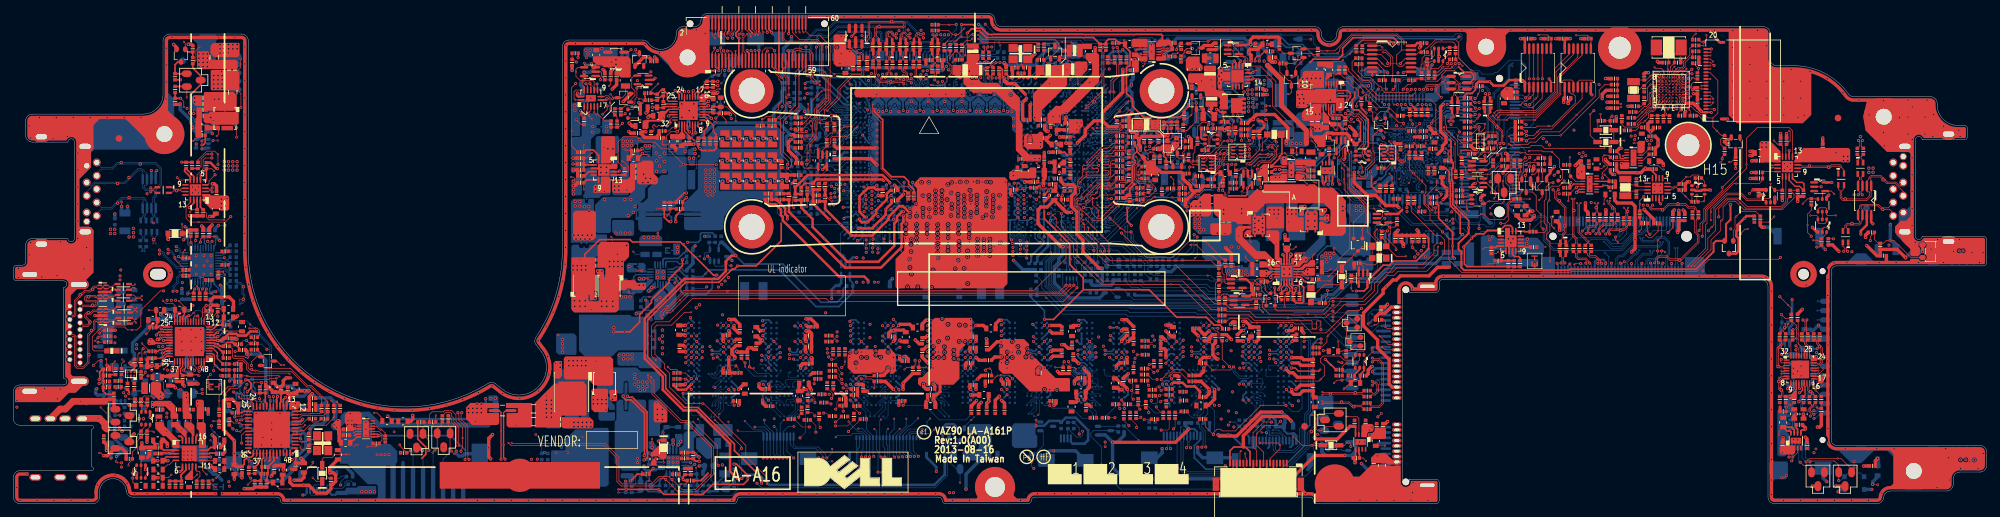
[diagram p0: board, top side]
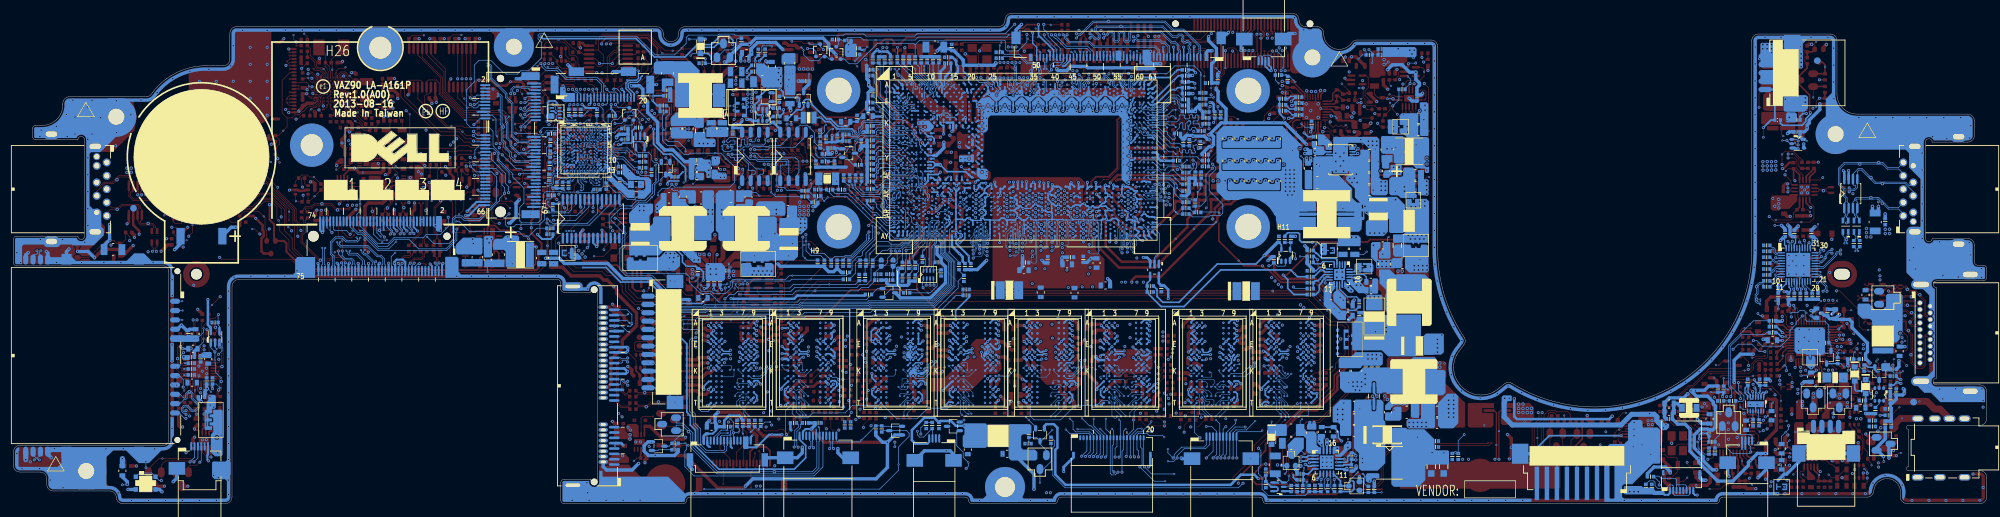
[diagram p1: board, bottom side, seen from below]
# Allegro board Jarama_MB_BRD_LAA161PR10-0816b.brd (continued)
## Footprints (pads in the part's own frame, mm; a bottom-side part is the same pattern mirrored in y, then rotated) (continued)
TPS51285BRUKR_QFN20_3X3
  oval 0.203x1.016 smd: 1(0,0) 2(0.4,0) 3(0.8,0) 4(1.2,0) 5(1.6,0) 11(1.6,2.975) 12(1.2,2.975) 13(0.8,2.975) 14(0.4,2.975) 15(0,2.975)
  oval 1.016x0.203 smd: 6(2.288,0.688) 7(2.288,1.088) 8(2.288,1.488) 9(2.288,1.888) 10(2.288,2.288) 16(-0.688,2.288) 17(-0.688,1.888) 18(-0.688,1.488) 19(-0.688,1.088) 20(-0.688,0.688)
  rect 1.702x1.702 smd: 21(0.8,1.488)
TPS51362RVER_QFN28_4P5X3P5
  oval 0.203x1.041 smd: 1(0,0) 2(0.4,0) 3(0.8,0) 4(1.2,0) 5(1.6,0) 6(2,0) 7(2.4,0) 8(2.8,0) 9(3.2,0) 15(3.2,3.45) 16(2.8,3.45) 17(2.4,3.45) 18(2,3.45) 19(1.6,3.45) 20(1.2,3.45) 21(0.8,3.45) 22(0.4,3.45) 23(0,3.45)
  oval 1.041x0.203 smd: 10(3.825,0.925) 11(3.825,1.325) 12(3.825,1.725) 13(3.825,2.125) 14(3.825,2.525) 24(-0.625,2.525) 25(-0.625,2.125) 26(-0.625,1.725) 27(-0.625,1.325) 28(-0.625,0.925)
  rect 3.099x2.108 smd: 29(1.6,1.725)
TPS51622RSM_QFN32_4X4
  oval 0.203x0.914 smd: 1(0,0) 2(0.4,0) 3(0.8,0) 4(1.2,0) 5(1.6,0) 6(2,0) 7(2.4,0) 8(2.8,0) 17(2.8,4.077) 18(2.4,4.077) 19(2,4.077) 20(1.6,4.077) 21(1.2,4.077) 22(0.8,4.077) 23(0.4,4.077) 24(0,4.077)
  oval 0.914x0.203 smd: 9(3.438,0.639) 10(3.438,1.039) 11(3.438,1.438) 12(3.438,1.838) 13(3.438,2.239) 14(3.438,2.639) 15(3.438,3.039) 16(3.438,3.438) 25(-0.639,3.438) 26(-0.639,3.039) 27(-0.639,2.639) 28(-0.639,2.239) 29(-0.639,1.838) 30(-0.639,1.438) 31(-0.639,1.039) 32(-0.639,0.639)
  rect 2.794x2.794 smd: 33(1.4,2.039)
TXB0102YZPR_DSBGA_8P
  round 0.254 smd: A1(0,0) A2(0.5,0) B1(0,-0.5) B2(0.5,-0.5) C1(0,-1) C2(0.5,-1) D1(0,-1.5) D2(0.5,-1.5)
TXB0104PWR_TSSOP14
  oval 0.381x1.651 smd: 1(0,0) 2(0.65,0) 3(1.3,0) 4(1.95,0) 5(2.6,0) 6(3.25,0) 7(3.9,0) 8(3.9,5.775) 9(3.25,5.775) 10(2.6,5.775) 11(1.95,5.775) 12(1.3,5.775) 13(0.65,5.775) 14(0,5.775)
W25Q32FVSSIQ_SO8
  oval 0.635x1.676 smd: 1(0,0) 2(1.27,0) 3(2.54,0) 4(3.81,0) 5(3.81,7.25) 6(2.54,7.25) 7(1.27,7.25) 8(0,7.25)
W25Q64FVSSIQ_SO8
  oval 0.635x1.676 smd: 1(0,0) 2(1.27,0) 3(2.54,0) 4(3.81,0) 5(3.81,7.25) 6(2.54,7.25) 7(1.27,7.25) 8(0,7.25)
Y_7A08000006_2P
  rect 1.702x2.388 smd: 1(0,0) 2(3.7,0)
Y_CM31532768DZFT_2P
  rect 1.092x1.905 smd: 1(0,0) 2(2.5,0)
Y_Q13FC1350000200_2P
  rect 0.991x1.803 smd: 1(0,0) 2(2.5,0)
Y_X3G024000DC1H_4P
  rect 1.397x1.194 smd: 1(0,0) 2(2.2,0) 3(2.2,1.7) 4(0,1.7)

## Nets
1.2V_DDR_PWROK: PU601.10 R1133.2
1.05V_VREF: PC501.2 PU501.26
1.05VS_PG: R1353.2 RH438.2 U672.2 U697.1
1.05VS_PG_EC: R1353.1 U34.A1
1.5VS_PWROK: PR428.1 R982.2
1.05VS_VCCST_PG: R1132.2 R1180.1 RC150.1 U672.4
1.5VSP_FB: PC429.2 PR425.1 PR427.2 PU405.5
1.8V_DDR_PWROK: PR434.2 R934.2
3VA_EN: D301.1 D302.1 D303.2 D305.1 D306.1 PR344.1
3VALW_PG: PR348.2 PU301.7 RH309.1
5VA_EN: D307.2 U34.B2
+0.6VSP: PC606.1 PC607.1 PJP603.1 PU601.2 PU601.20
+0.675VS: CD93.1 CD94.1 CD95.1 CD96.1 CD97.1 CD98.1 CD101.1 CD102.1 CD103.1 CD104.1 CD105.1 CD106.1 CD107.1 CD110.1 MC1267.1 MC1268.1 PJP603.2 RD25.2 RD26.2 RD27.2 RD28.2 RD29.2 RD30.2 RD31.2 RD32.2 RD33.2 RD34.2 RD35.2 RD36.2 RD37.2 RD38.2 RD39.2 RD40.2 RD41.2 RD42.2 RD43.2 RD44.2 RD45.2 RD46.2 RD47.2 RD48.2 RD49.2 RD50.2 RD51.2 RD52.2 RD53.2 RD54.2 RD55.2 RD56.2 RD57.2 RD58.2 RD59.2 RD60.2 RD61.2 RD62.2 RD63.2 RD64.2 RD65.2 RD66.2 RD67.2 RD68.2 RD69.2 RD70.2 RD71.2 RD72.2 RD75.2 RD76.2 RD77.2 RD78.2 RD87.2 RD88.2 RD89.2 RD90.2
+1.2V_B+: PC602.1 PC603.1 PC604.1 PJP601.2 PL601.2 PQ601.5 PR611.1
+1.2V_FB: PC614.1 PR608.1 PR610.1 PU601.6
+1.2V_TON: PR611.2 PU601.9
+1.2VS_DVDD: CA1.1 CA2.1 CA3.1 CA4.1 CA5.1 CA6.1 CA18.1 CA19.1 CA20.1 LA1.1 UA1.1 UA1.15 UA1.25 UA1.37
+1.05VA: C1228.1 C1243.1 CH1214.1 CH1222.1 CH1223.1 CH1239.1 PJP501.2 Q360.5 R1355.1 RH38.1 RH39.1 RH40.1 RH375.1 RH405.1 RH406.2 RH445.1 U673.4 U673.5 U673.9 U673.10 U673.11 U673.12 U673.13 U673.14 U673.18 U673.19 UCPU1.AE9 UCPU1.AF9 UCPU1.AG8 UCPU1.AG13 UCPU1.AG14
+1.05VDX_MODPHY: C1209.1 LH10.1 LH11.1 Q360.1 Q360.2 Q360.3 R300.1 R1240.1
+1.05VDX_MODPHY_D: Q39.1 R300.2
+1.05VS: C1240.1 C1244.2 CH1.1 CH39.1 CH1215.1 CH1216.1 CH1217.1 CH1233.1 CH1234.1 CH1235.1 LH12.1 R297.1 R1190.2 R1355.2 RH51.1 RH340.1 RH355.1 RH356.1 U673.6 U673.7 U673.8 UCPU1.AE8 UCPU1.AF22 UCPU1.AG16 UCPU1.AG17 UCPU1.H11 UCPU1.H15 UCPU1.J11 UCPU1.J17 UCPU1.N8 UCPU1.P9 UCPU1.R21 UCPU1.T21
+1.5VS: CV31.1 CV32.1 CV42.1 CV43.1 PJP410.2 R296.1 R1305.1 U722.12 U722.19 U722.20 U722.31 U722.40 UCPU1.J15
+1.5VS_3.3VS_AUDIO: CA22.1 CA33.1 CA43.2 CH85.1 RA75.1 U717.8 U717.9 UA1.9 UA2.7 UCPU1.AH14
+1.05VS_B+: PC510.1 PC511.1 PC512.1 PC513.1 PL501.2 PU501.15 PU501.16 PU501.17
+1.5VS_D: Q34.1 R296.2
+1.5VS_FSW: PR422.2 PU405.7
+1.05VS_VCCST: CH1204.1 CH1205.1 PC721.1 PR735.1 PR736.1 PR737.1 R1132.1 R1179.1 R1211.1 RC43.2 RC45.2 RC46.2 RC48.2 RC93.2 RC95.1 RC149.2 RH340.2 UCPU1.AC22 UCPU1.AE22 UCPU1.AE23
+1.05VS_XDP: JXDP.43 JXDP.44 RH51.2
+1.5VSP: PC426.1 PC429.1 PC430.1 PJP410.1 PL405.2 PR422.1 PR427.1 PU405.14
+1.05VSP: PC505.1 PC506.1 PC507.1 PC508.1 PJP501.1 PL502.2 PU501.22
+1.5VSP_LX: PL405.1 PR429.1 PU405.1 PU405.2 PU405.3
+1.5VSP_VIN: PC428.1 PC432.1 PJP409.2 PU405.10 PU405.11 PU405.12
+1.8VP: PC434.1 PC440.1 PC441.1 PJP412.1 PL406.2 PR433.1 PR437.1 PU406.14
+1.8VS: C1284.1 C1286.1 C1288.1 JTP1.1 PJP412.2 R1131.2 R1188.2 R1204.2 R1327.1 R1328.1 R1360.1 R1361.1 R1362.1 R1363.1 R1364.1 R1365.1 R1368.1 R1369.1 R1370.1 R1371.1 RH350.2 U671.1 U677.1 U679.C1
+1.8VSP_LX: PL406.1 PR432.1 PU406.1 PU406.2 PU406.3
+1.35V_DDR: CC160.1 CC161.1 CC162.1 CC163.1 CC164.1 CC165.1 CC233.1 CC234.1 CC238.1 CC239.1 CC240.1 CD14.1 CD15.1 CD16.1 CD17.1 CD18.1 CD19.1 CD20.1 CD21.1 CD22.1 CD37.1 CD38.1 CD39.1 CD40.1 CD41.1 CD42.1 CD43.1 CD44.1 CD58.1 CD59.1 CD60.1 CD61.1 CD62.1 CD63.1 CD64.1 CD65.1 CD66.1 CD81.1 CD82.1 CD83.1 CD84.1 CD85.1 CD86.1 CD87.1 CD88.1 CD111.1 CD112.1 CD113.1 CD114.1 CD115.1 CD116.1 CD117.1 CD118.1 CD119.1 CD120.1 CD121.1 CD122.1 CD123.1 CD124.1 CD125.1 CD126.1 PJP602.2 RC75.1 RD13.1 RD17.1 RD18.1 RD73.2 RD74.2 UC1.5 UCPU1.AH26 UCPU1.AJ31 UCPU1.AJ33 UCPU1.AJ37 UCPU1.AN33 UCPU1.AP43 UCPU1.AR48 UCPU1.AY35 UCPU1.AY40 UCPU1.AY44 UCPU1.AY50 UD1.A1 UD1.A8 UD1.B2 UD1.C1 UD1.C9 UD1.D2 UD1.D9 UD1.E9 UD1.F1 UD1.G7 UD1.H2 UD1.H9 UD1.K2 UD1.K8 UD1.N1 UD1.N9 UD1.R1 UD1.R9 UD2.A1 UD2.A8 UD2.B2 UD2.C1 UD2.C9 UD2.D2 UD2.D9 UD2.E9 UD2.F1 UD2.G7 UD2.H2 UD2.H9 UD2.K2 UD2.K8 UD2.N1 UD2.N9 UD2.R1 UD2.R9 UD4.A1 UD4.A8 UD4.B2 UD4.C1 UD4.C9 UD4.D2 UD4.D9 UD4.E9 UD4.F1 UD4.G7 UD4.H2 UD4.H9 UD4.K2 UD4.K8 UD4.N1 UD4.N9 UD4.R1 UD4.R9 UD5.A1 UD5.A8 UD5.B2 UD5.C1 UD5.C9 UD5.D2 UD5.D9 UD5.E9 UD5.F1 UD5.G7 UD5.H2 UD5.H9 UD5.K2 UD5.K8 UD5.N1 UD5.N9 UD5.R1 UD5.R9 UD6.A1 UD6.A8 UD6.B2 UD6.C1 UD6.C9 UD6.D2 UD6.D9 UD6.E9 UD6.F1 UD6.G7 UD6.H2 UD6.H9 UD6.K2 UD6.K8 UD6.N1 UD6.N9 UD6.R1 UD6.R9 UD7.A1 UD7.A8 UD7.B2 UD7.C1 UD7.C9 UD7.D2 UD7.D9 UD7.E9 UD7.F1 UD7.G7 UD7.H2 UD7.H9 UD7.K2 UD7.K8 UD7.N1 UD7.N9 UD7.R1 UD7.R9 UD9.A1 UD9.A8 UD9.B2 UD9.C1 UD9.C9 UD9.D2 UD9.D9 UD9.E9 UD9.F1 UD9.G7 UD9.H2 UD9.H9 UD9.K2 UD9.K8 UD9.N1 UD9.N9 UD9.R1 UD9.R9 UD10.A1 UD10.A8 UD10.B2 UD10.C1 UD10.C9 UD10.D2 UD10.D9 UD10.E9 UD10.F1 UD10.G7 UD10.H2 UD10.H9 UD10.K2 UD10.K8 UD10.N1 UD10.N9 UD10.R1 UD10.R9
+1.35VP: PC610.1 PC611.1 PC614.2 PC615.1 PJP602.1 PJP604.1 PL602.1 PR608.2 PU601.5
+3.3V_M: C1216.1 CH6.1 CH7.1 CH47.1 R746.2 R1129.2 R1379.2 RH54.1 RH56.1 U2.8 U48.8 UCPU1.Y8
+3.3VDX_SSD: C719.1 C720.1 C721.1 C722.1 C1302.1 JSATA1.2 JSATA1.24 JSATA1.39 JSATA1.41 JSATA1.52 R1366.1 R1389.2
+3V_BATMAN: C1294.1 R1346.2 R1347.2 R1348.1 R1349.1 U714.11
+3V_D: Q5.1 R298.2
+3V_NFC: C1134.1 JNFC1.1 JNFC1.13 JNFC1.14 R973.1 R1242.2
+3V_PCH: C352.1 C1261.1 C1262.1 CH1220.1 CH1236.1 JAPS.12 JAPS.18 Q351.1 R298.1 R1239.1 R1242.1 R1312.2 R1324.1 R1326.2 RH42.1 RH70.2 RH72.2 RH80.2 RH81.2 RH154.2 RH160.2 RH270.2 RH271.2 RH274.1 RH294.2 RH295.2 RH298.2 RH299.2 RH303.2 RH341.1 RH351.1 RH383.2 RH468.2 RH469.2 RH470.2 RH471.2 RH472.2 U663.14 U672.5 U690.5 U691.5 U697.5 UCPU1.AA9 UCPU1.AC9 UCPU1.AE20 UCPU1.AE21
+3V_PCH_DSW: CH1224.1 RH12.2 RH146.2 RH296.2 RH348.2 RH351.2 RH402.2 RH464.2 RH466.2 UCPU1.AH10
+3VALW: C8.1 C96.1 C1199.1 C1219.1 C1289.1 C1290.1 C1297.1 C1299.1 CR11.1 CR12.1 JAPS.16 JLVDS2.45 JP1.1 PJP304.2 PR102.1 PR113.2 PR126.1 Q330.3 R11.1 R162.2 R163.2 R216.1 R923.2 R1260.1 RH348.1 RR9.1 RR10.2 U1.27 U5.5 U23.14 U636.C6 U664.1 U664.2 U699.5 U700.5 U710.5 U713.5 U715.1 U715.2 U716.1 U716.2 U716.6 U716.7 U718.1 U718.2 U718.6 U718.7 U719.1 U719.2 U719.4 U719.6 U719.7 U720.1 U720.2 U721.1 U721.2 U724.1 U724.2 U725.2
+3VALW_EC: C276.1 C277.1 C278.1 C279.1 C280.2 C281.2 L43.1 R216.2 R219.2 R221.2 R229.2 R230.2 R232.1 R233.1 R604.1 R922.2 R933.1 R935.2 R937.1 R940.1 R947.1 R949.2 R1156.1 R1386.2 RP21.7 RP21.8 RP22.5 U34.J4 U34.J7 U34.K7 U34.K12 U34.M12
+3VALWP: PC326.1 PJP304.1 PL303.1 PR348.1 PR353.1
+3VLP: PC347.1 PR335.1 R921.2 R939.1 R1349.2 RP22.6 RTCD1.3 U712.5
+3VNS_PWR: C976.1 C977.1 C978.1 C979.1 JLVDS2.40 JSATA1.22 JSNRDG.1 Q352.2 Q352.5 R854.2 R855.2 R1003.2 R1092.2 R1143.2 R1220.2 R1229.2 R1234.1 R1235.1 R1236.1 R1237.1 R1251.2 R1319.2 RH461.2 RH462.2 U636.A1 U636.A8 U636.F7 U636.G6 U636.G8 U636.H1
+3VS: C655.1 C1135.1 C1136.1 C1137.1 C1138.1 C1139.1 C1140.1 C1256.1 C1283.1 C1285.1 C1287.1 CH1225.1 CH1226.1 CV39.1 CV44.1 JDEBUG.9 JLVDS1.7 JLVDS1.17 MC1276.1 MC1277.1 MD50.5 PR723.2 PR725.2 PU701.20 PU701.21 Q326.2 Q344.2 Q359.2 Q359.5 QH3.2 QH3.5 QH4.2 QH4.5 R884.2 R930.1 R975.2 R976.1 R977.1 R978.1 R979.1 R1033.2 R1103.2 R1129.1 R1182.2 R1185.1 R1289.1 R1306.1 R1311.2 R1330.2 R1339.1 R1340.1 R1343.1 RC159.1 RH29.2 RH35.1 RH37.1 RH82.2 RH91.1 RH95.1 RH98.1 RH99.1 RH100.1 RH103.1 RH107.1 RH180.2 RH196.2 RH248.1 RH281.1 RH282.1 RH301.2 RH302.2 RH354.2 RH367.2 RH380.1 RH381.1 RH384.2 RH388.1 RH389.1 RH390.2 RH391.2 RH392.2 RH396.1 RH397.1 RH424.2 RH425.2 RH440.2 RH441.2 RH452.1 RH455.1 RH456.1 RH457.2 RH458.2 RH459.2 RH460.2 RH463.1 RH465.2 RH467.2 RV16.2 RV17.2 RV18.2 RV19.2 RV20.2 RV21.2 RV32.2 U635.5 U652.5 U652.10 U652.19 U652.24 U671.14 U675.5 U677.14 U678.5 U679.B2 U682.5 U698.5 U709.5 U722.11 U722.37 UCPU1.K14 UCPU1.K16 UCPU1.V8 UCPU1.W9 UH5.5
+3VS_AUDIO: CA7.1 CA8.1 CA9.1 CA10.1 CA11.1 CA12.1 CA31.1 CA32.1 CA46.1 LH2.1 R25.2 R1261.1 R1265.1 R1266.1 R1318.2 RA14.1 RA18.1 RA30.1 RA32.2 RA37.1 RA38.1 UA1.14 UA1.16 UA1.42 UA2.23 UA3.B2
+3VS_CAM: C1158.1 C1159.1 JLVDS1.1 JLVDS1.2 R1321.2
+3VS_CR: C1298.1 CR2.1 CR7.1 JP1.2 R1380.2 U1.11
+3VS_DVDD: CA35.1 CA42.2 RA32.1 UA2.11
+3VS_NGFF: C712.1 C713.1 C714.1 C715.1 C716.1 C717.1 C718.1 C725.1 C1215.1 JNGFF1.2 JNGFF1.4 JNGFF1.64 JNGFF1.66 JNGFF2.2 JNGFF2.4 JNGFF2.72 JNGFF2.74 Q346.2 Q348.2 Q350.2 R942.1 R1036.2 R1137.1 R1197.1 R1200.1 R1205.1 R1226.2
+3VS_TP: C1225.1 JTP1.2 Q364.2 Q365.2 R1128.2 R1300.1 R1301.1 RH364.2 RH365.2
+3VS_TS: C1200.1 JLVDS2.50 MD90.5 Q363.2 R1320.2 R1385.1 RH436.2 RH437.2
+5V_USB_P0: C1109.1 C1110.1 JUSB2.1 MD82.8 US2.12
+5V_USB_P1: C265.1 C303.1 JUSB1.1 MD74.8 US1.12
+5VALW: C962.1 C963.1 C1161.1 C1172.1 C1173.1 C1203.1 C1213.1 C1241.1 C1254.1 C1301.1 C1303.1 JPWR1.1 PC608.2 PJP306.2 PR104.2 PR505.1 PR606.1 PR731.1 PU601.12 R1165.2 R1168.2 R1170.2 R1213.2 R1214.2 R1341.2 U664.4 U664.6 U664.7 U673.2 U676.5 U715.4 U716.4 U717.1 U717.2 U717.4 U718.4 U720.4 U721.4 U724.4 US1.1 US2.1
+5VALWP: PC334.1 PJP306.1 PL302.2 PR316.2 PU301.14
+5VS: C1102.2 C1153.1 C1162.1 CV40.1 D110.2 D111.2 F1.2 JFAN1.1 JFAN1.8 PC713.1 PR720.1 PU702.2 Q329.3 QC5.2 R886.2 R989.2 R1331.2
+5VS_AUDIO: L1.1 R1125.2 RA2.2
+5VS_KBL: C1059.1 F1.1 JBL1.4 R950.2
+5VS_LDO-IN: CA36.1 CA37.1 RA2.1 UA2.39
+V1.05A_AOSCSUS: CH1232.1 CH1240.1 L63.1 UCPU1.AB8
+V1.05A_AOSCSUS_L: L63.2 RH406.1
+V1.05A_DCPSUS: RH405.2 UCPU1.AD8 UCPU1.AD10 UCPU1.AH13 UCPU1.J13
+V1.05S_APLLOPI: CH1212.1 CH1213.1 LH12.2 UCPU1.AA21 UCPU1.W21
+V1.05S_ASATA3PLL: CH1210.1 CH1211.1 LH11.2 RH43.2 UCPU1.A12 UCPU1.B11
+V1.05S_AUSB3PLL: CH1208.1 CH1209.1 LH10.2 RH338.1 UCPU1.B18 UCPU1.B27
+V1.05S_AXCK_DCB: CH1228.1 CH1229.1 L61.2 UCPU1.J18 UCPU1.K19
+V1.05S_AXCK_DCB_L: L61.1 RH355.2
+V1.05S_AXCK_LCPLL: CH1230.1 CH1231.1 L62.2 RH113.2 UCPU1.A20
+V1.05S_AXCK_LCPLL_L: L62.1 RH356.2
+V1.05VS_VCCHSIO: CH40.1 CH41.1 R1240.2 UCPU1.K9 UCPU1.L10 UCPU1.M9
+V18R: C293.1 U34.L1
+VCC_CORE: MC1269.1 MC1270.1 MC1271.1 MC1272.1 PC801.1 PC802.1 PC803.1 PC804.1 PC805.1 PC806.1 PC807.1 PC808.1 PC809.1 PC810.1 PC811.1 PC812.1 PC813.1 PC814.1 PC815.1 PC816.1 PC817.1 PC818.1 PC819.1 PC820.1 PC821.1 PC822.1 PC823.1 PC824.1 PC825.1 PC826.1 PC827.1 PC828.1 PC829.1 PC830.1 PL701.4 RC97.1 UCPU1.AB57 UCPU1.AD57 UCPU1.AG57 UCPU1.C24 UCPU1.C28 UCPU1.C32 UCPU1.C36 UCPU1.C40 UCPU1.C44 UCPU1.C48 UCPU1.C52 UCPU1.C56 UCPU1.E23 UCPU1.E25 UCPU1.E27 UCPU1.E29 UCPU1.E31 UCPU1.E33 UCPU1.E35 UCPU1.E37 UCPU1.E39 UCPU1.E41 UCPU1.E43 UCPU1.E45 UCPU1.E47 UCPU1.E49 UCPU1.E51 UCPU1.E53 UCPU1.E55 UCPU1.E57 UCPU1.F24 UCPU1.F28 UCPU1.F32 UCPU1.F36 UCPU1.F40 UCPU1.F44 UCPU1.F48 UCPU1.F52 UCPU1.F56 UCPU1.F59 UCPU1.G23 UCPU1.G25 UCPU1.G27 UCPU1.G29 UCPU1.G31 UCPU1.G33 UCPU1.G35 UCPU1.G37 UCPU1.G39 UCPU1.G41 UCPU1.G43 UCPU1.G45 UCPU1.G47 UCPU1.G49 UCPU1.G51 UCPU1.G53 UCPU1.G55 UCPU1.G57 UCPU1.H23 UCPU1.J23 UCPU1.K23 UCPU1.K57 UCPU1.L22 UCPU1.M23 UCPU1.M57 UCPU1.P57 UCPU1.U57 UCPU1.W57
+VCCIO_OUT: CH1241.1 UCPU1.A59
+VCCIOA_OUT: RC36.2 UCPU1.E20
+VCCP_D: Q4.1 R297.2
AGND: C21.2 C27.2 C42.2 C43.2 C44.2 C45.2 C46.2 C47.1 C48.2 CA25.2 CA28.2 CA29.2 CA30.2 CA31.2 CA32.2 CA34.2 CA36.2 CA37.2 CA38.2 CA39.1 CA40.1 CA45.1 CA46.2 CA51.2 CA52.2 CA53.1 CA54.1 CA55.1 CA56.1 CA57.2 CA67.2 CA68.2 CA69.2 CA74.2 DA1.1 DA2.1 DA3.1 DA4.1 DA5.1 JHP1.7 JPA1.1 JPA2.1 JPA3.1 QA1.1 QA1.4 QA3.1 QA3.4 QA6.1 QA6.4 R26.1 R27.1 RA20.2 RA25.2 RA43.1 RA45.1 RA68.2 RA69.2 U4.12 U4.16 U4.20 U4.21 UA2.22 UA2.28 UA2.42 UA3.A2
AV12: CR8.2 RR11.1 U1.10
DV12S: CR9.1 CR10.1 RR11.2 U1.14
DV33_18: CR1.2 U1.18
DVDD-12-SWR: LA1.2 UA1.13
DVDD_25: CA13.1 CA14.1 CA21.1 R1186.1 UA1.43
DVDD_IO: CA25.1 CA34.1 LH2.2 UA2.25
GND: C8.2 C9.1 C96.2 C265.2 C276.2 C277.2 C278.2 C279.2 C280.1 C281.1 C283.2 C285.2 C293.2 C303.2 C352.2 C355.2 C407.2 C612.2 C617.1 C655.2 C656.2 C712.2 C713.2 C714.2 C715.2 C716.2 C717.2 C718.2 C719.2 C720.2 C721.2 C722.2 C725.2 C962.2 C963.2 C976.2 C977.2 C978.2 C979.2 C1059.2 C1102.1 C1109.2 C1110.2 C1116.1 C1117.2 C1118.2 C1123.2 C1124.2 C1125.2 C1134.2 C1135.2 C1136.2 C1137.2 C1138.2 C1139.2 C1140.2 C1143.2 C1145.2 C1152.2 C1153.2 C1158.2 C1159.2 C1160.2 C1161.2 C1162.2 C1163.2 C1164.2 C1172.2 C1173.2 C1199.2 C1200.2 C1202.2 C1203.2 C1204.2 C1205.2 C1209.2 C1212.2 C1213.2 C1214.2 C1215.2 C1216.2 C1219.2 C1225.2 C1227.2 C1228.2 C1230.2 C1231.2 C1237.2 C1240.2 C1241.2 C1242.2 C1243.2 C1245.2 C1246.2 C1247.2 C1248.2 C1251.2 C1252.2 C1253.2 C1254.2 C1256.2 C1257.2 C1261.2 C1262.2 C1278.2 C1280.1 C1281.2 C1282.2 C1283.2 C1284.2 C1285.2 C1286.2 C1287.2 C1288.2 C1289.2 C1290.2 C1292.2 C1294.2 C1295.2 C1296.2 C1297.2 C1298.2 C1299.2 C1300.2 C1301.2 C1302.2 C1303.2 C1304.2 CA1.2 CA2.2 CA3.2 CA4.2 CA5.2 CA6.2 CA7.2 CA9.2 CA11.2 CA12.2 CA14.2 CA15.2 CA16.2 CA17.2 CA21.2 CA22.2 CA23.2 CA24.1 CA26.2 CA27.1 CA33.2 CA35.2 CA41.2 CA42.1 CA43.1 CA48.2 CA49.1 CA50.1 CC160.2 CC161.2 CC162.2 CC163.2 CC164.2 CC165.2 CC233.2 CC234.2 CC238.2 CC239.2 CC240.2 CD1.1 CD2.1 CD3.1 CD4.1 CD5.2 CD14.2 CD15.2 CD16.2 CD17.2 CD18.2 CD19.2 CD20.2 CD21.2 CD22.2 CD24.1 CD25.1 CD26.1 CD27.1 CD28.2 CD37.2 CD38.2 CD39.2 CD40.2 CD41.2 CD42.2 CD43.2 CD44.2 CD45.1 CD46.1 CD47.1 CD48.1 CD49.2 CD58.2 CD59.2 CD60.2 CD61.2 CD62.2 CD63.2 CD64.2 CD65.2 CD66.2 CD68.1 CD69.1 CD70.1 CD71.1 CD72.2 CD81.2 CD82.2 CD83.2 CD84.2 CD85.2 CD86.2 CD87.2 CD88.2 CD90.2 CD93.2 CD94.2 CD95.2 CD96.2 CD97.2 CD98.2 CD101.2 CD102.2 CD103.2 CD104.2 CD105.2 CD106.2 CD107.2 CD110.2 CD111.2 CD112.2 CD113.2 CD114.2 CD115.2 CD116.2 CD117.2 CD118.2 CD119.2 CD120.2 CD121.2 CD122.2 CD123.2 CD124.2 CD125.2 CD126.2 CH1.2 CH2.2 CH3.2 CH4.1 CH5.2 CH6.2 CH7.2 CH23.2 CH24.2 CH39.2 CH40.2 CH41.2 CH47.2 CH82.2 CH83.2 CH84.2 CH85.2 CH95.2 CH1202.2 CH1203.2 CH1204.2 CH1205.2 CH1206.2 CH1207.2 CH1208.2 CH1209.2 CH1210.2 CH1211.2 CH1212.2 CH1213.2 CH1214.2 CH1215.2 CH1216.2 CH1217.2 CH1218.2 CH1220.2 CH1222.2 CH1223.2 CH1224.2 CH1225.2 CH1226.2 CH1227.2 CH1228.2 CH1229.2 CH1230.2 CH1231.2 CH1232.2 CH1233.2 CH1234.2 CH1235.2 CH1236.2 CH1239.2 CH1240.2 CH1241.2 CLRP1.1 CLRP2.2 CR1.1 CR2.2 CR3.2 CR4.2 CR5.2 CR6.1 CR7.2 CR8.1 CR9.2 CR10.2 CR11.2 CR12.2 CR19.2 CR20.2 CV31.2 CV32.2 CV39.2 CV40.2 CV41.2 CV42.2 CV43.2 CV44.2 CV768.1 CV795.1 CV796.1 DA6.1 DA8.1 DA9.1 DE1.1 DE2.1 DH5.2 DV4.3 DV5.3 H1.1(TP-1) H2.1(TP-1) H4.1(TP-1) H6.1(TP-1) H7.1(TP-1) H9.1(TP-1) H10.1(TP-1) H11.1(TP-1) H12.1(TP-1) H15.1(TP-1) H18.1(TP-1) H26.1(TP-1) JAPS.5 JAPS.7 JAPS.9 JAPS.11 JAPS.19 JAPS.20 JBATT1.1 JBATT1.2 JBATT1.3 JBATT1.10 JBATT1.11 JBL1.5 JBL1.6 JCARD.4 JCARD.7 JCARD.12 JCARD.15 JCARD.19 JCARD.20 JCARD.21 JCARD.22 JCARD.23 JDCIN1.6 JDCIN1.7 JDEBUG.8 JDEBUG.10 JDEBUG.13 JDEBUG.14 JFAN1.4 JFAN1.5 JFAN1.9 JFAN1.10 JHDMI.2 JHDMI.5 JHDMI.8 JHDMI.11 JHDMI.17 JHDMI.20 JHDMI.21 JHDMI.22 JHDMI.23 JKB1.11 JKB1.12 JKB2.2 JKB2.21 JKB2.22 JLVDS1.5 JLVDS1.6 JLVDS1.13 JLVDS1.14 JLVDS1.21 JLVDS1.22 JLVDS1.23 JLVDS1.24 JLVDS2.3 JLVDS2.6 JLVDS2.9 JLVDS2.12 JLVDS2.15 JLVDS2.19 JLVDS2.21 JLVDS2.24 JLVDS2.27 JLVDS2.30 JLVDS2.31 JLVDS2.32 JLVDS2.46 JLVDS2.51 JLVDS2.52 JLVDS2.53 JLVDS2.54 JNFC1.2 JNFC1.9 JNFC1.15 JNFC1.16 JNFC1.17 JNGFF1.1 JNGFF1.7 JNGFF1.18 JNGFF1.25 JNGFF1.31 JNGFF1.37 JNGFF1.43 JNGFF1.49 JNGFF1.55 JNGFF1.61 JNGFF1.67 JNGFF1.68 JNGFF1.69 JNGFF2.1 JNGFF2.7 JNGFF2.18 JNGFF2.23 JNGFF2.24 JNGFF2.29 JNGFF2.30 JNGFF2.33 JNGFF2.36 JNGFF2.39 JNGFF2.45 JNGFF2.51 JNGFF2.57 JNGFF2.63 JNGFF2.69 JNGFF2.75 JNGFF2.76 JNGFF2.77 JPA1.2 JPA2.2 JPA3.2 JPWR1.6 JPWR1.7 JPWR1.8 JROT1.3 JROT1.4 JROT1.5 JROT1.6 JSATA1.4 JSATA1.9 JSATA1.15 JSATA1.18 JSATA1.21 JSATA1.26 JSATA1.27 JSATA1.29 JSATA1.34 JSATA1.35 JSATA1.37 JSATA1.40 JSATA1.43 JSATA1.50 JSATA1.53 JSATA1.54 JSNRDG.20 JSNRDG.21 JSNRDG.22 JSPK1.5 JSPK1.6 JTP1.3 JTP1.13 JTP1.14 JUSB1.4 JUSB1.7 JUSB1.11 JUSB1.12 JUSB1.13 JUSB1.14 JUSB2.4 JUSB2.7 JUSB2.11 JUSB2.12 JUSB2.13 JUSB2.14 JVOL.3 JVOL.4 JVOL.5 JVOL.6 JXDP.1 JXDP.2 JXDP.7 JXDP.8 JXDP.13 JXDP.14 JXDP.19 JXDP.20 JXDP.25 JXDP.26 JXDP.31 JXDP.32 JXDP.37 JXDP.38 JXDP.49 JXDP.50 JXDP.59 L44.1 LED2.1 MC94.2 MC95.2 MC96.2 MC102.1 MC103.2 MC104.2 MC105.2 MC118.1 MC284.2 MC654.2 MC1133.2 MC1141.2 MC1151.2 MC1210.2 MC1211.2 MC1212.2 MC1267.2 MC1268.2 MC1269.2 MC1270.2 MC1271.2 MC1272.2 MC1273.2 MC1274.2 MC1275.2 MC1276.2 MC1277.2 MD50.2 MD74.7 MD82.7 MD90.2 PBJ1.2 PC101.2 PC102.2 PC103.2 PC104.2 PC105.2 PC106.2 PC107.2 PC108.2 PC112.2 PC113.2 PC116.2 PC202.2 PC203.2 PC204.2 PC205.2 PC210.1 PC212.2 PC213.2 PC214.2 PC216.2 PC217.2 PC219.2 PC220.1 PC221.2 PC223.2 PC224.2 PC225.2 PC228.2 PC324.2 PC326.2 PC328.2 PC329.2 PC333.2 PC334.2 PC342.2 PC343.2 PC345.2 PC347.2 PC426.2 PC427.2 PC428.2 PC430.2 PC432.2 PC433.2 PC434.2 PC436.2 PC437.2 PC439.2 PC441.2 PC501.1 PC502.1 PC504.1 PC505.2 PC506.2 PC507.2 PC508.2 PC509.2 PC510.2 PC511.2 PC512.2 PC513.2 PC602.2 PC603.2 PC604.2 PC606.2 PC607.2 PC608.1 PC609.2 PC610.2 PC611.2 PC612.2 PC613.2 PC615.2 PC616.2 PC701.2 PC702.2 PC703.2 PC704.2 PC705.2 PC707.2 PC709.2 PC710.1 PC712.1 PC713.2 PC715.2 PC717.2 PC720.2 PC721.2 PC725.1 PC726.1 PC801.2 PC802.2 PC803.2 PC804.2 PC805.2 PC806.2 PC807.2 PC808.2 PC809.2 PC810.2 PC811.2 PC812.2 PC813.2 PC814.2 PC815.2 PC816.2 PC817.2 PC818.2 PC819.2 PC820.2 PC821.2 PC822.2 PC823.2 PC824.2 PC825.2 PC826.2 PC827.2 PC828.2 PC829.2 PC830.2 PD103.1 PD104.1 PL104.2 PQ102.3 PQ103.1 PQ103.4 PQ104.3 PQ105.1 PQ105.4 PQ106.3 PQ202.3 PQ204.3 PQ205.1 PQ205.2 PQ205.3 PQ304.8 PQ305.8 PQ602.1 PQ602.2 PQ602.3 PR106.2 PR108.2 PR115.2 PR118.2 PR121.2 PR124.2 PR125.2 PR213.2 PR225.2 PR226.2 PR311.1 PR318.2 PR351.2 PR352.1 PR354.2 PR425.2 PR438.2 PR508.1 PR610.2 PR709.2 PR710.2 PR711.2 PR712.2 PR713.2 PR714.2 PR721.2 PU201.14 PU201.21 PU301.21 PU405.6 PU405.15 PU405.16 PU405.17 PU406.6 PU406.15 PU406.16 PU406.17 PU501.10 PU501.11 PU501.12 PU501.13 PU501.14 PU501.19 PU501.23 PU501.24 PU501.25 PU501.29 PU601.1 PU601.3 PU601.14 PU601.21 PU701.19 PU701.22 PU701.29 PU701.33 PU702.3 PU702.9 Q4.3 Q5.3 Q34.3 Q39.3 Q71.3 Q107.3 Q134.3 Q305.3 Q311.3 Q361.1 Q362.3 Q366.4 Q367.4 R7.2 R36.2 R225.1 R290.2 R537.2 R540.2 R545.2 R607.1 R608.1 R819.1 R924.2 R936.2 R938.2 R945.1 R946.2 R951.2 R974.2 R1026.2 R1034.1 R1035.2 R1099.1 R1100.1 R1117.2 R1118.2 R1119.2 R1120.2 R1140.2 R1141.2 R1142.2 R1161.2 R1162.2 R1164.2 R1169.2 R1174.2 R1187.2 R1197.2 R1200.2 R1203.2 R1205.2 R1208.2 R1216.1 R1217.1 R1228.2 R1250.2 R1253.2 R1310.2 R1325.1 R1338.2 R1376.2 R1390.2 RA11.2 RA12.2 RA13.2 RA42.2 RC44.1 RC52.2 RC54.2 RC55.2 RC58.2 RC60.2 RC81.2 RC100.2 RC138.2 RC153.2 RC154.2 RC155.2 RC156.2 RC158.1 RC160.2 RC161.2 RD1.2 RD2.2 RD5.2 RD6.2 RD7.2 RD8.2 RD11.2 RD12.2 RD15.2 RD16.2 RD21.2 RD22.2 RD23.2 RD24.2 RD79.2 RD80.2 RD81.2 RD82.2 RD83.2 RD84.2 RD85.2 RD86.2 RH34.1 RH53.1 RH76.2 RH77.2 RH78.2 RH79.2 RH83.2 RH123.1 RH151.1 RH158.1 RH159.2 RH163.2 RH171.2 RH183.1 RH186.1 RH272.2 RH300.1 RH314.1 RH315.1 RH316.1 RH337.2 RH387.1 RH394.2 RH400.2 RH401.2 RH403.1 RH423.2 RH442.2 RH443.2 RP21.6 RP22.7 RP22.8 RR6.1 RV22.2 RV24.2 RV26.2 RV27.2 RV30.1 RV31.1 RV33.2 SW2.3 SW2.4 U1.33 U2.4 U5.3 U23.7 U34.G2 U34.J8 U34.J9 U34.J10 U34.N13 U48.4 U635.3 U636.A7 U636.B1 U636.E7 U636.F5 U636.H2 U636.H3 U652.1 U652.2 U652.3 U652.4 U652.8 U652.9 U652.11 U652.18 U652.25 U663.7 U663.15 U664.11 U664.15 U671.7 U672.3 U673.3 U675.3 U676.3 U677.7 U678.3 U679.B1 U682.3 U690.3 U691.3 U697.3 U698.3 U699.3 U700.3 U708.3 U709.3 U710.3 U712.3 U713.3 U714.3 U714.17 U715.11 U715.15 U716.11 U716.15 U717.11 U717.15 U718.11 U718.15 U719.11 U719.15 U720.5 U720.9 U721.5 U721.9 U722.15 U722.35 U722.41 U724.5 U724.9 U725.1 UA1.44 UA1.49 UA2.49 UC1.3 UCPU1.A11 UCPU1.A14 UCPU1.A18 UCPU1.A24 UCPU1.A28 UCPU1.A32 UCPU1.A36 UCPU1.A40 UCPU1.A44 UCPU1.A48 UCPU1.A52 UCPU1.A56 UCPU1.AA1 UCPU1.AA58 UCPU1.AB7 UCPU1.AB10 UCPU1.AB20 UCPU1.AB22 UCPU1.AC61 UCPU1.AD3 UCPU1.AD21 UCPU1.AD63 UCPU1.AE5 UCPU1.AE10 UCPU1.AE58 UCPU1.AF11 UCPU1.AF12 UCPU1.AF14 UCPU1.AF15 UCPU1.AF17 UCPU1.AF18 UCPU1.AG1 UCPU1.AG11 UCPU1.AG21 UCPU1.AG23 UCPU1.AG60 UCPU1.AG61 UCPU1.AG62 UCPU1.AG63 UCPU1.AH16 UCPU1.AH17 UCPU1.AH19 UCPU1.AH20 UCPU1.AH22 UCPU1.AH24 UCPU1.AH28 UCPU1.AH30 UCPU1.AH32 UCPU1.AH34 UCPU1.AH36 UCPU1.AH38 UCPU1.AH40 UCPU1.AH42 UCPU1.AH44 UCPU1.AH46 UCPU1.AH49 UCPU1.AH51 UCPU1.AH53 UCPU1.AH55 UCPU1.AH57 UCPU1.AJ13 UCPU1.AJ14 UCPU1.AJ23 UCPU1.AJ25 UCPU1.AJ27 UCPU1.AJ29 UCPU1.AJ35 UCPU1.AJ39 UCPU1.AJ41 UCPU1.AJ43 UCPU1.AJ45 UCPU1.AJ47 UCPU1.AJ50 UCPU1.AJ52 UCPU1.AJ54 UCPU1.AJ56 UCPU1.AJ58 UCPU1.AJ60 UCPU1.AJ63 UCPU1.AK3 UCPU1.AK23 UCPU1.AK52 UCPU1.AL10 UCPU1.AL13 UCPU1.AL17 UCPU1.AL20 UCPU1.AL22 UCPU1.AL23 UCPU1.AL26 UCPU1.AL29 UCPU1.AL31 UCPU1.AL33 UCPU1.AL36 UCPU1.AL39 UCPU1.AL40 UCPU1.AL45 UCPU1.AL46 UCPU1.AL51 UCPU1.AL52 UCPU1.AL54 UCPU1.AL57 UCPU1.AL60 UCPU1.AL61 UCPU1.AM1 UCPU1.AM17 UCPU1.AM23 UCPU1.AM31 UCPU1.AM52 UCPU1.AN7 UCPU1.AN17 UCPU1.AN23 UCPU1.AN31 UCPU1.AN32 UCPU1.AN35 UCPU1.AN36 UCPU1.AN39 UCPU1.AN40 UCPU1.AN42 UCPU1.AN43 UCPU1.AN45 UCPU1.AN46 UCPU1.AN48 UCPU1.AN49 UCPU1.AN51 UCPU1.AN52 UCPU1.AN60 UCPU1.AN63 UCPU1.AP3 UCPU1.AP10 UCPU1.AP17 UCPU1.AP20 UCPU1.AP22 UCPU1.AP23 UCPU1.AP26 UCPU1.AP29 UCPU1.AP31 UCPU1.AP38 UCPU1.AP39 UCPU1.AP48 UCPU1.AP52 UCPU1.AP54 UCPU1.AP57 UCPU1.AR5 UCPU1.AR11 UCPU1.AR15 UCPU1.AR17 UCPU1.AR23 UCPU1.AR31 UCPU1.AR33 UCPU1.AR39 UCPU1.AR43 UCPU1.AR49 UCPU1.AR52 UCPU1.AT13 UCPU1.AT35 UCPU1.AT37 UCPU1.AT40 UCPU1.AT42 UCPU1.AT43 UCPU1.AT46 UCPU1.AT49 UCPU1.AT61 UCPU1.AT62 UCPU1.AT63 UCPU1.AU1 UCPU1.AU16 UCPU1.AU18 UCPU1.AU20 UCPU1.AU22 UCPU1.AU24 UCPU1.AU26 UCPU1.AU28 UCPU1.AU30 UCPU1.AU33 UCPU1.AU51 UCPU1.AU53 UCPU1.AU55 UCPU1.AU57 UCPU1.AU59 UCPU1.AV8 UCPU1.AV14 UCPU1.AV16 UCPU1.AV20 UCPU1.AV24 UCPU1.AV28 UCPU1.AV33 UCPU1.AV34 UCPU1.AV36 UCPU1.AV39 UCPU1.AV41 UCPU1.AV43 UCPU1.AV46 UCPU1.AV49 UCPU1.AV51 UCPU1.AV55 UCPU1.AV59 UCPU1.AW4 UCPU1.AW16 UCPU1.AW24 UCPU1.AW33 UCPU1.AW35 UCPU1.AW37 UCPU1.AW40 UCPU1.AW42 UCPU1.AW44 UCPU1.AW47 UCPU1.AW50 UCPU1.AW51 UCPU1.AW59 UCPU1.AW60 UCPU1.AY4 UCPU1.AY6 UCPU1.AY11 UCPU1.AY16 UCPU1.AY18 UCPU1.AY22 UCPU1.AY24 UCPU1.AY26 UCPU1.AY30 UCPU1.AY33 UCPU1.AY51 UCPU1.AY53 UCPU1.AY57 UCPU1.AY59 UCPU1.B4 UCPU1.B20 UCPU1.B24 UCPU1.B26 UCPU1.B28 UCPU1.B32 UCPU1.B36 UCPU1.B40 UCPU1.B44 UCPU1.B48 UCPU1.B52 UCPU1.B56 UCPU1.B60 UCPU1.C11 UCPU1.C14 UCPU1.C18 UCPU1.C20 UCPU1.C25 UCPU1.C27 UCPU1.C38 UCPU1.C39 UCPU1.C57 UCPU1.D2 UCPU1.D5 UCPU1.D8 UCPU1.D12 UCPU1.D14 UCPU1.D18 UCPU1.D21 UCPU1.D23 UCPU1.D25 UCPU1.D26 UCPU1.D27 UCPU1.D29 UCPU1.D30 UCPU1.D31 UCPU1.D33 UCPU1.D34 UCPU1.D35 UCPU1.D37 UCPU1.D38 UCPU1.D39 UCPU1.D41 UCPU1.D42 UCPU1.D43 UCPU1.D45 UCPU1.D46 UCPU1.D47 UCPU1.D49 UCPU1.D50 UCPU1.D51 UCPU1.D53 UCPU1.D54 UCPU1.D55 UCPU1.D57 UCPU1.D59 UCPU1.D62 UCPU1.D63 UCPU1.E11 UCPU1.E17 UCPU1.F20 UCPU1.F26 UCPU1.F30 UCPU1.F34 UCPU1.F38 UCPU1.F42 UCPU1.F46 UCPU1.F50 UCPU1.F54 UCPU1.F58 UCPU1.F61 UCPU1.G3 UCPU1.G5 UCPU1.G6 UCPU1.G8 UCPU1.G18 UCPU1.G22 UCPU1.H13 UCPU1.H17 UCPU1.H57 UCPU1.J10 UCPU1.J22 UCPU1.J59 UCPU1.J63 UCPU1.K1 UCPU1.K12 UCPU1.L7 UCPU1.L13 UCPU1.L15 UCPU1.L17 UCPU1.L18 UCPU1.L20 UCPU1.L58 UCPU1.L61 UCPU1.M22 UCPU1.N3 UCPU1.N10 UCPU1.N21 UCPU1.P22 UCPU1.P59 UCPU1.P62 UCPU1.P63 UCPU1.R8 UCPU1.R10 UCPU1.R22 UCPU1.T1 UCPU1.T58 UCPU1.U9 UCPU1.U20 UCPU1.U22 UCPU1.U61 UCPU1.V3 UCPU1.V7 UCPU1.V10 UCPU1.V23 UCPU1.V58 UCPU1.W20 UCPU1.W22 UCPU1.Y10 UCPU1.Y59 UCPU1.Y63 UD1.A9 UD1.B1 UD1.B3 UD1.B9 UD1.D1 UD1.D3 UD1.D8 UD1.E1 UD1.E2 UD1.E7 UD1.E8 UD1.F9 UD1.G1 UD1.G8 UD1.G9 UD1.J2 UD1.J8 UD1.M1 UD1.M9 UD1.P1 UD1.P9 UD1.T1 UD1.T9 UD2.A9 UD2.B1 UD2.B3 UD2.B9 UD2.D1 UD2.D3 UD2.D8 UD2.E1 UD2.E2 UD2.E7 UD2.E8 UD2.F9 UD2.G1 UD2.G8 UD2.G9 UD2.J2 UD2.J8 UD2.M1 UD2.M9 UD2.P1 UD2.P9 UD2.T1 UD2.T9 UD4.A9 UD4.B1 UD4.B3 UD4.B9 UD4.D1 UD4.D3 UD4.D8 UD4.E1 UD4.E2 UD4.E7 UD4.E8 UD4.F9 UD4.G1 UD4.G8 UD4.G9 UD4.J2 UD4.J8 UD4.M1 UD4.M9 UD4.P1 UD4.P9 UD4.T1 UD4.T9 UD5.A9 UD5.B1 UD5.B3 UD5.B9 UD5.D1 UD5.D3 UD5.D8 UD5.E1 UD5.E2 UD5.E7 UD5.E8 UD5.F9 UD5.G1 UD5.G8 UD5.G9 UD5.J2 UD5.J8 UD5.M1 UD5.M9 UD5.P1 UD5.P9 UD5.T1 UD5.T9 UD6.A9 UD6.B1 UD6.B3 UD6.B9 UD6.D1 UD6.D3 UD6.D8 UD6.E1 UD6.E2 UD6.E7 UD6.E8 UD6.F9 UD6.G1 UD6.G8 UD6.G9 UD6.J2 UD6.J8 UD6.M1 UD6.M9 UD6.P1 UD6.P9 UD6.T1 UD6.T9 UD7.A9 UD7.B1 UD7.B3 UD7.B9 UD7.D1 UD7.D3 UD7.D8 UD7.E1 UD7.E2 UD7.E7 UD7.E8 UD7.F9 UD7.G1 UD7.G8 UD7.G9 UD7.J2 UD7.J8 UD7.M1 UD7.M9 UD7.P1 UD7.P9 UD7.T1 UD7.T9 UD9.A9 UD9.B1 UD9.B3 UD9.B9 UD9.D1 UD9.D3 UD9.D8 UD9.E1 UD9.E2 UD9.E7 UD9.E8 UD9.F9 UD9.G1 UD9.G8 UD9.G9 UD9.J2 UD9.J8 UD9.M1 UD9.M9 UD9.P1 UD9.P9 UD9.T1 UD9.T9 UD10.A9 UD10.B1 UD10.B3 UD10.B9 UD10.D1 UD10.D3 UD10.D8 UD10.E1 UD10.E2 UD10.E7 UD10.E8 UD10.F9 UD10.G1 UD10.G8 UD10.G9 UD10.J2 UD10.J8 UD10.M1 UD10.M9 UD10.P1 UD10.P9 UD10.T1 UD10.T9 UH5.3 US1.14 US1.17 US2.14 US2.17 YA1.2 YA1.4 YH2.2 YH2.4
VCC: PC214.1 PR210.2 PU201.20
VCCSENSE: PU701.24 RC98.1
VCCSENSE_R: RC97.2 RC98.2 UCPU1.E63
VCCSTPG_MCP: RC150.2 UCPU1.B59
VDD_+1.2V: PC612.1 PR604.1 PR606.2 PU601.11
VIN: PC103.1 PC104.1 PC208.1 PD201.2 PL101.2 PQ201.1 PR120.1 PR122.1 PR123.1 PR208.1 PR209.1
VSSSENSE: PU701.23 RC99.2
VSSSENSE_R: RC99.1 RC100.1 UCPU1.E62
1.2_PGND: CA8.2 CA10.2 CA18.2 CA19.2 CA20.2 RA11.1 RA12.1 RA13.1 UA1.12
3&5V_B+: PC324.1 PC328.1 PC343.1 PC345.1 PL304.2 PQ304.1 PQ305.1 PU301.12
+1.5VS_SS/TR: PC433.1 PU405.9
+1.8VS_SS/TR: PC437.1 PU406.9
+5PVDD: C21.1 C27.1 C43.1 C44.1 C46.1 L1.2 R23.2 R24.2 R34.2 U4.2 U4.4 U4.6 U4.14
+EC_VCCA: C282.1 L43.2 U34.B11
+EDP_COM: RC36.1 UCPU1.D20
+HDMI_5V: D110.1 FV2.1
+HDMI_5V_OUT: CV41.1 FV2.2 JHDMI.18
+INV_PWR_SRC: C612.1 JLVDS2.25 JLVDS2.26 Q70.1 Q70.2 Q70.5 Q70.6 R531.2 R541.1
+LCDVDD: C1143.1 C1145.1 C1231.1 JLVDS2.16 JLVDS2.17 JLVDS2.18 R1322.2 U708.5
+LCDVDD_R: D105.1 Q71.2 R1161.1 U708.2
+ODR_PWR: CR3.1 CR4.1 JCARD.5 U1.12
+PCH_VCCDSW: RH346.1 UCPU1.AG19 UCPU1.AG20
+RTC_VCCSUS: CH1207.1 RH341.2 UCPU1.AH11
+RTCBATT: PBJ1.1 RTCR1.2
+RTCVCC: CH82.1 CH83.1 CH84.1 CH95.1 R1348.2 RA16.1 RH11.1 RH23.1 RH25.1 RH31.1 RH147.1 RTCD1.1 UCPU1.AG10
+SD_VDD2: CR5.1 CR19.1 JCARD.16 U1.13
+VCHGR: PC223.1 PC224.1 PC225.1 PD204.1 PQ206.1 PQ206.2 PQ206.3 PR216.4
+VREFCA: CD1.2 CD2.2 CD24.2 CD25.2 CD45.2 CD46.2 CD68.2 CD69.2 CD90.1 RD13.2 RD14.2 RD15.1 UD1.M8 UD2.M8 UD4.M8 UD5.M8 UD6.M8 UD7.M8 UD9.M8 UD10.M8
+VREFDQ_A: CD3.2 CD4.2 CD26.2 CD27.2 RD17.2 RD19.2 RD21.1 UD1.H1 UD2.H1 UD4.H1 UD5.H1
+VREFDQ_B: CD47.2 CD48.2 CD70.2 CD71.2 RD18.2 RD20.2 RD22.1 UD6.H1 UD7.H1 UD9.H1 UD10.H1
+VS_LPSS_SDIO: CH1227.1 RH350.1 RH354.1 RH434.1 UCPU1.T9 UCPU1.U8
AC_PRESENT: RH12.1 RH137.2 U34.M10
AC_PRESENT_R: RH137.1 UCPU1.AJ8
ACCEL_INT1: D87.2 JLVDS2.38 R1230.1
ACCEL_INT2: JLVDS2.39 U636.E4
ACDET: PC216.1 PR208.2 PR213.1 PU201.6
ACDRV: PR206.2 PU201.4
ACIN: C1116.2 PR119.1 PR238.1 U34.F5
ACOFF: PQ202.2 RP22.1 U34.A9
ACOK: PR223.2 PR226.1 PR238.2 PU201.5
AD_BID0: C283.1 R219.1 R225.2 U34.A12
ADP_I: PC220.2 PR116.1 PU201.7 U34.B12
ADPIN: JDCIN1.2 JDCIN1.3 PC101.1 PC102.1 PL101.1
AGC: C45.1 R24.1 R27.2 U4.10
ALL_SYS_PCH_PWROK_EC: R1292.1 U691.4
ALS_INT#: JLVDS1.12 R1116.1
ALS_INT#_HUB: R1116.2 R1143.1 U636.E6
ALS_SMBCLK: JLVDS1.10 R983.1 R985.1
ALS_SMBDATA: JLVDS1.11 R984.1 R986.1
AMP_SPK_L: C29.2 RA47.1
AMP_SPK_L1: C51.1 RA47.2 RA69.1
AMP_SPK_LC: C29.1 UA2.43
AMP_SPK_LR: C51.2 U4.5
AMP_SPK_R: C32.2 RA46.1
AMP_SPK_R1: C50.1 RA46.2 RA68.1
AMP_SPK_RC: C32.1 UA2.44
AMP_SPK_RR: C50.2 CA58.1 U4.11
APOWER_OK: PU501.1 R746.1 R931.2 RH131.2
APWROK_R: RH131.1 RH134.1 RH438.1 UCPU1.AB5
ARRAY_MIC_CLK: JLVDS1.16 MC1212.1 U23.5
ARRAY_MIC_DAT: JLVDS1.15 MC1211.1 U23.2
AUD_MUTE#: RA55.1 U4.3
AUD_MUTE#_R: C42.1 D3.2 D4.2 R25.1 RA55.2
AUD_MUTE_EC#: D3.1 RA44.1 U34.N12
AUDIO_IRQ#: RH396.2 UCPU1.L4
AUDIO_PWREN: D305.2 R1140.1 R1182.1 T279.1(TP-1) U664.3 U664.5 U717.5 UCPU1.P1
AUDIO_XTAL24_IN: CA17.1 UA1.2 YA1.3
AUDIO_XTAL24_OUT: CA16.1 UA1.3 YA1.1
B+: C613.1 MC1273.1 MC1274.1 MC1275.1 PC217.1 PC219.1 PJP409.1 PJP411.1 PJP601.1 PL203.2 PL304.1 PL501.1 PL601.1 PL703.1 PR216.1 Q70.4 Q361.4 R531.1 R535.1 R1381.1
B-RAMP: PR704.2 PR711.1 PU701.11
BATDRV: PR230.1 PU201.11
BATMAN_CLK: Q359.6 R1347.1 R1350.1 U714.7
BATMAN_DATA: Q359.3 R1346.1 R1351.1 U714.6
BATMAN_X1: C1295.1 U714.14 Y3.1
BATMAN_X2: C1296.1 U714.15 Y3.2
BATT+: PC105.1 PC106.1 PD204.2 PL105.1 PL106.1 PQ206.5 PQ206.6 PQ206.7 PQ206.8
BATT++: JBATT1.8 JBATT1.9 PC107.1 PC108.1 PL105.2 PL106.2
BATT_LED_COLOR_W: Q366.5 U5.2 U34.A4
BATT_LED_COLOR_W#: Q367.5 U5.4
BATT_LED_CTRL#: Q366.2 Q367.2 R36.1 U34.A3
BATT_LOW_LED#_C: DA9.3 JPWR1.4 R4.1
BATT_PRS: JBATT1.5 PD104.2 PR112.1
BEEP#: RA33.1 U34.M8
BKOFF#: D72.3 D106.2 U34.E1
BOOT0: R819.2 R1092.1 U636.A6
BOOT_+1.2V: PR601.2 PU601.18
BST1_3V: PC318.2 PR355.1
BST1_5V: PC335.1 PR356.2
BST_3V: PR355.2 PU301.9
BST_5V: PR356.1 PU301.17
BST_+1.05VS: PR506.1 PU501.5
BT_CS_NOTICE: R1210.2 R1212.2 UCPU1.AP1
BT_PCMCLK: JNGFF1.8 U677.2
BT_PCMFR1: JNGFF1.10 U677.3
BT_PCMIN: JNGFF1.12 U677.5
BT_PCMOUT: JNGFF1.14 U677.4
BT_RADIO_DIS#: JNGFF1.46 JNGFF2.54 UCPU1.R7
BTST: PR211.1 PU201.17
BYPASS: C47.2 U4.9
CAPS_LED: LED2.2 R943.2
CAPS_LED#: Q326.3 U34.B3
CDCLK_REQ#: RH95.2 U1.2 UCPU1.Y5
CFG0: JXDP.9 UCPU1.AC60
CFG1: JXDP.11 UCPU1.AC62
CFG2: JXDP.15 UCPU1.AC63
CFG3: JXDP.17 R1198.2 UCPU1.AA63
CFG4: JXDP.27 RC81.1 UCPU1.AA60
CFG5: JXDP.29 UCPU1.Y62
CFG6: JXDP.33 UCPU1.Y61
CFG7: JXDP.35 UCPU1.Y60
CFG8: JXDP.10 UCPU1.V62
CFG9: JXDP.12 UCPU1.V61
CFG10: JXDP.16 UCPU1.V60
CFG11: JXDP.18 UCPU1.U60
CFG12: JXDP.28 UCPU1.T63
CFG13: JXDP.30 UCPU1.T62
CFG14: JXDP.34 UCPU1.T61
CFG15: JXDP.36 UCPU1.T60
CFG16: JXDP.6 UCPU1.AA62
CFG17: JXDP.4 UCPU1.AA61
CFG18: JXDP.24 UCPU1.U63
CFG19: JXDP.22 UCPU1.U62
CFG_RCOMP: RC153.1 UCPU1.V63
CHG_LGATE: PQ205.4 PU201.15
CHG_LX: PC218.2 PL203.1 PQ203.1 PQ203.2 PQ203.3 PQ205.5 PR220.1 PU201.19
CHG_UGATE: PQ203.4 PU201.18
CL_CLK: JNGFF1.34 JNGFF2.42 UCPU1.AF2
CL_DATA: JNGFF1.32 JNGFF2.40 UCPU1.AD2
CL_RST#: R1209.2 UCPU1.AF4
CL_RST#_L: JNGFF1.30 JNGFF2.38 R1209.1 R1210.1
CLK_LPC_DEBUG: JDEBUG.7 RH360.2
CLK_PCI_LPC: MR226.1 RH386.2 U34.N5
CLK_PCI_TPM: MR976.1 RH428.2 U652.21
CLK_PCIE0: JNGFF2.71 UCPU1.C42
CLK_PCIE0#: JNGFF2.73 UCPU1.C43
CLK_PCIE2: JNGFF1.39 UCPU1.B42
CLK_PCIE2#: JNGFF1.41 UCPU1.C41
CLK_PCIE3: JNGFF2.47 UCPU1.C37
CLK_PCIE3#: JNGFF2.49 UCPU1.B38
CLK_PCIE_CD: U1.5 UCPU1.A41
CLK_PCIE_CD#: U1.6 UCPU1.B41
CLK_REQ0#: JNGFF2.68 Q348.3 R1343.2 RH417.1
CLK_REQ2#: JNGFF1.45 Q346.3 R1339.2 RH410.1
CLK_REQ3#: JNGFF2.53 Q350.3 R1340.2 RH418.1
CLK_SMB: JBATT1.7 PD103.2 PR109.1
CLKOUT_LPC0: RH360.1 RH428.1 UCPU1.AN15
CLKOUT_LPC1: RH386.1 UCPU1.AP15
CMSRC: PR203.2 PU201.3
COMP: PC714.2 PC724.2 PR726.1 PR727.2 PU701.26
CONSOLE_RX: JSNRDG.14 T261.1(TP-1) U636.D3
CONSOLE_TX: JSNRDG.15 T260.1(TP-1) U636.D2
CPU_B+: PC701.1 PC702.1 PC703.1 PC704.1 PC705.1 PC710.2 PC725.2 PC726.2 PL703.2 PR717.1 PU702.5
CPU_EDP_HPD#: QC5.3 RC148.1 RC160.1 UCPU1.D6
CPU_PATH_EN: R1324.2 R1325.2 U697.2
CPU_PATH_EN_G: U663.1 U663.4 U663.10 U663.13 U697.4
CPU_XDP_TCK: RC52.1 RH446.1 T265.1(TP-1) UCPU1.E60
CPU_XDP_TDI: RC46.1 T268.1(TP-1) U663.9 UCPU1.F63
CPU_XDP_TDO: RC48.1 T269.1(TP-1) U663.5 UCPU1.F62
CPU_XDP_TMS: RC45.1 T266.1(TP-1) U663.12 UCPU1.E61
CPU_XDP_TRST#: RC54.1 RH370.2 T267.1(TP-1) U663.2 UCPU1.E59
CR_PWREN: RH83.1 U720.3 UCPU1.AL2
CR_RST#: R1208.1 U1.1 U678.4
CR_WAKE#: RH295.1 RR18.2 UCPU1.AD5
CS_+1.2V: PR604.2 PU601.13
CSN1: PC708.2 PC718.2 PL701.3 PR707.2 PR708.2 PU701.18
CSON_B: PC227.2 PC228.1 PR216.3 PU201.12
CSOP_B: PC227.1 PR216.2 PU201.13
CSP1: PC708.1 PC718.1 PH702.1 PR702.2 PR707.1 PU701.17
CSSN_1: PC211.2 PC212.1 PR201.3 PU201.1
CSSP_1: PC210.2 PC211.1 PR201.2 PU201.2
DAT_SMB: JBATT1.6 PD103.3 PR111.1
DC_TEST_A3_B3: UCPU1.A3 UCPU1.B3
DC_TEST_A61_B61: UCPU1.A61 UCPU1.B61
DC_TEST_AY2_AW2: UCPU1.AW2 UCPU1.AY2
DC_TEST_AY3_AW3: UCPU1.AW3 UCPU1.AY3
DC_TEST_AY61_AW61: UCPU1.AW61 UCPU1.AY61
DC_TEST_AY62_AW62: UCPU1.AW62 UCPU1.AY62
DC_TEST_B62_B63: UCPU1.B62 UCPU1.B63
DC_TEST_C1_C2: UCPU1.C1 UCPU1.C2
DCIN_GND: JDCIN1.4 JDCIN1.5 PL104.1
DDR3_DRAMRST#: CD5.1 CD28.1 CD49.1 CD72.1 RC75.2 RC162.2 UD1.T2 UD2.T2 UD4.T2 UD5.T2 UD6.T2 UD7.T2 UD9.T2 UD10.T2
DDR_A_BS0: RD67.1 UCPU1.AU35 UD1.M2 UD2.M2 UD4.M2 UD5.M2
DDR_A_BS1: RD71.1 UCPU1.AV35 UD1.N8 UD2.N8 UD4.N8 UD5.N8
DDR_A_BS2: RD69.1 UCPU1.AY41 UD1.M3 UD2.M3 UD4.M3 UD5.M3
DDR_A_CAS#: RD63.1 UCPU1.AU34 UD1.K3 UD2.K3 UD4.K3 UD5.K3
DDR_A_CKE0: RD57.1 UCPU1.AU43 UD1.K9 UD2.K9 UD4.K9 UD5.K9
DDR_A_CKE1: RD87.1 UCPU1.AW43 UD1.J9 UD2.J9 UD4.J9 UD5.J9
DDR_A_CS0#: RD61.1 UCPU1.AP33 UD1.L2 UD2.L2 UD4.L2 UD5.L2
DDR_A_CS1#: RD88.1 UCPU1.AR32 UD1.L1 UD2.L1 UD4.L1 UD5.L1
DDR_A_D0: UCPU1.AH63 UD1.F7
DDR_A_D1: UCPU1.AH62 UD1.H7
DDR_A_D2: UCPU1.AK63 UD1.F2
DDR_A_D3: UCPU1.AK62 UD1.H3
DDR_A_D4: UCPU1.AH61 UD1.H8
DDR_A_D5: UCPU1.AH60 UD1.F8
DDR_A_D6: UCPU1.AK61 UD1.E3
DDR_A_D7: UCPU1.AK60 UD1.G2
DDR_A_D8: UCPU1.AM63 UD1.A7
DDR_A_D9: UCPU1.AM62 UD1.B8
DDR_A_D10: UCPU1.AP63 UD1.A3
DDR_A_D11: UCPU1.AP62 UD1.A2
DDR_A_D12: UCPU1.AM61 UD1.C8
DDR_A_D13: UCPU1.AM60 UD1.D7
DDR_A_D14: UCPU1.AP61 UD1.C2
DDR_A_D15: UCPU1.AP60 UD1.C3
DDR_A_D16: UCPU1.AP58 UD2.F7
DDR_A_D17: UCPU1.AR58 UD2.H7
DDR_A_D18: UCPU1.AM57 UD2.E3
DDR_A_D19: UCPU1.AK57 UD2.H3
DDR_A_D20: UCPU1.AL58 UD2.H8
DDR_A_D21: UCPU1.AK58 UD2.F8
DDR_A_D22: UCPU1.AR57 UD2.F2
DDR_A_D23: UCPU1.AN57 UD2.G2
DDR_A_D24: UCPU1.AP55 UD2.A7
DDR_A_D25: UCPU1.AR55 UD2.B8
DDR_A_D26: UCPU1.AM54 UD2.C2
DDR_A_D27: UCPU1.AK54 UD2.C3
DDR_A_D28: UCPU1.AL55 UD2.C8
DDR_A_D29: UCPU1.AK55 UD2.D7
DDR_A_D30: UCPU1.AR54 UD2.A3
DDR_A_D31: UCPU1.AN54 UD2.A2
DDR_A_D32: UCPU1.AY58 UD4.F8
DDR_A_D33: UCPU1.AW58 UD4.H8
DDR_A_D34: UCPU1.AY56 UD4.F2
DDR_A_D35: UCPU1.AW56 UD4.H3
DDR_A_D36: UCPU1.AV58 UD4.H7
DDR_A_D37: UCPU1.AU58 UD4.F7
DDR_A_D38: UCPU1.AV56 UD4.G2
DDR_A_D39: UCPU1.AU56 UD4.E3
DDR_A_D40: UCPU1.AY54 UD4.B8
DDR_A_D41: UCPU1.AW54 UD4.A7
DDR_A_D42: UCPU1.AY52 UD4.A2
DDR_A_D43: UCPU1.AW52 UD4.A3
DDR_A_D44: UCPU1.AV54 UD4.D7
DDR_A_D45: UCPU1.AU54 UD4.C8
DDR_A_D46: UCPU1.AV52 UD4.C2
DDR_A_D47: UCPU1.AU52 UD4.C3
DDR_A_D48: UCPU1.AK40 UD5.G2
DDR_A_D49: UCPU1.AK42 UD5.H3
DDR_A_D50: UCPU1.AM43 UD5.H7
DDR_A_D51: UCPU1.AM45 UD5.F8
DDR_A_D52: UCPU1.AK45 UD5.H8
DDR_A_D53: UCPU1.AK43 UD5.F7
DDR_A_D54: UCPU1.AM40 UD5.F2
DDR_A_D55: UCPU1.AM42 UD5.E3
DDR_A_D56: UCPU1.AM46 UD5.C2
DDR_A_D57: UCPU1.AK46 UD5.C3
DDR_A_D58: UCPU1.AM49 UD5.B8
DDR_A_D59: UCPU1.AK49 UD5.A7
DDR_A_D60: UCPU1.AM48 UD5.A3
DDR_A_D61: UCPU1.AK48 UD5.A2
DDR_A_D62: UCPU1.AM51 UD5.D7
DDR_A_D63: UCPU1.AK51 UD5.C8
DDR_A_DQS0: UCPU1.AJ62 UD1.F3
DDR_A_DQS1: UCPU1.AN61 UD1.C7
DDR_A_DQS2: UCPU1.AN58 UD2.F3
DDR_A_DQS3: UCPU1.AN55 UD2.C7
DDR_A_DQS4: UCPU1.AW57 UD4.F3
DDR_A_DQS5: UCPU1.AW53 UD4.C7
DDR_A_DQS6: UCPU1.AL42 UD5.F3
DDR_A_DQS7: UCPU1.AL49 UD5.C7
DDR_A_DQS#0: UCPU1.AJ61 UD1.G3
DDR_A_DQS#1: UCPU1.AN62 UD1.B7
DDR_A_DQS#2: UCPU1.AM58 UD2.G3
DDR_A_DQS#3: UCPU1.AM55 UD2.B7
DDR_A_DQS#4: UCPU1.AV57 UD4.G3
DDR_A_DQS#5: UCPU1.AV53 UD4.B7
DDR_A_DQS#6: UCPU1.AL43 UD5.G3
DDR_A_DQS#7: UCPU1.AL48 UD5.B7
DDR_A_MA0: RD29.1 UCPU1.AU36 UD1.N3 UD2.N3 UD4.N3 UD5.N3
DDR_A_MA1: RD37.1 UCPU1.AY37 UD1.P7 UD2.P7 UD4.P7 UD5.P7
DDR_A_MA2: RD35.1 UCPU1.AR38 UD1.P3 UD2.P3 UD4.P3 UD5.P3
DDR_A_MA3: RD41.1 UCPU1.AP36 UD1.N2 UD2.N2 UD4.N2 UD5.N2
DDR_A_MA4: RD33.1 UCPU1.AU39 UD1.P8 UD2.P8 UD4.P8 UD5.P8
DDR_A_MA5: RD47.1 UCPU1.AR36 UD1.P2 UD2.P2 UD4.P2 UD5.P2
DDR_A_MA6: RD39.1 UCPU1.AV40 UD1.R8 UD2.R8 UD4.R8 UD5.R8
DDR_A_MA7: RD51.1 UCPU1.AW39 UD1.R2 UD2.R2 UD4.R2 UD5.R2
DDR_A_MA8: RD53.1 UCPU1.AY39 UD1.T8 UD2.T8 UD4.T8 UD5.T8
DDR_A_MA9: RD43.1 UCPU1.AU40 UD1.R3 UD2.R3 UD4.R3 UD5.R3
DDR_A_MA10: RD31.1 UCPU1.AP35 UD1.L7 UD2.L7 UD4.L7 UD5.L7
DDR_A_MA11: RD45.1 UCPU1.AW41 UD1.R7 UD2.R7 UD4.R7 UD5.R7
DDR_A_MA12: RD25.1 UCPU1.AU41 UD1.N7 UD2.N7 UD4.N7 UD5.N7
DDR_A_MA13: RD55.1 UCPU1.AR35 UD1.T3 UD2.T3 UD4.T3 UD5.T3
DDR_A_MA14: RD49.1 UCPU1.AV42 UD1.T7 UD2.T7 UD4.T7 UD5.T7
DDR_A_MA15: RD27.1 UCPU1.AU42 UD1.M7 UD2.M7 UD4.M7 UD5.M7
DDR_A_RAS#: RD59.1 UCPU1.AY34 UD1.J3 UD2.J3 UD4.J3 UD5.J3
DDR_A_WE#: RD65.1 UCPU1.AW34 UD1.L3 UD2.L3 UD4.L3 UD5.L3
DDR_B_BS0: RD70.1 UCPU1.AL35 UD6.M2 UD7.M2 UD9.M2 UD10.M2
DDR_B_BS1: RD66.1 UCPU1.AM36 UD6.N8 UD7.N8 UD9.N8 UD10.N8
DDR_B_BS2: RD68.1 UCPU1.AU49 UD6.M3 UD7.M3 UD9.M3 UD10.M3
DDR_B_CAS#: RD62.1 UCPU1.AM33 UD6.K3 UD7.K3 UD9.K3 UD10.K3
DDR_B_CKE0: RD58.1 UCPU1.AY49 UD6.K9 UD7.K9 UD9.K9 UD10.K9
DDR_B_CKE1: RD89.1 UCPU1.AU50 UD6.J9 UD7.J9 UD9.J9 UD10.J9
DDR_B_CS0#: RD60.1 UCPU1.AM32 UD6.L2 UD7.L2 UD9.L2 UD10.L2
DDR_B_CS1#: RD90.1 UCPU1.AK32 UD6.L1 UD7.L1 UD9.L1 UD10.L1
DDR_B_D0: UCPU1.AY31 UD7.H7
DDR_B_D1: UCPU1.AW31 UD7.F7
DDR_B_D2: UCPU1.AY29 UD7.G2
DDR_B_D3: UCPU1.AW29 UD7.F2
DDR_B_D4: UCPU1.AV31 UD7.H8
DDR_B_D5: UCPU1.AU31 UD7.F8
DDR_B_D6: UCPU1.AV29 UD7.H3
DDR_B_D7: UCPU1.AU29 UD7.E3
DDR_B_D8: UCPU1.AY27 UD7.D7
DDR_B_D9: UCPU1.AW27 UD7.B8
DDR_B_D10: UCPU1.AY25 UD7.A2
DDR_B_D11: UCPU1.AW25 UD7.A3
DDR_B_D12: UCPU1.AV27 UD7.C3
DDR_B_D13: UCPU1.AU27 UD7.A7
DDR_B_D14: UCPU1.AV25 UD7.C2
DDR_B_D15: UCPU1.AU25 UD7.C8
DDR_B_D16: UCPU1.AM29 UD6.H8
DDR_B_D17: UCPU1.AK29 UD6.F8
DDR_B_D18: UCPU1.AL28 UD6.F2
DDR_B_D19: UCPU1.AK28 UD6.G2
DDR_B_D20: UCPU1.AR29 UD6.H7
DDR_B_D21: UCPU1.AN29 UD6.F7
DDR_B_D22: UCPU1.AR28 UD6.E3
DDR_B_D23: UCPU1.AP28 UD6.H3
DDR_B_D24: UCPU1.AN26 UD6.B8
DDR_B_D25: UCPU1.AR26 UD6.A7
DDR_B_D26: UCPU1.AR25 UD6.C3
DDR_B_D27: UCPU1.AP25 UD6.C2
DDR_B_D28: UCPU1.AK26 UD6.A2
DDR_B_D29: UCPU1.AM26 UD6.C8
DDR_B_D30: UCPU1.AK25 UD6.D7
DDR_B_D31: UCPU1.AL25 UD6.A3
DDR_B_D32: UCPU1.AY23 UD9.H8
DDR_B_D33: UCPU1.AW23 UD9.F7
DDR_B_D34: UCPU1.AY21 UD9.H3
DDR_B_D35: UCPU1.AW21 UD9.G2
DDR_B_D36: UCPU1.AV23 UD9.H7
DDR_B_D37: UCPU1.AU23 UD9.F8
DDR_B_D38: UCPU1.AV21 UD9.F2
DDR_B_D39: UCPU1.AU21 UD9.E3
DDR_B_D40: UCPU1.AY19 UD9.A7
DDR_B_D41: UCPU1.AW19 UD9.B8
DDR_B_D42: UCPU1.AY17 UD9.C2
DDR_B_D43: UCPU1.AW17 UD9.A3
DDR_B_D44: UCPU1.AV19 UD9.C8
DDR_B_D45: UCPU1.AU19 UD9.D7
DDR_B_D46: UCPU1.AV17 UD9.A2
DDR_B_D47: UCPU1.AU17 UD9.C3
DDR_B_D48: UCPU1.AR21 UD10.E3
DDR_B_D49: UCPU1.AR22 UD10.H7
DDR_B_D50: UCPU1.AL21 UD10.F2
DDR_B_D51: UCPU1.AM22 UD10.H8
DDR_B_D52: UCPU1.AN22 UD10.F7
DDR_B_D53: UCPU1.AP21 UD10.H3
DDR_B_D54: UCPU1.AK21 UD10.G2
DDR_B_D55: UCPU1.AK22 UD10.F8
DDR_B_D56: UCPU1.AN20 UD10.B8
DDR_B_D57: UCPU1.AR20 UD10.A7
DDR_B_D58: UCPU1.AK18 UD10.A2
DDR_B_D59: UCPU1.AL18 UD10.A3
DDR_B_D60: UCPU1.AK20 UD10.D7
DDR_B_D61: UCPU1.AM20 UD10.C8
DDR_B_D62: UCPU1.AR18 UD10.C3
DDR_B_D63: UCPU1.AP18 UD10.C2
DDR_B_DQS0: UCPU1.AV30 UD7.F3
DDR_B_DQS1: UCPU1.AW26 UD7.C7
DDR_B_DQS2: UCPU1.AM28 UD6.F3
DDR_B_DQS3: UCPU1.AM25 UD6.C7
DDR_B_DQS4: UCPU1.AV22 UD9.F3
DDR_B_DQS5: UCPU1.AW18 UD9.C7
DDR_B_DQS6: UCPU1.AM21 UD10.F3
DDR_B_DQS7: UCPU1.AM18 UD10.C7
DDR_B_DQS#0: UCPU1.AW30 UD7.G3
DDR_B_DQS#1: UCPU1.AV26 UD7.B7
DDR_B_DQS#2: UCPU1.AN28 UD6.G3
DDR_B_DQS#3: UCPU1.AN25 UD6.B7
DDR_B_DQS#4: UCPU1.AW22 UD9.G3
DDR_B_DQS#5: UCPU1.AV18 UD9.B7
DDR_B_DQS#6: UCPU1.AN21 UD10.G3
DDR_B_DQS#7: UCPU1.AN18 UD10.B7
DDR_B_MA0: RD30.1 UCPU1.AP40 UD6.N3 UD7.N3 UD9.N3 UD10.N3
DDR_B_MA1: RD44.1 UCPU1.AR40 UD6.P7 UD7.P7 UD9.P7 UD10.P7
DDR_B_MA2: RD40.1 UCPU1.AP42 UD6.P3 UD7.P3 UD9.P3 UD10.P3
DDR_B_MA3: RD50.1 UCPU1.AR42 UD6.N2 UD7.N2 UD9.N2 UD10.N2
DDR_B_MA4: RD38.1 UCPU1.AR45 UD6.P8 UD7.P8 UD9.P8 UD10.P8
DDR_B_MA5: RD56.1 UCPU1.AP45 UD6.P2 UD7.P2 UD9.P2 UD10.P2
DDR_B_MA6: RD36.1 UCPU1.AW46 UD6.R8 UD7.R8 UD9.R8 UD10.R8
DDR_B_MA7: RD48.1 UCPU1.AY46 UD6.R2 UD7.R2 UD9.R2 UD10.R2
DDR_B_MA8: RD42.1 UCPU1.AY47 UD6.T8 UD7.T8 UD9.T8 UD10.T8
DDR_B_MA9: RD52.1 UCPU1.AU46 UD6.R3 UD7.R3 UD9.R3 UD10.R3
DDR_B_MA10: RD32.1 UCPU1.AK36 UD6.L7 UD7.L7 UD9.L7 UD10.L7
DDR_B_MA11: RD54.1 UCPU1.AV47 UD6.R7 UD7.R7 UD9.R7 UD10.R7
DDR_B_MA12: RD26.1 UCPU1.AU47 UD6.N7 UD7.N7 UD9.N7 UD10.N7
DDR_B_MA13: RD46.1 UCPU1.AK33 UD6.T3 UD7.T3 UD9.T3 UD10.T3
DDR_B_MA14: RD34.1 UCPU1.AR46 UD6.T7 UD7.T7 UD9.T7 UD10.T7
DDR_B_MA15: RD28.1 UCPU1.AP46 UD6.M7 UD7.M7 UD9.M7 UD10.M7
DDR_B_RAS#: RD64.1 UCPU1.AM35 UD6.J3 UD7.J3 UD9.J3 UD10.J3
DDR_B_WE#: RD72.1 UCPU1.AK35 UD6.L3 UD7.L3 UD9.L3 UD10.L3
DDR_CHA_EN: RH440.1 RH442.1 UCPU1.J1
DDR_CHB_EN: RH441.1 RH443.1 UCPU1.K3
DDR_PG_CNTL: UC1.2 UCPU1.AV61
DDR_VREF: CA13.2 CA15.1 R1186.2 R1187.1 UA1.40
DELAY_VR_AND_ALL_SYS: R1290.1 R1295.1 U690.4 U691.1
DEVSLP0: JSATA1.44 R1366.2 UCPU1.P2
DH_+1.2V: PQ601.4 PU601.17
DISPOFF#: D72.1 JLVDS2.22 R540.1
DL_+1.2V: PQ602.4 PU601.15
DMIC_CLK: MD50.6 R1342.1 U23.9
DMIC_CLK_CODEC: CA49.2 RA9.2 UA2.12
DMIC_CLK_DSP: RA5.2 UA1.47
DMIC_CLK_R: JLVDS1.9 MC1133.1 R1342.2
DMIC_CLK_SW: RA5.1 RA9.1 U23.6 U23.8
DMIC_DAT: JLVDS1.8 MC1210.1 MD50.4 U23.12
DMIC_DAT_CODEC: CA24.2 RA10.2 UA2.13
DMIC_DAT_DSP: RA6.2 UA1.48
DMIC_DAT_SW: RA6.1 RA10.1 U23.3 U23.11
DMIC_SW_CODEC: RH419.1 UA2.17
DMIC_SW_DIS: Q135.2 Q136.2 RH466.1 UCPU1.AN4
DMIC_SW_HUB: R31.1 U636.H5
DMIC_SW_PCH: RH420.1 UCPU1.T2
DROOP: PC714.1 PR727.1 PR744.1 PU701.25
DSP_PD#: R1262.1 U34.H5
DSP_PD#_R: R1261.2 R1262.2 UA1.17
DSWODVREN: RH147.2 RH151.2 UCPU1.AW7
EAPD#: RA23.1 U34.D6 UA2.14
EC_BATT_PRS#: C286.2 PC114.1 PC229.1 PR112.2 PR113.1 U34.B1
EC_CRY2: MC654.1 R253.2 R607.2 U34.K1
EC_ENVDD: D93.1 D105.3 D306.3 R1026.1 U34.A10 U715.3
EC_ON: C1117.1 R341.1 U34.G1
EC_ON_CTRL#: C1118.1 R987.1 RP22.3 U34.G5
EC_PECI: R240.1 U34.H2
EC_RST#: C285.1 R221.1 U34.K13
EC_RUNTIME_SCI#: RH299.1 U34.N6 UCPU1.AM2
EC_RX: JDEBUG.12 U34.K9
EC_SLP_S5#: D114.2 R1386.1 U34.N9
EC_SMB_CK1: PR109.2 PR240.1 R229.1 R1016.1 U34.A8
EC_SMB_CK1_R: JLVDS2.43 R1016.2
EC_SMB_CK4: JLVDS2.28 U34.E5
EC_SMB_DA1: PR111.2 PR239.1 R230.1 R1017.1 U34.A7
EC_SMB_DA1_R: JLVDS2.44 R1017.2
EC_SMB_DA4: JLVDS2.29 U34.D5
EC_SMI#: RH82.1 T270.1(TP-1) U34.L13 UCPU1.V1
EC_TX: JDEBUG.11 U34.K10
EC_WAKE_SCI#: RH427.2 U34.N7
ECAGND: C282.2 C286.1 L44.2 R948.2 U34.A11
EDP_AUXN: C1065.1 UCPU1.A45
EDP_AUXN_C: C1065.2 ML58.1 R1011.1 R1033.1
EDP_AUXN_CONN: JLVDS2.14 ML58.2 R1011.2
EDP_AUXP: C1064.1 UCPU1.B45
EDP_AUXP_C: C1064.2 ML58.4 R1010.1 R1034.2
EDP_AUXP_CONN: JLVDS2.13 ML58.3 R1010.2
EDP_BKLCTL: RC147.2 UCPU1.B8
EDP_DISP: RC146.1 RC158.2 UCPU1.A43
EDP_HPD: JLVDS2.20 QC5.1 RC138.1 RC148.2
EDP_TXN_P0: C1060.1 UCPU1.C45
EDP_TXN_P0_C: C1060.2 ML57.4 R1008.1
EDP_TXN_P0_CONN: JLVDS2.1 ML57.3 R1008.2
EDP_TXN_P1: C1061.1 UCPU1.A47
EDP_TXN_P1_C: C1061.2 ML56.4 R1006.1
EDP_TXN_P1_CONN: JLVDS2.4 ML56.3 R1006.2
EDP_TXN_P2: C1066.1 UCPU1.C47
EDP_TXN_P2_C: C1066.2 ML59.4 R1013.1
EDP_TXN_P2_CONN: JLVDS2.7 ML59.3 R1013.2
EDP_TXN_P3: C1068.1 UCPU1.A49
EDP_TXN_P3_C: C1068.2 ML60.1 R1015.1
EDP_TXN_P3_CONN: JLVDS2.10 ML60.2 R1015.2
EDP_TXP_P0: C1062.1 UCPU1.B46
EDP_TXP_P0_C: C1062.2 ML57.1 R1009.1
EDP_TXP_P0_CONN: JLVDS2.2 ML57.2 R1009.2
EDP_TXP_P1: C1063.1 UCPU1.B47
EDP_TXP_P1_C: C1063.2 ML56.1 R1007.1
EDP_TXP_P1_CONN: JLVDS2.5 ML56.2 R1007.2
EDP_TXP_P2: C1067.1 UCPU1.C46
EDP_TXP_P2_C: C1067.2 ML59.1 R1012.1
EDP_TXP_P2_CONN: JLVDS2.8 ML59.2 R1012.2
EDP_TXP_P3: C1069.1 UCPU1.B49
EDP_TXP_P3_C: C1069.2 ML60.4 R1014.1
EDP_TXP_P3_CONN: JLVDS2.11 ML60.3 R1014.2
EN_+1.05VS: PU501.28 R501.2 R503.2
EN_+1.5VSP: PR404.2 PU405.13
EN_+1.8VSP: PR405.2 PU406.13
EN_+V5A: D307.1 PR345.2
EN_CAM: R1162.1 U715.5 UCPU1.AM4
EN_WLANPWR#: D115.3 U34.F4
ENBKL: D72.2 RH123.2 UCPU1.A9
F-IMAX: PR712.1 PR745.2 PU701.10
FAN_TEMP0: C1253.1 R949.1 R951.1 U34.A13
FB_3V: PR352.2 PR353.2 PU301.4
FB_5V: PR316.1 PR354.1 PU301.2
FB_+1.8VSP: PC440.2 PR433.2 PR438.1 PU406.5
FIVE_EN: JXDP.45 R1179.2 UCPU1.H59
FSW_+1.8VS: PR437.2 PU406.7
GPIO12: RH296.1 UCPU1.AM7
GYRO_DRDY: JLVDS2.35 U636.G5
GYRO_INT#: JLVDS2.36 U636.H8
H_CATERR#: T2.1(TP-1) UCPU1.K61
H_CPU_SVIDALRT#: RC93.1 RC94.2 UCPU1.L62
H_CPU_SVIDCLK: RC92.2 UCPU1.N63
H_CPU_SVIDDAT: RC95.2 RC96.2 UCPU1.L63
H_CPUPWRGD_R: RC44.2 UCPU1.C61
H_DRAMRST#: RC162.1 UCPU1.AV15
H_PECI: R240.2 UCPU1.N62
H_PROCHOT#: C656.1 PQ104.1 PQ105.3 PQ106.1 R265.1 RC41.1 RC43.1 U635.4
H_PROCHOT#_R: RC41.2 UCPU1.K63
H_PROCHOT_EC: PR110.1 R608.2 U34.E2 U635.2
H_THERMTRIP#: RC49.2 RC149.1
H_THERMTRIP#_R: RC49.1 UCPU1.D60
HDA_BIT_CLK: MC96.1 RP3.8 UCPU1.AW8
HDA_BITCLK_AUDIO: RA58.1 RP3.1 UA1.6
HDA_BITCLK_AUDIO_R: CA41.1 RA29.2 UA2.5
HDA_BITCLK_DSP: RA29.1 RA58.2 UA1.23
HDA_RST#: RP3.7 UCPU1.AU8
HDA_RST_AUDIO#: RA62.1 RP3.2 UA1.11
HDA_RST_AUDIO#_R: CA26.1 Q6.3 RA30.2 RA54.2 RA57.1 UA2.6
HDA_RST_DSP#: RA54.1 RA62.2 UA1.18
HDA_SDIN0: RA1.1 UCPU1.AY10
HDA_SDIN0_AUDIO: RA1.2 RA60.1 UA1.8
HDA_SDIN0_DSP: RA36.1 RA60.2 UA1.21
HDA_SDIN0_R: RA36.2 UA2.8
HDA_SDO: Q351.2 R1341.1 U34.C1
HDA_SDOUT: MC103.1 RH24.2 RH42.2 RP3.5 UCPU1.AU11
HDA_SDOUT_AUDIO: RA59.1 RP3.4 UA1.5
HDA_SDOUT_AUDIO_R: RA52.2 UA2.4
HDA_SDOUT_DSP: CA27.2 RA52.1 RA59.2 UA1.24
HDA_SPKR: RA31.1 RH37.2 UCPU1.V2
HDA_SYNC: RP3.6 UCPU1.AV11
HDA_SYNC_AUDIO: RA61.1 RP3.3 UA1.10
HDA_SYNC_AUDIO_R: RA53.2 UA2.9
HDA_SYNC_DSP: CA50.2 RA53.1 RA61.2 UA1.19
HDMI_CEC: CV796.2 JHDMI.13
HDMI_CFG: RV20.1 RV26.1 U722.23
HDMI_CK_N: L67.2 U722.21
HDMI_CK_N_R: DV4.1 DV4.9 JHDMI.12 L67.1
HDMI_CK_P: L67.3 U722.22
HDMI_CK_P_R: DV4.2 DV4.8 JHDMI.10 L67.4
HDMI_CLK: JHDMI.15 RV28.2 U722.32
HDMI_D0_N: L66.2 U722.29
HDMI_D0_N_R: DV4.4 DV4.7 JHDMI.9 L66.1
HDMI_D0_P: L66.3 U722.30
HDMI_D0_P_R: DV4.5 DV4.6 JHDMI.7 L66.4
HDMI_D1_N: L65.2 U722.26
HDMI_D1_N_R: DV5.2 DV5.8 JHDMI.6 L65.1
HDMI_D1_P: L65.3 U722.27
HDMI_D1_P_R: DV5.1 DV5.9 JHDMI.4 L65.4
HDMI_D2_N: L64.2 U722.24
HDMI_D2_N_R: DV5.5 DV5.6 JHDMI.3 L64.1
HDMI_D2_P: L64.3 U722.25
HDMI_D2_P_R: DV5.4 DV5.7 JHDMI.1 L64.4
HDMI_DAT: JHDMI.16 RV29.2 U722.33
HDMI_DCIN_EN: RV17.1 U722.13
HDMI_DDCBUF: RV16.1 RV22.1 U722.14
HDMI_EQ: RV18.1 RV24.1 U722.17
HDMI_HPD: CV768.2 JHDMI.19 RV30.2 U722.28
HDMI_I2C_CTL_EN: RV19.1 U722.8
HDMI_PRE: RV21.1 RV27.1 U722.16
HDMI_RESERVED: CV795.2 JHDMI.14
HDMI_REXT: RV31.2 U722.18
HP2_D_L: RA15.1 UA2.26
HP2_D_L_C: DA2.3 JHP1.1 RA3.2
HP2_D_L_R1: CA29.1 RA3.1 RA15.2 RA21.1 RA43.2 RA49.2 RA51.2
HP2_D_R: RA17.1 UA2.27
HP2_D_R_C: DA1.2 JHP1.2 RA4.2
HP2_D_R_R2: CA28.1 RA4.1 RA17.2 RA22.1 RA45.2 RA48.2 RA50.2
HP_PLUG#: D4.1 QA6.6
HUB_OSC_IN: C1204.1 U636.D8 Y2.1
HUB_OSC_OUT: C1205.1 U636.D7 Y2.2
HWPG: R930.2 R931.1 R934.1 R982.1 R1133.1 R1296.1 U34.F1 U690.2
I2C0_SCK: Q352.1 R1224.1 RA8.2 RH425.1 RH462.1 UCPU1.F3
I2C0_SCK_DSP: RA8.1 UA1.26
I2C0_SCK_SNR: JSNRDG.18 R1224.2 U636.G3
I2C0_SDA: Q352.4 R1225.1 RA7.2 RH424.1 RH461.1 UCPU1.F2
I2C0_SDA_DSP: RA7.1 UA1.27
I2C0_SDA_SNR: JSNRDG.19 R1225.2 U636.F3
I2C1_SCK: R1152.1 R1257.1 RH364.1 RH436.1 UCPU1.F1
I2C1_SCK_TP: DE2.3 JTP1.6 R1257.2
I2C1_SCK_TS: JLVDS2.47 MD90.1 R1152.2 R1218.2
I2C1_SDA: R1153.1 R1258.1 RH365.1 RH437.1 UCPU1.G4
I2C1_SDA_TP: DE2.2 JTP1.7 R1258.2
I2C1_SDA_TS: JLVDS2.48 MD90.3 R1153.2 R1219.2
I2S_BCLK_OUT: R1372.2 UA1.29
I2S_CLK: R1372.1 R1373.1 R1374.1 U677.13
I2S_CLK_IN: R1373.2 UA1.38
I2S_SDI_IN: U677.10 UA1.41
I2S_SDO_OUT: U677.11 UA1.31
I2S_SFRM_IN: R1374.2 UA1.39
I2S_SFRM_OUT: U677.12 UA1.30
IMON: PC707.1 PR703.1 PU701.13
IMVP_VR_PG: PR723.1 PU701.3 R1211.2 R1291.1 RC152.1
INV_PWM_R: D106.1 JLVDS2.23 MC1151.1 R545.1
ISET: RV32.1 RV33.1 U722.34
JACK_PLUG: QA3.5 RA26.1 RA35.1
JACK_PLUG_C: DA5.3 JHP1.6 RA20.1 RA35.2
JACK_PLUG_DL: CA57.1 QA3.6 QA6.2 QA6.5 RA26.2 RA38.2
JACK_PLUG_DL#: QA6.3 RA24.2
JDREF: RA25.1 UA2.35
JNTRST: JSATA1.16 JSNRDG.4 R1236.2 U636.B4
JTCK: JSATA1.14 JSNRDG.5 R1099.2 U636.B2
JTDI: JSATA1.12 JSNRDG.6 R1237.2 U636.C3
JTDO: JSATA1.10 JSNRDG.7 R1235.2 U636.A4
JTMS: JSATA1.8 JSNRDG.3 R1234.2 U636.D4
KB_BL_DET: R944.1 R945.2 T284.1(TP-1) UCPU1.AU2
KB_DET#: JKB1.10 RH302.1 T282.1(TP-1) UCPU1.Y1
KB_INT#: Q365.1 R1388.1 U34.M7
KB_INT#_R: JTP1.12 Q365.3 R1301.2 R1388.2
KB_LED_PWM: Q311.2 U34.M9
KB_LED_PWM#: JBL1.1 JTP1.9 Q311.1 R950.1
KB_RST#: RH196.1 U34.L2 UCPU1.V4
KSI0: JKB1.1 U34.D9
KSI1: JKB1.3 U34.E12
KSI2: JKB1.5 U34.E13
KSI3: JKB1.2 U34.D12
KSI4: JKB1.6 U34.D13
KSI5: JKB1.4 U34.C12
KSI6: JKB1.7 U34.C13
KSI7: JKB1.8 U34.D10
KSO0: JKB2.12 U34.J13
KSO1: JKB2.14 U34.J12
KSO2: JKB2.13 U34.H12
KSO3: JKB2.15 U34.H13
KSO4: JKB2.19 U34.H10
KSO5: JKB2.20 U34.H9
KSO6: JKB2.17 U34.G9
KSO7: JKB2.18 U34.G10
KSO8: JKB2.16 U34.G13
KSO9: JKB2.6 U34.G12
KSO10: JKB2.4 U34.F13
KSO11: JKB2.5 U34.F12
KSO12: JKB2.11 U34.F10
KSO13: JKB2.8 U34.F9
KSO14: JKB2.7 U34.E10
KSO15: JKB2.9 U34.E9
KSO16: JKB2.10 U34.E8
L_MIC1: CA69.1 DA2.2 JHP1.3 RA28.2 UA2.31
LCD_TEST: JLVDS2.42 U34.B10
LDO_OUT: CA40.2 CA45.2 UA2.40
LG_3V: PQ304.4 PU301.11
LG_5V: PQ305.4 PU301.15
LID_SW_IN#: C9.2 R11.2 RP21.2 U34.N2 U725.3
LINE2-VREFO: RA27.1 RA28.1 UA2.29
LPC_AD0: JDEBUG.5 U34.N4 U652.26 UCPU1.AU14
LPC_AD1: JDEBUG.4 U34.K5 U652.23 UCPU1.AW12
LPC_AD2: JDEBUG.3 U34.M4 U652.20 UCPU1.AY12
LPC_AD3: JDEBUG.2 U34.N3 U652.17 UCPU1.AW11
LPC_FRAME#: JDEBUG.1 U34.K4 U652.22 UCPU1.AV12
LPCPD#: R1238.2 R1239.2 U652.28
LX_3V: PC318.1 PQ304.3 PU301.8
LX_5V: PC335.2 PQ305.3 PU301.18
LX_DGPU: PL701.1 PR719.2 PU702.4
M_CLK_A_DDR0: RD75.1 UCPU1.AV37 UD1.J7 UD2.J7 UD4.J7 UD5.J7
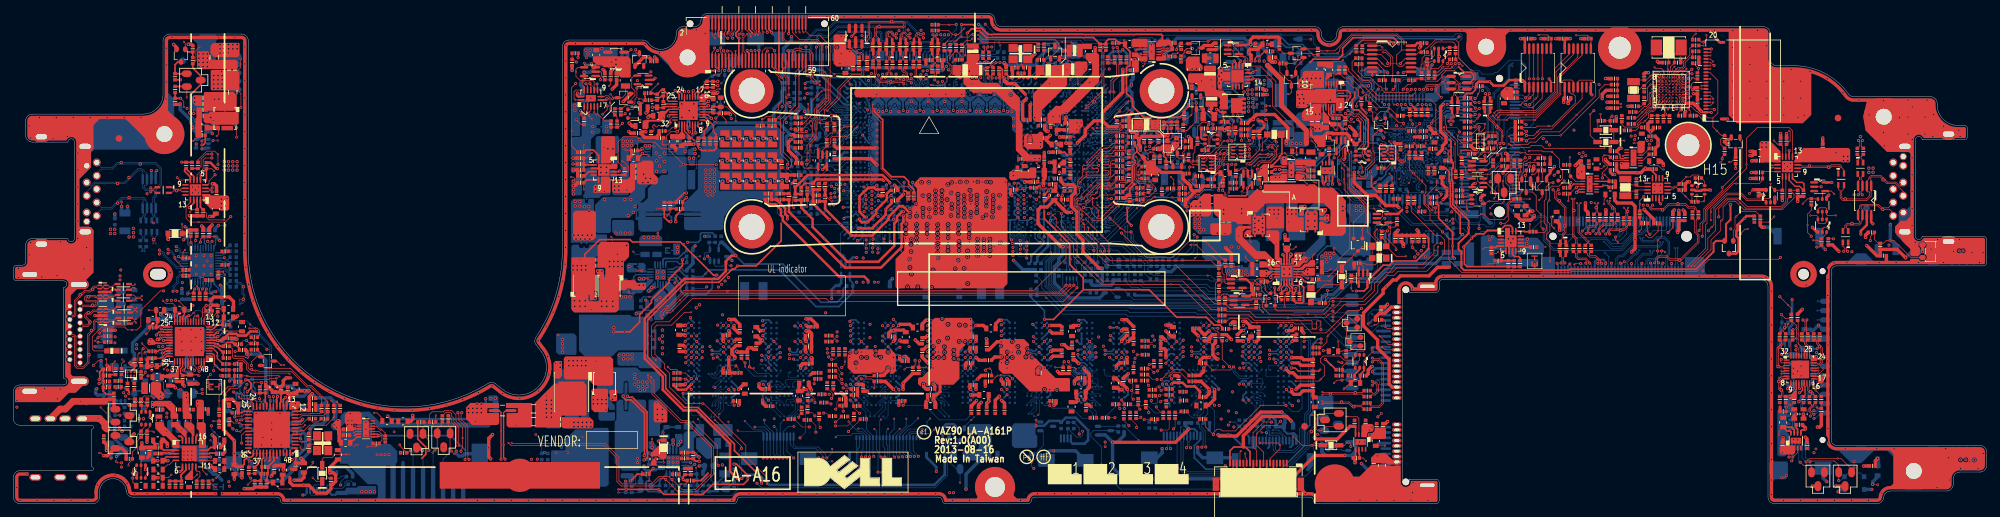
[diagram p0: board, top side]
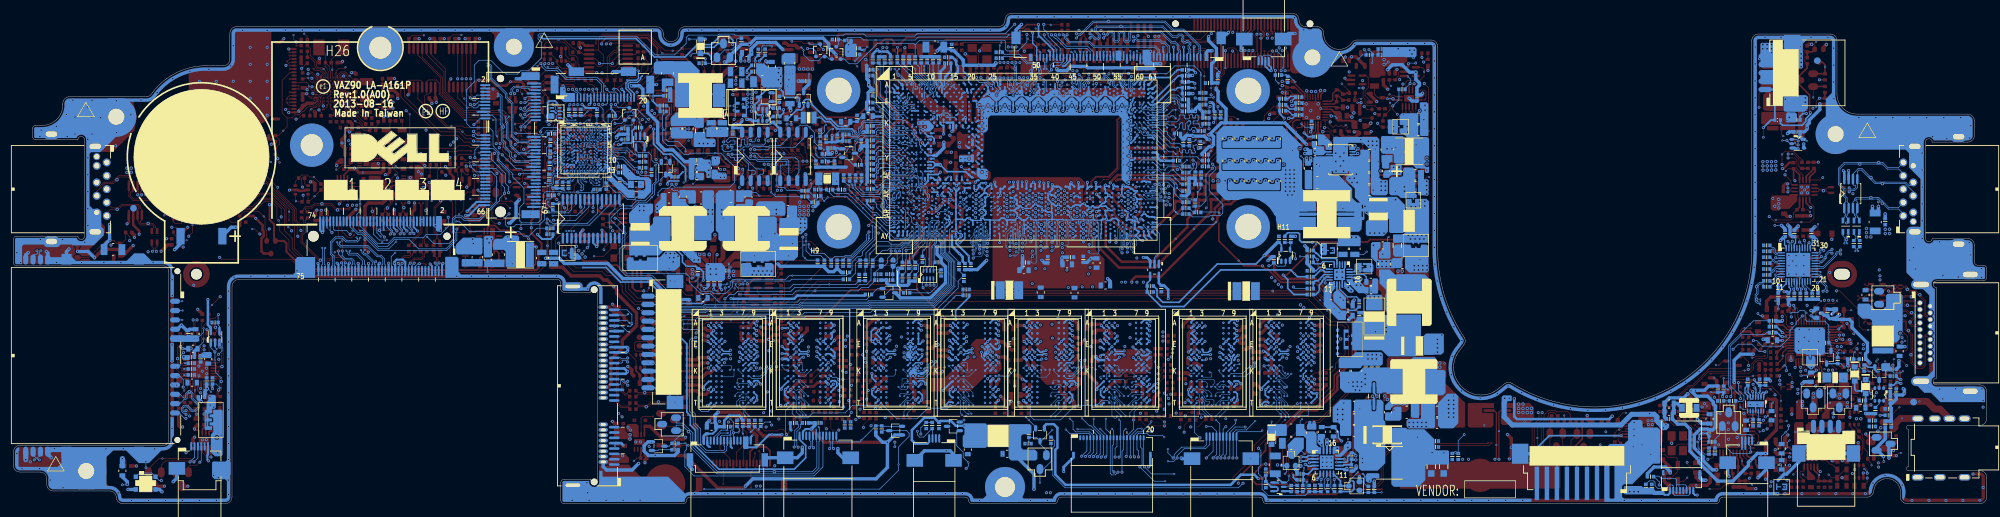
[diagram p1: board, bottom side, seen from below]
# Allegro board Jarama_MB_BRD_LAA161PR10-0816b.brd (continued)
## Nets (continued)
M_CLK_A_DDR#0: RD77.1 UCPU1.AU37 UD1.K7 UD2.K7 UD4.K7 UD5.K7
M_CLK_B_DDR0: RD76.1 UCPU1.AN38 UD6.J7 UD7.J7 UD9.J7 UD10.J7
M_CLK_B_DDR#0: RD78.1 UCPU1.AM38 UD6.K7 UD7.K7 UD9.K7 UD10.K7
M_ODT0: RD73.1 UD1.J1 UD1.K1 UD2.J1 UD2.K1 UD4.J1 UD4.K1 UD5.J1 UD5.K1
M_ODT2: RD74.1 UD6.J1 UD6.K1 UD7.J1 UD7.K1 UD9.J1 UD9.K1 UD10.J1 UD10.K1
MAG_DRDY: JLVDS2.37 U636.E5
MEM_CONFIG0: RH303.1 RH316.2 T286.1(TP-1) UCPU1.AT5
MEM_CONFIG1: RH180.1 RH315.2 T287.1(TP-1) UCPU1.U4
MEM_CONFIG2: RH271.1 RH314.2 UCPU1.AB6
MEM_TEMP0: C1245.1 R940.2 R946.1 U34.B13
MIC2-VREFO-L: RA49.1 UA2.1
MIC2-VREFO-R: RA48.1 UA2.30
MIC2_L: CA71.1 UA2.47
MIC2_L_C: CA71.2 RA51.1
MIC2_R: CA70.1 UA2.48
MIC2_R_C: CA70.2 RA50.1
MIC_CAP: CA67.1 UA2.36
MONO_IN: CA47.2 UA2.2
MOTOR_EN#: C1164.1 Q330.2 R923.1 U34.B6
MOTOR_N1: JLVDS1.20 R924.1
MOTOR_P1: DH5.1 JLVDS1.19 Q330.1
MPCIE_RST#: R1314.1 RH381.2 U675.1 U678.2 UCPU1.U6
MPHY_PWREN: Q362.2 R1169.1 R1185.2 UCPU1.Y2
MPHY_PWREN#: Q39.2 Q361.2 Q361.5 Q362.1 R1381.2
MSATA_DET#: JSATA1.51 RH392.1 T274.1(TP-1) UCPU1.AC1
NFC_DET#: JNFC1.4 R1228.1 RH465.1 UCPU1.N5
NFC_IRQ: JNFC1.5 R1100.2 RH294.1 UCPU1.AN3
NFC_RST#: JNFC1.10 R1142.1 UCPU1.AD7
NFC_VDD_SIM: JNFC1.6 R973.2 R974.1
NGFF_PWREN: D115.2 R1233.1 UCPU1.R6
NGFF_RST#: JNGFF1.44 R1203.1 R1232.1 R1241.2 R1243.2 U675.4 U709.2
NGFF_WAKE#: R1215.1 R1231.1 RH397.2 UCPU1.L3
NGFF_WAKE#_R: Q347.1 R1231.2
O-USR: PR706.2 PR713.1 PU701.9
OCP-I: PR703.2 PR710.1 PU701.12
P1: PL201.1 PL202.1 PR201.4
PA0_WAKUP: D86.1 D87.1 R537.1 R1230.2 U636.F6
PA11: R1221.2 U636.C1
PA12: R1222.2 R1223.1 R1251.1 U636.C2
PB5: R1223.2 U636.A5
PB13: R1367.1 U636.G1
PBTN_OUT#: RH293.2 U34.H4
PBTN_OUT#_R: R1312.1 RH293.1 RH439.1 RH444.1 UCPU1.AL7
PBTN_SW#: DA8.3 JAPS.8 JPWR1.2 R987.2 RH21.1 RH439.2 SW2.1 SW2.2
PC0: R1135.1 U636.E8
PC2_1: R1136.1 U636.D6
PCH_DDI2_N0: CV30.1 UCPU1.C51
PCH_DDI2_N0_C: CV30.2 U722.7
PCH_DDI2_N1: CV33.1 UCPU1.C53
PCH_DDI2_N1_C: CV33.2 U722.5
PCH_DDI2_N2: CV34.1 UCPU1.C49
PCH_DDI2_N2_C: CV34.2 U722.2
PCH_DDI2_N3: CV35.1 UCPU1.A53
PCH_DDI2_N3_C: CV35.2 U722.10
PCH_DDI2_P0: CV27.1 UCPU1.C50
PCH_DDI2_P0_C: CV27.2 U722.6
PCH_DDI2_P1: CV28.1 UCPU1.B54
PCH_DDI2_P1_C: CV28.2 U722.4
PCH_DDI2_P2: CV29.1 UCPU1.B50
PCH_DDI2_P2_C: CV29.2 U722.1
PCH_DDI2_P3: CV36.1 UCPU1.B53
PCH_DDI2_P3_C: CV36.2 U722.9
PCH_DP_AUXN: CV10.2 UCPU1.C5
PCH_DP_AUXN_C: CV10.1 JNGFF2.20 R1036.1
PCH_DP_AUXP: CV8.2 UCPU1.B5
PCH_DP_AUXP_C: CV8.1 JNGFF2.22 R1035.1
PCH_DP_CLK: RH281.2 UCPU1.B9
PCH_DP_DAT: RH282.2 UCPU1.C9
PCH_DP_HPD: JNGFF2.31 RH300.2 UCPU1.C8
PCH_DP_N0: CV49.1 UCPU1.C54
PCH_DP_N0_C: CV49.2 JNGFF2.32
PCH_DP_N1: CV48.1 UCPU1.B58
PCH_DP_N1_C: CV48.2 JNGFF2.26
PCH_DP_N2: CV50.1 UCPU1.B55
PCH_DP_N2_C: CV50.2 JNGFF2.25
PCH_DP_N3: CV38.1 UCPU1.A57
PCH_DP_N3_C: CV38.2 JNGFF2.19
PCH_DP_P0: CV37.1 UCPU1.C55
PCH_DP_P0_C: CV37.2 JNGFF2.34
PCH_DP_P1: CV45.1 UCPU1.C58
PCH_DP_P1_C: CV45.2 JNGFF2.28
PCH_DP_P2: CV46.1 UCPU1.A55
PCH_DP_P2_C: CV46.2 JNGFF2.27
PCH_DP_P3: CV47.1 UCPU1.B57
PCH_DP_P3_C: CV47.2 JNGFF2.21
PCH_DPWROK: RH126.1 RH309.2 RH401.1 UCPU1.AV5
PCH_ENVDD: D93.2 D105.2 D306.2 RH158.2 UCPU1.C6
PCH_GPIO15: RH270.1 UCPU1.AD6
PCH_GPIO17: RH301.1 T281.1(TP-1) UCPU1.T3
PCH_GPIO18: Q348.1 RH91.2 RH417.2 UCPU1.U2
PCH_GPIO20: Q346.1 RH100.2 RH410.2 UCPU1.AD1
PCH_GPIO21: Q350.1 RH103.2 RH418.2 UCPU1.N1
PCH_GPIO22: RH107.2 UCPU1.U5
PCH_GPIO27: RH186.2 RH310.2 RH427.1 RH464.1 UCPU1.AN5
PCH_GPIO35: RH390.1 T271.1(TP-1) UCPU1.U1
PCH_GPIO36: RH391.1 T272.1(TP-1) UCPU1.V6
PCH_HDMI_CLK: RH388.2 U722.38 UCPU1.D9
PCH_HDMI_DAT: RH389.2 U722.39 UCPU1.D11
PCH_HDMI_HPD: RH387.2 U722.3 UCPU1.A8
PCH_INTVRMEN: RH31.2 RH34.2 UCPU1.AV7
PCH_INV_PWM: D106.3 RC146.2 RC147.1
PCH_JTAG_JTAGX: RH374.1 RH375.2 RH412.1 T273.1(TP-1) UCPU1.AE63
PCH_JTAG_TCK: RH53.2 RH373.1 RH411.1 T277.1(TP-1) UCPU1.AE62
PCH_JTAG_TDI: RH40.2 RH371.1 T278.1(TP-1) UCPU1.AD61
PCH_JTAG_TDO: RH369.1 RH413.1 RH445.2 T275.1(TP-1) UCPU1.AE61
PCH_JTAG_TMS: RH39.2 RH372.1 T276.1(TP-1) UCPU1.AD62
PCH_JTAG_TRST#: RH370.1 UCPU1.AU62
PCH_OPIRCOMP: RC156.1 UCPU1.AW15
PCH_PLTRST#: RH168.2 RH183.2 UCPU1.AG7 UH5.1 UH5.2
PCH_PWR_EN: R1249.2 U34.F2
PCH_PWRBTN#_XDP: JXDP.41 RH21.2 RH444.2
PCH_PWROK: R1295.2 R1296.2 R1297.2 RH134.2 RH394.1 UCPU1.AY7
PCH_PWROK_EC: R1294.1 U34.E6 U691.2
PCH_RSMRST#: RH133.2 RH159.1 U34.D4
PCH_RSMRST#_R: RH126.2 RH133.1 UCPU1.AW6
PCH_RTCRST#: CH4.2 CLRP1.2 JAPS.10 RH25.2 UCPU1.AU7
PCH_RTCX1: CH2.1 RH2.1 UCPU1.AW5 YH1.1
PCH_RTCX2: CH3.1 RH2.2 UCPU1.AY5 YH1.2
PCH_SATALED#: RH35.2 UCPU1.U3
PCH_SMBCLK: JXDP.53 QH3.1 RH98.2 RH105.2
PCH_SMBDATA: JXDP.51 QH3.4 RH99.2 RH111.2
PCH_SMLCLK: JTP1.10 Q352.6 Q359.1 QH4.1 R976.2 R983.2 R1350.2 RH453.2 U34.B8
PCH_SMLDATA: JTP1.11 Q352.3 Q359.4 QH4.4 R977.2 R984.2 R1351.2 RH454.2 U34.A6
PCH_SPI_CLK: MC118.2 RH256.2 RH258.2 UCPU1.AA3
PCH_SPI_CS1#: U2.1 UCPU1.Y4
PCH_SPI_CS#: U48.1 UCPU1.Y7
PCH_SPI_IO2: RH54.2 RP4.7 RP5.7 UCPU1.Y6
PCH_SPI_IO3: RH56.2 RP4.5 RP5.5 UCPU1.AF1
PCH_SPI_SI: RP4.6 RP5.6 UCPU1.AA2
PCH_SPI_SO: RP4.8 RP5.8 UCPU1.AA4
PCH_SRTCRST#: CH5.1 CLRP2.1 RH23.2 UCPU1.AV6
PCH_SUSWARN#: RH297.2 U34.D8
PCH_SUSWARN#R: RH154.1 RH297.1 RH429.2 UCPU1.AV4
PCI_PIRQC#: RH455.2 UCPU1.N4
PCI_PIRQD#: RH456.2 UCPU1.N2
PCIE_PRX_C_CARDTX_N2: CR13.2 U1.8
PCIE_PRX_C_CARDTX_P2: CR14.2 U1.7
PCIE_PRX_CARDTX_N2: CR13.1 UCPU1.F15
PCIE_PRX_CARDTX_P2: CR14.1 UCPU1.G15
PCIE_PRX_DTX_N1: JNGFF2.67 UCPU1.G17
PCIE_PRX_DTX_N4: JNGFF2.43 UCPU1.F13
PCIE_PRX_DTX_P1: JNGFF2.65 UCPU1.F17
PCIE_PRX_DTX_P4: JNGFF2.41 UCPU1.G13
PCIE_PRX_WLANTX_N3: JNGFF1.35 UCPU1.G11
PCIE_PRX_WLANTX_P3: JNGFF1.33 UCPU1.F11
PCIE_PTX_C_CARDRX_N2: CH25.2 UCPU1.B31
PCIE_PTX_C_CARDRX_P2: CH26.2 UCPU1.A31
PCIE_PTX_CARDRX_N2: CH25.1 U1.4
PCIE_PTX_CARDRX_P2: CH26.1 U1.3
PCIE_PTX_DRX_N1: CH1242.1 JNGFF2.61
PCIE_PTX_DRX_N1_C: CH1242.2 UCPU1.C30
PCIE_PTX_DRX_N4: CH1237.1 JNGFF2.37
PCIE_PTX_DRX_N4_C: CH1237.2 UCPU1.B29
PCIE_PTX_DRX_P1: CH1243.1 JNGFF2.59
PCIE_PTX_DRX_P1_C: CH1243.2 UCPU1.C31
PCIE_PTX_DRX_P4: CH1238.1 JNGFF2.35
PCIE_PTX_DRX_P4_C: CH1238.2 UCPU1.A29
PCIE_PTX_WLANRX_N3: CH11.1 JNGFF1.29
PCIE_PTX_WLANRX_N3_C: CH11.2 UCPU1.C29
PCIE_PTX_WLANRX_P3: CH16.1 JNGFF1.27
PCIE_PTX_WLANRX_P3_C: CH16.2 UCPU1.B30
PCIE_RCOMP: RH338.2 UCPU1.A27
PCIE_WAKE#: JNGFF1.47 JNGFF2.55 Q347.3 R942.2 U676.4
PLT_RST#: JDEBUG.6 MC104.1 R1313.1 RH168.1 RH171.1 RH363.2 U34.M5 U675.2 U678.1 U698.1 UH5.4
PLTRST1#_XDP: JXDP.46 RH363.1
PM_CLKRUN#: RH248.2 U34.M6 U652.15 UCPU1.V5
PM_SLP_A#: JAPS.13 R503.1 U34.K2 U721.3 UCPU1.AL5
PM_SLP_S0#: JAPS.4 PU501.2 RH447.2 RH448.1 U34.M2
PM_SLP_S3#: JAPS.17 PR404.1 PR405.1 R501.1 U34.J5 U673.16 U710.2 U716.3 U717.3 UCPU1.AT4
PM_SLP_S4#: JAPS.14 PR613.1 U34.N1 UCPU1.AJ6
PM_SLP_S5#: D114.1 JAPS.15 UCPU1.AP5
PM_SLP_SUS: Q5.2 U713.4
PM_SLP_SUS#: D307.3 R290.1 R1249.1 RH313.1 U713.2 U719.3
PM_SYS_RESET#: JAPS.6 RH450.2 RH451.2
PP: R975.1 U652.7
PROC_OPI_COMP: RC154.1 UCPU1.AY15
PS_ID: PR102.2 PR103.2 U34.K6
PSID: JDCIN1.1 PL102.1
PSID-1: PQ102.2 PR105.2 PR106.1
PSID-2: PQ101.2 PQ102.1 PR104.1
PSID-3: PQ101.3 PR103.1
PWM1: PU701.6 PU702.8
PWR_LED#: DA8.2 JPWR1.3 R1.1
PWR_SRC_ON: C613.2 Q70.3 R535.2 R536.1
REGN: PC213.1 PD202.2 PR223.1 PR224.2 PU201.16
RESET#: C1152.1 JSATA1.20 JSNRDG.2 R1003.1 R1090.1 R1141.1 U636.C7
ROTATION_SW#: C1125.1 R233.2 R957.2 U34.B9
ROTATION_SW#_C: JROT1.1 JROT1.2 R957.1
RREF: RR6.2 U1.9
RUN_ON#: Q4.2 Q34.2 U710.4
S3_+1.2V: PR615.2 PU601.7
S5_+1.2V: PC616.1 PR613.2 PU601.8
SATA_PRX_DTX_N0: CS53.1 UCPU1.J5
SATA_PRX_DTX_N0_C: CS53.2 JSATA1.25
SATA_PRX_DTX_P0: CS54.1 UCPU1.H5
SATA_PRX_DTX_P0_C: CS54.2 JSATA1.23
SATA_PTX_DRX_N0: CS43.1 UCPU1.B15
SATA_PTX_DRX_N0_C: CS43.2 JSATA1.31
SATA_PTX_DRX_P0: CS42.1 UCPU1.A15
SATA_PTX_DRX_P0_C: CS42.2 JSATA1.33
SATA_RCOMP: RH43.1 UCPU1.C12
SBD_WAKE#: T252.1(TP-1) U636.F8
SD_CD#: JCARD.8 U1.30
SD_CLK: CR20.1 JCARD.6 RR4.2
SD_CLK_R: RR4.1 U1.17
SD_CMD: JCARD.3 RR5.2
SD_CMD_R: RR5.1 U1.19
SD_D2: JCARD.1 RR8.2
SD_D2_R: RR8.1 U1.21
SD_D3: JCARD.2 RR7.2
SD_D3_R: RR7.1 U1.20
SD_LN0_M: JCARD.14 RR15.2
SD_LN0_M_R: RR15.1 U1.25
SD_LN0_P: JCARD.13 RR16.2
SD_LN0_P_R: RR16.1 U1.26
SD_LN1_M: JCARD.17 RR13.2
SD_LN1_M_R: RR13.1 U1.23
SD_LN1_P: JCARD.18 RR12.2
SD_LN1_P_R: RR12.1 U1.22
SD_RCLK_M: JCARD.10 RR2.2
SD_RCLK_M_R: RR2.1 U1.15
SD_RCLK_P: JCARD.9 RR3.2
SD_RCLK_P_R: RR3.1 U1.16
SD_REG2: CR6.2 RR14.2
SD_REG2_R: RR14.1 U1.24
SD_WAKE#_R: RR10.1 RR18.1 U1.32
SDIO_CLK: JNGFF1.9 R1360.2 UCPU1.E3
SDIO_CMD: JNGFF1.11 R1361.2 UCPU1.F4
SDIO_D0: JNGFF1.13 R1362.2 RH434.2 UCPU1.D3
SDIO_D1: JNGFF1.15 R1363.2 UCPU1.E4
SDIO_D2: JNGFF1.17 R1364.2 UCPU1.C3
SDIO_D3: JNGFF1.19 R1365.2 UCPU1.E2
SDIO_RST#: JNGFF1.23 R1328.2 U679.D1
SDIO_RST#_R: R1313.2 R1314.2 U679.A1
SDIO_WAKE#: R1215.2 U679.A2
SDIO_WAKE#_Q: JNGFF1.21 R1327.2 U679.D2
SENSE_A: RA41.1 UA2.34
SENSE_B: RA24.1 UA2.33
SENSOR_ALERT#: R1158.1 U636.H6
SENSOR_DFU_EN#: JSNRDG.17 R1220.1 U636.F2 UCPU1.AK4
SENSOR_EN: JSNRDG.16 R1250.1 U716.5 UCPU1.AG3
SENSOR_HUB_I2C_WAKE: R1252.1 UCPU1.Y3
SENSOR_HUB_I2C_WAKE_R: JSNRDG.13 R1252.2 R1253.1 U636.G2
SENSOR_HUB_WAKE#: R232.2 U636.F1
SENSOR_I2C_SCL: JLVDS2.33 JSNRDG.8 R854.1 R985.2 U636.B5
SENSOR_I2C_SDA: JLVDS2.34 JSNRDG.9 R855.1 R986.2 U636.C5
SENSOR_INT#: R1135.2 R1367.2 RH298.1 T285.1(TP-1) UCPU1.AH4
SENSOR_RST#: R1090.2 RH452.2 UCPU1.R5
SENSOR_STANDBY#: D86.2 UCPU1.C4
SERIRQ: RH29.1 U34.M3 U652.27 UCPU1.T4
SKIN_TEMP0: C1251.1 R933.2 R936.1 U34.E7
SKIN_TEMP1: C1252.1 R937.2 R938.1 U34.D7
SKIP#: PR718.1 PU701.7
SKIP#1: PR718.2 PR720.2 PU702.1
SLATE_MODE: U636.D5 UCPU1.AL4
SLEEVE: CA68.1 DA1.3 JHP1.4 QA1.3 RA27.2 UA2.32
SLEW: PC502.2 PU501.21
SLEWA: PR701.2 PR714.1 PU701.15
SLP_WLAN#: RH402.1 U34.N8 UCPU1.AM5
SM_INTRUDER#: RH11.2 UCPU1.AU6
SM_PG_CTRL: PR615.1 RC159.2 RC161.1 UC1.4
SM_RCOMP0: RC55.1 UCPU1.AU60
SM_RCOMP1: RC58.1 UCPU1.AV60
SM_RCOMP2: RC60.1 UCPU1.AU61
SMBALERT#: R1136.2 RH81.1 UCPU1.AN2
SMBCLK: QH3.6 RH105.1 RH470.1 UCPU1.AP2
SMBDATA: QH3.3 RH111.1 RH471.1 UCPU1.AH1
SML0CLK: JNFC1.8 RH70.1 UCPU1.AN1
SML0DATA: JNFC1.7 RH72.1 UCPU1.AK1
SML1ALERT#: R1158.2 R1229.1 UCPU1.AU4
SML1CLK: QH4.6 RH453.1 RH469.1 UCPU1.AU3
SML1DATA: QH4.3 RH454.1 RH472.1 UCPU1.AH3
SNUB_1.5VSP: PC427.1 PR429.2
SNUB_1.8VSP: PC439.1 PR432.2
SNUB_3V: PC333.1 PR312.2
SNUB_5V: PC329.1 PR313.2
SNUB_+1.2V: PC613.1 PR605.2
SNUB_+1.05V: PC509.1 PR507.2
SNUB_CHG: PC221.1 PR220.2
SOSCI: CH1202.1 U636.B8 Y1.2
SOSCO: CH1203.1 U636.B7 Y1.1
SP7_SDWP: JCARD.11 U1.29
SPARE1: JSNRDG.10 U636.C4
SPARE2: JSNRDG.11 U636.A3
SPI_CLK32: MR257.2 RH256.1 U2.6
SPI_CLK_ROM: MR256.2 RH258.1 U48.6
SPI_DIN32: RP5.1 U2.2
SPI_DO32: RP5.3 U2.5
SPI_IO2_ROM: RP4.2 U48.3
SPI_IO3_ROM: RP4.4 U48.7
SPI_PCH_DO2_32: RP5.2 U2.3
SPI_PCH_DO3_32: RP5.4 U2.7
SPI_SI_ROM: RP4.3 U48.5
SPI_SO_ROM: RP4.1 U48.2
SPK_L+_C: CA55.2 DA3.2 JSPK1.4 L2.2
SPK_L-_C: CA53.2 DA3.3 JSPK1.3 L3.2
SPK_OUT_L+: L2.1 U4.19
SPK_OUT_L-: L3.1 U4.1
SPK_OUT_R+: L4.1 U4.17
SPK_OUT_R-: L5.1 U4.15
SPK_R+_C: CA54.2 DA4.2 JSPK1.2 L4.2
SPK_R-_C: CA56.2 DA4.3 JSPK1.1 L5.2
SSD_PWREN: RH431.1 U682.4 U724.3
SSD_PWREN#: RH423.1 RH431.2 U682.2 UCPU1.K2
SUS_STAT#: R1238.1 UCPU1.AG4
SUSACK#: RH430.2 U34.M13
SUSACK#_R: RH429.1 RH430.1 UCPU1.AK2
SUSCLK: MC102.2 RH132.2 UCPU1.AE6
SUSCLK_R: R253.1 R1255.2 R1256.2 RH132.1
SW_+1.2V: PC605.1 PL602.2 PQ601.1 PQ601.2 PQ601.3 PQ602.5 PR605.1 PU601.16
SW_+1.05VS: PC503.2 PL502.1 PR507.1 PU501.6 PU501.7 PU501.8 PU501.9
SW_USB20_N0: ML52.4 US2.11
SW_USB20_N1: ML40.4 US1.11
SW_USB20_P0: ML52.1 US2.10
SW_USB20_P1: ML40.1 US1.10
SYS_PRS: JBATT1.4 PR115.1
SYS_PWROK: R1290.2 R1292.2 R1294.2 R1297.1 R1309.1 RH272.1 UCPU1.AG2
SYS_PWROK_XDP: C1282.1 JXDP.47 R1309.2 R1311.1
SYS_RESET#: RH450.1 RH467.1 UCPU1.AC3
SYSTEM_FAN_FB: D81.2 R884.1 U34.M11
SYSTEM_FAN_PWM: JFAN1.3 JFAN1.6 R1103.1 U34.N10
TABLET_MODE: Q107.2 RA42.1 U34.B7
TABLET_MODE_R: T283.1(TP-1) UA1.7
TD_IREF: RC155.1 UCPU1.B12
TESTLOW1: RH76.1 UCPU1.C35
TESTLOW2: RH77.1 UCPU1.C34
TESTLOW3: RH78.1 UCPU1.AK8
TESTLOW4: RH79.1 UCPU1.AL8
TP_CLK: DE1.2 JTP1.5 R979.2 U34.A5
TP_DATA: DE1.3 JTP1.4 R978.2 U34.B5
TP_EN: R1174.1 U718.5 UCPU1.N6
TP_INT#: Q364.1 R1387.1 RH380.2 UCPU1.U7
TP_INT#_R: JTP1.8 Q364.3 R1300.2 R1387.2
TPM_DET: RH274.2 RH337.1 UCPU1.AG5
TPM_IRQ#: RH463.2 UCPU1.P4
TPM_RESET#: R1310.1 U652.16 U698.4
TPM_RST#: U698.2 UCPU1.AG6
TRIP: PR508.2 PU501.20
TS_EN: U719.5 UCPU1.N7
TS_INT#: Q363.1 R1384.1 RH384.1 UCPU1.P3
TS_INT#_R: Q363.3 R1157.1 R1384.2 R1385.2
TS_RST#: R1227.1 R1376.1 UCPU1.L1
TS_RST#_R: JLVDS2.49 R1157.2 R1227.2
UART1_CTS#: RH460.1 U671.10 UCPU1.J4
UART1_CTS#_NGFF: JNGFF1.26 R1371.2 U671.5
UART1_RTS#: RH459.1 U671.11 UCPU1.J3
UART1_RTS#_NGFF: JNGFF1.28 R1370.2 U671.4
UART1_RXD: RH457.1 U671.12 UCPU1.K4
UART1_RXD_NGFF: JNGFF1.22 R1369.2 U671.3
UART1_TXD: RH458.1 U671.13 UCPU1.G2
UART1_TXD_NGFF: JNGFF1.24 R1368.2 U671.2
UART_WAKE#: JNGFF1.20 RH383.1 T288.1(TP-1) UCPU1.AM3
UG_3V: PQ304.2 PU301.10
UG_5V: PQ305.2 PU301.16
USB0_CTL1: R1166.2 U34.B4
USB0_DET#: D83.1 JUSB2.10
USB0_DET_EC#: D83.3 R935.1 U34.D1
USB0_EN: R1217.2 U700.4 US2.5
USB0_PWR_EN: RH400.1 U700.1 UCPU1.AT3
USB0_PWR_EN_EC: RP22.2 U34.M1 U700.2
USB1_CTL1: R1167.2 U34.H1
USB1_DET#: D104.1 JUSB1.10
USB1_DET_EC#: D104.3 R1156.2 U34.A2
USB1_EN: R1216.2 U699.4 US1.5
USB1_PWR_EN: RH403.2 U699.1 UCPU1.AV3
USB1_PWR_EN_EC: RP21.3 U34.J2 U699.2
USB3RN0: ML54.4 UCPU1.G20
USB3RN0_RC_CON: JUSB2.5 MD82.1 ML54.3
USB3RN1: ML46.1 UCPU1.E18
USB3RN1_RC_CON: JUSB1.5 MD74.6 ML46.2
USB3RP0: ML54.1 UCPU1.H20
USB3RP0_RC_CON: JUSB2.6 MD82.2 ML54.2
USB3RP1: ML46.4 UCPU1.F18
USB3RP1_RC_CON: JUSB1.6 MD74.5 ML46.3
USB3TN0: C1107.1 UCPU1.C33
USB3TN0_C: C1107.2 ML53.4
USB3TN0_RC_CON: JUSB2.8 MD82.3 ML53.3
USB3TN1: C621.1 UCPU1.B33
USB3TN1_C: C621.2 ML45.4
USB3TN1_RC_CON: JUSB1.8 MD74.3 ML45.3
USB3TP0: C1108.1 UCPU1.B34
USB3TP0_C: C1108.2 ML53.1
USB3TP0_RC_CON: JUSB2.9 MD82.4 ML53.2
USB3TP1: C623.1 UCPU1.A33
USB3TP1_C: C623.2 ML45.1
USB3TP1_RC_CON: JUSB1.9 MD74.4 ML45.2
USB20_N0: UCPU1.AN8 US2.2
USB20_N0_CONN: JUSB2.2 MD82.5 ML52.3
USB20_N1: UCPU1.AR7 US1.2
USB20_N1_CONN: JUSB1.2 MD74.2 ML40.3
USB20_N2: ML49.1 R742.1 UCPU1.AR8
USB20_N2_R: JNGFF1.5 ML49.2 R742.2
USB20_N3: R1218.1 UCPU1.AR10
USB20_N4: ML55.1 R1005.1 UCPU1.AM15
USB20_N4_CONN: JLVDS1.4 MD50.1 ML55.2 R1005.2
USB20_N5: R1221.1 UCPU1.AM13
USB20_N6: ML50.1 R743.1 UCPU1.AP11
USB20_N6_R: JNGFF2.5 ML50.2 R743.2
USB20_P0: UCPU1.AM8 US2.3
USB20_P0_CONN: JUSB2.3 MD82.6 ML52.2
USB20_P1: UCPU1.AT7 US1.3
USB20_P1_CONN: JUSB1.3 MD74.1 ML40.2
USB20_P2: ML49.4 R741.1 UCPU1.AP8
USB20_P2_R: JNGFF1.3 ML49.3 R741.2
USB20_P3: R1219.1 UCPU1.AT10
USB20_P4: ML55.4 R1004.1 UCPU1.AL15
USB20_P4_CONN: JLVDS1.3 MD50.3 ML55.3 R1004.2
USB20_P5: R1222.1 UCPU1.AN13
USB20_P6: ML50.4 R744.1 UCPU1.AN11
USB20_P6_R: JNGFF2.3 ML50.3 R744.2
USB_CTL0: R1166.1 R1213.1 US2.6
USB_CTL1: R1167.1 R1214.1 US1.6
USB_ILIM_SET: R1164.1 R1170.1 U34.K8 US1.4 US2.4
USB_OC0#: RH468.1 UCPU1.AL3 US2.13
USB_OC1#: RH160.1 UCPU1.AT1 US1.13
USB_OC2#: RH80.1 UCPU1.AH2
USBCHG_DET_D: R342.1 U712.4
USBCHG_DET_PWR_EN#: D83.2 D104.2 R939.2 U712.2
USBRBIAS: RH163.1 UCPU1.AJ10 UCPU1.AJ11
V_DDR_REF_CA: CD89.1 RD14.1 UCPU1.AP49
V_DDR_REFA_R: CD91.1 RD19.1 UCPU1.AR51
V_DDR_REFB_R: CD92.1 RD20.1 UCPU1.AP51
VCIN0_PH: R947.2 R948.1 U34.C2
VCIN1_PH: PC112.1 PR116.2 PR118.1 U34.D2
VCOUT0_PH#: D303.1 R922.1 U34.E4
VLDOIN_+1.2V: PJP604.2 PU601.19
VOLUME: C48.1 R23.1 R26.2 U4.7
VOLUME_DOWN_SW#: C1124.1 R955.2 RP21.1 U34.J1
VOLUME_DOWN_SW#_C: DA6.2 JVOL.2 R955.1 R1263.1
VOLUME_DOWN_SW#_DSP: R1263.2 R1265.2 UA1.4
VOLUME_UP_SW#: C1123.1 R953.2 RP22.4 U34.N11
VOLUME_UP_SW#_C: DA6.3 JVOL.1 R953.1 R1264.1
VOLUME_UP_SW#_DSP: R1264.2 R1266.2 UA1.20
VR_HOT#: PU701.30 R265.2
VR_ON: PU701.8 RC151.1
VR_ON_MCP: RC151.2 UCPU1.F60
VR_SVID_ALRT#: PR736.2 PU701.32 RC94.1
VR_SVID_CLK: PR735.2 PU701.31 RC92.1
VR_SVID_DAT: PR737.2 PU701.1 RC96.1
VREF: PC717.1 PH701.1 PR701.1 PR704.1 PR706.1 PR726.2 PR745.1 PU701.27
VREF_CODEC: CA39.2 UA2.41
VRP: CA52.1 UA2.38
VRPG_MCP: RC152.2 UCPU1.C59
VTTREF_+1.2V: PC609.1 PU601.4
WAKE#: RH128.2 RH146.1 RH310.1 UCPU1.AJ5
WAKE_PCH#: R604.2 RH128.1 U34.L12 U676.2
WIN8_INT#: JLVDS2.41 MC105.1 U34.G4
WL_OFF#: Q344.3 UCPU1.L2
WL_OFF#_R: JNGFF1.48 JNGFF2.56 Q344.1 R1137.2
WLAN_EN: D115.1 R1390.1 U718.3
XCLK_BIASREF: RH113.1 UCPU1.C26
XDP_BPM0#: JXDP.21 UCPU1.J60
XDP_BPM1#: JXDP.23 UCPU1.H60
XDP_DBRESET#: C1237.1 JXDP.48 RH367.1 RH451.1
XDP_PIN60: JXDP.60 R1198.1
XDP_PRDY#: JXDP.5 T263.1(TP-1) UCPU1.J62
XDP_PREQ#: JXDP.3 T264.1(TP-1) UCPU1.K62
XDP_PWRGD: JXDP.39 R1180.2
XDP_TCK0: JXDP.57 RH374.2 RH411.2 RH446.2
XDP_TCK1: JXDP.55 RH373.2
XDP_TDI: JXDP.56 RH371.2 RH414.1
XDP_TDI_SWITCH: RH413.2 RH414.2 U663.8
XDP_TDO: JXDP.52 RH38.2 RH369.2 RH412.2 U663.6
XDP_TMS: JXDP.58 RH372.2 U663.11
XDP_TRST#: JXDP.54 U663.3
XTAL24_IN: CH23.1 RH117.2 UCPU1.A25 YH2.3
XTAL24_OUT: CH24.1 RH117.1 UCPU1.B25 YH2.1
N13303482: PC115.2 PQ105.5 PR124.1
N13303498: PC115.1 PQ105.6 PR126.2
N13303530: PC114.2 PQ104.2 PR108.1
N13303550: PQ105.2 PR123.2 PR125.1
N13303636: PC116.1 PQ106.2 PR110.2
N13305100: PL102.2 PQ101.1 PR105.1
N13305156: PQ103.5 PQ103.6 PR120.2 PR121.1
N13305200: PC113.1 PQ103.2 PR119.2
N13305312: PQ103.3 PR122.2
N13374678: PC504.2 PR505.2 PU501.18
N13374846: PC503.1 PR506.2
N17638789: Q329.1 R943.1
N17654244: C1160.1 Q326.1 Q329.2 R989.1
N18675747: MC284.1 MR226.2
N22841841: R1331.1 U717.13 U717.14
N34287396: MC94.1 MR256.1
N34514472: RH313.2 UCPU1.AP4
N34536136: T123.1(TP-1) UCPU1.AD4
N35032609: CH1206.1 UCPU1.AE7
N36180324: CH1218.1 RH346.2
N39815594: T226.1(TP-1) UCPU1.H61
N39815596: T227.1(TP-1) UCPU1.H62
N39815598: T228.1(TP-1) UCPU1.K59
N39815600: T229.1(TP-1) UCPU1.H63
N39815609: T231.1(TP-1) UCPU1.J61
N39815611: T230.1(TP-1) UCPU1.K60
N39955939: R1125.1 U664.8 U664.9
N39956017: C1212.1 U664.12
N39956029: R1318.1 U664.13 U664.14
N39956087: C1214.1 U664.10
N40621945: Q71.1 R536.2
N41001654: C1230.1 U715.12
N41482702: R1188.1 U671.8
N41500627: C1242.1 U673.1
N41500629: R1190.1 U673.15
N41574995: R1204.1 U677.8
N41624107: R1202.1 R1232.2 R1233.2 R1338.1 U676.1 U709.4
N41625248: C1246.1 Q347.2 R1202.2
N41869823: C1244.1 U673.17
N42153733: R1330.1 U716.13 U716.14
N42557576: R1289.2 R1291.2 U690.1
N42775202: Q351.3 RH24.1
N42993790: R1131.1 U679.C2
N43167321: R1322.1 U715.13 U715.14
N43454026: R1326.1 U719.13 U719.14
N44367556: R1321.1 U715.8 U715.9
N44368114: C1247.1 U715.10
N44369635: C617.2 R1260.2 U715.6 U715.7
N44370994: C1257.1 U716.12
N44372336: R1319.1 U716.8 U716.9
N44373242: C1248.1 U716.10
N44377351: C1163.1 U717.12
N44380707: C1202.1 U718.12
N44531503: C355.1 U719.12
N44535135: C1278.1 U719.10
N44536141: R1320.1 U719.8 U719.9
N44948988: RD7.1 UD6.L8
N44951196: RD8.1 UD7.L8
N44953884: RD11.1 UD9.L8
N44956010: RD12.1 UD10.L8
N44984260: RD1.1 UD1.L8
N44985933: RD2.1 UD2.L8
N44994261: RD5.1 UD4.L8
N44996448: RD6.1 UD5.L8
N45067794: CD91.2 RD23.1
N45067802: CD92.2 RD24.1
N45067875: CD89.2 RD16.1
N45134129: RD79.1 UD1.L9
N45134345: RD80.1 UD2.L9
N45134724: RD81.1 UD4.L9
N45134937: RD82.1 UD5.L9
N45136338: RD83.1 UD6.L9
N45136742: RD84.1 UD7.L9
N45137119: RD85.1 UD9.L9
N45137332: RD86.1 UD10.L9
N45346908: C1280.2 R1305.2 R1306.2 U717.6 U717.7
N45346942: C1281.1 U717.10
N45347302: R1128.1 U718.8 U718.9
N45347364: C1292.1 U718.10
N45348400: R1226.1 U718.13 U718.14
N45705313: R34.1 U4.13
N46229337: RR9.2 U1.28
N46231209: D111.1 RV28.1 RV29.1
N46238153: MC95.1 MR257.1
N46249068: R1118.1 US1.15
N46249084: R1165.1 US1.7 US1.8
N46249102: R1117.1 US1.16
N46483813: JNGFF2.50 R1256.1
N46487566: JNGFF1.42 R1255.1
N46493858: JNGFF2.52 R1243.1
N46563920: QA1.5 QA1.6 RA16.2
N46563950: CA74.1 Q6.1 QA1.2 RA18.2 RA57.2
N46564129: RA23.2 RA44.2 UA3.B1
N46564153: CA30.1 UA3.B3
N46564161: RA21.2 UA3.A1
N46564163: RA22.2 UA3.A3
N46564471: CA47.1 CA48.1 R7.1 RA31.2 RA33.2 RA56.2
N46564600: T254.1(TP-1) UA2.37
N46564857: CA23.1 UA2.10
N46564859: CA51.1 UA2.20
N46565041: CA44.1 UA2.21
N46565056: CA44.2 UA2.24
N46565215: QA3.3 RA37.2 RA39.1
N46565224: CA38.1 QA3.2 RA39.2
N46974230: Q136.1 R163.1 R990.1 U23.10 U23.13
N46974405: Q135.1 R162.1 R988.1 U23.1 U23.4
N47176858: Q134.2 Q136.3 R31.2 R990.2 RH419.2 RH420.2
N47395773: PR428.2 PU405.4
N47396645: PR434.1 PU406.4
N47396970: PC436.1 PJP411.2 PU406.10 PU406.11 PU406.12
N47421956: PR717.2 PU701.16
N47421965: PC720.1 PR731.2 PU701.28
N47421967: PC709.1 PH701.2 PR709.1 PU701.14
N47422029: PR721.1 PU701.4
N47422048: PH702.2 PR708.1
N47422075: PL701.2 PR702.1
N47422085: PC715.1 PR725.1 PU701.2
N47422365: PC712.2 PR719.1
N47422375: PR715.2 PU702.6
N47422428: PC711.2 PR715.1
N47422430: PC711.1 PU702.7
N47423101: PC724.1 PR744.2
N47902580: JSATA1.45 T244.1(TP-1)
N47902593: JSATA1.47 T245.1(TP-1)
N47902613: JSATA1.49 T246.1(TP-1)
N47972075: C407.1 U721.6
N47972306: R1379.1 U721.7 U721.8
N47973312: R1380.1 U720.7 U720.8
N47973343: C1300.1 U720.6
N48312843: Q107.1 RA41.2
N48433973: MC1141.1 MR976.2
N48463842: DA5.2 JHP1.5 RA14.2
N48664246: PC208.2 PC209.2 PR202.2 PR206.1
N48664254: PC209.1 PQ201.4 PR203.1
N48664258: PQ201.3 PR201.1
N48664262: PQ201.2 PR202.1
N48664277: PQ202.1 PR209.2
N48664377: PC202.1 PC203.1 PC204.1 PC205.1 PL201.2 PL202.2 PQ203.5
N48664598: PC218.1 PD202.1 PR211.2
N48665076: PQ206.4 PR230.2
N48665187: PQ204.1 PR224.1 PU201.10
N48665195: PC229.2 PQ204.2 PR225.1
N48665393: PD201.1 PR210.1
N48680306: T280.1(TP-1) UCPU1.AC20
N48727395: C1227.1 Q360.4 R1382.2 R1383.2
N48727429: Q361.3 R1382.1
N48727431: Q361.6 R1383.1
N48850801: PL303.2 PQ304.5 PQ304.6 PQ304.7 PR312.1
N48850817: PR344.2 PU301.6
N48850937: PL302.1 PQ305.5 PQ305.6 PQ305.7 PR313.1
N48851279: PR318.1 PU301.1
N48851283: PR345.1 PU301.20
N48851285: PR311.2 PU301.5
N48851436: PR351.1 PU301.19
N49081818: R1389.1 U724.7 U724.8
N49081850: C1304.1 U724.6
N49122205: JNGFF1.58 R1212.1
N49301602: PR335.2 PU301.3
N49301672: PC342.1 PU301.13
N49308388: PR239.2 PU201.8
N49308391: PR240.2 PU201.9
N49379203: CA58.2 RA56.1
N49466651: JKB1.9 JKB2.3
N49718258: Q366.1 Q366.3
N49718282: Q367.1 Q367.3
N49718310: Q366.6 R1.2
N49718360: Q367.6 R4.2
N49853731: RH447.1 UCPU1.AF3
N49853749: RH448.2 UCPU1.L5
N51252706: D81.1 JFAN1.2 JFAN1.7 R886.1
N51254722: Q6.2 RA75.2
N51410754: D301.2 R342.2
N51410761: D302.2 R341.2
N51850640: Q134.1 Q135.3 R988.2
N52198701: R1168.1 US2.7 US2.8
N52198820: R1119.1 US2.15
N52198836: R1120.1 US2.16
N52248533: JNGFF2.17 T289.1(TP-1)
N52739814: JSATA1.38 T243.1(TP-1)
N52739816: JSATA1.36 T242.1(TP-1)
N53088164: PC605.2 PR601.1
N53261894: RTCD1.2 RTCR1.1
N53506599: JNGFF2.66 R1241.1
N85222631: R921.1 U34.J6
N93297419: Q305.2 U708.4
N93297423: Q305.1 R541.2
N96981838: JBL1.3 R944.2

Pads without a net: BRK1 1; D110 3; DA9 2; FD1 1; FD2 1; FD3 1; FD4 1; FD5 1; FD6 1; JAPS 1 2 3; JBL1 2; JKB2 1; JLVDS1 18; JNFC1 3 11 12; JNGFF1 6 16 36 38 40 50 51 52 53 54 56 57 59 60 62 63 65; JNGFF2 6 8 9 10 11 12 13 14 15 16 44 46 48 58 60 62 64 70; JPWR1 5; JSATA1 1 3 5 6 7 11 13 17 19 28 30 32 42 46 48; JSNRDG 12; JXDP 40 42; MD90 4 6; PD104 3; PU405 8; PU406 8; PU501 3 4 27; PU701 5; RP21 4 5; U1 31; U4 8 18; U5 1; U635 1; U636 A2 B3 B6 C8 D1 E1 E2 E3 F4 G4 G7 H4 H7; U652 6 12 13 14; U671 6 9; U672 1; U677 6 9; U682 1; U708 1; U709 1; U710 1; U712 1; U713 1; U714 1 2 4 5 8 9 10 12 13 16; U722 36; UA1 22 28 32 33 34 35 36 45 46; UA2 3 15 16 18 19 45 46; UC1 1; UCPU1 A4 A5 A6 A17 A21 A23 A35 A37 A39 A51 A60 A62 AA23 AA59 AB21 AB23 AC2 AC4 AC58 AC59 AD23 AD59 AD60 AE59 AE60 AF20 AG58 AJ7 AK38 AL1 AL11 AL32 AL38 AM10 AM11 AN10 AP7 AP13 AP32 AR13 AT2 AU10 AU12 AU15 AU44 AU63 AV1 AV2 AV10 AV44 AV50 AV62 AV63 AW1 AW10 AW14 AW36 AW49 AW63 AY8 AY14 AY36 AY42 AY43 AY60 B2 B6 B14 B17 B21 B22 B23 B35 B37 B39 B43 B51 C15 C17 C21 C22 C23 C62 C63 D1 D15 D17 D58 D61 E1 E5 E6 E8 E10 E13 E15 F5 F6 F8 F10 F22 G1 G10 H6 H8 H10 H18 H22 J2 J6 J8 J20 J21 J58 K10 K18 K21 L6 L8 L11 L59 L60 M20 M21 N23 N58 N59 N60 N61 P20 P60 P61 R20 R23 T23 T59 U10 U59 V21 V59 W23 Y20 Y22; US1 9; US2 9

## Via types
v1: diameter 0.457, hole 0.203, TOP to BOTTOM, 2394 vias
v2: diameter 0.305, hole 0.152, TOP to BOTTOM, 695 vias
v3: diameter 0.457, hole 0.203, IN1 to IN4, 673 vias
v4: diameter 0.305, hole 0.102, IN4 to BOTTOM, 907 vias
v5: diameter 0.406, hole 0.203, TOP to BOTTOM, 117 vias
v6: diameter 0.508, hole 0.254, TOP to BOTTOM, 662 vias
v7: diameter 0.305, hole 0.102, TOP to IN1, 408 vias
v8: diameter 0.305, hole 0.102, TOP to GND1, 232 vias
v9: diameter 0.305, hole 0.102, GND3 to BOTTOM, 195 vias
v10: diameter 0.254, hole 0.102, GND3 to BOTTOM, 122 vias
v11: diameter 0.254, hole 0.102, TOP to GND1, 16 vias
v12: diameter 0.305, hole 0.102, GND1 to IN1, 1 via

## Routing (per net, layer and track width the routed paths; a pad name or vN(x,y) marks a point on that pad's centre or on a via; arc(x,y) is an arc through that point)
1.2V_DDR_PWROK: length 182.4
  TOP w0.109: v2(99.17,33.87) 99.17,33.26 v1(98.99,33.08) ; v1(210.84,59.81) 210.84,59.2 R1133.2
  IN1 w0.076: v1(98.99,33.08) 98.99,33.16 98.16,32.33 98.16,28.52 97.55,27.91 97.55,15.87 99.59,13.84 99.59,13.14 100.4,12.33 100.92,12.33 101.3,11.95 102.75,11.95 105.55,9.15 v3(106.08,9.15)
  IN3 w0.102: v1(210.84,59.81) 211.02,59.63 211.02,56.62 210.72,56.33 210.01,56.33 209.11,55.43 209.11,53.96 209.82,53.25 209.82,52.81 208.55,51.55 208.55,49.9 206.23,47.58 206.23,42.67 205.23,41.66 205.23,39.63 199.21,33.61 199.21,26.78 198.04,25.61 198.04,14.53 193.62,10.12 193.16,10.12 190.89,7.84 180.36,7.84 179.23,6.72 159.79,6.72 157.1,9.4 150.93,9.4 149.86,10.47 139.95,10.47 138.96,9.48 128.05,9.48 126.46,7.88 108.4,7.88 107.13,9.15 v3(106.08,9.15)
  BOTTOM w0.109: PU601.10 98.93,33.54 98.99,33.47 v1(98.99,33.08)
1.05V_VREF: length 2.6
  TOP w0.203: v1(199.57,61.1) 199.54,61.13 PU501.26
  BOTTOM w0.254: v1(199.57,61.1) 199.51,61.16 PC501.2
1.05VS_PG: length 104.8
  TOP w0.109: v1(87.85,63.56) 87.85,63.93 87.68,64.1 U697.1 ; U672.2 121.09,52.99 R1353.2 121.95,53.63 122.28,53.96 122.28,54.75 122.6,55.07 v2(124.39,55.07) 124.85,55.07 v7(126.31,56.52)
  IN1 w0.076: v1(87.85,63.56) 89.43,63.56 91.43,61.55 94.3,61.55 95.47,62.72 103.63,62.72 105.12,64.22 106.93,64.22 108.84,66.13 122.66,66.13 127.02,61.77 127.02,60.71 128.52,59.22 128.52,58.23 126.84,56.55 v3(126.69,56.55) 126.66,56.52 v7(126.31,56.52) ; v3(165.59,54.99) 165.7,55.1 v7(166.02,55.1)
  IN3 w0.102: v3(165.59,54.99) 161.88,54.99 161.51,54.62 160.37,54.62 159.38,53.63 155.11,53.63 154.6,53.12 151.63,53.12 150.44,54.31 150.44,57.89 150.11,58.23 129.13,58.23 127.45,56.55 v3(126.69,56.55)
1.05VS_PG_EC: length 96.1
  TOP w0.109: v7(125.43,56.55) v2(124.36,56.55) 123.37,55.56 122.28,55.56 121.72,55 R1353.1
  IN1 w0.076: v3(125.82,56.55) v7(125.43,56.55)
  IN3 w0.102: v1(200.22,57.63) 200.21,57.63 196.77,54.19 195.2,54.19 193.83,52.81 189.56,52.81 187.42,54.95 184.67,54.95 183.73,55.89 182.11,55.89 181.45,56.55 181.1,56.55 180.31,55.76 175.48,55.76 175.12,56.12 168.99,56.12 167.64,57.46 165.18,57.46 164.94,57.22 163.72,57.22 163.33,57.62 162.86,57.62 161.87,58.61 160.72,58.61 160.42,58.3 158.41,58.3 157.68,59.04 156.94,59.04 156.25,58.35 154.83,58.35 154.37,58.81 150.31,58.81 149.68,59.44 129.63,59.44 127.22,57.03 126.31,57.03 v3(125.82,56.55)
  BOTTOM w0.109: 206.57,55.94 205.81,56.7 205.81,57.23 205.45,57.59 204.87,57.59 203.75,58.71 202.94,58.71 202.51,59.14 201.95,59.14 200.44,57.63 v1(200.22,57.63)
  BOTTOM w0.254: U34.A1 206.57,55.94
1.5VS_PWROK: length 154.7
  TOP w0.109: PR428.1 83.55,53.59 v2(83.55,55.88) 83.55,62.37 v1(84.16,62.97) ; v1(208.3,59.85) 208.97,59.18 R982.2
  IN3 w0.102: v1(84.16,62.97) 84.78,62.97 86.02,64.22 89.83,64.22 91.71,66.1 98.11,66.1 99.93,64.28 101.95,64.28 105.01,67.34 106.93,67.34 108.71,69.12 111.55,69.12 111.91,69.48 117.47,69.48 117.7,69.71 121.48,69.71 123.13,71.36 129.53,71.36 131.9,68.99 137.55,68.99 138.41,68.13 142.58,68.13 143.49,67.22 146.06,67.22 148.39,69.55 153.89,69.55 154.04,69.4 162.91,69.4 164.43,67.88 165.45,67.88 165.6,68.03 165.6,68.34 166.46,69.2 174.62,69.2 176.22,67.6 180.12,67.6 180.89,68.37 189.54,68.37 189.83,68.66 193.15,68.66 195.26,66.56 198.4,66.56 200.71,68.87 204.22,68.87 206.79,66.3 206.79,64.17 206.9,64.05 206.9,61.51 208.3,60.11 v1(208.3,59.85)
1.05VS_VCCST_PG: length 20.4
  TOP w0.109: v7(117.09,52.76) 117.28,52.76 117.99,52.05 R1132.2 117.99,50.76 118.45,50.3 v2(119.11,50.3) 120.22,50.3 U672.4
  IN1 w0.076: v7(117.09,52.76) 116.78,53.07 116.78,53.58 113.34,57.02 113.07,57.02 112.71,57.39 v3(112.6,57.39) 111.84,56.62 v7(111.31,56.62)
  IN4 w0.076: v3(112.6,57.39) 112.6,58.03 115.18,60.61 115.18,61.15 115.84,61.81 116.6,61.81 v4(116.83,61.58)
1.5VSP_FB: length 4.9
  TOP w0.109: PR425.1 85.77,51.8 v2(86.57,52.6)
  TOP w0.254: PC429.2 PR425.1 ; PC429.2 85.5,50.77 PU405.5 ; PC429.2 PR427.2
1.8V_DDR_PWROK: length 51.1
  TOP w0.109: v7(222.18,37.75) 221.93,37.5 PR434.2 ; R934.2 211.64,59.61 v1(211.42,59.83) ; v1(232.08,48.38) 231.3,47.6 230.26,47.6 229.86,47.2 v2(229.86,45.47) 229.59,45.19 229.59,42.27 229.93,41.93 229.93,40.83 229.47,40.37 229.47,39.7 229.95,39.21 v7(229.95,36.3)
  IN1 w0.076: v7(229.95,36.3) 229.72,36.53 228.48,36.53 227.82,37.19 222.74,37.19 v7(222.18,37.75)
  IN2 w0.102: v1(211.42,59.83) 212.22,59.03 216.81,59.03 218.65,57.18 222.22,57.18 226.19,53.22 227.27,53.22 229.22,51.27 231.2,51.27 232.08,50.38 v1(232.08,48.38)
3VA_EN: length 14
  TOP w0.109: 203.35,36.81 D302.1 201.92,38.59 D306.1 198.81,35.48 D305.1 v2(196.99,33.4) 195.57,33.4 PR344.1 194.19,32.49 D301.1
3VALW_PG: length 28.4
  TOP w0.109: v1(193.73,33.82) 193.38,33.82 192.81,34.38 PU301.7
  BOTTOM w0.109: v1(193.73,33.82) 193.64,33.82 193.13,34.32 PR348.2 192.86,32.39 192.31,31.85 190.83,31.85 190.49,31.5 188.69,31.5 187.7,32.49 187.7,33.2 187.53,33.38 179.09,33.38 178.83,33.64 v2(175.96,33.64) RH309.1
5VA_EN: length 54.3
  TOP w0.109: D307.2 187.5,29.71 187.5,31.22 186.81,31.91 186.81,32.49 186.51,32.8 186.26,32.8 v1(186.11,32.95)
  IN1 w0.076: v3(205.57,55.05) 205.57,54.79 205.25,54.47 204.82,54.47 203.7,53.35 201.72,53.35 200.11,51.74 v3(199.69,51.74)
  IN3 w0.102: v1(186.11,32.95) 186.16,33.01 186.16,35.78 185.43,36.52 182.31,36.52 179.16,39.66 179.16,43.56 180.7,45.1 188.96,45.1 191.52,47.66 194.68,47.66 196.21,49.18 198.98,49.18 199.69,49.89 v3(199.69,51.74)
  IN4 w0.076: v4(205.89,55.3) 205.83,55.3 v3(205.57,55.05)
  BOTTOM w0.076: 207.11,55.2 206.32,55.2 206.24,55.28 205.91,55.28 v4(205.89,55.3)
  BOTTOM w0.109: v1(186.11,32.95) 186.52,32.95 v2(186.63,32.84)
  BOTTOM w0.254: U34.B2 207.11,55.2
+0.6VSP: length 1.9
  BOTTOM w0.102: v2(92.78,37.78) 93.2,37.36 PC607.1
+0.675VS: length 3.2
  TOP w0.508: 123.87,16.65 123.88,16.65 124.56,15.97 RD37.2 124.56,15.14 124.6,15.1 RD29.2 ; RD88.2 RD61.2
  vias: v5(113.86,12.73) v6(99.38,38.41) v6(99.38,37.75) v6(102.2,29.37) v6(102.69,29.8)
+1.2V_B+: length 29.1
  TOP w0.254: 85.5,36.66 85.5,37.35 87.74,39.58 92.28,39.58 92.64,39.23 99.8,39.23 104.76,34.27 v1(105.28,34.27)
  BOTTOM w0.254: v1(105.28,34.27) 104.59,33.59 104.59,32.29 103.65,31.35 PR611.1
  vias: v2(84.79,36.58) v6(83.75,35.67) v6(83.74,35.03) v6(84.38,35.67) v6(84.38,35.03) v6(85.02,35.67) v6(85.02,35.03) v6(85.65,35.67) v6(85.65,35.03)
+1.2V_FB: length 6.4
  BOTTOM w0.102: PR608.1 v2(102.76,37.07)
  BOTTOM w0.203: PR610.1 100.34,34.91 99.79,35.45 99.09,35.45 98.77,35.14 PU601.6
  BOTTOM w0.508: PR610.1 100.77,35.07 101.68,35.99 PC614.1 PR608.1
+1.2V_TON: length 4.2
  BOTTOM w0.203: PU601.9 98.81,33.94
  BOTTOM w0.254: PR611.2 100.37,31.35 v2(99.87,31.86) 99.87,32.77 99.42,33.22 99.42,33.41 98.89,33.94 98.81,33.94
+1.2VS_DVDD: length 59.2
  TOP w0.203: UA1.25 34.43,13.84 34.22,13.63 CA5.1
  TOP w0.254: CA6.1 34.55,5.91 34.55,6.52 34.99,6.97 35.61,6.97 35.91,7.27 UA1.37 ; UA1.1 42.14,8.34 42.53,7.96 42.53,7.22 42.22,6.91 CA4.1 ; UA1.15 40.41,15.61 v1(40.75,15.95)
  TOP w0.508: CA5.1 33.66,14.76 CA2.1 32.76,15.65 31.65,15.65 31.45,15.45 31.45,11.06 v2(33.07,9.43) v1(33.07,7.54) CA3.1 33.32,5.58 CA6.1 ; CA4.1 43.48,6.09 CA1.1 43.49,6.36 43.08,6.77 43.07,6.77 v1(43.07,6.77)
  IN3 w0.508: v1(40.75,15.95) 41.43,15.26 41.43,14.37 42.26,13.55 43.48,13.55 44.06,12.96 44.06,11.51 v1(44.39,11.18)
  BOTTOM w0.508: v1(33.07,7.54) 34.3,7.54 35.65,6.18 35.65,5.72 37.99,3.39 40.25,3.39 43.07,6.2 v1(43.07,6.77) 43.31,6.77 44.39,7.86 v1(44.39,11.18) 45.13,11.92 46.25,11.92 CA18.1 47.03,13.56 CA20.1 CA19.1 46.28,15.02 LA1.1
+1.05VA: length 88.3
  IN1 w0.508: v3(135.15,46.49) 134.41,46.49 133.55,45.63 131.13,45.63 129.69,47.07 129.08,47.07 128.49,47.66 128.49,47.68 127.15,49.03 v3(126.59,49.03)
  IN2 w0.508: v3(135.15,46.49) 135.15,46.67 135.58,47.1 137.2,47.1 137.92,47.81 138.98,47.81 139.57,47.23 141.42,47.23 141.83,47.63 146.86,47.63 147.16,47.33 149.95,47.33 150.46,47.84 150.46,48.45 151.81,49.79 153.08,49.79 153.54,49.34 154.6,49.34 154.97,49.7 v1(156.57,49.7)
  IN2 w0.889: 181.41,59.88 181.24,60.05 v6(177.02,60.05) 177.02,59.66 174.58,57.22 167.68,57.22 166.17,55.71
  IN4 w0.254: v4(155.37,48.02) 155.37,48.35 156.57,49.55 v1(156.57,49.7)
  IN4 w0.508: v4(120.49,46.14) 121.37,47.01 121.37,47.34 122.65,48.62 124.71,48.62 125.37,47.96 126.13,47.96 126.64,48.47 126.64,48.98 v3(126.59,49.03)
  BOTTOM w0.254: UCPU1.AG13 v4(155.37,48.02) ; v1(156.57,49.7) 156.94,49.33 UCPU1.AE9 UCPU1.AF9 158.43,48.35 UCPU1.AG8 ; RH406.2 179.32,57.77 178.05,59.04 177.36,59.04 177.02,59.38 v6(177.02,60.05) 177.02,60.32 176.75,60.59 176.22,60.59 175.86,60.23 175.86,59.9 173.63,57.67 172.99,57.67 171.87,56.55 170.54,56.55 170.06,57.03 CH1239.1 169.09,57.26 CH1214.1 168.27,58.09 RH405.1
  BOTTOM w0.508: RH375.1 118.43,47.94 RH38.1 119.32,48.8 RH40.1 RH39.1 RH445.1 119.37,46.54 119.78,46.14 v4(120.49,46.14)
  vias: v1(164.15,54.47) v5(186.12,59.86) v6(184.17,61.69) v6(184.75,62.02) v6(184.75,61.39) v6(184.84,60.75) v6(184.84,60.12) v6(184.84,59.48) v6(184.84,58.85) v6(185.39,62.02) v6(185.39,61.39) v6(185.48,60.75) v6(185.48,60.12) v6(185.48,59.48)
+1.05VDX_MODPHY: length 0.7
  BOTTOM w0.508: v1(177.82,63.36) 177.79,63.33 R300.1
  vias: v2(179.44,62.59)
+1.05VDX_MODPHY_D: length 3.1
  BOTTOM w0.109: R300.2 v2(176.24,64.45)
  BOTTOM w0.508: Q39.1 177.03,62.11 176.24,62.9 R300.2
+1.5VS: length 373.4
  TOP w0.254: v1(207.26,68.92) 207.26,69.13 206.55,69.85 200.49,69.85 198.93,68.28 198.93,67.27 198.29,66.63 194.54,66.63 194.07,66.16 v7(194.07,66.15) ; R296.1 v1(257.74,50.25)
  TOP w0.508: 48.75,10.79 48.75,9.39 R1305.1
  IN1 w0.254: v7(194.07,66.15) v3(193.39,66.84) ; v3(233.62,67.8) 233.24,67.42 233.24,59.32 232.96,59.04 232.96,55.76 233.77,54.95 235.65,54.95 241.06,49.54 257.03,49.54 v1(257.74,50.25)
  IN2 w0.254: v3(193.39,66.84) 193.29,66.73 192.7,66.73 191.8,67.64 190.56,67.64 190.39,67.47 181.68,67.47 180.44,68.71 176.02,68.71 175.71,68.4 175.71,68.04 175.14,67.47 174.71,67.47 174.45,67.22 172.99,67.22 172.21,68 171.33,68 170.55,67.23 170.12,67.23 169.32,68.03 168.78,68.03 168.24,67.5 167.07,67.5 166.54,66.96 164.26,66.96 163.9,66.61 159.05,66.61 158.59,67.06 158.16,67.06 157.73,66.63 157.73,65.31 157.04,64.63 v3(157.04,57.64) ; v1(207.26,68.92) 207.83,69.49 210.18,69.49 210.7,68.97 215.13,68.97 217.96,66.14 221.75,66.14 223.41,67.8 v3(233.62,67.8)
  IN2 w0.508: v3(126.16,70.82) 126.1,70.77 126.1,67.6 127.09,66.61 127.09,63.2 128.29,62.01 149.83,62.01 153.38,58.45 153.38,57.26 v3(153.21,57.08)
  IN2 w0.762: v6(88.78,55.86) v6(88.78,56.52)
  IN3 w0.508: v6(88.78,56.52) 88.78,58.19 90.44,59.85 90.44,60.79 91.23,61.58 91.23,64.6 92.3,65.67 97.73,65.67 99.6,63.8 102.33,63.8 104.77,66.24 106.48,66.24 108.86,68.61 117.62,68.61 118.13,69.12 121.51,69.12 123.21,70.82 v3(126.16,70.82) ; v3(153.21,57.08) 155.62,57.08 156.08,57.54 156.94,57.54 v3(157.04,57.64)
  IN3 w0.635: v1(25.22,32.27) 25.24,32.24 25.62,32.24 26.63,31.24 27.7,31.24 28.19,30.76 28.19,29.42 28.56,29.05 31.24,29.05 33.71,26.58 33.71,25.37 34.23,24.85 34.23,24.01 34.09,23.87 34.09,22.09 34.51,21.67 35.78,21.67 40.76,16.7 41.5,16.7 45.59,12.61 47.14,12.61 47.39,12.35
  IN3 w0.762: 72.46,15.48 v6(72.14,15.79)
  IN4 w0.254: v3(157.04,57.64) 157.04,57.72 156.89,57.56 155.17,57.56 v4(155.14,57.59)
  IN4 w0.508: v1(25.47,39.56) 26.1,40.19 30.12,40.19 v1(30.85,39.45)
  IN4 w1.016: 87.98,55.38 85.54,52.94 85.54,50.96 84.91,50.33 84.91,47.34 88.01,44.23 88.01,38.86 89.33,37.55 92.4,37.55 93.11,36.84 93.11,34.81 92.47,34.17 92.47,32.65 93.62,31.5 93.62,30.49 91.79,28.66 91.79,25.18 89.58,22.97 89.58,19.16 88.28,17.86 86.3,17.86 83.71,15.27 83.71,13.39 82.37,12.05 77.14,12.05 74.62,14.57 74.62,14.61 73.55,14.61 72.92,15.25
  BOTTOM w0.203: CV43.1 26.1,39.91 26.1,38.91 26.39,38.62 U722.31 ; CV42.1 30.24,39.96 30.24,38.82 30,38.57 U722.40 ; CV32.1 29.36,31.86 29.36,32.22 29.56,32.42 29.56,32.85 29.6,32.89 U722.12
  BOTTOM w0.381: CV32.1 29.89,31.78 v1(30.31,31.78)
  BOTTOM w0.508: v1(25.47,39.56) 25.95,40.04 CV43.1 ; v1(25.22,32.27) CV31.1 ; CV42.1 30.27,40.04 v1(30.85,39.45)
  BOTTOM w0.762: 48.94,12.15 49.07,12.15 49.35,12.43 49.35,13.01 49.73,13.39 53.13,13.39 54.73,11.79 70.98,11.79 72.21,13.02 72.21,15.22 72.08,15.35
  vias: v1(48.01,11.82) v1(48.38,11.36) v1(71.44,15.79) v5(48.55,12.45)
+1.05VS: length 96.8
  TOP w0.508: CH39.1 157.53,54.03 157.52,54.04 v1(157.52,54.06) ; v1(154.15,47.69) 154.15,48.51 154.36,48.73 154.36,49.51 RH340.1 154.27,49.6 CH1215.1 ; CH1233.1 151.38,48.24 v1(151.33,48.19) ; v1(161.89,68.36) 161.89,67.34 ; CH1235.1 v1(153.7,53.5) ; LH12.1 143.62,68.6 144.01,68.21 v1(144.01,67.83)
  IN1 w0.508: v1(161.89,68.36) 161.87,68.39 158.87,68.39 157.35,69.91 145.71,69.91 144.01,68.21 v1(144.01,67.83)
  IN3 w0.508: v1(116.44,70.01) 116.91,70.48 121.39,70.48 122.7,71.79 135.98,71.79 136.95,70.82 136.95,70.01 137.43,69.53 138.02,69.53 138.83,68.72 143.22,68.72 144.01,67.93 v1(144.01,67.83)
  IN4 w0.254: v3(178.33,49.34) 185.01,49.34 185.22,49.13 187.79,49.13 188.14,49.49 190.02,49.49 190.75,48.76 191.79,48.76 192.33,49.31 193.43,49.31 193.69,49.04 194.46,49.04 v4(195.13,49.72) ; v3(158.92,48.8) v4(158.92,48.42)
  BOTTOM w0.152: v1(156.56,58.1) 156.56,58.23 156.23,58.56 155.47,58.56 155.16,58.24 UCPU1.H15 ; UCPU1.J17 154.19,57.66 154.45,57.92 155.5,57.92 v1(155.58,58)
  BOTTOM w0.254: v1(156.56,58.1) 156.71,58.24 UCPU1.H11 UCPU1.J11 ; v4(195.13,49.72) 195.13,49.7 R297.1 ; v4(158.92,48.42) 158.9,48.45 158.9,48.47 158.87,48.49 UCPU1.AE8 ; UCPU1.AG17 153.81,48.02 154.14,47.69 v1(154.15,47.69) 154.48,48.02 UCPU1.AG16 ; v1(151.33,48.19) 151.04,48.48 UCPU1.AF22 ; UCPU1.N8 158.43,55.08 UCPU1.P9 157.83,55.05 157.5,54.72 157.5,54.14 157.51,54.13 157.52,54.13 v1(157.52,54.06)
  BOTTOM w0.356: v4(151.77,54.58) UCPU1.T21
  BOTTOM w0.508: RH51.1 115.96,63.08 CH1.1 115.98,65.93 115.26,66.66 115.26,68.23 116.44,69.41 v1(116.44,70.01)
  vias: v1(153.71,54.13) v1(157.54,58.6) v3(152.52,54.58) v5(161.08,63.15) v6(180.44,64.07) v6(180.46,63) v6(180.71,65.24) v6(180.79,64.6) v6(180.8,63.54)
+1.5VS_3.3VS_AUDIO: length 215.8
  TOP w0.102: v5(11.97,20.71) 12.71,21.45 v1(13.13,21.45)
  TOP w0.203: U717.9 54.49,10.42 v1(54.72,10.19) 54.54,10.02 U717.8 ; UA2.7 29.95,24.5
  TOP w0.254: v1(43.3,12.64) 43,12.34 UA1.9 ; v1(30.57,24.44) 30.52,24.5 29.95,24.5 ; v1(154.88,46.9) 154.39,46.41 CH85.1
  TOP w0.381: v7(36.46,25.79) 36.44,25.81 35.44,25.81 34.82,25.19 33.64,25.19 33.37,25.46 32.22,25.46 31.68,24.93 CA33.1
  TOP w0.508: v1(30.57,24.44) 31.1,24.44 31.45,24.8 CA33.1
  IN1 w0.508: v1(43.3,12.64) 43.3,15.32 42.39,16.23 42.39,16.52 40.57,18.34 40.57,19.45 39.52,20.51 39.11,20.51 37.23,22.39 37.23,25.02 v7(36.46,25.79)
  IN3 w0.254: v1(154.88,46.9) 153.76,46.9 153.54,47.13 152.37,47.13 152.09,47.4 150.29,47.4 149.78,46.9 148.74,46.9 148.13,47.51 141.7,47.51 141.34,47.15 139.39,47.15 139.16,47.38 133.29,47.38 132.89,46.97 129.05,46.97 128.57,47.46 127.98,47.46 127.43,46.9 127.04,46.9 125.44,45.3 122.07,45.3 121,44.23 121,43.91 109.34,32.25 109.34,21.88 108.63,21.17 108.63,19.57 107.74,18.68 105.17,18.68 100.68,14.18 v3(100.68,13.27)
  IN3 w0.508: v1(30.57,24.44) 29.69,24.44 29.13,25 29.13,25.92 28.29,26.75 28.29,28.33 27.49,29.13 27.49,30.2 27.15,30.54 26.34,30.54 25.68,31.2 20.59,31.2 18.64,29.24 18.64,25.94 16.2,23.5 15.18,23.5 v1(13.13,21.45) ; v1(43.3,12.64) 43.4,12.54 43.4,10.27 44.37,9.31 44.37,7.04 44.75,6.66 48.28,6.66 50.62,9 53.56,9 54.72,10.16 v1(54.72,10.19)
  IN4 w0.254: v4(67.61,8.03) 73.63,8.03 78.06,3.6 89.82,3.6 91.15,4.94 93.57,4.94 93.73,4.77 95.94,4.77 96.26,5.09 99.94,5.09 100.68,5.82 v3(100.68,13.27)
  BOTTOM w0.254: v1(30.57,24.44) 30.6,24.44 30.63,24.47 31.34,24.47 CA43.2 ; UCPU1.AH14 155.31,47.34 v1(154.88,46.9) ; v4(67.61,8.03) 65.45,10.19 v1(54.72,10.19)
  BOTTOM w0.508: RA75.1 13.13,20.54 v1(13.13,21.45) ; v1(43.3,12.64) 42.67,12.01 CA22.1
+1.05VS_B+:
  vias: v2(193.01,57.72) v6(193.58,58.38) v6(194.21,58.38) v6(194.85,58.38) v6(195.48,58.38)
+1.5VS_D: length 2.4
  TOP w0.102: v2(256.77,51.21) 257.08,51.21 R296.2
  TOP w0.508: Q34.1 R296.2
+1.5VS_FSW: length 4
  TOP w0.109: PR422.2 85.36,49.02 84.99,48.65 84.12,48.65 83.81,48.95 v2(83.46,48.95)
  TOP w0.254: PR422.2 85.48,49.13 86.12,49.77 PU405.7
+1.05VS_VCCST: length 53.5
  TOP w0.508: PR736.1 96.64,55.39 96.37,55.13 PR737.1 96.32,54.9 PR735.1 94.49,54.9 PC721.1 94.06,55.74 v1(94.65,55.74) ; v1(116.35,54.59) 115.98,54.22 v2(115.98,53.65) 115.98,52.97 117.2,51.75 117.2,51.16 R1132.1
  IN2 w0.508: v1(116.35,54.59) 116.12,54.59 114.66,56.05 102.75,56.05 102.43,56.37 100.83,56.37 100.5,56.04 100.5,55.53 100.07,55.1 98.93,55.1 98.29,55.74 v1(94.65,55.74) ; v1(116.23,60.15) 117.06,60.15 v1(118.42,58.78) 118.41,58.78 117.93,58.3 117.93,55.66 118.48,55.1 v1(118.76,55.1)
  BOTTOM w0.381: R1211.1 115.67,58.89 115.67,59.87 115.95,60.15 v1(116.23,60.15)
  BOTTOM w0.508: RC95.1 120.64,55 RC93.2 119.98,54.8 119.98,54.98 119.76,55.2 118.87,55.2 v1(118.76,55.1) 117.09,55.1 116.58,54.59 v1(116.35,54.59) ; RC46.2 RC48.2 RC45.2 118.45,58.81 v1(118.42,58.78) 118.42,59.13 RC149.2 117.75,59.16 R1179.1 RC43.2
  vias: v1(149.62,49.77) v1(149.65,49.16)
+1.05VS_XDP: length 9.2
  TOP w0.254: v1(114.88,64.63) 114.57,64.93 JXDP.43 JXDP.44
  BOTTOM w0.102: v1(114.88,64.63) 114.88,64.83 v2(115.33,65.29)
  BOTTOM w0.508: v1(114.88,64.63) 115.07,64.44 RH51.2
+1.5VSP: length 18.4
  TOP w0.203: PC429.1 v6(83.74,50.91)
  TOP w0.254: v1(90.68,49.87) 90.58,49.77 PU405.14
  TOP w0.508: PR422.1 PR427.1 v1(83.78,50.02)
  IN2 w0.508: v1(90.68,49.87) 90.48,50.07 90.48,54.22 89.62,55.08 88.15,55.08 86.71,56.52 v1(86.71,56.52)
  IN4 w0.203: v6(83.74,50.91) 83.91,50.91 84.63,51.62 84.63,53.48 86.61,55.46 86.61,55.63 v1(86.66,55.69)
  vias: v2(87.24,58.35)
+1.05VSP: length 22.9
  TOP w0.102: v1(187.43,59.63) v2(188.04,59.63)
  TOP w0.203: PU501.22 v7(197.62,58.66)
  IN1 w0.203: v7(197.62,58.66) 197.55,58.73 197.02,58.73 v3(197,58.76) 196.64,59.11 193.66,59.11 193.22,59.55 189.57,59.55 189.07,60.04 187.84,60.04 v1(187.43,59.63)
  IN3 w0.203: v3(197,58.76) 197,58.35 196.54,57.89 189.35,57.89 188.26,58.99 v1(187.43,58.99)
+1.5VSP_LX:
  vias: v2(88.4,53.4) v6(88.97,53.2) v6(89.73,53.2)
+1.5VSP_VIN:
  vias: v2(88.47,46.8) v6(87.13,47.48) v6(87.13,46.85)
+1.8VP: length 22.5
  TOP w0.254: PU406.14 224.35,41.37 224.03,41.69 223.21,41.69 222.5,40.98 220.61,40.98 220.06,40.43 218.92,40.43 v5(218.2,39.71) 217.01,38.53 v1(217.01,38.46) 217.15,38.32 217.15,35.91 217.53,35.53 PC440.1 PR433.1 PR437.1
  BOTTOM w0.254: v1(217.01,38.46) 217.06,38.51 217.72,38.51 218,38.24 218,37.32
+1.8VS: length 224.4
  TOP w0.254: v7(220.83,55.1) C1284.1 220.31,54.59 U679.C1 ; R1361.1 217.15,61.12 217.53,61.5 218.27,61.5 218.8,62.04 218.8,62.47 R1360.1
  TOP w0.305: U671.1 232.16,60.84 C1286.1
  TOP w0.381: U677.1 226.2,63.19 225.89,63.49 v1(225.62,63.49) C1288.1 223.85,63.49 223.03,62.67 221.51,62.67 v5(220.92,63.25) 219.28,63.25 218.93,62.9 R1360.1 ; RH350.2 187.71,68.87 v1(187.66,68.82)
  TOP w0.508: v7(224.77,54.59) R1371.1 R1368.1 R1369.1 ; v1(232.01,60.16) 232.01,60.68 232.14,60.8 C1286.1 ; R1188.2 v1(234.58,69.71) ; R1204.2 v1(228.61,69.71)
  IN1 w0.254: v7(217.15,55.48) 217.72,54.91 220.64,54.91 v7(220.83,55.1) 220.83,55.48 221.9,56.55 223.13,56.55 224.77,54.91 v7(224.77,54.59)
  IN1 w0.508: v1(232.01,60.16) 232.01,67.23 234.49,69.71 v1(234.58,69.71)
  IN2 w0.254: v3(241.34,38.87) 240.46,37.98 229.65,37.98 227.89,36.23 225.39,36.23 224.94,35.77 215.26,35.77 214.34,36.69 212.05,36.69 211.72,37.02 v1(211.31,37.02) 210.2,35.91 204.3,35.91 200.48,32.09 200.48,27.99 197.17,24.68 v1(195.71,24.68)
  IN2 w0.508: v1(225.62,63.49) 226.04,63.08 226.64,63.08 229.56,60.16 v1(232.01,60.16) 232.01,55.6 233.5,54.11 v3(234.46,54.11)
  IN3 w0.254: v1(228.61,69.71) 228.39,69.71 225.94,67.25 222.84,67.25 221.38,65.79 218.71,65.79 216.35,68.16 v1(216.35,69.99)
  IN3 w0.508: v1(228.61,69.71) 228.85,69.71 229.63,68.92 233.14,68.92 233.93,69.71 v1(234.58,69.71)
  IN4 w0.508: v3(241.34,38.87) 241.06,39.15 241.06,41 238.96,43.11 238.96,45.41 238.42,45.94 238.42,49.2 236.52,51.1 236.52,52.15 234.74,53.93 234.64,53.93 v3(234.46,54.11)
  BOTTOM w0.254: v1(195.71,24.68) 195.23,24.68 194.51,23.96 194.51,13.72 194,13.21 194,11.77 193.23,11 193.23,8.66 189.73,5.16 178.44,5.16 176.73,6.88 176.73,8.69 177.65,9.61 JTP1.1 ; v1(216.35,69.99) 216.07,69.71 202.1,69.71 199.36,66.96 194.79,66.96 192.93,68.82 190.82,68.82 189.58,70.06 188.23,70.06 187.62,69.45 187.62,68.86 v1(187.66,68.82)
+1.8VSP_LX:
  vias: v1(220.9,39.56) v1(221.3,40.01) v2(220.74,40.17)
+1.35V_DDR: length 230.7
  TOP w0.254: RD13.1 118.42,48.01 117.91,47.51 RD18.1
  TOP w0.381: v7(130.24,48.38) 130.03,48.6 120.17,48.6 119.69,48.12 RD13.1 ; v1(143.26,20.31) 143.26,20.31 143.29,20.34 143.29,20.83 CD37.1 ; v1(127.92,33.2) 127.92,33.46 127.34,34.04 123.55,34.04 115.14,42.45 115.14,42.96 114.86,43.24 114.86,44.08 114.04,44.9 113.1,44.9 112.5,45.5 RD17.1
  TOP w0.457: 138.67,18.07 138.67,16.8 138.17,16.3 CD39.1
  TOP w0.508: v1(184.06,24.32) 183.97,24.42 CD83.1 ; v1(179.75,17.12) 179.76,17.11 179.76,15.68 178.8,14.71 CD87.1 ; v1(166.69,17.11) 166.64,17.16 166.64,17.29 166.11,17.82 CD63.1 165.88,17.87 164.98,18.77 CD64.1 ; v1(154.29,20.33) 154.24,20.28 CD111.1 ; CD61.1 166.61,27.57 v1(165.88,27.57) ; CD82.1 177.43,26.14 CD81.1 178.36,25.33 v1(178.95,25.92) ; v1(191.32,25.1) 191.4,25.18 191.8,25.18 CD85.1 ; v1(119.43,22.72) 119.45,22.74 CD18.1 CD17.1 119.45,25.53 119.11,25.87 118.68,25.87 v1(118.62,25.92) ; CD38.1 136.23,23.1 v1(136.72,23.59) ; CD19.1 120.28,26.78 119.35,27.7 v1(118.61,27.7) ; v1(100.54,25.18) 100.4,25.32 CD114.1 ; CD21.1 119.03,17.67 119.24,17.45 119.24,17.26 v1(119.45,17.06) ; v1(107.05,27.62) 107.06,27.62 107.96,27.62 108.71,26.87 CD14.1 ; CD118.1 147,26.96 147.54,27.5 v1(147.84,27.5) ; CD15.1 107.13,25.86 v1(107.06,25.92) ; v1(147.84,24.26) 147.19,24.26 146.01,23.08 CD116.1 ; v1(136.79,25.19) 136.49,24.88 CD120.1 ; v1(165.84,25.92) 166.07,26.15 CD62.1 ; CD84.1 191.75,26.27 191.42,25.94 190.52,25.94 v1(190.5,25.92) ; CD123.1 185.24,26.48 CD125.1 185.22,26.53 184.41,27.34 v1(183.99,27.34) ; CD126.1 173.29,25.07 v1(172.47,25.89) ; CD115.1 100.28,23.74 v1(100.54,23.48) ; v1(143.26,16.32) 143.28,16.3 CD44.1 ; RD73.2 CD16.1 107.13,20.27 v1(107.07,20.33) 107.07,21.94 v1(107.07,21.94) ; CD43.1 137.98,15.2 v1(137.65,15.53) 137.73,15.61 CD39.1 ; CD122.1 136.01,26.95 136.56,27.5 v1(136.79,27.5) ; CD112.1 111.67,24.06 v1(112.11,24.5) 111.89,24.5 111.32,25.07 CD113.1 ; CD119.1 130.98,25.57 131.33,25.92 v1(131.7,25.92) 131.79,26.01 133.24,26.01 CD121.1 ; v1(191.3,17.12) 191.3,16.72 191.63,16.39 192.49,16.39 193.02,16.92 CD86.1 194.49,16.18 CD88.1 ; v1(144.06,22.72) 144.08,22.75 CD40.1 ; v1(160.26,15.53) 160.45,15.73 CD65.1 160.45,16.87 161.03,17.44 161.03,19.34 160.26,20.11 v1(160.26,20.32) ; v1(172.44,24.47) 171.93,24.99 CD124.1 ; v1(190.49,20.32) 190.49,20.12 190.99,19.62 191.5,19.62 192.16,18.96 RD74.2 ; v1(155.11,25.92) 155.46,25.56 CD60.1 ; CD42.1 144.06,17.79 v1(144.06,17.12)
  IN1 w0.381: v7(130.24,48.38) 130.61,48.75 131.79,48.75 132.91,47.63 134.77,47.63 v7(135.27,48.14)
  IN4 w0.508: v1(121.55,28.61) 122.47,29.54 v1(122.47,30.74)
  BOTTOM w0.102: 125.29,24.32 v1(125.29,24.35)
  BOTTOM w0.178: UCPU1.AN33 143.36,44.97 143.3,44.97 v1(143.27,44.95)
  BOTTOM w0.203: UCPU1.AY35 142.61,40.05 142.58,40.02 142.58,39.7 143.02,39.26 143.02,39.26 v1(143.04,39.24) ; UD1.K8 101.86,19.82 102.26,19.42 102.26,18.73 v1(102.24,18.72) ; UCPU1.AY40 139.46,40.06 139.42,40.02 139.42,39.65 139.86,39.21 v1(139.86,39.18)
  BOTTOM w0.254: v1(117.81,26.71) 118.19,26.33 118.21,26.33 UD2.B2 ; UD7.C9 UD7.D9 UD7.E9 159.62,23.92 v1(159.16,24.39) ; UCPU1.AP43 137.25,43.63 137.1,43.63 v1(137.07,43.61) ; UD1.C9 100.88,25.52 v1(100.54,25.18) ; v1(148.71,17.13) 148.71,17.16 148.3,17.57 UD6.N9 ; v1(173.35,20.35) 173.35,20.31 173.35,20.31 173.35,20.28 173.71,19.92 UD9.K8 ; UD1.K2 106.66,19.97 107.02,20.33 v1(107.07,20.33) ; UD7.N9 159.86,17.54 v1(159.43,17.96) ; UD4.G7 127.3,22.33 126.9,22.72 v1(126.9,22.73) ; UD10.K8 185.29,19.92 v1(184.9,20.31) ; v1(125.18,21.94) 125.18,21.93 125.28,21.93 UD4.H9 ; v1(136.79,25.19) 137.13,25.52 UD5.C9 ; v1(102.24,22.72) 102.64,22.32 UD1.G7 ; UD6.D9 148.3,24.72 v1(147.84,24.26) 148.18,23.92 UD6.E9 ; v1(133.49,39.79) 133.46,39.79 133.16,40.1 UCPU1.AY50 ; UD10.R1 190.94,15.92 ; v1(143.25,21.91) 142.86,21.52 UD5.H2 ; UD10.H2 190.08,21.54 190.08,21.54 v1(189.69,21.15) ; UD2.A8 113.41,27.15 113.01,27.55 112.21,27.55 112.12,27.46 v1(112.12,27.42) ; v1(149.48,22.72) 149.88,22.32 UD6.G7 ; v1(154.29,20.33) 154.31,20.33 UD6.K2 ; v1(118.61,20.34) 118.21,19.95 UD2.K2 ; v1(131.69,27.62) 132.09,27.22 UD4.A1 ; v1(136.72,23.59) 136.94,23.59 137.25,23.91 UD5.E9 ; v1(148.69,20.32) 149.09,19.92 UD6.K8 ; UD5.D9 137.22,24.72 v1(136.82,24.32) ; v1(147.84,25.2) 147.98,25.2 UD6.C9 ; UD6.A1 154.7,27.12 v1(154.3,26.71) 153.91,26.32 UD6.B2 ; v1(148.43,48.2) 148.43,47.71 UCPU1.AH26 ; v1(137.65,15.53) 137.26,15.92 UD5.R9 ; v1(118.62,25.92) 118.62,25.92 UD2.C1 UD2.D2 ; UD4.H2 v1(131.7,21.93) ; UD2.H9 112.52,21.61 112.52,21.81 112.09,22.24 v1(111.99,22.24) ; v1(184.09,17.94) 184.5,17.53 UD10.N9 ; v1(165.85,21.91) 165.46,21.52 UD7.H2 ; v1(165.85,20.32) 165.83,20.32 165.46,19.95 UD7.K2 ; v1(166.65,22.73) 166.26,23.12 UD7.F1 ; v1(159.44,27.48) 159.48,27.48 159.48,27.47 159.58,27.57 160.24,27.57 160.66,27.15 UD7.A8 ; UD1.N1 107.48,17.52 107.86,17.13 v1(107.86,17.12) 107.95,17.03 107.95,16.3 107.58,15.92 UD1.R1 ; UD9.E9 172.94,23.98 v1(172.44,24.47) ; v1(191.32,22.74) 190.94,23.12 UD10.F1 ; v1(118.61,21.91) 118.22,21.52 UD2.H2 ; v1(135.17,43.68) 134.99,43.68 UCPU1.AR48 ; UD9.R9 172.97,15.92 173.35,15.54 v1(173.35,15.52) ; UD6.A8 149.1,27.15 148.68,27.57 147.92,27.57 v1(147.84,27.5) ; v1(138.43,22.72) 138.83,22.32 UD5.G7 ; UCPU1.AJ33 v1(143.69,48.25) ; UD7.R1 166.37,15.92 166.8,16.36 166.8,17 v1(166.69,17.11) ; UD9.A1 179.34,27.12 v1(178.93,26.71) 178.54,26.32 UD9.B2 ; v1(166.69,17.11) 166.69,17.12 ; v1(166.69,17.11) 166.28,17.52 UD7.N1 ; v1(155.16,23.57) 155.16,23.53 155.15,23.51 155.01,23.51 154.7,23.2 UD6.F1 ; UD10.N1 190.92,17.52 191.3,17.13 v1(191.3,17.12) ; v1(144.06,22.72) 143.66,23.12 UD5.F1 ; v1(161.04,22.72) 161.44,22.32 UD7.G7 ; UD5.B2 142.86,26.32 v1(143.25,26.71) ; v1(184,23.52) 184.4,23.92 UD10.E9 ; UD7.D2 UD7.C1 166.24,25.52 v1(165.84,25.92) 165.46,26.3 UD7.B2 ; UD4.B2 131.3,26.32 v1(131.69,26.71) ; 143.23,20.31 143.26,20.31 143.26,20.31 v1(143.26,20.31) 143.2,20.31 142.85,19.96 UD5.K2 ; UD2.R1 119.45,16.35 v1(119.45,17.06) 119.44,17.06 119.01,17.48 UD2.N1 ; v1(143.26,16.32) 143.65,15.93 UD5.R1 ; v1(136.76,39.76) 136.33,40.19 UCPU1.AY44 ; v1(132.67,23.45) 132.67,23.45 132.62,23.4 132.38,23.4 132.1,23.12 UD4.F1 ; v1(143.25,27.62) 143.65,27.22 UD5.A1 ; v1(183.89,22.13) 184.48,21.55 184.48,21.51 184.49,21.52 UD10.H9 ; UD9.D9 172.94,24.74 172.77,24.91 172.77,25.36 UD9.C9 172.9,25.56 172.8,25.56 v1(172.47,25.89) ; UD2.C9 112.49,25.52 v1(112.16,25.19) 112.61,24.73 UD2.D9 ; UD9.H9 172.93,21.52 172.87,21.52 172.47,21.12 v1(172.47,21.05) ; v1(160.26,15.53) 160.24,15.56 160.23,15.56 159.86,15.92 UD7.R9 ; UD1.N9 101.06,17.54 101.45,17.15 v1(101.45,17.12) ; v1(113.02,20.33) 113.41,19.94 UD2.K8 ; v1(107.05,26.71) 106.66,26.32 UD1.B2 ; v1(144.06,17.12) 144.06,17.13 143.67,17.52 UD5.N1 ; UD10.D9 184.46,24.72 v1(184.06,24.32) ; v1(178.95,25.92) 178.95,25.92 UD9.C1 UD9.D2 ; UD10.D2 UD10.C1 190.5,25.92 v1(190.5,25.92) ; v1(125.29,25.14) 125.68,25.52 UD4.C9 ; v1(100.61,21.12) 101.01,21.52 UD1.H9 ; v1(131.7,25.92) 131.7,25.92 UD4.C1 UD4.D2 ; v1(126.11,20.32) 126.11,20.32 126.11,20.31 126.5,19.93 UD4.K8 ; UD6.H9 148.26,21.52 v1(147.86,21.12) ; UD1.H2 106.67,21.53 106.67,21.54 v1(107.07,21.94) ; UD9.N1 179.36,17.52 179.75,17.13 v1(179.75,17.12) 179.88,16.99 179.88,16.34 179.46,15.92 UD9.R1 ; UD9.F1 179.81,23.12 v1(180.27,23.58) ; v1(118.61,27.7) 119.01,27.29 UD2.A1 ; v1(131.69,20.32) 131.68,20.32 131.3,19.93 UD4.K2 ; UD2.R9 112.61,15.9 113,15.52 v1(113.01,15.52) ; v1(184.9,15.52) 184.9,15.55 184.6,15.85 184.57,15.85 UD10.R9 ; UD6.H2 153.91,21.52 v1(154.31,21.92) ; UD2.G7 114.26,22.32 114.53,22.59 114.71,22.59 v1(114.76,22.65) ; v1(107.06,23.51) 107.46,23.12 UD1.F1 ; UD10.B2 190.1,26.34 v1(190.46,26.71) ; UD10.G7 186.24,22.32 v1(186.64,22.72) ; UD4.A8 126.07,27.55 125.4,27.55 v1(125.17,27.32) ; v1(137.65,20.33) 138.05,19.93 UD5.K8 ; UD10.C9 184.37,25.52 v1(184.04,25.19) ; UD6.N1 154.71,17.52 155.1,17.13 v1(155.1,17.12) 155.2,17.02 155.2,16.3 154.82,15.92 UD6.R1 ; UD1.R9 101.07,15.92 v1(101.47,16.32) ; UD9.G7 174.56,22.32 v1(175.06,22.82) ; v1(159.31,22.37) 159.31,22.07 159.86,21.52 UD7.H9 ; v1(112.11,24.5) 112.11,24.49 112.61,23.98 UD2.E9 ; UCPU1.AJ37 v1(141.09,48.05) ; v1(100.54,23.48) 100.54,23.48 100.98,23.92 UD1.E9 ; v1(155.11,25.92) 155.09,25.92 UD6.C1 UD6.D2 ; v1(125.28,17.9) 125.65,17.52 UD4.N9 ; UD9.N9 172.94,17.59 172.61,17.92 172.58,17.92 172.55,17.94 v1(172.55,17.92) ; v1(136.86,17.92) 137.25,17.53 UD5.N9 ; UD1.D9 100.94,24.72 v1(100.54,24.32) ; UD2.N9 112.6,17.52 v1(112.21,17.91) ; v1(136.79,27.5) 136.87,27.57 137.63,27.57 138.05,27.15 UD5.A8 ; v1(101.34,27.9) 101.34,27.72 101.3,27.68 UD1.A8 ; v1(136.73,22.14) 136.73,22.06 137.25,21.54 UD5.H9 ; v1(143.26,25.92) 143.26,25.92 UD5.C1 UD5.D2 ; UD4.R1 132.22,15.92 132.59,16.3 132.59,17.03 v1(132.5,17.12) 132.5,17.13 132.11,17.52 UD4.N1 ; UD1.D2 UD1.C1 107.06,25.92 v1(107.06,25.92) ; v1(190.49,20.32) 190.5,20.32 190.11,19.92 UD10.K2 ; UD4.R9 125.7,15.92 v1(126.09,15.53) ; UCPU1.AJ31 v1(144.99,48.22) ; UD1.A1 107.46,27.22 v1(107.05,27.62) ; UD6.R9 148.31,15.92 v1(148.71,16.32) ; UD2.F1 119.02,23.12 119.43,22.71 v1(119.43,22.72) ; UD4.E9 125.7,23.94 v1(125.29,24.35) 125.66,24.72 UD4.D9
  BOTTOM w0.381: v1(122.47,30.74) 122.47,32.09 123.08,32.7 CC240.1 123.88,33.06 UC1.5
  vias: v5(105,17.39) v6(96.67,24.69) v6(97.14,26.02) v6(97.14,25.13) v6(97.14,24.24) v6(97.14,23.35) v6(97.14,22.46)
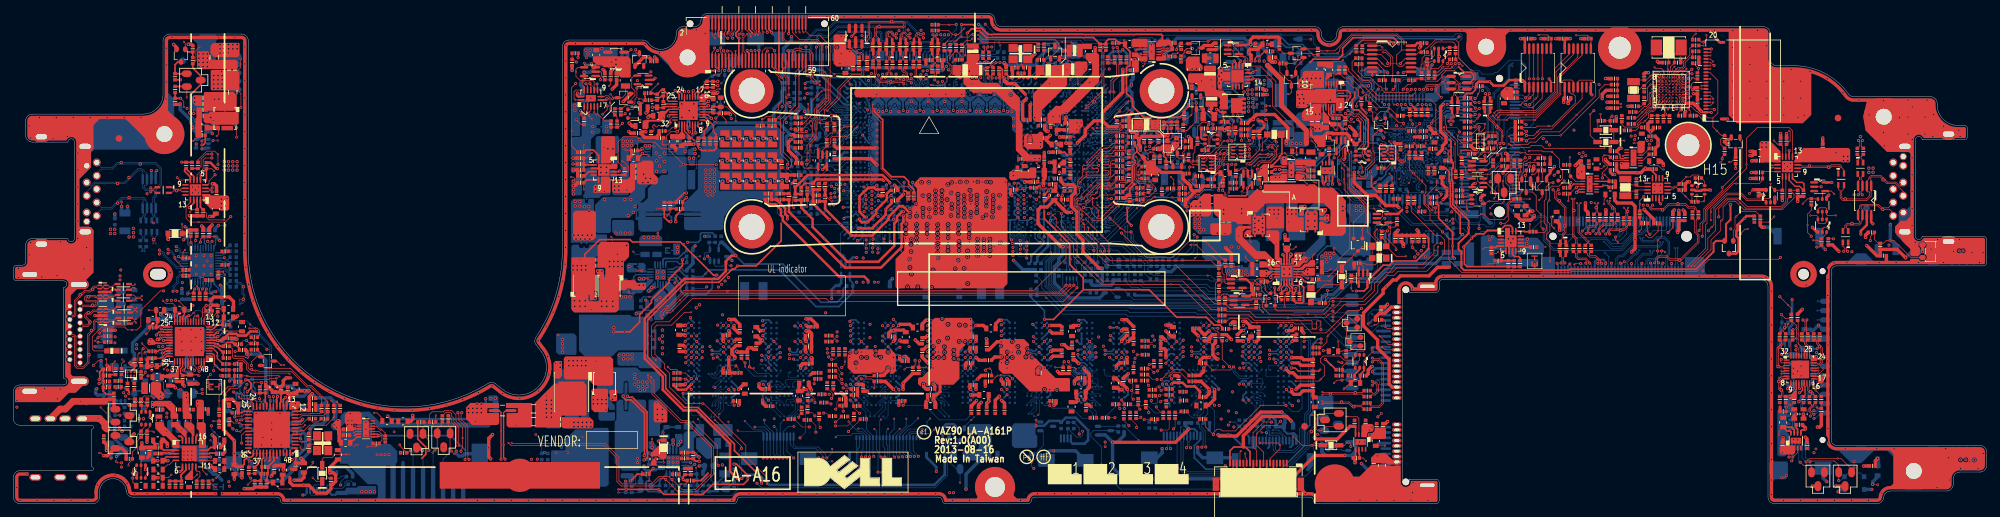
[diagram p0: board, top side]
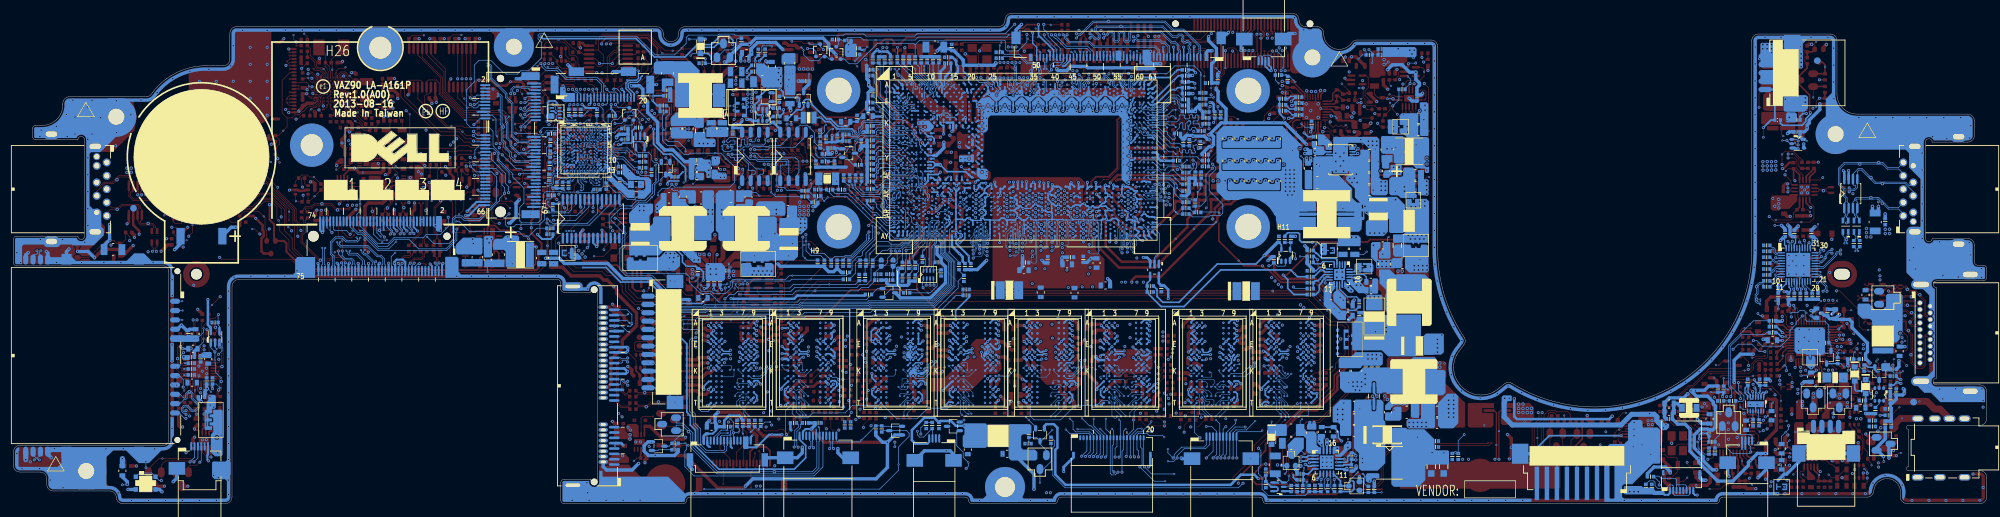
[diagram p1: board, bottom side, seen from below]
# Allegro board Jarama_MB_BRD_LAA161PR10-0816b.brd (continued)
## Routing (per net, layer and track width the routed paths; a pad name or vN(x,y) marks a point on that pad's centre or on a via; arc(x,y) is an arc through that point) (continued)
+1.35VP: length 38.5
  TOP w0.254: v1(100.12,36.56) 100.12,35.66 98.13,33.66 98.13,33.16 95.48,30.51 95.48,30.13 93.72,28.37 93.72,27.22 92.26,25.76 v5(91.46,25.76) v6(89.86,25.76)
  IN1 w0.508: v6(92.14,35.54) 94.81,35.54 95.7,34.65 95.7,33.23 96.21,32.72 96.21,31.96 95.6,31.35 95.6,29.6 92.4,26.4 v6(89.86,26.4)
  BOTTOM w0.203: PU601.5 97.63,36.15 97.77,36.3 99.32,36.3 99.66,35.95 100.54,35.95 PC614.2 PR608.2 100.63,37.07 v1(100.12,36.56)
+3.3V_M: length 70.1
  TOP w0.254: CH47.1 157.31,52.69 157.77,52.23 v7(157.77,52.21) ; R746.2 201.73,59.28 v1(202.44,58.57) ; v1(201.17,57.58) 201.61,57.15 201.61,54.45 201.05,53.89 R1129.2
  TOP w0.381: RH56.1 RH54.1 187.17,56.49 v5(187.17,57) 186.81,57.36 186.44,57.36 v1(186.25,57.55) ; 194.75,54.72 194.21,55.26 v1(194.21,56.19)
  TOP w0.508: R1129.2 199.93,54.81 199.93,55.08 199.55,55.46 197.43,55.46 197.33,55.56 196.6,55.56 196.07,55.02 C1216.1
  IN1 w0.254: v3(158.01,51.9) 157.91,52 157.91,52.07 v7(157.77,52.21)
  IN2 w0.254: v1(201.17,57.58) 202.17,58.57 v1(202.44,58.57)
  IN2 w0.381: v1(194.21,56.19) 193.43,56.97 188.55,56.97 188.16,56.57 186.4,56.57 186.2,56.78 186.2,56.85 ; v3(170.38,55.69) 170.47,55.77 173.03,55.77 173.68,55.13 174.16,55.13 174.68,55.65 175.63,55.65 175.8,55.81 179.85,55.81 180.92,56.88 v3(182.49,56.88) 182.75,56.62 185.97,56.62 186.2,56.85 ; v1(186.25,57.55) 186.25,56.9 186.2,56.85
  IN4 w0.254: v3(158.01,51.9) 158.69,51.9 v4(158.87,51.71)
  IN4 w0.381: v3(182.49,56.88) 182.47,56.9 v4(182.09,56.9) ; v3(170.38,55.69) 170.38,55.43 170.07,55.13 169.06,55.13 168.75,55.43 168.75,55.84 168.34,56.26 167.52,56.26 167.24,55.98 165.72,55.98 164.84,55.1 164.84,54.44 163.85,53.45 161.61,53.45 161.21,53.04 160.11,53.04 159.71,52.64 159.71,52.56 158.87,51.73 v4(158.87,51.71)
  BOTTOM w0.381: v1(186.25,57.55) 186.25,57.29 186.66,56.88 187.45,56.88 187.65,56.68 CH6.1 186.35,56.32 186.24,56.2 U48.8 ; v4(182.09,56.9) 181.83,57.16 CH7.1 181.49,57.07 180.54,56.12 U2.8
+3.3VDX_SSD: length 23.9
  TOP w0.102: v5(202.74,26.97) 203.33,27.57 R1366.1
  TOP w0.508: JSATA1.52 206.18,29.46 205.29,28.57 C720.1 204.48,28.57 203.84,27.94 R1366.1
  IN2 w0.508: v6(203.01,10.33) 202.6,10.33 202.11,10.82 202.11,15.26 205.12,18.26 JSATA1.24
  BOTTOM w0.508: JSATA1.2 207.03,5.55 206.52,5.04 202.72,5.04 v1(201.73,6.03)
  vias: v1(204.12,7.16) v6(203.03,9.7)
+3V_BATMAN: length 17.3
  TOP w0.254: U714.11 245.8,49.28 C1294.1
  TOP w0.508: R1348.1 R1349.1 239.91,49.97 240.27,49.61 v2(243.01,49.61) 243.57,49.61 v1(244.24,50.29) 244.38,50.15 C1294.1 ; v1(250.84,48.24) 250.52,48.24 R1347.2 R1346.2
  IN2 w0.508: v1(250.84,48.24) 250.82,48.22 249.93,48.22 248.14,50.01 244.52,50.01 v1(244.24,50.29)
+3V_D: length 2.4
  TOP w0.508: R298.2 179.66,69.02 179.33,68.69 178.2,68.69 Q5.1
+3V_NFC: length 27.7
  TOP w0.508: v1(189.82,13.72) 186.66,13.72 183.07,10.14 180.49,10.14 v1(180.28,10.35)
  BOTTOM w0.305: 191.55,10.49 190.63,10.49 190.13,10.99 R1242.2 ; 185.82,8.44 184.11,8.44 182.2,10.35 v5(181.76,10.35) v1(180.28,10.35)
  BOTTOM w0.381: C1134.1 188.92,11.59 188.92,12.45 188.18,13.19 186.68,13.19 186.37,12.87 186.37,12.75 R973.1
  BOTTOM w0.508: v1(189.82,13.72) 190.29,13.25 190.29,12.11 190.13,11.95 R1242.2 C1134.1
+3V_PCH: length 332.2
  TOP w0.203: 168.13,52.79 167.57,52.23 167.57,51.75 167.87,51.44 167.87,51.06 167.46,50.64 167.46,48.16 166.02,46.72 RH468.2
  TOP w0.254: RH270.2 167.77,53.73 168.13,53.37 168.13,52.79 168.74,52.18 168.94,52.18 ; JAPS.12 185.06,7.8 184.42,8.44 184.11,8.44 184.05,8.49 182.63,8.49 182.06,7.92 JAPS.18 ; v1(215.65,36.79) 215.38,37.06 v5(215.38,38.65) 215.38,40.71 213.29,42.79 213.29,44.74 R1239.1 ; v1(84.41,61.53) 84.28,61.4 84.28,61.2 84.46,61.02 U663.14 ; v1(166.69,44.31) 166.69,42.34 167.3,41.73 v1(167.3,41.72)
  TOP w0.305: U690.5 184.51,33.65 185.21,32.95 v1(185.47,32.95)
  TOP w0.381: v6(85.41,64.68) 85.42,64.67 U697.5 ; U672.5 121.54,50.52 121.11,50.09 v1(121.11,50.08) ; U691.5 185.05,31.11 185.27,31.34 C1261.1
  TOP w0.508: v1(89.66,65.06) 89.39,64.79 R1324.1 ; C1261.1 185.62,31.66 185.32,31.95 C1262.1 185.32,32.81 v1(185.47,32.95) ; v1(156.56,50.76) 156.97,51.16 CH1220.1 ; 176.71,46.66 176.97,46.91 177.46,46.91 177.93,47.39 RH299.2 RH298.2 ; 176.71,46.66 176.18,47.19 176.18,47.65 175.8,48.03 175.72,48.03 175.04,48.71 RH383.2 174.78,49.67 171.76,49.67 171.47,49.96 RH351.1 ; 176.71,46.66 175.63,45.58 R1312.2 175.39,44.7 175.57,44.52 v1(175.63,44.52) ; v1(158.35,43.67) 157.6,43.67 RH341.1 154.72,44.47 153.76,44.47 153.35,44.05 153.35,41.97 156.78,38.54 v6(157.07,38.54) ; v7(178.75,68.05) 179.9,68.05 R298.1 ; v1(191.17,12.41) 191.19,12.43 190.56,13.06 186.95,13.06 184.05,10.17 184.05,8.49
  IN1 w0.254: v3(170.63,49.13) 170.8,49.13 v7(171.08,49.41)
  IN1 w0.381: v3(178.12,68.11) 178.7,68.11 v7(178.75,68.05)
  IN1 w0.508: v1(121.11,50.08) 122.31,51.28 122.85,51.82 122.85,53.7 123.82,54.67 126.91,54.67 126.91,54.68 128.04,54.68 128.36,55 128.36,56.88 129.36,57.87 136.14,57.87 136.82,58.56 136.82,59.09 137.41,59.67 149.45,59.67 150.34,58.78 150.34,55.05 151.66,53.73 v3(152.16,53.73)
  IN1 w0.635: v3(160.19,61.58) 160.19,60.89 159.86,60.56 159.1,60.56 158.18,59.65 158.18,57.67 157.45,56.93 157.45,54.95 156.69,54.19 156.69,51.75 156.56,51.62 v1(156.56,50.76)
  IN2 w0.254: 157.7,45.78 157.83,45.65 157.83,44.89 158.36,44.36 158.36,44.26 158.57,44.05
  IN2 w0.381: v1(158.35,43.67) 158.08,43.94 157.31,43.94 156.86,44.38 156.86,45.04 157.6,45.78 157.7,45.78
  IN2 w0.508: v3(178.12,68.11) 176.68,66.66 175.14,66.66 174.96,66.47 167.86,66.47 v6(167.73,66.59) ; v1(121.11,50.08) 121,49.97 117.8,49.97 116.43,51.34 116.43,53.37 114.38,55.42 103.59,55.42 102.96,54.8 101.06,54.8 100.58,54.31 98.35,54.31 97.81,54.86 94.14,54.86 92.6,56.4 90.72,56.4 87.8,59.32 86.62,59.32 v1(84.41,61.53) ; v1(156.56,50.76) 156.28,50.76 155.82,50.3 154.88,50.3 154.4,50.78 154.4,52.23 153.97,52.66 153.66,52.66 152.6,53.73 v3(152.16,53.73)
  IN2 w0.635: v1(167.3,41.72) 167.77,42.19 167.77,42.62 170.24,45.08 173.44,45.08 174.1,44.42 174.53,44.42 ; 157.7,45.78 157.7,47.73 157.96,47.99 157.96,49.39 156.84,50.5 156.81,50.5 v1(156.56,50.76) ; v3(160.19,61.58) 162.58,63.97 164.1,63.97 165.27,65.13 165.27,65.44 165.93,66.1 167.24,66.1 v6(167.73,66.59)
  IN4 w0.508: v1(191.17,12.41) 191.17,12.9 193.97,15.7 193.97,25.81 193.59,26.2 193.59,30.03 v4(194.13,30.56) 194.13,31 192.25,32.88 191.36,32.88 191.18,33.05 188.08,33.05 187.36,32.33 185.79,32.33 185.41,32.71 185.41,32.91 185.46,32.95 v1(185.47,32.95)
  BOTTOM w0.254: v4(158.43,51.24) 157.68,51.24 157.25,50.81 157.78,50.29 UCPU1.AC9 ; v1(166.69,44.31) 166.91,44.31 167.53,44.93 RH160.2 ; v1(156.56,50.76) 155.57,49.77 152.8,49.77 152.33,49.29 UCPU1.AE20 151.87,48.89 UCPU1.AE21
  BOTTOM w0.457: RH154.2 174.91,44.93 175.32,44.52 v1(175.63,44.52)
  BOTTOM w0.508: 157.25,50.81 156.61,50.81 v1(156.56,50.76) ; v1(215.65,36.79) 213.61,36.79 212.82,36 206.35,36 204.08,33.73 199.92,33.73 197.52,31.33 196.36,31.33 195.62,30.59 194.2,30.59 194.18,30.56 v4(194.13,30.56) ; R1242.1 191.52,12.06 v1(191.17,12.41) ; Q351.1 162.57,30.84 158.05,30.84 155.8,33.1 155.8,35.52 RH42.1 156.46,36.76 157.07,37.38 157.07,38.53 v6(157.07,38.54) ; RH294.2 171.39,34.65 172.03,35.29 ; RH303.2 172.03,35.29 ; 172.03,35.29 172.54,34.78 173.3,34.78 173.93,35.42 RH72.2 RH70.2 180.56,35.59 v4(180.92,35.95) ; 170.68,50.45 RH274.1 RH295.2 ; v1(84.41,61.53) 84.66,61.27 CH1236.1 85.24,62.37 84.88,62.72 84.88,63.05 85.41,63.58 v6(85.41,64.68) 86.35,64.68 87.47,65.79 88.92,65.79 v1(89.66,65.06)
  vias: v1(175.65,43.91) v4(171.04,49.28)
+3V_PCH_DSW: length 37.1
  TOP w0.254: v1(180.37,46.97) 180.37,47.38 180.5,47.5 180.5,48 RH296.2 181.03,49.16 180.65,49.54 180.15,49.54 179.71,49.11 RH12.2
  TOP w0.305: v7(167.93,47.94) 167.78,47.94 167.06,47.22 RH464.2
  TOP w0.508: RH466.2 166.33,45.83 166.73,46.24 RH464.2
  IN1 w0.203: v7(170.87,48.56) 170.81,48.62 170.5,48.62 170.43,48.7 169.82,48.7 169.49,48.37 169.49,47.96 169.21,47.68 168.18,47.68 v7(167.93,47.94) ; v3(167.76,48.47) 167.32,48.92 166.01,48.92 v7(166,48.93)
  IN1 w0.254: v3(171.21,48.2) 170.87,48.55 v7(170.87,48.56) ; v3(167.76,48.47) 167.93,48.31 v7(167.93,47.94)
  IN2 w0.254: v3(171.21,48.2) 171.3,48.12 171.3,47.59 171.64,47.25 175.08,47.25 175.93,48.1 179.24,48.1 v1(180.37,46.97)
  IN3 w0.254: v3(158.38,47.5) 158.39,47.5 158.39,47.48 158.74,47.13 161.61,47.13 161.8,47.32 163.2,47.32 163.39,47.51 164.76,47.51 165.8,48.55 167.68,48.55 v3(167.76,48.47)
  IN4 w0.254: v4(157.55,47.05) 157.57,47.05 157.83,47.3 158.21,47.3 158.39,47.48 158.39,47.5 v3(158.38,47.5)
  BOTTOM w0.254: UCPU1.AH10 157.81,47.36 157.6,47.15 157.6,47.1 v4(157.55,47.05)
  vias: v2(172.12,48.33)
+3VALW: length 250.7
  TOP w0.102: v5(259.81,46.5) v1(260.36,47.05)
  TOP w0.109: v6(197.63,37.5) v5(197.63,38.31)
  TOP w0.203: 173.45,68.05 173.26,68.05 173.03,67.83 172.65,67.83 172.5,67.97 171.93,67.97 171.69,67.73 U719.4 ; U718.6 234.34,47.12 233.93,46.71 v6(233.93,46.67) 233.98,46.72 U718.7 ; U1.27 v7(268,23.2)
  TOP w0.254: RH348.1 181.76,49.84 v1(181.76,50.87) ; PR113.2 60.52,9.69 61.72,8.49 61.72,7.39 v7(61.13,6.8) ; v1(141.89,71.81) 143.64,71.81 144.2,71.26 144.93,71.26 145.84,70.34 171.77,70.34 171.96,70.15 171.96,69.27 ; U721.2 196.42,48.29 196.11,47.98 v1(196.11,47.89) 195.92,48.08 U721.1 ; 183.06,5.06 JAPS.16
  TOP w0.305: v1(199.12,51.57) 199.32,51.77 U710.5 ; U713.5 184.32,68.7 184.42,68.8 v6(185.17,68.8)
  TOP w0.356: U5.5 v1(272.16,48.16)
  TOP w0.381: U23.14 209.72,68.65 210.11,69.05 C96.1 ; RR10.2 266.25,25.99 v1(266.33,26.07)
  TOP w0.457: R216.1 213.8,47.94 v5(214.53,47.2) 214.53,46.16 v1(213.96,45.59)
  TOP w0.508: C96.1 210.61,68.51 v1(210.43,68.33) ; v1(188.89,66.2) 188.3,66.2 187.97,66.53 R162.2 ; v1(260.36,47.05) C1289.1 262.26,47.05 U699.5 ; v1(283.17,36.86) 281.91,38.12 R11.1 C8.1 278.89,37.17 v1(277.36,38.69) ; v6(185.17,68.8) 185.11,68.87 185.11,69.5 185.54,69.93 189.27,69.93 189.46,69.74 R163.2 ; PR102.1 24.89,59.85 v1(24.96,59.93) ; RR9.1 267.01,28.43 v1(267.71,29.13) ; v1(203.35,20.56) 203.26,20.56 202.75,20.05 202.75,19.46 PR126.1 ; U725.2 v1(285.7,37.8)
  GND1 w0.254: v11(247.34,62.84) v12(246.98,62.84)
  IN1 w0.254: v7(61.13,6.8) 61.02,6.8 59.18,4.96 v3(59.18,4.59) ; v3(173.56,67.78) 173.56,68.26 v7(173.4,68.42) ; v3(247.74,62.84) v12(246.98,62.84)
  IN1 w0.762: v7(268,23.2) v3(267.55,23.2)
  IN2 w0.508: v1(29.15,27.01) 29.86,27.73 29.86,28.89 30.09,29.12 30.09,30.87 29.52,31.44 29.52,33.01 28.97,33.56 25.72,33.56 v1(25.29,33.13)
  IN3 w0.254: v1(190.21,51.75) 190.19,51.77 187.47,51.77 187.27,51.57 184.73,51.57 183.47,50.31 182.17,50.31 181.76,50.73 v1(181.76,50.87)
  IN3 w0.508: v1(16.07,35.03) 17.01,35.03 18.46,36.48 23.87,36.48 25.53,34.82 25.53,33.37 v1(25.29,33.13)
  IN3 w0.762: v3(36.37,3.62) 36.37,5.34 32.94,8.77 32.94,9.51 32.07,10.37 32.07,13.17 32.96,14.05 32.96,16.72 v1(32.94,16.75) 33.34,17.15 33.34,18.78 31.15,20.98 31.15,23.81 31.34,24 31.34,25.92 30.88,26.37 29.79,26.37 v1(29.15,27.01)
  IN4 w0.508: v1(260.36,47.05) 261.46,48.16 v1(272.16,48.16) 275.39,44.92 275.39,39.9 276.6,38.69 v1(277.36,38.69)
  IN4 w0.762: v3(36.37,3.62) 36.67,3.31 40.38,3.31 41.34,2.35 42.74,2.35 43.38,2.98 46.98,2.98 ; v1(16.07,35.03) 16.45,35.42 16.45,42.27 18.36,44.18 18.36,49.13 20.52,51.29 23.31,51.29 26.49,54.47 26.49,55.99 v1(26.87,56.37)
  BOTTOM w0.203: U664.2 33.77,16.42 33.5,16.7 32.99,16.7 ; 32.99,16.7 v1(32.94,16.75) ; 32.99,16.7 33.34,16.34 33.35,16.34 33.37,16.32 U664.1
  BOTTOM w0.254: v1(141.89,71.81) 141.88,71.8 141.88,70.24 139.65,68.01 JLVDS2.45
  BOTTOM w0.457: C1290.1 27.25,55.74 26.87,56.12 v1(26.87,56.37)
  BOTTOM w0.508: v1(283.17,36.86) 284.11,37.8 v1(285.7,37.8) ; C1290.1 27.92,54.96 27.57,54.61 U700.5 ; v1(26.87,56.37) 26.87,56.75 26.56,57.06 26.56,57.48 24.96,59.08 v1(24.96,59.93) ; v1(172.19,67.32) 173.3,68.43 173.3,68.95 174.14,69.78 184.19,69.78 v6(185.17,68.8) 185.22,68.86 R923.2 188.07,67.14 Q330.3 188.07,66.76 188.63,66.2 v1(188.89,66.2)
  vias: v1(140.11,1.64) v1(140.7,1.64) v1(183.52,2.64) v1(184.11,2.64) v1(202.93,11.03) v1(203.32,11.46) v1(234.23,49.41) v1(234.7,49.77) v1(240.7,50.99) v1(242.11,55.1) v1(242.61,54.58) v1(242.72,55.16) v1(264.72,7.6) v4(266.79,22.49) v4(267.28,22.16) v6(195.83,37.09) v6(196.36,37.5) v6(196.46,36.87) v6(196.56,36.24) v6(197,37.5) v6(197.1,36.87)
+3VALW_EC: length 407
  TOP w0.254: R947.1 133.6,46.86 133.31,46.86 v7(133.22,46.95) ; v1(111.97,3.06) 111.97,3.89 107.91,7.96 107.91,8.95 102.43,14.42 100.45,14.42 97.62,17.25 97.62,19.23 94.92,21.93 94.92,27.53 100.58,33.18 105.59,33.18 107.6,35.19 107.92,35.19 v1(108.38,35.64) 111.15,35.64 v2(111.94,36.43) 114.9,39.39 v7(114.9,42.01) ; R219.2 204.1,46.76 203.26,47.61 203.26,49.13 ; 160.1,32.06 169.97,32.06 174.08,27.95 178.52,27.95 179.69,26.78 180.59,26.78 180.94,26.42 R937.1 ; 160.1,32.06 160.1,33.84 158.1,35.85 158.1,38.92 154.29,42.73 v7(154.29,43.8) ; 160.1,32.06 155.66,27.62 v1(154.3,27.62) ; R216.2 214.29,50.34 214.86,49.77 214.86,48.31 215.04,48.14 215.04,44.66 216.52,43.19 216.52,40.56 216.71,40.37 v1(216.88,40.37) ; 204.29,53.31 204.41,53.18 RP22.5 ; R949.2 84.52,66.9 v1(84.51,66.89)
  TOP w0.508: 213.16,52.38 213.87,53.09 213.87,53.61 214.39,54.14 214.39,54.98 213.59,55.78 213.59,59.5 v1(213.96,59.86) ; 209.63,54.97 C281.2
  IN1 w0.254: v7(211.37,54.11) 211.27,54.21 210.97,54.21 v3(210.94,54.24) ; v3(211.27,52.51) v7(211.73,52.51) ; v7(154.29,43.8) 154.29,44.6 154.27,44.61 154.27,45.14 153.38,46.03 152.9,46.03 151.5,47.43 148.13,47.43 146.86,48.7 138.98,48.7 137.23,46.95 v7(133.22,46.95) 130.69,46.95 127.11,50.53 122.78,50.53 122.03,49.78 121.6,49.78 121.35,49.54 121.1,49.54 116.95,45.39 116.95,44.5 115.25,42.8 115.25,42.52 114.9,42.17 v7(114.9,42.01)
  IN1 w0.381: v7(212.26,50.94) 212.01,50.94 v3(211.85,50.78)
  IN2 w0.254: v1(84.51,66.89) 84.85,66.54 84.85,62.85 83.86,61.86 83.86,60.99 86.96,57.89 88.46,57.89 91.28,55.08 93.11,55.08 93.83,54.35 97.59,54.35 102.71,49.23 102.71,44.1 108.63,38.18 108.63,35.9 v1(108.38,35.64) ; v1(111.97,3.06) 143.36,3.06 145.7,5.41 148.09,5.41 151.37,2.12 193.03,2.12 196.44,5.53 196.44,13.97 197.12,14.65 197.12,22.6 196.3,23.43 195.38,23.43 195.18,23.63 195.18,24.85 195.51,25.18 196.59,25.18 199.87,28.46 199.87,32.32 203.84,36.29 209.84,36.29 211.05,37.51 211.87,37.51 212.27,37.11 213.65,37.11 216.88,40.34 v1(216.88,40.37)
  IN2 w0.305: v3(211.85,50.78) 212.18,50.78 213.04,49.93 214.89,49.93 v3(215.36,50.4)
  IN3 w0.305: v1(213.96,59.86) 213.96,60.1 213.35,60.71 210.89,60.71 210.2,60.03 v1(210.2,59.83)
  IN4 w0.254: v3(211.85,50.78) 211.85,50.76 211.8,50.81 211.52,50.81 211.5,50.78 v4(211.47,50.78) ; v4(215.16,48.47) 214.97,48.28 214.97,47.89 214.71,47.63 v4(214.71,47.39) 214.91,47.19 215.36,47.19 215.59,46.96 215.59,46.45 215.36,46.22 v4(215.27,46.22) ; v3(210.94,54.24) 210.94,54.59 v4(211.09,54.75) ; v3(211.27,52.51) 211.27,52.54 211.37,52.64 211.63,52.64 211.63,52.69 211.68,52.69 v4(211.68,52.66)
  IN4 w0.305: v3(215.36,50.4) 215.02,50.06 215.02,49.11 215.21,48.92 215.21,48.52 v4(215.16,48.47)
  BOTTOM w0.254: 211.5,50.78 211.52,50.81 211.98,50.81 212.35,50.44 U34.M12 ; 211.5,50.78 v4(211.47,50.78) ; 211.5,50.78 211.5,50.83 211.36,50.69 U34.K12 ; U34.J4 210.86,54.51 v4(211.09,54.75) ; 215.35,58.14 215.35,60.13 215.12,60.36 214.22,60.36 213.96,60.1 v1(213.96,59.86) ; U34.J7 U34.K7 211.37,52.94 211.63,52.69 211.68,52.69 v4(211.68,52.66) ; v1(154.3,27.62) 154.3,28.92 152.27,30.95 R940.1 ; R229.2 R230.2
  BOTTOM w0.305: v4(214.71,47.39) 214.1,47.39 R604.1 R221.2 ; R933.1 214.55,40.04 214.9,39.68 216.2,39.68 v1(216.88,40.37) ; v1(210.2,59.83) 210.15,59.83 209.63,59.3 208.16,59.3 R935.2
  BOTTOM w0.508: 203.32,55.38 204.64,55.38 205.05,54.97 v1(205.05,54.85) ; 203.32,55.38 R922.2 ; 203.32,55.38 R1156.1
  vias: v1(203.1,49.77)
+3VALWP: length 15.7
  TOP w0.254: v1(192.04,33.5) 193.1,32.44 193.1,30.31 192.87,30.08 191.91,30.08 191.57,30.42 PR353.1
  BOTTOM w0.254: 198.77,38.62 196.59,38.62 195.17,37.19 195.17,36.2 v2(194.56,35.59) 193.19,35.59 192.86,35.26 PR348.1 192.55,35.24 192.04,34.73 v1(192.04,33.5)
+3VLP: length 144.4
  TOP w0.254: RP22.6 205.36,52.68 205.67,52.99 205.67,53.37 205.23,53.82 v1(204.74,53.82) ; v1(217.79,41.36) v2(217.79,42.1) 217.79,42.46 215.42,44.83 215.42,48.29 215.25,48.47 215.25,50.14 215.45,50.34 215.45,51.11 R921.2 215.14,54.33 v7(214.93,54.54)
  TOP w0.305: v1(217.79,41.36) 217.79,40.55 216.26,39.02 216.26,38.16 216.69,37.73 216.69,35.39 217.09,35 232.84,35 232.97,35.14 251.8,35.14 254.44,37.78 254.44,39.02 254.8,39.39 RTCD1.3 256.29,39.59 256.29,41.9 256.97,42.57 v6(256.97,44.81)
  TOP w0.432: R1349.2 238.99,49.67 239.34,49.32 v1(239.64,49.32)
  IN1 w0.254: v3(190.74,30.86) 190.74,30.64 v7(190.61,30.5) ; v1(204.74,53.82) 205.01,54.08 206.09,54.08 206.42,54.42 207.33,54.42 207.91,55 211.55,55 212.16,54.39 212.84,54.39 213,54.54 v7(214.93,54.54)
  IN3 w0.305: v1(239.64,49.32) 240.09,49.77 242.98,49.77 243.9,48.85 253.76,48.85 256.97,45.65 v6(256.97,44.81)
  IN4 w0.254: v4(191.4,30.84) 190.76,30.84 v3(190.74,30.86) ; v4(210.08,35.4) 211.27,35.4 213.1,37.23 213.1,39.22 213.47,39.59 215.25,39.59 217.02,41.36 v1(217.79,41.36)
  BOTTOM w0.152: U712.5 200.84,54.02 201.09,54.26 202.69,54.26
  BOTTOM w0.254: v1(204.74,53.82) 204.73,53.81 204.34,53.81 204.08,54.06 202.81,54.06 202.69,54.19 202.69,55.89 R939.1 ; v4(191.4,30.84) 191.46,30.84 192.3,30.01 195.9,30.01 196.72,30.82 197.73,30.82 200.14,33.22 204.43,33.22 206.61,35.4 v4(210.08,35.4)
+3VNS_PWR: length 236.1
  TOP w0.127: v11(248.84,63.34) 248.84,63.43 249.24,63.84 U636.G8
  TOP w0.203: U636.H1 249.86,60.34 250.13,60.07 250.44,60.07 250.48,60.03
  TOP w0.229: U636.A8 246.08,64.09 v1(245.87,64.09)
  TOP w0.254: v7(249.18,64.19) 249.34,64.04 U636.G8 ; v1(254.09,58.63) 254.06,58.66 JSNRDG.1 ; U636.A1 246.2,60.2 246.2,59.69 246.2,59.69 246.2,59.65 v6(246.24,59.65) ; v7(200.72,61.68) 200.72,60.89 200.34,60.51 200.34,59.29 200.59,59.04 201.29,59.04 202.75,57.58 202.75,53.58 202.24,53.07 202.24,52.6 v7(202.34,52.5) 202.36,52.5 202.67,52.18 Q352.2 ; v7(201.59,52.18) Q352.5
  TOP w0.305: JSNRDG.1 252.76,58.66 v1(252.57,58.85)
  TOP w0.508: R1092.2 v1(241.64,59.57) ; v7(250.26,58.78) 250.12,58.64 R1220.2 ; R855.2 v1(238.49,60.18) ; 250.48,60.03 251.36,60.03 251.67,59.72 251.9,59.72 C977.1 252.02,59.4 v1(252.57,58.85) ; C978.1 245.45,56.17 v1(245.01,55.73) 244.6,56.14 C976.1 244.6,56.95 244.91,57.25 R1251.2 ; v7(214.92,35.44) 213.14,35.44 211.84,34.15 207.57,34.15 206.96,33.53 206.45,33.53 v5(205.42,32.5) 204.98,32.06 204.98,31.53 202.05,28.6 202.05,26.64 204.17,24.52 204.17,23.33 205.87,21.62 205.87,17.93 206.34,17.46 JSATA1.22 ; R1319.2 246.59,51.34 246.92,50.94 v1(246.92,50.67) ; R1003.2 238.36,61.96 237.78,61.37 v1(237.78,60.71) ; v7(252.23,66.02) R1143.2 ; C979.1 251.61,62.34 v1(251.34,62.06) ; R854.2 v1(238.49,59.29)
  GND1 w0.254: v11(249.34,62.84) 249.05,63.12 249.05,63.13 248.84,63.34 v11(248.84,63.34)
  IN1 w0.254: v7(249.18,64.19) 249.18,64.59 v3(249.22,64.63) ; v7(202.34,52.5) 201.91,52.5 v7(201.59,52.18) ; v7(200.72,61.68) 200.27,62.12 200.27,64.68 201.06,65.46 201.47,65.46 201.9,65.03 v3(202.58,65.03)
  IN1 w0.508: v3(225.65,35.58) 225.05,34.98 215.37,34.98 v7(214.92,35.44) ; v1(252.57,58.85) 250.32,58.85 v7(250.26,58.78) ; v7(252.23,66.02) v3(251.66,66.02)
  IN2 w0.381: 220.94,63.42 216.83,63.42 216.81,63.43 205.15,63.43 203.55,65.03 v3(202.58,65.03) 202.05,65.03 201.29,65.79 200.07,65.79 199.22,66.65 194.65,66.65 192.7,68.59 190.32,68.59 189.66,67.93 181.93,67.93 180.71,69.15 175.56,69.15 174.89,68.47 v3(174.89,67.97) ; v1(237.78,60.71) 235.5,60.71 231.35,64.87 224.03,64.87 223.49,64.32 ; v1(166.02,68.05) 166.02,67.97 165.8,67.75 160.75,67.75 160.37,68.13 158.13,68.13 157.32,67.32 156.53,67.32 154.2,64.98 144.06,64.98 142.64,66.4 142.64,67.52 142.23,67.93 139.9,67.93 138.65,66.68 v3(138.65,65.57)
  IN2 w0.508: v3(225.65,35.58) 228.45,35.58 230.35,37.47 241.01,37.47 242.03,38.49 246.93,38.49 248.35,37.07 253.21,37.07 254.91,38.77 254.91,40.62 254.04,41.49 v3(253.84,41.49)
  IN4 w0.508: v3(253.84,41.49) 253.75,41.58 253.75,42.97 253.28,43.44 253.28,47.58 251.86,49 249.68,49 248.01,50.67 v1(246.92,50.67) ; v3(138.65,65.57) v4(138.25,65.57)
  BOTTOM w0.254: JLVDS2.40 137.15,66.41 137.99,65.57 v4(138.25,65.57)
  BOTTOM w0.381: RH461.2 166.69,67.39 166.03,68.05 v1(166.02,68.05) 165.74,67.78 164.48,67.78 164.03,67.32 RH462.2
+3VS: length 704.7
  TOP w0.254: C1283.1 218.51,54.08 219.13,54.08 219.14,54.09 U679.B2 ; C1135.1 211.36,40.19 211.8,39.75 211.8,38.23 209.95,36.38 206.58,36.38 205.96,35.76 205,35.76 202.64,33.4 U682.5 202.64,32.38 202.14,31.89 v1(200.96,31.89) ; v1(209.12,59.83) 209.2,59.83 209.86,59.16 R930.1 ; v1(220.21,52.14) 220.21,51.54 U675.5 ; v7(216.3,65.46) 217.09,64.68 218.14,64.68 218.54,64.27 218.54,63.66 217.99,63.1 MD50.5 ; RH98.1 177.73,56.19 177.73,54.85 177.96,54.62 v7(178.32,54.62) ; RH384.2 RH440.2 RH301.2 172.75,56.57 172.75,55.23 v1(172.78,55.2) ; UH5.5 185.11,47.74 v1(184.66,47.29) 184.66,46.39 184.41,46.13 v7(181.86,46.13) ; QH3.5 180.17,54.57 v7(179.53,54.57)
  TOP w0.305: v1(218.79,48.01) 218.53,48.01 218.3,47.78 U709.5
  TOP w0.381: C1285.1 232.16,69.53 U671.14 ; U698.5 207.21,43.43 207.83,44.05 ; Q359.2 251.59,47.03 251.72,46.9 252.6,46.9 252.74,47.03 Q359.5 253.73,47.03 253.74,47.02 253.97,47.02 v1(253.99,47) ; C1287.1 226.2,69.68 U677.14 ; QH4.2 213.29,67.18 v1(213.43,67.04) 213.29,66.9 QH4.5 ; v1(108.11,37.17) 107.45,37.17 106.61,36.33 106.61,34.83 105.47,33.69 100.39,33.69 94.48,27.78 94.48,21.75 97.18,19.05 97.18,17.06 100.26,13.98 102.25,13.98 107.25,8.97 107.25,4.84 108.32,3.77 v1(109.01,3.77)
  TOP w0.508: v1(139.16,65.18) 139.02,65.32 139.02,66.23 R1033.2 ; 168.45,54.61 168.45,53.82 168.66,53.6 v1(168.66,53.01) ; 168.45,54.61 168.89,55.05 RH248.1 RH196.2 RH180.2 171.43,55.1 172.27,55.1 172.37,55.2 v1(172.78,55.2) ; 168.45,54.61 168.08,54.97 RH452.1 168.14,55.34 v1(168.14,55.67) 167.3,55.67 166.96,56.02 RH396.1 RH397.1 166.96,58.12 v1(167.39,58.56) ; C1285.1 v1(232.99,69.71) ; C1283.1 218.59,53.12 v1(218.94,53.12) ; v1(210.06,41.02) 210.08,41.02 210.24,40.85 C1136.1 ; v7(181.4,38.36) 182.26,37.5 R1289.1 ; RH95.1 RH441.2 176.28,54.59 v1(175.84,55.04) ; R1340.1 245.5,42.62 244.05,44.06 v1(244.05,44.13) ; RH367.2 116.8,55.3 v1(116.38,55.3) ; C1136.1 R975.2 C1140.1 C1139.1 206.81,40.59 v1(207.22,40.99) ; C1136.1 C1135.1 ; Q344.2 227.05,47.86 v1(227.46,47.44) ; v1(200.65,49.69) 200.65,48.18 202.62,46.21 203.89,46.21 205.42,44.69 207.03,44.69 v1(207.35,44.37) ; v1(199.98,56.56) 200.84,55.69 R1129.1 ; CH1226.1 154.34,56.12 154.64,55.81 v1(154.84,55.81) ; C1287.1 v1(225.53,69.71) ; RV32.2 29.28,41.3 v1(29.75,41.77) ; RH465.2 156.58,54.97 v1(156.56,54.95) ; R1185.1 181.68,56.35 181.27,55.94 v1(181.24,55.94) 180.93,56.24 RH99.1 ; R1343.1 248.34,43.8 248.56,44.01 v1(248.56,44) ; v1(101.81,53.88) PR723.2 100.25,53.88 PR725.2 ; R1339.1 223.65,52.27 223.41,52.51 v1(223.31,52.51) ; R1306.1 47.34,5.41 v1(47.34,4.62) 47.91,4.62 48.23,4.3 48.23,3.35 47.77,2.89 R884.2 47.53,2.23 46.88,1.58 45.38,1.58 44.21,2.75 v5(43.48,2.75) 41.83,2.75 41.38,3.2 v7(41.38,3.9) ; CH1225.1 156.39,53.83 v1(156.05,54.17)
  IN1 w0.254: v3(166.67,47.54) 166.49,47.72 166.11,47.72 v7(166.02,47.63) ; v1(213.43,67.04) 213.58,67.04 214.09,66.53 214.09,65.79 214.39,65.49 216.27,65.49 v7(216.3,65.46) ; v7(181.86,46.13) 181.86,45.53 179.53,43.21 179.53,38.97 180.14,38.36 v7(181.4,38.36)
  IN1 w0.305: v1(210.38,44.45) 210.59,44.45 211.44,45.3 213.43,45.3 v1(213.62,45.11)
  IN1 w0.381: v7(179.53,54.57) 179.48,54.62 v7(178.32,54.62) 177.69,54.62 177.27,55.04 v1(175.84,55.04)
  IN1 w0.508: v7(41.38,3.9) 41.21,4.08 39.68,4.08 39.05,4.71 37.21,4.71 35.93,5.99 35.93,10.1 35.38,10.66 35.38,12.12 32.86,14.64 32.86,15.9 32.33,16.43 32.33,18.37 v1(32.35,18.4) ; v1(225.53,69.71) 225.65,69.71 226.46,68.89 232.17,68.89 ; v3(230.96,63.56) 230.96,67.67 232.17,68.89 ; 232.17,68.89 v1(232.99,69.71)
  IN2 w0.508: v1(154.84,55.81) 154.04,56.61 154.04,60.36 151.76,62.64 141.03,62.64 139.16,64.51 v1(139.16,65.18) ; v1(109.01,3.77) 108.52,3.77 106.92,2.17 57.07,2.17 55.92,3.31 51.96,3.31 50.65,4.62 v1(47.34,4.62) ; v1(213.43,67.04) 209.54,67.04 207.21,64.7 v1(207.21,64.58) ; v1(253.99,47) 251.48,49.51 249.8,49.51 248.53,50.78 247.88,50.78 247.33,51.34 246.86,51.34 244.82,53.37 v1(244.82,53.88) ; v1(244.05,44.13) 242.86,42.93 232.85,42.93 228.34,47.44 v1(227.46,47.44) ; v1(199.98,56.56) 200.12,56.42 200.12,55.91 199.64,55.43 193.9,55.43 193.79,55.53 190.2,55.53 189.74,55.99 181.29,55.99 v1(181.24,55.94) 180.54,55.24 176.04,55.24 v1(175.84,55.04) 175.8,55.08 174.95,55.08 174.39,54.52 173.46,54.52 v1(172.78,55.2)
  IN3 w0.381: v1(253.99,47) 253.99,46.43 256.24,44.18 262.48,44.18 264.99,41.66 264.99,36.42 264.75,36.18 264.75,32.42 266.19,30.98 v1(266.19,30.6)
  IN3 w0.508: v1(116.38,55.3) 116.05,55.3 115.56,54.82 115.56,52.6 116.45,51.71 116.45,49.46 116.63,49.29 116.63,48.05 114.29,45.71 109.68,45.71 107,43.04 107,38.27 v1(108.11,37.17) ; v1(248.56,44) 248.56,45.04 251.58,48.07 252.93,48.07 v1(253.99,47) ; v3(230.96,63.56) 230.96,64.17 230.52,64.6 225.52,64.6 224.94,64.02 224.94,62.26 223.31,60.64 219.96,60.64 218.47,62.12 216.57,62.12 213.66,65.03 213.66,65.06 213.33,65.39 213.33,66.94 v1(213.43,67.04)
  IN4 w0.254: v1(200.65,49.69) 199.99,49.03 198.86,49.03 197.96,48.13 197.96,47.63 197.21,46.88 185.07,46.88 v1(184.66,47.29) ; v3(166.67,47.54) 166.84,47.72 167.64,47.72 v4(167.66,47.73) ; v4(200.33,21.12) 200.63,21.41 200.63,31.56 v1(200.96,31.89)
  IN4 w0.508: v6(101.05,61.78) 101.05,61.45 100.64,61.04 99,61.04 96.92,58.96 96.92,55.51 98.04,54.39 100.42,54.39 100.93,53.88 v1(101.81,53.88) ; v4(167.66,65.72) 166.76,66.62 165.27,66.62 v4(164.92,66.98) 164.83,67.06 159.52,67.06 v4(159.44,66.99) ; v4(115.3,62.33) 116.55,63.58 119.42,63.58 120.73,64.89 124.15,64.89 124.47,65.2 v4(124.59,65.2) ; v1(26.87,29.73) 27.07,29.73 28.26,28.53 28.26,26.74 28.84,26.17 28.84,23.93 31.77,20.99 31.77,18.98 v1(32.35,18.4)
  BOTTOM w0.203: CV44.1 28.59,39.86 28.59,39.07 28.79,38.87 U722.37 ; CV39.1 30.7,32.04 30.7,32.27 30,32.97 U722.11
  BOTTOM w0.254: RH392.2 167.51,48.17 167.66,48.01 v4(167.66,47.73) ; RC159.1 124.66,32.62 124.15,32.11 124.15,31.06 123.27,30.18 120.87,30.18 115.13,35.92 109.35,35.92 v1(108.11,37.17) ; C655.1 105.55,38.8 U635.5 ; v1(204.26,62.14) 203.9,61.78 JLVDS1.17 ; U652.19 207.22,44.5 v1(207.35,44.37) ; UCPU1.V8 158.87,52.63 UCPU1.W9 157.58,52.19 ; U652.10 v1(207.22,40.99) ; v1(209.12,59.83) 209.09,59.83 208.9,60.01 JLVDS1.7
  BOTTOM w0.305: U652.5 210.47,40.61 v1(210.06,41.02) ; v1(213.62,45.11) 213.77,44.95 RH29.2 ; U652.24 210.47,44.53 v1(210.38,44.45)
  BOTTOM w0.356: v1(154.84,55.81) 154.67,55.99 UCPU1.K16 UCPU1.K14
  BOTTOM w0.381: RH391.2 172.79,54.19 ; 172.79,54.19 172.79,55.19 v1(172.78,55.2) ; 172.79,54.19 172.18,54.19 RH455.1 RH463.1 RH456.1 ; Q326.2 141.01,11.63 140.73,11.91 139.59,11.91 139.06,11.37 139.06,8.39 139.37,8.08 139.37,4.36 137.83,2.82 113.14,2.82 111.61,4.34 109.58,4.34 v1(109.01,3.77) ; v1(266.19,30.6) 266.19,26.79 265.96,26.56 265.94,26.56 265.76,26.38 U678.5
  BOTTOM w0.508: 113.82,57.08 105.01,57.08 v1(101.81,53.88) ; 113.82,57.08 113.82,59.2 115.02,60.4 115.02,61.79 115.3,62.07 v4(115.3,62.33) ; 113.82,57.08 114.55,57.08 116.33,55.3 ; v4(167.66,65.72) 167.58,65.64 RH458.2 RH460.2 167.58,64.12 167.56,64.1 167.56,63.67 167.3,63.41 v6(167.3,62.78) 167.3,62.68 166.69,62.07 RH459.2 166.95,62.04 167.38,61.6 167.38,60.33 RH457.2 RH380.1 167.39,59.03 v1(167.39,58.56) ; 116.33,55.3 v1(116.38,55.3) ; 116.33,55.3 116,55.3 115.69,55 115.69,53.81 115.97,53.53 116.35,53.53 117.38,52.5 R1311.2 ; v1(168.14,55.67) 168.08,55.74 RH381.1 RH103.1 ; CV39.1 31.18,32.52 v1(30.96,32.75) ; R1103.2 50.77,4.5 49.78,5.49 48.08,5.49 47.34,4.76 v1(47.34,4.62) ; RH354.2 186.28,67.25 186.45,67.09 v1(186.45,66.35) ; v1(139.16,65.18) 139.16,65.11 138.98,64.93 137.66,64.93 137.04,65.55 134.73,65.55 134.51,65.34 127.27,65.34 127.13,65.2 v4(124.59,65.2) ; v1(32.35,18.4) 32.61,18.66 R1182.2 ; v1(108.11,37.17) 106.11,39.16 C655.1 ; v1(156.05,54.17) 156.05,53.34 157.2,52.19 157.58,52.19 ; CV44.1 29.08,40.04 29.43,40.39 29.43,41.45 v1(29.75,41.77) ; RH390.2 RH35.1 RH82.2 RH37.1 167.51,50.88 RH302.2 RH100.1 RH392.2 ; RH390.2 167.58,53.63 RH107.1 168.4,53.27 v1(168.66,53.01) ; RH390.2 RH91.1 ; v4(159.44,66.99) RH388.1 RH281.1 RH389.1 ; v4(164.92,66.98) RH424.2
  vias: v1(244.51,54.42) v1(245.12,54.43) v6(100.41,61.78)
+3VS_AUDIO: length 125.4
  TOP w0.203: UA2.23 24.54,28.22 v1(24.89,28.56)
  TOP w0.254: UA3.B2 17.59,19.83 18.15,20.39 CA32.1 ; v7(38.26,6.36) 38.41,6.51 UA1.42 ; UA1.16 39.91,15.12 40.01,15.22 40.01,15.81 40.06,15.86 CA10.1 ; UA1.14 40.91,15.25 41.34,15.68
  TOP w0.381: v1(22.02,28.34) 22.56,28.89 LH2.1
  TOP w0.508: v7(32.94,29.12) 32.94,30.32 32.29,30.97 30.02,30.97 v7(29.43,30.39) ; RA14.1 13.94,8.86 v1(13.94,7.97) ; CA11.1 41.34,16.28 41.34,15.68 ; CA11.1 41.09,16.56 CA7.1 42.57,16.91 v5(43.57,16.91) v1(44.25,16.91) ; CA11.1 40.94,16.68 40.14,16.68 CA10.1 39.93,16.73 CA8.1 38.15,17.52 R1266.1 37.77,17.79 37.76,17.8 v1(37.76,18.17) ; v7(39.04,5.58) 39.21,5.74 CA9.1 40.4,5.65 v1(40.4,5.07) ; v1(17.32,14.82) 17.37,14.77 RA37.1 ; RA38.1 v1(20,9.2) ; CA32.1 18,20.89 17.66,20.89 v1(17.46,21.09) ; RA30.1 34.94,22.84 v1(34.94,22.41)
  IN1 w0.508: v1(34.94,22.41) 34.94,23.27 34.09,24.12 34.09,24.93 32.94,26.08 v7(32.94,29.12) ; v7(39.04,5.58) 39,5.62 39,5.62 v7(38.26,6.36) ; v7(29.43,30.39) 29.41,30.36 26.08,30.36 24.89,29.17 v1(24.89,28.56) ; v1(17.46,21.09) 17.46,20.25 16.74,19.54 v3(16.74,18.46) ; v1(20,9.2) 20,9.27 19.5,9.76 17.66,9.76 17.19,10.23 17.19,14.69 v1(17.32,14.82)
  IN4 w0.508: v1(20,9.2) 20,8.57 19.4,7.97 v1(13.94,7.97) ; v4(19.04,15.45) 19.04,16.19 16.78,18.45 16.76,18.45 v3(16.74,18.46) 16.74,18.33 15.82,17.41 15.82,15.96 16.96,14.82 v1(17.32,14.82) ; v4(32.19,12.49) 32.2,12.48 32.2,11.01 33.03,10.18 34.09,10.18 37.3,6.97 37.95,6.97 39.85,5.07 v1(40.4,5.07)
  BOTTOM w0.508: CA46.1 23.5,27.73 23.81,28.04 CA31.1 24.3,28.23 24.63,28.56 v1(24.89,28.56) ; CA46.1 22.05,28.34 v1(22.02,28.34) ; CA46.1 22.55,27.62 20.57,27.62 20.14,27.19 20.14,26.39 17.84,24.09 17.84,22.77 18.12,22.49 RA18.1 18.04,21.67 v1(17.46,21.09) ; v1(34.94,22.41) 36.85,22.41 37.79,21.47 37.79,18.19 v1(37.76,18.17) ; v1(40.4,5.07) 41.04,5.07 42.44,6.47 42.44,7.04 43.76,8.36 43.76,10.28 42.87,11.17 41.66,11.17 R1265.1 40.99,11.06 40.58,11.46 40.58,14.61 40.91,14.94 40.91,15.25 41.78,16.11 43.45,16.11 v1(44.25,16.91) 44.15,17 42.21,17 41.58,17.63 R1261.1
+3VS_CAM: length 29.2
  TOP w0.102: v5(213.71,60.9) 212.88,61.73 v1(212.88,62.11)
  IN2 w0.381: v1(212.88,62.11) 212.87,62.1 212.87,61.96 212.48,61.57 203.81,61.57 202.79,62.58 v6(202.79,62.63)
  BOTTOM w0.508: v6(202.79,62.63) 201.61,62.63 201.09,62.11 201.09,60.92 200.37,60.21 200.37,58.66 198.88,57.16 198.88,54.08 197.81,53.02 196.59,53.02 194.84,51.27 194.1,51.27
+3VS_CR:
  vias: v1(265.31,14.46) v1(265.87,16.07) v1(265.86,14.77) v2(266.81,16.96)
+3VS_DVDD: length 6
  TOP w0.102: v2(31.63,30.41) 31.49,30.27 RA32.1
  TOP w0.203: UA2.11 29.8,26.1 30.08,26.37
  TOP w0.254: 30.08,26.37 30.49,26.78 31.3,26.78 CA35.1 31.36,26.84 31.36,27.8 CA42.2 RA32.1
+3VS_NGFF: length 88.4
  TOP w0.254: v1(172.13,52.64) 172.19,52.57 172.19,52.08 172.52,51.75 R1200.1 173.21,51.24 173.52,50.92 Q348.2
  TOP w0.381: v1(230.64,50.53) 230.64,50.5 230.08,49.94 R1197.1 229.99,49.55 229.44,49 Q346.2 ; R942.1 223.65,50.4 222.93,49.68 v1(222.93,49.51)
  TOP w0.508: R1137.1 227.53,50.15 v1(227.53,50.61) ; v1(227.39,43.84) 226.92,43.84 C725.1 ; C717.1 231.37,41.91 v1(231.37,41) ; C716.1 225.05,43.06 225.61,42.5 227.04,42.5 227.6,43.06 v1(227.6,43.2) ; C713.1 C714.1 249.23,41.03 249.07,40.86 v1(249.07,40.65) ; R1036.2 235.64,43.67 235.26,44.05 235.26,45.07 v1(235.27,45.07)
  IN1 w0.254: v3(185.53,49.61) 185.41,49.73 183.71,49.73 183.47,49.98 179.82,49.98 178.43,51.37 178.43,51.88 177.67,52.64 173.5,52.64 172.98,53.16 172.43,53.16 172.13,52.85 v1(172.13,52.64) ; v3(223.91,48.08) 223.59,47.76 222.53,47.76 221.35,48.94 220.29,48.94 220.05,48.7 218.01,48.7 217.88,48.57 215.16,48.57 214.57,49.16 213.1,49.16 212.77,48.83 212.45,48.83 211.98,48.36 210.11,48.36 209.35,47.6 203.55,47.6 202.75,48.4 200.57,48.4 199.98,48.99 194.72,48.99 v3(194.18,49.54)
  IN4 w0.254: v3(185.53,49.61) 187.6,49.61 188.63,50.64 190.4,50.64 190.52,50.53 193.5,50.53 194.18,49.86 v3(194.18,49.54)
  BOTTOM w0.254: v1(172.13,52.64) 172.13,52.97 R1205.1 171.91,53.32 171.77,53.19 Q350.2
  BOTTOM w0.305: v1(227.39,43.84) 227.37,43.84 225.97,45.24 JNGFF1.64 ; v1(227.6,43.2) 227.13,43.2 225.59,44.74 JNGFF1.66 ; JNGFF2.74 249.4,40.98 v1(249.07,40.65) 248.9,40.81 JNGFF2.72
  vias: v1(223.51,62.14) v1(228.95,54.72) v1(229.46,54.21) v1(229.89,53.78) v1(234.33,52.48) v1(234.74,52) v1(235.3,52.18) v5(234.92,52.64)
+3VS_TP: length 154.4
  TOP w0.508: v1(185.73,2.63) 186.02,2.35 189.9,2.35 194.77,7.22 v1(199.26,7.22) ; v1(175.9,11.18) 173.92,9.2 v1(164.5,9.2) ; v1(242.16,37.71) 242.68,38.24 v5(242.68,39.59) 242.68,44.59 242.2,45.07 240.04,45.07 239.64,45.46 R1128.2
  IN2 w0.508: v1(199.26,7.22) 199.26,9.71 199.69,10.14 199.69,20.73 204.97,26.02 204.97,32.89 205.81,33.73 212.11,33.73 213.24,34.86 228.67,34.86 230.52,36.71 241.15,36.71 v1(242.16,37.71)
  IN4 w0.381: v1(175.9,11.18) 178.7,11.18 v4(178.89,11)
  BOTTOM w0.305: v1(175.9,11.18) 176.75,11.18 177.15,10.79 JTP1.2
  BOTTOM w0.381: v4(178.89,11) 179.01,11.13 RH365.2
  BOTTOM w0.508: RH364.2 C1225.1 175.33,11.76 v1(175.9,11.18) ; v1(185.73,2.63) 184.64,3.72 166.21,3.72 164.5,5.43 v1(164.5,9.2) ; R1301.1 166.24,10.23 165.21,9.2 v1(164.5,9.2) ; v1(164.5,9.2) 163.41,10.29 Q365.2 ; R1300.1 195.83,7.76 196.36,7.22 v1(199.26,7.22) 200.25,7.22 200.91,7.88 200.91,8.68 200.32,9.27 Q364.2
+3VS_TS: length 72.9
  TOP w0.254: v7(175.8,59.9) 175.8,59.47 175.2,58.87 R1385.1 174.52,57.92 169.14,57.92 167.48,59.58 167.48,60.64 166.58,61.54 166.58,65.38 166.77,65.57 167,65.57 167.11,65.68 167.11,67.74 166.36,68.49 R1320.2 166.18,69.06 C1200.1 164.88,69.62 163.87,69.62 163.51,69.25 RH436.2 RH437.2 161.64,69.87 145.61,69.87 v2(144.66,70.82) 144.63,70.85 144.07,70.85 143.74,71.18 143.39,71.18 v1(142.75,70.54) ; v1(125.44,70.06) 126.04,70.66 MD90.5
  IN1 w0.254: v7(177.68,61.06) 177.25,61.06 176.09,59.9 v7(175.8,59.9)
  IN4 w0.254: v1(125.44,70.06) 125.44,71 126.08,71.64 135.83,71.64 136.29,71.18 142.12,71.18 v1(142.75,70.54)
  BOTTOM w0.203: v1(142.75,70.54) 142.75,69.01 142.15,68.4 JLVDS2.50
+5V_USB_P0: length 1.3
  BOTTOM w0.381: v1(21.46,49.92) 21.3,49.76 MD82.8
  vias: v5(20.97,42.08) v6(14.53,41.13) v6(14.53,40.5) v6(15.17,41.13) v6(15.17,40.5) v6(17.33,39.99) v6(17.98,41.26) v6(17.98,40.62) v6(17.98,39.99)
+5V_USB_P1: length 1.4
  TOP w0.381: MD74.8 278.02,42.21 v1(278.29,41.94)
  vias: v5(272.78,52.61) v6(273.88,52.05) v6(273.88,51.42) v6(274.52,52.05) v6(274.52,51.42) v6(277.67,50.29) v6(277.67,49.66) v6(278.3,50.29) v6(278.3,49.66)
+5VALW: length 282.7
  TOP w0.109: 30.51,44.98 v6(31.13,44.98)
  TOP w0.203: U715.4 189.5,50.07 189.48,50.09 v1(189.48,50.1) ; C1254.1 240.44,52.28 240.44,51.81 240.55,51.7 240.97,51.7 241.11,51.84 U716.4 ; C1203.1 233.49,47.92 U718.4
  TOP w0.254: U724.4 200.86,11.45 C1303.1 ; v1(197.4,47.89) 197.42,47.9 U721.4 ; v1(25.19,51.19) 25.22,51.19 25.23,51.17 R1168.2 R1214.2 ; PR104.2 v1(25.03,63.53) ; v1(199.51,56.17) 198.87,56.17 198.38,56.65 PR505.1 ; 30.41,44.88 C1173.1 ; v1(183.69,66.35) 183.44,66.11 U673.2
  TOP w0.381: v1(233.06,48.14) 232.92,48 C1203.1
  TOP w0.508: v1(240.59,53.27) 240.37,53.27 C1254.1 ; R1170.2 v1(259.92,48.75) ; R1165.2 R1213.2 267.02,45.33 v1(267.02,45.32) ; PR731.1 95.19,58.15 v6(94.99,57.95) ; U676.5 219.59,45.86 v1(219.59,45.55) ; C1303.1 200.03,11.59 198.13,9.69 194.98,9.69 v1(194.71,9.95)
  IN1 w0.254: v1(25.03,63.53) 23.95,62.45 23.95,59.16 25.46,57.65 25.46,51.46 v1(25.19,51.19) 25.19,42.93 v3(25.85,42.27)
  IN1 w0.508: v1(267.02,45.32) 263.59,48.75 v1(259.92,48.75)
  IN2 w0.254: v1(199.51,56.17) 199.4,56.06 196.44,56.06 195.09,57.41 188.18,57.41 187.89,57.12 187.05,57.12 186.84,57.34 v3(186.84,57.58)
  IN2 w0.508: v3(221.18,40.93) 220.88,40.64 217.57,40.64 217.21,40.99 216.64,40.99 215.31,39.66 213.05,39.66 212.57,39.18 ; v1(259.92,48.75) 259.02,49.65 259.02,53.27 259.84,54.08 v6(261.68,54.08) 260.51,55.25 255.14,55.25 253.38,57.01 249.6,57.01 249.09,57.51 243.27,57.51 240.82,55.06 240.82,53.5 v1(240.59,53.27)
  IN3 w0.254: v3(194.49,32.98) 194.49,33.16 200.78,39.44 200.78,42.23 202.1,43.55 202.1,44.92 200.48,46.54 198.7,46.54 197.4,47.84 v1(197.4,47.89) ; v1(183.69,66.35) 183.26,65.93 183.26,59.46 184.5,58.23 186.29,58.23 186.84,57.68 v3(186.84,57.58)
  IN3 w0.508: v1(267.02,45.32) 265.75,44.05 265.75,36.14 265.51,35.9 265.51,33.5 267,32.01 267,25.42 266.08,24.51 266.08,21.24 264.66,19.82 264.66,12.78 265.52,11.92 265.52,9.05 266.24,8.34 268.76,8.34 v1(269.46,7.64) ; v1(233.06,48.14) 233.06,49.13 234.41,50.48 235.17,50.48 237,52.31 239.64,52.31 240.59,53.26 v1(240.59,53.27) ; 97.2,31.35 97.99,32.14 97.99,36.05 97.02,37.02 95.22,37.02 92.55,39.68 89.68,39.68 89.05,40.32 89.05,44.74 90.54,46.24 92.35,46.24 93.29,47.18 93.29,53.86 93.67,54.24 93.67,56.17 94.99,57.49 v6(94.99,57.95)
  IN4 w0.508: v4(221.18,42.07) v3(221.18,40.93)
  BOTTOM w0.203: U664.6 35.37,16.36 35.71,16.7 35.71,17.71 C1213.1 36.16,17.32 36.16,16.59 35.77,16.2 U664.7 ; U664.4 34.57,16.57 34.51,16.63 34.51,17.17 v1(34.7,17.36)
  BOTTOM w0.254: v1(199.51,56.17) 199.51,53.9 197.99,52.38 196.75,52.38 194.71,50.34 194.71,48.4 ; v1(197.4,47.89) 197.4,48.14 197.17,48.37 195.7,48.37 ; v1(183.69,66.35) 183.38,66.66 183.37,66.66 C1241.1
  BOTTOM w0.381: v1(187.91,30.75) 187.88,30.72 178.45,30.72 177.97,31.2 167.94,31.2 R1341.2
  BOTTOM w0.508: v4(221.18,42.07) 220.95,42.07 220.07,42.94 220.07,45.07 v1(219.59,45.55)
  vias: v1(34.94,17.89) v1(50.03,11.84) v1(50.08,12.43) v1(50.64,11.84) v1(50.67,12.43) v1(96.28,30.5) v1(96.74,30.89) v5(32,45.75) v5(50.43,13.51) v5(269.75,8.2) v6(31.13,45.63) v6(31.11,44.33) v6(31.71,44.59) v6(181.86,34.87) v6(182.16,34.29) v6(182.51,34.89) v6(182.8,34.31) v6(183.15,34.87) v6(183.44,34.3) v6(183.79,34.86) v6(184.07,34.29) v6(184.46,34.89) v6(184.71,34.31) v6(209.73,36.97) v6(210.19,37.45) v6(210.7,37.93) v6(211.07,38.58) v6(261.68,53.45) v6(262.31,54.08) v6(262.31,53.45)
+5VALWP: length 20.4
  TOP w0.254: v1(188.77,32.34) 188.77,31.59 PR316.2
  IN1 w0.508: v1(189.99,37.32) 188.89,38.41 v1(183.36,38.41)
  IN3 w0.254: v6(182.33,38.5) 183.23,37.6 187.12,37.6 188.78,35.94 188.78,32.36 v1(188.77,32.34)
  vias: v2(179.32,37.14)
+5VS: length 288
  TOP w0.127: v7(144.37,70.26) 145.08,69.55 155.87,69.55 156.47,68.96 156.47,68.13 155.24,66.9 QC5.2
  TOP w0.508: v1(23.18,39.61) 23.15,39.64 D111.2
  IN1 w0.127: v6(100.53,52.81) 100.02,53.32 96.25,53.32 94.76,51.82 92.25,51.82 89.1,54.97 85.13,54.97 83.53,56.57 83.53,63.15 84.35,63.97 85.39,63.97 86.02,64.6 94.05,64.6 94.91,65.46 97.92,65.46 99.4,63.99 102.05,63.99 104.25,66.19 104.25,70.8 105.35,71.9 119.06,71.9 120.44,70.52 122.09,70.52 123.74,72.17 140.14,72.17 141.05,71.26 143.38,71.26 v7(144.37,70.26)
  IN1 w0.381: v6(100.53,52.81) 100.53,51.16 96.77,47.4 94.99,47.4 93.92,46.34 90.37,46.34 89.1,45.07 89.1,38.34 86.56,35.8 86.56,34.53 82.62,30.59 82.62,27.67 80.92,25.97 80.92,18.35 77.67,15.1 71.32,15.1 v6(70.68,15.73)
  IN2 w0.508: v6(142.56,2.17) 142.48,2.25 107.9,2.25 107.16,1.51 56.08,1.51 55.7,1.89
  BOTTOM w0.305: JFAN1.1 47.4,1.57 47.64,1.33 48.2,1.33 48.48,1.61 ; v1(43.31,1.29) 43.62,1.29 43.9,1.58 JFAN1.8
  BOTTOM w0.381: v6(56.04,13.11) 56.47,12.68 70.3,12.68 70.68,13.06 v6(70.68,15.73)
  BOTTOM w0.508: R886.2 51.02,1.96 ; C1153.1 145.61,7.48 142.56,4.43 v6(142.56,2.17)
  BOTTOM w0.635: R886.2 C1102.2 49.73,1.61 48.48,1.61
  vias: v1(15.97,34.15) v1(15.96,33.55) v5(56.99,10.77) v6(52.13,1.79) v6(52.77,1.79) v6(53.41,1.79) v6(54.04,1.79)
+5VS_AUDIO: length 1
  TOP w0.102: v1(28.26,16.53) 27.57,16.53 v5(27.37,16.72)
  vias: v1(20.15,19.15) v1(20.69,20.01) v1(28.25,17.14)
+5VS_KBL: length 15.8
  TOP w0.102: v1(153.04,11.67) v5(153.04,12.54)
  BOTTOM w0.305: 158.5,9 158.25,9.25 JBL1.4
  BOTTOM w0.381: 152.55,11.24 152.98,11.67 v1(153.04,11.67) 154.25,11.67 154.98,12.4 156.56,12.4 R950.2 157.5,12.89 158.97,12.89 160.84,11.02 160.84,9.52 160.32,9 158.5,9
+5VS_LDO-IN: length 5.7
  TOP w0.102: v2(23.64,16.53) 23.04,16.53 22.5,17.08 22.5,18.16 22.22,18.44 RA2.1
  TOP w0.508: CA37.1 23.44,19.24 CA36.1 22.35,19.1 RA2.1
+V1.05A_AOSCSUS: length 15.8
  TOP w0.508: v1(169.31,55.69) 169.31,56.63 169.12,56.82 CH1240.1
  IN1 w0.508: v7(158.17,50.71) 157.76,50.71 v3(157.7,50.76)
  IN2 w0.508: v3(165,53.75) 166.03,53.75 167.34,55.06 168.69,55.06 v1(169.31,55.69)
  IN4 w0.508: v3(157.7,50.76) 157.71,50.76 158.87,50.76 v4(158.87,50.76)
  BOTTOM w0.254: v1(169.31,55.69) 169.79,56.17 172.02,56.17 173.15,57.29 173.85,57.29 v2(174.44,57.88) 175.48,57.88 L63.1
+V1.05A_AOSCSUS_L: length 1.1
  BOTTOM w0.254: L63.2 177.2,57.77 RH406.1
+V1.05A_DCPSUS: length 27.8
  TOP w0.109: v1(165.28,58.03) 166.05,58.03 v2(167.06,59.04)
  IN1 w0.254: v3(158.87,57.84) 159.53,58.5 160.34,58.5 160.65,58.81 163.94,58.81 164.31,58.44 164.5,58.44 164.91,58.03 v1(165.28,58.03)
  IN4 w0.254: v4(155.85,47.67) 155.85,48.09 v4(157.57,49.81) 157.16,50.22 156.48,50.22 155.47,51.24 155.47,54.57 155.64,54.75 155.64,55.94 156.1,56.39 v4(156.1,57.16) 157.48,57.16 158.16,57.84 v3(158.87,57.84)
  BOTTOM w0.254: UCPU1.J13 v4(156.1,57.16) ; v4(157.57,49.81) UCPU1.AD10 UCPU1.AD8 ; UCPU1.AH13 v4(155.85,47.67)
  BOTTOM w0.381: v1(165.28,58.03) 166.64,58.03 RH405.2
+V1.05S_APLLOPI:
  vias: v1(152.88,51.74) v1(153.51,51.74) v2(143.47,62.92)
+V1.05S_ASATA3PLL: length 29.4
  IN4 w0.381: v4(155.92,66.02) 155.92,65.54 156.42,65.05 161.07,65.05 161.51,64.6 165.28,64.6 165.73,64.16 168.17,64.16 169.46,65.45 169.8,65.45 170.26,65.91 177.84,65.91 178.19,65.57 v3(179.04,65.57)
  BOTTOM w0.254: 156.53,63.58 156.53,63.17 156.34,62.98 UCPU1.A12 156.34,62.78 156.76,62.36 UCPU1.B11
  BOTTOM w0.381: 156.53,63.58 156.53,64.8 v2(156.33,65.01) 155.92,65.41 v4(155.92,66.02)
  vias: v3(179.58,65.57) v3(180.07,65.54) v4(179.28,66) v4(179.7,66) v4(180.14,66) v7(178.94,65.16) v7(179.32,65.16) v7(179.7,65.16)
+V1.05S_AUSB3PLL: length 45.6
  TOP w0.254: v1(148.25,63.84) 148.01,64.08 148.01,65.06 147.73,65.34 RH338.1
  TOP w0.508: CH1209.1 179.75,58.15 v6(178.99,58.91) 179.32,59.24 LH10.2 ; v7(151.44,61.37) v2(149.84,62.97) 148.8,62.97 148.65,63.13
  IN1 w0.381: v3(151.83,61.37) v7(151.44,61.37)
  IN3 w0.508: v1(148.25,63.84) 148.25,63.41 148.53,63.13 165.91,63.13 170.12,58.91 v6(178.99,58.91)
  IN4 w0.381: v4(152.42,61.6) 152.01,61.6 151.83,61.43 v3(151.83,61.37)
  BOTTOM w0.203: UCPU1.B27 147.62,62.29 148,62.67 148,63.1 148.14,63.24 148.14,63.74 148.24,63.84 v1(148.25,63.84)
  BOTTOM w0.305: UCPU1.B18 152.59,61.77 v4(152.42,61.6)
  BOTTOM w0.508: CH1208.1 179.09,59.34 178.99,59.24 v6(178.99,58.91)
+V1.05S_AXCK_DCB: length 2.1
  TOP w0.508: v1(152.81,57.88) 153.12,57.56 CH1229.1
  BOTTOM w0.254: 152.83,57.88 152.86,57.91 152.86,57.92 153.19,57.59 UCPU1.J18 ; 152.83,57.88 152.79,57.84 152.79,57.14 UCPU1.K19 ; 152.83,57.88 v1(152.81,57.88)
  vias: v2(155.05,62.97)
+V1.05S_AXCK_DCB_L: length 2.2
  TOP w0.109: L61.1 v2(159.31,62.94)
+V1.05S_AXCK_LCPLL: length 16.1
  TOP w0.508: L62.2 157.09,67.93 v1(157.04,67.88) ; v1(148.28,66.12) 148.28,66.01 148.57,65.72 RH113.2
  BOTTOM w0.203: UCPU1.A20 152.34,63.22 152.34,64.04 153.13,64.83 153.13,65.72
  BOTTOM w0.508: v1(148.28,66.12) 148.28,65.97 148.53,65.72 v2(150.82,65.72) 153.13,65.72 153.13,66.48 154.58,67.93 CH1231.1 155.12,68.18 155.82,68.18 CH1230.1 156.48,68.44 v1(157.04,67.88)
+V1.05S_AXCK_LCPLL_L: length 3.3
  TOP w0.109: L62.1 158.34,69.2 v2(156.88,69.2)
+V1.05VS_VCCHSIO:
  vias: v1(159.18,57.06) v1(159.18,56.07) v1(159.78,57.08) v2(159.52,56.57) v6(175.71,65.15) v6(176.4,65.15) v6(177.03,65.16) v6(177.67,65.16)
+V18R: length 3.4
  TOP w0.102: v2(213.86,54.72) 213.04,55.55 C293.1
  TOP w0.508: v1(211.85,56.52) 211.87,56.52 212.13,56.26 212.13,56.07 C293.1
  BOTTOM w0.203: v1(211.85,56.52) 211.85,55.94 U34.L1
+VCC_CORE: length 107.8
  TOP w0.508: v6(112.17,51.44) 112.17,51.91 PC804.1 ; v6(115.75,48.4) 115.75,48.84 PC809.1 115.41,49.26 MC1269.1 ; v6(108.67,48.4) 108.67,48.81 PC821.1 ; PC817.1 114.03,55.14 v6(114.03,54.75) ; MC1271.1 128.29,51.72 v1(129.23,50.78) ; MC1272.1 114.86,51.42 v6(113.99,51.42) 113.99,51.88 PC803.1 ; PC822.1 106.86,51.89 v6(106.86,51.42) ; PC810.1 113.95,48.87 v6(113.95,48.4) ; MC1270.1 123.2,53.31 v5(124.4,53.31) 129.22,53.31 v1(129.23,53.32) ; v6(112.2,54.72) 112.2,55.19 PC815.1 ; v6(110.39,51.42) 110.39,51.91 PC807.1 ; v6(106.93,54.78) 106.93,55.13 PC824.1 ; v6(112.22,48.4) 112.22,48.81 PC811.1 ; PC823.1 108.62,51.91 v6(108.62,51.37) ; PC825.1 108.67,55.16 v6(108.67,54.67) ; PC816.1 110.45,55.16 v6(110.45,54.75) ; v6(106.91,48.37) 106.91,48.79 PC801.1 ; v6(110.45,48.42) 110.45,48.81 PC814.1
  BOTTOM w0.102: 138.51,59.71 138.51,59.57 UCPU1.G41 ; UCPU1.G29 146.45,59.57 146.45,59.64 ; UCPU1.G29 146.48,59.12 ; UCPU1.G29 146.04,59.56 146.04,59.72 ; UCPU1.G29 146.08,59.2 146.08,59.01 ; UCPU1.G37 141.43,59.16 141.43,59.03 ; UCPU1.G37 141.41,59.54 141.41,59.7 ; UCPU1.G37 141.13,59.27 141.13,59.01 ; UCPU1.G37 141,59.58 141,59.75 ; UCPU1.F28 147.13,59.49 147.13,59.38 ; UCPU1.F28 146.7,59.92 146.6,59.92 ; UCPU1.F28 146.67,59.43 ; UCPU1.F28 147.19,59.95 ; 150.46,58.31 150.46,58.53 UCPU1.H23 ; 128.55,53.79 128.55,53.58 UCPU1.U57 ; UCPU1.G47 135.28,59.56 135.28,59.73 ; UCPU1.G47 135.23,59.22 135.23,59.02 ; UCPU1.G47 134.84,59.6 ; UCPU1.G47 134.82,59.1 ; 137.77,59.71 137.77,59.55 UCPU1.G43 ; 130.17,59.01 130.17,59.26 UCPU1.G55 ; UCPU1.G53 131.07,59.24 131.07,59.01 ; UCPU1.G53 131.4,59.57 131.4,59.71 ; UCPU1.G53 130.98,59.57 130.98,59.76 ; UCPU1.G53 131.43,59.13 ; UCPU1.F44 136.63,59.42 ; UCPU1.F44 137.15,59.94 ; UCPU1.F44 137.09,59.5 137.09,59.33 ; UCPU1.F44 136.62,59.97 ; 144.91,59.69 144.91,59.57 UCPU1.G31 ; UCPU1.AG57 128.56,48.39 128.56,48.62 ; UCPU1.AG57 128.4,48.23 128.19,48.44 128.19,48.57 ; UCPU1.AG57 128.27,48.1 128.27,47.88 ; UCPU1.AG57 128.64,48 ; 128.23,55.07 128.23,54.91 UCPU1.P57 ; UCPU1.G31 145.19,59.28 145.19,59.01 ; UCPU1.G31 144.92,59.17 144.76,59.17 ; UCPU1.G31 145.28,59.53 145.28,59.71 ; UCPU1.G33 143.89,59.53 143.89,59.69 ; UCPU1.G33 143.68,59.31 143.68,59.02 ; UCPU1.G33 143.55,59.55 143.55,59.72 ; UCPU1.G33 143.99,59.11 ; UCPU1.F36 141.65,59.42 ; UCPU1.F36 142.21,59.98 ; UCPU1.F36 142.16,59.44 ; UCPU1.F36 141.66,59.94 ; 128.62,57.64 128.62,57.56 UCPU1.K57 ; UCPU1.G43 137.38,59.58 137.38,59.7 ; UCPU1.G43 137.29,59.06 ; UCPU1.G43 137.74,59.22 137.74,59.01 ; 149.91,59.68 149.91,59.58 UCPU1.G23 ; 144.6,59.36 144.6,59.51 UCPU1.F32 ; 128.98,59.15 128.9,59.15 UCPU1.G57 ; 140.24,59.02 140.24,59.22 UCPU1.G39 ; UCPU1.G27 147.35,59.1 ; UCPU1.G27 147.78,59.53 147.78,59.7 ; UCPU1.G27 147.75,59.24 147.75,59.01 ; UCPU1.G27 147.38,59.61 ; 128.56,57.04 128.56,57.18 UCPU1.K57 ; 144.11,59.89 144.22,59.89 UCPU1.F32 ; 132.36,59.68 132.36,59.58 UCPU1.G51 ; UCPU1.G55 129.79,59.09 ; UCPU1.G55 129.88,59.55 129.88,59.72 ; UCPU1.G55 130.29,59.58 130.29,59.71 ; UCPU1.U57 128.29,53.55 128.29,53.78 ; UCPU1.U57 128.67,53.16 ; UCPU1.U57 128.24,53.27 128.24,53.1 ; UCPU1.F24 149.15,59.4 ; UCPU1.F24 149.68,59.44 ; UCPU1.F24 149.7,59.95 ; UCPU1.F24 149.17,59.96 ; UCPU1.AB57 128.58,50.65 128.58,50.52 ; UCPU1.AB57 128.62,51.05 128.62,51.16 ; UCPU1.AB57 128.18,50.61 ; UCPU1.AB57 128.22,51.02 128.22,51.18 ; UCPU1.P57 128.58,54.92 128.58,55.06 ; UCPU1.P57 128.17,54.5 ; UCPU1.P57 128.64,54.5 ; 132.06,59.34 132.06,59.51 UCPU1.F52 ; 128.19,56.32 128.19,56.25 UCPU1.M57 ; UCPU1.G23 150.31,59.18 150.31,59.03 ; UCPU1.G23 149.84,59.08 ; UCPU1.G23 150.31,59.55 150.31,59.71 ; UCPU1.G51 132.78,59.56 132.78,59.72 ; UCPU1.G51 132.27,59.06 ; UCPU1.G51 132.69,59.25 132.69,59.03 ; UCPU1.F52 131.61,59.41 ; UCPU1.F52 131.65,59.92 131.59,59.92 ; UCPU1.F52 132.14,59.95 ; UCPU1.G45 136.41,59.56 136.41,59.69 ; UCPU1.G45 136.05,59.52 136.05,59.71 ; UCPU1.G45 136.46,59.11 ; UCPU1.G45 136.18,59.33 136.18,59.01 ; UCPU1.H23 150.04,58.34 ; UCPU1.H23 150.12,58.87 ; UCPU1.H23 150.46,58.75 150.46,58.98 ; UCPU1.M23 150.48,56.07 150.48,55.84 ; UCPU1.M23 150.55,56.41 150.55,56.51 ; UCPU1.M23 150.07,55.92 ; UCPU1.M23 150.12,56.43 150.12,56.53 ; UCPU1.G49 133.64,59.3 133.64,59.02 ; UCPU1.G49 133.88,59.54 133.88,59.69 ; UCPU1.G49 133.51,59.55 133.51,59.71 ; UCPU1.G49 133.98,59.08 ; UCPU1.G57 128.8,59.48 128.8,59.74 ; UCPU1.G57 128.47,59.58 128.47,59.73 ; UCPU1.G57 128.69,59.36 128.69,58.96 ; UCPU1.F48 134.15,59.44 ; UCPU1.F48 134.16,59.92 134.16,59.97 ; UCPU1.F48 134.6,59.48 134.6,59.36 ; UCPU1.F48 134.65,59.95 ; 148.65,58.99 148.65,59.26 UCPU1.G25 ; UCPU1.K57 128.22,57.52 128.22,57.65 ; UCPU1.K57 128.15,57.09 ; 129.11,59.42 UCPU1.F56 ; UCPU1.F56 129.11,59.96 ; UCPU1.F56 129.6,59.91 129.68,59.91 ; UCPU1.F56 129.65,59.41 ; 139.61,59.37 139.61,59.48 UCPU1.F40 ; UCPU1.M57 128.62,56.26 128.62,56.3 ; UCPU1.M57 128.2,55.84 128.2,55.72 ; UCPU1.M57 128.62,55.82 128.62,55.73 ; UCPU1.F32 144.16,59.43 ; UCPU1.F32 144.63,59.9 144.72,59.9 ; UCPU1.G39 139.9,59.56 139.9,59.68 ; UCPU1.G39 139.84,59.1 ; UCPU1.G39 140.28,59.54 140.28,59.71 ; UCPU1.K23 150.53,56.83 150.53,56.66 ; UCPU1.K23 150.11,56.78 ; UCPU1.K23 150.47,57.14 150.47,57.46 ; UCPU1.K23 150.07,57.29 ; UCPU1.G35 142.78,59.54 142.78,59.72 ; UCPU1.G35 142.73,59.24 142.73,59.02 ; UCPU1.G35 142.43,59.53 142.43,59.7 ; UCPU1.G35 142.3,59.06 ; UCPU1.AD57 128.14,49.27 ; UCPU1.AD57 128.6,49.34 128.6,49.22 ; UCPU1.AD57 128.66,49.79 ; UCPU1.AD57 128.2,49.73 128.2,49.84 ; UCPU1.F40 139.13,59.42 ; UCPU1.F40 139.15,59.95 ; UCPU1.F40 139.66,59.94 ; UCPU1.J23 150.09,58.08 ; UCPU1.J23 150.06,57.55 ; UCPU1.J23 150.46,57.94 150.46,58.17 ; UCPU1.J23 150.47,57.7 150.47,57.46 ; UCPU1.W57 128.2,52.33 128.2,52.47 ; UCPU1.W57 128.62,52.35 128.62,52.43 ; UCPU1.W57 128.15,51.88 ; UCPU1.W57 128.62,51.92 128.62,51.83 ; UCPU1.G41 138.71,59.36 138.71,59.02 ; UCPU1.G41 138.88,59.53 138.88,59.7 ; UCPU1.G41 139.01,59.07 ; UCPU1.G25 149.03,59.08 ; UCPU1.G25 149.04,59.66 ; UCPU1.G25 148.54,59.57 148.54,59.71
  BOTTOM w0.254: UCPU1.F59 127.55,59.34 127.84,59.05 v1(127.84,59.02)
  BOTTOM w0.508: v6(108.67,54.67) 108.67,55.16 PC825.1 ; PC804.1 112.17,51.91 v6(112.17,51.44) ; v6(108.67,48.4) 108.67,48.81 PC821.1 ; PC814.1 110.45,48.81 v6(110.45,48.42) ; PC813.1 112.2,55.2 v6(112.2,54.72) ; v6(106.86,51.42) 106.86,51.89 PC822.1 ; v6(110.45,54.75) 110.45,55.18 PC820.1 ; v6(112.22,48.4) 112.22,48.81 PC811.1 ; v1(118.84,64.19) 119.4,64.19 RC97.1 ; PC812.1 114.03,55.15 v6(114.03,54.75) ; v6(106.93,54.78) 106.93,55.13 PC824.1 ; v6(110.39,51.42) 110.39,51.91 PC807.1 ; v6(106.91,48.37) 106.91,48.79 PC801.1 ; PC823.1 108.62,51.91 v6(108.62,51.37)
  vias: v1(129.23,56.88) v1(129.23,55.99) v1(129.23,55.1) v1(129.23,54.21) v1(129.23,52.56) v1(129.23,51.67) v1(129.48,58.78) v1(130.12,58.78) v1(131.26,58.78) v1(132.53,58.78) v1(133.8,58.78) v1(134.4,60.26) v1(135.07,58.78) v1(136.21,58.78) v1(136.9,60.26) v1(137.61,58.78) v1(138.88,58.78) v1(139.38,60.26) v1(139.9,58.78) v1(141.29,58.78) v1(141.92,60.26) v1(141.88,58.78) v1(142.46,58.78) v1(144.09,58.78) v1(144.72,58.78) v1(146.25,58.78) v1(146.88,58.78) v1(147.52,58.78) v1(148.79,58.78) v1(149.42,58.78) v1(149.68,57.77) v1(149.68,56.62) v6(103.64,50.02) v6(103.64,49.39) v6(103.63,48.75) v6(103.63,48.12) v6(103.63,47.48) v6(103.63,46.85) v6(103.96,46.27) v6(104.27,50.02) v6(104.27,49.39) v6(104.26,48.75) v6(104.26,48.12) v6(104.26,47.48) v6(104.27,46.85) v6(104.59,46.27) v6(104.91,50.02) v6(104.91,49.39) v6(104.9,48.75) v6(104.91,48.12) v6(104.91,47.48) v6(104.91,46.85)
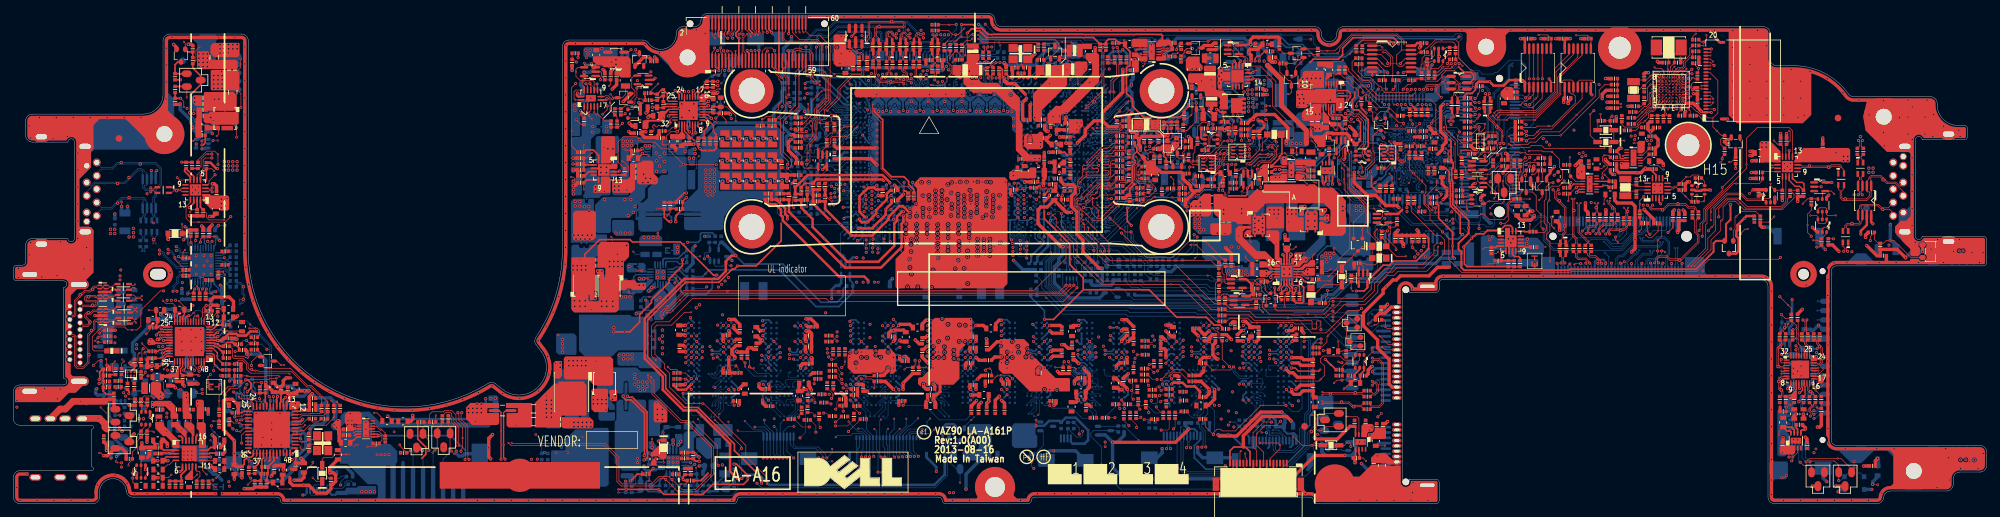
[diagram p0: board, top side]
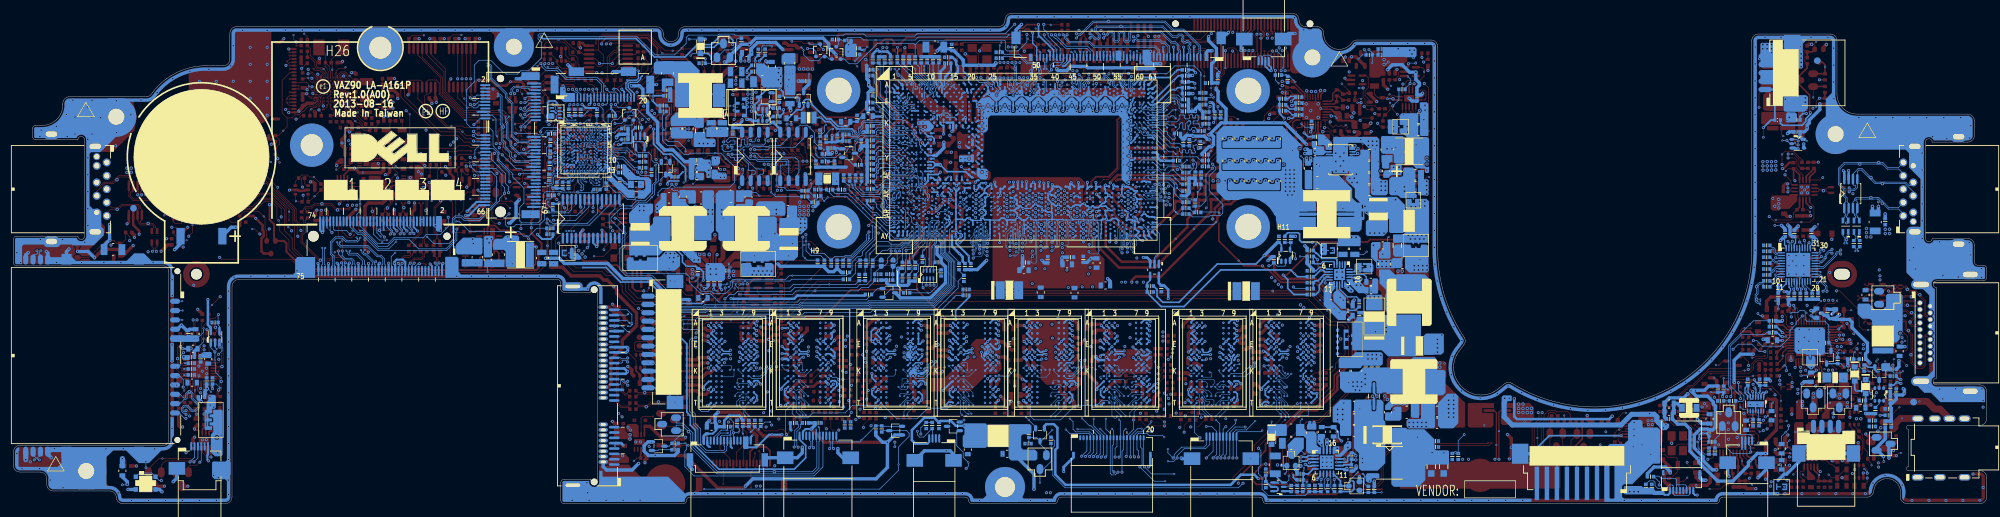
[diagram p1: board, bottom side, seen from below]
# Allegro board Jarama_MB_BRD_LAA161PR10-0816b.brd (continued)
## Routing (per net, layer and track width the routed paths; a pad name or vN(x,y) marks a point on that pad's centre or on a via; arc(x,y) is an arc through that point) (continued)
+VCCIO_OUT: length 8.1
  BOTTOM w0.254: CH1241.1 121.08,65.03 v2(121.39,64.71) 122.23,63.88 126.5,63.88 UCPU1.A59
+VCCIOA_OUT: length 3.4
  TOP w0.508: v7(152.25,59.88) 152.15,59.77 v2(152.15,58.89) RC36.2
  IN1 w0.508: v3(152.7,60.14) 152.52,60.14 v7(152.25,59.88)
  IN4 w0.508: v4(152.29,60.2) 152.64,60.2 v3(152.7,60.14)
+VCCP_D: length 2.3
  BOTTOM w0.102: v2(198.42,48.45) 198.42,48.6 Q4.1
  BOTTOM w0.508: Q4.1 197.06,49.33 R297.2
AGND: length 58.7
  TOP w0.109: CA34.2 20.43,26.01 v5(19.88,25.46) ; v5(25.03,17.1) 24.64,17.1 24.36,17.38 v1(24.24,17.38) ; v1(29.11,18.14) 29.11,18.99 v5(29.48,19.36)
  TOP w0.203: UA2.22 24.94,28.01 v7(24.96,28.02) ; UA2.28 22.01,25.3 v1(21.99,25.27) ; v1(26.21,20.38) 26.14,20.44 UA2.42
  TOP w0.254: U4.20 25.31,9.89 25.1,10.09 v8(24.75,10.09) ; U4.12 v1(29.51,7) ; U4.16 27.31,10.01 27.45,10.16 v8(27.45,10.36) ; UA3.A2 v8(17.59,18.88)
  TOP w0.381: v1(20.91,27.01) 20.43,26.53 CA34.2 ; QA6.4 v1(19.76,5.09) ; QA6.1 v1(18.46,4.6) ; QA3.1 v1(20.46,12.93)
  TOP w0.508: C27.2 20.92,9.23 21.2,8.95 21.2,8.41 ; RA25.2 20.06,21.59 CA67.2 20.69,20.62 v1(20.76,20.68) ; RA69.2 v1(21.65,3.89) ; C21.2 21.2,8.41 ; 21.2,8.41 RA20.2 19.34,8.41 CA57.2 v1(19.23,9.15) ; v1(29.5,5.75) 30.06,5.18 RA68.2 ; CA36.2 23.92,17.7 v1(24.24,17.38) ; CA37.2 CA40.1 25.33,17.89 v1(25.58,17.64) ; v1(18.09,10.44) 18.04,10.44 17.35,9.75 DA5.1 ; C46.2 v1(21.61,6.43) ; v8(30.99,8.44) 31.57,9.01 C43.2 ; CA56.1 v1(29.15,13.41) ; CA45.1 v1(27.63,17.95)
  GND1 w0.203: 7,3.28 JHP1.7 ; JHP1.7 8.08,3.95 ; JHP1.7 8.08,3.28 ; JHP1.7 5.92,3.28 ; JHP1.7 5.92,3.95
  IN1 w0.254: v3(25.37,28.18) 25.22,28.02 v7(24.96,28.02)
  VCC w0.203: JHP1.7 8.08,3.28 ; JHP1.7 5.92,3.28 ; JHP1.7 5.92,3.95 ; JHP1.7 8.08,3.95 ; JHP1.7 7,3.28
  GND2 w0.203: JHP1.7 8.08,3.95 ; JHP1.7 5.92,3.28 ; JHP1.7 7,3.28 ; JHP1.7 5.92,3.95 ; JHP1.7 8.08,3.28
  GND3 w0.203: JHP1.7 8.08,3.28 ; JHP1.7 7,3.28 ; JHP1.7 5.92,3.95 ; JHP1.7 8.08,3.95 ; JHP1.7 5.92,3.28
  BOTTOM w0.381: CA46.2 22.66,28.9 v1(23.16,28.41)
  BOTTOM w0.508: v1(20.76,20.68) 20.76,21.62 CA74.2 ; v1(14.61,6.83) 14.61,8.75 DA2.1 ; v1(26.28,28.94) 25.79,28.94 CA51.2 ; v10(23.81,29.14) 23.79,29.13 CA46.2 ; CA39.1 27.31,18.27 v1(27.63,17.95)
  vias: v1(0.53,14.46) v1(0.53,2.42) v1(1.01,0.49) v1(2.03,4.43) v1(3.55,0.49) v1(6.09,0.49) v1(8.63,0.49) v1(11.17,0.49) v1(12.62,2.79) v1(15.21,4.25) v1(17.02,3.07) v1(18.15,1.49) v1(18.45,23.83) v1(18.45,23.22) v1(20.02,1.49) v1(22.56,1.49) v1(25.1,1.49) v1(25.52,7.87) v1(25.52,7.29) v1(25.51,6.68) v1(26.1,7.86) v1(26.1,7.27) v1(26.09,6.66) v1(26.7,7.87) v1(26.7,7.29) v1(26.69,6.68) v1(27.64,1.49) v1(29.11,17.53) v1(29.86,3.53) v1(30.18,1.49) v3(25.67,28.8) v8(14.37,17.45) v8(15.22,17.51) v8(16.19,19.34) v8(17.35,13.19) v8(19.16,11.86) v8(20.06,15.68) v8(20.19,27.54) v8(21.44,14.08) v8(24.26,2.47) v8(24.86,14.12) v8(25.15,2.47) v8(26.3,2.48) v8(26.9,14.09) v8(27.44,2.47) v8(28.33,2.47) v9(13.53,17.2) v9(14.29,11.46) v9(14.45,19.11) v9(15.42,17.32) v9(16.64,11.57) v9(16.72,15.42) v9(19.53,14.37) v9(21.45,18.65) v9(22.04,14.18) v9(25.98,14.18)
AV12: length 3.8
  TOP w0.203: U1.10 266.4,17.33 v6(266.3,17.23)
  BOTTOM w0.102: v6(266.3,17.23) 266.19,17.23 v2(265.73,16.77)
  BOTTOM w0.508: RR11.1 266.69,16.34 266.62,16.42 266.62,16.91 v6(266.3,17.23) 266.38,17.31 CR8.2
DV12S: length 2.7
  TOP w0.203: 268.13,16.29 v2(268.13,16.98) 268.13,17.53 268,17.66 U1.14
  BOTTOM w0.508: v6(267.2,15.3) 267.61,15.71 RR11.2
DV33_18: length 1.4
  IN1 w0.508: v3(269.97,18.55) v7(270.52,18.55)
  IN4 w0.508: v3(269.97,18.55) 269.8,18.55 269.4,18.14 v4(269.25,18.14)
  vias: v2(270.66,19.03)
DVDD-12-SWR:
  vias: v1(42.21,14.99) v1(42.59,14.49) v2(41.85,14.59)
DVDD_25: length 8.8
  TOP w0.109: CA21.1 39.81,2.21 v2(41.46,2.21)
  TOP w0.254: UA1.43 38.91,6.98 39.02,6.87 39.02,6.46 38.1,5.54 CA13.1 38.1,4.61 R1186.1 37.98,3.5 CA14.1 38.16,3.16 CA21.1
DVDD_IO: length 6.1
  TOP w0.102: v2(20.26,29) LH2.2
  TOP w0.203: UA2.25 22.76,26.5
  TOP w0.254: LH2.2 21.36,27.76 CA25.1 21.58,27.02 21.34,26.78 CA34.1 21.63,26.4 21.91,26.68 22.33,26.68 22.51,26.5 22.76,26.5
GND: length 2273.3
  TOP w0.102: v1(264.64,3.89) 265,3.89 v5(265.33,4.23) ; CA1.2 44.82,6.01 v5(44.82,6.21) ; v1(128.88,33.2) v5(129.44,33.2) ; v6(16.2,44.56) v5(16.2,45.23) ; v1(164.11,26.44) v5(165.14,26.44) ; v5(241.06,36.28) 240.84,36.05 v1(240.47,36.05) ; v6(96.45,39.92) v5(96.45,40.52)
  TOP w0.203: PU701.19 101.63,61.78 v6(101.75,61.9) ; U636.B1 246.83,60.33 246.83,60.24 v11(246.62,60.02) ; U636.A7 246.32,63.35 245.86,63.35 v11(245.83,63.38) ; U715.11 192.99,50.07 v1(193.02,50.05) ; v8(98.3,58.71) PU701.29 ; U717.11 U717.15 ; PU701.22 100.43,60.33 v6(100.03,59.93) ; U636.H3 250.23,61.34 250.49,61.59 v1(250.49,61.5) ; PU501.19 196.42,60.18 ; U719.11 v1(170.36,67.73) ; U718.11 v1(235.89,47.92) ; U716.11 v8(242.46,51.84)
  TOP w0.254: U682.3 v8(201.34,35.43) ; v1(107.06,64.91) 107.07,64.92 JXDP.13 ; v8(204.62,52.38) 204.82,52.18 205.09,52.18 RP22.7 ; JAPS.11 v8(185.57,5.29) ; JAPS.5 v8(188.57,5.29) ; v1(182.69,66.35) 182.94,66.1 U673.3 ; v8(110.57,70.49) 110.57,70.59 110.07,71.09 JXDP.26 ; UA1.44 39.41,6.93 v8(39.5,6.84) ; v1(26.32,44.38) 26.99,45.06 US2.14 ; v1(118.38,64.6) 118.57,64.79 JXDP.59 ; U714.3 246.3,45.16 v1(246.53,44.94) ; v1(220.2,53.86) 219.97,54.09 U679.B1 ; JXDP.1 104.07,65.24 104.4,64.91 v1(104.98,64.91) ; JXDP.14 107.07,70.85 106.87,70.65 v8(106.87,70.38) ; U724.5 200.86,7.18 C1304.2 ; JXDP.8 105.57,71 105.52,70.95 105.52,70.57 105.51,70.57 105.51,70.14 105.88,69.78 v8(106.01,69.78) ; U720.5 267.51,10.89 267.65,11.03 268.01,11.03 v1(268.18,11.2) ; JXDP.50 116.07,70.52 v1(116.02,70.47) ; JAPS.9 v8(186.57,5.29) ; RP22.8 v8(205.64,51.68) ; JXDP.20 108.57,71.01 108.12,70.57 108.12,70.15 108.49,69.78 v1(108.6,69.78) 108.57,69.75 JXDP.19 ; v8(111.66,70.65) 111.57,70.74 JXDP.32 ; JXDP.38 113.07,71.09 113.48,70.68 v1(113.48,70.65) ; JXDP.31 111.57,67.95 111.58,67.95 v1(111.58,67.93) ; U663.7 88.67,60.52 v6(88.84,60.69) ; US1.14 v1(265.75,52.91) ; JXDP.49 116.07,67.75 v1(115.92,67.9) ; JXDP.25 110.07,67.51 109.81,67.78 v1(109.81,67.93) ; v1(229.83,63.69) 229.83,63.57 230.1,63.3 U677.7 ; v8(203.36,64.17) U23.7 ; U636.H2 250.18,60.84 v11(250.27,60.74) ; U710.3 197.36,54.47 v8(196.98,54.85) ; JXDP.7 v1(105.57,64.91) ; JAPS.7 v8(187.57,5.29)
  TOP w0.305: JSNRDG.20 254.06,68.16 254.07,68.16 v1(254.09,68.16) ; v8(204.78,41.77) 204.41,42.13 U698.3
  TOP w0.381: v1(251.39,61.46) 251.42,61.43 C979.2 ; v1(276.47,40.39) 276.47,40.89 277.37,41.79 MD74.7 ; DV5.3 14.53,31.73 v1(14.69,31.89) ; DV4.3 v1(12.19,28.18) ; CA12.2 38.58,4.2 v1(38.58,4.08) ; v1(86.54,65.95) 86.54,65.67 86.81,65.4 U697.3 ; R1217.1 29.5,51.11 30.38,50.22 v1(30.55,50.22) ; RD22.2 116.92,48.42 v8(116.49,47.99) ; CH85.2 154.46,45.5 155.03,46.07 v1(155.03,46.24) ; R1253.2 256.43,54.61 256.79,54.61 Q34.3 ; U672.3 v8(120.44,53.2) ; v1(236.24,61.27) 236.05,61.46 236.05,62.42 U671.7
  TOP w0.406: v1(254.82,69.71) 255.36,69.16 JSNRDG.22
  TOP w0.432: JSNRDG.21 v1(256.55,57.66) ; Q367.4 271.36,45.93 v1(271.68,46.26) ; Q366.4 269.93,40.71 v1(269.21,41.44)
  TOP w0.457: U699.3 v1(263.6,45.95)
  TOP w0.508: v1(256.7,53.88) 256.55,53.88 256.53,53.91 256.44,53.91 R1253.2 ; v1(136.83,21.1) 136.83,21.13 136.01,21.96 CD38.2 ; C1301.2 268.41,9.72 v1(268.17,9.97) ; v1(261.88,46.31) 261.35,46.31 C1289.2 ; v6(109.7,48.34) 109.68,48.33 109.68,47.87 PC814.2 ; CD5.2 108.65,14.89 v1(108.51,14.75) ; CD26.1 132.96,21.38 132.65,21.69 v1(132.65,22.1) ; v1(232.67,59.99) 232.68,60 232.68,60.28 233.05,60.65 C1286.2 ; v1(249.89,44) 250.12,43.77 C713.2 ; v1(264.84,9.91) 264.84,9.32 C1297.2 ; v1(33.45,24.64) 33.36,24.64 33.2,24.8 CA33.2 ; CA1.2 43.49,3.92 43.08,3.51 v1(42.02,3.51) ; v1(118.61,22.73) 118.53,22.81 CD18.2 ; v1(143.26,17.12) 143.17,17.21 CD42.2 ; R1120.2 R1119.2 26.38,43.15 v1(26.33,43.19) ; C1162.2 59.47,12.34 59.77,12.64 v1(59.77,13.23) ; C1204.2 249.51,66.74 v1(249.5,66.75) ; v1(259.9,52.81) 260.34,52.81 C962.2 260.22,52.18 v1(259.9,52.18) ; C1228.2 v1(187.64,61.32) ; Q305.3 92.32,61.33 v1(91.27,60.28) ; C1287.2 v1(227.69,69.71) ; CD41.2 144.08,24.36 v1(144.04,24.32) ; PC809.2 115.04,47.85 v6(115.04,48.4) ; CD126.2 173.25,26.75 v1(172.46,26.75) ; R537.2 v1(239.87,58.02) ; MC1267.2 144.44,14.79 v1(144.83,15.18) ; CD125.2 184.86,24.71 v1(184.86,24.31) ; v1(107.3,58.33) 107.09,58.53 PR710.2 ; PC823.2 107.83,51 v6(107.83,51.37) ; CD37.2 142.46,20.92 142.46,20.32 v1(142.45,20.31) ; CR10.2 267.9,13.38 v1(267.86,13.42) ; RD81.2 130.19,19.22 130.89,19.92 v1(130.89,20.31) ; CD4.1 118.6,21 118.11,21 117.81,20.7 v1(117.81,20.32) ; v1(118.61,26.76) 118.84,26.53 CD19.2 ; v1(277.18,39.91) 277.18,40.25 C9.1 ; CR7.2 266.5,13.19 v1(266.76,13.44) ; RD7.2 v1(145.46,17.62) ; CD71.1 192.67,20.73 192.31,21.09 191.36,21.09 v1(191.36,21.09) ; PC803.2 113.24,50.92 v6(113.24,51.42) ; C612.2 90.28,62.8 v1(89.62,62.14) ; RD11.2 177.74,18.33 v1(178.94,17.13) 178.94,16.48 CD69.1 ; v1(144.28,18.66) 144.84,19.22 RD83.2 ; v1(118.62,17.12) 118.29,17.12 118.03,16.87 CD101.2 117.57,17.93 CD21.2 ; PC213.2 95.81,6.38 v1(96.12,6.69) ; CD82.2 176.51,25.95 v1(177.3,25.16) ; CH1211.2 v8(179.05,66.78) ; v1(155.73,14.72) 156.02,15.01 CD49.2 ; v1(155.02,51.16) CH1220.2 CH1223.2 ; R938.2 182.48,27.22 v1(182.13,26.87) ; CD118.2 145.15,26.72 v1(144.04,26.72) ; C720.2 205.24,29.49 v1(205.64,29.89) ; v8(40.25,3.16) 40.25,4.29 CA9.2 ; CD25.1 136.58,17.18 136.22,17.54 v1(136.22,17.88) ; v1(100.54,26.73) 100.52,26.72 CD114.2 ; v6(111.46,54.72) 111.46,54.22 PC815.2 ; PC811.2 111.41,47.93 v6(111.41,48.34) ; R1034.1 v8(136.57,65.86) ; RC60.2 132.34,47.26 v1(131.85,47.74) ; v6(107.91,48.4) 107.91,47.87 PC821.2 ; RD12.2 181.56,25.33 v1(182.29,24.6) ; v1(165.87,17.12) 165.88,17.12 165.88,17.12 165.88,17.1 165.86,17.08 165.51,17.08 165.22,17.38 CD64.2 ; v6(94.7,58.58) 94.93,58.81 PC717.2 ; v6(106.08,51.44) 106.08,50.97 PC822.2 ; CD20.2 109.27,17.88 v1(108.51,17.12) ; CD115.2 100.51,22.82 v1(100.61,22.72) ; v1(88.23,65.08) 88.5,64.82 R1325.1 ; CH1215.2 v11(154.27,52.67) ; v1(166.72,24.32) 166.86,24.32 167.34,24.79 CD98.2 CD61.2 ; v1(132.66,24.51) 132.86,24.3 CD121.2 ; v1(246.03,66.3) 246.22,66.12 C1205.2 ; R1118.2 v1(265.36,55.48) ; R36.2 272.22,38.79 v1(273.18,37.83) ; C1248.2 C1257.2 246.13,53.68 v1(246.13,54.07) 246.13,54.61 C1256.2 ; v1(152.93,63.86) 152.95,63.86 153.64,64.56 CH1228.2 ; C1140.2 208.01,38.97 v1(208.01,38.55) ; CD112.2 110.72,23.15 110.49,23.38 v1(110.07,23.38) 109.85,23.16 RD2.2 RD80.2 108.35,22.72 v1(108.22,22.85) ; R1216.1 v1(264.72,45.45) ; v1(147.87,21.99) 146.85,21.99 CD27.1 ; CD122.2 134.13,26.88 132.65,26.88 v1(132.48,26.72) ; YH2.4 152.04,66.61 v6(152.85,67.42) ; v1(134.97,24.54) 134.99,24.54 135.55,23.97 CD120.2 ; v1(143.25,22.72) 143.17,22.8 CD40.2 ; CH1202.2 244.24,64.61 v1(244.69,64.61) ; CH1235.2 v11(152.13,55.03) ; v8(99.12,53.02) 99.12,53.27 PC715.2 ; PC816.2 109.68,54.22 v6(109.68,54.72) ; v1(61.21,7.97) 60.79,8.39 PD104.1 ; CD83.2 183.81,25.95 v1(184.09,25.95) ; C1243.2 187.18,61.98 v1(187.56,61.98) ; CA4.2 v8(41.62,5.17) ; CD1.1 100.45,17.82 v1(100.57,17.95) ; v1(150.7,67.88) 150.27,68.31 YH2.2 ; R1164.2 v1(260.08,49.64) ; CD106.2 146.93,15.48 147.54,16.09 v1(147.55,16.09) ; CA49.1 30.51,29.75 v1(29.48,29.75) 29.48,29.18 CA24.1 ; CD44.2 145.95,15.38 v1(145.98,15.36) 145.66,15.04 CD103.2 ; v1(111.58,17.96) 111.58,17.5 111.89,17.18 CD2.1 ; v1(155.16,55.23) 154.78,54.85 CH1234.2 154.57,54.52 155.25,53.83 CH1225.2 ; v1(165.86,24.32) 165.86,24.49 CD62.2 ; v6(106.13,48.34) 106.13,47.87 PC801.2 ; CD60.2 156.66,26.72 v1(155.09,26.72) ; v1(269.97,11.49) 270.32,11.49 270.55,11.73 CR20.2 ; v1(191.95,17.12) 192.59,17.76 194.29,17.76 CD86.2 ; v1(144.14,15.43) 143.37,14.67 CD107.2 ; RA13.2 v8(45.22,14.93) ; v1(29.39,43.06) 29.88,43.06 C1172.2 ; C1251.2 210.69,51.79 v8(210.75,51.72) ; v1(133.15,17.12) v5(133.15,18.06) RD6.2 RD82.2 ; CD68.1 174.21,19.19 v11(173.75,19.19) ; CD123.2 186.37,24.62 186.04,24.3 v1(185.72,24.3) ; v1(118.62,24.32) 118.53,24.41 CD17.2 ; v1(191.36,24.32) 191.53,24.48 CD85.2 ; v1(260.17,51.37) 260.22,51.42 C963.2 ; v6(23.99,68.83) 24.43,68.39 PQ102.3 ; C1300.2 268.18,11.36 v1(268.18,11.2) ; v1(159.4,21.03) 159.41,21.03 159.41,21.01 158.87,21.55 CD59.2 ; CD43.2 136.58,15.29 v1(136.82,15.53) CD39.2 ; CH24.2 152.08,65.36 152.08,64.1 151.85,63.86 v1(151.8,63.86) ; CH39.2 158.17,52.56 v11(158.24,52.49) ; CD124.2 171.69,24.07 CD97.2 172.25,23.23 172.48,23 v1(172.48,21.86) ; v6(113.26,48.37) 113.26,47.85 PC810.2 ; CD102.2 119.6,19.6 v11(119.32,19.32) ; v1(159.43,26.71) 158.62,26.71 CD117.2 ; CD46.1 148.12,18.13 147.84,18.41 v1(147.84,18.68) ; PC720.2 92.6,56.61 v6(92.17,57.04) ; CH1209.2 178.05,59.15 v8(177.83,59.37) ; CD104.2 112.56,14.62 112.13,15.05 v1(112.13,15.53) ; R1197.2 v1(229.99,51.9) ; PC807.2 109.68,50.92 v6(109.68,51.42) ; v6(83.76,51.8) PR425.2 ; RD5.2 129.75,18.31 130.52,18.31 v1(131.69,17.13) ; v1(131.7,24.32) 131.9,24.52 CD119.2 ; v6(106.1,54.66) 106.1,54.25 PC824.2 ; CD110.2 159.07,15.22 v1(159.39,15.53) 159.06,15.86 CD65.2 ; v1(156.88,23.83) 157.29,23.83 157.82,23.3 CD58.2 ; CH23.2 149.43,64.99 149.51,64.91 149.51,63.85 v1(149.47,63.81) ; CD28.2 v1(132.51,14.75) ; v1(149.38,46.24) 149.24,46.38 CH1218.2 ; v1(238.26,63.74) 238.72,63.74 238.74,63.71 R1141.2 ; CH47.2 v1(154.92,52.69) ; CD113.2 111.7,25.95 v1(112.21,25.95) ; C1173.2 30.41,47.61 30.08,47.94 v1(29.77,47.94) ; JAPS.19 192.67,2.21 v1(193.36,1.51) ; C1285.2 v1(230.82,69.71) ; v1(107.88,24.34) 108.17,24.63 CD3.1 ; CH1212.2 141.2,64.33 v1(141.66,63.86) ; CD81.2 178.85,24.42 v1(178.95,24.32) 178.95,24.82 179.46,25.33 CD70.1 ; v6(26.19,68.86) 26.64,68.86 PR106.2 ; v1(106.27,20.32) 106.21,20.26 CD16.2 ; PC433.2 84.45,48.08 84.05,47.68 v6(83.8,47.68) ; C721.2 205.33,12 v1(205.66,12.33) ; v1(28.19,41.61) 28.39,41.41 RV33.2 ; PC721.2 92.36,55.53 v1(92.11,55.79) ; C1292.2 v8(239.72,48.32) ; CD93.2 160.95,14.85 v11(161.28,14.52) ; CV796.1 v1(15.23,25.99) ; CA3.2 v1(33.07,3.67) ; C714.2 v1(249.23,43.98) ; v1(129.42,46.23) 129.47,46.19 RC55.2 ; PC804.2 111.49,50.9 v6(111.49,51.42) ; v6(113.26,54.72) 113.26,54.2 PC817.2 ; v1(166.83,19.5) 166.12,18.79 CD63.2 ; v6(107.88,54.69) 107.88,54.25 PC825.2 ; CD111.2 153.33,20.12 153.49,20.28 153.49,20.3 v1(153.5,20.31) ; C1219.2 234.41,51.37 v1(233.72,50.68) ; v1(158.78,17.94) 158.78,18.39 159.23,18.84 CD45.1 ; PC342.2 190.3,39.8 v6(190.3,40.32) ; v1(178.96,21.94) 178.95,21.93 178.06,21.93 177.53,21.4 RD86.2 ; v1(133.2,46.4) 132.34,45.54 RC58.2 ; v1(157.56,57.97) 157.46,57.87 157.46,57.13 CH41.2 ; v1(156.1,55.41) 156.1,55.89 CH1217.2 157.27,56.05 CH40.2 ; MD90.2 v8(126.04,69.86) ; v1(147.87,15.51) 148.33,15.05 CD96.2 ; CD48.1 165.5,21.12 165.06,20.68 v1(165.06,20.31) ; CD15.2 106.21,24.38 v1(106.27,24.32) ; CR5.2 v1(276.88,5.65) ; DA8.1 v1(272.7,2.62) ; C1254.2 v1(238.99,53.49) ; CA14.2 CA15.2 R1187.2 35.87,2.26 v1(34.54,2.26) ; v1(200.78,6.13) 200.78,6.57 C1304.2 ; CD116.2 145.67,24.65 v1(145.6,24.73) ; v1(95.97,66.95) 96.3,66.62 R1161.2 ; v1(33.56,28.15) 33.33,27.92 CA42.1 ; C8.2 280.3,36.18 ; v1(155.23,22.86) 155.37,22.86 155.53,23.02 CD47.1 ; CA27.1 34.04,20.93 v8(34.04,20.05) ; v8(206.66,54.16) 206.86,53.96 C1252.2 ; C979.2 C977.2 ; R1117.2 v1(264.47,55.48) ; DA9.1 v1(269.2,2.62) ; v1(193.12,25.59) 192.79,25.92 CD84.2 ; v1(156.25,19.82) 156.25,19.83 156.56,19.52 RD8.2 RD84.2 ; YA1.4 v1(47.13,9.04) ; CD24.1 v11(127.83,16.85) ; R951.2 v1(83.61,64.93) ; PR213.2 PC216.2 ; RH423.2 v8(200.64,35.34) ; v1(238.32,44.05) 238.3,44.05 238.3,43.84 238.31,43.82 R1035.2 ; C265.2 v1(270.77,54.81) ; v1(178.14,20.32) 178.14,19.82 177.54,19.22 RD85.2 ; v1(107.84,26.72) 107.84,26.26 108.48,25.62 CD14.2 ; CA6.2 v1(34.22,3.89) ; C1298.2 v7(264.39,14.46) ; C1152.2 v7(238.56,61.07)
  GND1 w0.203: 8.12,17.47 JHDMI.20 ; JHDMI.20 8.12,19.23 ; JHDMI.20 9.8,19.23 ; JHDMI.20 9.8,17.47 ; JHDMI.20 11.48,19.23 ; 206.15,24.66 JSATA1.40 ; JSATA1.40 206.15,24.42 ; JSATA1.40 206.15,24.91 ; 284.4,3.27 H18.1 ; H18.1 283.2,6.1 ; H18.1 284.4,6.53 ; H18.1 283.2,3.7 ; H18.1 285.6,3.7 ; H18.1 282.77,4.9 ; H18.1 286.03,4.9 ; H18.1 285.6,6.1 ; H26.1 241.91,66.82 ; H26.1 238.87,69.86 ; H26.1 240.39,70.42 ; H26.1 241.91,69.86 ; H26.1 238.87,66.82 ; H26.1 242.47,68.34 ; H26.1 238.31,68.34 ; H26.1 240.39,66.26 ; 206.15,18.82 JSATA1.26 ; JSATA1.26 206.15,19.06 ; JSATA1.26 206.15,19.31 ; JUSB2.13 12.16,52.6 ; JUSB2.13 10.75,52.6 ; JUSB2.13 12.16,53.55 ; JUSB2.13 12.16,54.5 ; JUSB2.13 10.75,54.5 ; JUSB2.4 10.98,51.43 ; JUSB2.4 11.58,50.05 ; JUSB2.4 10.98,49.87 ; JUSB2.4 10.38,50.05 ; JUSB2.4 11.58,51.25 ; JUSB2.4 10.2,50.65 ; JUSB2.4 10.38,51.25 ; JUSB2.4 11.75,50.65 ; 219.2,67.3 H7.1 ; H7.1 220.4,66.87 ; H7.1 218.77,68.5 ; H7.1 222.03,68.5 ; H7.1 221.6,67.3 ; H7.1 221.6,69.7 ; H7.1 220.4,70.13 ; H7.1 219.2,69.7 ; 282.22,43.05 JUSB1.4 ; JUSB1.4 283.6,43.65 ; JUSB1.4 282.05,43.65 ; JUSB1.4 283.42,43.05 ; JUSB1.4 283.42,44.25 ; JUSB1.4 282.82,44.43 ; JUSB1.4 282.82,42.87 ; JUSB1.4 282.22,44.25 ; 11.7,47.15 JUSB2.7 ; JUSB2.7 13.25,47.15 ; JUSB2.7 11.88,46.55 ; JUSB2.7 12.48,47.93 ; JUSB2.7 13.08,46.55 ; JUSB2.7 12.48,46.38 ; JUSB2.7 11.88,47.75 ; JUSB2.7 13.08,47.75 ; 283.05,39.8 JUSB1.13 ; JUSB1.13 281.64,41.7 ; JUSB1.13 283.05,41.7 ; JUSB1.13 281.64,39.8 ; JUSB1.13 281.64,40.75 ; 288.19,38.35 JUSB1.14 ; JUSB1.14 291.01,39.3 ; JUSB1.14 288.19,39.3 ; JUSB1.14 291.01,38.35 ; JUSB1.14 289.6,38.35 ; 108.11,61.9 H10.1 ; H10.1 112.24,60.16 ; H10.1 110.5,59.51 ; H10.1 108.76,60.16 ; H10.1 112.89,61.9 ; H10.1 108.76,63.64 ; H10.1 110.5,64.29 ; H10.1 112.24,63.64 ; 206.15,22.26 JSATA1.34 ; JSATA1.34 206.15,22.02 ; JSATA1.34 206.15,22.51 ; 2.79,37.95 JUSB2.11 ; JUSB2.11 5.61,37.95 ; JUSB2.11 2.79,38.9 ; JUSB2.11 4.2,37.95 ; JUSB2.11 5.61,38.9 ; 279.9,56.37 H2.1 ; H2.1 281.1,56.8 ; H2.1 281.53,58 ; H2.1 278.27,58 ; H2.1 278.7,56.8 ; H2.1 279.9,59.63 ; H2.1 278.7,59.2 ; H2.1 281.1,59.2 ; H12.1 173.54,63.64 ; H12.1 170.06,60.16 ; H12.1 169.41,61.9 ; H12.1 171.8,64.29 ; H12.1 174.19,61.9 ; H12.1 170.06,63.64 ; H12.1 173.54,60.16 ; H12.1 171.8,59.51 ; H9.1 173.54,43.24 ; H9.1 171.8,39.11 ; H9.1 171.8,43.89 ; H9.1 170.06,39.76 ; H9.1 174.19,41.5 ; H9.1 169.41,41.5 ; H9.1 173.54,39.76 ; H9.1 170.06,43.24 ; 110.5,39.11 H11.1 ; H11.1 112.89,41.5 ; H11.1 112.24,43.24 ; H11.1 108.11,41.5 ; H11.1 112.24,39.76 ; H11.1 110.5,43.89 ; H11.1 108.76,39.76 ; H11.1 108.76,43.24 ; 0.87,34.35 JHDMI.23 ; JHDMI.23 4.03,35.23 ; JHDMI.23 0.87,35.23 ; JHDMI.23 4.03,34.35 ; JHDMI.23 2.45,35.23 ; 206.15,7.06 JSATA1.4 ; JSATA1.4 206.15,7.31 ; JSATA1.4 206.15,6.82 ; 0.87,16.85 JHDMI.22 ; JHDMI.22 4.03,16.85 ; JHDMI.22 4.03,15.97 ; JHDMI.22 2.45,15.97 ; JHDMI.22 0.87,15.97 ; 9.4,28.1 JHDMI.5 ; JHDMI.5 9.52,28.56 ; JHDMI.5 9.52,27.64 ; JHDMI.5 10.56,28.1 ; JHDMI.5 10.44,27.64 ; JHDMI.5 10.44,28.56 ; 249.13,55.26 H15.1 ; H15.1 249.13,52.22 ; H15.1 250.65,55.82 ; H15.1 250.65,51.66 ; H15.1 252.17,55.26 ; H15.1 252.17,52.22 ; H15.1 248.57,53.74 ; H15.1 252.73,53.74 ; H4.1 146.9,4.43 ; H4.1 144.97,2.5 ; H4.1 145.48,3.92 ; H4.1 148.83,2.5 ; H4.1 145.48,1.08 ; H4.1 148.32,1.08 ; H4.1 148.32,3.92 ; H4.1 146.9,0.57 ; JUSB2.14 4.2,55.95 ; JUSB2.14 5.61,55.95 ; JUSB2.14 5.61,55 ; JUSB2.14 2.79,55 ; JUSB2.14 2.79,55.95 ; 281.64,54.5 JUSB1.12 ; JUSB1.12 281.64,53.55 ; JUSB1.12 283.05,54.5 ; JUSB1.12 281.64,52.6 ; 281.32,46.37 JUSB1.7 ; JUSB1.7 281.32,47.92 ; JUSB1.7 280.72,47.75 ; JUSB1.7 281.92,47.75 ; JUSB1.7 282.1,47.15 ; JUSB1.7 280.55,47.15 ; JUSB1.7 281.92,46.55 ; JUSB1.7 280.72,46.55 ; 207.03,15.38 JSATA1.18 ; JSATA1.18 206.15,15.38 ; JSATA1.18 206.15,15.86 ; JUSB2.12 12.16,41.7 ; JUSB2.12 12.16,40.75 ; JUSB2.12 10.75,39.8 ; JUSB2.12 12.16,39.8 ; JHDMI.2 8.89,30.06 ; JHDMI.2 7.97,30.06 ; JHDMI.2 8.43,30.18 ; JHDMI.2 8.89,29.14 ; JHDMI.2 9.01,29.6 ; JHDMI.2 7.97,29.14 ; 288.19,55.4 JUSB1.11 ; JUSB1.11 288.19,56.35 ; JUSB1.11 291.01,55.4 ; JUSB1.11 289.6,56.35 ; JHDMI.11 10.44,24.64 ; JHDMI.11 10.56,25.1 ; JHDMI.11 9.4,25.1 ; JHDMI.11 10.44,25.56 ; JHDMI.11 9.52,24.64 ; JHDMI.11 9.52,25.56 ; H1.1 102.1,68.1 ; H1.1 99.27,66.9 ; H1.1 99.7,65.7 ; H1.1 100.9,65.27 ; H1.1 102.1,65.7 ; H1.1 100.9,68.53 ; H1.1 99.7,68.1 ; H1.1 102.53,66.9 ; 209.92,32.56 JSATA1.54 ; JSATA1.54 209.92,33.38 ; JSATA1.54 211.58,33.38 ; 9.52,21.64 JHDMI.17 ; JHDMI.17 9.4,22.1 ; JHDMI.17 10.44,21.64 ; JHDMI.17 10.56,22.1 ; JHDMI.17 10.44,22.56 ; JHDMI.17 9.52,22.56 ; 22.6,53.77 H6.1 ; H6.1 21.4,56.6 ; H6.1 23.8,56.6 ; H6.1 24.23,55.4 ; H6.1 23.8,54.2 ; H6.1 20.97,55.4 ; H6.1 21.4,54.2 ; H6.1 22.6,57.03 ; JHDMI.21 11.48,32.85 ; JHDMI.21 11.48,31.97 ; JHDMI.21 8.12,31.97 ; JHDMI.21 9.8,31.97 ; JHDMI.21 9.8,33.73 ; JHDMI.21 8.12,33.73 ; JHDMI.21 11.48,33.73 ; 206.15,28.66 JSATA1.50 ; JSATA1.50 206.15,28.91 ; JSATA1.50 206.15,28.42 ; JHDMI.8 8.89,26.14 ; JHDMI.8 8.89,27.06 ; JHDMI.8 9.01,26.6 ; JHDMI.8 7.97,27.06 ; JHDMI.8 7.97,26.14 ; 209.92,1.95 JSATA1.53 ; JSATA1.53 209.92,2.76 ; JSATA1.53 211.58,1.95
  VCC w0.203: JHDMI.2 9.01,29.6 ; JHDMI.2 7.97,29.14 ; JHDMI.2 7.97,30.06 ; JHDMI.2 8.89,29.14 ; JHDMI.2 8.43,30.18 ; JHDMI.2 8.89,30.06 ; JUSB1.4 283.42,43.05 ; JUSB1.4 282.82,42.87 ; JUSB1.4 282.22,44.25 ; JUSB1.4 283.6,43.65 ; JUSB1.4 282.05,43.65 ; JUSB1.4 282.22,43.05 ; JUSB1.4 283.42,44.25 ; JUSB1.4 282.82,44.43 ; 283.2,3.7 H18.1 ; H18.1 285.6,6.1 ; H18.1 284.4,3.27 ; H18.1 286.03,4.9 ; H18.1 282.77,4.9 ; H18.1 284.4,6.53 ; H18.1 283.2,6.1 ; H18.1 285.6,3.7 ; H1.1 102.1,68.1 ; H1.1 99.7,65.7 ; H1.1 99.7,68.1 ; H1.1 100.9,68.53 ; H1.1 99.27,66.9 ; H9.1 174.19,41.5 ; H9.1 170.06,43.24 ; H9.1 171.8,39.11 ; H9.1 170.06,39.76 ; H9.1 173.54,43.24 ; H9.1 173.54,39.76 ; H9.1 169.41,41.5 ; H9.1 171.8,43.89 ; H7.1 221.6,69.7 ; H7.1 221.6,67.3 ; H7.1 219.2,67.3 ; H7.1 220.4,70.13 ; H7.1 219.2,69.7 ; H7.1 218.77,68.5 ; H7.1 220.4,66.87 ; H7.1 222.03,68.5 ; JHDMI.22 4.03,15.97 ; JHDMI.22 2.45,15.97 ; JHDMI.22 0.87,16.85 ; JHDMI.22 0.87,15.97 ; JHDMI.22 4.03,16.85 ; JUSB2.7 13.08,47.75 ; JUSB2.7 13.08,46.55 ; JUSB2.7 11.88,46.55 ; JUSB2.7 13.25,47.15 ; JUSB2.7 11.7,47.15 ; JUSB2.7 12.48,47.93 ; JUSB2.7 12.48,46.38 ; JUSB2.7 11.88,47.75 ; 7.97,26.14 JHDMI.8 ; JHDMI.8 8.89,26.14 ; JHDMI.8 9.01,26.6 ; JHDMI.8 7.97,27.06 ; JHDMI.8 8.89,27.06 ; H6.1 23.8,54.2 ; H6.1 21.4,56.6 ; H6.1 23.8,56.6 ; H6.1 21.4,54.2 ; H6.1 24.23,55.4 ; H6.1 22.6,53.77 ; H6.1 22.6,57.03 ; H6.1 20.97,55.4 ; 288.19,56.35 JUSB1.11 ; JUSB1.11 291.01,55.4 ; JUSB1.11 288.19,55.4 ; JUSB1.11 289.6,56.35 ; 206.15,7.06 JSATA1.4 ; JSATA1.4 206.15,6.82 ; JSATA1.4 206.15,7.31 ; H11.1 110.5,43.89 ; H11.1 110.5,39.11 ; H11.1 108.76,43.24 ; H11.1 112.89,41.5 ; H11.1 112.24,43.24 ; H11.1 108.76,39.76 ; H11.1 108.11,41.5 ; H11.1 112.24,39.76 ; 2.79,37.95 JUSB2.11 ; JUSB2.11 2.79,38.9 ; JUSB2.11 5.61,38.9 ; JUSB2.11 4.2,37.95 ; JUSB2.11 5.61,37.95 ; 281.64,53.55 JUSB1.12 ; JUSB1.12 281.64,54.5 ; JUSB1.12 281.64,52.6 ; JUSB1.12 283.05,54.5 ; JUSB2.13 12.16,53.55 ; JUSB2.13 10.75,54.5 ; JUSB2.13 10.75,52.6 ; JUSB2.13 12.16,52.6 ; JUSB2.13 12.16,54.5 ; 10.2,50.65 JUSB2.4 ; JUSB2.4 11.75,50.65 ; JUSB2.4 10.98,49.87 ; JUSB2.4 11.58,51.25 ; JUSB2.4 10.38,51.25 ; JUSB2.4 11.58,50.05 ; JUSB2.4 10.38,50.05 ; JUSB2.4 10.98,51.43 ; JHDMI.5 10.44,27.64 ; JHDMI.5 9.52,28.56 ; JHDMI.5 9.4,28.1 ; JHDMI.5 10.56,28.1 ; JHDMI.5 9.52,27.64 ; JHDMI.5 10.44,28.56 ; H26.1 241.91,66.82 ; H26.1 241.91,69.86 ; H26.1 240.39,66.26 ; H26.1 240.39,70.42 ; H26.1 242.47,68.34 ; H26.1 238.87,66.82 ; H26.1 238.31,68.34 ; H26.1 238.87,69.86 ; 2.79,55.95 JUSB2.14 ; JUSB2.14 5.61,55 ; JUSB2.14 4.2,55.95 ; JUSB2.14 2.79,55 ; JUSB2.14 5.61,55.95 ; 8.12,17.47 JHDMI.20 ; JHDMI.20 11.48,19.23 ; JHDMI.20 9.8,17.47 ; JHDMI.20 8.12,19.23 ; JHDMI.20 9.8,19.23 ; 0.87,34.35 JHDMI.23 ; JHDMI.23 4.03,35.23 ; JHDMI.23 4.03,34.35 ; JHDMI.23 0.87,35.23 ; JHDMI.23 2.45,35.23 ; JHDMI.11 10.56,25.1 ; JHDMI.11 9.52,24.64 ; JHDMI.11 10.44,24.64 ; JHDMI.11 9.4,25.1 ; JHDMI.11 9.52,25.56 ; JHDMI.11 10.44,25.56 ; 288.19,39.3 JUSB1.14 ; JUSB1.14 291.01,38.35 ; JUSB1.14 289.6,38.35 ; JUSB1.14 288.19,38.35 ; JUSB1.14 291.01,39.3 ; 10.75,39.8 JUSB2.12 ; JUSB2.12 12.16,40.75 ; JUSB2.12 12.16,39.8 ; JUSB2.12 12.16,41.7 ; 281.64,41.7 JUSB1.13 ; JUSB1.13 283.05,39.8 ; JUSB1.13 281.64,39.8 ; JUSB1.13 281.64,40.75 ; JUSB1.13 283.05,41.7 ; H2.1 281.1,56.8 ; H2.1 278.7,59.2 ; H2.1 281.1,59.2 ; H2.1 278.7,56.8 ; H2.1 279.9,59.63 ; H2.1 281.53,58 ; H2.1 279.9,56.37 ; H2.1 278.27,58 ; 281.32,46.37 JUSB1.7 ; JUSB1.7 281.92,47.75 ; JUSB1.7 280.72,47.75 ; JUSB1.7 280.72,46.55 ; JUSB1.7 280.55,47.15 ; JUSB1.7 281.32,47.92 ; JUSB1.7 282.1,47.15 ; JUSB1.7 281.92,46.55 ; JHDMI.21 11.48,32.85 ; JHDMI.21 9.8,31.97 ; JHDMI.21 8.12,31.97 ; JHDMI.21 11.48,31.97 ; JHDMI.21 8.12,33.73 ; JHDMI.21 11.48,33.73 ; JHDMI.21 9.8,33.73 ; JHDMI.17 10.56,22.1 ; JHDMI.17 9.52,22.56 ; JHDMI.17 10.44,21.64 ; JHDMI.17 9.4,22.1 ; JHDMI.17 10.44,22.56 ; JHDMI.17 9.52,21.64 ; 209.92,2.76 JSATA1.53 ; JSATA1.53 211.58,1.95 ; JSATA1.53 209.92,1.95
  GND2 w0.203: H2.1 281.53,58 ; H2.1 278.27,58 ; H2.1 279.9,59.63 ; H2.1 279.9,56.37 ; H2.1 281.1,59.2 ; H2.1 278.7,56.8 ; H2.1 281.1,56.8 ; H2.1 278.7,59.2 ; 281.64,39.8 JUSB1.13 ; JUSB1.13 281.64,41.7 ; JUSB1.13 283.05,39.8 ; JUSB1.13 281.64,40.75 ; JUSB1.13 283.05,41.7 ; H11.1 112.24,39.76 ; H11.1 110.5,39.11 ; H11.1 108.76,43.24 ; H11.1 108.76,39.76 ; H11.1 112.24,43.24 ; H11.1 110.5,43.89 ; H11.1 112.89,41.5 ; H11.1 108.11,41.5 ; 280.55,47.15 JUSB1.7 ; JUSB1.7 281.32,47.92 ; JUSB1.7 281.32,46.37 ; JUSB1.7 282.1,47.15 ; JUSB1.7 281.92,46.55 ; JUSB1.7 280.72,46.55 ; JUSB1.7 281.92,47.75 ; JUSB1.7 280.72,47.75 ; JUSB2.4 11.58,51.25 ; JUSB2.4 10.2,50.65 ; JUSB2.4 10.98,49.87 ; JUSB2.4 11.58,50.05 ; JUSB2.4 10.38,51.25 ; JUSB2.4 10.98,51.43 ; JUSB2.4 11.75,50.65 ; JUSB2.4 10.38,50.05 ; H12.1 173.54,63.64 ; H12.1 169.41,61.9 ; H12.1 174.19,61.9 ; H12.1 171.8,59.51 ; H12.1 170.06,60.16 ; H12.1 171.8,64.29 ; H12.1 173.54,60.16 ; H12.1 170.06,63.64 ; 206.15,22.26 JSATA1.34 ; JSATA1.34 206.15,22.02 ; JSATA1.34 206.15,22.51 ; 206.15,19.31 JSATA1.26 ; JSATA1.26 206.15,19.06 ; JSATA1.26 206.15,18.82 ; 206.15,24.42 JSATA1.40 ; JSATA1.40 206.15,24.66 ; JSATA1.40 206.15,24.91 ; H15.1 250.65,55.82 ; H15.1 252.73,53.74 ; H15.1 249.13,55.26 ; H15.1 252.17,55.26 ; H15.1 252.17,52.22 ; H15.1 250.65,51.66 ; H15.1 248.57,53.74 ; H15.1 249.13,52.22 ; 238.87,66.82 H26.1 ; H26.1 242.47,68.34 ; H26.1 238.31,68.34 ; H26.1 238.87,69.86 ; H26.1 240.39,66.26 ; H26.1 241.91,66.82 ; H26.1 240.39,70.42 ; H26.1 241.91,69.86 ; JUSB2.14 4.2,55.95 ; JUSB2.14 5.61,55 ; JUSB2.14 5.61,55.95 ; JUSB2.14 2.79,55.95 ; JUSB2.14 2.79,55 ; 7.97,29.14 JHDMI.2 ; JHDMI.2 8.89,30.06 ; JHDMI.2 8.89,29.14 ; JHDMI.2 8.43,30.18 ; JHDMI.2 9.01,29.6 ; JHDMI.2 7.97,30.06 ; 21.4,54.2 H6.1 ; H6.1 24.23,55.4 ; H6.1 23.8,54.2 ; H6.1 23.8,56.6 ; H6.1 22.6,53.77 ; H6.1 21.4,56.6 ; H6.1 20.97,55.4 ; H6.1 22.6,57.03 ; 2.45,15.97 JHDMI.22 ; JHDMI.22 0.87,16.85 ; JHDMI.22 4.03,16.85 ; JHDMI.22 0.87,15.97 ; JHDMI.22 4.03,15.97 ; 281.64,52.6 JUSB1.12 ; JUSB1.12 283.05,54.5 ; JUSB1.12 281.64,53.55 ; JUSB1.12 281.64,54.5 ; JUSB2.13 12.16,53.55 ; JUSB2.13 12.16,52.6 ; JUSB2.13 10.75,52.6 ; JUSB2.13 10.75,54.5 ; JUSB2.13 12.16,54.5 ; H18.1 284.4,6.53 ; H18.1 285.6,6.1 ; H18.1 284.4,3.27 ; H18.1 282.77,4.9 ; H18.1 283.2,3.7 ; H18.1 286.03,4.9 ; H18.1 283.2,6.1 ; H18.1 285.6,3.7 ; 169.41,41.5 H9.1 ; H9.1 170.06,43.24 ; H9.1 170.06,39.76 ; H9.1 173.54,39.76 ; H9.1 174.19,41.5 ; H9.1 171.8,39.11 ; H9.1 173.54,43.24 ; H9.1 171.8,43.89 ; JHDMI.5 10.44,28.56 ; JHDMI.5 9.4,28.1 ; JHDMI.5 9.52,27.64 ; JHDMI.5 9.52,28.56 ; JHDMI.5 10.56,28.1 ; JHDMI.5 10.44,27.64 ; 288.19,38.35 JUSB1.14 ; JUSB1.14 291.01,38.35 ; JUSB1.14 288.19,39.3 ; JUSB1.14 291.01,39.3 ; JUSB1.14 289.6,38.35 ; 288.19,56.35 JUSB1.11 ; JUSB1.11 289.6,56.35 ; JUSB1.11 288.19,55.4 ; JUSB1.11 291.01,55.4 ; 209.92,32.56 JSATA1.54 ; JSATA1.54 211.58,33.38 ; JSATA1.54 209.92,33.38 ; 110.5,59.51 H10.1 ; H10.1 112.24,63.64 ; H10.1 110.5,64.29 ; H10.1 108.11,61.9 ; H10.1 108.76,63.64 ; H10.1 112.89,61.9 ; H10.1 108.76,60.16 ; H10.1 112.24,60.16 ; 146.9,0.57 H4.1 ; H4.1 145.48,1.08 ; H4.1 148.32,1.08 ; H4.1 146.9,4.43 ; H4.1 148.83,2.5 ; H4.1 144.97,2.5 ; H4.1 145.48,3.92 ; H4.1 148.32,3.92 ; JHDMI.23 4.03,35.23 ; JHDMI.23 2.45,35.23 ; JHDMI.23 0.87,35.23 ; JHDMI.23 0.87,34.35 ; JHDMI.23 4.03,34.35 ; JHDMI.21 11.48,32.85 ; JHDMI.21 11.48,31.97 ; JHDMI.21 9.8,33.73 ; JHDMI.21 9.8,31.97 ; JHDMI.21 8.12,33.73 ; JHDMI.21 11.48,33.73 ; JHDMI.21 8.12,31.97 ; 7.97,26.14 JHDMI.8 ; JHDMI.8 9.01,26.6 ; JHDMI.8 7.97,27.06 ; JHDMI.8 8.89,26.14 ; JHDMI.8 8.89,27.06 ; 8.12,17.47 JHDMI.20 ; JHDMI.20 9.8,17.47 ; JHDMI.20 11.48,19.23 ; JHDMI.20 8.12,19.23 ; JHDMI.20 9.8,19.23 ; 206.15,15.38 JSATA1.18 ; JSATA1.18 206.15,15.86 ; JSATA1.18 207.03,15.38 ; JUSB2.12 12.16,40.75 ; JUSB2.12 10.75,39.8 ; JUSB2.12 12.16,41.7 ; JUSB2.12 12.16,39.8 ; 282.22,44.25 JUSB1.4 ; JUSB1.4 283.42,43.05 ; JUSB1.4 282.05,43.65 ; JUSB1.4 283.6,43.65 ; JUSB1.4 282.22,43.05 ; JUSB1.4 283.42,44.25 ; JUSB1.4 282.82,44.43 ; JUSB1.4 282.82,42.87 ; 9.52,21.64 JHDMI.17 ; JHDMI.17 10.44,21.64 ; JHDMI.17 10.44,22.56 ; JHDMI.17 10.56,22.1 ; JHDMI.17 9.4,22.1 ; JHDMI.17 9.52,22.56 ; 220.4,66.87 H7.1 ; H7.1 222.03,68.5 ; H7.1 219.2,69.7 ; H7.1 219.2,67.3 ; H7.1 221.6,69.7 ; H7.1 220.4,70.13 ; H7.1 218.77,68.5 ; H7.1 221.6,67.3 ; JUSB2.11 5.61,37.95 ; JUSB2.11 2.79,37.95 ; JUSB2.11 2.79,38.9 ; JUSB2.11 5.61,38.9 ; JUSB2.11 4.2,37.95 ; 9.52,25.56 JHDMI.11 ; JHDMI.11 10.56,25.1 ; JHDMI.11 10.44,25.56 ; JHDMI.11 9.52,24.64 ; JHDMI.11 9.4,25.1 ; JHDMI.11 10.44,24.64 ; 11.88,47.75 JUSB2.7 ; JUSB2.7 12.48,47.93 ; JUSB2.7 12.48,46.38 ; JUSB2.7 13.08,46.55 ; JUSB2.7 13.25,47.15 ; JUSB2.7 11.88,46.55 ; JUSB2.7 11.7,47.15 ; JUSB2.7 13.08,47.75 ; H1.1 102.1,65.7 ; H1.1 100.9,68.53 ; H1.1 102.1,68.1 ; H1.1 100.9,65.27 ; H1.1 99.7,65.7 ; H1.1 99.7,68.1 ; H1.1 102.53,66.9 ; H1.1 99.27,66.9 ; 209.92,1.95 JSATA1.53 ; JSATA1.53 211.58,1.95 ; JSATA1.53 209.92,2.76 ; 206.15,28.42 JSATA1.50 ; JSATA1.50 206.15,28.66 ; JSATA1.50 206.15,28.91 ; 206.15,6.82 JSATA1.4 ; JSATA1.4 206.15,7.31 ; JSATA1.4 206.15,7.06
  GND3 w0.203: 0.87,16.85 JHDMI.22 ; JHDMI.22 4.03,16.85 ; JHDMI.22 2.45,15.97 ; JHDMI.22 0.87,15.97 ; JHDMI.22 4.03,15.97 ; 8.12,19.23 JHDMI.20 ; JHDMI.20 11.48,19.23 ; JHDMI.20 8.12,17.47 ; JHDMI.20 9.8,17.47 ; JHDMI.20 9.8,19.23 ; JUSB1.11 291.01,55.4 ; JUSB1.11 288.19,55.4 ; JUSB1.11 289.6,56.35 ; JUSB1.11 288.19,56.35 ; JHDMI.8 8.89,27.06 ; JHDMI.8 9.01,26.6 ; JHDMI.8 8.89,26.14 ; JHDMI.8 7.97,27.06 ; JHDMI.8 7.97,26.14 ; H6.1 24.23,55.4 ; H6.1 21.4,54.2 ; H6.1 21.4,56.6 ; H6.1 23.8,56.6 ; H6.1 22.6,57.03 ; H6.1 22.6,53.77 ; H6.1 20.97,55.4 ; H6.1 23.8,54.2 ; JUSB1.13 283.05,41.7 ; JUSB1.13 281.64,41.7 ; JUSB1.13 281.64,40.75 ; JUSB1.13 283.05,39.8 ; JUSB1.13 281.64,39.8 ; JUSB2.12 12.16,40.75 ; JUSB2.12 10.75,39.8 ; JUSB2.12 12.16,39.8 ; JUSB2.12 12.16,41.7 ; 289.6,38.35 JUSB1.14 ; JUSB1.14 291.01,38.35 ; JUSB1.14 291.01,39.3 ; JUSB1.14 288.19,39.3 ; JUSB1.14 288.19,38.35 ; 283.2,3.7 H18.1 ; H18.1 286.03,4.9 ; H18.1 285.6,6.1 ; H18.1 283.2,6.1 ; H18.1 284.4,6.53 ; H18.1 282.77,4.9 ; H18.1 284.4,3.27 ; H18.1 285.6,3.7 ; 209.92,2.76 JSATA1.53 ; JSATA1.53 209.92,1.95 ; JSATA1.53 211.58,1.95 ; 99.7,68.1 H1.1 ; H1.1 102.53,66.9 ; H1.1 99.7,65.7 ; H1.1 102.1,68.1 ; H1.1 100.9,68.53 ; H1.1 102.1,65.7 ; H1.1 99.27,66.9 ; H1.1 100.9,65.27 ; 209.92,32.56 JSATA1.54 ; JSATA1.54 211.58,33.38 ; JSATA1.54 209.92,33.38 ; 10.98,49.87 JUSB2.4 ; JUSB2.4 10.38,50.05 ; JUSB2.4 10.2,50.65 ; JUSB2.4 11.75,50.65 ; JUSB2.4 10.38,51.25 ; JUSB2.4 10.98,51.43 ; JUSB2.4 11.58,51.25 ; JUSB2.4 11.58,50.05 ; 206.15,22.02 JSATA1.34 ; JSATA1.34 206.15,22.51 ; JSATA1.34 206.15,22.26 ; 206.15,18.82 JSATA1.26 ; JSATA1.26 206.15,19.06 ; JSATA1.26 206.15,19.31 ; JUSB2.14 4.2,55.95 ; JUSB2.14 2.79,55.95 ; JUSB2.14 5.61,55 ; JUSB2.14 5.61,55.95 ; JUSB2.14 2.79,55 ; 9.4,28.1 JHDMI.5 ; JHDMI.5 9.52,28.56 ; JHDMI.5 10.56,28.1 ; JHDMI.5 10.44,27.64 ; JHDMI.5 9.52,27.64 ; JHDMI.5 10.44,28.56 ; 145.48,1.08 H4.1 ; H4.1 148.32,1.08 ; H4.1 146.9,4.43 ; H4.1 148.32,3.92 ; H4.1 145.48,3.92 ; H4.1 146.9,0.57 ; H4.1 148.83,2.5 ; H4.1 144.97,2.5 ; JUSB1.4 283.42,44.25 ; JUSB1.4 283.42,43.05 ; JUSB1.4 282.22,44.25 ; JUSB1.4 282.22,43.05 ; JUSB1.4 283.6,43.65 ; JUSB1.4 282.05,43.65 ; JUSB1.4 282.82,44.43 ; JUSB1.4 282.82,42.87 ; 11.7,47.15 JUSB2.7 ; JUSB2.7 13.08,46.55 ; JUSB2.7 12.48,47.93 ; JUSB2.7 13.25,47.15 ; JUSB2.7 11.88,47.75 ; JUSB2.7 13.08,47.75 ; JUSB2.7 12.48,46.38 ; JUSB2.7 11.88,46.55 ; 240.39,66.26 H26.1 ; H26.1 241.91,66.82 ; H26.1 238.87,69.86 ; H26.1 238.87,66.82 ; H26.1 238.31,68.34 ; H26.1 242.47,68.34 ; H26.1 241.91,69.86 ; H26.1 240.39,70.42 ; 279.9,56.37 H2.1 ; H2.1 278.7,59.2 ; H2.1 279.9,59.63 ; H2.1 281.53,58 ; H2.1 281.1,59.2 ; H2.1 278.27,58 ; H2.1 278.7,56.8 ; H2.1 281.1,56.8 ; H11.1 110.5,43.89 ; H11.1 112.24,39.76 ; H11.1 110.5,39.11 ; H11.1 112.24,43.24 ; H11.1 108.76,39.76 ; H11.1 108.76,43.24 ; H11.1 112.89,41.5 ; H11.1 108.11,41.5 ; JUSB1.12 283.05,54.5 ; JUSB1.12 281.64,53.55 ; JUSB1.12 281.64,54.5 ; JUSB1.12 281.64,52.6 ; 0.87,35.23 JHDMI.23 ; JHDMI.23 4.03,35.23 ; JHDMI.23 2.45,35.23 ; JHDMI.23 4.03,34.35 ; JHDMI.23 0.87,34.35 ; H9.1 174.19,41.5 ; H9.1 170.06,43.24 ; H9.1 171.8,39.11 ; H9.1 169.41,41.5 ; H9.1 171.8,43.89 ; H9.1 173.54,43.24 ; H9.1 170.06,39.76 ; H9.1 173.54,39.76 ; H15.1 252.73,53.74 ; H15.1 248.57,53.74 ; H15.1 250.65,55.82 ; H15.1 250.65,51.66 ; H15.1 252.17,52.22 ; H15.1 249.13,52.22 ; H15.1 252.17,55.26 ; H15.1 249.13,55.26 ; 281.32,46.37 JUSB1.7 ; JUSB1.7 280.55,47.15 ; JUSB1.7 280.72,46.55 ; JUSB1.7 281.32,47.92 ; JUSB1.7 282.1,47.15 ; JUSB1.7 281.92,46.55 ; JUSB1.7 281.92,47.75 ; JUSB1.7 280.72,47.75 ; H7.1 222.03,68.5 ; H7.1 221.6,67.3 ; H7.1 219.2,67.3 ; H7.1 220.4,66.87 ; H7.1 221.6,69.7 ; H7.1 218.77,68.5 ; H7.1 220.4,70.13 ; H7.1 219.2,69.7 ; 108.76,63.64 H10.1 ; H10.1 112.24,63.64 ; H10.1 110.5,59.51 ; H10.1 112.24,60.16 ; H10.1 108.76,60.16 ; H10.1 112.89,61.9 ; H10.1 110.5,64.29 ; H10.1 108.11,61.9 ; JHDMI.17 10.44,22.56 ; JHDMI.17 9.52,21.64 ; JHDMI.17 9.52,22.56 ; JHDMI.17 10.56,22.1 ; JHDMI.17 10.44,21.64 ; JHDMI.17 9.4,22.1 ; 9.52,24.64 JHDMI.11 ; JHDMI.11 10.56,25.1 ; JHDMI.11 9.4,25.1 ; JHDMI.11 10.44,25.56 ; JHDMI.11 9.52,25.56 ; JHDMI.11 10.44,24.64 ; 206.15,6.82 JSATA1.4 ; JSATA1.4 206.15,7.06 ; JSATA1.4 206.15,7.31 ; 207.03,15.38 JSATA1.18 ; JSATA1.18 206.15,15.38 ; JSATA1.18 206.15,15.86 ; 170.06,63.64 H12.1 ; H12.1 173.54,60.16 ; H12.1 171.8,59.51 ; H12.1 174.19,61.9 ; H12.1 170.06,60.16 ; H12.1 173.54,63.64 ; H12.1 169.41,61.9 ; H12.1 171.8,64.29 ; 7.97,29.14 JHDMI.2 ; JHDMI.2 8.89,30.06 ; JHDMI.2 8.43,30.18 ; JHDMI.2 9.01,29.6 ; JHDMI.2 8.89,29.14 ; JHDMI.2 7.97,30.06 ; 10.75,52.6 JUSB2.13 ; JUSB2.13 12.16,53.55 ; JUSB2.13 12.16,52.6 ; JUSB2.13 10.75,54.5 ; JUSB2.13 12.16,54.5 ; 206.15,24.91 JSATA1.40 ; JSATA1.40 206.15,24.42 ; JSATA1.40 206.15,24.66 ; 206.15,28.42 JSATA1.50 ; JSATA1.50 206.15,28.66 ; JSATA1.50 206.15,28.91 ; JHDMI.21 11.48,33.73 ; JHDMI.21 11.48,32.85 ; JHDMI.21 8.12,33.73 ; JHDMI.21 9.8,31.97 ; JHDMI.21 9.8,33.73 ; JHDMI.21 11.48,31.97 ; JHDMI.21 8.12,31.97 ; 2.79,37.95 JUSB2.11 ; JUSB2.11 2.79,38.9 ; JUSB2.11 4.2,37.95 ; JUSB2.11 5.61,38.9 ; JUSB2.11 5.61,37.95
  BOTTOM w0.076: v10(209.62,56.27) 209.61,56.26 209.61,55.67 209.83,55.44 U34.G2 210.11,55.69 210.11,56.24 v10(210.1,56.24)
  BOTTOM w0.102: v10(163.01,66.99) v5(163.01,68.41) ; v1(86.54,65.95) 86.44,66.05 v5(85.44,66.05) ; v1(30.7,41.72) v5(31.69,41.72) ; v1(33.56,28.15) 33.88,28.15 v5(34.23,28.51) ; v5(278.99,2.83) 278.33,2.83 v6(278.25,2.9) ; DH5.2 v5(194.18,69.63) ; v1(30.96,18.47) v5(30.96,19.19) ; v9(31.18,29.95) v5(31.18,29.19) ; v6(88.84,60.69) v5(89.67,60.69) ; v1(275.47,6.31) v5(275.47,5.38)
  BOTTOM w0.109: v9(79.08,7.53) 79.08,9.46 v5(78.17,10.36)
  BOTTOM w0.127: UCPU1.AV41 138.71,41.64 139.08,42 139.08,42.48 139.12,42.53 ; 140.65,42.56 140.65,42.04 140.29,41.67 UCPU1.AV39 ; 134.51,42.53 134.35,42.37 134.35,42 133.99,41.64 UCPU1.AV49 ; UCPU1.AY22 150.5,40.51 150.5,39.61 v1(150.67,39.44) ; UCPU1.AV36 141.86,41.64 142.23,42 142.23,42.41 142.35,42.53 ; UCPU1.AV46 135.61,41.53 135.61,41.68 135.93,42 135.93,42.27 135.91,42.28 135.91,42.59 ; UCPU1.AV43 137.14,41.64 137.5,42 137.5,42.28 137.75,42.53
  BOTTOM w0.152: v1(145.23,39.59) 145.23,39.6 145.36,39.74 UCPU1.AY30
  BOTTOM w0.178: v1(134.17,43.04) 134.11,43.04 133.85,43.3 UCPU1.AR49 133.68,43.28 133.68,42.7 UCPU1.AT49 ; UCPU1.AV33 144.06,42.46 UCPU1.AU33 ; UCPU1.AV33 144.01,41.76 UCPU1.AW33 ; UCPU1.AV33 143.76,41.81 UCPU1.AV34 ; UCPU1.AW37 141.12,40.84 v1(141.46,41.18) 141.77,41.49 UCPU1.AV36 ; UCPU1.AV34 143.34,41.49 v1(143.02,41.17) 142.69,40.84 UCPU1.AW35 ; UCPU1.AV34 143.76,41.16 UCPU1.AW33 ; v1(143.28,45.56) 143.36,45.56 143.7,45.9 UCPU1.AL33 ; v1(141.39,44.42) 141.56,44.6 UCPU1.AN36 ; UCPU1.AW40 139.54,40.84 v1(139.88,41.18) 140.19,41.49 UCPU1.AV39 ; UCPU1.AN35 143.07,44.26 143.6,44.26 143.6,44.26 143.87,44.26 143.87,44.26 144.17,44.26 v1(144.2,44.24) ; UCPU1.AW33 UCPU1.AY33 ; UCPU1.AV43 137.03,41.49 v1(136.72,41.17) 136.38,40.84 UCPU1.AW44 ; UCPU1.AW47 134.84,40.84 v1(135.17,41.16) 135.29,41.16 135.56,41.44 UCPU1.AV46 ; UCPU1.AV41 138.63,41.49 v1(138.31,41.17) 137.98,40.84 UCPU1.AW42 ; UCPU1.AT49 133.99,42.57 134.03,42.53 135.08,42.53 UCPU1.AT46 UCPU1.AT43 136.79,42.53 138.16,42.53 138.22,42.59 UCPU1.AT42 138.86,42.59 138.93,42.53 139.12,42.53 139.19,42.59 UCPU1.AT40 140.36,42.59 140.43,42.53 140.62,42.53 140.69,42.59 UCPU1.AT37 141.82,42.59 141.88,42.53 142.62,42.53 142.69,42.59 UCPU1.AT35 143.02,42.77 v1(143.29,43.03) 143.55,43.3 UCPU1.AR33 ; UCPU1.AT49 133.47,42.49 132.51,42.49 UCPU1.AU51 UCPU1.AV51 UCPU1.AW51 UCPU1.AY51 132.57,40.43 v9(132.57,39.82) ; UCPU1.AL36 141.56,45.9 v1(141.39,45.72) ; UCPU1.AU20 UCPU1.AU22
  BOTTOM w0.203: v1(28.3,32.16) 28.39,32.26 U722.15 ; v1(121.68,68.44) 121.65,68.4 JLVDS2.9 ; UCPU1.AT40 139.83,42.64 139.83,43.53 UCPU1.AR39 UCPU1.AP39 UCPU1.AN39 ; v1(147.7,39.12) 147.7,40.42 UCPU1.AY26 ; v1(141.38,43.78) 141.21,43.95 UCPU1.AP38 ; UCPU1.AU26 147.84,42.51 149.09,42.51 UCPU1.AU24 ; UCPU1.D59 127.76,60.66 127.76,60.4 127.96,60.2 v9(127.96,60.12) ; U664.11 U664.15 ; UD7.J8 160.26,21.12 159.49,21.12 v1(159.4,21.03) ; JLVDS2.6 120.15,68.41 v1(120.18,68.44) ; v1(149.35,39.55) 149.14,39.76 UCPU1.AY24 ; U722.35 28,36.01 U722.41 ; v1(123.23,68.44) 123.23,67.73 123.15,67.65 JLVDS2.12 ; v1(136.83,21.1) 136.86,21.12 137.65,21.12 138.05,20.72 UD5.J8 ; JLVDS2.3 118.65,68.43 v1(118.6,68.49) ; JLVDS2.24 v4(129.15,67.72) ; UCPU1.AR43 137.4,43.3 v1(137.07,42.97) 136.72,42.62 UCPU1.AT43 ; v1(153.67,39.17) 153.52,39.17 152.9,39.79 152.9,40.48 UCPU1.AY18
  BOTTOM w0.254: v9(127.9,58.47) 128.16,58.47 UCPU1.H57 128.4,58.71 128.3,58.81 128.3,59.25 128.08,59.46 UCPU1.F58 128.08,60 v9(127.96,60.12) ; UD5.F9 137.15,23.12 v1(136.81,22.78) 136.87,22.78 137.25,22.4 UD5.G9 ; UD10.D3 189.3,24.7 v1(189.66,24.33) ; UCPU1.AH32 v1(144.34,48.23) ; UD2.E7 114.21,23.93 113.83,24.32 113.83,24.33 v1(113.82,24.33) 113.43,24.72 UD2.D8 ; UD4.G1 132.11,22.33 132.41,22.33 v1(132.65,22.1) ; v10(151.23,53.69) 150.9,53.36 UCPU1.U22 150.45,52.95 UCPU1.V23 ; UD4.M1 132.14,18.32 133.12,17.34 133.12,17.12 133.14,17.11 v1(133.15,17.12) ; v1(108.22,22.85) 108.17,22.8 107.97,22.8 107.48,22.31 107.42,22.31 107.41,22.32 UD1.G1 ; UD2.G9 112.67,22.32 112.82,22.18 112.82,22.13 v1(113.03,21.92) ; v10(151.39,54.91) 151.77,55.29 UCPU1.N21 ; v9(141.91,62.93) UCPU1.A36 141.75,62.33 141.75,62 UCPU1.B36 ; UCPU1.AB22 150.85,50.94 v10(151.23,51.32) ; v9(125.29,18.65) 125.62,18.32 UD4.M9 ; UCPU1.AN42 138.59,44.6 v1(138.92,44.92) 139.24,44.6 UCPU1.AN40 139.65,44.92 UCPU1.AN39 139.92,45.09 140.45,45.62 140.45,46.45 v1(140.32,46.58) ; UCPU1.D14 155.93,61.03 155.93,61.41 v10(155.88,61.46) 155.72,61.62 UCPU1.C14 ; UCPU1.AH22 150.85,47.34 151.17,47.02 151.22,47.02 v1(151.3,46.95) 151.5,47.15 UCPU1.AG21 ; UCPU1.AH22 150.75,47.67 UCPU1.AJ23 ; UCPU1.AH22 150.45,48.07 UCPU1.AG23 149.89,48.07 149.78,47.96 v1(149.78,48.04) ; UD1.D1 107.5,24.72 107.88,24.34 v1(107.88,24.34) 107.88,24.28 107.53,23.92 UD1.E1 ; v9(156.89,42.96) 157.09,42.96 UCPU1.AR11 ; UCPU1.U9 v10(157.87,53.14) 157.98,53.03 UCPU1.V10 ; v1(178.94,17.13) 178.95,17.13 178.95,17.1 179.31,16.73 179.33,16.73 UD9.P1 ; UD5.P9 137.25,16.66 136.82,16.23 v1(136.82,15.53) 136.81,15.52 137.21,15.12 UD5.T9 ; UD4.T9 125.65,15.12 v1(125.24,15.53) ; v1(113.03,21.92) 113.41,22.3 UD2.G8 ; v1(113.03,21.92) 113.01,21.9 113.01,21.12 113.41,20.72 UD2.J8 ; UCPU1.AJ54 130.68,47.77 v1(130.66,47.77) 130.66,47.82 130.36,47.53 UCPU1.AH55 ; UCPU1.AY53 131.13,39.37 v1(131.24,39.26) ; UCPU1.J22 151.01,57.42 v10(151.21,57.22) ; UCPU1.E11 157.05,60.21 v10(157.36,60.52) ; v1(166.72,24.32) 166.7,24.3 166.7,24.28 166.34,23.92 UD7.E1 ; v1(166.72,24.32) 166.32,24.72 166.26,24.72 ; v1(166.72,24.32) 166.92,24.51 166.92,25.81 166.41,26.32 UD7.B1 ; v1(96.12,6.69) 96.14,6.71 PU201.14 ; v9(153.74,47.34) 153.74,47.22 154.17,46.8 ; v1(142.42,24.31) 142.05,24.68 UD5.D3 ; UCPU1.J59 127.59,58 v10(127.59,58.21) ; v1(159.43,26.71) 159.84,27.12 UD7.A9 ; v10(158.96,41.24) 158.96,41.27 158.8,41.42 158.69,41.42 UCPU1.AV8 ; UD6.A9 148.24,27.12 147.93,26.81 v1(147.84,26.81) ; v1(125.27,26.68) 125.7,27.11 UD4.A9 ; v1(132.51,14.75) 132.14,15.12 UD4.T1 ; v1(133.3,48.15) 133.3,48.09 133.32,48.07 133.32,48.07 133.28,48.03 UCPU1.AJ50 132.96,47.53 UCPU1.AH51 ; v10(153.9,58.49) 154.14,58.24 UCPU1.H17 ; UCPU1.D18 153.36,60.96 v10(153.65,60.67) ; UCPU1.AK23 149.68,46.55 v1(149.38,46.24) 149.39,46.24 149.39,46.25 149.73,45.9 UCPU1.AL23 149.84,45.8 149.84,45.34 UCPU1.AM23 149.84,45.15 149.84,44.69 UCPU1.AN23 150.01,44.6 v1(150.33,44.28) ; UCPU1.AK23 150.06,46.55 150.31,46.3 150.36,46.3 150.51,46.16 150.51,46.14 UCPU1.AL22 ; UCPU1.AK23 149.95,46.57 149.95,47.12 UCPU1.AH24 149.48,47.58 149.35,47.58 v1(149.02,47.91) 148.92,47.82 148.92,47.23 UCPU1.AJ25 ; v1(180.26,26.3) 180.23,26.32 UD9.B1 ; JLVDS2.27 v10(130.65,67.66) ; v9(154.24,42.46) UCPU1.AV16 UCPU1.AW16 ; v9(154.24,42.46) 154.07,42.63 153.26,42.63 153.09,42.46 v9(152.92,42.46) 152.6,42.79 v1(152.25,42.79) 151.92,42.46 UCPU1.AU20 UCPU1.AV20 ; v9(154.24,42.46) v9(154.24,43.63) UCPU1.AP17 UCPU1.AN17 UCPU1.AM17 v9(154.24,46.23) 154.24,46.73 154.17,46.8 ; UD10.E2 190.1,23.92 190.5,24.32 v1(190.52,24.32) 190.9,24.7 UD10.D1 ; v1(128.65,39.61) 128.65,39.66 128.71,39.73 128.71,39.73 128.68,39.76 128.68,40.5 UCPU1.AY57 ; UCPU1.R22 150.98,54.17 v10(151.23,54.42) ; UD6.P9 148.3,16.73 147.92,17.11 v1(147.87,17.11) ; UCPU1.AP48 134.27,44.28 v1(134.16,44.28) ; UD2.P1 119.01,16.73 v1(118.62,17.12) ; v1(111.58,17.96) 112.02,18.41 112.53,18.41 UD2.M9 ; UD1.F9 101.01,23.12 v1(100.61,22.72) ; v9(156.99,48.57) 156.99,48.56 ; 156.99,48.56 UCPU1.AG11 ; 156.99,48.56 157.02,48.53 UCPU1.AF11 157.73,48.86 UCPU1.AE10 ; UD5.M9 137.17,18.41 136.63,18.41 136.22,18 v1(136.22,17.88) ; UCPU1.L17 v10(154.19,56.29) ; 154.17,46.8 154.17,46.86 154.56,47.25 v9(154.56,47.34) ; v1(140.66,58.94) UCPU1.F38 UCPU1.D38 ; UD9.D3 177.74,24.72 v1(177.3,25.16) ; UD4.D1 132.09,24.72 v1(131.7,24.32) 131.69,24.32 131.3,23.93 UD4.E2 ; UD2.E8 113.41,23.92 v1(113.01,23.52) 112.62,23.12 UD2.F9 ; v1(150.33,44.28) 150,43.95 UCPU1.AP23 149.77,43.79 149.77,43.46 UCPU1.AR23 149.99,43.3 v1(150.34,42.95) ; v1(150.33,44.28) 150.32,44.28 150.32,44.31 150.69,43.95 UCPU1.AP22 ; UCPU1.AD63 124.63,49.64 v10(124.5,49.77) ; v1(155.21,42.43) 155.21,43 UCPU1.AR15 ; v1(155.21,42.43) 155.21,41.9 UCPU1.AV14 ; v1(155.21,42.43) 155.35,42.57 155.67,42.57 UCPU1.AT13 ; 127.49,44.95 127.11,44.57 UCPU1.AN60 ; 127.49,44.95 v1(127.55,44.95) ; 127.49,44.95 127.45,44.95 127.11,45.3 UCPU1.AL60 ; UCPU1.AL29 146.02,45.82 v1(145.62,45.82) ; v9(239.9,41.03) JNGFF2.36 ; UD6.B3 153.1,26.34 v1(152.56,26.89) ; v1(100.57,17.95) 100.83,18.21 100.94,18.21 UD1.M9 ; UD4.E1 132.09,23.94 132.64,24.48 132.64,24.49 v1(132.66,24.51) ; JLVDS2.30 v4(132.15,67.78) ; v1(190.53,22.71) 190.53,22.69 190.89,22.32 UD10.G1 ; UCPU1.G8 158.75,58.69 v10(158.52,58.69) ; v10(153.11,63.14) 153.11,63.07 152.86,62.81 UCPU1.A18 ; UCPU1.J63 124.44,57.88 124.43,57.9 v9(124.42,57.9) ; v1(164.17,25.19) 164.26,25.19 164.66,24.79 UD7.D3 ; UD10.B1 190.9,26.33 v1(191.28,26.72) ; UCPU1.AU51 132.3,42.64 v1(131.74,42.64) ; UD4.D3 130.1,25.11 v1(130.1,25.13) ; UCPU1.B40 UCPU1.A40 v9(139.41,62.87) ; v1(131.74,42.64) 131.72,42.66 131.72,43.14 UCPU1.AR52 UCPU1.AP52 131.51,43.95 v1(131.34,44.12) ; v1(131.74,42.64) 131.56,42.46 UCPU1.AU53 130.84,42.75 130.24,42.75 129.95,42.46 UCPU1.AU55 UCPU1.AV55 ; UD1.D3 105.87,24.72 v1(106.27,24.32) 106.66,23.93 UD1.E2 ; v9(214.12,58.56) 214.39,58.83 RP21.6 ; UD4.B3 130.5,26.33 130.89,26.72 v1(130.89,26.73) ; v10(152.53,56.25) 152.28,56.5 UCPU1.L20 ; v1(152.2,44.26) 152.28,44.26 152.59,43.95 UCPU1.AP20 ; UD1.B1 107.46,26.33 v1(107.84,26.72) ; UCPU1.A32 UCPU1.B32 ; v1(149.25,61.34) 149.27,61.37 149.74,61.37 UCPU1.D23 ; UCPU1.AH49 134.26,47.53 UCPU1.AJ47 v1(134.58,48.17) ; UCPU1.AJ63 125.09,46.92 124.26,46.92 v1(124.24,46.9) ; UD2.E2 118.21,23.93 v1(117.82,24.32) 117.42,24.72 UD2.D3 ; UD1.T9 101.06,15.15 100.22,15.98 v1(100.22,16.54) ; v10(153.09,56.28) 153.24,56.43 UCPU1.L18 ; v1(178.14,20.32) 178.1,20.32 178.51,20.72 UD9.J2 ; UCPU1.AH36 141.74,48.2 141.71,48.22 v1(141.71,48.22) ; UD6.E1 154.7,23.96 155.21,24.47 155.21,24.48 v1(155.23,24.5) ; JLVDS2.19 v10(126.65,66.01) ; v1(130.68,58.91) 130.63,58.96 UCPU1.F54 UCPU1.D54 ; UD10.E8 185.28,23.92 184.89,23.53 184.88,23.53 v1(184.88,23.53) ; v10(126.51,62.42) 126.77,62.15 UCPU1.B60 ; UCPU1.AP54 131.17,43.95 v1(131.34,44.12) ; UCPU1.AL40 139.33,45.97 139.58,46.22 UCPU1.AL39 139.96,46.22 v1(140.32,46.58) ; v1(131.34,44.12) 131.82,44.6 UCPU1.AN52 UCPU1.AN51 ; v1(131.69,17.13) 131.7,17.13 131.7,17.1 132.07,16.73 132.09,16.73 UD4.P1 ; v10(158.39,54.57) UCPU1.R10 ; v1(100.64,21.93) 101.02,22.32 UD1.G9 ; JNGFF2.45 v1(242.15,35.99) ; UD6.G1 154.77,22.32 155.19,22.74 155.19,22.87 155.23,22.92 v1(155.23,22.86) ; UCPU1.AL54 131.02,45.9 v1(131.34,46.22) ; UCPU1.W22 150.85,52.4 v10(151.05,52.21) ; v1(147.86,25.86) 148.3,26.3 UD6.B9 ; UCPU1.G22 v10(150.85,58.66) ; UCPU1.AN35 142.42,44.91 142.34,44.99 v1(142.29,44.95) 141.94,44.6 UCPU1.AN36 ; UCPU1.B24 UCPU1.A24 149.48,62.49 v9(149.73,62.74) ; UCPU1.C20 v10(151.95,62.02) 151.8,62.17 UCPU1.B20 ; v1(143.26,17.12) 143.65,16.73 143.65,16.73 UD5.P1 ; v1(143.17,58.96) UCPU1.F34 UCPU1.D34 ; UD2.B9 112.58,26.32 v1(112.21,25.95) ; v1(150.34,42.95) 149.96,42.56 149.33,42.56 149.23,42.46 UCPU1.AU24 UCPU1.AV24 UCPU1.AW24 UCPU1.AY24 ; v1(150.34,42.95) 150.49,42.79 UCPU1.AU22 ; 145.52,43.95 UCPU1.AR31 145.06,43.48 v1(145.06,42.89) ; 145.52,43.95 UCPU1.AP31 144.96,44.27 UCPU1.AN32 ; 145.52,43.95 UCPU1.AP29 ; v1(145.68,58.93) UCPU1.F30 UCPU1.D30 ; UD6.M1 154.82,18.32 v1(156.15,17) ; UD1.M1 107.5,18.32 108.49,17.34 108.49,17.12 108.5,17.11 v1(108.51,17.12) ; UD10.D8 185.3,24.72 v1(185.72,24.3) 185.72,24.3 185.72,24.29 186.09,23.92 UD10.E7 ; UD10.E1 190.98,23.92 191.34,24.28 191.34,24.3 v1(191.36,24.32) ; v1(180.4,17.15) 180.4,17.13 180.38,17.11 180.37,17.12 180.37,17.34 179.38,18.32 UD9.M1 ; UD9.D1 179.34,24.72 v1(178.95,24.32) ; 166.26,24.72 v1(165.86,24.32) 165.85,24.32 165.46,23.93 UD7.E2 ; 166.26,24.72 UD7.D1 ; UCPU1.AJ13 156.37,46.5 v1(156.37,46.24) 156.26,46.24 156.06,46.04 UCPU1.AL13 ; v1(143.29,43.03) 143.84,42.48 UCPU1.AU33 144.35,42.48 144.76,42.89 v1(145.06,42.89) ; v1(112.18,26.71) 112.59,27.12 UD2.A9 ; v9(126.46,48.21) 126.32,48.35 125.94,48.35 UCPU1.AG62 125.75,48.27 125.38,48.27 125.32,48.21 UCPU1.AG63 ; v1(141.38,43.78) 141.38,44.41 v1(141.39,44.42) ; UCPU1.AJ14 155.36,46.69 155.01,46.34 155.01,46.24 v1(155.03,46.24) ; UD7.J2 165.45,20.72 165.06,20.34 v1(165.06,20.31) ; v1(144.04,26.72) 144.03,26.71 143.65,26.33 UD5.B1 ; v1(100.54,25.93) 100.93,26.32 UD1.B9 ; UCPU1.AN51 132.7,44.64 132.31,45.02 132.1,45.02 UCPU1.AM52 131.83,45.29 131.83,45.85 UCPU1.AL52 131.69,45.9 131.37,46.22 v1(131.34,46.22) ; UCPU1.AN51 132.91,44.39 133.5,44.39 UCPU1.AN49 133.85,44.6 v1(134.16,44.28) ; UCPU1.AL60 UCPU1.AL61 ; UCPU1.AL60 127.13,45.66 127.13,45.69 127.56,46.13 v1(127.56,46.19) 127.55,46.21 127.55,46.42 UCPU1.AJ60 127.13,46.89 127.61,46.89 127.93,47.2 UCPU1.AJ58 128.41,47.53 UCPU1.AH57 129,47.53 v1(129.22,47.74) 129.36,47.6 129.36,47.22 UCPU1.AJ56 129.42,47.16 v1(129.42,46.23) 129.09,45.9 UCPU1.AL57 ; v1(131.34,46.22) 131.67,46.55 UCPU1.AK52 131.88,47.09 UCPU1.AJ52 131.98,47.61 v1(131.85,47.74) 131.7,47.59 131.38,47.59 131.33,47.54 UCPU1.AH53 ; v1(108.51,14.75) 108.51,14.85 108.07,15.29 107.63,15.29 UD1.T1 ; UCPU1.AU28 146.5,42.54 145.7,42.54 145.63,42.46 UCPU1.AU30 145.36,42.59 v1(145.06,42.89) ; UCPU1.AU28 UCPU1.AV28 ; UCPU1.AU28 146.66,42.46 147.01,42.8 147.45,42.8 UCPU1.AU26 ; v9(124.58,67.75) 124.65,67.68 JLVDS2.15 ; UD10.G8 185.3,22.31 v1(184.91,21.92) ; UD9.J8 173.73,20.73 173.73,20.76 v1(173.35,21.15) ; UD4.B1 132.09,26.33 v1(132.48,26.72) ; UD1.J8 101.85,20.72 101.85,20.75 101.48,21.12 v1(101.44,21.12) ; v1(137.65,21.91) 138.05,22.32 UD5.G8 ; UD5.B3 142.05,26.33 142.45,26.72 v1(142.45,26.73) ; v1(165.86,15.56) 165.86,15.46 166.2,15.12 UD7.T1 ; v9(125.81,59.63) 125.82,59.63 126.12,59.33 UCPU1.F61 ; JLVDS2.32 v4(133.15,67.71) ; UCPU1.AR5 160.81,43.44 v10(161,43.63) ; JROT1.3 107.93,65.55 107.28,64.91 v1(107.06,64.91) 107.06,65.37 107.43,65.74 JROT1.4 ; UD10.M9 184.37,18.44 183.92,18.44 183.45,17.97 v1(183.45,17.91) ; UD9.G1 179.51,22.49 v1(180.27,22.49) ; v1(124.59,17.81) 124.59,17.76 125.63,16.72 UD4.P9 ; UCPU1.AP10 157.8,44.13 v10(158.06,44.38) ; v1(142.45,20.31) 142.45,20.33 142.84,20.72 UD5.J2 ; UCPU1.D12 156.95,61.03 v10(157.13,61.2) 157.13,61.6 UCPU1.C11 ; UCPU1.AL46 135.85,45.9 v1(136.11,46.15) 136.33,46.15 UCPU1.AL45 ; UD9.T1 179.38,15.12 v1(179.76,14.75) ; UD9.T9 172.96,15.14 173.03,15.07 v10(173.03,14.56) ; v9(140.4,67.93) 140.15,67.67 JLVDS2.46 ; UCPU1.AP57 128.93,43.92 128.84,43.92 v1(128.5,43.59) 128.53,43.56 128.53,43.03 128.73,42.83 128.73,42.5 UCPU1.AU57 128.59,42.57 127.91,42.57 127.8,42.46 UCPU1.AU59 UCPU1.AV59 UCPU1.AW59 127.37,41.16 127.05,40.84 UCPU1.AW60 126.89,40.66 UCPU1.AY59 127.3,40.19 126.58,39.46 v1(126.32,39.46) ; v1(140.32,46.58) 139.79,47.11 UCPU1.AJ39 139.83,47.24 v1(139.83,47.83) 139.52,47.53 UCPU1.AH40 138.81,47.53 138.49,47.2 UCPU1.AJ41 ; UD6.J8 149.09,20.72 149.09,20.77 148.75,21.11 148.74,21.11 v1(148.69,21.16) ; UCPU1.AJ35 142.39,47.94 v1(142.66,48.22) 143.04,47.84 UCPU1.AH34 ; UD4.E7 127.29,23.92 126.91,24.3 126.91,24.31 v1(126.9,24.31) ; UD9.D8 173.74,24.7 v1(174.12,24.32) 173.74,23.94 UD9.E8 ; UD9.A9 172.57,26.75 172.51,26.75 ; UCPU1.AD21 151.62,49.7 v10(151.39,49.47) ; UCPU1.AW4 161.53,40.8 v10(161.53,40.19) ; v1(144.2,44.24) 144.56,44.6 UCPU1.AN32 ; v1(232.94,35.92) 232.65,35.64 JNGFF2.7 ; UD2.B3 117.41,26.32 117.09,26.63 v1(116.94,26.63) ; v9(157.18,63.2) 157.18,62.91 UCPU1.A11 ; UD6.D3 152.97,24.72 152.66,25.03 v1(152.64,25.03) ; v1(133.57,41.13) 133.44,41.13 133.16,40.86 UCPU1.AW50 ; UCPU1.AH38 v1(140.44,48.15) ; UD4.D8 126.53,24.72 126.9,24.34 v1(126.9,24.31) ; v1(184.09,25.95) 184.46,26.32 UD10.B9 ; UD2.D1 119.01,24.72 v1(118.62,24.32) 119.01,23.93 UD2.E1 ; UD10.J2 190.04,20.72 189.67,20.35 189.67,20.35 189.7,20.32 v1(189.7,20.31) ; UD9.M9 172.83,18.43 172.37,18.43 172.36,18.43 172.34,18.43 172.04,18.13 172.04,18.04 171.96,17.95 v1(171.96,17.92) 171.96,17.85 172.06,17.75 172.06,17.66 172.94,16.78 UD9.P9 ; UCPU1.AL51 132.71,45.9 133.2,46.38 v1(133.2,46.4) ; UD7.M1 166.83,18.89 v1(166.83,19.5) ; U34.J8 U34.J9 U34.J10 211.08,51.22 v9(211.08,51.08) ; UD5.E7 138.47,24.3 138.47,24.31 v1(138.46,24.31) UD5.D8 ; v1(184.06,26.71) 184.48,27.12 UD10.A9 ; UCPU1.D26 UCPU1.F26 148.18,58.92 v1(148.19,58.92) ; UD9.E2 178.54,23.93 178.93,24.32 v1(178.95,24.32) ; UCPU1.P62 UCPU1.P63 124.8,54.88 124.58,54.67 124.58,54.67 v10(124.58,54.67) ; v1(159.31,23) 159.43,23.12 UD7.F9 ; v1(135.92,48.16) 135.89,48.13 UCPU1.AJ45 135.56,47.53 UCPU1.AH46 ; v1(147.87,15.51) 148.26,15.12 UD6.T9 ; v9(131.88,61.84) 131.87,61.85 131.87,62.47 v9(131.88,62.49) ; v1(147.72,23.64) 147.72,23.35 147.95,23.12 UD6.F9 UD6.E8 ; v9(129.74,63.18) 129.59,63.03 129.59,62.7 UCPU1.A56 129.23,62.34 129.23,61.98 UCPU1.B56 ; v1(107.05,17.13) 107.06,17.13 107.06,17.1 107.43,16.73 107.45,16.73 UD1.P1 ; UD5.A9 137.23,27.12 v1(136.82,26.71) ; UD7.P9 159.73,16.72 159.29,16.28 159.29,15.64 v1(159.39,15.53) 159.8,15.12 UD7.T9 ; UD7.P1 166.25,16.73 166.25,16.74 v1(165.87,17.12) ; UCPU1.A44 136.66,62.24 136.66,62.22 v10(136.63,62.2) 136.9,61.93 UCPU1.B44 136.93,61.84 ; UD7.M9 159.74,18.44 159.18,18.44 158.78,18.04 v1(158.78,17.94) ; UCPU1.J10 157.82,57.59 157.52,57.89 157.52,57.93 v1(157.56,57.97) ; UD5.D1 143.65,24.7 v1(143.27,24.32) 143.26,24.32 142.86,23.92 UD5.E2 ; JVOL.3 v9(36.1,8.21) ; JVOL.4 v9(36.6,8.21) ; UCPU1.D62 125.45,60.78 v10(125.17,61.05) 125.05,61.05 UCPU1.D63 ; UD1.B3 105.86,26.33 106.25,26.72 v1(106.25,26.73) ; JLVDS2.21 v10(127.65,67.69) ; v1(130.89,20.31) 130.89,20.34 131.27,20.72 UD4.J2 ; UCPU1.AN43 137.44,44.6 v1(137.06,44.22) 137.06,44.24 136.71,44.6 UCPU1.AN45 136.41,44.77 135.87,44.77 135.69,44.6 UCPU1.AN46 135.66,44.65 135.34,44.96 v1(135.05,44.96) 135.05,44.95 134.69,44.6 UCPU1.AN48 134.48,44.6 v1(134.16,44.28) ; UD6.E7 149.88,23.92 v1(149.5,24.3) 149.1,24.7 UD6.D8 ; v1(133.17,58.91) 133.17,58.89 133.14,58.91 UCPU1.F50 UCPU1.D50 ; v10(125.8,56.12) 126.03,56.34 UCPU1.L61 ; UD5.E8 138.05,23.9 137.67,23.52 v1(137.66,23.52) ; U34.N13 v10(212.86,49.4) ; v1(147.87,21.99) 148.21,22.32 UD6.G9 ; UCPU1.N10 v10(157.55,55.52) ; UD1.D8 v1(102.27,24.31) 102.28,24.31 102.28,24.3 102.66,23.92 UD1.E7 ; UD4.F9 125.6,23.12 v1(125.17,22.7) 125.55,22.32 UD4.G9 125.81,22.21 126.38,22.21 UD4.G8 ; UCPU1.G5 160.36,58.89 v10(160.32,58.94) 160.28,58.89 UCPU1.G6 ; UD1.E8 101.86,23.9 101.49,23.52 101.47,23.52 v1(101.47,23.52) ; UCPU1.T58 128.08,54.09 128.03,54.09 127.43,54.69 UCPU1.P59 127.43,54.85 127.11,55.17 v1(127.11,55.26) ; UCPU1.AL26 147.95,45.9 147.58,46.27 v1(147.58,46.24) 147.59,46.26 UCPU1.AJ27 147.26,47.2 UCPU1.AH28 ; v1(161.07,24.31) 160.68,23.92 UD7.E8 ; v1(161.07,24.31) UD7.D8 ; v1(161.07,24.31) 161.08,24.31 161.08,24.3 UD7.E7 ; UD1.G8 101.86,22.32 v1(101.45,21.91) ; v1(154.3,17.13) 154.31,17.13 154.31,17.1 154.68,16.73 154.7,16.73 UD6.P1 ; v10(151.21,56.12) 150.88,55.79 UCPU1.M22 ; v1(126.1,21.11) 126.49,20.72 UD4.J8 ; 172.51,26.75 v1(172.46,26.75) ; 172.51,26.75 UD9.B9 ; UD6.T1 154.81,15.23 155.32,15.23 155.73,14.82 v1(155.73,14.72) ; U652.8 208.52,39.06 v1(208.01,38.55) 207.87,38.69 U652.9 ; UCPU1.AJ29 146.03,47.46 145.7,47.46 UCPU1.AH30 v1(145.64,48.22) ; v1(155.09,26.72) 155.08,26.71 154.7,26.33 UD6.B1 ; v1(178.95,24.32) 179.34,23.93 UD9.E1 ; UD7.G9 159.86,22.33 v1(160.26,22.73) 160.66,22.34 UD7.G8 ; v1(135.68,58.97) 135.68,58.94 135.65,58.97 UCPU1.F46 UCPU1.D46 ; UD10.P1 190.89,16.73 190.87,16.73 190.49,17.11 190.5,17.11 v1(190.5,17.12) ; UCPU1.AH42 137.51,47.53 UCPU1.AJ43 137.19,47.96 137,48.14 v1(137,48.14) 137,47.98 136.86,47.85 136.86,47.85 UCPU1.AH44 ; UCPU1.G18 153.5,58.89 v10(153.67,59.07) ; UD2.J2 118.21,20.72 v1(117.81,20.32) ; UD2.G1 118.97,22.32 118.61,22.68 v1(118.61,22.73) ; UCPU1.D21 v10(151.69,60.39) ; UCPU1.K12 156.57,56.97 156.28,56.67 UCPU1.L13 156.1,56.38 156.1,56.38 v1(156.1,55.41) ; UCPU1.AL31 145.21,46.22 v1(145.62,45.82) ; v1(136.85,25.95) 137.22,26.32 UD5.B9 ; UCPU1.L58 127.76,56.69 v10(127.64,56.81) ; UD5.T1 143.81,15.12 144.05,15.36 144.05,15.51 144.12,15.43 v1(144.14,15.43) ; v1(178.13,26.73) 177.74,26.34 UD9.B3 ; v1(148.72,21.91) 149.1,22.29 UD6.G8 ; UCPU1.AR39 140.01,43.72 140.6,43.72 UCPU1.AP38 ; v10(156.85,48.94) 156.59,48.68 UCPU1.AF12 ; v1(153.1,45.58) 152.97,45.58 UCPU1.AL20 ; UD6.E2 153.9,23.93 v1(154.3,24.32) 154.31,24.32 154.7,24.72 UD6.D1 ; UD9.E7 174.54,23.98 v1(175.07,24.51) ; UD2.B1 119.01,26.33 119.04,26.35 118.97,26.35 118.61,26.71 v1(118.61,26.76) ; JNGFF2.24 236.9,41.39 236.4,40.89 v1(236.4,40.88) ; UCPU1.C18 153.13,61.62 v10(153.32,61.43) ; UD1.A9 101.02,27.12 100.63,26.73 v1(100.54,26.73) ; UCPU1.AF15 154.96,48.96 155.01,49.01 v10(155.02,49.01) ; UCPU1.AP26 147.71,44.24 147.69,44.24 v1(147.58,44.35) ; v1(124.18,44.43) UCPU1.AN63 ; UD10.P9 184.5,16.66 184.04,16.2 v1(184.04,15.54) 184.02,15.52 184.06,15.52 184.46,15.12 UD10.T9 ; UCPU1.AT61 126.24,43.39 125.9,43.39 125.65,43.14 UCPU1.AT62 125.54,43.12 125.41,42.99 124.86,42.99 UCPU1.AT63 124.51,42.97 v1(124.3,42.76) ; v1(143.25,22.72) 143.25,22.68 143.6,22.32 UD5.G1 ; UD10.J8 184.92,21.1 184.05,21.1 v1(184.02,21.06) ; UCPU1.L15 155.14,56.38 155.11,56.35 v10(155.11,56.23) ; UD5.M1 143.8,18.32 144.14,18.66 v1(144.28,18.66) ; v10(151.23,55.34) 150.88,54.98 UCPU1.P22 ; UD6.M9 148.25,18.32 147.89,18.68 v1(147.84,18.68) ; v1(145.62,45.82) 145.54,45.82 145.29,45.57 UCPU1.AM31 145.11,45.48 145.11,45.02 UCPU1.AN31 144.87,44.6 UCPU1.AN32 ; v1(234.8,40.86) 235.4,41.46 JNGFF2.18 ; UD10.G9 184.44,22.32 v1(184,22.77) 184.35,23.12 UD10.F9 ; v1(126.9,24.31) 126.51,23.92 UD4.E8 ; UCPU1.Y10 v10(157.51,51.71) ; UD2.T1 119.07,15.12 119.48,15.53 v1(119.51,15.53) ; UCPU1.AP3 162.16,43.67 162.47,43.98 v10(162.47,44.03) ; JLVDS2.31 v4(132.65,67.74) ; UD5.E1 143.66,23.92 144.02,24.28 144.02,24.3 v1(144.04,24.32) ; UCPU1.AF17 v10(154.15,49.11) ; v1(159.41,25.99) 159.53,25.99 159.86,26.32 UD7.B9 ; v10(155.35,49.04) 155.78,48.61 UCPU1.AF14 ; v1(153.13,46.69) 152.93,46.89 UCPU1.AH19 v9(152.12,47.34) ; v10(152.76,53.69) 152.43,53.36 UCPU1.U20 ; UD2.P9 112.39,16.72 112.13,16.46 v1(112.13,15.53) 112.54,15.12 UD2.T9 ; UCPU1.AF18 v10(153.34,49.06) ; UCPU1.AA58 128.04,51.53 v10(127.66,51.53) 127.43,51.76 UCPU1.Y59 ; UCPU1.A48 UCPU1.B48 134.39,61.46 v9(134.23,61.3) ; UD6.J2 153.87,20.72 153.5,20.35 v1(153.5,20.31) ; v1(191.95,17.12) 191.94,17.11 191.93,17.12 191.93,17.64 191.25,18.32 UD10.M1 ; JNGFF2.30 238.4,41.38 v1(237.9,40.88) ; UCPU1.D42 UCPU1.F42 138.15,59.03 v1(138.25,58.94) ; UD7.G1 166.26,22.36 v1(165.89,22.72) ; UCPU1.B28 UCPU1.A28 ; UD9.F9 172.84,23.12 172.39,22.67 172.39,22.04 172.48,21.94 v1(172.48,21.86) 172.74,22.12 172.74,22.12 172.94,22.32 UD9.G9 173.08,22.46 173.6,22.46 UD9.G8 ; UCPU1.AB10 v10(158.42,50.76) ; UD4.B9 125.67,26.32 v1(125.27,25.92) ; UCPU1.D8 159.3,61.43 159.28,61.45 v10(159.28,61.45) ; v1(189.69,26.73) 189.69,26.72 189.3,26.33 UD10.B3 ; v1(164.11,26.44) 164.24,26.32 UD7.B3 ; v1(106.27,20.32) 106.27,20.38 106.61,20.72 UD1.J2 ; UCPU1.Y63 v9(124.42,51.89) ; UCPU1.E17 v10(154.62,60.2)
  BOTTOM w0.305: v9(191.03,8.52) 191.18,8.52 191.45,8.79 191.45,9.03 JNFC1.2 ; v1(246.86,36.05) 246.65,35.84 JNGFF2.63 ; JNGFF1.18 v9(225.82,58.74) ; JNGFF2.1 231.15,35.88 v1(231.01,36.03) ; JNGFF1.1 v9(218.3,62.99) ; JNGFF1.49 218.27,48.99 v9(218.33,48.93) ; JNGFF1.7 v9(218.32,61.49) ; JNGFF1.25 v9(218.33,54.99) ; v9(104.08,1.81) 104.14,1.87 PQ103.1 ; v1(118.38,64.6) 118.81,65.03 CH1241.2 ; JNGFF2.75 249.65,35.95 v1(249.73,36.03) ; JPWR1.6 266.18,7.37 266.26,7.29 266.26,6.56 v1(266.12,6.42) ; v1(100.22,16.54) 100.25,16.52 100.86,16.52 101.06,16.72 UD1.P9 ; v1(243.71,36.03) 243.65,35.97 JNGFF2.51 ; JNGFF2.33 v1(239.15,36.05) ; v1(240.47,36.05) 240.65,35.87 JNGFF2.39 ; JNGFF2.57 245.15,35.92 v1(244.99,36.08) ; v9(218.28,47.49) JNGFF1.55 ; v4(106.01,3.16) 106.03,3.17 PQ103.4 ; v9(184.73,10.22) 184.95,10 JNFC1.15 ; JNFC1.9 187.95,9.05 187.95,8.54 v9(187.75,8.34) ; JNGFF2.69 v1(248.15,36) ; v9(218.23,51.99) JNGFF1.37 ; JNGFF1.67 v9(218.31,44.49) ; JNGFF2.29 238.15,35.79 238.3,35.93 v1(238.3,36.03) 238.3,36.24 237.95,36.58 237,36.58 236.65,36.23 JNGFF2.23 ; UCPU1.D2 162.81,60.89 v10(163.01,61.1) ; v1(154.26,39.99) 154.26,40.04 154.28,40.05 UCPU1.AY16 ; v9(218.2,53.5) 218.19,53.49 JNGFF1.31 ; CR6.1 v1(269.94,23.22) ; v9(218.38,50.49) JNGFF1.43 ; UD10.T1 191.3,14.71 v1(191.42,14.71) ; v9(218.28,45.99) JNGFF1.61
  BOTTOM w0.381: U635.3 104.25,36.76 v1(103.89,37.12) ; v1(199.03,62.81) JLVDS1.22 ; MD82.7 v1(20.65,49.94) ; v1(126.22,36.9) 125.63,36.9 125.18,36.45 UC1.3 ; Q361.1 v1(182.54,58.15)
  BOTTOM w0.406: JSATA1.9 204.34,9.06 v9(204.03,8.76) ; v1(138.12,4.81) 138.12,5.48 136.66,6.94 136.66,7.37 JKB2.21 ; JSATA1.35 203.6,22.66 203.35,22.92 v1(203.35,23.33) 203.48,23.46 JSATA1.37 ; v1(125.43,5.51) 125.15,5.79 JKB2.22 ; JSATA1.43 v9(204.07,25.86) ; JSATA1.27 203.69,19.46 v1(203.37,19.78) 203.85,20.26 JSATA1.29 ; JSATA1.21 v9(204.07,17.06)
  BOTTOM w0.457: v1(28.22,53.2) 28.62,53.2 28.73,53.31 U700.3 ; JROT1.5 111.58,69.15 v1(111.58,67.93)
  BOTTOM w0.508: PC813.2 111.46,54.24 v6(111.46,54.72) ; CA50.1 31.54,27.34 30.7,27.34 v1(30.57,27.47) ; RV22.2 CV32.2 29.66,29.93 v1(29.48,29.75) ; v6(106.08,51.44) 106.08,50.97 PC822.2 ; v1(271.16,38.08) 270.27,38.97 PBJ1.2 ; C1110.2 v6(15.18,43.42) ; v1(107.55,36.44) 106.97,37.03 R608.1 ; v1(86.42,60.77) 86.01,60.36 CH1236.2 ; v6(109.68,51.42) 109.68,50.92 PC807.2 ; v1(103.52,70.48) 104.44,70.48 JROT1.6 ; PQ204.3 v9(93.86,4.06) ; CR19.2 278.99,4.02 278.25,3.28 v6(278.25,2.9) ; PC825.2 107.88,54.25 v6(107.88,54.69) ; v1(212.31,65.78) 211.29,64.76 JLVDS1.23 ; v1(293.08,37.63) 293.45,37.26 JCARD.15 ; v1(273.07,1.79) 273.41,2.13 SW2.4 ; MC1151.2 169.94,69.17 v1(170.33,68.79) ; v6(109.7,48.34) 109.7,47.86 PC814.2 ; C303.2 281.72,38.73 280.89,39.56 v1(280.89,41.87) ; v1(182.69,66.35) 182.55,66.21 181.8,66.21 C1240.2 ; v1(113.48,70.65) 113.68,70.44 JLVDS2.52 ; CV43.2 26.23,40.98 v1(25.7,41.51) ; JPWR1.7 270.83,3.85 v1(271.38,3.3) ; v1(33.45,24.64) 32.91,24.64 CA43.1 ; PR225.2 91.64,3.25 91.62,3.26 v1(91.62,3.37) ; v6(113.24,51.42) 113.24,50.92 PC803.2 ; JLVDS2.51 116.75,67.67 116.52,67.9 v1(115.92,67.9) ; JTP1.14 171.17,6.88 171.91,7.63 v1(171.91,8.26) ; 271.1,26.14 270.76,26.14 v1(270.15,26.75) 269.36,25.97 CR3.2 268.94,26.14 268.04,26.14 ; PC804.2 111.49,50.9 v6(111.49,51.42) ; v1(144.3,37.16) 144.28,37.14 CC239.2 144.28,35.47 CC164.2 ; JVOL.6 38.75,4.25 v1(38.58,4.08) ; CC234.2 134.62,36.17 v1(134.12,36.67) 134.01,36.77 CC161.2 ; v1(66.27,7.88) 66.27,7.55 66.68,7.15 67.23,7.15 67.57,7.49 JBATT1.10 ; JBL1.6 158.97,7.92 v1(155.7,7.92) 155.11,7.92 154.6,7.41 JBL1.5 ; PC612.2 94.89,28.18 95.45,27.62 v9(95.45,27.57) ; SW2.3 v1(278.13,2.13) ; PC811.2 111.41,47.93 v6(111.41,48.34) ; JDEBUG.8 v9(199.1,22.36) ; JNFC1.16 194.05,5.5 v9(193.68,5.13) ; v9(191.76,69.63) DH5.2 ; JSPK1.6 23.46,7.53 24.48,8.54 27.09,8.54 JSPK1.5 28.1,6.26 29.94,4.43 30.3,4.43 31.21,3.51 ; v1(102.03,38.64) 101.68,38.3 PC609.2 ; JBATT1.3 v9(58.31,6.16) ; v6(109.68,54.72) 109.68,54.24 PC820.2 ; v1(42.02,3.51) 42.56,3.51 42.9,3.85 JFAN1.9 ; CV42.2 30.17,41.18 v1(30.7,41.72) ; v6(17.09,44.56) 17.09,43.96 C1109.2 16.2,44.04 v6(16.2,44.56) ; PR226.2 103.19,4.87 103.43,5.11 PQ202.3 102.67,5.69 v1(102.63,5.65) ; JVOL.5 32.95,5.16 v1(34.22,3.89) ; PC821.2 107.91,47.87 v6(107.91,48.4) ; PC801.2 106.13,47.87 v6(106.13,48.34) ; v1(289.63,6.89) 290.15,7.41 JCARD.19 ; CC238.2 138.26,36.94 v1(138.38,36.82) 138.38,35.98 CC163.2 ; RC154.2 RC156.2 151.05,35.09 v1(149.65,36.48) ; RV24.2 RV31.1 CV31.2 ; CC233.2 140.99,36.1 v1(141.38,36.49) ; PC608.1 94.88,30.27 v1(94.63,30.51) ; v9(100.65,12.17) 100.65,11.84 PC214.2 101.29,11.79 v9(101.29,12.17) ; C656.2 v1(103.45,40.08) ; v6(101.16,51.8) 101.16,51.35 PC712.1 101.8,51.23 v6(101.8,51.8) ; JKB1.11 120.42,6.75 v1(120.52,6.85) ; CV39.2 v9(31.18,29.95) ; v1(205.66,64.58) 205.47,64.76 JLVDS1.24 ; R1205.2 173.4,52.48 RH78.2 172.94,52.43 v1(172.74,52.64) ; v10(176.8,49.45) 176.73,49.37 U2.4 ; v1(177.23,8.47) 177.23,7.63 177.98,6.88 JTP1.13 182.54,6.88 JNFC1.17 ; v1(12.22,23.54) CV41.2 ; C1290.2 29.54,55.74 29.77,55.5 v1(29.77,55.48) ; JCARD.12 290.15,37.59 v1(290.37,37.8) ; v1(131.55,33.72) 131.17,33.34 CC160.2 ; JCARD.23 287.35,37.78 v1(286.98,38.16) ; v9(220.06,63.69) 219.36,63.69 218.96,64.09 JNGFF1.68 ; v6(93.22,28.48) 93.38,28.63 PC615.2 ; JDEBUG.10 v9(199.05,19.87) ; v6(113.26,54.72) 113.26,54.21 PC812.2 ; RC100.2 v1(118.79,61.48) ; PC823.2 107.83,51 v6(107.83,51.37) ; v6(101.99,53.13) 101.67,53.13 PC713.2 101.43,52.49 v6(102.02,52.49) ; CV44.2 28.77,41.03 v1(28.19,41.61) ; v6(106.1,54.66) 106.1,54.25 PC824.2 ; JLVDS2.54 145.25,71.03 v1(144.44,71.84) ; v1(94.35,5.65) 94.35,5.32 94.76,4.91 PC228.2
  vias: v1(0.53,15.45) v1(0.74,33.89) v1(0.7,17.22) v1(0.78,35.25) v1(2.36,56.65) v1(2.36,37.3) v1(2.56,54.8) v1(2.58,39.14) v1(3.88,57.87) v1(4.24,33.97) v1(4.64,17.23) v1(5.96,54.69) v1(6.42,57.87) v1(6.55,34.2) v1(7.03,39.25) v1(7.03,17.18) v1(8.1,55.02) v1(8.96,57.87) v1(9.65,52.56) v1(9.65,50.02) v1(9.65,47.48) v1(9.65,44.94) v1(9.65,42.4) v1(9.63,39.76) v1(11.5,57.87) v1(14.04,57.87) v1(15.23,25) v1(15.2,24.11) v1(16.58,57.87) v1(19.12,57.87) v1(20.01,46.46) v1(22.9,68.28) v1(22.9,65.74) v1(22.9,63.2) v1(22.85,60.69) v1(23.01,30.49) v1(23.49,34.65) v1(23.64,30.49) v1(23.74,69.91) v1(24.28,30.49) v1(24.99,26.09) v1(25.19,24.28) v1(25.24,22.98) v1(26.28,69.91) v1(26.57,26.08) v1(26.6,24.34) v1(26.61,23.01) v1(26.82,47.46) v1(26.82,46.59) v1(27.24,47.03) v1(27.36,37.19) v1(27.36,35.67) v1(27.36,34.4) v1(27.68,47.46) v1(27.68,46.59) v1(28.03,26.11) v1(28.14,24.29) v1(28.14,22.97) v1(28.5,37.19) v1(28.5,35.67) v1(28.5,34.4) v1(29.6,37.19) v1(29.6,35.67) v1(29.6,34.4) v1(30.75,69.91) v1(30.96,17.89) v1(31.3,1.49) v1(32.24,3.28) v1(32.34,2.62) v1(33.17,69.91) v1(33.84,1.49) v1(34.35,14.84) v1(34.64,68.46) v1(34.64,65.92) v1(34.64,63.38) v1(34.64,60.84) v1(34.64,58.3) v1(34.64,55.76) v1(34.64,53.22) v1(34.64,50.68) v1(34.64,48.14) v1(34.64,45.6) v1(34.64,43.06) v1(34.64,40.52) v1(34.64,37.98) v1(34.77,35.44) v1(35.2,32.88) v1(35.36,14.84) v1(35.88,30.39) v1(36.34,13.5) v1(36.38,1.49) v1(36.82,27.97) v1(37.13,8.8) v1(37.33,9.91) v1(38.04,25.69) v1(38.64,9.65) v1(38.64,8.76) v1(38.66,12.1) v1(38.66,11.09) v1(38.92,1.49) v1(39.49,23.53) v1(39.9,13.5) v1(40.09,8.81) v1(41.14,21.55) v1(41.5,0.49) v1(43.02,19.79) v1(45.08,18.19) v1(47.26,16.85) v1(49.12,0.49) v1(49.6,15.76) v1(51.66,0.49) v1(52.01,14.92) v1(52.75,12.19) v1(52.77,11.15) v1(52.77,10.19) v1(54.2,0.49) v1(54.44,7.34) v1(54.5,14.33) v1(55.04,7.34) v1(55.62,7.35) v1(56.22,7.36) v1(57.04,14.03) v1(59.68,14) v1(62.3,14.26) v1(64.79,14.79) v1(67.25,15.6) v1(69.44,0.49) v1(69.59,16.65) v1(71.63,17.66) v1(71.98,0.49) v1(73.23,16.49) v1(74.52,0.49) v1(75.79,15.81) v1(77.06,0.49) v1(78.53,24.46) v1(78.59,16.89) v1(79.6,0.49) v1(79.72,26.53) v1(79.97,22.07) v1(80.12,19.33) v1(80.79,28.71) v1(81.63,31.07) v1(82.14,0.49) v1(82.21,33.36) v1(82.64,66.35) v1(82.64,63.81) v1(82.64,61.27) v1(82.64,58.73) v1(82.64,56.19) v1(82.64,53.65) v1(82.64,51.11) v1(82.64,48.57) v1(82.64,46.03) v1(82.64,43.49) v1(82.64,40.95) v1(82.64,38.41) v1(82.57,35.9) v1(82.68,68.65) v1(84.12,68.99) v1(84.68,0.49) v1(86.66,68.99) v1(87.22,0.49) v1(89.2,68.99) v1(89.76,0.49) v1(91.74,68.99) v1(92.3,0.49) v1(94.56,68.84) v1(94.84,0.49) v1(95.4,64.73) v1(96.69,67.6) v1(97.38,0.49) v1(98.08,6.87) v1(98.08,6.21) v1(98.08,5.57) v1(98.74,6.87) v1(98.74,6.21) v1(98.74,5.57) v1(99.37,6.87) v1(99.37,6.21) v1(99.4,5.57) v1(99.92,0.49) v1(101.47,26.72) v1(101.47,25.12) v1(102.2,71.03) v1(102.24,23.5) v1(102.26,25.16) v1(102.46,0.49) v1(103.12,22.82) v1(103.57,72.86) v1(104.24,23.56) v1(104.75,21.81) v1(105,0.49) v1(105.4,26.76) v1(105.52,32.47) v1(105.99,32.88) v1(106.13,28.3) v1(106.5,33.38) v1(107,33.89) v1(107.06,24.36) v1(107.54,0.49) v1(110.08,1.47) v1(111.99,21.49) v1(112.62,1.47) v1(115.16,1.47) v1(116.13,21.73) v1(117.7,1.47) v1(119.22,72.98) v1(120.24,1.47) v1(121.76,72.98) v1(121.81,23.2) v1(122.01,22) v1(122.44,47.59) v1(122.35,46.47) v1(122.77,44.78) v1(122.78,1.47) v1(123.27,25.74) v1(123.46,47.16) v1(124.3,72.98) v1(125.32,1.47) v1(126.19,33.2) v1(126.84,72.98) v1(127.01,70.16) v1(127.18,36.82) v1(127.17,33.2) v1(127.86,1.47) v1(128.2,26.89) v1(128.19,24.89) v1(128.4,64.47) v1(128.59,37.72) v1(128.98,23.56) v1(129.21,61.36) v1(129.38,72.98) v1(130.08,64.37) v1(130.07,26.69) v1(130.4,1.47) v1(130.46,63.89) v1(131.92,72.98) v1(132.54,70.9) v1(132.68,63.74) v1(132.94,1.47) v1(133.18,64.14) v1(133.81,32.5) v1(133.9,71.01) v1(134.05,23.55) v1(134.18,35.4) v1(134.35,64.37) v1(134.4,34.43) v1(134.46,72.98) v1(135.35,32.5) v1(135.48,1.47) v1(135.83,70.95) v1(136.13,64.87) v1(136.76,64.93) v1(137,72.98) v1(137.1,61.32) v1(137.43,32.4) v1(137.64,35.02) v1(137.88,63.52) v1(138.02,1.47) v1(138.31,37.61) v1(138.78,70.29) v1(138.99,27.76) v1(139.35,22.7) v1(139.54,72.98) v1(139.54,61.35) v1(139.8,24.82) v1(139.87,26.88) v1(140.56,0.49) v1(140.77,21.73) v1(140.95,35.22) v1(141.51,39.34) v1(141.58,26.77) v1(141.93,61.35) v1(142.08,72.98) v1(142.29,35.27) v1(142.81,32.99) v1(143.1,0.49) v1(143.5,63.86) v1(144.67,66.12) v1(144.66,61.32) v1(144.93,72.98) v1(145.24,37.76) v1(146.25,48.19) v1(146.16,38.51) v1(146.42,68.46) v1(146.78,71.51) v1(146.76,61.34) v1(147.07,63.81) v1(147.64,66.12) v1(149.09,70.98) v1(150.68,37.53) v1(150.72,0.49) v1(151.53,22) v1(151.63,70.98) v1(151.67,38) v1(153.27,1.51) v1(154.17,70.98) v1(155.81,1.51) v1(156.71,70.98) v1(158.35,1.51) v1(158.59,42.73) v1(159.25,70.98) v1(160.89,1.51) v1(161.79,70.98) v1(162,22.62) v1(162.41,24.98) v1(163.13,23.6) v1(163.43,1.51) v1(164,65.16) v1(164.33,70.98) v1(165.97,1.51) v1(166.87,70.98) v1(167.63,22.84) v1(167.86,21.78) v1(168.51,1.51) v1(169.41,70.98) v1(170.5,25.12) v1(171.05,1.51) v1(171.95,70.98) v1(173.59,1.51) v1(174.49,70.98) v1(176.13,1.51) v1(176.32,23.49) v1(177.03,70.98) v1(178.67,1.51) v1(179.57,70.98) v1(180.46,14.74) v1(180.75,12.69) v1(181.08,20.51) v1(181.21,1.51) v1(181.57,24.45) v1(181.83,11.79) v1(181.85,13.88) v1(182.11,70.98) v1(182.24,22.93) v1(182.45,16.75) v1(182.65,11.5) v1(183.02,13.63) v1(183.75,1.51) v1(184.65,70.98) v1(185.72,23.51) v1(185.69,22.71) v1(186.29,1.51) v1(186.68,21.31) v1(186.76,50.22) v1(187.19,70.98) v1(187.19,63.44) v1(187.18,62.86) v1(187.98,21.72) v1(188.83,1.51) v1(188.9,21.14) v1(189.73,70.98) v1(189.66,23.51) v1(190.52,23.55) v1(190.49,21.93) v1(191.37,1.51) v1(192.27,70.98) v1(192.31,15.41) v1(194.27,71) v1(196.28,49.96) v1(196.91,68.73) v1(197.05,49.96) v1(199.66,70.99) v1(201.52,70.98) v1(201.47,9.25) v1(201.52,0.49) v1(202.15,9.25) v1(204.06,70.98) v1(204.06,0.49) v1(206.6,70.98) v1(206.6,0.49) v1(208.55,43.77) v1(209.14,70.98) v1(209.14,0.49) v1(209.38,32.18) v1(209.37,1.63) v1(209.47,3.15) v1(210.45,62.11) v1(211.68,70.98) v1(211.68,0.49) v1(212.24,62.11) v1(214.04,34.1) v1(214.22,70.98) v1(215.14,56.82) v1(216.58,34.1) v1(216.76,70.98) v1(219.12,34.1) v1(219.35,60.13) v1(219.87,61.93) v1(221.66,34.1) v1(222.57,53.36) v1(224.1,70.98) v1(224.2,34.1) v1(226.64,70.98) v1(226.74,34.1) v1(228.95,34.1) v1(229.18,70.98) v1(231.34,46.46) v1(231.72,70.98) v1(233.55,55.99) v1(234.26,70.98) v1(235.91,48.88) v1(235.91,46.97) v1(236.11,45.14) v1(236.8,70.98) v1(240.59,47.35) v1(241.24,47.35) v1(241.88,47.35) v1(243.92,44.74) v1(244.42,70.98) v1(245.61,47.71) v1(245.61,46.85) v1(246.47,47.71) v1(246.47,46.85) v1(246.96,70.98) v1(249.5,70.98) v1(252.04,70.98) v1(252.29,34.1) v1(252.85,34.9) v1(254.58,70.98) v1(254.68,34.1) v1(257.22,34.1) v1(257.32,70.94) v1(257.32,68.4) v1(257.32,65.86) v1(257.32,63.32) v1(257.32,60.78) v1(257.32,58.24) v1(259.76,34.1) v1(259.86,68.4) v1(259.86,65.86) v1(259.86,63.32) v1(259.86,60.78) v1(259.86,58.24) v1(261,70.95) v1(262.27,33.92) v1(262.39,68.64) v1(262.4,63.32) v1(262.4,60.78) v1(262.4,58.24) v1(262.78,65.63) v1(263.09,31.86) v1(263.09,29.32) v1(263.09,26.78) v1(263.09,24.24) v1(263.09,21.7) v1(263.09,19.16) v1(263.09,16.62) v1(263.09,14.08) v1(263.09,11.54) v1(263.09,9) v1(263.09,6.64) v1(263.09,3.54) v1(263.09,1.38) v1(264.94,63.32) v1(264.94,60.78) v1(264.94,58.24) v1(264.92,0.49) v1(265.06,50.96) v1(265.06,50.09) v1(265.5,50.53) v1(265.94,50.96) v1(265.93,50.1) v1(266.05,65.1) v1(266.39,20.3) v1(266.36,19.46) v1(266.41,9.6) v1(267.02,19.86) v1(267,9.56) v1(267.48,63.32) v1(267.48,60.78) v1(267.53,20.62) v1(267.53,19.16) v1(267.46,0.49) v1(268,58.21) v1(268.31,32.75) v1(268.88,64.78) v1(268.93,13.14) v1(270,0.49) v1(271.44,63.7) v1(271.54,33.59) v1(271.52,31.2) v1(271.54,23.78) v1(271.54,21.37) v1(271.54,11.26) v1(271.62,9.08) v1(272.46,36.1) v1(272.54,0.49) v1(273.78,61.62) v1(274.16,8.21) v1(274.39,36.15) v1(275.14,37.77) v1(275.08,0.49) v1(275.47,46.31) v1(276.21,60.5) v1(277.62,0.49) v1(277.73,58.29) v1(278.86,8.24) v1(279.22,36.15) v1(279.6,1.61) v1(279.89,60.4) v1(279.86,55.62) v1(279.99,53.64) v1(280.69,38.76) v1(281.45,8.21) v1(281.76,36.15) v1(282.25,57.86) v1(283.53,60.49) v1(283.53,57.95) v1(283.53,55.41) v1(284.17,59.47) v1(284.17,54.61) v1(284.16,51.85) v1(284.16,49.31) v1(284.16,46.77) v1(284.16,44.23) v1(284.16,41.69) v1(284.63,39.19) v1(285.1,36.15) v1(286.07,57.95) v1(286.07,55.41) v1(286.4,60.49) v1(287.24,55.04) v1(287.37,58.35) v1(287.88,2.4) v1(287.95,39.61) v1(288.84,36.15) v1(288.87,56.57) v1(289.17,8.24) v1(289.81,3.54) v1(291.13,55.99) v1(291.33,55.04) v1(291.26,39.61) v1(291.38,5.25) v1(292.78,6.26) v1(294,5.24) v1(294.23,36.15) v1(294.77,37.64) v1(294.79,7.53) v3(107,21.12) v3(107.66,12.65) v3(108.45,12.27) v3(109.21,16.04) v3(109.63,19.88) v3(109.78,13.95) v3(109.97,11.76) v3(110.18,18.67) v3(110.29,16.64) v3(110.8,11.37) v3(113.77,17.47) v3(115.42,19.89) v3(118.13,12.78) v3(119.36,13.14) v3(119.43,11) v3(119.94,17.39) v3(120.18,11.55) v3(121.45,12.98) v3(121.85,15.87) v3(122.49,14.38) v3(122.51,11.94) v3(123.06,15.66) v3(123.66,14.14) v3(124.34,19.96) v3(124.4,19.04) v3(124.77,10.25) v3(126.98,13.07) v3(131.44,21.11) v3(133.29,20.32) v3(133.44,12.16) v3(134.41,13.91) v3(134.39,11.78) v3(135.23,16.67) v3(135.64,13.68) v3(135.77,11.74) v3(135.85,18.89) v3(136.72,11.26) v3(139,21.35) v3(153.97,61.96) v3(154.94,12.82) v3(155.06,16.23) v3(155.59,60.13) v3(155.96,11.95) v3(156.78,13.88) v3(157.09,11.65) v3(157.29,19.09) v3(157.89,16.32) v3(157.91,11.4) v3(158.14,14.9) v3(158.8,11.2) v3(161.77,58.07) v3(163.81,20.11) v3(164.25,13.07) v3(165.88,13.35) v3(167.17,16.06) v3(167.57,11.69) v3(168,14.2) v3(168.67,12.36) v3(169.48,14.06) v3(169.84,20.28) v3(170.16,17.21) v3(170.61,14.95) v3(170.81,19.1) v3(171.33,18.06) v3(171.76,19.65) v3(172.13,16.23) v3(172.3,15.24) v3(181.5,17.86) v3(186.03,18.01) v4(126.13,50.35) v4(128.08,52.78) v5(6.58,15.71) v5(10.6,35.19) v5(10.95,38.39) v5(11.52,36.51) v5(27.3,24.93) v5(29.01,36.38) v5(81.53,25.28) v5(88.7,14.05) v5(90.38,37.4) v5(90.66,22.23) v5(91.8,47) v5(93.67,54.57) v5(96.2,15.1) v5(99.65,59.24) v5(106.83,31.86) v5(179.24,63.53) v5(181.34,40.47) v5(191.32,35.82) v5(192.22,59.52) v5(267.07,57.87) v6(27.12,60.82) v6(27.12,60.18) v6(27.76,67.42) v6(27.76,66.78) v6(27.76,66.15) v6(27.76,65.51) v6(28.39,67.42) v6(28.39,66.78) v6(28.39,66.15) v6(28.39,65.51) v6(29.03,67.42) v6(29.03,66.78) v6(29.03,66.15) v6(29.03,65.51) v6(82.19,24.62) v6(82.19,23.99) v6(82.19,23.35) v6(82.19,22.72) v6(83.8,48.34) v6(83.8,47.05) v6(83.8,46.41) v6(83.89,12.17) v6(83.89,11.54) v6(84.04,59.71) v6(84.04,58.97) v6(84.52,12.17) v6(84.52,11.54) v6(85.16,12.17) v6(85.16,11.54) v6(85.79,12.17) v6(85.79,11.54) v6(86.43,12.17) v6(86.43,11.54) v6(86.8,16.87) v6(86.8,16.24) v6(86.8,15.6) v6(86.8,14.97) v6(87.43,15.6) v6(87.43,14.97) v6(87.92,50.43) v6(87.92,49.61) v6(88.07,15.6) v6(88.07,14.97) v6(88.7,15.6) v6(88.7,14.97) v6(88.75,50.43) v6(88.75,49.61) v6(89.21,36.3) v6(89.21,35.54) v6(89.85,36.3) v6(89.85,35.54) v6(89.97,48.24) v6(89.97,47.61) v6(89.97,46.97) v6(90.18,40.56) v6(90.48,36.3) v6(90.48,35.54) v6(90.62,48.24) v6(90.61,47.61) v6(90.61,46.97) v6(90.87,40.56) v6(90.99,30.97) v6(91.12,36.3) v6(91.12,35.54) v6(91.26,54.34) v6(91.26,53.7) v6(91.32,22.33) v6(91.32,21.7) v6(91.57,40.56) v6(91.62,31) v6(91.76,38.72) v6(91.89,54.34) v6(91.89,53.7) v6(91.95,22.33) v6(91.95,21.7) v6(92.27,40.56) v6(92.27,30.97) v6(92.53,54.34) v6(92.53,53.7) v6(92.59,22.33) v6(92.59,21.7) v6(94.35,39.92) v6(95.05,39.92) v6(95.75,39.92) v6(96.18,52.56) v6(96.25,51.39) v6(96.23,49.82) v6(96.42,34.73) v6(96.42,33.92) v6(96.37,14.13) v6(96.37,13.37) v6(96.37,12.61) v6(96.7,50.62) v6(96.77,52) v6(97.14,14.13) v6(97.14,13.37) v6(97.14,12.61) v6(97.24,34.73) v6(97.24,33.92) v6(97.42,52.55) v6(97.4,51.3) v6(97.36,49.84) v6(100.03,57.89) v6(101.15,58.91) v6(101.83,59.93) v6(101.78,57.89) v6(176.85,42.65) v6(176.85,42.02) v6(176.85,41.38) v6(177.49,42.65) v6(177.49,42.02) v6(177.49,41.38) v6(177.56,40.74) v6(178.14,41.05) v6(180.16,40.54) v6(180.51,41.07) v6(185.79,42.78) v6(185.79,42.02) v6(185.79,41.38) v6(185.79,40.75) v6(186.38,42.4) v6(186.35,41.05) v6(186.94,42.78) v6(186.94,42.02) v6(186.94,41.38) v6(186.94,40.75) v6(190.14,35.19) v6(190.14,34.37) v6(190.98,35.19) v6(190.98,34.37) v6(191.18,51.08) v6(191.25,49.97) v6(191.25,49.28) v6(192.2,61.27) v6(192.46,60.69) v6(192.46,60.05) v6(192.88,61.32) v6(193.11,60.69) v6(193.1,60.05) v6(193.73,59.8) v6(193.74,43.42) v6(193.74,42.4) v6(193.74,41.51) v6(194.82,56.19) v6(194.76,43.42) v6(194.76,42.4) v6(194.76,41.51) v6(195.46,56.19) v6(197.1,60.5) v6(200.96,44.59) v6(200.96,43.95) v6(201.59,44.59) v6(201.59,43.95) v6(223.74,39.71) v6(224.1,39.1) v6(224.43,39.71) v6(276.42,55.02) v7(142.02,67.9) v7(208.78,55.86) v8(32.25,14.77) v8(32.26,26.83) v8(32.33,22.72) v8(32.74,13.63) v8(34.04,27.22) v8(34.12,23.91) v8(34.45,27.24) v8(37.07,20.72) v8(41.08,17.46) v8(42.22,17.95) v8(44.2,10.53) v8(44.2,7.84) v8(45.22,15.81) v8(45.43,7.96) v8(49.38,11.16) v8(49.38,10.27) v8(53.83,9.03) v8(55.64,9.24) v8(57.96,7.63) v8(64.4,8.45) v8(98.85,19.6) v8(98.85,18.71) v8(103.37,53.88) v8(104.26,53.88) v8(105.85,60.88) v8(112.5,46.46) v8(114.28,46.46) v8(114.99,50.38) v8(117,57.04) v8(117,53.32) v8(117.86,49.26) v8(118.8,47.33) v8(120.58,48.01) v8(120.61,46.24) v8(121.47,48.01) v8(121.76,56.03) v8(122.87,56.04) v8(122.88,54.54) v8(122.87,52.64) v8(124.52,64.56) v8(125.66,65.06) v8(140.19,68.82) v8(150.25,50.44) v8(150.48,51.67) v8(151.33,50.61) v8(153.27,66.53) v8(153.3,48.24) v8(153.36,67.98) v8(153.42,56.68) v8(154.34,57.56) v8(155.05,47.86) v8(155.23,56.42) v8(155.81,48.75) v8(157.28,46.9) v8(157.74,45.58) v8(158.17,51.62) v8(158.2,49.72) v8(158.17,46.9) v8(162.07,12.89) v8(164.52,69.06) v8(166,52.54) v8(166,51.51) v8(166,50.6) v8(166,49.73) v8(167.16,64.98) v8(169.04,47.35) v8(169.81,48.75) v8(170.82,56.82) v8(170.87,57.26) v8(170.87,56.37) v8(171.58,53.2) v8(171.58,51.19) v8(171.89,46.34) v8(172.52,50.33) v8(172.66,53.48) v8(173.82,69.05) v8(173.83,67.04) v8(174.06,53.86) v8(174.73,66.2) v8(174.76,68.11) v8(175.5,16.78) v8(175.58,15.46) v8(175.66,13.83) v8(175.92,67.66) v8(176.33,62.42) v8(177.03,14.71) v8(177.53,12.68) v8(179.97,2.92) v8(181.72,67.4) v8(181.76,57.26) v8(182.1,48.12) v8(182.1,47.23) v8(182.22,32.35) v8(182.61,29.81) v8(182.81,56.4) v8(184.08,49.48) v8(185.86,69.02) v8(186.24,32.24) v8(186.53,31.34) v8(188.45,67.8) v8(191.38,52.81) v8(192.46,30.59) v8(194.49,22.53) v8(194.63,49.95) v8(194.63,49.06) v8(194.75,14.52) v8(196.28,12.56) v8(196.91,53.27) v8(197.95,19.19) v8(198.39,57.77) v8(199.33,56.93) v8(199.46,22) v8(199.75,19.19) v8(200.72,12.51) v8(200.82,20.39) v8(201.11,27.74) v8(201.59,24.94) v8(202.12,22.29) v8(202.37,12.51) v8(204.02,12) v8(204.4,63.48) v8(205.42,46.79) v8(206.31,46.79) v8(206.48,45.7) v8(206.81,39.28) v8(207.07,42.73) v8(207.35,63.48) v8(208.44,53.58) v8(208.82,63.48) v8(209.61,44.99) v8(210.17,53.58) v8(210.24,39.28) v8(211.13,39.28) v8(211.23,43.8) v8(211.52,69.05) v8(211.47,55.86) v8(211.46,54.97) v8(211.59,67.67) v8(211.77,49.44) v8(212.65,54.15) v8(212.65,49.44) v8(212.86,53.2) v8(215.16,63.1) v8(215.95,46.97) v8(216.87,45.19) v8(217.15,53.7) v8(218.25,44.96) v8(218.27,50.04) v8(219.98,48.74) v8(221.44,51.53) v8(221.75,55.1) v8(221.72,36.43) v8(223.08,60.03) v8(224.84,62.58) v8(225.04,61.7) v8(225.05,60.82) v8(225.05,44.62) v8(226.31,44.62) v8(227.96,38.46) v8(230.94,43.73) v8(232.01,50.78) v8(232.01,47.35) v8(232.01,46.46) v8(235.77,50.45) v8(239.91,51.93) v8(241.08,55.99) v8(242.45,52.76) v8(242.45,50.92) v8(242.89,48.7) v8(242.88,45.94) v8(243.69,56.41) v8(244.05,60.9) v8(244.05,61.73) v8(245.85,50.15) v8(246.36,56.37) v8(260.53,42.2) v8(266.5,15.15) v8(267.9,15.15) v8(269.49,46.86) v9(17.96,30.59) v9(18.37,30.59) v9(27.88,30.64) v9(34.06,11.66) v9(34.95,11.66) v9(38.6,13.7) v9(40.25,15.4) v9(41.47,13.41) v9(41.55,8.34) v9(45.4,1.87) v9(45.9,1.87) v9(48.4,4.57) v9(50.11,2.9) v9(79.97,7.53) v9(82.04,9.38) v9(82.04,8.49) v9(100.53,2.73) v9(101.42,2.73) v9(104.59,63.15) v9(105.91,40.08) v9(107.87,2.4) v9(110.11,6.75) v9(116.9,63.05) v9(117.38,50.55) v9(119.01,18.32) v9(119.36,50.53) v9(119.37,45.19) v9(120.77,51.42) v9(123.51,31.78) v9(127.11,48.21) v9(128.08,48.88) v9(135.15,9.88) v9(136.5,30.93) v9(141.55,30.99) v9(143.91,9) v9(144.86,31.99) v9(147.26,7.73) v9(147.26,7.22) v9(148.23,67.67) v9(148.23,66.78) v9(152.28,52.54) v9(152.27,32.11) v9(152.47,7.41) v9(153.68,12.24) v9(154.87,68.84) v9(156.1,58.24) v9(157.8,46.04) v9(158.74,68.44) v9(158.69,11.26) v9(159.52,56.48) v9(167.51,47.18) v9(171.46,57.26) v9(172.74,69.58) v9(174.26,51.29) v9(174.42,12.1) v9(174.57,56) v9(176.38,59.79) v9(176.65,10.18) v9(178.68,65) v9(178.71,64.42) v9(178.81,62.8) v9(178.83,62.34) v9(179.14,65) v9(179.14,64.42) v9(179.27,62.8) v9(179.27,62.34) v9(179.6,65) v9(179.6,64.42) v9(179.72,62.8) v9(179.72,62.34) v9(180.57,57.16) v9(180.66,61.07) v9(181.82,61.59) v9(182.43,48.43) v9(182.81,68.13) v9(183.46,12.51) v9(183.83,68.13) v9(184.35,12.51) v9(185.24,12.51) v9(187.01,12.51) v9(187.65,55.41) v9(187.95,11.54) v9(189.43,56.09) v9(189.83,56.09) v9(190.24,56.09) v9(190.62,56.09) v9(192.68,66.02) v9(192.79,30.84) v9(194.94,45.32) v9(195.37,45.32) v9(196.28,33.31) v9(196.28,15.17) v9(198.21,11.92) v9(198.34,51.22) v9(201.38,47.86) v9(202.14,54.92) v9(206.57,47.15) v9(206.57,45.61) v9(206.57,39.81) v9(208.43,47.1) v9(210.38,59.11) v9(211.12,45.61) v9(211.27,59.11) v9(211.4,40.88) v9(211.78,40.88) v9(212.21,47.28) v9(212.16,40.88) v9(212.54,40.88) v9(214.3,62.81) v9(214.45,35.96) v9(214.55,41.28) v9(214.94,54.59) v9(215.04,50.22) v9(216.22,35.96) v9(217.9,43.39) v9(225.62,36.05) v9(226.13,36.05) v9(227.64,36.08) v9(228.03,36.05) v9(264.46,24.13) v9(265.58,27.16) v9(270.87,17.79) v9(271.43,17.79) v10(33.96,18.67) v10(35.74,18.66) v10(101.68,34.91) v10(101.68,33.13) v10(124.71,31.73) v10(126.13,53.35) v10(143.05,66.9) v10(152.29,59.54) v10(152.28,50.92) v10(155.43,62.81) v10(155.92,66.91) v10(156.47,34.13) v10(157.09,40.19) v10(158.87,54.57) v10(159.25,36.17) v10(159.52,52.67) v10(159.52,50.76) v10(159.72,44.74) v10(160.08,40.19) v10(160.34,35.28) v10(160.78,60.97) v10(160.82,48.86) v10(161.23,66.99) v10(161.3,35.28) v10(161.54,62.16) v10(162.12,66.99) v10(162.16,58.63) v10(162.16,55.63) v10(162.16,52.63) v10(162.16,49.64) v10(162.16,46.64) v10(162.25,33.37) v10(163.46,57.09) v10(163.46,54.09) v10(163.46,51.1) v10(163.46,48.1) v10(163.46,45.1) v10(163.46,42.16) v10(163.65,36.53) v10(164.61,34.4) v10(165.42,36.53) v10(165.47,34.4) v10(168.6,35.59) v10(168.73,34.35) v10(169.04,58.23) v10(170.25,35.59) v10(170.9,47.07) v10(171.14,35.59) v10(172.92,35.59) v10(175.37,47.07) v10(205.4,60.86) v10(205.9,60.86) v10(209.4,60.86) v10(209.9,60.86) v11(113.07,66.41) v11(248.34,63.34) v11(248.84,62.34)
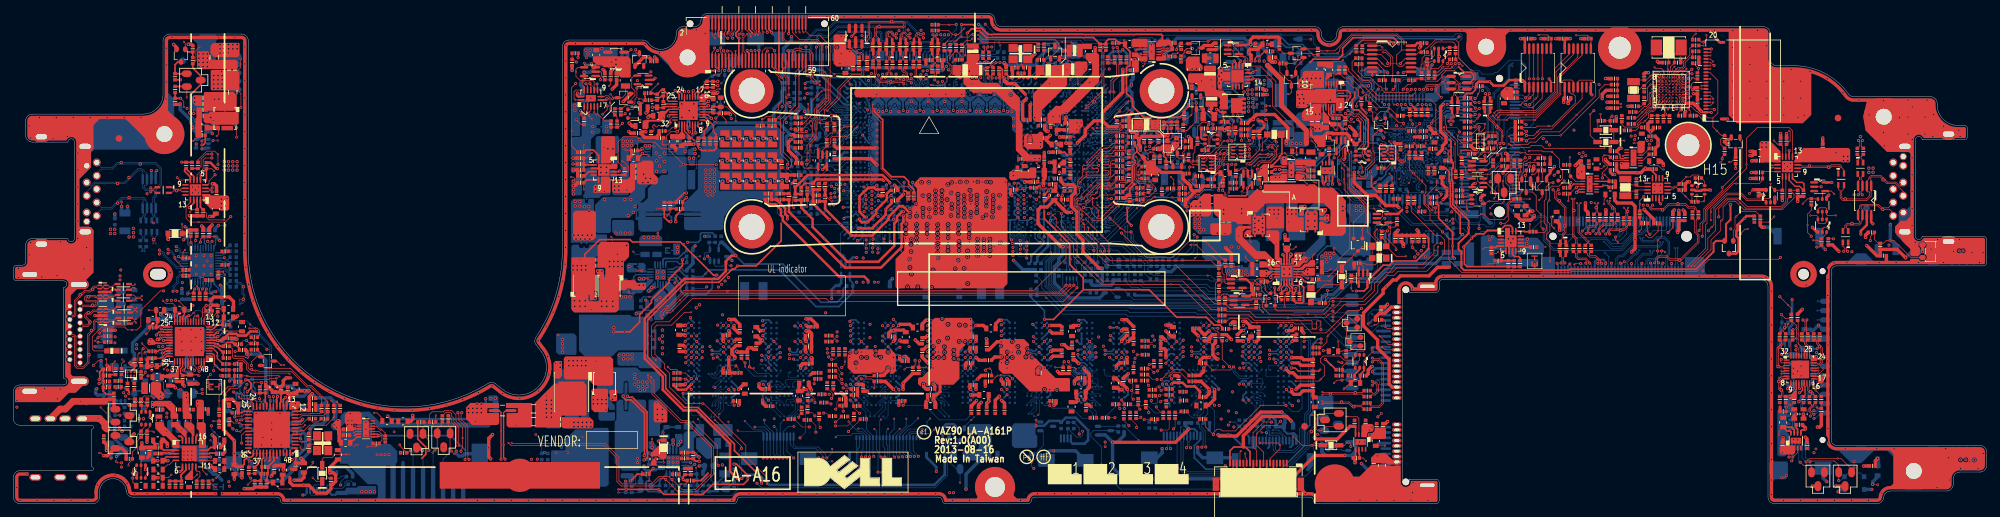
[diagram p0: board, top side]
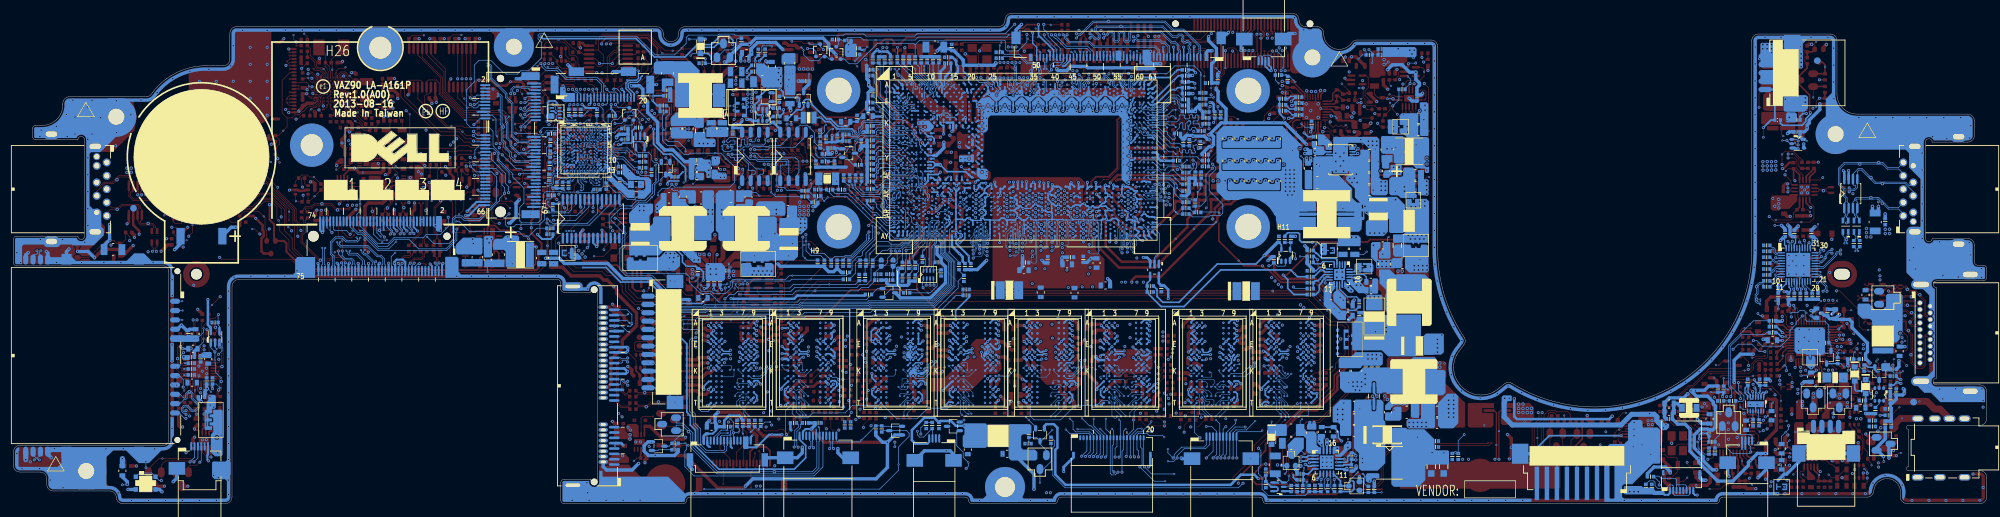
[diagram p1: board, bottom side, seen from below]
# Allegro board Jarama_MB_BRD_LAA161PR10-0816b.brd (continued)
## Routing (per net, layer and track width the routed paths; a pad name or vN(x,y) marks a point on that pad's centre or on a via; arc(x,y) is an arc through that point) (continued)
VCC: length 1.8
  BOTTOM w0.102: PR210.2 102.74,12.39 v2(102.46,12.67)
VCCSENSE: length 27.2
  TOP w0.203: PU701.24 99.63,61.34 v1(99.04,61.93)
  IN2 w0.254: v1(99.04,61.93) 99.05,61.95 99.05,62.75 99.92,63.61 102.67,63.61 105.23,61.05 106.52,61.05 109.06,58.52 112.24,58.52 114.32,60.6 114.32,61.13 116.11,62.92 118.43,62.92 v1(118.48,62.97)
  BOTTOM w0.254: v1(118.48,62.97) 118.74,63.23 RC98.1
VCCSENSE_R: length 7.1
  BOTTOM w0.254: RC98.2 RC97.2 120.96,64.14 v2(121.68,63.43) 124.83,60.27 UCPU1.E63
VCCSTPG_MCP: length 16.1
  BOTTOM w0.109: RC150.2 117.6,61.73 v2(117.6,64.27) 117.6,64.65 118.56,65.62 121.5,65.62 122.65,64.48 126.71,64.48 127.51,63.67 127.51,63.32 127.88,62.95 127.88,62.49 UCPU1.B59
VDD_+1.2V: length 2.9
  BOTTOM w0.254: PR604.1 93.95,29.5 94.47,28.98 95.47,28.98 PC612.1
  vias: v2(97.63,29.24)
VIN: length 260
  TOP w0.254: PR208.1 102.86,3.46 103.92,4.53 v7(103.93,4.53) ; PR123.1 197.21,20.81 197.15,20.81 v1(196.34,21.62) ; v6(107.87,5.93) 108.22,5.93 109.91,4.24 v1(109.91,3.79) 109.91,3.54 109.26,2.89 104.67,2.89 103.17,1.4 97.35,1.4 v5(96.6,2.14) v5(91.74,2.14) v7(90.52,2.14)
  IN1 w0.254: v3(31.26,31.12) 31.26,24.53 32.04,23.75 32.04,22.65 31.69,22.31 31.69,19.9 31.79,19.79 31.79,19.16 31.44,18.8 31.44,16.92 31.18,16.67 31.18,15.88 31.95,15.12 31.95,13.19 34.28,10.85 34.28,9.63 34.64,9.28 34.64,6.03 37.65,3.02 42.39,3.02 42.6,3.23 46.01,3.23 46.46,2.78 48.18,2.78 48.75,3.35 55.78,3.35 56.99,2.14 v7(90.52,2.14) ; v6(106.11,5.8) 106.11,5.49 105.43,4.81 104.74,4.81 104.46,4.53 v7(103.93,4.53)
  IN2 w0.254: v1(109.91,3.79) 109.94,3.82 143.04,3.82 145.38,6.17 148.41,6.17 151.45,3.12 192.94,3.12 195.65,5.82 195.65,20.94 v1(196.34,21.62)
  IN3 w0.254: v1(25.99,59.27) 25.83,59.1 25.83,51.04 24.89,50.1 24.89,41.21 26.08,40.01 26.08,38.79 26.89,37.98 28.64,37.98 29.05,37.57 29.05,33.97 31.26,31.76 v3(31.26,31.12)
  IN4 w0.254: v1(25.99,59.27) 27.25,59.27 28.62,60.64 v6(30.75,60.64)
  vias: v5(30.11,60.63)
VSSSENSE: length 25.9
  TOP w0.203: v6(99.69,61.93) 99.69,61.79 100.03,61.45 PU701.23
  IN2 w0.254: v6(99.69,61.93) 99.69,62.48 100.18,62.97 102.41,62.97 104.97,60.42 106.26,60.42 108.79,57.88 112.5,57.88 115,60.38 115,60.92 116.37,62.29 v1(118.51,62.29)
  BOTTOM w0.254: RC99.2 119.42,62.34 118.56,62.34 v1(118.51,62.29)
VSSSENSE_R: length 7.2
  BOTTOM w0.254: RC100.1 RC99.1 121.06,62.37 v2(121.38,62.05) 122.12,62.05 124.25,59.93 124.48,59.93 124.65,59.76 125.11,59.76 UCPU1.E62
1.2_PGND: length 19.6
  TOP w0.254: UA1.12 42.91,13.84 43.1,14.03
  TOP w0.508: 43.1,14.03 44.29,14.03 RA13.1 RA12.1 RA11.1 44.3,16.06 44.67,16.42 44.7,16.42 v1(44.72,16.44) ; CA8.2 39.55,17.52 CA10.2 40.39,17.85 40.39,18.42 v2(40.82,18.86) v7(41.48,18.86)
  IN1 w0.508: v1(44.72,16.44) 44.57,16.29 43.81,16.29 43.33,16.77 43.32,16.77 41.48,18.61 v7(41.48,18.86)
  BOTTOM w0.508: CA18.2 48.22,12.98 CA20.2 CA19.2 48.22,15.11 47.47,15.86 45.35,15.86 44.76,16.44 v1(44.72,16.44)
3&5V_B+: length 13.8
  IN1 w0.508: v6(191.15,37.37) 190.94,37.58 190.77,37.58 189.2,39.15 184.37,39.15 181.12,42.4 v6(181.12,43.44) v6(181.12,44.08)
  vias: v2(190.53,46.11) v6(183.81,44.19) v6(183.81,43.55) v6(198.95,44.56) v6(198.95,43.92)
+1.5VS_SS/TR: length 3.4
  TOP w0.109: PC433.1 v2(85.36,47.09)
  TOP w0.254: PC433.1 85.78,48.53 PU405.9
+1.8VS_SS/TR: length 1.5
  TOP w0.254: PC437.1 226.15,38.45 226,38.6 PU406.9
+5PVDD: length 17.7
  TOP w0.254: U4.6 25.31,5.07 25.05,4.81 v1(24.9,4.81) ; C46.1 22.89,7 U4.4 ; C21.1 22.49,8.04 23.72,8.04 23.76,8 U4.2 ; U4.14 29.09,8 29.53,8.44 C44.1
  TOP w0.508: C46.1 v1(23.12,6.43) ; R34.2 31.35,7.45 31.63,7.73 v1(31.63,8.09) ; v1(23.04,8.57) 23.04,9.03 22.59,9.48 C27.1 22.13,9.29 C21.1 ; v1(29.75,10.3) 30.17,9.88 C43.1 30.17,8.53 C44.1
  IN1 w0.254: v7(29.22,2.47) v3(28.7,2.47) ; v7(23.37,2.47) v3(22.93,2.47)
  IN4 w0.508: v1(29.75,10.3) 29.75,9.97 v1(31.63,8.09)
  vias: v1(22,16.4) v1(22,15.81) v2(22.43,16.11)
+EC_VCCA:
  vias: v2(205.58,48.17) v4(206.24,48.6) v4(206.27,48.98) v4(207.66,50.78) v4(207.98,50.81)
+EDP_COM: length 4.5
  TOP w0.508: RC36.1 151.03,57.72 v2(151.03,60.16) v7(151.62,60.74)
  IN1 w0.508: v3(152.04,60.77) 151.64,60.77 v7(151.62,60.74)
  IN4 w0.508: v4(152.45,61.03) 152.38,61.03 152.11,60.77 v3(152.04,60.77)
+HDMI_5V:
  vias: v2(13.19,27.47)
+HDMI_5V_OUT:
  vias: v2(16.31,21.61)
+INV_PWR_SRC: length 2.4
  BOTTOM w0.102: v5(89.54,66.2) 89.9,65.85 v6(90.18,65.85)
  BOTTOM w0.254: JLVDS2.25 v4(129.65,67.71) ; JLVDS2.26 v4(130.15,67.67)
  vias: v6(90.18,66.56)
+LCDVDD: length 49.1
  TOP w0.762: v7(187.67,65.72) 187.67,65.71 189.77,63.61 189.77,59.66 193.5,55.93 193.5,54.23 193.5,54.22 193.5,53.96
  IN1 w0.508: v7(187.67,65.72) 187.94,65.98 v3(187.94,66.32)
  IN3 w0.762: 124.14,66.85 118.24,66.85 116.93,65.54 108.76,65.54 107.38,64.17 105.2,64.17 102.03,60.99 95.8,60.99 v1(93.39,63.41)
  vias: v1(123.69,65.96) v1(123.88,70.06) v1(124.48,70.06) v1(125.15,67.79) v5(123.89,67.43) v6(187.18,66.33)
+LCDVDD_R: length 15.1
  TOP w0.356: v1(96.03,63.78) 95.78,63.52 U708.2
  TOP w0.508: Q71.2 94.4,66.99 v1(95.04,66.99) 95.38,66.65 R1161.1 ; D105.1 93.82,59.9 v1(93.61,60.11)
  IN2 w0.508: v1(93.61,60.11) 96.03,62.54 v1(96.03,63.78) 96.03,66 v1(95.04,66.99)
  BOTTOM w0.102: v1(93.61,60.11) v2(94.16,60.11)
+ODR_PWR: length 2.8
  TOP w0.203: v1(267.28,17.25) 267.2,17.33 U1.12
  BOTTOM w0.102: v4(267.79,24.75) 266.83,25.7 v2(266.83,26.27)
  vias: v3(267.79,24.34) v3(268.29,24.34) v4(268.24,24.75)
+PCH_VCCDSW: length 4.2
  TOP w0.102: v7(153.64,47.66) 153.64,46.12 v2(153.45,45.93)
  TOP w0.254: v7(153.64,47.66) 153.47,47.66 RH346.1
  IN1 w0.254: v7(153.64,47.66) 153.64,47.89 v3(153.5,48.02)
  IN4 w0.254: v4(152.93,48.02) v3(153.5,48.02)
  BOTTOM w0.254: v4(152.93,48.02) UCPU1.AG20
+RTC_VCCSUS: length 5.5
  TOP w0.102: RH341.2 155.38,47.29 154.55,47.29 154.46,47.2 v2(154.15,47.2)
  TOP w0.508: RH341.2 155.96,47.11 v7(155.96,47.86)
  IN1 w0.508: v3(155.77,46.97) 155.96,47.16 v7(155.96,47.86)
  IN4 w0.381: v4(156.46,47.66) v3(155.77,46.97)
  BOTTOM w0.254: UCPU1.AH11 156.78,47.34 v4(156.46,47.66)
+RTCBATT: length 6.2
  TOP w0.102: v2(263.52,43.04) 262.68,42.2 RTCR1.2
  TOP w0.508: RTCR1.2 261.42,41.7 261.69,41.44 v1(262,41.44)
  BOTTOM w0.508: v1(262,41.44) 262.69,41.44 PBJ1.1
+RTCVCC: length 358.6
  TOP w0.381: CH95.1 259.37,43.11 v1(259.02,42.77) 258.01,41.76 258.01,40.96 257.84,40.8 257.84,40.09 258.17,39.76 258.17,37.84 257.82,37.49 RTCD1.1
  TOP w0.508: CH82.1 156.72,48.37 v7(157.28,47.81) CH84.1 158.53,47.81 158.88,47.46 158.88,46.59 158.32,46.03 158.32,44.56 159.16,43.72 159.16,40.37 160.08,39.45 160.08,37.72 162.52,35.28 v1(162.92,35.28) ; v1(71.7,10.37) 71.7,10.35 71.14,9.79 v5(71.14,8.38) 71.14,7.01 v1(71.43,6.71) ; R1348.2 238.89,50.9 238.26,51.53 v1(238.26,51.62)
  IN1 w0.508: v3(157.28,48.24) v7(157.28,47.81)
  IN2 w0.381: v3(182.53,47.35) 183.15,46.73 191.31,46.73 192.39,47.81 193.45,47.81 194.1,48.46 199,48.46 200.07,47.39 202.43,47.39 203.78,46.05 207.64,46.05 209.85,43.84 211.7,43.84 212.22,43.32 214.01,43.32 214.28,43.05 215.04,43.05 215.19,43.2 219.6,43.2 221.56,45.16 222.84,45.16 225.47,42.53 225.99,42.53 227.01,41.51 v3(227.56,41.51) ; v1(238.26,51.62) 239.45,50.43 242.45,50.43 243.57,49.31 247.97,49.31 251.81,45.47 254.91,45.47 257.61,42.77 v1(259.02,42.77)
  IN2 w0.508: v3(157.28,48.24) 156.85,48.67 153.13,48.67 v3(152.77,49.03)
  IN3 w0.381: v3(182.53,47.35) 182.57,47.35 181.39,48.54 176.43,48.54 175.22,47.32 167.9,47.32 167.13,48.09 166.15,48.09 165.03,46.97 163.62,46.97 163.37,46.72 157.85,46.72 157.28,47.29 v3(157.28,48.24) ; v3(227.56,41.51) 227.56,40.52 230.93,37.16 250.78,37.16 256.39,42.77 v1(259.02,42.77)
  IN3 w0.508: v1(71.7,10.37) 71.72,10.35 73.53,10.35 74.77,9.1 92.25,9.1 94.79,11.64 97.78,11.64 98.87,12.74 98.87,16.74 99.87,17.74 99.87,28.18 102.18,30.49 106.14,30.49 115.19,39.54 115.19,42.94 115.52,43.28 116.79,43.28 122.4,48.88 124.68,48.88 125.16,48.4 125.16,47.33 v3(124.94,47.1)
  IN4 w0.508: v4(157.81,48.02) 157.63,48.2 157.31,48.2 157.28,48.23 v3(157.28,48.24) ; v3(124.94,47.1) 126.09,47.1 127.72,48.73 138.55,48.73 139.13,49.31 148.63,49.31 149.35,48.6 150.62,48.6 151.05,49.03 v3(152.77,49.03) ; v4(18.12,13.53) 18.12,12.4 21.23,9.29 23.32,9.29 24.06,8.56 29.64,8.56 33.03,5.16 38.86,5.16 39.67,4.35 42.36,4.35 42.7,4.01 47.91,4.01 48.44,4.54 49.71,4.54 50.64,5.47 70.19,5.47 v1(71.43,6.71)
  BOTTOM w0.508: RA16.1 18.09,13.51 v4(18.12,13.53) ; RH11.1 v1(162.92,35.28) 162.92,34.58 162.96,34.54 162.96,32.72 ; 162.96,32.72 164.26,32.72 164.61,33.08 RH23.1 RH25.1 ; 162.96,32.72 161.51,32.72 161.3,32.94 RH147.1 RH31.1
+SD_VDD2: length 36.1
  TOP w0.203: v1(267.28,16.62) 267.37,16.62 267.75,17 267.75,17.43 267.6,17.58 U1.13
  TOP w0.508: CR5.1 278.64,6.42 v1(278.99,6.76)
  IN2 w0.762: v6(293.45,6.57) 293.45,6.88 293.01,7.32 290.95,7.32 290.52,6.89 290.52,6.59 289.91,5.98 287.55,5.98 286.2,7.32 279.8,7.32 279.24,6.76 v1(278.99,6.76)
  IN3 w0.762: v1(278.99,6.76) 278.73,6.76 278.43,7.07 271.67,7.07 269.13,9.61 269.13,11.51 268.23,12.41
  BOTTOM w0.762: v1(278.99,6.76) CR19.1 ; JCARD.16 v6(293.45,6.57)
+VCHGR: length 0.6
  TOP w0.102: v1(93.4,6.14) v5(93.4,6.78)
+VREFCA: length 156.7
  TOP w0.381: v1(101.46,17.92) 101.46,17.91 v2(100.64,17.09) 99.46,17.09 98.85,17.7 CD1.2 ; v1(113,17.93) 113.1,17.83 CD2.2 ; RD15.1 RD13.2 CD90.1 RD14.2 119.69,44.99 122.05,42.63 122.08,42.63 v1(122.1,42.6) ; v1(173.35,17.92) 173.56,18.12 CD68.2 174.99,18.12 175.55,17.57 176.82,17.57 177.53,16.86 CD69.2
  TOP w0.508: CD24.2 127.04,17.9 v1(126.12,17.9) ; v1(148.71,18.72) 148.71,18.62 149.04,18.29 CD46.2 ; v1(137.65,17.92) 137.86,17.71 CD25.2 ; v1(160.25,17.93) 160.34,18.02 CD45.2
  IN1 w0.508: v1(148.71,18.72) 148.71,18.65 148.06,18 146.43,18 146.07,18.36 145.03,18.36 144.58,17.91 140.47,17.91 139.54,18.84 137.95,18.84 137.65,18.53 v1(137.65,17.92)
  IN2 w0.381: v1(122.1,42.6) 118.07,38.57 114.88,38.57 103.68,27.36 103.68,19.19 102.41,17.92 v1(101.46,17.92)
  IN2 w0.508: v1(137.65,17.92) 137.65,17.2 138.47,16.37 138.47,14.85 136.41,12.79 134.67,12.79 134.01,13.44 133.42,13.44 132.91,13.95 129.48,13.95 126.12,17.32 ; 126.12,17.32 125.02,16.22 124.29,16.22 121.62,18.88 113.34,18.88 ; 126.12,17.32 v1(126.12,17.9)
  IN3 w0.508: v1(184.86,17.92) 184.86,17.46 184.39,16.98 183.26,16.98 181.28,18.96 179.77,18.96 178.73,17.92 v1(173.35,17.92) 174.11,17.17 174.11,15.14 172.74,13.78 170.71,13.78 169.59,14.89 161.96,14.89 ; 161.96,14.89 160.25,16.59 v1(160.25,17.93) ; 161.96,14.89 160.23,13.17 159.43,13.17 159.02,12.76 157.35,12.76 156.86,13.24 156.15,13.24 155.75,13.65 154.98,13.65 151.4,17.23 149.97,17.23 148.71,18.49 v1(148.71,18.72)
  BOTTOM w0.381: v1(126.12,17.9) 126.5,18.27 UD4.M8 ; v1(137.65,17.92) 138.05,18.32 UD5.M8 ; v1(184.86,17.92) 184.86,17.97 185.21,18.32 UD10.M8 ; UD6.M8 149.1,18.33 v1(148.71,18.72) ; v1(101.46,17.92) 101.86,18.32 UD1.M8 ; v1(160.25,17.93) 160.25,17.98 160.6,18.32 UD7.M8 ; UD2.M8 113.4,18.32 v1(113,17.93) ; v1(173.35,17.92) 173.74,18.31 UD9.M8
+VREFDQ_A: length 88.8
  TOP w0.381: v1(115.82,42.67) 115.82,43.12 115.5,43.44 115.5,44.26 114.28,45.47 RD19.2 RD17.2 RD21.1
  TOP w0.508: CD4.2 119.52,21.8 v1(119.41,21.91) ; CD27.2 144.49,21.5 v1(144.06,21.93) ; v1(133.28,22.07) 133.54,22.07 133.92,21.68 CD26.2 ; CD3.2 108.17,23.71 107.53,23.08 v2(107.53,22.47) 107.98,22.02 v1(107.98,21.8)
  IN2 w0.508: v1(107.98,21.8) 108.49,21.8 108.92,22.23 108.92,23.68 109.3,24.06 110.61,24.06 111.08,23.59 111.08,21.25 111.5,20.83 112.53,20.83 112.73,21.03 118.71,21.03 119.41,21.74 v1(119.41,21.91) 119.84,21.91 120.28,22.36 120.28,22.77 121.5,23.98 122.24,23.98 122.63,23.59 125.54,23.59 126,24.04 126,24.84 127.02,25.86 130.77,25.86 131.4,25.24 132.9,25.24 133.28,24.85 v1(133.28,22.07) 134.54,20.82 136,20.82 137.52,19.29 139.11,19.29 140.8,20.98 143.54,20.98 144.06,21.5 v1(144.06,21.93)
  IN3 w0.381: v1(107.98,21.8) 108.12,21.8 108.83,22.51 108.83,32.37 115.82,39.36 115.82,42.66 v1(115.82,42.67)
  BOTTOM w0.381: UD1.H1 107.7,21.52 v1(107.98,21.8) ; UD2.H1 119.02,21.52 v1(119.41,21.91) ; v1(144.06,21.93) 143.65,21.53 UD5.H1 ; v1(133.28,22.07) 133.28,21.89 132.91,21.52 UD4.H1
+VREFDQ_B: length 119.1
  TOP w0.381: v1(131.16,48.08) 131.16,48.15 130.05,49.26 v2(123.37,49.26) 118.85,49.26 117.1,47.51 RD22.1 117.02,47.48 RD20.2 RD18.2
  TOP w0.508: v1(180.25,21.69) 180.1,21.69 179.51,22.28 179.51,23.73 179.89,24.11 CD70.2 ; CD47.2 155.56,22.11 v1(155.27,21.82) ; v1(191.32,21.96) 191.41,21.88 192.79,21.88 193.1,21.57 194.43,21.57 CD71.2 ; CD48.2 166.66,21.15 166.66,21.92 v1(166.65,21.93)
  IN3 w0.381: v3(150.29,46.62) 150.29,46.36 148.53,44.61 148.53,31.96 153.56,26.93 153.56,24.27 154.27,23.55 154.27,22.92 155.27,21.92 v1(155.27,21.82)
  IN3 w0.508: 166.09,21.07 162.23,21.07 160.71,19.55 159.24,19.55 158.35,20.44 157.09,20.44 155.71,21.82 v1(155.27,21.82) ; 166.09,21.07 166.65,21.63 v1(166.65,21.93) ; 166.09,21.07 166.47,21.07 167.24,20.31 167.96,20.31 169.17,21.52 171.02,21.52 172.9,19.64 178.95,19.64 180.04,20.73 180.04,21.48 v1(180.25,21.69) ; v1(191.32,21.96) 191.64,21.96 192.04,21.56 192.04,20.02 191.38,19.36 185.41,19.36
  IN4 w0.381: v3(150.29,46.62) 149.7,47.2 148.89,47.2 148.46,47.63 147.77,47.63 146.61,48.79 139.82,48.79 138.64,47.61 135.86,47.61 135.4,47.15 131.54,47.15 131.16,47.53 v1(131.16,48.08)
  BOTTOM w0.381: UD9.H1 179.51,21.69 v1(180.25,21.69) ; v1(166.65,21.93) 166.26,21.54 UD7.H1 ; v1(191.32,21.96) 190.9,21.53 UD10.H1 ; v1(155.27,21.82) 154.98,21.52 UD6.H1
+VS_LPSS_SDIO: length 45.4
  TOP w0.508: RH434.1 163.89,56.5 163,57.39 ; RH350.1 186.52,68.45 186.52,68.4 186.23,68.11 CH1227.1 185.08,68.11 184.85,67.88 v2(184.85,67.61) 185.22,67.24 v1(185.22,66.35) ; 163,57.39 161.73,57.39 160.41,56.07 160.41,55.25 159.24,54.08 v1(159.24,54.07) ; 163,57.39 163,58.66 166.03,61.69 v1(166.03,65.11)
  IN2 w0.508: v1(166.03,65.11) 166.13,65.21 168.05,65.21 168.68,65.84 175.22,65.84 175.41,66.02 177.44,66.02 v3(179.47,68.05)
  IN4 w0.508: v3(179.47,68.05) v4(180.13,68.05)
  BOTTOM w0.254: UCPU1.U8 158.43,54.06 UCPU1.T9
  BOTTOM w0.305: v1(159.24,54.07) 159.24,53.98 UCPU1.U8
  BOTTOM w0.508: v4(180.13,68.05) 181.21,69.13 183.93,69.13 184.88,68.18 RH354.1 184.88,67.38 185.22,67.04 v1(185.22,66.35)
AC_PRESENT: length 43.1
  TOP w0.109: RH12.1 178.31,48.62 RH137.2 177.83,49.84 177.54,50.13 177.54,51.87 177.73,52.06 178.21,52.06 178.68,52.53 179.18,52.53 179.98,53.32 180.23,53.32 180.85,53.95 180.85,54.14 181.09,54.38 v2(181.16,54.38) v1(181.76,54.38)
  IN2 w0.102: v3(212.34,52) 212.24,52.1 209.11,52.1 206.9,54.31 206.83,54.31 205.74,55.4 205.43,55.4 205.23,55.2 200.34,55.2 199.91,54.77 193.62,54.77 193.52,54.87 189.93,54.87 189.47,55.33 182.7,55.33 181.76,54.39 v1(181.76,54.38)
  IN4 w0.076: v4(212.06,51.7) 212.06,51.72 v3(212.34,52)
  BOTTOM w0.109: v4(212.06,51.7) 212.31,51.44 U34.M10
AC_PRESENT_R: length 23
  TOP w0.109: RH137.1 176.92,49.06 v7(176.43,48.57) ; v1(164.32,45.73) 164.31,45.74 v2(163.75,45.74)
  IN1 w0.076: v3(175.89,48.83) 176.13,48.83 176.38,48.57 v7(176.43,48.57)
  IN4 w0.076: v3(175.89,48.83) 175.46,48.4 175.46,47.81 175.22,47.57 171.19,47.57 170.46,46.85 168.57,46.85 167.45,45.73 v1(164.32,45.73) 163.85,45.73 163.82,45.75 163.48,45.75 163.15,46.08 161.28,46.08 160.99,45.79 160.99,45.79 160.85,45.65 160.45,45.65 160.35,45.55 159.94,45.55 159.86,45.63 159.86,45.63 159.83,45.65 159.28,45.65 159.15,45.53 158.97,45.53 v4(158.87,45.42)
  BOTTOM w0.109: v4(158.87,45.42) 158.87,45.58 158.46,45.98 158.46,46.24 158.87,46.65 UCPU1.AJ8
ACCEL_INT1: length 116.4
  TOP w0.109: v2(237.52,58.4) 237.52,57.73 v7(237.18,57.39) 237.11,57.32 D87.2
  IN1 w0.076: v7(237.18,57.39) 237.34,57.55 237.34,62.78 v1(237.31,62.82)
  IN2 w0.102: v1(237.31,62.82) 237.27,62.82 234.6,65.49 222.5,65.49 222.16,65.15 217.68,65.15 216.59,64.06 206.78,64.06 204.43,66.41 200.49,66.41 199.66,67.24 194.99,67.24 192.88,69.35 181.48,69.35 181.08,69.75 170,69.75 169.53,69.27 153.45,69.27 153.4,69.22 137.36,69.22 136.47,68.33 v3(136.47,67.17)
  IN4 w0.076: v3(136.47,67.17) 136.45,67.18 136.45,67.76 v4(136.48,67.79)
  BOTTOM w0.109: v4(136.48,67.79) 136.15,67.46 JLVDS2.38
ACCEL_INT2: length 129.1
  TOP w0.076: v1(250.6,62.49) 250.58,62.47 250.37,62.47 250.26,62.58 249.74,62.58 249.6,62.44 249.6,62.21 249.46,62.08 248.6,62.08 248.36,61.84 U636.E4
  IN2 w0.102: v1(250.6,62.49) 250.35,62.75 248.46,62.75 247.62,63.58 244.09,63.58 243.45,64.22 240.23,64.22 238.42,62.42 236.85,62.42 234,65.26 222.6,65.26 222.25,64.92 217.78,64.92 216.66,63.8 205.59,63.8 203.96,65.44 202.16,65.44 201.42,66.18 200.39,66.18 199.56,67.01 194.81,67.01 192.83,68.99 189.45,68.99 188.82,68.36 182.09,68.36 180.93,69.52 170.13,69.52 169.65,69.05 157.15,69.05 153.7,65.59 144.36,65.59 143.3,66.65 143.3,68.08 142.39,68.99 138.12,68.99 137.05,67.93 v3(137.05,67.17)
  IN4 w0.076: v4(136.98,67.75) 136.98,67.24 v3(137.05,67.17)
  BOTTOM w0.109: JLVDS2.39 136.65,67.43 v4(136.98,67.75)
ACDET: length 4.8
  TOP w0.109: PR208.2 100.84,3.16 100.63,2.94 v2(99.93,2.94)
  TOP w0.254: PR213.1 PC216.1 100.23,4.07 v1(100.23,3.62) 100.39,3.46 PR208.2
  BOTTOM w0.254: PU201.6 99.74,4.16 100.03,3.87 100.03,3.82 v1(100.23,3.62)
ACDRV: length 127.2
  TOP w0.254: v1(28.21,53.78) 28.43,53.78 v2(28.71,54.06) PR206.2
  IN1 w0.254: v1(101.97,5.9) 101.97,4.58 100.31,2.92 93.57,2.92 92.6,3.89 91.46,3.89 90.47,2.9 57.3,2.9 56.1,4.11 48.43,4.11 47.86,3.54 46.78,3.54 46.32,4 42.58,4 41.99,4.59 39.97,4.59 39.55,5 39.55,6.15 38.02,7.68 37.48,7.68 36.65,8.52 36.65,10.4 36.09,10.96 36.09,12.42 33.81,14.69 33.81,15.13 34.18,15.5 34.41,15.5 35.49,16.59 35.49,17.3 35.45,17.35 35.45,18.76 34.66,19.55 34.66,21.2 33.69,22.17 33.69,23.18 32.02,24.84 32.02,31.51 31.93,31.6 31.93,35.71 31.03,36.61 31.03,38.31 31.46,38.74 31.46,39.91 30.63,40.75 29.38,40.75 28.75,41.38 28.75,42.22 28.19,42.78 28.19,47.63 27.35,48.47 27.35,53.02 28.11,53.78 v1(28.21,53.78)
  BOTTOM w0.254: v1(101.97,5.9) 101.86,5.9 101.58,5.62 101.09,5.62 101,5.71 PU201.4
ACIN: length 166.9
  TOP w0.109: v1(204.2,13.01) v5(204.72,13.53)
  IN4 w0.076: v4(101.69,3.28) 102,2.98 105.02,2.98 105.91,3.87 108.27,3.87 109.27,4.87 117.35,4.87 117.75,4.48 127.55,4.48 128.97,3.06 142.11,3.06 144.82,5.77 147.91,5.77 151.57,2.11 185.85,2.11 186.57,2.83 192.39,2.83 194.85,5.29 196.06,5.29 203.78,13.01 v1(204.2,13.01) 204.59,13.41 204.59,32.16 207.29,34.86 208.22,34.86 211.49,38.13 211.49,39.01 210.9,39.6 210.9,40.07 211.38,40.55 211.69,40.55 212.11,40.97 212.11,41.53 213.04,42.45 213.04,43.96 214.36,45.28 214.36,46.01 214.27,46.1 214.27,46.75 213.86,47.16 213.86,47.81 213.77,47.9 213.77,49.41 213.43,49.75 213.43,50.71 213.67,50.95 213.67,51.76 v4(213.45,51.98) 213.4,52.03 213.4,52.33 213.07,52.66 212.87,52.66 212.59,52.94 211.35,52.94 211.04,53.25 210.08,53.25 v4(209.98,53.15)
  BOTTOM w0.076: U34.F5 209.54,53.76 209.54,53.42 209.82,53.15 v4(209.98,53.15)
  BOTTOM w0.109: v4(213.45,51.98) 213.62,51.98 213.87,51.72 214.26,51.72 214.85,51.14 C1116.2 ; PR119.1 PR238.1 101.85,2.29 101.85,3.13 v4(101.69,3.28)
ACOFF: length 144.8
  TOP w0.109: v2(206.75,50.35) v7(206.75,51.42) 206.48,51.68 RP22.1
  IN1 w0.076: v7(206.75,51.42) 206.8,51.47 v3(206.8,51.8)
  IN4 w0.076: v3(206.8,51.8) 206.6,52 v4(206.47,52) 206.15,52 205.73,51.58 205.73,50.59 205.96,50.36 205.96,48.34 203.83,46.21 203.83,42.65 202.51,41.33 202.51,38.18 197.88,33.55 197.88,26.7 196.92,25.74 196.92,21.62 196.18,20.88 196.18,14.32 194.58,12.72 194.23,12.72 190.03,8.52 179.76,8.52 179.05,7.8 156.65,7.8 155.94,8.51 154.07,8.51 151.12,11.46 142.43,11.46 140.49,9.53 125.46,9.53 125.06,9.13 119.67,9.13 119.3,8.76 112.29,8.76 108.01,4.48 v4(105.02,4.48)
  BOTTOM w0.076: U34.A9 206.53,51.94 v4(206.47,52)
  BOTTOM w0.109: v4(105.02,4.48) 104.73,4.77 PQ202.2
ACOK: length 4.9
  BOTTOM w0.109: v2(102.16,5.39) 102.16,4.99 102.28,4.87 PR226.1
  BOTTOM w0.254: PU201.5 100.78,5.21 101.53,4.45 PR226.1 PR223.2 102.33,3.51 PR238.2
AD_BID0: length 5.5
  TOP w0.109: v7(205.92,49.49) 206.31,49.1 v2(206.31,48.78) R225.2 C283.1 204.56,47.7 R219.1
  IN1 w0.076: v7(205.92,49.49) 205.95,49.51 v3(206.32,49.51)
  IN4 w0.076: v3(206.32,49.51) 206.32,49.89 v4(206.29,49.92)
  BOTTOM w0.254: U34.A12 206.59,50.44 206.29,50.14 v4(206.29,49.92)
ADP_I: length 149
  TOP w0.109: v1(99.59,3.62) 99.57,3.63 PC220.2
  IN4 w0.076: v1(99.59,3.62) 99.59,3.59 99.99,3.18 100.63,3.18 101.34,3.89 105.06,3.89 105.44,4.28 108.1,4.28 112.38,8.55 119.38,8.55 119.73,8.9 125.12,8.9 125.55,9.33 140.58,9.33 142.51,11.26 151.03,11.26 153.98,8.31 155.86,8.31 156.57,7.6 179.18,7.6 179.9,8.31 190.11,8.31 194.32,12.52 194.67,12.52 196.39,14.24 196.39,20.8 197.12,21.53 197.12,25.65 198.09,26.62 198.09,33.47 202.71,38.09 202.71,41.24 204.03,42.57 204.03,45.58 207.51,49.07 v4(207.73,49.07)
  BOTTOM w0.076: v4(207.73,49.07) 207.6,49.2 207.6,50.2
  BOTTOM w0.109: PU201.7 99.24,3.97 v1(99.59,3.62) 99.62,3.58 PR116.1 ; v4(207.73,49.07) 207.73,49.01 v2(207.42,48.7)
  BOTTOM w0.254: U34.B12 207.6,50.2
ADPIN: length 6.3
  TOP w0.109: v5(34.05,59.39) 34.05,61.49 PL101.1 ; PC101.1 34.02,65.36 v5(34.02,66.7)
  vias: v5(31.15,64.75) v6(29.99,64.17) v6(29.99,63.53) v6(29.99,62.9) v6(29.99,62.26) v6(30.63,64.17) v6(30.63,63.53) v6(30.63,62.9) v6(30.63,62.26) v6(31.26,64.17) v6(31.26,63.53) v6(31.26,62.9) v6(31.26,62.26)
AGC: length 6
  TOP w0.109: v2(30.28,2.52) 30.08,2.52 R24.1 R27.2 C45.1 27.44,3.59 27.92,4.07 27.92,4.71 27.77,4.86 27.44,4.86 27.31,4.99 U4.10
ALL_SYS_PCH_PWROK_EC: length 3.8
  TOP w0.109: U691.4 185.51,29.81 R1292.1 186.46,29.81 186.46,29.22 v2(186.99,28.69)
ALS_INT#: length 61.9
  TOP w0.109: v1(207.1,59.83) v2(206.6,59.83)
  IN1 w0.076: v3(252.67,67.8) v7(252.23,67.8)
  IN2 w0.102: v3(252.67,67.8) 252.67,66.96 253.13,66.51 253.13,64.04 252.19,63.1 252.19,61.55 251.15,60.51 248.79,60.51 247.45,59.16 243.46,59.16 237.59,53.3 229.63,53.3 226.64,56.29 224.61,56.29 219.7,61.2 218.33,61.2 218.15,61.02 208.02,61.02 207.1,60.1 v1(207.1,59.83)
  BOTTOM w0.109: JLVDS1.12 206.4,60 206.57,59.83 v1(207.1,59.83)
ALS_INT#_HUB: length 6.7
  TOP w0.076: U636.E6 248.58,63.08 248.58,63.94 248.61,63.97
  TOP w0.109: R1116.2 R1143.1 250.96,66.91 250.19,66.14 250.19,65.5 249.85,65.17 249.37,65.17 248.61,64.41 248.61,63.97
ALS_SMBCLK: length 14.9
  TOP w0.109: v2(216.86,65.63) 216.52,65.97 v1(216.36,65.97) 215.86,66.47 R985.1 215.83,66.63 R983.1
  BOTTOM w0.109: v1(216.36,65.97) 216.21,65.82 216.21,65.52 215.64,64.95 213.97,64.95 212.62,63.6 208.06,63.6 207.31,62.85 207.31,61.77 207.4,61.68 JLVDS1.10
ALS_SMBDATA: length 17.5
  TOP w0.102: v1(215.77,65.97) 215.77,65.94 v2(215.3,65.46) 215.07,65.24 214.28,65.24 213.29,64.24
  TOP w0.109: 213.29,64.24 213.12,64.24 R986.1 212.59,63.86 211.85,63.86 R984.1
  BOTTOM w0.109: v1(215.77,65.97) 215.89,65.85 215.89,65.65 215.51,65.26 213.84,65.26 212.49,63.91 207.93,63.91 206.99,62.98 206.99,61.77 206.9,61.68 JLVDS1.11
AMP_SPK_L1: length 4.6
  TOP w0.109: RA69.1 22.36,3.95 21.19,5.11 C51.1 ; RA69.1 23.2,3.89 v2(23.64,4.34) ; RA69.1 RA47.2
AMP_SPK_LC: length 31.6
  TOP w0.109: UA2.43 26.54,20.64 27.1,20.09 v1(27.1,20) ; v1(17.87,3.84) 17.87,3.2 C29.1
  IN1 w0.076: v1(27.1,20) 27.08,20 26.82,19.73 26.82,17.13 28.4,15.54 28.4,12.29 30.17,10.52 30.17,8.36 29.03,7.22 29.03,5.57 27.41,3.96 22.38,3.96 21.84,3.41 18.31,3.41 v1(17.87,3.84)
AMP_SPK_LR: length 2.5
  TOP w0.109: C51.2 23.07,5.82 23.32,5.82 24,6.5 U4.5
AMP_SPK_R: length 3.5
  BOTTOM w0.109: v2(29.5,9.5) 29.84,9.15 29.84,8.42 30.68,7.58 C32.2 RA46.1
AMP_SPK_R1: length 4.8
  TOP w0.109: v1(30.85,5.82) 31.44,6.41 C50.1 31.57,5.19 RA68.1 31.56,5.09 v2(30.35,3.87)
  BOTTOM w0.109: v1(30.85,5.82) 30.68,5.65 RA46.2
AMP_SPK_RC: length 13.9
  TOP w0.109: v1(27.82,19.85) 27.82,19.86 27.41,20.26 27.41,20.35 26.94,20.82 UA2.44
  IN1 w0.076: v1(27.82,19.85) 28.72,18.94 28.72,17.29 29.64,16.38 v1(29.64,11.68)
  BOTTOM w0.109: v1(29.64,11.68) 29.64,11.16 v2(30.09,10.7) 30.68,10.12 C32.1
AMP_SPK_RR: length 9.6
  TOP w0.109: v2(28.92,4.38) 28.28,5.02 U4.11 30.08,6.5 v7(30.17,6.41)
  IN1 w0.076: v7(30.17,6.41) 30.52,6.76 30.52,11.2 v7(30.79,11.46)
APOWER_OK: length 56.4
  TOP w0.109: R746.1 201.69,60.77 201.3,61.15 201.3,61.91 200.87,62.34 200.54,62.34 199.6,63.27 199.02,63.27 198.8,63.48 198.18,63.48 198.02,63.33 PU501.1 ; R746.1 202.25,61.29 202.67,61.29 v2(202.93,61.03) 204.59,59.37 205.9,59.37 R931.2 ; R746.1 200.98,60.02 v1(200.98,59.58)
  IN1 w0.076: v3(167.42,54.26) 167.18,54.5 166.58,54.5 166.34,54.26 v7(165.97,54.26)
  IN3 w0.102: v3(167.42,54.26) 167.65,54.03 169.01,54.03 169.72,54.75 174.74,54.75 174.91,54.91 175.33,54.91 175.74,54.5 176.03,54.5 176.55,55.02 180.87,55.02 181.25,55.41 183.53,55.41 184.47,54.47 184.47,54.26 184.97,53.77 185.81,53.77 186.68,52.89 188.56,52.89 189.12,52.33 194.03,52.33 195.4,53.7 197.74,53.7 200.76,56.72 200.76,58 200.92,58.16 200.92,59.52 v1(200.98,59.58)
APWROK_R: length 9.1
  TOP w0.109: RH131.1 RH438.1 ; RH131.1 164.78,53.96 164.43,53.96 163.74,53.27 v2(162.69,53.27) 160.66,51.24 160.66,51.14 v7(160.66,51.14) ; RH131.1 165.94,53.4 RH134.1
  IN1 w0.076: v3(160.67,50.76) 160.66,50.77 v7(160.66,51.14)
  IN4 w0.076: v4(160.67,50.38) v3(160.67,50.76)
  BOTTOM w0.109: UCPU1.AB5 160.82,50.53 v4(160.67,50.38)
ARRAY_MIC_CLK: length 7.3
  TOP w0.109: U23.5 204.09,66.05 205.12,65.02 205.12,63.67 MC1212.1 205.31,62.28 v1(205.45,62.14)
  BOTTOM w0.109: v1(205.45,62.14) 205.37,62.23 205.01,62.23 204.4,61.62 JLVDS1.16
ARRAY_MIC_DAT: length 11
  TOP w0.109: U23.2 205.34,68 206.43,66.91 MC1211.1 206.79,63.13 v2(206.79,62.57) 206.79,62.4 v1(206.5,62.11)
  BOTTOM w0.109: JLVDS1.15 204.9,61.43 205.17,61.7 206.09,61.7 v1(206.5,62.11)
AUD_MUTE#: length 2.3
  TOP w0.254: RA55.1 22.25,7.63 v2(23.09,7.63) 23.27,7.63 23.4,7.5 U4.3
AUD_MUTE#_R: length 14.8
  IN1 w0.076: v7(21.22,7.51) 21.22,9.23 18.01,12.43 18.01,14.18 18.35,14.52 18.35,14.62 v3(18.56,14.83)
  IN4 w0.076: v3(18.56,14.83) 18.13,14.4 v4(18.13,14.37)
  BOTTOM w0.254: v4(18.13,14.37) R25.1 18.1,15.48 D4.2 18.51,16.9 v2(19.49,16.9) 19.74,17.15 D3.2
AUD_MUTE_EC#: length 258.8
  TOP w0.109: v1(19.75,19.71) 19.75,19.55 19.11,18.91 RA44.1
  IN4 w0.076: v1(19.75,19.71) 19.75,15.31 18.48,14.04 17.9,14.04 17.65,13.8 17.65,12.27 22.21,7.72 23.78,7.72 27.2,4.3 36.35,4.3 36.8,4.75 38.68,4.75 39.57,3.86 40.61,3.86 41.51,2.95 42.46,2.95 43.1,3.59 48.08,3.59 48.62,4.12 49.88,4.12 50.81,5.05 72.14,5.05 74.69,2.5 104.83,2.5 106,3.67 108.35,3.67 108.96,4.28 127.47,4.28 128.89,2.85 142.19,2.85 144.91,5.57 147.82,5.57 151.49,1.91 185.93,1.91 186.65,2.62 192.47,2.62 194.94,5.09 196.14,5.09 198.96,7.91 202.24,7.91 205,10.66 205,31.99 207.46,34.45 208.39,34.45 210.55,36.61 211.5,36.61 211.89,37 211.89,39.75 213.67,41.53 213.67,43.73 214.98,45.04 214.98,45.42 215.88,46.33 215.88,47.18 215.46,47.6 v4(215.3,47.6)
  BOTTOM w0.109: D3.1 19.75,20.23 v1(19.75,19.71) ; U34.N12 213.28,50.02 213.28,49.82 213.99,49.11 v2(214.24,49.11) 214.46,48.89 214.46,48.01 214.72,47.75 215.14,47.75 v4(215.3,47.6)
AUDIO_IRQ#: length 6.5
  TOP w0.109: RH396.2 166.05,56.29 165.58,55.83 v2(163.38,55.83) 161.98,55.83 v7(161.5,56.31)
  IN1 w0.076: v7(161.5,56.31) 161.41,56.22 161.41,55.74 v3(161.44,55.71)
  IN4 w0.076: v3(161.44,55.71) 161.41,55.74 161.41,56.21 v4(161.51,56.3)
AUDIO_PWREN: length 276.6
  TOP w0.109: v7(193.72,31.25) 194.62,31.25 196.19,32.82 D305.2 ; U717.5 51.2,10.82 v7(51.01,10.63) ; v7(39.41,18.77) 38.36,18.77 38.22,18.63 35.11,18.63 35.06,18.58
  TOP w0.254: v1(34.77,18.58) 35.06,18.58 35.57,18.07 35.57,17.34 v1(35.01,16.79)
  IN1 w0.076: v7(39.41,18.77) 39.41,17.97 40.35,17.03 40.35,13.99 40.56,13.78 40.56,10.28 44.4,6.43 48.03,6.43 49.7,8.1 49.7,9.56 50.77,10.63 v7(51.01,10.63) 51.04,10.63 51.65,10.01 51.65,9.74 52.27,9.13 56.52,9.13 57.49,8.15 58.51,8.15 59.68,9.32 73.77,9.32 73.91,9.46 74.75,9.46 75.27,8.94 92,8.94 94.53,11.46 100.56,11.46 102.06,9.97 103.51,9.97 105.49,7.98 108.71,7.98 110.46,6.23 119.21,6.23 119.42,6.03 141.31,6.03 143.8,8.52 152.88,8.52 155.63,5.77 180.15,5.77 180.91,6.54 190.41,6.54 195.86,11.99 195.86,12.5 196.97,13.6 196.97,26.11 195.73,27.36 195.73,28.45 193.72,30.45 v7(193.72,31.25) 193.71,31.26 193.71,31.78 193.33,32.16 192.81,32.68 192.44,33.05 192.44,33.69 191.61,34.51 191.61,35.45 191.22,35.84 189.22,35.84 188.15,36.91 179.82,36.91 177.59,39.14 177.59,40.11 176.96,40.75 176.74,40.75 176.39,41.1 176.39,42.6 175.24,43.75 175.24,45.31 174.49,46.06 167.04,46.06 166.57,46.53 166.06,46.53 165.3,47.29 164.68,47.29 164.48,47.48 163.41,47.48 163.07,47.82 161.66,47.82 161.37,48.11 161.37,48.43 160.48,49.32 159.93,49.32 159.55,49.32 159.09,49.79 159.09,50.16 158.82,50.43 158.82,50.69 158.43,51.09 158.43,51.99 158.67,52.23 158.67,53.35 158.9,53.58 159.76,53.58 160.04,53.3 161.26,53.3 162.15,54.19 162.15,54.62 162.43,54.9 162.81,54.9 163.18,54.52 v3(163.18,54.52)
  IN4 w0.076: v3(163.18,54.52) 163.18,54.56 v4(163.46,54.84)
  BOTTOM w0.109: T279.1 165.11,55.55 164.41,54.85 163.46,54.85 v4(163.46,54.84)
  BOTTOM w0.203: U664.3 34.17,16.5 33.9,16.77 33.9,17.68 R1140.1 ; U664.5 34.97,16.75 v1(35.01,16.79)
  BOTTOM w0.254: R1182.1 R1140.1 34.04,17.75 34.77,18.47 v1(34.77,18.58)
AUDIO_XTAL24_IN: length 6.3
  TOP w0.109: UA1.2 42.7,8.84 42.92,8.62 42.92,8.38 v2(43.29,8.01) 43.45,8.01 CA17.1 44.37,8.92 46.17,8.92 YA1.3
AUDIO_XTAL24_OUT: length 3.7
  TOP w0.109: YA1.1 44.89,9.62 CA16.1 43.87,9.29 v2(43.31,9.29) 42.62,9.29 42.57,9.34 UA1.3
B+: length 49.2
  TOP w0.254: PJP411.1 v7(227.65,35.49)
  TOP w0.508: v6(190.49,53.98) 190.49,54.45 190.76,54.72 190.76,56.31 188.73,58.34 186.05,58.34 185.54,57.83 v1(185.54,57.59) 185.24,57.59 R1381.1
  IN1 w0.254: v3(211.74,34.62) 213.51,36.38 215.23,36.38 215.74,35.87 224.68,35.87 225.33,36.52 226.62,36.52 v7(227.65,35.49)
  IN2 w0.254: v3(211.74,34.62) 204.88,34.62 203.07,32.8 203.07,28.63 199.33,24.9 v3(198.8,24.9)
  BOTTOM w0.381: v1(185.54,57.59) 184.94,57.59 184.73,57.38 Q361.4
  vias: v5(85.76,66.84) v6(83.89,40.24) v6(84.08,45.32) v6(84.08,44.62) v6(84.21,39.67) v6(84.52,40.24) v6(84.78,45.32) v6(84.78,44.62) v6(84.84,39.67) v6(85.16,40.24) v6(85.46,44.51) v6(85.54,39.67) v6(85.67,67.98) v6(85.92,40.24) v6(86,67.42) v6(86.12,44.51) v6(86.15,43.82) v6(86.24,39.67) v6(86.32,67.98) v6(86.56,40.24) v6(88.06,68.21) v6(93.01,19.39) v6(93.01,18.75) v6(93,17.9) v6(93.53,17.55) v6(93.55,18.24) v6(93.83,16.98) v6(94.19,18.25) v6(94.17,17.59) v6(94.47,17.03) v6(94.82,18.22) v6(94.81,17.59) v6(176.31,44.57) v6(176.33,43.92) v6(176.33,43.29) v6(176.98,44.56) v6(176.97,43.92) v6(176.97,43.29) v6(177.62,45.19) v6(177.62,44.56) v6(177.6,43.92) v6(177.6,43.29) v6(191.39,53.98) v6(192.03,53.98) v6(192.66,53.98)
B-RAMP: length 5.6
  TOP w0.109: v6(104.45,57.77) 104.95,57.27 v2(105.21,57.27)
  TOP w0.203: PU701.11 103.91,58.31 v6(104.45,57.77)
  BOTTOM w0.203: v6(104.45,57.77) 103.89,57.77 PR711.1 103.9,58.28 104.54,58.91 PR704.2
BATDRV: length 2.1
  TOP w0.109: PR230.1 v2(95.14,3.42)
  TOP w0.254: PR230.1 95.14,4.66 v1(95.75,5.27)
BATMAN_CLK: length 7.4
  TOP w0.102: Q359.6 253.1,48.32 R1350.1 252.15,49.27 251.26,49.27 250.96,48.97 v2(250.33,48.97) R1347.1 248.95,47.59 248.53,47.59 248.34,47.4 248.17,47.4 248.03,47.54 U714.7
BATMAN_DATA: length 5.8
  TOP w0.102: Q359.3 251.2,45.27 R1351.1 251.06,45.25 v2(250.24,46.07) R1346.1 248.95,47.36 248.62,47.36 248.43,47.17 248.14,47.17 248,47.04 U714.6
BATMAN_X1: length 3.8
  TOP w0.109: Y3.1 242.1,47.79 C1295.1 243.14,47.54 U714.14
BATMAN_X2: length 3.7
  TOP w0.109: U714.15 243.06,47.04 C1296.1 241.92,46.85 Y3.2
BATT+:
  vias: v2(85.16,9.97)
BATT++:
  vias: v1(77.54,6.65) v1(78.42,6.65) v5(79.47,7.68) v5(81.24,7.62) v5(82.98,7.67)
BATT_LED_COLOR_W: length 86
  TOP w0.109: v2(259.54,41.16) 259.15,41.16 v1(258.41,40.42) ; U5.2 v1(270.53,47.51) ; Q366.5 270.71,41.19 270.95,41.44 v1(271.6,41.44)
  IN1 w0.076: v1(270.53,47.51) 270.39,47.37 270.39,41.74 270.69,41.44 v1(271.6,41.44)
  IN2 w0.102: v1(258.41,40.42) 258.13,40.7 256.63,40.7 254.09,43.24 251.58,43.24 250.36,42.02 232.5,42.02 227.97,46.55 226.98,46.55 226.1,47.43 223.21,47.43 220.31,50.33 216.48,50.33 215.23,51.57 212.08,51.57 211.22,50.71 210.25,50.71 207.03,53.93 206.42,53.93 205.86,54.49 v3(205.86,54.57)
  IN4 w0.076: v1(258.41,40.42) 259,41 271.16,41 v1(271.6,41.44) ; v4(206.24,54.42) 206.09,54.57 v3(205.86,54.57)
  BOTTOM w0.076: v4(206.24,54.42) 206.27,54.39 206.8,54.39 U34.A4
BATT_LED_COLOR_W#: length 3.1
  TOP w0.109: Q367.5 270.71,46.72 270.85,46.86 U5.4 272.06,46.86 v2(272.47,46.44)
BATT_LED_CTRL#: length 82.9
  TOP w0.109: R36.1 v1(272.37,39.71) ; Q367.2 v7(270.71,42.61)
  IN1 w0.076: v1(272.37,39.71) 272.37,41.8 271.56,42.61 v7(270.71,42.61)
  IN2 w0.102: v1(257.02,41.18) 257.02,41.82 254.88,43.95 251.57,43.95 250.1,42.48 232.69,42.48 228.16,47.01 227.23,47.01 226.23,48.01 225.58,48.01 225,48.59 222.69,48.59 220.5,50.78 217.7,50.78 215.19,53.28 212.63,53.28 210.97,54.95 208.76,54.95 208.4,55.3 206.39,55.3 v3(206.37,55.28)
  IN4 w0.076: v1(272.37,39.71) 272.37,41.55 272.05,41.87 257.7,41.87 v1(257.02,41.18) ; v3(206.37,55.28) 206.37,55.2 v4(206.14,54.97)
  BOTTOM w0.102: U34.A3 206.8,55 206.17,55 v4(206.14,54.97)
BATT_LOW_LED#_C: length 47.4
  TOP w0.109: v1(267.4,6.22) 267.87,5.75 268.87,5.75 269.09,5.52 DA9.3 ; v1(269.06,40.09) 268.5,40.65 v2(268.5,41.75) 268.5,43.39 269.07,43.96 R4.1
  IN4 w0.076: v1(269.06,40.09) 269.06,39.36 265.58,35.88 265.58,22.03 264.47,20.93 264.47,14.04 265.35,13.17 265.35,9.36 267.4,7.31 v1(267.4,6.22)
  BOTTOM w0.109: v1(267.4,6.22) 267.18,6.43 JPWR1.4
BATT_PRS: length 12.4
  TOP w0.109: v1(62.2,8) 62.2,9.5 61.3,10.4 PD104.2 61.3,11.49 61.55,11.74 62.72,11.74 PR112.1 v2(63.21,13.22)
  BOTTOM w0.109: v1(62.2,8) 61.31,7.11 JBATT1.5
BEEP#: length 238.6
  TOP w0.109: RA33.1 34.04,17.79 33.52,17.27 32.46,17.27 v2(32.33,17.14) 31.67,16.48 v1(31.67,16.32)
  IN4 w0.076: v4(212.08,52.66) 212.52,52.66 212.85,52.33 212.85,51.68 212.39,51.23 212.39,50.83 213.12,50.1 213.12,49.53 213.42,49.23 213.42,47.68 213.26,47.53 213.26,45.63 212.21,44.58 212.21,43.7 211.91,43.4 211.91,41.07 211.59,40.75 211.3,40.75 210.47,39.92 210.47,38.57 209.55,37.66 209.55,37.41 204.39,32.24 204.39,13.91 195.97,5.49 194.77,5.49 192.3,3.03 183.36,3.03 182.64,2.31 151.66,2.31 147.99,5.98 144.7,5.98 141.99,3.26 129.08,3.26 127.65,4.68 118.1,4.68 117.47,5.32 109.43,5.32 108.18,4.07 105.83,4.07 104.94,3.18 102.28,3.18 101.85,3.62 101.44,3.62 100.53,2.7 75.13,2.7 71.94,5.89 71.94,6.98 71.79,7.13 67.99,7.13 67.87,7.02 64.99,7.02 64.42,6.45 50.23,6.45 49.3,5.52 43.81,5.52 43.52,5.81 41.13,5.81 38.83,8.11 38.56,8.11 35.6,11.07 35.6,11.91 31.67,15.85 v1(31.67,16.32)
  BOTTOM w0.109: v4(212.08,52.66) 212.3,52.44 U34.M8
BKOFF#: length 55
  IN3 w0.102: v3(208.96,56.5) 208.96,56.52 208.71,56.78 208.71,60.03 207.13,61.6 207.13,63.05 208.48,64.4 208.48,66.63 207.84,67.27 206.29,67.27 204.4,69.16 200.68,69.16 198.3,66.78 195.35,66.78 192.89,69.25 178.25,69.25 v3(177.01,68)
  IN4 w0.076: v4(208.74,56.98) 208.96,56.76 v3(208.96,56.5) ; v4(177.36,68.41) 177.01,68.05 v3(177.01,68)
  BOTTOM w0.076: v4(208.74,56.98) 208.74,56.66 208.91,56.5 208.91,56 U34.E1
  BOTTOM w0.109: D106.2 173.2,66.65 173.58,67.03 D72.3 174.17,67.03 174.8,66.4 176.14,66.4 177.06,67.32 v2(177.06,67.95) 177.06,68.11 v4(177.36,68.41)
BOOT0: length 5.6
  TOP w0.109: R1092.1 243.63,59.57 R819.2 244.56,60.5 244.56,62.38 v2(245.02,62.84) U636.A6
BOOT_+1.2V: length 3.4
  BOTTOM w0.203: PR601.2 92.83,33.98 93.19,34.34 PU601.18
BST1_3V: length 2.8
  TOP w0.109: PC318.2 196.7,34.78 v2(197.15,35.23)
  TOP w0.508: PC318.2 PR355.1
BST1_5V: length 3
  TOP w0.109: PR356.2 184.41,36.86 v2(184.41,37.17)
  TOP w0.508: PR356.2 PC335.1
BST_3V: length 2.3
  TOP w0.109: PR355.2 194.43,37.16 v2(194.75,37.47)
  TOP w0.203: 192.81,35.18 PU301.9
BST_5V:
  vias: v2(187.92,35.42)
BST_+1.05VS: length 1.7
  TOP w0.203: PU501.5 196.42,63.68 196.59,63.85
  TOP w0.508: 196.59,63.85 196.91,64.17 PR506.1
BT_CS_NOTICE: length 75.5
  TOP w0.109: R1210.2 224.9,50.27 224.9,46.01 R1212.2 223.78,44.89 223.78,42.53 223.25,42 222.62,42 v1(222.59,42.03)
  IN2 w0.102: v3(165.7,45.04) 165.87,45.21 167.65,45.21 169.11,46.67 175.3,46.67 176.2,47.57 178.85,47.57 180.29,46.13 191.56,46.13 192.64,47.21 198.59,47.21 199.01,46.8 202.16,46.8 204.01,44.95 204.75,44.95 206.69,43.01 211.11,43.01 211.92,42.2 212.92,42.2 213.75,41.37 215.35,41.37 216.43,42.45 221.3,42.45 221.72,42.03 v1(222.59,42.03)
  IN4 w0.076: v4(165.32,45.02) 165.35,45.04 v3(165.7,45.04)
  BOTTOM w0.109: v4(165.32,45.02) 165.45,44.89 v2(165.45,44.57) 165.45,44.41 164.65,43.6 UCPU1.AP1
BT_PCMCLK: length 3.6
  TOP w0.109: U677.2 226.85,61.35 v1(226.33,60.84)
  BOTTOM w0.109: JNGFF1.8 225.93,61.24 v1(226.33,60.84)
BT_PCMFR1: length 6.2
  TOP w0.109: U677.3 227.5,61.41 v1(226.93,60.84) 226.42,60.33 226.1,60.33 v2(225.53,59.76)
  BOTTOM w0.109: v1(226.93,60.84) 226.5,60.41 226.18,60.41 225.85,60.74 JNGFF1.10
BT_PCMIN: length 6.7
  TOP w0.109: U677.5 228.8,60.8 v2(227.36,59.37) 226.78,59.37 226.33,59.81 v1(226.33,59.84)
  BOTTOM w0.109: JNGFF1.12 225.69,60.24 226.09,59.84 v1(226.33,59.84)
BT_PCMOUT: length 5.7
  TOP w0.109: v1(226.92,59.83) v2(227.81,60.72) 228.15,61.05 U677.4
  BOTTOM w0.109: v1(226.92,59.83) 226.43,59.34 225.95,59.34 225.55,59.74 JNGFF1.14
BT_RADIO_DIS#: length 117.2
  IN2 w0.102: v1(226.92,50.61) 226.69,50.38 226.12,50.38 225.29,51.2 225.29,52.37 223.28,54.38 218.8,54.38 217,56.18 216.22,56.18 215.98,55.94 215.98,55.53 216.73,54.78 216.73,54.42 216.43,54.11 215.33,54.11 214.85,54.59 214.06,54.59 212.73,55.93 211.33,55.93 211.06,56.19 209.68,56.19 209.38,55.89 206.76,55.89 206.66,55.99 201.48,55.99 200.6,56.87 200.25,57.22 196.22,57.22 195.5,57.95 193.4,57.95 192.77,58.58 185.4,58.58 184.44,57.62 182.16,57.62 182,57.77 176.06,57.77 174.89,56.6 167.94,56.6 165.92,54.58 164.87,54.58 164.38,54.08 163.9,54.08 163.62,54.36 163.62,54.67 163.32,54.97 161.24,54.97 160.96,54.7 160.45,54.7 160.27,54.52 159.61,54.52 v3(159.25,54.87)
  IN4 w0.076: v4(233.38,39.99) 234.08,39.29 v4(238.02,39.29) ; v4(159.52,54.57) 159.25,54.84 v3(159.25,54.87)
  BOTTOM w0.109: JNGFF2.54 244.4,41.32 243.66,40.58 243.01,40.58 240.62,38.2 239.11,38.2 v4(238.02,39.29) ; v4(233.38,39.99) 232.41,39.01 230.06,39.01 229.41,39.66 229.41,40.52 229.61,40.72 229.61,42.71 229.18,43.14 228.16,43.14 227.74,42.72 225.56,42.72 223.02,45.26 223.02,49.02 223.74,49.74 JNGFF1.46 226.05,49.74 v1(226.92,50.61)
BTST: length 2.4
  BOTTOM w0.254: PU201.17 98.24,8.79 v2(97.96,9.06) 97.72,9.3 PR211.1
BYPASS: length 1.4
  TOP w0.102: v2(27.5,4.36) 27.02,3.88 C47.2
CAPS_LED: length 170.9
  TOP w0.109: v1(22.47,31.9) 21.99,31.9 19.08,28.99 19.08,26.63 18.5,26.04 v2(17.74,26.04) 17.1,26.04 16.67,26.48 13.24,26.48 11.81,25.05 11.81,23.19 12.1,22.9 LED2.2
  IN1 w0.076: v1(111.28,3.06) 110.32,2.1 105.72,2.1 104.75,1.14 49.29,1.14 48.33,2.1 46.18,2.1 45.73,2.56 42.88,2.56 42.66,2.34 35.21,2.34 33.65,3.9 33.65,4.56 32.61,5.6 32.61,9.36 31.57,10.4 31.57,11.57 30.79,12.34 v3(30.79,14.21)
  IN4 w0.076: v1(22.47,31.9) 23.31,31.06 26.25,31.06 26.77,30.54 26.9,30.54 28.68,28.76 28.68,26.91 29.25,26.34 29.25,24.1 32.19,21.17 32.19,19.39 32.94,18.64 32.94,18.17 30.79,16.02 v3(30.79,14.21)
  BOTTOM w0.109: R943.2 139.5,9.44 139.5,8.65 139.74,8.41 139.74,4.21 137.92,2.38 111.96,2.38 v1(111.28,3.06)
CAPS_LED#: length 104.2
  IN4 w0.076: v4(143.76,13) 144.47,12.29 151.47,12.29 154.43,9.33 156.28,9.33 156.99,8.62 170.68,8.62 171.42,9.36 174.21,9.36 174.35,9.5 178.91,9.5 179.08,9.33 189.69,9.33 193.36,13 193.36,13.49 195.17,15.3 195.17,22.97 195.55,23.35 195.93,23.35 196.11,23.53 196.11,26.39 196.46,26.74 196.46,30.88 197.07,31.49 197.07,33.89 201.69,38.51 201.69,41.67 203.02,42.99 203.02,46.57 205.06,48.61 205.06,50.02 205.12,50.08 205.12,51.95 206.85,53.68 206.85,53.68 206.95,53.78 207.36,53.78 v4(207.82,54.24)
  BOTTOM w0.076: v4(207.82,54.24) 207.61,54.44 207.61,54.59 207.36,54.85 U34.B3
  BOTTOM w0.109: Q326.3 142.47,11.66 v2(143.35,12.54) 143.76,12.95 v4(143.76,13)
CDCLK_REQ#: length 137
  TOP w0.109: U1.2 264.6,21.11 264.42,21.29 264.42,21.5 v1(264.56,21.64) ; v7(174.97,52.03) 174.97,52.65 175.37,53.04 RH95.2
  IN1 w0.076: v3(164.56,51.95) 164.7,52.09 167.03,52.09 167.4,51.71 168.13,51.71 168.4,51.98 174.92,51.98 v7(174.97,52.03) 175.09,52.14 177.47,52.14 177.93,51.67 177.93,51.16 179.61,49.48 183.26,49.48 183.51,49.23 184.91,49.23 185.68,48.47 191.59,48.47 192.33,49.21 193.38,49.21 194.09,48.5 199.67,48.5 200.27,47.9 202.54,47.9 203.34,47.1 209.55,47.1 210.23,47.77 212.77,47.77 213.86,48.87 214.45,48.87 215.04,48.28 218,48.28 218.13,48.41 220.17,48.41 220.41,48.65 221.23,48.65 222.41,47.47 224.39,47.47 225.55,46.31 225.55,45.75 226.98,44.32 226.98,43.25 227.43,42.8 228.26,42.8 229.67,41.38 230.42,41.38 231.22,40.59 232.05,40.59 234.46,38.18 240.08,38.18 241.17,39.28 245.67,39.28 247.48,41.08 247.85,41.08 249.93,39 253.87,39 v3(256.43,41.56)
  IN4 w0.076: v1(264.56,21.64) 264.19,22 264.19,23.47 264.79,24.06 264.79,32.72 256.43,41.08 v3(256.43,41.56) ; v3(164.56,51.95) 164.1,52.41 161.61,52.41 161.54,52.33 161.54,51.88 161.28,51.62 160.67,51.62 v4(160.47,51.42)
  BOTTOM w0.109: v4(160.47,51.42) 160.77,51.71 UCPU1.Y5
CFG0: length 40
  TOP w0.109: v2(104.87,64.24) 105.62,64.24 106,64.63 106,65.11 106.07,65.18 JXDP.9 106.07,67.5 105.85,67.72 v1(105.85,68.32)
  IN2 w0.102: v3(126.49,50.02) 125.9,50.61 124.63,50.61 124.4,50.83 123.24,50.83 120.87,53.2 120.87,56.28 120.13,57.01 120.13,64.33 118.79,65.67 114.98,65.67 114.53,66.12 109.75,66.12 109.35,66.52 107.41,68.46 107.09,68.46 107.07,68.49 106.03,68.49 105.86,68.32 v1(105.85,68.32)
  IN4 w0.076: v4(126.78,50.35) 126.49,50.05 v3(126.49,50.02)
CFG1: length 37.9
  TOP w0.109: JXDP.11 106.57,67.51 106.27,67.81 v1(106.27,67.9)
  IN2 w0.102: v1(106.27,67.9) 106.62,68.26 106.97,68.26 107,68.23 107.31,68.23 109.12,66.42 109.65,65.9 114.43,65.9 114.89,65.44 118.7,65.44 119.91,64.23 119.91,56.92 120.64,56.18 120.64,53.1 123.27,50.48 123.56,50.48 123.69,50.61 124.3,50.61 124.53,50.38 124.81,50.38 v3(125.16,50.02)
  IN4 w0.076: v3(125.16,50.02) 125.16,50.07 v4(125.48,50.39)
  BOTTOM w0.109: v2(105.28,65.34) 105.28,66.91 v1(106.27,67.9)
CFG2: length 33.8
  TOP w0.109: v1(106.85,67.85) 107.37,67.85 107.57,67.65 JXDP.15
  IN2 w0.102: v3(124.54,50.02) 124.19,50.38 123.82,50.38 123.69,50.25 123.17,50.25 120.41,53.01 120.41,56.09 119.68,56.83 119.68,64.14 118.6,65.21 114.79,65.21 114.34,65.67 109.56,65.67 108.89,66.33 107.37,67.85 v1(106.85,67.85)
  IN4 w0.076: v4(124.83,50.39) 124.83,50.31 v3(124.54,50.02)
CFG3: length 37.4
  TOP w0.109: JXDP.17 v7(108.07,67.86)
  IN1 w0.076: v3(107.87,66.76) 108.07,66.96 v7(108.07,67.86)
  IN2 w0.102: v3(107.87,66.76) 109.2,65.43 111.96,65.43 113.65,63.74 118.89,63.74 119.45,63.18 119.45,56.73 120.18,55.99 120.18,52.91 123.08,50.02 v3(123.97,50.02)
  IN4 w0.076: v3(123.97,50.02) v4(123.97,50.43)
  BOTTOM w0.109: R1198.2 120.29,49.75 120.71,50.17 120.71,50.34 120.87,50.5 122.54,50.5 v2(123,50.04) 123.58,50.04 v4(123.97,50.43) 124.68,51.14 UCPU1.AA63
CFG4: length 40.6
  TOP w0.109: v1(110.39,67.93) 110.57,67.75 JXDP.27
  IN2 w0.102: v3(127.11,51.43) 126.42,51.43 126.1,51.75 124.55,51.75 124.5,51.8 123.87,51.8 123.64,52.03 123.06,52.03 121.56,53.53 121.56,56.56 120.82,57.3 120.82,59.26 121.56,60 121.56,64 119.21,66.35 115.27,66.35 114.81,66.81 111.51,66.81 v1(110.39,67.93)
  IN4 w0.076: v3(127.11,51.43) 126.85,51.18 v4(126.78,51.18)
  BOTTOM w0.109: v4(126.78,51.18) 126.43,51.53 124.45,51.53 123.68,50.76 120.5,50.76 RC81.1 120.28,50.91 v2(119.68,51.51)
CFG5: length 29.4
  TOP w0.109: v1(110.99,67.93) 111.07,67.85 JXDP.29
  IN2 w0.102: v1(110.99,67.93) 111.88,67.04 114.91,67.04 115.36,66.58 119.3,66.58 121.78,64.1 121.78,59.91 121.05,59.17 121.05,57.39 121.78,56.66 121.78,53.64 123.17,52.26 123.92,52.26 v3(124.02,52.15)
  IN4 w0.076: v3(124.02,52.15) 124.03,52.15 124.56,52.15 124.82,51.89 v4(125.48,51.89)
CFG6: length 31.3
  TOP w0.109: JXDP.33 112.07,67.83 112.55,68.31 113.52,68.31 v1(113.93,67.9)
  IN2 w0.102: v1(113.93,67.9) 115.01,67.9 115.65,67.27 119.61,67.27 122.54,64.34 122.54,53.94 123.56,52.92 125.21,52.92 v3(125.83,52.3)
  IN4 w0.076: v3(125.83,52.3) 126.13,52 v4(126.13,51.85)
  BOTTOM w0.109: v1(113.93,67.9) v2(113.93,65.31)
CFG7: length 30.9
  TOP w0.109: JXDP.35 112.57,67.59 v1(112.83,67.85)
  IN2 w0.102: v1(112.83,67.85) 113.42,67.27 115,67.27 115.46,66.81 119.39,66.81 122.01,64.19 122.01,59.81 121.28,59.08 121.28,57.49 122.01,56.75 122.01,53.82 123.32,52.51 124.33,52.51 124.91,51.93 127.29,51.93 v3(127.65,52.29)
  IN4 w0.076: v4(126.78,51.85) 127.21,51.85 v3(127.65,52.29)
CFG8: length 35.5
  TOP w0.109: JXDP.10 106.07,70.44 v7(106,70.37)
  IN1 w0.076: v3(106.38,70.35) 106.36,70.37 v7(106,70.37)
  IN2 w0.102: v3(125.22,52.31) 125.22,52.29 124.83,52.69 123.47,52.69 122.24,53.91 122.24,64.31 119.51,67.04 115.55,67.04 115.09,67.5 113.73,67.5 113.4,67.83 113.4,67.98 113.1,68.28 111.78,68.28 111.68,68.39 108.46,68.39 107.69,69.15 107.37,69.15 107.15,69.38 106.66,69.38 106.38,69.66 v3(106.38,70.35)
  IN4 w0.076: v3(125.22,52.31) 125.22,52.38 v4(125.48,52.64)
CFG9: length 36.1
  TOP w0.109: JXDP.12 106.57,70.8 106.41,70.63 106.41,70.19 106.81,69.78 v1(106.9,69.78)
  IN2 w0.102: v1(106.9,69.78) 107.06,69.78 107.47,69.38 107.79,69.38 108.55,68.61 111.77,68.61 111.88,68.51 114,68.51 114.3,68.21 115.03,68.21 115.74,67.5 119.7,67.5 122.77,64.43 122.77,54.04 123.66,53.15 125.23,53.15 125.56,52.81 125.95,52.81 v3(126.47,52.29)
  IN4 w0.076: v4(126.13,52.67) 126.13,52.63 v3(126.47,52.29)
CFG10: length 36
  TOP w0.109: v1(107.64,69.78) 107.23,70.19 107.23,70.54 107.57,70.88 JXDP.16
  IN2 w0.102: v3(127.09,52.29) 126.29,53.09 125.54,53.09 125.26,53.37 123.75,53.37 123,54.13 123,64.55 119.82,67.72 117.93,67.72 117.21,68.44 114.39,68.44 114.09,68.74 111.97,68.74 111.87,68.84 108.64,68.84 107.71,69.78 v1(107.64,69.78)
  IN4 w0.076: v3(127.09,52.29) 126.78,52.61 v4(126.78,52.67)
CFG11: length 35.5
  TOP w0.109: v1(107.64,70.37) 107.64,70.52 108.07,70.95 JXDP.18
  IN2 w0.102: v3(126.42,53.79) 125.87,54.34 125.57,54.34 123.95,55.96 123.95,64.89 121.27,67.57 121.27,68.58 120.5,69.35 114.77,69.35 114.47,69.66 113.24,69.66 112.88,70.02 112.26,70.02 111.96,70.32 110.51,70.32 109.57,69.38 108.43,69.38 108.2,69.61 108.2,69.81 v1(107.64,70.37)
  IN4 w0.076: v3(126.42,53.79) 126.66,53.55 v4(127.08,53.55)
  BOTTOM w0.109: v4(127.08,53.55) 126.88,53.35 UCPU1.U60
CFG12: length 29.5
  TOP w0.109: v7(110.98,70.24) 110.99,70.25 110.99,70.73 110.57,71.15 JXDP.28
  IN1 w0.076: v7(110.98,70.24) 110.98,69.87 v3(110.99,69.86)
  IN2 w0.102: v3(124.53,53.79) 124.53,54.62 123.46,55.69 123.46,64.73 120.81,67.38 120.81,68.39 120.31,68.89 114.58,68.89 114.28,69.2 112.16,69.2 112.06,69.3 111.55,69.3 v3(110.99,69.86)
  IN4 w0.076: v3(124.53,53.79) 124.53,53.83 v4(124.83,54.13)
CFG13: length 29.4
  TOP w0.109: JXDP.30 111.07,71.06 111.23,70.9 111.23,70.52 111.49,70.26 v7(111.46,70.26)
  IN1 w0.076: v3(111.58,69.88) 111.46,70 v7(111.46,70.26)
  IN2 w0.102: v3(111.58,69.88) 111.76,69.7 112.6,69.7 112.87,69.43 114.37,69.43 114.68,69.12 120.41,69.12 121.04,68.49 121.04,67.48 123.71,64.81 123.71,55.83 125.19,54.35 v3(125.19,53.79)
  IN4 w0.076: v4(125.48,54.13) 125.48,54.08 v3(125.19,53.79)
CFG14: length 33.4
  TOP w0.109: v7(112.25,70.67) 112.07,70.85 JXDP.34
  IN1 w0.076: v7(112.25,70.67) 112.25,70.73 v3(112,70.97)
  IN2 w0.102: v3(112,70.97) 112.14,71.1 119.72,71.1 121.52,69.3 122.04,69.3 122.55,68.79 122.55,68.35 124.66,66.25 124.66,57.41 125.34,56.73 125.34,55.61 125.7,55.25 126.47,55.25 127.58,54.14 v3(127.58,53.68)
  IN4 w0.076: v4(126.13,54.17) 126.43,54.47 127.3,54.47 127.65,54.11 127.65,53.75 v3(127.58,53.68)
CFG15: length 30
  TOP w0.109: JXDP.36 112.57,71.11 112.83,70.85 v1(112.83,70.65)
  IN2 w0.102: v3(127.15,54.03) 126.28,54.9 125.7,54.9 124.43,56.17 124.43,66.15 122.32,68.26 122.32,68.7 121.95,69.07 121.43,69.07 119.62,70.87 114.45,70.87 113.68,70.11 113.44,70.11 112.9,70.65 v1(112.83,70.65)
  IN4 w0.076: v4(126.78,54.17) 127.01,54.17 v3(127.15,54.03)
CFG16: length 37.6
  TOP w0.109: JXDP.6 105.07,70.41 v7(105.03,70.37)
  IN1 w0.076: v7(105.03,70.37) 104.85,70.37 v3(104.68,70.2)
  IN2 w0.102: v3(124.53,51.21) 124.38,51.06 123.33,51.06 121.1,53.29 121.1,56.37 120.36,57.11 120.36,64.42 118.89,65.9 115.08,65.9 114.62,66.35 109.84,66.35 109.58,66.61 107.5,68.69 107.19,68.69 106.96,68.92 106.47,68.92 106.27,69.12 105.11,69.12 104.68,69.55 v3(104.68,70.2)
  IN4 w0.076: v4(125.48,51.14) 125.36,51.01 124.73,51.01 v3(124.53,51.21)
CFG17: length 37.4
  TOP w0.109: v7(105.02,69.78) 104.57,70.23 JXDP.4
  IN1 w0.076: v3(105.41,69.77) 105.4,69.78 v7(105.02,69.78)
  IN2 w0.102: v3(105.41,69.77) 105.83,69.35 106.36,69.35 106.56,69.15 107.05,69.15 107.28,68.92 107.6,68.92 109.94,66.58 114.72,66.58 115.17,66.12 118.98,66.12 120.59,64.52 120.59,57.2 121.33,56.47 121.33,53.44 122.97,51.8 123.62,51.8 123.8,51.62 124.43,51.62 124.48,51.57 124.89,51.57 v3(125.06,51.39)
  IN4 w0.076: v4(126.13,51.18) 126.13,51.18 125.89,51.42 125.09,51.42 v3(125.06,51.39)
CFG18: length 30
  TOP w0.109: v7(110.41,70.01) 110.24,70.18 110.24,70.44 109.57,71.11 JXDP.24
  IN1 w0.076: v7(110.41,70.01) v3(110.41,69.63)
  IN2 w0.102: v3(123.92,53.79) 123.92,54.76 123.23,55.44 123.23,64.64 119.92,67.95 118.02,67.95 117.31,68.66 114.49,68.66 114.18,68.97 112.07,68.97 111.96,69.07 110.97,69.07 v3(110.41,69.63)
  IN4 w0.076: v4(124.83,53.39) 124.33,53.39 v3(123.92,53.79)
CFG19: length 35.7
  TOP w0.109: JXDP.22 109.07,70.83 v1(108.61,70.37)
  IN2 w0.102: v1(108.61,70.37) 109.01,69.96 109.77,69.96 110.36,70.54 112.06,70.54 112.36,70.24 112.98,70.24 113.34,69.88 114.56,69.88 114.87,69.58 120.6,69.58 121.33,68.84 121.85,68.84 122.09,68.6 122.09,68.14 124.2,66.04 124.2,56.04 125.62,54.62 126.13,54.62 126.79,53.96 126.79,53.55 126.61,53.37 126.24,53.37 v3(125.82,53.79)
  IN4 w0.076: v3(125.82,53.79) 125.48,53.45 v4(125.48,53.39)
CFG_RCOMP: length 4
  BOTTOM w0.381: RC153.1 121.71,51.39 v2(123.08,51.39) 123.62,51.39 124,51.77 124,52.31 124.33,52.64 UCPU1.V63
CHG_LGATE: length 11.2
  TOP w0.109: v6(95.59,9.08) v2(95.59,9.71)
  IN2 w0.102: v6(95.59,9.08) 95.22,9.08 95.19,9.1
  IN2 w1.016: 90.05,14.78 90.05,11.48 91.64,9.89 93.92,9.89 94.18,9.63
  BOTTOM w0.254: v6(95.59,8.4) 96.78,7.21 PU201.15
  vias: v6(89.67,15.63) v6(90.07,16.14)
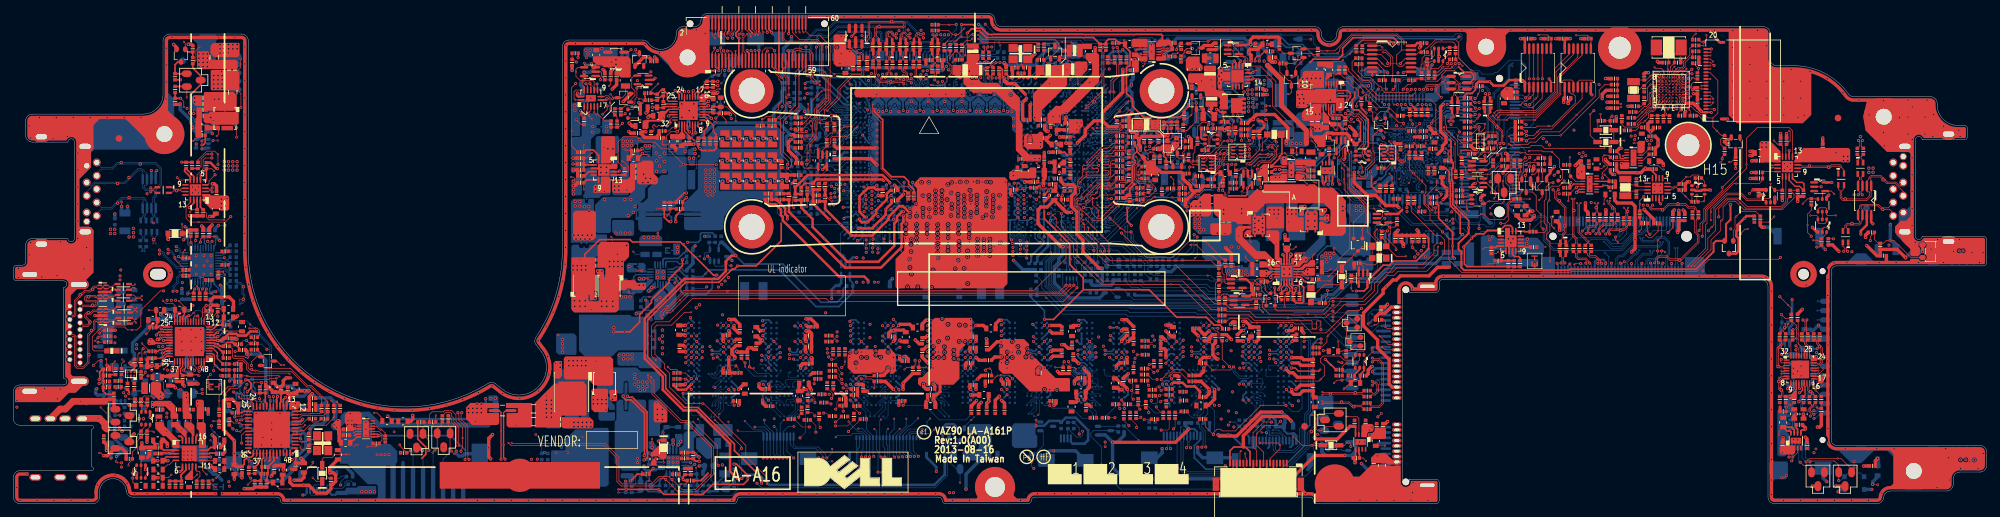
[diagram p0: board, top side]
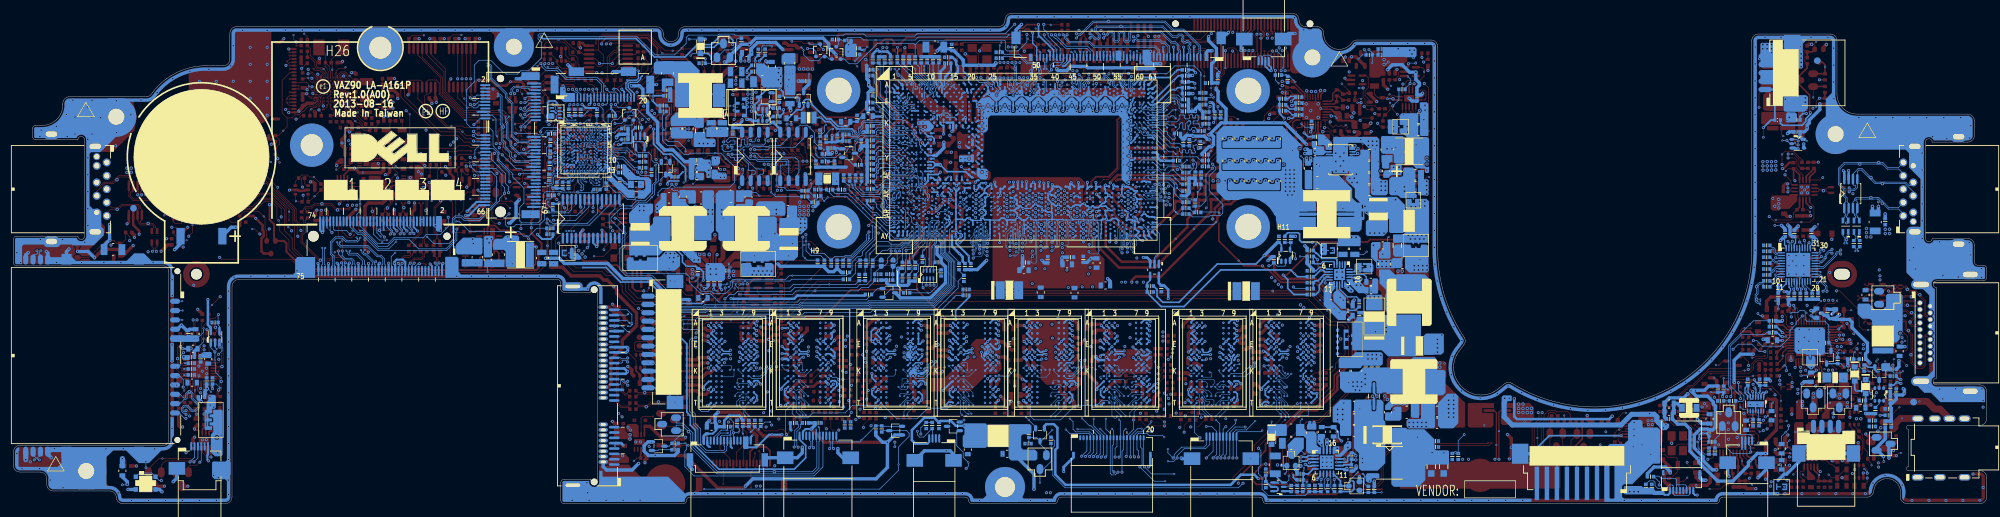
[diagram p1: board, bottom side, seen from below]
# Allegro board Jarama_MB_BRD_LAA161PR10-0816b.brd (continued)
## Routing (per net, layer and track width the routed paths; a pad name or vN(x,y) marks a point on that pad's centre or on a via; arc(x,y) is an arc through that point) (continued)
CHG_LX: length 20.2
  IN2 w1.016: 86.81,20.76 95.83,20.76 97.1,19.49 97.1,16.62 98.82,14.89 98.82,13.19 100.04,11.97 100.04,11.36
  vias: v2(87.18,21.34) v6(83.13,21.43) v6(83.13,20.68) v6(83.76,21.43) v6(83.76,20.68) v6(84.4,21.43) v6(84.4,20.68) v6(85.03,21.43) v6(85.03,20.68) v6(85.67,21.43) v6(85.67,20.68) v6(99.5,8.82) v6(99.87,9.36)
CHG_UGATE: length 22
  IN2 w1.016: 81.73,19.54 82.85,18.42 90.93,18.42 95.07,14.28 95.07,12.23 96.23,11.06 98.09,11.06
  BOTTOM w0.254: v6(98.74,8.9) PU201.18
  vias: v2(81.13,21.01) v6(81.83,21.09) v6(81.83,20.46) v6(98.72,9.53)
CL_CLK: length 96.3
  IN1 w0.076: v3(163.06,49.17) 163.46,49.56 164.59,49.56 164.71,49.44 166.52,49.44 167.2,50.12 175.1,50.12 175.75,49.47 176.68,49.47 177.06,49.09 177.31,49.09 178.45,47.96 182.63,47.96 182.88,47.71 184.05,47.71 184.26,47.51 184.26,47.07 184.45,46.88 194.89,46.88 195.4,46.38 201.91,46.38 202.44,45.84 202.71,45.58 205.81,45.58 206.17,45.22 210.55,45.22 211.34,46.01 218.95,46.01 219.88,46.94 220.88,46.94 v1(221.2,46.62)
  IN4 w0.076: v3(163.06,49.17) 162.81,48.91 v4(162.81,48.85) ; v1(221.2,46.62) 221.43,46.39 221.43,46.29 224.29,43.43 224.71,43.43 225.47,42.67 225.84,42.67 229.69,38.82 238.69,38.82 v4(239.39,39.51)
  BOTTOM w0.109: JNGFF1.34 223.93,52.74 223.72,52.52 223.72,51.58 221.62,49.48 221.62,47.95 221.2,47.53 v1(221.2,46.62) ; JNGFF2.42 241.4,40.39 240.53,39.51 v4(239.39,39.51)
CL_DATA: length 101.8
  IN1 w0.076: v3(165,50.53) 166.26,50.53 167.24,51.51 168.22,51.51 168.48,51.77 173.7,51.77 173.78,51.7 175.87,51.7 176.11,51.94 177.38,51.94 177.73,51.59 177.73,51.08 179.53,49.28 183.18,49.28 183.42,49.03 184.83,49.03 185.59,48.27 193.21,48.27 193.24,48.29 199.59,48.29 200.18,47.7 202.46,47.7 203.26,46.9 209.64,46.9 210.31,47.57 212.85,47.57 213.94,48.66 214.33,48.66 215.56,47.43 218.79,47.43 219.55,48.19 220.96,48.19 v1(221.02,48.25)
  IN4 w0.076: v4(162.99,49.97) 163.14,49.97 163.16,50 163.67,50 164.03,50.35 164.03,50.71 164.22,50.9 164.63,50.9 v3(165,50.53) ; v4(240.33,40.04) 240.33,39.71 238.98,38.36 229.13,38.36 224.54,42.95 224.13,42.95 223.81,42.63 221.6,42.63 221.3,42.93 220.91,42.93 220.69,43.15 220.69,44.97 220.99,45.26 220.99,46.17 220.8,46.36 220.8,47.05 221.02,47.27 v1(221.02,48.25)
  BOTTOM w0.109: v4(162.99,49.97) 162.81,49.79 UCPU1.AD2 ; JNGFF1.32 223.46,53.24 222.89,52.68 222.89,51.44 221.13,49.68 221.13,48.36 v1(221.02,48.25) ; v4(240.33,40.04) 240.9,40.61 JNGFF2.40
CL_RST#: length 74.8
  TOP w0.109: v7(225.27,47.23) 225.27,47.89 225.26,47.89 225.26,49.33 225.53,49.6 v2(225.53,49.7) 225.53,50.53 R1209.2
  IN1 w0.076: v7(225.27,47.23) 225.27,47.44 224.19,48.52 223.77,48.52 223.3,48.05 222.65,48.05 221.47,49.23 220.17,49.23 219.93,48.99 217.89,48.99 217.76,48.87 215.28,48.87 214.7,49.45 212.72,49.45 212.48,49.21 210.42,49.21 209.73,48.52 203.03,48.52 202.75,48.8 201.73,48.8 201.25,49.28 195.18,49.28 194.01,50.45 190.49,50.45 189.58,49.54 186.2,49.54 185.72,50.02 183.84,50.02 183.59,50.27 179.94,50.27 178.72,51.49 178.72,52 177.79,52.93 173.64,52.93 173.12,53.45 171.86,53.45 170.8,52.38 167.87,52.38 167.81,52.32 164.36,52.32 163.15,51.11 163.15,50.48 v3(161.83,49.16)
  IN4 w0.076: v3(161.83,49.16) 161.83,49.13 v4(161.51,48.81)
CL_RST#_L: length 30.3
  TOP w0.109: v1(239.77,39.96) 239.77,39.52 v2(240.11,39.18) ; R1210.1 R1209.1 225.86,51.49 226.23,51.86 v1(226.24,51.86)
  IN1 w0.076: v1(239.77,39.96) 239.49,39.68 235.13,39.68 233.95,40.86 233.95,41.25 229.08,46.12 229.08,49.45 228.14,50.39 228.14,51.44 227.76,51.82 227.42,51.82 227.03,51.43 226.51,51.43 226.23,51.71 226.23,51.85 v1(226.24,51.86)
  BOTTOM w0.109: JNGFF2.38 240.4,40.59 v1(239.77,39.96) ; JNGFF1.30 225.51,53.74 226.24,53.01 v1(226.24,51.86)
CLK_LPC_DEBUG: length 23.8
  TOP w0.109: v1(195.67,26.09) 195.67,27.3 195.57,27.4 195.1,27.4 195,27.3 195,26.32 194.9,26.22 194.46,26.22 194.35,26.32 194.35,27.32 194.25,27.42 192.07,27.42 192.01,27.49 v2(187.94,27.49) 185.68,27.49 184.88,28.29 181.38,28.29 RH360.2
  BOTTOM w0.109: JDEBUG.7 199.25,23.61 196.82,26.04 195.73,26.04 v1(195.67,26.09)
CLK_PCI_LPC: length 54.8
  TOP w0.109: v1(201.75,29.27) 201.42,28.94 v2(201.16,28.94) 199.78,28.94 196.44,25.6 194.3,25.6 192.97,26.93 191.8,26.93 191.59,27.15 185.36,27.15 184.71,27.8 182.05,27.8 181.58,27.33 RH386.2
  IN3 w0.102: v1(214.22,52.61) 214.22,51.68 213.56,51.02 213.56,50.16 213.18,49.78 213.18,48.15 211.42,46.4 211.42,44.01 208.93,41.52 208.93,40.34 207.56,38.96 207.55,38.96 201.88,33.3 201.88,29.41 v1(201.75,29.27)
  BOTTOM w0.076: v1(214.22,52.61) 214.22,53.4 213.96,53.65 213.15,53.65 U34.N5
  BOTTOM w0.109: MR226.1 214.67,52.57 214.26,52.57 v1(214.22,52.61)
CLK_PCI_TPM: length 50.1
  TOP w0.109: v1(208.54,44.37) 208.54,44.82 MR976.1 209.2,44.51 209.2,43.8 212.78,40.22 213.49,40.22 214.19,39.52 214.19,37.53 211.49,34.84 207.22,34.84 206.6,34.22 205.64,34.22 204.19,32.77 204.19,31.73 202.27,29.81 199.13,29.81 197.75,28.43 196.9,28.43 196.38,27.91 192.29,27.91 192.26,27.88 v2(190.71,27.88) 185.98,27.88 185.08,28.78 181.66,28.78 RH428.2
  BOTTOM w0.109: U652.21 208.52,44.39 v1(208.54,44.37)
CLK_PCIE0: length 139.7
  IN4 w0.076: v4(248.64,38.34) 248.77,38.47 248.77,38.77 248.02,39.52 248.02,40.84 247.29,41.58 247.29,48.23 245.41,50.11 245.41,50.84 243.63,52.61 242.91,52.61 236.92,58.6 236.92,59.55 233.82,62.66 222.05,62.66 220.83,63.88 219.03,63.88 215.26,67.65 204.69,67.65 204.24,68.11 200.96,68.11 198.78,65.93 195.01,65.93 192.78,68.16 190.82,68.16 189.98,67.32 181.35,67.32 181.24,67.2 179.28,67.2 179.23,67.15 172.93,67.15 172.36,67.72 171.52,67.72 170.95,67.15 169.74,67.15 169.28,66.7 168.28,66.7 167.56,67.42 165.45,67.42 165.13,67.74 157.92,67.74 157.46,67.28 155.35,67.28 153,64.93 145.26,64.93 144.62,64.3 143.37,64.3 143.15,64.07 142.03,64.07 141.8,64.3 141.04,64.3 139.36,62.62 138.3,62.62 137.88,62.2 137.88,61.46 v4(138.15,61.19)
  BOTTOM w0.109: JNGFF2.71 248.65,35.79 248.77,35.91 248.77,38.18 248.64,38.31 v4(248.64,38.34)
CLK_PCIE0#: length 139.9
  IN4 w0.076: v4(249.07,38.34) 248.95,38.46 248.95,38.84 248.2,39.59 248.2,40.91 247.47,41.65 247.47,48.3 245.59,50.18 245.59,50.91 243.71,52.79 242.99,52.79 237.1,58.67 237.1,59.62 233.89,62.84 222.12,62.84 220.9,64.05 219.11,64.05 215.33,67.83 204.77,67.83 204.31,68.28 200.88,68.28 198.7,66.11 195.08,66.11 192.86,68.33 190.75,68.33 189.91,67.5 181.28,67.5 181.16,67.38 179.21,67.38 179.16,67.33 173.01,67.33 172.43,67.9 171.45,67.9 170.87,67.33 169.67,67.33 169.21,66.87 168.35,66.87 167.63,67.6 165.52,67.6 165.21,67.92 157.84,67.92 157.39,67.46 155.28,67.46 152.93,65.11 145.18,65.11 144.55,64.47 143.3,64.47 143.07,64.24 142.11,64.24 141.88,64.47 140.97,64.47 139.29,62.8 138.22,62.8 137.7,62.27 137.7,61.62 v4(137.59,61.51)
  BOTTOM w0.109: v4(249.07,38.34) 249.03,38.3 249.03,35.91 249.15,35.79 JNGFF2.73
CLK_PCIE2: length 106.5
  IN4 w0.076: v4(222.82,61.47) 222.69,61.34 221.82,61.34 220.44,62.72 218.51,62.72 216.5,64.73 210.56,64.73 208.73,66.56 201.14,66.56 199.41,64.83 186.18,64.83 185.77,65.24 183.64,65.24 180.98,62.57 180.29,62.57 178.14,64.72 175.41,64.72 174.83,65.3 170.52,65.3 170.06,64.84 169.72,64.84 168.34,63.47 160.41,63.47 159.58,64.3 153.94,64.3 153.1,63.46 148.4,63.46 147.77,62.84 140.09,62.84 139.48,62.23 138.72,62.23 138.33,61.84 v4(138.15,61.84)
  BOTTOM w0.109: JNGFF1.39 218.05,51.49 218.16,51.38 220.06,51.38 220.78,52.1 220.78,52.68 221.65,53.54 221.65,54.14 222.03,54.52 222.03,56.84 222.17,56.98 222.17,61.09 222.46,61.39 222.74,61.39 v4(222.82,61.47)
CLK_PCIE2#: length 106.4
  IN4 w0.076: v4(138.72,61.51) 138.55,61.68 138.55,61.81 138.79,62.05 139.55,62.05 140.16,62.66 147.85,62.66 148.47,63.28 153.18,63.28 154.02,64.12 159.51,64.12 160.33,63.29 168.42,63.29 169.79,64.66 170.13,64.66 170.59,65.12 174.76,65.12 175.34,64.54 178.06,64.54 180.22,62.39 181.05,62.39 183.72,65.06 185.7,65.06 186.1,64.65 199.48,64.65 201.21,66.38 208.66,66.38 210.49,64.55 216.43,64.55 218.44,62.54 220.36,62.54 221.75,61.16 222.7,61.16 v4(222.82,61.04)
  BOTTOM w0.109: v4(222.82,61.04) 222.74,61.12 222.57,61.12 222.43,60.98 222.43,56.87 222.29,56.73 222.29,54.41 221.91,54.03 221.91,53.43 221.05,52.56 221.05,51.99 220.17,51.11 218.2,51.11 218.08,50.99 JNGFF1.41
CLK_PCIE3: length 135.4
  IN4 w0.076: v4(141.14,63.23) 141.2,63.29 145.09,63.29 145.43,63.64 145.43,64.02 145.71,64.3 153.28,64.3 155.63,66.65 157.88,66.65 158.02,66.78 158.44,66.78 159.12,66.1 161.25,66.1 161.36,66.21 164.41,66.21 165.03,65.6 166.34,65.6 167.1,64.83 167.97,64.83 169.21,66.06 169.55,66.06 170.01,66.52 181.64,66.52 182.44,65.72 185.95,65.72 186.38,65.29 199.15,65.29 200.88,67.01 212.36,67.01 214.04,65.34 216.55,65.34 218.67,63.22 220.59,63.22 221.87,61.93 222.91,61.93 223.34,61.5 224.25,61.5 224.4,61.65 232.97,61.65 242.76,51.86 243.3,51.86 244.77,50.39 244.77,49.85 244.87,49.74 244.87,46.62 245.78,45.72 245.78,43 245.31,42.53 245.31,38.21 245.03,37.93 v4(244.9,37.93)
  BOTTOM w0.109: v4(244.9,37.93) 245.07,37.77 245.07,37.64 244.96,37.54 243.82,37.54 242.77,36.48 242.77,35.91 242.65,35.79 JNGFF2.47 ; UCPU1.C37 141.08,61.51 140.99,61.6 140.99,61.68 141.09,61.78 141.09,61.88 140.93,62.05 140.93,63.12 141.04,63.23 v4(141.14,63.23)
CLK_PCIE3#: length 135.4
  IN4 w0.076: v4(245.48,37.93) 245.48,42.45 245.95,42.92 245.95,45.79 245.05,46.69 245.05,49.82 244.95,49.92 244.95,50.47 243.38,52.04 242.83,52.04 233.04,61.83 224.33,61.83 224.17,61.68 223.41,61.68 222.98,62.11 221.94,62.11 220.66,63.39 218.75,63.39 216.63,65.51 214.11,65.51 212.44,67.19 200.81,67.19 199.08,65.46 186.45,65.46 186.02,65.9 182.52,65.9 181.72,66.7 169.93,66.7 169.47,66.24 169.13,66.24 167.9,65.01 167.18,65.01 166.41,65.77 165.1,65.77 164.48,66.39 161.29,66.39 161.17,66.28 159.2,66.28 158.51,66.96 157.94,66.96 157.8,66.82 155.56,66.82 153.21,64.47 145.64,64.47 145.26,64.09 145.26,63.71 145.02,63.47 141.36,63.47 v4(141.17,63.66)
  BOTTOM w0.109: v4(141.17,63.66) 141.09,63.66 140.66,63.23 UCPU1.B38 ; v4(245.48,37.93) 245.33,37.78 245.33,37.53 245.07,37.27 243.93,37.27 243.03,36.37 243.03,35.91 243.15,35.79 JNGFF2.49
CLK_PCIE_CD: length 174.2
  TOP w0.109: U1.5 264.97,19.91 264.9,19.85 264.66,19.85 v7(264.59,19.92)
  IN1 w0.076: v7(264.59,19.92) 264.74,19.77 264.97,19.77 265.58,20.38 265.58,23.76 264.51,24.82 264.51,29.24 265.42,30.16 265.42,32.29 264.85,32.87 264.85,39.23 259.95,44.13 251.07,44.13 250.08,43.14 246.61,43.14 245.47,41.99 235.18,41.99 231.84,45.33 231.84,47.49 231.21,48.13 231.21,51.24 230.04,52.41 229.41,52.41 226.92,54.9 226.92,55.96 226.64,56.24 226.13,56.24 221.84,60.54 220.39,60.54 218.92,62.01 218.26,62.01 217.24,63.03 208.68,63.03 208.22,62.57 204.03,62.57 203.65,62.19 203.65,61.12 202.58,60.05 200.58,60.05 200.46,59.94 199.09,59.94 198.34,59.19 198.34,58.23 197.72,57.6 193.51,57.6 192.94,58.18 192.92,58.18 192.25,58.85 189.67,58.85 189,58.18 184.6,58.18 183.5,59.28 182.46,59.28 177.19,64.55 175,64.55 174.65,64.91 173.12,64.91 172.75,65.27 170.5,65.27 168.9,63.67 167.57,63.67 166.64,62.75 159.81,62.75 159.3,63.25 154.17,63.25 153.43,62.52 139.24,62.52 138.57,63.19 v1(138.36,63.19)
  BOTTOM w0.109: UCPU1.A41 138.72,62.56 138.61,62.45 138.46,62.45 138.36,62.56 v1(138.36,63.19)
CLK_PCIE_CD#: length 174.3
  TOP w0.109: v7(264.59,19.49) 264.67,19.58 264.86,19.58 264.93,19.51 U1.6
  IN1 w0.076: v7(264.59,19.49) 264.69,19.59 265.04,19.59 265.75,20.31 265.75,23.83 264.69,24.9 264.69,29.17 265.6,30.08 265.6,32.37 265.03,32.94 265.03,39.3 260.03,44.31 251,44.31 250.01,43.32 246.54,43.32 245.4,42.17 235.25,42.17 232.02,45.4 232.02,47.57 231.39,48.2 231.39,51.31 230.11,52.59 229.48,52.59 227.09,54.97 227.09,56.04 226.71,56.42 226.21,56.42 221.91,60.71 220.47,60.71 218.99,62.19 218.33,62.19 217.32,63.2 208.61,63.2 208.15,62.75 203.96,62.75 203.47,62.26 203.47,61.2 202.51,60.23 200.5,60.23 200.39,60.12 199.02,60.12 198.16,59.26 198.16,58.3 197.65,57.78 193.58,57.78 193.01,58.36 193,58.36 192.33,59.03 189.59,59.03 188.92,58.36 184.67,58.36 183.57,59.46 182.53,59.46 177.26,64.73 175.08,64.73 174.72,65.08 173.2,65.08 172.83,65.45 170.43,65.45 168.83,63.85 167.5,63.85 166.57,62.92 159.89,62.92 159.38,63.43 154.1,63.43 153.36,62.7 139.31,62.7 139.03,62.97 v1(139.03,63.29)
  BOTTOM w0.109: v1(139.03,63.29) 139.03,62.38 138.82,62.16 UCPU1.B41
CLK_REQ0#: length 87.9
  TOP w0.109: Q348.3 174.82,51.13 175.14,51.44 RH417.1 176.48,50.83 v7(177.21,50.83) ; R1343.2 v2(248.34,41.41) 248.34,41.37 v1(247.62,40.65)
  IN1 w0.076: v7(177.21,50.83) 177.41,50.83 179.36,48.87 183.01,48.87 183.26,48.62 184.66,48.62 185.49,47.8 195.33,47.8 195.84,47.29 202.29,47.29 203.09,46.49 206.19,46.49 206.54,46.13 209.71,46.13 210.73,47.15 213.12,47.15 213.75,47.79 214.91,47.79 215.5,47.2 218.85,47.2 219.5,47.86 221.73,47.86 222.32,47.27 224.29,47.27 225.34,46.21 225.34,45.67 226.78,44.23 226.78,43.16 227.35,42.6 228.17,42.6 229.43,41.34 229.43,39.66 229.94,39.15 232.65,39.15 233.81,37.98 241.07,37.98 241.41,38.32 245.09,38.32 245.46,38.69 245.66,38.69 v1(247.62,40.65)
  BOTTOM w0.109: v1(247.62,40.65) 247.9,40.93 JNGFF2.68
CLK_REQ2#: length 16.8
  TOP w0.109: v1(222.14,52.29) 222.34,52.5 v2(222.64,52.5) 222.74,52.4 R1339.2 ; Q346.3 228.23,48.67 228.23,49.93 RH410.1 227.6,49.36 v7(227.3,49.36)
  IN1 w0.076: v7(227.3,49.36) 227.3,49.83 226.94,50.19 226.23,50.19 224.92,51.49 222.84,51.49 222.5,51.84 222.5,51.94 v1(222.14,52.29)
  BOTTOM w0.109: v1(222.14,52.29) 220.06,50.21 219.28,50.21 219.06,49.99 JNGFF1.45
CLK_REQ3#: length 102.5
  TOP w0.109: v1(246.07,37.88) v2(246.07,39.44) 246.68,40.05 246.68,41.77 R1340.2 246.14,41.77 246.14,40.85 245.15,39.86 244.71,39.86 v7(244.33,40.24)
  IN1 w0.076: v1(170.05,53.53) 170.9,53.53 171.23,53.86 173.29,53.86 173.81,53.34 182.25,53.34 184.11,51.48 186.44,51.48 187.06,50.86 190.22,50.86 190.91,51.54 191.33,51.54 191.9,50.97 196.83,50.97 198.11,49.69 199.73,49.69 200.42,50.38 203.34,50.38 203.85,50.88 205.38,50.88 205.81,50.45 207.16,50.45 207.66,50.96 207.66,51.67 207.95,51.96 210.63,51.96 211.03,51.56 218.31,51.56 218.8,51.08 221.65,51.08 222.31,50.41 224.22,50.41 226.98,47.66 226.98,46.42 229.33,44.07 229.33,43.16 230.05,42.44 231.69,42.44 234.93,39.2 239.66,39.2 240.65,40.19 244.28,40.19 v7(244.33,40.24)
  BOTTOM w0.109: v1(246.07,37.88) 246.07,37.19 245.65,36.78 244.65,36.78 244.31,36.44 244.31,35.97 244.15,35.82 JNGFF2.53 ; RH418.1 169.59,50.78 170.69,51.89 Q350.3 171.24,52.16 170.53,52.87 170.53,53.04 v1(170.05,53.53)
CLK_SMB: length 10.6
  TOP w0.109: PR109.1 65.08,11.72 65.36,11.44 PD103.2 65.36,8.07 v1(65.54,7.9) v2(66.01,7.43)
  BOTTOM w0.109: JBATT1.7 64.31,6.67 v1(65.54,7.9)
CLKOUT_LPC0: length 34.7
  TOP w0.109: RH360.1 RH428.1 179.23,29.13 174.99,33.37 163,33.37 159.19,37.18 159.19,39.21 156.84,41.56 v2(156.84,42.31) v1(156.84,43.47)
  BOTTOM w0.102: v1(156.84,43.47) 156.5,43.81 155.77,43.81 155.6,43.97 155.6,44.13 UCPU1.AN15
CLKOUT_LPC1: length 34.6
  TOP w0.109: RH386.1 179.99,27.33 174.44,32.88 162.79,32.88 158.68,36.99 158.68,39.02 156.06,41.64 156.06,42.76 v2(155.59,43.23) 155.35,43.47 v1(154.88,43.47)
  BOTTOM w0.109: v1(154.88,43.47) 155.18,43.76 UCPU1.AP15
CMSRC: length 128.5
  TOP w0.109: v1(26.97,58.48) v2(26.97,59.03)
  IN1 w0.254: v1(101.35,6.13) 101.42,6.06 101.42,4.76 100.79,4.12 97.45,4.12 96.89,3.56 93.47,3.56 92.75,4.28 91.31,4.28 90.31,3.28 57.46,3.28 56.26,4.49 48.27,4.49 47.7,3.92 46.94,3.92 46.48,4.38 42.74,4.38 41.97,5.14 41.1,5.14 37.81,8.43 37.81,12.87 36.09,14.6 36.09,14.93 35.72,15.3 35.72,16.22 35.93,16.44 35.93,17.4 35.83,17.5 35.83,18.92 35.07,19.68 35.07,21.33 34.07,22.33 34.07,23.34 32.4,25 32.4,31.67 32.31,31.76 32.31,40.15 31.26,41.21 29.46,41.21 29.2,41.47 29.2,42.43 28.62,43.01 28.62,47.74 27.93,48.42 27.93,52.1 28.84,53 28.84,55.15 26.99,56.99 26.99,58.45 v1(26.97,58.48)
  BOTTOM w0.254: v1(101.35,6.13) 101.28,6.21 PU201.3 ; PR203.2 27.92,58.06 27.5,58.48 v1(26.97,58.48)
COMP: length 4.8
  TOP w0.203: PU701.26 97.62,59.91 PR726.1 PR727.2 96.98,61.12 PC714.2 96.32,60.49 PC724.2
CONSOLE_RX: length 19.2
  TOP w0.076: U636.D3 248.09,61.09 248.09,60.14
  TOP w0.109: JSNRDG.14 253.94,65.16 v7(253.94,65.16) ; T261.1 248.74,59.09 248.37,59.46 v7(248.37,59.72) 248.36,59.73 248.36,59.78 248.09,60.05 248.09,60.14
  IN1 w0.076: v7(253.94,65.16) 255.47,63.64 255.47,58.3 255.41,58.24 249.01,58.24 248.36,58.88 248.36,59.72 v7(248.37,59.72)
CONSOLE_TX: length 19.9
  TOP w0.076: 247.84,59.82 247.84,59.97 247.58,60.23 247.58,60.58 U636.D2
  TOP w0.109: v7(253.94,65.67) 253.92,65.67 253.91,65.66 JSNRDG.15 ; T260.1 247.86,59.33 v7(247.86,59.77) 247.84,59.8 247.84,59.82
  IN1 w0.076: v7(247.86,59.77) 248.02,59.62 248.02,58.94 248.93,58.03 255.49,58.03 255.67,58.21 255.67,63.94 v7(253.94,65.67)
CPU_B+: length 20.2
  TOP w0.508: PR717.1 105.28,61.53 v1(105.4,61.65)
  IN3 w0.508: v6(94.32,49.39) 94.32,50.92 94.99,51.6 94.99,52.42 96.44,53.87 96.44,54.54 96.95,55.05 100.04,55.05 100.5,55.51 100.5,56.07 101.03,56.6 102.05,56.6 103.45,58 103.7,58 104.92,59.22 104.92,61.17 v1(105.4,61.65)
  vias: v2(96.02,48.27) v6(88.46,45.58) v6(91.51,45.58) v6(92.02,43.16) v6(92.4,45.58) v6(92.78,43.67) v6(93.03,44.56) v6(94.21,48.13) v6(94.63,48.79) v6(94.98,48.14) v6(95.32,48.75)
CPU_EDP_HPD#: length 15.9
  TOP w0.109: RC148.1 154.23,67.39 154.18,67.34 RC160.1 154.69,66.02 155.83,66.02 QC5.3 157.51,66.72 v7(157.83,66.4) 158.07,66.4 158.5,65.97 158.5,63.91 v2(158.16,63.57)
  IN1 w0.076: v7(157.83,66.4) 157.85,66.43 158.16,66.43 v3(158.21,66.38)
  IN2 w0.102: v3(159.56,61.22) 158.21,62.57 v3(158.21,66.38)
  IN4 w0.076: v3(159.56,61.22) 159.75,61.03 v4(160.09,61.03)
CPU_PATH_EN: length 4.1
  TOP w0.109: U697.2 87.86,64.75 88.02,64.6 88.02,64.12 88.5,63.64 R1325.2 R1324.2 89.39,62.87 v2(89.13,62.62)
CPU_PATH_EN_G: length 15.8
  TOP w0.109: U663.10 86.92,63.24 86.75,63.41 85.22,63.41 ; 85.22,63.41 85.22,62.72 85.42,62.53 U663.13 84.16,61.99 83.9,61.73 83.9,60.74 v7(84.08,60.56) 84.13,60.52 U663.1 ; 85.22,63.41 84.84,63.41 84.18,64.07 v2(84.18,64.75) 84.18,65.08 84.5,65.4 U697.4 ; U663.4 86.42,58.92 v7(86.18,58.68)
  IN1 w0.076: v7(84.08,60.56) 85.96,58.68 v7(86.18,58.68)
CPU_XDP_TCK: length 31.3
  TOP w0.109: v7(123.41,57.62) 123.03,58 122.52,58 T265.1 122.4,57.43 RC52.1
  IN1 w0.076: v3(127.15,59.88) 127.53,59.88 128.21,59.19 128.21,58.43 126.89,57.11 123.92,57.11 v7(123.41,57.62) 121.33,55.53 121.33,51.95 119.91,50.53 119.91,49.76 115.72,45.57 115.72,44.84 114.83,43.95 v3(114.83,43.94)
  IN4 w0.076: v4(126.74,59.8) 127.07,59.8 v3(127.15,59.88) ; v3(114.83,43.94) v4(114.83,43.54)
  BOTTOM w0.109: v4(126.74,59.8) 126.74,60.12 UCPU1.E60 ; v4(114.83,43.54) 115,43.72 117.54,43.72 RH446.1
CPU_XDP_TDI: length 54.2
  TOP w0.109: v1(87.34,62.9) 87.42,62.83 U663.9
  IN1 w0.076: v1(87.34,62.9) 87.62,62.62 89.79,62.62 91.37,61.04 102.54,61.04 105.31,63.81 107.11,63.81 108.96,65.66 112.71,65.66 114.41,63.96 117.04,63.96 118.13,65.05 122.96,65.05 v7(125.16,62.85) 126.66,61.35 126.66,60.66 126.21,60.21 125.62,60.21 v3(125.14,59.72)
  IN4 w0.076: v3(125.14,59.72) 124.83,59.42 v4(124.83,59.38)
  BOTTOM w0.109: RC46.1 121.04,61.26 122.05,61.26 123.71,59.6 124.44,59.6 124.66,59.38 v4(124.83,59.38)
CPU_XDP_TDO: length 56.7
  TOP w0.109: U663.5 86.92,58.66 v7(86.92,58.66)
  IN1 w0.076: v3(125.76,59.11) 125.58,59.29 125.04,59.29 124.71,59.62 124.71,59.88 125.22,60.38 126.03,60.38 126.42,60.78 126.42,61.21 123.26,64.37 v7(122.88,64.37) 120.49,64.37 119.83,63.71 114.37,63.71 112.63,65.46 109.05,65.46 105.84,62.25 104.05,62.25 102.64,60.84 89.99,60.84 89.35,60.21 88.47,60.21 v7(86.92,58.66)
  IN4 w0.076: v3(125.76,59.11) 125.5,59.38 v4(125.48,59.38)
  BOTTOM w0.109: RC48.1 120.85,60.18 120.85,60.56 121.23,60.94 121.99,60.94 123.56,59.37 124.41,59.37 124.68,59.1 124.95,59.1 125.23,59.38 v4(125.48,59.38)
CPU_XDP_TMS: length 59.5
  TOP w0.109: U663.12 85.92,62.71 v1(85.68,62.95)
  IN1 w0.076: v3(125.93,59.77) 126.35,59.77 v7(126.56,59.99) 126.82,60.24 126.82,61.67 122.56,65.93 108.92,65.93 107.01,64.02 105.23,64.02 102.46,61.25 91.45,61.25 89.8,62.9 87.9,62.9 87.5,63.31 87.17,63.31 86.4,62.54 86.09,62.54 v1(85.68,62.95)
  IN4 w0.076: v3(125.93,59.77) 125.99,59.84 v4(126.3,59.84)
  BOTTOM w0.102: v4(126.3,59.84) 126.3,59.76 126.43,59.62 126.43,59.24 126.23,59.04 125.29,59.04 125.16,58.91 124.28,58.91
  BOTTOM w0.109: v4(126.3,59.84) 126.13,60.01 UCPU1.E61 ; RC45.1 120.85,59.29 120.85,59.74 121.1,59.99 121.1,60.48 121.31,60.69 121.91,60.69 123.5,59.09 124.1,59.09 124.28,58.91
CPU_XDP_TRST#: length 56.6
  TOP w0.109: v1(84.89,58.91) 84.89,58.26 RH370.2 85.42,58.1 U663.2 ; v7(123.41,58.07) 123.18,58.3 122.23,58.3 121.49,57.56 120.96,57.56 120.67,57.27 T267.1 120.83,56.95 RC54.1
  IN1 w0.076: v3(127.42,59.39) 127.3,59.27 127.3,58.53 126.66,57.89 123.59,57.89 v7(123.41,58.07) 122.24,59.24 117.67,59.24 117.47,59.04 112.11,59.04 111.6,58.53 108.55,58.53 106.34,60.74 103.12,60.74 102.81,60.43 95.13,60.43 92.69,58 90.75,58 89.93,58.81 88.19,58.81 87,57.62 86.19,57.62 v1(84.89,58.91)
  IN4 w0.076: v3(127.42,59.39) 127.64,59.6 v4(127.64,59.75)
  BOTTOM w0.109: UCPU1.E59 127.64,59.96 v4(127.64,59.75)
CR_PWREN: length 152.7
  TOP w0.109: v1(265.73,6.99) v2(266.35,6.99) 267.01,7.65 U720.3 ; RH83.1 168.42,48.75 168.4,48.78 v7(168.4,48.83)
  IN1 w0.076: v7(168.4,48.83) 168.45,48.78 168.45,48.4 v3(168.42,48.37)
  IN2 w0.102: v1(265.73,6.99) 265.73,7.65 263.66,9.72 263.66,38.53 262.83,39.35 256.88,39.35 254.29,41.94 253.33,41.94 253.02,41.63 253.02,41.02 250.78,38.78 249.07,38.78 247.88,39.98 240.82,39.98 240.32,39.47 233.87,39.47 231.18,42.15 227.69,42.15 226.32,43.52 225.33,43.52 223.1,45.75 221.31,45.75 220.37,44.81 217.67,44.81 217.29,45.19 214.69,45.19 213.96,44.47 213.26,44.47 211.97,45.75 209.96,45.75 208.79,46.92 204.07,46.92 202.77,48.22 200.54,48.22 199.47,49.28 195.29,49.28 194.63,49.94 194.01,49.94 193.46,49.4 192.76,49.4 190.92,47.56 185.62,47.56 184.96,48.22 181.95,48.22 181.3,48.87 178.17,48.87 177.92,49.11 177.92,49.82 177.68,50.05 175.82,50.05 175.44,50.43 170.36,50.43 169.98,50.05 168.73,50.05 168.42,49.74 v3(168.42,48.37)
  IN4 w0.076: v3(168.42,48.37) 168.19,48.14 168.19,47.76 167.07,46.64 164.15,46.64 164,46.8 v4(164,46.82)
  BOTTOM w0.102: UCPU1.AL2 162.53,46.13 162.53,46.72 162.7,46.89 163.94,46.89 v4(164,46.82)
CR_RST#: length 7.6
  TOP w0.109: U1.1 265.37,21.62 v1(264.6,22.39)
  BOTTOM w0.109: v1(264.6,22.39) 264.06,22.92 264.06,24.86 264.46,25.25 U678.4 264.46,26.57 264.66,26.78 R1208.1 v2(264.66,28.35)
CR_WAKE#: length 127.6
  TOP w0.109: v1(264.34,31.02) v2(265.57,29.8) 266.06,29.31 RR18.2
  IN2 w0.102: v3(176.77,53.93) 179.34,53.93 179.6,53.68 183.41,53.68 183.79,54.06 185.48,54.06 186.29,54.87 189.28,54.87 189.74,54.42 193.33,54.42 193.43,54.31 204.62,54.31 204.7,54.24 204.95,54.24 205.2,53.98 205.2,53.45 205.48,53.17 206.18,53.17 209.43,49.92 212.05,49.92 212.9,49.07 215.1,49.07 215.43,48.74 221.55,48.74 223.09,47.2 224.78,47.2 225.86,46.12 228.08,46.12 232.64,41.56 250.55,41.56 251.21,42.22 254.33,42.22 256.97,39.58 263.11,39.58 263.98,38.72 263.98,31.39 v1(264.34,31.02)
  IN4 w0.076: v4(164.18,49.64) 164.23,49.69 165.6,49.69 167.32,51.42 168.98,51.42 169.5,51.94 174.35,51.94 v4(176.16,53.74) 176.58,53.74 v3(176.77,53.93)
  BOTTOM w0.102: 163.79,49.22 163.7,49.13 161.49,49.13 160.82,49.79 UCPU1.AD5
  BOTTOM w0.109: v4(164.18,49.64) 164.18,49.61 163.79,49.22 ; RH295.1 175.2,51.57 175.94,52.31 175.94,53.53 v4(176.16,53.74)
CS_+1.2V: length 4.4
  BOTTOM w0.203: PR604.2 93.91,30.6 94.3,31 v2(95.19,31) 95.64,31 96.83,32.19 96.83,32.85
CSN1: length 33.9
  TOP w0.203: PU701.18 102.03,61.48 103.82,63.27 PC718.2 PC708.2 104.76,63.25 105.37,63.25 v6(105.42,63.31)
  TOP w0.254: v6(100.69,45.86) 100.15,45.32 PR707.2 PR708.2 99.13,43.16 v2(99.13,42.93) v6(99.13,42.27)
  IN3 w0.254: v6(105.42,63.31) 105.49,63.23 106.2,63.23 106.81,62.61 106.81,56.99 103.96,54.13 103.96,51.97 102.78,50.8 102.78,47 101.8,46.02 100.85,46.02 v6(100.69,45.86)
  BOTTOM w0.254: v6(99.13,42.27) 99,42.4 99,42.91 99.49,43.39 PL701.3
CSON_B: length 16.4
  TOP w0.254: v6(94.39,6.56) 94.49,6.56 94.82,6.89 94.82,6.9 94.91,6.99 94.91,7.81 94.82,7.9 94.82,13.76 v2(92.64,15.94) 92.06,15.94 v6(91.89,16.11)
  BOTTOM w0.254: PU201.12 96.31,5.71 96.19,5.82 PC228.1 PC227.2 94.94,6.69 94.81,6.56 v6(94.39,6.56) ; PR216.3 91.69,15.81 91.89,16.01 v6(91.89,16.11)
CSOP_B: length 16
  TOP w0.254: v6(91.24,16.11) 91.24,15.96 91.65,15.56 92.45,15.56 v2(93.81,14.19) 94.44,13.56 94.44,7.23 v6(94.41,7.2)
  BOTTOM w0.254: PR216.2 91.69,16.61 91.24,16.16 v6(91.24,16.11) ; v6(94.41,7.2) 94.41,7.25 94.76,7.6 PC227.1 95.62,7.04 95.62,6.41 95.83,6.21 PU201.13
CSP1: length 27.8
  TOP w0.203: v6(105.4,62.67) 104.98,62.67 PC708.1 PC718.1 103.48,62.39 102.43,61.35 PU701.17
  TOP w0.254: PR702.2 PH702.1 99.18,45.14 PR707.1 99.23,45.4 v2(100.09,46.25) 100.4,46.57 v6(100.7,46.57)
  IN3 w0.254: v6(105.4,62.67) 105.45,62.72 105.99,62.72 106.31,62.4 106.31,57.2 103.45,54.34 103.45,52.18 102.32,51.05 102.32,47.24 101.58,46.49 100.78,46.49 v6(100.7,46.57)
CSSN_1: length 45.7
  TOP w0.203: v1(73.59,6.66) 73.59,6.68 73.36,6.9 v2(73.36,8.81) 73.36,13.65 73.67,13.95 PR201.3
  TOP w0.254: v6(102.61,6.99) 101.94,7.67 PC211.2 100.93,7.67 PC212.1
  IN1 w0.203: v1(73.59,6.66) 73.42,6.5 73.42,5.45 74.9,3.98 90.04,3.98 91.3,5.24 93.29,5.24 93.72,4.81 96.41,4.81 96.72,5.11 99.84,5.11 100.27,5.55 100.27,6.29 100.95,6.97 102.58,6.97 v6(102.61,6.99)
  BOTTOM w0.254: PU201.1 101.5,7.21 101.71,6.99 v6(102.61,6.99)
CSSP_1: length 46.2
  TOP w0.203: v1(72.98,6.65) v2(72.98,10.88) 72.98,13.67 72.7,13.95 PR201.2
  TOP w0.254: v6(102.63,6.36) 102.14,6.36 PC211.1 100.93,6.75 PC210.2
  IN1 w0.203: v1(72.98,6.65) 73.09,6.54 73.09,5.32 74.76,3.65 90.18,3.65 91.44,4.91 93.15,4.91 93.58,4.48 96.55,4.48 96.85,4.78 99.98,4.78 100.6,5.41 100.6,6.15 101.09,6.64 102.2,6.64 102.48,6.36 v6(102.63,6.36)
  BOTTOM w0.254: v6(102.63,6.36) 102.61,6.38 101.78,6.38 101.46,6.71 PU201.2
DAT_SMB: length 10.3
  TOP w0.109: PR111.1 64.19,11.97 63.43,11.21 PD103.3 63.43,8.38 v1(63.09,8.03) 62.74,7.69 v2(62.74,7.65)
  BOTTOM w0.109: v1(63.09,8.03) 62.81,7.76 JBATT1.6
DC_TEST_A3_B3: length 1.5
  BOTTOM w0.254: 162.86,63.36 UCPU1.A3 162.2,62.69 UCPU1.B3
DC_TEST_A61_B61: length 1.5
  BOTTOM w0.254: 125.8,63.48 126.07,63.21 UCPU1.A61 126.07,62.22 UCPU1.B61
DC_TEST_AY2_AW2: length 0.7
  BOTTOM w0.254: UCPU1.AW2 162.8,40.3 UCPU1.AY2
DC_TEST_AY3_AW3: length 0.7
  BOTTOM w0.254: UCPU1.AY3 162.14,40.24 UCPU1.AW3
DC_TEST_AY61_AW61: length 1.4
  BOTTOM w0.254: UCPU1.AW61 126.13,40.27 UCPU1.AY61 126.05,39.99 125.67,39.61
DC_TEST_AY62_AW62: length 1.4
  BOTTOM w0.254: 124.91,39.7 UCPU1.AY62 125.4,40.75 UCPU1.AW62
DC_TEST_B62_B63: length 1.4
  BOTTOM w0.254: 124.33,62.72 UCPU1.B63 125.35,62.22 UCPU1.B62
DC_TEST_C1_C2: length 1.5
  BOTTOM w0.254: 163.77,62.34 163.46,62.03 UCPU1.C1 163.34,61.56 UCPU1.C2
DCIN_GND:
  vias: v5(32.16,67.6) v6(30.93,68.82) v6(30.93,68.18) v6(30.93,67.55) v6(31.57,68.82) v6(31.57,68.18) v6(31.57,67.55) v6(32.2,68.82) v6(32.2,68.18) v6(32.85,68.82) v6(32.85,68.18) v6(33.5,68.82) v6(33.5,68.18)
DDR3_DRAMRST#: length 184.4
  TOP w0.102: CD28.1 133.43,15.03 v1(133.15,14.75) ; v1(107.86,14.75) 107.74,14.87 CD5.1 ; v1(155.1,14.7) 155.11,14.71 CD49.1
  TOP w0.109: CD72.1 178.44,11.49 v1(179.58,10.35) 179.58,10.62 180.12,11.16 180.65,11.16 180.9,10.9 182.86,10.9 186.7,14.74 v1(190.43,14.74)
  IN1 w0.076: v1(155.1,14.7) 144.1,14.7 v1(143.26,15.53)
  IN3 w0.102: v1(133.15,14.75) 133.15,14.67 130.29,11.81 127.77,11.81 125.77,9.82 117.77,9.82 v1(117.72,9.86) 117.68,9.82 115.15,9.82 111.98,12.99 109.26,12.99 107.86,14.39 v1(107.86,14.75)
  BOTTOM w0.102: v1(117.72,9.86) 118.54,10.68 118.54,14.79 UD2.T2 ; UD6.T2 153.95,15.12 154.37,14.7 v1(155.1,14.7) 155.48,14.31 158.46,14.31 160.04,12.73 163.14,12.73 165.01,14.61 ; UD5.T2 143.13,14.84 143.13,13.15 142.55,12.56 138.57,12.56 136.39,14.75 v1(133.15,14.75) 132.41,15.48 131.55,15.48 131.3,15.23 UD4.T2 ; UD7.T2 165.46,15.12 165.84,14.75 169.7,14.75 170.84,13.6 175.68,13.6 176.42,12.86 178.13,12.86 178.74,13.48 178.74,14.12 178.54,14.32 UD9.T2 179.75,13.91 179.75,10.51 v1(179.58,10.35) ; v1(107.86,14.75) 107.03,14.75 UD1.T2
  BOTTOM w0.109: UD5.T2 142.85,15.13 v1(143.26,15.53) ; UD10.T2 190.43,14.79 v1(190.43,14.74) 191.34,13.83 192.35,13.83 192.86,14.33 192.86,16.11 192.63,16.34 192.63,21.7 192.71,21.78 192.71,25.87 192.93,26.09 194.96,26.09 195.57,26.7 195.57,27.19 195.19,27.57 193.24,27.57 192.65,28.15 191.48,28.15 191.23,28.41 177.14,28.41 176.88,28.66 167.01,28.66 166.71,28.97 157.27,28.97 153.91,32.34 153.91,33.37 RC75.2 153.79,34.96 RC162.2 ; UD7.T2 165.46,15.05 165.01,14.61
DDR_A_BS0: length 137.4
  TOP w0.076: RD67.1 121.9,17.24 122.63,16.5 v2(122.63,16.24) 122.63,15.97 v1(122.43,15.76)
  IN1 w0.076: v3(110.82,16.37) 111.07,16.62 112.76,16.62 113.04,16.34 114.33,16.34 114.4,16.27 114.4,15.66 114.48,15.59 114.63,15.59 114.71,15.66 114.71,16.27 114.78,16.34 114.94,16.34 115.01,16.27 115.01,15.66 115.09,15.59 115.24,15.59 115.32,15.66 115.32,16.27 115.39,16.34 115.54,16.34 115.62,16.27 115.62,15.66 115.7,15.59 115.85,15.59 115.93,15.66 115.93,16.27 116,16.34 116.15,16.34 116.23,16.27 116.23,15.66 116.31,15.59 116.46,15.59 116.54,15.66 116.54,16.27 116.61,16.34 116.78,16.34 116.83,16.3 116.83,16.2 116.93,16.09 120.31,16.09 120.44,15.97 120.44,15.59 120.56,15.46 122,15.46 122.3,15.76 v1(122.43,15.76) 122.6,15.6 122.6,15.56 122.89,15.27 123.62,15.27 123.78,15.42 123.78,15.59 123.85,15.67 124.01,15.67 124.08,15.59 124.08,15.42 124.16,15.34 124.31,15.34 124.39,15.42 124.39,15.59 124.46,15.67 124.62,15.67 124.69,15.59 124.69,15.42 124.77,15.34 124.83,15.34 125.1,15.07 126.53,15.07 126.65,15.2 130.18,15.2 130.33,15.36 130.44,15.36 130.54,15.26 130.65,15.26 130.75,15.37 130.75,15.48 130.66,15.58 130.66,15.68 130.77,15.79 130.87,15.79 130.97,15.7 131.08,15.7 131.19,15.8 131.19,15.91 131.09,16.01 131.09,16.12 131.2,16.22 131.31,16.22 131.4,16.13 131.51,16.13 131.62,16.23 131.62,16.34 131.52,16.44 131.52,16.55 131.67,16.69 133.43,16.69 133.56,16.82 133.56,17.19 133.61,17.24 133.75,17.24 133.81,17.17 133.81,16.43 133.94,16.3 134.52,16.3 134.65,16.43 v3(134.65,16.5)
  IN3 w0.191: v1(142.8,37.04) 142.7,37.14 142.54,37.14 142.43,37.03 142.43,36.11 142.35,36.03 142.35,35.83 142.71,35.47 142.71,35.03 142.58,34.9 142.56,34.9 142.43,34.78 142.43,34.34 142.54,34.23 142.54,33.98 142.23,33.68 141.66,33.68 141.49,33.85 141.05,33.85 140.34,33.14 139.14,33.14 137.93,31.92 136.76,31.92 135.92,31.08 127.01,31.08 126.91,31.19 126.47,31.19 126.35,31.31 126.35,31.69 126.22,31.82 125.78,31.82 125.66,31.69 125.66,30.71 125.53,30.59 125.06,30.59 124.93,30.71 124.93,32.22 124.81,32.34 124.41,32.34 124.29,32.22 124.29,30.75 124.16,30.62 123.79,30.62 123.66,30.75 123.66,32.13 123.54,32.26 123.05,32.26 122.93,32.13 122.93,28.97 123.05,28.85 123.74,28.85 123.87,28.72 123.87,24.23 123.54,23.91 123.27,23.91 123.08,23.72 123.08,21.6 122.43,20.96 122.43,16.84 122.57,16.7 122.57,16.34 122.79,16.11 123.54,16.11 123.66,15.98 123.66,15.27 123.38,14.99 123.08,14.99 122.43,15.64 v1(122.43,15.76)
  IN4 w0.076: v4(142.85,18.32) 142.9,18.37 143.2,18.37 143.27,18.44 143.27,18.63 143.23,18.67 141.89,18.67 140.06,16.85 138.91,16.85 138.5,16.43 137.68,16.43 137.57,16.54 135.67,16.54 135.4,16.27 134.87,16.27 v3(134.65,16.5) 134.63,16.52 133.89,16.52 133.58,16.82 133.58,17.33 133.34,17.57 130.58,17.57 130.2,17.95 129.6,17.95 v4(129.16,17.52) ; v4(116.08,17.52) 116.08,17.32 115.59,16.83 114.6,16.83 114.23,16.46 112.27,16.46 112.17,16.56 111.26,16.56 111.06,16.37 v3(110.82,16.37) 110.7,16.25 109.86,16.25 108.94,17.16 108.94,17.25 108.63,17.57 105.86,17.57 105.49,17.94 104.95,17.94 104.69,17.68 v4(104.69,17.48)
  BOTTOM w0.076: v4(129.16,17.52) 128.95,17.73 128.95,18.43 129.12,18.61 131.01,18.61 UD4.M2 ; UD2.M2 117.93,18.61 115.75,18.61 115.56,18.42 115.56,18.04 115.77,17.83 115.77,17.63 115.88,17.52 v4(116.08,17.52) ; v1(142.8,37.04) 142.87,37.04 142.99,36.91 142.99,36.2 142.87,36.07 142.32,36.07 142.19,36.2 142.19,41.44 142.56,41.81 UCPU1.AU35 ; v4(104.69,17.48) 104.69,17.68 105.64,18.63 106.02,18.63 106.34,18.32 UD1.M2
DDR_A_BS1: length 128.1
  TOP w0.076: v1(123.05,16.56) 122.96,16.56 122.7,16.83 RD71.1
  IN1 w0.076: v3(133.85,17.96) 133.65,17.76 133.46,17.76 133.38,17.83 133.38,18.05 133.31,18.13 133.15,18.13 133.08,18.05 133.08,17.83 133,17.76 132.85,17.76 132.77,17.83 132.77,18.05 132.7,18.13 132.54,18.13 132.47,18.05 132.47,17.83 132.39,17.76 132.24,17.76 132.16,17.83 132.16,18.05 132.09,18.13 131.94,18.13 131.86,18.05 131.86,17.83 131.78,17.76 131.45,17.76 129.91,16.22 129.79,16.22 129.72,16.3 129.72,16.37 129.64,16.45 129.49,16.45 129.41,16.37 129.41,16.3 129.34,16.22 129.18,16.22 129.11,16.3 129.11,16.37 129.03,16.45 128.88,16.45 128.8,16.37 128.8,16.3 128.73,16.22 128.57,16.22 128.5,16.3 128.5,16.37 128.42,16.45 128.27,16.45 128.19,16.37 128.19,16.3 128.12,16.22 127.97,16.22 127.89,16.3 127.89,16.37 127.81,16.45 127.66,16.45 127.58,16.37 127.58,16.3 127.51,16.22 125.02,16.22 124.96,16.16 123.71,16.16 123.31,16.56 v1(123.05,16.56) 122.66,16.95 120.06,16.95 119.76,16.65 118.08,16.65 117.93,16.8 113.25,16.8 112.96,17.1 110.77,17.1 110.55,17.32 109.07,17.32 108.74,17.64 108.74,17.9 108.82,17.97 v3(109.11,17.97)
  IN3 w0.076: v1(142.78,37.88) 143.09,37.88 143.17,37.8 143.17,36.6 143.12,36.55
  IN3 w0.191: v1(123.05,16.56) 123.05,16.8 122.8,17.05 122.8,20.87 123.43,21.51 123.43,23.26 124.28,24.1 124.28,29.28 124.15,29.4 123.45,29.4 123.32,29.53 123.32,30.04 123.45,30.17 126.03,30.17 126.15,30.29 126.15,30.66 126.19,30.7 136.52,30.7 136.74,30.93 136.74,31.35 136.87,31.47 137.39,31.47 137.52,31.35 137.52,30.31 137.65,30.19 138.15,30.19 138.28,30.31 138.28,31.66 138.4,31.79 138.75,31.79 138.88,31.66 138.88,30.32 139,30.19 139.38,30.19 139.49,30.31 139.49,32.6 139.62,32.73 140.06,32.73 140.18,32.6 140.18,30.33 140.32,30.19 140.76,30.19 140.89,30.32 140.89,32.16 141.01,32.29 141.45,32.29 141.58,32.16 141.58,30.2 141.7,30.08 143.01,30.08 143.13,30.2 143.13,30.66 143.01,30.79 142.4,30.79 142.27,30.92 142.27,31.33 142.4,31.46 143.01,31.46 143.13,31.59 143.13,32.11 143.01,32.24 142.36,32.24 142.23,32.36 142.23,33.14 142.54,33.44 142.89,33.44 143.12,33.67 143.12,36.55
  IN4 w0.076: v4(101.86,17.52) 102.32,17.99 102.95,17.99 103.32,18.36 105.66,18.36 106.04,17.99 109.1,17.99 v3(109.11,17.97) 109.21,17.87 109.21,17.66 109.55,17.32 110.46,17.32 110.8,16.98 112.51,16.98 112.63,16.87 114.05,16.87 114.7,17.52 v4(114.8,17.52) ; v4(127.89,17.52) 128.8,18.43 130.47,18.43 130.84,18.06 133.75,18.06 v3(133.85,17.96) 133.85,17.79 134.21,17.42 134.66,17.42 134.81,17.26 135.55,17.26 135.76,17.05 138.36,17.05 138.8,17.49 139.42,17.49 v4(139.44,17.52)
  BOTTOM w0.076: v4(139.44,17.52) 139.09,17.87 138.66,17.87 138.31,17.52 UD5.N8 ; v4(127.89,17.52) 127.53,17.87 126.96,17.87 126.61,17.52 UD4.N8 ; v1(142.78,37.88) 142.87,37.88 142.99,37.75 142.99,37.51 142.87,37.38 142.47,37.38 142.34,37.51 142.34,41.38 142.45,41.49 UCPU1.AV35 ; v4(114.8,17.52) 114.45,17.87 114.02,17.87 113.67,17.52 UD2.N8
DDR_A_BS2: length 128.8
  TOP w0.076: RD69.1 119.29,16.37 119.95,15.71 v1(119.95,15.15)
  IN1 w0.076: v3(111.47,16.17) 111.4,16.1 111.4,15.83 111.5,15.73 111.73,15.73 112.01,16.01 112.15,16.01 112.19,16.05 112.19,16.3 112.3,16.41 112.45,16.41 112.55,16.3 112.55,15.94 112.65,15.84 112.78,15.84 112.98,16.03 113.3,16.03 113.43,15.9 113.43,15.42 113.54,15.31 113.71,15.31 113.82,15.42 113.82,16.08 113.87,16.14 114.08,16.14 114.18,16.04 114.18,15.51 114.3,15.38 116.65,15.38 116.79,15.52 116.79,15.76 116.86,15.83 116.97,15.83 117.05,15.76 117.05,15.39 117.06,15.38 117.23,15.38 117.3,15.45 117.3,15.76 117.36,15.82 117.36,15.83 117.52,15.83 117.63,15.72 117.63,15.11 117.74,15 117.9,15 118.01,15.11 118.01,15.74 118.12,15.84 118.26,15.84 118.37,15.74 118.37,15.03 118.44,14.95 118.65,14.95 118.72,15.03 118.72,15.72 118.83,15.83 118.99,15.83 119.1,15.72 119.1,14.98 119.15,14.93 119.73,14.93 v1(119.95,15.15) 119.99,15.19 122.02,15.19 122.19,15.36 122.51,15.36 122.8,15.06 124.73,15.06 124.93,14.86 130.53,14.86 132.15,16.48 133.48,16.48 133.8,16.15 133.8,16.15 133.85,16.1 135.8,16.1 v3(135.84,16.14)
  IN3 w0.191: v1(138.32,38.37) 136.53,38.37 136.08,37.93 135.09,37.93 134.53,37.37 133.4,37.37 133.28,37.5 133.28,37.84 133.15,37.96 132.87,37.96 132.74,37.84 132.74,37.5 132.62,37.37 132.16,37.37 132.03,37.5 132.03,38.79 131.91,38.92 131.47,38.92 131.35,38.79 131.35,37.49 131.22,37.37 130.8,37.37 130.67,37.49 130.67,38.5 130.55,38.62 130.11,38.62 129.99,38.5 129.99,37.32 129.86,37.19 129.86,36.67 129.73,36.54 129.28,36.54 129.07,36.74 129.07,37.11 128.87,37.31 127.9,37.31 127.85,37.27 127.22,37.27 127.1,37.39 127.1,37.95 125.78,39.27 121.4,39.27 113.41,31.28 113.41,29.52 113.87,29.06 113.87,28.03 114.11,27.79 115,27.79 115.22,27.58 115.22,24.84 117.34,22.72 117.34,21.56 117.63,21.28 119.52,21.28 120.45,20.35 120.45,19.15 120.32,19.02 119.38,19.02 119.25,18.89 119.25,18.63 119.38,18.51 120.18,18.51 120.45,18.23 120.45,17.26 120.08,16.89 120.08,15.28 v1(119.95,15.15)
  IN4 w0.076: v4(105.16,17.52) 105.49,17.52 105.65,17.36 106.23,17.36 106.89,16.7 109.11,16.7 109.77,16.04 110.38,16.04 110.44,15.98 111.28,15.98 v3(111.47,16.17) 111.52,16.22 114.27,16.22 114.66,16.6 116.41,16.6 116.72,16.91 v4(116.72,17.52) ; v4(142.05,18.32) 141.7,17.97 141.7,17.86 141.71,17.85 141.71,17.74 141.61,17.63 141.5,17.63 141.48,17.65 141.38,17.65 141.27,17.54 141.27,17.43 141.28,17.41 141.28,17.31 141.18,17.2 141.07,17.2 141.05,17.21 140.94,17.21 140.84,17.11 140.84,17 140.85,16.98 140.85,16.87 140.74,16.77 140.64,16.77 140.62,16.78 140.51,16.78 140.32,16.59 139.03,16.59 138.66,16.22 135.92,16.22 v3(135.84,16.14) 135.74,16.04 134.46,16.04 134.25,16.25 133.7,16.25 133.4,16.55 131.99,16.55 131.84,16.7 131.06,16.7 130.25,17.52 v4(129.8,17.52)
  BOTTOM w0.076: UD1.M3 105.86,18.21 v4(105.16,17.52) ; UD2.M3 116.92,18.32 116.63,18.03 116.63,17.6 v4(116.72,17.52) ; UD4.M3 130.5,18.21 v4(129.8,17.52) ; v1(138.32,38.37) 138.71,38.76 UCPU1.AY41
DDR_A_CAS#: length 127.1
  TOP w0.076: v1(124.02,18.03) 124,18.03 123.03,19 RD63.1
  IN1 w0.076: v3(110.9,18.65) 114.18,18.65 114.52,18.31 119.02,18.31 119.68,18.97 121.03,18.97 121.48,18.51 123.51,18.51 123.99,18.03 v1(124.02,18.03) 124.32,18.33 125.46,18.33 125.68,18.1 125.68,17.64 125.82,17.5 129.48,17.5 130.97,18.99 134.6,18.99 134.98,18.61 135.28,18.61 v3(135.31,18.58)
  IN3 w0.076: v1(143.04,41.84) 144.19,40.68 145.27,40.68 145.66,40.29 145.66,37.34
  IN3 w0.191: 145.66,37.34 145.53,37.21 145.53,26.35 144.63,25.46 140.4,25.46 140.27,25.33 140.27,24.92 140.4,24.79 144.38,24.79 144.5,24.66 144.5,23.98 144.38,23.85 141.22,23.85 141.09,23.72 141.09,23.32 141.22,23.19 144.4,23.19 144.53,23.06 144.53,21.34 144.4,21.21 139.63,21.21 139.5,21.09 139.5,20.7 139.63,20.57 141.34,20.57 141.47,20.44 141.47,19.71 141.34,19.59 136.84,19.59 136.53,19.9 136.01,19.9 135.12,20.79 132.95,20.79 131.7,19.55 127.64,19.55 127.27,19.18 125.91,19.18 125,18.27 124.26,18.27 v1(124.02,18.03)
  IN4 w0.076: v4(117.41,19.92) 117.41,19.61 116.79,18.99 113.98,18.99 113.91,18.91 113.91,18.82 113.83,18.75 113.68,18.75 113.6,18.82 113.6,18.91 113.53,18.99 113.37,18.99 113.3,18.91 113.3,18.82 113.22,18.75 113.07,18.75 112.99,18.82 112.99,18.91 112.92,18.99 112.76,18.99 112.69,18.91 112.69,18.82 112.61,18.75 112.46,18.75 112.38,18.82 112.38,18.91 112.31,18.99 112.15,18.99 112.08,18.91 112.08,18.82 112,18.75 111.85,18.75 111.77,18.82 111.77,18.91 111.7,18.99 111.28,18.99 110.94,18.65 v3(110.9,18.65) 110.77,18.65 110.35,19.07 108.88,19.07 108.68,19.27 106.04,19.27 105.92,19.15 104.85,19.15 v4(104.54,19.47) ; v4(141.48,20.06) 140.57,19.14 139.17,19.14 138.63,18.6 136.35,18.6 136.23,18.48 135.41,18.48 v3(135.31,18.58) 135.02,18.58 134.31,19.29 130.05,19.29 v4(129.31,20.03)
  BOTTOM w0.076: v1(143.04,41.84) 143.19,41.84 UCPU1.AU34 ; UD4.K3 130.5,19.89 130.18,19.57 129.77,19.57 v4(129.31,20.03) ; UD1.K3 105.86,19.89 105.08,19.12 104.89,19.12 v4(104.54,19.47) ; UD5.K3 142.05,19.84 141.73,19.52 141.58,19.52 141.43,19.67 141.43,20 v4(141.48,20.06)
DDR_A_CKE0: length 122.7
  TOP w0.076: RD57.1 122.88,21.63 v1(122.47,21.63)
  IN1 w0.076: v3(132.26,21.21) 132.01,21.21 131.88,21.33 131.88,21.55 132.01,21.68 132.54,21.68 132.7,21.52 132.84,21.52 133,21.68 133.15,21.68 133.31,21.52 133.45,21.52 133.61,21.68 133.67,21.68 133.79,21.8 133.79,21.89 133.91,22.01 134.07,22.01 134.19,21.89 134.19,21.8 134.32,21.68 134.44,21.68 134.55,21.57 134.55,21.38 134.42,21.25 133.28,21.25 133.15,21.12 133.15,21.03 132.84,20.72 132.72,20.72 132.59,20.59 132.59,20.47 132.48,20.35 132.31,20.35 132.2,20.47 132.2,20.59 132.07,20.72 130.71,20.72 129.84,19.84 125.68,19.84 123.89,21.63 123.77,21.63 123.69,21.56 123.69,21.2 123.62,21.12 123.47,21.12 123.39,21.2 123.39,21.56 123.31,21.63 v1(122.47,21.63) 122.47,20.87 122.2,20.6 121.92,20.6 121.84,20.68 121.84,20.83 121.72,20.96 121.54,20.96 121.41,20.83 121.41,20.73 121.28,20.6 119.74,20.6 118.64,19.5 116.7,19.5 115.33,20.87 114.93,20.87 113.72,19.66 111.8,19.66 110.53,20.94 109.95,20.94 109.69,20.67 109.33,20.67 109.25,20.76 108.98,20.76 108.68,21.06 107.68,21.06 v3(107.6,20.98)
  IN3 w0.076: 140.92,35.98 141.04,36.1 141.04,36.71 141.07,36.74 141.07,42.36 140.92,42.51 138.06,42.51 137.39,41.84 v1(136.74,41.84)
  IN3 w0.191: v1(122.47,21.63) 122.61,21.77 122.61,23.6 121.78,24.43 121.78,24.99 121.07,25.7 121.07,29.78 120.61,30.24 120.61,30.88 119.59,31.91 119.59,33.16 122.05,35.63 123.68,35.63 123.98,35.33 123.98,35.06 123.75,34.83 123.75,34.65 124.11,34.29 124.29,34.29 124.52,34.52 124.79,34.52 125.65,33.66 130.4,33.66 131.23,32.83 133.29,32.83 133.43,32.97 135.25,32.97 135.96,33.68 136.3,33.68 136.55,33.93 137.75,33.93 138.51,34.69 139.63,34.69 140.25,35.32 140.92,35.98
  IN4 w0.076: v4(101.06,19.92) 100.59,19.92 100.49,19.82 100.49,19.67 100.59,19.56 102.36,19.56 103.63,20.83 105.53,20.83 105.63,20.73 107.35,20.73 v3(107.6,20.98) 107.79,21.17 108.25,21.17 108.53,21.45 108.66,21.45 108.69,21.42 108.69,21.02 108.8,20.91 108.97,20.91 109.08,21.02 109.08,21.45 109.21,21.58 109.76,21.58 110.17,21.17 110.76,21.17 110.92,21.01 110.92,20.89 110.82,20.78 110.82,20.69 110.91,20.6 111.03,20.6 111.19,20.76 111.31,20.76 111.43,20.64 111.43,20.52 111.27,20.36 111.27,20.24 111.46,20.04 112.03,20.04 112.09,20.11 v4(112.09,20.33) ; v4(125.23,19.64) 127.15,19.64 127.54,20.03 127.54,20.15 128.27,20.89 130.25,20.89 130.41,20.72 131.77,20.72 v3(132.26,21.21) 132.47,21.42 133.48,21.42 133.6,21.29 133.6,21.06 133.68,20.98 133.83,20.98 133.91,21.06 133.91,21.36 133.96,21.42 134.12,21.42 134.24,21.29 134.24,21.05 134.28,21.01 134.59,21.01 134.81,20.79 135.76,20.79 v4(136.2,20.36)
  BOTTOM w0.076: UCPU1.AU43 137.04,42.14 v1(136.74,41.84) ; UD4.K9 125.7,19.89 125.44,19.64 v4(125.23,19.64) ; v4(136.2,20.36) 136.2,20.07 136.81,19.46 137.61,19.46 137.74,19.59 137.74,19.79 137.61,19.92 UD5.K9 ; v4(112.09,20.33) 112.09,20.28 112.45,19.92 UD2.K9
DDR_A_CKE1: length 117.3
  TOP w0.076: v1(121.82,22.6) 122.39,22.6 RD87.1
  IN1 w0.076: v3(106.53,21.53) 107.15,21.53 107.31,21.38 108.61,21.38 108.8,21.56 109.86,21.56 110.05,21.38 110.52,21.38 111.95,19.94 113.6,19.94 114.77,21.11 115.42,21.11 116.6,19.93 118.77,19.93 119.65,20.81 120.49,20.81 121.62,21.93 121.62,22.39 v1(121.82,22.6) 122.27,22.6 122.34,22.67 122.34,23.7 122.47,23.83 122.66,23.83 122.79,23.7 122.79,22.18 122.94,22.03 123.78,22.03 125.1,20.71 125.25,20.71 125.33,20.79 125.33,21.01 125.4,21.09 125.56,21.09 125.63,21.01 125.63,20.79 125.71,20.71 126.36,20.71 126.41,20.65 126.88,20.65 126.95,20.58 126.95,20.17 127.03,20.09 127.18,20.09 127.26,20.17 127.26,20.58 127.33,20.65 127.48,20.65 127.56,20.58 127.56,20.17 127.64,20.09 127.79,20.09 127.87,20.17 127.87,20.58 127.94,20.65 128.07,20.65 128.15,20.58 128.15,20.21 128.23,20.13 128.38,20.13 128.46,20.21 128.46,20.58 128.53,20.65 128.68,20.65 128.76,20.58 128.76,20.21 128.84,20.13 128.99,20.13 129.07,20.21 129.07,20.58 129.14,20.65 129.29,20.65 129.37,20.58 129.37,20.21 129.45,20.13 129.6,20.13 129.68,20.21 129.68,20.58 129.75,20.65 129.98,20.65 130.35,21.02 130.46,21.02 130.51,20.97 130.62,20.97 130.73,21.08 130.73,21.19 130.68,21.24 130.68,21.35 v3(130.9,21.57)
  IN3 w0.076: 140.82,36.53 140.82,36.73 140.92,36.83 140.92,42.14 140.71,42.36 138.18,42.36 137.95,42.13 137.95,41.89 136.73,40.67 v1(136.73,40.5)
  IN3 w0.191: 140.82,36.53 140.77,36.48 140.77,36.39 139.46,35.08 138.35,35.08 137.58,34.32 136.39,34.32 136.14,34.07 135.8,34.07 135.09,33.36 133.26,33.36 133.15,33.24 132.73,33.24 132.61,33.37 132.61,33.65 132.48,33.77 132.12,33.77 131.99,33.65 131.99,33.37 131.87,33.24 131.37,33.24 130.56,34.05 125.81,34.05 123.85,36.02 121.8,36.02 119.19,33.42 119.19,31.74 120.18,30.75 120.18,30.11 120.65,29.64 120.65,25.52 121.39,24.78 121.39,24.35 122.28,23.46 122.28,22.58 122.15,22.45 121.95,22.45 121.82,22.58 v1(121.82,22.6)
  IN4 w0.076: v4(101.06,20.72) 100.79,20.72 100.66,20.59 100.66,20.41 100.79,20.28 101.14,20.28 101.66,19.76 102.26,19.76 103.53,21.03 105.54,21.03 106.03,21.53 v3(106.53,21.53) 107.39,21.53 107.55,21.38 108.16,21.38 108.6,21.82 109.82,21.82 110.24,21.4 110.98,21.4 111.28,21.71 111.43,21.71 111.56,21.58 111.56,21.4 111.42,21.26 111.42,21.08 111.61,20.89 111.79,20.89 v4(111.81,20.92) ; v4(125.25,20.3) 125.36,20.3 125.78,19.88 127.09,19.88 127.32,20.11 127.32,20.24 128.19,21.1 130.15,21.1 130.35,21.3 130.63,21.3 v3(130.9,21.57) 130.95,21.52 131.96,21.52 132.09,21.64 134.24,21.64 134.88,21 136.33,21 136.85,20.49 v4(136.85,20.35)
  BOTTOM w0.076: v1(136.73,40.5) 136.73,40.63 136.93,40.84 UCPU1.AW43 ; UD5.J9 137.25,20.67 136.93,20.35 v4(136.85,20.35) ; v4(125.25,20.3) 125.26,20.3 125.69,20.72 UD4.J9 ; v4(111.81,20.92) 111.89,20.84 112.49,20.84 UD2.J9
DDR_A_CS0#: length 118.5
  TOP w0.076: v1(124.18,17.36) 124.22,17.31 125.26,17.31 RD61.1
  IN1 w0.076: v3(110.95,18) 110.98,18 111.42,18.44 114.05,18.44 114.39,18.1 119.11,18.1 119.65,18.63 120.68,18.63 121.28,18.02 123.31,18.02 123.97,17.36 v1(124.18,17.36) 124.95,17.36 125.22,17.09 127.09,17.09 127.16,17.17 127.16,17.21 127.24,17.29 127.39,17.29 127.47,17.21 127.47,17.17 127.55,17.09 127.7,17.09 127.77,17.17 127.77,17.21 127.85,17.29 128,17.29 128.08,17.21 128.08,17.17 128.15,17.09 128.31,17.09 128.38,17.17 128.38,17.21 128.46,17.29 128.61,17.29 128.69,17.21 128.69,17.17 128.76,17.09 128.92,17.09 128.99,17.17 128.99,17.21 129.07,17.29 129.22,17.29 129.3,17.21 129.3,17.17 129.37,17.09 129.76,17.09 131.44,18.77 134.51,18.77 135.19,18.09 v3(135.63,18.09)
  IN3 w0.076: 146.51,36.64 146.51,39.84 143.84,42.5 143.84,43.18 143.33,43.69 v1(143.29,43.69)
  IN3 w0.191: 146.51,36.64 146.14,36.27 146.14,26.03 145.13,25.02 145.13,24.01 145.33,23.81 145.48,23.81 145.65,23.64 145.65,23.31 145.48,23.15 145.32,23.15 145.15,22.98 145.15,22.65 145.32,22.49 145.48,22.49 145.65,22.32 145.65,21.14 145.47,20.96 145.21,20.96 145.02,20.77 145.02,20.17 143.92,19.06 142.55,19.06 142.47,18.98 136.66,18.98 136.1,19.54 135.66,19.54 135.05,20.15 134.53,20.15 134.15,19.76 133.25,19.76 132.98,19.49 132.98,18.4 132.85,18.27 131.35,18.27 131.22,18.4 131.22,19.01 131.09,19.14 129.26,19.14 129.14,19.01 129.14,18.67 129.26,18.55 130.14,18.55 130.27,18.42 130.27,17.17 130.14,17.05 127.55,17.05 127.42,17.17 127.42,18.12 127.3,18.25 126.74,18.25 126.61,18.12 126.61,17.17 126.48,17.05 125.52,17.05 125.25,17.31 124.22,17.31 v1(124.18,17.36)
  IN4 w0.076: v4(131.69,18.73) 130.83,18.73 130.73,18.84 130.73,18.98 130.83,19.08 134.14,19.08 135.13,18.09 v3(135.63,18.09) 135.65,18.09 135.84,18.28 136.31,18.28 136.43,18.39 138.75,18.39 139.27,18.91 140.82,18.91 141.42,19.51 v4(142.46,19.51) ; v4(117.82,19.53) 117.82,19.47 116.89,18.54 111.54,18.54 111,18 v3(110.95,18) 110.67,18.28 110.01,18.28 109.5,18.79 108.77,18.79 108.65,18.9 108.65,19 108.59,19.07 108.31,19.07 108.24,18.99 108.24,18.88 108.16,18.8 108.01,18.8 107.93,18.88 107.93,18.99 107.86,19.07 106.92,19.07 106.78,18.93 106.78,18.65 106.66,18.52 106.45,18.52 106.32,18.65 v4(106.32,18.79)
  BOTTOM w0.076: v4(131.69,18.73) 131.68,18.75 131.68,19.46 131.55,19.59 131.38,19.59 131.26,19.46 131.26,19.16 UD4.L2 ; UD1.L2 106.66,19.48 106.53,19.61 106.32,19.61 106.19,19.48 106.19,18.92 106.32,18.79 v4(106.32,18.79) ; v1(143.29,43.69) 143.55,43.95 UCPU1.AP33 ; UD2.L2 118.21,19.14 v4(117.82,19.53) ; v4(142.46,19.51) 142.85,19.12 UD5.L2
DDR_A_CS1#: length 119.1
  TOP w0.076: v1(124.69,16.85) 125.25,16.3 RD88.1
  IN1 w0.076: v3(138.28,17.97) 138.28,17.78 137.94,17.44 135.46,17.44 134.33,18.57 131.59,18.57 129.9,16.88 124.72,16.88 v1(124.69,16.85) 124.59,16.75 124.13,16.75 123.13,17.76 121.17,17.76 120.57,18.37 119.67,18.37 119.19,17.88 118.08,17.88 118,17.81 118,17.38 117.93,17.3 117.78,17.3 117.7,17.38 117.7,17.81 117.62,17.88 117.47,17.88 117.4,17.81 117.4,17.38 117.32,17.3 117.17,17.3 117.09,17.38 117.09,17.81 117.01,17.88 116.86,17.88 116.79,17.81 116.79,17.38 116.71,17.3 116.56,17.3 116.48,17.38 116.48,17.81 116.4,17.88 113.73,17.88 113.6,18.01 v3(113.6,18.04)
  IN3 w0.076: v1(144.17,43.63) 144.17,42.51 146.74,39.94 146.74,36.38
  IN3 w0.191: 146.74,36.38 146.53,36.17 146.53,19.95 144.77,18.19 143.27,18.19 142.91,18.55 141.63,18.55 141.44,18.36 141.44,17.5 141.25,17.31 140.86,17.31 140.67,17.5 140.67,18.36 140.48,18.55 139.53,18.55 138.03,17.05 135.59,17.05 134.89,17.75 134.89,18.03 134.84,18.07 134.84,19.05 134.72,19.18 133.5,19.18 133.37,19.05 133.37,17.73 133.24,17.6 131.22,17.6 131.09,17.47 131.09,16.74 130.97,16.61 126.79,16.61 126.6,16.42 126.6,16.15 126.48,16.02 126.21,16.02 126.08,16.15 126.08,16.44 125.91,16.61 125.44,16.61 125.31,16.49 125.31,16.12 125.19,15.99 124.82,15.99 124.69,16.12 v1(124.69,16.85)
  IN4 w0.076: v4(107.1,18.75) 107.27,18.58 109.42,18.58 109.94,18.06 110.29,18.06 110.88,17.48 113.22,17.48 113.46,17.72 113.46,17.9 v3(113.6,18.04) 113.76,18.19 118.48,18.19 119,18.71 119,19.14 v4(118.62,19.52) ; v4(132.51,18.76) 132.54,18.73 134.14,18.73 135.19,17.68 135.7,17.68 135.89,17.49 137.82,17.49 138.28,17.95 v3(138.28,17.97) 138.31,18 138.66,18 139.35,18.68 140.29,18.68 140.44,18.53 140.44,18.23 140.54,18.12 140.69,18.12 140.82,18.25 140.82,18.56 141.37,19.1 143.58,19.1 143.69,19.22 143.69,19.39 143.56,19.52 v4(143.26,19.52)
  BOTTOM w0.076: UD5.L1 143.65,19.13 v4(143.26,19.52) ; UD4.L1 132.61,19.12 132.73,19 132.73,18.89 132.6,18.76 v4(132.51,18.76) ; UCPU1.AR32 144.5,43.3 v1(144.17,43.63) ; UD1.L1 107.46,19.1 v4(107.1,18.75) ; UD2.L1 119.14,19.12 119.27,19.25 119.27,19.39 119.14,19.52 v4(118.62,19.52)
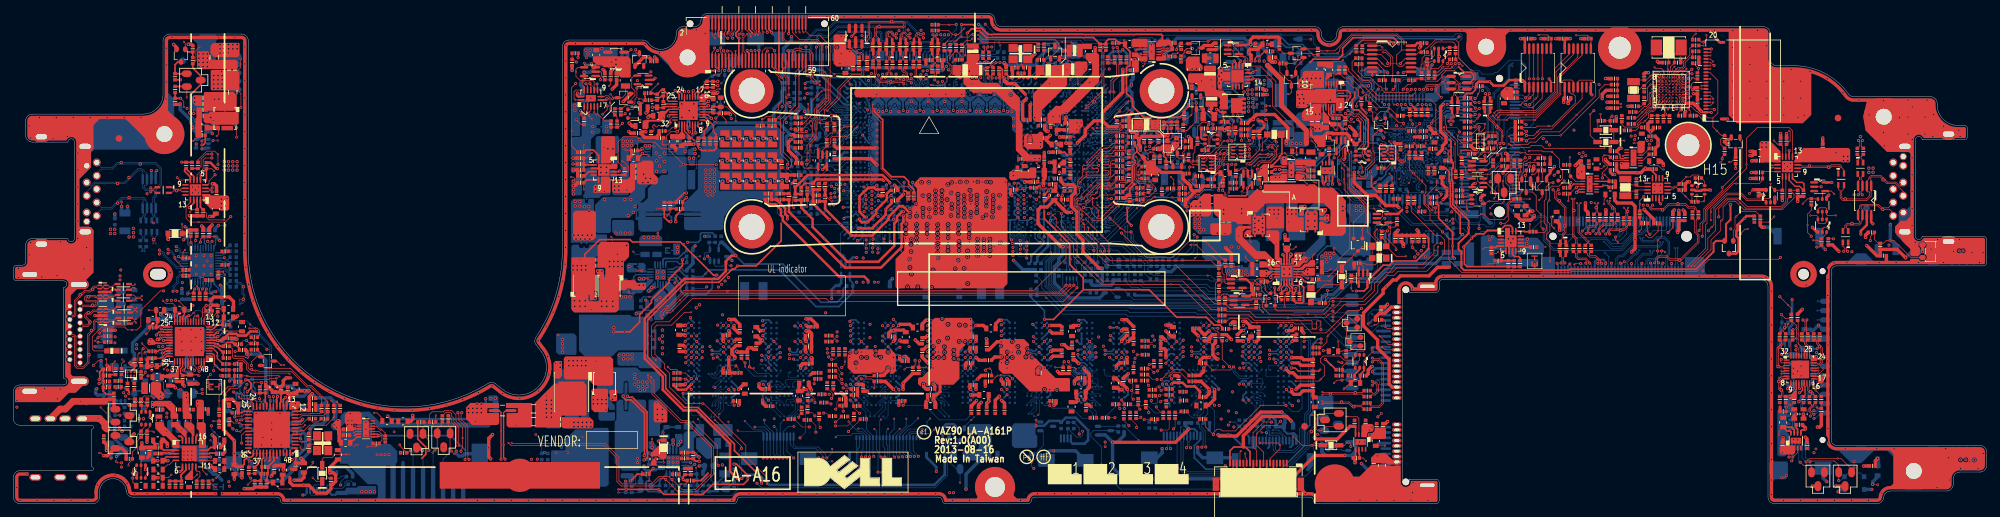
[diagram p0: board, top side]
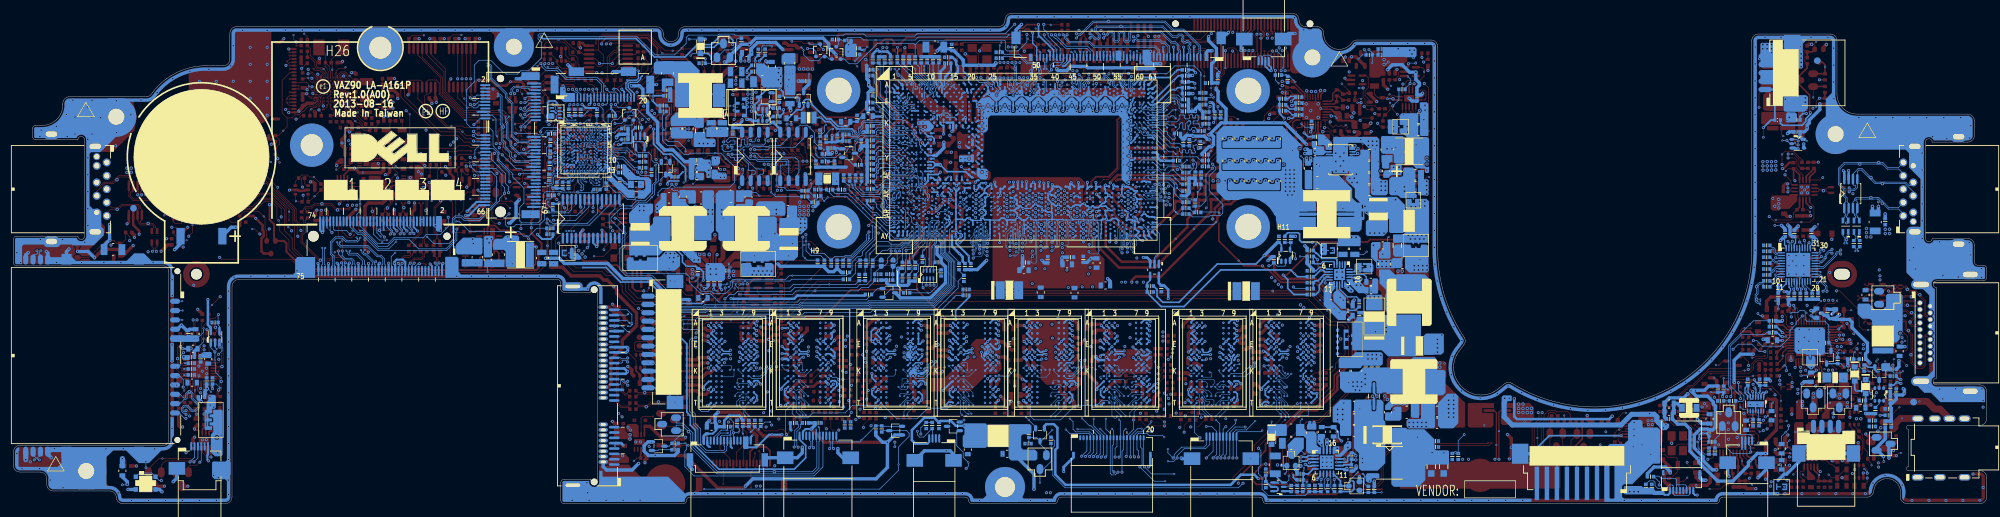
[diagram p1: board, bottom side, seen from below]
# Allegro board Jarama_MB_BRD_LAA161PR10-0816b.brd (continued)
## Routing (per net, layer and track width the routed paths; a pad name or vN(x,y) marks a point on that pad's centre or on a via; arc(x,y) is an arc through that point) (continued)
DDR_A_D0: length 36.6
  IN1 w0.127: v1(103.13,23.51) 103.11,23.53 103.11,28.33 119.45,44.67 119.45,45.92 121.83,48.3 123.41,48.3 123.82,47.88 v1(123.82,47.83)
  BOTTOM w0.076: v1(123.82,47.83) 124.19,47.46 124.76,47.46 UCPU1.AH63
  BOTTOM w0.178: UD1.F7 102.74,23.12 v1(103.13,23.51)
DDR_A_D1: length 38.4
  IN1 w0.127: v1(123.16,47.82) 122.96,48.02 122.06,48.02 119.81,45.77 119.81,44.52 103.55,28.26 103.55,22.34 103.11,21.9 v1(103.06,21.9)
  BOTTOM w0.076: UCPU1.AH62 125.45,47.54 125.16,47.25 124.61,47.25 124.56,47.3 123.82,47.3 123.29,47.82 v1(123.16,47.82)
  BOTTOM w0.178: UD1.H7 102.69,21.52 v1(103.06,21.9)
DDR_A_D2: length 35.3
  IN1 w0.127: v1(123.58,46) 122.76,45.18 121.95,45.18 121.75,44.97 121.75,43.48 110.09,31.83 110.09,24.44 109.57,23.92 109.3,23.92 109.17,23.79 109.17,23.61 109.05,23.48 108.79,23.48 108.66,23.61 108.66,24.02 108.54,24.15 108.28,24.15 108.16,24.02 108.16,23.69 108.03,23.56 107.78,23.56 107.65,23.69 107.65,23.79 107.52,23.92 107.26,23.92 107.24,23.93 106.46,23.93 106.26,23.74 v1(106.26,23.53)
  BOTTOM w0.076: v1(123.58,46) 123.77,46.18 UCPU1.AK63
  BOTTOM w0.178: UD1.F2 106.66,23.13 106.29,23.5 106.29,23.5 v1(106.26,23.53)
DDR_A_D3: length 36
  IN1 w0.127: v1(122.94,45.97) 122.94,45.71 122.68,45.44 121.75,45.44 121.4,45.1 121.4,43.66 109.73,31.99 109.73,27.48 107.05,24.81 106.03,24.81 105.83,24.6 105.83,22.5 v1(105.33,21.99)
  BOTTOM w0.076: v1(122.94,45.97) 122.94,45.96 123.27,45.63 123.73,45.63 123.99,45.89 124.99,45.89 125.28,46.18 UCPU1.AK62
  BOTTOM w0.178: v1(105.33,21.99) 105.8,21.52 UD1.H3
DDR_A_D4: length 40.3
  IN1 w0.127: v1(102.24,21.92) 102.66,22.33 102.66,23.97 102.73,24.04 102.73,28.47 119.09,44.82 119.09,46.07 121.7,48.68 123.62,48.68 v1(124.44,47.86)
  BOTTOM w0.076: UCPU1.AH61 125.75,47.92 124.5,47.92 v1(124.44,47.86)
  BOTTOM w0.178: v1(102.24,21.92) 101.86,21.53 UD1.H8
DDR_A_D5: length 42.5
  IN1 w0.127: v1(101.48,22.72) 101.01,23.19 101.01,26.94 101.85,27.79 101.85,28.1 118.72,44.97 118.72,46.22 121.56,49.06 123.84,49.06 125.43,47.47 v1(127.29,47.47)
  BOTTOM w0.076: UCPU1.AH60 127.23,47.54 v1(127.29,47.47)
  BOTTOM w0.178: v1(101.48,22.72) 101.86,23.1 UD1.F8
DDR_A_D6: length 36.6
  IN1 w0.127: v1(105.32,24.41) 105.32,25.91 105.45,26.04 105.88,26.04 106.01,25.91 106.01,25.21 106.14,25.09 106.45,25.09 106.58,25.21 106.58,25.35 106.71,25.48 107.24,25.48 109.34,27.58 109.34,32.11 121.07,43.85 121.07,45.25 121.71,45.9 122.35,45.9 v1(122.35,45.89)
  BOTTOM w0.076: UCPU1.AK61 126.06,46.29 125.46,45.7 124.02,45.7 123.8,45.48 122.77,45.48 v1(122.35,45.89)
  BOTTOM w0.178: v1(105.32,24.41) 105.34,24.39 105.34,24.38 105.37,24.36 105.37,24.35 105.8,23.92 UD1.E3
DDR_A_D7: length 37.1
  IN1 w0.127: v1(122.19,44.79) 122.14,44.74 122.14,43.38 110.51,31.74 110.51,24.41 109.25,23.15 109.25,22.79 109.12,22.66 108.89,22.66 108.77,22.79 108.77,23.14 108.64,23.27 107.88,23.27 107.75,23.14 107.75,22.78 107.73,22.76 106.3,22.76 v1(106.27,22.72)
  BOTTOM w0.076: UCPU1.AK60 126.59,46.29 125.84,45.54 124.07,45.54 123.86,45.32 122.64,45.32 122.19,44.87 v1(122.19,44.79)
  BOTTOM w0.178: UD1.G2 106.66,22.34 v1(106.27,22.72)
DDR_A_D8: length 39.2
  IN4 w0.127: v4(102.66,27.12) 102.66,27.38 105.81,30.54 108.99,30.54 113.91,35.46 113.91,35.64 113.1,36.45 113.1,36.63 113.28,36.81 113.46,36.81 114.27,36 114.45,36 114.63,36.18 114.63,36.36 113.15,37.84 113.15,38.01 113.33,38.19 113.51,38.19 114.98,36.72 115.16,36.72 115.44,37 115.44,37.18 114.28,38.34 114.28,38.53 116.72,40.96 118.67,40.96 121.77,44.06 123.24,44.06 124.29,45.11 v4(124.83,45.11)
DDR_A_D9: length 39.1
  IN4 w0.127: v4(125.48,45.11) 125.16,45.43 124.29,45.43 123.27,44.4 121.37,44.4 118.41,41.44 116.12,41.44 112.03,37.34 112.03,37.07 113.24,35.85 113.24,35.49 113.06,35.31 112.88,35.31 111.52,36.66 111.34,36.66 111.16,36.48 111.16,36.3 112.52,34.95 112.52,34.77 108.72,30.97 105.5,30.97 102.28,27.75 102.28,26.74 v4(101.86,26.32)
DDR_A_D10: length 37.4
  IN4 w0.127: v4(124.83,43.75) 124.64,43.56 124.04,43.56 123.7,43.22 123.03,43.22 122.61,42.81 122.61,41.61 122.01,41 121.76,41 121.63,41.13 121.42,41.34 121.24,41.34 120.93,41.03 120.93,40.85 121.27,40.51 121.27,40.26 121.03,40.02 120.78,40.02 120.44,40.36 120.26,40.36 119.95,40.05 119.95,39.87 120.29,39.53 120.29,39.29 119.93,38.92 119.12,38.92 110.68,30.48 110.68,30.18 111.51,29.35 111.51,29.11 111.33,28.93 111.15,28.93 110.21,29.87 110.03,29.87 109.85,29.69 109.85,29.51 110.79,28.57 110.79,28.39 110.59,28.2 110.42,28.2 109.29,29.33 109.11,29.33 108.93,29.15 108.93,28.97 109.79,28.11 109.79,27.78 109.67,27.65 107.62,27.65 107.22,28.04 106.88,28.04 106.38,27.55 105.93,27.55 105.73,27.35 105.73,27.25 v4(105.86,27.12)
DDR_A_D11: length 36.5
  IN4 w0.127: v4(106.66,27.12) 106.68,27.14 107.53,27.14 107.72,27.33 110.18,27.33 112.06,29.21 112.06,29.39 111.14,30.31 111.14,30.49 111.32,30.67 111.5,30.67 112.42,29.75 112.6,29.75 112.78,29.93 112.78,30.11 111.86,31.03 111.86,31.21 112.04,31.39 112.22,31.39 113.14,30.47 113.31,30.47 113.49,30.65 113.49,30.83 112.58,31.75 112.58,31.93 112.76,32.11 112.94,32.11 113.85,31.19 114.03,31.19 114.21,31.37 114.21,31.54 113.61,32.14 113.61,32.61 114.31,33.31 114.31,33.58 119.17,38.44 119.96,38.44 123.22,41.7 123.22,42.76 123.4,42.93 123.87,42.93 124.23,43.3 125.03,43.3 v4(125.48,43.75)
DDR_A_D12: length 38.9
  IN4 w0.127: v4(126.13,45) 125.5,45.63 124.08,45.63 123.61,45.16 121.63,45.16 118.31,41.84 116.08,41.84 110.88,36.64 110.61,36.37 110.61,36.19 111.96,34.84 111.96,34.66 111.78,34.48 111.6,34.48 110.25,35.83 110.07,35.83 105.62,31.38 105.46,31.38 105.05,30.98 100.99,26.92 100.99,26.39 v4(101.86,25.52)
DDR_A_D13: length 41.1
  IN4 w0.127: v4(102.66,24.72) 102.64,24.74 101.78,24.74 101.68,24.64 101.68,24.12 101.55,23.99 101.25,23.99 101.12,24.12 101.12,24.63 100.99,24.76 100.29,24.76 100.07,24.98 100.07,27.55 100.92,28.41 101.98,28.41 105.28,31.7 105.49,31.7 116.01,42.22 118.15,42.22 121.43,45.49 123.62,45.49 123.97,45.84 125.94,45.84 v4(126.78,45)
DDR_A_D14: length 38.3
  IN4 w0.127: v4(126.13,43.75) 125.42,43.04 125.15,43.04 124.39,42.29 123.88,42.29 123.67,42.07 123.67,41.63 120.11,38.08 119.43,38.08 116.88,35.53 116.88,35.32 117.61,34.6 117.61,34.31 117.42,34.13 117.25,34.13 116.5,34.87 116.32,34.87 116.14,34.69 116.14,34.51 116.89,33.77 116.89,33.59 116.71,33.41 116.53,33.41 115.78,34.15 115.6,34.15 115.43,33.98 115.43,33.8 116.17,33.05 116.17,32.87 115.99,32.69 115.81,32.69 115.07,33.44 114.89,33.44 114.71,33.26 114.71,33.08 115.45,32.33 115.45,32.16 115.27,31.98 115.09,31.98 114.35,32.72 114.17,32.72 113.99,32.54 113.99,32.36 114.73,31.62 114.73,31.44 108.71,25.41 106.76,25.41 v4(106.66,25.52)
DDR_A_D15: length 39.3
  IN4 w0.127: v4(105.86,25.52) 106.32,25.06 108.8,25.06 118.13,34.39 118.13,34.57 117.35,35.36 117.35,35.54 117.53,35.72 117.7,35.72 118.49,34.93 118.67,34.93 118.85,35.11 118.85,35.29 118.06,36.08 118.06,36.26 118.24,36.44 118.42,36.44 119.21,35.65 119.39,35.65 119.57,35.83 119.57,36.01 118.78,36.8 118.78,36.98 118.96,37.16 119.14,37.16 119.93,36.37 120.11,36.37 120.29,36.55 120.29,36.73 119.62,37.4 119.62,37.58 119.8,37.76 119.98,37.76 120.65,37.09 120.83,37.09 121.01,37.27 121.01,37.47 120.61,37.86 120.61,38.07 125.26,42.71 125.73,42.71 v4(126.78,43.75)
DDR_A_D16: length 28.8
  IN1 w0.127: v1(127.61,44.32) 127.69,44.25 127.69,43.51 127.13,42.95 127.13,42.63 126.8,42.29 125.89,42.29 124.36,40.77 122.97,40.77 114.68,32.48 v1(114.68,23.51)
  BOTTOM w0.076: UCPU1.AP58 127.99,43.95 v1(127.61,44.32)
  BOTTOM w0.178: v1(114.68,23.51) 114.3,23.12 UD2.F7
DDR_A_D17: length 30.6
  IN1 w0.127: v1(127.31,43.8) 126.88,43.8 124.22,41.14 122.83,41.14 113.86,32.17 113.86,27.44 114.32,26.98 114.32,23.93 114.18,23.79 114.18,22.54 v1(114.76,21.96)
  BOTTOM w0.076: v1(127.31,43.8) 127.44,43.8 127.94,43.3 UCPU1.AR58
  BOTTOM w0.178: UD2.H7 114.32,21.52 v1(114.76,21.96)
DDR_A_D18: length 32
  IN1 w0.127: v1(116.97,24.32) 116.97,24.21 116.84,24.08 116.07,24.08 115.94,24.21 115.94,24.91 116.07,25.04 118.68,25.04 119.14,25.49 119.14,35.12 123.38,39.36 124.29,39.36 125.66,40.73 126.69,40.73 128.5,42.55 128.5,43.02 128.87,43.39 128.87,45.15 v1(128.47,45.55)
  BOTTOM w0.076: v1(128.47,45.55) 128.77,45.25 UCPU1.AM57
  BOTTOM w0.178: v1(116.97,24.32) 117.37,23.92 UD2.E3
DDR_A_D19: length 33
  IN1 w0.127: v1(116.77,21.68) 116.91,21.82 116.91,23.17 117.26,23.52 118.62,23.52 119.46,24.36 119.46,34.93 123.5,38.97 124.48,38.97 125.86,40.35 126.65,40.35 128.73,42.43 128.73,42.94 129.07,43.28 129.07,45.62 v1(128.48,46.22)
  BOTTOM w0.076: UCPU1.AK57 128.81,46.55 v1(128.48,46.22)
  BOTTOM w0.178: v1(116.77,21.68) 116.93,21.52 UD2.H3
DDR_A_D20: length 32
  IN1 w0.127: v1(113.81,21.93) 113.85,21.96 113.85,23.34 113.08,24.11 113.08,31.91 122.68,41.51 124.08,41.51 125.23,42.65 125.23,43.21 127.57,45.56 v1(127.62,45.56)
  BOTTOM w0.076: UCPU1.AL58 127.96,45.9 v1(127.62,45.56)
  BOTTOM w0.178: v1(113.81,21.93) 113.41,21.53 UD2.H8
DDR_A_D21: length 32.8
  IN1 w0.127: v1(113.03,22.72) 113.03,22.89 112.54,23.38 112.54,23.87 112.68,24.01 112.68,32.02 125.31,44.65 125.31,45 127.14,46.83 v1(128.5,46.83)
  BOTTOM w0.076: UCPU1.AK58 128.22,46.55 v1(128.5,46.83)
  BOTTOM w0.183: UD2.F8 113.41,23.1 v1(113.03,22.72)
DDR_A_D22: length 30.3
  IN1 w0.127: v1(117.81,22.72) 117.81,22.43 117.71,22.32 117.31,22.32 117.18,22.45 117.18,23.08 117.31,23.21 119.65,23.21 119.83,23.38 119.83,34.78 123.64,38.6 124.67,38.6 126.11,40.05 127.05,40.05 128.81,41.8 128.81,42.18 129.4,42.77 v1(129.4,43.06)
  BOTTOM w0.076: v1(129.4,43.06) 129.19,43.06 UCPU1.AR57
  BOTTOM w0.178: v1(117.81,22.72) 118.21,23.12 UD2.F2
DDR_A_D23: length 33.1
  IN1 w0.127: v1(129.44,45.43) 129.44,44.89 129.8,44.53 129.8,42.75 129.07,42.03 129.07,41.58 126.55,39.06 125.73,39.06 124.91,38.24 123.79,38.24 120.2,34.64 120.2,22.01 119.66,21.48 118.24,21.48 v1(117.81,21.91)
  BOTTOM w0.076: v1(129.44,45.43) 129.44,45.09 UCPU1.AN57
  BOTTOM w0.178: UD2.G2 118.21,22.32 v1(117.81,21.91)
DDR_A_D24: length 25.1
  IN4 w0.127: v4(129.37,43.96) 129.1,43.96 128.87,43.73 128.87,43.39 128.48,43 128.48,42.71 127.75,41.98 127.24,41.98 126.96,41.7 126.09,41.7 122.48,38.09 122.48,37.05 113.6,28.17 113.6,27.73 v4(114.21,27.12)
  BOTTOM w0.076: v4(129.37,43.96) 129.4,43.92 129.87,43.92 UCPU1.AP55
DDR_A_D25: length 25.6
  IN4 w0.127: v4(113.41,26.32) 113.41,26.33 113.82,26.73 114.57,26.73 114.81,26.98 114.81,28.87 122.9,36.96 122.9,37.94 125.81,40.85 126.5,40.85 127.36,41.71 127.85,41.71 128.69,42.55 128.69,42.9 129.34,43.55 v4(129.38,43.55)
  BOTTOM w0.076: UCPU1.AR55 129.67,43.53 129.4,43.53 v4(129.38,43.55)
DDR_A_D26: length 27.4
  IN4 w0.076: v4(130.85,45.25) 130.59,45.25 130.34,45 130.34,42.76 129.59,42.01 129.59,41.9
  IN4 w0.127: 129.59,41.9 128.06,40.36 127.89,40.36 127.1,39.58 127.1,37.44 126.71,37.05 126.71,36.71 126.29,36.29 125.66,36.29 116.5,27.13 116.5,26.48 117.12,25.86 117.87,25.86 v4(118.21,25.52)
DDR_A_D27: length 28.9
  IN4 w0.076: 129.42,42.1 129.52,42.21 129.57,42.21 130.19,42.83 130.19,46.26 130.48,46.55 v4(130.85,46.55)
  IN4 w0.127: v4(117.41,25.52) 117.21,25.31 116.49,25.31 116.14,25.66 116.14,27.28 125.71,36.85 125.71,37.15 126.79,38.23 126.79,39.77 127.69,40.67 127.98,40.67 129.42,42.1
DDR_A_D28: length 31.4
  IN4 w0.076: 128.12,42.82 128.12,46.93 128.36,47.17 128.64,47.17 129.01,46.8 129.01,46.16 129.28,45.89 129.89,45.89 v4(129.9,45.9)
  IN4 w0.127: 128.12,42.82 127.54,42.24 127.21,42.24 126.86,41.9 125.71,41.9 122.12,38.31 122.12,37.31 113.07,28.26 113.07,25.86 v4(113.41,25.52)
DDR_A_D29: length 32.6
  IN4 w0.076: v4(129.9,46.55) 129.55,46.55 128.77,47.32 128.29,47.32 127.96,46.99 127.96,43.89 127.77,43.7
  IN4 w0.127: v4(114.21,24.72) 113.76,25.18 113.27,25.18 112.72,25.74 112.72,28.36 121.62,37.27 121.62,38.34 125.47,42.2 126.67,42.2 127.09,42.63 127.09,43.02 127.77,43.7
DDR_A_D30: length 26.7
  IN4 w0.076: v4(130.85,43.3) 130.85,43.27 130.65,43.07 130.65,42.62 130.09,42.07 130.09,41.57 129.8,41.28
  IN4 w0.127: v4(117.41,27.12) 117.36,27.07 117.36,26.32 117.57,26.12 118.07,26.12 118.29,26.34 119.05,26.34 119.14,26.43 119.14,27.44 119.27,27.56 119.76,27.56 119.89,27.69 119.89,27.94 119.76,28.07 119.27,28.07 119.14,28.2 119.14,28.45 119.27,28.58 119.74,28.58 119.91,28.75 119.91,29.22 123.62,32.93 124.44,32.93 128.23,36.73 128.23,36.9 128.51,37.18 128.82,37.18 129,37.35 129,39.36 129.17,39.54 129.17,40.66 129.8,41.28
DDR_A_D31: length 27.3
  IN4 w0.076: v4(130.85,44.6) 130.7,44.6 130.5,44.39 130.5,42.69 129.92,42.12 129.92,41.81 129.26,41.15
  IN4 w0.127: v4(118.21,27.12) 117.92,27.12 117.71,27.33 117.71,27.62 123.87,33.78 124.05,33.78 124.35,33.48 124.53,33.48 124.71,33.66 124.71,33.84 124.41,34.14 124.41,34.32 124.59,34.5 124.77,34.5 125.07,34.2 125.25,34.2 125.43,34.38 125.43,34.56 125.13,34.86 125.13,35.04 125.31,35.22 125.49,35.22 125.79,34.92 125.97,34.92 126.15,35.1 126.15,35.28 125.83,35.6 125.83,35.78 126.02,35.97 126.2,35.97 126.43,35.74 126.65,35.74 126.99,36.08 127,36.08 127.63,36.71 127.63,37.02 128.12,37.52 128.12,40.01 129.26,41.15
DDR_A_D32: length 22.9
  IN1 w0.127: v1(127.64,39.52) 126.69,38.57 126.16,38.57 125.09,37.49 124.73,37.49 124.6,37.37 124.6,37.11 124.73,36.99 125.09,36.99 125.21,36.86 125.21,36.6 125.09,36.48 124.73,36.48 124.6,36.35 124.6,36.1 124.73,35.97 125.09,35.97 125.21,35.84 125.21,35.45 123.75,33.99 123.75,29.33 125.82,27.26 125.82,23.01 v1(126.11,22.72)
  BOTTOM w0.076: UCPU1.AY58 128.02,40.07 127.64,39.68 v1(127.64,39.52)
  BOTTOM w0.178: UD4.F8 126.5,23.1 v1(126.11,22.72)
DDR_A_D33: length 23.3
  IN1 w0.127: v1(126.9,21.94) 126.91,21.93 126.91,21.93 127.41,22.42 127.41,22.93 126.24,24.1 126.24,27.29 124.15,29.39 124.15,33.93 125.53,35.32 125.53,37.42 126.23,38.12 126.77,38.12 127.56,38.9 v1(127.64,38.9)
  BOTTOM w0.076: v1(127.64,38.9) 128.11,39.37 128.11,39.86 128.29,40.03 128.29,40.3 128.13,40.45 128.02,40.56 UCPU1.AW58
  BOTTOM w0.178: UD4.H8 126.5,21.54 v1(126.9,21.94)
DDR_A_D34: length 23
  IN1 w0.127: v1(129.37,38.21) 130.28,37.31 130.28,33.39 130.46,33.21 130.46,33.03 130.3,32.87 130.3,32.69 130.48,32.51 130.66,32.51 130.82,32.67 131,32.67 131.18,32.49 131.18,32.31 131.02,32.15 131.02,31.97 131.2,31.79 131.38,31.79 131.54,31.95 131.72,31.95 131.9,31.77 131.9,31.59 131.74,31.43 131.74,31.25 131.92,31.07 132.1,31.07 132.26,31.23 132.44,31.23 132.62,31.05 132.62,30.87 132.46,30.71 132.46,30.53 132.64,30.35 132.82,30.35 132.98,30.51 133.16,30.51 133.34,30.33 133.34,26.34 132.1,25.1 131.35,25.1 131.06,24.82 131.06,23.69 v1(130.9,23.52)
  BOTTOM w0.076: v1(129.37,38.21) UCPU1.AY56
  BOTTOM w0.178: v1(130.9,23.52) 131.3,23.13 UD4.F2
DDR_A_D35: length 23.7
  IN1 w0.127: v1(129.79,21.96) 129.82,21.96 130.47,22.61 130.47,23.84 130.63,24.01 130.63,25.21 130.88,25.46 131.99,25.46 133,26.46 133,29.54 129.92,32.62 129.92,37.06 v1(129.39,37.6)
  BOTTOM w0.076: UCPU1.AW56 129.4,40.84 129.64,40.59 129.64,39.92 129.54,39.81 129.54,38.6 129.76,38.38 129.76,37.98 129.39,37.6 v1(129.39,37.6)
  BOTTOM w0.178: UD4.H3 130.22,21.52 129.79,21.95 v1(129.79,21.96)
DDR_A_D36: length 23.5
  IN1 w0.127: v1(127.63,37.68) 127.41,37.68 126.7,36.96 126.7,35.59 124.97,33.86 124.97,30.69 126.94,28.72 126.94,25.47 128.23,24.18 128.23,22.42 v1(127.7,21.9)
  BOTTOM w0.076: UCPU1.AV58 128.02,41.35 128.3,41.07 128.3,40.51 128.44,40.37 128.44,39.96 128.27,39.79 128.27,39.18 128.11,39.03 128.11,38.15 v1(127.63,37.68)
  BOTTOM w0.178: v1(127.7,21.9) 127.33,21.52 UD4.H7
DDR_A_D37: length 24.2
  IN1 w0.127: v1(127.63,38.29) 127.56,38.29 126.96,37.7 126.3,37.7 125.85,37.24 125.85,35.19 124.62,33.95 124.62,30.6 124.91,30.3 124.91,30.12 124.48,29.68 124.48,29.51 124.66,29.33 124.84,29.33 125.27,29.76 125.45,29.76 126.55,28.67 126.55,25.37 127.69,24.22 127.69,23.54 v1(127.75,23.48)
  BOTTOM w0.076: v1(127.63,38.29) 127.22,38.7 127.22,39.65 127.47,39.89 127.58,39.89 127.73,40.04 127.73,41.84 UCPU1.AU58
  BOTTOM w0.178: UD4.F7 127.39,23.12 v1(127.75,23.48)
DDR_A_D38: length 24.6
  IN1 w0.127: v1(130.91,22.72) 130.94,22.69 131.3,22.69 131.77,23.15 131.77,23.33 131.63,23.47 131.63,23.64 131.81,23.82 131.99,23.82 132.13,23.69 132.31,23.69 132.49,23.87 133.46,23.87 133.66,24.07 133.66,24.8 133.53,24.93 133.19,24.93 133.06,25.06 133.06,25.31 133.19,25.44 133.53,25.44 133.66,25.57 133.66,30.46 130.65,33.47 130.65,38.78 v1(130.29,39.13)
  BOTTOM w0.076: UCPU1.AV56 129.81,40.94 129.81,39.61 v1(130.29,39.13)
  BOTTOM w0.178: UD4.G2 131.3,22.33 v1(130.91,22.72)
DDR_A_D39: length 26.2
  IN1 w0.127: v1(130.05,24.4) 129.57,24.87 129.57,31.92 129.58,31.93 129.58,32.66 129.45,32.78 128.53,32.78 128.4,32.91 128.4,33.49 128.53,33.62 129.48,33.62 129.61,33.75 129.61,34.08 129.48,34.21 128.81,34.21 128.68,34.33 128.68,34.59 128.81,34.72 129.48,34.72 129.61,34.84 129.61,35.1 129.48,35.22 128.77,35.22 128.64,35.35 128.64,35.6 128.77,35.73 129.48,35.73 129.61,35.86 129.61,36.11 129.48,36.24 129.16,36.24 129.04,36.37 129.04,36.62 129.16,36.75 129.48,36.75 129.61,36.87 129.61,37.09 129.48,37.22 129.12,37.22 129,37.35 129,38.51 130.18,39.69 v1(130.29,39.69)
  BOTTOM w0.076: UCPU1.AU56 129.27,42 130.05,41.21 130.05,39.93 v1(130.29,39.69)
  BOTTOM w0.178: UD4.E3 130.5,23.95 130.08,24.37 130.08,24.37 130.05,24.4 130.05,24.4 v1(130.05,24.4)
DDR_A_D40: length 16.5
  IN4 w0.076: v4(130.45,40.19) 130.11,40.19 129.92,40 129.92,38.93 130.42,38.43 130.42,36.76
  IN4 w0.127: v4(126.5,26.32) 126.5,26.33 126.9,26.73 127.51,26.73 127.75,26.98 127.75,27.65 130.14,30.04 130.14,36.48 130.42,36.76
DDR_A_D41: length 17.4
  IN4 w0.076: 130.19,36.92 130.19,38.36 129.72,38.83 129.72,40.33 130.23,40.84 v4(130.45,40.84)
  IN4 w0.127: v4(127.3,27.12) 126.9,27.52 126.9,28.08 127.58,28.76 127.82,28.76 127.99,28.59 128.23,28.59 128.48,28.83 128.48,29.08 128.31,29.25 128.31,29.49 128.55,29.74 128.8,29.74 128.97,29.57 129.21,29.57 129.46,29.81 129.46,30.06 129.29,30.22 129.29,30.47 129.77,30.95 129.77,36.5 130.19,36.92
DDR_A_D42: length 14.8
  IN4 w0.076: 132.44,39.25 131.8,39.88 v4(131.8,40.19)
  IN4 w0.127: v4(131.3,27.12) 131.24,27.17 131.24,27.89 132.52,29.17 132.52,31.92 133.63,33.03 133.63,34.3 133.03,34.91 133.03,37.44 132.44,38.03 132.44,39.25
DDR_A_D43: length 15.9
  IN4 w0.076: 132.16,38.95 132.16,39.3 131.45,40 131.45,40.63 131.66,40.84 v4(131.8,40.84)
  IN4 w0.127: 132.16,38.95 132.16,37.93 132.7,37.39 132.7,34.79 133.31,34.17 133.31,33.16 132.2,32.05 132.2,29.3 130.5,27.59 v4(130.5,27.12)
DDR_A_D44: length 19.6
  IN4 w0.076: v4(130.56,41.49) 130.56,41.38 129.56,40.38 129.56,38.78 129.97,38.36 129.97,37.07
  IN4 w0.127: v4(127.3,24.72) 126.9,25.12 126.9,25.73 126.74,25.9 126.42,25.9 126.09,26.23 126.09,27.78 129.39,31.09 129.39,36.49 129.97,37.07
DDR_A_D45: length 19.3
  IN4 w0.076: v4(130.56,42.14) 130.55,42.14 130.24,41.82 130.24,41.34 129.38,40.48 129.38,38.73 129.75,38.36 129.75,37.23 129.68,37.16
  IN4 w0.127: v4(126.5,25.52) 126.31,25.52 125.75,26.09 125.75,27.95 128.4,30.61 128.4,33.51 129.01,34.12 129.01,36.49 129.68,37.16
DDR_A_D46: length 19.5
  IN4 w0.076: v4(131.8,41.49) 131.69,41.49 131.58,41.37 131.58,41.01 131.3,40.74 131.3,39.94 131.88,39.36 131.88,38.85
  IN4 w0.127: 131.88,38.85 131.88,37.8 132.38,37.3 132.38,34.66 133,34.04 133,33.29 131.89,32.18 131.89,29.45 129.64,27.21 129.64,26.32 129.94,26.03 130.79,26.03 v4(131.3,25.52)
DDR_A_D47: length 19.8
  IN4 w0.076: 131.63,38.81 131.63,39.4 131.14,39.88 131.14,40.8 131.42,41.08 131.42,41.65 131.8,42.03 v4(131.8,42.14)
  IN4 w0.127: 131.63,38.81 131.63,37.56 131.99,37.19 131.99,34.53 132.64,33.88 132.64,33.45 131.52,32.33 131.52,29.62 129.31,27.41 129.31,26.05 129.76,25.61 130.41,25.61 v4(130.5,25.52)
DDR_A_D48: length 32.8
  IN1 w0.127: v1(138.96,46.9) 139.2,46.9 140.13,45.96 140.13,45.28 139.93,45.08 139.93,42.83 139.14,42.04 139.14,36.22 138.96,36.04 138.96,31.73 142.03,28.67 142.03,26.01 143.07,24.97 144.24,24.97 144.49,24.72 144.49,21.68 144.25,21.44 142.91,21.44 v1(142.45,21.91)
  BOTTOM w0.076: v1(138.96,46.9) 139.32,46.55 UCPU1.AK40
  BOTTOM w0.183: v1(142.45,21.91) 142.85,22.32 UD5.G2
DDR_A_D49: length 31.1
  IN1 w0.127: v1(138.93,46.23) 139.31,45.85 139.31,45.42 139.53,45.21 139.53,43.26 138.76,42.5 138.49,42.5 137.85,41.86 137.85,35.58 138.1,35.32 138.1,34.6 137.98,34.47 137.56,34.47 137.43,34.35 137.43,34.09 137.56,33.96 137.98,33.96 138.1,33.84 138.1,31.39 140.62,28.88 140.62,26.28 141.98,24.92 141.98,23.93 141.95,23.9 141.95,21.29 141.82,21.16 141.53,21.16 141.4,21.29 v1(141.4,21.68)
  BOTTOM w0.076: UCPU1.AK42 138.62,46.55 138.93,46.24 v1(138.93,46.23)
  BOTTOM w0.178: v1(141.4,21.68) 141.56,21.52 UD5.H3
DDR_A_D50: length 29
  IN1 w0.127: v1(137.99,44.95) 137.65,44.61 136.87,44.61 136.68,44.42 136.68,43.01 136.11,42.43 135.08,42.43 134.77,42.12 134.77,35.01 134.92,34.86 134.92,32.26 138.55,28.63 138.55,25.53 139.31,24.77 139.31,24.39 139.93,23.76 139.93,22.57 v1(139.26,21.9)
  BOTTOM w0.076: UCPU1.AM43 137.7,45.25 v1(137.99,44.95)
  BOTTOM w0.178: v1(139.26,21.9) 138.88,21.52 UD5.H7
DDR_A_D51: length 30.2
  IN1 w0.127: v1(137.04,45.51) 134.39,45.51 133.28,44.39 132.92,44.39 132.54,44.01 132.54,40.64 132.06,40.16 132.06,39.16 132.64,38.57 132.64,34.45 133.37,33.72 133.37,31.68 137.33,27.71 137.33,24.06 137.19,23.92 137.19,23.2 v1(137.67,22.72)
  BOTTOM w0.076: v1(137.04,45.51) 136.78,45.25 UCPU1.AM45
  BOTTOM w0.183: UD5.F8 138.05,23.1 v1(137.67,22.72)
DDR_A_D52: length 31.2
  IN1 w0.127: v1(137.01,46.21) 137.4,45.81 137.4,45.32 137.19,45.1 135.75,45.1 134.61,43.96 134.61,42.9 134.34,42.64 133.63,42.64 133.09,42.09 133.09,34.59 134.27,33.4 134.27,31.36 137.7,27.93 137.7,24.2 138.92,22.98 138.92,22.39 v1(138.44,21.92)
  BOTTOM w0.076: UCPU1.AK45 136.69,46.55 137.01,46.23 v1(137.01,46.21)
  BOTTOM w0.178: UD5.H8 138.05,21.53 v1(138.44,21.92)
DDR_A_D53: length 29.8
  IN1 w0.127: v1(139.32,23.51) 138.94,23.89 138.94,24.51 138.17,25.29 138.17,28.53 134.6,32.1 134.6,33.6 133.71,34.49 133.71,39.46 134.43,40.19 134.43,42.32 134.78,42.66 135.44,42.66 135.63,42.85 135.63,44.47 136.02,44.86 137.3,44.86 137.61,45.16 137.61,46.51 v1(137.99,46.9)
  BOTTOM w0.076: UCPU1.AK43 137.64,46.55 v1(137.99,46.9)
  BOTTOM w0.178: v1(139.32,23.51) 138.93,23.12 UD5.F7
DDR_A_D54: length 31.3
  IN1 w0.127: v1(142.45,22.72) 142.45,23.16 142.57,23.28 144.02,23.28 144.15,23.41 144.15,23.67 144.03,23.79 143.03,23.79 142.84,23.98 142.84,24.65 140.95,26.54 140.95,27.08 141.08,27.21 141.61,27.21 141.74,27.33 141.74,27.59 141.61,27.71 141.08,27.71 140.95,27.84 140.95,28.09 141.08,28.22 141.51,28.22 141.63,28.35 141.63,28.6 141.51,28.73 141.08,28.73 140.95,28.86 140.95,29.06 138.5,31.51 138.5,36.33 138.76,36.59 138.76,42.03 139.73,42.99 139.73,45.57 v1(139.73,45.58)
  BOTTOM w0.076: v1(139.73,45.58) 139.4,45.25 UCPU1.AM40
  BOTTOM w0.178: v1(142.45,22.72) 142.85,23.12 UD5.F2
DDR_A_D55: length 29.4
  IN1 w0.127: v1(138.93,45.58) 138.93,45.43 139.32,45.04 139.32,43.44 138.6,42.71 138.28,42.71 137.49,41.93 137.49,39.42 137.37,39.3 137.11,39.3 136.99,39.17 136.99,38.98 137.11,38.85 137.4,38.85 137.53,38.73 137.53,38.47 137.4,38.34 137.11,38.34 136.99,38.22 136.99,37.96 137.11,37.84 137.4,37.84 137.53,37.71 137.53,37.46 137.4,37.33 137.11,37.33 136.99,37.2 136.99,36.95 137.11,36.82 137.4,36.82 137.53,36.69 137.53,36.44 137.4,36.31 137.11,36.31 136.99,36.19 136.99,33.65 137.11,33.52 137.61,33.52 137.73,33.39 137.73,33.14 137.61,33.01 137.11,33.01 136.99,32.88 136.99,32 140.3,28.68 140.3,26.03 141.15,25.17 141.15,24.73 v1(141.56,24.32)
  BOTTOM w0.076: v1(138.93,45.58) 138.9,45.55 138.9,45.53 138.61,45.25 UCPU1.AM42
  BOTTOM w0.178: v1(141.56,24.32) 141.96,23.92 UD5.E3
DDR_A_D56: length 25.3
  IN4 w0.127: v4(142.85,25.52) 142.89,25.48 143.41,25.48 144.21,26.28 144.46,26.53 144.46,27.04 139.58,31.92 139.58,33.7 138.98,34.3 138.98,36.5 138.8,36.68 138.8,42.04 137.49,43.35 137.49,44.5 136.46,45.53 135.86,45.53 135.66,45.33 v4(135.66,45.25)
DDR_A_D57: length 29.6
  IN4 w0.127: v4(135.68,46.55) 136.4,47.27 138.15,47.27 138.43,46.98 138.43,42.78 139.05,42.16 139.05,36.97 139.33,36.68 139.33,34.59 139.96,33.97 139.96,31.99 144.71,27.23 144.71,26.42 143.47,25.18 142.39,25.18 v4(142.05,25.52)
DDR_A_D58: length 24.4
  IN4 w0.127: v4(133.7,45.25) 133.7,42.95 134.39,42.26 135.33,42.26 135.59,42 135.59,38.78 136.13,38.23 136.13,34.43 136.83,33.73 136.83,31.17 137.36,30.64 137.36,30.39 136.9,29.94 136.9,29.76 137.21,29.45 137.39,29.45 137.84,29.91 138.09,29.91 138.94,29.05 138.94,28.73 139.49,28.18 139.49,27.15 139.06,26.72 138.45,26.72 v4(138.05,26.32)
DDR_A_D59: length 24.5
  IN4 w0.127: v4(138.85,27.12) 138.36,27.61 138.36,27.62 138.04,27.94 138.04,28.19 138.58,28.72 138.58,28.9 138.27,29.21 138.09,29.21 137.55,28.68 137.31,28.68 136.46,29.52 136.46,33.58 135.77,34.28 135.77,37.8 134.78,38.79 134.78,41.57 133.75,42.6 133.16,42.6 132.72,43.04 132.72,44.73 133.24,45.25 133.24,45.9 133.73,46.39 v4(133.73,46.55)
DDR_A_D60: length 24.7
  IN4 w0.076: v4(134.6,45.25) 134.6,44.88 135.61,43.87 135.61,43.75
  IN4 w0.127: 135.61,43.75 135.61,43.01 136.22,42.4 136.77,42.4 137.14,42.03 137.14,39.31 137.52,38.93 137.52,36.41 138.26,35.67 138.26,33.76 138.69,33.32 138.69,31.18 138.87,31 139.05,31 139.23,31.18 139.41,31.18 139.59,31 139.59,30.82 139.41,30.64 139.41,30.47 139.59,30.29 139.77,30.29 139.95,30.47 140.13,30.47 140.31,30.28 140.31,30.11 140.13,29.93 140.13,29.75 141.09,28.79 141.09,28.42 141.21,28.3 141.77,28.3 141.9,28.17 141.9,27.92 141.77,27.79 141.21,27.79 141.09,27.66 141.09,27.38 141.21,27.26 141.93,27.26 142.05,27.13 v4(142.05,27.12)
DDR_A_D61: length 24.7
  IN4 w0.076: v4(134.63,46.55) 134.63,45.88 135.73,44.78 136.3,44.78 136.58,44.5
  IN4 w0.127: v4(142.85,27.12) 142.66,27.31 142.66,28.38 142.12,28.93 141.94,28.93 141.74,28.73 141.56,28.73 141.38,28.91 141.38,29.09 141.58,29.29 141.58,29.47 141.4,29.65 141.22,29.65 141.04,29.47 140.86,29.47 140.68,29.65 140.68,29.83 140.86,30.01 140.86,30.19 139.17,31.88 139.17,33.59 138.62,34.14 138.62,36 137.76,36.86 137.76,41.72 136.58,42.9 136.58,44.5
DDR_A_D62: length 24.3
  IN4 w0.127: v4(138.85,24.72) 138.47,25.1 138.47,25.77 138.32,25.92 137.94,25.92 137.65,26.22 137.65,27.82 136.1,29.37 136.1,33.43 135.4,34.13 135.4,37.57 134.64,38.33 134.17,38.33 133.87,38.62 133.87,39.28 133.95,39.36 133.95,42.09 133.72,42.32 133.04,42.32 132.34,43.02 132.34,44.88 v4(132.7,45.25)
DDR_A_D63: length 24.6
  IN4 w0.127: v4(132.72,46.55) 132.34,46.55 131.92,46.13 131.92,42.99 133.04,41.88 133.04,39.37 133.62,38.78 133.62,37.83 134.2,37.25 134.58,37.25 135.03,36.81 135.03,33.99 135.78,33.24 135.78,29.17 137.32,27.64 137.32,25.87 137.67,25.52 v4(138.05,25.52)
DDR_A_DQS0: length 38.7
  IN1 w0.165: v1(122.91,47.26) 122.85,47.2 121.9,47.2 120.28,45.57 120.28,44.23 104.49,28.45 104.49,24.09 105.13,23.45 105.13,22.85 104.97,22.69 104.84,22.69 104.79,22.75 104.77,22.75 104.55,22.96 v1(104.55,23)
  BOTTOM w0.076: UCPU1.AJ62 125.81,46.74 125.71,46.65 125.32,46.65 125.27,46.59 125.05,46.59 124.99,46.65 124.54,46.65 124.44,46.55 123.8,46.55 123.55,46.8 123.25,46.8 122.91,47.14 v1(122.91,47.26)
  BOTTOM w0.216: UD1.F3 105.86,23.03 105.65,22.82 104.73,22.82 v1(104.55,23)
DDR_A_DQS1: length 37.8
  IN4 w0.076: v4(126.46,44.43) 126.05,44.02 124.62,44.02 124.44,43.84 123.89,43.84 123.58,43.53 122.25,43.53 121.86,43.14 121.86,43.07 121.85,43.07
  IN4 w0.165: v4(102.66,25.52) 102.76,25.63 104.12,25.63 104.43,25.94 104.43,28.06 106.15,29.78 109.3,29.78 116.41,36.89 116.41,37.38 116.09,37.69 116.09,37.87 116.38,38.16 116.56,38.16 116.87,37.84 117.37,37.84 117.78,38.26 117.78,38.75 116.8,39.73 116.8,39.97 117.03,40.2 117.26,40.2 118.25,39.22 118.74,39.22 119.2,39.68 119.2,40.41 121.85,43.07
DDR_A_DQS2: length 31.8
  IN1 w0.102: v1(128.46,44.27) 128.4,44.27 128.13,44 128.13,43.36 128.29,43.21 128.29,42.66 127.34,41.71 126.26,41.71 126.22,41.68 126.21,41.68
  IN1 w0.165: 126.21,41.68 126.08,41.68 124.29,39.89 123.19,39.89 115.6,32.29 115.6,22.93 115.71,22.82 115.99,22.82 116.13,22.96 v1(116.13,23.18)
  BOTTOM w0.076: v1(128.46,44.27) 128.06,44.27 127.99,44.34 127.99,44.54 UCPU1.AN58
  BOTTOM w0.216: UD2.F3 117.37,23.12 117.27,23.03 117.27,22.77 117.17,22.66 116.53,22.66 116.35,22.85 116.23,22.85 116.13,22.95 v1(116.13,23.18)
DDR_A_DQS3: length 28.2
  IN4 w0.076: v4(129.9,44.6) 129.9,44.71 129.79,44.81 129.61,44.81 129.53,44.74 129.53,44.52 129.98,44.07 129.98,42.84 129.55,42.4 129.28,42.4 129.03,42.15 129.03,42.09
  IN4 w0.165: v4(114.21,25.52) 115.01,25.52 115.67,26.18 115.67,27.5 123.09,34.92 123.09,35.41 123.04,35.47 123.04,35.7 123.39,36.06 123.62,36.06 123.68,36 124.17,36 125.03,36.86 125.03,39.02 126.13,40.12 126.69,40.12 127.6,41.03 127.97,41.03 129.03,42.09
DDR_A_DQS4: length 25.2
  IN1 w0.102: 127.88,36.68 127.88,36.69 127.92,36.72 127.92,36.79 127.99,36.87 127.99,38.23 128.18,38.43 128.18,38.57 v1(128.6,38.99)
  IN1 w0.165: v1(129.07,22.91) 129.26,22.73 129.45,22.73 129.7,22.98 129.7,23.61 128.75,24.56 128.75,27.55 125.42,30.88 125.42,33.62 127.88,36.08 127.88,36.68
  BOTTOM w0.076: UCPU1.AW57 128.78,41.24 128.86,41.24 128.94,41.16 128.94,40.67 128.97,40.63 128.97,40.4 128.93,40.36 128.93,39.89 129.04,39.77 129.04,38.77 128.88,38.61 128.82,38.61 128.73,38.7 128.68,38.7 128.6,38.78 v1(128.6,38.99)
  BOTTOM w0.216: v1(129.07,22.91) 129.17,22.81 130.12,22.81 130.14,22.8 130.33,22.8 130.47,22.94 130.47,23.1 UD4.F3
DDR_A_DQS5: length 17.8
  IN4 w0.076: 131.01,38.43 130.98,38.46 130.98,39.02 130.86,39.13 130.86,39.86 130.97,39.96 130.97,41 v4(131.13,41.16)
  IN4 w0.165: 131.01,38.43 131.01,29.8 128.99,27.78 128.99,26.46 128.3,25.77 127.54,25.77 v4(127.3,25.52)
DDR_A_DQS6: length 30.6
  IN1 w0.076: 135.96,41.72 135.96,41.73 136,41.78 136,41.83 136.01,41.84 136.01,42.01 136.57,42.56 137.55,42.56 138.35,43.37 138.35,45.78 138.29,45.85 138.12,45.85 138,45.72 v1(138,45.56)
  IN1 w0.165: v1(140.74,23) 140.94,22.81 141.09,22.81 141.23,22.95 141.23,23.39 140.37,24.25 140.37,24.95 139,26.32 139,27.14 139.51,27.65 139.51,28.38 136.15,31.74 136.15,39.04 135.96,39.22 135.96,41.72
  BOTTOM w0.076: v1(138,45.56) 138,45.71 138.19,45.9 UCPU1.AL42
  BOTTOM w0.216: UD5.F3 141.62,22.69 141.4,22.69 141.27,22.82 140.92,22.82 v1(140.74,23)
DDR_A_DQS7: length 25
  IN4 w0.076: v4(134.18,45.66) 134.26,45.57 134.26,45 134.75,44.51 134.75,42.95 134.98,42.73 135.54,42.73 136.2,42.06 136.2,41.55 136.24,41.51
  IN4 w0.165: v4(138.85,25.52) 139.84,25.52 140.64,26.32 140.64,28.61 138.24,31 138.24,32.86 137.69,33.42 137.69,34 137.08,34.61 137.08,38.54 136.24,39.37 136.24,41.51
  BOTTOM w0.076: UCPU1.AL49 133.94,45.9 v4(134.18,45.66)
DDR_A_DQS#0: length 38.9
  IN1 w0.165: v1(122.91,46.6) 122.62,46.89 122.03,46.89 120.59,45.44 120.59,44.1 104.8,28.32 104.8,24.22 105.44,23.58 105.44,22.72 105.1,22.38 104.56,22.38 v1(104.55,22.37)
  BOTTOM w0.076: v1(122.91,46.6) 122.95,46.65 123.48,46.65 123.74,46.39 124.5,46.39 124.6,46.49 124.93,46.49 124.98,46.43 125.33,46.43 125.39,46.49 125.89,46.49 126.26,46.86 UCPU1.AJ61
  BOTTOM w0.216: v1(104.55,22.37) 104.66,22.48 105.7,22.48 UD1.G3
DDR_A_DQS#1: length 38
  IN4 w0.076: 121.63,43.28 121.65,43.3 121.71,43.3 122.16,43.75 123.49,43.75 123.8,44.06 124.35,44.06 124.53,44.24 125.79,44.24 125.85,44.3 125.85,44.39 v4(125.81,44.43)
  IN4 w0.165: 121.63,43.28 118.89,40.54 118.89,39.81 118.61,39.53 118.38,39.53 117.39,40.51 116.9,40.51 116.49,40.1 116.49,39.61 117.47,38.62 117.47,38.39 117.24,38.15 117,38.15 116.69,38.47 116.25,38.47 115.78,38 115.78,37.56 116.1,37.25 116.1,37.01 109.17,30.09 106.02,30.09 104.12,28.18 104.12,26.06 103.99,25.94 102.45,25.94 102.34,26.05 102.34,26.21 102.45,26.32 v4(102.66,26.32)
DDR_A_DQS#2: length 32
  IN1 w0.102: v1(128.46,44.94) 128.08,44.56 128.08,44.29 127.89,44.1 127.89,43.26 128.04,43.11 128.04,42.76 127.23,41.96 126.26,41.96 126.22,41.99 126.21,41.99
  IN1 w0.165: 126.21,41.99 125.95,41.99 124.16,40.2 123.07,40.2 115.29,32.42 115.29,22.8 115.58,22.51 115.99,22.51 116.13,22.37 v1(116.13,22.37)
  BOTTOM w0.076: UCPU1.AM58 128.05,45.25 128.35,44.94 v1(128.46,44.94)
  BOTTOM w0.216: UD2.G3 116.18,22.32 v1(116.13,22.37)
DDR_A_DQS#3: length 28.4
  IN4 w0.076: 128.81,42.31 128.82,42.32 128.88,42.32 129.19,42.62 129.45,42.62 129.76,42.93 129.76,43.98 129.31,44.43 129.31,44.83 129.52,45.03 129.8,45.03 129.9,45.13 v4(129.9,45.25)
  IN4 w0.165: 128.81,42.31 127.84,41.34 127.47,41.34 126.56,40.43 126,40.43 124.72,39.14 124.72,36.99 124.04,36.31 123.81,36.31 123.75,36.37 123.26,36.37 122.73,35.83 122.73,35.34 122.78,35.29 122.78,35.05 115.36,27.63 115.36,26.31 114.88,25.83 114.62,25.83 114.21,26.24 v4(114.21,26.32)
DDR_A_DQS#4: length 25.4
  IN1 w0.102: v1(128.57,38.34) 128.44,38.34 128.23,38.13 128.23,36.72 128.19,36.68
  IN1 w0.165: v1(129.07,22.28) 129.21,22.42 129.58,22.42 130.01,22.85 130.01,23.74 129.06,24.69 129.06,27.68 125.73,31 125.73,33.49 128.19,35.95 128.19,36.68
  BOTTOM w0.076: UCPU1.AV57 128.7,41.62 129.09,41.22 129.09,40.73 129.13,40.7 129.13,40.34 129.08,40.29 129.08,39.95 129.2,39.84 129.2,38.71 128.95,38.46 128.69,38.46 v1(128.57,38.34)
  BOTTOM w0.216: v1(129.07,22.28) 129.27,22.47 129.98,22.47 130,22.46 130.36,22.46 UD4.G3
DDR_A_DQS#5: length 18
  IN4 w0.076: 130.7,38.43 130.7,38.44 130.74,38.49 130.74,38.54 130.76,38.56 130.76,38.93 130.64,39.04 130.64,39.95 130.74,40.05 130.74,41.17 131.13,41.56 v4(131.13,41.81)
  IN4 w0.165: v4(127.3,26.32) 127.54,26.08 128.17,26.08 128.68,26.58 128.68,27.91 130.7,29.92 130.7,38.43
DDR_A_DQS#6: length 30.9
  IN1 w0.076: 136.27,41.72 136.27,41.75 136.23,41.78 136.23,41.91 136.66,42.34 137.64,42.34 138.57,43.28 138.57,45.88 138.38,46.07 138.15,46.07 v1(138,46.22)
  IN1 w0.165: 136.27,41.72 136.27,39.35 136.46,39.17 136.46,31.87 139.82,28.51 139.82,27.52 139.31,27.02 139.31,26.44 140.68,25.07 140.68,24.38 141.54,23.51 141.54,22.82 141.22,22.5 140.87,22.5 v1(140.74,22.37)
  BOTTOM w0.076: UCPU1.AL43 137.67,45.9 v1(138,46.22)
  BOTTOM w0.216: UD5.G3 141.28,22.32 141.13,22.48 140.86,22.48 v1(140.74,22.37)
DDR_A_DQS#7: length 25.4
  IN4 w0.076: v4(134.17,46.07) 133.86,45.76 133.86,45.52 134.04,45.34 134.04,44.91 134.53,44.42 134.53,42.86 134.89,42.51 135.45,42.51 135.98,41.97 135.98,41.62 135.98,41.62 135.98,41.56 135.93,41.52 135.93,41.51
  IN4 w0.165: v4(138.85,26.32) 138.85,26.04 139.06,25.83 139.71,25.83 140.33,26.44 140.33,28.48 137.93,30.87 137.93,32.74 137.38,33.29 137.38,33.87 136.77,34.48 136.77,38.41 135.93,39.25 135.93,41.51
  BOTTOM w0.076: v4(134.17,46.07) 134.33,45.9 UCPU1.AL48
DDR_A_MA0: length 125.1
  TOP w0.076: v1(124.2,13.86) 124.2,14.19 RD29.1
  IN1 w0.076: v3(135.03,15.14) 135.03,14.94 135.4,14.56 135.4,14.49 135.33,14.42 134.94,14.42 134.8,14.56 134.75,14.56 134.68,14.63 134.68,14.81 134.55,14.94 134.47,14.94 134.06,15.35 134.06,15.65 134.01,15.7 133.75,15.7 133.45,15.4 132.03,15.4 130.65,14.01 124.35,14.01 v1(124.2,13.86) 124.04,13.71 122.09,13.71 121.5,14.3 117.46,14.3 117.06,14.7 111.67,14.7 111.12,15.25 110.5,15.25 v3(110.39,15.14)
  IN3 w0.076: 143.93,36.27 143.53,36.68 143.53,37.87 142.98,38.42 142.78,38.42 142.14,39.06 142.14,41.96 142.01,42.09 141.59,42.09 141.46,41.96 v1(141.46,41.84)
  IN3 w0.191: v1(124.2,13.86) 124.2,13.46 124.58,13.08 124.58,11.64 124.7,11.51 126.46,11.51 126.58,11.64 126.58,12.4 126.46,12.53 125.45,12.53 125.33,12.65 125.33,13.88 125.45,14.01 126.8,14.01 126.93,14.14 126.93,14.61 126.8,14.74 124.53,14.74 124.34,14.93 124.34,16.54 123.52,17.36 123.52,20.69 124.27,21.45 124.27,23.02 125.14,23.88 125.58,23.88 125.78,24.08 125.78,28.41 126.27,28.9 133.81,28.9 134.2,29.29 143.64,29.29 143.93,29.57 143.93,36.27
  IN4 w0.076: v4(129.11,16.12) 129.11,16.17 129.53,16.59 129.94,16.59 130.31,16.22 130.42,16.22 130.72,15.91 131.49,15.91 132,15.41 133.96,15.41 134.33,15.04 134.93,15.04 v3(135.03,15.14) 135.21,15.32 135.97,15.32 136.43,14.86 137.99,14.86 138.57,15.44 139.83,15.44 141.91,17.52 v4(142.05,17.52) ; v4(104.66,16.11) 104.66,16.31 104.93,16.58 106.12,16.58 106.78,15.91 106.86,15.91 107.39,15.38 108.73,15.38 108.87,15.24 109.38,15.24 109.61,15.01 110.26,15.01 v3(110.39,15.14) 110.52,15.27 111.2,15.27 111.63,14.84 113.39,14.84 113.95,15.4 115.66,15.4 116.03,15.76 v4(116.03,16.12)
  BOTTOM w0.076: UD1.N3 105.76,17.52 104.66,16.43 v4(104.66,16.11) ; v1(141.46,41.84) 141.61,41.84 UCPU1.AU36 ; v4(129.11,16.12) 129.11,16.21 130.42,17.52 UD4.N3 ; v4(116.03,16.12) 116.03,16.55 116.41,16.93 116.79,16.93 117.38,17.52 UD2.N3
DDR_A_MA1: length 128.5
  TOP w0.076: v1(123.07,14.16) 123.24,14.34 123.24,15.23 RD37.1
  IN1 w0.076: v3(109.86,15.44) 109.79,15.37 109.58,15.37 109.41,15.54 109.41,15.68 109.65,15.92 110.1,15.92 110.47,15.55 111.12,15.55 111.76,14.9 117.22,14.9 117.61,14.51 120.33,14.51 120.39,14.57 121.87,14.57 121.92,14.52 121.92,14.25 122.2,13.97 122.91,13.97 123.07,14.13 v1(123.07,14.16) 123.49,14.59 124.23,14.59 124.59,14.23 130.57,14.23 131.94,15.6 133.37,15.6 133.67,15.9 135.05,15.9 135.2,15.75 136.2,15.75 136.29,15.66 136.29,15.54 136.2,15.46 135.38,15.46 135.31,15.54 134.62,15.54 v3(134.53,15.44)
  IN3 w0.076: 143.53,36.31 143.34,36.5 143.34,37.85 142.92,38.27 142.71,38.27 142.33,38.66 142.11,38.66 141.96,38.8 141.96,39.59 141.84,39.72 141.77,39.72 141.65,39.84 141.65,40.02 141.77,40.15 141.84,40.15 141.96,40.28 141.96,40.71 141.86,40.81 141.59,40.81 141.46,40.68 v1(141.46,40.51)
  IN3 w0.191: 143.53,36.31 143.53,29.9 143.31,29.68 137.13,29.68 137,29.81 137,30.18 136.87,30.31 136.44,30.31 136.31,30.18 136.31,29.84 136.18,29.71 135.74,29.71 135.62,29.84 135.62,30.19 135.49,30.32 135.05,30.32 134.93,30.19 134.93,29.84 134.8,29.71 134.36,29.71 134.24,29.84 134.24,30.19 134.11,30.32 133.67,30.32 133.55,30.19 133.55,29.47 133.42,29.34 132.98,29.34 132.85,29.47 132.85,30.19 132.73,30.32 132.29,30.32 132.16,30.19 132.16,29.42 132.04,29.29 131.6,29.29 131.47,29.42 131.47,30.19 131.35,30.32 130.91,30.32 130.78,30.19 130.78,29.48 130.65,29.35 130.22,29.35 130.09,29.48 130.09,30.19 129.96,30.32 129.53,30.32 129.4,30.19 129.4,29.42 129.27,29.29 128.84,29.29 128.71,29.42 128.71,30.19 128.58,30.32 128.15,30.32 128.02,30.19 128.02,29.42 127.89,29.29 127.46,29.29 127.33,29.42 127.33,30.18 127.21,30.31 126.77,30.31 126.65,30.18 126.65,29.7 126.52,29.57 124.91,29.57 124.79,29.44 124.79,28.97 124.89,28.87 125.2,28.87 125.33,28.74 125.33,28.19 125.2,28.06 124.89,28.06 124.69,27.86 124.69,23.97 123.87,23.16 123.87,21.49 123.18,20.81 123.18,17.15 123.98,16.35 123.98,15.1 123.07,14.19 v1(123.07,14.16)
  IN4 w0.076: v4(140.03,16.12) 140.03,16.07 139.65,15.69 138.41,15.69 137.82,15.1 136.57,15.1 136.13,15.54 135.19,15.54 135.17,15.56 134.65,15.56 v3(134.53,15.44) 134.31,15.44 134.09,15.66 132.13,15.66 131.6,16.18 130.83,16.18 130.53,16.49 130.36,16.49 130.03,16.82 129.17,16.82 v4(128.48,16.12) ; v4(102.66,16.72) 102.81,16.87 106.12,16.87 106.81,16.18 106.97,16.18 107.56,15.59 108.81,15.59 108.96,15.45 109.85,15.45 v3(109.86,15.44) 109.95,15.54 111.31,15.54 111.76,15.09 113.35,15.09 113.88,15.62 115.49,15.62 115.55,15.69 115.55,15.97 v4(115.39,16.12)
  BOTTOM w0.076: v4(140.03,16.12) 140.03,16.52 139.84,16.72 UD5.P7 ; UD4.P7 127.87,16.72 v4(128.48,16.12) ; v4(115.39,16.12) 115.39,16.42 115.1,16.72 UD2.P7 ; UCPU1.AY37 140.9,40.05 140.9,39.72 140.95,39.67 141.39,39.67 141.46,39.73 v1(141.46,40.51)
DDR_A_MA2: length 136.5
  TOP w0.076: RD35.1 117.53,13.11 v1(117.53,12.96)
  IN1 w0.076: v3(135.03,13.74) 134.73,13.44 133.89,13.44 133.63,13.69 132.64,13.69 131.68,12.73 128.03,12.73 127.42,12.12 126.55,12.12 126.03,12.64 122.12,12.64 121.77,12.28 121.21,12.28 120.76,12.74 118.96,12.74 118.49,13.21 117.78,13.21 v1(117.53,12.96) 117.47,13.02 117.47,13.21 117.39,13.29 117.22,13.29 117.1,13.16 117.1,12.78 116.97,12.65 116.77,12.65 116.64,12.78 116.64,13.16 116.54,13.26 116.05,13.26 115.57,13.74 111.42,13.74 111.33,13.83 110.98,13.83 110.45,13.31 108.89,13.31 108.48,13.73 108.46,13.73 108.33,13.86 106.31,13.86 106.19,13.98 106.19,14.19 106.31,14.32 108.65,14.32 108.78,14.19 108.78,13.9 109.13,13.54 110.13,13.54 v3(110.37,13.78)
  IN3 w0.076: 131.49,42.27 132.63,42.27 132.96,42.6 137.24,42.6 137.68,43.05 140.15,43.05 v1(140.3,43.2)
  IN3 w0.191: 131.49,42.27 131.49,42.28 124.76,42.28 124.59,42.1 120.33,42.1 110.35,32.12 110.35,23.98 110.91,23.42 110.91,20.28 112.7,18.49 113.79,18.49 114.22,18.06 114.22,13.55 114.62,13.15 117.34,13.15 v1(117.53,12.96)
  IN4 w0.076: v4(104.61,14.7) 104.61,14.94 104.88,15.21 105.89,15.21 107.33,13.77 108.78,13.77 108.99,13.55 110.14,13.55 v3(110.37,13.78) 110.42,13.84 115.45,13.84 115.98,14.37 v4(115.98,14.75) ; v4(142.05,16.72) 142.22,16.89 142.29,16.89 142.37,16.82 142.37,16.53 142.1,16.26 141.81,16.26 141.12,15.57 141.01,15.57 140.9,15.68 140.79,15.68 140.68,15.57 140.68,15.47 140.79,15.36 140.79,15.25 140.64,15.1 140.64,14.88 139.56,13.8 136.13,13.8 135.85,14.07 135.36,14.07 v3(135.03,13.74) 134.86,13.74 134.61,13.49 134.15,13.49 133.94,13.7 132.2,13.7 131.05,14.85 130.2,14.85 129.88,15.17 129.48,15.17 v4(129.06,14.75)
  BOTTOM w0.076: v4(104.61,14.7) 104.61,15.03 105.52,15.94 105.52,16.39 UD1.P3 ; UD2.P3 117.41,16.44 117.08,16.1 117.08,15.95 116.72,15.59 115.76,15.59 115.64,15.46 115.64,14.87 115.76,14.75 v4(115.98,14.75) ; UD4.P3 130.5,16.4 130.16,16.06 130.16,15.91 129.06,14.81 v4(129.06,14.75) ; UCPU1.AR38 140.4,43.3 v1(140.3,43.2)
DDR_A_MA3: length 132.1
  TOP w0.076: v1(126.63,13.55) 126.6,13.55 125.77,14.38 RD41.1
  IN1 w0.076: v3(135.6,14.92) 137.91,14.92 138.04,14.8 138.04,14.34 137.91,14.21 134.79,14.21 133.83,15.18 132.12,15.18 130.5,13.55 v1(126.63,13.55) 124.51,13.55 124.4,13.44 121.97,13.44 121.33,14.09 117.38,14.09 116.99,14.48 111.59,14.48 111.22,14.85 v3(110.95,14.85)
  IN3 w0.076: 146.95,35.98 146.95,40.16 144.68,42.43 144.68,44.28 144.35,44.61 143.93,44.61 143.56,44.24 v1(142.31,44.24)
  IN3 w0.191: v1(126.63,13.55) 127.2,13.55 127.33,13.68 127.33,15.43 127.45,15.55 130.03,15.55 130.15,15.43 130.15,14.01 130.28,13.88 130.62,13.88 130.75,14.01 130.75,16.15 130.88,16.27 131.27,16.27 131.4,16.15 131.4,14.34 131.52,14.21 131.9,14.21 132.03,14.34 132.03,16.18 132.15,16.31 132.64,16.31 132.76,16.18 132.76,15.68 132.89,15.55 133.56,15.55 133.95,15.94 134.85,15.94 135.13,15.66 136.2,15.66 137.15,16.61 142.09,16.61 143.05,17.58 144.59,17.58 145.64,16.53 146.45,16.53 147.14,17.21 147.14,35.8 146.95,35.98
  IN4 w0.076: v4(129.75,16.16) 129.95,15.95 130.27,15.95 130.57,15.65 131.38,15.65 131.85,15.18 133.89,15.18 134.25,14.82 134.6,14.82 134.7,14.72 135.4,14.72 v3(135.6,14.92) 136.05,14.92 136.4,14.57 138.08,14.57 138.69,15.18 139.98,15.18 141.98,17.17 142.5,17.17 v4(142.85,17.52) ; v4(105.11,16.12) 106.28,16.12 106.75,15.65 106.75,15.65 107.22,15.17 108.65,15.17 108.78,15.04 109.29,15.04 109.53,14.8 110.19,14.8 110.29,14.7 110.8,14.7 v3(110.95,14.85) 111.05,14.75 111.35,14.75 111.52,14.57 113.42,14.57 114.03,15.18 115.85,15.18 116.66,15.99 v4(116.66,16.12)
  BOTTOM w0.076: v4(105.11,16.12) 105.11,16.47 105.74,17.11 106.24,17.11 UD1.N2 ; UD4.N2 130.88,17.11 130.4,17.11 129.74,16.45 129.74,16.16 129.75,16.16 v4(129.75,16.16) ; v4(129.75,16.16) 129.74,16.16 v4(129.75,16.16) ; UD2.N2 117.8,17.11 117.3,17.11 116.66,16.47 v4(116.66,16.12) ; UCPU1.AP36 142.02,43.95 v1(142.31,44.24)
DDR_A_MA4: length 129.2
  TOP w0.076: RD33.1 122.06,15.15 122.27,14.95 v1(122.35,14.95)
  IN1 w0.076: v3(108.56,16.11) 108.93,16.48 109.87,16.48 110.6,15.75 111.2,15.75 111.84,15.1 117.35,15.1 117.73,14.72 120.17,14.72 120.31,14.86 122.26,14.86 v1(122.35,14.95) 122.44,14.86 122.79,14.86 122.87,14.78 122.87,14.63 122.95,14.56 123.1,14.56 123.18,14.63 123.18,14.78 123.25,14.86 124.58,14.86 124.63,14.81 124.63,14.7 124.75,14.58 124.75,14.49 124.74,14.48 124.79,14.43 124.98,14.43 125.05,14.51 125.05,14.58 125.13,14.66 125.28,14.66 125.36,14.58 125.36,14.51 125.43,14.43 125.59,14.43 125.66,14.51 125.66,14.58 125.74,14.66 125.89,14.66 125.97,14.58 125.97,14.51 126.04,14.43 126.2,14.43 126.27,14.51 126.27,14.58 126.35,14.66 126.5,14.66 126.58,14.58 126.58,14.51 126.65,14.43 126.81,14.43 126.88,14.51 126.88,14.58 126.96,14.66 127.11,14.66 127.19,14.58 127.19,14.51 127.26,14.43 127.42,14.43 127.49,14.51 127.49,14.58 127.57,14.66 127.72,14.66 127.8,14.58 127.8,14.51 127.87,14.43 128.01,14.43 128.08,14.51 128.08,14.57 128.16,14.65 128.31,14.65 128.39,14.57 128.39,14.51 128.47,14.43 128.62,14.43 128.69,14.51 128.69,14.57 128.77,14.65 128.92,14.65 129,14.57 129,14.51 129.08,14.43 129.23,14.43 129.3,14.51 129.3,14.57 129.38,14.65 129.53,14.65 129.61,14.57 129.61,14.51 129.68,14.43 129.84,14.43 129.91,14.51 129.91,14.57 129.99,14.65 130.14,14.65 130.22,14.57 130.22,14.51 130.29,14.43 130.42,14.43 131.85,15.86 132.04,15.86 132.13,15.95 132.13,16.14 132.22,16.23 132.37,16.23 132.45,16.16 132.45,15.88 132.53,15.8 132.68,15.8 132.76,15.88 132.76,16.16 132.83,16.23 133.06,16.23 v3(133.23,16.07)
  IN3 w0.191: v1(139.88,41.84) 139.88,41.86 140.01,41.99 140.41,41.99 140.54,41.86 140.54,41.47 140.34,41.27 140.34,40.86 140.54,40.66 140.54,37.57 140.24,37.27 140.19,37.27 139.95,37.03 139.47,37.03 139.17,36.73 139.17,36.25 139.03,36.11 137.68,36.11 137.56,36.24 137.56,36.82 137.43,36.95 137.11,36.95 136.99,36.82 136.99,35.6 136.86,35.47 136.54,35.47 136.41,35.6 136.41,36.64 136.29,36.77 136,36.77 135.87,36.64 135.87,36.43 135.75,36.3 135.44,36.3 135.31,36.17 135.31,35.83 135.44,35.7 135.75,35.7 135.87,35.58 135.87,35.22 135.75,35.09 134.86,35.09 134.64,34.88 133.9,34.88 133.57,35.21 133.04,35.21 132.74,34.9 131.53,34.9 131.37,35.06 126.23,35.06 125.07,36.21 125.07,36.97 124.42,37.62 121.98,37.62 116.83,32.47 116.83,31.91 116.64,31.72 116.2,31.72 116,31.53 116,31.15 116.2,30.96 116.64,30.96 116.83,30.77 116.83,30.72 117.08,30.47 117.08,29.07 117.55,28.6 118.42,28.6 118.43,28.62 119.48,28.62 119.61,28.49 119.61,25.09 120.96,23.74 120.96,21.86 121.76,21.06 121.76,16.77 121.39,16.4 121.39,15.16 121.53,15.03 121.53,14.97 121.7,14.8 122.2,14.8 v1(122.35,14.95)
  IN4 w0.076: v4(127.82,16.12) 127.82,16.14 128.77,17.08 130.14,17.08 130.47,16.75 130.64,16.75 130.94,16.45 131.71,16.45 132.18,15.98 132.69,15.98 132.82,16.12 133.17,16.12 v3(133.23,16.07) 133.23,16.09 133.33,15.98 134.14,15.98 134.29,15.84 135.26,15.84 135.36,15.74 136.14,15.74 136.38,15.98 139.23,15.98 v4(139.37,16.12) ; v4(101.86,16.72) 101.86,16.88 102.06,17.08 103.45,17.08 103.58,17.21 103.58,17.55 103.7,17.68 103.81,17.68 103.92,17.57 103.92,17.21 104.05,17.08 106.21,17.08 106.8,16.49 108.19,16.49 v3(108.56,16.11) 108.58,16.11 109.05,15.65 109.49,15.65 109.68,15.84 110.29,15.84 110.37,15.76 111.78,15.76 111.98,15.97 113.31,15.97 113.44,15.83 113.61,15.83 113.75,15.97 114.58,15.97 v4(114.74,16.12)
  BOTTOM w0.076: UD4.P8 126.49,16.72 126.28,16.72 126.19,16.63 126.19,16.4 126.27,16.32 127.62,16.32 v4(127.82,16.12) ; v4(139.37,16.12) 139.17,16.32 137.86,16.32 137.76,16.42 137.76,16.59 137.84,16.67 138,16.67 UD5.P8 ; UD2.P8 113.34,16.72 113.21,16.59 113.21,16.45 113.34,16.32 114.54,16.32 v4(114.74,16.12) ; v1(139.88,41.84) 139.76,41.96 139.76,42.2 139.89,42.33 140.21,42.33 140.34,42.2 UCPU1.AU39
DDR_A_MA5: length 139.5
  TOP w0.076: v1(119.12,11.5) 118.03,11.5 RD47.1
  IN1 w0.076: v3(134.12,12.3) 133.95,12.13 133.95,12.11 132.88,11.04 126.01,11.04 125.54,11.51 124.61,11.51 124.06,10.96 120.49,10.96 120.35,11.1 120.02,11.1 119.71,11.41 119.21,11.41 v1(119.12,11.5) 118.95,11.33 118.95,11.24 118.82,11.12 118.55,11.12 118.43,11.24 118.43,11.48 118.34,11.57 118.21,11.57 118.12,11.48 118.12,11.41 118.04,11.33 117.89,11.33 117.82,11.41 117.82,11.48 117.73,11.57 117.6,11.57 117.51,11.48 117.51,11.43 117.41,11.32 117.25,11.32 117.15,11.43 117.15,11.52 117.1,11.57 114.75,11.57 114.68,11.64 114.68,12.21 114.4,12.49 113.78,12.49 113.71,12.41 113.71,11.65 113.63,11.57 113.48,11.57 113.4,11.65 113.4,12.41 113.32,12.49 113.17,12.49 113.1,12.41 113.1,11.65 113.02,11.57 112.87,11.57 112.79,11.65 112.79,12.41 112.71,12.49 112.56,12.49 112.49,12.41 112.49,12.07 112.45,12.03 112.23,12.03 112.18,12.08 112.18,12.41 112.11,12.49 109.91,12.49 v3(109.72,12.3)
  IN3 w0.076: 133,42.33 133.12,42.45 137.35,42.45 137.72,42.82 141.1,42.82 v1(141.38,43.1)
  IN3 w0.191: 133,42.33 132.66,42 125,42 124.71,41.71 120.5,41.71 110.75,31.96 110.75,25.05 110.97,24.83 110.97,23.81 111.22,23.56 111.22,21.17 112.43,19.96 112.76,19.96 116.87,15.86 116.87,14.98 118.09,13.76 118.58,13.27 118.58,12.81 118.95,12.44 118.95,11.66 v1(119.12,11.5)
  IN4 w0.076: v4(142.85,16.72) 142.41,16.28 142.41,15.83 142.02,15.44 141.92,15.44 141.27,14.78 141.27,13.77 139.97,12.47 138.74,12.47 138.74,12.47 134.29,12.47 v3(134.12,12.3) 134.12,12.09 133.75,11.73 133.24,11.73 132.56,12.41 131.83,12.41 130.54,13.7 129.44,13.7 128.86,13.11 v4(128.86,13.1) ; v4(104.44,12.99) 104.44,13 105.03,13.58 105.79,13.58 107.51,11.87 109.29,11.87 v3(109.72,12.3) 109.77,12.35 115.28,12.35 v4(116.03,13.1)
  BOTTOM w0.076: v1(141.38,43.1) 141.58,43.3 UCPU1.AR36 ; v4(116.03,13.1) 117.05,14.11 117.05,15.2 117.4,15.55 117.45,15.55 117.79,15.89 117.79,16.3 UD2.P2 ; UD1.P2 106.32,16.39 106.32,15.91 105.93,15.52 105.78,15.52 105.49,15.23 105.49,14.38 104.44,13.33 v4(104.44,12.99) ; UD4.P2 130.87,16.3 130.87,15.82 130.63,15.58 130.48,15.58 130.13,15.23 130.13,14.47 128.86,13.2 v4(128.86,13.1)
DDR_A_MA6: length 129.3
  TOP w0.076: RD39.1 121.67,13.58 v1(121.28,13.58)
  IN1 w0.076: v3(109.12,14.65) 109.15,14.62 109.5,14.62 109.58,14.7 109.58,14.95 109.67,15.04 109.84,15.04 109.93,14.95 109.93,14.82 110.06,14.7 110.48,14.7 110.57,14.61 110.57,14.49 110.67,14.39 111.39,14.39 111.5,14.28 116.9,14.28 117.3,13.88 120.98,13.88 v1(121.28,13.58) 121.44,13.58 121.85,13.17 126.25,13.17 126.77,12.65 127.17,12.65 127.78,13.26 131.38,13.26 132.34,14.23 133.3,14.23 v3(133.76,14.68)
  IN3 w0.076: v1(139.87,38.51) 139.61,38.51 139.49,38.64 139.49,39.03 139.36,39.16 138.98,39.16 138.85,39.03 138.85,38.15 138.73,38.03 136.63,38.03 136.2,37.6
  IN3 w0.191: v1(121.28,13.58) 121.35,13.58 120.98,13.95 120.76,13.95 120.41,14.3 120.41,16.77 120.77,17.13 120.77,20.5 119.89,21.37 119.89,23.17 119.77,23.3 119.05,23.3 118.93,23.42 118.93,23.65 118.74,23.83 118.21,23.83 118.09,23.71 118.09,23.35 117.96,23.22 117.39,23.22 117.26,23.35 117.26,23.64 117.14,23.77 116.84,23.77 115.71,24.9 115.71,27.99 115.59,28.12 114.39,28.12 114.26,28.25 114.26,28.63 114.39,28.76 115.37,28.76 115.5,28.88 115.5,29.25 115.37,29.38 114.12,29.38 113.93,29.57 113.93,30.74 114.06,30.86 114.46,30.86 114.58,30.99 114.58,31.28 114.36,31.5 114.36,31.68 121.52,38.84 125.53,38.84 126.76,37.61 126.76,36.26 126.89,36.13 127.54,36.13 127.66,36.26 127.66,36.86 127.79,36.99 128.11,36.99 128.23,36.86 128.23,36.26 128.36,36.13 129.21,36.13 129.24,36.16 130.04,36.16 130.17,36.29 130.17,36.96 130.29,37.09 134.65,37.09 134.78,37.21 134.98,37.21 135.36,37.6 136.2,37.6
  IN4 w0.076: v4(127.79,14.77) 128.65,15.64 130.2,15.64 130.46,15.38 131.27,15.38 132.35,14.3 133.38,14.3 v3(133.76,14.68) 133.92,14.52 136.16,14.52 136.38,14.3 138.5,14.3 138.59,14.39 138.59,14.72 138.71,14.85 138.81,14.85 138.92,14.75 138.92,14.42 139.03,14.3 139.19,14.3 139.35,14.45 v4(139.35,14.73) ; v4(101.86,15.92) 101.86,16.15 101.98,16.27 103.37,16.27 103.5,16.15 103.5,15.81 103.62,15.69 106.32,15.69 107.69,14.32 108.8,14.32 v3(109.12,14.65) 109.21,14.56 110.1,14.56 110.21,14.45 111.24,14.45 111.36,14.33 113.48,14.33 113.7,14.54 113.88,14.54 113.97,14.46 113.97,14.39 114.06,14.3 114.19,14.3 114.28,14.39 114.28,14.84 114.4,14.97 114.58,14.97 114.71,14.84 v4(114.71,14.75)
  BOTTOM w0.076: v4(114.71,14.75) 114.71,15.23 114.47,15.48 113.54,15.48 113.42,15.6 113.42,15.92 UD2.R8 ; v1(139.87,38.51) 139.49,38.51 139.19,38.8 139.19,41.22 UCPU1.AV40 ; v4(127.79,14.77) 127.79,15.12 127.42,15.48 127.03,15.48 126.59,15.92 UD4.R8 ; UD5.R8 138.08,15.92 138.52,15.48 138.98,15.48 139.35,15.11 v4(139.35,14.73)
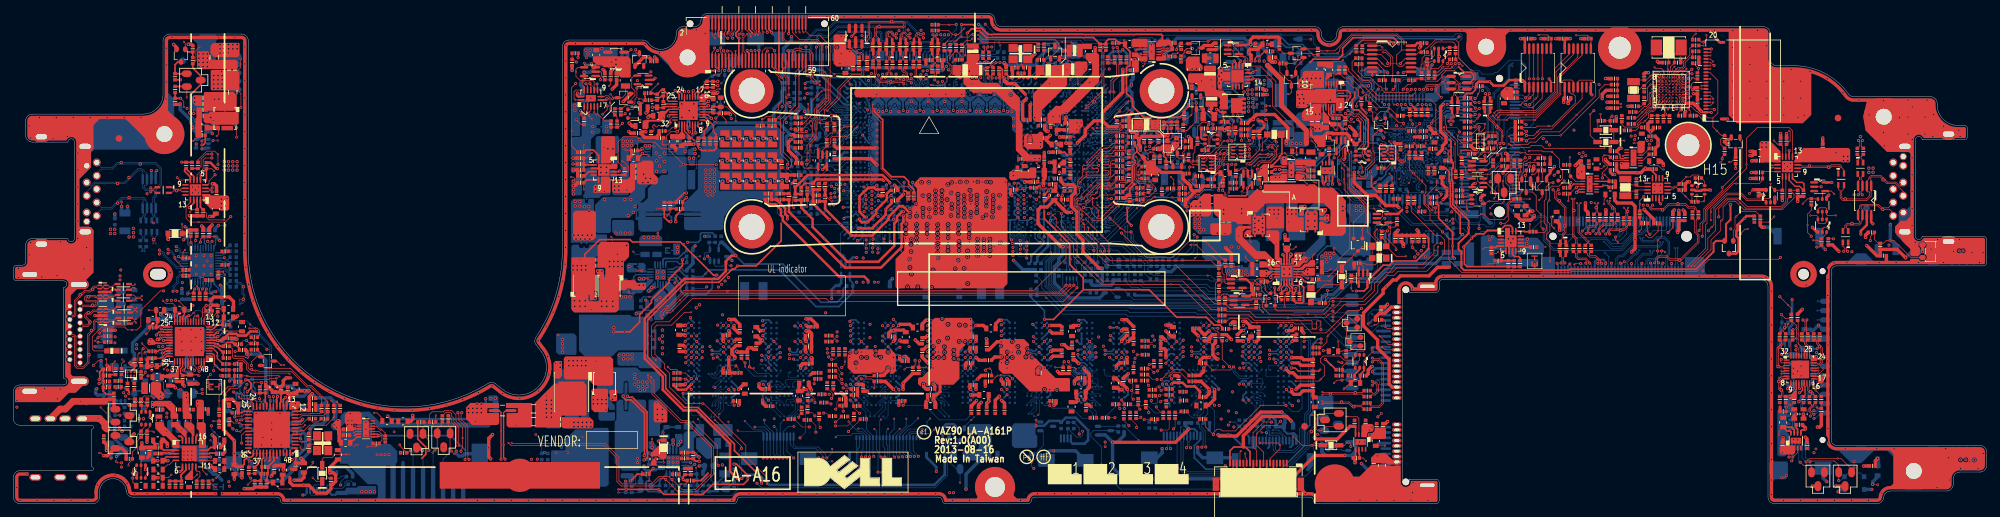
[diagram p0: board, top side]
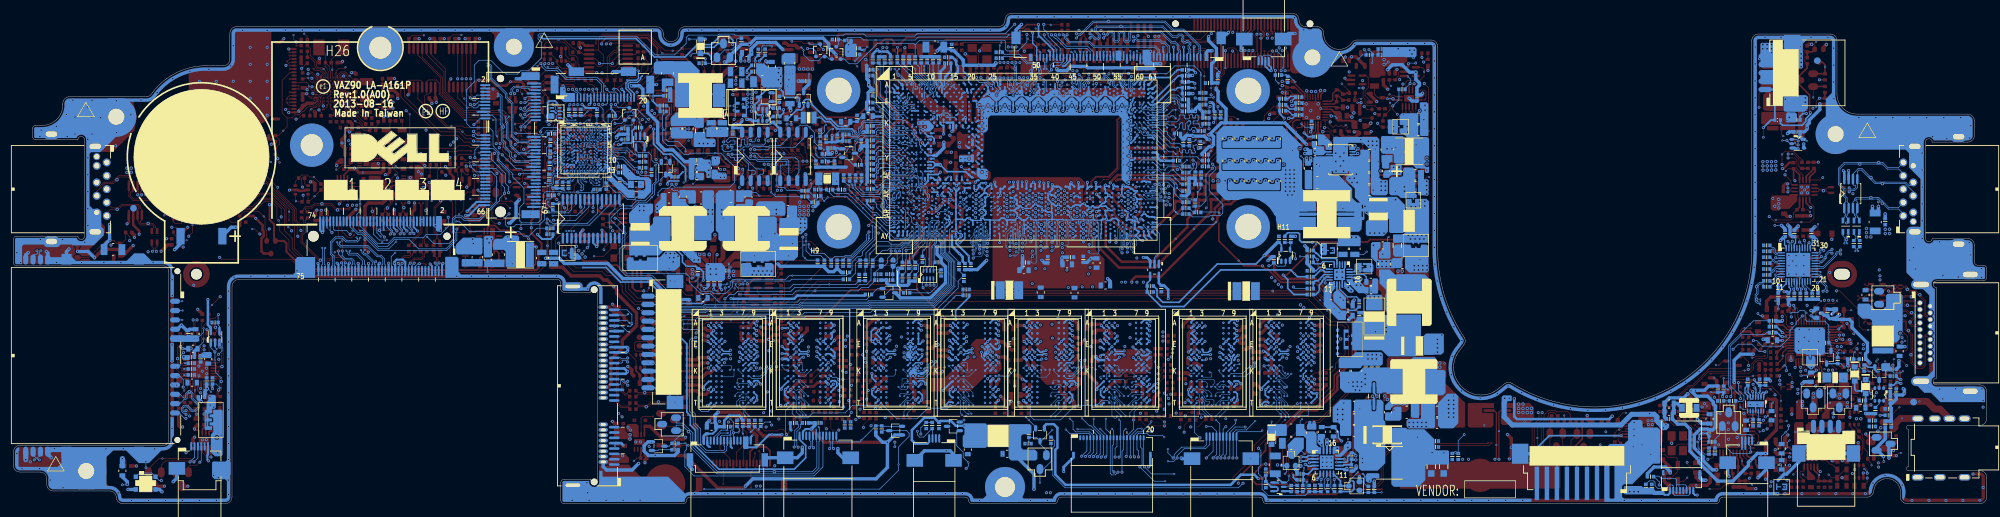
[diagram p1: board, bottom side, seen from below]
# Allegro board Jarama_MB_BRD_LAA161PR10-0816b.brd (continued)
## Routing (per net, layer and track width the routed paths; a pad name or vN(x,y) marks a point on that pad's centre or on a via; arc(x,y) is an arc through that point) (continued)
DDR_A_MA7: length 135.7
  TOP w0.076: RD51.1 126.73,12.57 v1(124.97,10.81)
  IN1 w0.076: v3(136.12,11.26) 136.12,10.6 135.98,10.46 135.68,10.46 135.6,10.53 135.6,11.23 135.5,11.33 135.36,11.33 135.26,11.23 135.26,10.59 135.13,10.46 125.37,10.46 125.02,10.81 v1(124.97,10.81) 124.75,10.81 124.23,10.29 115.78,10.29 115.03,11.04 112.4,11.04 111.71,11.73 111.57,11.73 v3(111.41,11.56)
  IN3 w0.076: 138.16,36.46 138.51,36.46 139.6,37.56 140.03,37.56 140.26,37.79 140.26,40.14 v1(139.88,40.52)
  IN3 w0.191: v1(124.97,10.81) 124.86,10.7 123.73,10.7 123.6,10.83 123.6,11.57 123.73,11.7 124.02,11.7 124.15,11.83 124.15,12.83 123.68,13.3 122.75,13.3 121.07,14.98 121.07,16.53 121.43,16.89 121.43,20.84 120.61,21.66 120.61,23.57 119.18,25.01 119.18,28.03 119.05,28.16 117.01,28.16 116.63,28.54 116.63,29.94 116.37,30.19 115.85,30.19 115.5,30.55 115.5,31.7 121.84,38.04 124.42,38.04 125.44,37.03 125.44,36.41 126.39,35.45 131.54,35.45 132.02,35.93 133.11,35.93 134.48,35.93 135.09,36.54 135.22,36.54 135.72,37.04 136.5,37.04 136.69,37.23 137.66,37.23 137.98,36.91 137.98,36.64 138.16,36.46
  IN4 w0.076: v4(130.18,13.07) 132.17,11.08 135.94,11.08 v3(136.12,11.26) 136.59,11.73 140.23,11.73 142.52,14.01 142.52,14.18 142.6,14.25 142.91,14.25 143,14.34 143,14.47 142.91,14.56 142.4,14.56 142.31,14.65 142.31,14.77 142.4,14.86 142.73,14.86 142.85,14.99 v4(142.85,15.92) ; v4(116.94,13.06) 116.94,12.67 115.85,11.57 111.42,11.57 v3(111.41,11.56) 111.41,11.34 111.04,10.98 107.5,10.98 105.55,12.92 v4(105.55,12.99)
  BOTTOM w0.076: UD4.R2 131.34,15.88 131.34,15.69 130.9,15.26 130.9,13.21 130.5,12.81 130.32,12.81 130.18,12.95 v4(130.18,13.07) ; v4(116.94,13.06) 116.94,13.12 117.25,13.43 117.69,13.43 117.82,13.55 117.82,15.32 117.95,15.45 118.23,15.45 118.35,15.57 118.35,15.79 118.23,15.92 UD2.R2 ; v4(105.55,12.99) 105.55,13.31 v2(105.66,13.42) 106.26,14.02 106.26,15.42 106.66,15.82 UD1.R2 ; UCPU1.AW39 140.2,40.84 v1(139.88,40.52)
DDR_A_MA8: length 133.4
  TOP w0.076: RD53.1 124.84,11.66 v1(123.03,11.66)
  IN1 w0.076: v3(132.95,13.02) 132.48,12.55 132.48,11.98 132.09,11.59 130.23,11.59 130.15,11.66 130.15,12.11 130.07,12.18 129.92,12.18 129.85,12.11 129.85,11.66 129.77,11.59 129.62,11.59 129.54,11.66 129.54,12.11 129.46,12.18 129.31,12.18 129.24,12.11 129.24,11.66 129.16,11.59 129.01,11.59 128.93,11.66 128.93,12.11 128.85,12.18 128.7,12.18 128.63,12.11 128.63,11.66 128.55,11.59 128.4,11.59 128.32,11.66 128.32,11.95 128.27,12 128.08,12 128.02,11.94 128.02,11.66 127.94,11.59 126.33,11.59 125.82,12.09 124.38,12.09 123.98,11.7 123.07,11.7 v1(123.03,11.66) 122.92,11.55 121.2,11.55 120.53,12.21 118.55,12.21 118.45,12.11 115.62,12.11 114.69,13.04 108.12,13.04 v3(108.07,13.1)
  IN3 w0.076: v1(139.89,39.84) 139.46,39.41 139.21,39.41 139.13,39.49 139.13,39.89 139.05,39.97 138.93,39.97 138.85,39.89 138.85,39.54 138.73,39.41 138.22,39.41 137.7,38.89 136.3,38.89 135.77,38.36 134.1,38.36 133.76,38.7 133.76,39.11 133.57,39.3 133.16,39.3 132.97,39.49 132.97,40.05 132.81,40.2
  IN3 w0.191: v1(123.03,11.66) 123.03,11.33 122.77,11.08 121.96,11.08 121.72,11.32 121.72,12.09 121.62,12.2 121.6,12.2 120.84,12.95 120.84,13.4 120.03,14.21 120,14.21 119.59,14.62 119.09,14.62 118.16,15.55 118.16,19.21 117.31,20.07 117.31,20.42 117.18,20.54 115.73,20.54 115.26,21.02 115.26,23.6 114.32,24.54 114.32,24.73 113,26.04 113,27.9 112.56,28.34 112.56,31.55 121.09,40.07 125.78,40.07 126.03,40.31 129.59,40.31 129.84,40.55 132.43,40.55 132.78,40.2 132.81,40.2
  IN4 w0.076: v4(114.76,13.07) 114.71,13.02 108.14,13.02 v3(108.07,13.1) 107.93,13.24 106.89,13.24 105.9,14.23 104.2,14.23 v4(102.96,12.99) ; v4(139.4,13.07) 139.34,13.01 134.89,13.01 134.84,12.96 133.9,12.96 133.71,13.15 133.07,13.15 v3(132.95,13.02) 132.92,12.99 132.02,12.99 130.76,14.25 127.61,14.25 127.49,14.13 127.49,13.17 v4(127.59,13.07)
  BOTTOM w0.076: v4(127.59,13.07) 127.59,13.76 126.5,14.85 UD4.T8 ; v4(114.76,13.07) 114.73,13.07 113.41,14.39 UD2.T8 ; UD5.T8 138.05,14.39 139.37,13.07 v4(139.4,13.07) ; UCPU1.AY39 140.24,40.19 v1(139.89,39.84) ; v4(102.96,12.99) 102.79,13.17 101.65,13.17 101.53,13.29 101.53,14.79 UD1.T8
DDR_A_MA9: length 127.2
  TOP w0.076: v1(123.03,12.24) 123.11,12.24 RD43.1
  IN1 w0.076: v3(136.16,13.4) 135.7,12.94 133.98,12.94 133.5,13.42 132.78,13.42 131.83,12.46 128.14,12.46 127.53,11.85 126.44,11.85 125.92,12.37 123.64,12.37 123.51,12.24 v1(123.03,12.24) 122.92,12.35 122.27,12.35 121.94,12.02 121.1,12.02 120.65,12.47 118.44,12.47 118.34,12.37 116.56,12.37 116.34,12.6 116.23,12.6 116.11,12.48 116,12.48 115.89,12.58 115.89,12.69 116.02,12.81 116.02,12.92 115.91,13.03 115.8,13.03 115.68,12.91 115.57,12.91 115.46,13.02 115.46,13.12 115.58,13.24 115.58,13.35 115.5,13.44 v3(111.14,13.44)
  IN3 w0.076: 138.03,37.25 138.56,37.25 139.17,37.86 139.84,37.86 v1(139.88,37.9)
  IN3 w0.191: v1(123.03,12.24) 123.12,12.16 123.5,12.16 123.62,12.28 123.62,12.84 123.5,12.97 122.61,12.97 120.74,14.84 120.74,16.65 121.1,17.01 121.1,20.71 120.28,21.52 120.28,23.31 118.72,24.87 116.28,24.87 116.16,25 116.16,25.38 116.28,25.5 116.64,25.5 116.77,25.63 116.77,26.04 116.64,26.17 116.31,26.17 116.18,26.29 116.18,29.66 116.06,29.78 114.66,29.78 114.48,29.96 114.48,30.33 114.61,30.46 114.96,30.46 115.09,30.58 115.09,31.85 121.69,38.45 125.38,38.45 125.8,38.02 125.8,36.68 126.63,35.84 130.15,35.84 131.04,36.73 133.44,36.73 133.57,36.6 133.57,36.38 133.7,36.26 134.29,36.26 134.92,36.88 135.12,36.88 135.55,37.32 136.39,37.32 136.78,37.71 137.57,37.71 138.03,37.25
  IN4 w0.076: v4(105.06,14.73) 105.98,14.73 107.21,13.5 108.63,13.5 108.84,13.29 110.99,13.29 v3(111.14,13.44) 111.23,13.53 115.62,13.53 116.61,14.52 v4(116.61,14.73) ; v4(142.05,15.92) 141.75,15.92 140.99,15.16 140.99,14.93 140.71,14.65 140.71,13.58 140.63,13.51 140.41,13.51 140.33,13.58 140.33,13.88 140.26,13.96 140.11,13.96 140.03,13.88 140.03,13.58 139.95,13.51 139.7,13.51 136.27,13.51 v3(136.16,13.4) 136.03,13.27 134.78,13.27 134.73,13.22 134.04,13.22 133.84,13.43 131.97,13.43 130.94,14.46 129.97,14.46 v4(129.7,14.73)
  BOTTOM w0.076: v4(116.61,14.73) 116.32,15.03 116.32,15.29 116.37,15.34 116.82,15.34 116.88,15.4 116.89,15.4 UD2.R3 ; v4(105.06,14.73) 105.06,15.1 105.86,15.9 UD1.R3 ; v4(129.7,14.73) 129.7,15.12 130.5,15.92 UD4.R3 ; UCPU1.AU40 139.41,41.93 139.04,41.56 139.04,38.74 v1(139.88,37.9)
DDR_A_MA10: length 129.2
  TOP w0.076: RD31.1 v2(124.45,21.29) 124.45,20.9 v1(123.97,20.42)
  IN1 w0.076: v3(109.18,20.28) 109.2,20.3 109.78,20.3 109.97,20.11 110.79,20.11 111.6,19.29 114.58,19.29 114.85,19.03 118.74,19.03 119.56,19.85 123.41,19.85 v1(123.97,20.42) 124.5,20.42 125.59,19.32 130.16,19.32 130.5,19.66 134.15,19.66 134.59,20.1 135.02,20.1 135.4,19.73 135.58,19.73 135.85,20 135.85,20.18 135.28,20.75 134.96,20.75 134.87,20.84 134.01,20.84 133.89,20.72 v3(133.89,20.25)
  IN3 w0.076: v1(142.32,43.6) 142.32,43.62 142.44,43.74 142.78,43.74 142.9,43.62 142.9,42.2 142.78,42.07 142.42,42.07 142.29,41.95 142.29,39.12 142.84,38.57 143.04,38.57 143.68,37.94 143.68,36.85 144.33,36.2
  IN3 w0.191: v1(123.97,20.42) 123.97,20.64 124.71,21.38 124.71,22.97 125.26,23.52 126.14,23.52 126.23,23.61 126.23,25.22 126.36,25.35 128.97,25.35 129.1,25.47 129.1,26.1 128.97,26.23 126.36,26.23 126.23,26.36 126.23,26.79 126.36,26.91 127.24,26.91 127.37,27.04 127.37,27.38 127.24,27.51 126.5,27.51 126.37,27.63 126.37,27.64 126.23,27.78 126.23,28.21 126.52,28.5 127.78,28.5 127.9,28.38 127.9,27.47 128.03,27.34 129.04,27.34 129.17,27.47 129.17,28.31 129.37,28.5 134.37,28.5 134.52,28.35 134.52,26.75 134.65,26.62 135.41,26.62 135.54,26.75 135.54,28.76 135.66,28.89 139.6,28.89 139.73,28.76 139.73,28.34 139.6,28.22 138.27,28.22 138.14,28.09 138.14,26.61 138.27,26.48 139.21,26.48 139.33,26.61 139.33,27.24 139.46,27.37 140.17,27.37 140.3,27.5 140.3,28.6 140.59,28.89 143.98,28.89 144.33,29.24 144.33,36.2
  IN4 w0.076: v4(114.84,19.97) 114.47,19.97 114.12,19.62 111.29,19.62 110.8,20.11 109.96,20.11 109.77,20.3 109.2,20.3 v3(109.18,20.28) 108.82,19.92 105.97,19.92 105.26,20.63 104.16,20.63 v4(102.66,19.12) ; v4(128.04,20.06) 128.66,20.67 129.92,20.67 130.67,19.92 133.56,19.92 v3(133.89,20.25) 134.14,20.5 134.52,20.5 134.93,20.09 135.53,20.09 135.93,19.69 138.74,19.69 139.15,20.11 v4(139.58,20.11)
  BOTTOM w0.076: UD5.L7 138.85,19.15 139.58,19.88 v4(139.58,20.11) ; UD4.L7 127.31,19.12 128.04,19.85 v4(128.04,20.06) ; UCPU1.AP35 142.66,43.95 v1(142.32,43.6) ; v4(114.84,19.97) 114.84,19.79 114.21,19.17 UD2.L7
DDR_A_MA11: length 126.6
  TOP w0.076: RD45.1 119.47,13.68 119.94,13.21 v1(119.94,13.16)
  IN1 w0.076: v3(133.84,14.1) 133.7,13.96 132.49,13.96 131.52,13 127.92,13 127.31,12.39 126.66,12.39 126.14,12.91 121.95,12.91 121.61,12.56 121.31,12.56 120.71,13.16 v1(119.94,13.16) 120.23,13.45 120.23,13.51 120.13,13.61 119.17,13.61 119.04,13.48 119.04,13.43 118.91,13.3 118.78,13.3 118.65,13.43 118.65,13.48 118.52,13.61 118.28,13.61 118.15,13.48 117.95,13.48 117.82,13.61 117.2,13.61 117.11,13.7 117,13.7 116.8,13.49 116.69,13.49 116.58,13.6 116.58,13.71 116.78,13.91 116.78,14.02 116.73,14.07 116.34,14.07 116.27,14 116.27,13.76 116.19,13.68 116.04,13.68 115.96,13.76 115.96,14 115.88,14.07 111.33,14.07 111.28,14.13 110.79,14.13 110.73,14.07 110.63,14.07 110.52,14.18 110.19,14.18 110.09,14.28 110.09,14.4 109.97,14.52 109.73,14.52 109.56,14.34 109.45,14.34 v3(109.17,14.06)
  IN3 w0.076: 133.23,41.38 133.39,41.55 133.9,41.55 133.98,41.62 134.66,41.62 134.79,41.49 134.79,38.93 134.92,38.8 135.41,38.8 135.53,38.93 135.53,39.27 135.66,39.39 137,39.39 137.12,39.52 137.12,40.71 137.25,40.83 138.18,40.83 138.31,40.71 v1(138.31,40.5)
  IN3 w0.191: 133.23,41.38 127.23,41.38 127.1,41.25 127.1,41.03 126.98,40.9 120.8,40.9 111.64,31.74 111.64,24.06 111.77,23.93 112.42,23.93 112.56,23.79 112.56,23.5 112.49,23.43 111.99,23.43 111.86,23.3 111.86,22.88 111.99,22.75 112.44,22.75 112.56,22.62 112.56,21.74 112.85,21.45 113.59,21.45 113.98,21.06 113.98,20.25 115.13,19.09 115.57,19.09 115.7,18.96 115.7,18.33 115.83,18.2 116.23,18.2 116.36,18.33 116.36,19.26 116.49,19.38 116.89,19.38 117.02,19.26 117.02,18.49 117.15,18.37 117.38,18.37 117.5,18.24 117.5,15.24 119.13,13.62 119.59,13.62 119.94,13.26 v1(119.94,13.16)
  IN4 w0.076: v4(128.43,14.75) 129.1,15.42 130.01,15.42 130.31,15.11 131.16,15.11 132.23,14.05 133.78,14.05 v3(133.84,14.1) 134.05,14.32 135.98,14.32 136.24,14.06 139.3,14.06 v4(139.98,14.75) ; v4(102.66,15.92) 102.56,15.92 102.43,15.79 102.43,15.52 102.5,15.45 106.27,15.45 107.66,14.05 109.16,14.05 v3(109.17,14.06) 109.47,14.35 109.99,14.35 110.14,14.2 111.11,14.2 111.22,14.09 114.71,14.09 115.34,14.72 v4(115.34,14.75)
  BOTTOM w0.076: v4(128.43,14.75) 128.43,14.81 127.31,15.92 UD4.R7 ; UD5.R7 138.94,15.92 139.98,14.88 v4(139.98,14.75) ; v1(138.31,40.5) 138.64,40.84 UCPU1.AW41 ; v4(115.34,14.75) 115.34,14.89 114.47,15.76 114.38,15.76 UD2.R7
DDR_A_MA12: length 127
  TOP w0.076: v1(122.1,16.4) 122.05,16.45 121.5,16.45 RD25.1
  IN1 w0.076: v3(109.76,16.92) 109.88,17.05 110.47,17.05 110.69,16.83 112.91,16.83 113.19,16.55 116.88,16.55 116.99,16.44 117.29,16.44 117.44,16.3 117.6,16.3 117.74,16.44 117.9,16.44 118.05,16.3 118.21,16.3 118.35,16.44 118.51,16.44 118.66,16.3 118.82,16.3 118.96,16.44 119.12,16.44 119.27,16.3 119.43,16.3 119.57,16.44 119.73,16.44 119.88,16.3 120.04,16.3 120.18,16.44 120.26,16.44 120.39,16.56 120.65,16.56 120.78,16.44 120.78,15.98 120.89,15.87 121.05,15.87 121.16,15.98 121.16,16.46 121.28,16.58 121.58,16.58 121.8,16.36 122.06,16.36 v1(122.1,16.4) 122.65,16.4 122.89,16.16 123.26,16.16 123.54,15.87 124.94,15.87 125.02,15.96 129.94,15.96 131.54,17.55 133.84,17.55 133.94,17.45 134.74,17.45 134.85,17.35 134.85,17.19 134.74,17.08 134.34,17.08 134.22,16.96 v3(134.22,16.96)
  IN3 w0.076: v1(138.32,41.81) 138.32,41.61 138.45,41.48 138.84,41.48 138.97,41.61 138.97,42.08 139.09,42.21 140.64,42.21 140.77,42.08 140.77,37.25 140.69,37.17
  IN3 w0.191: v1(122.1,16.4) 122.1,21.2 121.34,21.96 121.34,23.88 120.97,24.25 120.97,24.73 120.7,25 120.21,25 120.04,25.17 120.04,28.83 119.79,29.09 119.79,29.38 119.78,29.39 119.78,29.62 119.65,29.75 119.14,29.75 119.01,29.62 119.01,29.16 118.89,29.04 118.42,29.04 118.29,29.16 118.29,29.62 118.16,29.75 117.77,29.75 117.64,29.87 117.64,30.22 117.77,30.34 119.14,30.34 119.27,30.47 119.27,30.8 119.14,30.93 117.35,30.93 117.22,31.06 117.22,31.5 117.35,31.63 118.43,31.63 118.56,31.75 118.56,32.05 118.43,32.17 117.69,32.17 117.57,32.3 117.57,32.62 117.69,32.74 118.39,32.74 118.52,32.87 118.52,33.61 121.56,36.64 122.11,36.64 122.25,36.79 122.25,37.02 122.37,37.14 122.78,37.14 122.91,37.01 122.91,36.75 123.02,36.63 124.5,36.63 124.68,36.45 124.68,36.05 126.07,34.66 131.01,34.66 131.13,34.53 131.13,34.39 131.28,34.24 131.73,34.24 131.99,34.5 132.86,34.5 132.99,34.37 132.99,34.11 133.13,33.97 134.74,33.97 134.86,34.1 134.86,34.55 134.99,34.68 135.89,34.68 136.14,34.93 136.89,34.93 137.68,35.72 139.23,35.72 140.69,37.17
  IN4 w0.076: v4(115.44,17.52) 115.44,17.25 115.27,17.08 114.56,17.08 114.14,16.67 112.46,16.67 112.36,16.77 110.72,16.77 110.46,17.03 109.87,17.03 v3(109.76,16.92) 109.59,16.92 108.73,17.78 105.95,17.78 105.58,18.15 103.45,18.15 102.83,17.52 v4(102.66,17.52) ; v4(140.08,17.52) 140.08,17.31 139.83,17.06 138.67,17.06 138.39,16.78 135.74,16.78 135.46,17.06 134.32,17.06 v3(134.22,16.96) 134.11,16.96 133.85,17.22 133.85,17.38 133.39,17.83 130.69,17.83 130.31,18.22 129.22,18.22 v4(128.52,17.52)
  BOTTOM w0.076: UCPU1.AU41 138.76,42.22 138.65,42.33 138.3,42.33 138.14,42.17 138.14,41.91 138.24,41.81 v1(138.32,41.81) ; UD2.N7 114.21,17.25 114.38,17.08 115.01,17.08 v4(115.44,17.52) ; v4(140.08,17.52) 139.65,17.08 139.22,17.08 138.85,17.45 UD5.N7 ; UD4.N7 127.3,17.43 127.63,17.09 128.1,17.09 v4(128.52,17.52)
DDR_A_MA13: length 133
  TOP w0.076: v1(120.09,10.71) 120.09,11.72 RD55.1
  IN1 w0.076: v3(135.18,11.93) 135.18,11.9 134.05,10.77 125.58,10.77 125.11,11.24 124.73,11.24 124.12,10.63 120.24,10.63 120.17,10.71 v1(120.09,10.71) 120.02,10.71 119.92,10.61 119.1,10.61 119.03,10.68 119.03,10.76 118.95,10.84 118.8,10.84 118.72,10.76 118.72,10.68 118.65,10.61 118.3,10.61 118.22,10.68 118.22,10.98 118.15,11.05 118,11.05 117.92,10.98 117.92,10.68 117.84,10.61 117.69,10.61 117.61,10.68 117.61,10.98 117.54,11.05 117.39,11.05 117.31,10.98 117.31,10.68 117.23,10.61 117.06,10.61 116.93,10.73 116.93,11.18 116.8,11.31 116.6,11.31 116.52,11.23 116.52,10.6 116.47,10.56 116.27,10.56 116.22,10.61 116.22,11.23 116.14,11.31 115.99,11.31 115.91,11.23 115.91,10.93 115.83,10.85 115.68,10.85 115.61,10.93 115.61,11.23 115.53,11.31 114.49,11.31 114.37,11.43 114.37,12.11 114.25,12.22 114.09,12.22 113.97,12.11 113.97,11.38 113.9,11.31 112.56,11.31 111.88,11.99 110.65,11.99 v3(110.59,11.94)
  IN3 w0.076: 133.3,42.22 133.38,42.3 137.46,42.3 137.83,42.66 141.99,42.66 v1(142.31,42.98)
  IN3 w0.191: 133.3,42.22 132.8,41.72 125.27,41.72 124.86,41.3 120.65,41.3 111.18,31.84 111.18,25.48 111.29,25.37 111.29,23.96 111.54,23.71 111.54,21.3 111.84,21.01 112.98,21.01 113.66,20.33 113.66,19.85 117.19,16.33 117.19,15.11 118.21,14.08 118.21,14.08 118.9,13.4 118.9,12.94 119.73,12.11 119.73,11.35 120.09,10.99 v1(120.09,10.71)
  IN4 w0.076: v4(129.52,13.07) 129.94,13.49 130.35,13.49 132.46,11.38 134.8,11.38 135.18,11.76 v3(135.18,11.93) 135.18,12.03 135.35,12.2 138.46,12.2 138.59,12.07 140.11,12.07 141.55,13.51 141.55,14.62 v4(142.05,15.12) ; v4(104.89,12.99) 105.21,13.31 105.68,13.31 107.64,11.36 110.16,11.36 110.59,11.79 v3(110.59,11.94) 110.63,11.98 112.44,11.98 112.58,11.85 115.74,11.85 116.5,12.61 v4(116.5,13.08)
  BOTTOM w0.076: v1(142.31,42.98) 142.62,43.3 UCPU1.AR35 ; v4(129.52,13.07) 129.52,13.17 130.5,14.15 UD4.T3 ; UD1.T3 105.86,14.19 104.89,13.23 v4(104.89,12.99) ; UD2.T3 117.41,14.01 116.5,13.1 v4(116.5,13.08)
DDR_A_MA14: length 128.4
  TOP w0.076: v1(120.75,11.42) 120.58,11.59 RD49.1
  IN1 w0.076: v3(133.56,12.74) 133.47,12.74 132.82,12.09 132.82,11.94 132.18,11.31 126.23,11.31 125.72,11.82 124.49,11.82 123.93,11.26 120.92,11.26 v1(120.75,11.42) 120.75,11.61 120.42,11.94 119.82,11.94 119.75,11.87 119.75,11.76 119.67,11.69 119.52,11.69 119.44,11.76 119.44,11.87 119.36,11.94 118.66,11.94 118.56,11.84 115.43,11.84 114.51,12.77 109.22,12.77 v3(109.03,12.58)
  IN3 w0.076: v1(138.32,39.82) 138.32,39.92 138.19,40.05 137.48,40.05 137.35,39.92 137.35,39.26 137.23,39.13 135.89,39.13 135.77,39.01 135.77,38.64 135.64,38.51 134.2,38.51 133.91,38.8 133.91,39.17 133.63,39.45 133.26,39.45 133.12,39.59 133.12,40.33 132.96,40.49
  IN3 w0.191: 132.96,40.49 132.96,40.87 132.74,41.09 129.54,41.09 129.41,40.96 129.41,40.72 129.28,40.59 128.91,40.59 128.78,40.72 128.78,40.94 128.65,41.06 128.09,41.06 127.97,40.94 127.97,40.83 127.76,40.63 125.82,40.63 125.66,40.47 120.92,40.47 112.16,31.7 112.16,28.07 112.67,27.55 112.67,25.45 112.8,25.33 113.2,25.33 113.33,25.2 113.33,23.99 113.45,23.86 113.95,23.86 114.07,23.73 114.07,23.16 113.95,23.03 113.92,23.03 113.8,22.9 113.8,22.52 113.92,22.4 114.17,22.4 114.3,22.27 114.3,20.38 115.27,19.41 115.73,19.41 116.22,19.9 116.83,19.9 117.83,18.9 117.83,15.41 119.26,13.99 119.78,13.99 120.45,13.31 120.45,12.14 120.58,12.02 121,12.02 121.12,11.89 121.12,11.55 121,11.42 v1(120.75,11.42)
  IN4 w0.076: v4(140.03,13.07) 139.7,12.74 135,12.74 134.95,12.69 133.61,12.69 v3(133.56,12.74) 133.43,12.61 132.01,12.61 130.58,14.04 129.17,14.04 v4(128.22,13.1) ; v4(103.6,13.02) 104.54,13.97 105.78,13.97 107.49,12.26 107.84,12.26 108.25,12.67 108.94,12.67 v3(109.03,12.58) 109.17,12.72 114.06,12.72 114.13,12.65 114.97,12.65 v4(115.39,13.07)
  BOTTOM w0.076: UD2.T7 114.14,15.05 114.14,14.35 115.39,13.1 v4(115.39,13.07) ; UD1.T7 102.66,13.96 v4(103.6,13.02) ; v4(140.03,13.07) 140.03,13.1 138.85,14.28 UD5.T7 ; UD4.T7 127.3,14.56 128.22,13.63 v4(128.22,13.1) ; v1(138.32,39.82) 137.88,39.82 137.62,40.07 137.62,41.22 UCPU1.AV42
DDR_A_MA15: length 127.5
  TOP w0.076: RD27.1 119.93,18.06 v1(119.84,17.97)
  IN1 w0.076: v3(109.74,17.72) 109.74,17.77 109.95,17.97 110.25,17.97 110.86,17.36 111.22,17.36 111.3,17.44 111.3,17.47 111.38,17.54 111.53,17.54 111.61,17.47 111.61,17.44 111.68,17.36 112.44,17.36 112.52,17.44 112.52,17.47 112.6,17.54 112.75,17.54 112.82,17.47 112.82,17.44 112.9,17.36 113.07,17.36 113.36,17.07 114.09,17.07 114.21,17.2 114.21,17.55 114.27,17.61 114.4,17.61 114.48,17.53 114.48,17.12 114.53,17.07 114.67,17.07 114.75,17.15 114.75,17.58 114.82,17.66 114.98,17.66 115.05,17.58 115.05,17.15 115.13,17.07 115.28,17.07 115.36,17.15 115.36,17.58 115.43,17.66 115.59,17.66 115.66,17.58 115.66,17.15 115.74,17.07 115.89,17.07 115.97,17.15 115.97,17.58 116.04,17.66 116.2,17.66 116.27,17.58 116.27,17.15 116.35,17.07 118,17.07 118.48,17.55 119.29,17.55 119.71,17.97 v1(119.84,17.97) 120.04,17.97 120.74,17.28 122.91,17.28 123.82,16.37 124.87,16.37 125.18,16.68 130.04,16.68 131.72,18.35 134.04,18.35 134.43,17.96 v3(134.43,17.86)
  IN3 w0.076: 133.84,38.21 135.83,38.21 136.36,38.74 138.06,38.74 v1(138.33,39.01)
  IN3 w0.191: 133.84,38.21 133.59,38.21 133.47,38.33 133.47,38.95 133.34,39.08 133.06,39.08 132.93,38.95 132.93,38.37 132.81,38.24 132.46,38.24 132.31,38.4 132.31,39.26 132.18,39.39 132.04,39.39 131.92,39.51 131.92,40 131.79,40.12 131.46,40.12 131.33,40 131.33,39.79 131.21,39.66 130.93,39.66 130.8,39.79 130.8,40 130.67,40.12 130.03,40.12 129.89,39.98 129.89,38.84 129.77,38.73 129.19,38.73 129.06,38.85 129.06,39.84 128.87,40.03 126.15,40.03 125.78,39.67 121.24,39.67 112.98,31.4 112.98,29.4 113.48,28.9 113.48,27.55 113.57,27.46 114.7,27.46 114.82,27.33 114.82,27.08 114.7,26.95 113.46,26.95 113.34,26.83 113.34,26.55 113.46,26.42 114.67,26.42 114.8,26.29 114.8,25.96 114.67,25.84 114.33,25.84 114.2,25.71 114.2,25.37 114.33,25.24 114.67,25.24 114.8,25.11 114.8,24.54 115.61,23.73 115.61,21.42 115.88,21.15 115.88,21 116.01,20.87 116.47,20.87 116.6,21 116.6,21.07 116.73,21.2 117.12,21.2 117.24,21.09 117.24,21.01 117.36,20.88 118.92,20.88 119.09,20.71 119.09,19.19 118.97,19.06 118.66,19.06 118.53,18.93 118.53,17.72 118.66,17.59 119.23,17.59 119.61,17.97 v1(119.84,17.97)
  IN4 w0.076: v4(127.92,18.15) 128.46,18.7 130.58,18.7 130.98,18.3 133.05,18.3 133.13,18.38 134.02,18.38 134.43,17.97 v3(134.43,17.86) 134.56,17.86 134.95,17.47 135.63,17.47 135.83,17.26 138.23,17.26 139.42,18.45 139.58,18.45 139.71,18.32 v4(139.71,18.09) ; v4(102.66,18.32) 102.94,18.61 105.9,18.61 106.2,18.31 108.7,18.31 108.77,18.38 109.29,18.38 109.74,17.92 v3(109.74,17.72) 109.93,17.72 110.06,17.59 110.48,17.59 110.88,17.19 112.7,17.19 112.82,17.07 112.99,17.07 113.07,17.15 113.07,17.19 113.14,17.26 113.3,17.26 113.37,17.19 113.37,17.15 113.45,17.07 113.96,17.07 114.21,17.32 114.21,17.86 114.32,17.96 115,17.96 v4(115.12,17.85)
  BOTTOM w0.076: v4(115.12,17.85) 114.64,18.32 UD2.M7 ; UCPU1.AU42 137.84,41.95 137.47,41.58 137.47,38.84 137.59,38.71 138.2,38.71 138.33,38.84 v1(138.33,39.01) ; v4(139.71,18.09) 139.71,18.39 139.58,18.52 139.05,18.52 UD5.M7 ; v4(127.92,18.15) 127.75,18.32 UD4.M7
DDR_A_RAS#: length 125.5
  TOP w0.076: RD59.1 123.58,19.37 123.58,19.02 v1(123.97,18.63)
  IN1 w0.076: v3(110.71,19.28) 110.8,19.19 111.09,19.19 111.42,18.86 114.38,18.86 114.72,18.53 118.95,18.53 119.67,19.24 121.12,19.24 121.59,18.77 123.83,18.77 v1(123.97,18.63) 125.44,18.63 125.75,18.32 128.7,18.32 128.78,18.39 128.78,18.82 128.85,18.9 129,18.9 129.08,18.82 129.08,18.39 129.16,18.32 129.31,18.32 129.39,18.39 129.39,18.82 129.46,18.9 129.61,18.9 129.69,18.82 129.69,18.39 129.77,18.32 129.91,18.32 130.01,18.42 130.01,18.72 130.1,18.8 130.4,18.8 130.8,19.21 134.68,19.21 134.76,19.12 135.21,19.12 v3(135.28,19.19)
  IN3 w0.076: 144.73,37.27 144.73,39.91 144.61,40.03 143.21,40.03 v1(143.04,39.87)
  IN3 w0.191: 144.73,37.27 144.74,37.25 144.74,36.68 145.13,36.29 145.13,28.78 144.43,28.08 141.23,28.08 141.1,27.95 141.1,25.91 140.97,25.79 139.42,25.79 139.28,25.65 139.28,24.7 139.16,24.58 138.84,24.58 138.72,24.7 138.72,25.66 138.59,25.79 138.03,25.79 137.9,25.66 137.9,24.12 137.77,23.99 137.44,23.99 137.31,24.12 137.31,27.9 137.18,28.02 136.45,28.02 136.34,27.91 136.34,23.85 136.15,23.66 136.15,22.33 136.02,22.21 135.56,22.21 135.44,22.33 135.44,23.89 135.31,24.01 132.33,24.01 132.21,23.89 132.21,22.52 132.08,22.39 131.5,22.39 131.37,22.52 131.37,23.99 131.25,24.12 130.56,24.12 130.43,23.99 130.43,22.55 130.31,22.42 129.67,22.42 129.54,22.55 129.54,23.9 129.42,24.03 128.34,24.03 128.22,23.9 128.22,21.47 128.34,21.34 130.04,21.34 130.17,21.21 130.17,20.71 130.04,20.58 127.48,20.58 126.47,19.57 125.82,19.57 124.83,18.58 124.02,18.58 v1(123.97,18.63)
  IN4 w0.076: v4(140.85,20.06) 140.16,19.37 139.07,19.37 138.86,19.17 136.37,19.17 136.26,19.28 135.37,19.28 v3(135.28,19.19) 135.26,19.22 134.73,19.22 134.44,19.5 130.34,19.5 v4(129.81,20.03) ; v4(117.41,20.72) 117.41,20.37 116.24,19.2 110.79,19.2 v3(110.71,19.28) 108.96,19.28 108.77,19.47 105.02,19.47 v4(104.97,19.52)
  BOTTOM w0.076: UD5.J3 141.51,20.72 v4(140.85,20.06) ; v1(143.04,39.87) 143.36,40.19 UCPU1.AY34 ; UD4.J3 130.06,20.72 129.95,20.62 129.95,20.17 v4(129.81,20.03) ; v4(104.97,19.52) 105.31,19.87 105.31,20.46 105.57,20.72 UD1.J3
DDR_A_WE#: length 130.1
  TOP w0.076: v1(123.99,19.47) 123.99,19.56 123.55,20.01 123.55,20.28 RD65.1
  IN1 w0.076: v3(134.85,19.67) 134.61,19.43 130.7,19.43 130.38,19.12 128.45,19.12 128.37,19.04 128.37,18.61 128.29,18.53 128.14,18.53 128.07,18.61 128.07,19.04 127.99,19.12 127.84,19.12 127.76,19.04 127.76,18.61 127.68,18.53 127.53,18.53 127.46,18.61 127.46,19.04 127.38,19.12 125.36,19.12 125.33,19.08 125.33,18.99 125.2,18.86 124.96,18.86 124.83,18.99 124.83,19.36 124.72,19.47 v1(123.99,19.47) 123.56,19.04 121.82,19.04 121.33,19.54 119.59,19.54 118.86,18.81 114.73,18.81 114.47,19.07 111.5,19.07 110.86,19.71 v3(110.21,19.71)
  IN3 w0.076: v1(143.03,40.52) 143.03,40.68 142.9,40.81 142.57,40.81 142.45,40.68 142.45,39.18 142.9,38.73 143.11,38.73 143.83,38 143.83,37.14 144.29,36.68
  IN3 w0.191: 144.29,36.68 144.72,36.25 144.72,28.91 144.31,28.5 140.92,28.5 140.69,28.27 140.69,26.27 140.57,26.14 137.85,26.14 137.72,26.27 137.72,28.35 137.59,28.48 136.06,28.48 135.93,28.35 135.93,24.91 135.81,24.78 135.46,24.78 135.33,24.91 135.33,26.1 135.21,26.23 134.86,26.23 134.74,26.1 134.74,25.07 134.61,24.95 134.25,24.95 134.13,25.07 134.13,27.63 134,27.75 133.59,27.75 133.51,27.66 133.51,25.04 133.38,24.91 133.07,24.91 132.95,25.04 132.95,27.87 132.73,28.09 129.71,28.09 129.58,27.96 129.58,26.36 129.71,26.23 130.93,26.23 131.06,26.1 131.06,25.8 130.93,25.67 129.71,25.67 129.58,25.54 129.58,24.49 129.45,24.36 127.83,24.36 126.65,23.19 125.78,23.19 125.64,23.05 125.64,22.39 125.64,22.38 125.64,22.32 125.77,22.19 126.3,22.19 126.43,22.06 126.43,21.7 126.3,21.57 125.46,21.57 125.13,21.24 125.13,20.82 124.79,20.49 124.79,19.75 124.54,19.5 124.02,19.5 v1(123.99,19.47)
  IN4 w0.076: v4(116.26,19.69) 115.98,19.41 111.17,19.41 110.86,19.71 v3(110.21,19.71) 109.99,19.49 109.04,19.49 108.84,19.69 105.58,19.69 105.39,19.88 104.46,19.88 v4(104.05,19.47) ; v4(128.68,20.06) 129.08,20.46 129.84,20.46 130.58,19.71 134.81,19.71 v3(134.85,19.67) 135.65,19.67 135.85,19.48 138.85,19.48 139.02,19.65 140.01,19.65 140.21,19.85 v4(140.21,20.08)
  BOTTOM w0.076: v4(128.68,20.06) 129.61,19.12 UD4.L3 ; UCPU1.AW34 143.35,40.84 v1(143.03,40.52) ; v4(104.05,19.47) 104.7,18.82 105.56,18.82 UD1.L3 ; v4(116.26,19.69) 116.08,19.69 115.95,19.56 115.95,19.09 116.08,18.96 117.26,18.96 UD2.L3 ; v4(140.21,20.08) 140.21,19.5 140.74,18.96 141.89,18.96 UD5.L3
DDR_B_BS0: length 152.7
  TOP w0.076: RD70.1 171.85,15.43 v1(171.69,15.28)
  IN1 w0.076: v3(156.47,16.42) 156.84,16.42 157.3,16.89 163.15,16.89 163.37,16.67 166.99,16.67 167.12,16.54 167.48,16.54 167.8,16.22 170.61,16.22 171.44,15.4 171.58,15.4 v1(171.69,15.28) 172.14,14.84 172.57,14.84 172.7,14.96 172.7,15.29 172.79,15.39 172.93,15.39 173.03,15.29 173.03,15 173.14,14.89 173.3,14.89 173.41,15 173.41,15.05 173.54,15.17 173.56,15.17 173.65,15.26 173.72,15.26 173.97,15.51 173.97,15.7 173.89,15.78 173.66,15.78 173.55,15.88 173.55,16.03 173.66,16.13 174.32,16.13 174.4,16.05 174.4,15.52 174.48,15.44 174.93,15.44 175.01,15.52 175.01,15.95 175.09,16.03 175.25,16.03 175.31,15.97 175.31,15.52 175.39,15.44 175.75,15.44 176.99,16.68 179.96,16.68 180,16.72 180.76,16.72 181.18,16.3 181.8,16.3 181.89,16.39 v3(181.89,16.5)
  IN2 w0.191: v1(143.28,46.17) 143.96,46.84 144.47,46.84 145.16,46.14 145.16,44.26 146.07,43.36 146.07,42.48 146.6,41.95 154.75,41.95 155.54,41.16 157.97,41.16 159.34,39.8 164.58,39.8 166.27,38.12 177.66,38.12 180.41,35.37 180.41,27.68 180.53,27.55 181.52,27.55 181.65,27.42 181.65,26.81 181.52,26.69 180.85,26.69 180.72,26.56 180.72,25.94 180.85,25.81 181.83,25.81 181.96,25.68 181.96,25.03 181.83,24.91 180.25,24.91 180.13,24.78 180.13,24.16 180.25,24.04 180.6,24.04 180.72,23.91 180.72,21.52 181.54,20.7 181.54,20.28 180.88,19.62 180.5,19.62 179.94,20.18 179.73,20.18 178.07,18.52 178.07,16.27 178.03,16.23 178.03,15.31 177.9,15.18 177.21,15.18 177.19,15.2 175.53,15.2 175.4,15.33 175.4,15.53 175.28,15.66 174.7,15.66 174.58,15.53 174.58,14.44 174.45,14.32 173.93,14.32 173.8,14.44 173.8,14.65 173.68,14.77 172.1,14.77 171.69,15.18 v1(171.69,15.28)
  IN4 w0.076: v4(176.41,17.52) 176.41,17.73 176.62,17.95 177.44,17.95 177.71,17.68 180.43,17.68 180.83,17.29 180.83,16.64 180.86,16.6 181.02,16.6 181.23,16.39 181.78,16.39 v3(181.89,16.5) 182.05,16.34 182.65,16.34 182.89,16.57 186.25,16.57 186.5,16.81 187.26,16.81 188.29,17.84 188.29,17.95 188.21,18.02 188.21,18.12 188.32,18.23 188.43,18.23 188.5,18.16 188.61,18.16 189.16,18.72 189.63,18.72 190.03,18.32 v4(190.1,18.32) ; v4(151.77,17.52) 151.52,17.26 151.35,17.26 151.29,17.33 151.29,17.5 151.73,17.95 152.62,17.95 153,17.57 155.4,17.57 155.58,17.39 155.58,16.99 156.15,16.42 v3(156.47,16.42) 156.84,16.42 157.18,16.77 157.71,16.77 157.76,16.72 161.39,16.72 161.5,16.83 162.67,16.83 164.53,18.69 164.86,18.69 165.22,18.32 v4(165.46,18.32)
  BOTTOM w0.076: v4(151.77,17.52) 152.94,18.68 153.54,18.68 UD6.M2 ; v1(143.28,46.17) 143.01,45.9 UCPU1.AL35 ; UD9.M2 178.23,18.63 177.52,18.63 v4(176.41,17.52)
DDR_B_BS1: length 152.1
  TOP w0.076: v1(171.51,16.19) 171.51,16.2 171.6,16.3 RD66.1
  IN1 w0.076: v3(156.43,17.94) 156.43,17.91 156.89,17.45 157.78,17.45 157.94,17.3 164.28,17.3 164.76,17.78 167.82,17.78 168.13,17.47 169.33,17.47 170.04,16.75 170.86,16.75 171.42,16.19 v1(171.51,16.19) 171.61,16.19 171.96,15.84 172.39,15.84 172.52,15.97 172.52,16.74 172.61,16.83 172.74,16.83 172.84,16.74 172.84,16.33 172.94,16.23 173.08,16.23 173.18,16.33 173.18,16.74 173.28,16.84 173.42,16.84 173.52,16.74 173.52,16.67 173.64,16.55 173.8,16.55 173.92,16.67 173.92,16.74 174.04,16.85 174.62,16.85 174.69,16.93 174.69,17.42 174.77,17.49 174.92,17.49 175,17.42 175,16.93 175.07,16.85 175.23,16.85 175.3,16.93 175.3,17.68 175.39,17.77 175.52,17.77 175.61,17.68 175.61,17.02 175.7,16.93 175.82,16.93 175.91,17.02 175.91,17.73 175.98,17.8 180.65,17.8 181.13,17.31 v3(181.78,17.31)
  IN2 w0.191: v1(141.39,45.07) 141.84,44.63 141.84,42.86 142.38,42.31 142.38,39.32 143.89,37.82 143.89,37 144.16,36.72 148.84,36.72 149.49,36.07 150.78,36.07 151.62,35.23 160.27,35.23 160.87,35.84 164.44,35.84 165.04,35.23 169.14,35.23 169.5,34.88 169.5,33.33 169.62,33.21 170.3,33.21 170.42,33.33 170.42,34.79 170.55,34.92 171.15,34.92 171.28,34.79 171.28,32.58 171.4,32.45 172.04,32.45 172.16,32.58 172.16,34.79 172.29,34.92 172.9,34.92 173.03,34.79 173.03,34.24 173.15,34.12 174.08,34.12 174.21,33.99 174.21,33.46 174.08,33.33 173.4,33.33 173.27,33.2 173.27,32.59 173.4,32.46 174.08,32.46 174.21,32.34 174.21,31.72 174.08,31.59 172.11,31.59 171.99,31.46 171.99,30.9 172.11,30.78 174.08,30.78 174.21,30.65 174.21,30.17 174.08,30.04 173.4,30.04 173.27,29.91 173.27,29.42 173.4,29.29 174.08,29.29 174.21,29.16 174.21,28.64 174.08,28.51 173.4,28.51 173.27,28.39 173.27,27.94 173.4,27.82 174.08,27.82 174.21,27.69 174.21,27.18 174.08,27.05 173.09,27.05 172.96,26.93 172.96,26.42 173.09,26.29 174.08,26.29 174.21,26.17 174.21,25.64 174.08,25.52 172.84,25.52 172.71,25.39 172.71,24.88 172.84,24.76 173.51,24.76 173.64,24.63 173.64,24.11 173.51,23.98 172.54,23.98 171.15,22.59 171.15,21.02 170.35,20.22 170.35,20.01 170.22,19.88 170.22,18.93 170.86,18.29 170.86,17.82 171.02,17.66 171.02,16.81 171.51,16.32 v1(171.51,16.19)
  IN4 w0.076: v4(161.92,17.5) 161.92,17.31 161.86,17.26 161.18,17.26 161.04,17.12 157.93,17.12 157.88,17.17 157.41,17.17 157.16,17.43 156.92,17.43 156.84,17.35 156.64,17.35 156.43,17.56 v3(156.43,17.94) 156.16,17.94 156.02,18.08 153.14,18.08 152.79,18.43 150.48,18.43 150.04,17.99 148.86,17.99 148.73,17.86 148.73,17.65 148.86,17.52 v4(149.1,17.52) ; v4(186.69,17.52) 186.54,17.52 186.41,17.38 186.15,17.38 186.12,17.34 186.12,17.09 186.04,17.02 185.82,17.02 185.75,17.09 185.75,17.31 185.67,17.39 185.52,17.39 185.44,17.31 185.44,17.09 185.37,17.02 183.13,17.02 182.7,17.45 182.2,17.45 182.07,17.57 181.91,17.57 181.78,17.44 v3(181.78,17.31) 181.4,17.31 180.61,18.1 177.96,18.1 177.7,18.37 176.08,18.37 175.66,17.96 174.17,17.96 v4(173.74,17.52)
  BOTTOM w0.076: UD10.N8 185.22,17.6 185.22,17.83 185.42,18.04 186.63,18.04 186.88,17.78 186.88,17.71 v4(186.69,17.52) ; v1(141.39,45.07) 141.56,45.25 UCPU1.AM36 ; v4(161.92,17.5) 161.93,17.5 162.12,17.69 162.12,17.87 161.9,18.09 161.72,18.09 161.61,17.97 160.77,17.97 160.66,17.86 UD7.N8
DDR_B_BS2: length 144.5
  TOP w0.076: RD68.1 168.14,16.61 167.52,16.61 167.39,16.48 167.39,15.79 167.52,15.66 v1(167.6,15.66)
  IN1 w0.076: v3(183.06,16.13) 182.23,16.13 182.18,16.08 181.07,16.08 180.64,16.51 180.25,16.51 180.2,16.46 177.06,16.46 175.81,15.21 174.02,15.21 173.5,14.68 172.86,14.68 172.76,14.58 171.84,14.58 171.18,15.24 171.18,15.29 170.84,15.62 170.75,15.62 170.5,15.88 168.07,15.88 167.81,15.61 167.66,15.61 v1(167.6,15.66) 167.39,15.45 166.87,15.45 166.78,15.54 166.78,16.32 166.7,16.4 166.55,16.4 166.47,16.32 166.47,16.17 166.4,16.09 166.25,16.09 166.17,16.17 166.17,16.32 166.09,16.4 165.84,16.4 165.79,16.35 165.79,16.27 165.68,16.16 165.52,16.16 165.41,16.27 165.41,16.38 165.32,16.47 165.19,16.47 165.1,16.38 165.1,16.17 165,16.07 164.85,16.07 164.75,16.17 164.75,16.36 164.64,16.47 163.1,16.47 163.05,16.53 161.93,16.53 161.85,16.45 161.85,15.92 161.77,15.84 161.62,15.84 161.55,15.92 161.55,16.45 161.47,16.53 161.3,16.53 161.19,16.42 161.19,15.89 161.09,15.79 160.95,15.79 160.85,15.89 160.85,16.42 160.73,16.54 160.56,16.54 160.44,16.42 160.44,16.26 160.36,16.18 160.21,16.18 160.14,16.26 160.14,16.6 160.05,16.69 159.92,16.69 159.83,16.6 159.83,16.26 159.75,16.18 159.6,16.18 159.53,16.26 159.53,16.6 159.44,16.69 159.31,16.69 159.22,16.6 159.22,16.26 159.14,16.18 158.99,16.18 158.92,16.26 158.92,16.4 158.79,16.53 158.62,16.53 158.5,16.4 v3(158.5,16.17)
  IN2 w0.076: v1(133.57,41.91) 133.47,41.91 132.94,41.38 132.85,41.38 132.71,41.51 132.57,41.51 132.43,41.37 132.43,41.22 132.68,40.97 132.68,40.82 132.62,40.76 132.24,40.76 132.15,40.67 132.15,40.49 132.22,40.41 132.6,40.41 132.68,40.34 132.68,40.16 132.6,40.08 132.27,40.08 132.15,39.96 132.15,39.58 132.37,39.35
  IN2 w0.191: 132.37,39.35 132.37,35.1 133.14,34.33 133.14,33.27 133.41,33 133.41,32.72 133.15,32.46 133.15,32.28 133.57,31.85 133.75,31.85 133.88,31.98 134.06,31.98 134.32,31.73 134.32,31.55 134.19,31.42 134.19,31.24 134.44,30.99 134.62,30.99 134.75,31.12 134.93,31.12 135.18,30.87 135.18,30.69 135.05,30.56 135.05,30.38 135.34,30.09 135.52,30.09 135.65,30.23 135.82,30.23 136.15,29.9 138.61,29.9 139.83,28.68 140.38,28.68 140.5,28.55 140.5,27.92 140.63,27.79 141.09,27.79 141.21,27.92 141.21,28.55 141.34,28.68 141.87,28.68 142,28.55 142,27.92 142.13,27.79 142.61,27.79 142.74,27.92 142.74,28.52 142.87,28.64 143.43,28.64 143.56,28.52 143.56,27.96 143.68,27.83 144.68,27.83 144.87,27.64 144.87,27.05 145,26.92 145.61,26.92 145.74,26.79 145.74,26.36 145.61,26.24 144.95,26.24 144.83,26.11 144.83,25.73 144.95,25.61 145.95,25.61 146.64,24.92 146.64,23.6 146.77,23.48 147.13,23.48 147.26,23.6 147.26,24.61 147.39,24.74 148.17,24.74 148.3,24.61 148.3,23.75 148.43,23.63 148.92,23.63 149.04,23.75 149.04,24.5 149.39,24.84 149.7,24.84 149.96,24.58 149.96,24.27 150.14,24.08 150.46,24.08 150.78,23.76 150.78,23.21 150.91,23.08 151.12,23.08 151.25,22.95 151.25,22.37 151.12,22.24 150.41,22.24 150.28,22.11 150.28,21.68 150.41,21.56 150.74,21.56 150.87,21.43 150.87,20.64 150.99,20.51 151.39,20.51 151.51,20.64 151.51,21.44 151.64,21.56 152.12,21.56 152.25,21.44 152.25,20.62 152.38,20.49 152.83,20.49 152.96,20.62 152.96,21.99 153.09,22.12 153.86,22.12 154.13,22.39 154.5,22.39 154.77,22.12 154.77,21.74 154.25,21.22 154.25,21.04 154.55,20.74 154.73,20.74 155.36,21.37 155.81,21.37 156.48,20.7 156.48,20.34 156.61,20.22 156.95,20.22 157.08,20.34 157.08,20.72 157.2,20.84 157.6,20.84 157.73,20.72 157.73,20.21 158.07,19.87 158.07,19.62 158.7,18.99 160.98,18.99 161.39,18.58 162.47,18.58 163.08,17.97 164.16,17.97 164.52,17.62 164.52,16.63 165.13,16.02 166.3,16.02 166.78,15.53 166.78,15.38 166.91,15.25 167.27,15.25 167.4,15.38 167.4,15.46 v1(167.6,15.66)
  IN4 w0.076: v4(189.3,18.32) 189.11,18.32 188.56,17.77 188.56,17.66 188.74,17.47 188.74,17.37 188.63,17.26 188.52,17.26 188.34,17.44 188.23,17.44 187.35,16.56 186.6,16.56 186.26,16.22 183.15,16.22 v3(183.06,16.13) 183.03,16.1 181.71,16.1 181.64,16.17 181,16.17 180.62,16.55 179.23,16.55 179.07,16.71 178.3,16.71 177.5,17.52 v4(177.04,17.52) ; v4(164.66,18.32) 162.92,16.58 161.63,16.58 161.27,16.22 160.33,16.22 160.25,16.29 160.25,16.35 160.18,16.42 160.02,16.42 159.95,16.35 159.95,16.29 159.87,16.22 159.72,16.22 159.64,16.29 159.64,16.35 159.57,16.42 159.41,16.42 159.34,16.35 159.34,16.29 159.26,16.22 158.55,16.22 v3(158.5,16.17) 158.26,15.93 157.45,15.93 157.35,16.03 156.25,16.03 155.6,16.68 154.12,16.68 153.55,17.24 153.04,17.24 152.77,17.52 v4(152.4,17.52)
  BOTTOM w0.076: UD9.M3 177.74,18.21 v4(177.04,17.52) ; UCPU1.AU49 133.93,42.24 133.68,42.24 133.57,42.13 v1(133.57,41.91) ; v4(152.4,17.52) 153.1,18.21 UD6.M3
DDR_B_CAS#: length 146.6
  TOP w0.076: RD62.1 170.45,18.63 v1(171.16,18.63)
  IN1 w0.076: v3(158.03,18.53) 158.08,18.53 158.17,18.62 167.62,18.62 168.19,19.19 170.16,19.19 170.72,18.63 v1(171.16,18.63) 171.28,18.75 171.28,18.91 171.35,18.99 171.98,18.99 172.18,18.79 172.18,18.42 172.29,18.3 172.46,18.3 172.57,18.42 172.57,18.64 172.67,18.74 172.81,18.74 172.91,18.64 172.91,18.44 173.04,18.32 173.61,18.32 173.73,18.44 173.73,18.78 173.86,18.91 178.71,18.91 178.87,19.06 181.75,19.06 181.98,18.84 182.3,18.84 v3(182.55,18.58)
  IN2 w0.191: v1(171.16,18.63) 171.61,19.08 172.3,19.08 172.6,19.37 173.17,19.37 173.36,19.56 173.36,19.69 173.55,19.88 173.93,19.88 174.12,19.69 174.12,19.56 174.31,19.37 174.68,19.37 174.81,19.5 174.81,19.68 175,19.87 175.36,19.87 175.56,20.06 175.56,20.44 175.36,20.63 175,20.63 174.81,20.82 174.81,21.45 174.94,21.57 175.68,21.57 175.81,21.7 175.81,23.62 175.99,23.8 175.99,25.21 176.11,25.34 176.63,25.34 176.76,25.21 176.76,24.26 176.9,24.11 176.9,23.54 177.09,23.35 177.5,23.35 177.69,23.54 177.69,23.88 177.79,23.98 178.36,23.98 178.49,24.11 178.49,24.62 178.36,24.74 177.89,24.74 177.76,24.87 177.76,25.33 177.89,25.45 178.36,25.45 178.49,25.58 178.49,26.15 178.36,26.28 177.17,26.28 177.05,26.4 177.05,27.06 177.17,27.19 178.67,27.19 178.79,27.32 178.79,28.01 178.67,28.13 177.17,28.13 177.05,28.26 177.05,28.87 177.17,29 178.67,29 178.79,29.12 178.79,29.75 178.67,29.87 177.17,29.87 177.05,30 177.05,30.61 177.17,30.74 178.16,30.74 178.35,30.93 178.35,31.44 178.16,31.63 177.17,31.63 177.05,31.75 177.05,32.48 177.17,32.6 178.67,32.6 178.79,32.73 178.79,33.44 178.67,33.57 177.17,33.57 177.05,33.7 177.05,34.34 177.17,34.47 178.14,34.47 178.27,34.6 178.27,35.22 178.14,35.35 177.17,35.35 177.05,35.47 177.05,36.41 176.92,36.54 165.4,36.54 164.97,36.98 161.05,36.98 160.55,37.48 154.79,37.48 151.42,40.85 145.51,40.85 143.77,42.59 143.77,45.18 v1(144.2,45.61)
  IN4 w0.076: v4(164.66,19.92) 164.86,19.92 164.99,19.79 164.99,19.51 164.86,19.38 163.49,19.38 162.71,18.61 158.45,18.61 158.35,18.51 158.05,18.51 v3(158.03,18.53) 157.9,18.66 157.16,18.66 156.85,18.97 155.85,18.97 155.53,19.3 152.68,19.3 151.95,20.03 v4(151.92,20.03) ; v4(189.3,19.92) 189.52,19.92 189.64,19.81 189.64,19.64 189.52,19.53 187.85,19.53 187.42,19.1 186.51,19.1 186.3,18.9 182.87,18.9 v3(182.55,18.58) 182.24,18.58 181.52,19.29 180.35,19.29 180.15,19.49 177.09,19.49 v4(176.56,20.03)
  BOTTOM w0.076: v4(151.92,20.03) 152.23,19.72 152.9,19.72 UD6.K3 ; v4(176.56,20.03) 176.99,19.6 177.42,19.6 UD9.K3 ; v1(144.2,45.61) 143.84,45.25 UCPU1.AM33
DDR_B_CKE0: length 135
  TOP w0.076: RD58.1 167.63,21.07 v1(167.74,21.19)
  IN1 w0.076: v3(178.22,21.36) 177.41,20.55 177.26,20.55 177.18,20.63 177.18,20.86 177.11,20.93 176.88,20.93 176.8,20.86 176.8,20.63 176.72,20.55 176.5,20.55 176.42,20.63 176.42,20.86 176.34,20.93 176.11,20.93 176.04,20.86 176.04,20.63 175.96,20.55 175.73,20.55 175.66,20.63 175.66,20.86 175.58,20.93 175.35,20.93 175.28,20.86 175.28,20.63 175.2,20.55 175.11,20.55 175.05,20.49 175.05,20.03 174.96,19.94 174.83,19.94 174.74,20.03 174.74,20.8 174.65,20.89 174.52,20.89 174.42,20.8 174.42,20.02 174.35,19.94 174.2,19.94 174.12,20.02 174.12,20.55 174.03,20.64 173.9,20.64 173.82,20.55 173.82,20.02 173.74,19.94 173.02,19.94 172.74,20.22 172.74,20.32 172.89,20.47 172.89,20.59 172.8,20.68 172.67,20.68 172.53,20.54 172.35,20.54 171.68,21.21 171.68,21.31 171.86,21.49 171.86,21.6 171.76,21.71 171.65,21.71 171.47,21.53 171.36,21.53 171.2,21.69 171.08,21.69 171,21.76 171,21.97 170.92,22.05 170.77,22.05 170.7,21.97 170.7,21.76 170.62,21.69 170.1,21.69 170.02,21.76 170.02,22.46 169.95,22.53 169.79,22.53 169.72,22.46 169.72,21.76 169.64,21.69 169.49,21.69 169.41,21.76 169.41,22.46 169.34,22.53 169.18,22.53 169.11,22.46 169.11,21.76 169.03,21.69 168.5,21.69 168.18,21.36 168.09,21.36 167.95,21.23 167.78,21.23 v1(167.74,21.19) 167.62,21.19 166.73,20.3 166.49,20.3 165.91,19.71 163.58,19.71 162.82,20.48 162.21,20.48 161.96,20.23 161.96,20.12 162.38,19.71 162.38,19.6 162.27,19.5 162.16,19.5 161.75,19.91 161.64,19.91 161.38,19.64 161.38,19.6 161.3,19.52 161.15,19.52 161.07,19.6 161.07,19.64 160.99,19.72 160.84,19.72 160.77,19.64 160.77,19.6 160.69,19.52 160.54,19.52 160.46,19.6 160.46,19.64 160.38,19.72 160.23,19.72 160.16,19.64 160.16,19.6 160.08,19.52 159.93,19.52 159.85,19.6 159.85,19.64 159.78,19.72 159.19,19.72 158.91,20 158.91,20.11 159.13,20.33 159.13,20.43 159.02,20.54 158.91,20.54 158.69,20.32 158.59,20.32 158.48,20.43 158.48,20.54 158.69,20.76 158.69,20.86 158.59,20.97 158.48,20.97 158.26,20.76 158.16,20.76 158.04,20.87 155.5,20.87 155.43,20.79 155.43,19.52 155.34,19.43 155.21,19.43 155.12,19.52 155.12,20.79 155.05,20.87 153.94,20.87 v3(153.86,20.79)
  IN2 w0.076: v1(134.32,38.88) 134.12,38.88 133.99,38.75 133.99,37.53 134.14,37.38
  IN2 w0.191: v1(167.74,21.19) 167.73,21.17 167.52,21.17 167.14,21.56 167.14,22.89 166.49,23.53 165.17,23.53 165.04,23.4 165.04,23.29 164.91,23.16 164.3,23.16 164.17,23.29 164.17,23.97 164.3,24.1 164.65,24.1 164.77,24.23 164.77,25.23 164.54,25.46 164.54,25.87 164.42,25.99 163.84,25.99 163.71,25.87 163.71,24.92 163.59,24.79 163.06,24.79 162.93,24.92 162.93,25.31 163.05,25.43 163.05,26.42 162.92,26.55 162.51,26.55 162.39,26.42 162.39,25.54 162.26,25.41 161.83,25.41 161.7,25.54 161.7,26.43 162.06,26.79 162.06,26.97 161.7,27.32 161.52,27.32 160.94,26.74 160.94,25.9 160.81,25.77 160.35,25.77 160.23,25.9 160.23,27.66 160.35,27.79 160.61,27.79 160.74,27.92 160.74,28.49 160.61,28.62 155.37,28.62 154.9,29.08 150.86,29.08 150.73,29.21 150.73,30.02 150.61,30.15 150.18,30.15 150.05,30.02 150.05,29.69 149.93,29.56 149.49,29.56 149.37,29.69 149.37,30.01 149.24,30.14 146.99,30.14 146.28,30.85 145.47,30.85 144.67,31.65 142.09,31.65 141.96,31.78 141.96,32.38 141.84,32.51 138.83,32.51 138.32,33.02 138.32,33.22 138.65,33.56 138.65,33.74 138.34,34.05 138.16,34.05 137.84,33.73 137.39,33.73 136.79,34.34 136.79,35.6 135,37.38 134.14,37.38
  IN4 w0.076: v1(183.52,20.32) 183.33,20.51 183.33,20.73 182.76,21.3 180.52,21.3 180.44,21.21 180.03,21.21 179.68,20.87 178.71,20.87 v3(178.22,21.36) 177.99,21.13 177.89,21.13 177.67,20.91 175.55,20.91 174.81,20.17 174.81,19.99 174.25,19.43 172.48,19.43 v4(172.47,19.42) ; v4(148.3,19.92) 148.07,19.92 147.95,19.79 147.95,19.57 148.07,19.45 149.77,19.45 150.31,19.98 150.31,20.11 151.08,20.88 153.77,20.88 v3(153.86,20.79) 154.08,21.01 154.49,21.01 154.56,20.93 154.56,20.73 154.65,20.64 154.78,20.64 154.87,20.73 154.87,20.88 154.99,21.01 155.07,21.01 155.19,21.12 156.75,21.12 157.01,20.87 158.64,20.87 158.83,20.68 v4(158.83,20.36)
  BOTTOM w0.076: UD9.K9 172.94,19.9 172.47,19.43 v4(172.47,19.42) ; UD7.K9 159.83,19.9 159.29,19.9 v4(158.83,20.36) ; v1(183.52,20.32) 183.92,19.92 UD10.K9 ; UCPU1.AY49 133.96,40.19 133.83,40.06 133.83,38.49 133.96,38.36 134.19,38.36 134.32,38.49 v1(134.32,38.88)
DDR_B_CKE1: length 132.9
  TOP w0.076: RD89.1 v1(168.19,22.32)
  IN1 w0.076: v3(153.8,21.39) 153.81,21.4 155.42,21.4 155.71,21.69 158.18,21.69 159.95,19.92 161.37,19.92 162.12,20.68 164.65,20.68 164.71,20.74 166.58,20.74 167.44,21.61 167.44,21.92 167.84,22.32 v1(168.19,22.32) 168.72,22.32 168.8,22.39 168.8,23.4 168.89,23.49 169.01,23.49 169.1,23.4 169.1,22.95 169.19,22.86 169.32,22.86 169.41,22.95 169.41,23.4 169.5,23.49 169.62,23.49 169.71,23.4 169.71,22.91 169.8,22.83 169.93,22.83 170.02,22.91 170.02,23.33 170.11,23.42 170.23,23.42 170.32,23.33 170.32,22.39 170.4,22.32 171.47,22.32 172.32,21.47 172.71,21.47 172.9,21.28 172.9,20.96 173.1,20.76 173.5,20.76 173.9,21.15 177.34,21.15 177.45,21.25 177.51,21.25 178.03,21.77 178.37,21.77 178.81,21.32 v3(178.95,21.32)
  IN2 w0.191: v1(134.34,37.79) 134.34,38.38 134.47,38.51 134.91,38.51 135.04,38.38 135.04,37.9 137.18,35.76 137.18,34.83 137.66,34.35 137.9,34.35 138.15,34.6 138.35,34.6 138.59,34.36 139.07,33.88 139.07,33.03 139.2,32.9 139.77,32.9 139.89,33.03 139.89,33.32 140.02,33.44 140.55,33.44 140.68,33.32 140.68,33.03 140.81,32.9 141.35,32.9 141.48,33.03 141.48,33.32 141.61,33.44 142.23,33.44 142.36,33.32 142.36,32.17 142.48,32.05 143.14,32.05 143.27,32.17 143.27,33.32 143.4,33.44 143.92,33.44 144.05,33.32 144.05,32.17 144.17,32.05 144.54,32.05 145,32.5 145.18,32.5 145.5,32.18 145.5,32 145.3,31.8 145.3,31.62 145.68,31.23 145.86,31.23 146.06,31.43 146.26,31.43 147.15,30.53 151,30.53 151.13,30.41 151.13,29.61 151.25,29.48 151.71,29.48 151.84,29.61 151.84,29.88 151.97,30 152.45,30 152.58,29.88 152.58,29.61 152.7,29.48 153.13,29.48 153.26,29.61 153.26,29.88 153.39,30 153.89,30 154.02,29.88 154.02,29.61 154.14,29.48 154.63,29.48 154.75,29.61 154.75,29.88 154.88,30 155.2,30 155.62,29.58 155.62,29.14 155.74,29.01 161,29.01 161.13,28.88 161.13,27.77 161.26,27.64 161.67,27.64 161.8,27.77 161.8,27.94 161.93,28.07 162.45,28.07 162.58,27.94 162.58,27 162.7,26.88 163.13,26.88 163.26,27 163.26,27.94 163.39,28.07 163.86,28.07 163.99,27.94 163.99,27.02 164.11,26.9 164.56,26.9 164.68,27.02 164.68,27.94 164.81,28.07 165.29,28.07 165.42,27.94 165.42,27.24 165.55,27.12 165.88,27.12 166,26.99 166,26.51 165.88,26.38 165.01,26.38 164.88,26.25 164.88,25.59 165.01,25.47 165.82,25.47 165.95,25.34 165.95,24.91 165.82,24.78 165.27,24.78 165.15,24.65 165.15,23.99 165.27,23.86 166.63,23.86 167.18,23.31 167.9,23.31 168.19,23.02 v1(168.19,22.32)
  IN4 w0.076: v4(172.94,20.72) 172.94,20.16 173.22,19.88 174.28,19.88 174.59,20.19 174.59,20.24 175.48,21.13 177.43,21.13 178.05,21.75 178.52,21.75 v3(178.95,21.32) 178.97,21.32 179.74,22.09 181.96,22.09 182.11,21.94 182.11,21.7 182.23,21.58 182.4,21.58 182.51,21.7 182.51,21.95 182.64,22.08 182.86,22.08 182.98,21.95 182.98,21.48 184.1,20.36 v1(184.12,20.36) ; v4(148.3,20.72) 148.32,20.74 148.85,20.74 148.97,20.86 149.13,20.86 149.25,20.75 149.25,20.58 149.09,20.42 149.09,19.93 149.18,19.84 149.8,19.84 149.93,19.97 149.93,20.23 150.79,21.1 153.51,21.1 v3(153.8,21.39) 154.17,21.39 154.3,21.26 155.04,21.26 155.15,21.38 156.51,21.38 156.82,21.69 157.06,21.69 157.14,21.77 157.14,21.94 157.21,22.01 157.37,22.01 157.44,21.94 157.44,21.77 157.52,21.69 158.1,21.69 v4(159.47,20.33)
  BOTTOM w0.076: UCPU1.AU50 133.06,42.14 132.87,41.95 v2(132.87,37.94) 132.87,37.56 133,37.43 134.21,37.43 134.34,37.56 v1(134.34,37.79) ; UD7.J9 159.86,20.7 159.48,20.33 v4(159.47,20.33) ; v1(184.12,20.36) 184.48,20.72 UD10.J9
DDR_B_CS0#: length 135.9
  TOP w0.076: v1(171.48,17.5) 171.11,17.5 170.89,17.28 RD60.1
  IN1 w0.076: v3(158.18,17.96) 158.64,18.41 167.78,18.41 167.88,18.51 170.17,18.51 170.32,18.35 170.45,18.35 171.31,17.5 v1(171.48,17.5) 173.87,17.5 173.97,17.59 173.97,18.64 174.03,18.7 174.22,18.7 174.3,18.63 174.3,18.44 174.37,18.37 174.53,18.37 174.6,18.44 174.6,18.63 174.68,18.7 178.8,18.7 178.95,18.85 181.68,18.85 182.43,18.1 182.96,18.1 183.16,18.3 v3(183.16,18.47)
  IN2 w0.191: v1(171.48,17.5) 171.7,17.5 171.76,17.44 173.52,17.44 173.85,17.78 173.85,18.02 175.33,19.5 177.56,19.5 177.69,19.62 177.69,20.38 177.56,20.51 175.96,20.51 175.83,20.64 175.83,21.28 175.96,21.4 177.62,21.4 178.61,22.39 179.25,22.39 179.38,22.52 179.38,22.98 179.25,23.1 178.78,23.1 178.66,23.23 178.66,23.74 178.78,23.87 179.28,23.87 179.4,23.99 179.4,34.95 177.22,37.14 165.65,37.14 164.1,38.69 160.95,38.69 160.8,38.54 160.8,38.14 160.67,38.01 159.97,38.01 159.85,38.14 159.85,38.56 159.72,38.69 159.1,38.69 158.97,38.56 158.97,38.14 158.84,38.01 158.38,38.01 158.26,38.14 158.26,38.6 158.13,38.73 157.62,38.73 157.5,38.6 157.5,38.22 157.37,38.09 156.66,38.09 156.53,38.22 156.53,39.69 156.4,39.82 155.72,39.82 155.59,39.69 155.59,38.22 155.46,38.09 154.75,38.09 154.63,38.22 154.63,38.92 152.32,41.23 145.58,41.23 144.35,42.46 144.35,43.21 144.61,43.46 144.61,44.56 v1(144.18,44.99)
  IN4 w0.076: v4(154.3,18.73) 153.13,18.73 153.03,18.84 153.03,18.98 153.13,19.08 155.45,19.08 155.77,18.76 156.77,18.76 157.08,18.46 157.42,18.46 157.92,17.96 v3(158.18,17.96) 158.63,18.4 163.13,18.4 163.85,19.12 v4(165.46,19.12) ; v4(190.1,19.12) 190.12,19.15 190.12,19.33 189.97,19.48 189.79,19.48 189.63,19.33 187.94,19.33 187.51,18.9 186.59,18.9 186.31,18.62 183.31,18.62 v3(183.16,18.47) 182.87,18.18 182.35,18.18 181.45,19.08 180.28,19.08 180.06,19.29 178.04,19.29 177.92,19.16 177.92,18.96 178.04,18.84 178.83,18.84 v4(178.93,18.73)
  BOTTOM w0.076: v4(154.3,18.73) 154.28,18.75 154.28,18.77 153.93,19.12 UD6.L2 ; v1(144.18,44.99) 144.44,45.25 UCPU1.AM32 ; v4(178.93,18.73) 178.92,18.75 178.91,18.75 UD9.L2
DDR_B_CS1#: length 135.5
  TOP w0.076: RD90.1 171.95,17.18 171.76,17 v1(171.76,16.97)
  IN1 w0.076: v3(185.45,18.09) 185.45,17.91 185.03,17.49 183.25,17.49 182.9,17.85 182.39,17.85 181.59,18.65 179.03,18.65 178.88,18.5 175.16,18.5 173.92,17.26 172.05,17.26 v1(171.76,16.97) 171.43,16.97 170.31,18.09 170.21,18.09 170.08,18.22 167.89,18.22 167.87,18.2 164.2,18.2 164.12,18.12 164.12,17.83 164.05,17.76 163.9,17.76 163.82,17.83 163.82,18.12 163.74,18.2 163.59,18.2 163.51,18.12 163.51,17.83 163.44,17.76 163.29,17.76 163.21,17.83 163.21,18.12 163.13,18.2 162.98,18.2 162.9,18.12 162.9,17.83 162.83,17.76 162.68,17.76 162.6,17.83 162.6,18.12 162.52,18.2 162.37,18.2 162.3,18.12 162.3,17.83 162.22,17.76 162.07,17.76 161.99,17.83 161.99,18.12 161.91,18.2 161.76,18.2 161.69,18.12 161.69,17.83 161.61,17.76 161.46,17.76 161.38,17.83 161.38,18.12 161.3,18.2 161.11,18.2 v3(160.89,17.97)
  IN2 w0.191: v1(171.76,16.97) 171.77,16.98 173.38,16.98 173.51,16.86 173.51,16 173.64,15.87 174.25,15.87 174.37,16 174.37,16.34 174.5,16.46 174.76,16.46 174.89,16.59 174.89,17 174.76,17.12 174.5,17.12 174.37,17.25 174.37,18.01 175.05,18.69 175.49,18.69 175.62,18.56 175.62,18.1 175.75,17.97 176.2,17.97 176.33,18.1 176.33,18.88 176.46,19 176.89,19 177.01,18.88 177.01,18.09 177.14,17.96 177.59,17.96 177.71,18.09 177.71,18.79 178.8,19.87 178.8,20.34 179.1,20.64 179.57,20.64 179.8,20.87 179.8,35.11 177.39,37.52 165.81,37.52 164.22,39.11 162.45,39.11 162.29,39.27 162.29,39.34 162.1,39.54 161.72,39.54 161.53,39.34 161.53,39.27 161.34,39.08 158.3,39.08 158.17,39.21 158.17,40.28 158.04,40.41 157.59,40.41 157.4,40.6 157.4,40.71 157.21,40.9 156.83,40.9 156.64,40.71 156.64,40.6 156.45,40.41 155.12,40.41 154.99,40.54 154.99,40.94 154.87,41.06 154.37,41.06 154.24,40.94 154.24,40.57 154.12,40.44 153.66,40.44 153.54,40.57 153.54,41.43 153.41,41.56 145.74,41.56 144.64,42.65 144.64,43.06 144.88,43.3 144.88,46.04 144.69,46.24 v1(144.2,46.24)
  IN4 w0.076: v4(179.86,18.76) 179.89,18.73 181.5,18.73 182.27,17.97 182.76,17.97 183.26,17.47 185.02,17.47 185.45,17.9 v3(185.45,18.09) 185.77,18.41 186.38,18.41 186.68,18.7 187.59,18.7 187.82,18.92 189.72,18.92 190,18.64 191,18.64 191.13,18.77 191.13,18.99 191,19.12 v4(190.9,19.12) ; v4(166.26,19.12) 166.37,19.12 166.5,18.99 166.5,18.77 166.37,18.64 165.34,18.64 165.06,18.92 164.04,18.92 163.2,18.08 160.99,18.08 v3(160.89,17.97) 160.89,17.9 160.51,17.53 158.1,17.53 158.05,17.58 157.88,17.58 157.22,18.24 157.01,18.24 156.7,18.55 155.38,18.55 v4(155.17,18.76)
  BOTTOM w0.076: v4(179.86,18.76) 179.86,18.76 179.5,19.12 UD9.L1 ; v4(155.17,18.76) 155.17,18.88 154.94,19.12 UD6.L1 ; v1(144.2,46.24) 144.51,46.55 UCPU1.AK32
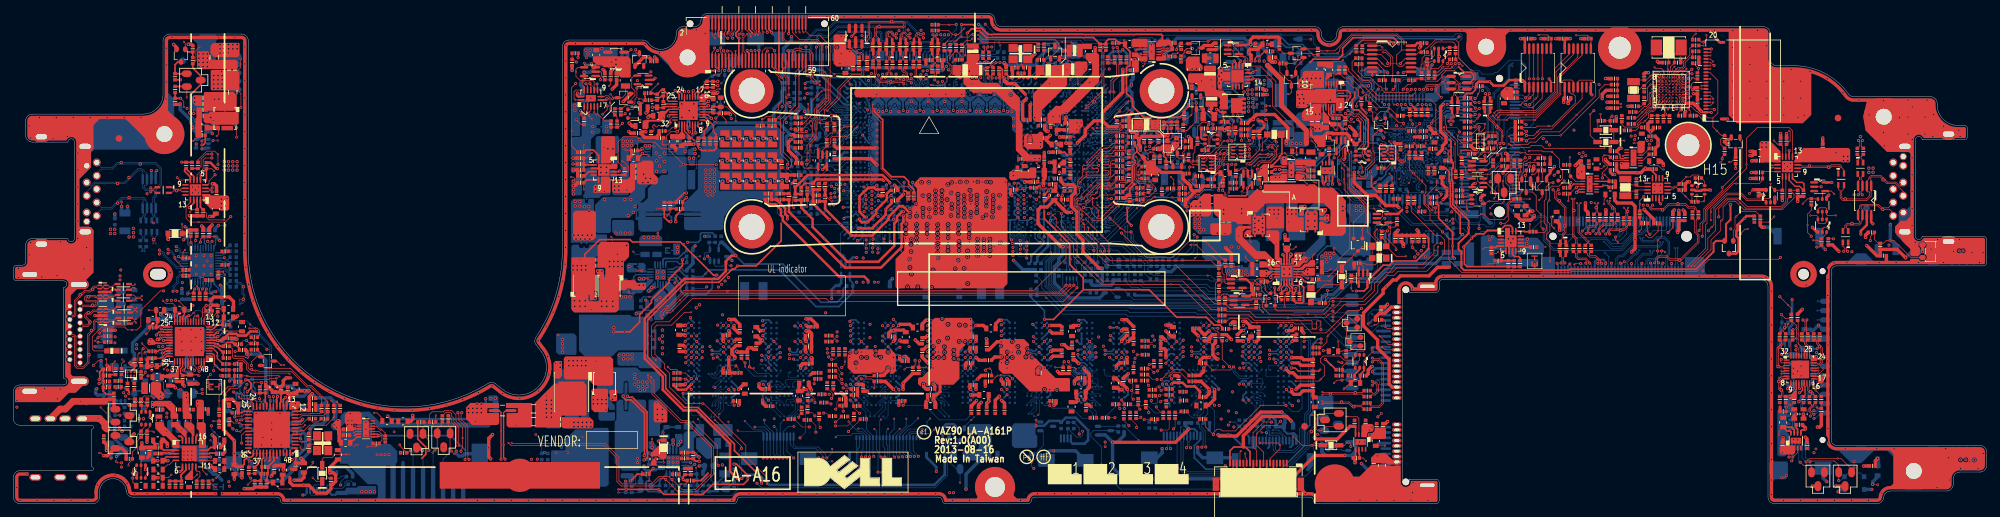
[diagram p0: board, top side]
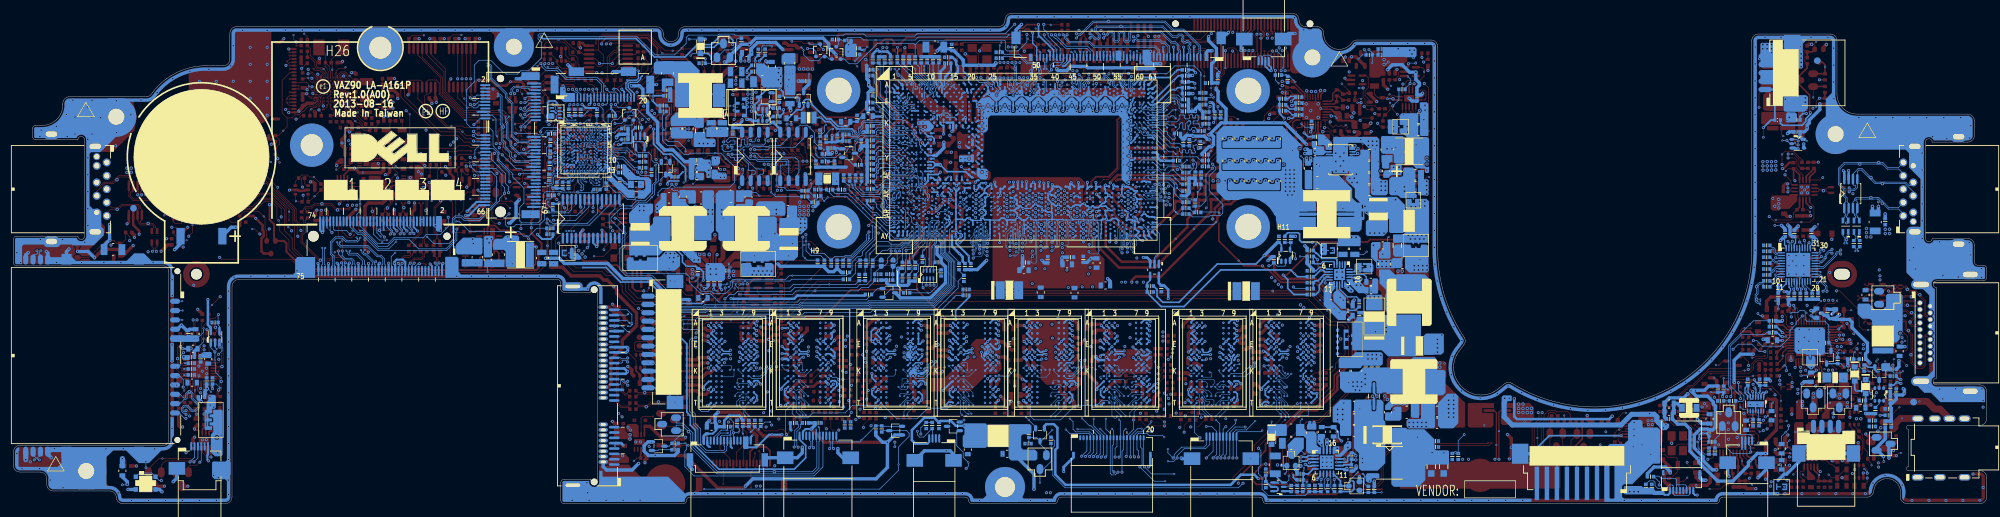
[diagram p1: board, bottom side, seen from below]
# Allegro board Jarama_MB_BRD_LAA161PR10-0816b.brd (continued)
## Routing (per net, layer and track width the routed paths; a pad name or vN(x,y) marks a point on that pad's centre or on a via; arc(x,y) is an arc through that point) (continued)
DDR_B_D0: length 38.9
  IN1 w0.102: 145.27,37.21 144.86,37.62 144.86,39.11 v1(144.3,39.67)
  IN1 w0.127: v1(162.01,21.98) 161.53,21.98 161.41,21.85 161.41,21.46 161.53,21.34 163.54,21.34 163.67,21.46 163.67,21.78 163.54,21.91 162.61,21.91 162.49,22.04 162.49,22.27 162.61,22.39 162.74,22.39 162.87,22.52 162.87,22.88 162.74,23 162.61,23 162.49,23.13 162.49,23.92 162.36,24.04 162.07,24.04 161.94,24.17 161.94,25.86 162.11,26.03 162.39,26.03 162.55,26.19 162.55,26.52 162.39,26.69 162.11,26.69 161.94,26.85 161.94,28.4 161.75,28.59 161.21,28.59 160.8,29 156.16,29 155.01,30.15 153.1,30.15 151.22,32.03 148.37,32.03 145.4,35 145.4,36.37 145.27,36.5 145.27,37.21
  BOTTOM w0.076: UCPU1.AY31 144.3,39.8 v1(144.3,39.67)
  BOTTOM w0.178: v1(162.01,21.98) 161.56,21.52 UD7.H7
DDR_B_D1: length 39.9
  IN1 w0.102: v1(144.3,39.06) 144.68,38.67 144.68,37.54 145,37.23 145,36.77
  IN1 w0.127: 145,36.77 145,36.41 145.02,36.39 145.02,34.86 148.31,31.58 151.07,31.58 152.87,29.77 154.87,29.77 155.98,28.66 159.82,28.66 159.95,28.53 159.95,25.91 160.07,25.78 160.38,25.78 160.51,25.91 160.51,28.38 160.63,28.5 160.85,28.5 160.98,28.38 160.98,28.27 161.1,28.15 161.55,28.15 161.67,28.02 161.67,27.56 161.55,27.44 161.08,27.44 160.95,27.31 160.95,27.04 161.08,26.91 161.57,26.91 161.7,26.79 161.7,26.48 161.57,26.36 161.13,26.36 161,26.23 161,25.95 161.13,25.82 161.5,25.82 161.62,25.7 161.62,24.15 161.5,24.03 161.37,24.03 161.25,23.9 161.25,23.59 161.37,23.46 161.79,23.46 v1(161.88,23.55)
  BOTTOM w0.076: v1(144.3,39.06) 143.84,39.51 143.84,39.88 144.01,40.05 144.17,40.05 144.57,40.45 144.58,40.45 144.68,40.56 UCPU1.AW31
  BOTTOM w0.178: v1(161.88,23.55) 161.46,23.13 UD7.F7
DDR_B_D2: length 38.9
  IN1 w0.127: v1(146.13,39.64) 147.96,39.64 148.22,39.37 148.22,39.08 147.52,38.37 147.52,36.65 149.78,34.39 152.39,34.39 154.34,32.44 155.78,32.44 157.04,31.18 162.22,31.18 162.51,30.9 162.71,30.9 163,31.18 164.18,31.18 166.94,28.41 166.94,27.63 167.07,27.5 167.86,27.5 168.19,27.16 168.19,26.96 167.82,26.59 167.82,24.44 166.59,23.21 165.67,23.21 165.47,23.02 165.47,22.13 165.28,21.93 v1(165.06,21.93)
  BOTTOM w0.076: UCPU1.AY29 146.04,39.73 v1(146.13,39.64)
  BOTTOM w0.178: UD7.G2 165.44,22.32 v1(165.06,21.93)
DDR_B_D3: length 39.6
  IN1 w0.127: v1(165.05,22.73) 165.05,23.05 165.53,23.54 166.55,23.54 167.5,24.49 167.5,26.03 167.38,26.15 166.73,26.15 166.6,26.28 166.6,26.55 166.73,26.67 167.38,26.67 167.5,26.8 167.5,27.12 167.38,27.24 166.75,27.24 166.63,27.37 166.63,28.28 164.05,30.86 163.13,30.86 162.76,30.49 162.46,30.49 162.09,30.86 156.91,30.86 155.65,32.12 154.21,32.12 152.26,34.08 149.53,34.08 148.16,35.44 147.8,35.44 146.96,36.28 146.96,36.74 147.16,36.94 147.16,39.21 147.08,39.29 146.26,39.29 146.13,39.17 v1(146.13,39.08)
  BOTTOM w0.076: UCPU1.AW29 146.51,40.36 146.51,39.46 v1(146.13,39.08)
  BOTTOM w0.178: UD7.F2 165.44,23.12 v1(165.05,22.73)
DDR_B_D4: length 40
  IN1 w0.102: v1(144.3,37.84) 144.3,37.66 144.67,37.29 144.67,36.72
  IN1 w0.127: v1(160.26,21.93) 160.96,21.93 161.52,22.5 161.52,22.95 160.42,24.06 160.42,24.76 160.54,24.88 161.09,24.88 161.22,25.01 161.22,25.34 161.09,25.47 159.06,25.47 158.93,25.59 158.93,27.92 158.8,28.04 158.37,28.04 158.25,27.92 158.25,25.71 158.12,25.58 157.76,25.58 157.64,25.71 157.64,28.17 157.51,28.3 155.82,28.3 154.71,29.41 152.7,29.41 150.88,31.22 148.16,31.22 144.67,34.72 144.67,36.72
  BOTTOM w0.076: UCPU1.AV31 144.68,41.24 144.96,40.96 144.96,40.73 144.88,40.66 144.88,40.38 144.96,40.3 144.96,40.08 144.68,39.8 144.68,38.14 144.38,37.84 v1(144.3,37.84)
  BOTTOM w0.183: UD7.H8 160.66,21.53 v1(160.26,21.93)
DDR_B_D5: length 41.1
  IN1 w0.127: v1(160.27,23.52) 160.22,23.47 159.02,23.47 158.89,23.59 158.89,23.8 159.02,23.92 159.79,23.92 159.92,24.05 159.92,24.95 159.79,25.07 157.25,25.07 157.13,25.2 157.13,27.85 157,27.98 156.71,27.98 156.58,27.85 156.58,24.41 156.45,24.29 156.23,24.29 156.1,24.41 156.1,27.69 155.92,27.87 155.26,27.87 154.08,29.05 152.56,29.05 150.74,30.87 148.01,30.87 144.3,34.59 144.3,36.62 143.91,37.01 143.91,38.05 v1(144.3,38.45)
  BOTTOM w0.076: v1(144.3,38.45) 143.67,39.08 143.67,39.92 143.96,40.21 144.11,40.21 144.3,40.4 144.3,41.6 144.68,41.98 UCPU1.AU31
  BOTTOM w0.178: UD7.F8 160.66,23.13 v1(160.27,23.52)
DDR_B_D6: length 40.2
  IN1 w0.127: v1(164.06,21.93) 164.06,21.71 164.19,21.58 164.49,21.58 164.62,21.71 164.62,22.99 165.48,23.84 166.09,23.84 166.3,24.04 166.3,24.57 166.47,24.74 166.65,24.74 167,25.09 167,25.5 166.3,26.2 166.3,28.16 163.91,30.55 163.26,30.55 162.89,30.18 162.33,30.18 161.96,30.55 156.78,30.55 155.52,31.81 154.08,31.81 152.12,33.76 149.27,33.76 147.94,35.08 147.62,35.08 146.63,36.08 146.63,36.97 146.83,37.17 146.83,38.09 146.75,38.17 146.29,38.17 146.16,38.04 v1(146.16,37.95)
  BOTTOM w0.076: v1(146.16,37.95) v2(146.76,38.55) 146.76,40.65 UCPU1.AV29
  BOTTOM w0.178: UD7.H3 164.47,21.52 v1(164.06,21.93)
DDR_B_D7: length 41.4
  IN1 w0.127: v1(164.12,24.53) 164.12,24.34 164.48,23.98 165.26,23.98 165.38,24.11 165.38,24.35 165.26,24.48 164.71,24.48 164.58,24.6 164.58,24.87 164.71,25 166.53,25 166.65,25.12 166.65,25.37 166.53,25.49 165.51,25.49 165.38,25.62 165.38,28.63 163.78,30.23 163.39,30.23 163.02,29.86 162.2,29.86 161.83,30.23 156.65,30.23 155.43,31.45 153.94,31.45 152.1,33.29 149.23,33.29 147.88,34.64 147.56,34.64 146.26,35.94 146.26,36.78 146.12,36.91 v1(146.12,37.17)
  BOTTOM w0.076: v1(146.12,37.17) 146.09,37.2 v2(145.4,37.2) 145.22,37.2 144.83,37.59 144.83,39.74 145.11,40.02 145.11,40.36 145.04,40.44 145.04,40.59 145.11,40.67 145.11,41.02 145.01,41.13 145.01,41.88 145.27,42.14 UCPU1.AU29
  BOTTOM w0.178: v1(164.12,24.53) 164.66,23.99 UD7.E3
DDR_B_D8: length 38.7
  IN4 w0.127: v4(161.46,24.72) 161.46,24.6 161.59,24.48 161.81,24.48 161.94,24.6 161.94,25.05 161.81,25.17 161.2,25.17 161.08,25.3 161.08,28.91 160.95,29.04 160.01,29.04 159.88,28.91 159.88,25.66 159.76,25.53 159.11,25.53 158.98,25.66 158.98,27.78 159.11,27.91 159.36,27.91 159.49,28.03 159.49,29.02 159.36,29.15 159.07,29.15 158.94,29.02 158.94,28.55 158.82,28.43 158.52,28.43 158.4,28.55 158.4,29.02 158.27,29.15 155.34,29.15 155.21,29.28 155.21,30.01 155.08,30.14 154.8,30.14 154.68,30.01 154.68,29.28 154.55,29.15 154.32,29.15 154.19,29.28 154.19,30.03 154.07,30.16 152.12,30.16 146.59,35.69 146.59,36.43 147.06,36.9 147.06,40.13 v4(147.12,40.19)
DDR_B_D9: length 39.8
  IN4 w0.076: v4(147.12,40.84) 147.08,40.87 147.08,41.35 146.97,41.47 146.56,41.47 146.41,41.32 146.41,41.2
  IN4 w0.127: 146.41,41.2 146.41,40.1 146.8,39.7 146.8,36.97 146.27,36.44 146.27,35.51 151.93,29.84 152.7,29.84 152.82,29.72 152.82,28.92 152.95,28.79 153.18,28.79 153.3,28.92 153.3,29.71 153.43,29.84 153.69,29.84 153.81,29.71 153.81,28.92 153.94,28.79 157.95,28.79 158.08,28.67 158.08,28.24 158.21,28.11 158.6,28.11 158.73,27.98 158.73,27.73 158.6,27.6 158.14,27.6 158.02,27.47 158.02,27.23 158.14,27.11 158.6,27.11 158.73,26.98 158.73,26.74 158.6,26.61 158.13,26.61 158,26.48 158,26.24 158.13,26.11 158.58,26.11 158.7,25.99 158.7,25.76 158.58,25.63 158.17,25.63 158.04,25.5 158.04,25.19 158.17,25.06 160.09,25.06 160.21,25.19 160.21,28.59 160.34,28.72 160.63,28.72 160.76,28.59 160.76,26.42 v4(160.66,26.32)
DDR_B_D10: length 39.6
  IN4 w0.127: v4(148.47,40.19) 148.89,40.19 148.96,40.11 148.96,38.73 149.21,38.48 149.21,38.22 148.96,37.97 148.96,37.71 149.21,37.46 149.21,37.2 148.96,36.95 148.96,36.55 150.05,35.47 150.68,35.47 153.29,32.86 156.33,32.86 157.86,31.33 167.49,31.33 168.12,30.7 169.1,30.7 169.75,30.05 169.75,29.79 169.62,29.67 169.31,29.67 169.18,29.54 169.18,29.29 169.31,29.16 169.62,29.16 169.75,29.03 169.75,28.78 169.62,28.65 169.31,28.65 169.18,28.52 169.18,28.2 169.31,28.07 169.7,28.07 169.83,27.94 169.83,27.7 169.73,27.6 169.29,27.6 168.72,27.02 168.67,27.02 168.53,26.89 166.98,26.89 166.86,26.76 166.86,26.29 166.73,26.17 166.46,26.17 166.33,26.29 166.33,26.94 166.21,27.06 166,27.06 165.88,26.94 165.88,26.46 165.75,26.33 165.48,26.33 165.36,26.46 165.36,27.02 v4(165.46,27.12)
DDR_B_D11: length 39.9
  IN4 w0.076: 148.39,38.37 148.48,38.46 148.48,39.5 148,39.98 148,40.88 148.12,41 148.34,41 148.47,40.88 v4(148.47,40.84)
  IN4 w0.127: v4(164.66,27.12) 164.72,27.12 164.85,27.25 164.85,27.52 164.96,27.63 164.96,28.43 165.05,28.52 166.4,28.52 166.77,28.14 166.77,27.77 166.9,27.64 167.15,27.64 167.28,27.77 167.28,28.13 167.41,28.25 167.66,28.25 167.79,28.13 167.79,27.84 167.96,27.67 168.19,27.67 168.54,28.02 168.54,28.84 168.42,28.96 168.29,28.96 168.17,29.09 168.17,29.34 168.29,29.47 168.42,29.47 168.54,29.6 168.54,29.92 168.4,30.07 167.86,30.07 167.23,30.7 157.59,30.7 156.07,32.22 155.08,32.22 154.67,31.8 154.47,31.8 154.09,32.18 153.2,32.18 152.89,31.87 152.68,31.87 152.35,32.2 152.35,32.38 152.5,32.53 152.5,32.71 152.32,32.89 152.14,32.89 151.99,32.74 151.81,32.74 151.63,32.92 151.63,33.1 151.79,33.25 151.79,33.43 151.61,33.61 151.43,33.61 151.27,33.46 151.09,33.46 150.91,33.64 150.91,33.82 151.07,33.97 151.07,34.15 150.89,34.33 150.71,34.33 150.55,34.18 150.37,34.18 148.39,36.16 148.39,38.37
DDR_B_D12: length 40.5
  IN4 w0.076: v4(148.05,41.49) 148.38,41.15 148.54,41.15 148.76,40.94 148.76,40.58 148.68,40.5 148.3,40.5 148.2,40.4 148.2,40 148.64,39.55 148.64,38.26
  IN4 w0.127: v4(164.66,25.52) 164.66,25.28 164.79,25.15 164.98,25.15 165.1,25.28 165.1,27.28 165.26,27.44 165.26,27.87 165.38,27.99 166.22,27.99 166.35,27.87 166.35,27.28 166.47,27.16 168.15,27.16 168.86,27.87 168.86,29.67 169.12,29.93 169.12,30.23 168.96,30.38 167.99,30.38 167.36,31.02 157.73,31.02 156.2,32.54 153.16,32.54 150.53,35.16 149.86,35.16 148.64,36.38 148.64,38.26
  BOTTOM w0.076: UCPU1.AV27 v4(148.05,41.49)
DDR_B_D13: length 41
  IN4 w0.127: v4(146.78,41.16) 146.61,41 146.61,40.39 146.69,40.31 146.83,40.31 147.01,40.49 147.28,40.49 147.41,40.36 147.41,39.92 147.33,39.84 147.33,38.97 147.55,38.75 147.55,38.2 147.33,37.99 147.33,36.78 146.89,36.34 146.89,35.9 152.31,30.48 155.43,30.48 155.55,30.35 155.55,29.59 155.68,29.47 155.91,29.47 156.04,29.59 156.04,30.18 156.16,30.31 156.27,30.31 156.52,30.06 156.52,29.59 156.64,29.47 160.2,29.47 160.32,29.35 160.58,29.35 160.7,29.47 160.93,29.47 161.04,29.35 161.24,29.35 161.35,29.47 162.81,29.47 162.94,29.34 162.94,29.15 162.81,29.02 161.54,29.02 161.41,28.9 161.41,28.65 161.54,28.53 162.78,28.53 162.91,28.4 162.91,28.21 162.78,28.08 161.54,28.08 161.41,27.96 161.41,27.77 161.54,27.64 162.86,27.64 162.98,27.51 162.98,26.52 162.86,26.39 161.86,26.39 161.74,26.52 161.74,26.71 161.86,26.84 162.49,26.84 162.61,26.96 162.61,27.13 162.49,27.24 161.58,27.24 v4(161.46,27.12)
  BOTTOM w0.076: UCPU1.AU27 147.22,42.08 146.64,41.5 146.64,41.23 146.7,41.16 v4(146.78,41.16)
DDR_B_D14: length 41.7
  IN4 w0.127: v4(148.47,41.49) 150.04,39.91 150.04,36.07 150.29,35.82 150.77,35.82 153.42,33.17 156.46,33.17 157.99,31.65 167.62,31.65 168.25,31.02 169.23,31.02 170.14,30.1 170.14,26.36 170.02,26.23 169.7,26.23 169.58,26.36 169.58,26.94 169.46,27.05 169.2,27.05 169.07,26.93 169.07,26.71 168.94,26.58 168.69,26.58 168.68,26.57 167.49,26.57 166.84,25.92 166.84,24.87 166.72,24.74 166.41,24.74 166.33,24.82 166.33,25.41 166.21,25.54 166,25.54 165.88,25.41 165.88,24.87 165.75,24.74 165.48,24.74 165.36,24.87 165.36,25.42 v4(165.46,25.52)
DDR_B_D15: length 41.1
  IN4 w0.076: 146.17,36.7 146.55,37.07 146.55,39.71 146.17,40.09 146.17,41.43 146.38,41.65 147.15,41.65 147.88,42.38 148.22,42.38 v4(148.47,42.14)
  IN4 w0.127: v4(160.66,25.52) 160.66,24.93 160.53,24.81 158.41,24.81 158.28,24.68 158.28,23.84 158.16,23.71 157.86,23.71 157.74,23.84 157.74,28.32 157.61,28.45 157.33,28.45 157.2,28.32 157.2,24.4 157.08,24.27 156.81,24.27 156.68,24.4 156.68,28.35 156.56,28.48 152.8,28.48 145.93,35.35 145.93,36.45 146.17,36.7
DDR_B_D16: length 43.9
  IN1 w0.127: v1(149.49,21.92) 149.49,21.66 149.64,21.51 149.82,21.51 150.14,21.83 150.14,22.39 149.93,22.6 149.93,22.89 149.65,23.17 148.58,23.17 147.86,22.44 146.65,22.44 146.37,22.16 146.37,20.69 146.24,20.56 145.28,20.56 145.15,20.69 145.15,25.17 144.85,25.48 144.85,27.11 139.8,32.15 139.8,36.58 139.93,36.71 140.36,36.71 140.49,36.83 140.49,42.05 141.05,42.61 141.41,42.61 141.81,43.01 141.81,46.28 142.14,46.61 144.38,46.61 145.11,45.88 145.11,45.72 v1(145.59,45.25)
  BOTTOM w0.076: UCPU1.AM29 v1(145.59,45.25)
  BOTTOM w0.178: v1(149.49,21.92) 149.1,21.53 UD6.H8
DDR_B_D17: length 44.7
  IN1 w0.127: v1(145.67,46.78) 145.08,47.37 142.89,47.37 142.44,46.92 141.93,46.92 141.75,46.74 141.21,46.74 140.9,46.43 140.9,42.96 140.34,42.4 139.82,42.4 139.49,42.07 139.49,32.02 144.56,26.95 144.56,25.22 144.83,24.95 144.83,19.59 144.96,19.46 145.75,19.46 145.88,19.59 145.88,20.11 146,20.23 146.17,20.23 146.29,20.11 146.29,19.42 146.42,19.29 146.74,19.29 146.87,19.42 146.87,21.35 147.06,21.54 148.09,21.54 148.3,21.76 148.3,22.28 v1(148.73,22.71)
  BOTTOM w0.076: v1(145.67,46.78) 145.9,46.55 UCPU1.AK29
  BOTTOM w0.178: v1(148.73,22.71) 149.1,23.08 UD6.F8
DDR_B_D18: length 44.9
  IN1 w0.102: v1(146.64,45.56) 146.87,45.56 147.2,45.23 147.2,43.89 147.32,43.77 147.67,43.77 147.79,43.64 147.79,43.49 147.67,43.36 147.32,43.36 147.2,43.23 147.2,40.95 146.45,40.2 144.08,40.2 143.75,39.87 143.75,38.73 143.53,38.5 143.53,36.02
  IN1 w0.127: 143.53,36.02 143.53,35.51 143.45,35.44 143.45,34.26 147.67,30.04 150.38,30.04 150.8,29.63 150.8,29.27 150.89,29.18 151.25,29.18 151.58,28.84 151.58,28.35 151.68,28.25 153.81,28.25 153.94,28.12 153.94,27.92 153.81,27.79 151.67,27.79 151.54,27.66 151.54,27.45 151.67,27.32 153.79,27.32 153.92,27.19 153.92,26.89 153.79,26.76 153.02,26.76 152.89,26.64 152.89,26.41 153.02,26.28 154.56,26.28 154.69,26.15 154.69,25.86 154.56,25.73 153.62,25.73 153.49,25.61 153.49,24.87 153.62,24.74 154.6,24.74 154.73,24.62 154.73,24.12 154.5,23.89 153.6,23.89 153.49,23.79 v1(153.49,23.54)
  BOTTOM w0.076: v1(146.64,45.56) 146.98,45.9 UCPU1.AL28
  BOTTOM w0.178: v1(153.49,23.54) 153.49,23.51 153.88,23.12 UD6.F2
DDR_B_D19: length 44.7
  IN1 w0.102: 143.83,35.4 143.83,36.19 143.72,36.3 143.72,38.44 143.93,38.65 143.93,39.8 144.15,40.02 146.52,40.02 147.97,41.47 147.97,44.86 v1(146.62,46.21)
  IN1 w0.127: v1(153.49,22.68) 154.63,22.68 154.79,22.85 154.79,23.03 154.66,23.16 154.04,23.16 153.91,23.28 153.91,23.5 154.04,23.63 154.61,23.63 155.02,24.03 155.3,24.03 156.02,23.31 156.2,23.31 156.39,23.5 156.39,23.68 155.67,24.4 155.67,24.9 155.54,25.02 153.88,25.02 153.75,25.15 153.75,25.35 153.88,25.48 155.54,25.48 155.67,25.61 155.67,26.85 153.94,28.57 152.36,28.57 150.53,30.4 147.82,30.4 143.82,34.4 143.82,35.39 143.83,35.4
  BOTTOM w0.076: v1(146.62,46.21) 146.97,46.55 UCPU1.AK28
  BOTTOM w0.178: UD6.G2 153.86,22.32 v1(153.49,22.68)
DDR_B_D20: length 42
  IN1 w0.127: v1(145.57,43.27) 145.57,43.62 145.44,43.74 144.82,43.74 144.69,43.62 144.69,42.79 144.57,42.66 142.8,42.66 142.54,42.41 141.81,42.41 141.6,42.21 141.3,42.21 141.04,41.94 141.04,36.73 140.53,36.22 140.53,32.32 143.5,29.35 143.83,29.35 144.64,30.16 144.82,30.16 145.59,29.4 145.59,29.22 144.81,28.44 144.81,28.15 145.65,27.31 145.65,25.74 146.21,25.19 147.28,25.19 147.41,25.06 147.41,24.81 147.28,24.68 146.48,24.68 146.36,24.55 146.36,24.27 146.48,24.15 147.09,24.15 147.22,24.02 147.22,23.77 147.09,23.64 146.55,23.64 146.42,23.51 146.42,23.19 146.55,23.07 147.74,23.07 148.55,23.88 149.75,23.88 149.89,24.02 150.64,24.02 151.03,23.63 151.03,22.88 150.85,22.7 v1(150.43,22.7)
  BOTTOM w0.076: v1(145.57,43.27) 145.59,43.3 UCPU1.AR29
  BOTTOM w0.178: UD6.H7 149.91,21.52 150.43,22.04 v1(150.43,22.7)
DDR_B_D21: length 43
  IN1 w0.127: v1(145.59,44.6) 145.58,44.61 143.41,44.61 143.38,44.58 142.86,44.58 142.69,44.4 142.69,42.84 142.46,42.61 141.72,42.61 141.52,42.41 141.13,42.41 140.79,42.07 140.79,41.07 140.76,41.03 140.76,36.8 140.17,36.21 140.17,32.24 143.69,28.72 143.83,28.72 144.73,29.62 144.91,29.62 145.11,29.42 145.11,29.24 144.28,28.4 144.28,28.13 145.33,27.08 145.33,25.61 146.04,24.9 146.04,24.39 145.91,24.26 145.61,24.26 145.48,24.13 145.48,23.9 145.61,23.78 145.91,23.78 146.04,23.65 146.04,23.41 145.91,23.28 145.62,23.28 145.49,23.16 145.49,21.01 145.62,20.88 145.85,20.88 145.98,21.01 145.98,22.69 146.1,22.81 147.86,22.81 148.47,23.42 149.81,23.42 150.08,23.16 150.25,23.16 150.37,23.27 150.37,23.51 v1(150.33,23.56)
  BOTTOM w0.076: UCPU1.AN29 v1(145.59,44.6)
  BOTTOM w0.178: v1(150.33,23.56) 149.9,23.13 UD6.F7
DDR_B_D22: length 41.2
  IN1 w0.102: 142.73,36.42 143.16,36.85 143.16,38.64 143.4,38.87 143.4,40.02 143.93,40.55 146.1,40.55 146.51,40.96 v1(146.51,42.99)
  IN1 w0.127: v1(152.66,24.32) 152.66,24.43 151.94,25.15 150.42,25.15 150.09,25.48 149.11,25.48 148.99,25.61 148.99,25.82 149.11,25.95 149.96,25.95 150.09,26.08 150.09,26.28 149.96,26.41 149.13,26.41 149,26.53 149,26.79 149.13,26.91 149.96,26.91 150.09,27.04 150.09,27.3 149.96,27.42 149.1,27.42 148.97,27.55 148.97,27.79 149.1,27.92 149.96,27.92 150.09,28.04 150.09,28.24 149.96,28.36 149.2,28.36 149.08,28.49 149.08,28.74 149.2,28.87 149.9,28.87 150.03,29 150.03,29.2 149.9,29.33 147.38,29.33 143.25,33.46 142.46,33.46 142.33,33.33 142.33,32.78 142.2,32.66 141.93,32.66 141.8,32.78 141.8,33.8 141.93,33.93 142.64,33.93 142.76,34.05 142.76,34.23 142.64,34.36 142.19,34.36 142.07,34.48 142.07,34.69 142.19,34.81 142.6,34.81 142.73,34.94 142.73,36.42
  BOTTOM w0.076: UCPU1.AR28 146.81,43.3 v1(146.51,42.99)
  BOTTOM w0.178: UD6.E3 153.06,23.92 v1(152.66,24.32)
DDR_B_D23: length 42.9
  IN1 w0.102: 143.1,35.78 143.34,36.02 143.34,38.56 143.57,38.8 143.57,39.94 144.01,40.38 146.38,40.38 146.9,40.9 146.9,43.49 v1(146.57,43.82)
  IN1 w0.127: 143.1,35.78 143.1,34.11 147.53,29.69 150.22,29.69 150.35,29.56 150.35,28.98 150.47,28.86 151.09,28.86 151.22,28.73 151.22,28.44 151.09,28.31 150.51,28.31 150.38,28.18 150.38,27.93 150.51,27.8 151.13,27.8 151.26,27.68 151.26,27.38 151.13,27.26 150.51,27.26 150.38,27.13 150.38,26.84 150.51,26.71 151.13,26.71 151.26,26.58 151.26,26.31 151.13,26.18 150.5,26.18 150.37,26.05 150.37,25.58 150.5,25.45 151.53,25.45 151.65,25.58 151.65,26.91 151.78,27.04 152,27.04 152.12,26.91 152.12,25.58 152.25,25.45 152.54,25.45 152.67,25.58 152.67,25.89 152.8,26.01 153.04,26.01 153.16,25.89 153.16,24.3 153.06,24.2 153.06,22.53 152.94,22.41 152.2,22.41 152.07,22.28 152.07,22.11 152.2,21.99 v1(152.45,21.99)
  BOTTOM w0.076: UCPU1.AP28 146.7,43.95 v1(146.57,43.82)
  BOTTOM w0.178: UD6.H3 152.92,21.52 v1(152.45,21.99)
DDR_B_D24: length 42.5
  IN4 w0.127: v4(148,44.6) 147.88,44.72 147.13,44.72 147.01,44.85 147.01,45.75 146.99,45.76 146.99,46.44 146.82,46.61 146.4,46.61 146.17,46.38 145.54,46.38 145.21,46.71 144,46.71 143.86,46.57 142.6,46.57 142.47,46.7 142.47,47.03 142.34,47.16 141.95,47.16 141.82,47.03 141.82,42.74 141.7,42.61 140.73,42.61 140.6,42.48 140.6,36.24 141.32,35.53 141.32,34.98 141.02,34.69 141.02,32.46 146.41,27.08 146.41,26 146.54,25.87 147.33,25.87 147.45,25.75 147.45,25.42 147.33,25.29 146.48,25.29 146.36,25.16 146.36,24.8 146.48,24.68 148.4,24.68 148.53,24.8 148.53,26.66 148.66,26.79 149.45,26.79 149.58,26.66 149.58,26.45 149.45,26.32 v4(149.1,26.32)
DDR_B_D25: length 41.8
  IN4 w0.127: v4(149.9,27.12) 148.39,27.12 148.26,26.99 148.26,26.47 148.14,26.35 146.94,26.35 146.8,26.48 146.8,27.13 141.34,32.59 141.34,34.56 141.63,34.85 141.63,35.56 140.88,36.31 140.88,36.86 141.01,36.99 141.49,36.99 141.62,37.11 141.62,37.35 141.49,37.48 141.01,37.48 140.88,37.61 140.88,42.18 141.01,42.31 142.16,42.31 142.76,42.91 142.76,44.45 142.89,44.58 143.63,44.58 143.75,44.45 143.75,43.08 143.88,42.95 144.44,42.95 144.57,43.08 144.57,46.32 144.7,46.45 145.01,46.45 145.14,46.32 145.14,43.77 145.27,43.64 145.56,43.64 145.68,43.77 145.68,44.18 145.81,44.3 146.08,44.3 146.21,44.18 146.21,43.58 146.33,43.45 146.98,43.45 147.11,43.58 147.11,43.86 147.23,43.99 147.5,43.99 147.63,43.86 v4(147.63,43.77)
  BOTTOM w0.076: v4(147.63,43.77) 147.63,43.67 UCPU1.AR26
DDR_B_D26: length 41.2
  IN4 w0.076: v4(148.96,43.3) 148.68,43.3 148.34,42.95 147.74,42.95 146.9,42.12 145.84,42.12 145.74,42.01 144.97,42.01 144.69,41.74
  IN4 w0.127: v4(153.1,25.52) 153.1,25.74 153.23,25.86 154.12,25.86 154.24,25.74 154.24,25.04 154.37,24.92 155.52,24.92 155.65,24.79 155.65,23.54 155.77,23.41 156.11,23.41 156.24,23.54 156.24,26.08 156.11,26.2 155.77,26.2 155.64,26.08 155.64,25.58 155.51,25.45 154.82,25.45 154.69,25.58 154.69,26.16 154.56,26.29 153.71,26.29 153.58,26.42 153.58,26.65 153.46,26.77 153.29,26.77 153.17,26.65 153.17,26.42 153.04,26.29 152.76,26.29 152.63,26.16 152.63,25.56 152.5,25.43 152.26,25.43 152.14,25.56 152.14,26.97 150.47,28.64 149.53,28.64 144.24,33.92 144.24,35.44 143.46,36.22 143.46,36.55 143.81,36.9 143.81,41.61 143.93,41.74 144.69,41.74
DDR_B_D27: length 41.7
  IN4 w0.076: 144.44,42.01 144.59,42.17 145.65,42.17 145.75,42.27 146.84,42.27 147.68,43.11 148.28,43.11 148.96,43.79 148.96,43.94 v4(148.96,43.95)
  IN4 w0.127: v4(153.9,25.52) 153.9,25.31 153.77,25.19 153.2,25.19 153.08,25.06 153.08,24.91 153.2,24.78 153.78,24.78 153.9,24.65 153.9,24.48 153.78,24.35 153.19,24.35 153.08,24.23 153.08,24.07 153.19,23.96 153.83,23.96 153.9,23.88 154.61,23.88 154.74,23.75 154.74,23.24 154.61,23.12 152.85,23.12 152.72,22.99 152.72,22.58 152.59,22.46 152.39,22.46 152.26,22.58 152.26,23.49 152.14,23.62 151.96,23.62 151.83,23.74 151.83,24.04 151.96,24.17 152.11,24.17 152.24,24.3 152.24,24.63 152.11,24.76 151.96,24.76 151.83,24.88 151.83,26.82 150.34,28.32 149.4,28.32 143.93,33.79 143.93,35.35 143.17,36.11 143.17,36.77 143.3,36.9 143.46,36.9 143.59,37.02 143.59,37.21 143.46,37.34 143.3,37.34 143.17,37.47 143.17,37.7 143.3,37.82 143.44,37.82 143.56,37.95 143.56,38.13 143.44,38.26 142.8,38.26 142.67,38.38 142.67,38.65 142.8,38.78 143.36,38.78 143.49,38.9 143.49,41.89 143.61,42.01 144.44,42.01
DDR_B_D28: length 43.9
  IN4 w0.076: v4(148,46.55) 148,46.54 148.13,46.41 148.69,46.41 148.82,46.28 148.82,45.77 148.95,45.65 149.34,45.65 149.47,45.52 149.47,42.78 149.34,42.65 147.87,42.65 147.02,41.8 146.09,41.8 146.03,41.74
  IN4 w0.127: 146.03,41.74 145.93,41.63 145.93,40.01 145.66,39.74 145.66,35 147.77,32.89 147.77,32.71 147.15,32.09 147.15,31.91 147.33,31.73 147.51,31.73 148.13,32.35 148.31,32.35 148.49,32.17 148.49,31.99 147.87,31.37 147.87,31.19 148.05,31.01 148.23,31.01 148.85,31.63 149.03,31.63 149.21,31.45 149.21,31.27 148.59,30.65 148.59,30.47 148.77,30.29 148.95,30.29 149.57,30.91 149.75,30.91 149.93,30.73 149.93,30.55 149.31,29.93 149.31,29.75 149.49,29.57 149.67,29.57 150.29,30.19 150.47,30.19 150.65,30.01 150.65,29.83 150.45,29.63 150.45,29.45 150.63,29.27 150.81,29.27 151.01,29.47 151.19,29.47 151.37,29.29 151.37,29.11 151.25,29 151.25,28.82 151.43,28.64 151.61,28.64 151.73,28.75 151.91,28.75 152.09,28.57 152.09,28.39 151.94,28.25 151.94,28.07 152.12,27.89 152.3,27.89 152.46,28.04 153.05,28.04 153.18,27.92 153.18,27.54 153.3,27.41 153.51,27.41 153.63,27.54 153.63,27.92 153.76,28.04 155.9,28.04 156.02,27.92 156.02,26.6 155.9,26.47 155.67,26.47 155.54,26.6 155.54,27.08 155.41,27.21 153.98,27.21 v4(153.9,27.12)
DDR_B_D29: length 44.8
  IN4 w0.127: v4(148,45.25) 147.21,46.04 147.21,46.51 146.9,46.82 146.27,46.82 145.82,47.26 143.7,47.26 143.53,47.44 141.38,47.44 140.95,47.01 140.95,43.21 140.35,42.61 140.35,35.22 140.71,34.86 140.71,32.33 145.56,27.48 145.56,27.16 145.68,27.03 145.96,27.03 146.09,26.9 146.09,26.64 145.96,26.51 145.62,26.51 145.49,26.38 145.49,26.2 145.62,26.08 145.97,26.08 146.1,25.95 146.1,25.71 145.97,25.58 145.62,25.58 145.49,25.45 145.49,25.27 145.62,25.15 145.93,25.15 146.05,25.02 146.05,24.39 146.18,24.26 147.16,24.26 147.28,24.13 147.28,23.83 147.16,23.7 145.62,23.7 145.49,23.57 145.49,23.3 145.62,23.17 148.1,23.17 149.05,24.12 149.05,25.47 v4(149.1,25.52)
DDR_B_D30: length 44.1
  IN4 w0.127: v4(148.96,46.55) 148.43,47.07 146.37,47.07 145.93,47.51 144.21,47.51 144.04,47.68 140.2,47.68 139.83,47.31 139.83,46.24 140.16,45.91 140.16,45.36 139.35,44.54 139.35,43.47 139.31,43.44 139.31,37.17 139.96,36.52 139.96,35.17 140.39,34.73 140.39,32.2 145.18,27.41 145.18,25.96 145.05,25.84 144.72,25.84 144.59,25.71 144.59,25.5 144.72,25.38 145.05,25.38 145.18,25.25 145.18,22.91 145.28,22.81 148.15,22.81 149.06,23.72 149.85,23.72 149.99,23.86 149.99,24.63 v4(149.9,24.72)
DDR_B_D31: length 44.3
  IN4 w0.076: v4(148.54,46.05) 148.22,46.05 148.1,45.93 148.1,45.53 148.22,45.41 149.19,45.41 149.32,45.28 149.32,42.93 149.19,42.8 147.81,42.8 146.97,41.96 145.94,41.96 145.84,41.86 145.3,41.86 145.13,41.68
  IN4 w0.127: v4(153.1,27.12) 152.84,27.38 152.17,27.38 150.6,28.95 149.66,28.95 146.62,32 146.62,32.18 147.23,32.8 147.23,32.98 147.06,33.16 146.88,33.16 146.26,32.54 146.08,32.54 145.9,32.72 145.9,32.9 146.52,33.52 146.52,33.7 146.34,33.87 146.16,33.87 145.54,33.26 145.36,33.26 145.1,33.51 145.1,33.66 145.74,34.29 145.74,34.47 145.55,34.66 145.37,34.66 144.88,34.17 144.7,34.17 144.56,34.31 144.56,34.49 144.95,34.88 144.95,35 144.82,35.13 144.61,35.13 144.48,35.26 144.48,35.45 144.61,35.58 145.21,35.58 145.34,35.7 145.34,35.96 145.21,36.08 144,36.08 143.87,36.21 143.87,36.47 144,36.59 145.29,36.59 145.42,36.72 145.42,37 145.29,37.13 144.91,37.13 144.78,37.25 144.78,39.82 144.57,40.03 144.17,40.03 144.05,40.16 144.05,40.4 144.17,40.53 145.06,40.53 145.19,40.4 145.19,40.09 145.32,39.96 145.53,39.96 145.66,40.09 145.66,40.9 145.53,41.02 144.14,41.02 144.01,41.15 144.01,41.35 144.14,41.48 144.92,41.48 145.13,41.68
  BOTTOM w0.076: UCPU1.AL25 148.7,45.9 v4(148.54,46.05)
DDR_B_D32: length 39.4
  IN1 w0.127: v1(174.14,21.91) 173.33,22.71 173.33,22.88 168.95,27.26 168.71,27.26 168.07,27.9 167.86,27.9 167.38,28.38 167.38,28.59 164.36,31.61 157.22,31.61 155.96,32.87 154.52,32.87 152.57,34.83 149.95,34.83 147.87,36.91 147.87,38.17 148.14,38.43 149.03,38.43 149.58,37.88 v1(149.58,37.79)
  BOTTOM w0.076: v1(149.58,37.79) 149.79,37.79 150.02,38.01 150.02,39.99 UCPU1.AY23
  BOTTOM w0.183: v1(174.14,21.91) 174.11,21.91 173.74,21.54 UD9.H8
DDR_B_D33: length 40.2
  IN1 w0.127: v1(149.58,38.4) 149.93,38.4 150.02,38.32 150.02,36.96 150.22,36.76 150.22,36.5 149.78,36.07 149.78,35.89 149.97,35.71 150.15,35.71 150.28,35.85 150.46,35.85 150.94,35.37 153.06,35.37 154.93,33.51 156.23,33.51 156.56,33.17 159.19,33.17 160.11,32.25 164.62,32.25 167.5,29.37 168.58,29.37 169.95,27.99 169.95,27.93 169.66,27.64 169.66,27.45 169.84,27.27 170.02,27.27 170.23,27.47 170.41,27.47 170.59,27.3 170.59,27.12 170.38,26.91 170.38,26.73 170.56,26.55 170.74,26.55 171.04,26.85 171.22,26.85 171.4,26.67 171.4,26.49 171.1,26.19 171.1,26.01 171.97,25.15 173.21,25.15 173.64,24.72 173.64,24.02 174.2,23.46 v1(175.07,23.46)
  BOTTOM w0.076: UCPU1.AW23 149.82,40.59 149.55,40.32 149.55,40.08 149.86,39.76 149.86,38.6 149.67,38.4 v1(149.58,38.4)
  BOTTOM w0.178: v1(175.07,23.46) 174.85,23.46 174.54,23.14 UD9.F7
DDR_B_D34: length 39.4
  IN1 w0.127: v1(177.06,21.95) 177.66,22.55 177.66,23.75 177.74,23.83 177.74,25.59 173.82,29.52 171.9,29.52 171.73,29.68 171.73,30.71 171.61,30.84 169.82,30.84 169.4,31.26 168.22,31.26 165.39,34.1 162.1,34.1 161.56,34.64 160.38,34.64 160,35.02 158.72,35.02 158.07,35.67 155.34,35.67 153.57,37.44 v1(151.64,37.44)
  BOTTOM w0.076: v1(151.64,37.44) 151.25,37.84 v2(151.25,38.26) 151.25,38.9 151.33,38.98 151.33,39.85 151.23,39.95 151.23,40.12 UCPU1.AY21
  BOTTOM w0.178: UD9.H3 177.31,21.95 177.07,21.95 v1(177.06,21.95)
DDR_B_D35: length 40.5
  IN1 w0.127: v1(151.68,39.2) 151.68,39.18 152.17,38.69 153.15,38.69 155.53,36.3 158.33,36.3 158.98,35.66 160.27,35.66 160.65,35.28 161.84,35.28 162.39,34.73 165.65,34.73 168.49,31.9 169.75,31.9 170.14,31.51 172.76,31.51 178.48,25.8 178.48,25.43 178.6,25.3 179.01,25.3 179.14,25.17 179.14,24.91 179.01,24.78 178.53,24.78 178.41,24.65 178.41,23.94 178.53,23.82 179.07,23.82 179.2,23.69 179.2,23.25 179.07,23.12 178.28,23.12 178.15,22.99 v1(178.15,22.73)
  BOTTOM w0.076: UCPU1.AW21 151.17,40.77 151.44,40.5 151.44,39.96 151.68,39.72 v1(151.68,39.2)
  BOTTOM w0.178: UD9.G2 178.15,22.71 v1(178.15,22.73)
DDR_B_D36: length 41.8
  IN1 w0.127: v1(175.07,22.06) 175.77,22.06 175.9,22.19 175.9,23.77 175.77,23.89 174.73,23.89 174.6,24.02 174.6,24.96 172.98,26.58 172.98,27.55 172.6,27.93 170.53,27.93 168.77,29.69 167.63,29.69 164.75,32.57 161.41,32.57 160.87,33.11 159.7,33.11 159.32,33.49 156.7,33.49 156.36,33.82 155.09,33.82 153.25,35.66 151.22,35.66 150.6,36.29 150.6,36.93 150.24,37.29 150.24,39.17 150.12,39.3 149.62,39.3 149.49,39.17 v1(149.49,39.01)
  BOTTOM w0.076: v1(149.49,39.01) 149.51,39.01 149.56,39.01 149.71,39.16 149.71,39.7 149.38,40.03 149.38,40.36 149.48,40.47 149.48,40.94 149.82,41.27 UCPU1.AV23
  BOTTOM w0.183: v1(175.07,22.06) 175.06,22.06 175.06,22.04 UD9.H7
DDR_B_D37: length 42
  IN1 w0.127: v1(149.58,37.18) 148.81,37.95 148.41,37.95 148.23,37.77 148.23,37.47 148.46,37.24 148.81,37.24 148.94,37.12 148.94,36.89 148.81,36.76 148.81,36.43 150.11,35.13 152.8,35.13 154.74,33.19 156.09,33.19 157.35,31.93 164.49,31.93 167.76,28.66 167.92,28.66 168.27,29.01 168.45,29.01 168.63,28.82 168.63,28.65 168.4,28.41 168.4,28.2 168.54,28.05 168.75,28.05 168.99,28.29 169.17,28.29 169.35,28.11 169.35,27.93 169.13,27.71 169.13,27.53 171.77,24.89 172.95,24.89 173.35,24.5 v1(173.35,23.52)
  BOTTOM w0.076: v1(149.58,37.18) 149.77,37.18 150.17,37.58 150.17,40.12 150.08,40.21 150.08,40.3 150.05,40.33 150.05,40.69 150.09,40.73 150.09,40.94 150.06,40.97 150.06,41.35 150.1,41.39 150.1,41.61 149.82,41.89 UCPU1.AU23
  BOTTOM w0.178: v1(173.35,23.52) 173.74,23.13 UD9.F8
DDR_B_D38: length 40.3
  IN1 w0.127: v1(178.15,23.52) 178.15,25.65 173.95,29.85 173.23,29.85 173.1,29.98 173.1,30.71 172.98,30.84 172.72,30.84 172.6,30.71 172.6,29.98 172.47,29.85 172.2,29.85 172.08,29.98 172.08,31.05 171.95,31.18 169.99,31.18 169.59,31.58 168.35,31.58 165.52,34.41 162.24,34.41 161.69,34.96 160.52,34.96 160.14,35.34 158.85,35.34 158.2,35.99 155.4,35.99 153.33,38.06 152.22,38.06 v1(151.65,38.62)
  BOTTOM w0.076: UCPU1.AV21 151.52,41.03 151.52,40.64 151.59,40.57 151.59,40.25 152.03,39.81 152.03,39.01 v1(151.65,38.62)
  BOTTOM w0.178: v1(178.15,23.52) 178.54,23.14 UD9.F2
DDR_B_D39: length 41.2
  IN1 w0.127: v1(177.22,24.52) 176.86,24.87 176.86,26.01 173.69,29.19 171.5,29.19 171.38,29.31 171.38,30.38 171.25,30.51 170.97,30.51 170.84,30.38 170.84,29.9 170.72,29.77 170.44,29.77 170.31,29.9 170.31,30.38 170.18,30.51 169.7,30.51 169.26,30.94 168.09,30.94 165.26,33.78 161.97,33.78 161.43,34.33 160.25,34.33 159.87,34.71 158.59,34.71 157.94,35.35 155.28,35.35 153.82,36.81 v1(151.65,36.81)
  BOTTOM w0.076: UCPU1.AU21 150.4,42.14 150.21,41.95 150.21,41.73 150.25,41.69 150.25,41.33 150.21,41.29 150.21,41.04 150.25,41 150.25,40.67 150.2,40.62 150.2,40.4 150.24,40.36 150.24,40.27 150.32,40.19 150.32,37.2 150.47,37.05 151.41,37.05 v1(151.65,36.81)
  BOTTOM w0.178: UD9.E3 177.74,23.99 v1(177.22,24.52)
DDR_B_D40: length 40.5
  IN4 w0.127: v4(152.25,40.19) 152.25,40.18 152.25,39.69 152.38,39.56 152.38,36.47 154.25,34.6 157.34,34.6 157.58,34.35 159.6,34.35 160.91,33.03 168.19,33.03 168.79,32.43 170.1,32.43 171.53,31 171.53,30.6 171.76,30.37 172.95,30.37 173.18,30.14 174.56,30.14 174.68,30.01 174.68,29.71 174.56,29.58 173.22,29.58 173.09,29.45 173.09,29.17 173.22,29.04 174.95,29.04 175.07,28.91 175.07,28.66 174.95,28.53 173.22,28.53 173.09,28.4 173.09,28.13 173.22,28.01 175.12,28.01 175.25,27.88 175.25,27.7 175.12,27.57 174.16,27.57 174.02,27.42 174.02,27.2 174.1,27.12 v4(174.54,27.12)
DDR_B_D41: length 41.9
  IN4 w0.127: v4(173.74,26.32) 173.54,26.32 173.41,26.19 173.41,25.62 173.28,25.49 173.1,25.49 172.89,25.71 172.89,26.21 172.88,26.21 172.88,26.66 173.01,26.79 173.56,26.79 173.69,26.92 173.69,27.17 173.56,27.3 173.01,27.3 172.88,27.42 172.88,27.85 172.75,27.98 171.34,27.98 171.21,28.11 171.21,28.36 171.34,28.49 172.65,28.49 172.77,28.62 172.77,28.87 172.65,29 171.34,29 171.21,29.12 171.21,29.38 171.34,29.51 172.65,29.51 172.77,29.63 172.77,29.89 172.65,30.01 171.34,30.01 171.21,30.14 171.21,30.87 169.96,32.12 168.66,32.12 168.06,32.72 160.78,32.72 159.46,34.03 157.45,34.03 157.24,34.24 154.1,34.24 152.07,36.27 152.07,39.37 151.54,39.91 151.54,40.48 151.9,40.84 v4(152.25,40.84)
DDR_B_D42: length 38.8
  IN4 w0.127: v4(153.6,40.19) 153.6,39.77 154.13,39.24 154.13,37.43 155.24,36.33 157.77,36.33 158.2,35.9 160.25,35.9 161.58,34.56 168.83,34.56 169.43,33.96 174.66,33.96 175.46,33.17 175.46,32.96 175.58,32.83 176.52,32.83 176.65,32.71 176.65,32.53 176.52,32.41 175.64,32.41 175.52,32.28 175.52,32.1 175.64,31.97 176.46,31.97 176.63,31.79 177.03,31.79 177.16,31.66 177.16,31.45 177.03,31.32 176.73,31.32 176.6,31.19 176.6,30.9 176.73,30.78 177.05,30.78 177.18,30.65 177.18,26.57 177.31,26.44 177.75,26.44 178.54,25.66 v4(178.54,25.52)
DDR_B_D43: length 39.2
  IN4 w0.127: v4(177.74,27.12) 177.5,27.36 177.5,27.62 177.63,27.74 178.04,27.74 178.17,27.87 178.17,28.12 178.04,28.25 177.63,28.25 177.5,28.38 177.5,28.63 177.63,28.76 178.04,28.76 178.17,28.89 178.17,29.14 178.04,29.27 177.63,29.27 177.5,29.39 177.5,29.77 177.63,29.9 178.09,29.9 178.22,30.02 178.22,30.28 178.09,30.4 177.63,30.4 177.5,30.53 177.5,30.79 177.63,30.91 178.03,30.91 178.17,31.06 178.17,31.27 178.03,31.42 177.63,31.42 177.5,31.55 177.5,32.31 176.24,33.56 176.06,33.56 175.88,33.38 175.7,33.38 175.52,33.56 175.52,33.74 175.7,33.92 175.7,34.1 175.52,34.28 169.56,34.28 168.96,34.88 163.93,34.88 163.09,35.72 160.87,35.72 160.38,36.22 158.33,36.22 157.9,36.64 155.31,36.64 154.33,37.62 154.33,39.37 153.89,39.81 153.89,40.54 v4(153.6,40.84)
DDR_B_D44: length 40.3
  IN4 w0.127: v4(152.36,41.49) 151.44,41.49 151.2,41.24 151.2,36.47 153.74,33.92 157.11,33.92 157.32,33.72 159.33,33.72 160.65,32.4 167.93,32.4 168.56,31.77 169.86,31.77 170.89,30.74 170.89,27.84 171.02,27.71 171.86,27.71 171.99,27.59 171.99,27.33 171.86,27.21 171.02,27.21 170.89,27.08 170.89,26.83 171.02,26.7 171.86,26.7 171.99,26.57 171.99,26.32 171.86,26.19 171.02,26.19 170.89,26.06 170.89,25.81 171.01,25.7 172.06,25.7 172.19,25.57 172.19,25.32 172.32,25.19 173.61,25.19 173.74,25.32 v4(173.74,25.52)
DDR_B_D45: length 40.9
  IN4 w0.127: v4(174.54,24.72) 174.54,24.86 174.41,24.98 173.76,24.98 173.63,24.86 173.63,24.51 173.5,24.38 173.25,24.38 173.12,24.51 173.12,24.81 172.99,24.94 172.06,24.94 171.93,24.81 171.93,24.67 171.8,24.54 171.55,24.54 171.42,24.67 171.42,24.81 171.29,24.94 171.19,24.94 170.91,25.21 170.91,25.34 170.58,25.67 170.58,30.61 169.73,31.45 168.43,31.45 167.8,32.08 160.52,32.08 159.2,33.4 157.19,33.4 156.98,33.61 153.6,33.61 150.26,36.95 150.26,41.88 150.51,42.14 v4(152.36,42.14)
DDR_B_D46: length 40.9
  IN4 w0.127: v4(153.6,41.49) 153.6,41.3 154.96,39.94 154.96,37.82 155.74,37.04 157.96,37.04 158.46,36.53 160.51,36.53 161.01,36.04 163.23,36.04 164.07,35.2 169.09,35.2 169.66,34.64 175.82,34.64 178.49,31.97 178.49,30.46 178.54,30.41 178.54,30.26 178.67,30.13 180.01,30.13 180.16,29.98 180.16,29.77 180.01,29.62 178.67,29.62 178.54,29.5 178.54,29.24 178.67,29.12 179.29,29.12 179.42,28.99 179.42,28.73 179.29,28.61 178.67,28.61 178.54,28.48 178.54,28.23 178.67,28.1 179.29,28.1 179.42,27.97 179.42,27.72 179.29,27.59 178.67,27.59 178.54,27.46 v4(178.54,27.12)
DDR_B_D47: length 40.6
  IN4 w0.076: v4(153.6,42.14) 153.41,42.14 153.22,41.94 153.22,39.12 153.46,38.88 153.46,38.52
  IN4 w0.127: v4(177.74,25.52) 177.75,25.52 177.88,25.65 177.88,25.94 177.75,26.06 177.41,26.06 177.28,25.94 177.28,25.68 177.16,25.55 176.97,25.55 176.74,25.78 176.23,25.78 176.11,25.91 176.11,26.16 176.23,26.29 176.74,26.29 176.86,26.41 176.86,30.33 176.74,30.46 176.41,30.46 176.28,30.58 176.28,31.5 176.16,31.63 175.26,31.63 175.14,31.75 175.14,33.03 174.53,33.65 169.3,33.65 168.7,34.25 161.45,34.25 160.12,35.58 158.07,35.58 157.7,35.94 154.83,35.94 153.46,37.32 153.46,38.52
DDR_B_D48: length 49.6
  IN1 w0.127: v1(151.3,42.89) 151.3,42.84 152.3,41.84 154.83,41.84 155.85,40.82 157.69,40.82 160.34,38.16 161.11,38.16 161.51,38.57 164.08,38.57 165.31,37.35 166.73,37.35 169.47,34.6 170.78,34.6 171.21,34.17 173.78,34.17 178.19,29.77 185.68,29.77 188.24,27.21 188.24,25.47 188.37,25.34 188.85,25.34 188.98,25.21 188.98,24.98 188.85,24.86 188.37,24.86 188.24,24.73 188.24,24.46 188.37,24.33 v1(188.8,24.33)
  BOTTOM w0.076: v1(151.3,42.89) 151.3,42.89 UCPU1.AR21
  BOTTOM w0.178: UD10.E3 189.21,23.92 v1(188.8,24.33)
DDR_B_D49: length 50.9
  IN1 w0.127: v1(186.5,21.9) 187.11,22.51 187.11,23.68 186.92,23.87 186.92,24.88 186.13,25.67 186.13,27.53 185.13,28.53 177.71,28.53 173.3,32.95 170.7,32.95 170.32,33.33 169.01,33.33 166.22,36.12 164.17,36.12 163.62,36.66 161.22,36.66 160.84,37.04 159.55,37.04 157.67,38.93 156.31,38.93 154.37,40.87 151.88,40.87 149.96,42.79 149.96,43.22 150.36,43.61 v1(150.36,43.61)
  BOTTOM w0.076: v1(150.36,43.61) 150.44,43.61 UCPU1.AR22
  BOTTOM w0.183: UD10.H7 186.13,21.52 v1(186.5,21.9)
DDR_B_D50: length 52.4
  IN1 w0.127: v1(189.66,22.72) 189.66,22.91 190.08,23.33 190.08,25.09 188.85,26.32 188.85,27.51 185.96,30.4 178.45,30.4 174.05,34.81 171.47,34.81 171.04,35.24 169.74,35.24 166.99,37.98 165.76,37.98 164.29,39.46 159.86,39.46 157.98,41.34 156.87,41.34 155.41,42.8 152.99,42.8 151.69,44.1 151.69,45.08 151.23,45.53 v1(151.23,45.56)
  BOTTOM w0.076: UCPU1.AL21 151.37,45.56 v1(151.23,45.56)
  BOTTOM w0.183: v1(189.66,22.72) 190.06,23.12 UD10.F2
DDR_B_D51: length 52.7
  IN1 w0.127: v1(150.35,45.56) 149.3,44.51 149.3,42.7 151.77,40.23 153.2,40.23 156.36,37.07 158.63,37.07 159.29,36.41 160.58,36.41 160.96,36.03 163.28,36.03 163.83,35.48 165.96,35.48 168.78,32.66 170.06,32.66 170.41,32.31 173.03,32.31 177.52,27.82 184.85,27.82 185.45,27.22 185.45,25.25 186.13,24.57 186.13,22.37 v1(185.68,21.92)
  BOTTOM w0.076: v1(150.35,45.56) 150.66,45.25 UCPU1.AM22
  BOTTOM w0.183: UD10.H8 185.3,21.53 v1(185.68,21.92)
DDR_B_D52: length 52.3
  IN1 w0.127: v1(186.57,23.51) 186.55,23.53 186.55,24.74 185.79,25.49 185.79,27.36 184.98,28.18 177.62,28.18 173.16,32.63 170.55,32.63 170.2,32.98 168.91,32.98 166.09,35.8 164.04,35.8 163.49,36.34 161.09,36.34 160.71,36.73 159.42,36.73 158.48,37.67 157.01,37.67 156.75,37.41 156.57,37.41 156.39,37.59 156.39,37.77 156.65,38.03 156.65,38.21 156.47,38.39 156.29,38.39 156.03,38.13 155.85,38.13 155.67,38.31 155.67,38.49 155.93,38.75 155.93,38.93 154.31,40.55 151.83,40.55 149.6,42.79 149.6,44.17 v1(150.35,44.92)
  BOTTOM w0.076: UCPU1.AN22 150.43,44.92 v1(150.35,44.92)
  BOTTOM w0.178: UD10.F7 186.48,23.51 v1(186.57,23.51)
DDR_B_D53: length 51.7
  IN1 w0.127: v1(151.3,43.63) 151.3,43.44 151.79,42.94 151.79,42.73 152.44,42.08 154.98,42.08 156,41.06 157.83,41.06 159.97,38.92 164.18,38.92 165.44,37.66 166.86,37.66 169.6,34.92 170.91,34.92 171.34,34.49 173.92,34.49 178.32,30.08 185.82,30.08 188.57,27.33 188.57,26.15 189.23,25.49 189.23,22.27 v1(188.65,21.68)
  BOTTOM w0.076: v1(151.3,43.63) 151.39,43.63 UCPU1.AP21
  BOTTOM w0.183: v1(188.65,21.68) 189.14,21.68 UD10.H3
DDR_B_D54: length 54
  IN1 w0.127: v1(152.17,46.12) 152.63,45.66 152.63,44.16 153.78,43.01 155.53,43.01 156.98,41.57 158.11,41.57 159.89,39.79 164.41,39.79 165.89,38.3 167.12,38.3 169.87,35.55 171.18,35.55 171.61,35.13 174.18,35.13 178.59,30.72 186.12,30.72 189.19,27.64 189.19,26.52 190.93,24.78 190.93,23.35 190.72,23.13 190.27,23.13 190.1,22.95 190.1,22.32 v1(189.71,21.92)
  BOTTOM w0.076: UCPU1.AK21 152.14,46.12 v1(152.17,46.12)
  BOTTOM w0.183: v1(189.71,21.92) 190.1,22.32 UD10.G2
DDR_B_D55: length 53.2
  IN1 w0.127: v1(151.21,46.19) 150.36,46.19 149.05,44.89 149.05,42.55 151.64,39.96 152.34,39.96 155.56,36.74 158.51,36.74 159.16,36.09 160.45,36.09 160.83,35.71 163.15,35.71 163.7,35.16 165.83,35.16 168.65,32.34 169.92,32.34 170.27,31.99 172.9,31.99 177.56,27.34 180.87,27.34 181.83,26.37 182.26,26.37 183.38,25.26 183.38,21.83 183.53,21.67 184.09,21.67 184.32,21.9 184.32,22.13 v1(184.91,22.72)
  BOTTOM w0.076: v1(151.21,46.19) 150.85,46.55 UCPU1.AK22
  BOTTOM w0.183: UD10.F8 185.3,23.1 v1(184.91,22.72)
DDR_B_D56: length 45.5
  IN4 w0.076: v4(152.66,44.6) 152.66,43.69 152.99,43.36 152.99,43.16 153.24,42.9 154.14,42.9 154.92,42.13
  IN4 w0.127: v4(185.3,26.32) 185.3,26.47 185.5,26.67 186.32,26.67 186.81,27.16 186.81,27.54 185.04,29.31 183.1,29.31 176.11,36.3 175.35,36.3 175.13,36.08 174.82,36.08 174.58,36.32 174.05,36.32 173.79,36.06 173.55,36.06 173.25,36.36 171.61,36.36 171.31,36.06 170.19,36.06 169.67,36.58 164.7,36.58 163.86,37.42 161.59,37.42 161.08,37.93 159.23,37.93 158.14,39.02 156.89,39.02 156.41,39.51 156.41,40.45 154.92,41.94 154.92,42.13
DDR_B_D57: length 44.3
  IN4 w0.076: v4(152.66,43.3) 152.66,43.1 153.01,42.75 153.91,42.75 154.63,42.03
  IN4 w0.127: 154.63,42.03 154.63,41.72 156.1,40.25 156.1,38.67 156.69,38.08 158.42,38.08 158.9,37.6 160.95,37.6 161.45,37.11 163.73,37.11 164.57,36.27 169.53,36.27 170.06,35.74 171.53,35.74 171.65,35.87 171.65,35.9 171.78,36.03 172.04,36.03 172.16,35.9 172.16,35.87 172.29,35.74 172.54,35.74 172.67,35.87 172.67,35.9 172.8,36.03 173.05,36.03 173.18,35.9 173.18,35.87 173.31,35.74 173.96,35.74 174.08,35.87 174.08,35.87 174.21,36 174.44,36 174.7,35.74 175.24,35.74 175.49,35.99 175.98,35.99 182.97,28.99 184.7,28.99 185.14,28.55 185.14,28.2 185.29,28.05 185.67,28.05 185.85,27.87 185.85,27.64 185.69,27.49 185.35,27.49 185.18,27.33 185.18,27.09 185.35,26.93 185.9,26.93 v4(186.1,27.12)
DDR_B_D58: length 46.6
  IN4 w0.076: 156.36,43.39 156.13,43.39 155.34,44.18 154.6,44.18 153.9,44.88 153.9,46.26 v4(153.61,46.55)
  IN4 w0.127: 156.36,43.39 159.56,40.19 165.63,40.19 167.06,38.76 170.67,38.76 170.9,38.53 176.96,38.53 184.01,31.48 185.94,31.48 189.18,28.24 190.06,28.24 190.21,28.08 190.21,27.85 190.06,27.69 189.87,27.69 189.71,27.53 189.71,27.29 189.87,27.12 v4(190.1,27.12)
DDR_B_D59: length 46.1
  IN4 w0.076: 156.24,43.15 156.2,43.19 156.08,43.19 155.24,44.03 154.5,44.03 153.61,44.92 v4(153.61,45.9)
  IN4 w0.127: v4(189.3,27.12) 189.3,26.89 189.19,26.78 189.03,26.78 188.92,26.89 188.92,27.29 189.2,27.57 189.2,27.77 185.8,31.16 183.88,31.16 176.83,38.21 170.77,38.21 170.54,38.44 166.19,38.44 165.57,39.06 165.57,39.24 165.75,39.41 165.75,39.59 165.57,39.77 165.39,39.77 165.21,39.6 165.03,39.6 164.77,39.86 159.54,39.86 156.24,43.15
DDR_B_D60: length 49.4
  IN4 w0.076: v4(152.66,46.55) 151.92,46.55 151.65,46.28 151.65,42.78 152.01,42.42 153.71,42.42 153.94,42.19 153.94,42
  IN4 w0.127: 153.94,42 153.94,41.48 155.37,40.05 155.37,37.96 155.94,37.4 158.21,37.4 158.64,36.97 160.69,36.97 161.19,36.47 163.44,36.47 164.28,35.63 169.27,35.63 169.83,35.07 176,35.07 183.15,27.92 184.21,27.92 184.53,27.6 184.53,25.51 185.26,24.78 186.04,24.78 v4(186.1,24.72)
DDR_B_D61: length 45.8
  IN4 w0.076: v4(152.66,45.25) 152.21,45.25 151.81,44.85 151.81,43.74 152.95,42.6 153.76,42.6 154.26,42.09
  IN4 w0.127: 154.26,42.09 154.26,41.6 155.72,40.15 155.72,38.23 156.2,37.75 158.3,37.75 158.77,37.28 160.82,37.28 161.32,36.79 163.6,36.79 164.44,35.95 169.4,35.95 169.97,35.39 176.13,35.39 182.84,28.68 184.3,28.68 184.83,28.14 184.83,25.98 v4(185.3,25.52)
DDR_B_D62: length 44.1
  IN4 w0.076: 155.59,43.09 154.7,43.09 154.2,43.59 v4(153.83,43.59)
  IN4 w0.127: v4(189.3,25.52) 188.26,26.56 188.26,27.81 185.54,30.53 183.62,30.53 176.57,37.57 170.5,37.57 170.27,37.8 165.78,37.8 164.4,39.18 159.5,39.18 155.59,43.09
  BOTTOM w0.076: v4(153.83,43.59) 153.61,43.38 UCPU1.AR18
DDR_B_D63: length 45.2
  IN4 w0.076: 155.37,43.62 155.16,43.82 154.35,43.82 153.92,44.26 153.79,44.26 153.61,44.08 v4(153.61,43.95)
  IN4 w0.127: 155.37,43.62 159.45,39.53 164.54,39.53 165.95,38.12 170.4,38.12 170.64,37.89 176.7,37.89 183.75,30.85 185.67,30.85 188.6,27.92 188.6,26.69 189.32,25.97 189.65,25.97 v4(190.1,25.52)
DDR_B_DQS0: length 41.6
  IN1 w0.076: 145.7,36.33 145.7,36.35 145.72,36.37 145.72,36.64 145.5,36.86 145.5,37.47 145.59,37.56 145.59,38.39 145.48,38.5 145.37,38.5 v1(145.24,38.38)
  IN1 w0.165: v1(163.38,23) 163.58,22.79 163.78,22.79 163.91,22.92 163.91,23.45 163.4,23.97 163.37,23.97 162.85,24.49 162.85,25.67 163.16,25.98 164.43,25.98 164.56,26.11 164.56,26.8 164.43,26.93 162.82,26.93 162.45,27.3 162.45,27.99 162.82,28.37 163.84,28.37 164.03,28.56 164.03,28.91 163.84,29.1 161.42,29.1 161.05,29.47 156.33,29.47 155.15,30.65 153.38,30.65 151.5,32.53 148.56,32.53 145.7,35.39 145.7,36.33
  BOTTOM w0.076: v1(145.24,38.38) 145.24,38.43 145.75,38.94 145.75,40.28 145.8,40.33 145.8,40.71 145.75,40.76 145.75,40.94 145.8,40.99 145.8,41.21 145.66,41.35 145.36,41.65 UCPU1.AV30
  BOTTOM w0.216: UD7.F3 164.36,22.82 163.55,22.82 v1(163.38,23)
DDR_B_DQS1: length 41.8
  IN4 w0.076: 148.05,37.86 148.05,37.87 148.01,37.92 148.01,37.97 148,37.98 148,38.47 148.29,38.76 148.29,39.42 147.82,39.89 147.82,40.66 147.63,40.84 147.63,41 v4(147.79,41.16)
  IN4 w0.165: v4(161.46,25.52) 161.7,25.77 162.46,25.77 162.59,25.64 162.59,25.42 162.97,25.04 163.41,25.04 163.93,25.57 163.93,26.01 163.67,26.26 163.67,27.08 163.8,27.21 164.23,27.21 164.54,27.52 164.54,28.08 164.23,28.39 163.79,28.39 163.67,28.51 163.67,28.85 163.79,28.97 166.58,28.97 166.85,28.71 167.28,28.71 167.7,29.13 167.7,29.57 167.03,30.25 157.41,30.25 155.9,31.76 155.26,31.76 154.74,31.24 154.4,31.24 153.91,31.73 153.38,31.73 152.89,31.24 152.63,31.24 147.8,36.07 147.8,36.49 148.05,36.75 148.05,37.86
DDR_B_DQS2: length 45.2
  IN1 w0.076: 142.17,41.15 142.17,41.16 142.21,41.2 142.21,41.81 142.8,42.4 145.2,42.4 145.95,43.14 145.95,44.51 146.2,44.76 146.43,44.76 146.61,44.95 v1(146.61,44.99)
  IN1 w0.165: v1(151.79,23.23) 151.79,23.22 151.95,23.06 152.25,23.06 152.39,23.2 152.39,23.51 151.88,24.01 151.18,24.01 150.71,24.48 149.98,24.48 149.71,24.75 148.8,24.75 148.3,25.26 148.3,28.43 148.17,28.55 147.53,28.55 147.4,28.43 147.4,26.09 147.09,25.78 146.41,25.78 146.1,26.09 146.1,29.52 144.85,30.78 144.62,30.78 143.89,30.04 143.45,30.04 142.98,30.51 142.98,30.95 143.74,31.71 143.74,31.89 143.39,32.23 143.21,32.23 142.52,31.53 141.96,31.53 141.04,32.46 141.04,34.76 141.43,35.15 141.43,35.51 141.95,36.02 141.95,38.1 142.17,38.33 142.17,41.15
  BOTTOM w0.076: v1(146.61,44.99) 146.87,45.25 UCPU1.AM28
  BOTTOM w0.216: v1(151.79,23.23) 151.97,23.05 152.38,23.05 152.57,22.86 152.87,22.86 153.1,23.09 UD6.F3
DDR_B_DQS3: length 44.9
  IN4 w0.076: 143.7,42.31 143.71,42.31 143.73,42.33 145.5,42.33 145.6,42.43 146.77,42.43 147.61,43.27 148.09,43.27 148.68,43.86 148.68,44.78 v4(148.41,45.06)
  IN4 w0.165: 143.7,42.31 142.92,42.31 142.33,41.73 142.33,41.47 142.6,41.2 142.6,40.29 142.33,40.02 142.33,36.22 143.47,35.08 143.47,34.55 142.1,33.18 142.1,32.91 142.63,32.38 142.83,32.38 143.54,33.1 143.98,33.1 144.47,32.61 144.47,32.17 143.74,31.45 143.74,31.27 144.15,30.86 144.33,30.86 145.05,31.59 145.49,31.59 146.08,31 146.08,30.56 145.35,29.84 145.35,29.66 145.69,29.33 145.87,29.33 146.59,30.05 147.03,30.05 147.5,29.57 147.5,29.13 146.83,28.46 146.83,28.24 147.08,27.98 147.27,27.98 147.89,28.6 148.45,28.6 149.19,27.87 150.4,27.87 150.73,27.54 150.73,26.98 150.82,26.89 151.25,26.89 151.56,26.59 151.56,24.21 151.25,23.9 150.6,23.9 150.29,24.21 150.29,25.45 150.17,25.58 149.96,25.58 v4(149.9,25.52)
  BOTTOM w0.076: UCPU1.AM25 148.6,45.25 v4(148.41,45.06)
DDR_B_DQS4: length 42.4
  IN1 w0.102: v1(150.7,38.14) 150.78,38.22 150.92,38.22 151.04,38.1 151.04,36.47 151.37,36.13 152.64,36.13 152.66,36.12
  IN1 w0.165: v1(176.34,22.85) 176.54,22.85 176.89,23.2 176.89,23.64 175.73,24.8 175.73,25.29 176.02,25.58 176.02,25.76 175.73,26.05 175.43,26.05 175.17,25.8 174.74,25.8 174.06,26.47 174.06,26.91 174.37,27.22 174.37,27.36 173.31,28.41 170.7,28.41 168.93,30.18 167.78,30.18 164.94,33.02 161.59,33.02 161.05,33.56 159.88,33.56 159.5,33.94 158.26,33.94 157.62,34.57 155.05,34.57 153.51,36.12 152.66,36.12
  BOTTOM w0.076: UCPU1.AV22 150.51,41.81 150.8,41.53 150.8,41.38 150.93,41.24 150.93,40.96 150.88,40.91 150.88,40.75 150.94,40.68 150.94,40.35 150.87,40.28 150.87,40.04 151.17,39.74 151.17,39.1 151.08,39.02 151.08,38.55 150.7,38.17 v1(150.7,38.14)
  BOTTOM w0.216: v1(176.34,22.85) 176.4,22.79 177.49,22.79 177.74,23.04 UD9.F3
DDR_B_DQS5: length 41.9
  IN4 w0.076: v4(152.92,41.16) 152.9,41.16 152.75,41.01 152.75,39.92 152.99,39.68 152.99,38.93 153.03,38.89
  IN4 w0.165: 153.03,38.89 153.03,37.08 154.65,35.46 157.55,35.46 157.9,35.11 159.91,35.11 161.23,33.8 168.51,33.8 169.11,33.19 172.06,33.19 172.37,32.89 172.37,31.26 172.5,31.13 173.05,31.13 173.18,31.26 173.18,32.85 173.48,33.16 174.38,33.16 174.69,32.85 174.69,31.33 174.85,31.17 175.35,31.17 175.83,30.68 175.83,30.13 176,29.97 176.1,29.97 176.41,29.66 176.41,28.99 176.1,28.69 175.97,28.69 175.84,28.56 175.84,28.15 175.97,28.03 176.28,28.03 176.59,27.72 176.59,27.05 176.28,26.75 176,26.75 175.83,26.58 175.83,26.14 175.46,25.77 174.78,25.77 v4(174.54,25.52)
DDR_B_DQS6: length 53.4
  IN1 w0.076: 152.55,41.18 152.53,41.18 152.52,41.19 152.52,41.2 152.45,41.27 151.97,41.27 150.71,42.53 150.71,44.42 150.9,44.61 151.22,44.61 151.33,44.71 151.33,44.86 v1(151.23,44.95)
  IN1 w0.165: v1(187.99,23) 188.21,22.78 188.41,22.78 188.57,22.94 188.57,23.26 187.52,24.3 187.52,26.83 185.36,28.99 177.89,28.99 173.47,33.41 170.89,33.41 170.49,33.82 169.18,33.82 166.41,36.58 164.53,36.58 164,37.11 161.41,37.11 161.03,37.49 159.74,37.49 157.32,39.92 155.82,39.92 154.56,41.18 152.55,41.18
  BOTTOM w0.076: UCPU1.AM21 151.53,45.25 v1(151.23,44.95)
  BOTTOM w0.216: v1(187.99,23) 188.17,22.82 189,22.82 UD10.F3
DDR_B_DQS7: length 46.8
  IN4 w0.076: 156,42.26 155.99,42.26 155.97,42.25 155.96,42.25 155.77,42.44 155.77,42.6 155.44,42.93 154.63,42.93 154.27,43.3 153.66,43.3 153.35,43.61 153.35,44.57 v4(152.98,44.93)
  IN4 w0.165: v4(186.1,25.52) 186.34,25.77 187.34,25.77 187.83,26.25 187.83,27.6 185.35,30.08 183.43,30.08 176.38,37.12 170.2,37.12 169.97,37.35 165.57,37.35 164.2,38.72 159.54,38.72 156,42.26
  BOTTOM w0.076: v4(152.98,44.93) 153.31,45.25 UCPU1.AM18
DDR_B_DQS#0: length 41.6
  IN1 w0.076: v1(145.24,38.98) 145.24,38.87 145.38,38.73 145.57,38.73 145.81,38.48 145.81,37.47 145.72,37.38 145.72,36.95 145.94,36.73 145.94,36.46 145.97,36.44 145.97,36.38 146.01,36.34 146.01,36.33
  IN1 w0.165: v1(163.38,22.37) 163.49,22.48 163.91,22.48 164.22,22.79 164.22,23.58 163.52,24.28 163.5,24.28 163.16,24.62 163.16,25.54 163.29,25.67 164.56,25.67 164.87,25.98 164.87,26.93 164.56,27.24 162.95,27.24 162.76,27.43 162.76,27.87 162.95,28.06 163.96,28.06 164.34,28.43 164.34,29.04 163.96,29.41 161.54,29.41 161.18,29.78 156.46,29.78 155.28,30.96 153.51,30.96 151.63,32.84 148.69,32.84 146.01,35.52 146.01,36.33
  BOTTOM w0.076: v1(145.24,38.98) 145.3,38.93 145.52,38.93 145.59,39 145.59,40.34 145.64,40.39 145.64,40.64 145.64,40.65 145.59,40.69 145.59,41 145.64,41.05 145.64,41.15 145.53,41.27 145.47,41.27 UCPU1.AW30
  BOTTOM w0.216: v1(163.38,22.37) 163.49,22.48 164.5,22.48 UD7.G3
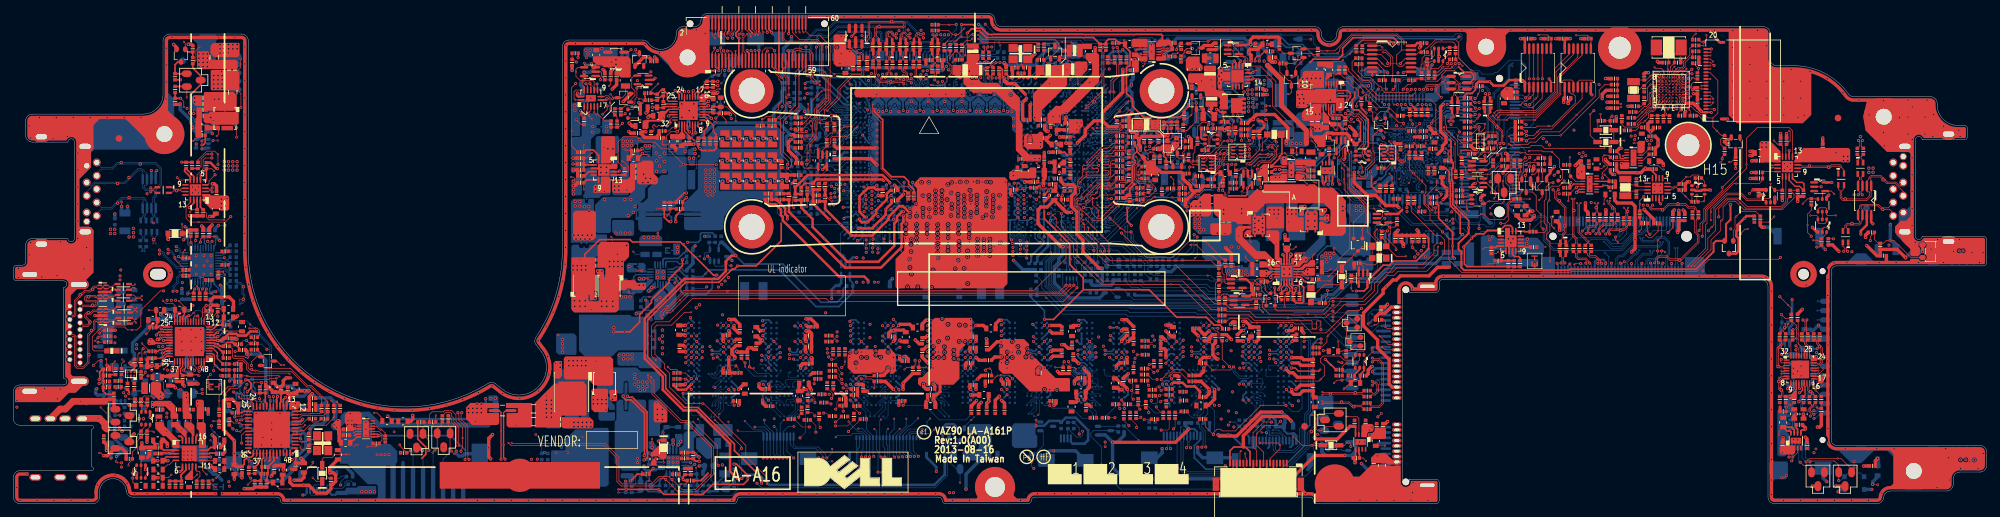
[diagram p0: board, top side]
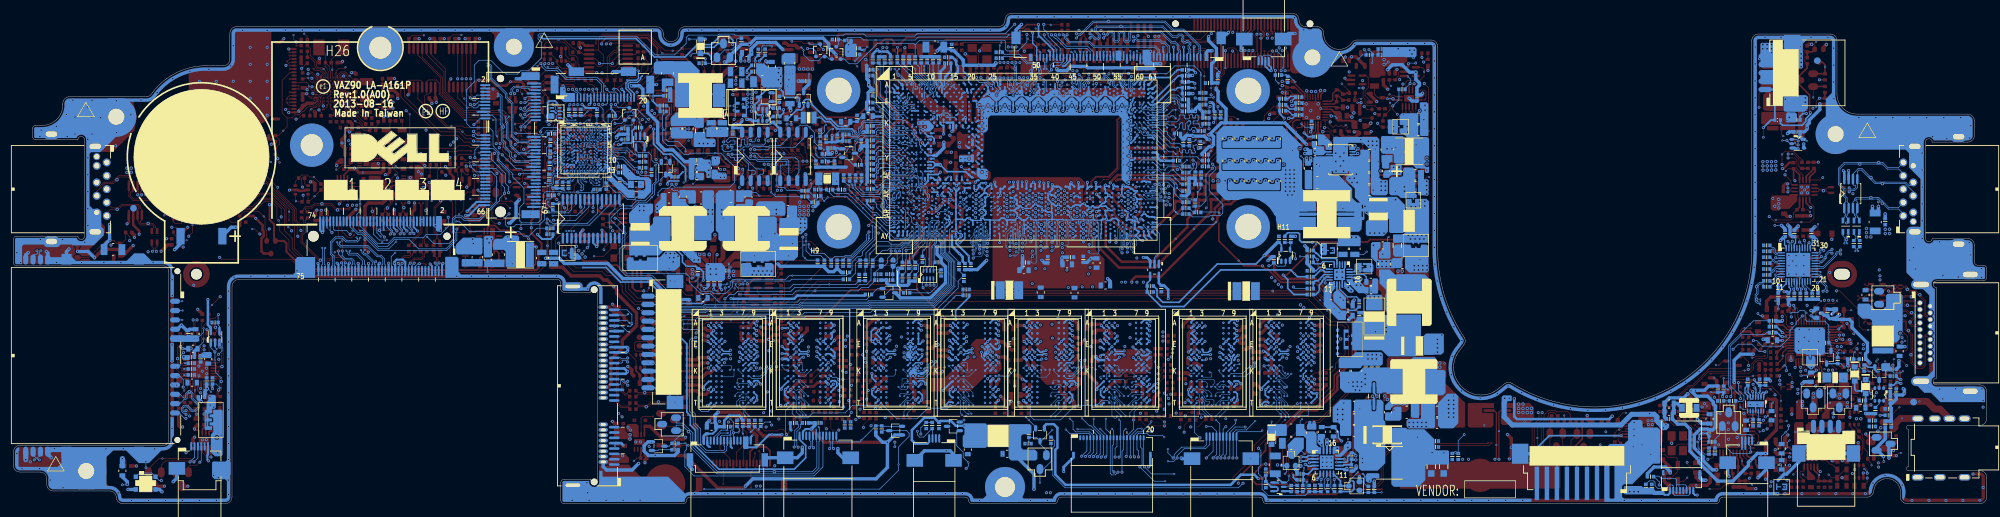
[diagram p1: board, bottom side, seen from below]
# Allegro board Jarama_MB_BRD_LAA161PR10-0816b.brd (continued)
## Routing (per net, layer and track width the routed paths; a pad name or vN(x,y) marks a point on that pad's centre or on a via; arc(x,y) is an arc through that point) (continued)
DDR_B_DQS#1: length 42
  IN4 w0.076: v4(147.79,41.81) 147.49,41.51 147.49,41.17 147.41,41.09 147.41,40.75 147.6,40.56 147.6,39.8 148.07,39.33 148.07,38.85 147.78,38.56 147.78,37.89 147.78,37.88 147.75,37.88 147.74,37.87 147.74,37.86
  IN4 w0.165: 147.74,37.86 147.74,36.87 147.49,36.62 147.49,35.94 152.5,30.93 153.02,30.93 153.51,31.42 153.78,31.42 154.27,30.93 154.87,30.93 155.39,31.45 155.77,31.45 157.28,29.94 166.9,29.94 167.39,29.44 167.39,29.26 167.16,29.02 166.98,29.02 166.71,29.28 163.67,29.28 163.36,28.97 163.36,28.39 163.67,28.08 164.1,28.08 164.23,27.95 164.23,27.64 164.1,27.52 163.67,27.52 163.36,27.21 163.36,26.13 163.62,25.88 163.62,25.7 163.28,25.35 163.1,25.35 162.9,25.55 162.9,25.77 162.59,26.08 161.7,26.08 v4(161.46,26.32)
DDR_B_DQS#2: length 45.2
  IN1 w0.076: v1(146.61,44.38) 146.45,44.54 146.29,44.54 146.17,44.42 146.17,43.05 145.29,42.18 142.89,42.18 142.43,41.72 142.43,41.21 142.48,41.16 142.48,41.15
  IN1 w0.165: v1(151.79,22.6) 151.79,22.6 151.95,22.75 152.38,22.75 152.7,23.07 152.7,23.64 152.01,24.32 151.3,24.32 150.83,24.79 150.1,24.79 149.84,25.06 148.93,25.06 148.61,25.38 148.61,28.55 148.3,28.86 147.4,28.86 147.09,28.55 147.09,26.22 146.96,26.09 146.54,26.09 146.41,26.22 146.41,29.65 144.98,31.09 144.49,31.09 143.76,30.35 143.58,30.35 143.29,30.64 143.29,30.82 144.05,31.58 144.05,32.01 143.52,32.54 143.09,32.54 142.39,31.84 142.09,31.84 141.35,32.59 141.35,34.63 141.74,35.02 141.74,35.38 142.26,35.89 142.26,37.98 142.48,38.2 142.48,41.15
  BOTTOM w0.076: UCPU1.AN28 146.83,44.6 v1(146.61,44.38)
  BOTTOM w0.216: UD6.G3 153.07,22.32 152.87,22.52 152.43,22.52 152.24,22.71 151.91,22.71 v1(151.79,22.6)
DDR_B_DQS#3: length 45
  IN4 w0.076: v4(148.41,44.41) 148.46,44.35 148.46,43.95 148,43.49 147.51,43.49 146.68,42.65 145.51,42.65 145.41,42.55 143.78,42.55 143.7,42.62
  IN4 w0.165: v4(149.9,26.32) 149.84,26.32 149.71,26.19 149.71,26 149.82,25.89 150.29,25.89 150.6,25.58 150.6,24.33 150.73,24.21 151.12,24.21 151.25,24.33 151.25,26.46 151.12,26.58 150.69,26.58 150.42,26.85 150.42,27.41 150.27,27.56 149.06,27.56 148.32,28.29 148.02,28.29 147.4,27.67 146.95,27.67 146.52,28.11 146.52,28.59 147.2,29.26 147.2,29.44 146.9,29.74 146.72,29.74 145.99,29.02 145.56,29.02 145.04,29.53 145.04,29.97 145.77,30.69 145.77,30.87 145.36,31.28 145.18,31.28 144.46,30.55 144.02,30.55 143.43,31.14 143.43,31.58 144.16,32.3 144.16,32.48 143.85,32.79 143.67,32.79 142.96,32.07 142.5,32.07 141.79,32.78 141.79,33.3 143.17,34.68 143.17,34.95 142.02,36.09 142.02,40.15 142.29,40.41 142.29,41.08 142.02,41.34 142.02,41.86 142.79,42.62 143.7,42.62
  BOTTOM w0.076: UCPU1.AN25 148.99,44.6 149.11,44.47 149.11,44.38 148.99,44.25 148.54,44.25 148.41,44.38 v4(148.41,44.41)
DDR_B_DQS#4: length 42.4
  IN1 w0.102: v1(150.7,38.75) 150.7,38.6 150.82,38.48 151.01,38.48 151.29,38.2 151.29,36.57 151.48,36.38 152.61,36.38 152.66,36.43
  IN1 w0.165: 152.66,36.43 153.63,36.43 155.18,34.88 157.75,34.88 158.39,34.25 159.63,34.25 160.01,33.87 161.18,33.87 161.72,33.33 165.07,33.33 167.9,30.49 169.06,30.49 170.83,28.72 173.44,28.72 174.68,27.49 174.68,27.09 174.37,26.78 174.37,26.6 174.87,26.11 175.05,26.11 175.3,26.36 175.86,26.36 176.33,25.89 176.33,25.45 176.04,25.16 176.04,24.93 177.2,23.77 177.2,23.07 v1(176.34,22.21)
  BOTTOM w0.076: v1(150.7,38.75) 150.88,38.75 150.93,38.8 150.93,39.08 151.02,39.17 151.02,39.68 150.72,39.97 150.72,40.35 150.79,40.42 150.79,40.62 150.72,40.68 150.72,41.06 150.62,41.17 150.5,41.17 UCPU1.AW22
  BOTTOM w0.216: UD9.G3 177.74,22.38 177.67,22.45 177.66,22.45 177.65,22.44 176.57,22.44 v1(176.34,22.21)
DDR_B_DQS#5: length 42.1
  IN4 w0.076: v4(152.92,41.81) 152.66,41.54 152.66,41.24 152.52,41.1 152.52,39.83 152.77,39.59 152.77,38.94 152.72,38.89
  IN4 w0.165: 152.72,38.89 152.72,36.95 154.52,35.15 157.42,35.15 157.77,34.8 159.78,34.8 161.1,33.49 168.38,33.49 168.98,32.88 171.94,32.88 172.06,32.76 172.06,31.13 172.37,30.82 173.18,30.82 173.49,31.13 173.49,32.72 173.61,32.85 174.25,32.85 174.38,32.72 174.38,31.2 174.76,30.82 175.26,30.82 175.52,30.55 175.52,30 175.87,29.66 175.98,29.66 176.1,29.53 176.1,29.12 175.98,29 175.84,29 175.53,28.69 175.53,28.02 175.84,27.72 176.15,27.72 176.28,27.59 176.28,27.18 176.15,27.06 175.87,27.06 175.52,26.71 175.52,26.27 175.33,26.08 174.78,26.08 v4(174.54,26.32)
DDR_B_DQS#6: length 53.5
  IN1 w0.076: 152.55,41.49 152.49,41.43 152.03,41.43 150.86,42.6 150.86,44.35 150.97,44.46 151.16,44.46 151.28,44.34 v1(151.28,44.26)
  IN1 w0.165: v1(188,22.36) 188.11,22.47 188.53,22.47 188.88,22.81 188.88,23.38 187.83,24.43 187.83,26.96 185.49,29.3 178.02,29.3 173.6,33.72 171.02,33.72 170.62,34.13 169.31,34.13 166.54,36.89 164.66,36.89 164.13,37.42 161.54,37.42 161.16,37.8 159.87,37.8 157.45,40.23 155.95,40.23 154.69,41.49 152.55,41.49
  BOTTOM w0.076: UCPU1.AN21 151.36,44.26 v1(151.28,44.26)
  BOTTOM w0.216: v1(188,22.36) 188.12,22.48 189.14,22.48 UD10.G3
DDR_B_DQS#7: length 46.9
  IN4 w0.076: 155.78,42.04 155.78,42.05 155.78,42.06 155.8,42.09 155.8,42.19 155.62,42.37 155.62,42.54 155.38,42.78 154.56,42.78 154.27,43.08 153.57,43.08 153.12,43.52 153.12,44.14 v4(152.98,44.27)
  IN4 w0.165: 155.78,42.04 159.41,38.41 164.08,38.41 165.44,37.04 169.84,37.04 170.07,36.81 176.25,36.81 183.3,29.77 185.22,29.77 187.52,27.47 187.52,26.38 187.21,26.08 186.17,26.08 186.1,26.15 v4(186.1,26.32)
  BOTTOM w0.076: UCPU1.AN18 153.74,44.6 153.9,44.76 153.9,44.86 153.78,44.98 153.42,44.98 152.87,44.43 152.87,44.39 v4(152.98,44.27)
DDR_B_MA0: length 134.6
  TOP w0.076: RD30.1 165.42,14.42 v1(165.58,14.26)
  IN1 w0.076: v3(182.27,15.14) 182.18,15.05 181.61,15.05 181.26,15.4 177.71,15.4 176.21,13.9 171.06,13.9 170.64,14.32 170.4,14.32 169.7,15.01 168.13,15.01 167.94,14.82 166.25,14.82 165.68,14.26 v1(165.58,14.26) 165.58,14.77 165.19,15.15 164.79,15.15 164.68,15.05 164.68,14.43 164.6,14.35 164.45,14.35 164.38,14.43 164.38,15.08 164.28,15.18 164.13,15.18 164.07,15.12 164.07,14.43 163.99,14.35 163.84,14.35 163.77,14.43 163.77,15.12 163.71,15.18 163.53,15.18 163.44,15.09 163.44,14.43 163.36,14.35 163.21,14.35 163.14,14.43 163.14,15.1 163.06,15.18 162.9,15.18 162.83,15.1 162.83,14.43 162.75,14.35 162.6,14.35 162.53,14.43 162.53,15.1 162.45,15.18 162.29,15.18 162.22,15.1 162.22,14.43 162.14,14.35 161.99,14.35 161.92,14.43 161.92,14.96 161.86,15.02 161.67,15.02 161.61,14.97 161.61,14.7 161.51,14.6 161.37,14.6 161.32,14.65 161.31,14.65 161.31,14.9 161.09,15.12 160.7,15.12 160.48,14.9 159.15,14.9 158.7,15.34 157.75,15.34 157.55,15.14 v3(157.55,14.93)
  IN2 w0.076: v1(138.93,44.26) 138.43,43.77 138.43,43.55 138.14,43.26 137.86,43.26 137.44,43.67 137.44,44.33 137.14,44.63 135.5,44.63
  IN2 w0.191: 135.5,44.63 135.43,44.56 134.71,44.56 134.58,44.69 133.55,44.69 132.69,43.83 132.69,42.93 130.84,41.07 130.84,39.13 130.65,38.94 130.65,33.11 135.05,28.71 137.34,28.71 141.09,24.96 144.04,24.96 144.83,24.18 144.83,23.71 146.89,21.65 146.89,20.71 148.13,19.47 149.41,19.47 151.28,17.6 155.75,17.6 155.88,17.47 156.7,17.47 156.77,17.39 157.3,17.39 157.72,16.97 158.41,16.97 159.39,15.99 160.46,15.99 162.19,14.26 v1(165.58,14.26)
  IN4 w0.076: v4(176.35,16.12) 176.77,16.54 177.18,16.54 177.5,16.22 177.66,16.22 177.97,15.91 178.74,15.91 179.27,15.38 181.15,15.38 181.56,14.96 182.1,14.96 v3(182.27,15.14) 182.39,15.26 183.47,15.26 183.89,14.84 185.8,14.84 186.37,15.41 187.18,15.41 v4(189.3,17.52) ; v4(151.71,16.12) 152.12,16.54 152.54,16.54 152.86,16.22 153.52,16.22 153.83,15.91 154.1,15.91 154.69,15.32 156.58,15.32 156.91,14.99 157.48,14.99 v3(157.55,14.93) 157.91,15.29 158.73,15.29 159.2,14.82 161.13,14.82 161.76,15.44 162.42,15.44 164.5,17.52 v4(164.66,17.52)
  BOTTOM w0.076: UCPU1.AP40 139.24,43.95 v1(138.93,44.26) ; v4(151.71,16.12) 151.71,16.63 152.17,17.1 152.68,17.1 UD6.N3 ; UD9.N3 177.74,17.5 v4(176.35,16.12)
DDR_B_MA1: length 132.3
  TOP w0.076: v1(171.05,14.51) 171.05,14.34 171.68,13.71 RD44.1
  IN1 w0.076: v3(157.08,15.43) 157.08,15.48 157.14,15.55 158.82,15.55 159.25,15.11 160.41,15.11 160.62,15.32 161.78,15.32 161.84,15.38 164.24,15.38 164.51,15.65 164.99,15.65 165.6,15.04 167.86,15.04 168.11,15.28 169.73,15.28 170.45,14.56 171,14.56 v1(171.05,14.51) 171.44,14.11 176.14,14.11 177.73,15.71 181.1,15.71 181.26,15.87 182.76,15.87 183.03,15.6 183.51,15.6 183.62,15.49 183.62,15.33 183.51,15.22 182.96,15.22 182.65,15.53 181.86,15.53 v3(181.77,15.44)
  IN2 w0.191: v1(171.05,14.51) 172.35,13.2 172.35,12.9 172.93,12.33 173.11,12.33 173.42,12.65 173.42,12.91 171.06,15.27 171.06,16.2 170.64,16.61 170.64,17.49 170.45,17.68 170.45,18.09 169.82,18.72 169.82,19.67 169.38,20.1 169.38,20.91 170.25,21.77 170.25,23.16 169.24,24.16 169.24,24.32 168.8,24.77 168.8,25.19 168.93,25.31 169.05,25.31 169.18,25.44 169.18,25.85 169.05,25.97 168.16,25.97 168.03,26.1 168.03,27.74 168.17,27.88 168.35,27.88 168.48,28.01 168.48,28.44 168.35,28.57 168.2,28.57 168.09,28.67 168.09,30.24 167.97,30.37 167.31,30.37 167.19,30.24 167.19,29.71 167.06,29.58 166.53,29.58 166.4,29.71 166.4,29.92 166.27,30.05 165.81,30.05 165.69,29.92 165.69,29.7 165.56,29.57 165.1,29.57 164.98,29.7 164.98,29.92 164.85,30.05 164.34,30.05 164.21,29.92 164.21,29.7 164.09,29.57 163.29,29.57 163.16,29.7 163.16,30.71 163.03,30.84 159.03,30.84 158.91,30.97 158.91,31.89 158.68,32.11 158.29,32.11 158.13,32.27 157.68,32.27 157.52,32.11 157.19,32.11 157.07,32.24 157.07,32.79 156.94,32.92 154.71,32.92 154.53,33.1 154.04,33.1 153.86,32.92 151.45,32.92 150.66,33.71 150.21,33.71 150.06,33.87 150.06,34.32 149.81,34.56 146.05,34.56 145.28,35.34 143.42,35.34 142.74,36.02 141.19,36.02 139.14,38.08 139.14,42.91 138.93,43.12 v1(138.93,43.61)
  IN4 w0.076: v4(162.64,16.12) 162.18,15.66 161.67,15.66 161.04,15.03 159.28,15.03 158.8,15.51 157.15,15.51 v3(157.08,15.43) 156.92,15.59 154.81,15.59 154.21,16.18 153.88,16.18 153.57,16.49 152.97,16.49 152.65,16.81 151.34,16.81 151.25,16.72 v4(149.9,16.72) ; v4(174.54,16.72) 174.56,16.74 177.35,16.74 177.61,16.49 177.77,16.49 178.08,16.18 178.85,16.18 179.44,15.59 181.4,15.59 181.55,15.44 v3(181.77,15.44) 181.9,15.57 182.58,15.57 182.67,15.48 183.53,15.48 183.94,15.08 185.19,15.08 185.32,15.21 185.32,15.41 185.42,15.51 185.57,15.51 185.68,15.41 185.68,15.34 185.78,15.24 185.92,15.24 186.02,15.34 186.02,15.55 186.15,15.68 186.83,15.68 v4(187.28,16.12)
  BOTTOM w0.076: v4(162.64,16.12) 162.64,16.4 162.51,16.52 161.59,16.52 161.46,16.65 UD7.P7 ; UCPU1.AR40 139.24,43.3 v1(138.93,43.61) ; UD10.P7 186.85,16.72 187.28,16.3 v4(187.28,16.12)
DDR_B_MA2: length 143.8
  TOP w0.076: v1(164.84,12.89) 164.82,12.87 RD40.1
  IN1 w0.076: v3(182.44,13.73) 182.08,13.37 181.39,13.37 181.08,13.68 178.93,13.68 178.06,12.8 170.22,12.8 169.71,13.31 169.33,13.31 169.27,13.37 168.58,13.37 168.2,13 166.87,13 166.3,12.42 165.31,12.42 v1(164.84,12.89) 164.84,12.53 164.71,12.4 164.53,12.4 164.52,12.41 164.52,12.56 164.42,12.67 164.28,12.67 164.23,12.61 164.23,12.47 164.15,12.4 163.99,12.4 163.86,12.53 163.86,13.22 163.73,13.34 162.89,13.34 162.82,13.27 162.82,12.47 162.74,12.4 162.59,12.4 162.51,12.47 162.51,13.27 162.44,13.34 162.22,13.34 162.15,13.27 162.15,12.49 162.07,12.41 161.92,12.41 161.84,12.49 161.84,13.27 161.77,13.34 161.61,13.34 161.54,13.27 161.54,12.49 161.46,12.41 161.31,12.41 161.23,12.49 161.23,13.27 161.16,13.34 161,13.34 160.93,13.27 160.93,13.07 160.85,13 160.7,13 160.62,13.07 160.62,13.27 160.55,13.34 160.4,13.34 160.32,13.27 160.32,13.17 160.27,13.12 160.07,13.12 160.01,13.18 160.01,13.27 159.94,13.34 159.81,13.34 159.32,13.83 159.21,13.83 159.06,13.68 158.91,13.68 158.75,13.83 157.89,13.83 157.76,13.71 157.76,13.4 157.64,13.27 156.25,13.27 156.23,13.3 156.23,13.44 156.27,13.48 157.11,13.48 v3(157.36,13.73)
  IN2 w0.191: v1(164.84,12.89) 164.56,12.62 161.81,12.62 160.25,14.18 157.51,14.18 156.51,15.18 154.47,15.18 153.83,15.82 148.51,15.82 145.91,18.42 145.91,21.52 144.06,23.37 141.24,23.37 140.25,24.36 139.6,24.36 137.68,26.28 137.68,27.25 136.99,27.95 134.69,27.95 129.42,33.23 129.42,36.86 129.86,37.3 129.86,38.34 129.48,38.73 129.48,41.29 130.21,42.02 130.21,42.12 133.8,45.71 136.22,45.71 136.85,45.09 137.24,45.09 138,44.33 v1(138,44.24)
  IN4 w0.076: v4(189.3,16.72) 189.52,16.72 189.61,16.63 189.61,16.52 189.46,16.37 189.17,16.37 188.92,16.12 188.92,15.83 188.83,15.74 188.72,15.74 188.49,15.97 188.38,15.97 188.27,15.86 188.27,15.75 188.5,15.52 188.5,15.42 187.02,13.94 183.4,13.94 183.3,14.04 182.74,14.04 v3(182.44,13.73) 182.19,13.48 181.28,13.48 181.13,13.63 180.81,13.63 180.62,13.82 179.49,13.82 178.46,14.85 177.45,14.85 177.24,15.05 176.46,15.05 176.3,14.9 v4(176.3,14.75) ; v4(151.67,14.75) 151.67,15.09 151.81,15.24 153.08,15.24 153.28,15.04 153.42,15.04 154.63,13.82 155.25,13.82 155.53,13.55 156.49,13.55 156.58,13.45 157.08,13.45 v3(157.36,13.73) 157.46,13.83 158.42,13.83 158.68,13.58 161.08,13.58 161.46,13.96 162.27,13.96 163.03,14.72 163.17,14.72 163.86,15.41 163.86,15.52 163.62,15.76 163.62,15.87 163.73,15.98 163.84,15.98 164.08,15.74 164.19,15.74 164.26,15.82 164.26,16.01 164.14,16.13 164.14,16.18 164.66,16.7 v4(164.66,16.72)
  BOTTOM w0.076: v4(176.3,14.75) 176.3,14.93 177.41,16.03 177.41,16.39 UD9.P3 ; UD6.P3 153.1,16.4 152.76,16.06 152.76,15.94 152.41,15.59 152.41,15.58 151.67,14.84 v4(151.67,14.75) ; v1(138,44.24) 138.29,43.95 UCPU1.AP42
DDR_B_MA3: length 140.3
  TOP w0.076: RD50.1 166.26,14.28 v1(166.27,14.27)
  IN1 w0.076: v3(158.71,14.75) 158.71,14.6 158.78,14.53 159.05,14.53 159.15,14.63 159.15,14.65 159.2,14.7 159.81,14.7 159.88,14.62 159.88,14.32 159.9,14.3 159.98,14.22 160.05,14.22 160.14,14.32 160.14,14.63 160.19,14.69 160.32,14.69 160.37,14.65 160.37,14.21 160.43,14.14 160.59,14.14 160.66,14.21 160.66,14.73 160.82,14.9 160.93,14.9 160.98,14.84 160.98,14.14 161.05,14.08 161.2,14.08 161.28,14.16 161.28,14.32 161.36,14.39 161.45,14.39 161.51,14.33 161.51,14.13 161.56,14.08 164.6,14.08 164.73,13.95 164.8,13.95 164.88,14.04 164.88,14.84 164.96,14.91 165.13,14.91 165.18,14.86 165.18,13.86 165.35,13.69 165.51,13.69 165.65,13.83 166.16,13.83 166.19,13.8 167.5,13.8 167.54,13.83 167.54,14.35 167.49,14.41 167.29,14.41 167.21,14.33 167.21,14.07 167.14,14 166.98,14 166.91,14.07 166.91,14.33 166.83,14.41 166.74,14.41 166.67,14.33 166.67,14.09 166.6,14.02 166.41,14.02 166.33,14.1 166.33,14.2 v1(166.27,14.27) 166.61,14.61 168.01,14.61 168.12,14.72 169.7,14.72 170.31,14.11 170.45,14.11 170.96,13.61 176.3,13.61 177.83,15.14 181.16,15.14 181.55,14.75 182.73,14.75 v3(182.83,14.85)
  IN2 w0.076: v1(138,43.6) 137.63,43.97 137.63,44.39 137.21,44.81 136.64,44.81 136.54,44.91
  IN2 w0.191: v1(166.27,14.27) 166.17,14.16 166.16,14.16 165.8,13.81 161.86,13.81 160.86,14.81 159.41,14.81 158.61,15.61 157.53,15.61 157.26,15.89 156.86,15.89 156.58,15.61 154.71,15.61 153.36,16.96 150.06,16.96 149.41,17.61 148.16,17.61 146.29,19.48 146.29,21.7 144.28,23.7 141.45,23.7 140.72,24.44 140.72,24.78 137.17,28.33 134.87,28.33 130.18,33.02 130.18,38.42 129.76,38.84 129.76,40.41 130.75,41.41 130.75,42.28 133.9,45.43 136.02,45.43 136.54,44.91
  IN4 w0.076: v4(152.34,16.11) 152.51,15.95 153.39,15.95 153.69,15.65 153.99,15.65 154.52,15.12 156.49,15.12 156.86,14.74 157.13,14.74 157.34,14.53 157.88,14.53 157.95,14.46 158.42,14.46 v3(158.71,14.75) 158.78,14.75 158.9,14.62 161.23,14.62 161.79,15.18 162.54,15.18 162.93,15.57 163.04,15.57 163.32,15.29 163.42,15.29 163.53,15.4 163.53,15.51 163.25,15.79 163.25,15.89 164.47,17.11 164.93,17.11 165.03,17.21 165.03,17.67 165.13,17.77 165.41,17.77 165.48,17.69 165.48,17.55 v4(165.46,17.52) ; v4(190.1,17.52) 189.69,17.11 189.19,17.11 187.86,15.79 187.86,15.68 188.12,15.43 188.12,15.32 188.01,15.21 187.9,15.21 187.65,15.47 187.54,15.47 187.26,15.19 186.46,15.19 185.83,14.57 183.87,14.57 183.59,14.85 v3(182.83,14.85) 182.69,14.71 181.53,14.71 181.07,15.17 179.11,15.17 178.63,15.65 177.82,15.65 177.59,15.88 177.3,15.88 177.14,15.73 176.75,15.73 176.65,15.83 176.65,15.93 176.69,15.97 176.84,15.97 v4(176.99,16.12)
  BOTTOM w0.076: UD6.N2 153.49,17.11 152.99,17.11 152.34,16.46 v4(152.34,16.11) ; UCPU1.AR42 138.3,43.3 138.01,43.59 138.01,43.59 v1(138,43.6) ; v4(176.99,16.12) 176.99,16.47 177.62,17.11 177.97,17.11 177.97,17.08 178.06,17 178.26,17 178.54,17.27 UD9.N2
DDR_B_MA4: length 143.4
  TOP w0.076: v1(170.28,15.46) 170.28,15.19 170.42,15.05 171.1,15.05 171.19,15.15 171.19,15.96 170.98,16.17 RD38.1
  IN1 w0.076: v3(155.64,16.07) 155.88,15.83 157.34,15.83 157.39,15.78 158.99,15.78 159.18,15.97 160.48,15.97 160.86,15.58 161.8,15.58 162.09,15.87 162.09,16.22 162.19,16.32 162.41,16.32 162.48,16.25 162.48,15.69 162.56,15.61 162.71,15.61 162.79,15.69 162.79,16.25 162.86,16.32 162.96,16.32 163.02,16.26 163.37,16.26 163.44,16.19 163.44,15.85 163.52,15.78 163.67,15.78 163.75,15.85 163.75,16.19 163.82,16.26 164.23,16.26 164.63,15.87 165.52,15.87 165.61,15.95 166.04,15.95 166.37,15.62 166.37,15.43 166.56,15.25 167.79,15.25 168.13,15.59 170.16,15.59 v1(170.28,15.46) 170.4,15.34 170.79,15.34 171.79,14.34 173.95,14.34 174.03,14.41 174.03,14.93 174.1,15 174.26,15 174.33,14.93 174.33,14.41 174.41,14.34 174.56,14.34 174.64,14.41 174.64,14.93 174.71,15 174.87,15 174.94,14.93 174.94,14.41 175.02,14.34 175.17,14.34 175.25,14.41 175.25,14.93 175.32,15 175.48,15 175.55,14.93 175.55,14.41 175.63,14.34 175.97,14.34 176.4,14.77 176.4,14.87 176.21,15.06 176.21,15.17 176.32,15.27 176.43,15.27 176.61,15.09 176.72,15.09 176.83,15.2 176.83,15.31 176.65,15.49 176.65,15.6 176.75,15.71 176.86,15.71 177.05,15.52 177.15,15.52 177.26,15.63 177.26,15.74 177.08,15.92 177.08,16.03 177.19,16.14 177.29,16.14 177.48,15.95 177.58,15.95 177.89,16.26 179.16,16.26 179.24,16.18 179.24,16.01 179.31,15.93 179.46,15.93 179.54,16.01 179.54,16.18 179.62,16.26 180.3,16.26 v3(180.44,16.11)
  IN2 w0.191: v1(170.28,15.46) 170.52,15.46 170.67,15.61 170.67,15.97 169.4,17.25 169.4,17.94 168.57,18.76 168.57,21.24 169.24,21.91 169.24,23.03 167.54,24.73 167.54,25.39 167.34,25.59 166.87,25.59 166.66,25.79 166.66,28.65 166.53,28.79 162.51,28.79 162.38,28.92 162.38,29.89 162.26,30.01 158.26,30.01 158.13,30.14 158.13,30.46 157.99,30.6 157.42,30.6 157.28,30.46 157.28,30.14 157.13,29.99 156.63,29.99 156.48,30.14 156.48,30.88 156.35,31.01 155.21,31.01 155.09,31.13 155.09,31.33 154.96,31.46 154.38,31.46 154.26,31.33 154.26,31.13 154.1,30.98 153.62,30.98 153.47,31.13 153.47,31.41 153.34,31.54 152.8,31.54 152.67,31.41 152.67,31.13 152.53,30.99 151.96,30.99 151.82,31.13 151.82,31.41 151.69,31.54 147.53,31.54 147.19,31.88 147.19,32.14 147.39,32.34 147.39,32.63 147.18,32.83 146.89,32.83 146.77,32.71 146.4,32.71 144.67,34.43 142.18,34.43 142.05,34.56 142.05,34.94 141.87,35.12 141.42,35.12 141.24,34.94 141.24,34.56 141.12,34.43 140.41,34.43 140.1,34.74 140.1,34.92 140.58,35.4 140.58,35.58 140.28,35.89 140.1,35.89 139.38,35.16 139.2,35.16 138.92,35.44 138.92,35.62 139.77,36.47 139.77,36.62 139.12,37.26 138.91,37.26 138.76,37.11 138.76,36.94 138.93,36.77 138.93,36.7 138.37,36.13 138.19,36.13 137.54,36.78 137.54,36.96 137.91,37.33 137.91,37.51 137.6,37.82 137.42,37.82 136.99,37.39 136.81,37.39 136.47,37.73 136.47,37.91 136.9,38.33 136.9,38.57 136.73,38.74 135.7,38.74 135.57,38.87 135.57,39.34 135.7,39.46 136.22,39.46 136.35,39.59 136.35,40.03 136.22,40.16 135.7,40.16 135.57,40.29 135.57,40.71 135.7,40.83 136.19,40.83 136.31,40.96 136.31,41.42 136.19,41.55 135.7,41.55 135.57,41.67 135.57,42.08 135.7,42.21 136.26,42.21 136.38,42.33 136.38,42.87 136.21,43.05 v1(136.12,43.05)
  IN4 w0.076: v4(161.98,16.12) 161.97,16.12 161.97,16.14 161.85,16.02 161.45,16.02 161.39,15.97 159.19,15.97 158.94,15.72 157.36,15.72 157.25,15.83 155.88,15.83 v3(155.64,16.07) 155.38,15.81 154.88,15.81 154.27,16.42 153.94,16.42 153.61,16.75 153.08,16.75 152.77,17.06 150.78,17.06 150.71,17.14 150.71,17.36 150.63,17.44 150.48,17.44 150.4,17.36 150.4,17.14 150.33,17.06 149.44,17.06 v4(149.1,16.72) ; v4(173.74,16.72) 173.43,16.72 173.29,16.86 173.29,16.98 173.45,17.14 175.9,17.14 176.08,16.96 177.67,16.96 178.24,16.39 179.01,16.39 179.26,16.15 180.41,16.15 v3(180.44,16.11) 180.59,15.97 181.55,15.97 181.66,15.87 181.98,15.87 182.07,15.78 182.83,15.78 182.92,15.69 183.28,15.69 183.56,15.97 186.46,15.97 v4(186.62,16.13)
  BOTTOM w0.076: UCPU1.AR45 136.71,43.18 136.71,43.07 136.46,42.83 136.16,42.83 136.12,42.87 v1(136.12,43.05) ; UD7.P8 160.79,16.72 161.19,16.32 161.77,16.32 v4(161.98,16.12) ; UD10.P8 185.58,16.44 186.31,16.44 v4(186.62,16.13)
DDR_B_MA5: length 146.6
  TOP w0.076: v1(168.09,11.42) 168.09,11.81 RD56.1
  IN1 w0.076: v3(157.03,12.23) 156.81,12.23 156.68,12.11 156.68,11.31 156.81,11.18 157.36,11.18 157.48,11.31 157.48,12.32 157.64,12.47 159.03,12.47 160.23,11.28 167.95,11.28 v1(168.09,11.42) 168.15,11.36 169.28,11.36 169.66,11.74 181.21,11.74 181.7,12.23 v3(182.24,12.23)
  IN2 w0.191: v1(136.12,43.68) 135.64,43.19 135.64,42.75 135.22,42.33 133.09,42.33 131.93,41.18 131.93,39.46 131.97,39.42 131.97,34.8 132.72,34.05 132.72,32.15 135.38,29.49 138.46,29.49 140.49,27.46 142.37,27.46 142.66,27.17 143.43,27.17 143.44,27.17 144.23,27.17 144.5,26.91 144.5,26.39 144.37,26.26 143.84,26.26 143.72,26.13 143.72,25.75 143.84,25.62 144.45,25.62 144.87,25.2 145.8,25.2 146.07,24.93 146.07,23.7 146.74,23.04 147.35,23.04 147.48,22.91 147.48,22.58 147.6,22.46 148.14,22.46 148.26,22.58 148.26,23.18 148.39,23.31 149.84,23.31 149.96,23.18 149.96,21.35 150.09,21.23 150.41,21.23 150.54,21.1 150.54,20.65 150.41,20.53 150.09,20.53 149.96,20.4 149.96,20.06 150.09,19.93 152.41,19.93 152.77,19.57 154.68,19.57 154.8,19.7 154.8,20.09 154.93,20.22 155.57,20.22 155.69,20.09 155.69,19.09 156.06,18.72 156.88,18.72 156.99,18.62 157.47,18.62 157.91,19.07 158.17,19.07 158.78,18.46 161.05,18.46 161.34,18.16 161.34,16.7 161.47,16.57 161.94,16.57 162.07,16.7 162.07,17.66 162.19,17.78 162.54,17.78 162.66,17.66 162.66,16.7 162.79,16.58 163.24,16.58 163.36,16.7 163.36,16.93 163.49,17.06 163.96,17.06 164.09,16.93 164.09,16.6 165.58,15.1 166.57,15.1 167.16,14.51 167.16,12.96 168.09,12.03 v1(168.09,11.42)
  IN4 w0.076: v4(151.93,13.48) 152.35,13.9 152.82,13.9 155.17,11.55 156.34,11.55 v3(157.03,12.23) 157.67,12.23 157.88,12.44 159.02,12.44 159.08,12.37 161.8,12.37 164.3,14.88 164.3,15.24 164.62,15.56 164.87,15.56 165.03,15.71 165.03,16.29 v4(165.46,16.72) ; v4(176.71,13.25) 176.71,13.35 177.2,13.84 177.92,13.84 179.73,12.03 181.46,12.03 181.66,12.23 v3(182.24,12.23) 182.41,12.41 186.97,12.41 187.04,12.48 187.04,13.33 189.22,15.51 189.39,15.51 189.66,15.79 189.66,16.11 189.68,16.11 189.84,16.27 189.96,16.27 190.1,16.41 v4(190.1,16.72)
  BOTTOM w0.076: UCPU1.AP45 136.39,43.95 v1(136.12,43.68) ; v4(176.71,13.25) 176.71,13.35 177.37,14.01 177.37,15.25 177.7,15.58 177.85,15.58 178.11,15.84 178.11,16.3 UD9.P2 ; UD6.P2 153.48,16.3 153.48,15.82 153.11,15.46 152.96,15.46 152.76,15.26 152.76,15.26 152.73,15.23 152.73,14.28 v4(151.93,13.48)
DDR_B_MA6: length 143.2
  TOP w0.076: RD36.1 168.33,14.41 v1(168.58,14.16)
  IN1 w0.076: v3(181.04,14.61) 181.04,14.49 180.83,14.28 177.35,14.28 176.41,13.34 170.79,13.34 169.68,14.46 168.88,14.46 v1(168.58,14.16) 168.54,14.16 167.91,13.53 166.64,13.53 166.07,12.96 165.71,12.96 165.1,13.57 164.73,13.57 164.42,13.88 160.03,13.88 159.59,14.33 157.38,14.33 157.17,14.54 156.47,14.54 v3(156.34,14.67)
  IN2 w0.076: v1(135.16,40.52) 134.97,40.52 134.84,40.65 134.84,41.03 134.74,41.14 134.59,41.14 134.48,41.03 134.48,40.44 134.36,40.31 133.99,40.31 133.86,40.19 133.86,39.62 133.49,39.25 133.49,36.31 133.67,36.13
  IN2 w0.191: 133.67,36.13 133.94,35.87 134.41,35.87 135.36,34.92 135.36,33.71 135.46,33.6 135.46,33.13 135.59,33 136.15,33 136.33,32.82 136.33,32.22 137.44,31.11 140.66,31.11 140.9,30.87 140.9,29.99 141.02,29.86 141.52,29.86 141.65,29.99 141.65,30.13 141.77,30.25 142.4,30.25 142.52,30.13 142.52,29.99 142.65,29.86 143.16,29.86 143.28,29.99 143.28,30.13 143.41,30.25 143.93,30.25 144.06,30.13 144.06,29.69 144.29,29.45 144.63,29.11 145.05,29.11 145.39,29.45 145.57,29.45 145.86,29.16 145.86,28.98 145.69,28.81 145.69,28.63 145.97,28.35 146.15,28.35 146.55,28.74 146.75,28.74 146.88,28.61 146.88,28.48 147.01,28.35 147.44,28.35 147.56,28.48 147.56,28.61 147.69,28.74 148.29,28.74 148.42,28.61 148.42,28.48 148.54,28.35 148.75,28.35 149.35,27.76 149.63,27.76 149.72,27.66 149.72,26.2 149.85,26.07 150.35,26.07 150.47,26.2 150.47,27.69 150.6,27.81 151.16,27.81 151.29,27.69 151.29,25.89 151.41,25.76 151.97,25.76 152.1,25.89 152.1,27.69 152.23,27.81 152.89,27.81 153.01,27.69 153.01,25.76 153.14,25.63 153.24,25.63 153.37,25.51 153.37,25.4 153.49,25.27 154.53,25.27 154.66,25.4 154.66,26.13 154.53,26.26 153.84,26.26 153.71,26.39 153.71,27.05 153.84,27.17 154.48,27.17 155.28,27.17 155.57,26.89 155.57,26.03 155.86,25.74 155.86,25.52 155.67,25.33 155.67,25.16 156.15,24.67 156.33,24.67 156.78,25.12 157.27,25.12 157.4,25 157.4,24.81 157.53,24.68 157.83,24.68 157.95,24.81 157.95,25.01 158.08,25.13 158.41,25.13 158.76,24.79 158.76,24.61 157.91,23.76 157.91,23.58 158.37,23.13 158.55,23.13 159.16,23.74 159.69,23.74 159.81,23.87 159.81,24.01 159.94,24.13 160.6,24.13 160.73,24.01 160.73,23.4 160.94,23.18 161.55,23.18 161.64,23.09 162.18,23.09 162.47,22.8 162.47,22.16 163,21.63 163,21.52 162.51,21.02 162.51,20.84 162.84,20.51 163.02,20.51 163.47,20.95 163.68,20.95 164.12,20.52 164.3,20.52 164.62,20.19 164.62,19.73 164.43,19.54 164.43,19.36 165.09,18.7 165.27,18.7 165.64,19.07 165.82,19.07 166.16,18.73 166.16,18.55 165.96,18.35 165.96,18.17 166.23,17.9 166.41,17.9 166.67,18.16 167.03,18.16 167.82,17.38 167.82,16.59 168.65,15.76 168.65,15.22 168.53,15.09 168.49,15.09 168.37,14.96 168.37,14.58 168.58,14.37 v1(168.58,14.16)
  IN4 w0.076: v4(173.74,15.92) 173.69,15.92 173.56,16.05 173.56,16.17 173.69,16.3 175.44,16.3 176.27,15.47 177.61,15.47 177.7,15.38 178.53,15.38 179.59,14.31 180.75,14.31 v3(181.04,14.61) 181.27,14.61 181.37,14.51 182.48,14.51 182.53,14.45 183.07,14.45 183.26,14.64 183.47,14.64 183.76,14.36 186.59,14.36 186.72,14.48 186.72,14.6 v4(186.59,14.73) ; v4(161.95,14.75) 161.62,14.41 161.04,14.41 160.97,14.33 160.97,14.19 160.89,14.11 160.74,14.11 160.66,14.19 160.66,14.33 160.59,14.41 160.44,14.41 160.36,14.33 160.36,14.19 160.28,14.11 160.13,14.11 160.05,14.19 160.05,14.33 159.98,14.41 159.77,14.41 159.7,14.33 159.7,14.14 159.61,14.06 159.48,14.06 159.39,14.14 159.39,14.33 159.32,14.41 158.96,14.41 158.8,14.25 157.84,14.25 157.76,14.33 157.23,14.33 157.03,14.53 156.71,14.53 156.57,14.67 v3(156.34,14.67) 156.24,14.67 155.83,14.26 154.93,14.26 153.75,15.44 153.53,15.44 153.32,15.66 151.25,15.66 151.07,15.84 150.89,15.84 150.71,15.66 150.45,15.66 150.22,15.89 150.22,16.13 150.16,16.19 150.16,16.2 150.07,16.3 149.29,16.3 149.1,16.11 v4(149.1,15.92)
  BOTTOM w0.076: v4(161.95,14.75) 161.95,15.1 161.6,15.46 161.12,15.46 UD7.R8 ; v1(135.16,40.52) 135.16,40.71 135.29,40.84 UCPU1.AW46 ; UD10.R8 185.3,16.02 185.4,16.13 185.56,16.13 185.66,16.02 185.66,15.59 185.79,15.46 186.48,15.46 186.59,15.35 v4(186.59,14.73)
DDR_B_MA7: length 150.4
  TOP w0.076: RD48.1 172.96,11.26 172.74,11.03 v1(171.77,11.03)
  IN1 w0.076: v3(158.7,11.8) 158.86,11.8 159.91,10.75 171.03,10.75 171.31,11.03 v1(171.77,11.03) 172.75,11.03 173.31,10.47 176.76,10.47 177.05,10.76 182.78,10.76 183.35,11.33 v3(183.35,11.57)
  IN2 w0.191: v1(135.16,39.21) 135.26,39.12 135.26,38.55 139.77,34.04 144.49,34.04 147.39,31.14 151.25,31.14 151.8,30.6 155.44,30.6 156.44,29.61 161.88,29.61 161.99,29.49 161.99,28.53 162.12,28.4 166.06,28.4 166.33,28.12 166.33,25.38 168.72,22.99 168.72,21.96 168.2,21.44 168.2,20.79 168.1,20.69 168.1,18.68 169,17.77 169,17.08 169.83,16.26 169.83,15.08 171.32,13.59 171.32,10.21 171.44,10.08 174.54,10.08 175.21,10.75 175.21,11.55 175.34,11.67 178.75,11.67 178.94,11.87 178.94,12.46 178.75,12.65 174.34,12.65 174.21,12.52 174.21,10.88 174.08,10.75 172.65,10.75 172.52,10.88 172.52,11.79 172.4,11.92 171.9,11.92 171.77,11.79 v1(171.77,11.03)
  IN4 w0.076: v4(152.73,13.12) 152.83,13.12 154.96,10.99 158.07,10.99 158.36,11.28 158.36,11.46 v3(158.7,11.8) 162.73,11.8 162.8,11.88 162.8,12.14 162.88,12.22 163.03,12.22 163.11,12.14 163.11,11.88 163.18,11.8 163.43,11.8 163.63,12 163.63,13.01 164.09,13.47 164.72,13.47 164.99,13.73 164.99,15.31 165.46,15.78 v4(165.46,15.92) ; v4(177.59,13.2) 179.29,11.5 179.58,11.5 179.69,11.4 179.69,11.21 179.79,11.11 179.97,11.11 180.07,11.21 180.07,11.3 180.17,11.4 180.38,11.4 180.49,11.3 180.49,11.21 180.59,11.11 180.79,11.11 180.89,11.21 180.89,11.32 180.99,11.43 181.22,11.43 181.32,11.32 181.32,11.18 181.43,11.08 182.86,11.08 v3(183.35,11.57) 183.59,11.81 187.13,11.81 187.95,12.63 187.95,12.74 187.75,12.93 187.75,13.04 187.86,13.15 187.97,13.15 188.16,12.95 188.27,12.95 188.38,13.06 188.38,13.17 188.18,13.36 188.18,13.47 188.29,13.58 188.4,13.58 188.59,13.38 188.7,13.38 189.79,14.48 189.79,15.35 190.1,15.65 v4(190.1,15.92)
  BOTTOM w0.076: UCPU1.AY46 135.56,39.61 v1(135.16,39.21) ; UD9.R2 178.15,15.53 178.15,13.76 v4(177.59,13.2) ; v4(152.73,13.12) 153.17,13.12 v2(153.37,13.33) 153.55,13.5 153.55,15.43 153.9,15.79 UD6.R2
DDR_B_MA8: length 141.7
  TOP w0.076: v1(169.23,12.6) 169.28,12.66 RD42.1
  IN1 w0.076: v3(180.24,13.02) 180.32,12.94 180.32,12.35 180.24,12.27 179.88,12.27 179.8,12.35 179.8,13.06 179.73,13.14 179.57,13.14 179.5,13.06 179.5,12.35 179.42,12.27 179.27,12.27 179.19,12.35 179.19,12.88 179.14,12.93 178.97,12.93 178.89,12.85 178.89,12.35 178.81,12.27 169.98,12.27 169.65,12.6 v1(169.23,12.6) 169.23,12.13 169.01,11.92 168.56,11.92 168.1,12.37 167.03,12.37 166.51,11.85 160.44,11.85 159.29,13.01 155.68,13.01 v3(155.54,12.87)
  IN2 w0.076: 134.03,36.24 133.66,36.6 133.66,39.19 134.02,39.56 134.02,40.03 134.15,40.16 134.83,40.16 v1(135.16,39.84)
  IN2 w0.191: v1(169.23,12.6) 169.31,12.52 169.31,11.03 169.12,10.84 166.15,10.84 165.28,11.71 163.56,11.71 163.37,11.51 163.37,11.11 163.56,10.92 165.02,10.92 165.79,10.14 166.83,10.14 167.02,9.95 167.02,9.03 167.21,8.83 167.49,8.83 167.68,9.03 167.68,9.95 167.87,10.14 169.63,10.14 169.87,10.38 169.87,13.03 169.03,13.87 169.03,15.94 168.21,16.76 168.21,17.45 166.36,19.3 166.36,20.99 166.23,21.12 165.83,21.12 165.7,20.99 165.7,20.89 165.57,20.77 165.14,20.77 165.01,20.89 165.01,20.99 164.89,21.12 163.98,21.12 162.91,22.2 162.91,22.83 162.34,23.4 162.34,23.74 160.99,25.09 160.66,25.09 160.04,24.46 159.81,24.46 159.55,24.72 159.55,24.92 159.67,25.04 159.67,25.23 159.38,25.52 159.21,25.52 158.98,25.29 158.72,25.29 158.49,25.52 156.55,25.52 155.9,26.17 155.9,27.11 155.51,27.5 155.06,27.5 154.42,28.14 149.51,28.14 148.52,29.14 146.57,29.14 145.86,29.85 145.05,29.85 144.25,30.65 141.67,30.65 140.82,31.5 137.6,31.5 136.73,32.38 136.73,32.98 135.78,33.92 135.78,35.05 134.6,36.24 134.03,36.24
  IN4 w0.076: v4(173.74,15.12) 173.74,15.32 174.02,15.6 174.55,15.6 175.35,14.81 175.73,14.81 175.81,14.72 175.81,14.34 175.89,14.26 178.27,14.26 179.51,13.02 v3(180.24,13.02) 180.31,13.08 180.91,13.08 181.05,12.95 184.35,12.95 184.42,13.02 184.42,13.11 184.5,13.19 184.65,13.19 184.73,13.11 184.73,13.02 184.8,12.95 185.1,12.95 v4(185.26,13.11) ; v4(161.53,13.21) 161.24,12.92 156.32,12.92 156.23,13.01 155.68,13.01 v3(155.54,12.87) 155.45,12.87 155.03,13.29 154.45,13.29 153.34,14.39 151.12,14.39 151.03,14.48 151.03,14.86 150.86,15.03 150.48,15.03 150.02,15.5 149.15,15.5 149.06,15.41 149.06,15.16 v4(149.1,15.12)
  BOTTOM w0.076: v4(161.53,13.21) 161.53,13.54 160.66,14.42 UD7.T8 ; v4(185.26,13.11) 185.26,13.16 185.82,13.72 185.82,14.6 UD10.T8 ; v1(135.16,39.84) 134.81,40.19 UCPU1.AY47
DDR_B_MA9: length 146.4
  TOP w0.076: v1(168.72,12.95) 168.55,12.78 RD52.1
  IN1 w0.076: v3(158.17,13.41) 158.17,13.5 158.23,13.57 158.6,13.57 158.87,13.3 159.06,13.3 159.17,13.41 159.36,13.41 159.97,12.81 160.08,12.81 160.11,12.84 160.22,12.84 160.33,12.73 160.33,12.62 160.3,12.59 160.3,12.38 160.47,12.2 160.6,12.2 160.65,12.25 160.65,12.64 160.7,12.69 160.85,12.69 160.91,12.63 160.91,12.17 160.95,12.13 163.19,12.13 163.27,12.21 163.27,13 163.34,13.07 163.49,13.07 163.57,13 163.57,12.21 163.65,12.13 166.41,12.13 167.01,12.73 168.5,12.73 v1(168.72,12.95) 169.01,12.95 169.07,13.01 169.64,13.01 170.11,12.54 178.17,12.54 179.04,13.41 180.88,13.41 181.18,13.11 183.2,13.11 183.58,13.49 v3(183.59,13.49)
  IN2 w0.076: v1(135.16,41.84) 135.19,41.87 135.19,42.04 135.11,42.12 134.45,42.12 134.32,42 134.32,41.9 134.39,41.83 134.7,41.83 134.78,41.75 134.78,41.6 134.7,41.52 134.39,41.52 134.32,41.45 134.32,40.58 134.2,40.47 134.03,40.47 133.92,40.58 133.92,41.39 133.79,41.52 133.39,41.52
  IN2 w0.191: 133.39,41.52 132.9,41.03 132.9,39.37 132.82,39.3 132.82,35.4 133.78,34.43 133.78,34.22 133.54,33.98 133.54,33.42 134.27,32.69 134.27,32.33 136.27,30.34 138.75,30.34 139.06,30.03 139.28,30.03 139.58,30.32 139.83,30.32 140.11,30.04 140.11,29.78 139.88,29.56 139.88,29.28 140.08,29.07 143.56,29.07 144.4,28.23 144.85,28.23 146.62,26.45 146.62,25.45 146.75,25.33 147.26,25.33 147.39,25.45 147.39,26.19 147.51,26.32 148.05,26.32 148.26,26.1 148.4,26.1 148.62,26.31 148.79,26.31 149.07,26.04 149.07,25.86 148.56,25.36 148.56,25.18 148.82,24.92 149,24.92 149.42,25.34 149.67,25.34 150.1,24.91 150.43,24.91 150.55,25.03 150.73,25.03 151.04,24.72 151.04,24.54 150.87,24.36 150.87,24.14 151.14,23.87 152.12,23.87 152.25,23.74 152.25,22.57 152.38,22.44 152.91,22.44 153.04,22.57 153.04,23.82 153.25,24.03 153.83,24.03 153.99,23.87 154.57,23.87 154.7,23.74 154.7,23.42 154.57,23.3 154.14,23.3 154.02,23.17 154.02,22.85 154.14,22.72 154.64,22.72 154.77,22.59 154.77,22.59 155.08,22.28 156.07,22.28 156.2,22.15 156.2,21.45 156.33,21.32 156.7,21.32 156.82,21.45 156.82,21.85 156.95,21.97 157.86,21.97 158.35,21.49 158.35,20.84 158.27,20.77 158.27,20.28 158.71,19.84 158.71,19.45 158.84,19.32 159.31,19.32 159.44,19.45 159.44,19.75 159.56,19.88 160,19.88 160.12,19.75 160.12,19.45 160.25,19.32 160.63,19.32 160.76,19.45 160.76,19.73 160.89,19.86 161.29,19.86 161.42,19.73 161.42,19.04 161.55,18.91 162.18,18.91 162.31,19.04 162.31,19.14 162.44,19.27 163.02,19.27 163.21,19.08 163.21,18.88 163.02,18.69 163.02,18.54 163.26,18.3 163.51,18.3 163.82,18.61 164.1,18.61 165.22,17.48 165.22,17.27 164.85,16.89 164.85,16.77 165.27,16.35 165.6,16.35 165.81,16.56 166.2,16.56 166.47,16.29 166.76,16.29 166.98,16.51 167.43,16.51 168.15,15.8 168.15,15.32 168.02,15.19 167.67,15.19 167.54,15.07 167.54,13.88 167.67,13.75 168.4,13.75 168.52,13.62 168.52,13.44 168.4,13.31 167.86,13.31 167.73,13.19 167.73,12.95 167.86,12.82 168.6,12.82 v1(168.72,12.95)
  IN4 w0.076: v4(189.3,15.92) 186.74,13.36 186.63,13.36 186.57,13.42 186.57,13.66 186.49,13.73 186.34,13.73 186.26,13.66 186.26,13.6 186.26,13.6 186.26,13.44 186.22,13.4 186.04,13.4 185.96,13.48 185.96,13.66 185.88,13.73 185.73,13.73 185.65,13.66 185.65,13.6 185.58,13.53 185.43,13.53 185.35,13.6 185.35,13.66 185.27,13.73 185.12,13.73 185.05,13.66 185.05,13.6 184.97,13.53 184.81,13.53 184.74,13.6 184.74,13.66 184.66,13.73 184.51,13.73 184.43,13.66 184.43,13.6 184.43,13.6 184.43,13.49 184.36,13.41 184.19,13.41 184.13,13.48 184.13,13.66 184.05,13.73 183.9,13.73 183.82,13.66 183.82,13.6 183.75,13.53 183.63,13.53 v3(183.59,13.49) 183.32,13.22 181.16,13.22 181.03,13.35 180.7,13.35 180.54,13.5 179.42,13.5 178.34,14.58 177.09,14.58 v4(176.94,14.73) ; v4(164.66,15.92) 163.95,15.22 163.95,15.11 164.03,15.03 164.03,14.92 163.92,14.81 163.82,14.81 163.74,14.89 163.63,14.89 163.52,14.79 163.52,14.68 163.6,14.6 163.6,14.49 163.49,14.38 163.39,14.38 163.31,14.46 163.2,14.46 163.09,14.35 163.09,14.25 163.17,14.17 163.17,14.06 163.06,13.95 162.95,13.95 162.87,14.03 162.77,14.03 162.66,13.92 162.66,13.82 162.74,13.74 162.74,13.63 162.63,13.52 162.52,13.52 162.44,13.6 162.34,13.6 162.26,13.53 161.37,13.53 161.14,13.3 158.28,13.3 v3(158.17,13.41) 157.94,13.19 157.85,13.19 157.77,13.26 157.77,13.3 157.7,13.38 157.55,13.38 157.47,13.3 157.47,13.26 157.39,13.19 156.44,13.19 156.35,13.28 155.42,13.28 155.14,13.56 154.5,13.56 153.46,14.6 153.01,14.6 152.93,14.67 152.93,14.93 152.85,15 152.7,15 152.63,14.93 152.63,14.67 152.55,14.6 152.44,14.6 v4(152.3,14.73)
  BOTTOM w0.076: UCPU1.AU46 135.61,42.24 135.48,42.37 135.29,42.37 135.23,42.3 135.08,42.3 134.95,42.17 134.95,41.96 135.08,41.84 v1(135.16,41.84) ; v4(152.3,14.73) 152.3,15.12 UD6.R3 ; UD9.R3 177.58,15.92 176.94,15.28 v4(176.94,14.73)
DDR_B_MA10: length 146.4
  TOP w0.076: RD32.1 170.37,20.84 170.02,20.84 v1(169.99,20.87)
  IN1 w0.076: v3(180.54,20.23) 180.54,20.21 180.66,20.08 181.41,20.08 181.52,19.97 181.52,19.81 181.41,19.7 180.14,19.7 180.07,19.78 180.07,20.58 179.98,20.67 179.85,20.67 179.76,20.58 179.76,20.23 179.67,20.15 179.55,20.15 179.46,20.23 179.46,20.31 179.37,20.4 179.07,20.4 178.59,19.93 175.52,19.93 175.13,19.53 172.76,19.53 171.43,20.87 v1(169.99,20.87) 168.76,20.87 167.79,19.89 166.67,19.89 166.04,19.26 159.04,19.26 157.75,20.55 156.11,20.55 v3(156.02,20.46)
  IN2 w0.191: v1(169.99,20.87) 170.44,20.87 170.69,21.12 170.69,22.88 170.82,23 171.09,23 171.22,23.13 171.22,23.96 171.35,24.08 171.86,24.08 171.99,24.21 171.99,24.73 171.86,24.86 171.09,24.86 170.96,24.99 170.96,25.38 171.09,25.5 171.88,25.5 172.01,25.63 172.01,26.13 171.88,26.25 170.59,26.25 170.46,26.38 170.46,26.83 170.59,26.95 171.47,26.95 171.59,27.08 171.59,27.8 171.72,27.93 172.75,27.93 172.88,28.06 172.88,28.64 172.75,28.77 171.55,28.77 171.43,28.89 171.43,29.47 171.55,29.59 172.75,29.59 172.88,29.72 172.88,30.26 172.75,30.38 171.72,30.38 171.59,30.51 171.59,31.72 170.5,32.81 169.23,32.81 169.1,32.94 169.1,34.71 168.98,34.84 168.3,34.84 168.18,34.71 168.18,32.86 168.05,32.73 167.39,32.73 167.26,32.86 167.26,34.71 167.14,34.84 166.48,34.84 166.35,34.71 166.35,33.67 166.22,33.54 165.7,33.54 165.57,33.67 165.57,34.71 165.45,34.84 164.86,34.84 164.73,34.71 164.73,33.49 164.61,33.37 164.02,33.37 163.9,33.49 163.9,34.71 163.77,34.84 163.17,34.84 163.05,34.71 163.05,33.81 162.92,33.68 162.4,33.68 162.27,33.81 162.27,34.71 162.14,34.84 161.6,34.84 161.47,34.71 161.47,33.96 161.35,33.84 160.79,33.84 160.66,33.96 160.66,34.71 160.53,34.84 159.97,34.84 159.85,34.71 159.85,34.28 159.72,34.15 159.16,34.15 159.03,34.28 159.03,34.71 158.91,34.84 158.18,34.84 158.05,34.71 158.05,34.28 157.93,34.15 157.24,34.15 157.11,34.28 157.11,34.71 156.99,34.84 156.33,34.84 156.21,34.71 156.21,34.29 156.08,34.17 155.52,34.17 155.39,34.29 155.39,34.71 155.27,34.84 151.43,34.84 150.63,35.64 148.8,35.64 148.67,35.77 148.67,36.27 148.54,36.4 147.86,36.4 147.73,36.27 147.73,35.86 147.61,35.73 146.87,35.73 146.74,35.86 146.74,36.27 146.61,36.4 144.08,36.4 143.47,37.02 143.47,37.77 142.84,38.4 142.58,38.4 142.3,38.11 142.12,38.11 141.9,38.34 141.9,38.52 142.19,38.82 142.19,39.04 142.04,39.2 142.04,39.41 141.79,39.67 141.79,40.2 142.04,40.45 142.04,41.84 140.97,42.9 140.97,45.3 140.84,45.43 140.52,45.43 140.39,45.56 140.39,46.05 140.52,46.18 141.24,46.18 141.36,46.31 v1(141.36,46.38)
  IN4 w0.076: v4(162.12,20.09) 161.84,20.09 161.37,19.62 158.5,19.62 157.67,20.45 156.04,20.45 v3(156.02,20.46) 156.02,20.18 155.75,19.92 153.27,19.92 153.1,20.08 153.1,20.54 152.97,20.67 151.16,20.67 150.51,20.02 150.51,19.88 149.9,19.27 v4(149.9,19.12) ; v4(174.54,19.12) 174.54,19.29 175.95,20.7 177.89,20.7 177.93,20.74 178.32,20.74 178.43,20.64 178.81,20.64 178.93,20.51 178.93,20.25 179.06,20.12 179.24,20.12 179.37,20.25 179.37,20.5 179.49,20.63 179.67,20.63 179.8,20.5 179.8,20.25 179.92,20.12 180.43,20.12 v3(180.54,20.23) 180.7,20.07 182.38,20.07 182.54,19.91 182.88,19.91 183.11,19.68 186.05,19.68 186.31,19.94 186.65,19.94 v4(186.82,20.11)
  BOTTOM w0.076: v4(162.12,20.09) 162.12,20.04 161.46,19.38 UD7.L7 ; UCPU1.AK36 141.54,46.55 v1(141.36,46.38) ; v4(186.82,20.11) 186.82,20.06 186.1,19.33 UD10.L7
DDR_B_MA11: length 143.2
  TOP w0.076: RD54.1 169.91,13.95 v1(169.91,13.66)
  IN1 w0.076: v3(181.28,14.06) 181.19,13.97 178.85,13.97 178.16,13.29 177.96,13.29 177.88,13.36 177.87,13.36 177.87,13.71 177.84,13.74 177.61,13.74 177.57,13.7 177.57,13.15 177.49,13.07 177.34,13.07 177.26,13.15 177.26,13.47 177.19,13.54 177.03,13.54 176.96,13.47 176.96,13.15 176.88,13.07 170.49,13.07 v1(169.91,13.66) 168.46,13.66 168.06,13.26 166.75,13.26 166.18,12.69 165.6,12.69 164.99,13.3 164.62,13.3 164.31,13.61 159.92,13.61 159.41,14.12 157.22,14.12 157.05,14.29 156.45,14.29 v3(156.23,14.06)
  IN2 w0.076: v1(134.4,39.6) 134.4,39.52 133.81,38.93 133.81,37.3 134.01,37.1
  IN2 w0.191: v1(169.91,13.66) 170.27,13.3 170.27,9.96 170.05,9.74 168.23,9.74 168.07,9.57 168.07,9.34 168.23,9.18 170.35,9.18 170.94,9.76 170.94,13.42 169.43,14.93 169.43,16.09 168.61,16.92 168.61,17.61 167.77,18.45 167.77,18.98 167.64,19.1 167.41,19.1 167.29,19.23 167.29,19.82 167.41,19.94 167.64,19.94 167.77,20.07 167.77,20.58 167.64,20.7 167.02,20.7 166.89,20.83 166.89,21.33 166.77,21.45 164.73,21.45 164.6,21.58 164.6,22.47 164.47,22.6 163.97,22.6 163.84,22.72 163.84,23.31 163.71,23.44 163.71,24.34 163.58,24.46 163.19,24.46 163.06,24.34 163.06,24.14 162.93,24.01 162.58,24.01 162.45,24.14 162.45,24.3 161.3,25.44 160.02,25.44 159.9,25.57 159.9,27.88 159.77,28.01 159.08,28.01 158.96,27.88 158.96,25.97 158.83,25.85 158.22,25.85 158.09,25.97 158.09,27.88 157.97,28.01 157.41,28.01 157.28,27.88 157.28,26.1 157.15,25.98 156.61,25.98 156.48,26.1 156.48,27.88 156.35,28.01 155.12,28.01 154.65,28.48 149.74,28.48 148.69,29.53 146.74,29.53 146.02,30.24 145.22,30.24 144.42,31.04 141.84,31.04 140.98,31.9 138.58,31.9 137.56,32.92 137.34,32.92 136.18,34.09 136.18,35.34 134.42,37.1 134.01,37.1
  IN4 w0.076: v4(149.9,15.92) 150.37,15.45 151.04,15.45 151.12,15.38 151.12,15.06 151.26,14.93 151.32,14.93 151.42,15.03 151.42,15.38 151.5,15.45 153.15,15.45 153.36,15.24 153.59,15.24 154.81,14.03 155.42,14.03 155.64,13.81 155.98,13.81 v3(156.23,14.06) 156.44,14.28 156.98,14.28 157.13,14.13 157.66,14.13 157.75,14.04 158.66,14.04 158.85,13.85 161.01,13.85 161.35,14.19 162.03,14.19 v4(162.59,14.75) ; v4(174.54,15.92) 174.54,15.9 175.18,15.25 175.4,15.25 175.47,15.33 175.47,15.64 175.55,15.71 175.7,15.71 175.78,15.64 175.78,15.33 175.85,15.25 177.42,15.25 177.56,15.11 178.49,15.11 179.5,14.1 180.71,14.1 180.88,13.94 181.16,13.94 v3(181.28,14.06) 181.52,14.3 182.35,14.3 182.41,14.24 183.42,14.24 183.51,14.15 186.95,14.15 187.32,14.52 187.32,14.63 187.23,14.72 v4(187.04,14.72)
  BOTTOM w0.076: v1(134.4,39.6) 134.44,39.65 134.44,41.19 UCPU1.AV47 ; v4(187.04,14.72) 187.04,15.33 186.61,15.76 186.47,15.76 186.3,15.92 UD10.R7
  BOTTOM w0.102: UD7.R7 162.59,14.79 v4(162.59,14.75)
DDR_B_MA12: length 142.5
  TOP w0.076: v1(167.36,16.97) 167.41,16.97 167.54,17.1 167.54,17.9 167.41,18.02 167.12,18.02 167.05,18.1 RD26.1
  IN1 w0.076: v3(156.77,16.93) 156.93,17.09 163.83,17.09 164.04,16.88 164.58,16.88 164.72,17.02 164.72,17.45 164.8,17.53 165,17.53 165.1,17.43 165.1,16.97 165.18,16.89 165.36,16.89 165.43,16.97 165.43,17.47 165.53,17.57 167.75,17.57 168.11,17.2 169.22,17.2 169.34,17.08 169.34,16.91 169.22,16.79 168.06,16.79 167.86,17 167.39,17 v1(167.36,16.97) 167.59,16.74 167.59,16.72 167.82,16.49 170.78,16.49 171.11,16.16 171.11,16.02 171.34,15.79 171.72,15.79 171.87,15.64 172.77,15.64 173.27,16.13 173.37,16.13 173.59,16.35 175.47,16.35 175.55,16.27 175.55,16.01 175.63,15.93 175.78,15.93 175.85,16.01 175.85,16.27 175.93,16.35 176.03,16.35 177.25,17.58 177.96,17.58 178.04,17.5 178.04,16.97 178.09,16.91 178.3,16.91 178.34,16.95 178.34,17.5 178.42,17.58 180.57,17.58 180.93,17.21 180.93,16.93 181.06,16.8 v3(181.37,16.8)
  IN2 w0.076: v1(133.58,40.5) 133.58,40.63 133.45,40.76 133.25,40.76 133.12,40.63 133.12,39.55 133.21,39.46
  IN2 w0.191: 133.21,39.46 133.21,35.56 133.84,34.93 134.79,34.93 134.92,34.8 134.92,34.1 134.79,33.97 134.24,33.97 134.12,33.84 134.12,33.4 134.24,33.27 134.95,33.27 135.08,33.15 135.08,32.88 134.77,32.57 134.77,32.39 135.28,31.88 135.46,31.88 135.7,32.12 135.88,32.12 136.17,31.82 136.17,31.64 135.94,31.4 135.94,31.22 136.26,30.9 136.44,30.9 136.68,31.14 136.85,31.14 137.28,30.72 140.38,30.72 140.5,30.59 140.5,29.59 140.63,29.47 143.72,29.47 144.57,28.62 145.01,28.62 145.68,27.95 146.5,27.95 146.62,27.83 146.62,26.92 146.75,26.79 147.26,26.79 147.39,26.92 147.39,27.83 147.51,27.95 148.68,27.95 148.81,27.83 148.81,27.41 148.68,27.28 148.43,27.28 148.3,27.16 148.3,26.77 148.43,26.65 149.3,26.65 149.39,26.56 149.39,26.08 149.98,25.49 151.25,25.49 151.37,25.36 151.37,24.32 151.5,24.2 152.06,24.2 152.19,24.32 152.19,25.36 152.31,25.49 152.83,25.49 153.1,25.22 153.1,24.49 153.23,24.36 153.74,24.36 153.87,24.49 153.87,24.83 154,24.96 155.42,24.96 155.71,24.67 155.71,22.74 155.83,22.61 156.29,22.61 156.42,22.74 156.42,24.2 156.74,24.53 157.14,24.53 157.47,24.2 157.47,23.91 157.34,23.78 157.34,23.6 157.64,23.3 157.64,23.14 157.37,22.88 157.37,22.7 157.71,22.37 157.89,22.37 158.32,22.8 158.5,22.8 158.83,22.46 158.83,22.28 158.52,21.97 158.52,21.79 158.68,21.62 158.68,20.32 158.94,20.07 159.28,20.07 159.98,20.77 160.48,20.77 160.61,20.9 160.61,21.48 160.72,21.6 160.72,22.14 160.85,22.26 161.4,22.26 161.53,22.14 161.53,21.36 161.72,21.17 161.88,21.17 162.07,20.98 162.07,20.6 161.88,20.41 161.72,20.41 161.53,20.22 161.53,20.09 162.02,19.6 163.72,19.6 165.74,17.58 167.15,17.58 167.36,17.37 v1(167.36,16.97)
  IN4 w0.076: v4(149.9,17.52) 150.53,18.15 151.03,18.15 151.1,18.07 151.1,17.91 151.18,17.83 151.33,17.83 151.41,17.91 151.41,18.07 151.48,18.15 152.72,18.15 153.09,17.78 155.92,17.78 v3(156.77,16.93) 156.81,16.97 157.79,16.97 157.84,16.92 161.21,16.92 161.35,17.06 162.54,17.06 162.85,17.37 v4(162.85,17.52) ; v4(174.54,17.52) 175.76,17.52 175.76,17.52 176.41,18.16 177.61,18.16 177.88,17.89 180.52,17.89 181.09,17.31 181.09,17.01 181.3,16.8 v3(181.37,16.8) 181.47,16.91 181.96,16.91 182.22,17.17 182.69,17.17 183.08,16.78 186.16,16.78 186.4,17.02 186.83,17.02 v4(187.32,17.52)
  BOTTOM w0.076: v4(162.85,17.52) 162.42,17.08 161.67,17.08 161.46,17.3 UD7.N7 ; UD10.N7 186.1,17.45 186.46,17.08 186.89,17.08 v4(187.32,17.52) ; v1(133.58,40.5) 133.63,40.45 134.13,40.45 134.25,40.58 134.25,41.65 134.55,41.94 134.55,41.99 UCPU1.AU47
DDR_B_MA13: length 152.9
  TOP w0.076: RD46.1 173.85,11.44 v1(173.62,11.22)
  IN1 w0.076: v3(158.02,11.98) 158.24,12.21 158.9,12.21 160.1,11.01 170.74,11.01 171.19,11.46 173.38,11.46 v1(173.62,11.22) 175.25,11.22 175.73,10.74 176.51,10.74 176.88,11.11 176.88,11.36 176.96,11.43 177.11,11.43 177.19,11.36 177.19,11.11 177.26,11.04 177.41,11.04 177.49,11.11 177.49,11.36 177.57,11.43 177.72,11.43 177.79,11.36 177.79,11.11 177.87,11.04 178.03,11.04 178.1,11.11 178.1,11.4 178.18,11.47 178.33,11.47 178.41,11.4 178.41,11.11 178.48,11.04 178.64,11.04 178.71,11.11 178.71,11.4 178.79,11.47 178.94,11.47 179.02,11.4 179.02,11.11 179.09,11.04 179.25,11.04 179.32,11.11 179.32,11.4 179.4,11.47 179.55,11.47 179.63,11.4 179.63,11.11 179.7,11.04 179.86,11.04 179.93,11.11 179.93,11.4 180.01,11.47 180.16,11.47 180.24,11.4 180.24,11.11 180.31,11.04 180.46,11.04 180.54,11.11 180.54,11.4 180.62,11.47 180.77,11.47 180.85,11.4 180.85,11.11 180.92,11.04 181.07,11.04 181.15,11.11 181.15,11.4 181.23,11.47 181.38,11.47 181.46,11.4 181.46,11.11 181.53,11.04 181.95,11.04 182.08,11.17 182.08,11.48 182.54,11.94 182.9,11.94 v3(182.97,12.02)
  IN2 w0.191: v1(173.62,11.22) 173.82,11.41 173.82,12.69 175.17,14.04 177.36,14.04 178.48,15.16 178.48,17.46 179,17.97 179.78,17.97 181.88,20.07 182.27,20.07 182.31,20.03 182.93,20.03 183.05,20.16 183.05,21.49 182.87,21.67 182.87,27.82 182.74,27.94 180.93,27.94 180.8,28.07 180.8,28.81 180.93,28.93 182.04,28.93 182.17,29.06 182.17,29.9 182.04,30.03 180.93,30.03 180.8,30.15 180.8,30.92 180.93,31.04 182.04,31.04 182.17,31.17 182.17,32.05 182.04,32.17 180.93,32.17 180.8,32.3 180.8,35.53 177.83,38.5 166.51,38.5 164.67,40.34 159.59,40.34 158.16,41.76 155.32,41.76 154.8,42.28 148.02,42.28 147.04,43.26 147.04,46.45 146.76,46.73 146.31,46.73 145.86,47.18 143.36,47.18 v1(143.16,46.98)
  IN4 w0.076: v4(152.38,13.47) 152.5,13.59 152.73,13.59 155.07,11.26 157.25,11.26 157.51,11.52 157.51,11.59 157.9,11.98 v3(158.02,11.98) 158.23,12.19 158.87,12.19 158.97,12.1 161.91,12.1 163.79,13.98 163.92,13.98 164.01,13.89 164.14,13.89 164.24,13.99 164.24,14.12 164.14,14.22 164.14,14.35 164.24,14.44 164.37,14.44 164.46,14.36 164.58,14.36 164.67,14.44 164.67,14.57 164.58,14.66 164.58,14.77 164.66,14.85 v4(164.66,15.12) ; v4(177.16,13.22) 177.45,13.52 177.74,13.52 179.49,11.76 181.29,11.76 181.66,11.4 181.99,11.4 182.55,11.95 182.91,11.95 v3(182.97,12.02) 183.03,12.08 187.02,12.08 187.38,12.44 187.38,13.2 188.27,14.1 188.38,14.1 188.52,13.96 188.65,13.96 188.74,14.05 188.74,14.18 188.6,14.32 188.6,14.42 188.7,14.53 188.81,14.53 188.96,14.38 189.09,14.38 189.18,14.47 189.18,14.59 189.03,14.75 189.03,14.85 v4(189.3,15.12)
  BOTTOM w0.076: UCPU1.AK33 143.59,46.55 v1(143.16,46.98) ; v4(152.38,13.47) 152.56,13.47 153.1,14.01 UD6.T3 ; v4(177.16,13.22) 177.16,13.39 177.74,13.97 UD9.T3
DDR_B_MA14: length 146
  TOP w0.076: v1(166.94,11.69) 166.19,12.45 RD34.1
  IN1 w0.076: v3(156.12,12.56) 155.97,12.41 155.29,12.41 155.16,12.28 155.16,11.53 155.28,11.41 156.27,11.41 156.41,11.55 156.41,12.22 156.94,12.74 159.15,12.74 160.32,11.57 166.83,11.57 v1(166.94,11.69) 167.35,12.09 168,12.09 168.47,11.62 169.17,11.62 169.55,12 180.8,12 181.33,12.54 v3(181.35,12.54)
  IN2 w0.191: v1(135.18,43.11) 134.69,42.62 132.9,42.62 131.65,41.38 131.65,38.23 131.52,38.1 131.17,38.1 131.04,37.98 131.04,37.35 131.17,37.23 131.56,37.23 131.69,37.1 131.69,36.59 131.56,36.47 131.17,36.47 131.04,36.34 131.04,35.73 131.17,35.61 131.45,35.61 131.58,35.48 131.58,34.89 131.45,34.76 131.17,34.76 131.04,34.64 131.04,33.27 131.17,33.14 132.13,33.14 132.26,33.02 132.26,32.05 135.2,29.11 138.29,29.11 140.37,27.02 140.37,26.74 140.16,26.52 140.16,26.36 141.23,25.29 141.84,25.29 141.96,25.42 141.96,26.15 142.09,26.28 142.67,26.28 142.8,26.15 142.8,25.42 142.93,25.29 144.18,25.29 145.16,24.31 145.16,24.06 147.35,21.87 147.35,20.7 148.26,19.79 149.62,19.79 149.93,19.48 150.64,19.48 150.83,19.29 150.83,18.61 151.02,18.42 151.36,18.42 151.56,18.61 151.56,19.36 151.74,19.54 152,19.54 152.18,19.36 152.18,18.16 152.37,17.97 152.71,17.97 152.9,18.16 152.9,19.05 153.09,19.24 153.42,19.24 153.61,19.05 153.61,18.12 153.8,17.93 154.16,17.93 154.35,18.12 154.35,18.99 154.54,19.19 154.9,19.19 155.09,18.99 155.09,18.12 155.28,17.93 155.57,17.93 155.76,18.12 155.76,18.21 155.95,18.4 156.76,18.4 156.85,18.3 157.38,18.3 157.51,18.18 157.51,17.85 157.87,17.49 159.15,17.49 159.34,17.3 159.34,16.58 159.53,16.39 159.92,16.39 160.11,16.58 160.11,17 160.31,17.19 160.68,17.19 160.87,17 160.87,16.24 161.06,16.05 161.74,16.05 161.93,15.86 161.93,14.98 162.14,14.77 162.41,14.77 162.6,14.96 162.6,15.71 162.79,15.9 163.1,15.9 163.29,15.71 163.29,14.96 163.48,14.77 163.79,14.77 163.98,14.96 163.98,15.48 164.16,15.67 164.42,15.67 164.61,15.48 164.61,14.96 164.8,14.77 166.43,14.77 166.78,14.42 166.78,13.03 166.59,12.84 165.41,12.84 165.22,12.65 165.22,12.39 165.41,12.2 166.05,12.2 166.24,12.01 166.24,11.44 166.43,11.25 166.75,11.25 166.94,11.44 v1(166.94,11.69)
  IN4 w0.076: v4(185.82,13.1) 185.84,13.12 186.05,13.12 186.07,13.1 186.38,13.1 186.44,13.03 186.44,12.8 186.32,12.68 181.49,12.68 v3(181.35,12.54) 181.11,12.3 179.85,12.3 178.1,14.05 175.61,14.05 v4(174.54,15.12) ; v4(149.9,15.12) 149.77,14.99 149.77,14.54 150.14,14.18 153.03,14.18 154.8,12.4 155.96,12.4 v3(156.12,12.56) 156.24,12.68 161.52,12.68 v4(162.03,13.19)
  BOTTOM w0.076: UD10.T7 186.1,13.61 185.75,13.26 185.75,13.16 v4(185.82,13.1) ; v1(135.18,43.11) 135.18,43.06 135.31,42.93 135.53,42.93 135.66,43.06 UCPU1.AR46 ; UD7.T7 161.46,14.4 162.03,13.83 v4(162.03,13.19)
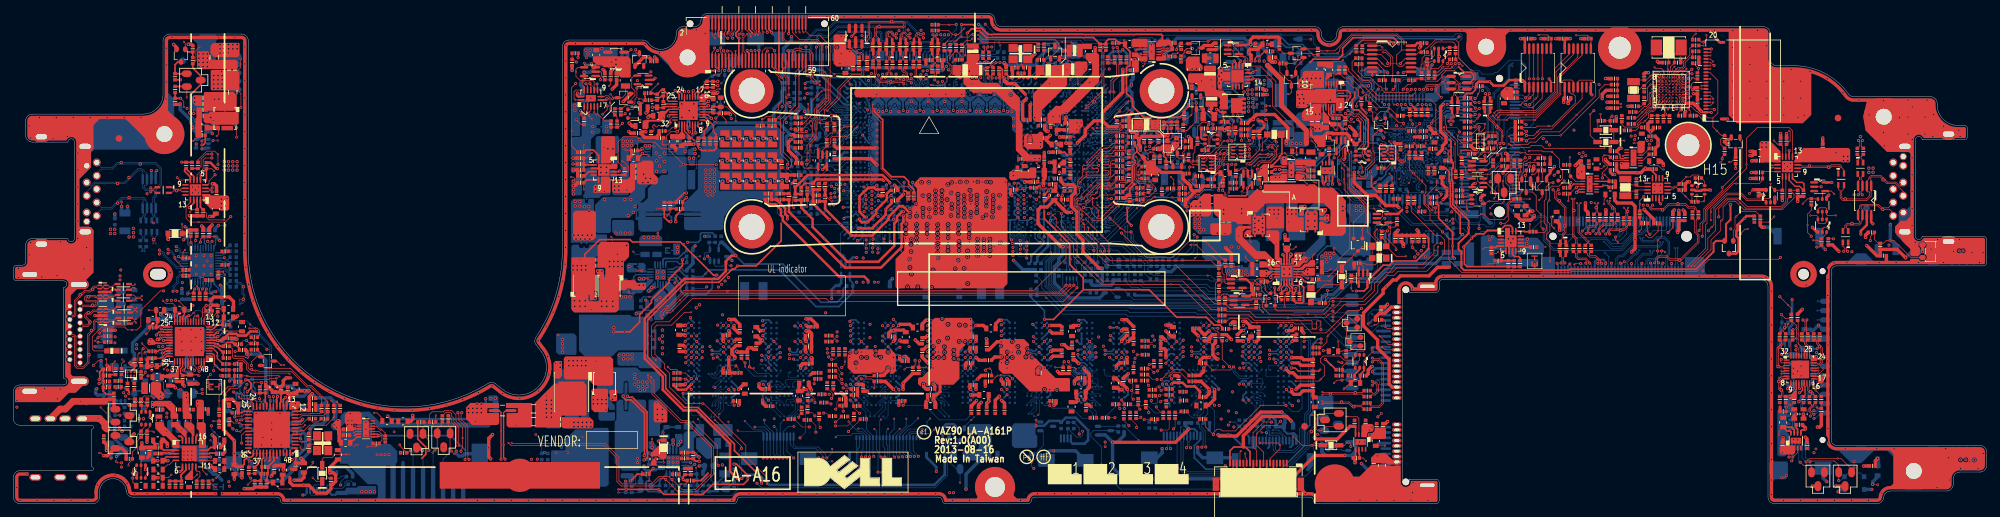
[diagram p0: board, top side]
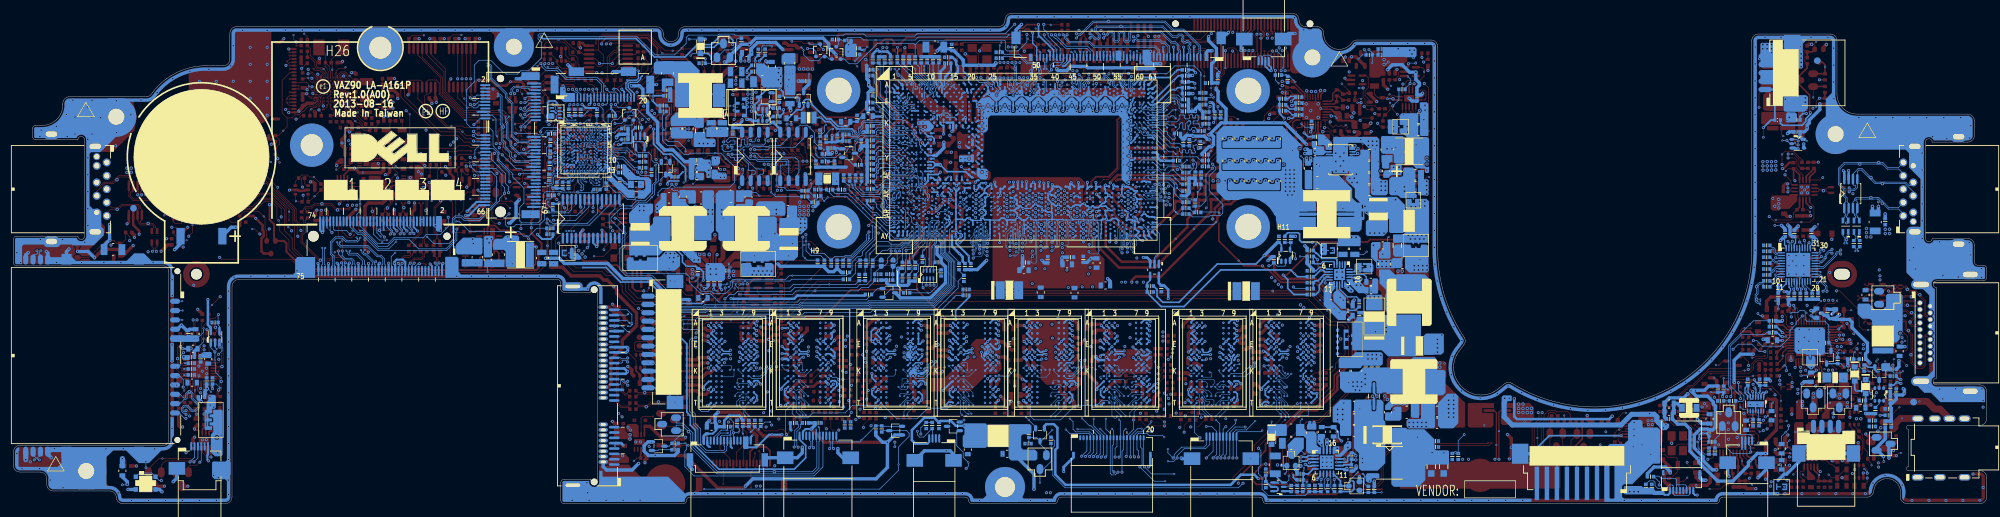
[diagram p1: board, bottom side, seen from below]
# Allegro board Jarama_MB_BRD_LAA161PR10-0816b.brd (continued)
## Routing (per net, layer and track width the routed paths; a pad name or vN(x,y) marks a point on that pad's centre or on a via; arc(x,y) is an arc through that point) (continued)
DDR_B_MA15: length 143.2
  TOP w0.076: v1(169.87,17.74) 169.75,17.85 RD28.1
  IN1 w0.076: v3(157.05,17.84) 157.68,17.84 158.01,17.51 164.2,17.51 164.68,17.99 167.9,17.99 168.15,17.74 v1(169.87,17.74) 170,17.61 170.36,17.61 171.22,16.74 171.43,16.74 171.59,16.58 171.92,16.58 172.4,17.06 174.01,17.06 175.25,18.3 178.97,18.3 179.09,18.42 180.85,18.42 v3(181.04,18.23)
  IN2 w0.191: v1(169.87,17.74) 169.87,18.02 168.99,18.9 168.99,19.13 169.26,19.4 169.26,19.67 168.99,19.93 168.99,21.09 169.77,21.87 169.77,23.07 168.34,24.5 168.34,25.28 168.2,25.42 167.98,25.42 167.36,26.04 167.12,26.04 167,26.17 167,26.66 167.12,26.79 167.57,26.79 167.7,26.91 167.7,27.5 167.57,27.63 167.19,27.63 167.06,27.75 167.06,28.24 167.19,28.36 167.57,28.36 167.7,28.49 167.7,29.06 167.57,29.19 162.93,29.19 162.78,29.34 162.78,30.28 162.65,30.41 158.77,30.41 158.52,30.66 158.52,31.48 158.35,31.66 157.96,31.66 157.8,31.5 157.8,31.12 157.68,31 157.04,31 156.91,31.12 156.91,31.56 156.69,31.78 156.69,32.37 156.56,32.49 156.18,32.49 156.05,32.37 156.05,31.53 155.92,31.4 155.55,31.4 155.43,31.53 155.43,32.39 155.3,32.52 154.85,32.52 154.73,32.39 154.73,31.98 154.6,31.85 154.16,31.85 154.03,31.98 154.03,32.4 153.9,32.53 153.28,32.53 153.15,32.4 153.15,32.06 153.03,31.93 152.47,31.93 152.34,32.06 152.34,32.4 152.21,32.53 151.69,32.53 151.56,32.4 151.56,32.06 151.44,31.93 150.85,31.93 150.73,32.06 150.73,33.09 150.6,33.21 150.17,33.21 150.04,33.09 150.04,32.06 149.91,31.93 149.47,31.93 149.34,32.06 149.34,33.46 149.6,33.71 149.6,33.99 149.43,34.17 148.71,34.17 148.58,34.04 148.58,32.06 148.45,31.93 147.95,31.93 147.82,32.06 147.82,34.04 147.69,34.17 147.17,34.17 147.04,34.04 147.04,33.35 146.92,33.23 146.43,33.23 146.31,33.35 146.31,34.04 146.18,34.17 145.71,34.17 144.96,34.92 143.26,34.92 142.49,35.69 141.15,35.69 138.86,37.98 138.86,42.74 138.73,42.87 137.72,42.87 137.59,42.73 137.59,42.55 137.9,42.24 137.9,38.24 137.77,38.12 137.29,38.12 137.16,38.24 137.16,42.11 136.65,42.62 136.65,44.17 136.54,44.29 v1(136.12,44.29)
  IN4 w0.076: v4(174.54,18.32) 175.33,18.32 175.59,18.58 175.93,18.58 176,18.66 176,19.38 176.09,19.47 176.22,19.47 176.31,19.38 176.31,18.66 176.39,18.58 177.94,18.58 178.21,18.31 180.96,18.31 v3(181.04,18.23) 181.21,18.39 181.54,18.39 182.27,17.66 182.78,17.66 183.2,17.24 185.07,17.24 185.46,17.62 186.2,17.62 186.44,17.86 186.72,17.86 v4(186.95,18.09) ; v4(149.9,18.32) 150.29,18.71 150.87,18.71 150.94,18.79 150.94,19.04 151.03,19.13 151.16,19.13 151.25,19.04 151.25,18.79 151.32,18.71 152.79,18.71 153.2,18.3 155.9,18.3 155.94,18.34 156.62,18.34 156.93,18.03 156.93,17.96 v3(157.05,17.84) 157.52,17.38 157.96,17.38 158.01,17.33 160.61,17.33 160.85,17.57 161.26,17.57 161.52,17.83 162.13,17.83 162.36,17.61 v4(162.36,17.54)
  BOTTOM w0.076: UCPU1.AP46 135.78,43.95 v1(136.12,44.29) ; UD7.M7 161.46,18.6 161.59,18.72 162.19,18.72 162.32,18.6 162.32,17.65 162.36,17.61 v4(162.36,17.54) ; v4(186.95,18.09) 186.95,18.62 186.83,18.75 186.22,18.75 186.1,18.62 UD10.M7
DDR_B_RAS#: length 147.2
  TOP w0.076: v1(170.68,19.68) 170.12,20.23 RD64.1
  IN1 w0.076: v3(157.46,19.69) 157.58,19.56 157.76,19.56 158.49,18.83 167.45,18.83 168.19,19.57 170.58,19.57 v1(170.68,19.68) 170.85,19.68 171.05,19.47 171.22,19.47 171.5,19.19 172.08,19.19 172.33,18.95 172.69,18.95 172.85,19.11 176.81,19.11 176.88,19.19 176.88,19.35 176.97,19.44 177.1,19.44 177.19,19.35 177.19,19.19 177.26,19.11 177.42,19.11 177.49,19.19 177.49,19.43 177.58,19.52 177.71,19.52 177.8,19.43 177.8,19.19 177.87,19.11 178.03,19.11 178.1,19.19 178.1,19.4 178.19,19.49 178.32,19.49 178.41,19.4 178.41,19.21 178.48,19.14 178.63,19.14 178.77,19.28 181.83,19.28 181.92,19.19 v3(182.53,19.19)
  IN2 w0.076: v1(142.29,45.56) 142.61,45.56 142.73,45.43 142.73,42.48 142.89,42.32 143.14,42.32
  IN2 w0.191: 143.14,42.32 143.58,41.89 143.58,40.2 143.7,40.07 146.45,40.07 146.57,39.94 146.57,37.84 146.7,37.71 147.17,37.71 147.3,37.84 147.3,40.15 147.42,40.28 147.98,40.28 148.11,40.15 148.11,37.32 148.24,37.19 148.82,37.19 148.95,37.32 148.95,40.15 149.07,40.28 149.93,40.28 150.05,40.15 150.05,36.53 150.18,36.4 151.27,36.4 151.4,36.27 151.4,36.02 151.41,36.02 151.6,35.83 159.73,35.83 160.12,36.22 164.6,36.22 165.2,35.61 169.3,35.61 169.32,35.59 169.34,35.59 169.62,35.31 176.12,35.31 176.25,35.18 176.25,34.47 176.12,34.34 174.73,34.34 174.6,34.22 174.6,33.65 174.73,33.52 176.14,33.52 176.27,33.39 176.27,32.77 176.14,32.64 174.73,32.64 174.6,32.52 174.6,32.01 174.73,31.88 176.12,31.88 176.25,31.75 176.25,31.13 176.12,31 174.73,31 174.6,30.88 174.6,30.24 174.73,30.12 176.12,30.12 176.25,29.99 176.25,29.45 176.12,29.33 174.73,29.33 174.6,29.2 174.6,27.52 174.73,27.4 175.47,27.4 175.66,27.21 175.66,26.28 175.47,26.09 174.73,26.09 174.6,25.96 174.6,24.17 174.58,24.15 174.58,24.13 174.07,23.62 174.07,23.04 173.93,22.9 171.93,22.9 171.58,22.55 171.58,20.89 170.74,20.05 170.74,19.74 v1(170.68,19.68)
  IN4 w0.076: v4(177.2,20.04) 177.2,19.82 177.32,19.7 180.23,19.7 180.42,19.51 181.63,19.51 182,19.14 182.47,19.14 v3(182.53,19.19) 186.31,19.19 186.49,19.37 187.4,19.37 v4(188.09,20.06) ; v4(164.66,20.72) 164.66,20.4 163.86,19.6 163.3,19.6 162.87,19.17 158.22,19.17 157.86,19.52 157.62,19.52 v3(157.46,19.69) 157.33,19.69 157.01,19.37 156.71,19.37 156.52,19.19 155.94,19.19 155.62,19.5 152.76,19.5 152.44,19.82 152.44,19.92 v4(152.56,20.04)
  BOTTOM w0.076: UD10.J3 187.91,20.72 187.79,20.59 187.79,20.18 187.91,20.06 v4(188.09,20.06) ; v4(177.2,20.04) 177.2,21.06 177.33,21.19 177.82,21.19 177.94,21.06 177.94,20.85 177.82,20.72 UD9.J3 ; v1(142.29,45.56) 142.6,45.25 UCPU1.AM35 ; v4(152.56,20.04) 152.56,21.06 152.68,21.19 153.23,21.19 153.36,21.06 153.36,20.85 153.23,20.72 UD6.J3
DDR_B_WE#: length 150
  TOP w0.076: RD72.1 171.69,20.36 v1(171.22,19.89)
  IN1 w0.076: v3(182.12,19.61) 182,19.49 179.87,19.49 179.8,19.57 179.8,19.85 179.71,19.94 179.58,19.94 179.49,19.85 179.49,19.57 179.42,19.49 179.26,19.49 179.19,19.57 179.19,19.93 179.1,20.01 178.97,20.01 178.88,19.93 178.88,19.57 178.81,19.49 178.6,19.49 178.57,19.53 178.57,19.68 178.52,19.72 176.78,19.72 176.69,19.63 176.69,19.4 176.61,19.32 176.46,19.32 176.38,19.4 176.38,19.63 176.29,19.72 176.17,19.72 176.08,19.63 176.08,19.4 176,19.32 175.85,19.32 175.77,19.4 175.77,19.59 175.68,19.68 175.56,19.68 175.47,19.59 175.47,19.4 175.39,19.32 172.69,19.32 171.35,20.66 171.2,20.66 171.1,20.55 171.1,20.41 171.39,20.12 171.39,20.06 v1(171.22,19.89) 171.04,20.07 170.35,20.07 170.17,19.89 168.16,19.89 167.32,19.04 158.79,19.04 157.75,20.08 157.17,20.08 v3(156.85,19.76)
  IN2 w0.076: v1(142.29,46.19) 142.8,46.19 142.89,46.1 142.89,42.76 143.07,42.59 143.3,42.59
  IN2 w0.191: v1(171.22,19.89) 171.22,19.93 171.41,20.13 172.07,20.13 172.26,20.32 172.26,20.61 171.98,20.88 171.98,22.36 172.11,22.48 172.81,22.48 172.94,22.36 172.94,21.73 173.07,21.61 173.52,21.61 173.65,21.73 173.65,22.36 173.78,22.48 174.47,22.48 174.6,22.61 174.6,23.63 174.88,23.92 175.53,23.92 175.66,24.05 175.66,24.84 175.53,24.97 175.06,24.97 174.93,25.1 174.93,25.63 175.06,25.76 176.51,25.76 176.64,25.89 176.64,27.74 176.51,27.87 175.12,27.87 175,27.99 175,28.68 175.12,28.81 176.53,28.81 176.65,28.93 176.65,36.04 176.53,36.16 176.06,36.16 175.94,36.04 175.94,35.83 175.81,35.7 175.38,35.7 175.25,35.83 175.25,35.96 175.06,36.15 174.72,36.15 174.53,35.96 174.53,35.83 174.4,35.7 173.92,35.7 173.79,35.83 173.79,35.96 173.6,36.15 173.19,36.15 173,35.96 173,35.83 172.88,35.7 172.35,35.7 172.23,35.83 172.23,35.96 172.04,36.15 171.68,36.15 171.49,35.96 171.49,35.83 171.36,35.7 171.08,35.7 170.73,36.05 170.47,36.05 170.12,35.7 169.78,35.7 169.41,36.08 165.33,36.08 165.18,36.22 165.16,36.22 164.79,36.6 160.69,36.6 160.52,36.76 160.52,36.97 160.4,37.09 159.66,37.09 159.54,36.97 159.54,36.43 159.33,36.22 158.93,36.22 158.72,36.43 158.72,36.97 158.6,37.1 158.04,37.1 157.91,36.97 157.91,36.43 157.71,36.22 157.3,36.22 157.1,36.43 157.1,37.09 156.97,37.21 156.41,37.21 156.28,37.09 156.28,36.33 156.16,36.2 155.63,36.2 155.5,36.33 155.5,37.09 155.37,37.21 154.78,37.21 154.65,37.09 154.65,36.35 154.52,36.22 153.88,36.22 153.75,36.35 153.75,38.14 153.62,38.27 153.03,38.27 152.9,38.14 152.9,36.57 152.77,36.44 152.26,36.44 152.14,36.57 152.14,39.65 151.25,40.54 144.04,40.54 143.92,40.66 143.92,41.96 143.3,42.59
  IN4 w0.076: v4(175.92,20.06) 176.33,20.46 177.39,20.46 177.96,19.9 180.32,19.9 180.49,19.73 182.01,19.73 v3(182.12,19.61) 182.18,19.67 182.81,19.67 183.02,19.47 186.21,19.47 186.39,19.65 187.33,19.65 187.45,19.78 v4(187.45,20.08) ; v4(163.26,20.03) 163.21,20.03 162.58,19.39 158.32,19.39 157.61,20.11 157.23,20.11 156.89,19.76 v3(156.85,19.76) 156.77,19.76 156.4,19.4 156.03,19.4 155.71,19.71 153.18,19.71 152.9,19.99 152.9,20.17 152.61,20.46 151.45,20.46 151.29,20.3 v4(151.29,20.06)
  BOTTOM w0.076: v4(187.45,20.08) 187.45,19.15 187.58,19.02 189.19,19.02 UD10.L3 ; UCPU1.AK35 142.65,46.55 v1(142.29,46.19) ; v4(163.26,20.03) 163.26,19.42 163.56,19.12 UD7.L3 ; UD6.L3 152.22,19.12 v4(151.29,20.06) ; v4(175.92,20.06) 176.86,19.12 UD9.L3
DDR_CHA_EN: length 13.7
  TOP w0.109: RH440.1 v7(173.28,55.63) 173.39,55.53 173.39,54.87 173.18,54.66 172.88,54.66 RH442.1
  IN1 w0.076: v3(163.94,57.79) 165.36,56.37 168.01,56.37 168.69,55.7 168.69,55.44 169.05,55.08 171.1,55.08 171.66,55.63 v7(173.28,55.63)
  IN4 w0.076: v3(163.94,57.79) 163.89,57.84 v4(163.46,57.84)
DDR_CHB_EN: length 15.5
  TOP w0.109: v7(174.06,54.82) 174.14,54.9 175.04,54.9 175.37,54.57 RH441.1
  IN1 w0.076: v3(163.06,58.15) 163.86,57.35 164.06,57.35 165.4,56.02 167.24,56.02 168.03,55.23 168.61,55.23 168.96,54.87 170.99,54.87 171.07,54.8 174.03,54.8 v7(174.06,54.82)
  IN4 w0.076: v4(162.16,57.13) 162.16,57.13 163.06,58.03 v3(163.06,58.15)
DDR_PG_CNTL: length 7.9
  BOTTOM w0.109: UCPU1.AV61 126.16,41.64 125.67,41.16 125.62,41.16 125.62,41.16 125.35,41.16 125.35,41.16 124.43,41.16 123.77,40.5 123.77,37.63 v2(124.21,37.18) 124.53,36.86 UC1.2
DDR_VREF: length 6.5
  TOP w0.109: v2(35.08,2.85) 35.65,3.42 R1187.1
  TOP w0.254: UA1.40 37.41,6.85 37.19,6.62 CA13.2 37.19,4.61 R1186.2 37.06,3.47 CA15.1 R1187.1
DELAY_VR_AND_ALL_SYS: length 5.6
  TOP w0.109: U690.4 183.96,31.76 183.31,31.11 U691.1 181.96,31.11 181.63,31.44 181.04,31.44 180.52,30.92 R1290.1 R1295.1
DEVSLP0: length 98.1
  TOP w0.109: JSATA1.44 205.56,26.26 v2(205.31,26.51) 205.31,27.36 205.11,27.57 R1366.2 203.98,26.79 v7(203.68,26.79)
  IN1 w0.076: v3(162.55,54.52) 162.55,54.29 160.9,52.64 159.72,52.64 158.73,51.65 158.73,51.21 159.12,50.82 159.12,50.58 159.39,50.31 159.39,49.92 159.68,49.63 159.81,49.63 160.65,49.63 161.61,48.66 163.96,48.66 164.06,48.56 165.32,48.56 165.56,48.32 167.07,48.32 167.4,47.98 167.4,47.46 167.98,46.88 174.82,46.88 175.38,46.31 178.37,46.31 179.04,45.64 179.04,38.76 180.27,37.52 188.4,37.52 189.47,36.45 191.47,36.45 192.22,35.7 192.22,34.77 193.05,33.94 193.05,33.49 195.01,31.53 195.01,30.02 196.34,28.7 196.34,27.61 197.58,26.37 197.58,12.84 v3(197.38,12.63) ; v3(203.37,25.37) 203.78,25.78 203.78,26.69 v7(203.68,26.79)
  IN2 w0.102: v3(203.37,25.37) 202.42,25.37 198.27,21.22 198.27,13.52 v3(197.38,12.63)
  IN4 w0.076: v4(162.81,54.84) 162.55,54.59 v3(162.55,54.52)
DH_+1.2V: length 6.8
  TOP w0.109: v2(94.93,33.71) v6(94.32,33.71)
  IN1 w1.016: 87.32,32.24 90.14,32.24 91.62,33.72 92.91,33.72
  vias: v6(87.08,31.43) v6(87.05,30.74) v6(93.68,33.72)
DISPOFF#: length 58.6
  TOP w0.109: v1(174.08,68.05) 174.08,68.35 R540.1
  IN2 w0.102: v3(128.34,67.17) 128.87,67.17 130.07,65.97 136.72,65.97 137.46,66.71 137.46,68.01 138.21,68.77 142.28,68.77 143.07,67.98 143.07,66.56 144.27,65.36 153.79,65.36 157.24,68.82 169.75,68.82 170.22,69.29 173.33,69.29 174.08,68.54 v1(174.08,68.05)
  IN4 w0.076: v4(128.15,67.83) 128.34,67.64 v3(128.34,67.17)
  BOTTOM w0.109: JLVDS2.22 v4(128.15,67.83) ; v2(176.27,69.08) 176.06,68.88 D72.1 174.55,68.52 v1(174.08,68.05)
DL_+1.2V: length 6.8
  TOP w0.109: v6(95.52,32.41) v2(96.07,32.41)
  IN3 w1.016: 89.1,34.4 90.7,34.4 93.49,31.61 94.18,31.61
  vias: v6(87.46,34.86) v6(88.09,34.86) v6(95.1,31.9)
DMIC_CLK: length 10.8
  TOP w0.109: U23.9 209.97,65.4 R1342.1 211.28,64.09 211.28,63.43 211.38,63.33 213.11,63.33 v2(213.8,64.02) 213.8,64.3 214.38,64.88 215.69,64.88 216.52,64.05 MD50.6
DMIC_CLK_CODEC: length 276
  TOP w0.109: v1(30.59,28.08) CA49.2 29.93,28.1 29.93,26.83 29.6,26.5 UA2.12 ; v1(209.8,62.11) 209.8,61.59 209.34,61.13 v2(209.11,61.13) 204.24,61.13 203.26,62.11 203.26,62.97 202.81,63.42 201.95,63.42 200.34,65.03 200.34,66.23 RA9.2
  IN3 w0.102: v1(30.59,28.08) 30.83,28.08 32.66,26.25 32.66,23.67 32.31,23.32 32.31,21.61 35.58,18.35 35.58,16.01 37.59,14 37.59,11.57 38.91,10.24 39.82,10.24 42.16,7.91 42.16,6.27 43.36,5.06 49.11,5.06 50.1,6.05 55.31,6.05 56.08,5.29 57.63,5.29 59.03,3.89 89.73,3.89 90.6,4.76 93.94,4.76 94.15,4.55 102.48,4.55 102.68,4.76 105.38,4.76 105.66,5.04 107.84,5.04 108.66,5.86 111.18,5.86 111.57,5.48 121.26,5.48 121.84,4.89 128.31,4.89 129.11,5.7 140.47,5.7 143.55,8.79 149.53,8.79 150.99,7.33 154.46,7.33 156.79,5 181.52,5 182.72,6.19 191.25,6.19 193.64,8.58 195.34,8.58 198.8,12.04 198.8,12.96 201.53,15.69 201.53,27.44 202.36,28.28 202.36,33.1 206.14,36.88 208.69,36.88 211.09,39.28 211.47,39.28 212.92,40.73 212.92,41.93 213.35,42.36 213.35,43.56 215.98,46.19 215.98,48.4 216.74,49.16 216.74,53.08 214.36,55.46 214.36,58.52 214.99,59.15 214.99,60.3 213.99,61.3 210.61,61.3 v1(209.8,62.11)
DMIC_CLK_DSP: length 246.6
  TOP w0.109: v1(209.2,62.11) 208.71,61.62 205.28,61.62 204.81,62.09 204.81,62.37 204.59,62.58 204.36,62.58 v2(203.47,63.48) 203.03,63.91 202.15,63.91 201.28,64.79 201.28,65.51 RA5.2 ; v1(41.73,6.64) 41.6,6.76 41.15,6.76 40.91,7.01 UA1.47
  IN3 w0.102: v1(41.73,6.64) 41.65,6.56 41.65,6.1 43.62,4.12 48.07,4.12 48.3,4.35 50.83,4.35 51.29,4.81 57.43,4.81 58.83,3.41 89.93,3.41 90.8,4.28 93.74,4.28 93.94,4.07 101.9,4.07 102.15,3.82 105.17,3.82 105.79,4.44 107.92,4.44 108.86,5.38 110.98,5.38 111.37,4.99 113.77,4.99 114.36,4.41 128.51,4.41 129.31,5.21 140.67,5.21 143.75,8.3 149.33,8.3 150.79,6.85 154.26,6.85 156.59,4.52 181.72,4.52 182.92,5.71 191.45,5.71 193.84,8.1 195.54,8.1 199.28,11.84 199.28,12.76 202.01,15.49 202.01,27.24 202.85,28.08 202.85,32.9 206.34,36.39 209.78,36.39 211.58,38.18 211.58,38.7 213.41,40.53 213.41,41.73 213.84,42.16 213.84,43.36 216.46,45.99 216.46,48.2 217.23,48.96 217.23,59.29 213.92,62.59 209.68,62.59 v1(209.2,62.11)
DMIC_CLK_R: length 4.7
  TOP w0.109: R1342.2 209.96,63.71 MC1133.1 209.07,62.82 208.68,62.82 v1(207.99,62.14)
  BOTTOM w0.109: v1(207.99,62.14) 207.9,62.04 JLVDS1.9
DMIC_CLK_SW: length 10.3
  TOP w0.109: v1(207.99,64.6) 208.15,64.75 U23.8 ; RA9.1 RA5.1 201.81,65.03 v2(201.89,64.96) 202.2,64.96 202.65,65.4 U23.6 204,65.4 204.59,64.82 v7(204.59,64.69)
  IN1 w0.076: v7(204.59,64.69) 204.59,64.45 204.9,64.14 207.54,64.14 v1(207.99,64.6)
DMIC_DAT: length 27.7
  TOP w0.109: v7(217.51,62.15) 218.09,62.15 218.42,62.48 218.42,63.08 218.85,63.51 218.85,64.4 218.22,65.03 218.09,65.03 216.31,66.81 216.31,69.05 215.82,69.54 v2(213.72,69.54) 212.82,69.54 211.59,68.31 211.41,68.31 210.78,67.67 MC1210.1 210.31,67.67 209.99,67.35 U23.12
  IN1 w0.076: v1(208.59,62.11) 209,62.52 216.63,62.52 217,62.15 v7(217.51,62.15)
  BOTTOM w0.109: v1(208.59,62.11) 208.59,61.84 208.4,61.65 JLVDS1.8
DMIC_DAT_CODEC: length 280.5
  TOP w0.109: v1(206.56,68.92) 206.56,68.93 206.09,69.4 201.73,69.4 RA10.2 ; v1(29.23,28) 29.23,28.52 CA24.2 28.68,28.76 28.68,27.9 28.54,27.76 UA2.13
  IN3 w0.102: v1(29.23,28) 30.17,27.06 31.16,27.06 32.15,26.07 32.15,23.84 31.83,23.52 31.83,21.26 34.11,18.99 34.11,16.8 37.02,13.89 37.02,11.13 37.86,10.28 37.86,8.44 39.49,6.82 39.74,6.82 43.27,3.28 48.42,3.28 48.65,3.51 51.18,3.51 51.63,3.97 57.08,3.97 58.48,2.57 105.11,2.57 106.14,3.6 108.27,3.6 109.07,4.4 110.78,4.4 111.02,4.16 113.43,4.16 114.01,3.57 140.35,3.57 144.14,7.36 148.93,7.36 150.38,5.91 153.96,5.91 156.19,3.68 182.09,3.68 183.28,4.87 191.8,4.87 194.19,7.26 195.89,7.26 200.12,11.49 200.12,12.41 202.85,15.14 202.85,26.89 203.68,27.73 203.68,32.55 206.69,35.56 210.25,35.56 210.94,36.24 211.76,36.24 213.06,37.55 213.06,39 213.87,39.81 214.38,39.81 215.17,40.6 215.17,41.12 216.68,42.63 216.68,45.02 217.3,45.64 217.3,47.85 218.07,48.61 218.07,50.85 218.87,51.65 218.87,52.46 219.4,52.99 219.4,53.75 218.07,55.09 218.07,59.63 213.66,64.04 213.09,64.04 208.8,68.33 207.14,68.33 v1(206.56,68.92)
DMIC_DAT_DSP: length 249.3
  TOP w0.109: UA1.48 41.52,7.62 v7(41.79,7.35) ; v1(205.92,68.92) 205.8,69.04 202.26,69.04 RA6.2
  IN1 w0.076: v7(41.79,7.35) v3(41.37,7.35)
  IN3 w0.102: v1(205.92,68.92) 207.22,67.62 207.99,67.62 211.93,63.69 213.51,63.69 217.71,59.49 217.71,53.64 218.29,53.06 218.29,51.58 217.71,51 217.71,48.76 216.95,48 216.95,45.79 216.33,45.17 216.33,44.14 214.98,42.79 214.98,42.44 214.47,41.93 214.47,41.46 214.29,41.28 214.29,40.52 214.03,40.25 213.81,40.25 212.06,38.5 212.06,37.98 211.74,37.67 211.74,36.87 211.46,36.6 210.67,36.6 209.98,35.91 206.54,35.91 203.33,32.7 203.33,27.88 202.49,27.04 202.49,15.29 199.76,12.56 199.76,11.64 195.74,7.62 194.04,7.62 191.65,5.23 183.13,5.23 181.94,4.03 156.37,4.03 154.04,6.37 150.59,6.37 149.13,7.82 143.95,7.82 140.06,3.93 114.16,3.93 113.57,4.51 111.17,4.51 110.78,4.9 109.06,4.9 108.12,3.96 105.99,3.96 105.24,3.21 94.13,3.21 93.54,3.79 91,3.79 90.13,2.93 58.63,2.93 57.23,4.33 51.49,4.33 51.03,3.87 48.5,3.87 48.27,3.64 43.42,3.64 41.12,5.95 41.12,7.09 v3(41.37,7.35)
DMIC_DAT_SW: length 10.6
  TOP w0.109: v1(207.59,65.97) 207.74,66.12 207.74,66.2 208.24,66.7 U23.11 ; v2(199.97,67.38) 200.31,67.72 RA10.1 RA6.1 202.23,67.35 U23.3 204.63,67.35 205.67,66.32 v1(205.67,65.97)
  BOTTOM w0.109: v1(207.59,65.97) v1(205.67,65.97)
DMIC_SW_CODEC: length 12.6
  TOP w0.109: v1(34.91,24.46) 35.35,24.01 RH419.1 ; UA2.17 26.94,27.91 27.17,28.13 v1(27.59,28.13)
  BOTTOM w0.109: v1(34.91,24.46) 34.4,24.46 33.55,23.6 30.8,23.6 29.43,24.98 29.43,25.99 v2(29.15,26.27) 28.49,26.93 28.49,27.23 v1(27.59,28.13)
DMIC_SW_DIS: length 74.9
  TOP w0.109: RH466.1 163.7,44.42 v2(163.51,44.42) 162.58,44.42 v7(162.24,44.76) ; Q136.2 193.07,66.55 191.89,65.38 Q135.2 191.89,64.13 191.74,63.98 v1(191.34,63.98)
  IN1 w0.076: v7(162.24,44.76) v3(161.84,44.76)
  IN2 w0.102: v3(203.12,60.02) 203.1,60.02 203.09,60.03 203.03,60.03 200.42,62.63 200.42,62.81 199.17,64.07 v3(199.04,64.07)
  IN3 w0.102: v1(191.34,63.98) 191.64,64.27 197.38,64.27 198.06,63.58 198.56,63.58 v3(199.04,64.07) ; v3(161.84,44.76) 162.98,44.76 163.48,45.27 163.48,46 163.82,46.34 168.75,46.34 169.05,46.64 175.39,46.64 176.64,47.9 180.89,47.9 182.07,46.72 182.83,46.72 183.23,47.12 183.23,47.72 183.35,47.84 186.96,47.84 188.8,49.68 189.93,49.68 190.77,48.84 191.48,48.84 191.98,49.34 191.98,50.39 192.22,50.63 194.7,50.63 196.45,52.38 198.28,52.38 202.85,56.95 202.85,59.75 v3(203.12,60.02)
  IN4 w0.076: v3(161.84,44.76) 161.84,44.76 161.82,44.76 161.82,44.76 161.51,44.46 v4(161.51,44.32)
DMIC_SW_HUB: length 280.3
  TOP w0.109: R31.1 35.59,22.41 v2(35.06,21.88) 34.76,21.88 34.54,22.1 33.24,22.1 v7(33.18,22.16) ; U636.H5 250.05,62.34 v7(250.17,62.21)
  IN1 w0.076: v7(33.18,22.16) 33.18,21.42 34.31,20.29 34.31,16.09 33.52,15.3 33.52,14.57 35.79,12.3 35.79,10.83 36.35,10.28 36.35,8.09 36.87,7.56 v3(36.87,5.98) ; v7(250.17,62.21) 250.12,62.16 249.8,62.16 v3(249.78,62.14)
  IN3 w0.102: v3(36.87,5.98) 37.46,5.39 37.84,5.39 41.47,1.76 46.97,1.76 47.68,1.05 105.87,1.05 106.87,2.05 141.45,2.05 144.74,5.33 148.06,5.33 151.24,2.15 191.24,2.15 194.82,5.74 196.66,5.74 201.64,10.72 201.64,11.45 205.21,15.01 205.21,30.13 206.6,31.52 206.6,32.67 207.51,33.57 211.92,33.57 213.6,35.25 214.69,35.25 216.06,36.62 216.06,38.21 218.36,40.51 221.34,40.51 221.58,40.75 221.58,41.65 220.69,42.54 220.69,44.04 221.86,45.21 222.41,45.21 224.99,47.79 224.99,49.05 225.88,49.94 228.64,49.94 233.39,54.69 239.39,54.69 242.77,58.07 244.1,58.07 244.66,58.63 246.25,58.63 249.78,62.16 v3(249.78,62.14)
DMIC_SW_PCH: length 268.4
  TOP w0.109: RH420.1 36.84,25.28 36.84,25.97 36.51,26.3 v2(36.21,26.3) v7(35.3,26.3)
  IN1 w0.076: v3(163.32,53.96) 163.34,53.96 163.32,53.98 162.46,53.98 160.94,52.46 159.86,52.46 158.92,51.52 158.92,51.24 159.28,50.88 159.28,50.66 159.54,50.39 159.54,49.98 159.74,49.78 160.71,49.78 161.68,48.81 164.07,48.81 164.12,48.76 165.41,48.76 165.65,48.52 167.15,48.52 167.61,48.07 167.61,47.56 168.08,47.08 174.9,47.08 175.14,46.85 175.58,46.85 175.88,47.14 177.83,47.14 179.24,45.73 179.24,38.84 180.36,37.73 188.49,37.73 189.56,36.66 191.55,36.66 192.42,35.79 192.42,34.85 193.25,34.02 193.25,33.58 195.22,31.61 195.22,30.11 196.54,28.79 196.54,27.7 197.78,26.45 197.78,12.43 194.57,9.22 193.39,9.22 190.5,6.33 181,6.33 180.23,5.56 155.55,5.56 152.8,8.31 143.88,8.31 141.39,5.82 128.94,5.82 128.22,5.11 119.89,5.11 118.97,6.03 110.38,6.03 108.63,7.78 105.41,7.78 103.43,9.76 101.97,9.76 100.47,11.26 94.61,11.26 91.83,8.48 72.16,8.48 71.42,7.74 67.86,7.74 67.32,8.29 64.24,8.29 63.9,8.63 59.28,8.63 58.6,7.95 57.41,7.95 56.43,8.92 50.81,8.92 48.12,6.23 44.31,6.23 40.35,10.19 40.35,13.7 40.15,13.9 40.15,16.94 39.05,18.05 39.05,19.69 36.61,22.13 36.61,24.77 35.3,26.07 v7(35.3,26.3)
  IN4 w0.076: v4(162.81,54.09) 163.2,54.09 163.34,53.96 v3(163.32,53.96)
DROOP: length 7.1
  TOP w0.109: v2(96.5,62.96) 95.4,61.86 PR744.1
  TOP w0.203: PU701.25 98.1,60.31 97.85,60.56 97.85,61.46 PR727.1 96.98,62.04 PC714.1 95.94,61.39 95.79,61.54 PR744.1
DSP_PD#: length 227.8
  IN1 w0.076: v3(39.08,16.92) 39.68,16.92 39.95,16.66 39.95,14.46 39.41,13.92 39.41,13.41 40.15,12.67 40.15,10.11 42.67,7.59 42.67,6.59 43.22,6.03 48.91,6.03 51.14,8.26 56.52,8.26 57.44,7.34 59.71,7.34 59.9,7.53 63.8,7.53 v3(64.13,7.2)
  IN4 w0.076: v4(38.73,17.1) 38.91,16.92 v3(39.08,16.92) ; v3(64.13,7.2) 64.36,7.43 67.71,7.43 67.82,7.54 71.96,7.54 72.35,7.15 72.35,6.07 75.31,3.11 90.31,3.11 91.2,4 93.84,4 94.12,4.28 96.15,4.28 96.47,4.59 100.83,4.59 101.15,4.91 104.56,4.91 104.77,5.13 108.09,5.13 112.12,9.16 119.13,9.16 119.5,9.53 124.89,9.53 125.29,9.93 140.3,9.93 142.25,11.88 151.3,11.88 154.26,8.92 156.11,8.92 156.82,8.21 170.91,8.21 171.65,8.96 174.41,8.96 174.54,9.09 178.74,9.09 178.91,8.92 189.86,8.92 193.77,12.84 193.77,13.33 195.57,15.13 195.57,21.85 196.51,22.79 196.51,26.22 196.87,26.57 196.87,30.71 197.48,31.32 197.48,33.72 202.1,38.34 202.1,41.5 203.42,42.82 203.42,46.4 205.56,48.53 205.56,50.25 205.43,50.38 205.43,51.75 207.16,53.48 207.71,53.48 v4(207.74,53.45)
  BOTTOM w0.076: U34.H5 210.11,54.19 209.26,54.19 209.21,54.19 209.11,54.09 209.11,53.82 209,53.7 208.15,53.7 207.88,53.44 207.75,53.44 v4(207.74,53.45)
  BOTTOM w0.109: v2(39.35,18.82) R1262.1 38.83,17.1 v4(38.73,17.1)
DSP_PD#_R: length 4.2
  TOP w0.254: UA1.17 39.41,15.94 v1(39.53,16.06)
  BOTTOM w0.109: v2(41.29,16.72) R1261.2
  BOTTOM w0.254: R1261.2 39.36,16.72 R1262.2 39.35,16.47 39.53,16.29 v1(39.53,16.06)
DSWODVREN: length 8
  BOTTOM w0.102: 159.12,39.76 159.06,39.83 159.06,40.56 UCPU1.AW7
  BOTTOM w0.109: RH147.2 160.83,34.76 160.83,35.72 RH151.2 161.21,36.28 161.21,37.42 v2(160.29,38.34) 159.12,39.51 159.12,39.76
EAPD#: length 256.3
  TOP w0.109: v1(19.42,23.22) 19.42,23.22 19.23,23.03 19.23,21.76 RA23.1 ; UA2.14 28.14,27.87 28.32,28.05 28.32,29.26 28.78,29.73 v1(28.87,29.73)
  IN1 w0.076: v1(28.87,29.73) 28.87,28.58 27.48,27.19 23.77,27.19 22.35,25.76 20.64,25.76 19.67,24.79 19.67,23.47 v1(19.42,23.22) ; v3(200.96,51.57) 201.21,51.82 201.21,52.27 201.86,52.92 206.01,52.92 206.86,53.77 208.08,53.77 v3(208.35,53.5)
  IN3 w0.102: v1(28.87,29.73) 29.3,30.16 30.98,30.16 34.21,26.93 34.21,25.83 35.59,24.45 35.59,22.57 40.97,17.19 41.73,17.19 44.25,14.68 45.85,14.68 46.68,13.85 47.46,13.85 49.37,11.94 49.37,11.44 51.05,9.76 53.34,9.76 54.61,11.03 65.78,11.03 66.26,10.55 70.21,10.55 71.33,9.43 73.18,9.43 74.4,8.21 92.84,8.21 95.38,10.75 107.8,10.75 109.75,8.8 126.09,8.8 127.68,10.39 137.28,10.39 138.28,11.4 150.23,11.4 151.31,10.31 157.48,10.31 160.14,7.65 170.56,7.65 172.18,9.28 174.94,9.28 175.79,10.13 178.67,10.13 179.44,10.9 180.77,10.9 181.58,10.09 185.13,10.09 186.3,11.26 189.82,11.26 190.32,11.77 190.32,12.39 191.08,13.14 192.04,13.14 194.93,16.02 194.93,26.36 195.97,27.4 195.97,32.12 197.1,33.25 197.1,34.68 201.54,39.13 201.54,41.92 202.86,43.24 202.86,46.72 202.18,47.41 202.18,48.22 201.11,49.28 200.4,49.28 200.15,49.54 200.15,49.79 200.96,50.61 v3(200.96,51.57)
  IN4 w0.076: v4(208.04,53.17) 208.04,53.18 208.35,53.49 v3(208.35,53.5)
  BOTTOM w0.109: U34.D6 208.32,53.44 v4(208.04,53.17) ; v2(28.67,29.26) 28.87,29.46 v1(28.87,29.73)
EC_BATT_PRS#: length 204.8
  TOP w0.109: PR113.1 PR112.2 62.3,13.41 62.67,13.78 64.36,13.78 64.54,13.96 65.59,13.96 66.23,13.33 66.23,12.4 67.23,11.4 v2(67.23,9.85) 67.23,8.36 66.99,8.12 v1(66.99,7.83) ; PC114.1 196.75,22.94 v1(196.03,22.94)
  IN4 w0.076: v1(66.99,7.83) 67.19,7.63 67.62,7.63 67.74,7.74 72.04,7.74 72.55,7.23 72.55,6.16 75.39,3.31 90.22,3.31 91.11,4.2 93.03,4.2 v4(93.31,4.48) 96.07,4.48 96.38,4.8 100.74,4.8 101.06,5.11 104.47,5.11 104.69,5.33 108,5.33 112.04,9.37 119.05,9.37 119.41,9.74 124.81,9.74 125.21,10.14 140.22,10.14 142.16,12.08 151.38,12.08 154.34,9.12 156.2,9.12 156.9,8.41 170.82,8.41 171.57,9.16 174.3,9.16 174.43,9.29 178.83,9.29 178.99,9.13 189.77,9.13 193.57,12.92 193.57,13.41 195.37,15.21 195.37,22.56 195.62,22.82 195.9,22.82 v1(196.03,22.94) 196.31,23.22 196.31,26.3 196.67,26.66 196.67,30.79 197.28,31.4 197.28,33.81 201.9,38.43 201.9,41.58 203.22,42.9 203.22,46.48 205.28,48.54 205.28,51.82 207.08,53.63 207.46,53.63 207.66,53.83 v4(207.89,53.83)
  BOTTOM w0.076: v4(207.89,53.83) 208.1,54.03 208.1,54.39 207.99,54.49 207.94,54.49 207.6,54.83 207.6,55.6 207.36,55.84 U34.B1 207.35,55.94 207.1,56.19 206.66,56.19 206.36,56.49
  BOTTOM w0.109: 206.36,56.49 206.3,56.56 206.3,57.99 C286.2 ; v4(93.31,4.48) 93.14,4.3 93.14,3.03 92.7,2.6 PC229.1
EC_CRY2: length 5.7
  GND3 w0.076: v10(211.73,57.82) 211.52,57.62 v10(211.52,56.88)
  BOTTOM w0.076: U34.K1 211.5,56.09 211.5,56.85 v10(211.52,56.88)
  BOTTOM w0.109: v2(209.37,58.81) 209.98,58.2 MC654.1 R607.2 R253.2 211.83,57.87 211.78,57.87 v10(211.73,57.82)
EC_ENVDD: length 167.1
  TOP w0.109: v7(199.93,53.7) 199.85,53.63 199.19,53.63 198.96,53.4 198.96,52.01 198.66,51.71 198.66,51.33 v2(199.27,50.72) 199.73,50.26 199.73,47.3 202.14,44.89 202.14,43.77 200.57,42.21 D306.3 ; D105.3 93.42,57.8 v1(93.76,57.46)
  TOP w0.203: U715.3 189.82,50.47 189.72,50.58 R1026.1
  TOP w0.254: v1(189,54.22) 188.86,54.37 188.86,55.15 189.06,55.35 D93.1 189.85,55.26 189.85,52.43 189.48,52.07 189.48,51.78 R1026.1
  IN1 w0.076: v7(199.93,53.7) 200.04,53.82 200.21,53.82 v3(200.4,53.63)
  IN2 w0.102: v3(206.54,50.82) 206.53,50.83 206.53,51.41 205.68,52.26 205.37,52.26 203.79,53.83 200.6,53.83 v3(200.4,53.63) 200.2,53.83 194.67,53.83 194.06,53.22 189.88,53.22 189.02,54.08 189.02,54.21 189.03,54.22 v1(189,54.22) 186.29,54.22 185.67,53.6 184.32,53.6 183.94,53.22 178.79,53.22 178.74,53.27 171.83,53.27 171.2,52.64 169.45,52.64 169.1,52.29 167.76,52.29 167.3,51.83 165.74,51.83 165.13,51.23 163.63,51.23 162.73,50.33 161.99,50.33 161.69,50.63 161.69,50.86 161.36,51.19 160.72,51.19 160.11,51.8 160.11,52.31 159.35,53.07 156.33,53.07 154.5,54.9 154.5,55.33 153.92,55.91 153.36,55.91 152.18,57.09 152.18,58.49 149.9,60.77 133.95,60.77 133.57,60.38 129.71,60.38 128.87,59.55 128.87,57.92 128.03,57.08 128.03,50.63 126.82,49.41 123.04,49.41 119.73,52.73 119.73,53.2 117.49,55.43 117.49,56.9 116.82,57.58 114.95,57.58 114.32,56.94 104.16,56.94 103.71,57.39 98.72,57.39 98.47,57.64 96.92,57.64 96.74,57.46 v1(93.76,57.46)
  IN4 w0.076: v4(206.57,51.21) 206.57,50.86 v3(206.54,50.82)
  BOTTOM w0.109: U34.A10 206.8,51.44 v4(206.57,51.21)
EC_ON: length 23.8
  TOP w0.109: v5(206.93,38.06) 206.93,38.35 205.39,39.89 205.39,40.66 v1(205.63,40.9) 205.21,40.9 205.14,40.83 R341.1
  IN1 w0.076: v7(209.7,55.86) 210.05,55.86 v3(210.08,55.84)
  IN3 w0.102: v1(205.63,40.9) 205.48,41.05 205.48,41.6 206.46,42.57 206.46,47.48 209.62,50.64 209.62,52.17 210.1,52.65 210.1,53.3 209.47,53.93 209.47,54.72 210.08,55.33 v3(210.08,55.84)
  IN4 w0.076: v3(210.08,55.84) 209.87,56.04 209.87,56.61 v4(209.86,56.62)
  BOTTOM w0.076: U34.G1 209.86,56.16 209.86,56.17 209.86,56.62 v4(209.86,56.62)
EC_ON_CTRL#: length 7.7
  TOP w0.109: RP22.3 206.56,52.68 206.91,52.33 206.91,51.77 207.55,51.14 v2(207.8,51.14) 208.13,51.14 208.32,51.33 208.32,52.12 R987.1 208.91,53.13 C1118.1 209.64,53.87 v7(209.64,54.08)
  IN1 w0.076: v3(210.09,53.9) 209.9,54.08 v7(209.64,54.08)
  IN4 w0.076: v3(210.09,53.9) 209.86,53.66 v4(209.86,53.59)
  BOTTOM w0.109: U34.G5 v4(209.86,53.59)
EC_PECI: length 11.6
  TOP w0.109: R240.1 203.43,58.66 203.43,57.36 204.12,56.68 204.86,56.68 205.37,56.17 208.29,56.17 208.46,56.35 209.82,56.35 v1(210.46,56.98)
  BOTTOM w0.076: U34.H2 210.61,55.69 210.61,56.09 210.76,56.24 210.76,56.47 210.46,56.78 v1(210.46,56.98)
EC_RST#: length 3
  BOTTOM w0.109: U34.K13 211.36,49.84 211.33,49.82 211.33,49.36 211.98,48.71 211.98,48.42 C285.1 R221.1
EC_RUNTIME_SCI#: length 75
  TOP w0.109: v2(176,48.52) 176,48.47 176.86,47.61 RH299.1 v7(177.02,48.55)
  IN1 w0.076: v3(176.45,49.08) 176.45,49.02 176.92,48.55 v7(177.02,48.55)
  IN2 w0.102: v3(215.82,44.43) 215.8,44.42 214.56,44.42 213.82,43.68 212.37,43.68 210.76,45.3 209.75,45.3 208.63,46.41 203.93,46.41 202.58,47.76 200.31,47.76 199.24,48.83 193.87,48.83 193.22,48.18 192.24,48.18 191.16,47.1 185.43,47.1 184.77,47.76 181.76,47.76 181.11,48.41 177.49,48.41 176.82,49.08 v3(176.45,49.08) 176.27,49.26 175.8,49.26 175.09,49.97 170.55,49.97 169.77,49.18 169.77,47.98 169.47,47.68 168.08,47.68 166.8,46.39 164.03,46.39 163.09,45.45 163.09,45.47 v3(163.06,45.47)
  IN4 w0.076: v4(213.89,53.27) 214.09,53.27 216.17,51.19 216.17,48.46 216.69,47.94 216.69,45.76 216.02,45.09 216.02,44.64 v3(215.82,44.43) ; v4(162.81,45.1) 162.81,45.12 163.01,45.32 163.01,45.37 163.09,45.45 163.09,45.47 v3(163.06,45.47)
  BOTTOM w0.109: v4(213.89,53.27) 213.81,53.35 212.95,53.35 U34.N6
EC_RX: length 43.2
  TOP w0.109: v1(198.8,21.13) 198.44,21.13 v2(198.28,21.29)
  IN3 w0.102: v3(210.49,51.62) 210.28,51.41 210.28,49.88 207.75,47.35 207.75,43.54 206.34,42.14 206.34,40.42 199.48,33.56 199.48,21.81 v1(198.8,21.13) 198.27,20.6 198.27,18.37 198.82,17.81 v3(198.84,17.81)
  IN4 w0.076: v3(198.84,17.81) 199.03,17.81 199.1,17.74 v4(199.1,17.36) ; v3(210.49,51.62) 211.58,51.62 211.65,51.69 v4(211.65,51.7)
  BOTTOM w0.109: JDEBUG.12 v4(199.1,17.36) ; v4(211.65,51.7) 211.6,51.7 211.36,51.94 U34.K9
EC_SLP_S5#: length 56.4
  TOP w0.109: D114.2 199.19,8.75 199.57,9.13 v2(199.78,9.13) 199.9,9.13 200.15,8.89 v1(200.15,8.57)
  IN4 w0.076: v1(200.15,8.57) 202.61,8.57 204.79,10.75 204.79,32.07 207.38,34.65 208.3,34.65 211.69,38.04 211.69,39.83 213.47,41.61 213.47,43.82 214.78,45.12 214.78,46.16 214.67,46.27 214.67,46.92 214.36,47.24 214.36,47.71 214.66,48.02 214.66,49.06 214.66,49.55 v4(214.39,49.82)
  BOTTOM w0.076: U34.N9 213.11,51.94 213.36,51.7 213.61,51.7 214,51.3 214.37,51.3 214.6,51.08 214.6,50.57 214.39,50.36 v4(214.39,49.82)
  BOTTOM w0.109: R1386.1 214.83,49.39 v4(214.39,49.82)
EC_SMB_CK1: length 252.8
  TOP w0.109: v7(95.43,18.98) 95.43,18.89 95.87,18.46 95.87,16.57 99.96,12.48 100.83,12.48 104.76,8.55 104.76,4.38 102.16,1.79 99.46,1.79 v1(97.63,3.62) 97.49,3.76 96.73,3.76 95.62,2.65 90.99,2.65 90.31,3.33 90.31,6.84 88.43,8.71 74.49,8.71 v7(74.09,9.11) ; PR109.2 65.09,13.17 65.6,12.66 65.6,12.14 66.34,11.4 66.34,8.69 v7(66.29,8.63)
  IN1 w0.076: v7(137.48,71.79) 137.22,71.52 136.87,71.52 136.63,71.27 136.63,69.4 136.07,68.84 131.88,68.84 131.39,68.35 131.39,67.37 v3(131.25,67.23) ; v3(95.57,19.72) 95.43,19.58 v7(95.43,18.98) ; v7(66.29,8.63) 66.29,8.68 66.64,9.04 74.01,9.04 v7(74.09,9.11)
  IN3 w0.102: v3(204.36,49.61) 203.73,50.25 203.73,53.17 203.42,53.48 203.42,55.25 204.07,55.9 204.07,58.62 204.49,59.04 204.49,60.59 203.55,61.53 203.55,63.13 204.03,63.61 204.03,66 203.42,66.61 200.28,66.61 198.93,65.26 193.48,65.26 192.33,66.4 192.33,66.82 191.56,67.6 190.37,67.6 190.06,67.29 181.68,67.29 180.92,66.53 175.58,66.53 175.04,65.98 168.94,65.98 168.24,65.29 166.54,65.29 165.02,66.81 163.95,66.81 163.7,67.06 155.82,67.06 154.17,65.41 142.28,65.41 141.14,66.56 141.03,66.56 140.62,66.96 138.07,66.96 137.31,67.72 133.9,67.72 132.96,66.78 131.69,66.78 131.25,67.23 v3(131.25,67.23) 131.39,67.37 131.39,67.57 131.21,67.75 128.11,67.75 127.88,67.52 127.88,66.96 127.17,66.25 127.17,66.05 126.36,65.24 118.26,65.24 117.3,64.28 117.3,63.85 114.47,61.02 114.47,58.61 110.89,55.02 110.89,47.96 110.55,47.62 109.53,47.62 105.66,43.75 105.66,37.8 95.85,28 95.85,20 v3(95.57,19.72)
  IN4 w0.076: v4(204.74,49.64) 204.72,49.61 v3(204.36,49.61)
  BOTTOM w0.109: v1(97.63,3.62) 97.61,3.59 PR240.1 ; v4(204.74,49.64) 205.25,50.15 205.25,51.27 206.34,52.36 206.77,52.36 U34.A8
EC_SMB_CK1_R: length 8.7
  TOP w0.109: R1016.2 v2(140.06,71.79) 141.05,71.79 v1(141.1,71.84)
  BOTTOM w0.109: JLVDS2.43 138.65,68.29 140.44,70.08 140.44,70.43 141.1,71.09 v1(141.1,71.84)
EC_SMB_CK4: length 105.1
  IN1 w0.076: v3(147.72,67.5) 148.84,68.61 155.95,68.61 156.58,67.98 156.58,66.68 v3(157.02,66.25)
  IN3 w0.102: v3(209.49,64.75) 208.93,64.19 208.93,63.91 207.59,62.57 207.59,61.81 208.43,60.97 209.26,60.97 209.77,60.46 209.77,59.29 210.03,59.04 210.03,56.65 208.73,55.35 v3(208.73,54.19) ; v3(203.04,65.85) 202.63,65.44 200.19,65.44 199.25,64.5 192.84,64.5 190.58,66.76 181.9,66.76 181.14,66 175.81,66 175.26,65.45 169.16,65.45 168.03,64.32 165.68,64.32 165.22,64.79 165.22,65.85 164.8,66.28 163.73,66.28 163.48,66.53 159.63,66.53 158.79,65.69 157.83,65.69 157.27,66.25 v3(157.02,66.25)
  IN4 w0.076: v3(203.04,65.85) 203.6,65.29 208.96,65.29 v3(209.49,64.75) ; v4(131.18,67.75) 131.18,67.89 131.91,68.61 139.47,68.61 141.75,66.34 141.75,65.54 142.37,64.92 142.8,64.92 143.43,65.55 143.43,65.78 144.84,67.19 147.41,67.19 v3(147.72,67.5) ; v4(209.11,54.75) 208.73,54.36 v3(208.73,54.19)
  BOTTOM w0.076: v4(209.11,54.75) 209.1,54.73 209.1,54.33 208.86,54.08 U34.E5
  BOTTOM w0.109: v4(131.18,67.75) 131.15,67.72 JLVDS2.28
EC_SMB_DA1: length 252.8
  TOP w0.109: v7(94.98,19.31) 94.98,18.82 95.47,18.32 v2(95.47,18.14) 95.55,18.06 95.55,16.44 99.83,12.17 100.7,12.17 104.44,8.42 104.44,4.51 102.04,2.1 100.09,2.1 v1(98.57,3.62) 98.11,4.07 96.6,4.07 95.49,2.96 91.12,2.96 90.62,3.46 90.62,6.97 88.56,9.03 74.66,9.03 v7(74.57,9.11) ; PR111.2 64.67,13.65 65.46,13.65 65.59,13.52 65.59,13.11 65.91,12.79 65.91,12.27 66.66,11.53 66.66,8.72 v7(66.73,8.64)
  IN1 w0.076: v3(131.83,67.23) 131.67,67.39 131.67,68.23 132,68.56 136.19,68.56 136.91,69.28 136.91,71.16 136.99,71.24 137.17,71.24 v7(137.48,70.93) ; v3(94.99,19.74) 94.99,19.33 v7(94.98,19.31) ; v7(66.73,8.64) 66.85,8.76 74.21,8.76 v7(74.57,9.11)
  IN3 w0.102: v3(94.99,19.74) 95.37,20.13 95.37,28 105.17,37.8 105.17,43.8 109.14,47.76 109.14,54.87 110.5,56.23 110.72,56.23 113.99,59.5 113.99,61.4 118.13,65.54 126.23,65.54 126.87,66.18 126.87,66.38 127.58,67.09 127.58,67.65 127.98,68.05 131.34,68.05 131.69,67.7 131.69,67.37 v3(131.83,67.23) 131.97,67.09 132.84,67.09 133.78,68.03 137.43,68.03 138.19,67.27 140.75,67.27 141.15,66.86 141.27,66.86 142.41,65.72 154.04,65.72 155.7,67.37 163.82,67.37 164.08,67.12 165.14,67.12 166.67,65.59 168.12,65.59 168.81,66.29 174.91,66.29 175.46,66.84 180.79,66.84 181.55,67.6 189.93,67.6 190.24,67.9 191.69,67.9 192.64,66.95 192.64,66.53 193.6,65.57 198.81,65.57 200.15,66.91 203.55,66.91 204.34,66.12 204.34,63.48 203.85,63 203.85,61.65 204.79,60.71 204.79,58.91 204.37,58.49 204.37,55.77 203.73,55.13 203.73,53.6 204.03,53.3 204.03,50.38 204.34,50.07 204.49,50.07 v3(204.59,50.17)
  IN4 w0.076: v4(204.74,50.53) 204.74,50.43 204.59,50.27 v3(204.59,50.17)
  BOTTOM w0.109: U34.A7 206.85,52.94 206.56,52.65 206.33,52.65 204.74,51.06 v4(204.74,50.53) ; PR239.1 98.62,3.56 v1(98.57,3.62)
EC_SMB_DA1_R: length 8.7
  TOP w0.109: v2(142.3,71.23) 141.36,70.29 v1(141.03,70.29) 140.6,70.29 139.96,70.93 R1017.2
  BOTTOM w0.109: JLVDS2.44 139.15,68.1 141.03,69.97 v1(141.03,70.29)
EC_SMB_DA4: length 105.3
  IN1 w0.076: v3(147.72,66.91) 148.13,67.32 148.13,67.62 148.92,68.41 155.87,68.41 156.38,67.89 156.38,66.3 v3(156.43,66.25)
  IN3 w0.102: v3(156.43,66.25) 156.84,66.66 157.19,66.66 157.93,65.92 158.69,65.92 159.53,66.76 163.57,66.76 163.82,66.51 164.89,66.51 165.45,65.95 165.45,64.88 165.78,64.55 167.94,64.55 169.07,65.68 175.16,65.68 175.71,66.23 181.04,66.23 181.81,66.99 190.67,66.99 192.93,64.73 199.16,64.73 200.12,65.69 202.23,65.69 v3(202.38,65.85) ; v3(208.91,64.75) 208.71,64.55 208.71,64.01 207.36,62.66 207.36,61.71 208.33,60.74 209.17,60.74 209.54,60.37 209.54,59.2 209.8,58.94 209.8,56.73 209.06,55.99 208.58,55.99 v3(208.15,56.42)
  IN4 w0.076: v4(131.66,67.75) 131.66,68.08 132,68.41 139.39,68.41 141.55,66.25 141.55,65.46 142.29,64.71 142.88,64.71 143.63,65.46 143.63,65.69 144.93,66.99 147.64,66.99 v3(147.72,66.91) ; v3(208.15,56.42) 208.27,56.42 v4(208.48,56.62) ; v3(208.91,64.75) 208.58,65.08 203.14,65.08 v3(202.38,65.85)
  BOTTOM w0.076: U34.D5 208.6,54.19 208.6,54.58 208.33,54.85 208.33,55.07 208.6,55.34 208.6,56.5 v4(208.48,56.62)
  BOTTOM w0.109: JLVDS2.29 131.65,67.74 v4(131.66,67.75)
EC_SMI#: length 56.2
  IN2 w0.102: v3(166.17,51.39) 167.18,51.39 167.82,52.03 169.16,52.03 169.54,52.41 171.29,52.41 171.93,53.04 178.65,53.04 179.63,52.06 183.46,52.06 184.02,52.61 185.69,52.61 187.07,54 188.49,54 189.49,52.99 194.15,52.99 194.76,53.6 199.82,53.6 200.2,53.22 200.73,53.22 201.11,53.6 203.7,53.6 204.95,52.35 204.95,52.03 205.71,51.27 205.71,51.14 206.38,50.47 207.64,50.47 208.55,49.56 v3(211.91,49.56)
  IN4 w0.076: v4(212.29,49.56) v3(211.91,49.56) ; v3(166.17,51.39) 166.21,51.39 v4(166.62,51.8)
  BOTTOM w0.109: v4(212.29,49.56) 212.24,49.56 U34.L13 ; UCPU1.V1 163.94,52.6 164.08,52.46 164.94,52.46 165.42,52.94 T270.1 165.78,52.94 166.12,52.6 166.12,52.29 v4(166.62,51.8)
EC_TX: length 41.7
  TOP w0.109: v2(197.63,18.07) 198.08,18.51 v1(198.82,18.51)
  IN3 w0.102: v1(198.82,18.51) 199.71,19.4 199.71,33.47 206.57,40.32 206.57,42.04 207.98,43.45 207.98,47.26 210.51,49.79 210.51,50.4 211.18,51.08 v3(211.18,51.21)
  IN4 w0.076: v4(211.68,51.27) 211.24,51.27 v3(211.18,51.21)
  BOTTOM w0.109: U34.K10 211.5,51.44 v4(211.68,51.27) ; JDEBUG.11 198.93,18.61 v1(198.82,18.51)
EC_WAKE_SCI#: length 63.7
  TOP w0.109: v7(168.63,51.46) 168.43,51.26 168.43,50.78 168.01,50.36 168.01,48.7 168.46,48.24 170.11,48.24 170.95,47.4 v2(170.95,46.93) 170.04,46.02 169.49,46.02 RH427.2
  IN1 w0.076: v3(214.12,48.24) 213.92,48.24 213.04,47.37 210.39,47.37 209.72,46.69 203.17,46.69 202.37,47.49 195.94,47.49 195.43,48 185.57,48 184.75,48.83 183.34,48.83 183.09,49.08 179.45,49.08 177.53,50.99 177.53,51.51 177.3,51.74 176.19,51.74 175.95,51.49 168.67,51.49 v7(168.63,51.46)
  IN4 w0.076: v4(213.2,52.95) 213.2,52.75 213.56,52.4 213.56,52.28 213.82,52.01 213.82,50.87 213.58,50.63 213.58,49.83 214.12,49.3 v3(214.12,48.24)
  BOTTOM w0.109: U34.N7 213.2,52.94 v4(213.2,52.95)
ECAGND: length 122.5
  TOP w0.254: R948.2 134.77,47.09 133.98,47.87 133.98,48.31 133.28,49 131.41,49 130.1,50.31 130.1,57.52 128.87,58.76 v7(128.87,59.19)
  IN1 w0.254: v3(131.87,58.81) 131.24,59.44 129.57,59.44 129.32,59.19 v7(128.87,59.19)
  IN2 w0.254: v3(204.57,51.82) 204.57,52.3 203.6,53.27 201.21,53.27 200.86,52.92 200.07,52.92 199.69,53.3 194.89,53.3 194.28,52.69 188.89,52.69 188.72,52.87 186.43,52.87 185.16,51.6 179.66,51.6 178.52,52.74 173.82,52.74 173.18,52.1 169.67,52.1 169.29,51.72 167.95,51.72 166.12,49.89 160.34,49.89 160.11,49.67 159.71,49.67 159.35,50.02 159.35,50.61 158.74,51.21 158.74,51.88 158.13,52.48 156.08,52.48 151.5,57.06 151.5,57.92 149.78,59.65 132.71,59.65 v3(131.87,58.81)
  IN3 w0.254: v1(205.83,59.83) 205.83,59.29 204.76,58.21 204.76,55.62 204.11,54.97 204.11,53.76 204.57,53.3 v3(204.57,51.82) 204.79,51.6 204.79,50.66 205.05,50.4 205.05,49.39 v1(203.78,48.12)
  BOTTOM w0.254: L44.2 203.52,47.86 v1(203.78,48.12) 204.36,48.7 C282.2 204.59,48.75 204.79,48.75 205.4,49.36 205.4,49.74 206.46,50.8 206.71,50.8 U34.A11 ; v1(205.83,59.83) v2(205.83,59.16) 205.23,58.56 C286.1
EDP_AUXN: length 4.9
  TOP w0.109: v1(136.55,63.68) 136.74,63.87 137.35,63.87 137.45,63.97 137.89,63.97 138.12,64.2 138.12,64.44 C1065.1
  BOTTOM w0.109: v1(136.55,63.68) 136.7,63.68 136.77,63.61 136.77,63.08 136.63,62.95 136.52,62.95 136.39,63.08 136.39,63.33 136.26,63.46 136.14,63.46 136.04,63.36 136.04,62.99 UCPU1.A45
EDP_AUXN_C: length 3
  TOP w0.109: C1065.2 138.03,65.92 138.03,66.15 R1033.1 138.03,66.79 138.03,66.88 138.32,67.17 ML58.1 138.32,67.95 R1011.1
EDP_AUXN_CONN: length 18
  TOP w0.109: v1(138.19,70.29) 138.03,70.12 138.03,70.04 138.32,69.75 ML58.2 138.32,69.08 R1011.2
  BOTTOM w0.109: v1(138.19,70.29) 138.01,70.11 138.01,69.77 137.32,69.08 134.33,69.08 133.64,68.39 124.46,68.39 124.01,67.93 124.01,67.62 124.15,67.49 JLVDS2.14
EDP_AUXP: length 4.9
  TOP w0.109: C1064.1 137.82,64.68 137.9,64.6 137.9,64.29 137.79,64.19 137.35,64.19 137.25,64.09 136.76,64.09 136.59,64.26 v1(136.59,64.32)
  BOTTOM w0.109: UCPU1.B45 136.21,62.21 136.99,62.99 136.99,63.93 v1(136.59,64.32)
EDP_AUXP_C: length 3
  TOP w0.109: C1064.2 137.8,65.92 137.8,66.15 R1034.2 137.8,66.79 137.8,66.88 137.52,67.17 ML58.4 137.52,67.95 R1010.1
EDP_AUXP_CONN: length 18
  TOP w0.109: v1(137.61,70.29) 137.8,70.1 137.8,70.04 137.52,69.75 ML58.3 137.52,69.08 R1010.2
  BOTTOM w0.109: JLVDS2.13 123.65,67.46 123.79,67.59 123.79,68.03 124.37,68.61 133.54,68.61 134.23,69.3 137.23,69.3 137.79,69.86 137.79,70.11 v1(137.61,70.29)
EDP_BKLCTL: length 4.7
  BOTTOM w0.102: UCPU1.B8 158.47,62.28 158.47,63.13 158.68,63.34
  BOTTOM w0.109: 158.68,63.34 159.71,64.37 159.71,65.44 RC147.2
EDP_DISP: length 9.7
  TOP w0.109: v7(137.28,62.77) 137.33,62.72 139.11,62.72 139.72,63.33 v2(139.72,63.84) 140.34,64.47 140.34,65.67 139.81,66.2 139.81,67.04 140.19,67.42 RC158.2 RC146.1
  IN1 w0.076: v7(137.28,62.77) 137.28,63.08 v3(137.36,63.15)
  IN4 w0.109: v3(137.36,63.15) 137.59,62.92 v4(137.59,62.81)
EDP_HPD: length 32.5
  TOP w0.109: QC5.1 155.49,69.02 154.36,69.02 RC148.2 RC138.1 153.13,69.12 v2(147.48,69.12) 145.09,69.12 144.53,69.68 v7(144.38,69.68)
  IN1 w0.076: v7(144.38,69.68) 143.72,69.02 137.86,69.02 136.62,67.78 133.06,67.78 132.02,66.73 129.63,66.73 128.64,67.72 127.43,67.72 v3(127.15,67.45)
  IN4 w0.076: v3(127.15,67.45) v4(127.15,67.89)
  BOTTOM w0.109: JLVDS2.20 v4(127.15,67.89)
EDP_TXN_P0: length 5.2
  TOP w0.109: C1060.1 134.93,65.17 134.93,64.13 135.25,63.81 135.64,63.81 135.79,63.66 v1(135.81,63.66)
  BOTTOM w0.109: UCPU1.C45 136.35,61.51 136.42,61.58 136.42,61.78 136.34,61.86 136.11,61.86 135.83,62.14 135.83,63.27 135.71,63.39 135.71,63.57 135.79,63.66 v1(135.81,63.66)
EDP_TXN_P0_C: length 2.2
  TOP w0.109: C1060.2 134.88,66.32 135.03,66.48 135.03,66.76 135.07,66.8 135.07,66.92 134.78,67.21 ML57.4 134.78,67.93 R1008.1
EDP_TXN_P0_CONN: length 25.5
  TOP w0.109: R1008.2 134.78,69.06 ML57.3 134.78,69.84 134.99,70.05 134.99,70.33 135.24,70.57 135.62,70.57 135.74,70.44 v1(136.21,70.44)
  BOTTOM w0.109: JLVDS2.1 117.65,68.62 119,69.97 120.15,71.12 121.73,71.12 122.93,72.32 133.76,72.32 135.64,70.44 v1(136.21,70.44)
EDP_TXN_P1: length 5.4
  TOP w0.109: v1(134.38,63.08) 134.15,63.31 133.91,63.31 133.74,63.48 133.74,63.8 133.6,63.94 133.6,64.42 133.36,64.66 133.17,64.66 132.95,64.88 132.95,65.12 C1061.1
  BOTTOM w0.109: UCPU1.A47 135.08,62.53 134.99,62.44 134.82,62.44 134.73,62.53 134.73,62.86 134.87,63 134.87,63.12 134.6,63.38 134.49,63.38 134.38,63.28 v1(134.38,63.08)
EDP_TXN_P1_C: length 2.1
  TOP w0.109: C1061.2 133.04,66.64 133.04,66.95 132.75,67.24 ML56.4 132.75,67.93 R1006.1
EDP_TXN_P1_CONN: length 25.3
  TOP w0.109: v1(134.18,70.44) 134.18,70.34 134.1,70.26 133.89,70.26 133.48,70.67 133.13,70.67 132.8,70.34 132.8,69.88 132.75,69.84 ML56.3 132.75,69.06 R1006.2
  BOTTOM w0.109: JLVDS2.4 119.15,68.12 119.29,68.26 119.29,68.56 119.09,68.76 119.09,69.04 119.44,69.4 119.78,69.4 119.93,69.25 120.07,69.25 120.28,69.45 120.28,69.67 120.15,69.79 120.15,70.11 120.44,70.4 120.9,70.4 121.18,70.12 121.78,70.12 123.27,71.61 133.17,71.61 133.47,71.31 133.47,70.8 132.87,70.2 132.87,69.94 133.06,69.75 133.28,69.75 133.79,70.26 134,70.26 v1(134.18,70.44)
EDP_TXN_P2: length 7.6
  TOP w0.109: v1(130.71,64.42) 130.92,64.63 130.92,65.13 C1066.1
  IN4 w0.076: v4(135.08,61.51) 135.42,61.6 135.46,61.67 135.48,61.69 135.48,61.88 134.92,62.44 132.62,62.44 130.99,64.07 130.99,64.15 v1(130.71,64.42)
EDP_TXN_P2_C: length 2.1
  TOP w0.109: R1013.1 130.72,67.93 ML59.4 130.72,67.24 131.01,66.95 131.01,66.62 C1066.2
EDP_TXN_P2_CONN: length 22.9
  TOP w0.109: R1013.2 130.72,69.06 ML59.3 130.72,70.56 130.98,70.82 131.45,70.82 131.73,70.55 131.73,70.4 131.86,70.26 132.06,70.26 132.15,70.35 v1(132.15,70.44)
  BOTTOM w0.109: v1(132.15,70.44) 132.07,70.37 131.67,70.37 131.59,70.44 131.59,70.62 131.39,70.82 130.74,70.82 130.5,70.59 130.5,69.52 130.4,69.41 130.07,69.41 129.97,69.52 129.97,70.57 129.74,70.81 129.21,70.81 128.97,70.57 128.97,69.5 128.87,69.4 128.5,69.4 128.4,69.5 128.4,70.57 128.14,70.83 123.52,70.83 121.95,69.26 121.41,69.26 120.88,68.72 120.88,68.15 120.65,67.92 JLVDS2.7
EDP_TXN_P3: length 7.5
  TOP w0.109: C1068.1 129.19,65.44 129.11,65.36 129.11,64.45 129.04,64.37 129.04,63.98 129.67,63.35 130.81,63.35 130.9,63.26 v6(131.31,63.26) 131.67,63.26 131.76,63.35 133.03,63.35 v1(133.24,63.56)
  BOTTOM w0.109: v1(133.24,63.56) 133.44,63.56 133.7,63.3 UCPU1.A49
EDP_TXN_P3_C: length 2
  TOP w0.109: C1068.2 129.19,66.7 129.19,66.88 129.49,67.19 ML60.1 129.49,67.87 R1015.1
EDP_TXN_P3_CONN: length 23
  TOP w0.109: R1015.2 129.49,69.13 ML60.2 129.49,69.81 129.12,70.18 129.12,71.15 129.28,71.32 129.8,71.32 129.81,71.32 133.19,71.32 133.45,71.58 133.45,72.03 133.19,72.28 v6(131.43,72.28) 128.16,72.28 127.92,72.05 127.92,70.23 v1(127.68,69.99)
  BOTTOM w0.109: JLVDS2.10 122.15,67.51 122.3,67.66 122.3,68.57 122.96,69.23 123.37,69.23 123.65,69.52 126.94,69.52 127.26,69.83 127.52,69.83 127.52,69.83 v1(127.68,69.99)
EDP_TXP_P0: length 5.2
  TOP w0.109: v1(135.81,64.32) 135.81,64.26 135.59,64.04 135.34,64.04 135.15,64.22 135.15,65.31 135.26,65.41 C1062.1
  BOTTOM w0.109: v1(135.81,64.32) 135.36,63.87 135.36,63.42 135.6,63.18 135.6,61.88 UCPU1.B46
EDP_TXP_P0_C: length 2.1
  TOP w0.109: C1062.2 135.46,66.32 135.26,66.53 135.26,66.67 135.3,66.71 135.3,66.92 135.58,67.21 ML57.1 135.58,67.93 R1009.1
EDP_TXP_P0_CONN: length 25.5
  TOP w0.109: v1(136.21,69.81) 136.21,69.86 135.86,70.22 135.65,70.22 135.52,70.35 135.33,70.35 135.22,70.24 135.22,70.03 135.31,69.93 135.44,69.93 135.58,69.79 ML57.2 135.58,69.06 R1009.2
  BOTTOM w0.109: v1(136.21,69.81) 136.21,69.86 135.86,70.22 135.55,70.22 133.67,72.1 123.02,72.1 121.82,70.9 120.24,70.9 119.16,69.82 117.87,68.53 117.87,67.59 117.95,67.51 118.08,67.51 118.15,67.43 JLVDS2.2
EDP_TXP_P1: length 5.5
  TOP w0.109: C1063.1 133.29,65.38 133.17,65.26 133.17,64.97 133.27,64.88 133.46,64.88 133.82,64.52 133.82,64.03 133.96,63.89 133.96,63.58 134,63.53 134.3,63.53 134.37,63.61 v1(134.37,63.79)
  BOTTOM w0.109: v1(134.37,63.79) 134.55,63.6 134.69,63.6 135.38,62.92 135.38,62.46 UCPU1.B47
EDP_TXP_P1_C: length 2
  TOP w0.109: R1007.1 133.55,67.93 ML56.1 133.55,67.24 133.26,66.95 133.26,66.6 C1063.2
EDP_TXP_P1_CONN: length 25.3
  TOP w0.109: v1(134.18,69.81) 134.18,69.96 134.11,70.04 133.8,70.04 133.39,70.45 133.22,70.45 133.02,70.25 133.02,70.02 133.1,69.93 133.36,69.93 133.55,69.74 ML56.2 133.55,69.06 R1007.2
  BOTTOM w0.109: v1(134.18,69.81) 134.18,69.95 134.09,70.04 133.89,70.04 133.37,69.53 132.96,69.53 132.64,69.85 132.64,70.29 133.25,70.89 133.25,71.21 133.07,71.39 123.37,71.39 121.88,69.9 121.09,69.9 120.8,70.18 120.53,70.18 120.37,70.02 120.37,69.89 120.5,69.76 120.5,69.36 120.16,69.03 119.84,69.03 119.69,69.17 119.54,69.17 119.31,68.95 119.31,68.85 119.51,68.65 119.51,68.17 119.37,68.03 119.37,67.56 119.45,67.48 119.58,67.48 119.65,67.41 JLVDS2.5
EDP_TXP_P2: length 7.7
  TOP w0.109: v1(131.36,64.42) 131.19,64.59 131.19,65 C1067.1
  IN4 w0.076: v4(135.65,61.19) 135.55,61.53 135.58,61.58 135.63,61.62 135.63,61.95 134.98,62.59 132.68,62.59 131.14,64.14 131.14,64.2 v1(131.36,64.42)
EDP_TXP_P2_C: length 2.1
  TOP w0.109: C1067.2 131.23,66.62 131.23,66.92 131.52,67.21 ML59.1 131.52,67.93 R1012.1
EDP_TXP_P2_CONN: length 22.9
  TOP w0.109: v1(132.15,69.81) 132.15,69.95 132.06,70.04 131.77,70.04 131.5,70.3 131.5,70.46 131.36,70.6 131.07,70.6 130.94,70.47 130.94,70.06 131.04,69.96 131.3,69.96 131.52,69.74 ML59.2 131.52,69.06 R1012.2
  BOTTOM w0.109: v1(132.15,69.81) 132.15,69.86 131.87,70.14 131.57,70.14 131.37,70.35 131.37,70.53 131.29,70.6 130.83,70.6 130.73,70.49 130.73,69.42 130.49,69.19 129.98,69.19 129.75,69.42 129.75,70.48 129.65,70.58 129.3,70.58 129.2,70.48 129.2,69.41 128.97,69.18 128.41,69.18 128.18,69.41 128.18,70.48 128.05,70.61 123.61,70.61 122.04,69.03 121.51,69.03 121.1,68.63 121.1,68.05 120.87,67.83 120.87,67.61 120.95,67.53 121.08,67.53 121.15,67.46 JLVDS2.8
EDP_TXP_P3: length 7.6
  TOP w0.109: v1(133.24,62.97) 133.09,63.13 131.85,63.13 131.75,63.03 130.81,63.03 130.71,63.13 129.57,63.13 128.81,63.89 128.81,64.46 128.89,64.54 128.89,65.19 C1069.1
  BOTTOM w0.109: UCPU1.B49 133.24,62.62 v1(133.24,62.97)
EDP_TXP_P3_C: length 2
  TOP w0.109: R1014.1 128.69,67.93 ML60.4 128.69,67.21 128.96,66.94 128.96,66.67 C1069.2
EDP_TXP_P3_CONN: length 22.6
  TOP w0.109: R1014.2 128.71,69.08 128.71,69.86 128.9,70.05 128.9,71.25 129.2,71.55 v6(129.55,71.55) 133.1,71.55 133.23,71.67 133.23,71.93 133.1,72.06 131.69,72.06 131.68,72.05 131.17,72.05 131.16,72.06 128.25,72.06 128.15,71.96 128.15,69.88 128.15,69.88 128.15,69.82 v1(127.68,69.35)
  BOTTOM w0.109: v1(127.68,69.35) 127.68,69.4 127.48,69.6 127.43,69.6 127.43,69.6 127.35,69.6 127.04,69.29 123.75,69.29 123.46,69.01 123.06,69.01 122.52,68.48 122.52,67.59 122.65,67.46 JLVDS2.11
EN_+1.05VS: length 5.3
  TOP w0.203: v1(199.62,60.51) 199.7,60.51 200.09,60.9 v2(200.09,61.14) 200.09,61.5 199.66,61.93 PU501.28
  BOTTOM w0.254: R503.2 R501.2 198.95,59.67 199.61,60.33 199.61,60.5 v1(199.62,60.51)
EN_+1.5VSP: length 4.4
  TOP w0.109: PR404.2 92,49.82 92,50.58 91.27,51.32 v2(91.07,51.32)
  TOP w0.254: PU405.13 91.46,49.27 PR404.2
EN_+1.8VSP: length 3.3
  TOP w0.109: v2(226.96,41.88) PR405.2
  TOP w0.254: PU406.13 226.09,40.84 226.17,40.76 PR405.2
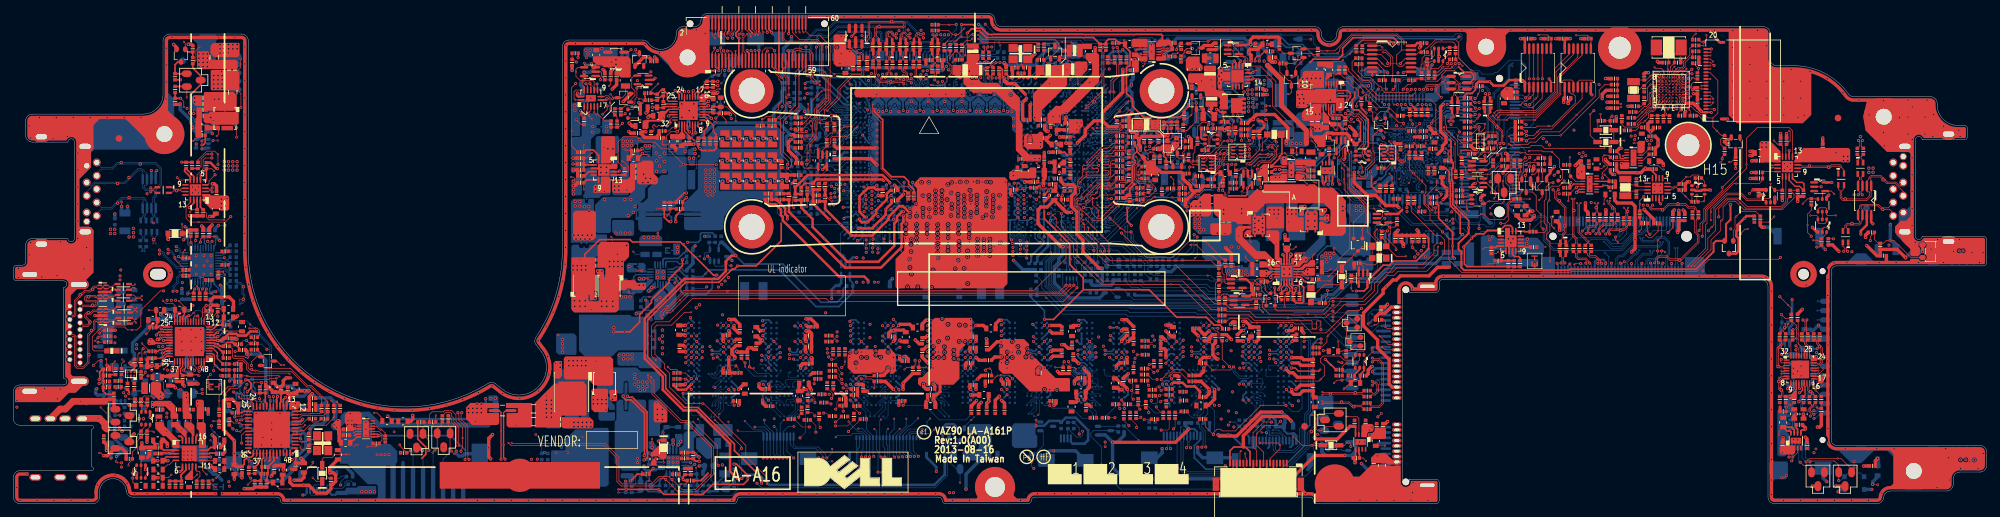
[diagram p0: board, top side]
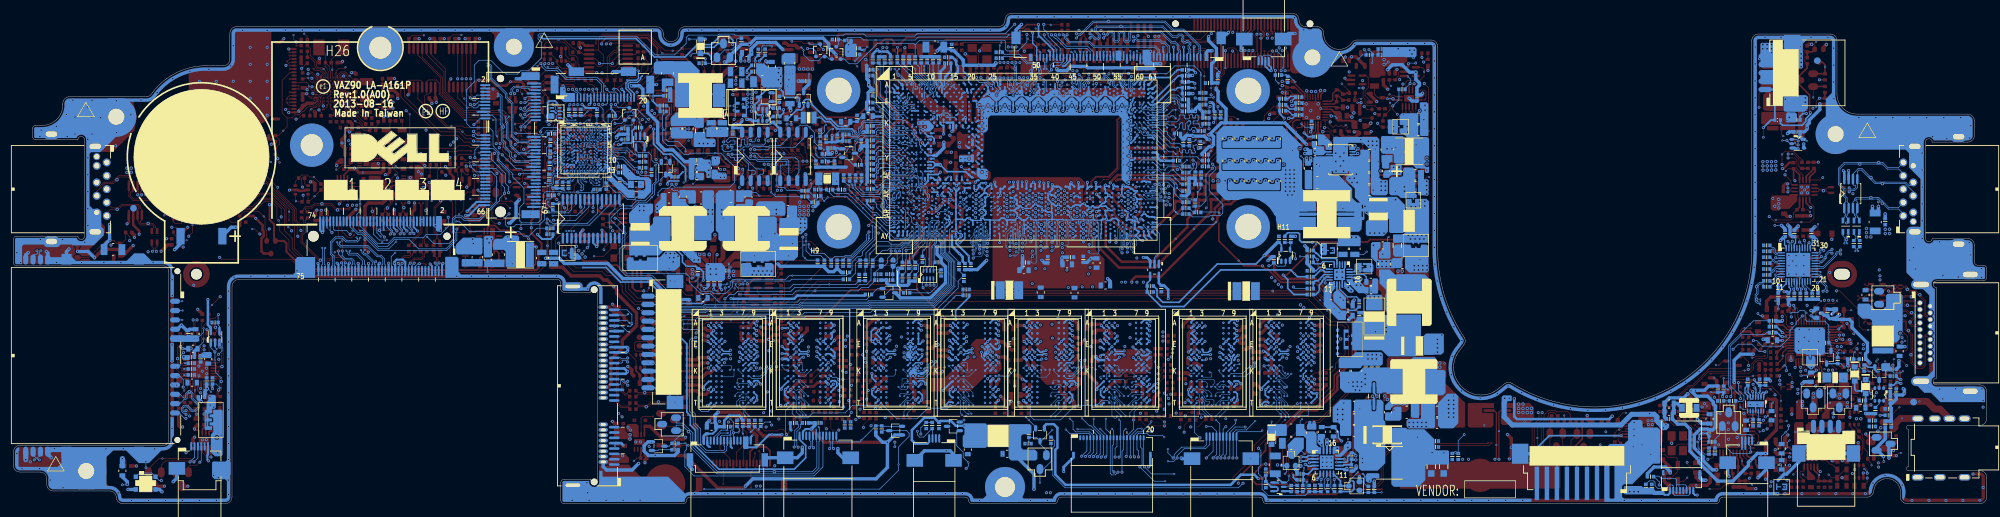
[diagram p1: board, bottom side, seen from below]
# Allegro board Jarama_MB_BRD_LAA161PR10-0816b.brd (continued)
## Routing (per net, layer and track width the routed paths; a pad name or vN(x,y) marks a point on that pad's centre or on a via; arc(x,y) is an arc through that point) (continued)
EN_+V5A: length 2.5
  TOP w0.109: D307.1 187.82,31.55 187.35,32.02 v2(187.35,32.27) 187.35,32.65 PR345.2
EN_CAM: length 34.9
  TOP w0.203: R1162.1 188.51,49.46 v2(189.19,49.46) 189.52,49.46 189.73,49.67 U715.5
  TOP w0.254: v1(188.9,50.1) 188.68,50.1 R1162.1
  IN3 w0.102: v1(188.9,50.1) 186.87,48.07 183.25,48.07 183,47.81 183,47.21 182.73,46.95 182.16,46.95 180.94,48.17 176.59,48.17 175.37,46.95 168.57,46.95 168.19,46.57 163.8,46.57 163.39,46.16 161.89,46.16 161.49,45.75 161.49,45.02 v3(161.28,44.81)
  IN4 w0.076: v4(161.51,45.14) 161.51,45.04 v3(161.28,44.81)
EN_WLANPWR#: length 29
  TOP w0.109: D115.3 231.49,48.42 231.83,48.76 231.83,49.96 231.37,50.41 231.37,51.62 v2(230.24,52.75) 228.93,52.75 228.8,52.89 226.83,52.89 v7(226.78,52.84)
  IN1 w0.076: v3(209.9,54.52) 209.98,54.52 210.51,53.98 210.51,53.68 210.69,53.5 212.03,53.5 212.62,54.08 213.19,54.08 213.32,54.21 216.22,54.21 216.62,53.82 219.22,53.82 219.63,53.41 221.79,53.41 222.27,52.93 224.62,52.93 225.22,52.33 226.27,52.33 v7(226.78,52.84)
  IN4 w0.076: v3(209.9,54.52) 209.81,54.52 209.52,54.81 v4(209.52,54.97)
  BOTTOM w0.109: U34.F4 209.52,54.61 v4(209.52,54.97)
ENBKL: length 26.4
  TOP w0.109: RH123.2 175.22,67.6 175.22,67.88 175.55,68.21 v1(176.45,68.21)
  IN2 w0.102: v1(176.45,68.21) 175.39,67.15 175.03,67.15 174.78,66.9 168.23,66.9 167.96,67.17 167.3,67.17 166.77,66.63 164.41,66.63 163.98,66.2 160,66.2 v3(159.45,65.65)
  IN4 w0.076: v4(159,65.59) 159.39,65.59 v3(159.45,65.65)
  BOTTOM w0.109: UCPU1.A9 158.01,63.52 159,64.51 v2(159,65.01) v4(159,65.59) ; D72.2 175.2,67.73 175.69,68.21 v1(176.45,68.21)
F-IMAX: length 5.1
  TOP w0.203: PU701.10 103.55,57.91 104.77,56.69 v2(104.77,55.96) 104.77,55.77 105.15,55.39 PR745.2 PR712.1
FAN_TEMP0: length 212.2
  TOP w0.109: R949.1 R951.1 83.85,66.61 v1(84.26,66.2)
  IN1 w0.076: v1(84.26,66.2) 84.83,66.2 85.15,66.52 88.78,66.52 89.91,65.39 93.86,65.39 94.49,66.02 98.09,66.02 99.75,64.36 101.94,64.36 104.02,66.44 104.02,71.19 105.21,72.37 119.42,72.37 120.76,71.03 121.76,71.03 123.12,72.4 140.24,72.4 140.37,72.26 144.85,72.26 145.24,71.86 v1(145.45,71.86)
  BOTTOM w0.109: v1(145.45,71.86) 146.87,70.45 160.08,70.45 160.44,70.09 167.7,70.09 168.01,70.4 170.85,70.4 171.03,70.22 187.28,70.22 187.45,70.39 189.69,70.39 189.85,70.24 194.27,70.24 194.61,69.9 194.61,68.99 196.33,67.27 199.23,67.27 201.97,70.02 215.48,70.02 215.89,70.43 216.57,70.43 216.77,70.23 216.77,69.68 216.26,69.17 216.26,66.8 218.17,64.89 219.36,64.89 219.86,64.4 221.52,64.4 221.77,64.65 222.03,64.65 223.86,66.47 225.6,66.47 226.33,65.73 226.33,63.19 227.51,62.01 227.51,57.04 226.83,56.36 224.06,56.36 223.51,55.81 223.51,53.63 222.65,52.77 222.65,51.54 220.57,49.45 220.57,48.95 218.89,47.28 218.89,45.03 219.51,44.41 219.51,42.39 219.22,42.1 216.8,42.1 216.25,42.64 216.25,44.09 215.98,44.36 215.98,46.41 215.58,46.82 213.45,46.82 213.33,46.71 v1(210.84,46.71) 210.75,46.62 207.94,46.62 207.51,47.05 C1253.1 207.45,47.1 207.03,47.52 207.03,49.77
  BOTTOM w0.254: U34.A13 207.03,49.77
FB_3V: length 4.8
  TOP w0.203: PR353.2 191.37,31.7 191.37,32.38 191.37,32.39 191.37,32.4 191.37,32.41 190.96,32.82 PU301.4
  TOP w0.254: PR353.2 191.9,31.83 191.9,32.3 191.92,32.32 v1(191.92,32.26)
  BOTTOM w0.109: v2(192.42,32.76) v1(191.92,32.26)
  BOTTOM w0.254: PR352.2 191.33,32.49 191.57,32.26 v1(191.92,32.26)
FB_5V: length 4.3
  TOP w0.203: PU301.2 190.16,32.7 189.77,32.31 PR316.1 190.4,32.14 v1(190.51,32.14)
  BOTTOM w0.109: 190.49,32.14 190.26,31.91 v2(189.96,31.91)
  BOTTOM w0.254: PR354.1 190.44,32.19 190.49,32.14 v1(190.51,32.14)
FB_+1.8VSP: length 6.1
  TOP w0.109: v2(220.64,35.96) 222.17,35.96 PR438.1
  TOP w0.254: PR433.2 PC440.2 223.69,36.43 PR438.1 222.64,37.52 222.98,37.87 PU406.5
FIVE_EN: length 20.5
  TOP w0.109: JXDP.45 115.07,65.27 115.34,65.01 115.34,64.14 115.61,63.86 v2(115.61,60.94) 115.61,60.14 v1(116.22,59.54)
  IN1 w0.076: v3(126.92,58.66) 126.84,58.66 126.33,58.15 124.12,58.15 122.85,59.42 122.37,59.42 122.35,59.44 116.31,59.44 v1(116.22,59.54)
  IN4 w0.076: v3(126.92,58.66) 126.92,58.68 v4(127.19,58.95)
  BOTTOM w0.109: v4(127.19,58.95) 127.43,58.72 UCPU1.H59 ; v1(116.22,59.54) 116.38,59.38 R1179.2
FSW_+1.8VS: length 2.3
  TOP w0.254: PR437.2 225.49,36.83 225.28,37.04 224.67,37.04 224.35,37.36 PU406.7
GPIO12: length 25.5
  TOP w0.109: v2(181.35,46.33) 181.35,46.58 v1(180.96,46.97) 181.03,47.05 RH296.1
  IN3 w0.102: v3(159.97,45.09) 160.08,45.19 160.65,45.19 160.9,44.94 160.9,44.61 161.13,44.38 162.85,44.38 163.66,45.19 163.66,45.92 163.84,46.11 168.84,46.11 169.15,46.41 175.48,46.41 176.74,47.67 180.27,47.67 180.96,46.99 v1(180.96,46.97)
  IN4 w0.076: v3(159.97,45.09) 159.96,45.1 159.96,45.14 159.72,45.39 v4(159.72,45.39)
GYRO_DRDY: length 126.8
  TOP w0.076: U636.G5 249.34,62.44 249.58,62.68 249.58,62.92 249.74,63.08 249.97,63.08 250.51,63.62 250.51,63.64 v1(250.64,63.76)
  IN2 w0.102: v3(134.71,67.14) 134.71,67.6 136.7,69.58 136.7,70.67 137.33,71.31 145.28,71.31 146.55,70.04 169.26,70.04 169.66,70.43 181.48,70.43 181.88,70.04 193.47,70.04 195.57,67.93 199.94,67.93 200.77,67.1 208.23,67.1 209.06,67.93 215.74,67.93 217.84,65.83 221.87,65.83 222.22,66.18 236.34,66.18 237.41,65.11 243.57,65.11 243.97,65.51 247.03,65.51 248.68,63.86 250.54,63.86 v1(250.64,63.76)
  IN4 w0.076: v3(134.71,67.14) 134.71,67.65 v4(134.65,67.71)
  BOTTOM w0.109: JLVDS2.35 v4(134.65,67.71)
GYRO_INT#: length 128.7
  TOP w0.109: 249.92,63.91 249.92,64 250.61,64.68 250.76,64.68 v1(251.19,65.11)
  TOP w0.254: U636.H8 249.92,63.91
  IN2 w0.102: v1(251.19,65.11) 250.77,64.69 250.77,64.22 251.05,63.94 251.05,63.53 250.77,63.25 250.46,63.25 250.08,63.64 248.59,63.64 246.94,65.29 244.07,65.29 243.66,64.88 237.31,64.88 236.25,65.95 222.31,65.95 221.97,65.6 217.74,65.6 215.65,67.7 209.16,67.7 208.32,66.87 200.68,66.87 199.85,67.7 195.37,67.7 193.26,69.81 181.78,69.81 181.38,70.2 169.77,70.2 169.3,69.73 146.53,69.73 145.19,71.08 137.43,71.08 136.92,70.58 136.92,69.48 135.3,67.86 v3(135.3,67.17)
  IN4 w0.076: v3(135.3,67.17) 135.15,67.31 v4(135.15,67.71)
  BOTTOM w0.109: v4(135.15,67.71) JLVDS2.36
H_CATERR#: length 3.8
  BOTTOM w0.102: UCPU1.K61 125.62,56.66 124.37,56.66
  BOTTOM w0.109: 124.37,56.66 124.37,56.67 122.92,56.67 T2.1
H_CPU_SVIDALRT#: length 7.3
  BOTTOM w0.109: RC94.2 RC93.1 120.41,53.65 120.78,54.02 v2(121.61,54.02) 122.05,54.02 124.02,55.99 125.09,55.99 UCPU1.L62
H_CPU_SVIDCLK: length 12.8
  BOTTOM w0.109: UCPU1.N63 124.75,55.71 124.54,55.71 122.28,53.45 121.61,53.45 121.48,53.32 121.3,53.32 121.18,53.45 121.02,53.45 120.79,53.21 120.79,52.82 120.52,52.55 120.41,52.55 120.31,52.65 120.31,52.96 120.2,53.07 119.99,53.07 119.88,52.96 119.88,52.66 119.77,52.55 119.55,52.55 119.44,52.66 119.44,52.96 119.33,53.07 119.11,53.07 119,52.96 119,52.67 v2(118.89,52.55) 118.49,52.55 118.4,52.65 118.4,52.8 118.57,52.97 118.57,53.2 118.74,53.37 118.74,53.65 118.66,53.73 118.41,53.73 118.33,53.81 118.23,53.81 118.13,53.7 118.13,53.18 118.02,53.07 117.89,53.07 117.67,53.29 RC92.2
H_CPU_SVIDDAT: length 13.9
  BOTTOM w0.109: RC96.2 118.31,56.17 118.31,56.24 118.43,56.37 118.86,56.37 118.99,56.24 118.99,56.11 119.1,56 119.32,56 119.43,56.11 v2(119.43,56.63) 119.11,56.95 119.11,57.24 119.25,57.39 119.44,57.39 119.87,56.96 119.87,56.19 119.99,56.07 120.18,56.07 120.3,56.19 120.3,57.03 120.39,57.12 120.51,57.12 120.82,56.8 120.82,56.35 121.56,55.61 RC95.2 121.56,55.05 121.43,54.92 121.43,54.76 121.61,54.58 121.81,54.58 122.56,55.33 122.56,55.67 122.7,55.81 123.34,55.81 123.91,56.38 UCPU1.L63
H_CPUPWRGD_R: length 12
  TOP w0.109: RC44.2 118.28,57.03 119.43,58.18 119.43,60.29 v5(120.25,61.11) v7(120.97,61.83)
  IN1 w0.076: v3(125.55,61.46) 125.55,61.45 124.53,61.45 124.28,61.7 121.1,61.7 v7(120.97,61.83)
  IN4 w0.076: v3(125.55,61.46) 125.62,61.54 v4(125.95,61.54)
  BOTTOM w0.109: v4(125.95,61.54) 125.99,61.58 UCPU1.C61
H_DRAMRST#: length 6.3
  BOTTOM w0.109: RC162.1 153.79,36.22 v2(155.24,37.67) 155.24,41.03 154.8,41.47 UCPU1.AV15
H_PECI: length 91.7
  TOP w0.109: v7(202.42,60.9) 202.42,60.59 R240.2 203.15,60 204.01,59.15 v2(204.01,59.09)
  IN1 w0.076: v3(200.17,60.99) 202.14,60.99 202.23,60.9 v7(202.42,60.9)
  IN3 w0.102: v3(124.94,56.55) 125.29,56.9 125.65,56.9 126.05,57.31 127.09,57.31 129.63,59.85 150.01,59.85 150.69,59.16 154.53,59.16 155.09,58.61 156,58.61 156.94,59.55 157.68,59.55 158.59,58.63 160.32,58.63 160.62,58.94 163.75,58.94 164.21,58.47 166.34,58.47 166.8,58.02 167.87,58.02 169.22,56.68 175.35,56.68 175.71,56.32 179.83,56.32 180.61,57.11 181.68,57.11 182.34,56.45 183.99,56.45 184.93,55.51 187.7,55.51 188.58,54.63 189.17,54.63 190.43,53.37 193.6,53.37 194.97,54.75 196.54,54.75 200.27,58.48 200.27,59.53 200.17,59.63 v3(200.17,60.99)
  IN4 w0.076: v4(125.48,55.63) 124.94,56.18 v3(124.94,56.55)
H_PROCHOT#: length 181.6
  TOP w0.109: v7(191.89,18.37) 195.38,18.37 v2(195.64,18.63) 196.18,19.17 196.18,20.66 195.64,21.2 195.64,21.75 196.02,22.13 198.54,22.13 199.15,21.52 200.39,21.52 200.82,21.95 PQ105.3 200.82,22.59 201.1,22.87 202.09,22.87 202.37,23.15 202.37,24.01 202.09,24.29 PQ104.1 199.51,24.77 PQ106.1
  IN1 w0.076: v7(191.89,18.37) 191.03,18.37 188.44,15.78 188.44,13.76 184.23,9.56 181.13,9.56 179.58,8.01 177.09,8.01 176.29,8.81 155.39,8.81 153.7,10.5 139.02,10.5 137.22,8.7 111.8,8.7 109.92,10.57 107.26,10.57 103.65,14.18 101.87,14.18 99.38,16.67 99.38,27.14 100.02,27.77 100.02,31.15 103.41,34.54 103.41,36.69 v1(103.42,36.71) 103.42,37.4 105.99,39.96 105.99,43.36 109.63,47 114.57,47 115.54,47.96 115.97,47.96 116.71,48.7 116.71,51.05 117.9,52.24 117.9,54.62 116.38,56.14 v1(116.38,56.19)
  BOTTOM w0.109: v1(116.38,56.19) RC41.1 RC43.1 ; v1(103.42,36.71) 103.42,37.47 103.63,37.68 104.08,37.68 104.25,37.84 U635.4 104.25,38.51 104.13,38.63 C656.1 R265.1
H_PROCHOT#_R: length 13.4
  BOTTOM w0.109: UCPU1.K63 123.99,57.13 123.89,57.23 121.19,57.23 120.84,57.59 120.84,58.18 120.76,58.26 120.13,58.26 120.02,58.16 120.02,57.8 119.92,57.69 119.4,57.69 119.29,57.8 119.29,58.19 119.14,58.35 118.96,58.35 118.86,58.24 118.86,57.95 118.73,57.82 v2(118.53,57.82) 118.42,57.93 118.42,58.15 118.31,58.26 118.09,58.26 117.98,58.15 117.98,57.49 118.09,57.38 118.64,57.38 118.75,57.27 118.75,57.05 118.64,56.94 117.93,56.94 117.82,56.83 117.82,56.56 117.71,56.45 117.4,56.45 117.29,56.56 RC41.2
H_PROCHOT_EC: length 179.3
  TOP w0.109: v1(195.69,24.1) 194.85,24.1 194.49,23.74 PR110.1
  IN4 w0.076: v1(107.41,35.67) 107.41,35.49 103.93,32.01 103.85,32.01 99.61,27.78 99.61,15.38 104.62,10.37 118.18,10.37 118.34,10.21 122.7,10.21 123.74,11.26 125.75,11.26 126.41,10.6 140.03,10.6 141.97,12.54 142.68,12.54 143.58,13.44 150.95,13.44 152.29,12.11 153.19,12.11 154.91,10.39 157.62,10.39 158.01,10 160.08,10 160.71,10.63 175.59,10.63 176.27,9.95 179.1,9.95 179.26,9.79 189.5,9.79 192.91,13.19 192.91,13.68 194.71,15.49 194.71,23.25 195.56,24.1 v1(195.69,24.1) 195.22,24.57 195.22,26.27 196.01,27.06 196.01,32.49 196.61,33.1 196.61,34.08 201.21,38.68 201.21,41.83 202.56,43.18 202.56,47.53 203.96,48.93 203.96,50.3 204.97,51.32 204.97,52.02 206.89,53.93 207.13,53.93 207.82,54.62 207.94,54.62 208.3,54.97 208.55,54.97 208.57,54.96 208.6,54.96 208.6,54.96 v4(208.6,54.96)
  BOTTOM w0.076: v4(208.6,54.96) 208.6,54.99 208.86,55.25 U34.E2
  BOTTOM w0.109: v1(107.41,35.67) 107.12,35.67 R608.2 106.16,35.6 105.07,35.6 104.9,35.78 U635.2
H_THERMTRIP#: length 2
  BOTTOM w0.109: RC149.1 RC49.2 116.67,60.85 v2(115.74,60.85)
H_THERMTRIP#_R: length 9.5
  IN1 w0.076: v3(125.52,60.91) 124.57,60.91 124.4,61.07 118.69,61.07 v1(118.43,60.82)
  IN4 w0.076: v4(126.78,61.01) 126.52,61.27 125.89,61.27 v3(125.52,60.91)
  BOTTOM w0.109: v1(118.43,60.82) 118.31,60.69 RC49.1
HDA_BIT_CLK: length 6.8
  BOTTOM w0.102: 158.42,39.82 158.29,39.95 158.29,40.3 158.59,40.59 UCPU1.AW8
  BOTTOM w0.109: RP3.8 159.11,35.48 158.77,35.82 158.77,36.6 MC96.1 159.25,37.8 v2(159.06,37.99) 158.57,38.49 158.57,39.68 158.42,39.82
HDA_BITCLK_AUDIO: length 139.1
  TOP w0.109: UA1.6 42.82,10.84 42.97,10.99 43.54,10.99 44.31,11.76 46.84,11.76 47.96,12.87 v7(47.96,13.06) RA58.1 ; v7(96.17,21.5) 95.48,22.18 v2(95.48,25.08) 95.48,26.63 96.11,27.25 98.12,27.25 101.61,30.74 121.63,30.74 122.09,30.29 157.08,30.29 v1(159.16,32.37)
  IN1 w0.076: v7(47.96,13.06) 48.7,13.06 48.93,12.84 51.53,12.84 52.62,11.74 53.1,11.74 53.28,11.57 63.47,11.57 63.98,11.06 63.98,11.06 64.27,10.77 75.02,10.77 75.73,10.05 90.13,10.05 97.1,17.03 97.1,20.57 v7(96.17,21.5)
  BOTTOM w0.109: v1(159.16,32.37) 159.16,32.38 159.26,32.48 159.26,33.27 159.11,33.42 RP3.1
HDA_BITCLK_AUDIO_R: length 3.4
  TOP w0.203: 30.12,23.57 29.99,23.7 UA2.5
  TOP w0.254: 30.12,23.57 30.14,23.54 v2(30.47,23.54) 31.3,22.72 CA41.1 RA29.2
HDA_BITCLK_DSP: length 30.5
  TOP w0.109: v7(33.5,16.52) v2(34.12,16.52) 34.42,16.21 35.45,16.21 36.41,15.25 UA1.23 ; v7(47.57,15.44) 47.96,15.05 RA58.2
  IN1 w0.076: v7(33.5,16.52) 33.52,16.54 33.52,19.9 32.66,20.76 32.66,21.5 v7(32.33,21.83) 32.33,21.94 v1(33.19,22.8) ; v7(47.57,15.44) 47.17,15.44 44.85,17.76 44.18,17.76 40.13,21.81 39.26,21.81 v1(37.94,23.14)
  BOTTOM w0.109: v1(33.19,22.8) 34.04,22.8 35.15,23.91 37.17,23.91 v1(37.94,23.14)
HDA_RST#: length 7.6
  BOTTOM w0.102: UCPU1.AU8 158.31,41.82 158.31,40.56 158.12,40.37 158.12,39.65 158.12,39.65
  BOTTOM w0.109: 158.12,39.65 158.12,39.18 158.26,39.03 v2(158.26,36.64) 158.26,35.59 158.61,35.24 RP3.7
HDA_RST_AUDIO#: length 135.3
  TOP w0.109: v7(46.13,13.8) 45.83,13.5 44.54,13.5 44.49,13.45 43.12,13.45 43.01,13.34 UA1.11 ; v1(158.71,32.75) 157.21,31.25 101,31.25 v2(98.72,28.97) 98.35,28.61 v7(97.8,28.61)
  IN1 w0.076: v7(46.13,13.8) 46.67,14.33 49.19,14.33 49.8,13.72 52.36,13.72 53.65,12.43 63.83,12.43 64.34,11.92 64.63,11.63 75.38,11.63 76.09,10.92 89.75,10.92 96.18,17.35 96.18,20.21 95.29,21.1 95.29,26.91 97,28.61 v7(97.8,28.61)
  BOTTOM w0.109: v1(158.71,32.75) 158.61,32.84 RP3.2
HDA_RST_AUDIO#_R: length 30.5
  TOP w0.203: UA2.6 30.02,24.1 30.13,23.99
  TOP w0.254: 30.13,23.99 30.16,23.96 30.6,23.96 30.96,23.6 v7(31.41,23.6) 31.97,24.16 32.78,24.16 33.04,23.91 CA26.1 33.83,23.29 RA30.2
  IN1 w0.254: v7(31.41,23.6) 30.88,23.07 30.88,19.64 v3(31.03,19.49)
  IN4 w0.254: v4(16.16,19.8) 16.17,19.78 18.09,19.78 20.08,21.78 21.16,21.78 21.66,21.27 22.83,21.27 23.01,21.45 28.45,21.45 v1(29.96,19.94) 30.41,19.49 v3(31.03,19.49)
  BOTTOM w0.109: v2(30.22,20.76) 29.96,20.5 v1(29.96,19.94)
  BOTTOM w0.254: v4(16.16,19.8) 16.46,19.8 16.72,20.06 Q6.3 17.74,20.45 18.08,20.79 RA57.1
HDA_RST_DSP#: length 26.4
  TOP w0.109: RA62.2 46.13,15.83 44.48,17.48 43.92,17.48 41.56,19.85 36.68,19.85 36.58,19.95 v2(36.21,19.95) 35.85,19.95 v1(35.67,20.13) 35.38,20.13 35.13,20.37 35.13,20.99 34.39,21.74 33.04,21.74 32.77,22 32.77,23.22 32.39,23.6 RA54.1 ; v1(38.91,16.05) UA1.18
  IN3 w0.102: v1(35.67,20.13) 35.92,19.87 35.92,19.19 36.59,18.52 36.59,17.86 37.92,16.54 38.42,16.54 v1(38.91,16.05)
HDA_SDIN0: length 137.5
  TOP w0.109: v7(156.7,39.58) 156.75,39.58 157.54,38.79 157.54,36.79 152.71,31.96 100.34,31.96 97.98,29.6 v7(97.82,29.6)
  IN1 w0.076: v7(45.21,12.73) 45.79,13.32 45.79,13.94 46.44,14.59 49.49,14.59 50.15,13.93 52.44,13.93 53.74,12.63 63.92,12.63 64.42,12.13 64.72,11.83 75.46,11.83 76.17,11.12 89.67,11.12 95.98,17.43 95.98,20.13 95.09,21.01 95.09,27.01 97.54,29.45 97.68,29.45 v7(97.82,29.6) ; v3(157.12,39.45) 156.7,39.45 v7(156.7,39.58)
  IN4 w0.076: v4(157.75,39.51) 157.7,39.45 v3(157.12,39.45)
  BOTTOM w0.109: v4(157.75,39.51) 157.84,39.59 UCPU1.AY10
HDA_SDIN0_AUDIO: length 4.7
  TOP w0.109: RA60.1 45.57,12.25 44.77,12.25 RA1.2 44.02,12.73 43.13,11.84 UA1.8
HDA_SDIN0_DSP: length 29.4
  TOP w0.109: UA1.21 37.41,14.9 36.91,15.4 36.91,15.67 v1(36.82,15.76)
  IN1 w0.076: v7(46.97,12.73) 46.51,12.73 46.13,12.35 44.12,12.35 43.63,11.86 42.91,11.86 41.95,12.82 v3(41.66,12.82)
  IN3 w0.102: v1(36.82,15.76) 37.05,15.53 40.05,15.53 40.65,14.93 40.65,14.05 41.66,13.03 v3(41.66,12.82)
  BOTTOM w0.109: RA36.1 32.91,25.64 33.22,25.33 v2(34.33,25.33) 36.64,25.33 38.37,23.6 38.37,17.68 36.82,16.14 v1(36.82,15.76)
HDA_SDIN0_R: length 3.1
  TOP w0.203: UA2.8 29.93,24.9
  TOP w0.254: 29.93,24.9 30.42,24.9 v1(30.57,25.05)
  BOTTOM w0.109: v1(30.57,25.05) v2(30.03,25.05)
  BOTTOM w0.254: v1(30.57,25.05) 30.75,25.05 31.34,25.64 RA36.2
HDA_SDO: length 68.5
  IN3 w0.102: v1(205.25,42.78) 205.3,42.78 205.64,43.12 205.64,48 207.92,50.27 207.92,51.18 206.57,52.53 206.57,53.3 207.74,54.47 207.74,55.74 207,56.47 v1(207,56.7)
  BOTTOM w0.076: U34.C1 207.86,56.08 207.59,56.35 207.49,56.35 207.13,56.7 v1(207,56.7)
  BOTTOM w0.109: v1(205.25,42.78) 205.02,42.78 203.8,41.56 203.8,38.44 204.18,38.06 204.18,35.24 203.47,34.53 194.66,34.53 194.14,34.01 194.14,33.17 192.46,31.48 190.98,31.48 189.72,30.22 177.96,30.22 177.61,30.57 167.66,30.57 R1341.1 165.97,32.26 Q351.2
HDA_SDOUT: length 16.2
  BOTTOM w0.102: UCPU1.AU11 157.42,41.84 157.42,41.44 157.55,41.31 157.55,40.62 157.45,40.52 157.37,40.44 157.37,39.99 157.17,39.78 157.17,39.66
  BOTTOM w0.109: MC103.1 156.52,35.05 ; 156.52,35.05 157.48,35.05 RP3.5 157.61,35.94 RH42.2 157.5,36.3 157.5,38.72 157.17,39.05 157.17,39.66 ; 156.52,35.05 157.04,34.53 157.04,32.65 158.08,31.61 v2(158.39,31.61) RH24.2
HDA_SDOUT_AUDIO: length 137.1
  TOP w0.109: v1(157.54,32.75) 156.51,31.73 100.44,31.73 97.96,29.24 97.47,29.24 v2(96.9,28.68) 96.77,28.55 96.77,28.11 v7(97.14,27.75) ; v7(43.12,10.44) 43.03,10.34 UA1.5
  IN1 w0.076: v7(97.14,27.75) 96.77,27.75 95.7,26.68 95.7,21.27 96.59,20.38 96.59,17.18 89.92,10.51 75.92,10.51 75.21,11.22 64.46,11.22 64.17,11.52 63.66,12.02 53.49,12.02 52.22,13.29 49.4,13.29 v7(48.89,13.8) 47.9,13.8 47.48,13.38 47.48,12.4 47.1,12.02 44.25,12.02 43.12,10.89 v7(43.12,10.44)
  BOTTOM w0.109: RP3.4 157.61,32.82 v1(157.54,32.75)
HDA_SDOUT_AUDIO_R: length 3.5
  TOP w0.203: UA2.4 29.85,23.3 30.52,22.63 v2(30.52,22.17) 30.52,21.76 RA52.2
HDA_SDOUT_DSP: length 28.9
  TOP w0.109: v7(48.42,15.27) 48.89,14.8 RA59.2 ; v7(41.33,19.48) 41.24,19.57 35.49,19.57 34.9,20.16 34.9,20.89 34.29,21.5 33.7,21.5 v7(33.14,20.94) RA52.1 ; v7(33.71,16.04) 34.04,15.71 v2(35.13,15.71) 35.25,15.71 35.91,15.04 UA1.24
  IN1 w0.076: v7(33.14,20.94) 33.98,20.1 33.98,16.3 v7(33.71,16.04) ; v7(48.42,15.27) 48.09,14.94 47.02,14.94 44.66,17.31 43.99,17.31 41.82,19.48 v7(41.33,19.48)
HDA_SPKR: length 261.9
  TOP w0.109: RA31.1 v2(34.94,19.16) 35.13,19.16 35.27,19.02 37.73,19.02 37.89,19.18 39.68,19.18 v7(39.81,19.05)
  IN1 w0.076: v7(39.81,19.05) 39.81,18.04 41.18,16.67 41.18,15.72 40.89,15.43 40.89,10.41 44.54,6.76 47.9,6.76 49.37,8.24 49.37,9.81 50.51,10.96 51.18,10.96 51.98,10.15 51.98,9.88 52.4,9.46 56.65,9.46 57.63,8.48 58.38,8.48 59.54,9.65 73.63,9.65 73.77,9.79 74.88,9.79 75.4,9.27 91.86,9.27 94.39,11.79 100.69,11.79 102.19,10.3 103.65,10.3 105.53,8.42 108.3,8.42 108.58,8.7 109.37,8.7 110.81,7.25 124.31,7.25 125,6.56 137.13,6.56 139.62,9.05 153.1,9.05 155.85,6.3 179.92,6.3 180.69,7.07 190.19,7.07 195.33,12.21 195.33,12.72 196.44,13.82 196.44,19.79 195.73,20.51 195.73,22.21 196.01,22.49 196.26,22.49 196.44,22.67 196.44,25.89 195.19,27.14 195.19,28.23 192.97,30.45 192.97,31.76 192,32.74 191.77,32.74 190.59,33.92 189.68,33.92 189.22,34.37 189.22,35.06 187.9,36.38 179.19,36.38 176.19,39.38 176.19,39.62 175.85,39.96 175.85,42.38 174.71,43.53 174.71,44.67 173.87,45.51 166.68,45.51 166.15,46.05 165.82,46.05 165.11,46.76 164.22,46.76 163.87,47.1 163.29,47.1 162.88,47.51 161.55,47.51 161.07,47.99 161.07,48.31 160.42,48.95 159.33,48.95 158.95,49.34 158.57,49.34 158.29,49.61 v3(158.29,50.12)
  IN4 w0.076: v3(158.29,50.12) 158.41,50.25 158.95,50.25 159.35,50.66 159.35,50.81 159.61,51.06 160.5,51.06 160.9,51.47 161.36,51.47 161.77,51.88 161.77,52.05 v4(161.84,52.13)
  BOTTOM w0.109: RH37.2 166.18,51.35 166.18,51.72 165.85,52.05 164.41,52.05 164.26,52.21 163.2,52.21 UCPU1.V2 162.36,52.15 161.86,52.15 v4(161.84,52.13)
HDA_SYNC: length 10.6
  BOTTOM w0.102: UCPU1.AV11 156.76,41.85 156.76,42.32 156.91,42.48 157.85,42.48 158.13,42.2 158.13,40.64 158.01,40.52 157.75,40.52 157.55,40.32 157.55,39.91 157.52,39.89 157.52,39.88 157.39,39.74 157.39,39.61
  BOTTOM w0.109: RP3.6 158.11,35.21 157.85,35.47 v2(157.85,38.43) 157.85,38.63 157.39,39.09 157.39,39.61
HDA_SYNC_AUDIO: length 135.1
  TOP w0.109: v7(97.14,28.23) 97.28,28.37 97.28,28.62 97.64,28.99 98.23,28.99 v2(99.76,30.52) 100.73,31.49 156.86,31.49 v1(158.12,32.75) ; v7(47.05,13.8) 46.46,13.22 43.21,13.22 42.84,12.84 UA1.10
  IN1 w0.076: v7(97.14,28.23) 96.92,28.23 95.5,26.81 95.5,21.18 96.39,20.29 96.39,17.27 89.84,10.71 76,10.71 75.29,11.43 64.55,11.43 64.25,11.72 63.75,12.23 53.57,12.23 52.3,13.5 49.74,13.5 49.12,14.12 47.36,14.12 v7(47.05,13.8)
  BOTTOM w0.109: v1(158.12,32.75) 158.11,32.76 RP3.3
HDA_SYNC_AUDIO_R: length 2.8
  TOP w0.203: UA2.9 29.9,25.3
  TOP w0.254: 29.9,25.3 30.05,25.3 30.38,25.64 v1(30.57,25.64)
  BOTTOM w0.254: v1(30.57,25.64) 30.6,25.66 30.6,25.7 31.43,26.53 RA53.2
HDA_SYNC_DSP: length 34.5
  TOP w0.109: v7(37.84,20.29) 41.45,20.29 44.02,17.72 44.58,17.72 47.05,15.25 RA61.2 ; v1(38.28,16.05) 38.41,15.92 UA1.19
  IN1 w0.076: v1(38.28,16.05) 38.28,16.79 38.7,17.2 38.7,19.22 37.84,20.09 v7(37.84,20.29)
  BOTTOM w0.109: v1(38.28,16.05) 38.19,16.14 38.19,17.15 38.6,17.56 38.6,23.7 v2(35.45,26.85) 34.89,27.41 CA50.2 32.53,26.54 RA53.1
HDMI_CEC: length 4.5
  TOP w0.109: CV796.2 13.37,25.99 v1(12.93,25.56)
  IN1 w0.076: v1(12.93,25.56) 11.77,25.56 10.31,24.1 JHDMI.13
HDMI_CFG: length 5.2
  TOP w0.109: v5(24.19,36.9) 24.19,36.6 25.38,35.4 RV26.1 v7(25.38,34.15)
  IN1 w0.076: v3(24.86,34.25) 24.96,34.15 v7(25.38,34.15)
  IN4 w0.076: v4(24.86,34.72) v3(24.86,34.25)
  BOTTOM w0.109: v4(24.86,34.72) 24.95,34.81 U722.23
HDMI_CK_N: length 13.4
  TOP w0.109: v7(18.36,27.12) 18.36,27.22 18.27,27.3 18.08,27.3 17.77,26.99 L67.2
  IN1 w0.076: v7(18.36,27.12) 18.58,27.35 18.62,27.35 18.89,27.62 18.89,28.11 19.77,28.99 19.77,29.21 21.6,31.03 23.83,31.03 24.28,31.48 24.28,31.63 v1(24.48,31.84)
  BOTTOM w0.109: v1(24.48,31.84) 24.12,32.2 24.12,32.53 24.67,33.08 24.67,33.86 25,34.18 25.09,34.18 25.27,34.01 U722.21
HDMI_CK_N_R: length 18.4
  TOP w0.109: JHDMI.12 8.93,25.1 9.04,25.1 9.16,24.99 9.16,20.67 9.54,20.28 10.49,20.28 11.32,21.12 v6(11.32,22.33) 11.32,25.25 12.2,26.13 12.2,27.23 12.29,27.32 12.45,27.32 12.59,27.18 DV4.9 13.19,27.18 13.33,27.32 13.47,27.32 13.6,27.18 DV4.1 14.17,27.18 14.31,27.31 15.09,27.31 15.42,26.99 L67.1
HDMI_CK_P: length 13.3
  TOP w0.109: v7(18.36,27.71) 18.17,27.52 18.08,27.52 17.77,27.84 L67.3
  IN1 w0.076: v7(18.36,27.71) 18.36,27.62 18.47,27.5 18.56,27.5 18.74,27.68 18.74,28.18 19.61,29.05 19.61,29.27 21.53,31.19 23.77,31.19 24.12,31.54 24.12,31.61 v1(23.9,31.84)
  BOTTOM w0.109: v1(23.9,31.84) 23.9,32.62 24.45,33.17 24.45,33.95 24.9,34.41 U722.22
HDMI_CK_P_R: length 18.3
  TOP w0.109: JHDMI.10 8.71,25.32 9.14,25.32 9.2,25.26 9.38,25.08 9.38,20.76 9.63,20.51 10.39,20.51 11.1,21.21 11.1,22.07 11.09,22.08 11.09,22.59 11.1,22.6 11.1,25.36 v6(11.7,25.96) 11.97,26.24 11.97,27.32 12.19,27.54 12.45,27.54 12.59,27.68 DV4.8 13.17,27.68 13.31,27.54 13.46,27.54 13.6,27.68 DV4.2 14.17,27.68 14.31,27.54 15.06,27.54 15.37,27.84 L67.4
HDMI_CLK: length 33.3
  TOP w0.109: RV28.2 26.55,39.12 v1(26.57,39.1)
  IN1 w0.076: JHDMI.15 9.29,23.79 9.29,30.29 9.9,30.89 12.55,30.89 13.82,32.16 13.82,34.82 19.78,40.78 23.45,40.78 25.13,39.1 v1(26.57,39.1)
  BOTTOM w0.109: U722.32 26.79,38.88 v1(26.57,39.1)
HDMI_D0_N: length 22.8
  TOP w0.109: v7(18.48,28.79) 18.32,28.95 18.08,28.95 17.77,28.64 L66.2
  IN1 w0.076: v1(24.38,37.94) 24.17,38.15 23.86,38.15 22.6,39.4 19.94,39.4 17.09,36.55 17.09,29.78 17.21,29.65 17.54,29.65 17.67,29.78 17.67,29.93 17.81,30.07 18.83,30.07 19.04,29.85 19.04,29.22 18.83,29 18.7,29 v7(18.48,28.79)
  BOTTOM w0.109: U722.29 25.22,37.21 24.8,37.62 24.8,37.96 24.64,38.12 24.56,38.12 v1(24.38,37.94)
HDMI_D0_N_R: length 8.9
  TOP w0.109: JHDMI.9 10.46,26.58 11.18,26.58 11.47,26.87 v6(11.47,27.22) 11.47,27.45 10.9,28.02 10.9,28.29 11.02,28.41 11.63,28.41 12.02,28.8 12.48,28.8 12.6,28.68 DV4.7 13.15,28.68 13.29,28.82 13.46,28.82 13.6,28.68 DV4.4 14.14,28.68 14.28,28.82 14.53,28.82 14.65,28.94 15.14,28.94 15.45,28.64 L66.1
HDMI_D0_P: length 22.8
  TOP w0.109: v7(18.48,29.37) 18.48,29.36 18.3,29.18 18.11,29.18 17.79,29.49 L66.3
  IN1 w0.076: v7(18.48,29.37) 18.7,29.15 18.76,29.15 18.89,29.28 18.89,29.79 18.76,29.92 17.87,29.92 17.82,29.87 17.82,29.71 17.61,29.5 17.15,29.5 16.94,29.71 16.94,36.61 19.88,39.56 22.66,39.56 23.92,38.3 24.15,38.3 v1(24.38,38.53)
  BOTTOM w0.109: U722.30 25.13,37.61 25.03,37.71 25.03,38.05 24.73,38.34 24.56,38.34 v1(24.38,38.53)
HDMI_D0_P_R: length 8.9
  TOP w0.109: JHDMI.7 10.28,26.8 11.09,26.8 11.24,26.95 11.24,27.37 10.68,27.93 10.68,28.39 10.93,28.64 v6(11.23,28.64) 11.54,28.64 11.93,29.03 12.5,29.03 12.65,29.18 DV4.6 13.15,29.18 13.29,29.04 13.47,29.04 13.6,29.18 DV4.5 14.14,29.18 14.28,29.04 14.43,29.04 14.56,29.17 15.14,29.17 15.47,29.49 L66.4
HDMI_D1_N: length 19.8
  TOP w0.109: L65.2 17.48,32.07 17.83,32.42 18.05,32.42 v7(18.19,32.28)
  IN1 w0.076: v1(23.15,37.54) 22.92,37.77 22.68,37.77 22.49,37.96 22.49,38.59 22.33,38.74 21.13,38.74 20.87,38.49 20.64,38.49 20.42,38.71 20.32,38.71 20.15,38.55 20.15,38.44 20.37,38.22 20.37,37.99 20.12,37.74 19.89,37.74 19.67,37.95 19.56,37.95 19.4,37.79 19.4,37.68 19.62,37.47 19.62,37.23 19.36,36.98 19.13,36.98 18.91,37.2 18.81,37.2 18.64,37.04 18.64,36.93 18.86,36.71 18.86,36.48 18.51,36.13 18.51,35.44 18.34,35.27 17.9,35.27 17.8,35.17 17.8,34.99 17.9,34.89 18.34,34.89 18.54,34.7 18.54,34.32 18.34,34.13 18.11,34.13 18.01,34.04 18.01,33.9 18.11,33.8 18.34,33.8 18.51,33.64 18.51,33.35 18.76,33.09 18.76,32.69 18.58,32.5 18.42,32.5 v7(18.19,32.28)
  BOTTOM w0.109: v1(23.15,37.54) 23.31,37.7 23.52,37.7 23.93,37.29 23.93,36.85 24.65,36.12 24.92,36.12 25.03,36.01 U722.26
HDMI_D1_N_R: length 10.8
  TOP w0.109: L65.1 15.21,32.07 14.91,32.37 14.31,32.37 14.17,32.23 DV5.8 13.66,32.23 13.52,32.37 13.28,32.37 13.14,32.23 DV5.2 12.64,32.23 12.48,32.39 12.15,32.39 v6(11.87,32.12) 11.49,31.74 10.73,31.74 10.34,31.35 10.34,31.34 9.98,30.97 9.97,30.97 9.35,30.36 9.35,28.25 9.12,28.02 8.85,28.02 JHDMI.6
HDMI_D1_P: length 19.8
  TOP w0.109: L65.3 17.53,32.92 17.8,32.65 17.98,32.65 v7(18.19,32.86)
  IN1 w0.076: v7(18.19,32.86) 18.4,32.65 18.52,32.65 18.61,32.75 18.61,33.03 18.36,33.28 18.36,33.57 18.28,33.65 18.05,33.65 17.86,33.84 17.86,34.1 18.05,34.29 18.28,34.29 18.38,34.39 18.38,34.64 18.28,34.74 17.84,34.74 17.65,34.93 17.65,35.23 17.84,35.42 18.28,35.42 18.36,35.5 18.36,36.19 18.71,36.54 18.71,36.65 18.49,36.87 18.49,37.1 18.74,37.35 18.98,37.35 19.19,37.13 19.3,37.13 19.46,37.3 19.46,37.4 19.25,37.62 19.25,37.85 19.5,38.11 19.73,38.11 19.95,37.89 20.06,37.89 20.22,38.05 20.22,38.16 20,38.38 20,38.61 20.25,38.86 20.49,38.86 20.7,38.64 20.81,38.64 21.06,38.9 22.4,38.9 22.64,38.65 22.64,38.02 22.74,37.92 22.94,37.92 v1(23.15,38.12)
  BOTTOM w0.109: v1(23.15,38.12) 23.35,37.93 23.61,37.93 24.15,37.38 24.15,36.94 24.75,36.34 24.96,36.34 25.03,36.41 U722.27
HDMI_D1_P_R: length 10.7
  TOP w0.109: JHDMI.4 8.78,28.25 9.03,28.25 9.12,28.34 9.12,30.45 v6(10,31.32) 10.64,31.96 11.39,31.96 12.04,32.62 12.5,32.62 12.62,32.73 DV5.1 13.14,32.73 13.27,32.6 13.51,32.6 13.65,32.73 DV5.9 14.17,32.73 14.31,32.6 14.88,32.6 15.2,32.92 L65.4
HDMI_D2_N: length 19.7
  TOP w0.109: L64.2 18.02,30.42 18.34,30.73 19.06,30.73 v7(19.24,30.55)
  IN1 w0.076: v1(21.85,37.42) 21.65,37.63 20.92,37.63 19.14,35.85 19.14,33.92 19.75,33.31 19.75,32.84 19.36,32.44 19.36,32.26 19.63,31.99 19.81,31.99 20.41,32.59 20.71,32.59 21.08,32.22 21.08,31.92 19.91,30.74 19.44,30.74 v7(19.24,30.55)
  BOTTOM w0.109: U722.24 25.03,35.21 24.94,35.29 24.38,35.29 22.41,37.26 22.41,37.47 22.31,37.57 22,37.57 v1(21.85,37.42)
HDMI_D2_N_R: length 10.7
  TOP w0.109: JHDMI.3 10.41,29.53 11.56,29.53 11.58,29.52 12.29,29.52 12.58,29.8 12.58,30.25 12.34,30.49 11.02,30.49 10.89,30.62 10.89,30.87 11.02,31 v6(11.26,31) 12.1,31 12.23,30.87 12.49,30.87 12.63,30.73 DV5.5 13.15,30.73 13.29,30.87 13.47,30.87 13.6,30.73 DV5.6 14.11,30.73 14.26,30.87 14.53,30.87 14.68,30.72 14.95,30.72 15.25,30.42 L64.1
HDMI_D2_P: length 19.7
  TOP w0.109: v7(19.24,31.14) 19.06,30.96 18.34,30.96 18.02,31.27 L64.3
  IN1 w0.076: v7(19.24,31.14) 19.49,30.89 19.84,30.89 20.93,31.98 20.93,32.16 20.65,32.44 20.47,32.44 19.87,31.84 19.56,31.84 19.2,32.2 19.2,32.5 19.6,32.9 19.6,33.24 18.99,33.85 18.99,35.91 20.86,37.78 21.62,37.78 v1(21.85,38.01)
  BOTTOM w0.109: U722.25 25.03,35.61 24.94,35.52 24.47,35.52 22.64,37.35 22.64,37.56 22.4,37.8 22.06,37.8 v1(21.85,38.01)
HDMI_D2_P_R: length 10.7
  TOP w0.109: L64.4 15.28,31.27 14.95,30.95 14.78,30.95 14.62,31.1 14.22,31.1 14.08,31.23 DV5.7 13.6,31.23 13.46,31.09 13.29,31.09 13.16,31.23 DV5.4 12.64,31.23 12.5,31.09 12.33,31.09 12.2,31.22 11.56,31.22 11.55,31.24 10.94,31.24 10.67,30.97 10.67,30.52 10.93,30.26 12.25,30.26 12.36,30.15 12.36,29.9 12.21,29.75 v6(11.87,29.75) 10.33,29.75 JHDMI.1
HDMI_DAT: length 39.8
  TOP w0.109: RV29.2 27.29,39.9 v1(27.29,39.45)
  IN1 w0.076: JHDMI.16 7.82,21.99 7.82,21.32 9.39,19.74 10.61,19.74 14.29,23.43 14.29,34.64 19.97,40.32 23.26,40.32 24.94,38.64 26.76,38.64 27.29,39.16 v1(27.29,39.45)
  BOTTOM w0.109: v1(27.29,39.45) 27.2,39.36 U722.33
HDMI_DCIN_EN: length 2.9
  TOP w0.109: RV17.1 28.43,33.89 v2(27.9,33.89)
  IN1 w0.076: v7(28.82,33.49) 28.85,33.51 v3(28.85,32.83)
  IN4 w0.076: v3(28.85,32.83) 28.95,32.83 v4(29.18,32.6)
  BOTTOM w0.109: v4(29.18,32.6) 29.2,32.61 U722.13
HDMI_DDCBUF: length 3.6
  TOP w0.109: v2(29.77,31.56) RV16.1 28.77,32.05 v1(28.89,32.16)
  BOTTOM w0.109: U722.14 28.79,32.85 28.68,32.73 28.68,32.37 v1(28.89,32.16) 28.77,32.05 RV16.1
HDMI_EQ: length 3.7
  TOP w0.109: v1(27.13,32.16) 26.99,32.03 RV18.1 26.27,31.56 v2(26.07,31.35)
  BOTTOM w0.109: RV18.1 26.99,32.03 v1(27.13,32.16) 27.6,32.63 U722.17
HDMI_HPD: length 34.5
  TOP w0.109: v1(24.73,37.04) 24.96,36.81 RV30.2 25.38,37.73 v2(25.71,38.06) ; CV768.2 v1(12.67,24.21)
  IN1 w0.076: v1(12.67,24.21) 12.67,23.12 10.64,21.1 9.98,21.1 JHDMI.19
  IN3 w0.102: v1(24.73,37.04) 24.52,37.04 23.73,37.83 23.73,38.46 22.37,39.82 19.49,39.82 14.04,34.37 14.04,24.82 13.43,24.21 v1(12.67,24.21)
  BOTTOM w0.109: v1(24.73,37.04) 24.96,36.81 U722.28
HDMI_I2C_CTL_EN: length 2.9
  TOP w0.109: v2(31.67,34.34) 31.4,34.6 v7(31.4,34.81) 31.32,34.73 RV19.1
  IN1 w0.076: v7(31.4,34.81) 31.4,35.2 v3(31.39,35.21)
  IN4 w0.076: v4(31.41,34.81) 31.41,35.19 v3(31.39,35.21)
  BOTTOM w0.109: U722.8 v4(31.41,34.81)
HDMI_PRE: length 3.2
  TOP w0.109: v2(27.44,32.6) 27.72,32.32 v1(27.72,32.16) 27.88,32 RV21.1
  BOTTOM w0.109: RV21.1 27.88,32 v1(27.72,32.16) 28,32.44 U722.16
HDMI_RESERVED: length 12
  TOP w0.109: v2(12.19,24.4) v1(12.67,24.87) 12.9,25.1 CV795.2
  IN1 w0.076: JHDMI.14 8.71,23.6 9.41,22.9 9.41,20.86 9.74,20.53 9.82,20.46 10.59,20.46 13.07,22.94 13.07,24.47 v1(12.67,24.87)
HDMI_REXT: length 2.2
  BOTTOM w0.109: RV31.2 26.1,31.73 27.2,32.82 U722.18
HP2_D_L: length 19.1
  TOP w0.203: v1(22.12,26.2) 22.21,26.1 UA2.26
  IN1 w0.254: v1(15.94,13.25) 15.94,16.87 17.44,18.37 17.44,19.17 18.94,20.67 18.94,24.57 20.57,26.2 v1(22.12,26.2)
  BOTTOM w0.109: v2(21.66,26.65) v1(22.12,26.2)
  BOTTOM w0.254: RA15.1 v1(15.94,13.25)
HP2_D_L_C: length 13
  IN4 w0.508: v1(15.42,7.08) 15.42,6.56 14.43,5.57 13.83,5.57 12.21,3.95 JHP1.1
  BOTTOM w0.109: v1(15.42,7.08) v2(15.42,6.29)
  BOTTOM w0.508: RA3.2 15.17,9.7 16.48,8.39 DA2.3 16.34,8 v1(15.42,7.08)
HP2_D_L_R1: length 14.3
  IN1 w0.254: v3(18.43,17.66) 18.09,17.32 v7(18.09,17.12)
  IN3 w0.508: v3(18.43,17.66) 13.63,17.66 13.2,17.23 v1(12.48,17.23)
  BOTTOM w0.508: RA3.1 CA29.1 14.29,12.51 14.28,12.52 RA15.2 14.28,14.19 RA49.2 14.4,14.33 14.4,15.07 RA51.2 14.13,15.08 13.53,15.68 RA43.2 12.57,16.29 v2(12.31,16.54) 12.31,17.06 v1(12.48,17.23)
HP2_D_R: length 14.4
  TOP w0.203: v1(21.4,25.28) 21.4,25.34 21.8,25.74 22.46,25.74 22.5,25.7 UA2.27
  IN1 w0.254: v7(14.37,18.33) 14.17,18.54 v3(14.17,18.87)
  IN3 w0.254: v3(14.17,18.87) 14.71,19.41 15.08,19.41 16.1,20.43 18.08,20.43 18.94,21.29 18.94,24.19 20.03,25.28 v1(21.4,25.28)
HP2_D_R_C: length 11.8
  TOP w0.508: 14.03,15.65 RA4.2 15.04,14.38 DA1.2
  TOP w1.016: JHP1.2 6.98,14.18 7.78,14.18 8.93,15.34 v2(10.06,15.34) 13.71,15.34
HP2_D_R_R2: length 16.9
  TOP w0.254: RA4.1 14.87,16.39 v2(13.93,16.39) 13.44,16.87 CA28.1 RA17.2 RA50.2 RA48.2 13.28,20.11 12.93,19.77 12.93,18.72 v1(12.82,18.6) ; v1(17.28,16.51) 17.28,16.86 17.07,17.06 RA22.1
  IN3 w0.254: v1(17.28,16.51) 17.28,16.63 16.77,17.14 14.66,17.14 14.06,16.54 12.39,16.54 11.91,17.03 11.91,17.94 12.57,18.6 v1(12.82,18.6)
  BOTTOM w0.254: v1(12.82,18.6) 13.02,18.6 RA45.2
HP_PLUG#: length 22.1
  TOP w0.109: QA6.6 17.86,5.16 v1(17.86,4.57)
  IN1 w0.076: v3(18.64,18.6) 18.64,18.6 19.14,18.09 19.14,17.13 18.14,16.12 18.14,14.63 17.81,14.31 17.81,12.35 20.8,9.36 20.8,4.63 20.24,4.07 18.36,4.07 v1(17.86,4.57)
  IN4 w0.076: v4(18.1,18.6) v3(18.64,18.6)
  BOTTOM w0.109: v1(17.86,4.57) 17.86,4.76 v2(18.29,5.19)
HUB_OSC_IN: length 5.3
  TOP w0.109: Y2.1 248.6,67.4 C1204.1 247.96,65.48 247.96,64.92 247.84,64.8 U636.D8
HUB_OSC_OUT: length 6
  TOP w0.076: U636.D7 247.59,63.58 247.59,64.01
  TOP w0.109: 247.59,64.01 v2(247.59,65.07) 247.59,65.97 C1205.1 247.74,66.53 Y2.2
HWPG: length 65.2
  TOP w0.109: R982.1 R930.2 R1133.1 R934.1 ; R982.1 208.97,57.53 209.42,57.08 v1(209.42,56.88) ; R982.1 208.08,58.2 R931.1 ; v7(176.14,38.78) v2(177.03,38.78) 178.62,37.19 179.41,37.19 R1296.1 180.88,35.72 180.88,34.61 181.18,34.31 181.18,33.26 181.44,33 U690.2
  IN1 w0.076: v7(176.14,38.78) 175.71,39.21 v3(175.71,39.42)
  IN4 w0.076: v1(209.42,56.88) 209.49,56.8 209.49,56.29 208.93,55.74 205.35,55.74 203.62,54 203.62,53.61 203.57,53.57 202.89,52.88 202.89,51.75 202.96,51.67 202.96,51.25 202.25,50.54 202.25,49.17 200.74,47.65 199.62,47.65 197.82,45.86 182.83,45.86 182.1,46.58 178.11,46.58 177.38,45.86 177.03,45.86 176.41,45.23 175.28,45.23 174.76,44.71 174.76,40.37 v3(175.71,39.42)
  BOTTOM w0.076: U34.F1 209.36,56.82 v1(209.42,56.88)
I2C0_SCK: length 66.2
  TOP w0.102: v1(164.1,61.7) 164.27,61.87 164.27,63.41 165.12,64.26 165.12,65.49
  TOP w0.109: 165.12,65.49 165.12,65.74 R1224.1 RA8.2 ; Q352.1 202.39,51.53 202.01,51.91 202.01,52.28 201.98,52.32 201.98,52.34 201.86,52.46 201.86,53.43 202.34,53.92 202.34,57.44 201.38,58.4 200.6,58.4 200.29,58.72 199.97,58.72 199.74,58.95 v1(199.74,58.94)
  IN3 w0.102: v1(164.1,61.7) 164.51,62.11 165.95,62.11 169.84,58.23 177.95,58.23 178.05,58.12 181.96,58.12 182.34,57.74 183.91,57.74 185.01,56.65 187.93,56.65 189.08,55.49 189.53,55.49 190.31,54.72 193.73,54.72 194.62,55.61 196.01,55.61 198.82,58.43 198.82,58.66 199.15,58.99 199.69,58.99 v1(199.74,58.94)
  BOTTOM w0.102: RH462.1 RH425.1 165.12,65.86 165.12,64.35 164.15,63.38 164.15,61.76 v1(164.1,61.7) 164.15,61.65 164.15,60.46 163.62,59.93 163.14,59.93 162.84,59.62 162.48,59.62 UCPU1.F3
I2C0_SCK_DSP: length 188.5
  TOP w0.109: v1(33.11,13.01) 33.22,13.11 34.3,13.11 34.52,13.34 UA1.26 ; v1(68.19,6.63) 68.01,6.8 68.01,11.62 67,12.63 67,13.55 v1(67.1,13.65) ; v7(164.26,66.51) 164.26,66.54 163.81,66.99 RA8.1
  IN1 w0.076: v3(163.97,65.78) 164.27,66.08 164.27,66.49 v7(164.26,66.51)
  IN3 w0.102: v1(67.1,13.65) 67.58,13.17 73.86,13.17 75.91,11.11 89.3,11.11 93.08,14.89 97.79,19.6 97.79,29.51 105.96,37.68 105.96,43.49 109.7,47.23 111.75,47.23 112.72,48.19 112.72,55.56 115.87,58.71 117.32,58.71 119.32,60.71 119.32,64.07 120.19,64.93 126.51,64.93 127.5,65.92 128.12,65.92 128.6,66.4 140.07,66.4 141.37,65.11 159.72,65.11 160.66,66.05 163.49,66.05 163.76,65.78 v3(163.97,65.78)
  IN4 w0.076: v1(33.11,13.01) 33.01,12.91 33.01,11.96 37.49,7.48 38.78,7.48 40.93,5.33 42.89,5.33 43.19,5.04 49.5,5.04 50.43,5.96 67.53,5.96 v1(68.19,6.63)
I2C0_SCK_SNR: length 112
  TOP w0.076: U636.G3 249.44,61.34 249.69,61.09 251.04,61.09 v7(251.09,61.04)
  TOP w0.109: R1224.2 164.59,67.19 v1(164.59,68.35) ; JSNRDG.18 253.95,67.16 v7(253.96,67.17)
  IN1 w0.076: v3(237.31,64.05) 237.31,64.45 237.66,64.8 243.49,64.8 243.69,65.01 247.39,65.01 247.54,64.85 248.78,64.85 249.59,65.67 250.06,65.67 251.48,67.09 253.26,67.09 253.33,67.17 v7(253.96,67.17) 253.96,67.01 252.62,65.67 252.62,63.66 253.03,63.25 253.03,62.16 251.91,61.04 v7(251.09,61.04)
  IN3 w0.102: v3(237.31,64.05) 235.74,65.62 225.38,65.62 223.34,63.57 223.34,63.36 222.52,62.54 221.54,62.54 220.89,63.19 216.74,63.19 214.19,65.74 214.19,66.15 214.45,66.4 214.45,67.17 211.91,69.7 200.46,69.7 198.08,67.32 195.57,67.32 193.11,69.78 165.96,69.78 164.59,68.41 v1(164.59,68.35)
I2C0_SDA: length 62.6
  TOP w0.102: R1225.1 165.42,65.82 165.42,64.13 164.57,63.28 164.57,61.82 v1(164.69,61.7)
  TOP w0.109: Q352.4 201.33,53.25 201.54,53.46 201.54,53.56 202.03,54.05 202.03,57.31 201.25,58.09 200.47,58.09 200.18,58.38 199.47,58.38 v1(199.35,58.5) ; R1225.1 RA7.2
  IN3 w0.102: v1(199.35,58.5) 199.33,58.5 196.13,55.3 194.74,55.3 193.85,54.42 190.18,54.42 189.4,55.19 188.96,55.19 187.8,56.35 184.88,56.35 183.79,57.44 182.21,57.44 181.83,57.82 177.92,57.82 177.82,57.92 169.71,57.92 165.83,61.81 164.79,61.81 v1(164.69,61.7)
  BOTTOM w0.102: RH461.1 RH424.1 165.6,65.86 165.6,64.15 164.64,63.18 164.64,61.76 v1(164.69,61.7) 164.64,61.65 164.64,60.54 163.8,59.7 163.24,59.7 162.88,59.34 UCPU1.F2
I2C0_SDA_DSP: length 190.2
  TOP w0.109: v1(33.41,12.51) 34.34,12.51 34.68,12.84 UA1.27 ; v1(67.6,6.61) 67.7,6.71 67.7,11.47 66.67,12.5 66.67,13.5 v1(66.52,13.65)
  IN1 w0.076: v7(166.57,66.99) 166.44,66.86 165.98,66.86 v3(164.59,65.46)
  IN3 w0.102: v1(66.52,13.65) 67,13.17 67.15,13.17 67.46,12.86 73.73,12.86 75.79,10.8 89.43,10.8 98.1,19.47 98.1,29.38 106.27,37.55 106.27,43.34 109.85,46.92 113.1,46.92 114.47,48.29 114.47,56.63 116.25,58.4 117.44,58.4 119.81,60.77 119.81,64.12 120.31,64.63 126.64,64.63 127.63,65.62 128.25,65.62 128.73,66.1 139.95,66.1 141.24,64.8 159.85,64.8 160.79,65.74 161.99,65.74 163.04,64.7 164.23,64.7 164.59,65.06 v3(164.59,65.46)
  IN4 w0.076: v1(33.41,12.51) 33.41,11.96 37.61,7.76 38.89,7.76 41.04,5.61 43.44,5.61 43.73,5.32 49.39,5.32 50.31,6.24 67.23,6.24 v1(67.6,6.61)
I2C0_SDA_SNR: length 114.1
  TOP w0.076: v7(250.7,60.82) 250.33,60.45 250.11,60.45 249.98,60.58 249.72,60.58 249.59,60.71 249.59,60.94 249.44,61.09 249.13,61.09 248.88,61.34 U636.F3
  TOP w0.109: v1(165.18,68.4) 165.35,68.23 v2(165.35,67.91) 165.35,67.48 165.68,67.15 R1225.2 ; JSNRDG.19 253.98,67.66 v7(253.98,67.66)
  IN1 w0.076: v7(250.7,60.82) 250.8,60.73 252.24,60.73 253.49,61.97 253.49,63.19 252.9,63.77 252.9,65.56 254.27,66.93 254.27,67.37 v7(253.98,67.66) 253.42,67.66 253.13,67.37 251.37,67.37 249.94,65.95 249.47,65.95 248.71,65.18 247.77,65.18 247.64,65.31 243.6,65.31 243.38,65.08 237.1,65.08 236.67,64.65 v3(236.67,64.05)
  IN3 w0.102: v1(165.18,68.4) 166.26,69.48 192.98,69.48 195.45,67.01 198.21,67.01 200.59,69.39 211.79,69.39 214.14,67.04 214.14,66.53 213.89,66.28 213.89,65.62 216.62,62.89 220.76,62.89 221.41,62.23 222.64,62.23 223.64,63.23 223.64,63.44 225.51,65.31 235.41,65.31 v3(236.67,64.05)
I2C1_SCK: length 215.8
  TOP w0.109: v7(160.46,59.24) 160.52,59.24 160.58,59.3 160.82,59.3 v6(161.74,60.23) 163.2,61.68 163.2,67.67 RH436.1 ; v7(126.52,65.08) 126.85,65.08 126.96,64.97 126.96,64.46 126.83,64.33 125.45,64.33 123.39,62.27 123.39,60.96 121.39,58.96 v7(121.39,58.02)
  IN1 w0.076: v7(121.39,58.02) 121.39,58 121.42,57.97 121.74,57.97 v3(121.79,57.92) 122.04,57.67 122.04,57.41 120.52,55.89 120.52,52.31 119.17,50.96 119.17,50.22 114.59,45.64 108.92,45.64 106.44,43.17 106.44,36.9 100.63,31.09 100.63,27.78 99.84,27 99.84,17.62 100.78,16.68 100.78,16.05 102.06,14.77 103.83,14.77 107.41,11.18 109.52,11.18 109.67,11.03 110.11,11.03 111.99,9.15 136.95,9.15 138.76,10.96 153.89,10.96 155.14,9.71 172.3,9.71 172.62,9.38 177.79,9.38 178.03,9.14 178.03,8.64 v1(177.86,8.47) ; v3(160.09,59.06) 160.28,59.06 v7(160.46,59.24)
  IN3 w0.102: v3(160.09,59.06) 159.96,59.19 158.62,59.19 157.3,60.51 154.88,60.51 153.82,59.44 150.87,59.44 150.08,60.23 142.87,60.23 142.46,60.64 134.05,60.64 133.67,60.26 126.71,60.26 126.61,60.16 124.15,60.16 121.91,57.92 v3(121.79,57.92)
  IN4 w0.076: v4(170.88,12.25) 170.68,12.25 170.58,12.35 170.58,12.59 170.76,12.77 174.13,12.77 174.41,12.49 177.4,12.49 177.53,12.36 177.53,12.14 177.49,12.1 v4(177.23,12.1) ; v4(161.85,59.03) 160.12,59.03 v3(160.09,59.06)
  BOTTOM w0.102: v4(161.85,59.03) 161.9,58.99 163.07,58.99 UCPU1.F1
  BOTTOM w0.109: v1(177.86,8.47) 178.05,8.66 178.05,10.83 177.51,11.37 177.51,11.82 v4(177.23,12.1)
I2C1_SCK_TP: length 37.3
  IN4 w0.076: v4(170.88,11.34) 170.71,11.34 170.58,11.46 170.58,11.58 170.66,11.65 173.78,11.65 174.34,11.1 v4(175.15,11.1)
  BOTTOM w0.109: DE2.3 196.13,12.19 196.02,12.08 195.1,12.08 193.61,10.59 193.61,8.5 189.89,4.78 v6(181.43,4.78) 175.75,4.78 175.06,5.48 175.06,9.27 175.15,9.37 JTP1.6 v4(175.15,11.1)
I2C1_SCK_TS: length 22.2
  TOP w0.109: MD90.1 125.09,68.37 125.23,68.23 125.48,68.23 126.26,67.45 126.79,67.45 127.04,67.2 127.04,66.52 v7(126.52,66)
  IN1 w0.076: v7(126.52,66) 126.44,66.08 v3(126.44,66.38)
  IN4 w0.076: v4(140.65,65.13) 140.65,65.56 139.93,66.28 137.71,66.28 137.02,65.59 127.65,65.59 126.87,66.38 v3(126.44,66.38)
  BOTTOM w0.109: JLVDS2.47 140.65,66.28 140.77,66.16 140.77,65.26 v4(140.65,65.13)
I2C1_SDA: length 214
  TOP w0.109: v7(127.77,65.08) 127.39,65.08 127.28,64.97 127.28,64.33 126.96,64.02 125.58,64.02 123.7,62.14 123.7,60.8 v7(121.79,58.89) ; RH437.1 162.89,67.71 v6(162.89,64.24) 162.89,61.81 160.69,59.61 160.58,59.61 160.52,59.67 v7(160.47,59.67)
  IN1 w0.076: v7(160.47,59.67) 160.42,59.62 v3(160.09,59.62) ; v7(121.79,58.89) v3(121.79,58.5) 122.32,57.97 122.32,57.3 120.8,55.77 120.8,52.19 119.45,50.84 119.45,50.11 114.7,45.36 109.03,45.36 106.72,43.05 106.72,36.79 100.91,30.97 100.91,27.67 100.12,26.88 100.12,17.74 101.06,16.8 101.06,16.16 102.18,15.05 103.94,15.05 107.52,11.46 109.63,11.46 109.78,11.31 110.23,11.31 112.11,9.43 136.84,9.43 138.64,11.24 154.01,11.24 155.26,9.99 172.41,9.99 172.74,9.66 177.91,9.66 178.31,9.26 178.31,8.62 v1(178.44,8.49)
  IN3 w0.102: v3(160.09,59.62) 159.96,59.5 158.74,59.5 157.42,60.82 154.76,60.82 153.69,59.75 151,59.75 150.21,60.54 142.99,60.54 142.59,60.94 133.93,60.94 133.55,60.56 126.59,60.56 126.49,60.46 124.02,60.46 122.04,58.48 121.81,58.48 v3(121.79,58.5)
  IN4 w0.076: v4(178.1,12.1) 177.91,12.1 177.81,12.2 177.81,12.48 177.51,12.77 174.53,12.77 174.25,13.05 170.64,13.05 170.3,12.71 170.3,12.31 170.24,12.25 v4(170,12.25) ; v4(160.5,59.34) 160.37,59.34 v3(160.09,59.62)
  BOTTOM w0.102: 160.98,59.22 161.51,58.68 UCPU1.G4
  BOTTOM w0.109: v4(160.5,59.34) 160.62,59.22 160.98,59.22 ; v1(178.44,8.49) 178.36,8.57 178.36,10.96 177.82,11.5 177.82,11.82 v4(178.1,12.1)
I2C1_SDA_TP: length 38.4
  IN4 w0.076: v4(174.8,11.48) 174.69,11.37 174.45,11.37 173.9,11.93 170.54,11.93 170.3,11.69 170.3,11.44 170.2,11.34 v4(170,11.34)
  BOTTOM w0.109: DE2.2 196.13,11.66 196.02,11.76 195.23,11.76 v6(194.27,10.8) 193.92,10.46 193.92,8.37 190.02,4.47 175.62,4.47 174.74,5.35 174.74,9.27 174.65,9.37 JTP1.7 174.65,11.33 v4(174.8,11.48)
I2C1_SDA_TS: length 22.4
  TOP w0.109: v7(127.77,66) 127.27,66.5 127.27,67.29 126.89,67.67 126.35,67.67 126.24,67.78 126.24,67.93 126.37,68.05 126.78,68.05 126.99,68.27 MD90.3
  IN1 w0.076: v3(127.92,66.35) 127.91,66.35 127.91,66.32 127.93,66.29 127.93,66.16 v7(127.77,66)
  IN4 w0.076: v4(141.1,65.13) 140.8,65.43 140.8,65.62 140,66.43 137.65,66.43 136.96,65.74 127.72,65.74 127.32,66.14 127.32,66.28 127.39,66.35 v3(127.92,66.35)
  BOTTOM w0.109: JLVDS2.48 141.15,66.29 141.01,66.15 141.01,65.23 v4(141.1,65.13)
I2S_BCLK_OUT: length 3.3
  TOP w0.109: R1372.2 32.95,12.09 v2(33.76,12.09) 34,12.09 34.25,11.84 UA1.29
I2S_CLK: length 261.4
  TOP w0.109: v1(226.87,63.69) 226.85,63.71 U677.13 ; v1(35.51,3.82) 35.23,4.1 R1373.1 R1374.1 ; v1(32.86,11.21) 32.36,11.71 R1372.1
  IN1 w0.076: v1(32.86,11.21) 32.86,10.96 33.67,10.14 33.67,8.48 34.27,7.88 34.27,5.76 35.51,4.52 v1(35.51,3.82)
  IN3 w0.102: v1(226.87,63.69) 226.87,63.38 221.1,57.62 221.1,51.75 219.03,49.68 219.03,48.66 219.25,48.45 219.25,47.81 218.27,46.83 218.27,45.23 217.19,44.16 217.19,42.71 215.47,40.99 215.47,40.47 214.1,39.1 214.1,38.16 211.88,35.94 211.07,35.94 210.38,35.25 206.82,35.25 203.99,32.42 203.99,15.52 200.42,11.96 200.42,11.37 196.01,6.96 194.31,6.96 191.93,4.57 183.41,4.57 182.21,3.37 152.24,3.37 148.73,6.88 144.34,6.88 140.73,3.27 113.89,3.27 113.3,3.85 110.73,3.85 110.18,3.3 106.27,3.3 105.24,2.27 58.04,2.27 56.64,3.67 51.76,3.67 51.3,3.21 48.77,3.21 48.55,2.98 43.15,2.98 39.62,6.51 39.36,6.51 37.56,8.31 37.56,9.03 35.86,10.73 35.4,10.73 34.44,11.69 33.32,11.69 32.84,11.21 v1(32.86,11.21)
I2S_CLK_IN: length 2.9
  TOP w0.109: R1373.2 35.23,6.39 v2(35.32,6.49) 35.74,6.49 36.41,7.15 UA1.38
I2S_SDI_IN: length 250.3
  TOP w0.109: v7(37.6,6.43) 37.91,6.75 UA1.41 ; v1(228.82,63.69) 228.8,63.71 U677.10
  IN1 w0.076: v3(37.51,5.98) 37.51,6.35 v7(37.6,6.43)
  IN3 w0.102: v3(37.51,5.98) 37.69,5.98 41.6,2.07 47.1,2.07 47.81,1.35 105.74,1.35 106.74,2.35 141.32,2.35 144.79,5.81 148.26,5.81 151.62,2.46 182.63,2.46 183.82,3.65 192.31,3.65 194.69,6.04 196.54,6.04 201.34,10.84 201.34,11.58 204.9,15.14 204.9,32.05 207.2,34.34 210.76,34.34 211.44,35.02 212.26,35.02 215.02,37.78 215.02,38.72 216.39,40.09 216.39,40.61 218.31,42.54 218.31,43.98 219.18,44.85 219.18,46.45 220.47,47.74 220.47,48.81 224.07,52.41 224.07,59.22 226.31,61.46 226.46,61.46 226.64,61.27 226.79,61.27 226.93,61.42 226.93,61.56 226.74,61.75 226.74,61.89 226.89,62.04 227.03,62.04 227.65,61.41 227.8,61.41 227.94,61.56 227.94,61.7 227.32,62.32 227.32,62.47 227.46,62.61 227.61,62.61 228.23,61.99 228.37,61.99 228.51,62.13 228.51,62.28 227.89,62.9 227.89,63.04 228.13,63.28 228.42,63.28 v1(228.82,63.69)
I2S_SDO_OUT: length 250.8
  TOP w0.109: UA1.31 34.71,10.84 34.16,10.28 v1(34.16,9.08) ; v1(228.16,63.69) 228.15,63.7 U677.11
  IN3 w0.102: v1(228.16,63.69) 228.11,63.69 221.71,57.29 221.71,50.49 220.17,48.95 220.17,47.87 218.88,46.58 218.88,44.98 218.01,44.11 218.01,42.66 216.08,40.74 216.08,40.22 214.71,38.85 214.71,37.9 212.14,35.33 211.32,35.33 210.63,34.64 207.07,34.64 204.6,32.17 204.6,15.27 201.03,11.7 201.03,11.04 196.34,6.35 194.57,6.35 192.18,3.96 183.7,3.96 182.5,2.76 151.81,2.76 148.41,6.17 144.64,6.17 141.13,2.66 106.62,2.66 105.62,1.66 57.32,1.66 56.28,2.7 51.66,2.7 50.87,1.91 47.68,1.91 47.22,2.37 41.72,2.37 35.02,9.08 v1(34.16,9.08)
I2S_SFRM_IN: length 2.5
  TOP w0.254: R1374.2 36.12,5.45 36.61,5.93 v2(36.61,6.45) 36.61,6.69 36.91,6.99 UA1.39
I2S_SFRM_OUT: length 251.7
  TOP w0.109: v1(227.53,63.69) 227.5,63.72 U677.12 ; v1(33.42,10.96) 33.57,10.8 v2(33.97,10.8) 34.5,11.34 UA1.30
  IN3 w0.102: v1(33.42,10.96) 33.57,10.96 41.85,2.68 47.35,2.68 47.81,2.22 50.74,2.22 51.68,3.16 56.46,3.16 57.65,1.96 105.44,1.96 106.47,2.99 110.36,2.99 110.91,3.55 113.17,3.55 113.76,2.96 140.93,2.96 144.49,6.52 148.58,6.52 152.04,3.07 182.38,3.07 183.57,4.26 192.05,4.26 194.44,6.65 196.21,6.65 200.73,11.17 200.73,11.83 204.29,15.39 204.29,32.3 206.94,34.95 210.51,34.95 211.19,35.63 212.01,35.63 214.41,38.03 214.41,38.97 215.78,40.35 215.78,40.87 217.5,42.59 217.5,44.03 218.57,45.1 218.57,46.71 219.86,48 219.86,49.08 221.41,50.62 221.41,57.42 227.53,63.54 v1(227.53,63.69)
IMON: length 6.6
  TOP w0.102: PC707.1 106.76,59.48 108.11,58.14 v2(108.11,57.34)
  TOP w0.203: PC707.1 105.33,59.48 105.31,59.5 PR703.1 104.32,59.11 PU701.13
IMVP_VR_PG: length 101.4
  TOP w0.109: R1291.1 181.18,36.5 v2(178.7,38.98) 178.36,39.31 175.92,39.31 173.54,36.93 169.51,36.93 167.25,39.19 167.23,39.19 v1(165.84,40.57)
  TOP w0.203: v7(101.83,54.49) 101.53,54.8 PR723.1 101.15,55.1 100.43,55.82 PU701.3
  IN1 w0.076: v3(119.22,52.79) 119.17,52.84 119.17,55.99 118.87,56.29 117.62,56.29 116.78,57.13 v1(115.69,57.13) 114.52,57.13 113.68,57.97 112.55,57.97 112.04,57.46 109.15,57.46 107.7,56.02 105.89,56.02 104.23,54.36 101.96,54.36 v7(101.83,54.49)
  IN3 w0.102: v1(165.84,40.57) 165.46,40.95 159.78,40.95 158.03,42.71 156.64,42.71 155.67,43.67 155.67,43.9 155.44,44.13 155.44,46.41 155.26,46.59 155.26,47.23 155.09,47.4 154.7,47.4 154.48,47.18 153.89,47.18 153.59,47.48 152.44,47.48 152.25,47.67 149.99,47.67 149.78,47.46 148.79,47.46 148.48,47.76 141.57,47.76 141.27,47.46 139.57,47.46 139.36,47.66 132.94,47.66 132.58,47.3 130.47,47.3 129.53,48.24 128.21,48.24 126.87,49.59 122.37,49.59 119.22,52.74 v3(119.22,52.79)
  BOTTOM w0.109: v1(115.69,57.13) 115.51,57.31 R1211.2 RC152.1
INV_PWM_R: length 48.6
  IN4 w0.076: v4(128.65,66.07) 128.8,66.23 130.42,66.23 130.73,66.53 130.73,68.11 131.79,69.17 143.71,69.17 144.72,70.19 146.3,70.19 v4(146.35,70.24)
  BOTTOM w0.109: D106.1 171.82,68.83 R545.1 171.44,69.58 171.29,69.43 MC1151.1 170.39,69.9 168.48,69.9 168.09,69.5 v2(166.26,69.5) 160.33,69.5 159.87,69.95 146.63,69.95 v4(146.35,70.24)
  BOTTOM w0.203: JLVDS2.23 v4(128.65,66.07)
ISET: length 4.1
  TOP w0.109: v1(28,39.21) 28,39.66 28.38,40.04 RV33.1 RV32.1 v2(30.41,40.04)
  BOTTOM w0.109: v1(28,39.21) 27.94,39.21 27.6,38.87 U722.34
JACK_PLUG: length 7.2
  TOP w0.109: QA3.5 19.81,11.68 19.11,10.98 RA26.1 18.6,10.37 18.6,9.86 18.37,9.63 18.37,8.31 17.8,7.74 RA35.1 17.8,6.57 17.23,6 v2(17.23,5.75)
JACK_PLUG_C: length 21.9
  TOP w0.109: v2(12.86,7.6) 13.1,7.6 v1(13.52,7.18)
  TOP w0.508: v1(13.52,7.18) 14.05,7.18 15.16,8.29 DA5.3 16.22,8.29 v7(16.88,7.63) RA35.2 ; RA20.1 20.37,7.19 v7(20.06,6.88)
  IN1 w0.508: v7(20.06,6.88) 17.63,6.88 v7(16.88,7.63)
  IN4 w0.508: JHP1.6 8.83,13.83 11.82,13.83 13.29,12.35 13.29,7.41 v1(13.52,7.18)
JACK_PLUG_DL: length 10.2
  TOP w0.109: QA6.2 QA6.5 19.11,6.28 19.23,6.41 CA57.1 18.61,7.53 18.61,9.47 RA26.2 19.11,9.99 RA38.2 ; RA38.2 20.85,10.88 v2(21.01,10.71) ; RA38.2 20,11.1 20.46,11.55 QA3.6
JACK_PLUG_DL#: length 24
  TOP w0.109: v2(19.26,24.01) 19.26,23.97 20.3,22.93 RA24.2 19.92,22.84 v7(19.6,22.53) ; v1(20.08,4.5) 19.76,4.18 QA6.3
  IN1 w0.076: v1(20.08,4.5) 20.59,5.01 20.59,9.28 17.61,12.26 17.61,14.42 17.77,14.59 17.77,16.04 18.84,17.11 18.84,17.83 18.23,18.44 18.23,19.34 19.58,20.69 19.58,22.5 v7(19.6,22.53)
JDREF: length 2.5
  TOP w0.203: RA25.1 21.24,21.8 v2(22.1,21.8) 22.18,21.8 22.88,22.5 UA2.35
JNTRST: length 99.6
  TOP w0.076: U636.B4 246.58,61.58 246.12,61.58 245.98,61.44 245.74,61.44 245.44,61.15 v7(245.44,61.06)
  TOP w0.109: v7(253.94,60.16) 253.93,60.16 JSNRDG.4 ; v7(245.44,61.06) 245.44,60.83 245.27,60.66 245.27,59.52 v2(245.1,59.36) 244.89,59.36 244.2,58.67 244.2,58.54 R1236.2
  IN1 w0.076: v3(220.56,41.3) 219.4,40.14 217.84,40.14 214.87,37.17 213.33,37.17 211.03,34.87 208.82,34.87 206.9,32.95 206.9,31.71 205.2,30.01 205.2,24.75 205.03,24.58 205.03,14.03 206.06,13 206.06,12.17 206.37,11.86 JSATA1.16 ; v7(253.94,60.16) 253.31,60.16 252.85,59.69 249.9,59.69 248.86,60.73 247.25,60.73 246.68,60.16 246.68,59.45 246.39,59.16 245.61,59.16 244.83,59.94 244.83,60.53 v3(245.13,60.83) 245.21,60.83 v7(245.44,61.06)
  IN3 w0.102: v3(245.13,60.83) 245.67,60.83 246.68,59.83 246.68,59.38 246.15,58.86 244.56,58.86 244.01,58.3 242.68,58.3 239.3,54.92 233.21,54.92 230.97,52.69 229.63,52.69 228.05,51.11 228.05,50.54 227.68,50.17 225.79,50.17 224.76,49.14 224.76,47.88 222.31,45.44 221.76,45.44 220.39,44.06 220.39,41.47 v3(220.56,41.3)
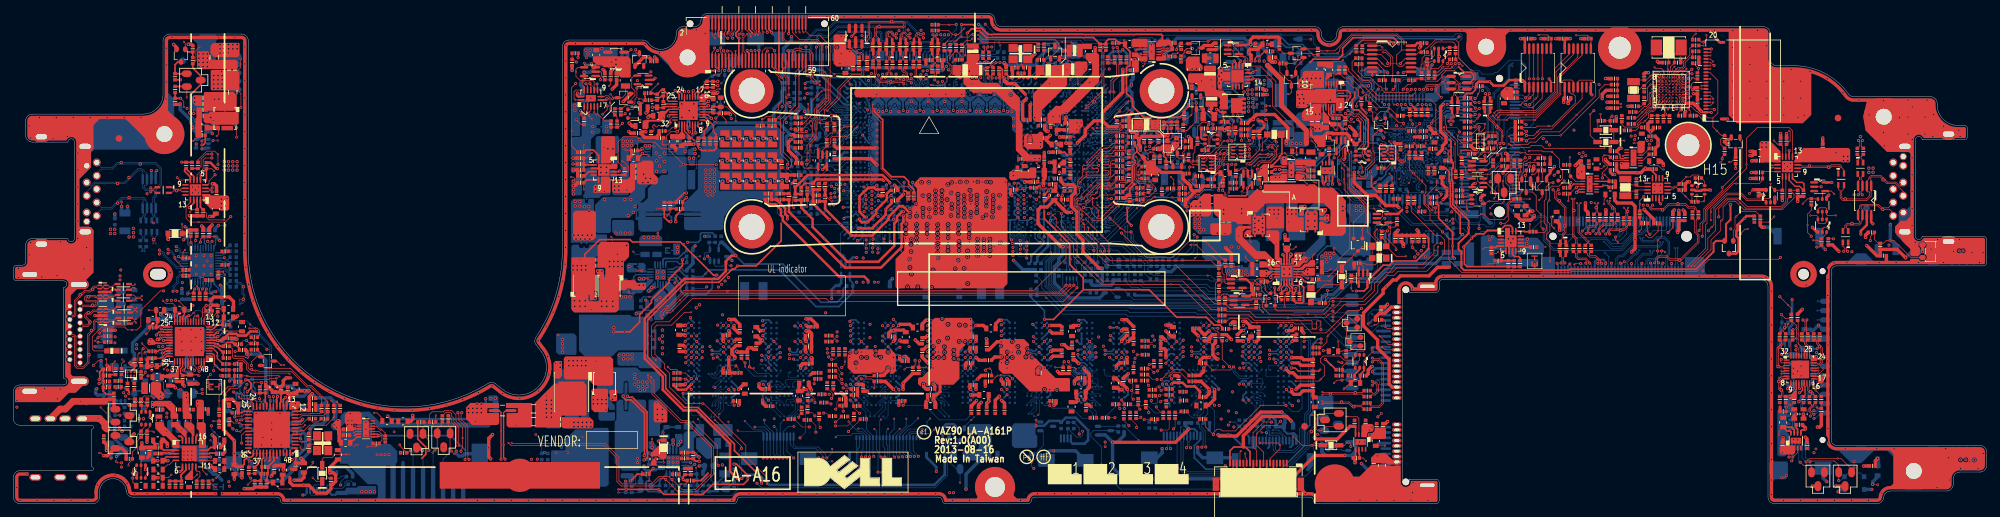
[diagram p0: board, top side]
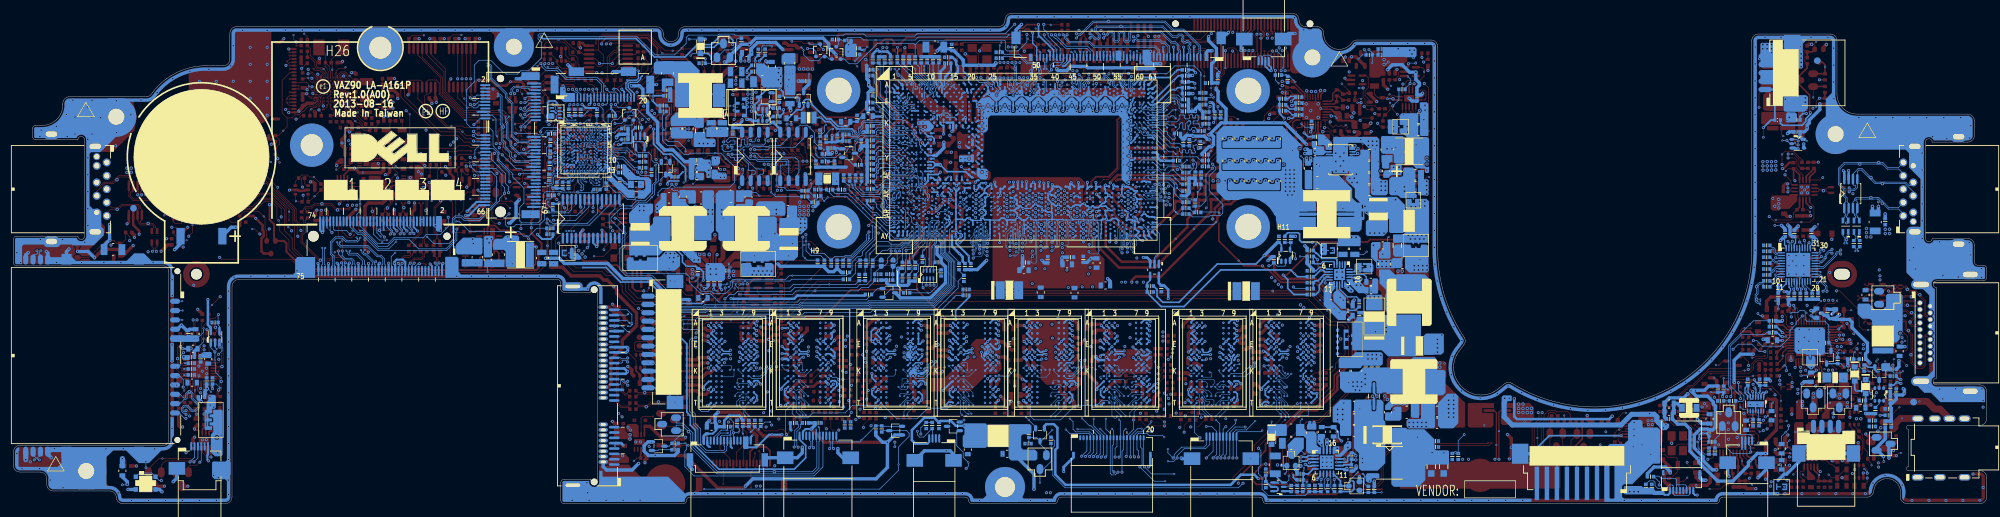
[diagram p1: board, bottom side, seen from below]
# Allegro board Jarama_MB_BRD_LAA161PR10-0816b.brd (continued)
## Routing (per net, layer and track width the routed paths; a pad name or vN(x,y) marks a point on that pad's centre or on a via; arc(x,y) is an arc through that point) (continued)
JTCK: length 95.4
  TOP w0.076: U636.B2 246.6,60.59 246.07,60.59 v7(245.98,60.5)
  TOP w0.109: R1099.2 242.8,55.96 243.25,56.41 243.25,56.79 243.55,57.09 243.89,57.09 v2(244.14,57.34) 244.68,57.88 244.68,58.48 244.96,58.76 245.42,58.76 245.79,59.12 245.79,60.26 245.98,60.45 v7(245.98,60.5) ; v7(253.94,60.66) 253.94,60.66 JSNRDG.5
  IN1 w0.076: v7(253.94,60.66) 253.54,60.66 252.77,59.89 249.98,59.89 248.83,61.04 247.26,61.04 246.72,60.5 v7(245.98,60.5) 245.98,60.27 245.76,60.05 245.79,60.05 245.79,60.07 245.78,60.07 245.78,60.05 v3(245.79,60.05) ; JSATA1.14 206.26,11.06 205.22,12.11 205.22,13.54 204.83,13.93 204.83,24.67 205,24.83 205,30.09 206.7,31.79 206.7,33.03 208.74,35.07 210.95,35.07 213.24,37.37 214.79,37.37 217.83,40.42 219.09,40.42 v3(219.96,41.28)
  IN3 w0.102: v3(245.79,60.05) 244.82,59.09 244.47,59.09 243.91,58.53 242.58,58.53 239.2,55.15 233.11,55.15 230.88,52.92 229.53,52.92 227.98,51.37 226.03,51.37 225.85,51.19 225.85,50.82 223.11,48.08 223.11,46.55 222.22,45.66 221.67,45.66 219.96,43.95 v3(219.96,41.28)
JTDI: length 103
  TOP w0.076: U636.C3 247.09,61.09 246.24,61.09 246.11,60.96
  TOP w0.109: v1(219.35,41.25) v2(219.35,41.83) ; 246.11,60.96 245.99,60.84 245.85,60.84 v7(245.55,60.54) 245.55,60.54 245.55,59.22 245.32,58.99 244.87,58.99 244.44,58.57 244.44,58.35 243.01,56.92 243.01,56.56 242.9,56.45 241.1,56.45 240.71,56.84 R1237.2 ; JSNRDG.6 253.96,61.16 254.38,60.75 v7(254.38,60.66)
  IN1 w0.076: v1(219.35,41.25) 218.73,40.62 217.75,40.62 214.7,37.57 213.16,37.57 210.86,35.28 208.65,35.28 206.5,33.12 206.5,31.89 204.79,30.18 204.79,24.92 204.63,24.75 204.63,13.84 205.02,13.46 205.02,11.52 206.27,10.26 JSATA1.12 ; v7(254.38,60.66) 254.38,60.69 254.08,60.98 253.57,60.98 252.68,60.1 250.07,60.1 248.92,61.25 247.18,61.25 246.75,60.82 245.83,60.82 v7(245.55,60.54) 245.27,60.26 v3(245.23,60.26)
  IN3 w0.102: v1(219.35,41.25) 219.35,43.67 221.57,45.89 222.12,45.89 222.88,46.65 222.88,48.17 225.62,50.92 225.62,55.71 226.18,56.27 230.93,56.27 231.34,56.68 240.4,56.68 242.49,58.76 243.82,58.76 245.23,60.17 v3(245.23,60.26)
JTDO: length 100.4
  TOP w0.076: 245.26,61.36 245.34,61.44 245.51,61.44 245.78,61.71 v7(245.85,61.71) 245.98,61.84 U636.A4
  TOP w0.109: 245.26,61.36 245.15,61.26 245.15,61.02 245.03,60.9 245.03,59.84 244.24,59.05 244.14,59.05 v2(243.76,58.67) 242.92,57.83 R1235.2 ; v7(253.94,61.65) 253.93,61.66 JSNRDG.7
  IN1 w0.076: v7(245.85,61.71) 246.04,61.71 v3(246.25,61.5) 246.86,61.5 247.21,61.86 248.88,61.86 250.24,60.5 252.51,60.5 253.41,61.4 253.69,61.4 v7(253.94,61.65) ; v3(206.1,32.18) 206.1,31.81 204.59,30.3 204.59,25 204.43,24.84 204.43,13.76 204.81,13.37 204.81,10.61 205.95,9.46 JSATA1.10
  IN3 w0.102: v3(246.25,61.5) 245.99,61.25 244.97,61.25 244.73,61 244.73,59.99 243.72,58.99 242.39,58.99 240.77,57.36 225.73,57.36 225.39,57.02 225.39,51.01 222.65,48.27 222.65,46.74 222.03,46.12 221.48,46.12 218.85,43.5 218.85,41.33 215.82,38.29 215.82,37.79 211.83,33.8 207.42,33.8 206.1,32.49 v3(206.1,32.18)
JTMS: length 107.1
  TOP w0.076: U636.D4 247.59,62.09 246.25,62.09 246.15,61.99 245.66,61.99 v7(245.4,61.72)
  TOP w0.109: v7(245.4,61.72) 245.14,61.72 v2(244.97,61.55) 244.8,61.38 244.8,59.94 244.39,59.53 244.06,59.53 243.24,58.71 R1234.2 ; v7(254.38,60.16) 254.38,60.07 253.97,59.66 JSNRDG.3
  IN1 w0.076: v7(245.4,61.72) 245.07,61.72 v3(245,61.65) 244.62,61.28 244.62,59.85 245.52,58.95 246.47,58.95 246.88,59.37 246.88,60.07 247.34,60.53 248.77,60.53 249.81,59.49 252.93,59.49 253.28,59.84 254.11,59.84 254.38,60.11 v7(254.38,60.16) ; JSATA1.8 205.52,8.66 204.61,9.58 204.61,13.29 204.22,13.67 204.22,24.92 204.39,25.09 204.39,30.65 205.58,31.85 v3(205.58,31.85)
  IN3 w0.102: v3(205.58,31.85) 205.58,32.29 207.32,34.03 211.73,34.03 215.59,37.89 215.59,38.39 218.62,41.42 218.62,43.59 220.78,45.75 220.78,46.78 225.16,51.16 225.16,57.11 225.64,57.59 240.67,57.59 242.3,59.22 243.63,59.22 244.5,60.09 244.5,61.15 v3(245,61.65)
KB_BL_DET: length 88
  IN1 w0.076: v3(162.38,42.15) 163.05,42.15 166.46,38.74 167.28,38.74 170.06,35.96 173.92,35.96 178.73,31.15 186.26,31.15 190.22,27.19 190.65,27.19 190.87,26.96 190.87,26.14 191.76,25.26 191.76,19.82 187.8,15.86 187.8,13.78 184.11,10.08 181,10.08 180.87,9.95 173.15,9.95 172.83,10.26 159.69,10.26 v1(159.51,10.45)
  IN4 w0.076: v4(162.81,42.17) 162.4,42.17 v3(162.38,42.15)
  BOTTOM w0.109: v4(162.81,42.17) 163.14,41.83 163.76,41.83 163.9,41.69 164.67,41.69 166.27,43.29 T284.1 ; v1(159.51,10.45) 159.51,11.36 R945.2 R944.1
KB_DET#: length 173.6
  IN1 w0.076: v3(158.69,49.72) 158.78,49.63 159.03,49.63 159.49,49.17 160,49.17 160,49.17 160.42,49.17 161.22,48.37 161.22,48.05 161.61,47.66 162.94,47.66 163.32,47.28 164.29,47.28 164.48,47.09 165.21,47.09 165.96,46.34 166.32,46.34 166.8,45.86 174.4,45.86 175.04,45.22 175.04,43.66 176.18,42.52 176.18,40.09 176.52,39.75 176.52,39.53 179.34,36.71 188.06,36.71 189.13,35.64 191.13,35.64 191.41,35.37 191.41,33.56 191.9,33.07 192.14,33.07 192.83,32.38 193.3,31.9 193.3,30.58 195.52,28.36 195.52,27.27 196.77,26.03 196.77,13.69 195.66,12.58 195.66,12.07 190.33,6.74 180.83,6.74 180.06,5.97 155.71,5.97 152.96,8.72 143.71,8.72 141.22,6.23 119.5,6.23 119.3,6.43 112.64,6.43 v1(112.22,6.85)
  IN4 w0.076: v3(158.69,49.72) 158.73,49.76 160.21,49.76 160.55,50.1 160.78,50.1 161.08,50.4 161.64,50.4 162.02,50.78 162.02,50.83 162.27,51.09 162.63,51.09 v4(163.01,51.47)
  BOTTOM w0.109: v1(112.22,6.85) 112.26,6.89 JKB1.10 112.26,10.56 112.03,10.79 108.59,10.79 v2(108.4,10.98) ; v4(163.01,51.47) 163.39,51.85 UCPU1.Y1 163.98,51.85 164.15,51.67 T282.1 165.72,51.67 165.82,51.57 165.82,51.2 166.12,50.9 166.12,50.52 RH302.1
KB_INT#: length 109.3
  IN4 w0.076: v4(214.39,52.08) 214.97,52.08 215.97,51.08 215.97,48.36 216.49,47.84 216.49,45.85 215.82,45.18 215.82,45.02 215.18,44.38 214.9,44.38 214.08,43.56 214.08,42.34 214.46,41.96 214.46,41.54 214.12,41.19 213.63,41.19 212.1,39.67 212.1,36.91 211.59,36.41 210.63,36.41 208.47,34.25 207.54,34.25 206.51,33.21 206.51,31.91 205.2,30.6 205.2,10.47 201.63,6.89 200.75,6.89 199.99,6.13 197.47,6.13 196.23,4.88 195.02,4.88 192.32,2.18 v4(191.92,2.18)
  BOTTOM w0.076: U34.M7 212.36,52.94 212.62,52.69 213.06,52.69 213.21,52.54 213.39,52.54 213.85,52.08 v4(214.39,52.08)
  BOTTOM w0.109: R1388.1 165.14,10.94 Q365.1 161.63,10.94 161.25,10.56 161.25,10.09 162.83,8.5 v2(162.83,5.86) 162.83,5.01 165.66,2.18 v4(191.92,2.18)
KB_INT#_R: length 11.7
  BOTTOM w0.109: Q365.3 165.29,11.59 R1388.2 R1301.2 v2(168.41,9.48) 168.64,9.25 171.96,9.25 172.15,9.44 JTP1.12
KB_LED_PWM: length 108.3
  IN1 w0.076: v3(209.8,38.82) 209.54,39.07 207,39.07 206.15,38.22 205.56,38.22 201.47,34.12 201.47,30.64 200.5,29.68 200.5,14.64 199.89,14.03 199.89,11.82 195.29,7.22 194.1,7.22 191.33,4.45 182.88,4.45 182.11,3.69 154.31,3.69 v1(152.71,5.29)
  IN3 w0.102: v3(209.8,38.82) 209.8,39.15 211.02,40.37 211.02,41.38 211.98,42.35 211.98,43.21 212.39,43.61 212.39,45.7 214.53,47.85 214.53,49.67 214.7,49.83 v3(214.7,50.59)
  IN4 w0.076: v4(214.27,50.99) 214.38,50.87 214.42,50.87 v3(214.7,50.59)
  BOTTOM w0.076: v4(214.27,50.99) 214.1,50.99 213.55,51.54 213.23,51.54 213.08,51.69 212.61,51.69 U34.M9
  BOTTOM w0.109: Q311.2 154.01,10.94 154.12,10.83 154.12,8.68 153.16,7.72 153.16,6.94 152.38,6.17 v2(152.38,6.16) 152.38,5.62 v1(152.71,5.29)
KB_LED_PWM#: length 18.1
  IN4 w0.381: v4(156.75,9.79) 157.31,9.23 v1(163.39,9.23) 163.75,9.23 164.52,10 v4(173.65,10)
  BOTTOM w0.109: v1(163.39,9.23) v5(163.39,8.53)
KB_RST#: length 59.8
  TOP w0.109: RH196.1 170.45,54.14 v7(170.63,54.31)
  IN1 w0.076: v3(161.16,52) 161.13,52.03 161.13,52.41 162.25,53.53 163.82,53.53 164.89,54.59 165.75,54.59 165.92,54.76 166.19,54.76 166.39,54.96 167.34,54.96 167.84,54.47 167.84,54.29 168.07,54.06 168.61,54.06 169.02,54.47 170.48,54.47 v7(170.63,54.31) 170.71,54.39 173.7,54.39 174.24,53.84 175.48,53.84 175.96,54.33 177.09,54.33 177.42,54 177.87,54 178.13,53.74 182.42,53.74 183.16,53.01 183.61,53.01 184.14,52.48 186.02,52.48 187.23,51.27 189.05,51.27 189.96,52.17 191.28,52.17 192.07,51.38 195.25,51.38 195.82,51.95 197.16,51.95 197.67,52.46 200.53,52.46 201.62,53.55 203.18,53.55 205.31,55.69 206.8,55.69 207.23,55.25 211.42,55.25 211.7,55.53 v3(211.7,55.48)
  IN4 w0.076: v4(161.18,52.38) 161.18,52.03 v3(161.16,52) ; v3(211.7,55.48) 211.7,55.41 211.52,55.23 v4(211.52,55.05)
  BOTTOM w0.109: v4(211.52,55.05) 211.52,55.11 U34.L2 ; v4(161.18,52.38) 161.43,52.63 UCPU1.V4
KSI0: length 134.9
  IN4 w0.076: v1(121.74,6.85) 122.13,7.25 125.77,7.25 126.22,7.7 141.25,7.7 143.19,9.63 150.36,9.63 154.02,5.97 179.92,5.97 180.64,6.69 190.79,6.69 194.99,10.89 196.19,10.89 198.01,12.71 198.01,19.41 199.4,20.8 199.4,21.5 199.71,21.81 199.71,32.79 204.34,37.42 204.34,39.57 205.1,40.34 205.1,41.21 206.34,42.45 206.34,44.7 207.51,45.87 207.51,46.46 208.53,47.47 208.53,47.62 208.83,47.93 208.83,49.11 208.4,49.54 208.4,51.49 208.2,51.7 v4(208.07,51.7)
  BOTTOM w0.109: v2(122.54,8.2) 122.54,7.65 v1(121.74,6.85) 121.57,7.01 121.57,7.37 120.47,8.47 117.12,8.47 116.76,8.83 JKB1.1 ; U34.D9 208.32,51.94 v4(208.07,51.7)
KSI1: length 132.2
  IN4 w0.076: v1(116.77,6.85) 117.66,7.74 119.77,7.74 120.11,8.08 125.46,8.08 125.89,8.51 140.91,8.51 142.85,10.45 150.69,10.45 154.36,6.79 179.52,6.79 180.24,7.5 190.45,7.5 194.65,11.71 195,11.71 197.2,13.9 197.2,20.45 197.94,21.18 197.94,25.27 198.9,26.23 198.9,33.13 203.52,37.75 203.52,40.91 204.84,42.23 204.84,43.19 205.5,43.85 205.5,45.69 v4(207.6,47.79)
  BOTTOM w0.076: U34.E12 208.86,50.38 209.1,50.14 209.1,48.37 v2(208.83,48.1) 208.45,47.72 207.66,47.72 v4(207.6,47.79)
  BOTTOM w0.109: JKB1.3 115.76,7.86 v1(116.77,6.85)
KSI2: length 135.6
  IN4 w0.076: v4(207.99,48.04) 207.92,47.96 207.92,47.73 205.71,45.52 205.71,42.68 203.73,40.7 203.73,37.67 199.1,33.05 199.1,26.15 198.14,25.18 198.14,21.1 197.4,20.36 197.4,13.81 195.09,11.5 194.74,11.5 190.53,7.3 180.39,7.3 179.67,6.58 154.27,6.58 150.61,10.24 142.93,10.24 141,8.31 125.97,8.31 125.54,7.88 120.2,7.88 119.85,7.54 118.06,7.54 116.97,6.45 115.57,6.45 v1(115.17,6.85)
  BOTTOM w0.076: U34.E13 208.88,49.92 208.88,48.64 208.29,48.04 v4(207.99,48.04)
  BOTTOM w0.109: v1(115.17,6.85) 114.76,7.26 JKB1.5 114.76,11.98 v2(115.31,12.53)
KSI3: length 132.7
  IN4 w0.076: v4(208.57,48.78) 208.57,47.95 208.32,47.71 208.32,47.56 207.31,46.54 207.31,45.96 206.14,44.79 206.14,42.54 204.9,41.29 204.9,40.42 204.13,39.66 204.13,37.5 199.51,32.88 199.51,21.9 199.2,21.58 199.2,20.89 197.81,19.5 197.81,13.64 195.27,11.1 194.91,11.1 190.7,6.89 180.55,6.89 179.84,6.18 154.1,6.18 150.44,9.84 143.1,9.84 141.17,7.9 126.14,7.9 125.71,7.47 121.77,7.47 v1(121.14,6.85)
  BOTTOM w0.076: U34.D12 208.36,50.42 208.6,50.17 208.6,49.77 208.73,49.64 208.73,49.11 208.57,48.94 v4(208.57,48.78)
  BOTTOM w0.109: JKB1.2 116.26,8.89 116.91,8.24 120.1,8.24 121.14,7.2 v1(121.14,6.85) 121.64,6.35 v2(122.52,6.35)
KSI4: length 134.5
  IN4 w0.076: v1(114.59,6.85) 115.88,8.15 119.55,8.15 119.9,8.49 125.29,8.49 125.72,8.92 140.74,8.92 142.68,10.85 150.86,10.85 154.52,7.19 179.35,7.19 180.07,7.91 190.28,7.91 194.48,12.11 194.84,12.11 196.79,14.07 196.79,20.62 197.53,21.35 197.53,25.49 198.49,26.45 198.49,33.3 203.12,37.92 203.12,41.08 204.44,42.4 204.44,43.37 205.05,43.98 205.05,45.92 207.22,48.09 207.22,48.21 207.49,48.48 208.04,48.48 v4(208.06,48.47)
  BOTTOM w0.076: U34.D13 208.36,49.8 208.58,49.58 208.58,49.25 208.24,48.91 208.24,48.65 v4(208.06,48.47)
  BOTTOM w0.109: v1(114.59,6.85) 114.59,7.08 114.26,7.41 JKB1.6 114.26,11.15 v5(113.85,11.57)
KSI5: length 134.7
  IN4 w0.076: v4(207.6,48.22) 207.6,48.17 205.25,45.82 205.25,43.89 204.64,43.28 204.64,42.31 203.32,40.99 203.32,37.84 198.7,33.22 198.7,26.32 197.73,25.35 197.73,21.27 197,20.53 197,13.98 194.92,11.91 194.57,11.91 190.36,7.7 180.15,7.7 179.44,6.99 154.44,6.99 150.78,10.65 142.76,10.65 140.83,8.72 125.8,8.72 125.37,8.29 120.03,8.29 119.69,7.94 116.85,7.94 v1(115.76,6.85)
  BOTTOM w0.076: v4(207.6,48.22) 207.74,48.36 207.74,48.63 208.43,49.31 208.43,49.51 208.11,49.82 208.11,50.19 U34.C12
  BOTTOM w0.109: v1(115.76,6.85) 115.26,7.34 JKB1.4 115.26,10.86 115.98,11.58 v5(116.8,11.58)
KSI6: length 137.3
  IN4 w0.076: v1(114,6.85) 114.61,6.24 117.05,6.24 118.14,7.34 119.94,7.34 120.28,7.68 125.63,7.68 126.05,8.11 141.08,8.11 143.02,10.04 150.52,10.04 154.19,6.38 179.75,6.38 180.47,7.09 190.62,7.09 194.82,11.3 195.17,11.3 197.61,13.73 197.61,20.28 198.34,21.02 198.34,25.1 199.31,26.06 199.31,32.96 203.93,37.59 203.93,39.75 204.69,40.51 204.69,41.38 205.94,42.62 205.94,44.87 207.1,46.04 207.1,46.63 208.12,47.64 208.12,47.79 208.41,48.08 208.41,48.51 208.3,48.62 208.3,49.26 v4(208.15,49.41)
  BOTTOM w0.109: v1(114,6.85) 114,7.21 113.76,7.45 JKB1.7 113.76,10.66 112.38,12.05 v5(112.38,12.53)
  BOTTOM w0.254: U34.C13 207.86,49.7 v4(208.15,49.41)
KSI7: length 139.8
  IN4 w0.076: v1(113.42,6.85) 114.91,8.35 119.47,8.35 119.81,8.7 125.21,8.7 125.63,9.12 140.66,9.12 142.6,11.06 150.95,11.06 154.61,7.39 179.27,7.39 179.99,8.11 190.2,8.11 194.4,12.31 194.75,12.31 196.59,14.15 196.59,20.7 197.33,21.44 197.33,25.57 198.29,26.54 198.29,33.38 202.91,38.01 202.91,41.16 204.23,42.48 204.23,45.5 207.37,48.64 207.85,48.64 208.04,48.84 208.04,49.14 207.88,49.3 207.88,49.52 208.25,49.89 208.25,51.24 208.11,51.38 207.96,51.38 v4(207.66,51.67)
  BOTTOM w0.109: v4(207.66,51.67) 207.66,51.63 207.99,51.3 208.21,51.3 U34.D10 ; v5(110.97,11.49) 112.44,11.49 113.26,10.67 JKB1.8 113.26,7.01 v1(113.42,6.85)
KSO0: length 121.4
  IN4 w0.076: v1(130.42,6.99) 131.2,6.99 132.7,5.49 136.33,5.49 137.11,6.28 141.84,6.28 143.78,8.21 148.93,8.21 152.59,4.55 181.71,4.55 182.43,5.27 191.38,5.27 193.84,7.73 195.04,7.73 201.53,14.21 201.53,27.51 202.15,28.13 202.15,33.19 205.76,36.8 205.76,38.75 207,39.99 207.63,39.99 208.22,40.58 208.22,42.47 209.16,43.42 209.16,46.03 209.95,46.82 209.95,46.99 210.31,47.35 v4(210.31,47.39)
  BOTTOM w0.109: U34.J13 210.86,49.8 210.93,49.73 210.93,49.34 210.83,49.23 v2(210.83,48.41) 210.83,48.2 210.31,47.68 v4(210.31,47.39) ; JKB2.12 130.15,8.56 130.42,8.29 v1(130.42,6.99)
KSO1: length 129.6
  IN4 w0.076: v1(129.39,4.72) 129.81,5.14 130.75,5.14 132.02,3.87 138.34,3.87 139.12,4.65 142.52,4.65 144.45,6.59 148.25,6.59 151.91,2.92 182.39,2.92 183.1,3.64 192.05,3.64 194.51,6.1 195.72,6.1 203.78,14.16 203.78,32.52 208.81,37.55 208.81,38.86 209.85,39.9 209.85,40.24 210.62,41.02 210.62,42.51 210.79,42.67 210.79,43.43 211.4,44.04 211.4,44.92 212.45,45.97 212.45,47.57 v4(211.64,48.38)
  BOTTOM w0.076: 211.11,49.36 211.11,50.19 U34.J12
  BOTTOM w0.109: v2(128.85,11.18) 129.15,10.88 JKB2.14 129.15,8.1 129.39,7.86 v1(129.39,4.72) ; 211.11,49.36 211.11,48.98 211.64,48.45 v4(211.64,48.38)
KSO2: length 126.1
  IN4 w0.076: v1(129.84,6.98) 130.23,6.59 131.32,6.59 132.61,5.29 136.41,5.29 137.19,6.07 141.93,6.07 143.86,8.01 148.84,8.01 152.5,4.35 181.8,4.35 182.51,5.06 191.46,5.06 193.92,7.53 195.13,7.53 201.73,14.13 201.73,27.43 202.36,28.05 202.36,33.11 205.96,36.72 205.96,38.66 207.09,39.79 207.72,39.79 208.42,40.49 208.42,42.39 209.37,43.33 209.37,45.94 v4(210.38,46.96)
  BOTTOM w0.076: 210.71,49.45 210.71,49.71 210.61,49.81 210.61,50.19 U34.H12
  BOTTOM w0.109: v4(210.38,46.96) 210.14,46.96 209.94,47.16 209.94,47.75 210.37,48.18 210.37,49.11 210.71,49.45 ; v1(129.84,6.98) 129.65,7.17 JKB2.13 129.65,12.42 v2(129.84,12.61)
KSO3: length 127.4
  IN4 w0.076: v1(128.76,7.08) 128.82,7.02 129.2,7.02 129.84,6.38 131.23,6.38 132.53,5.09 136.49,5.09 137.28,5.87 142.01,5.87 143.95,7.81 148.75,7.81 152.41,4.14 181.88,4.14 182.6,4.86 191.55,4.86 194.01,7.32 195.21,7.32 201.94,14.05 201.94,27.34 202.56,27.96 202.56,33.03 206.17,36.63 206.17,38.58 207.17,39.58 207.8,39.58 208.63,40.41 208.63,42.3 209.57,43.25 209.57,45.37 210.51,46.31 211,46.31 211.23,46.54 211.23,46.91 210.55,47.6 210.55,49.47 v4(210.43,49.59)
  BOTTOM w0.076: v4(210.43,49.59) 210.43,49.87 U34.H13
  BOTTOM w0.109: v1(128.76,7.08) 128.65,7.19 JKB2.15 128.65,10.15 127.68,11.12 v5(127.68,12.53)
KSO4: length 136.1
  IN4 w0.076: v1(126.71,5.52) 126.87,5.37 130.81,5.37 132.11,4.07 138.25,4.07 139.04,4.85 142.43,4.85 144.37,6.79 148.33,6.79 151.99,3.13 182.3,3.13 183.02,3.84 191.97,3.84 194.43,6.31 195.64,6.31 202.95,13.62 202.95,26.92 203.57,27.54 203.57,32.6 208.6,37.63 208.6,38.95 209.64,39.98 209.64,41.81 210.58,42.76 210.58,43.52 211.19,44.13 211.19,45 212.25,46.06 212.25,47.39 211.35,48.29 211.35,49.94 210.83,50.47 210.28,50.47 210.06,50.69 v4(210.06,51.12)
  BOTTOM w0.109: v2(122.93,3.36) 124.56,3.36 v1(126.71,5.52) 126.39,5.85 126.39,8.25 126.65,8.51 JKB2.19 ; U34.H10 210.06,51.15 v4(210.06,51.12)
KSO5: length 138.2
  IN4 w0.076: v4(210.41,52.28) 210.41,52.03 209.79,51.41 209.79,50.64 210.11,50.31 210.76,50.31 211.16,49.92 211.16,48.19 212.05,47.3 212.05,46.14 210.99,45.09 210.99,44.21 210.38,43.6 210.38,42.84 209.44,41.9 209.44,40.07 208.4,39.03 208.4,37.72 203.37,32.69 203.37,27.63 202.75,27 202.75,13.71 195.55,6.51 194.35,6.51 191.88,4.05 182.94,4.05 182.22,3.33 152.08,3.33 148.41,6.99 144.28,6.99 142.35,5.06 138.95,5.06 138.17,4.28 132.19,4.28 130.89,5.57 128.08,5.57 127.68,5.96 126.47,5.96 v1(126.03,5.52)
  BOTTOM w0.076: v4(210.41,52.28) 210.36,52.23 U34.H9
  BOTTOM w0.109: JKB2.20 126.15,5.64 v1(126.03,5.52) 124.96,4.45 v2(121.57,4.45)
KSO6: length 134.3
  IN4 w0.076: v1(127.53,7.01) 128.56,5.98 131.06,5.98 132.36,4.68 136.66,4.68 137.45,5.46 142.18,5.46 144.11,7.4 148.58,7.4 152.25,3.74 182.05,3.74 182.77,4.45 191.71,4.45 194.18,6.92 195.38,6.92 202.34,13.88 202.34,27.17 202.96,27.79 202.96,32.86 206.57,36.46 206.57,38.41 207.34,39.18 207.97,39.18 209.03,40.24 209.03,42.12 209.98,43.06 209.98,45.2 210.68,45.91 211.24,45.91 211.64,46.31 211.64,47.13 210.85,47.92 210.85,49.79 210.64,50.01 209.94,50.01 209.49,50.46 209.49,51.58 209.8,51.89 v4(209.8,52.31)
  BOTTOM w0.076: U34.G9 209.86,52.25 v4(209.8,52.31)
  BOTTOM w0.109: v1(127.53,7.01) 127.65,7.14 JKB2.17 127.65,10.18 127.07,10.77 126.43,10.77 125,12.2 v2(125,12.33)
KSO7: length 137.6
  IN4 w0.076: v1(126.93,7) 128.16,5.77 130.98,5.77 132.27,4.48 136.75,4.48 137.53,5.26 142.26,5.26 144.2,7.2 148.5,7.2 152.16,3.53 182.14,3.53 182.85,4.25 191.8,4.25 194.26,6.71 195.47,6.71 202.55,13.79 202.55,27.09 203.17,27.71 203.17,32.77 206.77,36.38 206.77,38.33 207.42,38.97 208.06,38.97 209.24,40.15 209.24,41.99 210.18,42.93 210.18,43.69 210.79,44.3 210.79,45.17 211.84,46.22 211.84,47.22 211,48.06 211,49.86 210.7,50.16 210,50.16 209.64,50.52 209.64,51.48 210.08,51.92 210.08,52.41 v4(209.77,52.71)
  BOTTOM w0.076: 209.8,52.71 210.1,52.41 210.1,51.69 U34.G10
  BOTTOM w0.109: 209.8,52.71 v4(209.77,52.71) ; v1(126.93,7) 126.93,7.93 127.15,8.15 JKB2.18 127.15,10.28 126.93,10.5 125.61,10.5 125.32,10.21 123.31,10.21 v2(123.07,9.97)
KSO8: length 128.9
  IN4 w0.076: v4(209.88,49.61) 210.13,49.86 210.54,49.86 210.7,49.7 210.7,47.79 211.44,47.05 211.44,46.39 211.15,46.11 210.59,46.11 209.77,45.29 209.77,43.16 208.83,42.22 208.83,40.32 207.89,39.38 207.25,39.38 206.37,38.49 206.37,36.55 202.76,32.94 202.76,27.88 202.14,27.26 202.14,13.96 195.3,7.12 194.09,7.12 191.63,4.66 182.68,4.66 181.97,3.94 152.33,3.94 148.67,7.6 144.03,7.6 142.09,5.67 137.36,5.67 136.58,4.89 132.44,4.89 131.15,6.18 128.96,6.18 v1(128.12,7.01)
  BOTTOM w0.109: v4(209.88,49.61) 209.86,49.63 U34.G13 ; v1(128.12,7.01) 128.15,7.04 JKB2.16 128.15,10.15 127.06,11.25 v2(126.45,11.25)
KSO9: length 120.6
  IN4 w0.076: v1(133.66,7.06) 134.41,6.31 135.99,6.31 136.77,7.09 141.5,7.09 143.44,9.03 150.1,9.03 153.77,5.36 180.18,5.36 180.89,6.08 191.04,6.08 193.5,8.54 194.71,8.54 198.62,12.46 198.62,16.06 200.01,17.45 200.01,21.25 200.32,21.56 200.32,32.54 204.95,37.16 204.95,39.08 206.71,40.85 206.71,41.94 206.95,42.18 206.95,42.96 207.74,43.75 207.74,44.9 208.12,45.28 208.12,46.2 209.14,47.22 209.14,47.37 209.38,47.61 209.38,48.07 v4(209.57,48.26)
  BOTTOM w0.076: U34.G12 210.1,50.2 210.1,49.82 210.15,49.77 210.15,48.57 209.83,48.26 v4(209.57,48.26)
  BOTTOM w0.109: v2(136.05,11.17) 134.03,11.17 133.15,10.29 JKB2.6 133.15,7.57 v1(133.66,7.06)
KSO10: length 118.6
  IN4 w0.076: v4(209.42,48.84) 209.35,48.84 209.02,48.52 209.02,47.83 208.73,47.54 208.73,47.39 207.71,46.37 207.71,45.79 206.55,44.62 206.55,42.35 206.3,42.11 206.3,41.02 204.54,39.25 204.54,37.33 199.92,32.71 199.92,21.73 199.6,21.42 199.6,20.72 198.21,19.33 198.21,12.63 194.54,8.95 193.33,8.95 190.87,6.49 180.72,6.49 180.01,5.77 153.93,5.77 150.27,9.43 143.27,9.43 141.34,7.5 136.6,7.5 135.82,6.71 135.21,6.71 v1(134.84,7.08)
  BOTTOM w0.076: U34.F13 209.25,49.84 209.25,49.01 v4(209.42,48.84)
  BOTTOM w0.109: v1(134.84,7.08) 134.15,7.77 JKB2.4 134.15,10.32 134.36,10.53 137.22,10.53 v2(137.8,11.11)
KSO11: length 121.5
  IN4 w0.076: v1(134.25,7.08) 134.82,6.51 135.9,6.51 136.69,7.29 141.42,7.29 143.36,9.23 150.19,9.23 153.85,5.57 180.09,5.57 180.81,6.28 190.96,6.28 193.42,8.75 194.62,8.75 198.42,12.54 198.42,19.24 199.81,20.63 199.81,21.33 200.12,21.64 200.12,32.63 204.74,37.25 204.74,39.17 206.51,40.93 206.51,42.02 206.75,42.27 206.75,44.53 207.92,45.7 207.92,46.29 208.93,47.3 208.93,47.45 209.18,47.69 209.18,48.29 209.44,48.56 209.69,48.56 v4(209.82,48.7)
  BOTTOM w0.076: U34.F12 209.36,50.44 209.6,50.2 209.6,49.27 209.82,49.04 v4(209.82,48.7)
  BOTTOM w0.109: v2(137.19,12.76) 136.72,12.29 136.72,11.16 136.33,10.77 134.25,10.77 133.65,10.17 JKB2.5 133.65,7.68 v1(134.25,7.08)
KSO12: length 131.6
  IN4 w0.076: v1(130.59,4.75) 131.67,3.67 138.42,3.67 139.2,4.45 142.6,4.45 144.54,6.38 148.16,6.38 151.82,2.72 182.47,2.72 183.19,3.44 192.14,3.44 194.6,5.9 195.8,5.9 203.98,14.08 203.98,32.43 209.01,37.46 209.01,38.78 210.05,39.82 210.05,40.16 210.83,40.93 210.83,42.42 210.99,42.59 210.99,43.35 211.6,43.96 211.6,44.83 212.65,45.89 212.65,47.81 212.9,48.05 212.9,48.97 212.58,49.28 212.58,49.72 212.1,50.2 211.31,50.2 210.76,50.74 v4(210.6,50.74)
  BOTTOM w0.076: v4(210.6,50.74) 210.54,50.69 209.79,50.69 209.36,51.12 U34.F10
  BOTTOM w0.109: v1(130.59,4.75) 130.87,5.02 130.87,8.66 130.65,8.87 JKB2.11 130.65,10.98 v2(130.89,11.22)
KSO13: length 125.6
  IN4 w0.076: v4(209.39,52.31) 208.81,51.72 208.81,51.39 208.98,51.21 208.98,50.95 208.95,50.91 208.95,49.91 209.29,49.56 209.66,49.19 210.01,49.19 210.24,48.95 210.24,48.32 209.78,47.86 209.78,47.44 209.54,47.2 209.54,47.05 208.55,46.06 208.55,45.04 208.15,44.64 208.15,43.18 207.81,42.85 207.81,40.75 207.46,40.4 206.83,40.4 205.35,38.92 205.35,37 205.24,36.88 201.75,33.39 201.75,30.15 201.12,29.53 201.12,15.68 199.03,13.58 199.03,12.29 194.88,8.14 193.67,8.14 191.21,5.67 182.26,5.67 181.54,4.96 153.6,4.96 149.93,8.62 143.61,8.62 141.67,6.68 136.94,6.68 136.16,5.9 133.57,5.9 v1(132.49,6.98)
  BOTTOM w0.076: U34.F9 209.36,52.27 v4(209.39,52.31)
  BOTTOM w0.109: v1(132.49,6.98) 132.15,7.32 JKB2.8 132.15,10.19 133.62,11.67 v2(133.62,12.73)
KSO14: length 124
  IN4 w0.076: v1(133.08,7.02) 133.99,6.1 136.07,6.1 136.86,6.89 141.59,6.89 143.52,8.82 150.02,8.82 153.68,5.16 181.46,5.16 182.17,5.88 191.12,5.88 193.59,8.34 194.79,8.34 198.82,12.37 198.82,13.67 200.92,15.76 200.92,29.61 201.54,30.23 201.54,33.47 205.15,37.08 205.15,39 206.75,40.6 207.38,40.6 207.61,40.83 207.61,42.93 207.94,43.26 207.94,44.81 208.32,45.19 208.32,46.12 209.34,47.14 209.34,47.28 209.58,47.52 209.58,47.87 210.09,48.38 210.09,48.89 209.94,49.04 209.6,49.04 208.67,49.96 v4(208.67,51.01)
  BOTTOM w0.076: U34.E10 208.86,51.22 208.67,51.04 v4(208.67,51.01)
  BOTTOM w0.109: v2(135.39,12.8) 134.26,11.67 134.02,11.67 132.65,10.3 JKB2.7 132.65,7.45 v1(133.08,7.02)
KSO15: length 124.9
  IN4 w0.076: v4(209.21,50.81) 209.21,49.86 209.73,49.34 210.07,49.34 210.39,49.02 210.39,48.26 209.99,47.85 209.99,47.32 209.75,47.07 209.75,46.97 208.96,46.18 208.96,43.5 208.02,42.56 208.02,40.66 207.55,40.19 206.92,40.19 205.56,38.83 205.56,36.91 201.95,33.3 201.95,30.07 201.33,29.44 201.33,14.3 194.96,7.93 193.76,7.93 191.29,5.47 182.35,5.47 181.63,4.75 152.67,4.75 149.01,8.42 143.69,8.42 141.76,6.48 137.02,6.48 136.24,5.7 133.16,5.7 v1(131.88,6.98)
  BOTTOM w0.076: v4(209.21,50.81) 209.11,50.7 208.52,50.7 208.37,50.85 208.37,51.09 208.6,51.31 208.6,51.36 208.6,51.36 208.6,51.69 U34.E9
  BOTTOM w0.109: v1(131.88,6.98) 131.65,7.21 JKB2.9 131.65,10.21 v2(132.64,11.21)
KSO16: length 137.5
  IN4 w0.076: v1(129.99,4.72) 130.56,4.16 130.65,4.16 131.34,3.46 138.51,3.46 139.29,4.25 142.68,4.25 144.62,6.18 148.08,6.18 151.74,2.52 182.56,2.52 183.27,3.23 192.22,3.23 194.68,5.7 195.89,5.7 204.18,13.99 204.18,32.32 209.35,37.49 209.35,37.74 210.27,38.66 210.27,40.09 211.03,40.85 211.03,42.34 211.19,42.5 211.19,43.26 211.8,43.87 211.8,44.75 212.86,45.8 212.86,47.7 213.11,47.95 213.11,49.03 212.81,49.34 212.81,49.78 212.24,50.35 211.41,50.35 v4(210.61,51.15)
  BOTTOM w0.076: U34.E8 208.87,52.44 209.11,52.2 209.11,51.77 209.19,51.7 209.52,51.7 209.61,51.61 209.61,51.13 209.89,50.84 210.21,50.84 210.52,51.15 v4(210.61,51.15)
  BOTTOM w0.109: v2(131.81,12.73) 131.81,11.2 131.15,10.54 JKB2.10 131.15,4.55 130.92,4.32 130.4,4.32 v1(129.99,4.72)
L_MIC1: length 15.7
  TOP w0.102: v1(16.2,6.12) 15.55,6.12 v2(15.33,6.33)
  IN1 w1.016: 15.26,5.85 13.86,5.85 11.89,3.88 11.89,3.46 10.99,2.56 3.74,2.56 3.3,3 JHP1.3
  vias: v1(16.17,5.48) v1(20.31,24.03) v1(20.52,24.58) v6(18.83,12.73) v6(19.47,12.73)
LCD_TEST: length 84.4
  IN2 w0.102: v1(139.92,65.03) 139.92,64.52 141.4,63.05 152.24,63.05 154.55,60.74 154.55,56.8 155.67,55.69 155.67,55.2 157.52,53.35 159.89,53.35 160.11,53.12 160.6,53.12 161.74,51.98 162.58,51.98 163.05,51.51 165.08,51.51 165.64,52.06 167.21,52.06 167.66,52.52 169,52.52 169.35,52.87 171.1,52.87 171.74,53.5 179.45,53.5 179.5,53.45 183.85,53.45 184.23,53.83 185.57,53.83 186.39,54.64 189.19,54.64 190.38,53.45 193.97,53.45 194.57,54.06 203.89,54.06 205.28,52.66 206.44,52.66 207.26,51.84 v3(207.26,51.16)
  IN4 w0.076: v3(207.26,51.16) 207.35,51.26 v4(207.64,51.26)
  BOTTOM w0.109: JLVDS2.42 138.15,66.32 138.32,66.14 139.65,66.14 140.1,65.69 140.1,65.21 v1(139.92,65.03) 140.16,64.79 v2(140.38,64.79) ; v4(207.64,51.26) 207.45,51.44 U34.B10
LDO_OUT: length 5
  TOP w0.102: v2(27.84,19.19) 27.68,19.35 CA45.2
  TOP w0.203: CA40.2 25.03,19.54 25.03,20.23 25.34,20.54 UA2.40
  TOP w0.254: CA45.2 26.36,19.24 CA40.2
LG_3V: length 16
  TOP w0.109: v6(192.6,37.37) 192.83,37.6 v2(193.15,37.6)
  IN2 w1.016: 193.94,45.28 196.82,45.28 197.94,44.17 197.94,39.86 196.64,38.57 v3(192.27,38.57) 191.99,38.29
  vias: v6(191.94,37.37) v6(192.65,44) v6(193.26,44.56)
LG_5V:
  vias: v2(188.93,38.92)
LID_SW_IN#: length 90.7
  TOP w0.109: U725.3 283.98,36.89 281.44,39.43 v5(280.84,39.43) 280.26,39.43 279.86,39.04 R11.2 279.06,39.04 278.5,39.59 C9.2 277.89,40.05 v1(277.89,39.43)
  IN2 w0.102: v1(216.4,55.72) 216.92,55.72 219.46,53.18 220.49,53.18 221.94,51.74 222.56,51.74 225.67,48.62 228.13,48.62 233.16,43.59 241.84,43.59 243.86,45.61 249.84,45.61 251.05,44.41 255.09,44.41 257.17,42.32 263.04,42.32 264.66,40.7 274.41,40.7 275.68,39.43 v1(277.89,39.43)
  BOTTOM w0.076: 213.7,57.15 212.97,57.15 212.11,56.28 212.11,55.77 212.18,55.7 212.6,55.7 U34.N2
  BOTTOM w0.109: RP21.2 213.81,58.33 214.05,58.09 214.05,57.5 213.7,57.15 ; v1(216.4,55.72) 216.4,55.99 215.99,56.4 213.99,56.4 213.61,56.02 213.61,55.66 213.39,55.44 U34.N2
LINE2-VREFO: length 17.4
  IN1 w0.508: v3(15.44,18.78) 15.44,18.58 15.26,18.4 v7(15.22,18.4)
  IN3 w0.508: v1(21.53,24.6) 21.53,24.31 20.92,23.69 20.92,21.85 18.87,19.79 16.4,19.79 15.44,18.83 v3(15.44,18.78)
  IN4 w0.508: v4(16.64,12.45) 16.64,13.46 15.97,14.13 15.97,14.71 15.06,15.63 15.06,18.19 15.44,18.58 v3(15.44,18.78)
  vias: v2(22.03,24.75)
LPC_AD0: length 110.6
  IN1 w0.076: v1(215.26,43.75) 214.88,44.13 214.64,44.13 214.19,43.68 213.56,43.68 213.34,43.47 211.71,43.47 211.21,42.96 209.21,42.96 208.9,42.65 206.01,42.65 205.45,43.21 204.87,43.21 204.51,42.86 204.03,42.86 195.42,34.25 195.42,30.19 196.74,28.87 196.74,28.09 197.41,27.41 v1(197.47,27.41)
  IN4 w0.076: v1(215.26,43.75) 216.08,43.75 216.52,44.18 216.52,45.01 217.1,45.6 217.1,48.11 216.58,48.63 216.58,51.36 214.23,53.7 213.82,53.7 213.2,54.33 v4(213.2,54.42)
  BOTTOM w0.109: v1(215.26,43.75) 215.1,43.59 212.24,43.59 211.77,44.06 U652.26 ; UCPU1.AU14 155.91,41.85 155.91,41.37 155.88,41.34 155.88,39.74 155.77,39.63 155.77,37.67 154.4,36.3 154.4,32.54 157.48,29.46 166.91,29.46 167.13,29.24 177.06,29.24 177.41,28.9 191.43,28.9 191.69,28.64 195.97,28.64 197.2,27.41 v1(197.47,27.41) 197.52,27.36 198.14,27.36 199.39,26.12 JDEBUG.5 ; U34.N4 213.17,54.44 v4(213.2,54.42)
LPC_AD1: length 109.3
  IN1 w0.076: v3(214.69,43.6) 214.56,43.48 213.64,43.48 213.42,43.26 211.8,43.26 211.29,42.76 209.29,42.76 208.99,42.45 205.48,42.45 205.4,42.38 203.84,42.38 197.15,35.69 197.15,31.53 196.56,30.95 196.56,29.33 196.94,28.95 196.94,28.41 197.35,28 v1(197.48,28)
  IN4 w0.076: v4(214.6,43.16) 214.62,43.19 214.62,43.54 v3(214.69,43.6) 214.69,43.79 215.06,44.15 215.44,44.15 215.55,44.04 215.99,44.04 216.31,44.36 216.31,45.1 216.9,45.68 216.9,48.02 216.38,48.54 216.38,51.27 214.1,53.55 213.68,53.55 212.9,54.33 212.06,54.33 211.94,54.21 211.88,54.21 211.87,54.2 211.86,54.2 211.71,54.04 211.71,54.04 211.65,53.98 211.65,53.7 v4(211.64,53.7)
  BOTTOM w0.102: UCPU1.AW12 156.31,40.84 156.06,40.58 156.06,39.67 155.97,39.58 155.97,39.28
  BOTTOM w0.109: v4(214.6,43.16) 214.57,43.19 210.99,43.19 209.82,44.36 U652.23 ; JDEBUG.4 199.26,27.36 198.62,28 v1(197.48,28) 197.02,28 196.14,28.88 191.79,28.88 191.52,29.15 177.5,29.15 177.16,29.48 167.23,29.48 167.01,29.7 157.57,29.7 154.63,32.64 154.63,36.27 155.97,37.61 155.97,39.28 ; v4(211.64,53.7) 211.4,53.94 U34.K5
LPC_AD2: length 110.8
  IN1 w0.076: v1(197.47,28.86) 196.77,29.56 196.77,30.86 197.35,31.45 197.35,35.6 203.92,42.17 205.49,42.17 205.56,42.25 209.07,42.25 209.38,42.55 211.38,42.55 211.88,43.06 213.51,43.06 213.66,43.21 215.05,43.21 215.42,42.83 v1(215.42,42.65)
  IN4 w0.076: v1(215.42,42.65) 215.74,42.65 217.51,44.42 217.51,48.28 216.99,48.8 216.99,51.53 214.45,54.06 214.06,54.06 v4(213.98,54.15)
  BOTTOM w0.076: v4(213.98,54.15) 213.43,54.69 212.61,54.69 212.56,54.65
  BOTTOM w0.109: UCPU1.AY12 156.34,39.4 156.17,39.23 156.17,37.54 154.87,36.25 154.87,32.74 157.67,29.94 167.11,29.94 167.31,29.73 177.27,29.73 177.62,29.38 191.61,29.38 191.88,29.11 196.34,29.11 196.59,28.86 v1(197.47,28.86) 197.71,28.61 JDEBUG.3 ; v1(215.42,42.65) 215.28,42.65 v2(214.96,42.33) 214.62,41.99 209.44,41.99 207.87,43.57 U652.20
  BOTTOM w0.254: U34.M4 212.56,54.65
LPC_AD3: length 111.7
  IN1 w0.076: v1(197.48,29.75) 196.97,30.26 196.97,30.78 197.55,31.36 197.55,35.52 204.01,41.97 205.57,41.97 205.65,42.05 209.16,42.05 209.46,42.35 212.02,42.35 212.15,42.22 212.81,42.22 213.25,42.67 213.51,42.67 213.82,42.99 214.76,42.99 215,42.74 215,42.5 215.4,42.11 215.4,42.11 v1(215.44,42.07)
  IN4 w0.076: v1(215.44,42.07) 215.47,42.07 215.51,42.11 215.53,42.11 217.71,44.29 217.71,48.36 217.19,48.88 217.19,51.61 214.56,54.24 214.29,54.24 214.12,54.42 213.91,54.42 213.35,54.97 v4(213.2,54.97)
  BOTTOM w0.109: UCPU1.AW11 157,40.84 156.63,40.46 156.63,39.43 156.36,39.15 156.36,37.47 155.11,36.22 155.11,32.84 157.77,30.17 167.2,30.17 167.41,29.97 177.37,29.97 177.71,29.62 191.71,29.62 191.98,29.35 197.08,29.35 v1(197.48,29.75) 199.08,29.75 199.19,29.87 JDEBUG.2 ; U652.17 205.92,44.96 209.11,41.76 215.13,41.76 v1(215.44,42.07)
  BOTTOM w0.254: v4(213.2,54.97) 213.17,54.94 U34.N3
LPC_FRAME#: length 107.4
  IN1 w0.076: v1(214.47,42.5) 214.41,42.44 213.31,42.44 212.89,42.02 212.06,42.02 211.94,42.15 209.54,42.15 209.24,41.84 205.73,41.84 205.66,41.77 204.09,41.77 197.76,35.43 197.76,30.62 v1(197.48,30.34)
  IN4 w0.076: v1(214.47,42.5) 214.65,42.5 215.31,43.16 215.89,43.16 216.72,43.99 216.72,44.93 217.3,45.51 217.3,48.19 216.78,48.71 216.78,51.44 214.37,53.86 213.89,53.86 213.52,54.22 213.52,54.5 213.33,54.69 212.97,54.69 212.79,54.52 211.83,54.52 v4(211.78,54.47)
  BOTTOM w0.102: UCPU1.AV12 156.63,41.16 157.17,41.16 157.37,40.96 157.37,40.69 157.15,40.47 156.94,40.47 156.81,40.34 156.81,39.35 156.72,39.26 156.72,39.26 156.57,39.11 156.57,39.11 156.56,39.1 156.56,38.9
  BOTTOM w0.109: v1(214.47,42.5) 214.39,42.43 211.22,42.43 209.17,44.48 U652.22 ; v4(211.78,54.47) 211.76,54.44 U34.K4 ; JDEBUG.1 199.27,31.12 198.49,30.34 v1(197.48,30.34) 196.87,30.34 196.12,29.59 192.08,29.59 191.81,29.86 177.81,29.86 177.46,30.2 167.51,30.2 167.3,30.41 157.87,30.41 155.34,32.93 155.34,36.19 156.56,37.41 156.56,38.9
LPCPD#: length 4.2
  TOP w0.109: v2(212.81,43.62) v1(212.81,44.33) 212.54,44.33 212.07,44.8 R1239.2 R1238.2
  BOTTOM w0.109: v1(212.81,44.33) 213.07,44.59 U652.28
LX_3V: length 8.8
  IN1 w1.016: 195.67,43.07 195.67,39.79 194.69,38.8 194.69,36.08 v6(193.69,35.09)
  vias: v2(193.22,34.78) v6(193.69,34.45) v6(195.65,44.05) v6(196.3,44.05)
LX_5V: length 1
  TOP w0.109: v6(185.05,40.17) 185.05,39.38 v2(185.2,39.23)
  vias: v6(184.41,40.17) v6(187.52,34.83) v6(187.52,34.2)
LX_DGPU:
  vias: v2(99.83,50.59)
M_CLK_A_DDR0: length 136.2
  TOP w0.076: v1(123.27,25.08) 122.99,24.8 122.82,24.8 122.49,25.14 RD75.1
  IN1 w0.076: v3(110.4,22.43) 110.63,22.2 110.83,22.2 111.34,21.68 111.34,21.37 111.74,20.97 113.83,20.97 114.42,21.56 115.73,21.56 116.3,20.98 118.98,20.98 119.18,21.19 119.95,21.19 120.86,22.09 120.86,27.75 121.08,27.97 121.95,27.97 122.18,27.75 122.18,24.88 122.28,24.78 122.97,24.78 v1(123.27,25.08) 123.54,24.81 123.69,24.81 123.82,24.94 123.82,27.61 124.02,27.82 124.56,27.82 124.78,27.6 124.78,23.78 124.65,23.65 124.36,23.65 124.25,23.54 124.25,23.37 124.36,23.26 124.65,23.26 124.78,23.13 124.78,21.63 124.91,21.5 125.59,21.5 125.8,21.71 126.43,21.71 127.12,21.02 128.35,21.02 128.48,21.15 128.48,21.62 128.7,21.85 129.04,21.85 129.26,21.62 129.26,21.1 129.34,21.02 129.48,21.02 130.62,22.16 131.12,22.16 131.75,22.8 134.17,22.8 v3(134.39,23.01)
  IN3 w0.206: v1(123.27,25.08) 123.25,25.08 123.04,24.87 122.79,24.87 122.67,24.99 122.67,25.75 122.38,26.05 122.11,26.05 121.99,26.17 121.99,26.56 122.11,26.67 122.95,26.67 123.25,26.97 123.25,27.8 122.95,28.1 122.44,28.1 122.32,28.22 122.32,30.18 122.07,30.44 121.75,30.44 121.63,30.55 121.63,30.86 121.75,30.98 122.02,30.98 122.32,31.28 122.32,31.91 122.02,32.21 120.7,32.21 120.58,32.33 120.58,32.72 120.7,32.84 121.93,32.84 122.25,33.16 122.25,34.52 122.37,34.63 122.72,34.63 122.84,34.52 122.84,33.18 123.15,32.87 123.96,32.87 124.3,33.21 124.79,33.21 125.58,32.42 129.21,32.42 129.52,32.73 130.01,32.73 131.04,31.7 132.05,31.7 132.26,31.92 133.1,31.92 133.31,31.7 135.63,31.7 136.81,32.88 138.02,32.88 138.9,33.76 139.99,33.76 140.69,34.46 141.46,34.46 141.8,34.79 141.8,35.83 142.1,36.14 142.1,37.27 142.35,37.52 142.35,38.12 142.05,38.42 141.76,38.42 v1(141.52,38.66)
  IN4 w0.076: v4(102.26,21.12) 102.57,20.82 102.65,20.82 103.24,21.41 105.32,21.41 106.19,22.28 106.51,22.28 106.76,22.53 107.91,22.53 108.03,22.4 108.23,22.4 108.44,22.2 110.17,22.2 v3(110.4,22.43) 110.64,22.19 111.05,22.19 111.27,22.41 111.27,23.11 110.94,23.44 110.94,24.19 111.16,24.41 111.53,24.41 111.75,24.19 111.75,23.88 112.13,23.5 112.13,23.12 112.59,22.67 112.59,21.72 112.71,21.6 112.71,21.33 112.48,21.11 112.48,20.99 112.53,20.94 113.33,20.94 113.44,20.83 113.53,20.83 v4(113.82,21.12) ; v4(126.9,21.1) 127.23,20.77 127.32,20.77 128.4,21.84 129.14,21.84 129.49,21.49 129.99,21.49 130.65,22.15 131.09,22.15 131.93,22.99 132.28,22.99 132.48,22.79 132.88,22.79 133.08,22.99 133.43,22.99 133.65,22.77 134.15,22.77 v3(134.39,23.01) 134.63,22.77 135.44,22.77 135.54,22.87 135.54,24.42 135.77,24.64 136.08,24.64 136.3,24.42 136.3,21.79 136.39,21.71 137.17,21.71 138.06,20.82 138.15,20.82 v4(138.46,21.12)
  BOTTOM w0.076: v1(141.52,38.66) 141.52,38.65 141.23,38.36 140.86,38.36 140.75,38.47 140.75,41.65 140.9,41.8 140.96,41.8 141.04,41.72 UCPU1.AV37
  BOTTOM w0.185: v4(113.82,21.12) 114.21,20.73 UD2.J7 ; UD1.J7 102.66,20.73 v4(102.26,21.12) ; UD5.J7 138.85,20.89 138.63,21.12 v4(138.46,21.12) ; UD4.J7 127.28,20.72 v4(126.9,21.1)
M_CLK_A_DDR#0: length 136.5
  TOP w0.076: v1(123.27,24.37) 123.01,24.63 122.85,24.63 122.52,24.3 RD77.1
  IN1 w0.076: v3(110.4,21.8) 110.64,22.03 110.76,22.03 111.18,21.61 111.18,21.3 111.67,20.81 113.9,20.81 114.49,21.39 115.66,21.39 116.23,20.82 119.05,20.82 119.25,21.02 120.02,21.02 121.02,22.02 121.02,27.68 121.15,27.8 121.88,27.8 122.01,27.68 122.01,24.82 122.21,24.62 123.03,24.62 v1(123.27,24.37) 123.54,24.65 123.85,24.65 123.98,24.77 123.98,27.54 124.09,27.65 124.49,27.65 124.61,27.52 124.61,23.85 124.58,23.82 124.29,23.82 124.08,23.6 124.08,23.3 124.29,23.09 124.58,23.09 124.61,23.06 124.61,21.54 124.82,21.34 125.66,21.34 125.87,21.54 126.36,21.54 127.05,20.86 128.42,20.86 128.64,21.08 128.64,21.56 128.77,21.68 128.97,21.68 129.1,21.56 129.1,21.03 129.27,20.86 129.55,20.86 130.69,22 131.19,22 131.82,22.63 134.13,22.63 v3(134.39,22.38)
  IN3 w0.206: v1(123.27,24.37) 123.08,24.56 122.67,24.56 122.37,24.86 122.37,25.63 122.25,25.75 121.98,25.75 121.68,26.04 121.68,26.68 121.98,26.98 122.82,26.98 122.94,27.1 122.94,27.68 122.82,27.8 122.31,27.8 122.01,28.1 122.01,30.06 121.94,30.13 121.62,30.13 121.33,30.43 121.33,30.99 121.62,31.28 121.89,31.28 122.01,31.4 122.01,31.79 121.89,31.91 120.57,31.91 120.27,32.2 120.27,32.85 120.57,33.15 121.8,33.15 121.94,33.29 121.94,34.64 122.24,34.94 122.85,34.94 123.15,34.64 123.15,33.3 123.27,33.18 123.83,33.18 124.17,33.52 124.92,33.52 125.71,32.73 129.09,32.73 129.39,33.04 130.13,33.04 131.16,32.01 131.92,32.01 132.14,32.23 133.22,32.23 133.44,32.01 135.51,32.01 136.69,33.19 137.89,33.19 138.77,34.06 139.86,34.06 140.56,34.76 141.33,34.76 141.49,34.92 141.49,35.96 141.79,36.26 141.79,37.39 142.05,37.65 142.05,37.99 141.92,38.12 141.67,38.12 141.52,37.97 v1(141.52,37.95)
  IN4 w0.076: v4(126.89,20.32) 127.17,20.6 127.39,20.6 128.46,21.68 129.07,21.68 129.42,21.33 130.06,21.33 130.72,21.98 131.16,21.98 132,22.83 132.21,22.83 132.42,22.62 132.95,22.62 133.15,22.83 133.36,22.83 133.58,22.61 134.16,22.61 v3(134.39,22.38) 134.61,22.6 135.51,22.6 135.71,22.8 135.71,24.35 135.84,24.47 136.01,24.47 136.14,24.35 136.14,21.73 136.32,21.54 137.1,21.54 137.99,20.65 138.31,20.65 138.46,20.5 v4(138.46,20.33) ; v4(102.26,20.32) 102.59,20.65 102.72,20.65 103.31,21.24 105.39,21.24 106.23,22.09 106.55,22.09 106.82,22.36 107.84,22.36 107.96,22.24 108.16,22.24 108.37,22.03 110.17,22.03 v3(110.4,21.8) 110.63,22.03 111.12,22.03 111.44,22.34 111.44,23.18 111.1,23.51 111.1,24.12 111.23,24.24 111.46,24.24 111.58,24.12 111.58,23.82 111.96,23.43 111.96,23.05 112.42,22.6 112.42,21.65 112.55,21.53 112.55,21.4 112.32,21.17 112.32,20.92 112.46,20.78 113.26,20.78 113.37,20.66 113.48,20.66 v4(113.82,20.32)
  BOTTOM w0.076: v1(141.52,37.95) 141.52,38.04 141.36,38.2 140.79,38.2 140.59,38.4 140.59,41.71 140.99,42.1 UCPU1.AU37
  BOTTOM w0.185: UD5.K7 138.85,19.94 v4(138.46,20.33) ; v4(102.26,20.32) 102.66,19.93 UD1.K7 ; UD2.K7 114.21,19.93 v4(113.82,20.32) ; v4(126.89,20.32) 127.28,19.92 UD4.K7
M_CLK_B_DDR0: length 155.9
  TOP w0.076: RD76.1 170.12,24.12 170.36,24.12 v1(170.77,24.53)
  IN1 w0.076: v3(181.56,23.81) 181.29,23.54 180.91,23.54 180.83,23.62 180.83,23.93 180.45,24.31 180.45,25.67 180.54,25.75 180.69,25.75 181.01,25.44 181.01,25.09 181.19,24.9 181.65,24.9 181.86,25.1 181.86,25.64 180.51,26.98 179.98,26.98 179.69,26.69 179.69,22.45 179.61,22.38 179.33,22.38 179.2,22.51 178.54,22.51 178.32,22.29 177.97,22.29 177.19,21.52 173.97,21.52 171.34,24.15 171.15,24.15 v1(170.77,24.53) 170.34,24.1 170.25,24.1 170.13,24.22 170.13,24.99 169.92,25.2 169.62,25.2 169.41,24.99 169.41,24.22 169.34,24.15 169.05,24.15 168.98,24.21 168.98,26.45 168.77,26.66 168.48,26.66 168.27,26.45 168.27,24.27 167.05,23.05 167.05,21.77 166.57,21.29 164.56,21.29 164.32,21.05 160.39,21.05 159.67,21.77 159.21,21.77 158.05,22.93 157.15,22.93 v3(156.87,23.2)
  IN2 w0.206: v1(170.77,24.53) 170.77,24.15 170.64,24.02 170.46,24.02 170.01,24.48 170.01,26.61 169.71,26.9 169.13,26.9 169.01,27.03 169.01,27.46 169.13,27.59 170.73,27.59 171.04,27.89 171.04,28.66 170.73,28.97 169.03,28.97 168.9,29.1 168.9,29.52 169.03,29.65 170.69,29.65 171,29.96 171,31.59 170.36,32.23 169.61,32.23 169.31,31.92 169.31,31.2 169.18,31.07 168.65,31.07 168.52,31.2 168.52,31.96 168.22,32.27 167.43,32.27 167.12,31.96 167.12,31.26 166.93,31.07 166.53,31.07 166.34,31.26 166.34,32.66 165.97,33.03 165.23,33.03 164.86,32.66 164.86,31.01 164.67,30.82 164.34,30.82 164.15,31.01 164.15,32.61 163.78,32.98 163.18,32.98 162.8,32.61 162.8,31.8 162.61,31.61 162.26,31.61 162.07,31.8 162.07,32.99 161.7,33.36 161.07,33.36 160.7,32.99 160.7,31.74 160.57,31.61 160.06,31.61 159.94,31.74 159.94,33.31 159.56,33.68 155.14,33.68 154.86,33.97 153.68,33.97 153.39,33.68 151.8,33.68 150.17,35.32 146.38,35.32 145.68,36.03 143.57,36.03 142.99,36.6 142.5,36.6 141.74,37.36 140.98,37.36 140.88,37.46 140.88,42.3 140.52,42.66 140,42.66 139.78,42.88 139.78,43.55 139.7,43.63 139.7,44.24 140,44.53 140.22,44.53 140.44,44.32 v1(140.44,44.27)
  IN4 w0.076: v4(161.06,21.12) 160.72,20.78 160.63,20.78 160.18,21.24 159.98,21.24 159.87,21.35 159.87,22.09 159.9,22.12 159.9,22.54 159.87,22.57 159.87,22.9 159.9,22.93 159.9,23.39 159.38,23.9 158.84,23.9 158.52,23.59 158.52,22.31 158.47,22.26 158,22.26 157.88,22.38 157.88,22.74 157.65,22.98 157.1,22.98 v3(156.87,23.2) 156.62,22.96 156.22,22.96 155.69,22.42 155.02,22.42 154.72,22.73 154.24,22.73 153.06,21.55 151.38,21.55 151.27,21.66 150.81,21.66 149.99,20.83 149.77,20.83 v4(149.49,21.11) ; v4(185.7,21.12) 185.4,20.82 185.22,20.82 184.35,21.69 183.74,21.69 183.47,21.96 183.47,23.31 183.55,23.39 183.55,24.68 183.33,24.91 182.94,24.91 182.72,24.68 182.72,23.71 182.59,23.58 181.79,23.58 v3(181.56,23.81) 181.29,23.54 180.97,23.54 180.55,23.12 179.26,23.12 178.61,22.48 178.31,22.18 177.92,22.18 177.28,21.53 175.28,21.53 174.58,20.83 174.27,20.83 174.14,20.97 v4(174.14,21.12)
  BOTTOM w0.076: UCPU1.AN38 140.83,44.34 140.75,44.27 v1(140.44,44.27)
  BOTTOM w0.185: v4(185.7,21.12) 186.1,20.73 UD10.J7 ; v4(174.14,21.12) 174.14,21.12 UD9.J7 ; v4(149.49,21.11) 149.88,20.72 UD6.J7 ; UD7.J7 161.46,20.73 v4(161.06,21.12)
M_CLK_B_DDR#0: length 156.3
  TOP w0.076: v1(170.76,23.57) 170.42,23.92 170.2,23.92 RD78.1
  IN1 w0.076: v3(156.85,22.57) 157.04,22.76 157.99,22.76 159.14,21.61 159.6,21.61 160.32,20.88 164.38,20.88 164.63,21.13 166.64,21.13 167.21,21.7 167.21,22.98 168.44,24.2 168.44,26.38 168.55,26.5 168.71,26.5 168.82,26.38 168.82,24.14 168.98,23.98 169.41,23.98 169.58,24.16 169.58,24.92 169.69,25.04 169.85,25.04 169.96,24.92 169.96,24.16 170.18,23.94 170.34,23.94 170.41,23.94 v1(170.76,23.57) 171.17,23.98 171.27,23.98 173.9,21.35 177.26,21.35 178.04,22.13 178.39,22.13 178.61,22.34 179.13,22.34 179.26,22.21 179.68,22.21 179.85,22.39 179.85,26.62 180.05,26.82 180.44,26.82 181.69,25.57 181.69,25.17 181.59,25.07 181.26,25.07 181.17,25.15 181.17,25.51 180.76,25.92 180.47,25.92 180.28,25.73 180.28,24.24 180.66,23.86 180.66,23.55 180.84,23.37 181.36,23.37 v3(181.56,23.17)
  IN2 w0.206: v1(140.43,44.93) 140.34,44.84 139.87,44.84 139.4,44.36 139.4,43.5 139.47,43.42 139.47,42.75 139.87,42.35 140.39,42.35 140.57,42.17 140.57,37.33 140.85,37.05 141.61,37.05 142.37,36.3 142.86,36.3 143.44,35.72 145.55,35.72 146.26,35.01 150.04,35.01 151.68,33.38 153.52,33.38 153.81,33.66 154.73,33.66 155.02,33.38 159.44,33.38 159.63,33.18 159.63,31.61 159.94,31.31 160.7,31.31 161.01,31.61 161.01,32.86 161.2,33.05 161.57,33.05 161.76,32.86 161.76,31.67 162.13,31.3 162.74,31.3 163.11,31.67 163.11,32.48 163.3,32.67 163.66,32.67 163.85,32.48 163.85,30.88 164.22,30.51 164.8,30.51 165.17,30.88 165.17,32.53 165.36,32.72 165.84,32.72 166.03,32.53 166.03,31.14 166.4,30.77 167.06,30.77 167.43,31.14 167.43,31.83 167.56,31.96 168.09,31.96 168.22,31.83 168.22,31.07 168.52,30.77 169.31,30.77 169.61,31.07 169.61,31.8 169.74,31.92 170.23,31.92 170.69,31.47 170.69,30.08 170.56,29.96 168.9,29.96 168.59,29.65 168.59,28.97 168.9,28.66 170.6,28.66 170.73,28.53 170.73,28.02 170.6,27.9 169.01,27.9 168.7,27.59 168.7,26.9 169.01,26.59 169.59,26.59 169.7,26.48 169.7,24.35 170.34,23.71 170.63,23.71 v1(170.76,23.57)
  IN4 w0.076: v4(174.13,20.32) 174.13,20.47 174.33,20.67 174.65,20.67 175.35,21.37 177.34,21.37 177.99,22.01 178.38,22.01 178.68,22.31 178.68,22.31 179.33,22.95 180.61,22.95 181.03,23.37 181.36,23.37 v3(181.56,23.17) 181.81,23.42 182.66,23.42 182.88,23.64 182.88,24.61 183.01,24.74 183.26,24.74 183.39,24.61 183.39,23.46 183.3,23.38 183.3,21.89 183.67,21.52 184.28,21.52 185.15,20.65 185.38,20.65 v4(185.71,20.32) ; v4(161.04,20.32) 160.75,20.62 160.56,20.62 160.11,21.07 159.91,21.07 159.71,21.28 159.71,22.16 159.73,22.19 159.73,22.47 159.7,22.5 159.7,22.97 159.73,23 159.73,23.32 159.31,23.74 158.91,23.74 158.69,23.52 158.69,22.24 158.54,22.09 157.93,22.09 157.71,22.31 157.71,22.68 157.58,22.81 157.09,22.81 v3(156.85,22.57) 156.63,22.79 156.29,22.79 155.76,22.26 154.95,22.26 154.65,22.56 154.31,22.56 153.13,21.38 151.31,21.38 151.2,21.49 150.88,21.49 150.06,20.67 149.79,20.67 149.5,20.38 v4(149.5,20.32)
  BOTTOM w0.076: v1(140.43,44.93) 140.75,45.25 UCPU1.AM38
  BOTTOM w0.185: UD7.K7 161.44,19.92 v4(161.04,20.32) ; UD6.K7 149.9,19.93 v4(149.5,20.32) ; v4(185.71,20.32) 186.1,19.94 UD10.K7 ; UD9.K7 174.14,20.32 v4(174.13,20.32)
M_ODT0: length 62.6
  TOP w0.076: v1(108.13,20.66) 108.45,20.35 108.45,20.16 108.91,19.7 RD73.1
  IN1 w0.076: v3(139.08,20.51) 139.07,20.5 139.07,20.23 138.38,19.55 136.77,19.55 135.27,21.05 133.45,21.05 132.29,19.88 130.43,19.88 130.18,19.64 125.59,19.64 124.41,20.82 123.41,20.82 122.93,20.34 119.76,20.34 118.66,19.23 116.66,19.23 115.47,20.42 v3(115.18,20.42)
  IN4 w0.076: v4(119.57,20.35) 119.57,20.68 119.45,20.79 118.13,20.79 117.85,21.07 116.96,21.07 116.31,20.42 v3(115.18,20.42) 115.18,20.42 114.54,20.42 113.94,19.83 111.38,19.83 110.61,20.6 110.61,20.86 110.5,20.96 109.98,20.96 109.69,20.67 109.4,20.67 109.39,20.69 108.16,20.69 v1(108.13,20.66) ; v4(144.14,20.33) 143.73,20.74 140.69,20.74 140.67,20.77 140.67,21.17 140.59,21.25 140.39,21.25 140.26,21.12 140.26,20.61 140.19,20.54 139.93,20.54 139.83,20.64 139.83,21.17 139.7,21.3 139.47,21.3 139.37,21.2 139.37,20.82 139.07,20.51 v3(139.08,20.51) 139.07,20.5 139.07,20.32 138.65,19.9 136.02,19.9 135.62,20.31 135.01,20.31 134.54,20.77 132.98,20.77 v4(132.81,20.59)
  BOTTOM w0.076: UD5.K1 143.72,19.92 v4(144.14,20.33) 143.75,20.72 UD5.J1 ; UD1.J1 107.49,20.76 108.04,20.76 v1(108.13,20.66) 108.13,20.6 107.46,19.92 UD1.K1 ; UD4.K1 132.14,19.92 v4(132.81,20.59) 132.75,20.65 132.17,20.65 UD4.J1 ; UD2.K1 119.14,19.92 v4(119.57,20.35) 119.19,20.72 UD2.J1
M_ODT2: length 66.5
  TOP w0.216: v2(195.59,20.1) 195.36,19.87 RD74.1 192.3,19.87 191.83,20.34 v6(191.28,20.34)
  IN1 w0.076: v3(162.65,20.08) 163.27,19.46 165.95,19.46 166.58,20.1 167.1,20.1 167.66,20.65 167.85,20.65 168.61,21.42 171.18,21.42 172.86,19.74 175.04,19.74 175.65,20.35 177.5,20.35 177.9,20.76 179.17,20.76 179.35,20.93 181.26,20.93 181.5,20.69 181.5,20.42 181.84,20.08 182.41,20.08 182.48,20.02 183.07,20.02 183.31,19.78 185.86,19.78 186.28,20.19 186.28,20.4 186.34,20.45 v3(186.34,20.54)
  IN4 w0.076: v4(155.34,20.67) 155.54,20.87 156.61,20.87 156.82,20.66 157.87,20.66 158.65,19.88 161.2,19.88 161.76,20.44 162.3,20.44 v3(162.65,20.08) 163.64,21.07 166.03,21.07 v4(166.81,20.29) ; v6(191.28,20.34) 190.88,20.74 188.37,20.74 188.29,20.82 188.29,21.17 188.19,21.27 188.04,21.27 187.94,21.17 187.94,20.66 187.82,20.54 187.65,20.54 187.53,20.66 187.53,21.45 187.4,21.58 187.23,21.58 187.1,21.45 187.1,20.89 186.95,20.74 186.54,20.74 v3(186.34,20.54) 186.34,20.45 186.28,20.4 186.28,20.29 185.88,19.89 183.28,19.89 183.02,20.14 183.02,20.68 182.68,21.02 180.94,21.02 180.61,20.69 180.36,20.69 v4(180.27,20.78)
  BOTTOM w0.076: UD6.J1 154.71,20.73 155.29,20.73 v4(155.34,20.67) 154.7,20.03 UD6.K1 ; UD10.J1 v6(191.28,20.34) 190.9,19.96 UD10.K1 ; UD7.J1 166.36,20.72 166.79,20.29 ; 166.79,20.29 166.42,19.92 UD7.K1 ; 166.79,20.29 v4(166.81,20.29) ; UD9.K1 179.65,19.92 180.27,20.54 v4(180.27,20.78) 180.21,20.72 UD9.J1
MAG_DRDY: length 128.1
  TOP w0.076: v1(251.2,64.45) 250.7,64.45 250.25,63.99 250.25,63.81 250.01,63.58 249.94,63.58 249.94,63.58 249.74,63.58 249.6,63.44 249.6,63.24 249.44,63.08 249.22,63.08 249.08,62.94 249.08,62.74 249.08,62.74 248.93,62.58 248.59,62.58 U636.E5
  IN2 w0.102: v1(251.2,64.45) 251.28,64.37 251.28,63.44 250.86,63.03 250.37,63.03 249.99,63.41 248.5,63.41 246.84,65.06 244.16,65.06 243.76,64.65 237.22,64.65 236.15,65.72 222.41,65.72 222.06,65.38 217.65,65.38 215.55,67.47 209.25,67.47 208.42,66.64 200.58,66.64 199.75,67.47 195.17,67.47 193.06,69.58 181.57,69.58 181.17,69.98 169.87,69.98 169.4,69.5 153.36,69.5 153.31,69.45 137.22,69.45 135.88,68.12 v3(135.88,67.17)
  IN4 w0.076: v3(135.88,67.17) 135.88,67.53 v4(135.67,67.74)
  BOTTOM w0.109: JLVDS2.37 135.65,67.72 v4(135.67,67.74)
MEM_CONFIG0: length 14.9
  IN4 w0.076: v4(160.56,42.79) 160.56,42.26 160.83,41.99 160.83,41.82 161.66,40.98 166.1,40.98 166.86,40.22 v4(167.28,40.22)
  BOTTOM w0.109: RH303.1 RH316.2 171.14,36.56 170.72,36.98 169.83,36.98 167.28,39.53 T286.1 v4(167.28,40.22)
MEM_CONFIG1: length 11.8
  TOP w0.109: v7(169.46,53.51) 169.28,53.34 169.28,53.07 T287.1 169.73,52.94 169.89,53.11 170.58,53.11 RH315.2 170.67,53.42 RH180.1
  IN1 w0.076: v3(162.55,52.94) 165.98,52.94 166.69,53.65 169.32,53.65 v7(169.46,53.51)
  IN4 w0.076: v3(162.55,52.94) 161.87,52.94 v4(161.84,52.97)
  BOTTOM w0.109: v4(161.84,52.97) 161.51,53.3 UCPU1.U4
MEM_CONFIG2: length 15.3
  TOP w0.109: RH314.2 RH271.1 170.69,52.55 170.55,52.69 170.21,52.69 v7(170.15,52.75) 169.79,52.4 v2(169.79,51.67)
  IN1 w0.076: v7(170.15,52.75) 169.98,52.59 167.79,52.59 167.72,52.52 164.34,52.52 163,51.18 163,50.74 162.62,50.36 160.54,50.36 160.33,50.57 160.14,50.57 160.13,50.58 159.89,50.58 v3(159.78,50.68)
  IN4 w0.076: v3(159.78,50.68) 160.09,50.68 v4(160.17,50.76)
MEM_TEMP0: length 74.6
  IN4 w0.076: v4(202.23,45.6) 202.02,45.4 202.02,43.4 200.68,42.05 200.68,38.99 195.47,33.78 195.47,27.44 v4(194.99,26.96)
  BOTTOM w0.076: 206.7,49.54 206.6,49.64 206.6,50.1 206.7,50.2 207.1,50.2 207.17,50.13
  BOTTOM w0.109: v4(202.23,45.6) 203.42,45.6 204.51,46.69 205.2,46.69 C1245.1 206.7,48.19 206.7,49.54 ; v4(194.99,26.96) 193.01,26.96 192.42,27.54 191.33,27.54 190.87,28 183.48,28 183.32,27.84 176.91,27.84 176.65,28.1 166.78,28.1 166.47,28.41 157.04,28.41 v2(154.58,30.87) 154.22,31.22 R940.2 R946.1
  BOTTOM w0.254: U34.B13 207.17,50.13
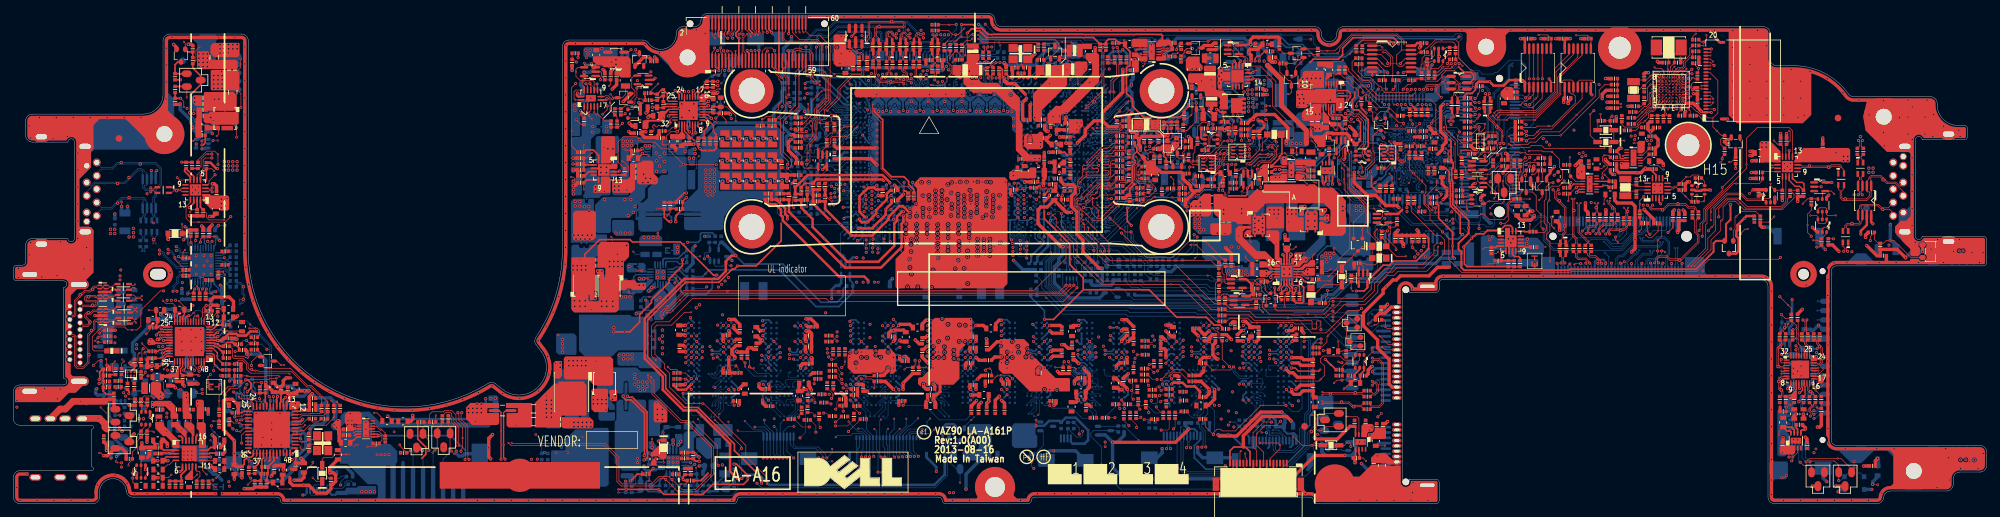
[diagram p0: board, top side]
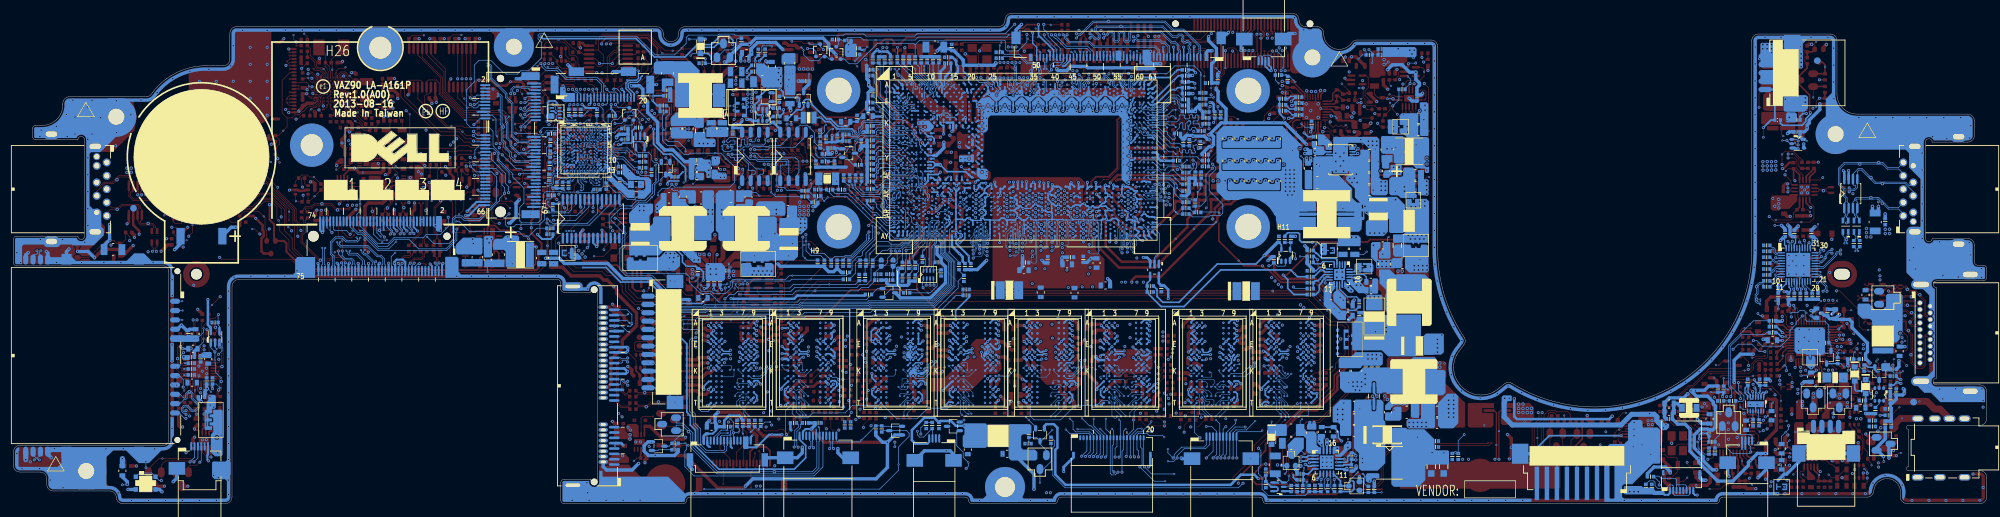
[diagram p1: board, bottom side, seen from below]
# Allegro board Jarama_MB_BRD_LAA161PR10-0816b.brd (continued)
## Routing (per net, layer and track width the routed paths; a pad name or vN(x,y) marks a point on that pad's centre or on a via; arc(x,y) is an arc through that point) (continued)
MIC2-VREFO-L: length 18.9
  IN3 w0.508: v6(29.28,21.52) 29.28,20.13 28.39,19.24 22.17,19.24 19.27,16.34 18.46,16.34 17.57,15.45 17.05,15.45 16.98,15.38 15.85,15.38 15.13,14.66 v3(15.06,14.66)
  IN4 w0.508: v4(15.18,14.21) 15.18,14.54 v3(15.06,14.66)
  BOTTOM w0.102: v6(29.28,21.52) v2(29.28,22.06)
MIC2-VREFO-R: length 14.6
  TOP w0.102: v1(14.03,20.75) 14.03,20.77 13.91,20.89 13.91,21.62 v2(13.87,21.66)
  TOP w0.508: v1(14.03,20.75) 14.37,20.4 RA48.1
  IN4 w0.508: v1(14.03,20.75) 14.14,20.63 16.47,20.63 16.68,20.42 17.83,20.42 19.82,22.41 21.42,22.41 21.91,21.92 22.49,21.92 23.12,22.55 23.12,24.11 22.76,24.47 v1(22.47,24.47)
MIC2_L: length 19.9
  TOP w0.203: v1(27.83,20.43) 28.14,20.74 UA2.47
  IN3 w0.254: v1(12.82,18.02) 13.13,18.02 13.28,18.17 15.74,18.17 15.89,18.32 15.9,18.32 16.87,19.29 18.66,19.29 19.48,18.47 20.68,18.47 23.07,20.86 27.45,20.86 27.83,20.48 v1(27.83,20.43)
  BOTTOM w0.254: CA71.1 13.9,17.78 13.49,18.18 v2(13.39,18.18) 13.19,18.18 13.02,18.02 v1(12.82,18.02)
MIC2_L_C: length 0.9
  BOTTOM w0.508: RA51.1 CA71.2
MIC2_R: length 16.9
  TOP w0.203: UA2.48 28.54,20.54 v1(28.66,20.43)
  IN1 w0.254: v3(14.9,20.02) 15.13,20.25 v7(15.3,20.25)
  IN4 w0.254: v3(14.9,20.02) 15.74,19.19 18.25,19.19 20.33,21.27 20.94,21.27 21.45,20.76 23.34,20.76 23.5,20.93 28.16,20.93 v1(28.66,20.43)
MIC2_R_C: length 3.3
  TOP w0.109: v2(15.2,21.32) 14.81,20.94 14.81,19.82 CA70.2
  TOP w0.254: CA70.2 14.48,19.34 RA50.1
MIC_CAP: length 2.8
  TOP w0.203: UA2.36 22.94,22.1 22.29,21.45 22.29,20.97 21.94,20.62 CA67.1
MONO_IN: length 3.8
  TOP w0.203: UA2.2 29.81,22.5 30.07,22.24 30.07,20.93 v2(30.41,20.58) 30.94,20.05 CA47.2
MOTOR_EN#: length 40.9
  IN3 w0.102: v1(191.76,66.68) 191.76,66.53 193.34,64.96 199.06,64.96 200.41,66.3 203.24,66.3 203.68,65.87 203.68,63.69 203.24,63.25 203.24,61.39 204.18,60.45 204.18,59.17 203.76,58.75 203.76,56.31 202.89,55.43 202.89,52.92 v3(203.32,52.48)
  IN4 w0.076: v4(203.7,52.61) 203.5,52.61 203.37,52.48 v3(203.32,52.48)
  BOTTOM w0.076: 204.34,52.61 v2(204.84,52.61) 205.23,52.61 205.99,53.37 206.01,53.37 206.17,53.53 206.37,53.53 206.53,53.69 207.11,53.69 U34.B6
  BOTTOM w0.109: v1(191.76,66.68) C1164.1 190.86,66.02 Q330.2 188.87,68.02 187.81,68.02 187.09,68.73 187.09,69.54 186.86,69.77 R923.1 ; v4(203.7,52.61) 204.34,52.61
MOTOR_N1: length 36.2
  TOP w0.203: v1(185.83,66.35) 185.83,66.76 186.19,67.12 186.57,67.12 v2(186.58,67.13) 187.25,67.8 R924.1
  IN3 w0.203: v1(185.83,66.35) 185.83,66.1 186.05,65.88 186.05,59.01 186.86,58.2 187.82,58.2 188.78,57.23 196.89,57.23 198.57,58.92 198.57,61.15 199.82,62.39 199.82,63.66 200.6,64.45 v3(200.91,64.45)
  IN4 w0.203: v3(200.91,64.45) 200.91,64.42 v4(201.21,64.12)
  BOTTOM w0.203: JLVDS1.20 202.4,61.5 203.29,62.39 203.29,62.9 203.04,63.15 201.92,63.15 201.43,63.65 201.43,63.9 v4(201.21,64.12)
MOTOR_P1: length 45.5
  IN3 w0.203: v3(189.53,66.2) 189.53,65.9 189.32,65.69 188.25,65.69 186.41,63.86 186.41,59.13 187.01,58.53 187.95,58.53 188.92,57.56 196.75,57.56 198.24,59.06 198.24,61.28 199.48,62.53 199.48,63.8 200.64,64.96 v3(201.24,64.96)
  IN4 w0.203: v3(201.24,64.96) 201.59,64.96 v4(201.67,64.88)
  IN4 w0.254: v4(190.9,66.66) 189.99,66.66 v3(189.53,66.2)
  BOTTOM w0.102: v2(193.95,67.15) 193.61,67.49 DH5.1
  BOTTOM w0.203: v4(201.67,64.88) 201.76,64.79 201.76,63.78 202.06,63.48 203.18,63.48 203.63,63.04 203.63,62.21 202.9,61.49 JLVDS1.19
  BOTTOM w0.254: Q330.1 189.88,68.97 190.44,68.41 192.09,68.41 192.47,68.03 DH5.1 191.35,67.49 190.9,67.04 v4(190.9,66.66)
MPCIE_RST#: length 147.6
  TOP w0.109: R1314.1 220.95,52.69 220.21,52.69 v7(220.16,52.74) 219.96,52.74 v2(219.7,52.48) 218.56,51.34 U675.1
  IN1 w0.076: v7(220.16,52.74) v3(219.72,52.74)
  IN2 w0.102: v3(265.06,23.54) 265.06,39.82 262.78,42.1 257.07,42.1 254.98,44.18 250.95,44.18 249.75,45.39 243.95,45.39 241.93,43.37 233.06,43.37 228.16,48.27 225.65,48.27 223.08,50.83 221.44,50.83 220.67,51.61 220.67,52.32 220.25,52.74 v3(219.72,52.74) 219.56,52.59 216.22,52.59 214.68,54.12 212.12,54.12 211.07,55.18 209.09,55.18 208.78,55.48 206.67,55.48 206.52,55.63 205.41,55.63 205.2,55.43 200.25,55.43 199.82,55 193.72,55 193.62,55.1 190.02,55.1 189.56,55.56 181.63,55.56 180.71,54.64 176.19,54.64 175.51,53.96 173.25,53.96 173.07,54.14 169.47,54.14 169.11,53.77 167.91,53.77 167.41,53.27 167.41,52.92 167.08,52.59 163.49,52.59 162.76,53.32 161.77,53.32 161.05,54.03 160.7,54.03 v3(160.32,53.65)
  IN4 w0.076: v3(265.06,23.54) 265.06,23.38 v4(264.88,23.2) ; v3(160.32,53.65) 160.34,53.63 160.34,53.58 160.17,53.75 v4(160.17,54.03)
  BOTTOM w0.102: v4(160.17,54.03) 160.42,54.03 160.67,54.29 160.98,54.29 161.14,54.45 161.14,54.86 161.6,55.31 164.01,55.31
  BOTTOM w0.109: RH381.2 165.92,56.43 165.3,56.43 164.31,55.44 164.14,55.44 164.01,55.31 ; v4(264.88,23.2) 265.11,23.43 U678.2 ; v4(160.17,54.03) UCPU1.U6
MPHY_PWREN: length 30
  TOP w0.109: v7(181.5,58.13) 181.94,58.13 182.67,57.4 v2(182.67,57.34) 182.67,57.12 182.4,56.85 182.4,55.95 R1185.2 181.88,54.83 v1(182.34,54.38)
  IN1 w0.076: v3(180.74,58.71) 180.74,58.55 181.22,58.07 181.45,58.07 v7(181.5,58.13)
  IN3 w0.102: v1(182.34,54.38) 182.34,54.25 182,53.91 177.36,53.91 176.91,53.46 174.9,53.46 174.72,53.63 171.29,53.63 170.58,52.92 169.69,52.92 169.31,52.54 168.04,52.54 167.58,52.08 165.51,52.08 165.05,52.54 164.14,52.54 163.56,51.95 v3(163.21,51.95)
  IN4 w0.076: v3(163.21,51.95) 162.91,51.95 v4(162.81,51.85) ; v4(180.66,60.16) 180.66,58.78 v3(180.74,58.71)
  BOTTOM w0.109: Q362.2 180.8,60.29 v4(180.66,60.16)
MPHY_PWREN#: length 15.3
  TOP w0.254: R1381.2 183.76,57.58 v1(183.19,58.15)
  BOTTOM w0.254: v1(183.19,58.15) 183.32,58.28 183.84,58.28 184.32,58.76 184.32,59.83 183.72,60.42 Q362.1 182.55,62.11 v2(180.5,62.11) 180.1,61.72 180.1,61.15 179.85,60.89 177.82,60.89 177.68,60.75 Q39.2 ; v1(183.19,58.15) Q361.2 ; v1(183.19,58.15) Q361.5
MSATA_DET#: length 90
  IN1 w0.076: v3(196.96,12.21) 196.96,13.01 197.38,13.43 197.38,26.28 196.13,27.53 196.13,28.62 194.81,29.94 194.81,31.44 192.84,33.41 192.84,33.86 192.02,34.68 192.02,35.62 191.39,36.25 189.39,36.25 188.32,37.32 179.99,37.32 178.83,38.47 178.83,45.56 178.3,46.1 177.48,46.1 176.99,45.61 175.51,45.61 174.66,46.46 167.52,46.46 166.93,47.05 v3(166.28,47.05)
  IN2 w0.102: v3(203.37,26.04) 202.42,26.04 197.83,21.46 197.83,13.83 196.96,12.95 v3(196.96,12.21)
  IN4 w0.076: v4(166.06,47.46) 166.46,47.05 v3(166.28,47.05) ; v4(203.32,26.6) 203.32,26.09 v3(203.37,26.04)
  BOTTOM w0.109: v4(203.32,26.6) 202.93,26.6 202.74,26.79 202.74,28.34 203.46,29.06 JSATA1.51 ; UCPU1.AC1 164.28,50.35 164.33,50.4 165.42,50.4 T274.1 165.89,49.94 165.89,49.53 166.12,49.3 166.12,48.74 RH392.1 166.59,48.04 166.06,47.51 v4(166.06,47.46)
Net_689: length 0.4
  BOTTOM w0.254: 162.8,41.51 163.05,41.26
Net_738: length 0.5
  BOTTOM w0.254: 126.56,63.23 126.73,63.06 126.73,62.81
Net_739: length 0.4
  BOTTOM w0.254: 125.48,61.43 125.21,61.7
Net_740: length 0.7
  BOTTOM w0.254: 124.83,61.5 124.61,61.5 124.28,61.83
Net_741: length 0.7
  BOTTOM w0.254: 125.42,62.81 124.9,63.34
Net_763: length 0.7
  BOTTOM w0.254: 124.83,42.14 124.15,42.14
Net_765: length 0.7
  BOTTOM w0.254: 124.83,41.48 124.18,41.48
Net_767: length 0.7
  BOTTOM w0.254: 124.83,40.76 124.32,40.24
Net_851: length 0.8
  BOTTOM w0.254: 162.95,62.31 163.49,62.85
Net_855: length 0.6
  BOTTOM w0.254: 164.03,40.88 163.56,40.88 163.46,40.77
Net_856: length 0.7
  BOTTOM w0.254: 163.46,41.5 163.57,41.38 164.15,41.38
NFC_DET#: length 95.4
  TOP w0.109: RH465.1 158.74,54.97 v7(158.77,54.95)
  IN1 w0.076: v3(158.9,55.33) 158.9,55.08 v7(158.77,54.95)
  IN2 w0.102: v3(161.13,42.5) 161.13,42.83 160.32,43.65 159.63,43.65 159.07,44.2 159.07,45.17 158.51,45.73 158.51,45.98 159.63,47.1 159.63,48.07 159.38,48.32 159.38,49.49 159.07,49.79 159.07,50.22 158.16,51.14 156.94,51.14 156.15,51.93 155.92,51.93 v3(155.9,51.95)
  IN3 w0.102: v3(192.3,16.21) 192.68,16.59 192.68,21.65 191.77,22.56 191.77,27.44 191.05,28.15 187.43,28.15 184.33,31.26 184.33,33.27 185.18,34.12 185.18,34.91 184.76,35.33 182.12,35.33 178.2,39.25 176.85,39.25 176.28,39.82 176.28,40.48 175.74,41.03 175.74,42.33 173.26,44.8 170.2,44.8 168.31,42.91 166.95,42.91 165.49,41.45 161.98,41.45 161.13,42.3 v3(161.13,42.5)
  IN4 w0.076: v4(183.76,11.13) 183.87,11.24 188.25,11.24 v4(188.46,11.02) 189.19,11.02 190.2,12.03 190.2,12.88 191.89,14.58 191.89,15.71 192.3,16.11 v3(192.3,16.21) ; v3(155.9,51.95) 156.03,51.95 158.9,54.82 v3(158.9,55.33) 158.97,55.25 160.14,55.25 v4(160.5,54.9)
  BOTTOM w0.109: v4(160.5,54.9) 160.5,55.1 160.82,55.43 UCPU1.N5 ; v2(182.07,12.24) 182.81,12.24 R1228.1 183.76,11.29 v4(183.76,11.13) ; JNFC1.4 190.45,9.94 189.37,11.02 v4(188.46,11.02)
NFC_IRQ: length 69.7
  IN4 w0.076: v4(188.26,32.47) 188.26,32.22 192.73,27.75 192.73,23.92 v1(193.17,23.48) 193.55,23.1 193.55,15.95 190.4,12.8 190.4,11.94 189.05,10.59 v4(188.39,10.59) 187.94,11.03 185.32,11.03 v4(185,10.71) ; v4(166.36,41.46) 166.13,41.23 161.82,41.23 v4(161.8,41.25)
  BOTTOM w0.109: R1100.2 184.35,11.35 v4(185,10.71) ; v4(161.8,41.25) 161.82,41.27 161.82,43.97 UCPU1.AN3 ; v4(188.26,32.47) 188.03,32.7 188.03,33.21 187.62,33.61 179.75,33.61 179.17,34.19 v2(178.73,34.19) 170.63,34.19 RH294.1 169.79,35.04 169.79,36.18 168.94,37.03 168.49,37.03 168.23,37.29 168.23,37.74 166.36,39.61 v4(166.36,41.46) ; JNFC1.5 189.95,10.11 189.47,10.59 v4(188.39,10.59)
NFC_RST#: length 70.5
  IN1 w0.076: v1(187.53,10.64) 190.47,10.64 192.4,12.56 192.4,14.37 192.75,14.72 192.75,18.13 191.97,18.92 191.97,25.36 191.69,25.64 191.69,27.02 190.68,28.02 189.67,28.02 186.34,31.35 178.81,31.35 173.99,36.18 170.14,36.18 167.37,38.95 166.54,38.95 163.12,42.36 162.73,42.36 162.54,42.55 162.25,42.55 161.89,42.91 160.27,42.91 159.21,43.97 159.21,44.22 v3(158.31,45.12)
  IN4 w0.076: v3(158.31,45.12) 158.31,45.35 v4(158.46,45.5)
  BOTTOM w0.109: v4(158.46,45.5) 158.46,45.63 158.21,45.88 158.21,46.31 158.54,46.64 158.54,47.4 158.74,47.61 159.05,47.61 159.2,47.76 159.2,48.09 159.35,48.24 159.35,48.52 159.2,48.67 159.2,49.49 UCPU1.AD7 ; R1142.1 186.68,11.26 186.68,10.8 v2(186.81,10.68) 187.5,10.68 v1(187.53,10.64) 187.53,10.16 187.45,10.07 JNFC1.10
NFC_VDD_SIM: length 9
  IN4 w0.076: v4(187.97,10.36) 187.85,10.24 186.37,10.24 v4(186.12,10.49)
  BOTTOM w0.109: R974.1 R973.2 v4(186.12,10.49) ; v2(187.99,12.68) 187.51,12.2 187.51,11.18 187.66,11.03 187.84,11.03 187.97,10.9 v4(187.97,10.36) 188.07,10.26 189.28,10.26 189.45,10.08 JNFC1.6
NGFF_PWREN: length 91.1
  TOP w0.109: v7(214.1,56.45) 214.1,55.89 215.75,54.24 v2(215.75,53.92) 215.75,51.25 215.76,51.24 215.76,50.21 215.75,50.21 215.75,49.93 R1233.1 ; D115.2 231.07,49.72 v1(230.59,49.23)
  IN1 w0.076: v3(213.73,56.85) 213.84,56.75 213.84,56.71 v7(214.1,56.45)
  IN2 w0.102: v1(230.59,49.23) 229.98,49.84 228.87,49.84 227.49,51.23 225.95,51.23 225.52,51.65 225.52,52.56 223.48,54.61 218.93,54.61 217.02,56.51 216.23,56.51 215.93,56.21 214.37,56.21 v3(213.73,56.85) 213.09,56.85 212.3,57.64 203.95,57.64 201.48,60.11 201.48,60.29 199.68,62.09 198.8,62.09 196.48,64.41 187.38,64.41 185.95,62.97 182.86,62.97 180.76,60.87 176.93,60.87 176.4,60.33 176.4,59.92 174.32,57.84 167.43,57.84 165.92,56.33 164.88,56.33 163.8,55.25 161.26,55.25 160.97,54.96 160.02,54.96 v3(159.94,54.87)
  IN4 w0.076: v3(159.94,54.87) 160.17,54.64 v4(160.17,54.57)
NGFF_RST#: length 49.9
  TOP w0.109: R1232.1 217.33,49.26 218.95,49.26 ; R1243.2 243.39,42.63 243.64,42.38 R1241.2 243.64,41.13 v7(243.31,40.8) ; 218.95,49.26 219.13,49.08 219.13,48.36 219.4,48.09 U709.2 220.43,48.09 221.79,46.73 221.79,46.54 v1(221.8,46.53) 221.8,45.96 v2(221.58,45.74) ; 218.95,49.26 218.95,49.63 219.37,50.04 U675.4 220.87,50.04 R1203.1
  IN1 w0.076: v7(243.31,40.8) v3(243.78,40.8)
  IN4 w0.076: v4(243.4,40.94) 243.64,40.94 v3(243.78,40.8)
  BOTTOM w0.109: JNGFF1.44 223.08,50.24 222.18,49.34 222.18,47.77 221.79,47.38 221.79,46.54 v1(221.8,46.53) 221.8,46.48 222.56,45.72 222.56,45.38 225.49,42.45 227.86,42.45 228.31,42.9 229.08,42.9 229.36,42.62 229.36,40.8 229.17,40.62 229.17,39.57 230.54,38.2 234.66,38.2 236.09,39.62 238.25,39.62 239.3,38.58 240.67,38.58 243.03,40.94 v4(243.4,40.94)
NGFF_WAKE#: length 74.5
  TOP w0.109: v7(214.28,58.15) 214.28,56.88 214.45,56.71 214.45,56.07 v2(214.79,55.73) 216.16,54.36 216.16,52.35 216.6,51.9 R1231.1 217.25,51.9 R1215.1 ; v7(162.15,56.32) 163.4,56.32 163.66,56.06 165.49,56.06 165.59,56.17 165.59,56.17 165.61,56.19 165.61,56.22 165.61,56.22 165.61,57 RH397.2
  IN1 w0.076: v7(162.15,56.32) 161.9,56.08 v3(161.9,56.02) ; v3(213.68,58.15) v7(214.28,58.15)
  IN2 w0.102: v3(213.68,58.15) 213.51,58.33 204.23,58.33 202.16,60.39 202.16,60.57 200.2,62.54 200.2,62.72 199.43,63.48 198.38,63.48 196.77,65.1 184.02,65.1 180.55,61.63 176.7,61.63 175.71,60.64 175.71,60.2 174.04,58.53 169.25,58.53 168.52,59.27 167.12,59.27 165.46,57.6 164.52,57.6 163.34,56.42 162.31,56.42 v3(161.9,56.02)
  IN4 w0.076: v3(161.9,56.02) 161.9,56.05 v4(162.16,56.3)
NGFF_WAKE#_R: length 13.4
  TOP w0.109: v7(217.48,49.61) 217.3,49.79 217.3,50.45 R1231.2 ; v7(222.92,48.37) 222.92,47.66 223.09,47.48 Q347.1 223.09,45.32 222.78,45 221.67,45 v2(220.99,44.32)
  IN1 w0.076: v7(217.48,49.61) 217.65,49.78 221.23,49.78 222.64,48.37 v7(222.92,48.37)
O-USR: length 4.3
  TOP w0.203: PU701.9 103.44,57.51 103.84,57.11 103.84,56.35 103.37,55.88 v2(103.37,55.74) PR713.1 PR706.2
OCP-I: length 4.5
  TOP w0.109: PR710.1 106.66,57.51 v2(106.66,57.12)
  TOP w0.203: PU701.12 104.57,58.71 PR703.2 104.76,58.53 PR710.1
P1:
  vias: v2(75.19,11.74)
PA0_WAKUP: length 23.2
  TOP w0.076: v1(249.75,64.37) 249.75,64.37 249.6,64.22 249.59,64.22 249.59,63.65 249.52,63.58 249.24,63.58 249.1,63.44 249.1,63.21 248.84,62.95 U636.F6
  TOP w0.109: v1(239.24,58.09) 238.96,57.81 R537.1 ; R1230.2 R537.1 ; R537.1 238.96,56.54 D87.1 D86.1 240.18,54.21 240.39,54.42 v2(241.08,54.42)
  IN3 w0.102: v1(239.24,58.09) 239.24,58.19 239.5,58.45 241.21,58.45 242.2,59.44 243.53,59.44 244.27,60.18 244.27,61.53 244.8,62.06 245.48,62.06 245.64,61.91 247.69,61.91 249.75,63.97 v1(249.75,64.37)
PA11: length 2.7
  TOP w0.076: U636.C1 247.43,60.25 247.43,60.16 247.27,60 247.27,59.94 247.29,59.93 247.29,59.91
  TOP w0.109: R1221.2 247.45,58.17 247.38,58.24 247.38,58.46 247.29,58.56 247.29,59.91
PA12: length 4.6
  TOP w0.076: U636.C2 247.08,60.58 247.08,59.94 247.06,59.93 247.06,59.91
  TOP w0.109: 247.06,59.91 247.06,58.28 R1222.2 R1223.1 R1251.1
PB5: length 7.3
  TOP w0.076: U636.A5 246.28,62.34 246.09,62.14 245.21,62.14 v7(245.2,62.14)
  IN1 w0.076: v7(246.06,57.25) 246.06,58.13 244.42,59.77 244.42,61.68 244.85,62.11 245.18,62.11 v7(245.2,62.14)
PB13: length 3.1
  TOP w0.109: U636.G1 249.34,60.09 250.07,59.36 250.46,59.36 v2(250.71,59.11) 250.93,58.88 R1367.1
PBTN_OUT#: length 49.6
  TOP w0.109: v7(175.39,47.35) 175.39,47.37 174.43,48.33 v2(174.43,48.37)
  IN1 w0.076: v7(175.39,47.35) 176.13,48.09 177.65,48.09 178.24,47.5 181.83,47.5 183.36,45.97 194.45,45.97 194.96,45.46 199.7,45.46 200.12,45.04 201.73,45.04 202.97,43.8 203.66,43.8 204.53,44.66 205.43,44.66 206.37,43.72 v3(207.16,43.72)
  IN3 w0.102: v3(210.48,54.57) 210.48,53.48 210.36,53.35 210.36,52.41 209.9,51.95 209.9,50.22 206.94,47.27 206.94,43.94 v3(207.16,43.72)
  IN4 w0.076: v4(210.71,54.97) 210.51,54.77 210.51,54.59 v3(210.48,54.57)
  BOTTOM w0.076: v4(210.71,54.97) 210.36,54.62 U34.H4
PBTN_OUT#_R: length 75.7
  TOP w0.109: v7(159.35,45.45) 159.21,45.31 159.21,44.77 v2(161.49,42.49) 163.13,42.49 165.45,44.81 168.4,44.81 168.68,45.1 169.38,45.1 169.81,45.53 170.25,45.53 170.58,45.87 174.19,45.87 R1312.1 RH439.1 RH293.1
  IN1 w0.076: v7(159.35,45.45) 159.33,45.47 159.33,45.6 159.02,45.9 v3(159.02,45.9) ; v7(113.1,57.51) 113.49,57.51 114.35,56.65 116.55,56.65 118.59,54.62 v3(118.59,52.79)
  IN3 w0.102: v3(159.02,45.9) 158.31,45.9 157.91,45.5 156.25,45.5 155.85,45.91 155.85,46.44 156.15,46.74 156.15,47.18 154.91,48.42 151.94,48.42 151.68,48.67 150.49,48.67 150.23,48.42 148.91,48.42 148.68,48.65 128.64,48.65 126.87,50.43 122.5,50.43 119.63,53.3 118.87,53.3 118.59,53.02 v3(118.59,52.79)
  IN4 w0.076: v4(159.72,46.04) 159.59,45.9 v3(159.02,45.9)
PBTN_SW#: length 357.8
  TOP w0.109: v1(264.43,36.91) 264.15,36.64 253.77,36.64 251.93,34.8 233.11,34.8 232.97,34.66 216.75,34.66 214.81,36.6 214.81,39.81 v1(213.89,40.74) 211.99,42.63 211.99,43.96 211.13,44.83 211.13,46.34 211.38,46.59 211.38,47.68 v5(209.52,49.55) 208.91,50.16 R987.2 ; JAPS.8 187.06,7.74 186.06,8.75 186.06,10.47 187.32,11.73 189.02,11.73 v1(189.64,12.35) ; v1(268.87,6.26) 269,6.4 272.52,6.4 273.16,5.76 DA8.3 v1(273.16,3.46) ; v7(175.95,46.66) 175.76,46.46 RH439.2
  IN1 w0.076: v3(177.03,46.71) 176,46.71 v7(175.95,46.66) ; v1(189.64,12.35) 189.08,11.79 187.94,11.79 187.05,10.9 187.05,8.86 186.84,8.64 181.51,8.64 179.7,6.83 156.07,6.83 153.32,9.58 139.4,9.58 137.6,7.78 111.03,7.78 109.59,9.23 107.31,9.23 103.27,13.27 101.47,13.27 98.47,16.26 98.47,27.53 99.1,28.16 99.1,31.53 102.49,34.92 102.49,37.83 105.05,40.38 105.05,43.71 109.25,47.91 112.44,47.91 112.74,48.22 112.74,48.78 114.6,50.63 114.6,55.11 v7(113.09,56.62)
  IN2 w0.102: v1(264.43,36.91) 264.83,36.52 264.83,28.34 263.95,27.47 263.95,9.75 266.48,7.22 267.9,7.22 v1(268.87,6.26) ; v1(213.89,40.74) 213.7,40.74 212.69,41.74 211.73,41.74 210.92,42.55 206.17,42.55 205.38,43.34 204.44,43.34 201.87,45.91 v3(201.82,45.91) 201.42,45.5 198.52,45.5 197.49,46.53 192.92,46.53 191.84,45.45 180,45.45 178.74,46.71 v3(177.03,46.71)
  IN3 w0.102: v3(201.82,45.91) 201.82,45.7 202.41,45.12 202.41,43.43 201.09,42.11 201.09,39.32 196.64,34.87 196.64,33.44 195.51,32.3 195.51,27.59 194.47,26.55 194.47,16.56 191.76,13.85 191.14,13.85 v1(189.64,12.35)
  BOTTOM w0.109: v1(273.16,3.46) 273.45,3.46 SW2.2 274.59,4.61 276.4,4.61 SW2.1 ; v1(268.87,6.26) 268.18,6.94 JPWR1.2
PC0: length 6.5
  TOP w0.109: R1135.1 250.88,68.25 250.88,67.24 249.95,66.31 249.95,65.6 249.76,65.41 249.14,65.41 v2(248.88,65.15) 248.55,64.81 248.55,64.68 248.34,64.47 U636.E8
PC2_1: length 9.6
  TOP w0.076: v7(248.58,65.51) 248.28,65.21 248.28,64.89 248.09,64.7 248.09,63.1 247.84,62.85 U636.D6
  TOP w0.109: v7(251.31,69.55) 251.31,69.99 v2(251.78,70.46)
  IN1 w0.076: v7(251.31,69.55) 251.31,67.6 249.93,66.23 249.29,66.23 v7(248.58,65.51)
PCH_DDI2_N0: length 163.4
  IN4 w0.076: v4(33.35,34.28) 32.98,34.65 32.84,34.65 32.78,34.59 32.78,32.22 33.14,31.86 33.14,29.97 33.8,29.31 33.8,28.68 34.49,28 34.49,26.18 35.45,25.22 35.45,24.47 36.25,23.67 36.25,22.83 39.06,20.02 39.17,20.02 39.3,20.15 39.58,20.15 39.78,19.95 39.78,19.66 39.66,19.53 39.66,19.43 39.82,19.26 39.93,19.26 40.05,19.39 40.34,19.39 40.54,19.19 40.54,18.91 40.41,18.78 40.41,18.67 41.32,17.76 41.93,17.76 45.15,14.54 45.15,14.23 44.86,13.94 44.86,13.76 45.17,13.46 45.35,13.46 45.87,13.98 47.9,13.98 49.6,12.28 49.6,11.4 49.92,11.08 50.21,11.08 50.29,11.16 50.29,11.27 50.45,11.44 50.93,11.44 51.12,11.25 51.12,11.15 51.24,11.03 51.41,11.03 51.53,11.15 51.53,11.64 51.25,11.92 51.25,12.23 51.45,12.43 52.1,12.43 52.32,12.21 52.32,12.05 52.6,11.77 53.26,11.77 53.66,11.36 64.01,11.36 64.37,11.72 74.43,11.72 76.25,9.9 91.14,9.9 93.41,12.17 93.41,14.74 96.31,17.64 96.31,20.62 95.24,21.69 95.24,26.55 96.49,27.79 96.49,29 100.65,33.16 100.65,34.78 104.54,38.67 104.54,43.43 108.41,47.3 116.15,47.3 119.17,50.33 119.17,51.21 120.92,52.97 120.92,53.38 121.09,53.54 121.55,53.54 121.66,53.65 121.66,53.81 121.55,53.92 121.09,53.92 120.92,54.09 120.92,54.44 121.09,54.61 121.92,54.61 122.88,55.57 122.88,60.47 124.9,62.49 129.47,62.49 129.7,62.72 130.47,62.72 130.75,62.44 131.03,62.44 131.36,62.11 131.64,62.11 132.1,61.65 132.1,61.4 132.29,61.21 132.76,61.21 132.94,61.39 132.94,61.55 132.84,61.65 132.7,61.65 132.57,61.53 v4(132.57,61.51)
PCH_DDI2_N0_C: length 2.4
  BOTTOM w0.109: CV30.2 32.44,34.51 32.33,34.62 32.02,34.62 31.77,34.87 31.77,34.97 31.45,35.29 31.27,35.29 31.18,35.21 U722.7
PCH_DDI2_N1: length 163.5
  IN4 w0.076: v4(33.35,36.06) 33.13,36.28 32.73,36.28 32.39,36.63 32.12,36.63 31.78,36.29 31.78,36.02 31.84,35.95 32.3,35.95 32.58,35.67 32.58,35.31 32.15,34.88 32.15,31.94 32.53,31.55 32.53,29.71 33.09,29.15 33.09,27.87 33.22,27.75 33.35,27.75 33.55,27.54 33.55,27.26 33.35,27.06 33.2,27.06 33.09,26.95 33.09,26.07 34.46,24.7 34.46,23.97 34.68,23.76 35.12,23.76 35.49,23.39 35.49,22.73 41.09,17.13 41.7,17.13 44.17,14.66 44.17,13.53 45.71,11.98 46.15,11.98 46.25,12.09 46.25,12.99 46.45,13.19 46.73,13.19 46.94,12.99 46.94,12.16 47.04,12.05 47.21,12.05 47.32,12.16 47.32,12.91 47.49,13.09 47.9,13.09 48.44,12.54 48.94,12.05 48.94,11.2 49.74,10.4 51.85,10.4 52.16,10.71 52.2,10.75 64.4,10.75 64.7,11.06 74.23,11.06 75.99,9.29 91.47,9.29 94.1,11.92 94.1,14.55 96.95,17.39 96.95,20.9 95.85,21.99 95.85,26.3 97.1,27.54 97.1,28.74 101.26,32.91 101.26,33.92 105.15,37.8 105.15,43.18 108.67,46.69 116.4,46.69 119.78,50.07 119.78,50.87 122.57,53.67 122.57,54.38 123.49,55.3 123.49,60.21 125.24,61.96 129.9,61.96 130.05,62.11 130.75,62.11 130.96,61.91 130.96,61.75 v4(131.19,61.51)
PCH_DDI2_N1_C: length 2.1
  BOTTOM w0.109: U722.5 31.18,36.01 31.27,36.09 31.7,36.09 32,36.39 32.1,36.39 CV33.2
PCH_DDI2_N2: length 164.8
  IN4 w0.076: v4(133.7,61.51) 133.51,61.32 133.42,61.32 133.32,61.43 133.32,61.6 133.7,61.98 133.93,61.98 134.08,61.83 134.08,61.43 133.04,60.38 125,60.38 124.14,59.53 124.14,54.98 123.26,54.1 123.26,53.46 120.39,50.59 120.39,49.82 116.66,46.08 108.92,46.08 105.76,42.92 105.76,37.51 101.87,33.62 101.87,32.66 97.71,28.49 97.71,17.29 94.81,14.4 94.81,11.74 91.75,8.68 75.74,8.68 74.45,9.98 55.68,9.98 55.45,9.75 49.43,9.75 47.97,11.21 45.6,11.21 43.35,13.46 42.68,13.46 40.07,16.06 40.07,17.05 35.36,21.77 35.03,21.77 34.31,22.49 34.31,22.82 32.48,24.65 32.48,28.88 31.9,29.46 31.9,31.31 31.53,31.68 31.53,33 30.93,33.6 30.93,36.79 32.58,38.44 33.14,38.44 33.22,38.36 33.22,37.97 v4(33.35,37.84)
PCH_DDI2_N2_C: length 2.6
  BOTTOM w0.109: U722.2 31.18,37.21 31.27,37.29 31.53,37.29 31.82,37.59 31.82,38.05 31.94,38.17 32.1,38.17 CV34.2
PCH_DDI2_N3: length 164.7
  IN4 w0.076: v4(131.44,63.09) 131.16,62.81 131.09,62.81 130.52,63.38 129.32,63.38 129.01,63.08 126.88,63.08 126.8,63.15 126.8,64.03 126.6,64.23 126.32,64.23 126.12,64.03 126.12,63.15 126.04,63.08 124.29,63.08 122.24,61.03 122.24,60.54 122.14,60.43 121.65,60.43 121.46,60.24 121.46,59.89 121.65,59.7 122.17,59.7 122.27,59.6 122.27,59.37 122.17,59.27 120.5,59.27 120.31,59.08 120.31,58.21 120.5,58.02 121.13,58.02 121.23,57.92 121.23,57.6 121.13,57.5 120.48,57.5 120.31,57.34 120.31,56.84 120.48,56.67 122.19,56.67 122.3,56.56 122.3,56.4 122.19,56.29 120.48,56.29 120.31,56.13 120.31,55.77 120.48,55.6 121.58,55.6 121.68,55.5 121.68,55.33 121.58,55.22 120.48,55.22 120.31,55.06 120.31,53.31 119.31,52.31 118.15,52.31 117.05,51.21 117.05,49.07 115.89,47.91 108.69,47.91 108.69,47.91 108.19,47.91 108.16,47.91 103.85,43.61 103.85,38.84 100.2,35.19 100.2,35.19 100.04,35.03 100.04,33.42 95.88,29.25 95.88,28.05 94.63,26.8 94.63,21.9 92.41,19.68 92.41,12.03 90.89,10.51 76.5,10.51 74.66,12.35 64.01,12.35 63.66,12 53.92,12 52.88,13.04 51.94,13.04 51.53,13.44 49.42,13.44 48.05,14.82 45.74,14.82 42.16,18.4 41.55,18.4 41.32,18.63 41.32,19.29 39.06,21.54 38.82,21.54 36.95,23.41 36.95,23.87 36.06,24.76 36.06,25.55 35.1,26.51 35.1,28.27 34.46,28.9 34.46,30.01 34.11,30.36 33.93,30.36 33.88,30.41 v4(33.88,30.62)
  BOTTOM w0.109: CV35.1 33.34,32.51 33.34,32.85 33.42,32.93 33.94,32.93 34.2,32.67 34.2,31.44 34.41,31.23 v6(34.41,30.64) 34.41,30.42 34.22,30.23 33.91,30.23 33.83,30.31 33.83,30.54 33.88,30.59 v4(33.88,30.62) ; v4(131.44,63.09) 131.19,62.85 UCPU1.A53
PCH_DDI2_N3_C: length 2.8
  BOTTOM w0.109: U722.10 31.07,34.01 31.16,34.1 31.27,34.1 31.49,33.88 31.49,33.27 31.92,32.84 32.1,32.84 CV35.2
PCH_DDI2_P0: length 163.5
  IN4 w0.076: v4(33.35,35.17) 32.98,34.8 32.78,34.8 32.63,34.65 32.63,32.15 32.99,31.8 32.99,29.9 33.65,29.24 33.65,28.62 34.33,27.94 34.33,26.12 35.3,25.15 35.3,24.41 36.1,23.61 36.1,22.77 39,19.87 39.23,19.87 39.36,19.99 39.52,19.99 39.63,19.88 39.63,19.72 39.5,19.6 39.5,19.36 39.76,19.11 39.99,19.11 40.12,19.24 40.28,19.24 40.39,19.13 40.39,18.97 40.26,18.84 40.26,18.61 41.26,17.61 41.87,17.61 45,14.48 45,14.29 44.71,14 44.71,13.7 45.1,13.31 45.41,13.31 45.93,13.83 47.83,13.83 49.45,12.21 49.45,11.34 49.85,10.93 50.27,10.93 50.44,11.1 50.44,11.21 50.51,11.29 50.87,11.29 50.97,11.18 50.97,11.09 51.18,10.88 51.47,10.88 51.68,11.09 51.68,11.7 51.4,11.98 51.4,12.16 51.52,12.28 52.04,12.28 52.16,12.15 52.16,11.98 52.53,11.62 53.19,11.62 53.6,11.21 64.08,11.21 64.43,11.57 74.37,11.57 76.18,9.75 91.2,9.75 93.57,12.11 93.57,14.68 96.46,17.57 96.46,20.68 95.4,21.75 95.4,26.49 96.64,27.73 96.64,28.93 100.81,33.1 100.81,34.72 104.69,38.6 104.69,43.37 108.48,47.15 116.21,47.15 119.32,50.26 119.32,51.15 121.08,52.9 121.08,53.31 121.15,53.39 121.61,53.39 121.81,53.59 121.81,53.87 121.61,54.07 121.15,54.07 121.08,54.15 121.08,54.38 121.15,54.46 121.98,54.46 123.03,55.51 123.03,60.41 124.96,62.34 129.53,62.34 129.76,62.57 130.41,62.57 130.69,62.29 130.97,62.29 131.3,61.96 131.58,61.96 131.95,61.59 131.95,61.34 132.23,61.06 132.82,61.06 132.95,61.19 v4(133.14,61.19)
PCH_DDI2_P0_C: length 2.4
  BOTTOM w0.109: CV27.2 32.44,34.97 32.3,34.84 32.12,34.84 32,34.96 32,35.06 31.54,35.52 31.27,35.52 31.18,35.61 U722.6
PCH_DDI2_P1: length 163.4
  IN4 w0.076: v4(130.63,61.84) 130.51,61.96 130.12,61.96 129.97,61.81 125.3,61.81 123.65,60.15 123.65,55.23 122.73,54.31 122.73,53.6 119.93,50.81 119.93,50.01 116.46,46.54 108.73,46.54 105.3,43.11 105.3,37.74 101.42,33.85 101.42,32.85 97.25,28.68 97.25,27.48 96.01,26.23 96.01,22.06 97.1,20.96 97.1,17.33 94.25,14.49 94.25,11.86 91.53,9.14 75.93,9.14 74.16,10.9 64.76,10.9 64.46,10.6 52.27,10.6 52.01,10.34 51.91,10.24 49.68,10.24 48.79,11.13 48.79,11.98 47.83,12.94 47.55,12.94 47.47,12.85 47.47,12.09 47.27,11.9 46.98,11.9 46.78,12.09 46.78,12.93 46.67,13.04 46.51,13.04 46.4,12.93 46.4,12.03 46.21,11.83 45.65,11.83 44.02,13.46 44.02,14.59 41.64,16.98 41.03,16.98 35.34,22.67 35.34,23.33 35.06,23.6 34.61,23.6 34.31,23.91 34.31,24.63 32.94,26.01 32.94,27.01 33.14,27.21 33.28,27.21 33.39,27.32 33.39,27.48 33.28,27.59 33.15,27.59 32.94,27.81 32.94,29.09 32.38,29.65 32.38,31.49 32,31.87 32,34.95 32.43,35.38 32.43,35.61 32.24,35.8 31.78,35.8 31.62,35.95 31.62,36.35 32.05,36.78 32.45,36.78 32.8,36.43 33.09,36.43 33.19,36.53 33.19,36.79 v4(33.35,36.95)
PCH_DDI2_P1_C: length 2.1
  BOTTOM w0.109: CV28.2 32.1,36.62 31.9,36.62 31.6,36.32 31.27,36.32 31.18,36.41 U722.4
PCH_DDI2_P2: length 164.8
  IN4 w0.076: v4(133.14,61.84) 133.34,61.84 133.64,62.14 133.99,62.14 134.23,61.9 134.23,61.36 133.1,60.23 125.06,60.23 124.29,59.46 124.29,54.92 123.41,54.03 123.41,53.4 120.54,50.53 120.54,49.75 116.72,45.93 108.98,45.93 105.91,42.86 105.91,37.45 102.03,33.56 102.03,32.59 97.86,28.43 97.86,17.23 94.96,14.33 94.96,11.68 91.81,8.53 75.68,8.53 74.38,9.83 55.75,9.83 55.52,9.6 49.37,9.6 47.91,11.06 45.54,11.06 43.29,13.31 42.62,13.31 39.92,16 39.92,16.99 35.29,21.62 34.96,21.62 34.16,22.43 34.16,22.75 32.33,24.58 32.33,28.81 31.74,29.4 31.74,31.25 31.38,31.62 31.38,32.94 30.78,33.54 30.78,36.85 32.52,38.59 33.21,38.59 v4(33.35,38.73)
PCH_DDI2_P2_C: length 2.6
  BOTTOM w0.109: CV29.2 32.1,38.39 31.85,38.39 31.6,38.14 31.6,37.68 31.43,37.52 31.27,37.52 31.18,37.61 U722.1
PCH_DDI2_P3: length 164.8
  IN4 w0.076: v4(33.88,29.88) 33.88,30.16 33.93,30.21 34.04,30.21 34.31,29.94 34.31,28.84 34.94,28.2 34.94,26.45 35.91,25.48 35.91,24.7 36.8,23.81 36.8,23.35 38.76,21.39 39,21.39 41.17,19.22 41.17,18.56 41.48,18.25 42.09,18.25 45.68,14.66 47.99,14.66 49.36,13.29 51.47,13.29 51.87,12.89 52.81,12.89 53.85,11.84 63.72,11.84 64.08,12.2 74.59,12.2 76.44,10.36 90.95,10.36 92.56,11.97 92.56,19.62 94.79,21.84 94.79,26.74 96.03,27.98 96.03,29.19 100.2,33.35 100.2,34.97 100.35,35.12 100.35,35.12 104.01,38.78 104.01,43.54 108.22,47.76 108.25,47.76 115.96,47.76 117.21,49.01 117.21,51.14 118.22,52.15 119.37,52.15 120.47,53.25 120.47,55 120.54,55.07 121.65,55.07 121.84,55.26 121.84,55.57 121.65,55.76 120.54,55.76 120.47,55.83 120.47,56.06 120.54,56.14 122.25,56.14 122.45,56.34 122.45,56.62 122.25,56.82 120.54,56.82 120.47,56.9 120.47,57.27 120.54,57.35 121.19,57.35 121.38,57.54 121.38,57.98 121.19,58.17 120.57,58.17 120.47,58.28 120.47,59.01 120.57,59.11 122.23,59.11 122.42,59.3 122.42,59.66 122.23,59.85 121.71,59.85 121.61,59.95 121.61,60.18 121.71,60.28 122.21,60.28 122.4,60.47 122.4,60.97 124.35,62.92 126.1,62.92 126.27,63.09 126.27,63.97 126.38,64.08 126.54,64.08 126.65,63.97 126.65,63.09 126.82,62.92 129.08,62.92 129.38,63.23 130.46,63.23 131.03,62.66 131.22,62.66 v4(131.44,62.44)
  BOTTOM w0.109: v4(131.44,62.44) 131.19,62.2 UCPU1.B53 ; v4(33.88,29.88) 34,30.01 34.31,30.01 34.64,30.34 34.64,31.32 34.44,31.52 v6(34.44,32.52) 34.44,32.75 34.03,33.16 33.59,33.16 CV36.1
PCH_DDI2_P3_C: length 2.8
  BOTTOM w0.109: CV36.2 32.1,33.06 32.02,33.06 31.71,33.36 31.71,33.97 31.36,34.32 31.16,34.32 31.08,34.41 U722.9
PCH_DP_AUXN: length 100.5
  TOP w0.109: v7(236.63,45.09) 236.86,44.86 v6(236.86,44.38) 236.86,43.7 CV10.2
  IN1 w0.076: v7(236.63,45.09) 236.72,45.09 237.04,45.41 237.04,45.58 236.32,46.29 236.32,49.65 229.71,56.26 229.71,59.51 226.83,62.39 225.79,62.39 223.59,64.59 219.17,64.59 214.99,68.77 209.66,68.77 209.25,68.36 204.87,68.36 204.44,68.79 200.46,68.79 198.34,66.67 195.32,66.67 193.2,68.79 190.8,68.79 190.21,68.21 184.08,68.21 183.45,68.84 171.52,68.84 170.83,68.16 168.95,68.16 168.19,67.39 164.23,67.39 162.96,66.12 162.96,65.95 163.37,65.54 v3(163.39,65.54)
  IN4 w0.076: v3(163.39,65.54) 163.42,65.51 v4(163.42,65.16)
  BOTTOM w0.109: UCPU1.C5 160.69,62.27 160.55,62.42 160.55,62.92 160.83,63.2 161.84,63.2 163.18,64.54 163.18,64.93 v4(163.42,65.16)
PCH_DP_AUXN_C: length 6.1
  TOP w0.109: R1036.1 CV10.1 236.88,42.1 236.88,41.99 236.57,41.68 235.77,41.68 235.53,41.44 235.53,40.67 v1(235.36,40.5)
  BOTTOM w0.109: JNGFF2.20 235.9,41.44 235.54,41.08 235.54,40.67 v1(235.36,40.5)
PCH_DP_AUXP: length 100.5
  TOP w0.109: CV8.2 237.1,43.69 237.1,45 v7(237.19,45.09)
  IN1 w0.076: v3(162.81,65.54) 162.81,66.19 164.17,67.55 168.13,67.55 168.89,68.31 170.77,68.31 171.46,68.99 183.51,68.99 184.14,68.36 190.15,68.36 190.73,68.94 193.26,68.94 195.38,66.82 198.28,66.82 200.4,68.94 204.5,68.94 204.93,68.51 209.19,68.51 209.59,68.92 215.06,68.92 219.23,64.74 223.65,64.74 225.85,62.54 226.89,62.54 229.86,59.57 229.86,56.32 236.47,49.71 236.47,46.36 237.19,45.64 v7(237.19,45.09)
  IN4 w0.076: v4(162.76,65.16) 162.76,65.49 v3(162.81,65.54)
  BOTTOM w0.109: v4(162.76,65.16) 162.96,64.96 162.96,64.64 161.75,63.43 160.73,63.43 160.32,63.02 160.32,62.6 160.21,62.49 160.01,62.49 159.94,62.42 159.94,62.26 160.04,62.16 160.31,62.16 UCPU1.B5
PCH_DP_AUXP_C: length 6.2
  TOP w0.109: v1(235.95,40.5) 235.76,40.69 235.76,41.35 235.86,41.45 236.66,41.45 237.1,41.89 237.1,42.13 CV8.1 R1035.1
  BOTTOM w0.109: v1(235.95,40.5) 235.76,40.68 235.76,40.98 236.4,41.62 JNGFF2.22
PCH_DP_CLK: length 4.2
  BOTTOM w0.109: RH281.2 v2(157.66,65.06) 157.66,64.77 157.46,64.56 157.46,64.17 157.39,64.11 157.39,63.45 157.49,63.36 157.49,62.42 UCPU1.B9
PCH_DP_DAT: length 5
  BOTTOM w0.102: UCPU1.C9 158.26,61.77 158.26,62.42 158.29,62.44 158.29,63.34 159.24,64.3
  BOTTOM w0.109: RH282.2 159.44,64.5 159.24,64.3
PCH_DP_HPD: length 136.4
  IN2 w0.102: v3(159.45,59.85) 159.53,59.85 160.34,60.66 162.32,60.66 166.44,64.78 168.23,64.78 168.86,65.41 174.61,65.41 175.37,64.65 177.82,64.65 178.11,64.94 178.11,66.09 179.19,67.17 189.5,67.17 190.43,66.24 198.52,66.24 201.45,63.31 204.01,63.31 204.26,63.05 220.1,63.05 220.84,62.31 222.79,62.31 224.98,64.5 229.89,64.5 230.32,64.07 v3(230.32,63.23)
  IN3 w0.102: v3(230.32,63.23) 230.32,61.96 227.27,58.91 225.49,58.91 224.48,57.89 224.48,52.38 221.44,49.35 221.44,48.09 220.19,46.83 220.19,46.57 v3(220.15,46.53)
  IN4 w0.076: v4(238.15,37.63) 228.42,37.63 227.03,39.01 227.03,40.17 225.09,42.11 224.08,42.11 223.77,42.43 221.52,42.43 221.21,42.73 220.82,42.73 220.49,43.06 220.49,45.05 220.76,45.32 220.76,46.07 220.3,46.53 v3(220.15,46.53) ; v4(159.45,60.26) 159.48,60.23 159.48,59.88 v3(159.45,59.85)
  BOTTOM w0.102: 158.92,62.4 158.64,62.68 158.64,62.93 158.92,63.2 ; 158.98,63.2 159.52,63.75
  BOTTOM w0.109: JNGFF2.31 238.65,35.64 238.75,35.75 238.75,37.02 v4(238.15,37.63) ; 158.92,62.4 158.92,62.4 UCPU1.C8 158.92,60.81 159.48,60.26 v4(159.45,60.26) ; 159.52,63.75 160.29,64.52 v2(160.29,65.13) RH300.2 ; 158.92,63.2 158.98,63.2
PCH_DP_N0: length 143.4
  TOP w0.109: CV49.1 241.33,43.22 241.33,43.46 241.32,43.47 241.32,44.06 v7(241.03,44.36)
  IN1 w0.076: v3(130.27,61.06) 130.23,61.06 129.85,61.43 129.85,61.8 129.62,62.04 128.77,62.04 127.56,63.24 127.56,64.2 127.91,64.55 129.41,66.05 134.84,66.05 135.4,66.61 146.11,66.61 148.57,69.07 156.76,69.07 158.64,67.19 161.92,67.19 164.79,70.06 193.66,70.06 195.83,67.89 197.83,67.89 200.04,70.1 215.44,70.1 219.73,65.81 227.76,65.81 229.25,64.31 229.25,61.74 231.01,59.98 231.01,56.72 234.18,53.55 235.54,53.55 238.6,50.49 238.6,46.69 240.4,44.89 241.15,44.89 241.37,44.67 241.37,44.48 241.24,44.36 v7(241.03,44.36)
  IN4 w0.076: v3(130.27,61.06) 130.27,61.04 130.32,60.99 130.5,60.99 130.63,61.13 v4(130.63,61.19)
PCH_DP_N0_C: length 6.3
  TOP w0.109: CV49.2 241.31,41.61 241.31,41.5 241,41.19 240.26,41.19 240.25,41.18 238.88,41.18 238.54,40.84 238.54,40.66 v1(238.3,40.42)
  BOTTOM w0.109: v1(238.3,40.42) 238.54,40.66 238.54,40.95 238.9,41.31 JNGFF2.32
PCH_DP_N1: length 136.4
  TOP w0.109: CV48.1 239.53,43.7 239.53,44.1 v6(239.31,44.32) 238.64,44.99 238.64,45.31 v7(238.52,45.42)
  IN1 w0.076: v7(238.52,45.42) 238.68,45.27 238.68,45.12 238.55,44.99 238.4,44.99 238.2,45.19 238.2,46.37 237.13,47.44 237.13,51.27 235.33,53.06 234.01,53.06 230.52,56.55 230.52,59.79 227.13,63.18 226.82,63.18 224.64,65.35 219.5,65.35 215.23,69.62 200.21,69.62 198.02,67.43 195.64,67.43 193.47,69.6 164.99,69.6 161.87,66.48 159.09,66.48 158.4,65.79 152.51,65.79 152.41,65.69 140.52,65.69 140.09,66.12 135.59,66.12 135.06,65.59 129.6,65.59 128.99,64.99 128.8,64.79 128.8,64.19 128.34,63.74 128.21,63.74 128.12,63.83 128.12,63.9 v1(127.98,64.04)
  BOTTOM w0.109: v1(127.98,64.04) 128.39,63.64 128.39,62.31 128.06,61.98 128.06,61.91 UCPU1.B58
PCH_DP_N1_C: length 6.3
  TOP w0.109: CV48.2 239.38,42.45 239.53,42.3 239.53,42.14 239.32,41.93 237.85,41.93 237.18,41.26 237.18,40.81 v1(236.82,40.45)
  BOTTOM w0.109: v1(236.82,40.45) 237.04,40.66 237.04,41.03 237.4,41.39 JNGFF2.26
PCH_DP_N2: length 133.6
  TOP w0.109: CV50.1 235.55,39.04 235.55,39.21 234.15,40.62 v6(234.15,42.4) 234.15,44.91 v7(233.99,45.07)
  IN1 w0.076: v1(132.1,63.81) 132.33,64.04 132.43,64.04 133.22,64.83 135.45,64.83 135.96,65.34 137.92,65.34 138.77,64.49 140.59,64.49 140.78,64.67 141.04,64.93 152.72,64.93 152.8,65.01 159.24,65.01 161.07,65.01 161.47,64.6 164.7,64.6 166.12,66.02 168.52,66.02 169.67,67.17 171.07,67.17 171.63,67.72 172.35,67.72 172.91,67.16 173.56,67.16 173.88,66.84 181.5,66.84 182.26,67.6 190.48,67.6 191.06,68.18 192.95,68.18 195.07,66.06 198.61,66.06 200.72,68.17 203.89,68.17 204.31,67.75 215.14,67.75 218.93,63.97 220.76,63.97 222.08,62.64 224.31,62.64 225.69,61.27 227.07,61.27 229.05,59.29 229.05,56.04 235.2,49.89 235.2,46.76 234.41,45.97 234.41,45.37 234.26,45.22 234.26,45.17 234.16,45.07 v7(233.99,45.07)
  BOTTOM w0.109: v1(132.1,63.81) 131.96,63.95 131.79,63.95 131.22,63.38 130.93,63.38 130.8,63.25 130.8,62.68 130.49,62.37 130.27,62.37 UCPU1.B55
PCH_DP_N2_C: length 4.5
  TOP w0.109: CV50.2 235.61,37.43 235.61,37.24 235.9,36.95 236.73,36.95 237.28,36.39 237.28,36.19 v1(237.12,36.03)
  BOTTOM w0.109: JNGFF2.25 237.15,35.49 237.31,35.64 237.31,35.84 v1(237.12,36.03)
PCH_DP_N3: length 132.5
  TOP w0.109: CV38.1 233.79,39.05 233.79,39.62 233.32,40.09 233.32,43.68 233.31,43.69 233.31,44.21 233.32,44.22 233.32,45.61 v7(233.2,45.73)
  IN1 w0.076: v7(233.2,45.73) 233.34,45.87 233.34,47.72 233.57,47.95 233.57,49.12 233.11,49.58 233.11,51.11 228.44,55.79 228.44,56.76 227.27,57.93 226.31,57.93 222.31,61.93 221.93,61.93 220.54,63.32 218.71,63.32 217.35,64.68 214.2,64.68 213.35,65.53 213.35,66.19 212.4,67.14 200.56,67.14 198.88,65.45 192.28,65.45 191.66,66.07 190.23,66.07 189.31,66.99 182.53,66.99 181.77,66.23 173.56,66.23 173.25,66.54 169.91,66.54 168.73,65.36 167.14,65.36 165.77,63.99 161.19,63.99 160.79,64.4 160,64.4 153.07,64.4 152.99,64.32 141.33,64.32 140.84,63.83 138.6,63.83 138.51,63.91 137.55,63.91 136.02,62.39 131.3,62.39 131.17,62.52 129.44,62.52 129.08,62.89 129.08,63.56 129.46,63.94 v1(129.46,64.22)
  BOTTOM w0.109: UCPU1.A57 128.69,62.76 128.75,62.7 128.86,62.7 129.03,62.86 129.03,62.97 128.92,63.08 128.92,63.18 129.03,63.28 129.03,63.4 129.46,63.83 v1(129.46,64.22)
PCH_DP_N3_C: length 4.6
  TOP w0.109: CV38.2 233.79,37.47 233.79,36.98 234.18,36.59 235.24,36.59 235.49,36.34 235.49,36.23 v1(235.31,36.05)
  BOTTOM w0.109: v1(235.31,36.05) 235.65,35.72 JNGFF2.19
PCH_DP_P0: length 143.5
  TOP w0.109: v7(241.66,44.36) 241.56,44.25 v6(241.56,43.82) 241.56,43.17 CV37.1
  IN1 w0.076: v7(241.66,44.36) 241.52,44.5 241.52,44.74 241.22,45.04 240.47,45.04 238.75,46.76 238.75,50.55 235.6,53.7 234.24,53.7 231.16,56.78 231.16,60.05 229.41,61.81 229.41,64.37 227.82,65.96 219.79,65.96 215.5,70.25 199.98,70.25 197.77,68.04 195.89,68.04 193.72,70.21 164.73,70.21 161.86,67.34 158.71,67.34 156.83,69.22 148.51,69.22 146.04,66.76 135.34,66.76 134.78,66.2 129.34,66.2 127.41,64.27 127.41,63.18 128.71,61.88 129.56,61.88 129.7,61.74 v3(129.7,61.09)
  IN4 w0.076: v3(129.7,61.09) 129.7,61.15 v4(130.07,61.51)
PCH_DP_P0_C: length 6.3
  TOP w0.109: CV37.2 241.53,41.61 241.53,41.41 241.08,40.96 v6(240.52,40.96) 238.97,40.96 238.77,40.75 238.77,40.54 v1(238.88,40.42)
  BOTTOM w0.109: JNGFF2.34 239.4,41.5 238.76,40.86 238.76,40.54 v1(238.88,40.42)
PCH_DP_P1: length 136.6
  TOP w0.109: CV45.1 239.75,43.7 239.75,44.19 239.66,44.29 239.66,44.3 239.29,44.66 239.28,44.66 238.87,45.08 238.87,45.33 v7(238.96,45.42)
  IN1 w0.076: v1(127.98,63.46) 128.11,63.58 128.4,63.58 128.95,64.13 128.95,64.73 129.27,65.04 129.66,65.44 135.12,65.44 135.65,65.97 140.02,65.97 140.46,65.54 152.47,65.54 152.57,65.64 158.46,65.64 159.15,66.33 161.93,66.33 165.06,69.45 193.4,69.45 195.57,67.28 198.09,67.28 200.27,69.46 215.17,69.46 219.44,65.2 224.58,65.2 226.75,63.03 227.07,63.03 230.37,59.72 230.37,56.49 233.95,52.91 235.27,52.91 236.98,51.2 236.98,47.38 238.05,46.31 238.05,45.13 238.33,44.84 238.61,44.84 238.83,45.06 238.83,45.3 v7(238.96,45.42)
  BOTTOM w0.109: UCPU1.C58 128.12,61.31 127.83,61.6 127.83,62.07 128.16,62.4 128.16,63.28 v1(127.98,63.46)
PCH_DP_P1_C: length 6.3
  TOP w0.109: CV45.2 239.91,42.45 239.75,42.3 239.75,42.04 239.41,41.7 237.94,41.7 237.41,41.17 v1(237.41,40.45)
  BOTTOM w0.109: JNGFF2.28 237.9,41.57 237.26,40.93 237.26,40.59 v1(237.41,40.45)
PCH_DP_P2: length 133.7
  TOP w0.109: CV46.1 235.78,39.07 235.78,39.31 234.37,40.71 234.37,42.13 234.38,42.14 234.38,42.66 234.37,42.67 234.37,44.88 v7(234.56,45.07)
  IN1 w0.076: v7(234.56,45.07) 234.56,45.91 235.35,46.69 235.35,49.96 229.2,56.1 229.2,59.36 227.13,61.43 225.75,61.43 224.38,62.8 222.14,62.8 220.82,64.12 218.99,64.12 215.21,67.9 204.37,67.9 203.96,68.32 200.65,68.32 198.55,66.21 195.13,66.21 193.01,68.33 191,68.33 190.41,67.75 182.2,67.75 181.44,66.99 173.95,66.99 173.62,67.31 172.97,67.31 172.41,67.88 171.57,67.88 171.01,67.32 169.6,67.32 168.46,66.18 166.06,66.18 164.64,64.75 161.54,64.75 161.13,65.16 160.32,65.16 152.74,65.16 152.66,65.08 140.98,65.08 140.93,65.04 140.53,64.64 138.83,64.64 137.98,65.49 135.9,65.49 135.39,64.98 133.15,64.98 132.37,64.19 132.3,64.19 v1(132.1,64.4)
  BOTTOM w0.109: UCPU1.A55 130.29,62.59 130.4,62.59 130.58,62.78 130.58,63.35 130.84,63.6 131.13,63.6 131.69,64.17 131.87,64.17 v1(132.1,64.4)
PCH_DP_P2_C: length 4.4
  TOP w0.109: CV46.2 235.83,37.51 235.83,37.33 236,37.17 236.82,37.17 237.5,36.49 237.5,36.22 v1(237.7,36.03)
  BOTTOM w0.109: v1(237.7,36.03) 237.53,35.85 237.53,35.64 237.65,35.52 JNGFF2.27
PCH_DP_P3: length 132.5
  TOP w0.109: CV47.1 234.01,39.05 234.01,39.71 233.55,40.18 v6(233.55,43.95) 233.55,45.64 v7(233.64,45.73)
  IN1 w0.076: v1(129.88,63.79) 129.83,63.79 129.83,63.79 129.78,63.84 129.57,63.84 129.23,63.5 129.23,62.95 129.51,62.67 131.24,62.67 131.36,62.54 135.96,62.54 137.48,64.07 138.58,64.07 138.66,63.98 140.77,63.98 141.27,64.47 152.93,64.47 153,64.55 159.43,64.55 160.06,64.55 160.06,64.55 160.85,64.55 161.26,64.14 165.7,64.14 167.07,65.51 168.66,65.51 169.84,66.7 173.31,66.7 173.63,66.38 181.7,66.38 182.47,67.14 189.38,67.14 190.29,66.23 191.73,66.23 192.35,65.6 198.81,65.6 200.5,67.29 212.46,67.29 213.51,66.25 213.51,65.59 214.27,64.83 217.42,64.83 218.78,63.47 220.6,63.47 221.99,62.09 222.37,62.09 226.37,58.09 227.34,58.09 228.59,56.83 228.59,55.85 233.27,51.18 233.27,49.64 233.72,49.18 233.72,47.89 233.5,47.66 233.5,45.87 v7(233.64,45.73)
  BOTTOM w0.109: UCPU1.B57 128.69,62.2 129.18,62.7 129.25,62.77 129.25,63.31 129.74,63.79 v1(129.88,63.79)
PCH_DP_P3_C: length 4.6
  TOP w0.109: v1(235.9,36.05) 235.71,36.24 235.71,36.44 235.34,36.81 234.27,36.81 234.01,37.07 234.01,37.47 CV47.2
  BOTTOM w0.109: JNGFF2.21 236.15,35.8 v1(235.9,36.05)
PCH_DPWROK: length 15.7
  BOTTOM w0.102: 161.33,39.2 160.55,39.98 160.55,41.24 UCPU1.AV5
  BOTTOM w0.109: 161.33,39.2 162.25,39.2 162.56,38.89 163.98,38.89 164.36,39.28 166,39.28 v2(166.57,38.71) 167.71,37.57 RH126.1 RH401.1 168.77,36.51 169.3,35.98 169.3,34.51 RH309.2
PCH_ENVDD: length 145.9
  TOP w0.109: v1(93.16,59.55) 92.72,59.1 D105.2 ; v7(186.9,52.94) 186.9,54.01 187.65,54.76 D93.2 187.65,57.38 v1(187.43,57.6) ; v7(199.78,52.99) 199.78,52.59 199.97,52.39 199.97,47.44 202.44,44.97 202.44,42.1 201.87,41.53 v2(201.87,41) D306.2
  IN1 w0.076: v7(186.9,52.94) 186.9,52.6 187.83,51.67 188.89,51.67 189.79,52.57 191.45,52.57 192.23,51.79 195.08,51.79 195.65,52.36 196.99,52.36 197.5,52.87 199.65,52.87 v7(199.78,52.99) ; v1(93.16,59.55) 93.29,59.67 94.06,59.67 95.03,60.64 102.73,60.64 104.14,62.05 105.92,62.05 109.13,65.25 112.54,65.25 114.29,63.51 119.91,63.51 120.32,63.91 v3(121.05,63.91)
  IN3 w0.102: v3(121.05,63.91) 127.12,63.91 128.29,65.08 129.15,65.08 129.51,65.44 136.87,65.44 137.91,64.4 138.04,64.27 160.33,64.27 v3(160.65,63.95) 168.17,63.95 169.44,65.22 173.49,65.22 178.25,60.46 180.38,60.46 182.1,58.75 183.34,58.75 184.26,57.83 184.49,57.83 185.36,56.96 186.96,56.96 187.43,57.43 v1(187.43,57.6)
  IN4 w0.076: v3(160.65,63.95) v4(161.05,63.95)
  BOTTOM w0.102: 159.31,62.87 159.31,62.68 159.68,62.31 UCPU1.C6
  BOTTOM w0.109: 159.31,62.87 160.41,63.97 161.04,63.97 v4(161.05,63.95) 161.05,64.19 162.93,66.07 RH158.2
PCH_GPIO15: length 10.1
  TOP w0.109: v7(160.28,50.17) 160.62,50.17 v2(161.15,50.7) 162.88,52.43 164.29,52.43 164.79,52.93 165.72,52.93 165.74,52.91 166.33,52.91 166.49,53.07 166.49,53.71 RH270.1
  IN1 w0.076: v3(159.89,50.12) 159.84,50.12 159.89,50.17 v7(160.28,50.17)
  IN4 w0.076: v4(160.27,50.2) 160.24,50.17 159.89,50.17 159.84,50.12 v3(159.89,50.12)
  BOTTOM w0.109: v4(160.27,50.2) 160.17,50.1 UCPU1.AD6
PCH_GPIO17: length 17.9
  TOP w0.109: RH301.1 172.12,55.73 171.97,55.58 v7(171.06,55.58)
  IN1 w0.076: v7(171.06,55.58) 170.76,55.28 169.13,55.28 168.89,55.52 168.89,55.78 168.1,56.57 165.8,56.57 164.23,58.15 163.9,58.15 163.49,58.56 162.93,58.56 162.25,57.87 v7(162.25,56.88) 162.93,56.19 162.93,55.76 161.54,54.36 v3(161.54,54.08)
  IN4 w0.076: v4(161.87,54.34) 161.79,54.34 v3(161.54,54.08)
  BOTTOM w0.109: UCPU1.T3 162.07,54.13 v4(161.87,54.34)
PCH_GPIO18: length 18.8
  TOP w0.109: v7(174.82,54.44) 174.89,54.38 174.89,53.73 174.17,53.02 Q348.1 174.17,52 174.49,51.68 175.19,51.68 RH417.2
  IN1 w0.076: v3(175.2,54.44) v7(174.82,54.44)
  IN4 w0.076: v3(175.2,54.44) 175.05,54.29 172.01,54.29 171.76,54.54 168.77,54.54 168.38,54.93 167.08,54.93 v4(166.62,54.47)
  BOTTOM w0.109: UCPU1.U2 162.81,53.4 163.11,53.7 164.34,53.7 165.3,54.66 166.43,54.66 v4(166.62,54.47)
PCH_GPIO20: length 95.5
  TOP w0.109: v2(228.34,45.51) 228.79,45.97 Q346.1 228.12,47.36 228.12,47.61 228.79,48.28 228.79,49.64 RH410.2 229.11,49.98 v7(228.67,50.43)
  IN1 w0.076: v7(228.67,50.43) 228.67,50.73 v3(228.57,50.83)
  IN2 w0.102: v3(165.97,56.98) 167.06,58.07 174.23,58.07 176.17,60.01 176.17,60.43 176.84,61.1 180.66,61.1 182.77,63.2 185.85,63.2 187.29,64.64 196.58,64.64 197.31,63.91 198.9,62.31 199.77,62.31 201.71,60.38 201.71,60.2 204.04,57.87 212.41,57.87 212.79,57.49 214.3,57.49 214.57,57.76 216.1,57.76 219.02,54.83 223.6,54.83 225.75,52.69 225.75,51.75 226.04,51.46 227.95,51.46 v3(228.57,50.83)
  IN3 w0.102: v3(165.97,56.98) 167.44,56.98 168.78,55.64 168.78,55.22 168.48,54.92 167.28,54.92 166.95,54.59 v3(166.95,53.04)
  IN4 w0.076: v3(166.95,53.04) 166.88,53.04 166.15,52.31 166.15,51.95 165.23,51.04 v4(164.97,51.04)
  BOTTOM w0.109: UCPU1.AD1 163.46,49.93 163.14,50.25 163.14,50.45 163.37,50.68 164.2,50.68 164.56,51.04 v4(164.97,51.04) 165.64,51.04 165.88,50.8 165.88,50.42 166.12,50.18 166.12,49.63 RH100.2
PCH_GPIO21: length 13.8
  IN1 w0.076: v3(163.98,56.02) 164.47,55.52 167.1,55.52 168.17,54.45 v3(168.23,54.45)
  IN4 w0.076: v4(164.36,55.99) 164.33,56.02 v3(163.98,56.02) ; v3(168.23,54.45) 168.48,54.2 v4(168.94,54.2)
  BOTTOM w0.109: RH103.2 166.43,56.82 v2(165.55,56.82) 165.18,56.82 v4(164.36,55.99) 164.03,55.66 163.53,55.66 UCPU1.N1 ; v4(168.94,54.2) 169.34,53.81 Q350.1 168.4,51.6 RH418.2
PCH_GPIO22: length 9.8
  BOTTOM w0.102: UCPU1.U5 161.36,53.62 161.59,53.85 162.28,53.85 162.45,54.03 162.45,54.19 162.83,54.56 163.39,54.56 163.91,54.05 164.31,54.05
  BOTTOM w0.109: 164.31,54.05 165.25,54.99 167.95,54.99 RH107.2 169.18,54.54 v2(169.32,54.4)
PCH_GPIO27: length 12.4
  TOP w0.109: RH186.2 RH310.2 RH427.1 167.61,45.58 167.35,45.32 RH464.1 165.27,45.32 162.7,42.76 162.22,42.76 161.36,43.61 v2(161.36,44.12) 161.1,44.38 v1(160.17,44.38)
  BOTTOM w0.109: UCPU1.AN5 160.53,44.74 160.17,44.38 v1(160.17,44.38)
PCH_GPIO35: length 3.8
  BOTTOM w0.109: RH390.1 165.92,54.28 T271.1 165.3,54.28 164.39,53.36 163.48,53.36 UCPU1.U1
PCH_GPIO36: length 17.9
  IN4 w0.076: v4(160.14,52.31) 160.14,52.46 160.37,52.69 161.33,52.69 161.44,52.59 163.7,52.59 164.05,52.94 165.23,52.94 166.24,53.94 166.24,54.77 166.59,55.13 168.47,55.13 168.83,54.77 171.82,54.77 172.1,54.49 173.06,54.49 v4(173.67,55.1)
  BOTTOM w0.109: T272.1 172.93,56.17 173.67,55.44 v4(173.67,55.1) ; UCPU1.V6 160.17,52.34 v4(160.14,52.31)
PCH_HDMI_CLK: length 192.1
  IN3 w0.102: v1(29.08,39.33) 29.61,39.86 29.97,39.86 30.23,39.59 30.23,39.16 31.13,38.26 31.13,36.61 32.51,35.24 32.51,32.93 34.16,31.28 34.16,29.62 35.45,28.32 35.45,26.26 36.76,24.96 36.76,23.06 41.46,18.36 42.22,18.36 44.68,15.9 46.29,15.9 47.16,15.02 47.95,15.02 49.07,13.9 50.8,13.9 51.53,13.17 53.03,13.17 54,12.2 66.27,12.2 66.75,11.72 73.47,11.72 75.17,10.02 89.75,10.02 98.89,19.15 98.89,29 101.82,31.94 106.29,31.94 113.88,39.52 113.88,42.15 113.67,42.35 113.67,44.12 117.32,47.77 117.32,49.57 117.14,49.75 117.14,52.84 117.11,52.87 117.11,55.86 123.62,62.37 125.95,62.37 126.23,62.09 129.71,62.09 129.9,61.9 136.05,61.9 136.24,62.09 153.05,62.09 153.54,61.6 158.46,61.6 v3(158.9,61.17)
  IN4 w0.076: v4(158.52,61.03) 158.75,61.03 v3(158.9,61.17)
  BOTTOM w0.109: v4(158.52,61.03) 158.27,61.27 158.03,61.27 157.8,61.5 157.8,61.78 158.03,62.01 158.03,62.31 157.68,62.67 157.68,63.95 158.24,64.51 158.24,65.76 RH388.2 ; v1(29.08,39.33) 29.3,39.1 29.3,38.95 29.2,38.84 U722.38
PCH_HDMI_DAT: length 190.4
  IN3 w0.102: v3(158.01,61.05) 157.81,61.25 153.26,61.25 152.77,61.73 136.39,61.73 136.21,61.55 129.66,61.55 129.48,61.73 125.9,61.73 125.75,61.88 123.82,61.88 117.62,55.69 117.62,49.95 117.8,49.77 117.8,45.95 116.23,44.38 114.65,44.38 114.15,43.89 114.15,42.55 114.38,42.32 114.38,39.34 106.14,31.1 101.67,31.1 99.37,28.8 99.37,18.95 89.95,9.53 74.97,9.53 73.27,11.24 66.55,11.24 66.06,11.72 53.8,11.72 52.83,12.68 51.33,12.68 50.6,13.42 48.87,13.42 47.75,14.54 46.96,14.54 46.09,15.41 44.48,15.41 42.02,17.88 41.26,17.88 36.28,22.86 36.28,24.76 34.94,26.09 34.94,28.12 33.67,29.39 33.67,31.08 30.24,34.51 30.24,38.46 29.74,38.97 v1(29.74,39.33)
  IN4 w0.076: v4(157.61,61.03) 157.97,61.03 158.01,60.99 v3(158.01,61.05)
  BOTTOM w0.102: 156.81,63.31 156.81,62.7 157.32,62.19 157.32,61.88 157.57,61.63 157.57,61.06 v4(157.61,61.03)
  BOTTOM w0.109: U722.39 29.6,38.89 29.54,38.95 29.54,39.13 v1(29.74,39.33) ; RH389.2 156.91,65.96 156.91,63.4 156.81,63.31
PCH_HDMI_HPD: length 193.3
  IN3 w0.102: v3(161.94,65.18) 161.92,65.16 160.63,65.16 159.97,64.5 138.14,64.5 136.84,65.79 128.85,65.79 128.37,65.31 127.98,65.31 126.99,64.32 120.57,64.32 120.24,63.99 120.24,59.67 118.54,57.97 117.49,57.97 115.11,55.58 115.11,49.72 116.2,48.62 116.2,48.23 114.15,46.18 109.54,46.18 106.57,43.21 106.57,37.4 98.4,29.23 98.4,19.35 89.55,10.5 75.37,10.5 73.67,12.2 66.95,12.2 66.47,12.68 54.2,12.68 53.23,13.65 51.73,13.65 51,14.38 49.27,14.38 48.15,15.5 47.36,15.5 46.46,16.4 45.62,16.4 44.29,17.74 43.63,17.74 40.11,21.26 39.24,21.26 37.31,23.19 37.31,25.09 35.99,26.41 35.99,28.47 34.64,29.82 34.64,31.48 32.99,33.13 32.99,35.44 v1(31.57,36.86)
  IN4 w0.076: v3(161.94,65.18) 161.94,65.39 v4(161.79,65.54)
  BOTTOM w0.109: RH387.2 162.12,65.87 v4(161.79,65.54) 161.79,65.51 161.35,65.07 161.18,65.07 159.82,63.72 159.82,63.71 159.08,62.97 159.07,62.97 UCPU1.A8 ; v1(31.57,36.86) 31.51,36.81 U722.3
PCH_INTVRMEN: length 8.7
  BOTTOM w0.102: 158.88,39.78 158.88,40.77 159.3,41.19 UCPU1.AV7
  BOTTOM w0.109: RH31.2 159.84,34.79 159.84,35.77 160.25,36.19 RH34.2 160.67,36.51 v2(160.67,37.1) 160.38,37.38 160.38,37.55 158.88,39.06 158.88,39.78
PCH_INV_PWM: length 39.6
  TOP w0.109: v1(143.63,70.34) 143.38,70.34 142.97,69.93 v2(141.92,69.93) 141.71,69.93 141.13,69.35 139.83,69.35 RC146.2
  BOTTOM w0.109: 160.34,68.79 159.67,69.46 146.97,69.46 146.86,69.35 146.86,68.12 146.6,67.87 144.95,67.87 143.63,69.19 v1(143.63,70.34) ; 160.34,68.79 160.56,69.01 166,69.01 169.06,65.95 170.22,65.95 170.92,66.65 D106.3 ; 160.34,68.79 RC147.1
PCH_JTAG_JTAGX: length 12.2
  BOTTOM w0.109: UCPU1.AE63 124.26,48.89 124.05,48.68 122.33,48.68 121.51,47.85 121.51,46.49 120.7,45.69 119.05,45.69 118.89,45.53 RH374.1 118.08,45.88 T273.1 117.6,47.2 RH375.2 117.6,48.75 RH412.1
PCH_JTAG_TCK: length 11.2
  BOTTOM w0.109: RH53.2 RH411.1 RH373.1 121.05,43.42 T277.1 121.69,44.06 121.69,47.35 122.54,48.19 124.01,48.19 124.4,48.59 125.18,48.59 UCPU1.AE62
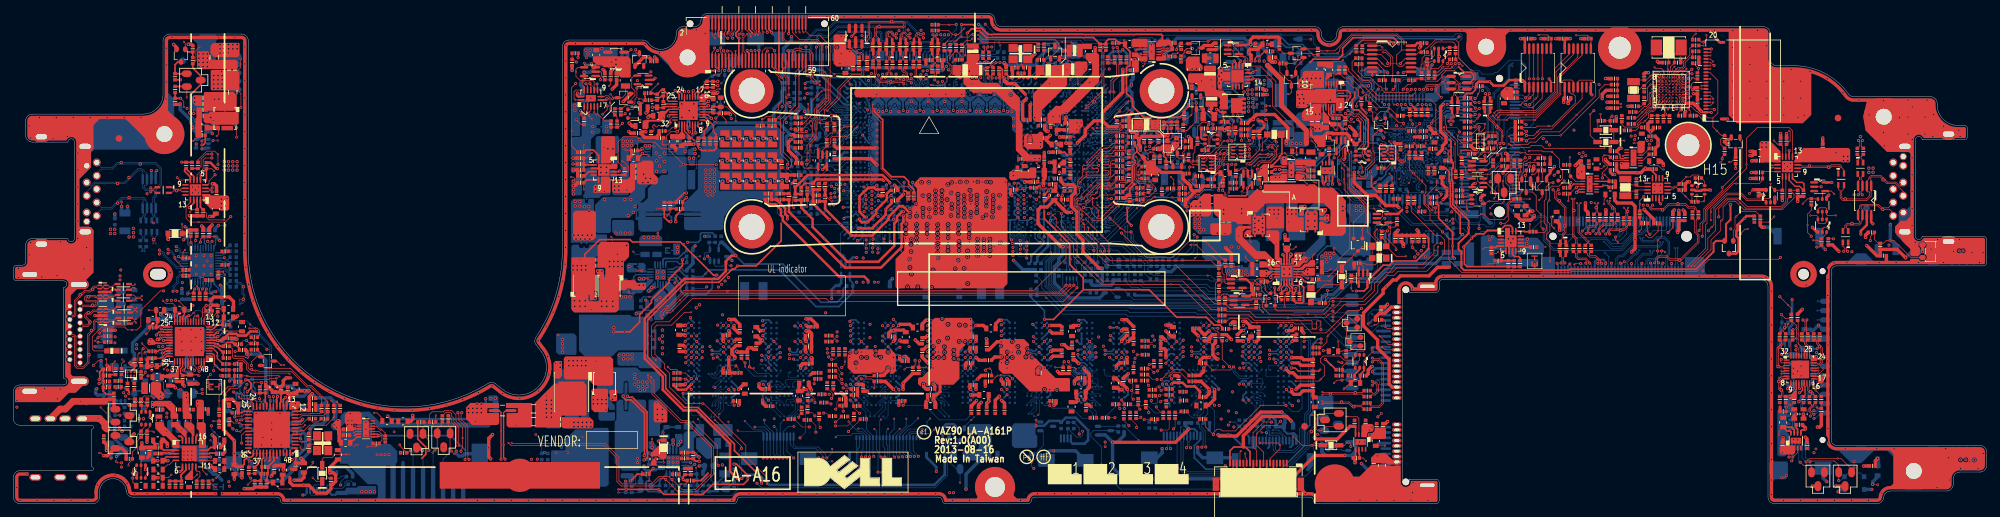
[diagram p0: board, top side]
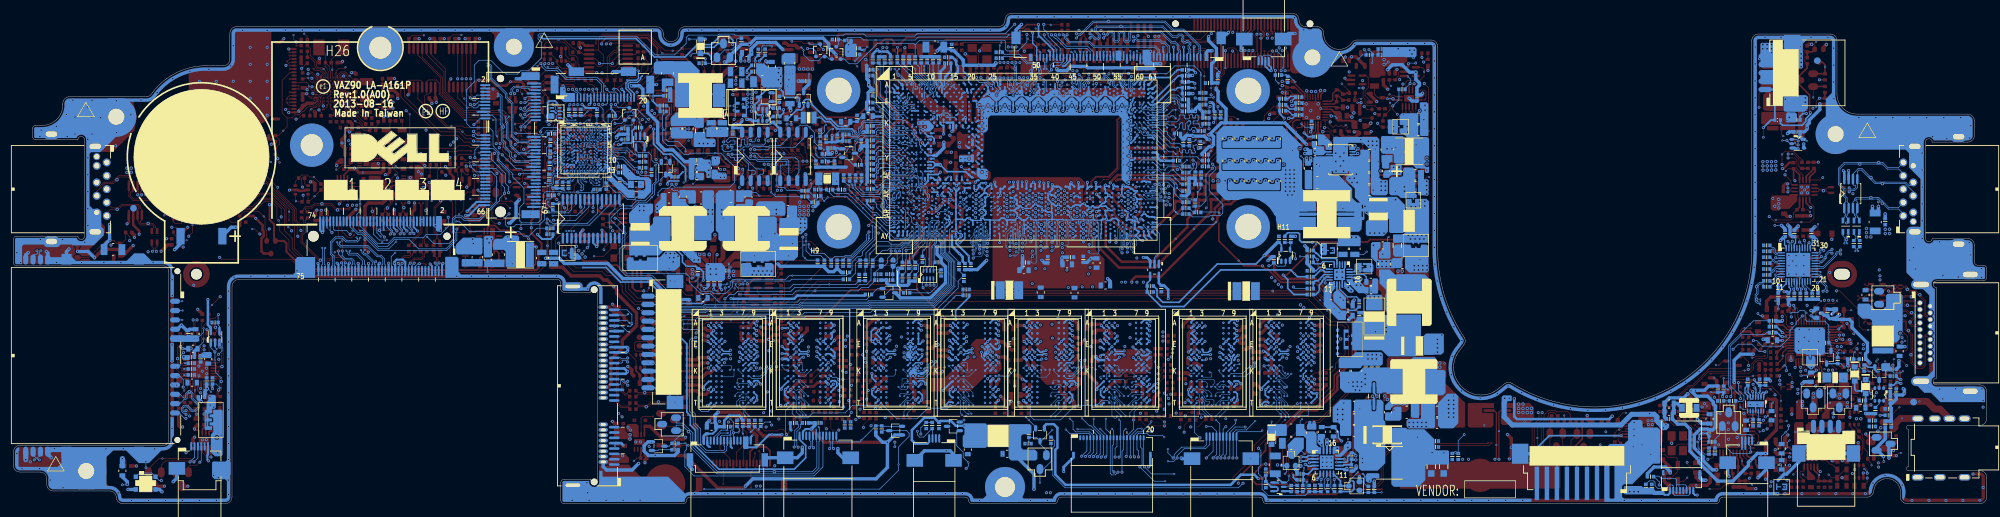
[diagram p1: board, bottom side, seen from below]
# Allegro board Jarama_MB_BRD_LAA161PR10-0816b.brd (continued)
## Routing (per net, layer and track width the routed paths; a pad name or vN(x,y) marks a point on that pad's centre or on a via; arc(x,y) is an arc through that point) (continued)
PCH_JTAG_TDI: length 57.3
  TOP w0.109: RH371.1 91.36,58.28 v1(91.56,58.48)
  IN2 w0.102: v1(91.56,58.48) 92.17,59.09 94.09,59.09 99.35,64.35 107.92,64.35 108.76,65.18 111.88,65.18 113.56,63.51 118.8,63.51 119.22,63.09 119.22,56.64 119.96,55.9 119.96,52.82 123.14,49.64 125.51,49.64 v3(125.84,49.97)
  IN4 w0.076: v4(126.13,49.68) 126.13,49.68 v3(125.84,49.97)
  BOTTOM w0.102: T278.1 121.73,50.04 121.97,50.04 122.43,49.58 123.49,49.58 123.95,50.04 125.77,50.04 v4(126.13,49.68)
  BOTTOM w0.109: RH40.2 120.44,48.75 T278.1
PCH_JTAG_TDO: length 50
  TOP w0.109: v1(91.14,57.01) 90.58,56.45 RH413.1 RH369.1
  IN2 w0.102: v1(91.14,57.01) 91.78,57.64 92.46,57.64 93.75,56.35 98.34,56.35 98.88,56.88 103.57,56.88 103.97,56.49 115.09,56.49 115.84,55.74 116.68,55.74 116.99,55.43 116.99,53.49 118.32,52.15 119.65,52.15 122.85,48.95 125.06,48.95 125.52,48.49 125.77,48.49 v3(125.8,48.52)
  IN4 w0.076: v3(125.8,48.52) 126.13,48.85 v4(126.13,48.85)
  BOTTOM w0.076: v4(126.13,48.85) 125.78,49.21 125.39,49.21 125.34,49.16 124.2,49.16
  BOTTOM w0.109: 124.2,49.16 123.96,48.92 122.23,48.92 121.15,47.83 T275.1 120.67,46.85 RH445.2
PCH_JTAG_TMS: length 53.9
  TOP w0.109: v5(88.19,58.38) 88.87,59.05 v1(88.87,59.62)
  IN2 w0.102: v1(88.87,59.62) 89.3,59.62 91.03,57.89 92.53,57.89 93.72,56.7 98.37,56.7 98.78,57.11 103.67,57.11 104.06,56.71 115.27,56.71 115.39,56.6 116.63,56.6 117.21,56.02 117.21,53.59 118.42,52.38 119.75,52.38 122.95,49.18 125.52,49.18 125.65,49.06 v3(125.57,49.06)
  IN4 w0.076: v4(125.48,49.64) 125.48,49.14 v3(125.57,49.06)
  BOTTOM w0.076: 123.88,49.37 125.03,49.37 125.3,49.64 v4(125.48,49.64)
  BOTTOM w0.109: RH39.2 120.49,47.86 T276.1 121.78,49.15 123.66,49.15 123.88,49.37 ; RH372.1 87.95,60.54 v1(88.87,59.62)
PCH_JTAG_TRST#: length 67.6
  TOP w0.109: v5(84.23,57.56) 84.97,56.83 v7(85.41,56.83)
  IN1 w0.076: v7(85.41,56.83) 85.62,57.03 90.49,57.03 90.99,57.54 92.54,57.54 93.25,56.83 97.45,56.83 97.78,56.5 98.5,56.5 98.83,56.83 99.32,56.83 99.99,56.17 102.3,56.17 102.73,55.74 104.93,55.74 105.84,56.65 107.69,56.65 108.96,57.92 111.85,57.92 112.36,58.43 116.13,58.43 117.81,56.75 119.07,56.75 119.93,55.89 119.93,52.94 119.15,52.15 118.66,52.15 118.2,51.7 118.2,50.76 v3(118.13,50.68)
  IN3 w0.102: v3(114.56,42.73) 114.56,43.07 115.48,43.99 116.16,43.99 118.92,46.75 118.92,49.34 118.13,50.12 v3(118.13,50.68)
  IN4 w0.076: v4(115.31,42.2) 115.27,42.2 114.78,42.69 114.6,42.69 v3(114.56,42.73)
  BOTTOM w0.109: UCPU1.AU62 125.4,42.15 125.06,41.82 115.69,41.82 v4(115.31,42.2)
PCH_OPIRCOMP: length 7.5
  BOTTOM w0.178: UCPU1.AW15 154.13,40.84 153.8,40.5 153.47,40.5 153.28,40.32 153.28,40.05 153.49,39.84 153.73,39.84 153.93,39.65
  BOTTOM w0.305: RC156.1 152.32,36.3 v2(152.32,37.12) 154.2,39 154.2,39.38 153.93,39.65
PCH_PLTRST#: length 34.9
  TOP w0.109: 185.38,48.98 185.38,48.91 185.22,48.75 184.97,48.75 184.73,48.99 UH5.2 184.73,50.05 184.45,50.33 183.85,50.33 183.48,49.96 RH168.2 182.78,50.12 182.78,50.72 v1(182.94,50.87) ; 185.38,48.98 185.76,48.6 RH183.2 186.67,48.42 v5(186.67,47.39) ; 185.38,48.98 UH5.1
  IN3 w0.102: v1(182.94,50.87) 182.01,51.8 175.68,51.8 175.1,51.21 170.37,51.21 169.68,50.53 168.55,50.53 167.56,49.54 165.25,49.54 164.46,48.75 161.44,48.75 161.16,48.47 161.16,47.89 160.88,47.61 159.48,47.61 v3(159.12,47.96)
  IN4 w0.076: v4(159.52,47.9) 159.18,47.9 v3(159.12,47.96)
PCH_PWR_EN: length 8.7
  IN4 w0.076: v4(214.32,55.46) 213.59,56.18 213.46,56.18 213.06,56.57 212.41,56.57 212.01,56.17 211.33,56.17 211.18,56.32 210.89,56.32 210.58,56.62 210.25,56.62 209.92,56.96 v4(209.92,57.03)
  BOTTOM w0.076: v4(209.92,57.03) 209.44,57.51 v2(209.1,57.51) 209.01,57.43 209.01,56.7 209.11,56.61 209.11,55.69 U34.F2
PCH_PWRBTN#_XDP: length 11
  TOP w0.109: RH21.2 114.01,56.64 RH444.2 115.5,59 115.5,59.66 115.22,59.94 115.22,63.58 v2(114.97,63.84) 114.97,63.89 114.26,64.59 114.26,65.13 114.07,65.33 JXDP.41
PCH_PWROK: length 51
  TOP w0.109: v1(161.7,37.95) 161.7,38.44 159.57,40.57 159.57,43.87 158.73,44.71 158.73,45.75 159.53,46.55 v5(159.53,47.37) 159.28,47.62 159.28,48.35 159.99,49.06 159.99,50.48 160.22,50.71 160.65,50.71 162.74,52.8 163.96,52.8 164.63,53.46 165.02,53.46 RH134.2 ; R1295.2 180.87,33.16 180.87,33.99 R1297.2 R1296.2 179.24,36.44 164.13,36.44 v1(162.7,37.88)
  IN3 w0.102: v1(162.7,37.88) 162.7,37.88 161.77,37.88 v1(161.7,37.95)
  BOTTOM w0.109: RH394.1 161.77,34.77 161.77,36.56 161.7,36.62 v1(161.7,37.95) 161.55,38.11 161,38.11 159.34,39.78 UCPU1.AY7
PCH_PWROK_EC: length 71.2
  TOP w0.109: R1294.1 181.78,30.46 185.22,30.46 185.55,30.79 186.44,30.79 186.95,30.29 186.95,29.42 187.97,28.4 v2(193.76,28.4) 196.18,28.4 197.09,29.32 197.69,29.32 198.68,30.3 202.06,30.3 203.7,31.94 203.7,32.97 205.43,34.71 206.4,34.71 207.02,35.33 211.09,35.33 213.19,37.42 v7(213.19,38.53)
  IN1 w0.076: v3(208.83,53.12) 209.16,53.45 209.54,53.45 209.82,53.17 212.43,53.17 212.6,53.35 213.05,53.35 213.43,53.73 216.06,53.73 216.43,53.36 218.03,53.36 219.23,52.15 v3(219.63,52.15) ; v3(213.63,38.46) 213.57,38.53 v7(213.19,38.53)
  IN4 w0.076: v3(219.63,52.15) 219.63,50.27 220.44,49.46 220.44,47.48 219.67,46.71 219.67,46.08 219.93,45.82 219.93,45.75 220.03,45.65 220.03,43.52 218.87,42.36 218.87,41 216.4,38.54 213.71,38.54 v3(213.63,38.46) ; v3(208.83,53.12) 208.83,53.15 v4(209.21,53.53)
  BOTTOM w0.076: U34.E6 209.13,53.44
  BOTTOM w0.109: 209.13,53.44 v4(209.21,53.53)
PCH_RSMRST#: length 72.2
  IN4 w0.076: v4(207.87,54.97) 207.87,54.9 207.1,54.14 206.85,54.14 205.96,53.25 205.44,53.25 204.16,51.97 204.16,51.15 203.5,50.49 203.5,49.12 201.12,46.74 200.18,46.74 198.84,45.4 181.76,45.4 178.95,42.59 178.95,39.24 181.4,36.79 185.97,36.79 186.76,36 186.76,33.76 187.2,33.33 v4(187.2,32.98)
  BOTTOM w0.076: v4(207.87,54.97) 207.87,54.83 208.26,54.44 U34.D4
  BOTTOM w0.109: v4(187.2,32.98) 187.2,32.66 186.87,32.32 179.12,32.32 178.57,32.88 v2(173.2,32.88) 169.28,32.88 RH159.1 RH133.2
PCH_RSMRST#_R: length 12.2
  BOTTOM w0.109: UCPU1.AW6 160.37,40.55 160.37,39.91 161.15,39.13 161.15,39.12 161.26,39.02 162.08,39.02 162.48,38.62 165.97,38.62 v2(167.11,37.47) 167.23,37.35 167.23,36.07 RH126.2 167.84,35.47 RH133.1
PCH_RTCRST#: length 68.1
  TOP w0.109: v1(188.28,12.23) 187.12,12.23 185.53,10.64 185.53,8.52 186.06,7.98 JAPS.10 ; v1(163.95,37.88) 163.95,39.15 160.55,42.55 v7(160.08,42.55)
  IN1 w0.076: v7(160.08,42.55) 159.98,42.45 159.89,42.45 v3(159.71,42.27)
  IN4 w0.076: v4(159.3,42.14) 159.43,42.27 v3(159.71,42.27) ; v1(188.28,12.23) 188.82,12.76 189.43,12.76 190.98,14.31 190.98,16.24 191.33,16.59 192.02,16.59 193.1,17.67 193.1,22.91 192.35,23.66 192.35,25.74 191.89,26.2 191.89,27.65 189.5,30.04 188.05,30.04 186.73,31.36 v4(186.73,31.38)
  BOTTOM w0.109: v1(163.95,37.88) 163.95,37.3 164.48,36.76 164.48,36.1 164.92,35.67 165.32,35.67 CLRP1.2 166.39,34.6 CH4.2 RH25.2 166.39,33.38 167.38,32.39 168.39,32.39 168.88,31.9 v5(175.34,31.9) 178.16,31.9 178.71,31.34 186.7,31.34 v4(186.73,31.38)
PCH_RTCX1: length 18.4
  BOTTOM w0.109: UCPU1.AW5 161.21,40.46 161.21,39.98 161.4,39.78 163.46,39.78 166.4,42.73 166.58,42.73 v2(168.14,44.28) 170.37,46.52 172.34,46.52 172.68,46.86 RH2.1 CH2.1 171.81,48.26 YH1.1
PCH_RTCX2: length 18.9
  BOTTOM w0.109: UCPU1.AY5 160.87,40.02 161.34,39.55 162.56,39.55 162.71,39.4 163.77,39.4 166.56,42.2 166.74,42.2 170.57,46.03 v2(170.83,46.03) 172.57,46.03 173.59,47.05 RH2.2 CH3.1 174.76,47.37 YH1.2
PCH_SATALED#: length 5.3
  BOTTOM w0.109: UCPU1.U3 162.49,52.98 163.96,52.98 164.06,52.88 164.6,52.88 165.26,53.54 165.77,53.54 RH35.2
PCH_SMBCLK: length 75.6
  TOP w0.109: v1(178.91,56.88) 178.7,56.66 RH98.2 178.7,56 178.32,55.62 QH3.1 178.66,55.27 178.81,55.12 178.81,53.81 178.5,53.5 178.39,53.5 RH105.2 ; v7(120.72,62.75) 120.57,62.89 120.17,62.89 v6(119.97,63.1) 119.33,63.73 119.33,67.39 118.98,67.74 117.94,67.74 117.72,67.95 117.13,67.95 116.98,67.81 116.98,67.67 117.07,67.58 JXDP.53
  IN1 w0.076: v7(120.72,62.75) v3(121.1,62.75)
  IN3 w0.102: v1(178.91,56.88) 178.73,57.06 177.63,57.06 177.45,57.23 169.45,57.23 166.91,59.77 164.81,59.77 162.2,62.39 135.48,62.39 135.35,62.26 130.35,62.26 130.22,62.39 126.82,62.39 126.03,63.18 122.52,63.18 122.24,62.9 121.25,62.9 v3(121.1,62.75)
PCH_SMBDATA: length 80.3
  TOP w0.109: v7(120.71,63.31) 120.61,63.2 120.3,63.2 119.64,63.86 v6(119.64,64.45) 119.64,67.52 119.11,68.05 118.07,68.05 117.85,68.27 117,68.27 116.67,67.94 116.67,67.67 116.57,67.58 JXDP.51 ; RH111.2 177.2,56.47 177.83,57.11 178.52,57.11 178.72,57.31 179.09,57.31 v1(179.52,56.88) 179.56,56.84 RH99.2 180.09,55.71 180.49,55.71 180.73,55.47 180.73,54.45 180.22,53.94 180.22,53.94 QH3.4
  IN1 w0.076: v3(121.1,63.33) 120.73,63.33 v7(120.71,63.31)
  IN3 w0.102: v3(121.1,63.33) 121.23,63.2 122.12,63.2 122.4,63.48 126.15,63.48 126.94,62.7 130.35,62.7 130.47,62.57 135.22,62.57 135.35,62.7 162.32,62.7 164.94,60.08 167.04,60.08 169.58,57.54 177.58,57.54 177.75,57.36 179.04,57.36 v1(179.52,56.88)
PCH_SMLCLK: length 182.5
  TOP w0.102: R1350.2 251.69,47.96 251.41,47.68 Q359.1
  TOP w0.109: R1350.2 252.04,48.81 252.15,48.7 252.15,47.58 v1(252.02,47.46) ; v1(201.86,49.69) 201.86,50.58 Q352.6 ; QH4.1 214.29,68.24 214.43,68.39 RH453.2 R983.2 215.83,68.84 215.47,69.2 212.92,69.2 212.15,68.42 212.15,67.42 211.89,67.17 211.21,67.17 210.82,66.78 210.82,65.91 210.66,65.76 v7(210.66,65.24)
  IN1 w0.076: v7(210.66,65.24) 210.91,65.49 210.91,65.57 210.81,65.67 210.48,65.67 210.25,65.44 208.32,65.44 208.04,65.16 204.26,65.16 203.85,64.75 203.28,64.75 203.17,64.64 v3(203.17,64.45) ; v1(201.86,49.69) 201.86,49.68 202.18,49.36 203.06,49.36 203.26,49.16 209.38,49.16 210.44,50.22 212.5,50.22 212.72,50.01 215.53,50.01 215.86,50.34 221.47,50.34 222.69,49.12 224.64,49.12 226.45,47.32 226.45,45.73 228.23,43.95 228.23,43.62 229.88,41.97 231.46,41.97 234.69,38.74 239.85,38.74 240.94,39.84 245.44,39.84 247.25,41.64 250.87,41.64 251.43,42.2 252.19,42.2 v3(252.6,41.79)
  IN3 w0.102: v1(173.17,8.25) 173.02,8.4 173.02,8.54 173.14,8.67 175.2,8.67 176.01,9.48 189.25,9.48 195.55,15.78 195.55,23.1 195.84,23.39 196.01,23.39 196.59,23.97 196.59,30.84 197.71,31.96 197.71,34.4 202.15,38.84 202.15,41.26 203.47,42.58 203.47,46.97 202.79,47.66 202.79,48.47 201.86,49.4 v1(201.86,49.69) 201.86,49.73 201.68,49.91 201.68,52.68 202.36,53.35 202.36,55.41 203.46,56.51 203.46,58.87 203.83,59.24 203.83,60.37 202.79,61.41 202.79,61.88 202.3,62.37 202.3,62.9 203.22,63.81 203.22,64.4 v3(203.17,64.45) ; v1(252.02,47.46) 252.51,46.97 252.51,41.88 v3(252.6,41.79)
  BOTTOM w0.076: U34.B8 207.1,52.7 207.1,53.07 206.98,53.2 206.72,53.2 206.42,52.89 206.22,52.89
  BOTTOM w0.109: JTP1.10 173.15,9.37 173.06,9.27 173.06,8.37 v1(173.17,8.25) ; 206.22,52.89 205,51.67 204.11,51.67 202.48,50.04 202.21,50.04 v1(201.86,49.69) 201.38,49.21 R976.2
PCH_SMLDATA: length 175.3
  TOP w0.102: R1351.2 252.93,45.25 v2(253.02,45.34) 253.1,45.42 253.1,46.36
  TOP w0.109: QH4.4 212.16,66.34 211.58,65.76 RH454.2 v7(211.58,65.18) 211.78,64.98 R984.2 ; v1(251.94,46.24) 251.94,45.42 R1351.2 ; v1(201.26,49.69) 201.26,49.47 201.66,49.08 202.06,49.08 202.34,49.36 202.34,50.25 203.31,51.21 203.31,52.54 203.01,52.83 Q352.3 ; Q359.4 253.1,46.36
  IN1 w0.076: v3(252.01,41.79) 251.89,41.92 251.55,41.92 250.99,41.36 247.36,41.36 245.56,39.56 241.05,39.56 239.96,38.46 234.57,38.46 231.35,41.69 229.76,41.69 227.95,43.5 227.95,43.83 226.17,45.61 226.17,47.2 224.53,48.84 222.57,48.84 221.35,50.06 215.97,50.06 215.64,49.73 212.6,49.73 212.39,49.94 210.56,49.94 209.49,48.88 203.14,48.88 202.94,49.08 201.86,49.08 201.26,49.68 v1(201.26,49.69) ; v7(211.58,65.18) 211.19,65.57 211.19,65.68 210.93,65.95 210.37,65.95 210.14,65.72 208.21,65.72 207.93,65.44 204.14,65.44 203.74,65.03 203.17,65.03 v3(202.58,64.45)
  IN3 w0.102: v1(172.56,8.25) 172.71,8.4 172.71,8.67 173.02,8.97 175.07,8.97 175.88,9.79 189.12,9.79 195.24,15.91 195.24,23.22 195.71,23.69 195.88,23.69 196.28,24.1 196.28,30.97 197.4,32.09 197.4,34.53 201.85,38.97 201.85,41.38 203.17,42.71 203.17,46.85 202.48,47.53 202.48,48.4 201.26,49.61 v1(201.26,49.69) 201.26,49.79 201.38,49.91 201.38,52.8 202.05,53.47 202.05,55.53 203.16,56.64 203.16,59 203.52,59.37 203.52,60.24 202.48,61.29 202.48,61.76 202,62.24 202,63.03 202.91,63.94 202.91,64.12 v3(202.58,64.45) ; v1(251.94,46.24) 251.94,46.16 251.91,46.13 251.91,45.7 252.2,45.41 252.2,41.98 v3(252.01,41.79)
  BOTTOM w0.109: v1(201.26,49.69) 201.26,50.05 R977.2 202.35,50.35 204,52 204.92,52 206.03,53.11 206.2,53.11 206.54,53.44 U34.A6 ; JTP1.11 172.65,9.37 172.74,9.27 172.74,8.43 v1(172.56,8.25)
PCH_SPI_CLK: length 51.9
  TOP w0.109: v1(162.41,50.72) 161.54,50.72 161.41,50.6 161.41,50.38 161.54,50.25 162.28,50.25 162.41,50.12 162.41,49.86 162.28,49.73 160.66,49.73 160.53,49.6 160.53,49.37 160.66,49.25 163.81,49.25 163.94,49.37 163.94,49.79 163.81,49.92 163,49.92 162.87,50.05 162.87,50.22 163,50.35 163.88,50.35 164,50.48 164,50.71 163.88,50.83 163.02,50.83 162.9,50.95 162.9,51.12 163.02,51.24 163.86,51.24 163.98,51.36 163.98,51.52 163.86,51.63 162.85,51.63 162.73,51.76 162.73,51.96 162.85,52.09 v2(163.61,52.09) 164.74,52.09 MC118.2 165.57,51.94 RH256.2 ; v1(183.79,54.47) 183.79,55.19 RH258.2
  IN3 w0.102: v1(162.41,50.72) 162.13,50.72 161.54,51.32 161.54,51.62 161.82,51.9 162.29,51.9 162.82,52.43 163.58,52.43 164.17,53.02 165.25,53.02 165.71,52.56 167.38,52.56 167.67,52.85 167.67,53.22 168,53.55 169.21,53.55 169.92,54.26 174.77,54.26 175.05,53.98 176.19,53.98 176.75,54.54 181.3,54.54 181.68,54.92 182.67,54.92 182.9,54.69 182.9,54.42 183.41,53.91 183.41,53.73 183.28,53.6 182.83,53.6 182.72,53.49 182.72,53.23 182.83,53.12 183.81,53.12 184.2,53.51 184.2,53.86 183.99,54.06 183.99,54.26 v1(183.79,54.47)
  BOTTOM w0.109: UCPU1.AA3 162.16,50.97 v1(162.41,50.72)
PCH_SPI_CS1#: length 39.4
  IN3 w0.102: v3(161.92,51.44) 162.27,51.09 162.93,51.09 163.47,51.62 163.48,51.62 164.16,52.31 164.95,52.31 165.41,51.85 167.68,51.85 168.14,52.31 169.4,52.31 169.79,52.69 170.68,52.69 171.39,53.4 174.63,53.4 174.81,53.22 177.32,53.22 177.78,53.68 181.59,53.68 182.66,52.61 185.12,52.61 v3(185.58,53.07)
  IN4 w0.076: v3(185.58,53.07) 185.94,53.07 v4(186,53.02) ; v3(161.92,51.44) 161.66,51.19 161.06,51.19 v4(161.05,51.2)
  BOTTOM w0.109: v4(161.05,51.2) 161.51,51.66 UCPU1.Y4 ; U2.1 180.54,50.66 180.43,50.76 179.66,50.76 179.55,50.87 179.55,51.21 179.66,51.32 183.94,51.32 184.24,51.62 185.11,51.62 186,52.51 v4(186,53.02)
PCH_SPI_CS#: length 38.5
  IN3 w0.102: v3(159.35,51.37) 159.35,49.84 158.46,48.95 158.46,47.98 159.01,47.43 161.28,47.43 161.56,47.71 163.09,47.71 163.8,48.42 164.15,48.42 164.28,48.29 164.69,48.29 165.45,49.06 167.76,49.06 168.75,50.04 169.9,50.04 170.59,50.73 175.52,50.73 175.65,50.87 179.55,50.87 180.41,50.01 184.61,50.01 184.74,50.14 184.74,50.74 184.87,50.87 185.08,50.87 185.21,50.74 185.21,50.2 185.34,50.07 185.55,50.07 185.68,50.2 185.68,50.76 185.81,50.88 186.04,50.88 186.16,50.76 v1(186.16,50.14)
  IN4 w0.076: v3(159.35,51.37) 159.35,51.54 v4(159.52,51.71)
  BOTTOM w0.109: v1(186.16,50.14) 186.07,50.05 186.07,49.54 186.24,49.38 U48.1
PCH_SPI_IO2: length 38.6
  TOP w0.109: RP4.7 178.42,50.75 178.63,50.54 178.63,50.19 178.89,49.93 179.68,49.93 180.52,50.76 180.52,51.15 181,51.63 181,52.28 v1(181.18,52.46) 181.62,52.9 181.92,52.9 182.37,52.45 RP5.7 182.92,52.45 183.15,52.22 183.15,51.71 183.24,51.62 185.07,51.62 186.49,53.05 v2(186.49,53.75) RH54.2
  IN3 w0.102: v3(159.91,51.42) 160.19,51.14 160.19,50.72 160.99,49.92 162.53,49.92 163.77,51.16 165.29,51.16 165.71,50.74 167.22,50.74 168.28,51.8 169.62,51.8 170.05,52.23 174.67,52.23 175.2,52.76 177.51,52.76 177.85,53.1 180.54,53.1 v1(181.18,52.46)
  IN4 w0.076: v4(160.17,51.71) 159.91,51.45 v3(159.91,51.42)
PCH_SPI_IO3: length 27.5
  TOP w0.109: RH56.2 185.6,54.21 185.3,53.91 v2(185.06,53.91) 183.27,53.91 182.81,53.45 RP5.5 180.7,53.45 179.99,52.74 v1(179.99,52.47) 179.82,52.29 178.78,52.29 178.24,51.75 RP4.5
  IN3 w0.102: v3(163.7,49.16) 164.12,49.58 164.56,49.58 165.03,50.05 167.33,50.05 168.38,51.1 169.57,51.1 170.17,51.7 174.9,51.7 175.51,52.31 179.83,52.31 v1(179.99,52.47)
  IN4 w0.076: v4(163.46,48.85) 163.46,48.92 v3(163.7,49.16)
PCH_SPI_SI: length 26.1
  TOP w0.109: RP5.6 182.33,53.14 180.95,53.14 180.59,52.78 v1(180.59,52.47) 180.59,52.43 180.22,52.06 178.88,52.06 178.62,51.8 178.62,51.56 178.31,51.25 RP4.6
  IN3 w0.102: v3(163.68,50.52) 164.09,50.94 165.19,50.94 165.61,50.52 167.32,50.52 168.26,51.46 169.61,51.46 170.07,51.93 174.8,51.93 175.41,52.54 177.61,52.54 177.95,52.87 180.19,52.87 v1(180.59,52.47)
  IN4 w0.076: v4(163.87,51.04) 163.72,50.88 163.72,50.58 163.67,50.53 163.67,50.52 v3(163.68,50.52)
  BOTTOM w0.076: UCPU1.AA2 163.02,51.1 163.32,51.39 163.65,51.39 163.87,51.16 v4(163.87,51.04)
PCH_SPI_SO: length 30
  TOP w0.109: RP5.8 182.28,51.95 v1(181.77,52.46) 181.23,51.93 181.23,51.53 180.75,51.05 180.75,50.67 179.77,49.68 178.81,49.68 178.24,50.25 RP4.8
  IN3 w0.102: v3(161.26,50.76) 161.65,50.37 162.57,50.37 163.59,51.39 165.38,51.39 165.79,50.99 167.14,50.99 168.18,52.03 169.51,52.03 169.94,52.46 170.77,52.46 171.35,53.04 174.66,53.04 174.71,52.99 177.42,52.99 177.76,53.33 180.9,53.33 v1(181.77,52.46)
  IN4 w0.076: v4(161.66,50.81) 161.64,50.83 161.28,50.83 161.28,50.84 161.26,50.81 v3(161.26,50.76)
  BOTTOM w0.109: UCPU1.AA4 161.51,50.98 161.66,50.82 v4(161.66,50.81)
PCH_SRTCRST#: length 10.1
  TOP w0.109: v1(163.32,37.88) 163.32,38.3 v2(161.85,39.76) 160.92,40.7 v7(160.92,41.33)
  IN1 w0.076: v3(160.52,41.41) 160.6,41.33 v7(160.92,41.33)
  IN4 w0.076: v3(160.52,41.41) 160.2,41.41 v4(160.12,41.49)
  BOTTOM w0.109: RH23.2 CH5.1 163.7,35.52 CLRP2.1 163.61,35.57 163.21,35.97 163.17,35.97 163.04,36.1 163.04,37.6 v1(163.32,37.88)
PCH_SUSWARN#: length 39.6
  IN2 w0.102: v1(182.34,50.87) 182.75,50.47 183.11,50.47 183.75,51.11 185.11,51.11 185.31,51.32 188.88,51.32 189.95,52.38 196.49,52.38 196.72,52.61 200.98,52.61 201.34,52.97 203.47,52.97 204.13,52.3 204.13,51.67 204.44,51.37 205.12,51.37 206.39,50.1 v3(206.75,50.1)
  IN4 w0.076: v4(207.98,52.14) 207.73,52.14 207.06,51.48 207.06,51.47 206.9,51.31 206.9,50.25 v3(206.75,50.1)
  BOTTOM w0.076: v4(207.98,52.14) 208.28,52.44 U34.D8
  BOTTOM w0.109: RH297.2 181.27,46.03 v2(181.9,46.66) 181.9,50.43 v1(182.34,50.87)
PCH_SUSWARN#R: length 19.2
  IN4 w0.076: v4(161.26,41.79) 164.29,41.79 164.75,42.25 166.8,42.25 167.35,42.81 167.87,42.81 169.57,44.51 171.48,44.51 172.2,45.23 173.82,45.23 v4(173.96,45.37)
  BOTTOM w0.109: v2(173.42,45.92) 173.42,45.91 v4(173.96,45.37) 174.25,45.66 174.25,45.93 174.44,46.12 RH429.2 174.58,46.12 175.05,45.65 175.33,45.65 RH154.1 176.4,45.73 RH297.1 ; v4(161.26,41.79) 161.48,41.57 UCPU1.AV4
PCI_PIRQC#: length 13.5
  BOTTOM w0.109: UCPU1.N4 161.66,55.63 161.99,55.96 162.65,55.96 162.75,56.06 163.61,56.06 164.95,57.4 168.08,57.4 168.4,57.08 168.4,56.65 v2(168.64,56.41) 168.84,56.21 168.84,55.58 169.14,55.27 169.64,55.27 169.75,55.37 169.75,55.69 169.92,55.86 171.68,55.86 172,55.53 RH455.2
PCI_PIRQD#: length 9.8
  BOTTOM w0.102: 164.03,56.09 163.81,55.87 163,55.87 162.81,55.68 UCPU1.N2
  BOTTOM w0.109: RH456.2 169.93,55.04 169.04,55.04 168.6,55.48 168.6,55.88 168.17,56.32 168.17,56.98 167.99,57.16 165.1,57.16 164.03,56.09
PCIE_PRX_C_CARDTX_N2: length 4.2
  TOP w0.109: U1.8 264.95,18.71 264.85,18.81 264.69,18.81 264.42,18.54 264.42,18.06 264.42,18.05 264.42,17.22 v6(264.59,17.04) 264.82,16.81 264.82,16.12 264.98,15.96 265.13,15.96 CR13.2
PCIE_PRX_C_CARDTX_P2: length 4.2
  TOP w0.109: CR14.2 264.6,16.32 264.6,16.71 264.19,17.12 v6(264.19,18.32) 264.19,18.63 264.6,19.03 264.85,19.03 264.93,19.11 U1.7
PCIE_PRX_CARDTX_N2: length 156.8
  IN1 w0.076: v7(265.23,15.15) 265.02,15.15 264.95,15.21 264.95,15.77 264.05,16.67 264.05,29.54 264.92,30.4 264.92,32.13 264.03,33.02 264.03,38.81 259.26,43.57 251.26,43.57 250.37,42.68 246.82,42.68 245.68,41.54 234.99,41.54 230.02,46.51 230.02,51.1 227.17,53.95 226.27,53.95 226.03,54.19 226.03,55.69 221.67,60.04 220.22,60.04 218.75,61.51 205.35,61.51 203.41,59.57 201.71,59.57 201.15,59.01 200.67,59.01 200.2,59.48 199.32,59.48 198.8,58.96 198.8,57.91 198.04,57.15 193.32,57.15 192.69,57.78 189.22,57.78 188.59,57.15 186.13,57.15 186.08,57.2 185.17,57.2 184.65,57.72 184.4,57.72 183.31,58.8 181.79,58.8 180.94,59.65 177.69,59.65 177.22,59.18 170.32,59.18 167.21,62.29 157.16,62.29 156.61,61.74 156.61,59.8 156.2,59.39 155.77,59.39 v3(155.59,59.57)
  IN4 w0.076: v4(155.14,59.54) 155.17,59.57 v3(155.59,59.57)
PCIE_PRX_CARDTX_P2: length 156.8
  IN1 w0.076: v7(264.34,15.15) 264.74,15.15 264.8,15.21 264.8,15.71 263.9,16.61 263.9,29.6 264.76,30.46 264.76,32.06 263.87,32.95 263.87,38.74 259.2,43.42 251.33,43.42 250.44,42.53 246.88,42.53 245.74,41.38 234.92,41.38 229.86,46.45 229.86,51.04 227.11,53.79 226.21,53.79 225.88,54.12 225.88,55.62 221.61,59.89 220.16,59.89 218.69,61.36 205.41,61.36 203.47,59.42 201.77,59.42 201.21,58.86 200.6,58.86 200.13,59.33 199.38,59.33 198.95,58.9 198.95,57.84 198.1,56.99 193.26,56.99 192.62,57.63 189.29,57.63 188.65,56.99 186.07,56.99 186.02,57.04 185.11,57.04 184.59,57.57 184.33,57.57 183.25,58.65 181.72,58.65 180.88,59.5 177.76,59.5 177.29,59.03 170.26,59.03 167.14,62.14 157.22,62.14 156.76,61.67 156.76,59.74 156.27,59.24 155.85,59.24 v3(155.59,58.99)
  IN4 w0.076: v4(155.14,58.89) 155.24,58.99 v3(155.59,58.99)
PCIE_PRX_DTX_N1: length 123.4
  IN4 w0.076: v4(154.19,58.89) 154.19,58.96 154.32,59.09 154.46,59.09 154.65,59.28 154.65,59.89 155.3,60.54 159.91,60.54 159.94,60.56 160.84,60.56 160.97,60.43 161.45,60.43 161.58,60.56 162.08,60.56 162.18,60.66 163.32,60.66 163.62,60.36 167.14,60.36 169.7,57.8 177.2,57.8 178.71,56.29 180.04,56.29 180.96,55.38 182.04,55.38 182.14,55.48 193.26,55.48 193.76,54.99 196.63,54.99 200.56,58.92 200.56,59.74 200.81,59.98 201.21,59.98 203.78,62.54 215.14,62.54 217.13,60.56 217.13,60.08 218.46,58.75 219.02,58.75 219.08,58.68 220.21,58.68 220.68,59.15 225.13,59.15 225.65,58.63 232.95,58.63 237.81,53.77 237.81,52.97 240.35,50.43 241.56,50.43 242.69,49.3 242.69,39.66 242.97,39.38 243.62,39.38 243.77,39.53 243.77,39.72 v4(243.93,39.89)
  BOTTOM w0.109: JNGFF2.67 247.65,35.61 247.51,35.75 247.51,37.04 247.86,37.38 247.86,39.24 247.08,40.01 245.98,40.01 245.42,39.45 243.93,39.45 243.76,39.62 243.76,39.71 v4(243.93,39.89)
PCIE_PRX_DTX_N4: length 127.8
  IN4 w0.076: v4(156.1,59.54) 156.1,59.36 156.15,59.3 156.29,59.3 156.38,59.39 156.38,59.69 156.83,60.13 158.29,60.13 159.76,58.66 160.17,58.66 160.24,58.73 161.02,58.73 161.09,58.66 163.72,58.66 163.8,58.58 166.57,58.58 167,58.15 168.69,58.15 169.5,57.33 177,57.33 178.5,55.82 179.86,55.82 180.76,54.92 182.25,54.92 182.35,55.02 192.43,55.02 192.94,54.51 196.8,54.51 197.01,54.72 199.4,57.11 200.31,57.11 200.63,57.42 200.63,57.8 201.1,58.27 201.1,59.14 203.66,61.7 215.3,61.7 216.64,60.36 216.64,59.9 218.75,57.79 220.02,57.79 220.87,58.64 224.7,58.64 225.23,58.12 232.82,58.12 237.34,53.59 237.34,51.47 237.98,50.84 238.08,50.84 238.55,51.3 238.82,51.3 239.03,51.09 239.03,50.82 238.57,50.35 238.57,50.24 238.73,50.08 238.84,50.08 239.3,50.54 239.57,50.54 239.78,50.32 239.78,50.05 239.25,49.52 239.25,48.88 239.34,48.78 239.6,48.78 239.81,48.58 239.81,48.22 239.64,48.06 239.32,48.06 239.25,47.98 239.25,47.75 239.32,47.68 239.64,47.68 239.81,47.51 239.81,47.16 239.64,46.99 239.32,46.99 239.25,46.92 239.25,46.64 239.35,46.54 239.62,46.54 239.79,46.36 239.79,45.19 239.87,45.11 241.93,45.11 242.12,44.92 242.12,44.62 241.93,44.43 239.91,44.43 239.81,44.33 239.81,44.08 239.91,43.98 241.84,43.98 242.03,43.79 242.03,43.38 241.84,43.19 240.52,43.19 240.42,43.09 240.42,42.87 240.52,42.77 241.79,42.77 242,42.55 242,39.61 243.15,38.46 243.15,38.17 v4(243.3,38.01)
  BOTTOM w0.109: v4(243.3,38.01) 243.15,37.86 243.15,37.59 242.85,37.29 242.64,37.29 241.51,36.16 241.51,35.93 241.65,35.79 JNGFF2.43
PCIE_PRX_DTX_P1: length 123.5
  IN4 w0.076: v4(243.38,39.89) 243.45,39.96 243.54,39.96 243.62,39.89 243.62,39.59 243.55,39.53 243.03,39.53 242.84,39.72 242.84,49.36 241.62,50.58 240.42,50.58 237.97,53.03 237.97,53.83 233.02,58.78 225.71,58.78 225.19,59.3 220.62,59.3 220.15,58.83 219.14,58.83 219.08,58.9 218.52,58.9 217.28,60.14 217.28,60.63 215.21,62.7 203.71,62.7 201.15,60.13 200.74,60.13 200.41,59.8 200.41,58.99 196.56,55.14 193.82,55.14 193.33,55.63 182.07,55.63 181.97,55.53 181.02,55.53 180.1,56.45 178.77,56.45 177.27,57.95 169.76,57.95 167.2,60.51 163.68,60.51 163.38,60.82 162.12,60.82 162.02,60.71 161.51,60.71 161.38,60.59 161.03,60.59 160.9,60.71 159.87,60.71 159.85,60.69 155.24,60.69 154.5,59.95 154.5,59.34 154.4,59.24 154.27,59.24 154.19,59.32 v4(154.19,59.54)
  BOTTOM w0.109: v4(243.38,39.89) 243.53,39.73 243.53,39.53 243.83,39.23 245.51,39.23 246.07,39.79 246.99,39.79 247.64,39.15 247.64,37.48 247.29,37.13 247.29,35.75 247.15,35.61 JNGFF2.65
PCIE_PRX_DTX_P4: length 127.7
  IN4 w0.076: v4(242.72,38.01) 242.91,38.01 243,38.1 243,38.4 241.85,39.54 241.85,42.49 241.73,42.62 240.46,42.62 240.26,42.81 240.26,43.15 240.46,43.34 241.78,43.34 241.88,43.44 241.88,43.72 241.78,43.82 239.85,43.82 239.66,44.01 239.66,44.39 239.85,44.58 241.86,44.58 241.97,44.68 241.97,44.86 241.86,44.96 239.81,44.96 239.64,45.13 239.64,46.3 239.55,46.39 239.29,46.39 239.1,46.58 239.1,46.98 239.26,47.14 239.58,47.14 239.66,47.22 239.66,47.45 239.58,47.53 239.26,47.53 239.1,47.69 239.1,48.05 239.26,48.21 239.58,48.21 239.66,48.29 239.66,48.52 239.54,48.63 239.28,48.63 239.1,48.81 239.1,49.58 239.63,50.12 239.63,50.26 239.5,50.39 239.36,50.39 238.9,49.93 238.67,49.93 238.42,50.18 238.42,50.41 238.88,50.88 238.88,51.02 238.76,51.15 238.61,51.15 238.15,50.68 237.91,50.68 237.19,51.41 237.19,53.53 232.75,57.97 225.16,57.97 224.64,58.49 220.94,58.49 220.08,57.64 218.69,57.64 216.49,59.84 216.49,60.3 215.23,61.55 203.73,61.55 201.25,59.08 201.25,58.21 200.78,57.74 200.78,57.36 200.37,56.96 199.46,56.96 197.12,54.61 196.86,54.36 192.88,54.36 192.37,54.87 182.42,54.87 182.31,54.77 180.7,54.77 179.8,55.67 178.44,55.67 176.93,57.18 169.44,57.18 168.62,58 166.94,58 166.5,58.43 163.73,58.43 163.66,58.5 161.03,58.5 160.95,58.58 160.31,58.58 160.23,58.5 159.7,58.5 158.22,59.98 156.89,59.98 156.53,59.62 156.53,59.33 156.36,59.15 156.15,59.15 156.1,59.1 v4(156.1,58.89)
  BOTTOM w0.109: v4(242.72,38.01) 242.92,37.81 242.92,37.68 242.76,37.51 242.55,37.51 241.29,36.25 241.29,35.93 241.15,35.79 JNGFF2.41
PCIE_PRX_WLANTX_N3: length 83.3
  IN4 w0.076: v4(221.67,58.02) 221.67,57.59 220.97,56.89 218.55,56.89 215.86,59.58 215.86,60.07 215.03,60.89 204.83,60.89 203.36,59.43 202.46,59.43 201.9,58.86 201.9,57.53 201.7,57.33 199.04,54.67 198.16,54.67 196.89,53.4 188.97,53.4 188.54,53.83 180.75,53.83 179.53,55.05 178.17,55.05 177.12,56.1 175.18,56.1 174.73,56.55 169.19,56.55 168.37,57.37 165.5,57.37 164.78,56.65 161.96,56.65 161.47,57.13 160.51,57.13 159.71,57.93 159.28,57.93 158.72,58.49 158.21,58.49 157.56,59.14 157.3,59.14 v4(157.05,58.89)
  BOTTOM w0.109: v4(221.67,58.02) 221.67,57.18 221.51,57.03 221.51,54.78 220.98,54.24 220.98,53.63 219.78,52.44 218.62,52.44 218.57,52.49 JNGFF1.35
PCIE_PRX_WLANTX_P3: length 83.3
  IN4 w0.076: v4(221.11,58.02) 221.21,58.02 221.52,57.72 221.52,57.65 220.91,57.04 218.61,57.04 216.01,59.65 216.01,60.13 215.09,61.04 204.77,61.04 203.3,59.58 202.4,59.58 201.75,58.92 201.75,57.59 198.98,54.82 198.1,54.82 196.83,53.55 189.03,53.55 188.6,53.98 180.82,53.98 179.6,55.2 178.24,55.2 177.18,56.26 175.24,56.26 174.79,56.7 169.26,56.7 168.43,57.53 165.44,57.53 164.71,56.8 162.02,56.8 161.54,57.29 160.57,57.29 159.77,58.09 159.34,58.09 158.78,58.64 158.27,58.64 157.62,59.3 157.3,59.3 v4(157.05,59.54)
  BOTTOM w0.109: JNGFF1.33 217.63,52.99 217.63,52.99 218.08,52.99 218.13,52.94 218.13,52.76 218.18,52.71 218.66,52.71 218.71,52.66 219.69,52.66 220.75,53.72 220.75,54.33 221.29,54.87 221.29,57.12 221.45,57.28 221.45,57.69 v4(221.11,58.02)
PCIE_PTX_C_CARDRX_N2: length 163
  TOP w0.109: v7(265.14,26.96) 265.24,26.86 265.24,26.62 v6(265.05,26.43) 264.68,26.06 264.68,25.79 CH25.2
  IN1 w0.076: v1(144.1,63.86) 144.37,63.6 144.37,63.45 144.53,63.28 153.28,63.28 153.79,63.79 159.75,63.79 160.15,63.38 166.35,63.38 166.6,63.63 167.67,64.7 168.97,64.7 170.19,65.92 173.01,65.92 173.34,65.59 177.88,65.59 178.09,65.39 178.09,64.55 180.22,62.42 181.35,62.42 183.98,65.05 185.9,65.05 186.24,64.7 188.59,64.7 189.35,65.46 191.38,65.46 192,64.84 199.13,64.84 200.82,66.53 212.15,66.53 212.74,65.93 212.74,65.27 213.98,64.04 217.13,64.04 218.51,62.66 220.34,62.66 221.67,61.32 222.05,61.32 226.08,57.3 226.94,57.3 227.68,56.56 227.68,55.22 229.85,53.04 230.32,53.04 232.5,50.86 232.5,45.56 235.44,42.63 245.19,42.63 246.34,43.77 247.74,43.77 249.34,45.37 259.62,45.37 265.56,39.43 265.56,33.31 266.59,32.28 266.59,29.98 265.27,28.66 265.27,27.08 v7(265.14,26.96)
  BOTTOM w0.109: v1(144.1,63.86) 144.19,63.78 144.19,63.15 145.11,62.23 UCPU1.B31
PCIE_PTX_C_CARDRX_P2: length 163
  TOP w0.109: CH26.2 264.9,25.79 264.9,25.95 265.46,26.51 265.46,26.84 v7(265.58,26.96)
  IN1 w0.076: v7(265.58,26.96) 265.42,27.11 265.42,28.6 266.74,29.92 266.74,32.34 265.72,33.37 265.72,39.49 259.68,45.53 249.28,45.53 247.68,43.92 246.27,43.92 245.13,42.78 235.5,42.78 232.66,45.63 232.66,50.92 230.38,53.2 229.91,53.2 227.83,55.28 227.83,56.62 227.01,57.45 226.14,57.45 222.12,61.48 221.74,61.48 220.4,62.81 218.57,62.81 217.19,64.19 214.04,64.19 212.9,65.34 212.9,66 212.21,66.68 200.75,66.68 199.07,64.99 192.07,64.99 191.45,65.62 189.29,65.62 188.53,64.85 186.3,64.85 185.96,65.2 183.92,65.2 181.29,62.57 180.28,62.57 178.24,64.61 178.24,65.45 177.95,65.74 173.4,65.74 173.07,66.07 170.12,66.07 168.9,64.85 167.61,64.85 166.49,63.74 166.29,63.53 160.22,63.53 159.81,63.94 159.68,63.94 153.73,63.94 153.22,63.43 144.6,63.43 144.52,63.51 144.52,63.62 v1(144.76,63.86)
  BOTTOM w0.109: UCPU1.A31 145.13,62.81 145.18,62.86 145.18,63.05 145.1,63.13 145,63.13 144.82,62.95 144.71,62.95 144.41,63.25 144.41,63.58 144.49,63.66 144.49,63.74 144.62,63.86 v1(144.76,63.86)
PCIE_PTX_CARDRX_N2: length 5.8
  TOP w0.109: CH25.1 264.6,24.29 264.6,24.03 263.91,23.34 263.91,20.71 v6(264.08,20.55) 264.27,20.35 264.9,20.35 264.94,20.31 U1.4
PCIE_PTX_CARDRX_P2: length 5.9
  TOP w0.109: CH26.1 265.13,24.65 264.95,24.65 264.83,24.52 264.83,23.92 v6(264.39,23.48) 264.37,23.48 264.14,23.25 264.14,20.83 264.39,20.58 264.85,20.58 264.98,20.71 U1.3
PCIE_PTX_DRX_N1: length 13.6
  TOP w0.109: v1(246.2,36.1) 246.03,36.28 246.03,36.67 246.28,36.92 247.44,36.92 247.86,36.49 249.35,36.49 v6(249.36,36.48) 249.6,36.48 252.25,39.13 252.25,40.36 251.83,40.78 251.83,42.5 CH1242.1
  BOTTOM w0.109: v1(246.2,36.1) 246.01,35.92 246.01,35.73 246.15,35.59 JNGFF2.61
PCIE_PTX_DRX_N1_C: length 128.7
  TOP w0.109: CH1242.2 251.82,44.09 251.82,44.29 251.58,44.53 250.72,44.53 250.29,44.96 v6(249.12,44.96) 247.64,44.96 246.94,44.26 246.53,44.26 246.53,44.26 245.18,44.26 245.06,44.37 245.06,44.49 v1(245.31,44.74)
  IN4 w0.076: v4(145.68,61.19) 145.75,61.26 145.75,61.39 145.65,61.49 145.54,61.49 145.18,61.13 145.18,60.9 145.51,60.57 146.81,60.57 148.95,62.72 153.31,62.72 153.92,63.33 159.4,63.33 159.94,62.8 166.68,62.8 170.25,59.23 177.99,59.23 179.1,58.12 181.56,58.12 181.99,57.69 182.84,57.69 183.46,57.06 196.51,57.06 197.99,58.54 197.99,59 198.66,59.67 199.03,60.04 199.03,61.41 200.87,63.25 201.69,63.25 202.48,64.04 215.61,64.04 217.71,61.95 219.23,61.95 220.63,60.55 225.86,60.55 225.98,60.43 227.25,60.43 227.65,60.84 233.13,60.84 239.69,54.28 239.69,53.62 241.04,52.27 241.69,52.27 244.37,49.59 244.37,46.48 245.31,45.54 v1(245.31,44.74)
PCIE_PTX_DRX_N4: length 145.6
  TOP w0.109: v1(147.06,66.12) 146.63,65.69 146.47,65.69 146.36,65.58 146.36,65.44 146.46,65.34 CH1237.1
  IN4 w0.076: v4(246.85,39.19) 246.84,39.19 246.71,39.32 246.71,39.44 246.81,39.53 247,39.53 247.79,38.74 247.79,37.84 247.99,37.64 250.33,37.64 251.72,39.03 251.72,40.78 251,41.5 251,45.64 246.2,50.44 246.2,51.18 243.62,53.75 242.88,53.75 237.71,58.93 237.71,59.99 236.95,60.75 236.95,61.65 234.28,64.32 226.82,64.32 226.38,64.75 219.27,64.75 215.08,68.94 209.8,68.94 209.37,68.51 205.03,68.51 204.62,68.93 200.65,68.93 198.44,66.72 195.35,66.72 193.13,68.94 190.42,68.94 189.86,68.39 184.07,68.39 183.53,68.92 171.06,68.92 170.53,68.39 170.15,68.39 169.59,68.94 155.89,68.94 152.66,65.72 146.96,65.72 146.86,65.82 146.86,65.9 147.06,66.1 v1(147.06,66.12)
  BOTTOM w0.109: v4(246.85,39.19) 246.75,39.09 246.75,38.84 246.38,38.47 242.31,38.47 240.87,37.02 240.37,37.02 240.01,36.66 240.01,35.93 240.15,35.79 JNGFF2.37
PCIE_PTX_DRX_N4_C: length 2.7
  TOP w0.109: v1(146.48,63.81) 146.28,64.01 146.28,64.09 CH1237.2
  BOTTOM w0.109: UCPU1.B29 146.53,62.45 146.53,63.31 146.37,63.46 146.37,63.71 v1(146.48,63.81)
PCIE_PTX_DRX_P1: length 13.6
  TOP w0.109: v1(245.61,36.1) 245.75,36.23 245.8,36.29 245.8,36.76 246.18,37.14 247.53,37.14 247.96,36.72 249.51,36.72 252.02,39.23 252.02,40.27 251.61,40.68 251.61,42.5 CH1243.1
  BOTTOM w0.109: v1(245.61,36.1) 245.79,35.93 245.79,35.72 245.65,35.58 JNGFF2.59
PCIE_PTX_DRX_P1_C: length 128.7
  TOP w0.109: v1(244.54,44.74) 244.84,44.45 244.84,44.28 245.09,44.03 v6(246.79,44.03) 247.03,44.03 247.73,44.74 248.85,44.74 248.86,44.73 249.37,44.73 249.38,44.74 250.2,44.74 250.63,44.31 251.49,44.31 251.6,44.2 251.6,44.07 CH1243.2
  IN4 w0.076: v1(244.54,44.74) 244.65,44.64 244.81,44.64 244.91,44.74 244.91,44.95 245.15,45.19 245.15,45.47 244.21,46.41 244.21,49.53 241.62,52.12 240.98,52.12 239.54,53.55 239.54,54.21 233.06,60.69 227.72,60.69 227.31,60.28 225.91,60.28 225.8,60.4 220.57,60.4 219.17,61.79 217.65,61.79 215.55,63.89 202.55,63.89 201.76,63.1 200.93,63.1 199.18,61.35 199.18,59.98 198.77,59.56 198.14,58.94 198.14,58.48 196.57,56.91 183.4,56.91 182.77,57.54 181.93,57.54 181.49,57.97 179.04,57.97 177.93,59.08 170.18,59.08 166.62,62.64 159.87,62.64 159.34,63.18 153.98,63.18 153.37,62.57 149.02,62.57 146.87,60.42 145.44,60.42 145.03,60.84 145.03,61.2 145.11,61.28 v4(145.11,61.51)
PCIE_PTX_DRX_P4: length 145.6
  TOP w0.109: CH1238.1 146.03,65.34 146.14,65.44 146.14,65.67 146.32,65.85 146.48,66.01 v1(146.48,66.12)
  IN4 w0.076: v4(246.42,39.19) 246.56,39.33 246.56,39.5 246.74,39.68 247.06,39.68 247.94,38.8 247.94,37.9 248.05,37.79 250.26,37.79 251.57,39.1 251.57,40.71 250.84,41.44 250.84,45.58 246.04,50.38 246.04,51.11 243.55,53.6 242.82,53.6 237.56,58.86 237.56,59.93 236.8,60.69 236.8,61.59 234.22,64.17 226.75,64.17 226.32,64.6 219.21,64.6 215.02,68.79 209.86,68.79 209.43,68.36 204.97,68.36 204.55,68.78 200.71,68.78 198.5,66.57 195.29,66.57 193.07,68.79 190.48,68.79 189.92,68.23 184,68.23 183.47,68.77 171.13,68.77 170.59,68.23 170.08,68.23 169.53,68.79 155.95,68.79 152.72,65.57 146.89,65.57 146.7,65.76 146.7,65.9 v1(146.48,66.12)
  BOTTOM w0.109: v4(246.42,39.19) 246.53,39.09 246.53,38.93 246.29,38.69 242.22,38.69 240.77,37.24 240.28,37.24 239.79,36.76 239.79,35.93 239.65,35.79 JNGFF2.35
PCIE_PTX_DRX_P4_C: length 2.7
  TOP w0.109: CH1238.2 145.85,64.42 146.06,64.22 146.06,64.01 v1(145.87,63.81)
  BOTTOM w0.109: UCPU1.A29 146.24,62.69 146.17,62.62 146.04,62.62 145.92,62.75 145.92,62.92 146.19,63.2 146.19,63.33 146.15,63.36 146.15,63.53 v1(145.87,63.81)
PCIE_PTX_WLANRX_N3: length 101.6
  TOP w0.109: CH11.1 145.36,67.93 145.36,68.35 v1(145.24,68.46)
  IN4 w0.076: v4(224.35,65.57) 224.22,65.69 223.18,65.69 222.7,65.21 219.46,65.21 215.27,69.4 200.47,69.4 198.25,67.18 195.54,67.18 193.32,69.4 148.25,69.4 146.5,67.65 145.51,67.65 145.31,67.85 145.31,68.4 v1(145.24,68.46)
  BOTTOM w0.109: JNGFF1.29 218.03,53.99 218.15,54.11 219.8,54.11 220.77,55.08 220.77,59.98 221.66,60.87 221.66,61.41 223.93,63.69 223.93,65.53 224.07,65.67 224.25,65.67 v4(224.35,65.57)
PCIE_PTX_WLANRX_N3_C: length 6.3
  TOP w0.109: CH11.2 145.44,66.43 145.44,66.29 v1(145.27,66.12)
  BOTTOM w0.109: UCPU1.C29 145.57,61.51 145.38,61.7 145.38,61.96 145.41,61.98 145.41,63.19 145.18,63.42 145.18,64.84 145.18,64.85 145.18,65.42 145.18,65.43 145.18,65.56 145.27,65.64 v1(145.27,66.12)
PCIE_PTX_WLANRX_P3: length 101.7
  TOP w0.109: v1(145.84,68.46) 145.58,68.2 145.58,68.09 CH16.1
  IN4 w0.076: v4(224.35,66) 224.2,65.85 223.12,65.85 222.64,65.36 219.53,65.36 215.33,69.55 200.41,69.55 198.19,67.33 195.6,67.33 193.38,69.55 148.19,69.55 146.44,67.8 145.57,67.8 145.46,67.92 145.46,68.11 145.81,68.46 v1(145.84,68.46)
  BOTTOM w0.109: JNGFF1.27 218,54.49 218.16,54.33 219.71,54.33 220.55,55.17 220.55,60.07 221.44,60.96 221.44,61.51 223.71,63.78 223.71,65.62 223.99,65.9 224.25,65.9 v4(224.35,66)
PCIE_PTX_WLANRX_P3_C: length 6.3
  TOP w0.109: v1(145.87,66.12) 145.66,66.33 145.66,66.43 CH16.2
  BOTTOM w0.109: UCPU1.B30 145.68,61.82 145.76,61.74 145.95,61.74 146.02,61.81 146.02,61.98 145.87,62.14 145.69,62.14 145.63,62.19 145.63,62.31 145.79,62.47 145.79,62.57 145.63,62.73 145.63,63.28 145.41,63.51 v6(145.41,65.16) 145.41,65.46 145.49,65.55 145.49,65.75 v1(145.87,66.12)
PCIE_RCOMP: length 2.3
  TOP w0.102: v1(147.66,63.81) v2(147.66,63.15)
  TOP w0.381: v1(147.66,63.81) 147.58,63.89 147.58,64.35 RH338.2
  BOTTOM w0.381: UCPU1.A27 147.62,63.78 v1(147.66,63.81)
PCIE_WAKE#: length 50.4
  TOP w0.109: v1(246.65,37.88) 247,37.88 v2(247.2,37.68) ; U676.4 220.28,44.96 220.66,45.33 v7(220.88,45.33) 222.21,45.33 222.31,45.44 222.31,48.56 222.13,48.73 Q347.3 222.13,49.74 222.69,50.3 222.69,50.54 R942.2 222.24,50.59 221.04,49.39 v1(219.55,49.39)
  IN1 w0.076: v7(220.88,45.33) 221.48,45.33 221.86,45.71 222.98,45.71 224.35,44.33 226.01,44.33 226.57,43.77 226.57,43.08 227.26,42.39 227.91,42.39 228.45,41.85 228.45,40.92 228.94,40.43 228.94,39.56 229.62,38.87 232.64,38.87 233.73,37.78 241.15,37.78 241.5,38.12 245.73,38.12 245.92,38.31 246.22,38.31 v1(246.65,37.88)
  BOTTOM w0.109: v1(219.55,49.39) 219.45,49.49 JNGFF1.47 ; v1(246.65,37.88) 246.65,37.4 245.79,36.54 244.75,36.54 244.54,36.34 244.54,35.9 244.65,35.79 JNGFF2.55
PLT_RST#: length 250.4
  TOP w0.109: U675.2 220.49,50.69 220.88,51.09 220.88,51.77 222.08,52.97 222.08,53.81 R1313.1 222.17,54.57 222.17,55.49 221.95,55.71 220.3,55.71 v1(220.1,55.51) ; v7(183.81,46.78) 184.08,47.05 UH5.4 183.76,47.74 183.24,47.23 MC104.1 RH171.1 183.01,48.98 RH168.1 ; RH363.2 117.51,55.61 118.46,55.61 v1(118.66,55.81) ; v7(203.57,44.26) 204.04,43.79 U698.1
  IN1 w0.076: v3(200.04,45.92) 200.04,45.89 ; 200.04,45.89 200.02,45.92 195.19,45.92 194.68,46.43 184.17,46.43 v7(183.81,46.78) 183.8,46.8 v3(183.8,47.32) ; 200.04,45.89 200.44,45.5 201.92,45.5 203.16,44.26 v7(203.57,44.26) 203.57,44.35 204.34,45.12 205.62,45.12 205.98,44.76 209,44.76 209.89,43.87 210.83,43.87 211.68,44.73 213.04,44.73 213.16,44.6 213.81,44.6 214.65,45.44 216.39,45.44 217.06,44.76 v3(217.11,44.76) 221.62,44.76 222.11,45.25 222.79,45.25 224.16,43.88 225.82,43.88 226.12,43.58 226.12,42.89 227.07,41.94 227.72,41.94 228,41.66 228,40.69 228.48,40.2 228.48,39.37 229.43,38.41 232.42,38.41 233.56,37.27 252.39,37.27 253.27,36.39 v3(254.58,36.39)
  IN3 w0.102: v1(118.66,55.81) 118.51,55.81 118.1,55.41 118.1,54.42 118.74,53.78 120.14,53.78 123.01,50.91 123.64,50.91 123.77,50.78 127.25,50.78 129.05,48.98 148.84,48.98 149.17,48.65 149.9,48.65 150.21,48.95 151.91,48.95 152.22,48.65 155.21,48.65 155.92,47.94 156.18,47.94 157.8,46.31 159.2,46.31 159.43,46.08 159.43,44.48 160.27,43.65 162.44,43.65 164.06,45.27 164.76,45.27 164.94,45.45 168.87,45.45 169.35,45.93 175.68,45.93 176.94,47.19 179.09,47.19 179.76,46.52 180.8,46.52 181.1,46.22 183.01,46.22 183.8,47.01 v3(183.8,47.32) ; v1(265.13,22.75) 263.8,24.09 263.8,33.52 260.93,36.39 v3(254.58,36.39) ; v1(220.1,55.51) 220.62,54.99 220.62,51.95 218.55,49.88 218.55,48.41 217.79,47.65 217.79,45.44 v3(217.11,44.76)
  IN4 w0.076: v3(200.04,45.92) 200.15,45.82 200.15,39.21 194.94,34 194.94,28.18 v4(194.86,28.1)
  BOTTOM w0.076: U34.M5 212.36,53.95 212.59,54.19 213.05,54.19 213.4,53.83 214.15,53.83 214.31,53.98 214.31,54.28 213.89,54.69 213.89,55.76 214.04,55.91 215.56,55.91 215.69,55.79 215.69,55.66 216.02,55.33 216.76,55.33
  BOTTOM w0.109: U678.1 265.76,23.38 v1(265.13,22.75) 265.13,21.05 265.02,20.94 265.02,19.66 v2(264.24,18.88) ; v1(220.1,55.51) 216.93,55.51 216.76,55.33 ; JDEBUG.6 198.91,24.87 195.67,28.1 v4(194.86,28.1)
PLTRST1#_XDP: length 22.9
  TOP w0.109: RH363.1 118.06,56.12 v2(119.28,57.34) 119.92,57.98 119.92,59.22 121.52,60.81 121.52,63.46 120.68,64.3 120.68,68.54 120.12,69.1 115.55,69.1 115.07,69.58 JXDP.46
PM_CLKRUN#: length 71.2
  IN1 w0.076: v3(160.57,52) 161,51.57 161.33,51.57 161.61,51.85 161.61,52.59 162.38,53.35 165.98,53.35 166.49,53.86 168.94,53.86 v7(169.22,54.14) 170.1,54.14 170.27,53.96 170.88,53.96 171.11,54.19 173.61,54.19 174.26,53.54 182.34,53.54 184.19,51.68 186.52,51.68 187.14,51.06 190.14,51.06 190.82,51.75 191.41,51.75 191.98,51.18 195.33,51.18 195.6,51.44 198.44,51.44 v3(198.82,51.06) 199.59,51.06 199.97,51.44 200.1,51.44 201.8,53.15 205.83,53.15 206.61,53.92 208.42,53.92 208.63,53.7 209.59,53.7 209.95,53.35 212.39,53.35 212.77,53.73 v3(212.79,53.73)
  IN4 w0.076: v4(199.14,50.8) 199.1,50.8 198.84,51.06 v3(198.82,51.06) ; v4(160.55,52.41) 160.55,52.03 v3(160.57,52) ; v4(212.01,53.44) 212.46,53.44 212.74,53.73 v3(212.79,53.73)
  BOTTOM w0.109: v4(160.55,52.41) 160.8,52.67 UCPU1.V5 ; U652.15 204.62,44.97 204.29,44.64 v2(202.79,44.64) 201.97,45.45 200.73,45.45 199.64,46.54 199.64,47.84 199.14,48.34 v4(199.14,50.8) ; U34.M6 v4(212.01,53.44)
PM_SLP_A#: length 158.9
  TOP w0.109: v7(184.33,7.53) 184.33,6.95 184.57,6.71 JAPS.13 ; v1(196.77,47.89) 196.92,48.04 U721.3
  IN1 w0.076: v3(160.71,46) 160.75,45.95 160.75,45.17 160.9,45.02 160.9,44.66 161.26,44.31 164.73,44.31 166.59,42.44 166.59,41.71 167.11,41.18 167.36,41.18 170.79,37.75 174.64,37.75 179.47,32.93 184.82,32.93 185.28,33.39 186.25,33.39 v3(186.69,32.95) 186.97,32.95 187.86,32.06 188.46,32.06 188.92,31.61 189.13,31.61 189.67,31.07 189.67,30.27 190.31,29.62 191.37,29.62 193.52,27.48 193.52,26.41 194.02,25.9 194.02,19.44 194.33,19.13 194.33,13.8 193.97,13.44 193.97,11.88 189.62,7.53 v7(184.33,7.53)
  IN3 w0.102: v3(186.69,32.95) 186.68,32.95 186.68,35.97 185.63,37.02 182.49,37.02 179.65,39.86 179.65,43.36 180.9,44.62 189.42,44.62 191.9,47.1 195.98,47.1 v1(196.77,47.89)
  IN4 w0.076: v4(198.82,46.21) 199.81,47.2 200.93,47.2 202.71,48.98 202.71,50.35 203.7,51.34 203.7,52.15 205.15,53.6 205.15,53.98 205.3,54.14 206.39,54.14 206.72,54.47 207,54.47 207.36,54.82 207.36,55.13 207.69,55.46 209.64,55.46 209.82,55.28 209.82,55.05 210,54.87 210.2,54.87 210.61,55.28 210.99,55.28 v4(211.12,55.15) ; v4(160.78,46.41) 160.71,46.34 v3(160.71,46)
  BOTTOM w0.109: v4(198.82,46.21) 198.82,46.63 198.23,47.23 197.28,47.23 196.77,47.73 v1(196.77,47.89) 196.34,47.46 188.05,47.46 187.37,48.14 187.37,50.48 189.43,52.54 194.03,52.54 194.25,52.31 194.9,52.31 196.3,53.71 197.43,53.71 198.14,54.42 v2(198.14,56.24) 198.14,58.25 R503.1 ; v4(211.12,55.15) 211.36,55.39 U34.K2 ; UCPU1.AL5 160.56,46.2 v4(160.78,46.41)
PM_SLP_S0#: length 97.8
  TOP w0.109: PU501.2 197.62,64.65 RH448.1 RH447.2 199.57,65.46 199.83,65.21 199.83,64.85 202.48,62.2 202.48,62.17 204.01,60.64 212.04,60.64 212.87,59.81 v2(212.87,59.03) 212.87,56.16 v7(212.83,56.12) ; JAPS.4 v7(189.06,2.93)
  IN1 w0.076: v3(212.79,55.32) 212.83,55.36 v7(212.83,56.12) ; v7(189.06,2.93) 191.96,2.93 194.73,5.7 195.93,5.7 202.02,11.79 202.02,27.29 202.99,28.25 202.99,33.49 206.2,36.69 208.32,36.69 211.3,39.67 v3(211.3,39.76)
  IN3 w0.102: v3(211.3,39.76) 211.3,39.84 211.92,40.46 211.92,41.61 212.87,42.56 212.87,43.76 214.42,45.31 214.42,46.95 215.02,47.54 215.02,49.37 215.78,50.14 215.78,52.68 213.18,55.28 212.79,55.28 212.77,55.3 212.77,55.32 v3(212.79,55.32)
  IN4 w0.076: v3(212.79,55.32) 212.23,55.32 211.96,55.05 v4(211.93,55.05)
  BOTTOM w0.254: v4(211.93,55.05) 211.96,55.05 U34.M2
PM_SLP_S3#: length 436
  TOP w0.109: PR404.1 91.45,50.22 90.51,51.16 90.51,54.24 91.29,55.02 93.3,55.02 94.13,54.2 95.98,54.2 96.98,53.2 97.95,53.2 v5(100.29,50.86) 105.15,50.86 v1(105.2,50.81) ; v1(181.36,5.69) 181.76,5.29 182.38,5.29 182.57,5.48 JAPS.17 ; v7(192.03,52.64) 192.03,53.3 191.85,53.48 191.17,53.48 190.94,53.7 190.94,54.14 191.62,54.82 191.62,56.42 188.42,59.62 188.42,63.11 187.34,64.19 185.32,64.19 185.19,64.06 U673.16 ; v7(101.76,12.28) 101.76,12.24 105.33,8.67 105.33,5.91 v1(105.5,5.74) ; PR405.1 227.98,40.65 229.06,40.65 229.44,41.04 229.44,41.72 229.1,42.07 229.1,45.39 229.37,45.66 229.37,47.44 230.04,48.12 v1(230.41,48.12) ; v7(238.11,53.27) 229.11,53.27 228.67,53.71 227.18,53.71 226.85,53.38 224.46,53.38 223.95,53.89 v7(223.77,53.89) ; U717.3 51.24,11.62 v7(51.14,11.72) ; v7(240.86,52.1) 241,52.24 U716.3 ; U710.2 198.67,53.87 198.47,53.67 v7(198.47,53.37) 198.47,53.37 198.47,52.22 198.15,51.9 198.15,48.24 v1(198.51,47.89)
  IN1 w0.076: v7(101.76,12.28) 101.23,12.81 100.56,12.81 100.04,13.33 100.04,14.03 98.01,16.06 98.01,27.72 98.65,28.35 98.65,31.72 102.03,35.1 102.03,38.01 104.59,40.57 104.59,44.59 105.45,45.45 105.45,50.55 v1(105.2,50.81) ; v7(51.14,11.72) 51.16,11.74 51.5,11.74 52.5,10.75 55.59,10.75 55.61,10.73 56.81,10.73 v3(58.11,9.43) ; v7(192.03,52.64) 192.2,52.47 194.75,52.47 v3(195.09,52.81) 196.8,52.81 197.36,53.37 v7(198.47,53.37) 199.93,53.37 200.07,53.23 200.65,53.23 201.43,54.01 202.99,54.01 204.99,56.02 207,56.02 207.59,55.43 211.09,55.43 211.11,55.44 211.11,55.44 211.31,55.64 211.31,55.65 211.52,55.86 211.93,55.86 212.41,55.39 v3(212.41,54.88) 212.42,54.87 212.99,54.87 213.25,55.13 214.82,55.13 215.22,55.53 215.88,55.53 217.05,54.36 223.32,54.36 223.79,53.89 v7(223.77,53.89) 223.77,53.72 v3(223.45,53.4) ; v7(240.86,52.1) 239.27,52.1 v7(238.11,53.27)
  IN2 w0.102: v3(223.45,53.4) 223.48,53.4 224.81,52.07 224.81,50.49 225.48,49.82 227.62,49.82 229.32,48.12 v1(230.41,48.12)
  IN3 w0.102: v3(212.41,54.88) 212.41,54.85 213.16,54.1 213.16,50.44 212.36,49.64 212.36,48.7 211.75,48.09 210.61,48.09 209.9,47.38 209.9,43.21 208.45,41.77 208.45,40.55 201.36,33.47 201.36,31.44 201.26,31.34 201.26,29.22 201.27,29.22 201.27,27.86 201.05,27.64 201.05,15.89 198.32,13.16 198.32,12.24 195.14,9.06 193.44,9.06 191.05,6.68 182.35,6.68 v1(181.36,5.69) 181.16,5.48 157.03,5.48 154.7,7.81 151.19,7.81 149.74,9.27 143.35,9.27 140.27,6.18 128.91,6.18 128.69,5.96 111.77,5.96 111.27,6.46 105.91,6.46 105.5,6.05 v1(105.5,5.74) 105.01,5.24 102.48,5.24 102.28,5.04 96.78,5.04 96.02,5.8 95.6,5.8 95.04,5.24 90.4,5.24 89.53,4.37 72.92,4.37 68.38,8.92 58.62,8.92 v3(58.11,9.43)
  IN4 w0.076: v3(212.41,54.88) 212.26,54.74 211.67,54.74 211.3,54.36 211.3,54.08 210.76,53.55 v4(210.46,53.55) ; v4(161.51,42.82) 161.7,43.01 162.38,43.01 162.96,42.43 164.28,42.43 164.56,42.71 166.59,42.71 167.2,43.32 167.73,43.32 169.38,44.97 171.29,44.97 172.01,45.69 176.21,45.69 176.83,46.31 177.19,46.31 178.25,47.37 181.96,47.37 183.01,46.31 197.53,46.31 198.51,47.29 v1(198.51,47.89) ; v3(195.09,52.81) v4(194.71,52.81)
  BOTTOM w0.109: v4(194.71,52.81) 194.71,53.2 195.78,54.27 197.3,54.27 197.65,54.62 197.65,57.88 197.12,58.4 197.12,59.34 197.45,59.67 R501.1 ; U34.J5 210.85,53.94 v4(210.46,53.55)
PM_SLP_S4#: length 294.4
  TOP w0.109: v7(184.92,2.42) 184.92,4.76 184.06,5.61 JAPS.14 ; v7(101.4,28.68) 100.44,28.68 98.52,26.76 96.32,26.76 96.01,26.45 96.01,22.4 97.45,20.96 97.45,20.3 98.2,19.54 98.2,17.46 100.64,15.02 103.13,15.02 v5(103.16,14.99) 103.35,14.99 109.61,8.73 109.61,7.11 112.78,3.93 v7(112.78,2.93)
  IN1 w0.076: v3(212.55,37.61) 210.72,35.78 206.57,35.78 203.9,33.11 203.9,27.87 202.94,26.91 202.94,22.84 203.76,22.02 203.76,12.89 196.12,5.24 195.09,5.24 192.04,2.19 185.15,2.19 v7(184.92,2.42) 184.66,2.16 151.65,2.16 148.48,5.33 145.07,5.33 141.9,2.16 113.55,2.16 v7(112.78,2.93) ; v3(156.86,46.74) 156.25,46.74 155.92,46.41 155.59,46.41 155.29,46.72 155.29,48.19 153.89,49.59 153.89,52.79 153.23,53.45 153.23,54.47 151.89,55.81 151.89,56.52 151.33,57.08 151.33,58.66 149.73,60.26 143.94,60.26 143.45,60.74 135.4,60.74 134.87,60.21 134.87,59.24 133.98,58.35 129.13,58.35 126.87,56.09 122.93,56.09 121.89,55.05 121.89,51.86 120.39,50.36 120.39,49.6 116.4,45.61 116.4,44.72 115.15,43.47 113.76,43.47 112.4,44.83 109.15,44.83 107.18,42.86 107.18,36.6 106.67,36.09 106.67,34.76 104.41,32.49 v1(103.75,32.49) 103.68,32.42 103.27,32.42 101.4,30.55 v7(101.4,28.68)
  IN4 w0.076: v4(213.32,55.91) 214.13,55.1 214.92,55.1 215.95,54.07 216.47,54.07 218.38,52.16 218.38,49.31 219.37,48.32 219.37,47.99 218.73,47.34 218.73,43.84 215.02,40.14 213.22,40.14 212.55,39.48 v3(212.55,37.61) ; v3(156.86,46.74) 157.69,47.57 157.92,47.57 158.26,47.91 158.62,47.91 159.05,47.48 159.86,47.48 v4(159.89,47.46)
  BOTTOM w0.109: U34.N1 213.28,55.94 v4(213.32,55.91) ; v1(103.75,32.49) 103.5,32.24 PR613.1 ; UCPU1.AJ6 160.17,47.17 v4(159.89,47.46)
PM_SLP_S5#: length 74.8
  TOP w0.109: v7(183.7,7.88) 183.57,7.75 JAPS.15 ; D114.1 v5(194.32,8.75) 192.87,8.75 v7(191.52,10.09)
  IN1 w0.076: v7(183.7,7.88) 183.8,7.98 189.43,7.98 191.52,10.08 v7(191.52,10.09) 191.72,10.29 191.74,10.29 193.52,12.07 193.52,13.63 193.87,13.99 193.87,18.94 193.57,19.25 193.57,25.71 193.06,26.22 193.06,27.29 191.18,29.17 190.12,29.17 189.21,30.08 189.21,30.88 188.94,31.15 188.73,31.15 188.27,31.61 187.67,31.61 186.81,32.47 179.28,32.47 174.45,37.3 170.6,37.3 167.69,40.2 166.99,40.2 166.72,40.47 166.72,40.93 166.13,41.52 166.13,42.25 164.54,43.85 161.13,43.85 v3(160.94,44.04)
  IN4 w0.076: v3(160.94,44.04) 160.89,44.09 v4(160.56,44.09)
PM_SLP_SUS: length 9.1
  TOP w0.109: Q5.2 177.04,68.96 177.38,69.29 v5(178.78,69.29) 178.96,69.29 179.19,69.53 182.1,69.53 182.51,69.12 182.51,68.65 183.39,67.76 U713.4
PM_SLP_SUS#: length 135.4
  TOP w0.109: v1(213.7,39.05) 212.99,39.05 212.59,38.65 212.59,37.52 210.89,35.82 206.81,35.82 206.2,35.2 205.23,35.2 203.21,33.17 203.21,32.14 201.86,30.79 197.26,30.79 196.91,30.44 196.91,29.83 195.97,28.89 189.13,28.89 188.79,29.23 D307.3 188.82,29.73 v1(188.82,30.72) ; v7(181.72,68.05) 182.29,68.05 182.56,67.79 182.56,67.14 182.67,67.03 184.37,67.03 184.74,66.66 184.74,65.82 184.97,65.59 186.63,65.59 188.93,63.29 v2(188.93,60.87) v7(188.93,59.63) ; v7(174.25,67.57) 174.19,67.51 173.53,67.51 173.06,67.04 R290.1 172.73,67.23 172.73,67.34 172.33,67.74 172.05,67.74 171.65,67.33 U719.3
  IN1 w0.076: v7(174.25,67.57) 174.38,67.45 181.11,67.45 v7(181.72,68.05) ; v3(189.01,59.14) 188.93,59.22 v7(188.93,59.63)
  IN2 w0.102: v3(189.01,59.14) 196.04,59.14 197.12,58.06 200.44,58.06 200.67,57.83 200.67,57.49 201.68,56.47 206.52,56.47 206.93,56.07 209.3,56.07 209.61,56.37 211.14,56.37 211.4,56.1 213.25,56.1 214.23,55.13 215,55.13 215.46,54.67 v3(216.02,54.67)
  IN4 w0.076: v1(213.7,39.05) 213.75,39 216.21,39 218.38,41.17 218.38,42.52 219.18,43.32 219.18,47.09 219.88,47.79 219.88,48.46 218.87,49.47 218.87,52.32 216.63,54.55 216.13,54.55 v3(216.02,54.67) 215.74,54.95 v4(215.56,54.95)
  BOTTOM w0.109: v4(215.56,54.95) 215.23,55.28 R1249.1 ; v1(188.82,30.72) 188.78,30.72 188.12,31.38 187.37,31.38 186.91,31.83 178.92,31.83 178.37,32.39 169.08,32.39 168.59,32.88 167.58,32.88 166.95,33.51 166.95,35.34 RH313.1
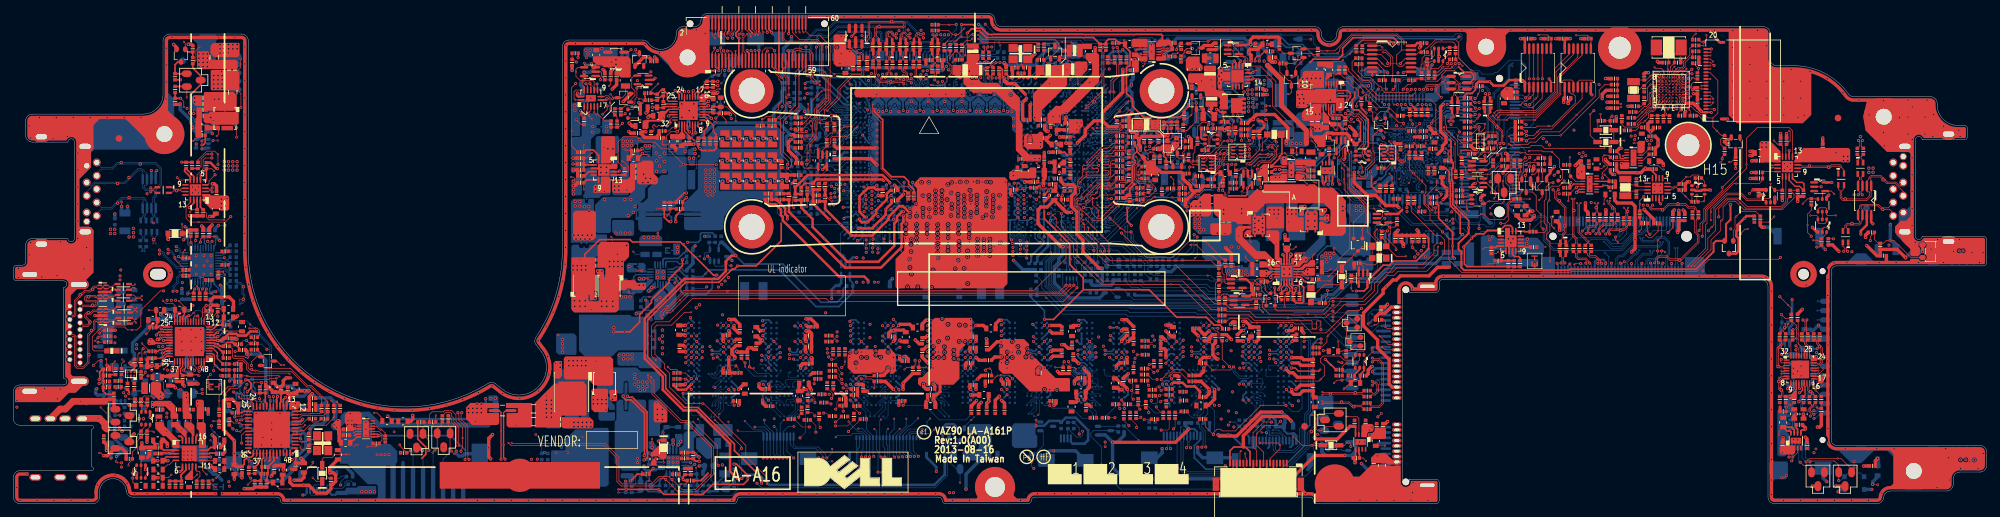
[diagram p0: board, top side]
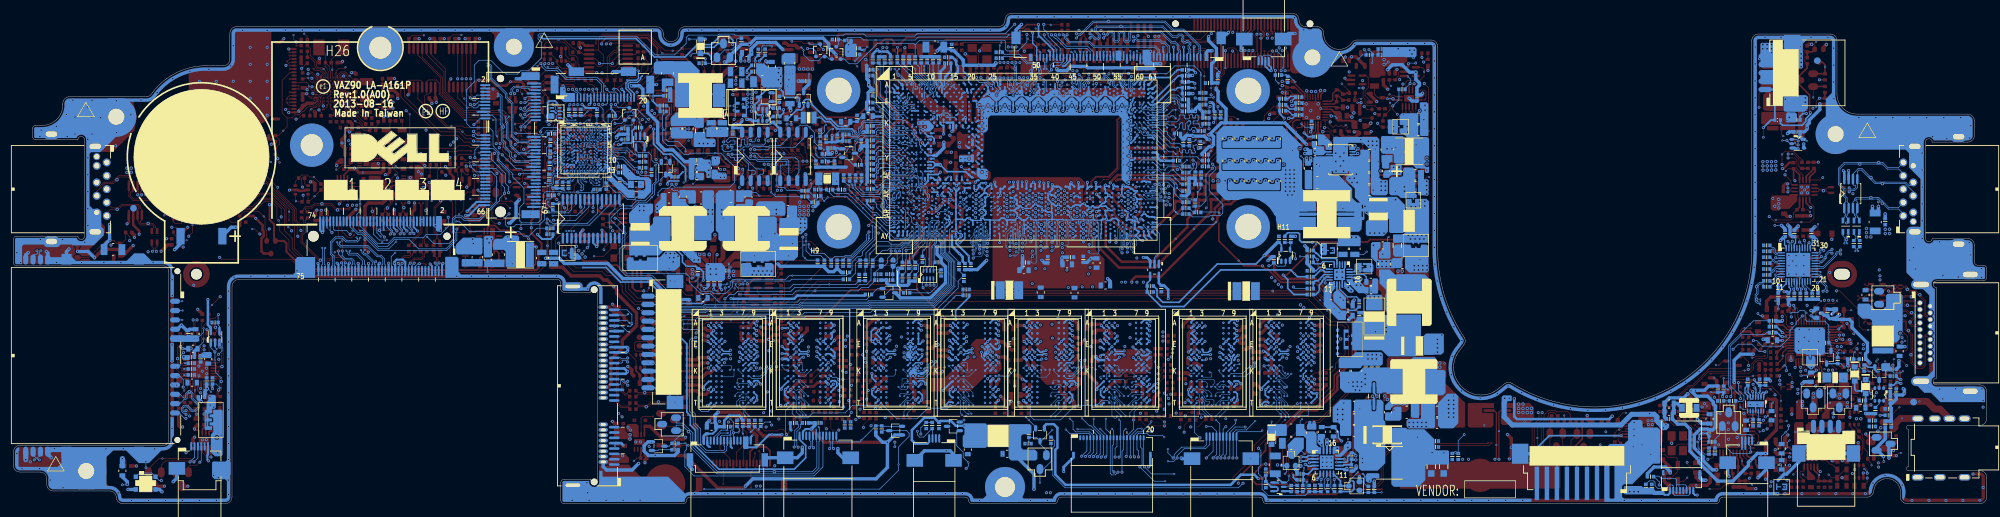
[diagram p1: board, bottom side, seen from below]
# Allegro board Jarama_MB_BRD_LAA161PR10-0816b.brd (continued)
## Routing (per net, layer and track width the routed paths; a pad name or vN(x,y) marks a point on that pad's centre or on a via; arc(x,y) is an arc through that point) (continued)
PM_SYS_RESET#: length 220.6
  TOP w0.109: v7(186.56,9.1) 189.22,9.1 v7(189.55,8.77) 189.55,8.24 188.06,6.75 JAPS.6 ; RH450.2 166.45,48.85 166.45,48.53 166.35,48.42 165.1,48.42 164.17,47.49 163.04,47.49 163.02,47.51 162.62,47.51 162.2,47.09 162.2,46.73 v2(162.05,46.58) 161.77,46.3 161.41,46.3 161.12,46.01 161.12,45.47 160.58,44.94 159.59,44.94 v7(159.52,44.86)
  IN1 w0.076: v7(189.55,8.77) 193.06,12.28 193.06,13.82 193.41,14.18 193.41,18.75 193.01,19.16 193.01,23.01 192.7,23.31 192.7,26.96 190.95,28.71 189.93,28.71 188.36,30.29 188.36,30.87 188.08,31.15 187.48,31.15 186.62,32.01 179.09,32.01 174.26,36.84 170.41,36.84 167.5,39.75 166.72,39.75 166.24,40.23 166.24,40.76 165.67,41.33 165.67,42.07 164.31,43.43 160.48,43.43 159.52,44.39 v7(159.52,44.86) ; v7(186.56,9.1) 181.32,9.1 179.51,7.29 157,7.29 155.94,8.35 155.2,8.35 153.51,10.04 139.21,10.04 137.41,8.24 111.59,8.24 109.71,10.12 107.07,10.12 103.46,13.72 101.69,13.72 98.93,16.49 98.93,27.34 99.56,27.97 99.56,31.34 102.95,34.73 102.95,37.64 105.5,40.19 105.5,43.52 109.44,47.46 113.91,47.46 114.55,48.09 114.55,48.8 115.26,49.51 115.72,49.51 116.25,50.05 116.25,51.24 117.44,52.43 117.44,53.77 v7(117,54.21)
PP: length 3.2
  TOP w0.109: R975.1 209.35,38.43 v1(209.42,38.36) v2(209.89,37.89)
  BOTTOM w0.109: U652.7 209.17,38.61 v1(209.42,38.36)
PROC_OPI_COMP: length 5
  BOTTOM w0.381: UCPU1.AY15 154.84,38.6 v2(153.71,37.47) 153.23,36.99 153.23,36.33 RC154.1
PS_ID: length 289.3
  TOP w0.109: v2(25.49,59.44) 25.49,60.3 v1(25.03,60.77)
  TOP w0.254: v1(25.03,60.77) PR102.2 PR103.2
  IN1 w0.076: v3(212.52,41.22) 212,41.22 211.68,41.54 209.8,41.54 208.86,40.6 206.53,40.6 205.56,39.63 202.82,39.63 198.39,35.21 198.39,12.18 194.73,8.52 193.58,8.52 190.79,5.72 182.35,5.72 181.58,4.96 155.29,4.96 152.54,7.7 144.13,7.7 141.65,5.22 129.19,5.22 128.47,4.5 119.62,4.5 118.7,5.42 110.13,5.42 108.37,7.17 105.16,7.17 103.18,9.15 101.72,9.15 100.22,10.65 94.86,10.65 92.08,7.87 72.41,7.87 71.67,7.13 67.52,7.13 66.97,6.59 63.89,6.59 63.36,7.12 60.07,7.12 59.88,6.93 50.43,6.93 49.12,5.62 43.06,5.62 42.43,6.24 41.56,6.24 39.68,8.13 39.68,12.57 37.43,14.82 37.43,16.7 38.17,17.44 38.17,18.46 36.96,19.66 36.96,21.2 36.2,21.96 36.2,24.6 34.77,26.03 34.77,29.61 34.28,30.09 34.28,31.35 33.42,32.22 33.42,41.3 30.57,44.15 30.57,49.56 30.14,50 30.14,51.05 30.57,51.48 30.57,55.7 25.51,60.77 v1(25.03,60.77)
  IN4 w0.076: v3(212.52,41.22) 213.24,41.94 213.24,43.88 214.56,45.2 214.56,46.09 214.47,46.18 214.47,46.84 214.15,47.15 214.15,47.8 214.46,48.1 214.46,49.17 213.73,49.9 213.73,50.54 213.98,50.78 213.98,52.08 213.71,52.34 213.71,52.46 213.49,52.68 213.49,53.06 213.29,53.26 212.83,53.26 212.74,53.17 211.71,53.17 v4(211.66,53.22)
  BOTTOM w0.109: U34.K6 211.43,53.44 v4(211.66,53.22)
PSID: length 9.4
  TOP w0.109: v1(33.41,56.37) v5(33.41,54.92)
  BOTTOM w0.254: JDCIN1.1 32.06,62.08 31.7,61.71 PL102.1 32.28,57.5 v1(33.41,56.37)
PSID-1: length 3.4
  TOP w0.109: PQ102.2 25.73,69.03 v2(25.51,69.25)
  TOP w0.254: PQ102.2 26.12,67.72 PR106.1 PR105.2
PSID-2: length 4.2
  TOP w0.254: PQ101.2 PR104.1 v2(24.19,65.49) 24.19,65.79 24.61,66.22 PQ102.1
PSID-3: length 3.4
  TOP w0.109: v2(25.95,60.89) PQ101.3
  TOP w0.254: PR103.1 25.93,62.54 PQ101.3
PWM1: length 9.4
  TOP w0.109: v6(95.21,53.64) 95.83,53.64 v2(95.96,53.51)
  TOP w0.203: PU701.6 101.63,56.15 101.66,56.13 101.66,55.48 v7(101.58,55.41)
  IN1 w0.254: v6(95.21,53.64) 96.54,54.97 101.15,54.97 v7(101.58,55.41)
  vias: v6(94.57,53.63)
PWR_LED#: length 48.3
  TOP w0.109: R1.1 270.25,38.46 v1(269.88,38.46) ; DA8.2 275.09,5.19 273.51,6.76 v2(272.99,6.76) 268.79,6.76 v1(268.28,6.26)
  IN4 w0.076: v1(268.28,6.26) 267.89,6.65 267.89,7.1 265.55,9.44 265.55,13.25 264.67,14.13 264.67,20.84 265.78,21.95 265.78,35.8 268.45,38.46 v1(269.88,38.46)
  BOTTOM w0.109: v1(268.28,6.26) 267.68,6.86 JPWR1.3
PWR_SRC_ON: length 5.2
  TOP w0.109: v1(92.44,68.05) 92.07,67.68 Q70.3
  BOTTOM w0.109: v1(92.44,68.05) 91.94,67.56 R536.1 ; R536.1 R535.2 C613.2 ; R536.1 v2(91.94,66.07)
REGN: length 24.6
  TOP w0.109: PD202.2 v2(97.3,6.18)
  IN1 w0.254: v6(97.17,8.29) 98.11,8.29 98.44,7.96 102.53,7.96 103.47,7.02 103.47,4.45 v3(103.32,4.3)
  IN4 w0.254: v4(94.84,3.39) 95.01,3.56 96.41,3.56 96.95,4.1 101.03,4.1 101.26,4.33 103.3,4.33 v3(103.32,4.3) 103.35,4.33 v4(103.75,4.33)
  BOTTOM w0.254: v4(103.75,4.33) 103.75,3.92 103.4,3.56 PR223.1 ; v4(94.84,3.39) 94.68,3.23 94.68,2.17 95.04,1.81 PR224.2
RESET#: length 116.2
  TOP w0.076: v7(247,64.5) 247.15,64.35 247.15,64.02 247.09,63.96 247.09,63.59 U636.C7
  TOP w0.109: v7(247,64.5) 247,64.89 246.63,65.26 245.75,65.26 v2(245.6,65.41) ; JSNRDG.2 254.48,59.16 v1(254.55,59.09) ; C1152.1 R1003.1 240.04,62.8 R1090.1 v7(240.06,63.71)
  IN1 w0.076: v7(240.06,63.71) 240.06,63.72 240.68,64.35 243.93,64.35 244.24,64.04 244.7,64.04 245.18,64.52 v3(246.58,64.52) 246.6,64.5 v7(247,64.5) ; v3(222.43,40.71) 221.96,40.71 220.5,42.17 217.67,42.17 214.95,39.45 213.09,39.45 209.87,36.24 206.39,36.24 203.45,33.3 203.45,28.06 202.48,27.1 202.48,16.32 v3(203.35,15.45)
  IN2 w0.102: v3(203.35,15.45) 204.56,16.66 JSATA1.20
  IN3 w0.102: v3(246.58,64.52) 246.95,64.15 247.96,64.15 249.55,65.74 251.17,65.74 251.66,65.26 251.66,65.01 254.55,62.11 v1(254.55,59.09) 254.55,58.51 253.2,57.16 249.15,57.16 248.84,57.46 245.14,57.46 244.58,56.9 243.26,56.9 239.36,53.01 236.73,53.01 235.32,51.6 233.98,51.6 231.16,48.77 227.94,48.77 226.79,47.62 226.79,45.98 223.83,43.02 223.83,42.59 222.47,41.23 222.47,40.75 v3(222.43,40.71)
ROTATION_SW#: length 139.1
  TOP w0.109: v7(206.06,50.89) 205.45,50.27 R233.2
  IN1 w0.076: v3(206.09,51.27) 206.09,50.92 v7(206.06,50.89)
  IN3 w0.102: v3(102.24,62.28) 102.24,63.1 104.81,65.67 107.46,65.67 108.71,66.91 116.83,66.91 117.53,67.61 123.83,67.61 124.55,68.33 125.95,68.33 126.13,68.51 137.38,68.51 138.22,67.67 142.39,67.67 143.3,66.76 146.25,66.76 148.58,69.1 153.67,69.1 153.85,68.92 162.71,68.92 164.2,67.42 165.27,67.42 166.79,65.9 167.99,65.9 168.69,66.59 174.78,66.59 175.33,67.14 180.31,67.14 181.08,67.92 189.82,67.92 190.11,68.21 192.96,68.21 195.07,66.1 198.59,66.1 200.64,68.16 203.5,68.16 205.2,66.45 205.2,63.89 205.86,63.23 205.86,61.08 206.7,60.24 206.7,58.75 206.39,58.44 206.39,56.73 207.46,55.66 207.46,54.54 206.39,53.48 206.39,52.18 206.09,51.88 v3(206.09,51.27)
  IN4 w0.076: v4(105.53,64.24) 105.23,64.24 103.26,62.28 v3(102.24,62.28) ; v3(206.09,51.27) 206.09,51.29 v4(206.37,51.57)
  BOTTOM w0.076: U34.B9 207.11,51.7 206.5,51.7 v4(206.37,51.57)
  BOTTOM w0.109: v4(105.53,64.24) 104.77,64.24 C1125.1 104.31,64.07 v2(103.45,63.2)
ROTATION_SW#_C: length 7.9
  BOTTOM w0.109: JROT1.1 108.93,67.02 108.82,67.13 108.6,67.13 108.43,66.96 ; 108.43,66.96 108.17,67.22 107.26,67.22 106.74,66.7 106.74,65.24 v1(106.44,64.94) 106.44,64.25 R957.1 106.44,63.51 v2(105.95,63.01) ; 108.43,66.96 JROT1.2
RREF: length 3.2
  TOP w0.203: v1(265.5,17.23) 265.5,17.32 266,17.82 U1.9
  BOTTOM w0.102: RR6.2 264.93,17.94 v2(264.32,17.33)
  BOTTOM w0.305: RR6.2 v1(265.5,17.23)
RUN_ON#: length 80.2
  TOP w0.109: v1(252.27,40.95) 252.41,41.09 252.41,41.94 252.98,42.52 252.98,44.2 255.73,46.96 v5(255.73,47.4) 258.67,50.34 258.67,54.14 258.39,54.43 Q34.2 ; v1(197.66,51.84) 197.66,52.43 U710.4
  IN2 w0.102: v1(252.27,40.95) 251.94,41.28 232.4,41.28 231.3,42.38 229.9,42.38 229.2,43.07 229.2,44.68 227.98,45.89 225.76,45.89 224.68,46.97 222.99,46.97 222.26,47.71 220.48,47.71 219.68,48.51 215.33,48.51 215.09,48.75 212.36,48.75 212.06,48.45 211.38,48.45 211.13,48.7 206.17,48.7 205.23,49.64 205.23,50.55 204.9,50.88 204.09,50.88 203.75,51.23 203.04,51.23 202.66,51.6 202.66,52.05 202.36,52.36 201.38,52.36 201.17,52.15 197.97,52.15 v1(197.66,51.84)
  BOTTOM w0.109: v1(197.66,51.84) 197.04,51.23 Q4.2
S3_+1.2V: length 2.9
  BOTTOM w0.203: PU601.7 98.92,34.74
  BOTTOM w0.254: 98.92,34.74 99.01,34.74 99.24,34.97 v2(99.59,34.97) 99.71,34.97 100.67,34.02 PR615.2
S5_+1.2V: length 3.8
  BOTTOM w0.203: PU601.8 99.14,34.34
  BOTTOM w0.254: 99.14,34.34 v2(99.79,33.69) 100.08,33.4 100.5,33.4 PC616.1 PR613.2
SATA_PRX_DTX_N0: length 80.1
  TOP w0.109: v7(195.89,16.32) 196,16.42 v6(197.08,16.42) 200.55,16.42 200.56,16.41 201.08,16.41 201.09,16.42 201.77,16.42 CS53.1
  IN1 w0.076: v7(195.89,16.32) 195.74,16.47 195.55,16.47 195.4,16.62 195.4,19.82 195.12,20.1 195.12,26.35 194.58,26.89 194.58,27.97 192.28,30.28 192.28,30.98 191.36,31.9 191.36,32.25 190.3,33.31 189.24,33.31 188.61,33.93 188.61,34.73 187.57,35.77 178.18,35.77 175.1,38.86 175.1,42.25 174.1,43.25 174.1,44.41 173.62,44.89 166.44,44.89 165.89,45.44 165.57,45.44 164.86,46.15 163.86,46.15 163.49,46.52 162.38,46.52 162.12,46.77 161.3,46.77 160.84,47.23 159.14,47.23 158.51,47.85 158.51,48.36 158.31,48.56 158.31,48.84 157.12,50.03 157.12,51.05 157.32,51.25 157.32,53.06 158.18,53.92 158.18,55.95 158.91,56.68 160.18,56.68 160.47,56.97 v3(160.47,57.92)
  IN4 w0.076: v3(160.47,57.92) 160.8,57.59 v4(160.83,57.59)
SATA_PRX_DTX_N0_C: length 5.9
  TOP w0.109: CS53.2 203.3,16.29 203.79,16.29 204.28,16.78 204.28,17.84 203.9,18.22 203.48,18.22 v1(203.36,18.34)
  BOTTOM w0.109: JSATA1.25 204.12,18.66 203.8,18.34 v1(203.36,18.34)
SATA_PRX_DTX_P0: length 80.1
  TOP w0.109: CS54.1 201.84,16.64 v6(200.82,16.64) 197.35,16.64 197.34,16.65 196.83,16.65 196.82,16.64 196,16.64 v7(195.89,16.75)
  IN1 w0.076: v7(195.89,16.75) 195.89,16.71 195.8,16.62 195.61,16.62 195.55,16.68 195.55,19.88 195.27,20.16 195.27,26.41 194.74,26.95 194.74,28.04 192.43,30.34 192.43,31.04 191.51,31.96 191.51,32.32 190.37,33.46 189.3,33.46 188.77,33.99 188.77,34.79 187.64,35.92 178.25,35.92 175.25,38.92 175.25,42.31 174.25,43.32 174.25,44.47 173.68,45.04 166.5,45.04 165.96,45.59 165.63,45.59 164.92,46.3 163.93,46.3 163.56,46.67 162.44,46.67 162.18,46.92 161.36,46.92 160.9,47.38 159.2,47.38 158.67,47.91 158.67,48.42 158.46,48.62 158.46,48.9 157.27,50.1 157.27,50.99 157.47,51.19 157.47,52.99 158.34,53.86 158.34,55.89 158.97,56.52 160.24,56.52 160.62,56.9 160.62,57.34 v3(161.21,57.92)
  IN4 w0.076: v4(160.86,58.24) 160.88,58.24 v3(161.21,57.92)
SATA_PRX_DTX_P0_C: length 5.9
  TOP w0.109: v1(203.36,17.76) 203.6,18 203.81,18 204.06,17.75 204.06,16.88 203.7,16.52 203.47,16.52 CS54.2
  BOTTOM w0.109: v1(203.36,17.76) 203.72,18.12 203.89,18.12 204.21,18.44 204.37,18.44 204.44,18.37 204.44,17.93 204.51,17.86 JSATA1.23
SATA_PTX_DRX_N0: length 86.9
  TOP w0.109: v7(195.89,15.35) 196,15.25 v6(198.76,15.25) 199.89,15.25 200.38,14.76 200.85,14.76 200.86,14.75 201.79,14.75 CS43.1
  IN1 w0.076: v7(195.89,15.35) 195.76,15.22 195.4,15.22 194.94,15.68 194.94,19.44 194.63,19.74 194.63,26.16 194.13,26.67 194.13,27.73 191.44,30.42 191.44,31.16 191.17,31.43 190.23,31.43 189.86,31.8 189.86,32.59 189.59,32.85 189.05,32.85 188.72,33.18 187.62,33.18 186.77,34.03 185.04,34.03 184.57,33.56 179.74,33.56 174.92,38.38 171.04,38.38 167.91,41.5 167.91,42.01 165.3,44.62 165.3,45 164.99,45.31 164,45.31 163.3,46.01 162.11,46.01 161.88,46.24 161.18,46.24 160.88,46.54 160.59,46.54 160.41,46.72 158.62,46.72 158.01,47.33 158.01,48.27 157.37,48.9 156.7,48.9 155.52,50.08 155.52,54.1 154.3,55.32 154.3,60.02 154.63,60.35 155.95,61.67 155.95,62.31 155.48,62.78 154.92,62.78 154.76,62.62 154.76,62.16 v3(154.55,61.96)
  IN4 w0.076: v3(154.55,61.96) 154.55,62.34 v4(154.5,62.39)
  BOTTOM w0.109: v4(154.5,62.39) 154.28,62.17 UCPU1.B15
SATA_PTX_DRX_N0_C: length 12.4
  TOP w0.109: v1(203.37,21.25) 203.61,21.49 204.28,21.49 204.79,20.98 204.79,15.08 204.35,14.64 203.16,14.64 203.04,14.75 CS43.2
  BOTTOM w0.109: v1(203.37,21.25) 203.62,21.5 204.07,21.5 204.18,21.4 204.18,21.15 204.26,21.06 JSATA1.31
SATA_PTX_DRX_P0: length 87
  TOP w0.109: CS42.1 201.77,14.53 v6(200.6,14.53) 200.3,14.53 199.8,15.02 199.03,15.02 199.02,15.01 198.5,15.01 198.49,15.02 196,15.02 v7(195.89,14.92)
  IN1 w0.076: v3(155.11,61.96) 154.91,62.16 154.91,62.56 154.98,62.63 155.42,62.63 155.8,62.25 155.8,61.73 154.15,60.08 154.15,55.25 155.37,54.03 155.37,50.02 156.64,48.75 157.31,48.75 157.85,48.21 157.85,47.27 158.55,46.57 160.34,46.57 160.52,46.39 160.82,46.39 161.12,46.08 161.82,46.08 162.05,45.86 163.24,45.86 163.94,45.16 164.93,45.16 165.14,44.94 165.14,44.56 167.76,41.94 167.76,41.44 170.97,38.22 174.86,38.22 179.67,33.41 184.64,33.41 185.1,33.88 186.71,33.88 187.56,33.03 188.65,33.03 188.98,32.7 189.53,32.7 189.71,32.52 189.71,31.74 190.17,31.28 191.11,31.28 191.29,31.1 191.29,30.35 193.97,27.67 193.97,26.6 194.48,26.09 194.48,19.68 194.79,19.38 194.79,15.62 195.33,15.07 195.74,15.07 v7(195.89,14.92)
  IN4 w0.076: v4(154.91,62.52) 155.11,62.31 v3(155.11,61.96)
  BOTTOM w0.109: v4(154.91,62.52) 154.61,62.81 UCPU1.A15
SATA_PTX_DRX_P0_C: length 12.5
  TOP w0.109: v1(203.37,21.83) 203.49,21.71 204.37,21.71 205.02,21.07 205.02,14.99 204.44,14.42 203.29,14.42 CS42.2
  BOTTOM w0.109: JSATA1.33 204.43,21.86 204.29,21.73 203.48,21.73 v1(203.37,21.83)
SATA_RCOMP: length 5
  BOTTOM w0.229: UCPU1.C12 156.34,62.33 155.97,62.7 155.97,63.38 155.85,63.51 155.85,63.71
  BOTTOM w0.381: RH43.1 v2(155.01,64.83) 155.85,63.99 155.85,63.71
SBD_WAKE#: length 2.4
  TOP w0.109: U636.F8 248.84,64.3 249.47,64.93 250.12,64.93 T252.1
SD_CD#: length 11.5
  TOP w0.109: v1(266.76,23.07) 266.8,23.02 U1.30 ; v2(270.86,17.74) 270.8,17.74 270.53,17.47 v1(269.88,17.47)
  IN3 w0.102: v1(266.76,23.07) 266.76,22.28 268.29,20.74 268.29,19.06 v1(269.88,17.47)
  BOTTOM w0.109: v1(269.88,17.47) 269.88,18.6 270.47,19.19 JCARD.8
SD_CLK: length 13.8
  TOP w0.102: v7(269.89,14.44) 270.03,14.3 CR20.1 RR4.2
  IN1 w0.102: v7(269.89,14.44) 268.55,15.78 268.55,21.4 269.79,22.64 v1(269.84,22.64)
  BOTTOM w0.102: v1(269.84,22.64) 270.33,22.16 270.33,20.73 270.47,20.59 JCARD.6
SD_CLK_R: length 3.3
  TOP w0.102: U1.17 269.44,18.35 269.26,18.17 269.26,17.45 v2(269.73,16.98) 270.55,16.15 RR4.1
SD_CMD: length 12.8
  IN4 w0.102: v4(270.02,27.54) 270.45,27.54 270.55,27.44 270.55,26.45 270.45,26.35 270.1,26.35 270,26.25 270,25.81 270.1,25.71 270.45,25.71 270.55,25.61 270.55,25.28 270.45,25.18 270.1,25.18 270,25.08 270,24.75 270.1,24.65 270.53,24.65 270.63,24.54 270.63,24.16 270.53,24.06 270.19,24.06 269.37,23.24 269.37,21.71 269.03,21.37 269.03,20.11 v4(268.22,19.3)
  BOTTOM w0.102: JCARD.3 v4(270.02,27.54)
SD_CMD_R: length 3.6
  TOP w0.102: U1.19 270.12,19.51 v7(270.12,19.52) 270.27,19.52 270.87,20.11 v2(270.87,20.32)
  IN1 w0.102: v3(270.45,19.29) 270.35,19.29 v7(270.12,19.52)
  IN4 w0.102: v3(270.45,19.29) 270.44,19.3 v4(269.74,19.3)
  BOTTOM w0.102: RR5.1 v4(269.74,19.3)
SD_D2: length 12.8
  IN4 w0.102: v4(268.22,21.06) 268.04,21.24 268.04,21.83 268.37,22.16 268.37,23.6 268.98,24.21 268.98,29.01 269.08,29.11 269.46,29.11 269.56,29.21 269.56,29.65 269.46,29.75 269.06,29.75 268.95,29.85 268.95,30.24 269.06,30.34 v4(270.02,30.34)
  BOTTOM w0.102: JCARD.1 v4(270.02,30.34)
SD_D2_R: length 2.8
  TOP w0.102: v7(270.12,20.38) 270.06,20.31 U1.21
  IN1 w0.102: v7(270.12,20.38) 270.25,20.51 270.5,20.51 v3(270.53,20.48)
  IN4 w0.102: v3(270.53,20.48) 270.17,20.48 v4(269.61,21.04)
  BOTTOM w0.102: RR8.1 269.59,21.06 v4(269.61,21.04)
SD_D3: length 12.6
  IN4 w0.102: v4(269.96,28.94) 270.48,28.94 270.58,28.84 270.58,28.13 270.48,28.03 270.17,28.03 270.07,28.13 270.07,28.33 269.97,28.43 269.61,28.43 269.51,28.33 269.51,24.07 268.89,23.44 268.89,21.94 268.55,21.6 268.55,20.52 v4(268.22,20.19)
  BOTTOM w0.102: JCARD.2 v4(269.96,28.94)
SD_D3_R: length 2.6
  TOP w0.102: v7(270.12,19.95) 270.09,19.91 U1.20
  IN1 w0.102: v7(270.12,19.95) 270.48,19.95 v3(270.53,19.9)
  IN4 w0.102: v3(270.53,19.9) 270.05,19.9 v4(269.75,20.19)
  BOTTOM w0.102: RR7.1 v4(269.75,20.19)
SD_LN0_M: length 46.2
  TOP w0.109: v1(268.4,27.54) 268.34,27.49 268.34,25.65 RR15.2
  IN1 w0.076: v1(291.78,37.91) 291.56,37.69 291.56,37.17 291.38,36.99 285.14,36.99 284.97,37.16 284.97,38.22 284.87,38.32 284.47,38.32 284.37,38.22 284.37,37.16 284.2,36.99 283.65,36.99 283.49,37.16 283.49,38.86 283.39,38.96 282.98,38.96 282.88,38.86 282.88,37.16 282.71,36.99 282.13,36.99 281.96,37.16 281.96,38.86 281.86,38.96 281.46,38.96 281.36,38.86 281.36,37.16 281.19,36.99 270.16,36.99 270.01,36.84 270.01,30.31 268.29,28.6 268.29,27.65 v1(268.4,27.54)
  BOTTOM w0.109: v1(291.78,37.91) 291.66,37.79 291.66,37.57 291.86,37.37 292.19,37.37 292.35,37.22 JCARD.14
SD_LN0_M_R: length 2.7
  TOP w0.109: RR15.1 268.28,24.29 268.28,24.01 268.72,23.58 v6(268.72,23.27) 268.72,22.71 268.8,22.63 U1.25
SD_LN0_P: length 46.2
  TOP w0.109: v1(267.81,27.54) 268.12,27.23 268.12,25.93 RR16.2
  IN1 w0.076: v1(291.19,37.91) 291.41,37.69 291.41,37.23 291.32,37.14 285.2,37.14 285.13,37.22 285.13,38.29 284.94,38.48 284.4,38.48 284.21,38.29 284.21,37.22 284.14,37.14 283.72,37.14 283.64,37.22 283.64,38.92 283.45,39.11 282.92,39.11 282.73,38.92 282.73,37.22 282.65,37.14 282.19,37.14 282.12,37.22 282.12,38.92 281.93,39.11 281.39,39.11 281.2,38.92 281.2,37.22 281.13,37.14 270.1,37.14 269.86,36.9 269.86,30.37 268.14,28.66 268.14,27.87 v1(267.81,27.54)
  BOTTOM w0.109: v1(291.19,37.91) 291.44,37.66 291.44,37.45 291.25,37.26 JCARD.13
SD_LN0_P_R: length 2.8
  TOP w0.109: RR16.1 268.06,24.13 268.06,23.92 268.48,23.5 268.48,22.7 268.4,22.63 U1.26
SD_LN1_M: length 43.8
  IN1 w0.076: v7(269.42,25.46) 269.72,25.46 269.79,25.38 269.79,24.15 270.35,23.59 270.35,21.57 269.02,20.24 269.02,17.1 270.5,15.62 270.5,11.12 269.84,10.46 269.84,9.19 271.68,7.35 286.49,7.35 287.61,6.23 290.01,6.23 290.24,6 291.64,6 v1(292.19,6.56)
  BOTTOM w0.109: JCARD.17 292.35,7.3 291.91,6.86 291.91,6.72 292.07,6.56 v1(292.19,6.56)
SD_LN1_M_R: length 5.2
  TOP w0.109: RR13.1 269.53,24.65 269.68,24.65 269.85,24.47 269.85,23.97 v6(270.28,23.54) 270.5,23.33 270.5,22.01 270.49,22 270.49,21.42 270.5,21.41 270.5,21.21 270.31,21.02 269.96,21.02 269.87,21.11 U1.23
SD_LN1_P: length 43.8
  IN1 w0.076: v1(291.41,6.56) 291.59,6.74 291.71,6.74 291.8,6.65 291.8,6.38 291.57,6.16 290.3,6.16 290.07,6.38 287.67,6.38 286.56,7.5 271.75,7.5 270,9.25 270,10.4 270.66,11.06 270.66,15.68 269.17,17.17 269.17,20.18 270.5,21.51 270.5,23.66 269.94,24.21 269.94,25.38 270.02,25.46 v7(270.31,25.46)
  BOTTOM w0.109: v1(291.41,6.56) 291.56,6.56 291.69,6.69 291.69,6.84 291.25,7.28 JCARD.18
SD_LN1_P_R: length 5.2
  TOP w0.109: RR12.1 270.08,24.31 270.08,24.07 270.72,23.43 v6(270.72,21.74) 270.72,21.12 270.4,20.8 269.96,20.8 269.87,20.71 U1.22
SD_RCLK_M: length 12.9
  TOP w0.109: v1(269.46,13.39) 269.28,13.57 268.97,13.57 268.72,13.82 268.72,14.3 269.12,14.7 269.12,14.82 268.79,15.15
  BOTTOM w0.109: JCARD.10 270.38,14.99 269.79,15.58 269.52,15.58 269.29,15.82 269.29,16.43 269.15,16.56 268.75,16.56 268.65,16.46 268.65,15.72 267.7,14.77 267.7,14.45 268.15,14 268.46,14 269.17,14.71 269.82,14.71 270.14,14.39 270.14,13.83 269.88,13.58 269.64,13.58 v1(269.46,13.39)
SD_RCLK_M_R: length 2.6
  TOP w0.109: U1.15 268.4,17.62 268.48,17.54 268.48,16.95 268.74,16.7 268.98,16.7 269.12,16.56 269.12,16.39 RR2.1
SD_RCLK_P: length 12.6
  TOP w0.109: RR3.2 269.34,14.81 269.34,14.61 268.94,14.21 268.94,13.91 269.06,13.8 269.37,13.8 269.46,13.89 v1(269.46,13.98)
  BOTTOM w0.109: JCARD.9 270.35,16.39 269.77,15.81 269.61,15.81 269.51,15.91 269.51,16.52 269.24,16.79 v6(268.98,16.79) 268.67,16.79 268.43,16.55 268.43,15.81 267.48,14.87 267.48,14.36 268.06,13.78 268.55,13.78 269.26,14.49 269.73,14.49 269.92,14.3 269.92,13.93 269.79,13.8 269.64,13.8 v1(269.46,13.98)
SD_RCLK_P_R: length 2.6
  TOP w0.109: RR3.1 269.35,16.39 269.35,16.65 269.07,16.92 268.83,16.92 268.71,17.04 268.71,17.52 268.8,17.62 U1.16
SD_REG2: length 3.4
  BOTTOM w0.102: CR6.2 267.72,23.38 266.85,24.25 v2(266.85,24.72)
  BOTTOM w0.508: RR14.2 268.22,22.86 267.85,23.22 CR6.2
SD_REG2_R:
  vias: v6(269.8,22)
SD_WAKE#_R: length 7.9
  TOP w0.109: U1.32 266,24.3 RR10.1 266.43,24.54 266.82,24.94 266.82,26.7 RR18.1 265.79,27.73 265.19,27.73 v5(264.59,28.34)
SDIO_CLK: length 71
  TOP w0.109: R1360.2 219.39,62.14 219.39,61.68 v2(219.14,61.44) 219.14,61.12 v1(218.74,60.71)
  IN1 w0.076: v1(218.74,60.71) 218.2,60.71 218.03,60.89 205.59,60.89 203.66,58.96 201.96,58.96 201.02,58.02 199.87,58.02 198.06,56.21 196.25,56.21 195.79,55.75 194.02,55.75 193.24,56.54 185.91,56.54 185.86,56.59 184.92,56.59 184.4,57.11 184.14,57.11 183.88,57.38 183.52,57.73 181.75,57.73 181.63,57.61 181.04,57.61 180.31,58.34 178.15,58.34 177.93,58.56 170.07,58.56 167.31,61.31 163.76,61.31 163.24,61.83 161.03,61.83 160.65,61.45 v3(160.65,60.19)
  IN4 w0.076: v3(160.65,60.19) 160.55,60.09 v4(160.55,59.83)
  BOTTOM w0.109: UCPU1.E3 162.16,59.71 161.99,59.55 161.66,59.55 161.36,59.85 160.57,59.85 v4(160.55,59.83) ; JNGFF1.9 218.46,60.99 v1(218.74,60.71)
SDIO_CMD: length 68.7
  TOP w0.109: R1361.2 218.07,60.74 218.67,60.13 v1(218.76,60.13)
  IN1 w0.076: v3(161.23,60.09) 161.23,60.71 160.95,60.99 160.95,61.43 161.21,61.68 163.18,61.68 164.01,60.85 167.13,60.85 169.88,58.1 177.75,58.1 177.96,57.88 180.12,57.88 180.85,57.15 181.82,57.15 181.94,57.27 183.33,57.27 183.42,57.19 183.95,56.65 184.21,56.65 184.73,56.13 185.7,56.13 185.75,56.08 193.05,56.08 193.83,55.3 195.98,55.3 196.44,55.75 198.25,55.75 199.71,57.21 200.31,57.21 200.66,56.85 202.2,56.85 204.76,59.42 212.77,59.42 212.95,59.6 212.95,60.18 213.2,60.43 217.72,60.43 217.9,60.26 218.63,60.26 v1(218.76,60.13)
  IN4 w0.076: v3(161.23,60.09) 161.23,59.58 v4(161.51,59.3)
  BOTTOM w0.109: v1(218.76,60.13) 218.53,60.13 218.18,60.49 JNGFF1.11
SDIO_D0: length 69.1
  TOP w0.109: v1(218.79,59.29) 218.76,59.32 218.73,59.32 218.12,59.93 R1362.2 ; RH434.2 164.78,57.77 164.78,58.21 v2(165.54,58.98) v7(166.9,60.33)
  IN1 w0.076: v3(162.07,61.3) 163.34,61.3 163.99,60.65 166.58,60.65 v7(166.9,60.33) 166.97,60.26 167.43,60.26 169.8,57.89 177.66,57.89 177.88,57.68 180.03,57.68 180.76,56.95 181.86,56.95 182.37,56.45 184.12,56.45 184.64,55.93 185.62,55.93 185.67,55.88 192.97,55.88 193.75,55.09 196.06,55.09 196.52,55.55 198.33,55.55 199.79,57.01 200.22,57.01 200.58,56.65 202.28,56.65 204.85,59.22 218.71,59.22 v1(218.79,59.29)
  IN4 w0.076: v4(161.82,60.99) 161.82,61.04 v3(162.07,61.3)
  BOTTOM w0.109: v4(161.82,60.99) 162.03,60.78 UCPU1.D3 ; v1(218.79,59.29) 218.09,59.99 JNGFF1.13
SDIO_D1: length 68.4
  TOP w0.109: R1363.2 218.32,58.78 218.92,58.78 v1(219.37,59.24)
  IN1 w0.076: v3(161.31,61.27) 161.31,61.04 161.66,60.69 163.64,60.69 163.88,60.45 166.25,60.45 166.77,59.93 167.48,59.93 169.71,57.69 177.58,57.69 177.79,57.48 179.94,57.48 180.67,56.75 181.78,56.75 182.28,56.24 184.04,56.24 184.56,55.72 185.46,55.72 185.51,55.67 189.33,55.67 189.74,55.27 193.29,55.27 193.66,54.89 196.15,54.89 196.56,55.3 198.77,55.3 199.22,55.76 199.74,55.76 200.37,56.4 202.32,56.4 204.93,59.01 217.82,59.01 218.05,58.78 218.92,58.78 v1(219.37,59.24)
  IN4 w0.076: v4(161.18,60.89) 161.31,61.02 v3(161.31,61.27)
  BOTTOM w0.109: v1(219.37,59.24) 218.99,58.86 218.59,58.86 217.96,59.49 JNGFF1.15 ; v4(161.18,60.89) 161.18,60.64 161.51,60.31 UCPU1.E4
SDIO_D2: length 65.6
  TOP w0.109: v1(218.76,58.35) 218.56,58.15 R1364.2
  IN1 w0.076: v3(162.15,60.21) 162.45,60.51 163.49,60.51 163.76,60.24 166.16,60.24 166.69,59.72 167.39,59.72 169.63,57.49 177.49,57.49 177.71,57.27 179.86,57.27 180.58,56.54 181.69,56.54 182.2,56.04 183.95,56.04 184.47,55.52 185.38,55.52 185.43,55.47 189.25,55.47 189.66,55.06 193.2,55.06 193.58,54.69 196.23,54.69 196.65,55.1 198.85,55.1 199.31,55.56 199.82,55.56 200.46,56.19 202.4,56.19 205.02,58.81 217.74,58.81 218.2,58.35 v1(218.76,58.35)
  IN4 w0.076: v3(162.15,60.21) 162.35,60.21 v4(162.53,60.38)
  BOTTOM w0.109: JNGFF1.17 218.13,58.99 v1(218.76,58.35) ; v4(162.53,60.38) 162.53,60.33 162.48,60.38 162.48,61.19
  BOTTOM w0.254: UCPU1.C3 162.48,61.19
SDIO_D3: length 67
  TOP w0.109: R1365.2 218.6,57.26 v2(219.09,57.76) 219.4,58.06 v1(219.4,58.28)
  IN1 w0.076: v3(162.81,59.65) 163.2,60.04 166.08,60.04 166.6,59.52 167.31,59.52 169.54,57.29 177.41,57.29 178.35,56.34 181.61,56.34 182.11,55.84 183.87,55.84 184.39,55.32 185.29,55.32 185.34,55.27 189.17,55.27 189.57,54.86 193.12,54.86 193.5,54.48 196.32,54.48 196.73,54.9 198.94,54.9 199.4,55.35 199.91,55.35 200.54,55.99 202.48,55.99 205.1,58.61 217.62,58.61 218.28,57.95 219.07,57.95 v1(219.4,58.28)
  IN4 w0.076: v4(163.03,60.39) 163.03,59.87 v3(162.81,59.65)
  BOTTOM w0.109: v4(163.03,60.39) 162.81,60.17 UCPU1.E2 ; v1(219.4,58.28) 218.99,57.87 218.66,57.87 218.04,58.49 JNGFF1.19
SDIO_RST#: length 6.7
  TOP w0.109: U679.D1 219.64,55.21 219.64,55.76 220.21,56.33 v2(220.21,56.93) 220.14,57.01 219.16,57.01 218.75,56.6 v1(218.75,56.47) 218.65,56.37 R1328.2
  BOTTOM w0.109: JNGFF1.23 217.75,57.49 218.75,56.49 v1(218.75,56.47)
SDIO_RST#_R: length 2
  TOP w0.109: U679.A1 220.1,53.25 R1314.2 220.83,53.49 R1313.2
SDIO_WAKE#: length 3.9
  TOP w0.109: v2(216.64,52.78) 216.78,52.92 218.1,52.92 218.59,52.43 R1215.2 218.88,52.43 219.39,52.94 219.39,53.49 219.28,53.59 U679.A2
SDIO_WAKE#_Q: length 6
  TOP w0.109: U679.D2 219.35,55.17 v2(219.35,55.96) v1(219.35,56.47) 218.36,55.48 R1327.2
  BOTTOM w0.109: v1(219.35,56.47) 219.35,56.49 217.85,57.99 JNGFF1.21
SENSE_A: length 2.9
  TOP w0.203: UA2.34 22.92,22.9 22.85,22.83 22.74,22.83 22.5,22.59 v1(22.28,22.59)
  BOTTOM w0.109: v1(22.28,22.59) 21.35,22.59 v2(21.33,22.61)
  BOTTOM w0.203: RA41.1 22.29,22.58 v1(22.28,22.59)
SENSE_B: length 2.3
  TOP w0.203: UA2.33 22.85,23.3 22.71,23.16 22.6,23.16 22.52,23.07 v2(22.12,23.07) 21.85,23.07 21.62,22.84 RA24.1
SENSOR_ALERT#: length 2.8
  TOP w0.109: U636.H6 250.08,62.84 250.41,63.17 250.69,63.17 251.12,63.6 251.12,63.8 v2(251.16,63.84) 251.48,63.84 251.66,63.66 R1158.1
SENSOR_DFU_EN#: length 119.3
  TOP w0.076: U636.F2 249.08,60.59 249.08,60.06
  TOP w0.109: R1220.1 249.21,58.66 v1(249.57,59.03) 249.57,59.52 249.08,60.01 249.08,60.06 ; v7(254.35,66.28) 253.96,66.66 JSNRDG.17
  IN1 w0.076: v7(254.35,66.28) 254.06,65.98 253.81,65.98 253.59,65.76 253.59,64.6 254.73,63.46 254.73,60.03 254.34,59.63 253.37,59.63 253.02,59.28 249.83,59.28 v1(249.57,59.03)
  IN2 w0.102: v3(224.33,45.88) 223.7,46.5 222.8,46.5 222.05,47.25 217.66,47.25 216.93,47.98 214.89,47.98 214.46,47.54 211.51,47.54 210.99,48.07 206.07,48.07 204.93,49.21 204.13,49.21 203.96,49.39 203.96,50.3 203.57,50.68 199.92,50.68 199.66,50.43 198.39,50.43 197.63,51.19 196.57,51.19 196.11,51.65 193.08,51.65 192.94,51.51 191,51.51 190.12,50.63 185.65,50.63 185.42,50.4 184.06,50.4 183.44,49.78 182.01,49.78 181.78,50.01 180.5,50.01 178.3,52.21 174.24,52.21 173.61,51.57 169.89,51.57 169.51,51.19 168.17,51.19 165.73,48.75 162.83,48.75 162.43,48.34 v3(162.43,48.32)
  IN3 w0.102: v3(224.33,45.88) 224.33,46.17 227.64,49.48 228.83,49.48 232.54,53.2 234.56,53.2 235.5,54.14 239.48,54.14 242.96,57.62 244.29,57.62 244.85,58.17 248.72,58.17 v1(249.57,59.03)
  IN4 w0.076: v4(161.39,47.71) 161.49,47.71 161.69,47.91 161.99,47.91 162.43,48.34 v3(162.43,48.32)
  BOTTOM w0.102: UCPU1.AK4 161.23,46.92 161.23,47.43 161.39,47.59 v4(161.39,47.71)
SENSOR_EN: length 132.7
  TOP w0.109: U716.5 239.48,51.44 R1250.1 238.69,52.23 v2(238.09,52.23) 237.81,51.95 237.81,51.36 238.51,50.66 238.51,50.34 237.78,49.6 237.78,48.87 v1(237.81,48.83) ; JSNRDG.16 253.94,66.16 254.41,65.69 v1(254.51,65.69)
  IN2 w0.102: v3(164.28,49.16) 165.81,49.16 168.07,51.42 169.41,51.42 169.8,51.8 173.51,51.8 174.15,52.43 178.39,52.43 180.59,50.24 181.87,50.24 182.1,50.01 183.34,50.01 183.97,50.63 185.32,50.63 185.55,50.86 190.03,50.86 190.91,51.74 192.84,51.74 193.01,51.9 196.18,51.9 196.66,51.42 197.73,51.42 198.49,50.66 199.57,50.66 199.82,50.91 203.68,50.91 203.93,50.66 204.74,50.66 205.02,50.38 205.02,49.44 206.17,48.29 211.11,48.29 211.63,47.77 214.24,47.77 214.67,48.2 217.1,48.2 217.82,47.48 222.14,47.48 222.89,46.73 224.21,46.73 v3(224.91,46.03)
  IN3 w0.102: v1(254.51,65.69) 255.54,64.66 255.54,58.18 254.65,57.29 254.65,51.21 253.12,49.68 244.15,49.68 243.45,50.38 239.39,50.38 237.84,48.83 v1(237.81,48.83)
  IN4 w0.076: v4(164.66,49.26) 164.38,49.26 v3(164.28,49.16) ; v3(224.91,46.03) 225.05,45.89 225.05,45.16 227.53,42.68 227.82,42.68 228.71,41.79 229.63,41.79 231.22,43.38 234.14,43.38 235.68,44.92 235.68,45.27 237.81,47.4 v1(237.81,48.83)
  BOTTOM w0.102: 163.99,48.97 163.59,48.57 162.59,48.57 UCPU1.AG3
  BOTTOM w0.109: v4(164.66,49.26) 164.48,49.08 164.1,49.08 163.99,48.97
SENSOR_HUB_I2C_WAKE: length 107.9
  TOP w0.109: R1252.1 255.73,52 v1(255.73,51.72) 255.73,51.42 v2(255.45,51.14)
  IN1 w0.076: v1(162.51,51.47) 162.51,51.8 163.44,52.74 166.08,52.74 166.8,53.45 168.84,53.45 169.38,52.92 169.85,52.92 170.03,53.09 171.12,53.09 171.68,53.65 173.2,53.65 173.72,53.13 182.17,53.13 184.02,51.28 186.35,51.28 186.98,50.66 194.09,50.66 195.26,49.49 199.82,49.49 200.5,50.17 203.42,50.17 203.93,50.68 205.02,50.68 205.5,50.2 206.14,50.2 206.62,49.72 207.18,49.72 207.89,50.43 212.74,50.43 213.4,51.09 218.14,51.09 218.61,50.62 221.59,50.62 222.25,49.96 224.34,49.96 226.78,47.52 226.78,45.96 v3(228.17,44.56)
  IN3 w0.102: v3(228.17,44.56) 229.19,45.58 236.39,45.58 238.7,47.89 238.7,49.13 239.72,50.15 243.35,50.15 244.05,49.45 253.57,49.45 255.73,51.61 v1(255.73,51.72)
  BOTTOM w0.109: UCPU1.Y3 162.17,51.81 v1(162.51,51.47)
SENSOR_HUB_I2C_WAKE_R: length 20.7
  TOP w0.076: 249.75,60.03 249.59,60.19 249.59,60.43 249.34,60.68 U636.G2
  TOP w0.109: 254.34,57.82 253.59,57.82 253.12,58.29 252.51,58.29 252.04,58.76 251.87,58.76 251.04,59.59 250.18,59.59 249.75,60.03 ; 254.34,57.82 255.07,58.56 255.07,63.46 253.87,64.66 JSNRDG.13 ; 254.34,57.82 254.34,56.47 v2(254.91,55.9) 255.63,55.18 R1253.1 255.5,54.59 255.5,53.86 R1252.2
SENSOR_HUB_WAKE#: length 48.7
  TOP w0.109: v1(248.91,59.61) 248.84,59.68 U636.F1
  IN3 w0.102: v1(221.13,43.44) 221.13,44.15 221.95,44.98 222.81,44.98 227.55,49.71 228.74,49.71 232.63,53.6 234.65,53.6 235.51,54.47 239.49,54.47 242.87,57.84 244.2,57.84 244.75,58.4 248,58.4 248.91,59.32 v1(248.91,59.61)
  BOTTOM w0.109: v1(221.13,43.44) 221.68,42.88 221.68,41.82 221.35,41.49 220.43,41.49 220.05,41.86 216.5,41.86 215.84,42.52 215.84,43.84 215.67,44.01 v2(215.67,44.17) 215.67,45.48 215.46,45.69 214.89,45.69 R232.2
SENSOR_I2C_SCL: length 141.5
  TOP w0.076: U636.B5 246.68,62.34 246.44,62.58 245.43,62.58 v7(245.4,62.54)
  TOP w0.102: v7(252.61,62.21) 252.66,62.16 JSNRDG.8
  TOP w0.109: v1(214.6,65.97) 214.81,66.19 214.81,66.48 R985.2 ; v7(240.59,59.44) 240.09,59.44 240.04,59.39 R854.1
  IN1 w0.076: v7(240.59,59.44) 240.87,59.16 241.83,59.16 242.36,59.7 243.62,59.7 244.04,60.12 244.04,62.09 244.72,62.77 245.19,62.77 245.4,62.57 v7(245.4,62.54) 245.81,62.54 v3(245.87,62.59) 246.03,62.43 247.23,62.43 247.3,62.36 249.33,62.36 249.87,62.9 251.37,62.9 252.05,62.21 v7(252.61,62.21)
  IN3 w0.102: v3(245.87,62.59) 245.81,62.65 245.09,62.65 243.56,64.18 238.11,64.18 235.86,66.43 223.18,66.43 221.79,65.03 215.69,65.03 215.2,65.53 215.04,65.53 v1(214.6,65.97) 214.74,66.11 214.74,67.33 212.14,69.93 200.36,69.93 198.06,67.62 195.7,67.62 193.31,70.01 146.93,70.01 146.25,69.32 139.77,69.32 139.44,69.66 139.44,70.21 v1(139.36,70.29)
  BOTTOM w0.109: v1(139.36,70.29) 139.34,70.26 139.34,70.22 137.68,68.57 134.53,68.57 133.65,67.69 JLVDS2.33
SENSOR_I2C_SDA: length 144
  TOP w0.076: v7(245.4,63.15) 245.45,63.09 246.41,63.09 246.43,63.08 246.44,63.08 246.6,62.92 246.6,62.71 246.72,62.59 247.08,62.59 U636.C5
  TOP w0.102: JSNRDG.9 252.63,62.66 v7(252.61,62.64)
  TOP w0.109: v7(240.59,59.93) 240.09,59.93 240.04,59.98 R855.1 ; v1(215.18,65.97) 214.69,65.48 213.98,65.48 v2(213.87,65.38) 213.2,64.7 R986.2
  IN1 w0.076: v7(252.61,62.64) 252.58,62.67 252.24,62.67 251.55,63.36 249.68,63.36 249.14,62.81 248.54,62.81 248,63.36 246.55,63.36 246.33,63.13 245.91,63.13 v3(245.87,63.18) 245.84,63.15 v7(245.4,63.15) 245.29,63.05 244.61,63.05 243.76,62.2 243.76,60.23 243.5,59.98 240.65,59.98 v7(240.59,59.93)
  IN3 w0.102: v1(139.95,70.29) 139.74,70.09 139.74,69.78 139.9,69.63 146.12,69.63 146.81,70.32 193.44,70.32 195.83,67.93 197.94,67.93 200.24,70.23 212.27,70.23 215.04,67.46 215.04,66.11 v1(215.18,65.97) 215.82,65.34 221.66,65.34 223.06,66.73 235.98,66.73 238.23,64.49 243.69,64.49 245.22,62.96 245.65,62.96 v3(245.87,63.18)
  BOTTOM w0.109: v1(139.95,70.29) 139.39,69.73 139.29,69.73 137.81,68.26 134.66,68.26 134.15,67.75 JLVDS2.34
SENSOR_INT#: length 146.9
  TOP w0.109: RH298.1 179.22,47.11 178.28,47.11 177.53,46.36 177.04,46.36 176.88,46.2 v7(176.88,45.97) ; R1135.2 252.91,68.69 v7(252.94,68.66) ; R1367.2 252.22,58.16 252.74,57.64 v1(253,57.64)
  IN1 w0.076: v3(163.06,48.32) 163.53,48.32 163.62,48.41 164.1,48.41 164.32,48.19 165.22,48.19 165.31,48.1 166.87,48.1 167.09,47.89 167.09,47.49 167.89,46.68 174.73,46.68 175.44,45.97 v7(176.88,45.97) ; v1(253,57.64) 253.4,57.24 254.98,57.24 255.87,58.13 255.87,67.47 254.68,68.66 v7(252.94,68.66)
  IN2 w0.102: v3(224.66,45.39) 224.21,45.39 223.34,46.26 222.71,46.26 221.95,47.02 217.56,47.02 216.84,47.75 214.98,47.75 214.55,47.32 211.41,47.32 210.89,47.84 205.98,47.84 204.83,48.98 204.04,48.98 203.73,49.29 203.73,50.21 203.48,50.45 200.09,50.45 199.84,50.2 198.3,50.2 197.54,50.96 196.47,50.96 196.12,51.32 193.07,51.32 192.38,50.63 190.98,50.63 189.88,49.54 188.17,49.54 187.76,49.13 182.33,49.13 181.68,49.78 180.4,49.78 178.21,51.98 174.35,51.98 173.72,51.34 169.98,51.34 169.6,50.96 168.29,50.96 165.86,48.52 163.29,48.52 163.06,48.29 v3(163.06,48.32)
  IN3 w0.102: v3(224.66,45.39) 225.04,45.39 226.31,46.66 226.31,47.82 227.74,49.26 229.96,49.26 231.92,51.21 231.92,51.29 233.55,52.92 234.61,52.92 235.6,53.91 239.58,53.91 243.06,57.39 244.38,57.39 244.94,57.95 252.53,57.95 252.84,57.64 v1(253,57.64)
  IN4 w0.076: v4(161.79,47.63) 161.98,47.63 162.16,47.81 162.57,47.81 163,48.25 163.02,48.25 163.06,48.29 v3(163.06,48.32)
  BOTTOM w0.109: UCPU1.AH4 161.51,47.35 v4(161.79,47.63) 162.25,47.63 162.48,47.86 162.48,48.19 162.67,48.38 163.66,48.38 163.81,48.53 164.83,48.53 T285.1
SENSOR_RST#: length 104.7
  TOP w0.109: v7(223.82,55.08) 224.11,54.78 224.11,54.46 224.7,53.87 226.65,53.87 226.98,54.2 227.83,54.2 228.83,55.2 v2(231.53,55.2) 231.56,55.2 237.32,60.96 237.32,61.98 238.16,62.82 R1090.2 ; RH452.2 166.86,55.23 166.5,55.59 163.89,55.59 163.78,55.48 161.43,55.48 v7(161.21,55.26)
  IN1 w0.076: v3(160.82,55.32) 160.77,55.26 v7(161.21,55.26) ; v7(223.82,55.08) 223.46,55.08 v3(222.47,56.07)
  IN2 w0.102: v3(160.82,55.32) 160.42,55.72 160.42,57.23 159.89,57.77 159.89,58 160.67,58.78 162.49,58.78 163.16,59.46 163.16,59.67 163.44,59.95 168.8,59.95 169.54,59.22 173.75,59.22 175.02,60.49 175.02,60.93 177.2,63.11 177.2,63.39 178.57,64.75 178.57,65.81 178.97,66.21 181.93,66.21 182.36,65.78 198.33,65.78 201.39,62.72 201.87,62.72 204.54,60.05 204.54,59.88 205.62,58.8 216.71,58.8 218.55,56.96 221.58,56.96 v3(222.47,56.07)
  IN4 w0.076: v4(160.82,54.57) v3(160.82,55.32)
SENSOR_STANDBY#: length 92.2
  TOP w0.109: D86.2 236.96,54.21 235.97,55.2 v2(235.97,58.36) v1(236.52,58.91)
  IN2 w0.102: v3(162.2,59.47) 162.2,59.67 163.39,60.87 164.74,60.87 169.05,65.18 174.52,65.18 175.27,64.42 177.91,64.42 178.34,64.85 178.34,65.91 179.37,66.94 189.41,66.94 190.34,66.01 198.42,66.01 201.35,63.08 203.91,63.08 204.17,62.82 220.01,62.82 220.74,62.09 222.89,62.09 225.07,64.27 228.85,64.27 229.33,63.79 229.33,63.15 230.14,62.34 233.09,62.34 v1(236.52,58.91)
  IN4 w0.076: v3(162.2,59.47) v4(161.82,59.85)
  BOTTOM w0.109: UCPU1.C4 161.49,61.4 161.49,60.77 161.82,60.43 v4(161.82,59.85)
SERIRQ: length 80
  IN2 w0.102: v3(160.88,53.65) 160.88,53.35 161.87,52.36 167.17,52.36 167.64,52.83 167.64,53.18 168,53.54 168.89,53.54 169.34,53.09 171.01,53.09 171.64,53.73 175.63,53.73 176.32,54.42 179.19,54.42 179.7,53.91 182.54,53.91 182.77,54.14 182.77,54.44 183.43,55.1 189.37,55.1 189.83,54.64 193.43,54.64 193.53,54.54 204.72,54.54 204.79,54.47 205.23,54.47 205.68,54.01 205.91,54.01 206.29,53.63 206.98,53.63 210.31,50.3 212.12,50.3 212.88,49.54 215.31,49.54 v3(215.58,49.27)
  IN4 w0.076: v3(160.88,53.65) 161.03,53.81 v4(161.03,54.01) ; v4(215.3,45.27) 215.3,45.39 216.08,46.17 216.08,47.28 215.42,47.94 215.42,48.26 215.58,48.41 v3(215.58,49.27) 215.75,49.45 215.75,50.99 215.27,51.47 214.29,51.47 214.13,51.63 214.13,52.14 213.86,52.41 213.86,52.52 213.66,52.73 213.66,53.1 213.15,53.61 213.15,53.86 213.14,53.87 213.14,53.87 212.94,54.07 212.93,54.07 212.92,54.08 212.13,54.08 v4(211.97,53.93)
  BOTTOM w0.076: v4(211.97,53.93) 212.11,54.07 212.11,54.7
  BOTTOM w0.109: v4(161.03,54.01) 161.15,54.13 UCPU1.T4 ; v4(215.3,45.27) 215.3,44.76 RH29.1 214.36,43.82 212.67,43.82 212.39,44.1 212.39,44.73 212.42,44.76 U652.27
  BOTTOM w0.254: U34.M3 212.11,54.7
SKIN_TEMP0: length 44.7
  IN1 w0.076: v3(229.95,43.51) 229.95,44.2 228.34,45.81 228.34,47.4 226.74,49 226.74,49.37 226.47,49.64 225.75,49.64 224.45,50.95 222.53,50.95 221.87,51.61 220.94,51.61 220.92,51.62 219,51.62 217.8,52.83 216.19,52.83 215.82,53.2 212.67,53.2 212.49,53.02 210.46,53.02 210.14,52.7 v7(209.8,52.7) 209.8,52.7 v3(209.43,53.07)
  IN4 w0.076: v4(228.99,42.32) 228.99,42.54 v3(229.95,43.51) ; v4(209.16,52.76) 209.16,52.81 v3(209.43,53.07)
  BOTTOM w0.109: R933.2 R936.1 216.95,41.28 218.14,40.09 v2(218.48,40.09) 218.93,40.09 219.64,40.8 227.04,40.8 228.57,42.32 v4(228.99,42.32) ; v4(209.16,52.76) 208.98,52.94 U34.E7
SKIN_TEMP1: length 58.6
  TOP w0.109: v1(183.43,26.48) 183.27,26.31 R938.1 182.68,26.2 R937.2 ; v7(196.79,34.12) 196.91,34.12 198.21,35.42 198.21,36.48 200.01,38.27 200.01,46.22 199.16,47.07 v2(199.16,48.61) 199.16,49.98 v7(198.79,50.35)
  IN1 w0.076: v3(196.08,33.82) 196.49,33.82 v7(196.79,34.12) ; v7(198.79,50.35) 199.64,50.35 200.2,50.91 203.12,50.91 203.63,51.42 205.37,51.42 205.8,51.85 206.17,51.85 206.77,52.46 v3(207.55,52.46) 207.56,52.47 207.56,53.03 v7(207.57,53.04)
  IN3 w0.102: v3(192.59,22.84) 193.27,22.84 193.91,23.48 193.91,26.78 194.95,27.82 194.95,32.54 196.08,33.67 v3(196.08,33.82)
  IN4 w0.076: v3(192.59,22.84) 191.51,23.92 191.2,23.92 190.91,24.21 190.91,24.49 190.68,24.72 190.35,24.72 190.12,24.49 190.12,24.24 189.83,23.94 186.44,23.94 186.17,23.67 186.17,23.41 185.88,23.12 185.55,23.12 185.53,23.14 184.72,23.14 184.47,23.38 184.47,24.61 184.31,24.77 183.88,24.77 183.43,25.22 v1(183.43,26.48) ; v4(207.96,52.57) 207.66,52.57 v3(207.55,52.46)
  BOTTOM w0.109: U34.D7 208.33,52.94 v4(207.96,52.57)
SKIP#: length 3
  TOP w0.203: PU701.7 102.03,55.69 v1(102.14,55.58)
  BOTTOM w0.254: v1(102.14,55.58) 101.57,55.01 PR718.1
SKIP#1:
  vias: v2(98.85,54.75)
SLATE_MODE: length 111.9
  TOP w0.076: v7(245.52,63.69) 245.53,63.69 245.96,63.69 246.06,63.59 246.44,63.59 246.45,63.59 246.6,63.44 246.6,63.22 246.73,63.09 247.48,63.09 247.6,62.97 247.6,62.58 U636.D5
  IN1 w0.076: v3(245.26,63.99) 245.56,63.69 v7(245.52,63.69)
  IN2 w0.102: v3(161.13,45.45) 161.13,45.6 162.71,47.18 165.19,47.18 168.51,50.5 169.79,50.5 170.17,50.88 178.2,50.88 179.76,49.32 181.49,49.32 182.14,48.67 185.15,48.67 185.81,48.01 190.73,48.01 192.53,49.81 192.53,50.13 193.1,50.71 196.08,50.71 196.28,50.5 197.35,50.5 198.11,49.74 199.99,49.74 200.45,49.28 202.62,49.28 202.77,49.13 203.24,49.13 203.85,48.52 204.64,48.52 205.79,47.38 208.99,47.38 210.16,46.21 212.86,46.21 213.07,46 220.25,46 v3(220.35,45.89)
  IN3 w0.102: v3(220.35,45.89) 220.55,46.1 220.55,46.88 221.67,48 221.67,49.25 224.94,52.52 224.94,57.21 225.8,58.07 238.27,58.07 238.88,58.68 239.69,58.68 240.98,59.98 243.74,59.98 244.04,60.28 244.04,61.62 244.7,62.29 245.58,62.29 245.73,62.14 246.5,62.14 246.75,62.39 246.75,63.33 246.4,63.69 245.56,63.69 v3(245.26,63.99)
  IN4 w0.076: v4(160.9,45.14) 161.13,45.37 v3(161.13,45.45)
  BOTTOM w0.109: v4(160.9,45.14) 161.51,45.75 UCPU1.AL4
SLEEVE: length 17
  TOP w0.102: DA1.3 v2(13.06,14.44)
  IN1 w1.016: JHP1.4 3.3,13.65 3.75,14.11 12.33,14.11 14.43,12 15.18,12
  vias: v1(16.5,16.63) v1(16.8,16.12) v1(21.75,23.54) v1(22.35,23.55) v6(15.86,11.37) v6(16.26,10.87)
SLEW: length 4.9
  TOP w0.109: v2(200.64,57.18) 199.99,57.18 PC502.2
  TOP w0.203: PC502.2 199.24,57.84 198.81,58.28 197.44,58.28 197.22,58.5 PU501.21
SLEWA: length 4.8
  TOP w0.203: v6(104.03,60.31) 103.94,60.31 103.55,59.91 PU701.15
  BOTTOM w0.109: v2(104.9,61.76) PR701.2
  BOTTOM w0.203: v6(104.03,60.31) 104.01,60.31 103.89,60.42 103.89,60.45 PR714.1 103.52,61.07 104.18,61.07 104.57,60.69 PR701.2
SLP_WLAN#: length 75.5
  TOP w0.109: v7(160.46,45.25) v2(160.79,45.58) 160.79,46.11 162.49,47.81 163.12,47.81 163.26,47.67 164.1,47.67 165.08,48.66 RH402.1
  IN1 w0.076: v7(160.46,45.25) 160.46,44.88 v3(160.52,44.81)
  IN2 w0.102: v3(160.52,44.81) 160.7,44.81 161.13,44.38 163.16,44.38 163.95,45.17 164.76,45.17 165.04,45.45 167.56,45.45 169.01,46.9 175.2,46.9 176.1,47.8 178.95,47.8 180.38,46.36 191.46,46.36 192.54,47.44 198.71,47.44 199.13,47.02 202.26,47.02 204.09,45.19 204.82,45.19 206.78,43.24 211.21,43.24 211.78,42.66 v3(212.39,42.66)
  IN4 w0.076: v3(212.39,42.66) 212.41,42.69 212.41,44.49 213.57,45.65 213.57,45.78 213.8,46.01 213.83,46.01 214.06,46.24 214.06,46.67 213.62,47.11 213.62,49.32 213.28,49.67 213.28,50.79 213.48,50.99 213.48,51.39 213.02,51.85 213.02,52.13 v4(213.12,52.23) ; v3(160.52,44.81) 160.5,44.84 160.5,45.03 160.56,45.1 v4(160.56,45.39)
  BOTTOM w0.109: v4(213.12,52.23) 212.91,52.44 U34.N8
SM_INTRUDER#: length 7.8
  BOTTOM w0.102: UCPU1.AU6 159.61,41.63 159.61,39.87 159.82,39.66
  BOTTOM w0.109: 159.82,39.66 161.02,38.46 161.88,38.46 162.26,38.08 162.26,36.2 RH11.2
SM_PG_CTRL: length 30.2
  BOTTOM w0.254: PR615.1 103.12,34.02 v2(103.57,34.48) 104.13,35.03 114.62,35.03 120.11,29.55 123.54,29.55 125.62,31.64 RC161.1 RC159.2 125.62,33.05 125.18,33.5 UC1.4
SM_RCOMP0: length 9.1
  TOP w0.381: RC55.1 129.09,47.1 128.81,47.38 127.92,47.38 126.63,46.08 v2(126.63,44.99) 126.63,43.75 127.41,42.96 v1(127.66,42.96)
  BOTTOM w0.254: UCPU1.AU60 127.1,42.34 127.1,42.66 127.4,42.96 v1(127.66,42.96)
SM_RCOMP1: length 8.1
  TOP w0.381: RC58.1 131.43,45.04 v2(130.54,44.15) 130.54,43.32 128.48,41.26 126.46,41.26 v1(126.41,41.31)
  BOTTOM w0.254: v1(126.41,41.31) 126.58,41.49 UCPU1.AV60
SM_RCOMP2: length 8.5
  TOP w0.381: RC60.1 131.23,46.97 130.7,46.45 130.7,45.6 129.11,44.01 129.11,43.49 v2(127.79,42.17) 126.96,42.17 126.62,42.5 v1(126.62,42.68)
  BOTTOM w0.254: v1(126.62,42.68) 126.39,42.68 126.18,42.48 UCPU1.AU61
SMBALERT#: length 128.2
  TOP w0.109: RH81.1 168.51,49.26 v7(168.36,49.26) ; v2(253.37,70.24) 253.37,69.6 v1(252.96,69.2) 252.61,69.2 R1136.2
  IN1 w0.076: v7(168.36,49.26) 168.38,49.28 168.65,49.28 v3(168.93,49)
  IN2 w0.102: v3(225.71,43.07) 225.45,43.07 223,45.53 221.41,45.53 220.24,44.36 216.86,44.36 216.25,44.97 214.78,44.97 213.73,43.91 212.47,43.91 210.86,45.53 209.84,45.53 208.67,46.69 203.97,46.69 202.68,47.99 200.44,47.99 199.38,49.06 193.87,49.06 193.76,49.17 192.86,49.17 191.02,47.33 185.53,47.33 184.87,47.99 181.86,47.99 181.21,48.64 177.59,48.64 176.69,49.54 175.91,49.54 175.25,50.2 170.46,50.2 169.26,49 v3(168.93,49)
  IN3 w0.102: v1(252.96,69.2) 253.16,69.01 253.16,64.6 255.31,62.44 255.31,58.27 254.07,57.03 254.07,52.08 252.28,50.29 248.35,50.29 247.1,51.54 239.16,51.54 238.6,50.99 236.87,50.99 231.71,45.83 228.07,45.83 225.71,43.47 v3(225.71,43.07)
  IN4 w0.076: v4(164.86,46.97) 164.92,46.97 165.74,47.79 166.35,47.79 167.67,49.11 168.83,49.11 v3(168.93,49)
  BOTTOM w0.109: UCPU1.AN2 162.81,44.49 163.04,44.71 164.31,44.71 164.65,45.06 164.65,45.39 164.86,45.6 v4(164.86,46.97)
SMBCLK: length 26.4
  TOP w0.109: v1(177.13,51.34) 177.13,52.04 177.49,52.4 178.1,52.4 178.7,52.99 RH105.1 179.05,53.25 179.05,54.69 179.62,55.27 QH3.6
  IN4 w0.076: v4(169.77,47.84) 169.69,47.91 169.69,49.35 170.13,49.79 176.37,49.79 177.01,50.43 177.01,51.21 v1(177.13,51.34)
  BOTTOM w0.109: RH470.1 170.15,48.22 v4(169.77,47.84) 169.67,47.74 v2(169.67,47.35) 169.67,47.35 168.35,46.03 165.73,46.03 164.97,45.26 164.97,44.38 164.53,43.95 163.26,43.95 162.92,43.6 UCPU1.AP2
SMBDATA: length 22.2
  TOP w0.109: v1(176.55,51.34) 176.55,52.43 176.82,52.7 176.82,53.5 RH111.1 177.28,53.97 QH3.3
  IN4 w0.076: v1(176.55,51.34) 176.73,51.16 176.73,50.54 176.25,50.07 170.01,50.07 169.41,49.46 169.41,47.86 v4(169.34,47.79)
  BOTTOM w0.102: UCPU1.AH1 163.51,47.4 164.2,47.4
  BOTTOM w0.109: RH471.1 169.34,48.29 v4(169.34,47.79) 169.34,47.46 168.22,46.34 165.73,46.34 v2(165.58,46.49) 165.45,46.62 165.45,46.91 165.03,47.33 165.03,47.33 164.95,47.4 164.2,47.4
SML0CLK: length 76
  IN3 w0.102: v3(164.74,44.76) 164.67,44.7 164.67,44.32 165.37,43.62 168.04,43.62 169.83,45.41 173.51,45.41 176.35,42.58 176.35,41.28 176.7,40.93 176.8,40.93 177.13,40.6 177.13,39.99 v1(177.16,39.96) 177.26,39.86 178.47,39.86 182.38,35.94 185.01,35.94 185.79,35.17 185.79,33.87 184.94,33.02 184.94,31.51 186.26,30.18 190.72,30.18 193.01,27.9 193.01,26.09 192.69,25.78 192.69,24.86 192.82,24.74 192.96,24.74 v1(193.16,24.93)
  IN4 w0.076: v3(164.74,44.76) 164.76,44.76 164.74,44.74 v3(164.74,44.76) ; v3(164.74,44.76) 164.53,44.56 v4(164.53,44.43)
  BOTTOM w0.109: JNFC1.8 188.45,9.17 188.45,8.72 188.54,8.63 188.54,8.02 188.91,7.65 191.68,7.65 192.84,8.82 192.84,11.16 193.57,11.89 193.57,13.32 194.13,13.88 194.13,24.49 193.81,24.8 193.3,24.8 v1(193.16,24.93) ; v4(164.53,44.43) 164.53,44.43 164.46,44.35 UCPU1.AN1 ; RH70.1 176.54,36.51 v2(176.84,36.8) 177.16,37.12 v1(177.16,39.96)
SML0DATA: length 76.1
  IN3 w0.102: v1(193.16,24.32) 193.05,24.43 192.69,24.43 192.39,24.74 192.39,25.9 192.7,26.22 192.7,27.77 190.59,29.88 186.14,29.88 184.63,31.38 184.63,33.15 185.48,33.99 185.48,35.04 184.88,35.64 182.26,35.64 178.34,39.56 176.98,39.56 176.7,39.84 v1(176.7,40.34) 176.7,40.49 176.04,41.15 176.04,42.45 173.39,45.11 169.96,45.11 168.17,43.32 165.25,43.32 164.37,44.19 164.37,44.52 v3(164.13,44.76)
  IN4 w0.076: v3(164.13,44.76) 164.13,44.86 v4(163.9,45.09)
  BOTTOM w0.102: 163.57,46.49 163.57,46.49 UCPU1.AK1
  BOTTOM w0.109: 163.57,46.49 163.77,46.29 163.77,45.8 163.96,45.61 163.96,45.28 163.9,45.21 v4(163.9,45.09) ; v1(176.7,40.34) 176.68,40.32 v2(176.68,39.37) 176.68,37.91 175.95,37.18 174.48,37.18 173.93,36.64 RH72.1 ; JNFC1.7 188.95,9.17 188.95,8.7 188.86,8.6 188.86,8.15 189.04,7.97 191.55,7.97 192.47,8.89 192.47,11.23 193.25,12.01 193.25,13.45 193.81,14.01 193.81,24.36 193.68,24.49 193.32,24.49 v1(193.16,24.32)
SML1ALERT#: length 120.9
  TOP w0.109: R1158.2 252.16,64.71 v1(252.16,65.26) 251.4,66.02 R1229.1
  IN2 w0.102: v3(224.36,42.52) 224.13,42.52 222.98,41.36 221.74,41.36 221.11,41.99 216.64,41.99 214.97,40.32 212.83,40.32 210.83,42.32 205.11,42.32 202.16,45.27 198.42,45.27 197.4,46.3 193.02,46.3 191.94,45.22 179.91,45.22 179.26,45.87 176.03,45.87 175.96,45.8 169.67,45.8 166.74,42.88 165.68,42.88 165.37,43.19 163.87,43.19 163.52,42.83 163.52,42.68 163.24,42.4 162.83,42.4 162.5,42.73 162.15,42.73 v3(161.84,42.43)
  IN3 w0.102: v1(252.16,65.26) 252.17,65.26 255.09,62.35 255.09,58.36 253.84,57.12 253.84,52.17 252.18,50.52 248.45,50.52 247.19,51.77 239.07,51.77 238.51,51.21 236.78,51.21 231.62,46.06 227.97,46.06 224.43,42.52 v3(224.36,42.52)
  IN4 w0.076: v3(161.84,42.43) 161.58,42.17 v4(161.48,42.17)
SML1CLK: length 73.6
  TOP w0.109: v7(212.15,65.24) 213.24,65.24 213.94,65.94 QH4.6 213.94,66.47 RH453.1
  IN1 w0.076: v7(212.15,65.24) 212.15,65.13 211.78,64.77 211.78,64.54 211.13,63.89 208.63,63.89 208.15,63.41 202.21,63.41 201.88,63.74 201.72,63.74 v3(201.67,63.79)
  IN3 w0.102: v3(170.25,48.24) 170.15,48.34 170.15,49.41 170.78,50.05 175.14,50.05 175.44,49.75 176.54,49.75 177.05,50.26 179.3,50.26 180.16,49.4 184.09,49.4 184.59,48.9 186.7,48.9 188.81,51.01 190.49,51.01 190.99,51.51 194.82,51.51 196.23,52.92 198.06,52.92 201.9,56.75 201.9,57.95 201.71,58.14 201.71,58.95 201.87,59.11 201.87,59.93 201.12,60.68 201.12,63.45 201.41,63.74 201.62,63.74 v3(201.67,63.79)
  IN4 w0.076: v4(170.2,47.76) 170.2,48.19 v3(170.25,48.24)
  BOTTOM w0.102: 165.09,42.6 164.56,42.07 164,42.07 163.59,42.48 162.46,42.48
  BOTTOM w0.109: 165.09,42.6 166.13,43.65 166.8,43.65 v2(168.98,45.83) 170.22,47.07 170.22,47.73 v4(170.2,47.76) 170.43,47.76 RH469.1
  BOTTOM w0.254: UCPU1.AU3 162.46,42.48
SML1DATA: length 70.8
  TOP w0.109: QH4.3 212.64,67.18 212.12,66.66 RH454.1 211.11,66.19 211.11,65.15 v7(211.11,65.15)
  IN1 w0.076: v7(211.11,65.15) 211.5,64.76 211.5,64.65 211.02,64.17 208.51,64.17 208.03,63.69 202.33,63.69 201.69,64.32 201.69,64.36 v3(201.68,64.37)
  IN3 w0.102: v3(201.68,64.37) 201.61,64.3 201.54,64.3 200.82,63.57 200.82,60.55 201.57,59.8 201.57,59.24 201.4,59.08 201.4,58.01 201.59,57.82 201.59,56.88 197.94,53.22 196.11,53.22 194.7,51.81 190.86,51.81 190.37,51.32 188.68,51.32 186.57,49.21 184.71,49.21 184.22,49.7 180.28,49.7 179.42,50.56 176.92,50.56 176.42,50.05 175.56,50.05 175.27,50.35 170.66,50.35 169.84,49.54 169.84,48.48 169.53,48.17 v3(168.98,48.17)
  IN4 w0.076: v3(168.98,48.17) 168.93,48.17 v4(168.57,47.81)
  BOTTOM w0.102: 163.65,47.63 163.58,47.63 163.58,47.63 162.63,47.63 162.31,47.31 UCPU1.AH3 ; 165.13,47.57 165.44,47.25
  BOTTOM w0.109: RH472.1 168.37,48.01 v4(168.57,47.81) 168.62,47.76 168.62,47.28 v2(168.42,47.07) 168.04,46.69 166,46.69 165.44,47.25 ; 163.65,47.63 165.07,47.63 165.13,47.57
SNUB_1.8VSP: length 1.1
  BOTTOM w0.109: PC439.1 v2(224.33,34.73)
SNUB_3V: length 1.8
  BOTTOM w0.109: v2(196.76,47.19) 196.54,46.97 195.94,46.97 195.7,46.72 PC333.1
SNUB_5V: length 1.8
  BOTTOM w0.109: PC329.1 184.16,46.66 v2(183.66,46.16)
SNUB_+1.2V: length 1.3
  BOTTOM w0.109: v2(89.49,39.99) 89.66,39.82 PC613.1
SOSCI: length 5.5
  TOP w0.109: Y1.2 242.71,63.51 CH1202.1 244.38,63.51 v2(244.98,64.11) 245.59,64.71 246.27,64.71 246.84,64.15
  TOP w0.254: U636.B8 246.84,64.15
SOSCO: length 7
  TOP w0.076: U636.B7 246.84,63.47 246.59,63.71 246.59,64.01 246.51,64.09
  TOP w0.109: Y1.1 242.45,61.21 243.89,62.65 CH1203.1 245.4,63.99 245.4,64.17 245.69,64.46 246.17,64.46 246.51,64.12 246.51,64.09
SP7_SDWP: length 16.9
  TOP w0.109: U1.29 267.2,23.21 v1(266.76,23.66)
  IN3 w0.102: v1(269.47,12.78) 270.29,13.6 270.29,17.65 268.69,19.24 268.69,22.64 267.67,23.66 v1(266.76,23.66)
  BOTTOM w0.109: JCARD.11 270.48,13.59 269.67,12.78 v1(269.47,12.78)
SPARE1: length 7
  TOP w0.076: 250.08,61.74 249.94,61.59 247.58,61.59 U636.C4
  TOP w0.109: 250.08,61.74 250.25,61.91 250.56,61.91 251.1,62.45 v2(251.1,62.56) 251.1,62.87 251.39,63.16 JSNRDG.10
SPARE2: length 13.2
  TOP w0.109: v7(253.94,63.66) 253.94,63.66 JSNRDG.11 ; U636.A3 246.22,61.34 246.02,61.14 v7(245.87,61.14)
  IN1 w0.076: v7(253.94,63.66) 254.4,63.2 254.4,61.66 253.92,61.18 253.48,61.18 252.6,60.3 250.15,60.3 249,61.45 247.09,61.45 246.69,61.04 245.96,61.04 v7(245.87,61.14)
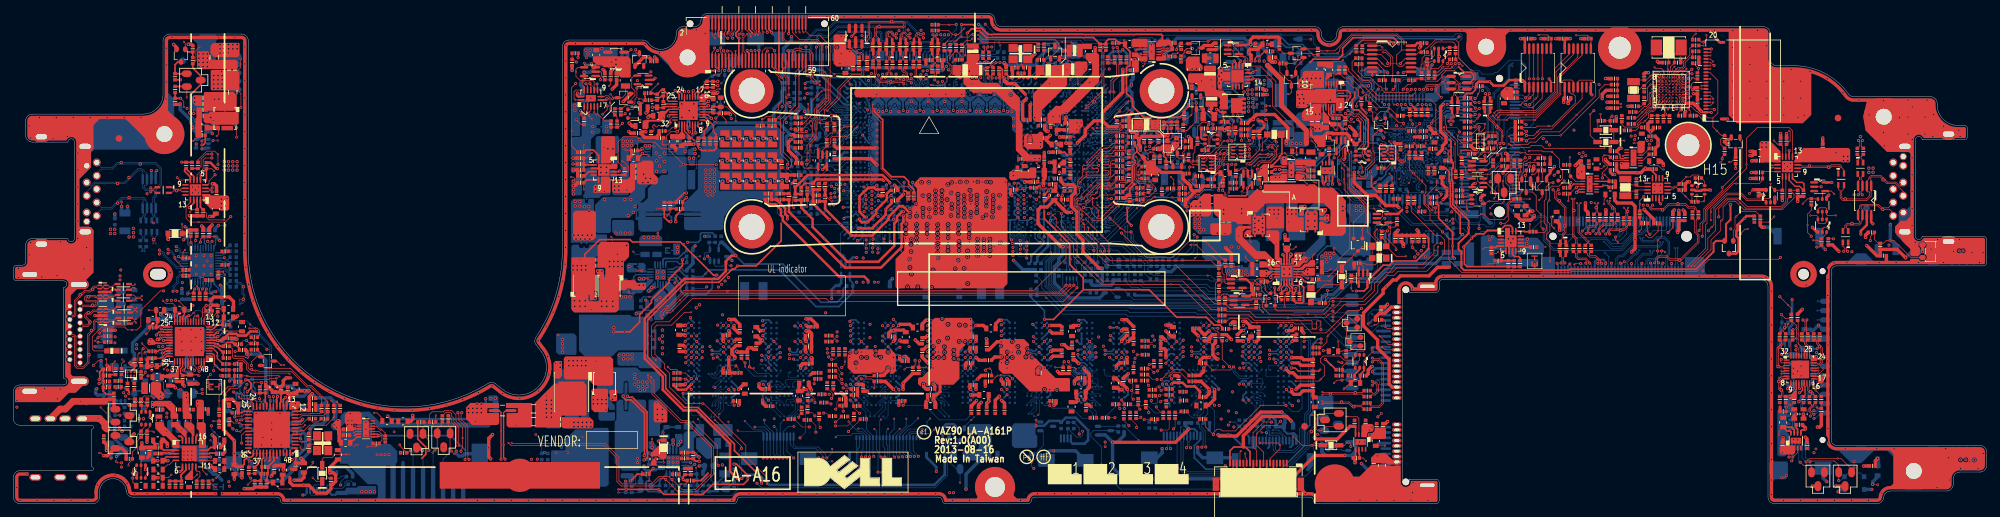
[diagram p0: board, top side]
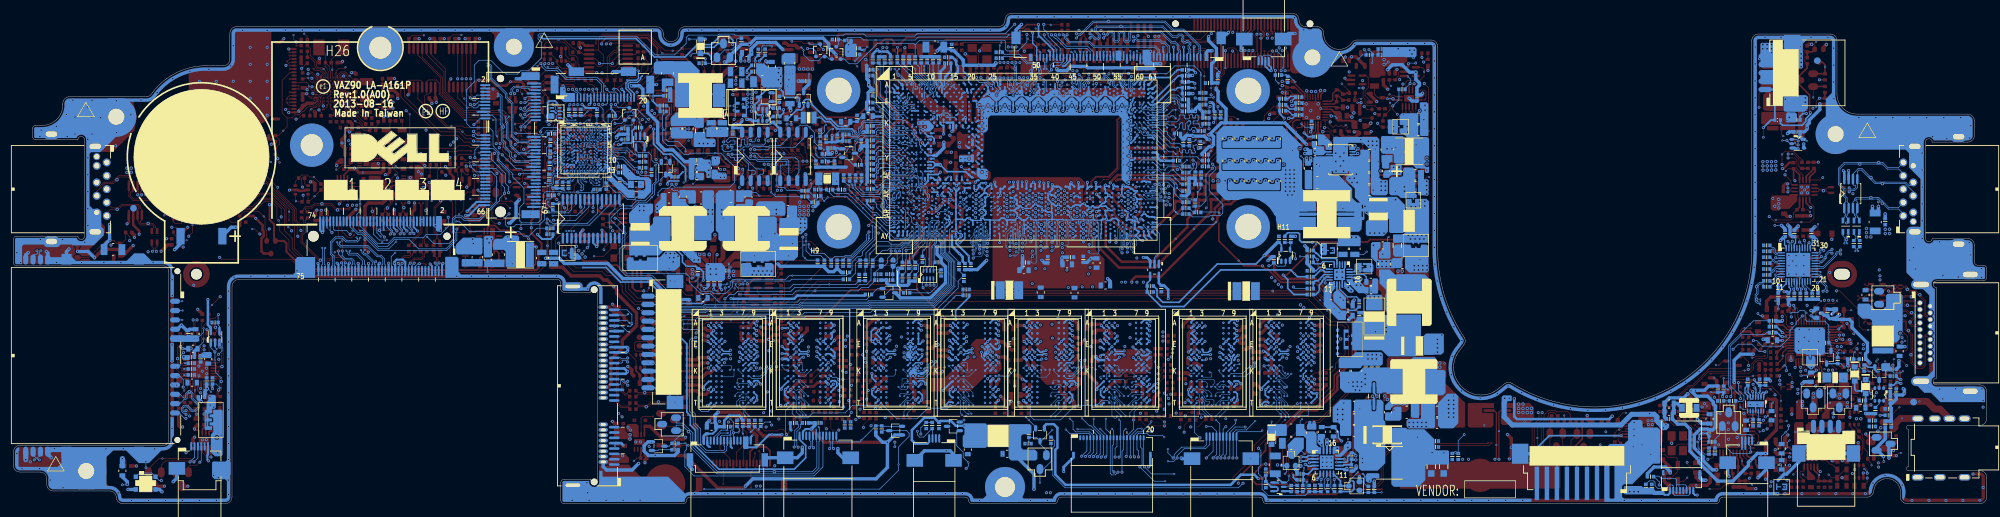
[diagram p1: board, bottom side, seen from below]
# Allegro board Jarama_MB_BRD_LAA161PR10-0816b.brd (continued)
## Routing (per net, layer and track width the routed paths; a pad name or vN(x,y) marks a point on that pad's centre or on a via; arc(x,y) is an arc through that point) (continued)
SPI_CLK32: length 14.8
  TOP w0.109: RH256.1 167.18,53.09 v7(167.58,53.09)
  IN1 w0.076: v3(168.08,52.99) 167.68,52.99 v7(167.58,53.09)
  IN4 w0.076: v3(168.08,52.99) 168.57,52.5 168.84,52.5 169.26,52.92 171.15,52.92 171.28,53.04 v4(173.98,53.04)
  BOTTOM w0.109: v4(173.98,53.04) 174.25,53.31 MR257.2 175.41,54.15 175.41,55.61 176.52,56.73 177.59,56.73 178,56.32 U2.6
SPI_CLK_ROM: length 5.4
  TOP w0.109: v1(184.96,54.47) 184.66,54.76 RH258.1 MR256.2 184.99,56.12 185.59,56.71 v2(185.59,56.76)
  BOTTOM w0.109: v1(184.96,54.47) 184.73,54.23 184.4,54.23 184.3,54.34 184.3,54.64 183.7,55.24 U48.6
SPI_DIN32: length 9.1
  TOP w0.109: RP5.1 184.23,51.95 v1(184.36,52.08)
  BOTTOM w0.109: v1(184.36,52.08) 184.36,52.1 183.83,51.57 179.47,51.57 179.27,51.37 U2.2
SPI_DO32: length 9.9
  TOP w0.109: v1(184.38,53.07) 184.26,52.95 RP5.3
  BOTTOM w0.109: v1(184.38,53.07) 182.39,53.07 182.04,53.42 178.35,53.42 176.73,55.05 U2.5
SPI_IO2_ROM: length 18.8
  TOP w0.109: v1(187.76,52.38) v2(186.61,52.38) 186.41,52.38 185.17,51.14 184.71,51.14 v7(184.54,50.96) ; RP4.2 179.57,50.75 v7(179.75,50.92)
  IN1 w0.076: v7(179.75,50.92) 179.58,50.92 179.42,51.08 179.42,51.52 179.97,52.07 182.94,52.07 184.05,50.96 v7(184.54,50.96)
  BOTTOM w0.109: U48.3 183.7,49.22 183.53,49.39 183.16,49.39 183.05,49.5 183.05,50.06 183.16,50.17 184.14,50.17 186.28,52.31 187.69,52.31 v1(187.76,52.38)
SPI_IO3_ROM: length 25.9
  TOP w0.109: v7(180.08,51.68) 180.01,51.75 RP4.4 ; v7(186.26,50.69) 186.68,51.11 188.13,51.11 v2(188.71,51.69) 189.03,52.01 189.03,53.37 188.52,53.88 188.2,53.88 v1(187.75,53.44)
  IN1 w0.076: v7(180.08,51.68) 180.36,51.39 183.05,51.39 184.01,50.43 185.06,50.43 185.58,50.95 186.01,50.95 v7(186.26,50.69)
  BOTTOM w0.109: U48.7 184.97,55.17 185.39,54.75 185.39,53.86 185.5,53.75 185.74,53.75 185.85,53.86 185.85,54.53 185.95,54.64 186.24,54.64 186.35,54.53 186.35,53.61 186.46,53.5 186.8,53.5 186.91,53.61 186.91,54.77 187.01,54.87 188.15,54.87 188.58,54.44 188.58,54.28 188.41,54.11 188.26,54.11 187.98,54.39 187.42,54.39 187.32,54.29 187.32,53.99 187.43,53.88 187.88,53.88 187.95,53.81 187.95,53.54 187.85,53.44 v1(187.75,53.44)
SPI_PCH_DO2_32: length 12.9
  TOP w0.109: RP5.2 184.03,52.45 184.19,52.61 v2(184.99,52.61) 185.05,52.56 185.05,52.18 v1(184.94,52.08)
  BOTTOM w0.109: v1(184.94,52.08) 184.94,52.22 184.66,52.5 184.04,52.5 183.39,51.85 178.25,51.85 177.74,51.34 177.74,49.64 178,49.39 U2.3
SPI_PCH_DO3_32: length 8.9
  TOP w0.109: v1(184.97,53.12) 184.97,53.37 184.8,53.54 184.16,53.54 184.07,53.45 RP5.4
  BOTTOM w0.109: v1(184.97,53.12) 184.58,53.51 182.29,53.51 182.13,53.66 180.53,53.66 179.27,54.92 U2.7
SPI_SI_ROM: length 22.9
  TOP w0.109: v1(188.36,53.44) 188.8,53 188.8,52.25 187.92,51.37 186.46,51.37 v7(185.7,50.61) ; v7(179.74,51.35) 179.63,51.25 RP4.3
  IN1 w0.076: v7(179.74,51.35) 179.95,51.35 180.83,50.47 183.67,50.47 183.92,50.22 185.32,50.22 v7(185.7,50.61)
  BOTTOM w0.109: v1(188.36,53.44) 188.36,53.63 188.54,53.81 189.05,53.81 v2(189.22,53.63) 189.22,53.12 188.92,52.81 188.03,52.81 187.83,53.02 186.48,53.02 186.01,53.49 185.3,53.49 185.04,53.74 183.04,53.74 182.77,54.01 182.77,54.64 182.43,54.99 U48.5
SPI_SO_ROM: length 19.6
  TOP w0.109: v7(184.97,50.8) 185.3,50.8 186.44,51.94 187.98,51.94 188.34,52.3 v1(188.34,52.38) ; v7(180.51,51.71) 180.51,51.48 180.17,51.13 180.17,50.8 179.61,50.25 RP4.1
  IN1 w0.076: v7(180.51,51.71) 183.02,51.71 184.08,50.64 184.82,50.64 v7(184.97,50.8)
  BOTTOM w0.109: v1(188.34,52.38) 188.34,52.35 187.9,51.9 187.47,51.9 187.39,51.82 187.39,51.55 187.29,51.44 186.97,51.44 186.86,51.55 186.86,51.82 186.76,51.93 186.28,51.93 185.31,50.96 185.31,50.06 185.2,49.94 184.41,49.94 184.3,49.84 184.3,49.5 184.41,49.39 184.8,49.39 184.97,49.22 U48.2
SPK_L+_C:
  vias: v1(20.82,15.17) v1(20.85,14.56) v2(23.44,15.11)
SPK_L-_C:
  vias: v1(22.98,13.56) v1(22.95,12.98)
SPK_OUT_L+:
  vias: v2(25.19,10.92)
SPK_OUT_L-:
  vias: v2(22.9,10.85)
SPK_OUT_R+:
  vias: v2(26.74,10.92)
SPK_OUT_R-:
  vias: v2(28.63,10.74)
SPK_R+_C:
  vias: v1(25.9,16.51) v1(25.9,15.92) v2(26.02,15.25)
SPK_R-_C:
  vias: v1(27.58,15.27) v1(27.59,14.69) v2(28.37,15.22)
SSD_PWREN: length 26.4
  TOP w0.109: v7(199.56,13.06) 199.59,13.04 201.1,13.04 201.36,12.78 U724.3 ; v7(200.42,31.89) 200.21,32.1 v2(200.21,32.34) RH431.1 200.96,33.31 U682.4
  IN1 w0.076: v7(200.42,31.89) 200.42,31.59 200.04,31.21 200.04,17.18 199.43,16.57 199.43,13.19 v7(199.56,13.06)
SSD_PWREN#: length 66.9
  TOP w0.109: RH431.2 200.48,34.22 200.94,33.76 201.73,33.76 201.99,34.02 U682.2 201.99,35.62 RH423.1 202.24,36.05 202.49,35.8 203.76,35.8 204.27,36.3 204.27,39.1 202.68,40.69 202.68,45.26 v2(200.98,46.96) 200.21,47.73 v7(200.21,52.78)
  IN1 w0.076: v3(163.19,57.18) 163.29,57.08 163.85,57.08 165.21,55.72 167.19,55.72 167.89,55.02 168.52,55.02 168.88,54.67 170.91,54.67 170.99,54.59 173.78,54.59 174.33,54.05 175.4,54.05 175.89,54.54 177.16,54.54 177.5,54.2 177.96,54.2 178.21,53.95 182.51,53.95 183.24,53.21 183.69,53.21 184.22,52.68 186.1,52.68 187.31,51.47 188.97,51.47 189.87,52.37 191.36,52.37 192.15,51.58 195.16,51.58 195.73,52.15 197.08,52.15 197.59,52.66 200.09,52.66 v7(200.21,52.78)
  IN4 w0.076: v3(163.19,57.18) 163.1,57.09 v4(162.81,57.09)
SUS_STAT#: length 61.4
  TOP w0.109: v2(212.87,47.01) 213.06,47.01 v1(213.67,46.4) 213.67,46.17 213.44,45.93 R1238.1
  IN2 w0.102: v1(213.67,46.4) 213.35,46.72 211.66,46.72 210.78,47.61 205.88,47.61 204.74,48.75 203.94,48.75 203.33,49.36 202.86,49.36 202.46,49.77 202.46,49.89 202.13,50.22 200.3,50.22 200.04,49.97 198.2,49.97 197.44,50.73 196.38,50.73 196.02,51.09 193.16,51.09 192.48,50.4 191.07,50.4 189.98,49.31 188.27,49.31 187.86,48.9 182.24,48.9 181.59,49.55 180.31,49.55 178.11,51.75 174.45,51.75 173.81,51.11 170.08,51.11 169.7,50.73 168.42,50.73 165.29,47.61 162.45,47.61 161.74,48.32 v3(161.87,48.32)
  IN4 w0.076: v4(161.31,48.44) 161.37,48.38 161.68,48.38 161.74,48.32 v3(161.87,48.32)
  BOTTOM w0.109: UCPU1.AG4 161.51,48.14 161.31,48.34 v4(161.31,48.44)
SUSACK#: length 43.2
  IN2 w0.102: v3(211.79,48.85) 211.72,48.93 206.29,48.93 205.48,49.74 205.48,50.66 205.02,51.11 204.18,51.11 203.84,51.46 203.13,51.46 202.89,51.7 202.89,52.15 202.46,52.59 201.28,52.59 201.08,52.38 196.82,52.38 196.59,52.15 190.05,52.15 188.98,51.09 185.4,51.09 185.2,50.88 183.85,50.88 183.2,50.24 182.2,50.24 181.97,50.47 181.57,50.47 v1(181.16,50.87)
  IN4 w0.076: v3(211.79,48.85) 212.1,49.16 v4(212.29,49.16)
  BOTTOM w0.109: RH430.2 179.5,46.92 179.98,47.4 180.77,47.4 181.05,47.69 181.05,50.76 v1(181.16,50.87) ; v4(212.29,49.16) 212.59,49.46 212.59,49.78 212.51,49.86
  BOTTOM w0.254: U34.M13 212.43,49.94 212.51,49.86
SUSACK#_R: length 17.7
  IN4 w0.076: v4(163.67,45.47) 163.98,45.47 164.14,45.31 164.55,45.31 164.67,45.44 167.45,45.44 168.66,46.64 170.55,46.64 171.27,47.37 175.3,47.37 175.66,47.73 175.66,47.86 175.74,47.94 175.82,47.94 v4(175.89,48.01)
  BOTTOM w0.109: v4(163.67,45.47) 163.39,45.47 163.16,45.7 163.16,46.25 UCPU1.AK2 ; v4(175.89,48.01) 175.89,47.41 RH430.1 175.58,46.12 RH429.1
SUSCLK: length 8.8
  TOP w0.109: v7(164.47,50.94) 164.75,50.94 MC102.2 165.52,50.16 166.31,50.16 166.35,50.2 RH132.2
  IN1 w0.076: v3(164.41,50.5) 164.46,50.55 164.46,50.92 v7(164.47,50.94)
  IN3 w0.102: v3(164.41,50.5) 164.31,50.5 163.44,49.64 161.59,49.64 161.36,49.41 161.36,49.18 161.13,48.95 160.81,48.95 160.3,48.45 v3(160.3,48.5)
  IN4 w0.076: v4(160.17,48.86) 160.17,48.83 160.18,48.83 160.3,48.7 v3(160.3,48.5)
SUSCLK_R: length 89.1
  TOP w0.109: R1255.2 R1256.2 228.58,52.35 226.52,52.35 226.26,52.6 v2(225.53,52.6) 224.76,52.6 224.11,51.95 224.11,50.05 223.35,49.28 223.35,48.09 223.91,47.53 v7(223.91,46.77) ; v7(167.51,51.19) 167.43,51.11 RH132.1
  IN1 w0.076: v7(167.51,51.19) 167.66,51.04 176.03,51.04 176.68,50.39 177.08,50.39 177.94,49.53 177.94,49.11 178.64,48.41 182.82,48.41 183.07,48.17 184.47,48.17 185.3,47.34 195.13,47.34 195.64,46.83 202.1,46.83 202.9,46.03 206,46.03 206.35,45.68 210.36,45.68 211.18,46.49 213.1,46.49 213.47,46.86 214.93,46.86 v3(215.08,46.71) 215.25,46.54 218.83,46.54 219.69,47.4 221.54,47.4 222.17,46.77 v7(223.91,46.77)
  IN3 w0.102: v1(212.02,59.81) 212.77,59.07 212.77,56.37 216.26,52.88 216.26,49.36 215.5,48.6 215.5,47.13 v3(215.08,46.71)
  BOTTOM w0.109: R253.1 212.16,59.68 v1(212.02,59.81)
SW_+1.2V:
  vias: v2(86.47,29.12) v6(83.98,30.41) v6(84.02,29.57) v6(84.75,30.39) v6(84.78,29.6) v6(85.57,30.41) v6(85.57,29.6) v6(88.03,30.36) v6(88.06,29.57) v6(88.77,30.34) v6(88.8,29.57) v6(89.7,30.32) v6(89.7,29.56) v6(93.66,32.75) v6(94.29,32.75)
SW_+1.05VS:
  vias: v2(194.44,64.27) v6(192.67,63.09) v6(192.65,62.44) v6(192.94,63.69) v6(193.3,63.09) v6(193.29,62.44) v6(193.62,63.74) v6(193.94,63.09) v6(193.92,62.44) v6(194.25,63.74) v6(194.93,63.76) v6(195.56,63.76)
SW_USB20_N0: length 2.7
  TOP w0.109: US2.11 25.23,46.78 25.09,46.92 v6(24.42,46.92) 24.01,46.92 23.68,46.59 ML52.4
SW_USB20_N1: length 8.1
  TOP w0.109: ML40.4 273.95,50.02 273.61,50.36 273.61,50.56 273.37,50.8 272.05,50.8 271.88,50.63 271.41,50.63 271.4,50.63 v6(268.79,50.63) 267.65,50.63 267.49,50.78 US1.11
SW_USB20_P0: length 2.7
  TOP w0.109: ML52.1 23.73,47.44 24.02,47.14 24.15,47.14 24.16,47.15 24.67,47.15 24.68,47.14 25.09,47.14 25.23,47.28 US2.10
SW_USB20_P1: length 7.7
  TOP w0.109: US1.10 267.52,50.28 267.64,50.4 268.52,50.4 268.53,50.39 269.05,50.39 269.06,50.4 v6(271.67,50.4) 271.96,50.4 272.14,50.58 273.27,50.58 273.39,50.47 273.39,50.36 273.1,50.07 ML40.1
SYS_PRS: length 7.5
  TOP w0.109: v1(59.47,8.05) 59.05,7.63 PR115.1 57.83,8.67 v5(57.83,8.82)
  BOTTOM w0.109: JBATT1.4 59.81,7.71 v1(59.47,8.05)
SYS_PWROK: length 101.3
  TOP w0.109: R1297.1 179.9,33.05 179.9,30.51 R1290.2 ; R1290.2 179.71,30.01 174,35.72 163.91,35.72 162.18,37.45 162.18,38.88 160.28,40.79 160.28,41.82 160.18,41.92 v7(160.17,41.92) 159.77,42.31 159.77,42.73 159.94,42.9 v5(159.94,43.25) 159.94,43.78 159.03,44.69 159.03,45.6 159.24,45.81 159.59,45.81 159.8,45.6 160.15,45.6 160.28,45.73 160.28,45.98 162.34,48.04 163.94,48.04 v1(163.95,48.03) ; R1290.2 R1294.2 182.06,29.27 185.88,29.27 R1292.2
  IN1 w0.076: v7(160.17,41.92) 160.14,41.89 158.9,41.89 158.18,42.6 157.17,42.6 156.28,43.49 156.28,44.08 152.6,47.76 151.02,47.76 150.31,48.47 149.35,48.47 148.79,49.03 138.83,49.03 137.13,47.33 132.79,47.33 131.67,48.45 130.83,48.45 130.45,48.07 130.07,48.07 127.27,50.86 124.05,50.86 v3(123.46,51.44)
  IN4 w0.076: v4(123.54,52.05) 123.54,51.52 v3(123.46,51.44)
  BOTTOM w0.102: UCPU1.AG2 163.1,47.81 163.72,47.81 v1(163.95,48.03)
  BOTTOM w0.109: v1(163.95,48.03) 164.92,48.03 165.93,47.02 166.44,47.02 RH272.1 ; v4(123.54,52.05) 121.04,52.05 120.97,51.99 118.17,51.99 117.62,51.44 R1309.1
SYS_PWROK_XDP: length 19.9
  TOP w0.109: v1(116.05,61.27) v2(116.05,62.31) 116.05,63.79 115.57,64.26 JXDP.47
  IN4 w0.076: v4(116.1,52.89) 117.23,52.89 119.25,54.91 119.25,58.81 117.01,61.04 116.27,61.04 v1(116.05,61.27)
  BOTTOM w0.109: C1282.1 R1309.2 R1311.1 116.47,52.52 v4(116.1,52.89)
SYS_RESET#: length 11.6
  TOP w0.109: RH450.1 166.63,48.12 165.59,48.12 RH467.1 164.68,47.21 v2(163.82,47.21) 162.8,47.21 v7(162.78,47.23)
  IN1 w0.076: v7(162.78,47.23) 162.78,47.28 162.71,47.35 161.49,47.35 160.85,47.99 v3(160.6,47.99)
  IN4 w0.076: v3(160.6,47.99) 160.78,48.17 v4(160.78,48.4)
  BOTTOM w0.102: v4(160.78,48.4) 161.13,48.75 161.13,49.03 160.47,49.69 160.47,49.92 160.64,50.09 160.79,50.09 160.9,50.2 161.22,50.2 161.39,50.03 161.67,50.03 161.95,50.31 UCPU1.AC3
SYSTEM_FAN_FB: length 222.6
  TOP w0.109: R884.1 47.24,3.81 46.22,4.82 D81.2 46.22,6.69 46.45,6.92 47.71,6.92 48.18,7.39 v7(49.75,7.39) v2(50.26,7.39)
  IN1 w0.076: v3(214.06,41.79) 214.04,41.82 211.98,41.82 211.85,41.94 209.63,41.94 209.3,41.61 206.97,41.61 205.4,40.04 202.65,40.04 197.99,35.38 197.99,12.35 194.66,9.02 193.47,9.02 190.58,6.13 181.08,6.13 180.31,5.36 155.46,5.36 152.71,8.11 143.97,8.11 141.48,5.62 129.02,5.62 128.3,4.9 119.81,4.9 118.88,5.82 110.29,5.82 108.54,7.58 105.33,7.58 103.34,9.56 101.89,9.56 100.39,11.06 94.7,11.06 91.91,8.28 72.24,8.28 71.5,7.54 67.35,7.54 66.83,7.02 65.1,7.02 63.7,8.43 60.45,8.43 59.56,7.54 57.53,7.54 56.6,8.47 50.83,8.47 v7(49.75,7.39)
  IN4 w0.076: v3(214.06,41.79) 213.87,41.98 213.87,43.65 214.81,44.59 215.1,44.59 215.61,45.1 215.61,45.26 216.29,45.93 216.29,47.53 v4(215.74,48.08)
  BOTTOM w0.076: 213.04,50.69 212.61,50.69 212.54,50.76
  BOTTOM w0.109: 213.04,50.69 213.63,50.1 213.63,49.89 214.09,49.44 214.44,49.44 214.7,49.18 214.7,48.1 214.81,47.98 215.65,47.98 v4(215.74,48.08)
  BOTTOM w0.254: U34.M11 212.54,50.76
SYSTEM_FAN_PWM: length 219.1
  IN1 w0.076: v1(48.98,2.8) 55.56,2.8 56.76,1.6 102.6,1.6 105.25,4.25 107.64,4.25 108.72,3.17 109.87,3.17 110.69,4 113.31,4 114.08,3.23 141.45,3.23 144.66,6.43 148.89,6.43 152.09,3.23 182.3,3.23 183.07,4 191.52,4 194.29,6.76 195.48,6.76 200.96,12.24 200.96,29.37 201.92,30.34 201.92,33.93 205.75,37.76 207.19,37.76 v3(207.36,37.93)
  IN3 w0.102: v3(214.13,50.45) 214.12,50.44 214.12,49.94 213.7,49.53 213.7,47.69 211.91,45.9 211.91,43.81 211.5,43.41 211.5,42.55 210.53,41.59 210.53,40.57 208.98,39.02 208.98,37.85 208.49,37.36 207.68,37.36 207.36,37.68 v3(207.36,37.93)
  IN4 w0.076: v4(214,50.01) 214,50.32 v3(214.13,50.45)
  BOTTOM w0.109: JFAN1.6 44.9,2.63 45.1,2.83 46.4,2.83 ; 46.4,2.83 JFAN1.3 ; 46.4,2.83 46.4,3.62 46.55,3.77 48.69,3.77 49.04,4.12 49.78,4.12 R1103.1 49.71,3.9 49.62,3.9 48.98,3.26 v1(48.98,2.8) ; U34.N10 212.93,51.37 213.46,51.37 213.66,51.18 213.66,50.63 214,50.29 v4(214,50.01)
TABLET_MODE: length 249.4
  IN4 w0.076: v4(207.73,52.92) 206.85,52.92 205.58,51.65 205.58,50.53 205.76,50.35 205.76,48.45 203.63,46.31 203.63,42.73 202.3,41.41 202.3,38.26 197.68,33.64 197.68,31.23 197.07,30.62 197.07,26.49 196.72,26.13 196.72,22.71 195.78,21.77 195.78,15.05 193.99,13.26 193.99,12.77 189.94,8.72 178.82,8.72 178.66,8.89 174.73,8.89 174.6,8.75 171.74,8.75 170.99,8 156.74,8 156.03,8.72 154.17,8.72 151.21,11.68 142.33,11.68 140.38,9.73 125.38,9.73 124.98,9.33 119.58,9.33 119.21,8.96 112.21,8.96 108.17,4.92 104.86,4.92 104.64,4.71 101.23,4.71 100.91,4.39 96.55,4.39 96.23,4.07 94.2,4.07 93.92,3.79 91.28,3.79 90.39,2.9 75.21,2.9 72.14,5.97 72.14,7.07 71.87,7.34 67.9,7.34 67.79,7.22 64.9,7.22 64.33,6.65 50.15,6.65 49.22,5.72 43.9,5.72 43.61,6.02 41.22,6.02 39.63,7.61 39.63,8.4 38.86,9.18 38.46,9.18 37.99,9.65 37.99,9.81 33.52,14.28 33.52,18.8 32.8,19.52 32.8,20.84 29.71,23.93 29.71,28.25 v4(29.33,28.63)
  BOTTOM w0.109: Q107.2 23.3,23.79 RA42.1 v2(23.62,25.66) 23.62,26.75 24.21,27.35 26.9,27.35 27.16,27.61 27.16,28.8 27.34,28.98 27.93,28.98 28.28,28.63 v4(29.33,28.63) ; v4(207.73,52.92) 207.38,52.92 U34.B7
TABLET_MODE_R: length 1.7
  TOP w0.109: T283.1 43.34,11.48 42.77,11.48 42.63,11.34 UA1.7
TD_IREF: length 6.2
  BOTTOM w0.102: UCPU1.B12 155.72,62.44 155.72,62.97
  BOTTOM w0.109: 155.72,62.97 155.24,63.46
  BOTTOM w0.381: RC155.1 154.76,66.91 154.2,66.35 154.2,65.83 v2(153.96,65.59) 153.96,64.74 155.24,63.46
TESTLOW1: length 12.5
  BOTTOM w0.109: UCPU1.C35 142.6,61.69 142.26,62.04 142.26,63.25 142.1,63.41 142.1,64.04 141.78,64.36 141.59,64.36 141.43,64.51 141.43,64.96 141.59,65.11 141.59,65.57 142.19,66.17 143.53,66.17 144.72,67.36 147,67.36 RH76.1 147.68,68.04 v2(147.68,68.7)
TESTLOW2: length 11.3
  BOTTOM w0.109: RH77.1 147.08,67.02 144.72,67.02 143.63,65.93 142.28,65.93 141.9,65.55 141.9,65.01 141.79,64.89 v2(141.79,64.8) 142.33,64.26 142.33,63.51 143.05,62.8 143.05,62.19 142.82,61.97 142.82,61.75 143.17,61.41 UCPU1.C34
TESTLOW3: length 19.5
  IN4 w0.076: v4(160.5,49.16) 160.52,49.16 160.63,49.05 161.14,49.05 161.33,49.24 161.33,49.37 161.63,49.67 163.61,49.67 164.05,50.11 165.44,50.11 167.16,51.82 168.81,51.82 169.45,52.46 v4(171.6,52.46)
  BOTTOM w0.109: RH78.1 174.19,52.43 173.65,51.9 172.21,51.9 171.65,52.46 v4(171.6,52.46) ; v4(160.5,49.16) 160.04,49.16 159.89,49 159.89,48.29 159.81,48.22 159.81,47.79 159.61,47.58 159.35,47.58 159.15,47.38 159.15,47.12 159.16,47.11 UCPU1.AK8
TESTLOW4: length 8.8
  TOP w0.109: RH79.1 163.88,48.52 162.03,48.52 v2(161.22,47.71) 159.88,46.37 v7(159.88,45.96)
  IN1 w0.076: v7(159.88,45.96) 159.94,45.96 v3(160.18,46.2)
  IN4 w0.076: v4(160.14,45.82) 160.14,46.16 v3(160.18,46.2)
  BOTTOM w0.109: UCPU1.AL8 160.03,45.71 v4(160.14,45.82)
TP_CLK: length 79.5
  TOP w0.109: DE1.2 196.42,11.59 195.81,10.98 v2(195.33,10.98) 195.14,10.98 194.95,11.17 194.95,12.72 v7(194.84,12.84)
  IN1 w0.076: v3(194.4,13.11) 194.68,12.84 v7(194.84,12.84)
  IN3 w0.102: v1(175.56,8.38) 175.71,8.53 175.71,8.86 176.04,9.19 189.64,9.19 193.56,13.11 v3(194.4,13.11) 194.29,13.23 194.29,13.71 194.81,14.23 195.76,14.23 196.82,15.29 196.82,26.12 197.99,27.29 197.99,34.11 202.63,38.76 202.63,41.23 203.7,42.3 203.7,47.21 203.14,47.77 203.14,48.81 202.46,49.49 202.46,51.09 v3(202.18,51.37)
  IN4 w0.076: v4(202.61,51.54) 202.41,51.54 202.23,51.37 v3(202.18,51.37)
  BOTTOM w0.102: 203.17,52.63 203.53,52.99 205.3,52.99 206.17,53.86 206.37,53.86 206.46,53.94 U34.A5
  BOTTOM w0.109: R979.2 202.3,51.24 v4(202.61,51.54) 202.66,51.54 203.07,51.95 203.07,52.53 203.17,52.63 ; JTP1.5 175.65,9.51 175.71,9.44 175.71,8.53 v1(175.56,8.38)
TP_DATA: length 78.9
  TOP w0.102: v7(195.26,13.29) v2(194.3,13.29)
  TOP w0.109: v7(195.26,13.29) 195.48,13.52 DE1.3
  IN1 w0.076: v3(194.84,13.55) 195.09,13.29 v7(195.26,13.29)
  IN3 w0.102: v3(202.18,51.95) 202.69,51.44 202.69,49.59 203.37,48.9 203.37,47.86 203.93,47.3 203.93,42.15 202.94,41.16 202.94,38.74 198.21,34.02 198.21,27.19 197.05,26.02 197.05,15.09 195.89,13.93 195.22,13.93 v3(194.84,13.55) 194.91,13.47 194.91,13.04 194.26,12.39 193.52,12.39 190.09,8.96 176.14,8.96 175.94,8.76 175.94,8.61 v1(176.17,8.38)
  IN4 w0.076: v3(202.18,51.95) v4(202.18,52.36)
  BOTTOM w0.076: 206.44,54.19 207.11,54.19 U34.B5
  BOTTOM w0.102: 206.44,54.19 206.29,54.03 206.09,54.03 205.38,53.32 203.37,53.32 202.67,52.62
  BOTTOM w0.109: 202.67,52.62 202.41,52.36 v4(202.18,52.36) 201.95,52.13 R978.2 ; v1(176.17,8.38) 175.95,8.6 175.95,9.29 176.15,9.5 JTP1.4
TP_EN: length 92.4
  TOP w0.109: v2(232.71,45.36) 232.71,46.25 R1174.1 233.86,47.4 v1(233.9,47.4) 234.02,47.52 U718.5
  IN2 w0.102: v3(161,56.09) 160.8,56.29 160.8,57.01 161.05,57.26 161.92,57.26 162.43,57.77 162.43,58.15 163.16,58.89 163.56,58.89 164.39,59.72 168.71,59.72 169.44,58.99 173.85,58.99 175.25,60.39 175.25,60.83 176.51,62.09 180.36,62.09 183.83,65.55 198.23,65.55 201.29,62.49 201.75,62.49 204.31,59.93 204.31,59.78 205.52,58.57 215.94,58.57 218.47,56.03 221.48,56.03 221.93,55.58 223.5,55.58 226.09,52.99 227.17,52.99 229.23,50.94 231.06,50.94 231.45,50.54 231.45,48.41 232.45,47.4 v1(233.9,47.4)
  IN4 w0.076: v3(161,56.09) 160.6,56.09 v4(160.55,56.04)
  BOTTOM w0.109: v4(160.55,56.04) 160.45,56.04 160.17,55.76 UCPU1.N6
TP_INT#: length 89.9
  IN1 w0.076: v3(159.07,52.64) 158.98,52.55 158.98,52.22 158.58,51.81 158.58,51.15 158.97,50.76 158.97,50.5 159.24,50.24 159.24,49.85 159.62,49.47 159.87,49.47 160.55,49.47 161.52,48.5 161.52,48.18 161.73,47.98 163.2,47.98 163.49,47.68 164.15,47.68 164.28,47.81 165.04,47.81 166.14,46.71 166.84,46.71 167.28,46.26 174.57,46.26 175.42,45.41 177.08,45.41 177.56,45.89 178.21,45.89 178.63,45.47 178.63,38.39 179.9,37.12 188.23,37.12 189.3,36.05 191.3,36.05 191.81,35.53 191.81,34.6 192.64,33.77 192.64,33.33 194.61,31.36 194.61,29.85 195.93,28.53 195.93,27.44 197.17,26.2 197.17,13.52 196.07,12.41 196.07,11.9 194.93,10.77 194.93,10.62 v1(195.16,10.39)
  IN4 w0.076: v4(159.25,52.99) 159.07,52.81 v3(159.07,52.64)
  BOTTOM w0.102: 159.86,54.44 159.86,54.8 160.47,55.41 160.47,55.57 160.89,55.99 161.61,55.99 161.84,56.22 161.84,56.45
  BOTTOM w0.109: v4(159.25,52.99) 159.52,53.26 UCPU1.U7 159.52,53.62 159.71,53.81 159.71,54.29 159.86,54.44 ; v1(195.16,10.39) 195.39,10.39 R1387.1 197.16,8.62 Q364.1 ; 161.84,56.45 162.04,56.64 163.47,56.64 164.81,57.98 164.81,58.13 165.11,58.44 165.26,58.44 v2(165.55,58.73) 166.18,58.73 RH380.2
TP_INT#_R: length 35.6
  BOTTOM w0.109: Q364.3 198.85,7.97 198.73,8.09 R1300.2 195.81,9.01 R1387.2 v2(194.74,9.05) 194.58,8.89 194.58,8.09 194.81,7.86 194.81,5.55 193.42,4.15 175.49,4.15 174.15,5.5 JTP1.8
TPM_DET: length 22
  IN4 w0.076: v4(175.14,53.31) 173.97,52.14 169.42,52.14 168.9,51.62 167.24,51.62 165.53,49.91 164.06,49.91 163.67,49.51 161.69,49.51 161.48,49.3 161.48,49.18 161.13,48.83 161.13,48.64 161.05,48.55 161.05,47.79 v4(160.8,47.54)
  BOTTOM w0.109: v4(160.8,47.54) 160.8,47.61 160.82,47.63 UCPU1.AG5 ; RH274.2 172.48,51.29 RH337.1 173.42,51.29 174.06,51.93 174.85,51.93 175.22,52.29 v2(175.22,52.36) 175.22,53.23 v4(175.14,53.31)
TPM_IRQ#: length 10.2
  BOTTOM w0.102: UCPU1.P4 161.72,54.81 162.04,55.12 163.77,55.12
  BOTTOM w0.109: 163.77,55.12 164.32,55.12 165.19,55.99 165.93,55.99 166.12,55.8 166.12,55.35 166.25,55.23 168.52,55.23 168.95,54.8 169.81,54.8 RH463.2
TPM_RESET#: length 8.7
  TOP w0.109: U698.4 206.75,42.13 R1310.1 206.7,41.45 v1(205.91,41.45) 206.06,41.3 206.06,40.47 v2(205.87,40.28)
  BOTTOM w0.109: v1(205.91,41.45) 206.14,41.68 206.14,43.34 205.27,44.21 U652.16
TPM_RST#: length 57.4
  TOP w0.109: U698.2 204.59,42.78 204.91,43.1 204.91,43.96 v7(205.05,44.1) v2(204.45,44.7)
  IN1 w0.076: v7(205.05,44.1) 205.02,44.13 204.74,44.13 v3(204.65,44.22)
  IN2 w0.102: v3(204.65,44.22) 204.42,44.22 202.07,46.57 198.91,46.57 198.49,46.99 192.73,46.99 191.65,45.91 180.19,45.91 178.76,47.34 176.29,47.34 175.39,46.44 169.44,46.44 166.85,43.85 162.48,43.85 162.22,43.59 160.78,43.59 160.47,43.9 159.86,43.9 159.56,44.2 159.56,45.37 159.71,45.53 159.71,46.54 160.04,46.87 v3(160.04,47.99)
  IN4 w0.076: v3(160.04,47.99) 160.06,47.99 160.06,47.79 160.27,47.58 160.28,47.58 v4(160.3,47.57)
  BOTTOM w0.109: UCPU1.AG6 160.17,47.69 v4(160.3,47.57)
TRIP: length 1.9
  TOP w0.203: PU501.20 196.82,58.43 PR508.2
TS_EN: length 33.7
  TOP w0.109: U719.5 171.69,68.13 171.81,68.26 v7(172.74,68.26)
  IN1 w0.076: v3(173.01,67.95) 173.01,67.99 v7(172.74,68.26)
  IN2 w0.102: v3(173.01,67.95) 172.98,67.95 172.55,68.39 169.82,68.39 169.77,68.44 167.2,68.44 166.06,67.29 163.92,67.29 163.7,67.06 159.18,67.06 158.84,67.39 158.06,67.39 157.42,66.76 157.42,65.44 156.64,64.65 156.64,58.71 156.2,58.28 156.2,57.82 157.52,56.5 159.68,56.5 v3(160.06,56.12)
  IN4 w0.076: v4(159.68,56.09) 160.09,56.09 160.11,56.12 v3(160.06,56.12)
  BOTTOM w0.109: UCPU1.N7 159.68,55.68 v4(159.68,56.09)
TS_INT#: length 19.6
  TOP w0.109: v7(174.35,55.71) 174.17,55.89 RH384.1 174.55,56.29 174.94,55.91 R1384.1 175.6,55.91 v2(176.11,56.43) 177.03,57.35 Q363.1
  IN1 w0.076: v3(173.93,55.71) 173.96,55.69 174.33,55.69 v7(174.35,55.71)
  IN4 w0.076: v4(162.16,54.81) 162.16,54.96 162.5,55.3 164.26,55.3 165.28,56.33 167.09,56.33 167.45,56.69 168.41,56.69 169.02,56.08 170.85,56.08 171.1,55.82 173.82,55.82 v3(173.93,55.71)
TS_INT#_R: length 54.9
  TOP w0.109: Q363.3 176.38,58.39 v2(176.22,58.22) 175.69,57.69 R1385.2 175.06,57.55 R1384.2 v7(175.55,56.83) ; R1157.1 140.9,66.53 140.56,66.19 v7(140.56,66.15)
  IN1 w0.076: v3(175.94,56.74) 175.85,56.83 v7(175.55,56.83) ; v3(140.94,66.15) v7(140.56,66.15)
  IN2 w0.102: v3(140.94,66.15) 140.94,65.57 143.17,63.33 154.45,63.33 155.47,62.31 155.47,61.58 154.81,60.92 154.81,57.01 155.95,55.86 156.38,55.86 158.62,53.63 159.53,53.63 159.96,54.06 160.39,54.06 160.62,54.28 161.16,54.28 161.37,54.5 161.63,54.5 161.97,54.16 161.97,53.91 162.32,53.55 162.83,53.55 163.57,52.81 166.08,52.81 166.74,53.47 167.24,53.47 167.76,54 168.87,54 169.97,55.1 169.97,55.91 170.2,56.14 175.34,56.14 v3(175.94,56.74)
TS_RST#: length 36.6
  TOP w0.109: v2(143.49,69.71) 143.23,69.44 142.59,69.44 R1376.1 ; R1376.1 142.45,68.33 142.45,67.24 v7(142.4,67.19) ; R1376.1 R1227.1
  IN1 w0.076: v3(142,67.22) 142.37,67.22 v7(142.4,67.19)
  IN2 w0.102: v3(159.66,55.61) 159.58,55.69 157.7,55.69 156.84,56.55 156.2,56.55 155.95,56.8 155.95,58.35 156.43,58.83 156.43,62.62 154.45,64.6 143.73,64.6 142,66.33 v3(142,67.22)
  IN4 w0.076: v4(163.46,56.34) 163.41,56.34 162.71,55.63 162.43,55.63 162.12,55.33 161.31,55.33 160.98,55.66 160.67,55.66 160.51,55.5 159.77,55.5 v3(159.66,55.61)
TS_RST#_R: length 5.4
  TOP w0.109: R1157.2 141.94,67.04 v7(141.08,67.9) 140.45,67.27 140.45,67.13 v2(140.15,66.84)
  IN1 w0.076: v3(141.42,67.24) 141.42,67.27 141.08,67.61 v7(141.08,67.9)
  IN4 w0.076: v4(141.65,67.71) 141.65,67.47 v3(141.42,67.24)
  BOTTOM w0.109: JLVDS2.49 v4(141.65,67.71)
UART1_CTS#: length 92.8
  TOP w0.109: U671.10 234.76,67.25 231.34,63.82 231.34,61.48 227.81,57.95 223.91,57.95 v2(223.48,57.51) 221.98,57.51 221.41,58.09 v7(221.41,58.2)
  IN1 w0.076: v3(164.36,59.1) 164.36,59.09 164.64,59.37 165.72,59.37 167.58,57.51 168.38,57.51 169.31,56.58 174.75,56.58 175.28,56.05 177.69,56.05 178.07,55.67 180.51,55.67 181.01,55.18 182.74,55.18 183.18,54.74 183.18,54.49 183.6,54.07 188.6,54.07 188.84,53.83 189.9,53.83 190.16,53.56 193.82,53.56 193.98,53.73 196.5,53.73 197,54.24 199.21,54.24 199.67,54.69 200.18,54.69 200.81,55.33 202.76,55.33 205.35,57.92 212.52,57.92 213.2,57.23 213.99,57.23 214.83,56.4 215.93,56.4 216.41,56.88 218.03,56.88 218.43,57.29 220.49,57.29 v7(221.41,58.2)
  IN4 w0.076: v3(164.36,59.1) 164.38,59.13 164.38,59.5 v4(164.41,59.52)
  BOTTOM w0.102: UCPU1.J4 161.51,57.82 162,58.31 163.58,58.31 164.22,58.95
  BOTTOM w0.109: 164.22,58.95 164.22,59.33 v4(164.41,59.52) 165.98,61.1 165.98,62.59 166.44,63.05 166.44,63.94 RH460.1
UART1_CTS#_NGFF: length 15.2
  TOP w0.109: U671.5 234.76,60.73 230.17,56.13 228.47,56.13 v2(228.1,55.76) 227.54,55.2 v1(226.45,55.2) 226.17,55.48 R1371.2
  BOTTOM w0.109: v1(226.45,55.2) 225.98,54.74 JNGFF1.26
UART1_RTS#: length 88.4
  TOP w0.109: U671.11 234.11,66.93 231.1,63.92 231.1,61.57 227.81,58.28 v2(226.37,58.28) 222.57,58.28 v7(222.15,57.87)
  IN1 w0.076: v3(164.94,58.97) 164.95,58.96 164.95,58.94 165.31,58.58 165.86,58.58 167.33,57.11 168.21,57.11 169.14,56.17 174.58,56.17 175.11,55.65 177.52,55.65 177.9,55.26 180.25,55.26 180.74,54.77 182.57,54.77 182.77,54.57 182.77,54.33 183.43,53.67 186.97,53.67 187.59,53.04 193.87,53.04 194.15,53.32 196.66,53.32 197.17,53.83 199.38,53.83 199.84,54.29 200.35,54.29 200.98,54.92 202.93,54.92 204.56,56.56 206.08,56.56 206.95,57.44 212.35,57.44 212.64,57.15 212.64,56.73 213.65,55.72 214.76,55.72 215.03,55.99 216.1,55.99 216.58,56.47 218.19,56.47 218.6,56.88 221.16,56.88 v7(222.15,57.87)
  IN4 w0.076: v4(165.07,59.5) 165.07,59.1 v3(164.94,58.97)
  BOTTOM w0.109: UCPU1.J3 162.49,58.13 163.75,58.13 164.66,59.04 164.66,59.09 v4(165.07,59.5) RH459.1
UART1_RTS#_NGFF: length 21.4
  TOP w0.109: R1370.2 226.22,54.59 v1(226.45,54.36) 226.78,54.69 227.56,54.69 228.61,55.74 231.4,55.74 v2(233.93,58.26) 236.78,61.12 236.78,62.92 236.23,63.48 234.37,63.48 234.11,63.23 U671.4
  BOTTOM w0.109: JNGFF1.28 226.32,54.24 v1(226.45,54.36)
UART1_RXD: length 87.6
  TOP w0.109: U671.12 233.46,67.35 230.86,64.75 230.86,61.67 227.81,58.62 v2(224.26,58.62) 222.28,58.62 v7(221.86,58.2)
  IN1 w0.076: v3(165.54,58.97) 165.77,58.97 167.43,57.31 168.3,57.31 169.23,56.38 174.66,56.38 175.19,55.85 177.61,55.85 177.99,55.47 180.39,55.47 180.88,54.97 182.65,54.97 182.97,54.65 182.97,54.41 183.52,53.87 188.51,53.87 188.76,53.63 189.81,53.63 190.08,53.36 193.9,53.36 194.07,53.53 196.58,53.53 197.09,54.03 199.3,54.03 199.76,54.49 200.26,54.49 200.9,55.13 202.84,55.13 205.43,57.72 212.39,57.72 212.97,57.13 212.97,56.7 213.75,55.93 214.68,55.93 214.95,56.19 216.01,56.19 216.49,56.68 218.11,56.68 218.52,57.08 220.74,57.08 v7(221.86,58.2)
  IN4 w0.076: v4(165.72,59.48) 165.54,59.3 v3(165.54,58.97)
  BOTTOM w0.102: 163.62,57.56 162.31,57.56 162.16,57.41 161.79,57.41 UCPU1.K4
  BOTTOM w0.109: RH457.1 166.35,60.12 v4(165.72,59.48) 165.44,59.2 165.26,59.2 165.16,59.1 165.08,59.1 164.34,58.36 164.34,58.29 163.62,57.56
UART1_RXD_NGFF: length 15.3
  TOP w0.109: U671.3 233.46,63.25 233.2,63.51 232,63.51 231.57,63.08 231.57,61.38 v2(227.71,57.51) 225.94,57.51 R1369.2 226.13,56.82 v1(226.38,56.82)
  BOTTOM w0.109: v1(226.38,56.82) 225.46,57.74 JNGFF1.22
UART1_TXD: length 89.6
  TOP w0.109: U671.13 232.81,67.36 230.61,65.16 230.61,61.76 227.81,58.95 v2(222.61,58.95) 222,58.95 v7(221.63,58.58)
  IN1 w0.076: v3(163.67,59.53) 163.77,59.63 164.46,59.63 164.51,59.58 165.8,59.58 167.67,57.72 168.47,57.72 169.4,56.78 174.83,56.78 175.36,56.26 177.79,56.26 178.17,55.87 180.6,55.87 181.1,55.38 183.68,55.38 184.2,54.86 185.13,54.86 185.18,54.81 188.98,54.81 189.38,54.4 192.93,54.4 193.31,54.03 196.51,54.03 196.92,54.44 199.13,54.44 199.59,54.9 200.1,54.9 200.73,55.53 202.67,55.53 205.26,58.12 212.65,58.12 213.09,57.69 214.47,57.69 214.93,58.15 217.43,58.15 218.09,57.49 220.19,57.49 221.28,58.58 v7(221.63,58.58)
  IN4 w0.076: v4(163.85,59.14) 163.85,59.36 v3(163.67,59.53)
  BOTTOM w0.109: UCPU1.G2 163.03,58.59 163.31,58.87 163.58,58.87 v4(163.85,59.14) 163.87,59.16 163.87,59.39 165.58,61.1 165.58,63.25 166.03,63.71 166.03,64.42 RH458.1
UART1_TXD_NGFF: length 15.5
  TOP w0.109: v1(226.45,55.81) 226.24,55.81 R1368.2 227.82,56.37 228.05,56.6 v2(229.75,56.6) 230.3,56.6 233.74,60.03 233.74,60.36 233.74,60.37 233.74,61.1 233.42,61.42 233.15,61.42 232.81,61.76 U671.2
  BOTTOM w0.109: JNGFF1.24 225.87,55.24 v1(226.45,55.81)
UART_WAKE#: length 89.4
  TOP w0.109: RH383.1 175.95,50.37 v1(176.04,50.46) 176.57,50.46 T288.1
  IN2 w0.102: v3(224.66,44.77) 224.5,44.77 223.28,46 221.23,46 220.28,45.04 218.71,45.04 218.33,45.42 214.59,45.42 213.87,44.7 213.35,44.7 212.07,45.98 210.06,45.98 208.9,47.15 204.16,47.15 202.87,48.45 200.64,48.45 199.57,49.51 195.39,49.51 194.73,50.17 193.91,50.17 193.37,49.63 192.67,49.63 190.83,47.79 185.72,47.79 185.06,48.45 182.05,48.45 181.4,49.09 179.62,49.09 178.26,50.46 v1(176.04,50.46) 175.84,50.66 170.27,50.66 169.89,50.27 168.61,50.27 165.23,46.9 163.92,46.9 162.48,45.45 162.45,45.45 162.45,45.44 v3(162.46,45.44)
  IN4 w0.076: v4(162.16,45.14) 162.17,45.14 162.48,45.45 162.45,45.45 162.45,45.44 v3(162.46,45.44) ; v4(222.9,55.04) 224.06,53.88 224.06,52.14 222.13,50.21 222.13,48.24 223.78,46.59 223.78,45.63 224.64,44.77 v3(224.66,44.77)
  BOTTOM w0.109: JNGFF1.20 223.65,58.24 223.08,57.67 223.08,55.21 v4(222.9,55.04)
UG_3V:
  vias: v2(193.92,36.79) v6(192.79,36.53) v6(193.43,36.53) v6(196.57,43.14) v6(196.57,42.5)
UG_5V:
  vias: v2(183.34,40.09)
USB0_CTL1: length 70.1
  TOP w0.109: v1(255.21,42.99) 255.21,44.25 256.53,45.56 257.96,45.56 v2(258.4,45.12) 259.22,44.3 264.61,44.3 265.49,45.17 265.49,45.67 R1166.2
  IN2 w0.102: v3(206.89,54.91) 207.03,54.77 209.06,54.77 209.29,54.54 209.29,53.93 210.18,53.04 214.85,53.04 217.34,50.55 220.41,50.55 223.3,47.66 226.2,47.66 227.08,46.78 228.07,46.78 232.6,42.25 250.27,42.25 251.56,43.54 254.65,43.54 v1(255.21,42.99)
  IN4 w0.076: v3(206.89,54.91) 206.71,54.91 v4(206.52,54.72)
  BOTTOM w0.076: v4(206.52,54.72) 206.55,54.69 207.11,54.69 U34.B4
USB0_DET#: length 259.6
  TOP w0.109: v7(201.19,48.89) 201.33,48.75 202.22,48.75 202.65,49.19 202.65,50.12 203.64,51.1 203.64,52.71 203.46,52.89 v2(203.46,55.13) 204.26,55.93 D83.1
  IN1 w0.076: v7(201.19,48.89) 200.82,48.89 v3(200.81,48.88)
  IN3 w0.102: v3(200.81,48.88) 200.81,47.99 202.63,46.16 202.63,43.33 201.31,42.01 201.31,39.22 196.87,34.78 196.87,33.34 195.74,32.21 195.74,27.5 194.7,26.46 194.7,16.12 191.97,13.39 191.01,13.39 190.1,12.48 190.1,11.86 189.72,11.49 186.21,11.49 185.04,10.32 181.67,10.32 180.87,11.12 179.34,11.12 178.58,10.36 175.7,10.36 174.85,9.51 172.09,9.51 170.46,7.88 160.24,7.88 157.57,10.54 151.41,10.54 150.32,11.63 138.19,11.63 137.18,10.62 127.58,10.62 125.99,9.03 109.85,9.03 107.9,10.98 95.29,10.98 92.75,8.44 74.5,8.44 73.28,9.66 71.43,9.66 70.31,10.78 66.36,10.78 65.88,11.26 54.52,11.26 53.96,10.71 50.46,10.71 49.6,11.57 49.6,12.04 47.56,14.08 46.77,14.08 45.95,14.91 44.34,14.91 41.83,17.42 41.07,17.42 35.82,22.67 35.82,24.55 34.49,25.89 34.49,27.93 31.9,30.51 29.86,30.51 28.64,31.73 26.97,31.73 26.21,32.49 26.21,37.69 21.62,42.28 JUSB2.10
USB0_DET_EC#: length 7.9
  TOP w0.109: D83.3 204.02,58.22 204.6,58.81 v2(205.67,58.81) 207.37,57.11 207.92,57.11 v1(208.04,56.98)
  BOTTOM w0.076: v1(208.04,56.98) 208.04,56.65 208.32,56.37 208.32,55.98 U34.D1
  BOTTOM w0.109: R935.1 207.97,57.06 v1(208.04,56.98)
USB0_EN: length 11.9
  TOP w0.109: v2(30.03,49.87) 29.7,50.2 R1217.2
  TOP w0.254: v1(28.7,48.42) 28.89,48.61 R1217.2 27.99,49.31 US2.5
  IN3 w0.254: v1(28.7,48.42) 28.7,51.2 27.37,52.52 v1(27.37,53.93)
  BOTTOM w0.457: U700.4 27.37,53.36 v1(27.37,53.93)
USB0_PWR_EN: length 261.8
  TOP w0.109: v1(167.25,40.72) 166.44,40.72 165.97,41.19 165.77,41.19 v2(165.6,41.37) 164.1,42.86 v1(164.1,42.81)
  IN3 w0.102: v1(28.21,54.36) 29.2,53.37 29.2,48.1 28.59,47.49 28.59,39.23 30.02,37.8 30.02,34.41 33.45,30.98 33.45,29.29 34.72,28.02 34.72,25.99 36.05,24.65 36.05,22.76 41.16,17.65 41.92,17.65 44.39,15.18 45.99,15.18 46.87,14.31 47.65,14.31 48.77,13.19 50.5,13.19 52.03,11.67 53.43,11.67 53.61,11.49 65.97,11.49 66.45,11.01 70.4,11.01 71.52,9.89 73.37,9.89 74.59,8.67 92.65,8.67 95.19,11.21 108.04,11.21 109.98,9.28 125.92,9.28 127.49,10.85 137.09,10.85 138.1,11.86 150.42,11.86 151.5,10.77 157.67,10.77 160.33,8.11 170.37,8.11 171.99,9.74 174.75,9.74 175.6,10.59 178.48,10.59 179.25,11.35 180.96,11.35 181.77,10.55 184.83,10.55 188.49,14.21 191.69,14.21 193.16,15.68 193.16,21.59 192.08,22.67 192.08,26.28 v3(192.3,26.5)
  IN4 w0.076: v3(192.3,26.5) 192.3,27.89 188.28,31.91 185.56,31.91 184.82,32.65 184.82,33.6 185.21,33.99 185.21,35.05 184.87,35.39 180.68,35.39 177.13,38.93 v4(176.29,38.93)
  BOTTOM w0.102: v1(164.1,42.81) 163.78,43.13 162.48,43.13 UCPU1.AT3
  BOTTOM w0.109: v1(167.25,40.72) 167.62,40.36 167.62,39.53 169.93,37.21 170.82,37.21 170.96,37.07 172.35,37.07 RH400.1 173.93,37.52 175.43,37.52 176.27,38.36 176.27,38.91 v4(176.29,38.93) ; v1(28.21,54.36) 28.46,54.61 U700.1
USB0_PWR_EN_EC: length 301.3
  TOP w0.109: RP22.2 206,52.18 v7(205.68,52.5)
  IN1 w0.076: v1(29.89,54.44) 30.37,53.96 30.37,51.57 29.78,50.98 29.78,48.84 30.17,48.46 30.17,43.9 33.01,41.05 33.01,32.05 33.88,31.18 33.88,29.92 34.36,29.44 34.36,25.86 35.79,24.43 35.79,21.79 36.56,21.03 36.56,17.83 36.86,17.53 36.86,17.13 36.86,16.37 36.42,15.93 36.42,15.59 36.87,15.13 36.87,14.8 39.27,12.4 39.27,7.96 41.39,5.84 42.26,5.84 42.89,5.22 56.54,5.22 57.77,3.98 69.57,3.98 72.12,6.53 72.12,7 72.58,7.46 92.25,7.46 95.03,10.24 100.05,10.24 101.55,8.75 103.01,8.75 104.99,6.76 108.2,6.76 110.08,4.88 113.65,4.88 114.44,4.09 141.1,4.09 144.3,7.3 152.37,7.3 155.12,4.55 181.75,4.55 182.52,5.32 190.96,5.32 193.75,8.11 194.92,8.11 198.82,12.01 198.82,16.82 199.43,17.43 199.43,35.67 202.99,39.23 205.86,39.23 206.83,40.19 210.31,40.19 210.75,40.62 212.7,40.62 212.99,40.33 214.31,40.33 v3(214.71,40.74) ; v7(205.68,52.5) 205.99,52.5 207.1,53.62 207.61,53.62 208.96,52.27 210.75,52.27 210.92,52.1 211.7,52.1 211.96,52.36 213.47,52.36 213.81,52.01 217.8,52.01 v3(217.85,52.07)
  IN4 w0.076: v3(214.71,40.74) 214.97,40.74 218.12,43.88 218.12,48.53 217.85,48.8 v3(217.85,52.07) 217.83,52.07 216.34,53.55 215.82,53.55 214.73,54.64 214.32,54.64 214.17,54.8 214.04,54.8 212.54,56.29 v4(212.52,56.29)
  BOTTOM w0.109: v2(30.57,54.44) v1(29.89,54.44) 29.41,53.96 U700.2
  BOTTOM w0.254: U34.M1 212.36,56.14 v4(212.52,56.29)
USB1_CTL1: length 286.7
  TOP w0.109: R1167.2 27.63,51.53 28.94,52.84 30.13,52.84 v2(30.61,52.36) v1(30.61,50.85)
  IN1 w0.076: v3(214.92,41.78) 214.52,41.38 213.68,41.38 213.45,41.61 211.9,41.61 211.77,41.74 209.71,41.74 209.38,41.41 207.05,41.41 205.48,39.84 202.73,39.84 198.19,35.29 198.19,12.26 194.65,8.72 193.46,8.72 190.67,5.93 182.27,5.93 181.5,5.16 155.38,5.16 152.63,7.91 144.05,7.91 141.56,5.42 129.11,5.42 128.39,4.7 119.71,4.7 118.79,5.62 110.21,5.62 108.46,7.37 105.24,7.37 103.26,9.36 101.8,9.36 100.31,10.85 94.78,10.85 92,8.07 72.33,8.07 71.59,7.34 67.43,7.34 66.88,6.79 63.98,6.79 63.44,7.33 59.99,7.33 59.79,7.13 57.36,7.13 56.43,8.06 51.23,8.06 48.99,5.82 43.14,5.82 42.46,6.5 42.46,7.51 39.95,10.02 39.95,12.59 37.64,14.9 37.64,16.62 38.37,17.36 38.37,18.54 37.17,19.75 37.17,21.28 36.4,22.05 36.4,24.68 34.97,26.12 34.97,29.69 34.49,30.18 34.49,31.44 33.62,32.3 33.62,41.38 32.12,42.88 32.12,48.73 30.96,49.89 30.96,50.5 v1(30.61,50.85)
  IN4 w0.076: v4(210.48,56.35) 210.66,56.17 211.12,56.17 211.27,56.02 212.59,56.02 214.01,54.59 214.15,54.59 214.31,54.44 214.65,54.44 217.39,51.7 217.39,48.96 217.91,48.44 217.91,43.96 215.61,41.66 215.03,41.66 v3(214.92,41.78)
  BOTTOM w0.109: U34.H1 210.36,56.09 210.48,56.22 v4(210.48,56.35)
USB1_DET#: length 89.2
  TOP w0.109: v1(205.2,59.83) 204.92,60.11 204.84,60.11 v2(204.8,60.14)
  IN2 w0.102: v1(205.2,59.83) 205.73,59.29 208.32,59.29 208.71,59.67 208.71,60.1 209.09,60.49 217.62,60.49 218.41,59.7 220.41,59.7 225.32,54.8 226.74,54.8 228.47,53.07 237.69,53.07 242.92,58.3 253.31,58.3 255.62,55.99 272.56,55.99 275.56,52.99 276.9,52.99 277.18,52.71 281.6,52.71 282.35,51.97 JUSB1.10
  BOTTOM w0.109: v1(205.2,59.83) 204.73,59.35 D104.1
USB1_DET_EC#: length 5.5
  BOTTOM w0.102: R1156.2 204.69,56.24 v2(205.3,55.63) 206.27,55.63 206.46,55.44
  BOTTOM w0.109: R1156.2 203.73,56.75 202.71,56.75 202.49,56.97 D104.3
  BOTTOM w0.254: U34.A2 206.46,55.44
USB1_EN: length 4.4
  TOP w0.109: v2(262.95,47.96) 262.95,47.66 U699.4 263.63,46.98 R1216.2 264.75,47.01 US1.5
USB1_PWR_EN: length 123
  TOP w0.109: v1(253.66,40.9) 253.66,40.97 v2(254.15,41.45) 254.49,41.79 254.49,44.3 256.49,46.3 258.53,46.3 259.39,45.44 262.2,45.44 262.3,45.35 U699.1
  IN2 w0.102: v1(253.66,40.9) 253.66,40.42 251.57,38.32 248.86,38.32 247.71,39.48 241.04,39.48 240.57,39.01 232.76,39.01 230.16,41.6 228.61,41.6 227.83,40.83 226.74,40.83 225.65,41.92 223.86,41.92 223.07,41.14 221.64,41.14 221.01,41.77 216.8,41.77 215.12,40.09 211.88,40.09 209.87,42.1 205.01,42.1 202.07,45.04 198.33,45.04 197.3,46.07 193.11,46.07 192.03,44.99 179.81,44.99 179.16,45.64 176.13,45.64 176.07,45.58 169.97,45.58 166.93,42.54 165.86,42.54 v3(165.17,41.85)
  IN4 w0.076: v4(162.14,41.51) 162.21,41.44 164.75,41.44 v3(165.17,41.85) 166.55,41.85 v4(166.74,41.66)
  BOTTOM w0.109: v4(166.74,41.66) 166.74,39.73 169.97,36.51 RH403.2
USB1_PWR_EN_EC: length 72.2
  TOP w0.109: v7(254.03,42.48) v2(254.03,43.77) 254.03,44.18 256.39,46.54 258.63,46.54 259.49,45.68 261.78,45.68 261.85,45.75 262.77,45.75 262.95,45.58 U699.2
  IN1 w0.076: v7(254.03,42.48) 251.31,42.48 250.76,41.92 247.1,41.92 245.98,40.8 244.43,40.8 244.02,40.39 239.6,40.39 239.15,39.94 235.16,39.94 234.15,40.95 234.15,41.33 229.28,46.2 229.28,50.79 226.87,53.21 225.91,53.21 225.29,53.83 225.29,55.38 221.6,59.08 220.12,59.08 219.47,59.72 218.43,59.72 218.38,59.67 214.76,59.67 v1(214.57,59.86)
  GND3 w0.076: v10(211.17,56.88) v10(211.17,57.51)
  BOTTOM w0.076: U34.J2 211.11,55.69 211.11,56.82 v10(211.17,56.88)
  BOTTOM w0.109: v10(211.17,57.51) 211.19,57.49 212.31,57.49 212.83,58.01 212.83,58.49 213.17,58.83 RP21.3 213.88,58.83 214.15,59.1 214.15,59.44 v1(214.57,59.86)
USB3RN0: length 194.6
  IN4 w0.076: v4(21.3,39.01) 21.16,38.88 21.16,37.46 21.62,37 22.98,37 23.58,36.41 24.83,36.41 25.91,35.33 25.91,32.8 27.03,31.68 29.17,31.68 30.24,30.6 30.24,29.33 31.13,28.44 31.13,23.4 33.88,20.65 33.88,20.26 35.53,18.61 35.53,17.89 36.21,17.2 36.21,15.34 39.26,12.29 39.26,11.36 44.29,6.33 48.61,6.33 50.49,8.21 58.35,8.21 58.87,8.73 73.97,8.73 75.24,7.46 92.54,7.46 95.85,10.78 98.08,10.78 98.98,11.68 98.98,28.04 103.09,32.15 103.09,32.88 106.98,36.76 106.98,42.41 109.43,44.86 117.57,44.86 123.56,50.86 127.17,50.86 128.71,52.4 128.71,58 128.84,58.13 129.06,58.35 150.36,58.35 150.55,58.54 152.21,58.54 152.29,58.62 v4(152.29,58.89)
  BOTTOM w0.109: ML54.4 21.51,40.17 21.21,39.86 21.21,39.1 v4(21.3,39.01)
USB3RN0_RC_CON: length 19.3
  BOTTOM w0.109: ML54.3 21.51,42.68 21.21,42.98 21.21,43.17 21.09,43.29 21.09,43.4 21.3,43.62 MD82.1 21.3,45.05 21.1,45.25 21.1,45.76 21.43,46.09 21.43,47.08 22.18,47.84 22.18,50.27 21.32,51.13 19.26,51.13 19.25,51.14 18.73,51.14 18.73,51.13 v6(16.15,51.13) 15.53,51.13 14.78,50.38 13.2,50.38 12.48,51.1 JUSB2.5
USB3RN1: length 154.8
  TOP w0.109: ML46.1 274.59,38.57 274.31,38.29 274.31,38.01 v1(274.49,37.83)
  IN4 w0.076: v1(274.49,37.83) 274.28,38.05 274.28,40.88 273.82,41.33 271.1,44.05 257.89,44.05 251.02,37.18 247.67,37.18 247.38,37.47 244.68,37.47 244.44,37.71 244.44,42.59 243.52,43.52 243.52,49.56 241.45,51.63 240.29,51.63 238.58,53.35 238.58,54.09 233.24,59.42 226.13,59.42 225.61,59.94 220.38,59.94 218.98,61.34 217.46,61.34 215.49,63.31 202.63,63.31 200.63,61.3 200.63,60.88 199.8,60.05 199.8,59.88 198.72,58.8 198.72,58.21 196.26,55.75 194.07,55.75 193.55,56.27 181.86,56.27 180.61,57.51 178.82,57.51 177.77,58.57 170.02,58.57 167.29,61.3 163.92,61.3 163.15,62.07 156.47,62.07 155.85,61.45 154.93,61.45 153.53,60.05 153.38,60.05 v4(153.24,60.2)
USB3RN1_RC_CON: length 11.6
  TOP w0.109: ML46.2 274.59,41.1 274.31,41.38 274.31,41.61 274.48,41.78 274.87,41.78 274.88,41.77 275.4,41.77 275.41,41.78 276.26,41.78 276.51,42.03 276.51,42.32 276.72,42.53 MD74.6 276.72,44.09 276.51,44.3 276.51,44.53 276.62,44.64 279.02,44.64 279.55,44.11 v6(279.76,44.11) 280.77,44.11 281.32,43.56 JUSB1.5
USB3RP0: length 194.6
  IN4 w0.076: v4(152.29,58.24) 152.14,58.39 150.62,58.39 150.43,58.2 129.13,58.2 128.86,57.93 128.86,52.33 127.23,50.71 123.63,50.71 117.63,44.71 109.49,44.71 107.13,42.35 107.13,36.7 103.24,32.81 103.24,32.09 99.13,27.97 99.13,11.62 98.14,10.63 95.92,10.63 92.6,7.31 75.17,7.31 73.9,8.58 58.93,8.58 58.41,8.06 50.55,8.06 48.67,6.18 44.23,6.18 39.11,11.3 39.11,12.23 36.06,15.27 36.06,17.14 35.38,17.83 35.38,18.55 33.73,20.2 33.73,20.59 30.98,23.34 30.98,28.38 30.09,29.27 30.09,30.54 29.1,31.53 26.97,31.53 25.76,32.74 25.76,35.26 24.77,36.25 23.51,36.25 22.92,36.85 21.56,36.85 21.01,37.4 21.01,38.86 v4(20.87,39.01)
  BOTTOM w0.109: v4(20.87,39.01) 20.97,39.11 v6(20.97,39.58) 20.97,39.86 20.71,40.13 ML54.1
USB3RP0_RC_CON: length 19.2
  BOTTOM w0.109: ML54.2 20.71,42.66 20.99,42.94 20.99,43.08 20.86,43.2 20.86,43.4 20.65,43.61 MD82.2 20.65,45.02 20.87,45.25 20.87,45.86 21.2,46.19 21.2,47.18 21.96,47.93 21.96,50.18 21.23,50.91 v6(18.99,50.91) 16.42,50.91 16.41,50.9 15.89,50.9 15.88,50.91 15.63,50.91 14.87,50.15 13.15,50.15 12.48,49.48 JUSB2.6
USB3RP1: length 154.8
  TOP w0.109: v1(273.91,37.83) 274.09,38.01 274.09,38.27 273.79,38.57 ML46.4
  IN4 w0.076: v4(153.24,59.54) 153.24,59.8 153.34,59.9 153.6,59.9 155,61.3 155.91,61.3 156.53,61.92 163.09,61.92 163.86,61.15 167.23,61.15 169.96,58.41 177.71,58.41 178.76,57.36 180.55,57.36 181.79,56.12 193.49,56.12 194.01,55.6 196.32,55.6 198.88,58.15 198.88,58.73 199.95,59.81 199.95,59.99 200.78,60.82 200.78,61.24 202.7,63.15 215.42,63.15 217.39,61.18 218.92,61.18 220.31,59.79 225.55,59.79 226.07,59.27 233.18,59.27 238.42,54.02 238.42,53.28 240.23,51.48 241.38,51.48 243.36,49.5 243.36,43.46 244.29,42.53 244.29,37.65 244.62,37.32 247.31,37.32 247.61,37.03 251.09,37.03 257.96,43.9 271.04,43.9 273.72,41.22 274.12,40.81 274.12,38.05 v1(273.91,37.83)
USB3RP1_RC_CON: length 11.7
  TOP w0.109: JUSB1.6 280.56,44.34 279.63,44.34 279.11,44.87 276.52,44.87 276.28,44.63 276.28,44.29 276.07,44.07 MD74.5 276.07,42.54 276.28,42.32 276.28,42.12 276.16,42 v6(275.14,42) 274.39,42 274.08,41.7 274.08,41.42 273.79,41.12 ML46.3
USB3TN0: length 189.6
  IN4 w0.076: v4(19.65,37.86) 19.5,38.01 19.5,38.62 20.88,40 23.78,40 26.56,37.22 26.56,34.29 27.18,33.66 29.11,33.66 30.7,32.08 30.7,29.52 31.72,28.51 31.72,23.48 34.99,20.21 34.99,20.02 36.33,18.68 36.33,18.06 37.59,16.8 37.59,14.97 39.87,12.68 39.87,11.6 44.56,6.92 48.02,6.92 49.98,8.87 58.35,8.87 58.68,9.2 74.14,9.2 75.42,7.92 92.08,7.92 95.65,11.49 97.73,11.49 98.47,12.23 98.47,28.18 102.63,32.34 102.63,33.31 106.52,37.19 106.52,42.6 109.24,45.32 117.13,45.32 122.93,51.13 122.93,51.9 123.97,52.94 127.69,52.94 128.09,53.34 128.09,58.54 128.89,59.34 142.67,59.34 143.17,59.85 143.17,61.35 143.34,61.51 v4(143.73,61.51)
  BOTTOM w0.109: v4(19.65,37.86) 19.55,37.97 19.55,38.19 C1107.1
USB3TN0_C: length 1.6
  BOTTOM w0.109: ML53.4 19.86,40.37 19.57,40.08 19.57,39.76 C1107.2
USB3TN0_RC_CON: length 12
  BOTTOM w0.109: ML53.3 19.86,42.63 19.57,42.91 19.57,43.02 19.77,43.22 19.77,43.44 20,43.66 MD82.3 20,45.23 19.79,45.44 19.79,45.64 19.55,45.88 v6(17.32,45.88) 16.4,45.88 16.12,45.88 15.67,45.42 15.65,45.42 15.21,44.98 15.21,44.97 14.62,44.38 13.2,44.38 12.48,45.1 JUSB2.8
USB3TN1: length 152.7
  TOP w0.109: C621.1 276.53,53.58 276.53,54.26 276.71,54.44 v1(276.71,54.45)
  IN4 w0.076: v4(142.84,65.58) 142.72,65.58 142.56,65.73 142.56,67.06 145.03,69.53 146.86,69.53 147.34,70.01 193.58,70.01 195.8,67.79 198,67.79 200.22,70.01 215.54,70.01 219.73,65.82 222.09,65.82 222.74,66.47 226.54,66.47 228.2,64.8 234.51,64.8 237.28,62.04 237.98,62.04 241.64,58.38 249.31,58.38 249.59,58.1 253.13,58.1 256.51,54.72 269.09,54.72 270.49,53.32 274.14,53.32 274.26,53.2 275.99,53.2 276.5,53.7 276.5,54.23 v1(276.71,54.45)
  BOTTOM w0.109: v4(142.84,65.58) 142.84,65.3 143.07,65.07 v6(143.07,64.83) 143.07,63.69 143.43,63.33 143.63,63.33 144.04,62.92 144.04,62.47 UCPU1.B33
USB3TN1_C: length 1.5
  TOP w0.109: ML45.4 276.81,51.42 276.52,51.71 276.52,52.04 C621.2
USB3TN1_RC_CON: length 11.1
  TOP w0.109: v1(276.69,46.3) 276.51,46.48 276.51,46.72 276.72,46.93 MD74.3 276.72,48.41 276.51,48.62 276.51,48.85 276.81,49.15 ML45.3
  IN1 w0.076: v1(276.69,46.3) 276.45,46.54 276.45,46.78 279.69,50.02 281.24,50.02 281.32,49.95 JUSB1.8
USB3TP0: length 189.6
  IN4 w0.076: v4(143.17,61.84) 143.17,61.56 143.02,61.41 143.02,59.91 142.6,59.5 128.82,59.5 127.93,58.61 127.93,53.4 127.63,53.09 123.91,53.09 122.78,51.96 122.78,51.19 117.06,45.47 109.18,45.47 106.37,42.67 106.37,37.26 102.48,33.37 102.48,32.4 98.32,28.24 98.32,12.29 97.67,11.64 95.59,11.64 92.02,8.07 75.49,8.07 74.21,9.36 58.62,9.36 58.29,9.03 49.92,9.03 47.96,7.07 44.62,7.07 40.02,11.67 40.02,12.75 37.74,15.03 37.74,16.86 36.48,18.12 36.48,18.74 35.14,20.08 35.14,20.27 33.15,22.26 31.87,23.54 31.87,28.57 30.85,29.59 30.85,32.14 29.18,33.82 27.25,33.82 26.71,34.35 26.71,37.28 23.84,40.15 20.82,40.15 19.35,38.68 19.35,37.99 v4(19.22,37.86)
  BOTTOM w0.109: C1108.1 19.33,38.19 19.33,37.97 v4(19.22,37.86)
USB3TP0_C: length 1.6
  BOTTOM w0.109: C1108.2 19.34,39.79 19.34,40.07 19.06,40.36 ML53.1
USB3TP0_RC_CON: length 11.8
  BOTTOM w0.109: ML53.2 19.06,42.67 19.35,42.96 19.35,43.11 19.55,43.32 19.55,43.42 19.35,43.62 MD82.4 19.35,45.23 19.56,45.44 19.56,45.55 19.46,45.66 17.58,45.66 17.57,45.65 17.06,45.65 17.05,45.66 16.31,45.66 16.22,45.66 v6(15.61,45.05) 14.71,44.15 13.18,44.15 12.48,43.46 JUSB2.9
USB3TP1: length 152.5
  TOP w0.109: v1(276.13,54.45) 276.31,54.27 276.31,53.63 C623.1
  IN4 w0.076: v1(276.13,54.45) 276.35,54.23 276.35,53.77 275.93,53.35 274.33,53.35 274.2,53.48 270.55,53.48 269.16,54.87 256.57,54.87 253.19,58.25 249.65,58.25 249.37,58.53 241.7,58.53 238.04,62.19 237.34,62.19 234.57,64.96 228.26,64.96 226.6,66.62 222.68,66.62 222.03,65.97 219.79,65.97 215.6,70.16 200.16,70.16 197.93,67.94 195.87,67.94 193.65,70.16 147.28,70.16 146.79,69.68 144.96,69.68 142.41,67.13 142.41,65.67 142.5,65.58 142.5,65.45 v4(142.44,65.39)
  BOTTOM w0.109: v4(142.44,65.39) 142.84,64.99 142.84,64.51 142.85,64.5 142.85,63.59 143.38,63.07 143.38,62.62 143.48,62.52 143.63,62.52 143.73,62.62 UCPU1.A33
USB3TP1_C: length 1.5
  TOP w0.109: C623.2 276.3,52.01 276.3,51.74 276.01,51.45 ML45.1
USB3TP1_RC_CON: length 11.4
  TOP w0.109: v1(276.1,46.3) 276.28,46.48 276.28,46.72 276.07,46.93 MD74.4 276.07,48.37 276.28,48.58 276.28,48.88 276.01,49.15 ML45.2
  IN1 w0.076: v1(276.1,46.3) 276.29,46.49 276.29,46.85 279.62,50.18 281.24,50.18 281.32,50.25 JUSB1.9
USB20_N0: length 212.9
  TOP w0.109: US2.2 29.2,46.78 29.34,46.92 29.57,46.92 v1(29.75,46.74)
  IN4 w0.076: v1(29.75,46.74) 29.97,46.96 30.68,46.96 33.67,43.96 33.67,33.8 34.27,33.21 34.27,32.13 34.36,32.04 34.36,30.78 34.92,30.22 34.92,29.09 35.55,28.46 35.55,26.7 36.54,25.71 36.54,25.12 39.83,21.83 39.83,21.47 43.66,17.65 44.11,17.65 45.01,16.75 46.49,15.27 48.29,15.27 49.56,14 51.64,14 52.08,13.57 53.02,13.57 54.08,12.51 63.42,12.51 63.72,12.81 74.85,12.81 76.69,10.97 89.67,10.97 90.7,12 90.7,22.51 93.47,25.28 93.47,27.19 95.19,28.91 95.19,30.01 99.33,34.15 99.33,34.97 99.69,35.33 99.69,37.03 102.98,40.32 102.98,43.4 107.49,47.91 107.49,48.7 108.12,49.34 115.68,49.34 116.43,50.08 116.43,51.23 119.86,54.66 119.86,59.29 125.44,64.88 134.61,64.88 134.99,64.5 134.99,63.55 136.21,62.33 136.21,61.2 136.74,60.68 140.35,60.68 141.81,62.14 143.77,62.14 144.16,61.74 144.16,60.47 145.19,59.45 152.44,59.45 154.22,57.67 154.22,50.5 154.6,50.12 154.6,47.42 154.2,47.01 154.2,45.23 154.79,44.64 155.25,44.64 156.06,43.82 158.01,43.82 158.44,44.26 158.44,44.52 158.62,44.7 158.66,44.7 v4(158.79,44.56)
  BOTTOM w0.109: v4(158.79,44.56) 159,44.56 UCPU1.AN8
USB20_N0_CONN: length 15.5
  TOP w0.109: v1(20.57,46.74) 20.75,46.92 21,46.92 21.33,46.59 ML52.3
  BOTTOM w0.109: JUSB2.2 10.98,46.76 12.19,47.97 v6(15.59,47.97) 16.7,47.97 17.27,48.54 17.29,48.54 17.72,48.98 17.72,48.99 18.73,50 19.13,50 19.35,49.78 MD82.5 19.35,47.34 19.76,46.93 20.39,46.93 v1(20.57,46.74)
USB20_N1: length 126.6
  TOP w0.109: US1.2 263.51,50.78 263.37,50.64 263.23,50.64 v7(263.11,50.76)
  IN1 w0.076: v3(236.31,44.59) 236.52,44.38 237.27,44.38 238.03,43.62 245.08,43.62 245.99,44.53 247.41,44.53 249.01,46.13 249.55,46.13 252.27,48.85 257.38,48.85 259.15,50.62 262.97,50.62 v7(263.11,50.76)
  IN4 w0.076: v4(159.72,43.44) 159.72,43.35 159.81,43.26 161.22,43.26 161.27,43.32 166.34,43.32 166.95,43.92 167.48,43.92 169.13,45.58 171.04,45.58 171.76,46.3 175.75,46.3 177.43,47.98 180.79,47.98 180.94,48.13 184.35,48.13 184.5,47.98 186.9,47.98 187.29,47.58 194.98,47.58 195.98,48.59 197.43,48.59 198.57,49.73 199.7,49.73 201.54,51.57 201.54,52.4 203.01,53.86 203.01,54.26 205.2,56.45 205.39,56.45 206.53,57.59 212.48,57.59 213.57,56.5 214.04,56.5 214.72,55.81 215.74,55.81 216.39,55.16 216.88,55.16 218.31,53.74 219.64,53.74 221.67,51.71 221.67,48.05 223.32,46.4 223.32,45.26 224.3,44.28 225.28,44.28 227.41,42.15 227.7,42.15 228.24,41.61 228.24,41.3 228.8,40.74 229.29,40.74 231.32,42.77 234.35,42.77 235.93,44.36 236.14,44.36 236.31,44.53 v3(236.31,44.59)
USB20_N1_CONN: length 16
  TOP w0.109: JUSB1.2 282.82,47.81 282.65,47.63 282.28,47.63 281.72,48.19 280.47,48.19 280.14,48.52 280.14,48.55 279.77,48.92 279.75,48.92 279.47,49.19 277.99,49.19 277.68,48.88 277.68,48.68 277.37,48.36 MD74.2 277.37,46.83 277.45,46.74 277.7,46.74 277.8,46.65 277.8,46.19 277.3,45.69 v6(274.15,45.69) 273.84,45.69 273.61,45.92 273.61,46.89 273.95,47.23 ML40.3
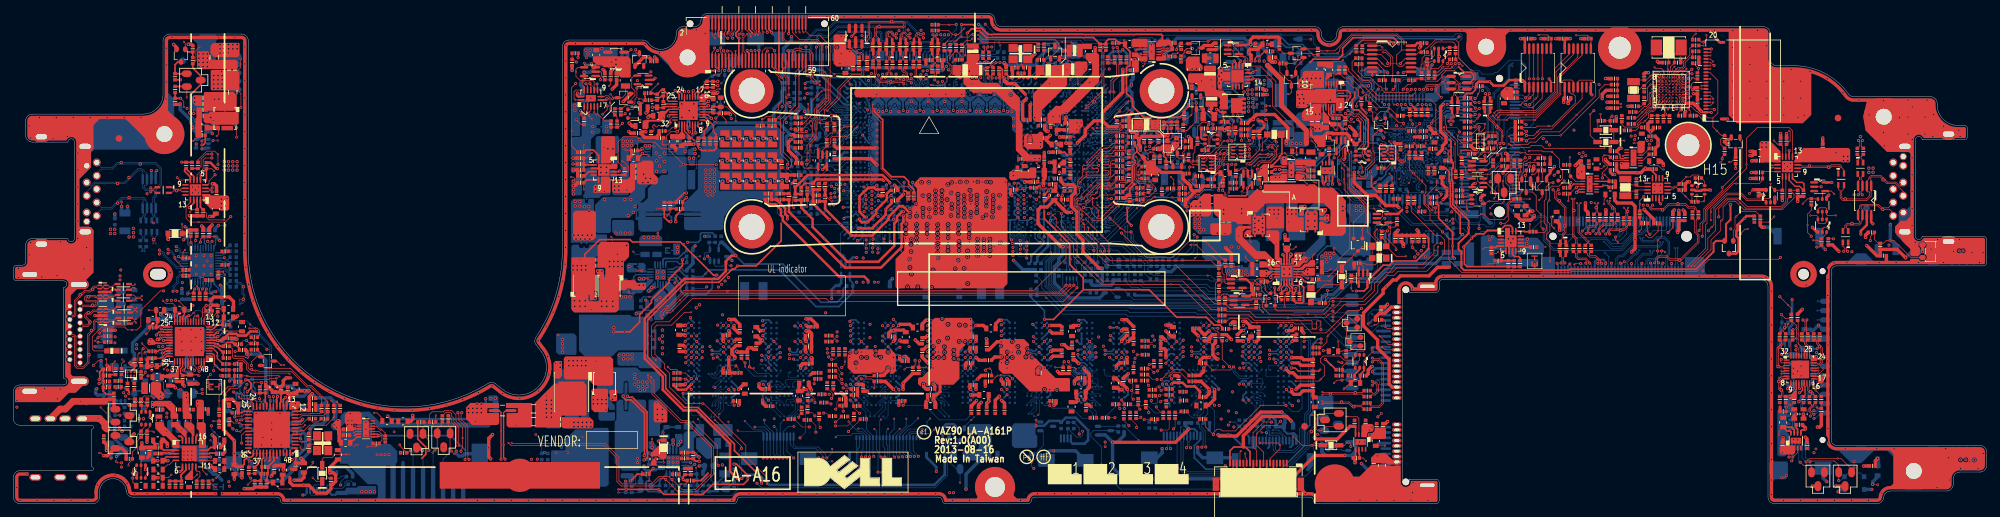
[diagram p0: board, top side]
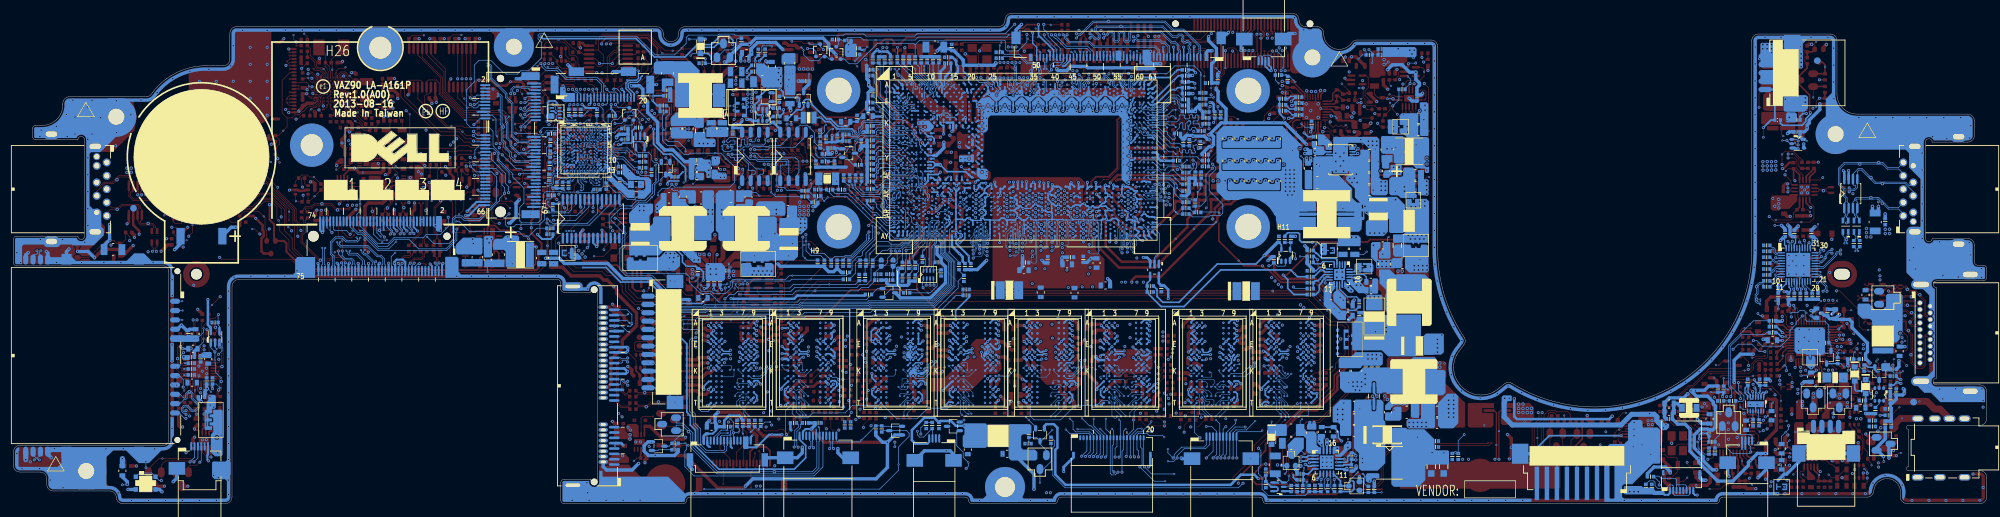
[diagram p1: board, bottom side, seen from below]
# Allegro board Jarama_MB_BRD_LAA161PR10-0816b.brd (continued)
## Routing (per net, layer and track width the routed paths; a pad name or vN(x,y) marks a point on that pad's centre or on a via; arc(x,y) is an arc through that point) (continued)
USB20_N2: length 80.7
  TOP w0.109: v1(222.46,53.97) 222.66,54.17 222.66,55.78 v6(221.98,56.45) 220.48,57.96 220.48,58.25 220.19,58.54 ML49.1 220.19,59.25 R742.1
  IN4 w0.076: v1(222.46,53.97) 222.69,54.2 222.69,54.39 222.6,54.48 222.09,54.48 221.93,54.31 218.38,54.31 216.43,56.27 214.92,56.27 213.96,57.22 213.51,57.22 212.68,58.05 205.61,58.05 204.87,57.31 204.87,56.94 202.42,54.49 202.42,53.98 200.55,52.11 200.55,51.32 199.42,50.19 198.19,50.19 197.06,49.06 195.79,49.06 194.79,48.05 188.06,48.05 187.67,48.43 184.92,48.43 184.73,48.62 180.19,48.62 180,48.43 177.23,48.43 175.56,46.76 171.57,46.76 170.85,46.03 168.93,46.03 167.66,44.77 166.31,44.77 165.39,43.85 161.45,43.85 161.12,43.52 160.23,43.52 160.03,43.72 159.57,43.72 159.49,43.65 159.05,43.65 v4(158.84,43.43)
  BOTTOM w0.109: UCPU1.AR8 v4(158.84,43.43)
USB20_N2_R: length 6
  TOP w0.109: R742.2 220.19,60.35 ML49.2 220.19,60.88 220.49,61.18 220.49,61.27 v1(220.29,61.46)
  BOTTOM w0.109: JNGFF1.5 218.05,61.99 218.12,62.07 218.12,62.18 218.21,62.27 219.21,62.27 219.29,62.35 220.31,62.35 220.57,62.08 220.57,61.74 220.46,61.63 220.46,61.53 220.39,61.46 v1(220.29,61.46)
USB20_N3: length 51.7
  IN1 w0.076: v7(126.52,66.91) 127.02,66.41 127.02,64.89 126.76,64.63 126.76,62.96 129.37,60.36 130.64,60.36 132.01,61.73 149.84,61.73 150.89,60.68 150.89,59.81 151.89,58.82 151.89,57.96 152.57,57.27 152.57,55.86 154.35,54.08 154.35,50.06 156.64,47.77 156.64,47.62 157.71,46.54 157.71,44.98 157.85,44.84 157.85,44.01 157.71,43.87 157.71,43.37 157.71,43.36 157.71,43.36 v3(157.42,43.09)
  IN4 w0.076: v4(157.8,43.44) 157.45,43.09 v3(157.42,43.09)
USB20_N4: length 73.9
  TOP w0.109: R1005.1 216.13,59.19 ML55.1 216.13,58.6 215.74,58.21 215.74,58 215.55,57.81 215.36,57.81 215.26,57.7 215.26,57.51 v1(215.44,57.34)
  IN4 w0.076: v4(155.03,45.42) 155.16,45.3 155.33,45.3 156.22,44.42 157.51,44.42 157.77,44.67 157.77,45.6 158.66,46.5 159.77,46.5 160.02,46.74 160.48,46.74 160.61,46.87 162.45,46.87 162.65,47.07 163.19,47.07 163.7,47.58 164.03,47.58 164.5,48.06 164.86,48.06 165.4,48.6 166.01,48.6 167.74,50.33 169.4,50.33 169.95,50.87 174.85,50.87 176.27,52.29 178.34,52.29 180.16,50.48 183.74,50.48 184.32,51.06 187.5,51.06 187.78,51.34 190.53,51.34 190.87,51.68 193.36,51.68 194.04,51.01 197.42,51.01 198.94,52.54 199.88,52.54 201.51,54.17 201.51,54.69 204.11,57.29 204.11,57.63 205.29,58.81 214.26,58.81 215.23,57.84 215.23,57.54 v1(215.44,57.34)
  BOTTOM w0.109: v4(155.03,45.42) 155.34,45.42 155.42,45.35 155.42,45.14 155.34,45.06 UCPU1.AM15
USB20_N4_CONN: length 11.7
  TOP w0.109: v1(211.04,62.11) 211.29,62.36 211.29,62.55 211.55,62.81 212.52,62.81 212.53,62.82 213.34,62.82 213.82,63.31 214.08,63.31 214.25,63.48 214.25,63.84 214.47,64.05 MD50.1 215.31,64.05 216.46,62.9 216.46,62.01 215.79,61.34 215.79,61.23 216.13,60.9 ML55.2 216.13,60.22 R1005.2
  BOTTOM w0.109: JLVDS1.4 210.4,61.35 211.04,62 v1(211.04,62.11)
USB20_N5: length 109.1
  IN1 w0.076: v3(234.54,55.56) 234.31,55.79 234.31,55.91 235.02,56.62 247.11,56.62 247.47,56.98 247.47,57.18 247.54,57.25 v7(247.84,57.25)
  IN4 w0.076: v4(156.25,45.7) 156.3,45.65 156.3,45.58 156.15,45.42 155.95,45.42 155.8,45.58 155.8,46.2 156.91,47.32 156.91,48.51 157.61,49.21 159.33,49.21 159.4,49.28 160.17,49.28 160.67,49.79 160.9,49.79 161.16,50.05 162.49,50.05 162.97,50.53 162.97,50.68 163.38,51.09 163.7,51.41 164.89,51.41 165.44,51.95 165.44,52.28 166.73,53.58 169.54,53.58 169.89,53.93 171.44,53.93 171.7,53.68 175.43,53.68 176.14,54.39 179.3,54.39 180.47,53.22 183.14,53.22 183.84,52.52 185.12,52.52 185.27,52.37 186.94,52.37 187.36,52.79 193.85,52.79 194.46,52.18 196.55,52.18 198.28,53.91 199.21,53.91 203.02,57.72 203.02,58.2 205.07,60.26 214.74,60.26 215.12,59.88 215.12,59.46 218.1,56.47 218.1,56.35 218.52,55.93 221.33,55.93 222,56.6 225.52,56.6 226.18,57.26 230.73,57.26 233.27,54.72 234,54.72 234.31,55.02 234.31,55.33 v3(234.54,55.56)
  BOTTOM w0.109: v4(156.25,45.7) 156.25,45.58 156.07,45.39 UCPU1.AM13
USB20_N6: length 101.4
  TOP w0.109: v1(231.2,47.05) 230.88,46.73 230.88,45.89 v6(231.36,45.41) 232.35,44.42 232.35,41.91 232.36,41.9 232.36,41.38 232.35,41.37 232.35,40.66 232,40.31 232,39.69 232.31,39.38 ML50.1 232.31,38.84 R743.1
  IN4 w0.076: v4(156.32,44.7) 156.57,44.95 156.57,45.22 158.53,47.18 159.99,47.18 160.08,47.26 162.04,47.26 162.42,47.63 162.94,47.63 163.42,48.12 163.42,48.22 163.96,48.76 164.66,48.76 165.13,49.23 165.79,49.23 167.51,50.96 169.17,50.96 169.69,51.48 174.57,51.48 176.1,53.02 178.48,53.02 179.82,51.67 187,51.67 187.29,51.96 189.6,51.96 189.93,52.29 193.64,52.29 194.24,51.7 196.74,51.7 198.34,53.3 199.24,53.3 203.47,57.53 203.47,57.93 204.96,59.42 214.51,59.42 217.65,56.28 217.65,56.13 218.66,55.11 221.44,55.11 221.98,55.65 223.94,55.65 225.38,54.21 225.38,51.14 228.14,48.37 229.06,48.37 229.72,47.72 230.73,47.72 230.96,47.49 230.96,47.29 v1(231.2,47.05)
  BOTTOM w0.109: v4(156.32,44.7) 156.32,44.66 156.5,44.48 156.5,44.35 157,43.85 157.15,43.85 UCPU1.AP11
USB20_N6_R: length 3.3
  TOP w0.109: v1(232.18,36.08) 231.98,36.28 231.98,36.88 232.31,37.21 ML50.2 232.31,37.71 R743.2
  BOTTOM w0.109: JNGFF2.5 232.15,35.51 232.02,35.64 232.02,35.92 v1(232.18,36.08)
USB20_P0: length 212.9
  TOP w0.109: v1(29.75,47.33) 29.56,47.14 29.34,47.14 29.2,47.28 US2.3
  IN4 w0.076: v4(158.79,44.99) 158.66,44.85 158.55,44.85 158.29,44.59 158.29,44.32 157.94,43.98 156.13,43.98 155.31,44.79 154.86,44.79 154.35,45.3 154.35,46.95 154.76,47.35 154.76,50.19 154.37,50.57 154.37,57.73 152.51,59.6 145.25,59.6 144.32,60.54 144.32,61.81 143.83,62.29 141.75,62.29 140.29,60.83 136.8,60.83 136.37,61.27 136.37,62.39 135.15,63.61 135.15,64.56 134.68,65.03 125.38,65.03 119.7,59.36 119.7,54.72 116.27,51.29 116.27,50.15 116.23,50.1 115.61,49.49 108.06,49.49 107.33,48.76 107.33,47.98 102.83,43.47 102.83,40.38 99.54,37.09 99.54,35.39 99.18,35.03 99.18,34.21 95.04,30.07 95.04,28.98 93.31,27.25 93.31,25.34 90.54,22.58 90.54,12.06 89.6,11.12 76.75,11.12 74.91,12.96 63.66,12.96 63.35,12.66 54.15,12.66 53.08,13.72 52.14,13.72 51.71,14.16 49.62,14.16 48.35,15.43 46.55,15.43 45.12,16.86 44.18,17.8 43.72,17.8 39.99,21.53 39.99,21.89 36.7,25.18 36.7,25.78 35.71,26.77 35.71,28.52 35.07,29.15 35.07,30.29 34.51,30.84 34.51,32.1 34.42,32.19 34.42,33.27 33.83,33.87 33.83,44.03 30.74,47.11 29.97,47.11 v1(29.75,47.33)
  BOTTOM w0.109: UCPU1.AM8 159.09,44.99 v4(158.79,44.99)
USB20_P0_CONN: length 15.5
  TOP w0.109: v1(20.57,47.33) 20.75,47.15 21,47.15 21.28,47.44 ML52.2
  BOTTOM w0.109: v1(20.57,47.33) 20.39,47.15 19.86,47.15 19.57,47.43 19.57,47.63 19.68,47.73 19.91,47.73 20,47.83 MD82.6 20,49.44 19.22,50.22 18.64,50.22 v6(17.3,48.89) 16.6,48.19 15.86,48.19 15.85,48.2 15.33,48.2 15.32,48.19 12.1,48.19 11.58,47.67 11.08,47.67 10.98,47.77 JUSB2.3
USB20_P1: length 126.7
  TOP w0.109: v7(263.11,50.33) 263.2,50.42 263.37,50.42 263.51,50.28 US1.3
  IN1 w0.076: v3(236.31,44) 236.54,44.23 237.2,44.23 237.97,43.47 245.14,43.47 246.06,44.38 247.48,44.38 249.08,45.98 249.61,45.98 252.33,48.7 257.45,48.7 259.21,50.47 262.97,50.47 v7(263.11,50.33)
  IN4 w0.076: v3(236.31,44) 236.11,44.2 236,44.2 234.41,42.62 231.39,42.62 229.36,40.58 228.73,40.58 228.09,41.23 228.09,41.55 227.63,42 227.34,42 225.22,44.13 224.24,44.13 223.17,45.2 223.17,46.34 221.52,47.99 221.52,51.65 219.58,53.59 218.24,53.59 216.82,55.01 216.33,55.01 215.68,55.66 214.66,55.66 213.98,56.35 213.51,56.35 212.41,57.44 206.6,57.44 205.45,56.29 205.26,56.29 203.16,54.19 203.16,53.8 201.69,52.33 201.69,51.51 199.76,49.58 198.63,49.58 197.49,48.43 196.04,48.43 195.04,47.43 187.23,47.43 186.84,47.82 184.44,47.82 184.28,47.98 181.01,47.98 180.85,47.82 177.49,47.82 175.81,46.15 171.82,46.15 171.1,45.42 169.2,45.42 167.54,43.77 167.01,43.77 166.4,43.16 161.33,43.16 161.28,43.11 159.81,43.11 159.72,43.02 v4(159.72,42.79)
USB20_P1_CONN: length 16.4
  TOP w0.109: JUSB1.3 282.82,46.72 282.82,46.77 281.62,47.97 280.38,47.97 v6(279.79,48.55) 279.38,48.97 278.09,48.97 277.91,48.79 277.91,48.6 278.02,48.49 MD74.1 278.02,46.09 277.39,45.46 274.42,45.46 274.41,45.46 273.76,45.46 273.39,45.83 273.39,46.89 273.1,47.18 ML40.2
USB20_P2: length 80.9
  TOP w0.109: v1(223.04,53.97) 222.89,54.13 222.89,55.87 222.33,56.42 222.33,56.44 221.97,56.8 221.95,56.8 220.7,58.06 220.7,58.27 220.99,58.56 ML49.4 220.99,59.22 R741.1
  IN4 w0.076: v4(158.84,44) 159.05,43.8 159.43,43.8 159.51,43.87 160.09,43.87 160.29,43.67 161.05,43.67 161.38,44 165.32,44 166.24,44.92 167.6,44.92 168.87,46.19 170.78,46.19 171.51,46.91 175.49,46.91 177.17,48.59 179.94,48.59 180.13,48.78 184.79,48.78 184.98,48.59 187.74,48.59 188.12,48.2 194.72,48.2 195.73,49.21 197,49.21 198.13,50.34 199.36,50.34 200.4,51.38 200.4,52.18 202.27,54.04 202.27,54.56 204.72,57.01 204.72,57.37 205.54,58.2 212.74,58.2 213.57,57.37 214.03,57.37 214.98,56.42 216.49,56.42 218.45,54.47 221.86,54.47 222.03,54.63 222.66,54.63 222.84,54.45 222.84,54.17 v1(223.04,53.97)
  BOTTOM w0.109: UCPU1.AP8 159.08,43.76 v4(158.84,44)
USB20_P2_R: length 6
  TOP w0.109: v1(220.87,61.46) 220.71,61.3 220.71,61.17 220.99,60.89 ML49.3 220.99,60.38 R741.2
  BOTTOM w0.109: v1(220.87,61.46) 220.83,61.5 220.83,62.14 220.4,62.57 219.2,62.57 219.12,62.49 JNGFF1.3
USB20_P3: length 51.6
  IN1 w0.076: v7(127.77,66.91) 127.18,66.32 127.18,64.83 126.92,64.57 126.92,63.03 129.43,60.51 130.57,60.51 131.95,61.88 149.9,61.88 151.05,60.74 151.05,59.88 152.04,58.89 152.04,58.02 152.72,57.34 152.72,55.93 154.5,54.15 154.5,50.12 156.79,47.84 156.79,47.68 157.87,46.6 157.87,45.04 158.01,44.9 158.01,43.95 157.87,43.81 157.87,43.35 157.89,43.32 v3(158.13,43.06)
  IN4 w0.076: v4(157.8,42.79) 158.08,43.06 v3(158.13,43.06)
USB20_P4: length 74.1
  TOP w0.109: v1(214.85,57.34) 215.03,57.52 215.03,57.8 215.27,58.03 215.46,58.03 215.52,58.09 215.52,58.25 215.28,58.49 ML55.4 215.28,59.17 R1004.1
  IN4 w0.076: v1(214.85,57.34) 215.08,57.56 215.08,57.77 214.2,58.66 205.35,58.66 204.26,57.56 204.26,57.22 201.66,54.62 201.66,54.1 201.62,54.06 199.94,52.38 199,52.38 197.48,50.86 193.97,50.86 193.3,51.53 190.94,51.53 190.59,51.19 187.84,51.19 187.56,50.91 184.38,50.91 183.8,50.33 180.09,50.33 178.28,52.14 176.33,52.14 174.91,50.72 170.01,50.72 169.46,50.17 167.8,50.17 166.08,48.45 165.46,48.45 164.92,47.91 164.57,47.91 164.09,47.43 163.76,47.43 163.25,46.92 162.72,46.92 162.52,46.72 160.67,46.72 160.55,46.59 160.08,46.59 159.83,46.34 158.72,46.34 157.92,45.54 157.92,44.61 157.57,44.27 156.15,44.27 155.27,45.15 154.9,45.15 v4(154.63,45.42)
  BOTTOM w0.109: v4(154.63,45.42) 154.92,45.71 UCPU1.AL15
USB20_P4_CONN: length 11.5
  TOP w0.109: R1004.2 215.28,60.23 ML55.3 215.28,60.95 215.57,61.24 215.57,61.43 216.24,62.1 216.24,62.81 216.14,62.91 216.01,62.91 215.88,62.77 215.88,62.26 215.77,62.15 MD50.3 214.39,62.15 214.28,62.26 214.28,62.88 214.08,63.08 213.92,63.08 213.42,62.59 v6(213.04,62.59) 211.64,62.59 211.51,62.46 211.51,62.24 v1(211.64,62.11)
  BOTTOM w0.109: JLVDS1.3 210.9,61.54 211.04,61.68 211.21,61.68 v1(211.64,62.11)
USB20_P5: length 109.1
  IN1 w0.076: v3(233.95,55.56) 234.16,55.76 234.16,55.98 234.96,56.78 247.05,56.78 247.32,57.05 247.32,57.18 247.24,57.25 v7(246.95,57.25)
  IN4 w0.076: v4(156.25,45.17) 156.15,45.27 155.89,45.27 155.64,45.51 155.64,46.26 156.76,47.38 156.76,48.57 157.55,49.36 159.26,49.36 159.34,49.44 160.1,49.44 160.61,49.94 160.84,49.94 161.09,50.2 162.43,50.2 162.82,50.59 162.82,50.74 163.28,51.2 163.63,51.56 164.83,51.56 165.28,52.01 165.28,52.34 166.67,53.73 169.48,53.73 169.83,54.08 171.51,54.08 171.76,53.83 175.37,53.83 176.08,54.54 179.37,54.54 180.54,53.37 183.2,53.37 183.9,52.68 185.18,52.68 185.34,52.52 186.87,52.52 187.29,52.94 193.91,52.94 194.52,52.33 196.49,52.33 198.21,54.06 199.14,54.06 202.86,57.78 202.86,58.26 205.01,60.41 214.8,60.41 215.27,59.94 215.27,59.52 218.26,56.54 218.26,56.41 218.59,56.08 221.27,56.08 221.94,56.75 225.46,56.75 226.12,57.41 230.79,57.41 233.33,54.87 233.94,54.87 234.16,55.09 234.16,55.35 v3(233.95,55.56)
  BOTTOM w0.109: v4(156.25,45.17) 155.88,44.8 UCPU1.AN13
USB20_P6: length 101.2
  TOP w0.109: R744.1 231.51,38.84 ML50.4 231.51,39.46 231.78,39.73 231.78,40.41 232.13,40.75 v6(232.13,41.64) 232.13,44.33 231.39,45.06 231.38,45.06 231.02,45.43 231.02,45.44 230.66,45.8 230.66,46.8 v1(230.41,47.05)
  IN4 w0.076: v1(230.41,47.05) 230.59,46.87 230.73,46.87 230.8,46.95 230.8,47.43 230.67,47.56 229.65,47.56 228.99,48.22 228.07,48.22 225.22,51.07 225.22,54.15 223.88,55.49 222.04,55.49 221.51,54.96 218.6,54.96 217.49,56.07 217.49,56.22 214.45,59.27 205.02,59.27 203.63,57.87 203.63,57.46 199.31,53.15 198.41,53.15 196.81,51.54 194.18,51.54 193.58,52.14 190,52.14 189.67,51.81 187.36,51.81 187.06,51.52 179.76,51.52 178.41,52.87 176.17,52.87 174.63,51.33 169.76,51.33 169.23,50.81 167.58,50.81 165.85,49.08 165.19,49.08 164.73,48.61 164.03,48.61 163.57,48.15 163.57,48.05 163,47.48 162.48,47.48 162.11,47.11 160.14,47.11 160.05,47.02 158.59,47.02 156.73,45.16 v4(156.73,44.7)
  BOTTOM w0.109: v4(156.73,44.7) 156.73,44.44 157.09,44.08 157.3,44.08 157.37,44.15 157.37,44.28 UCPU1.AN11
USB20_P6_R: length 3.3
  TOP w0.109: R744.2 231.51,37.71 ML50.3 231.51,37.16 231.76,36.91 231.76,36.24 v1(231.59,36.08)
  BOTTOM w0.109: JNGFF2.3 231.65,35.55 231.79,35.7 231.79,35.88 v1(231.59,36.08)
USB_CTL0: length 336.6
  TOP w0.109: R1213.1 R1166.1 266.48,46.38 266.48,45.83 264.71,44.06 258.97,44.06 257.71,45.32 256.72,45.32 255.86,44.46 255.86,42.71 v2(255.61,42.45) 255.5,42.35 255.5,40.95 254.06,39.51 254.06,38.1 v7(251.53,35.57) ; v1(29.71,51.82) 28.73,51.82 28.4,51.49 28.4,50.2 27.49,49.29 US2.6
  IN1 w0.076: v1(29.71,51.82) 29.71,51.66 29.1,51.05 29.1,44.36 32.61,40.85 32.61,31.88 33.47,31.02 33.47,29.75 33.95,29.27 33.95,25.69 34.51,25.14 34.51,24.29 35.39,23.42 35.39,21.62 36.15,20.86 36.15,17.64 36.45,17.34 36.45,17.3 36.45,16.54 36.01,16.1 36.01,15.42 36.47,14.96 36.47,14.63 38.19,12.9 38.19,8.46 41.22,5.43 42.1,5.43 42.72,4.81 46.46,4.81 47.06,4.21 47.58,4.21 48.15,4.78 56.38,4.78 57.58,3.58 69.74,3.58 72.52,6.36 72.52,6.83 72.75,7.06 92.42,7.06 95.18,9.81 97.33,9.81 97.94,9.2 97.94,9.05 98.65,8.34 102.84,8.34 104.82,6.36 108.04,6.36 109.92,4.48 113.48,4.48 114.27,3.69 141.27,3.69 144.47,6.89 152.21,6.89 154.95,4.14 181.92,4.14 182.69,4.91 191.13,4.91 193.9,7.68 195.1,7.68 199.23,11.81 199.23,16.65 199.84,17.26 199.84,35.5 203.16,38.82 206.03,38.82 206.99,39.78 210.48,39.78 210.91,40.22 212.53,40.22 212.83,39.91 214.76,39.91 215.59,40.74 215.59,41.07 217.14,42.63 220.69,42.63 221.89,41.42 223.12,41.42 223.59,41.89 224.97,41.89 225.1,41.77 225.31,41.77 227.16,39.92 227.16,38.82 229.16,36.81 232.77,36.81 233.34,36.24 233.34,35.62 233.93,35.03 235.07,35.03 235.2,34.91 250.89,34.91 251.52,35.53 251.52,35.56 v7(251.53,35.57)
USB_CTL1: length 336.1
  TOP w0.109: v7(251.1,35.57) 251.1,35.67 253.57,38.15 253.57,39.78 254.74,40.95 254.74,44.11 256.42,45.79 258.21,45.79 259.47,44.53 264.51,44.53 265.25,45.27 US1.6 ; v1(29.7,52.41) v2(29.11,52.41) 28.84,52.41 28.1,51.67 28.1,50.55 27.8,50.26 R1167.1
  TOP w0.254: R1167.1 R1214.1
  IN1 w0.076: v7(251.1,35.57) 250.64,35.11 235.28,35.11 235.15,35.24 234.01,35.24 233.55,35.7 233.55,36.32 232.85,37.02 229.25,37.02 227.36,38.9 227.36,40 225.39,41.97 225.18,41.97 225.03,42.12 223.53,42.12 223.03,41.63 221.98,41.63 220.76,42.85 217.07,42.85 215.38,41.16 215.38,40.82 214.68,40.11 212.92,40.11 212.61,40.42 210.83,40.42 210.4,39.99 206.91,39.99 205.94,39.02 203.07,39.02 199.64,35.59 199.64,17.35 199.03,16.74 199.03,11.91 195.03,7.91 193.84,7.91 191.04,5.11 182.6,5.11 181.84,4.35 155.04,4.35 152.29,7.09 144.39,7.09 141.18,3.89 114.36,3.89 113.56,4.68 110,4.68 108.12,6.56 104.9,6.56 102.92,8.54 101.47,8.54 99.97,10.04 95.12,10.04 92.34,7.26 72.66,7.26 72.32,6.92 72.32,6.44 69.66,3.78 57.69,3.78 56.46,5.01 42.8,5.01 42.18,5.63 41.31,5.63 39.07,7.87 39.07,12.32 36.67,14.71 36.67,15.04 36.21,15.5 36.21,16.02 36.65,16.46 36.65,17.21 36.65,17.42 36.35,17.72 36.35,20.95 35.59,21.71 35.59,24.34 34.16,25.78 34.16,29.36 33.67,29.84 33.67,31.1 32.81,31.96 32.81,40.95 29.3,44.46 29.3,50.85 30.12,51.66 30.12,51.99 v1(29.7,52.41)
USB_ILIM_SET: length 339.6
  TOP w0.109: US1.4 261.89,49.78 R1164.1 R1170.1 261.75,48.5 261.25,47.99 v2(257.83,47.99) 257.44,47.99 253.45,44.01 253.45,42 253.24,41.79 253.24,38.27 250.64,35.67 v7(250.64,35.57) ; v1(30.18,49.3) 29.28,48.4 29.28,47.98 29.08,47.78 US2.4
  IN1 w0.076: v1(30.18,49.3) 30.37,49.1 30.37,44.03 33.22,41.18 33.22,32.13 34.08,31.27 34.08,30.01 34.56,29.52 34.56,25.95 36,24.51 36,21.88 36.76,21.11 36.76,17.93 37.23,17.46 37.23,14.73 39.47,12.49 39.47,8.04 41.47,6.04 42.35,6.04 42.97,5.42 56.63,5.42 57.86,4.19 69.49,4.19 71.91,6.61 71.91,7.09 72.49,7.67 92.17,7.67 94.95,10.45 100.14,10.45 101.64,8.95 103.09,8.95 105.07,6.97 108.29,6.97 110.17,5.09 113.73,5.09 114.53,4.29 141.01,4.29 144.22,7.5 152.46,7.5 155.21,4.75 181.67,4.75 182.44,5.52 190.87,5.52 193.67,8.31 194.82,8.31 198.62,12.12 198.62,16.91 199.23,17.52 199.23,35.76 202.9,39.43 205.65,39.43 206.61,40.39 210.23,40.39 210.98,41.14 v3(211.42,41.14) 211.74,40.83 213.05,40.83 213.38,41.16 215.1,41.16 217,43.06 220.83,43.06 221.34,42.55 223.34,42.55 223.73,42.95 224.53,42.95 225.29,42.19 225.46,42.19 227.56,40.09 227.56,38.99 229.33,37.22 232.94,37.22 233.75,36.41 233.75,35.79 234.09,35.44 235.24,35.44 235.37,35.31 250.39,35.31 v7(250.64,35.57)
  IN4 w0.076: v4(211.65,52.21) 211.83,52.38 212.54,52.38 212.69,52.23 212.69,51.75 212.24,51.29 212.24,50.77 212.97,50.03 212.97,49.45 213.26,49.16 213.26,47.82 213.06,47.61 213.06,45.72 212.01,44.66 212.01,43.79 211.42,43.2 v3(211.42,41.14)
  BOTTOM w0.109: U34.K8 211.41,52.44 v4(211.65,52.21)
USB_OC0#: length 271.7
  TOP w0.109: RH468.1 164.65,46.26 162.65,46.26 162.17,45.78 v7(161.49,45.78) 161.49,44.79 162.36,43.91 v7(162.36,43.09) ; v1(32.53,43.04) 31.7,42.2 v2(27.72,42.2) 26.44,42.2 25.85,42.79 25.85,44.52 26.49,45.17 US2.13
  IN1 w0.076: v3(161.84,45.55) 161.84,45.5 161.87,45.53 v3(161.84,45.55) ; v3(161.84,45.55) 161.72,45.55 v7(161.49,45.78) ; v1(32.53,43.04) 33.83,41.74 33.83,32.39 34.69,31.52 34.69,30.26 35.62,29.33 35.62,26.04 36.81,24.85 36.81,22.21 38.95,20.08 39.35,20.08 40.15,19.28 40.15,18.17 41.51,16.81 41.51,15.52 41.22,15.22 41.22,10.55 44.67,7.09 47.76,7.09 49.04,8.38 49.04,9.95 50.38,11.29 51.32,11.29 52.31,10.29 52.31,10.01 52.54,9.79 56.79,9.79 57.76,8.81 58.24,8.81 59.4,9.98 73.49,9.98 73.63,10.12 75.02,10.12 75.54,9.6 91.73,9.6 94.25,12.12 100.83,12.12 102.33,10.63 103.79,10.63 105.67,8.75 108.16,8.75 108.44,9.03 109.5,9.03 110.95,7.58 137.68,7.58 139.48,9.38 153.24,9.38 155.99,6.63 179.79,6.63 181.6,8.44 188.56,8.44 191.83,11.71 191.84,11.71 192.6,12.47 192.6,14.28 192.96,14.64 192.96,18.31 192.17,19.1 192.17,25.46 191.89,25.74 191.89,27.1 190.76,28.23 189.76,28.23 186.43,31.56 178.9,31.56 174.07,36.38 170.22,36.38 167.31,39.29 166.53,39.29 163.42,42.4 163.42,42.99 163.21,43.19 162.46,43.19 v7(162.36,43.09)
  IN4 w0.076: v4(162.16,45.81) 162.16,45.81 161.84,45.5 v3(161.84,45.55)
USB_OC1#: length 134.4
  TOP w0.109: US1.13 266.25,55.89 265.74,56.4 260.99,56.4 259.37,54.77 v2(259.37,50.86) 259.37,50.25 253.22,44.11 253.22,42.42 252.81,42.02 252.81,40.17 v1(252.74,40.09)
  IN2 w0.102: v3(163.06,42.82) 163.69,43.44 166.77,43.44 169.46,46.13 175.86,46.13 176.84,47.11 178.66,47.11 180.1,45.68 191.75,45.68 192.83,46.76 198.4,46.76 198.82,46.34 201.97,46.34 203.33,44.97 203.33,44.77 204.53,43.57 205.47,43.57 206.26,42.78 211.02,42.78 211.83,41.97 212.79,41.97 213.62,41.14 215.45,41.14 216.52,42.22 221.2,42.22 221.83,41.59 222.83,41.59 224.21,42.97 224.5,42.97 225.32,42.16 225.75,42.16 226.84,41.07 227.74,41.07 228.54,41.87 231.15,41.87 233.78,39.24 240.42,39.24 240.89,39.71 247.82,39.71 248.98,38.55 251.31,38.55 252.74,39.98 v1(252.74,40.09)
  IN4 w0.076: v4(163.46,42.82) v3(163.06,42.82)
  BOTTOM w0.109: v4(163.46,42.82) 163.51,42.82 163.9,42.43 164.48,42.43 164.84,42.78 164.84,43.15 166.16,44.47 166.16,44.99 RH160.1
USB_OC2#: length 8.9
  TOP w0.109: RH80.1 168.89,50.5 168.43,50.05 168.43,49.81 v7(168.34,49.72)
  IN1 w0.076: v3(168.9,49.61) 168.44,49.61 v7(168.34,49.72)
  IN4 w0.076: v4(164.41,47.07) 164.78,47.45 165.11,47.45 165.65,47.99 166.27,47.99 167.71,49.44 168.73,49.44 v3(168.9,49.61)
  BOTTOM w0.109: UCPU1.AH2 163.04,47.35 163.32,47.07 163.58,47.07 163.64,47.13 164.36,47.13 v4(164.41,47.07)
USBCHG_DET_D: length 37.6
  TOP w0.109: R342.1 196.35,30.89 196.68,31.22 v1(196.68,31.94)
  BOTTOM w0.109: v1(196.68,31.94) 197.4,31.94 199.63,34.16 203.62,34.16 204.54,35.09 204.54,38.21 204.16,38.59 204.16,40.78 205.86,42.48 205.86,42.86 204.44,44.28 202.63,44.28 201.72,45.19 200.48,45.19 v2(199.74,45.93) 199.36,46.31 199.36,47.79 198.77,48.37 198.77,50.91 199,51.14 199.41,51.14 199.76,51.49 199.76,52.18 200.2,52.61 201.8,52.61 202.14,52.96 U712.4
USBCHG_DET_PWR_EN#: length 7.9
  TOP w0.109: D83.2 205.32,57.02 v1(205.28,56.98)
  BOTTOM w0.109: U712.2 201.49,55.69 201.29,55.89 R939.2 201.29,56.79 201.67,57.17 201.67,57.65 202.16,58.15 203.15,58.15 D104.2 204.32,56.98 v1(205.28,56.98)
USBRBIAS: length 3.2
  TOP w0.109: RH163.1 156.83,45.22 v2(157.44,44.61)
  TOP w0.254: RH163.1 156.83,46.03 v1(156.98,46.19)
  BOTTOM w0.254: v1(156.98,46.19) 157.01,46.22 157.01,46.68 UCPU1.AJ11 UCPU1.AJ10
V_DDR_REF_CA: length 19.4
  TOP w0.381: RD14.1 120.63,45.32 CD89.1 121.47,44.18 v2(123.78,41.87) 125.46,40.19 128.53,40.19 130.99,42.65 130.99,43.01 132.59,44.61 133.13,44.61 134.08,43.66 v1(134.17,43.66)
  BOTTOM w0.254: v1(134.17,43.66) 134.15,43.68 134.02,43.68 133.75,43.95 UCPU1.AP49
V_DDR_REFA_R: length 29.6
  TOP w0.381: v1(133.2,43.15) 133.2,42.25 132.92,41.97 132.92,38.46 129.85,35.39 124.44,35.39 v2(118.62,41.21) 116.06,43.77 CD91.1 RD19.1
  BOTTOM w0.254: v1(133.2,43.15) 133.19,43.15 133.18,43.13 133.13,43.17 132.83,43.17 UCPU1.AR51
V_DDR_REFB_R: length 27.4
  TOP w0.381: RD20.1 117.86,45.5 CD92.1 117.91,45.5 117.91,44.36 119.6,42.67 119.6,41.47 v2(121.38,39.7) 124.8,36.28 129.47,36.28 131.83,38.64 131.83,42.02 132.24,42.43 132.24,43.04 132.97,43.76 v1(133.21,43.76)
  BOTTOM w0.254: v1(133.21,43.76) 133.19,43.74 133.15,43.74 132.95,43.95 UCPU1.AP51
VCIN0_PH: length 130.5
  TOP w0.109: v7(128.67,59.85) 128.57,59.75 128.57,58.48 129.85,57.2 129.85,50.2 131.48,48.57 132.16,48.57 133.2,47.52 133.81,47.52 134.32,47.01 134.32,46.12 133.89,45.69 R947.2 R948.1 ; v1(207.7,59.85) 207.7,59.42 v2(207.88,59.24)
  IN1 w0.076: v3(125.24,68.88) 124.52,68.16 124.52,64.66 128.67,60.51 v7(128.67,59.85)
  IN3 w0.102: v1(207.7,59.85) 207.7,59.86 206.09,61.48 206.09,66.35 204.06,68.39 200.55,68.39 198.49,66.33 195.16,66.33 193.06,68.44 189.93,68.44 189.64,68.14 180.99,68.14 180.21,67.37 175.24,67.37 174.69,66.82 168.59,66.82 167.89,66.12 166.89,66.12 165.36,67.65 164.31,67.65 162.81,69.15 153.94,69.15 153.76,69.32 148.49,69.32 146.15,66.99 143.39,66.99 142.48,67.9 138.31,67.9 137.48,68.74 125.38,68.74 v3(125.24,68.88)
  BOTTOM w0.076: U34.C2 207.86,55.56 207.61,55.8 207.61,56.11 207.53,56.19 207.36,56.19 207.21,56.35 206.8,56.35 206.65,56.5 206.65,56.52
  BOTTOM w0.109: v1(207.7,59.85) 207.7,59.79 207.05,59.14 207.05,57.51 206.6,57.06 206.6,56.57 206.65,56.52
VCIN1_PH: length 167
  TOP w0.109: v2(104.98,12.57) 108.96,8.59 v1(108.96,8.29)
  IN3 w0.102: v1(108.96,8.29) 109.14,8.11 126.36,8.11 127.96,9.71 138.86,9.71 139.86,10.7 149.95,10.7 151.03,9.63 157.2,9.63 159.88,6.94 179.13,6.94 180.26,8.07 190.8,8.07 193.07,10.35 193.53,10.35 197.81,14.63 197.81,25.71 198.98,26.88 198.98,33.7 205,39.72 205,41.77 206,42.77 206,47.67 208.33,50 208.33,51.49 207.78,52.04 207.4,52.04 206.85,52.59 206.85,53.17 207.94,54.26 207.94,55.79 207.49,56.24 v3(207.49,57.03)
  IN4 w0.076: v4(207.69,56.62) 207.49,56.83 v3(207.49,57.03)
  BOTTOM w0.076: U34.D2 208.11,55.69 208.11,56.2 v4(207.69,56.62)
  BOTTOM w0.109: v1(108.96,8.29) 108.6,7.93 108.6,5.81 108.99,5.42 108.99,4.47 108.43,3.91 108.43,2.14 107.49,1.2 102,1.2 PR118.1
  BOTTOM w0.254: PR118.1 PC112.1 PR116.2
VCOUT0_PH#: length 26.7
  TOP w0.109: v7(204.07,41.12) 203.69,40.74 v2(203.69,40.5) 203.69,40.19 204.65,39.23 204.65,37.61 D303.1
  IN1 w0.076: v7(204.07,41.12) 204.16,41.03 v3(204.16,40.57)
  IN3 w0.102: v3(205.73,53.63) 205.73,52.43 205.5,52.21 205.5,50.81 205.58,50.73 205.58,48.78 205.06,48.26 205.06,43.5 204.54,42.98 204.54,40.95 v3(204.16,40.57)
  IN4 w0.076: v4(205.43,53.86) 205.66,53.63 v3(205.73,53.63) 206.11,53.63 206.8,54.31 207.07,54.31 207.51,54.76 207.51,55.06 207.75,55.3 208.96,55.3 v4(209.11,55.15)
  BOTTOM w0.076: U34.E4 208.84,54.46 208.84,54.86 209.11,55.12 v4(209.11,55.15)
  BOTTOM w0.109: v4(205.43,53.86) 205.43,54.01 205.15,54.29 204.84,54.29 204.54,54.59 R922.1
VLDOIN_+1.2V: length 0.6
  TOP w0.109: v1(94.05,34.91) v2(93.4,34.91)
VOLUME: length 4.3
  TOP w0.254: R23.1 R26.2 C48.1 25.15,3.93 25.08,4.01 v2(25.08,4.3) 25.81,5.03 U4.7
VOLUME_DOWN_SW#: length 225.1
  TOP w0.109: v1(212.21,57.02) 212.21,57.16 v2(212.5,57.45)
  IN3 w0.102: v1(212.21,57.02) 212.26,56.97 212.26,56.35 211.96,56.04 211.55,56.04 211.35,55.84 211.35,55.23 211.65,54.92 211.65,51.14 210.75,50.24 210.75,49.68 208.96,47.89 208.96,43.6 206.8,41.44 206.8,40.23 200.32,33.75 200.32,31.56 200.55,31.33 200.55,28.93 200.55,28.92 200.55,28.16 200.07,27.67 200.07,16.24 193.72,9.89 193.26,9.89 190.99,7.62 180.45,7.62 179.32,6.49 159.46,6.49 157.06,8.89 151.12,8.89 149.76,10.24 140.68,10.24 139.69,9.25 128.15,9.25 126.55,7.65 106.93,7.65 106.39,8.19 98.46,8.19 98.03,7.76 95.28,7.76 94.85,8.19 93.86,8.19 93.2,7.53 74.12,7.53 72.9,8.75 71.05,8.75 69.94,9.86 65.99,9.86 65.5,10.35 56.15,10.35 53.99,8.19 50.79,8.19 48.61,6 44.19,6 43.71,6.48 43.71,7.73 43.65,7.78 43.65,8.7 v3(43.45,8.9)
  IN4 w0.076: v4(43.17,9.23) 43.17,9.18 v3(43.45,8.9)
  BOTTOM w0.076: U34.J1 210.91,56 210.91,56.55 210.89,56.57 210.89,56.83
  BOTTOM w0.109: v4(43.17,9.23) 43.18,9.22 43.18,8.41 42.2,7.43 C1124.1 R955.2 ; RP21.1 213.23,57.83 212.41,57.02 v1(212.21,57.02) 212.21,57.03 212.06,57.18 211.04,57.18 210.89,57.03 210.89,56.83
VOLUME_DOWN_SW#_C: length 14.8
  TOP w0.109: v1(35.31,7.73) 34.38,7.73 v2(33.81,7.17)
  BOTTOM w0.109: JVOL.2 35.6,8.82 35.31,8.53 v1(35.31,7.73) 35.51,7.53 38.04,7.53 39.11,8.6 39.11,11.16 DA6.2 39.95,11.24 39.95,10.35 40.66,9.63 R1263.1 R955.1
VOLUME_DOWN_SW#_DSP: length 4.1
  TOP w0.203: UA1.4 42.87,9.84 v1(43,9.71)
  BOTTOM w0.254: R1263.2 41.55,9.28 R1265.2 41.95,10.55 v2(42.44,10.55) 42.75,10.55 43,10.31 v1(43,9.71)
VOLUME_UP_SW#: length 232.1
  TOP w0.109: v2(205.89,54.31) 206.24,53.95 RP22.4 206.52,53.18 207.22,52.48 207.22,51.8 207.52,51.49 v7(208.01,51.49)
  IN1 w0.076: v3(212.79,50.97) 212.77,50.97 212.43,51.32 211.85,51.32 211.37,50.83 208.67,50.83 v7(208.01,51.49)
  IN3 w0.102: v3(212.79,50.97) 212.73,50.97 209.42,47.66 209.42,43.41 207.97,41.97 207.97,40.75 200.55,33.33 200.55,31.66 200.78,31.43 200.78,29.02 200.78,29.02 200.78,28.06 200.55,27.83 200.55,16.08 197.83,13.36 197.83,12.44 194.94,9.55 193.24,9.55 190.85,7.16 180.64,7.16 179.51,6.03 159.27,6.03 156.87,8.43 151.25,8.43 149.94,9.75 141.04,9.75 138.93,7.64 129.77,7.64 129.39,7.26 129.39,6.92 129.14,6.66 128.71,6.66 128.49,6.44 112.01,6.44 111.51,6.94 106.95,6.94 106.16,7.73 98.65,7.73 98.22,7.3 95.09,7.3 94.66,7.73 94.05,7.73 93.39,7.07 74.25,7.07 72.8,8.52 70.63,8.52 69.75,9.4 65.8,9.4 65.31,9.89 56.34,9.89 52.98,6.54 49.9,6.54 48.91,5.55 43.57,5.55 42.64,6.47 42.64,8.15 39.16,11.63 39.16,14.51 v3(39.36,14.71)
  IN4 w0.076: v4(213.18,51.09) 213.07,50.97 v3(212.79,50.97) ; v3(39.36,14.71) 39.34,14.74 v4(39.34,15.4)
  BOTTOM w0.109: v4(39.34,15.4) R953.2
  BOTTOM w0.254: v4(213.18,51.09) 213.04,50.94 U34.N11
VOLUME_UP_SW#_C: length 14.4
  TOP w0.109: R1264.1 37.15,17.79 v1(37.15,18.14) 37.09,18.21 36.06,18.21 v2(36,18.14)
  BOTTOM w0.109: JVOL.1 35.1,10.16 35.27,10.33 37.22,10.33 37.64,10.75 DA6.3 37.64,15.34 R953.1 37.24,15.4 37.18,15.34 36.56,15.34 36.32,15.58 36.32,16.16 37.15,17 v1(37.15,18.14)
VOLUME_UP_SW#_DSP: length 4.2
  TOP w0.109: R1264.2 36.04,16.6 v2(35.81,16.84)
  TOP w0.254: UA1.20 37.91,15.04 37.7,15.25 37.7,16.53 R1266.2 R1264.2
VR_HOT#: length 41.2
  TOP w0.203: v6(98.08,58.11) 98.08,58.08 98.31,58.31 PU701.30
  IN1 w0.254: v6(98.08,58.11) 98.86,58.11 99.99,56.98 105,56.98 105.75,57.73 v1(107.44,57.73)
  IN3 w0.254: v1(107.44,57.73) 107.44,57.07 105.02,54.66 105.02,51.7 105.71,51.01 105.71,50.43 105.43,50.15 105.43,45.04 104.78,44.39 104.78,40.13 103.83,39.18 v1(100.91,39.18)
  BOTTOM w0.109: v6(98.08,58.11) 97.55,58.11 v2(97.26,57.82)
  BOTTOM w0.254: R265.2 105.02,40.19 104.6,40.61 103.02,40.61 102.81,40.41 102.81,39.52 102.47,39.18 v1(100.91,39.18)
VR_ON: length 17.4
  TOP w0.109: v2(117.57,58.85) 117.12,58.4 v7(116.96,58.4) RC151.1
  TOP w0.203: PU701.8 102.43,56.55 102.6,56.38 v7(103.17,56.38)
  IN1 w0.076: v7(103.17,56.38) 105,56.38 105.67,57.06 107.52,57.06 108.79,58.33 111.68,58.33 112.19,58.83 116.53,58.83 v7(116.96,58.4)
VR_ON_MCP: length 11.5
  TOP w0.109: RC151.2 118.42,57.89 118.94,58.42 v2(118.94,59.11) v7(118.94,59.93)
  IN1 w0.076: v3(126.4,59.37) 126.4,59.26 125.9,58.76 125.29,58.76 124.12,59.93 v7(118.94,59.93)
  IN4 w0.076: v4(126.78,59.34) 126.41,59.34 126.38,59.37 126.38,59.37 v3(126.4,59.37)
VR_SVID_ALRT#: length 24.5
  TOP w0.109: PU701.32 99,56.46 v1(99.1,56.36) 98.57,56.36 98.08,55.86 PR736.2
  IN4 w0.076: v4(118.36,54.54) 117.54,55.35 116.91,55.35 116.5,55.76 115.69,55.76 115.18,56.27 110.86,56.27 110.33,56.8 103.94,56.8 103.93,56.81 99.56,56.81 v1(99.1,56.36)
  BOTTOM w0.109: RC94.1 119.07,54.31 118.59,54.31 v4(118.36,54.54)
VR_SVID_CLK: length 29.5
  TOP w0.109: PU701.31 98.6,57.91 98.24,57.55 v1(98.24,57.23) 98.36,57.23 98.43,57.16 98.43,57.02 97.86,56.45 97.75,56.45 97.44,56.75 97.31,56.75 97.08,56.52 96.88,56.52 96.68,56.73 96.58,56.73 96.32,56.47 96.17,56.47 v2(95.92,56.73) 95.81,56.73 95.66,56.57 95.66,56.45 95.87,56.24 95.87,55.94 95.74,55.81 PR735.2
  IN4 w0.076: v4(117.18,54.08) 115.85,54.08 114.27,55.66 110.72,55.66 110.11,56.27 103.71,56.27 103.7,56.28 100.94,56.28 99.83,55.16 98.43,55.16 97.94,55.65 97.94,56.94 v1(98.24,57.23)
  BOTTOM w0.109: RC92.1 117.47,54.08 v4(117.18,54.08)
VR_SVID_DAT: length 35.2
  TOP w0.109: PR737.2 97.14,54.69 97.14,53.88 97.24,53.78 v2(97.43,53.78) 97.84,53.78 97.97,53.91 97.97,54.36 97.77,54.57 97.77,55.15 98.38,55.76 v6(99.33,55.76) 99.63,56.06 PU701.1
  IN4 w0.076: v6(99.33,55.76) 99.25,55.84 98.77,55.84 98.5,56.11 98.5,56.59 99.25,57.35 104.15,57.35 104.16,57.34 110.55,57.34 111.09,56.8 114.93,56.8 115.13,57.01 115.13,58.4 115.26,58.53 116.15,58.53 116.27,58.4 116.27,56.75 116.4,56.62 116.78,56.62 116.91,56.75 116.91,58.4 117.04,58.53 117.42,58.53 117.54,58.4 117.54,56.32 v4(117.09,55.86)
VREF: length 26.6
  TOP w0.203: PC717.1 96.4,59.34 PR726.2 97.44,59.51 PU701.27
  TOP w0.254: PR706.1 102.48,53.49 v6(102.75,53.22) 103.03,52.94 v2(103.89,52.94) 104.86,52.94 105.15,53.23 PR745.1 ; v6(95.62,59.42) PC717.1
  IN1 w0.254: v6(95.62,59.42) 101.42,59.42 102.1,58.73 104.41,58.73 105.11,58.03 v1(105.11,57.78)
  IN3 w0.254: v1(105.11,57.78) 105.16,57.73 105.16,56.59 102.75,54.18 v6(102.75,53.22)
  BOTTOM w0.203: PR701.1 PH701.1 PR704.1
  BOTTOM w0.254: PR704.1 105.81,58.48 v1(105.11,57.78)
VREF_CODEC: length 4
  TOP w0.203: UA2.41 25.74,20.27 v1(25.48,20.01)
  BOTTOM w0.109: CA39.2 26.78,19.19 v2(27.68,19.19)
  BOTTOM w0.254: v1(25.48,20.01) 25.83,19.67 CA39.2
VRP:
  vias: v1(23.06,20.02) v1(23.68,20.02) v2(24.26,20.15)
VRPG_MCP: length 15
  IN1 w0.076: v1(115.04,59.52) 115.04,59.6 116,60.56 116.54,60.56 117.1,60 118.38,60 118.76,60.38 124.76,60.38 124.91,60.54 125.7,60.54 v3(126.08,60.92)
  IN4 w0.076: v3(126.08,60.92) 126.26,60.74 126.92,60.74 127.56,61.38 v4(127.56,61.51)
  BOTTOM w0.109: v1(115.04,59.52) 115.04,59.15 RC152.2
VTTREF_+1.2V: length 6
  BOTTOM w0.109: PC609.1 100.77,38.5 v2(100.35,38.92)
  BOTTOM w0.203: PU601.4 97.23,36.36
  BOTTOM w0.254: 97.23,36.36 97.23,36.59 97.4,36.76 99.49,36.76 100.27,37.55 100.36,37.55 PC609.1
WAKE#: length 18.7
  TOP w0.109: v2(173.23,48.98) 173.64,48.57 v7(173.64,47.91) RH146.1 ; v7(170.43,47.43) 170.43,47.1 169.99,46.67 RH128.2 169.25,46.67 RH310.1
  IN1 w0.076: v7(173.64,47.91) 173.36,47.63 171,47.63 170.77,47.86 v3(170.71,47.86) 170.43,47.58 v7(170.43,47.43)
  IN4 w0.076: v4(161.18,46.39) 161.21,46.41 164.27,46.41 164.5,46.19 167.26,46.19 168.38,47.3 170.27,47.3 170.71,47.73 v3(170.71,47.86)
  BOTTOM w0.109: v4(161.18,46.39) 161.18,46.59 UCPU1.AJ5
WAKE_PCH#: length 73.3
  TOP w0.109: RH128.1 169.47,47.99 168.38,47.99 167.77,48.6 167.77,50.53 168.18,50.94 168.18,51.82 v7(167.97,52.03) ; v2(217.82,43.89) v7(217.51,44.2) 217.51,45.4 217.72,45.61 U676.2 ; v7(213,48.47) 213,47.72 211.37,46.09 211.37,44.95 v7(212.35,43.97)
  IN1 w0.076: v7(217.51,44.2) 217.46,44.15 216.96,44.15 216.27,44.84 214.72,44.84 213.96,44.08 213.33,44.08 213.12,43.87 212.44,43.87 v7(212.35,43.97) ; v7(213,48.47) 212.73,48.2 v3(212.53,48.2) 212.3,47.98 210.14,47.98 209.47,47.3 203.43,47.3 202.63,48.1 200.45,48.1 199.86,48.7 194.18,48.7 193.47,49.41 192.25,49.41 191.7,48.87 190.72,48.87 190.29,49.3 188.45,49.3 188.3,49.14 185.29,49.14 185,49.44 183.59,49.44 183.35,49.68 179.7,49.68 178.14,51.25 178.14,51.76 177.55,52.35 173.82,52.35 173.65,52.18 168.31,52.18 168.16,52.03 v7(167.97,52.03)
  IN4 w0.076: v3(212.53,48.2) 212.53,48.69 v4(212.57,48.73)
  BOTTOM w0.076: U34.L12 211.61,50.2 211.61,49.84
  BOTTOM w0.109: R604.2 213.45,48.73 v4(212.57,48.73) 212.31,48.73 211.61,49.42 211.61,49.84
WIN8_INT#: length 91.2
  IN1 w0.076: v3(210.97,55.79) 210.89,55.86 v7(210.56,55.86)
  IN2 w0.102: v3(210.97,55.79) 210.61,55.43 209.37,55.43 209.09,55.71 206.69,55.71 206.59,55.81 205.33,55.81 205.24,55.72 201.42,55.72 200.16,56.99 196.11,56.99 195.38,57.72 193.31,57.72 192.67,58.35 185.5,58.35 184.53,57.39 182.06,57.39 181.9,57.55 176.16,57.55 174.98,56.37 168.04,56.37 166.02,54.35 164.97,54.35 164.12,53.5 163.21,53.5 162.99,53.73 162.4,53.73 162.15,53.98 162.15,54.23 161.71,54.67 161.28,54.67 161.08,54.47 160.55,54.47 160.32,54.24 159.58,54.24 159.38,54.44 158.29,54.44 156.58,56.14 156.13,56.14 155.19,57.08 155.19,61.04 155.7,61.55 155.7,63.03 154.36,64.37 143.58,64.37 141.1,66.85 140.53,66.85 139.64,65.96 v1(139.64,65.57)
  IN4 w0.076: v4(210.1,55.15) 210.08,55.15 210.71,55.79 v3(210.97,55.79)
  BOTTOM w0.076: 209.86,54.5 209.86,54.91 v4(210.1,55.15)
  BOTTOM w0.109: U34.G4 209.86,54.5 ; JLVDS2.41 137.65,66.34 138.09,65.91 138.52,65.91 138.77,65.67 139.54,65.67 v1(139.64,65.57)
WL_OFF#: length 79.1
  TOP w0.109: Q344.3 225.75,49.38 225.95,49.59 225.95,51.14 226.17,51.35 226.43,51.35 226.93,51.85 v1(226.93,51.91)
  IN2 w0.102: v3(162.55,56.02) 162.6,56.07 163.48,56.07 164.78,57.36 165.54,57.36 167.22,59.04 168.42,59.04 169.16,58.3 174.13,58.3 175.94,60.11 175.94,60.55 176.71,61.32 180.57,61.32 183.46,64.22 185.9,64.22 186.54,64.87 196.67,64.87 197.32,64.22 198.31,63.23 199.36,63.23 199.97,62.62 199.97,62.44 201.94,60.48 201.94,60.3 204.14,58.1 212.63,58.1 213.01,57.72 214.2,57.72 214.47,57.98 216.2,57.98 219.12,55.06 223.7,55.06 226.17,52.59 226.26,52.59 v1(226.93,51.91)
  IN4 w0.076: v4(162.81,56.34) 162.81,56.3 162.55,56.04 v3(162.55,56.02)
WL_OFF#_R: length 32.7
  TOP w0.109: v1(228.94,41.17) 228.61,41.5 v2(228.61,43.35) 227.89,44.06 227.89,46.16 227.34,46.72 226.4,46.72 Q344.1 226.28,46.82 v1(226.28,49.21) 226.42,49.35 R1137.2
  BOTTOM w0.109: JNGFF1.48 226.25,49.24 v1(226.28,49.21) ; JNGFF2.56 244.9,41.49 243.76,40.34 243.13,40.34 240.75,37.96 230.44,37.96 228.94,39.47 v1(228.94,41.17)
WLAN_EN: length 5
  TOP w0.109: U718.3 233.78,48.32 D115.1 232.92,49.18 R1390.1 v2(232.92,51.93)
XCLK_BIASREF: length 3.9
  TOP w0.254: v1(148.86,63.81) 148.86,64.13 RH113.1
  BOTTOM w0.102: UCPU1.C26 148.18,61.41 147.9,61.68 147.9,61.95 148.46,62.51 148.46,63.03 148.57,63.14
  BOTTOM w0.203: v1(148.86,63.81) 148.86,63.43 148.57,63.14
XDP_BPM0#: length 34.1
  TOP w0.109: v1(109.19,70.37) 109.07,70.25 JXDP.21
  IN2 w0.102: v1(109.19,70.37) 109.19,70.61 110.21,71.62 119.84,71.62 121.71,69.76 122.81,69.76 124,68.57 124,67.55 125.11,66.44 125.11,60.77 125.47,60.41 126.1,60.41 126.84,59.67 126.84,59.34 127.35,58.83 127.35,58.07 v3(127.2,57.92)
  IN4 w0.076: 127.12,57.84 v3(127.2,57.92) ; 127.12,57.84 127.07,57.79 126.73,57.79 v4(126.78,57.84) 127.12,57.84
XDP_BPM1#: length 32.2
  TOP w0.109: JXDP.23 109.57,67.54 109.31,67.8 109.31,69.9 v7(109.78,70.37)
  IN1 w0.076: v7(109.78,70.37) 109.78,70.57 v3(109.92,70.72)
  IN2 w0.102: v3(126.26,58.58) 126.23,58.61 125.72,58.61 125.32,59.01 125.32,59.29 125.55,59.52 125.55,59.88 124.89,60.54 124.89,66.34 123.77,67.46 123.77,68.48 122.72,69.53 121.62,69.53 119.75,71.4 110.6,71.4 v3(109.92,70.72)
  IN4 w0.076: v4(126.49,58.9) 126.49,58.81 v3(126.26,58.58)
  BOTTOM w0.109: UCPU1.H60 126.72,58.67 v4(126.49,58.9)
XDP_DBRESET#: length 27.2
  TOP w0.109: C1237.1 RH451.1 RH367.1 118.34,54.67 119.18,54.67 119.61,55.1 v2(119.61,55.51) 119.61,57.32 120.16,57.86 120.16,59.12 121.76,60.71 121.76,63.56 120.92,64.39 120.92,68.64 120.22,69.33 115.66,69.33 115.31,69.68 115.31,70.53 115.57,70.8 JXDP.48
XDP_PIN60: length 26.7
  TOP w0.109: v1(118.73,50.88) 118.83,50.88 119.21,51.27 v2(119.21,53.58) 119.21,53.81 120.23,54.83 120.23,57.27 120.63,57.66 120.63,58.64 122.23,60.24 122.23,68.64 120.73,70.14 119.25,70.14 118.57,70.81 JXDP.60
  BOTTOM w0.109: R1198.1 118.73,50.29 v1(118.73,50.88)
XDP_PRDY#: length 46.7
  TOP w0.109: v1(105.41,67.92) 105.36,67.92 105.07,67.63 JXDP.5
  IN2 w0.102: v3(125.75,57.53) 125.77,57.51 127.52,57.51 127.98,57.97 127.98,58.5 128.24,58.76 128.24,59.75 125.34,62.64 125.34,66.53 124.22,67.65 124.22,68.77 122.14,70.85 120.94,70.85 119.94,71.85 105.55,71.85 104.27,70.58 104.27,69.58 105.41,68.45 v1(105.41,67.92)
  IN4 w0.076: v4(125.48,57.88) 125.75,57.61 v3(125.75,57.53)
  BOTTOM w0.102: v4(125.48,57.88) 125.48,57.76 125.32,57.59 124.67,57.59 124.67,57.59 124.22,57.59 124.06,57.76
  BOTTOM w0.109: T263.1 121.74,58.15 121.99,58.15 122.19,57.95 123.87,57.95 124.06,57.76 124.06,57.76
XDP_PREQ#: length 48.7
  TOP w0.109: v1(104.93,68.31) 104.93,68.02 104.57,67.67 JXDP.3
  IN2 w0.102: v3(125.13,57.54) 125.51,57.16 127.58,57.16 128.28,57.86 128.28,58.39 128.58,58.69 128.58,59.74 126.03,62.29 125.95,62.29 125.62,62.62 125.62,66.61 124.53,67.7 124.53,68.82 122.24,71.1 121.01,71.1 119.94,72.17 105.54,72.17 104.04,70.67 104.04,69.2 104.93,68.32 v1(104.93,68.31)
  IN4 w0.076: v4(125.48,57.13) 125.48,57.18 v3(125.13,57.54)
  BOTTOM w0.109: T264.1 121.65,56.74 122.31,56.74 122.5,56.93 123.76,56.93 123.81,56.88 124.41,56.88 124.45,56.84 125.19,56.84 v4(125.48,57.13)
XDP_PWRGD: length 12.2
  TOP w0.109: R1180.2 112.05,56.8 v2(112.05,57.67) 112.29,57.67 112.67,58.05 113.4,58.05 114.51,59.16 114.51,59.89 114.98,60.36 114.98,63.18 114.58,63.58 114.58,63.94 114.03,64.49 114.03,64.96 113.57,65.41 JXDP.39
XDP_TCK0: length 27.5
  TOP w0.109: v1(115.84,50.3) 116.06,50.3 116.44,50.68 116.44,51.51 115.27,52.68 v2(115.27,55.58) 115.27,57.38 116.01,58.12 116.14,58.12 117.56,59.53 117.56,64.55 118.07,65.06 JXDP.57
  BOTTOM w0.109: v1(115.84,50.3) 116.83,49.31 116.83,45.4 117.62,44.61 RH374.2 118.43,43.75 RH446.2 118.74,43.67 RH411.2
XDP_TCK1: length 31.5
  TOP w0.109: v1(115.84,50.88) 115.95,50.99 115.95,51.31 114.78,52.48 114.78,57.58 115.8,58.61 115.94,58.61 117.07,59.74 v2(117.07,64.07) 117.07,64.75 117.57,65.26 JXDP.55
  BOTTOM w0.109: RH373.2 119.27,43.42 118.84,42.99 116.4,42.99 116.2,43.19 114.67,43.19 114.32,43.54 114.32,44.9 116.34,46.92 116.34,49.11 115.36,50.09 115.36,50.4 v1(115.84,50.88)
XDP_TDI: length 38
  TOP w0.109: JXDP.56 117.57,70.75 v7(117.67,70.65) ; RH414.1 RH371.2 91.09,59.19 91.55,59.65 92.64,59.65 93.02,60.03 93.02,60.63 93.31,60.92 v1(93.31,62.31)
  IN1 w0.076: v7(117.67,70.65) 117.67,68.19 116.19,66.7 108.66,66.7 108.1,66.14 104.84,66.14 103.93,65.23 103.93,64.82 102.66,63.55 99.16,63.55 98.45,64.26 97.08,64.26 96.06,63.24 95.23,63.24 94.3,62.31 v1(93.31,62.31)
  BOTTOM w0.109: v1(93.31,62.31) v2(93.95,62.31)
XDP_TDI_SWITCH: length 5.5
  TOP w0.109: U663.8 88.45,61.02 88.58,61.15 89.02,61.15 89.29,60.88 v2(89.29,60.08) 89.29,59.01 RH414.2 90.34,57.96 RH413.2
XDP_TDO: length 71.7
  TOP w0.109: v7(89.45,57.36) 88.5,57.36 87.42,58.44 U663.6 ; JXDP.52 116.57,70.64 117.64,69.57 120.32,69.57 121.15,68.73 121.15,64.49 121.99,63.65 121.99,60.48 v2(121.48,59.97) 120.39,58.88 120.39,57.76 120,57.36 120,54.95 118.78,53.73 v1(118.78,51.49)
  IN1 w0.076: v1(118.78,51.49) 120.14,52.85 120.14,56.22 119.4,56.96 117.89,56.96 116.22,58.63 112.27,58.63 111.77,58.12 108.88,58.12 107.61,56.85 105.76,56.85 104.84,55.94 102.81,55.94 102.38,56.37 100.07,56.37 99.41,57.03 98.75,57.03 98.42,56.7 97.86,56.7 97.53,57.03 93.34,57.03 92.63,57.74 89.83,57.74 v7(89.45,57.36)
  BOTTOM w0.109: RH412.2 RH38.2 118.43,50.15 118.26,50.33 118.26,51.09 118.66,51.49 v1(118.78,51.49)
XDP_TMS: length 44
  TOP w0.109: JXDP.58 118.07,70.83 v7(118.26,70.65) ; v1(86.28,62.97) 86.42,62.84 U663.11
  IN1 w0.076: v1(86.28,62.97) 87.27,63.97 89.43,63.97 91.51,61.88 94.28,61.88 95.4,63 96.11,63 97.16,64.05 98.37,64.05 99.08,63.34 102.74,63.34 104.13,64.73 104.13,65.15 104.92,65.94 108.19,65.94 108.75,66.5 116.27,66.5 118.2,68.43 118.2,70.59 v7(118.26,70.65)
  BOTTOM w0.109: RH372.2 87.04,62.21 v1(86.28,62.97) 86.25,63 86.25,63.67 v2(86.62,64.04)
XDP_TRST#: length 46.9
  TOP w0.109: v7(117.09,70.65) 117.09,70.62 117.07,70.64 JXDP.54 ; v2(86.62,57.6) 86.16,58.06 v7(86.16,58.2) 85.83,58.53 85.83,58.91 85.92,59 U663.3
  IN1 w0.076: v7(117.09,70.65) 117.09,67.89 116.1,66.9 108.58,66.9 108.02,66.35 104.75,66.35 103.73,65.32 103.73,64.9 102.57,63.75 99.25,63.75 98.54,64.46 96.99,64.46 96.78,64.24 86.33,64.24 85.24,63.15 85.24,60.18 86.51,58.91 86.51,58.54 v7(86.16,58.2)
XTAL24_IN: length 5.3
  TOP w0.109: YH2.3 150.25,65.97 150.25,65.46 CH23.1 150.35,65.36 RH117.2 150.52,64.32 v1(150.52,63.86)
  BOTTOM w0.109: v1(150.52,63.86) 150.51,63.86 150.03,63.38 149.52,63.38 148.95,62.81 UCPU1.A25
XTAL24_OUT: length 8.5
  TOP w0.102: CH24.1 151.18,65.63 150.87,65.93 150.87,67.37 YH2.1
  TOP w0.109: CH24.1 151.26,65.28 RH117.1 151.09,64.32 151.09,63.94 v1(151.16,63.86)
  BOTTOM w0.109: UCPU1.B25 148.75,62.4 148.89,62.55 149.06,62.55 149.63,63.11 150.73,63.11 151.16,63.54 v1(151.16,63.86)
N13303482: length 4.3
  TOP w0.109: v2(199.09,17.14) 200.04,18.09 PC115.2
  TOP w0.254: PC115.2 200.67,18.61 PR124.1 200.67,19.31 201.47,20.11 PQ105.5
N13303498: length 5.5
  TOP w0.109: PQ105.6 202.12,21.49 v2(203.42,22.79)
  TOP w0.254: PC115.1 201.56,18.11 PR126.2 201.56,19.36 202.12,19.92 PQ105.6
N13303530: length 5.1
  TOP w0.109: v2(198.25,24.32) PC114.2 198.81,22.84 198.89,22.92 PR108.1 200.03,22.92 200.75,23.64 PQ104.2
N13303550: length 5.1
  TOP w0.109: PQ105.2 201.48,21.57 200.94,21.03 v2(199.57,21.03) 199.36,21.03 198.86,20.53 PR123.2 PR125.1
N13303636: length 9.7
  TOP w0.109: PQ106.2 201.11,26.77 200.01,27.87 199.4,27.87 196.76,25.23 196.76,25.21 v2(196.75,25.21) 196.57,25.02 196.57,24.25 195.8,23.48 195.47,23.48 PR110.2 PC116.1
N13305100: length 17.7
  TOP w0.109: PR105.1 27.31,66.41 27.31,67.93 v2(27.87,68.49)
  TOP w0.254: PR105.1 26.85,65.31 28.03,64.13 PQ101.1 28.03,62.81 26.5,61.27 26.5,58.73 v1(26.37,58.61)
  BOTTOM w0.254: PL102.2 30.85,57.01 30.56,56.73 27.61,56.73 27.07,57.27 27.07,57.69 26.37,58.38 v1(26.37,58.61)
N13305156: length 4.2
  BOTTOM w0.254: PQ103.6 106.23,1.87 106.08,2.03 106.08,2.35 106.25,2.52 107.08,2.52 PR121.1 PR120.2
N13305200: length 2.1
  BOTTOM w0.109: 105.19,2.52 104.29,2.52 PC113.1 PR119.2
N13305312: length 3.6
  BOTTOM w0.109: v2(104.41,4.19) 104.41,3.54 104.78,3.17 PQ103.3
  BOTTOM w0.254: PR122.2 106.46,4.21 105.42,3.17 PQ103.3
N13374678: length 1.1
  TOP w0.109: PR505.2 197.47,56.45 v2(197.92,55.99)
N13374846: length 2.4
  TOP w0.109: PR506.2 197.53,66.32 198.78,66.32 v2(198.99,66.53)
N17638789: length 6.9
  BOTTOM w0.109: R943.1 140,9.03 140,6.33 141.14,5.19 Q329.1 v2(141.67,3.16)
N17654244: length 8
  BOTTOM w0.109: Q326.1 142.22,9.94 R989.1 143.33,9.33 C1160.1 ; Q326.1 141.66,8.94 140.71,7.98 Q329.2 ; Q326.1 141.47,9.38 v2(139.82,11.03)
N18675747: length 2.5
  BOTTOM w0.109: MR226.2 215.23,51.95 215.51,52.24 215.51,53.37 215.21,53.68 MC284.1
N22841841: length 2
  TOP w0.109: v2(53.99,13.61) 54.41,13.61 55.21,12.81 R1331.1
N34287396: length 2.1
  TOP w0.109: v2(182.84,54.57) 182.89,54.62 MC94.1 183.5,56.12 MR256.1
N34514472: length 13
  BOTTOM w0.102: 159.81,40.06 159.81,41.56 160.1,41.86 160.51,41.86 160.9,42.25 160.9,42.91 161.51,43.52 UCPU1.AP4
  BOTTOM w0.109: 159.81,40.06 159.81,39.94 160.97,38.77 161.97,38.77 162.45,38.29 164.18,38.29 164.48,37.98 165.22,37.98 RH313.2
N34536136: length 4.9
  BOTTOM w0.109: T123.1 164.6,49.94 164.05,49.94 163.74,49.64 163.74,49.48 163.58,49.32 163.55,49.32 163.54,49.31 161.84,49.31 161.52,49.64 UCPU1.AD4
N35032609: length 8.9
  TOP w0.109: CH1206.1 164.45,51.47 164.19,51.21 164.19,49.13 164,48.94 v2(160.58,48.94) 160.36,48.94 v7(159.58,48.17)
  IN1 w0.076: v7(159.58,48.17) 159.73,48.32 v3(159.73,48.52)
  IN4 w0.076: v3(159.73,48.52) 159.73,48.65 v4(159.52,48.86)
N36180324: length 3.3
  TOP w0.109: RH346.2 151.13,47.35 150.83,47.06 CH1218.1 150.16,47.8 v2(150.42,48.07)
N39815594: length 5.3
  BOTTOM w0.102: UCPU1.H61 125.63,58.17 124.64,58.17 124.63,58.18 124.15,58.18
  BOTTOM w0.109: T226.1 121.8,59.04 122.66,58.18 124.15,58.18
N39815596: length 3.2
  BOTTOM w0.109: T227.1 123.1,58.62 123.87,58.62 124.11,58.38 124.68,58.38 124.71,58.35 125.2,58.35 UCPU1.H62
N39815598: length 7.2
  BOTTOM w0.102: 124.27,54.2 124.27,54.77 124.67,55.16 126.12,55.16 126.43,55.48 126.43,55.74 126.69,55.99 126.94,55.99 127.15,56.2 127.15,56.89 UCPU1.K59
  BOTTOM w0.109: T228.1 124.27,54.01 124.27,54.2
N39815600: length 4
  BOTTOM w0.109: T229.1 121.93,60.31 123.38,58.86 123.97,58.86 124.2,58.63 UCPU1.H63
N39815609: length 3.7
  BOTTOM w0.102: UCPU1.J61 125.7,57.41 124.59,57.41
  BOTTOM w0.109: T231.1 123.89,57.64 124.12,57.41 124.59,57.41
N39815611: length 8.1
  BOTTOM w0.102: 124.5,55.25 124.51,55.25 124.59,55.34 125.59,55.34 125.76,55.52 125.76,55.7 126.13,56.07 126.25,56.07 126.41,56.23 126.41,56.8 UCPU1.K60
  BOTTOM w0.109: 124.5,55.25 124.05,54.81 124.05,54.42 122.37,52.74 121.66,52.74 T230.1
N39955939: length 1
  BOTTOM w0.109: 36.09,14.09 36.44,14.09 v2(36.87,14.52)
N39956017: length 1.4
  BOTTOM w0.109: C1212.1 34.17,12.68 U664.12
N39956029: length 1.4
  BOTTOM w0.109: R1318.1 32.19,14.96 v2(31.97,15.17)
N39956087: length 1.3
  BOTTOM w0.109: C1214.1 34.97,12.6 U664.10
N40621945: length 3.3
  TOP w0.109: Q71.1 93.3,67.52 93.16,67.66 93.16,68.03 v1(93.14,68.05)
  BOTTOM w0.109: v1(93.14,68.05) 92.86,67.78 R536.2 93.41,67.27 v2(94.01,66.67)
N41001654: length 1.7
  TOP w0.203: C1230.1 193.71,50.01 193.22,50.5 192.83,50.5 192.8,50.47 U715.12
N41482702: length 3.9
  TOP w0.109: v2(233.88,70.21) 235.59,70.21 R1188.1 236.1,69.16 236.06,69.12 U671.8
N41500627: length 5
  TOP w0.254: U673.1 183.94,65.89 184.3,66.24 v1(184.3,66.35)
  BOTTOM w0.109: v2(181.79,68.54) 181.88,68.63 183.14,68.63 183.29,68.47 183.29,67.78 183.83,67.24 C1242.1
  BOTTOM w0.254: C1242.1 184.3,66.75 v1(184.3,66.35)
N41500629: length 3.2
  TOP w0.109: v2(186.47,63.56) 186.34,63.69 v1(185.5,63.69)
  TOP w0.254: v1(185.5,63.69) 185.38,63.56 U673.15
  BOTTOM w0.254: v1(185.5,63.69) 185.5,63.97 184.8,64.66 R1190.1
N41574995: length 3.6
  TOP w0.109: U677.8 230.1,69.15 230.13,69.18 R1204.1 229.57,70.26 v2(228.25,70.26)
N41624107: length 6.9
  TOP w0.109: R1233.2 215.87,48.9 R1232.2 ; R1232.2 v2(216.77,47.94) 216.77,47.19 216.87,47.09 R1338.1 R1202.1 217.48,46.08 217.66,46.26 U676.1 ; R1232.2 217.4,48.9 217.57,48.74 U709.4
N41625248: length 16.3
  TOP w0.109: Q347.2 224.42,48.37 224.42,46.58 224.11,46.28 224.11,45.55 223.54,44.99 223.54,43.08 223.08,42.62 220.86,42.62 220.08,43.4 v2(219.63,43.4) 219.41,43.18 217.56,43.18 215.95,44.78 C1246.1 R1202.2
N41869823: length 3.1
  TOP w0.109: v1(185.51,64.64) 185.83,64.96 v2(186.34,64.96)
  TOP w0.254: U673.17 185.21,64.56 185.29,64.64 v1(185.51,64.64)
  BOTTOM w0.254: C1244.1 185.51,64.99 v1(185.51,64.64)
N42153733: length 1.2
  TOP w0.109: R1330.1 v2(242.49,54.06)
N42557576: length 4.6
  TOP w0.109: U690.1 181.6,33.65 181.54,33.72 181.54,34.54 181.37,34.7 R1291.2 R1289.2 v2(183.38,35.58)
N42775202: length 6.1
  BOTTOM w0.109: v2(160.04,32.09) 161.59,32.09 RH24.1 162.64,32.18 163.96,32.18 165.18,30.96 Q351.3
N42993790: length 4
  TOP w0.109: v2(216.16,55.18) 216.16,54.71 216.74,54.12 217.6,54.12 R1131.1 219.26,54.59 U679.C2
N43167321: length 2.6
  TOP w0.109: v2(190.25,52.55) 190.62,52.18 191.37,52.18 U715.14
N43454026: length 4.6
  TOP w0.109: v2(169.02,65.56) 169.34,65.87 U719.14
  TOP w0.203: U719.14 168.58,66.53 R1326.1 168.31,67.29 168.67,66.93 U719.13
N44367556: length 1
  TOP w0.109: v6(193.04,48.74) 193.04,48.48 v2(193.58,47.94)
N44368114: length 3.3
  TOP w0.109: v2(194.98,48.14) 194.63,48.14 C1247.1
  TOP w0.203: C1247.1 193.66,49.12 193.66,49.13 193.19,49.59 192.79,49.59 192.71,49.67 U715.10
N44369635:
  vias: v1(188.89,48.9) v1(189.48,48.9) v2(188.92,49.44)
N44370994: length 1.8
  TOP w0.109: U716.12 243.86,52.24 244.79,53.17 C1257.1
N44372336: length 3
  TOP w0.109: R1319.1 244.81,50.87 245.01,50.67 246.18,50.67 246.77,50.08 v2(246.98,50.08)
N44373242: length 1.7
  TOP w0.109: U716.10 243.86,51.44 C1248.1
N44377351: length 2.7
  TOP w0.109: C1163.1 55.64,10.6 55.14,11.11 v2(54.98,11.11) 54.79,11.11 54.28,11.62 U717.12
N44380707: length 3.2
  TOP w0.109: v2(238.12,49.31) 238.8,48.62 C1202.1
  TOP w0.203: U718.12 238.79,48.32 C1202.1
N44531503: length 2.9
  TOP w0.109: U719.12 168.81,67.33 v7(168.72,67.41)
  IN1 w0.076: v3(169.12,67.5) 169.04,67.41 v7(168.72,67.41)
  IN4 w0.076: v4(168.63,67.35) 168.75,67.47 169.1,67.47 v3(169.12,67.5)
  BOTTOM w0.109: v4(168.63,67.35) 168.63,67.09 v2(169.35,66.38)
N44535135: length 2.9
  TOP w0.203: U719.10 168.14,68.13 v1(167.99,67.98)
  BOTTOM w0.109: v2(167.49,68.47) v1(167.99,67.98)
  BOTTOM w0.254: v1(167.99,67.98) 168.37,67.98 C1278.1
N44948988: length 4.3
  TOP w0.102: v1(149.51,18.73) 148.98,19.26 v2(147.81,19.26) 147.31,19.26 RD7.1
  BOTTOM w0.102: UD6.L8 149.12,19.12 v1(149.51,18.73)
N44951196: length 7.2
  TOP w0.102: RD8.1 157.09,21.13 v1(157.25,21.29)
  TOP w0.109: RD8.1 v2(155.92,20.44)
  BOTTOM w0.102: UD7.L8 160.63,19.12 160.27,18.76 158.95,18.76 157.95,19.77 157.95,20.46 157.25,21.16 v1(157.25,21.29)
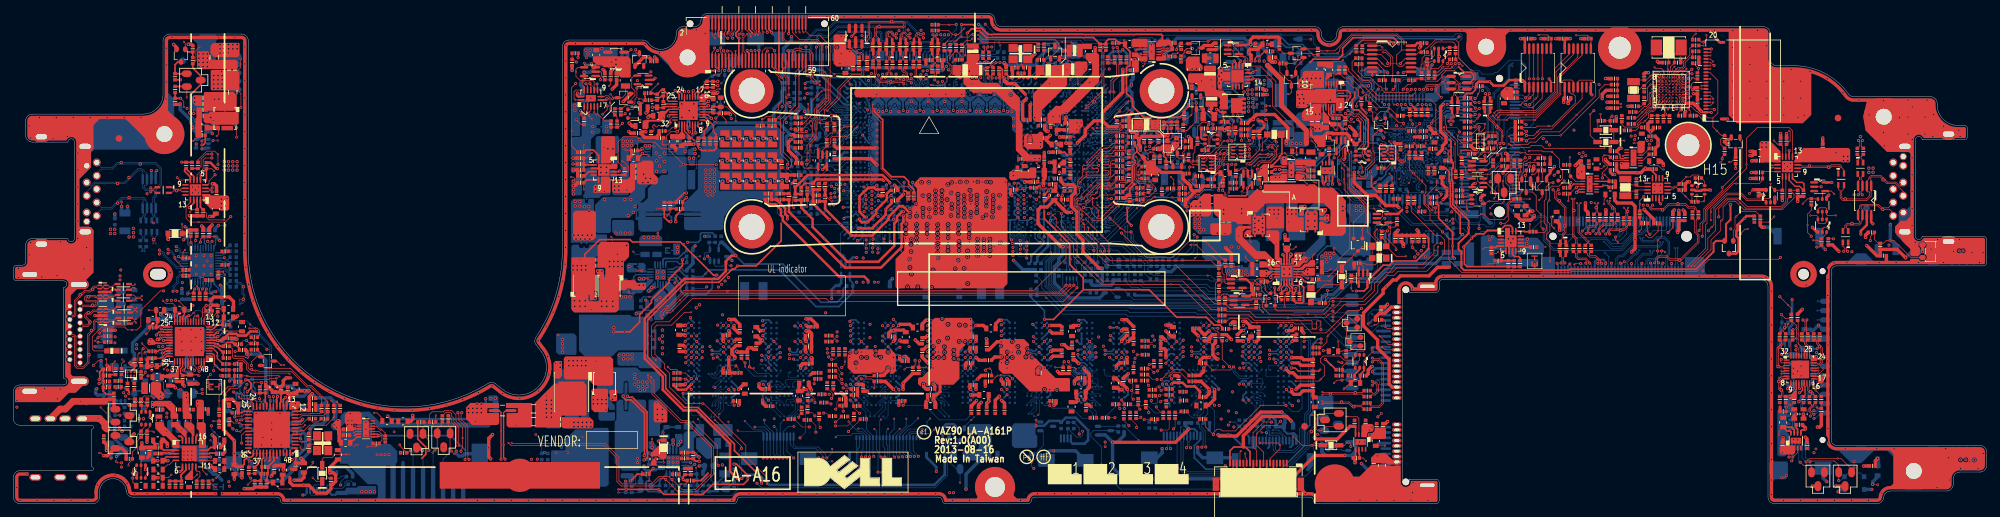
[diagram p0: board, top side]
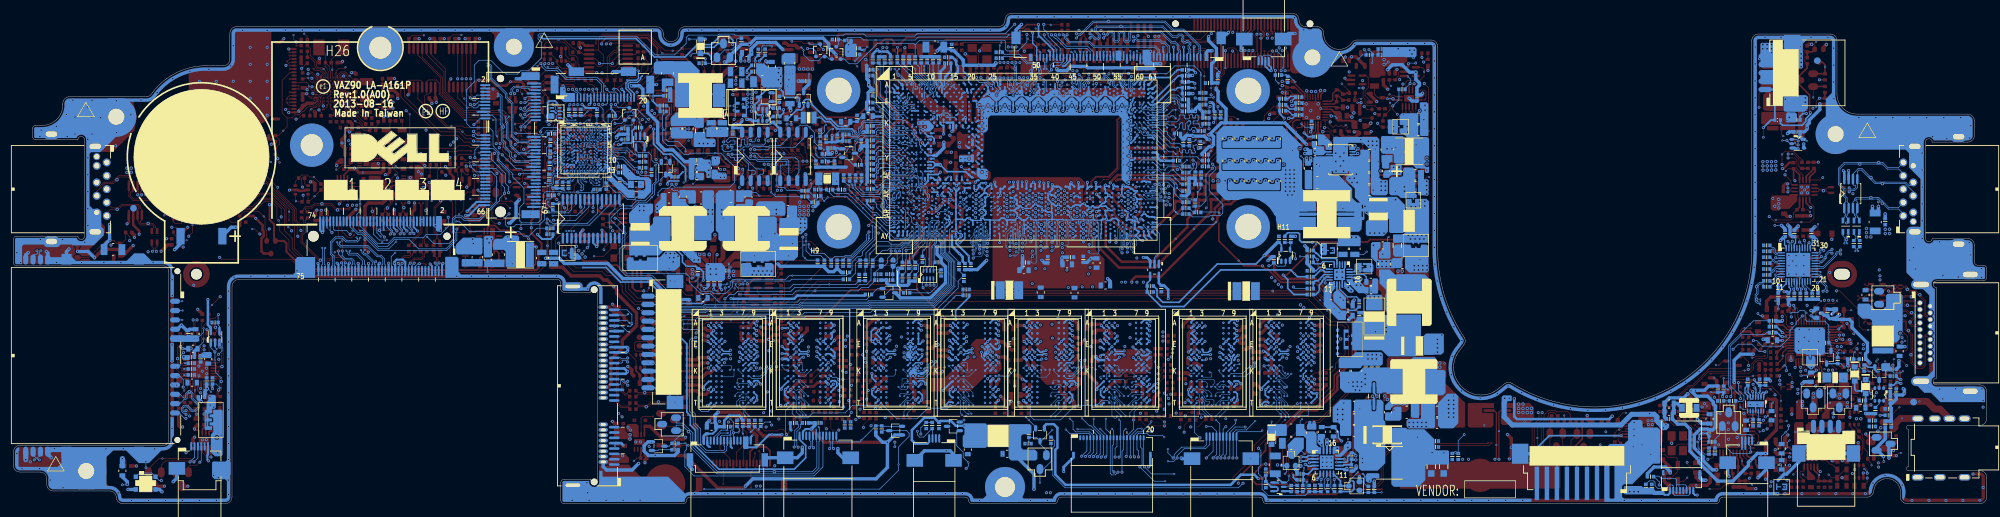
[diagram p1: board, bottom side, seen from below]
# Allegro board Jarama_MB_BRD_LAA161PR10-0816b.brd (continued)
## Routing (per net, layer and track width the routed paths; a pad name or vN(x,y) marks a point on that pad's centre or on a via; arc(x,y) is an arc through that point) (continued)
N44953884: length 4.7
  TOP w0.102: RD11.1 174.64,19.62 173.52,19.62 v2(173.16,19.26) 173.16,18.9 v1(173.34,18.72)
  BOTTOM w0.102: v1(173.34,18.72) 173.34,18.71 173.35,18.71 173.74,19.1 UD9.L8
N44956010: length 11.3
  TOP w0.109: v2(179.48,26.28) 179.9,25.87 180.17,25.87 180.41,25.62 180.41,24.86 180.85,24.42 RD12.1 180.9,21.63 v1(182.01,20.53)
  BOTTOM w0.102: UD10.L8 185.12,19.12 184.77,18.76 183.46,18.76 182.55,19.67 182.55,19.97 182.01,20.51 v1(182.01,20.53)
N44984260: length 4.8
  TOP w0.102: v1(101.45,18.73) 100.59,19.6 RD1.1
  TOP w0.109: RD1.1 99.26,20.1 98.34,20.1 v2(97.94,20.51)
  BOTTOM w0.102: v1(101.45,18.73) 101.84,19.12 UD1.L8
N44985933: length 6
  TOP w0.102: v1(110.14,20.51) 110.14,21.51 RD2.1
  TOP w0.109: v2(110.8,20.3) 110.35,20.3 v1(110.14,20.51)
  BOTTOM w0.102: UD2.L8 113.41,19.17 113.07,19.51 111.34,19.51 110.34,20.51 v1(110.14,20.51)
N44994261: length 3.7
  TOP w0.102: v1(126.89,18.71) 126.91,18.68 128.46,18.68 RD5.1
  TOP w0.109: RD5.1 v2(128.82,17.3)
  BOTTOM w0.102: UD4.L8 126.51,19.12 126.88,18.76 126.88,18.72 126.88,18.71 126.88,18.71 v1(126.89,18.71)
N44996448: length 7.5
  TOP w0.102: RD6.1 134.94,20.77 v1(134.94,21.5)
  TOP w0.109: v2(133.34,20.11) 133.67,20.44 RD6.1
  BOTTOM w0.102: UD5.L8 138.05,19.09 137.7,18.73 136.87,18.73 135.08,20.53 135.08,21.36 v1(134.94,21.5)
N45067794: length 3.3
  TOP w0.102: CD91.2 116.57,45.98 116.57,44.56 v5(116.8,44.33)
  TOP w0.381: RD23.1 115.22,46.49 CD91.2
N45067802: length 1.9
  TOP w0.102: v2(118.8,44.53) CD92.2
  TOP w0.381: CD92.2 RD24.1
N45067875: length 2.3
  TOP w0.102: v2(122.56,45.32) 122.38,45.32 CD89.2
  TOP w0.381: CD89.2 RD16.1
N45134129: length 2.1
  TOP w0.102: RD79.1 100.51,18.71 v1(100.57,18.65)
  TOP w0.109: v2(101.05,18.42) 100.82,18.65 v1(100.57,18.65)
  BOTTOM w0.102: v1(100.57,18.65) 101.04,19.12 UD1.L9
N45134345: length 5.8
  TOP w0.102: RD80.1 108.96,21.64 v1(109.5,21.1)
  TOP w0.109: v1(109.5,21.1) v2(109.5,20.56)
  BOTTOM w0.102: UD2.L9 110.84,19.12 109.58,20.39 109.58,21.02 v1(109.5,21.1)
N45134724: length 3.7
  TOP w0.102: v1(126.11,18.72) 126.61,19.22 127.43,19.22 v2(127.62,19.03) 128.63,19.03 RD81.1
  BOTTOM w0.102: v1(126.11,18.72) 125.7,19.12 UD4.L9
N45134937: length 5.3
  TOP w0.102: RD82.1 135.5,21.31 v1(135.61,21.43)
  TOP w0.109: RD82.1 v2(136.55,20.44)
  BOTTOM w0.102: v1(135.61,21.43) 135.59,21.4 135.59,20.37 136.84,19.12 UD5.L9
N45136338: length 5.1
  TOP w0.102: v1(145.46,20) 145.7,20.25 v2(146.12,20.25) 146.37,20 RD83.1
  BOTTOM w0.102: v1(145.46,20) 146.34,19.12 UD6.L9
N45136742: length 5.5
  TOP w0.102: RD84.1 157.98,21.21 v1(157.89,21.3)
  TOP w0.109: RD84.1 158.75,20.44 v2(159.01,20.18)
  BOTTOM w0.102: v1(157.89,21.3) 158.32,20.88 158.32,19.86 159.06,19.12 UD7.L9
N45137119: length 6.5
  TOP w0.102: v2(174.87,20.11) 173.68,20.11 173.16,19.59 172.78,19.59 v1(171.78,18.59) ; RD85.1 175.21,19.94
  TOP w0.109: 175.21,19.94 175.05,20.11 v2(174.87,20.11)
  BOTTOM w0.102: UD9.L9 172.72,18.9 172.08,18.9 171.81,18.63 171.81,18.59 v1(171.78,18.59)
N45137332: length 7.5
  TOP w0.109: v1(182.6,20.51) 182.12,20.04 v2(179.47,20.04) RD86.1
  BOTTOM w0.102: UD10.L9 183.51,19.12 182.83,19.8 182.83,20.27 182.6,20.51 v1(182.6,20.51)
N45346908: length 3.2
  TOP w0.109: v2(51.56,8.82) 51.21,8.82 50.95,8.56
  TOP w0.203: U717.6 51.36,10.42 51.19,10.24 51.01,10.24 ; R1305.2 50.79,9.51 50.93,9.51 51.44,10.02 U717.7
N45346942: length 5.1
  TOP w0.109: U717.10 54.7,10.82 55.15,10.37 55.15,9.43 C1281.1 54.25,8.53 v2(52.9,8.53)
N45347302: length 1.5
  TOP w0.109: R1128.1 238.25,45.79 238.05,45.6 v2(238.05,44.89)
N45347364: length 2.1
  TOP w0.203: C1292.1 238.54,47.7 v2(237.92,47.7) 237.9,47.7 237.73,47.52 U718.10
N45348400: length 1.3
  TOP w0.109: v2(238.09,50.61) 237.7,50.21 R1226.1
N45705313: length 2.2
  TOP w0.254: R34.1 30.27,7.59 v2(29.43,7.59) 29.34,7.5 U4.13
N46229337: length 5.6
  TOP w0.109: RR9.2 267.1,27.38 267.1,24 267.44,23.66 v2(267.44,23.48) 267.6,23.32 U1.28
N46231209: length 3.8
  TOP w0.109: v2(25.25,41.89) D111.1
  TOP w0.508: D111.1 25.76,40.5 26.22,40.95 RV28.1 RV29.1
N46238153: length 3
  BOTTOM w0.109: v2(173.72,56.8) 173.91,56.61 173.91,55.76 174.57,55.1 MC95.1 174.62,55.04 174.62,54.28 MR257.1
N46249068: length 4.2
  TOP w0.109: v2(265.77,55.89) 265.89,55.76 265.89,54.42 R1118.1 265.25,53.77 US1.15
N46249084: length 6.7
  TOP w0.203: US1.8 266.25,48.78 266.86,48.17 267.73,48.17 v2(267.98,47.93) 267.98,47.06 R1165.1 267.29,47.58 266.63,47.58 265.75,48.46 US1.7
N46249102: length 3.2
  TOP w0.109: v2(263.45,54.44) 264.01,53.88 R1117.1 264.75,53.6 US1.16
N46483813: length 29.7
  TOP w0.109: v7(227.65,51.47) 227.98,51.8 R1256.1 ; v1(230.22,42.93) 230.22,41.68 v2(230.59,41.31)
  IN1 w0.076: v7(227.65,51.47) 227.65,51.17 227.93,50.89 227.93,50.3 228.87,49.36 228.87,46.03 230.49,44.42 230.49,43.2 v1(230.22,42.93)
  BOTTOM w0.109: v1(230.22,42.93) 230.22,41.52 231.41,40.33 233.51,40.33 233.98,39.86 238.35,39.86 239.19,39.02 240.78,39.02 243.4,41.64 JNGFF2.50
N46487566: length 3.8
  TOP w0.109: v1(226.37,50.82) 226.68,51.13 v2(227.01,51.13) 227.99,51.13 R1255.1
  BOTTOM w0.109: JNGFF1.42 226.29,50.74 v1(226.37,50.82)
N46493858: length 6.6
  TOP w0.109: v1(244,46.03) 243.39,45.42 v2(243.39,44.9) R1243.1
  BOTTOM w0.109: JNGFF2.52 243.9,43.36 243.43,43.84 243.43,45.46 v1(244,46.03)
N46563920: length 1.9
  BOTTOM w0.109: RA16.2 16.07,14.99 QA1.5 QA1.6
N46563950: length 8.2
  BOTTOM w0.109: QA1.2 Q6.1 17.39,19.87 RA57.2 19.03,20.56 RA18.2 CA74.1 19.89,22.61 v2(19.73,22.78)
N46564129: length 4.2
  TOP w0.109: UA3.B1 19.07,19.72 RA44.2 RA23.2 19.11,20.77 18.64,21.24 18.64,22.35 v2(18.88,22.59)
N46564153: length 2.3
  TOP w0.109: UA3.B3 16.71,19.72 CA30.1 16.19,20.96 v2(16.54,21.32)
N46564161: length 1.2
  TOP w0.109: RA21.2 18.04,18.08 18.04,19.17 UA3.A1
N46564163: length 1.2
  TOP w0.109: UA3.A3 17.09,18.05 RA22.2
N46564471: length 9.1
  TOP w0.109: CA48.1 CA47.1 R7.1 RA31.2 RA33.2 33.13,17.75 32.9,17.52 32.1,17.52 30.79,16.21 v2(30.79,15.43) RA56.2
N46564600: length 2.1
  TOP w0.109: T254.1 23.68,21.32 UA2.37
N46564857: length 5.2
  TOP w0.109: CA23.1 33.71,25.83 33.66,25.88 v2(31.98,25.88) 31.29,25.88 31.1,26.07 30.28,26.07 29.91,25.7 UA2.10
N46564859: length 3
  TOP w0.102: v2(26.97,28.61) 26.54,28.18 v1(26.27,28.18)
  TOP w0.203: UA2.20 25.74,27.85 26.07,28.18 v1(26.27,28.18)
  BOTTOM w0.254: v1(26.27,28.18) 25.95,27.86 CA51.1
N46565041: length 3.5
  TOP w0.109: v2(24.78,30.36) 25.58,29.56 CA44.1
  TOP w0.203: UA2.21 25.34,28.09 25.58,28.33 CA44.1
N46565056: length 4.6
  TOP w0.109: CA44.2 24.19,29.7 23.86,30.03 22.79,30.03 v2(22.38,30.44)
  TOP w0.203: CA44.2 24.19,28.66 24.14,28.62 UA2.24
N46565215: length 3.3
  TOP w0.109: v2(17.27,15.71) 17.29,15.68 RA37.2 19.11,14.79 RA39.1 19.16,14.72 QA3.3
N46565224: length 4.7
  TOP w0.109: v2(21.02,15.78) 20.67,16.14 19.56,16.14 RA39.2 19.75,15.03 19.79,15.03 CA38.1 20.06,14.38 19.81,14.13 QA3.2
N46974230: length 28.1
  TOP w0.109: 207.77,68 207.77,69.41 207.02,70.15 200.36,70.15 198.51,68.3 198.51,67.85 v2(198.18,67.52) 195.43,67.52 R990.1 194.44,67.31 194.23,67.52 Q136.1 190.07,67.52 R163.1 ; 207.77,68 207,67.24 207,65.9 207.36,65.54 207.83,65.54 208.34,66.05 U23.10 ; 207.77,68 U23.13
N46974405: length 31.5
  TOP w0.109: U23.4 204.13,66.7 204.85,65.98 v7(204.86,65.98) 204.86,65.98 205.32,65.51 205.85,65.51 206.1,65.77 206.1,66.91 205.36,67.65 v8(205.01,67.65) ; v8(204.88,68.36) 204.59,68.65 U23.1 ; R162.1 189.53,66.26 R988.1 189.53,64.69 190.79,63.43 191.06,63.43 191.24,63.25 v7(191.24,62.66) 191.24,61.65 190.98,61.39 v2(190.75,61.39)
  GND1 w0.076: v8(204.88,68.36) 204.91,68.33 204.91,67.75 v8(205.01,67.65)
  IN1 w0.076: v7(204.86,65.98) 204.64,65.77 203.96,65.77 203.63,65.44 201.9,65.44 201.57,65.77 200.88,65.77 199.82,64.7 199.82,64.03 199.42,63.64 198.01,63.64 197.39,64.26 192.84,64.26 v7(191.24,62.66)
N47176858: length 271.2
  TOP w0.109: Q136.3 195.17,68.17 R990.2 195.55,67.88 v2(196.64,67.88) 197.76,67.88 200.26,70.39 207.12,70.39 208.11,69.41 208.11,68.98 v7(208.12,68.97) ; RH420.2 36.51,24.04 RH419.2 R31.2 37.07,22.51 Q134.2 36.38,22.02 35.63,21.27 v1(35.63,20.71)
  IN1 w0.076: v7(208.12,68.97) v3(208.6,68.97)
  IN2 w0.102: v3(203.36,67.71) 206.81,67.71 208.07,68.97 v3(208.6,68.97)
  IN3 w0.102: v1(35.63,20.71) 35.96,20.71 37.33,19.34 40.05,16.62 40.05,16.03 41,15.08 41,14.19 42.35,12.85 42.35,9.5 42.54,9.3 43.76,9.3 43.94,9.13 43.94,6.58 44.28,6.23 48.51,6.23 50.69,8.42 53.89,8.42 56.05,10.57 65.59,10.57 66.07,10.09 70.02,10.09 71.14,8.97 72.99,8.97 74.21,7.76 93.06,7.76 95.6,10.3 107.61,10.3 109.57,8.34 126.27,8.34 127.86,9.93 138.76,9.93 139.76,10.93 150.05,10.93 151.12,9.86 157.29,9.86 159.97,7.17 179.04,7.17 180.17,8.3 190.7,8.3 192.98,10.57 193.43,10.57 197.58,14.72 197.58,25.8 198.75,26.97 198.75,33.79 204.77,39.81 204.77,42.88 205.29,43.4 205.29,48.17 205.83,48.71 205.83,50.81 205.73,50.91 205.73,51.77 206.22,52.26 206.22,53.65 207.28,54.72 207.28,55.48 206.17,56.6 206.17,58.54 206.47,58.84 206.47,60.15 204.97,61.65 204.97,63.48 204.88,63.57 204.88,66.45 203.62,67.71 v3(203.36,67.71)
N47395773: length 4.5
  TOP w0.109: v2(85.36,53.79) PR428.2
  TOP w0.254: PR428.2 85.71,53.03 86.77,53.03 87.58,52.22 PU405.4
N47396645: length 2.9
  TOP w0.109: PR434.1 220.22,38.41 v2(219.94,38.13)
  TOP w0.254: PU406.4 222.03,38.6 221.84,38.41 PR434.1
N47396970:
  vias: v2(229.27,38.49) v6(226.47,39) v6(226.57,39.66)
N47421956: length 3.6
  TOP w0.109: v2(105.7,62.16) 105.31,62.16 105.11,61.96 104.3,61.96 103.07,60.73 PU701.16
N47421967: length 4.4
  TOP w0.203: v6(104.01,59.67) 103.84,59.51 PU701.14
  BOTTOM w0.203: PH701.2 104.26,59.16 PR709.1 PC709.1 103.4,60.05 103.78,59.67 v6(104.01,59.67)
N47422029: length 3.8
  TOP w0.203: PU701.4 100.83,56.06 v6(101.16,55.74)
  BOTTOM w0.109: v2(102.56,56.96) 102.03,56.42 PR721.1
  BOTTOM w0.203: v6(101.16,55.74) 101.02,55.88 PR721.1
N47422048: length 2.2
  TOP w0.109: v2(97.82,43.16) 98.29,43.63 PH702.2
  TOP w0.254: PR708.1 99.18,44.23 PH702.2
N47422075: length 7
  TOP w0.109: PR702.1 v2(96.35,44.23)
  TOP w0.254: PR702.1 97.4,42.95 98.06,42.29 98.35,42.29 v6(98.37,42.27)
  BOTTOM w0.254: v6(98.37,42.27) 98.49,42.4 98.49,42.91 98.01,43.39 PL701.2
N47422085: length 3.1
  TOP w0.203: PU701.2 100.03,55.07 PR725.1 PC715.1
N47422365: length 2.9
  BOTTOM w0.109: PC712.2 102.25,50.29 102.25,51.75 v2(102.58,52.08)
N47422375: length 3
  TOP w0.109: v2(95.08,52.1) 94.84,52.34 94.28,52.34 v6(94.13,52.5)
  TOP w0.254: PR715.2 94.13,52.45 v6(94.13,52.5)
  BOTTOM w0.203: PU702.6 94.28,52.34 v6(94.13,52.5)
N47422428: length 2.4
  TOP w0.109: v2(91.47,53.15) 91.66,52.95 PC711.2
  TOP w0.508: PR715.1 92.5,52.22 PC711.2
N47422430: length 2.9
  TOP w0.109: v2(93.38,53.96) 93.38,53.06 PC711.1
  TOP w0.254: v6(94.07,53.22) 94.07,53.16 93.87,52.95 PC711.1
  BOTTOM w0.203: PU702.7 94.54,52.74 94.07,53.21 v6(94.07,53.22)
N47423101: length 2.1
  TOP w0.109: PC724.1 94.2,60.49 94,60.69 v2(93.61,60.69)
  TOP w0.203: PC724.1 94.54,60.99 94.48,61.06 PR744.2
N47902580: length 2.6
  BOTTOM w0.109: T244.1 203.38,25.76 204.28,26.66 JSATA1.45
N47902593: length 2.4
  BOTTOM w0.109: JSATA1.47 203.48,27.46 T245.1
N47902613: length 2.1
  BOTTOM w0.109: T246.1 203.47,28.26 JSATA1.49
N47972075: length 1.3
  TOP w0.254: U721.6 196.92,52.35 C407.1
N47972306: length 2.7
  TOP w0.109: v2(194.25,54.43) 194.82,53.86 194.82,53.58 195.76,52.64 R1379.1
N47973312: length 5.5
  TOP w0.109: R1380.1 264.2,10.83 v2(264.2,10.23)
  TOP w0.254: U720.7 266.51,11.05 266.08,11.48 R1380.1 265.44,10.89 265.88,10.89 266.01,10.77 U720.8
N47973343: length 1.4
  TOP w0.254: C1300.1 266.81,11.36 267.01,11.16 U720.6
N48312843: length 2.9
  BOTTOM w0.109: v2(21.27,20.46) 21.8,20.99 RA41.2
  BOTTOM w0.203: Q107.1 23.93,20.99 RA41.2
N48433973: length 1.8
  TOP w0.109: v2(208.72,46.82) MR976.2 MC1141.1
N48463842: length 4.6
  TOP w1.016: 13.98,11.18 13.71,11.45 13.71,11.96 12.89,12.78 v2(12.66,12.78) 10.33,12.78 JHP1.5
N48664246: length 1.2
  TOP w0.109: v2(26.93,54.36) PR206.1
N48664254:
  vias: v2(29.9,57.44) v6(29.53,57.89)
N48664258:
  vias: v2(69.14,12.3) v6(31.57,51.29) v6(31.57,50.66) v6(31.55,50.02) v6(32.2,51.27) v6(32.2,50.63) v6(32.19,50) v6(32.84,51.27) v6(32.84,50.63) v6(32.82,50) v6(33.48,51.27) v6(33.48,50.63) v6(33.47,50) v6(68.12,14.28) v6(68.12,13.65) v6(68.75,14.28) v6(68.75,13.65) v6(69.39,14.93) v6(69.39,14.28) v6(69.39,13.65) v6(70.03,14.93) v6(70.02,14.28) v6(70.02,13.65)
N48664262: length 1.3
  TOP w0.109: PQ201.2 30.7,55.37 v2(30.44,55.1)
N48664277: length 1.9
  BOTTOM w0.109: v2(102.05,7.43) 102.72,8.1 PR209.2
N48664377:
  vias: v2(79.79,16.14) v6(79.76,15.5) v6(79.76,14.87) v6(79.76,14.23) v6(79.76,13.6) v6(79.77,12.96) v6(80.51,15.5) v6(80.51,14.87) v6(80.51,14.23) v6(80.51,13.6) v6(80.51,12.96)
N48664598: length 6.4
  TOP w0.109: v2(97.3,10.69) PD202.1
  TOP w0.254: v1(96.51,9.38) 96.61,9.47 PD202.1
  BOTTOM w0.254: v1(96.51,9.38) 97.02,9.89 97.02,10.78 PR211.2 PC218.1
N48665076: length 2.3
  TOP w0.254: v1(92.35,3.39) v2(92.93,3.96) 93.39,4.43 PR230.2
N48665187: length 6.1
  BOTTOM w0.109: v2(94.06,4.72) 95.46,3.32 PQ204.1
  BOTTOM w0.254: PQ204.1 96.63,2.65 PR224.1 96.7,3.4 97.74,4.43 PU201.10
N48665195: length 3.4
  BOTTOM w0.109: PQ204.2 93.54,1.68 PC229.2 PR225.1 v2(90.54,1.68)
N48665393: length 1.3
  BOTTOM w0.109: PD201.1 v2(107,12.29)
N48680306: length 2
  TOP w0.109: v1(153.45,50.52) 153.45,50.72 T280.1
  BOTTOM w0.109: UCPU1.AC20 153.04,50.11 v1(153.45,50.52)
N48727395: length 5.5
  TOP w0.254: C1227.1 181.1,57.51 Q360.4 180.62,58.68 180.22,59.09 v1(180.05,59.09)
  BOTTOM w0.254: v1(180.05,59.09) 180.05,58.58 R1383.2 180.94,58.4 180.94,59.03 R1382.2
N48727429: length 3
  BOTTOM w0.254: Q361.3 183.71,59.3 183.71,59.67 183.53,59.85 182.37,59.85 181.81,59.29 R1382.1
N48727431: length 1.3
  BOTTOM w0.254: Q361.6 182.37,57.38 181.7,58.05 R1383.1
N48850801:
  vias: v2(190.81,42.22) v6(190.68,44.05) v6(190.68,43.42) v6(191.32,44.05) v6(191.32,43.42) v6(191.95,44.05) v6(191.95,43.42)
N48850817: length 2.8
  TOP w0.203: 192.72,33.87 192.6,33.98 PU301.6
  TOP w0.254: 192.72,33.87 v2(193.2,33.38) 193.33,33.26 194.06,33.26 194.42,33.61 PR344.2
N48850937:
  vias: v2(189.08,42.76) v6(188.03,44.05) v6(188.03,43.42) v6(188.66,44.05) v6(188.66,43.42) v6(189.3,44.05) v6(189.3,43.42)
N48851279: length 3.5
  TOP w0.203: v1(189.3,32.06) 189.35,32.06 189.36,32.05 189.36,32.38 189.76,32.77 PU301.1
  BOTTOM w0.109: v2(188.46,32.98) 188.64,32.8 PR318.1
  BOTTOM w0.254: PR318.1 189.55,32.32 v1(189.3,32.06)
N48851283: length 3.9
  TOP w0.109: PU301.20 188.85,33.98 188.15,33.28 PR345.1 187.17,33.75 186.19,33.75 v2(185.81,33.37)
N48851285: length 2.7
  TOP w0.203: PR311.2 192.46,32.52 192.27,32.71 191.54,32.71 191.36,32.9 PU301.5
N48851436: length 3.2
  TOP w0.203: PU301.19 188.45,34.38 188.18,34.11 v6(188.18,33.93)
  BOTTOM w0.109: v2(188.21,35.95) PR351.1
  BOTTOM w0.203: PR351.1 188.21,33.95 v6(188.18,33.93)
N49081818: length 1.4
  TOP w0.109: R1389.1 v2(205.25,8.68)
N49081850: length 2.5
  TOP w0.109: C1304.1 201.99,6.84 v2(202.42,6.41)
  TOP w0.254: C1304.1 201.43,7.48 201.36,7.55 U724.6
N49122205: length 4.1
  TOP w0.109: v2(226.93,45.68) R1212.1 225.48,46.43 225.77,46.72 v1(225.77,47)
  BOTTOM w0.109: v1(225.77,47) 225.52,46.74 JNGFF1.58
N49301602: length 4.3
  TOP w0.109: v2(190.24,29.55) 190.24,31.08 190.66,31.51 PR335.2
  TOP w0.203: PU301.3 190.56,32.75 191.04,32.27 191.04,31.85 PR335.2
N49301672: length 3.4
  TOP w0.109: PC342.1 191.56,38.15 v2(191.93,38.51)
  TOP w0.203: 190.56,36.84 PU301.13
  TOP w0.254: PC342.1 190.56,36.84
N49308388: length 3
  BOTTOM w0.109: PR239.2 99.13,2.32 99.13,3.64 98.74,4.03 PU201.8
N49308391: length 2.9
  BOTTOM w0.109: PR240.2 98.14,2.35 98.14,3.95 98.24,4.04 PU201.9
N49379203: length 1.7
  TOP w0.109: v2(29.93,12.38) CA58.2 RA56.1
N49466651: length 34.6
  IN4 w0.076: v1(135.43,7.11) 135.04,7.5 126.31,7.5 124.85,6.04 113.62,6.04 v1(112.81,6.85)
  BOTTOM w0.109: v2(109.45,12.38) 110.78,11.06 112.31,11.06 112.76,10.61 JKB1.9 112.76,6.9 v1(112.81,6.85) ; v1(135.43,7.11) 135.43,7.13 134.65,7.91 JKB2.3
N49718258: length 3.9
  TOP w0.109: v2(268.93,43.2) 269.88,43.2 270.06,43.03 Q366.3 270.06,42.15 270.19,42.02 271.12,42.02 271.36,42.26 Q366.1
N49718282: length 4.1
  TOP w0.109: Q367.1 270.06,44.13 270.29,44.36 271.2,44.36 271.36,44.2 Q367.3 271.36,43.35 271.49,43.21 v2(272.71,43.21)
N49718310: length 2.6
  TOP w0.109: v2(269.36,39.48) 270.35,39.48 R1.2 271.36,40.49 Q366.6
N49718360: length 2.6
  TOP w0.109: v2(267.76,44.95) 268.51,45.7 R4.2 269.64,45.7 269.68,45.66 Q367.6
N49853731: length 54.8
  TOP w0.109: v1(201.97,61.68) 201.97,62.01 v2(201.52,62.46) 199.43,64.55 RH447.1
  IN1 w0.076: v3(177.29,49.55) 177.27,49.55 176.89,49.93 175.94,49.93 175.29,50.58 167.01,50.58 166.33,49.89 164.92,49.89 164.79,50.02 163.14,50.02 162.4,49.28 v3(162.4,49.16)
  IN3 w0.102: v3(177.29,49.55) 177.69,49.95 179.17,49.95 180.03,49.09 183.97,49.09 184.46,48.6 186.83,48.6 188.76,50.53 191.25,50.53 191.59,50.86 194.61,50.86 196.36,52.61 198.19,52.61 202.2,56.63 202.2,58.07 202.01,58.26 202.01,58.82 202.18,58.99 202.18,60.05 201.97,60.26 v1(201.97,61.68)
  IN4 w0.076: v3(162.4,49.16) 162.16,48.92 v4(162.16,48.81)
N49853749: length 46.9
  TOP w0.109: v7(197.94,64.35) 198.14,64.55 RH448.2 199.18,63.8 199.85,63.8 200.34,63.31 v2(200.34,63.1)
  IN1 w0.076: v3(198.42,64.04) 198.24,64.04 v7(197.94,64.35)
  IN2 w0.102: v3(198.42,64.04) 197.14,65.32 183.92,65.32 180.45,61.86 176.6,61.86 175.48,60.74 175.48,60.3 173.94,58.76 169.35,58.76 168.61,59.5 166.92,59.5 165.99,58.57 164.01,58.57 162.15,56.7 161.24,56.7 v3(161.16,56.78)
  IN4 w0.076: v3(161.16,56.78) 160.77,56.78 v4(160.72,56.83)
  BOTTOM w0.109: v4(160.72,56.83) 160.72,56.58 UCPU1.L5
N51252706: length 15.1
  TOP w0.109: v7(45.61,2.15) 46.22,2.76 D81.1 45.34,3.35 v2(44.8,3.89)
  IN1 w0.076: v3(44.4,1.31) 45.24,2.15 v7(45.61,2.15)
  IN4 w0.076: v4(44.4,1.99) v3(44.4,1.31)
  BOTTOM w0.109: R886.1 50.49,3.41 49.83,3.41 49.62,3.21 49.62,2.69 49.23,2.29 47.97,2.29 47.47,2.8 47.06,2.8 46.9,2.64 JFAN1.2 46.9,1.45 46.7,1.25 44.6,1.25 44.4,1.45 v4(44.4,1.99)
N51254722: length 2.2
  BOTTOM w0.109: v2(12.55,19.86) 12.82,19.59 13.9,19.59 RA75.2
N51410754: length 2.6
  TOP w0.109: D301.2 194.33,30.08 R342.2 195.79,30.44 v2(195.79,31.2)
N51410761: length 5.2
  TOP w0.109: R341.2 205.45,39.24 D302.2 206.96,37.08 v2(208.4,37.08)
N51850640: length 249.3
  TOP w0.109: v2(40.52,20.79) v7(40.02,20.79) 39.44,21.37 Q134.1 ; Q135.3 190.59,65.36 190.44,65.51 R988.2 191.73,65.97 192.23,66.48 v7(192.23,67.14)
  IN1 w0.076: v7(192.23,67.14) 192.83,67.14 v3(192.94,67.25) ; v3(45.55,14.26) 44.96,14.26 42.81,16.41 42.81,16.69 40.99,18.51 40.99,19.82 v7(40.02,20.79)
  IN3 w0.102: v3(192.94,67.25) 192.94,66.68 193.76,65.87 198.68,65.87 200.08,67.27 203.63,67.27 204.65,66.24 204.65,63.47 204.74,63.38 204.74,61.55 206.24,60.05 206.24,58.94 205.94,58.63 205.94,55.1 206.24,54.8 206.24,54.36 205.96,54.08 205.58,54.08 205.38,53.88 205.38,52.59 205.25,52.46 205.25,50.68 205.35,50.58 205.35,48.88 204.23,47.76 204.23,42.02 203.35,41.13 203.35,38.72 198.52,33.89 198.52,27.07 197.35,25.9 197.35,14.82 193.34,10.8 192.88,10.8 190.61,8.53 180.07,8.53 178.94,7.4 160.07,7.4 157.39,10.09 151.22,10.09 150.14,11.16 139.66,11.16 138.66,10.16 127.77,10.16 126.18,8.58 109.66,8.58 107.71,10.52 95.48,10.52 92.94,7.98 74.31,7.98 73.09,9.2 71.24,9.2 70.12,10.32 66.17,10.32 65.69,10.8 54.7,10.8 53.43,9.53 50.95,9.53 49.14,11.34 49.14,11.85 47.57,13.42 45.99,13.42 45.55,13.86 v3(45.55,14.26)
N52198701: length 6.5
  TOP w0.109: US2.8 24.88,48.52 v5(24.52,48.88)
  TOP w0.254: US2.8 26.49,48.96 25.63,49.82 25.63,50.04 R1168.1 25.85,50.21 26.99,49.07 US2.7
N52198820: length 2.7
  TOP w0.109: R1119.1 26.76,44.06 v2(26.45,43.75)
  TOP w0.254: US2.15 27.49,44.06 R1119.1
N52198836: length 5.8
  TOP w0.109: R1120.1 28.91,43.54 28.91,42.92 29.3,42.54 v2(31.56,42.54)
  TOP w0.254: R1120.1 27.99,44.45 US2.16
N52248533: length 2.5
  TOP w0.109: v1(234.54,35.97) 233.72,35.97 T289.1
  BOTTOM w0.109: v1(234.54,35.97) 234.74,35.97 235.15,35.57 JNGFF2.17
N52739814: length 3.1
  TOP w0.109: T243.1 205.71,23.86 JSATA1.38
N52739816: length 2.4
  TOP w0.109: T242.1 205.27,23.06 JSATA1.36
N53088164: length 0.8
  TOP w0.109: v2(92.82,31.48) 92.34,31.48 v1(92.11,31.71)
N53261894: length 8.1
  TOP w0.109: RTCR1.1 260.71,43.83 258.59,43.83 v2(257.83,43.06) 257.64,42.87 257.64,41.12 257.39,40.87 RTCD1.2
N53506599: length 5.8
  TOP w0.109: R1241.1 v2(244.56,40.89) 244.56,40.72 v1(244.9,40.38)
  BOTTOM w0.109: v1(244.9,40.38) 245.47,40.95 247.21,40.95 247.4,41.14 JNGFF2.66
N85222631: length 8
  TOP w0.109: R921.1 214.71,51.9 v7(214.71,52.42) 214.71,52.9 v2(214.37,53.25)
  IN1 w0.076: v3(210.71,52.66) 210.91,52.87 213.26,52.87 213.91,52.22 214.51,52.22 v7(214.71,52.42)
  IN4 w0.076: v4(210.36,52.81) 210.38,52.84 210.48,52.84 210.71,52.61 v3(210.71,52.66)
  BOTTOM w0.109: v4(210.36,52.81) 210.36,52.95 U34.J6
N93297419: length 5.1
  TOP w0.109: Q305.2 92.32,60.47 93.01,61.16 93.01,61.9 92.54,62.37 92.54,63.81 92.9,64.17 U708.4
N93297423: length 3.9
  TOP w0.109: R541.2 91.6,61.35 91.09,60.84 Q305.1 89.87,60.84 v2(89.35,61.36)
N96981838: length 4.9
  BOTTOM w0.109: JBL1.3 157.75,11.21 R944.2 159.09,9.98 159.67,9.98 160.01,10.32 v5(160.01,10.85)

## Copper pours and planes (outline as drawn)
+0.6VSP on BOTTOM: 95.73,35.03 95.74,35.05 95.78,35.05 95.85,35.12 95.85,35.2 95.78,35.28 95.78,36.36 95.88,36.46 96.23,36.46 96.34,36.36 96.34,35.47 96.51,35.47 96.51,36.38 96.69,36.56 96.84,36.56 97.35,37.07 98.37,37.07 98.49,37.19 98.49,37.7 97.99,37.7 97.99,38.21 98.49,38.21 98.49,38.59 98.37,38.72 97.48,38.72 97.1,38.34 93.8,38.34 93.67,38.21 93.67,36.94 94.07,36.53 94.25,36.53 94.84,35.95 94.84,35.09 94.9,35.03
+0.675VS on BOTTOM (solid shape): 99.78,38.88 99.78,37.49 99.54,37.24 98.88,37.24 98.72,37.4 98.72,38.92 98.82,39.02 99.64,39.02
+0.675VS on TOP: outline of 130 points within 101.91,7.86 175.13,30.21 ; 5 cut-outs
+0.675VS on IN2: 101.54,28.94 102.43,28.94 103.07,29.57 103.07,38.21 102.3,38.97 99.13,38.97 99,38.84 99,37.45 99.13,37.32 100.27,37.32 100.78,36.81 100.78,29.7
+1.2V_B+ on TOP (solid shape): 87.05,36.81 87.05,31.99 86.8,31.73 83.62,31.73 83.5,31.86 83.5,36.81 83.62,36.94 86.92,36.94
+1.2V_B+ on BOTTOM (solid shape): 84.65,38.34 86.18,38.34 86.18,38.84 88.46,38.84 88.84,38.46 88.84,37.32 88.55,37.03 87.15,37.03 87.06,36.94 87.06,35.29 86.43,34.65 83.76,34.65 83.51,34.91 83.51,38.59 83.76,38.84 84.65,38.84
+1.05VA on TOP: 181.24,63.18 182.07,63.18 182.28,63.38 182.28,64.8 182.15,64.93 181.26,64.93 181.16,65.03 181.16,65.72 181.51,66.07 182.48,66.07 182.61,65.95 182.61,65.11 182.73,64.98 184.11,64.98 184.34,65.22 185.12,65.22 185.2,65.13 185.2,65.01 185.12,64.93 184.38,64.93 184.11,64.65 184.11,63.43 184.33,63.2 186.14,63.2 186.34,63 186.34,59.25 185.51,58.43 182.29,58.43 182.05,58.67 182.05,61.33 181.11,62.26 181.11,63.05
+1.05VA on TOP: 159.14,48.22 159.18,48.26 159.45,48.26 159.7,48.5 159.7,51.04 161.22,52.56 162.74,52.56 164.52,54.34 164.52,54.85 164.14,55.23 161.47,55.23 158.56,52.31 158.56,49.36 158.46,49.26 157.79,49.26 157.66,49.39 157.66,50.27 157.54,50.4 156.39,50.4 156.27,50.27 156.27,49.39 156.39,49.26 156.9,49.26 157.16,49 157.16,48.37 157.31,48.22
+1.05VA on BOTTOM: 184.09,57.89 183.97,58.02 183.97,64.02 184.02,64.08 185.3,64.08 185.5,63.88 185.5,62.26 186.07,61.69 186.07,57.97 186,57.89
+1.05VA on IN2: 182.7,62.47 185.49,62.47 185.87,62.09 185.87,58.78 185.62,58.53 181.43,58.53 181.17,58.78 181.17,60.94
+1.05VA on IN2: 166.63,56.12 165.04,56.12 163.77,54.85 163.77,54.47 164.03,54.21 165.3,54.21 166.06,54.97 166.63,54.97 166.71,55.05 166.71,56.04
+1.05VDX_MODPHY on TOP (solid shape): 180.02,64.5 180.02,62.09 180.14,61.96 181.03,61.96 181.76,61.23 181.76,59.32 181.55,59.1 180.76,59.1 180.57,59.29 180.57,60.72 180.28,61.02 178.45,61.02 178.32,61.16 178.32,61.68 178.21,61.78 177.37,61.78 177.22,61.93 177.22,62.68 176.85,63.05 175.98,63.05 175.77,63.25 175.77,64.3 176,64.52 179.99,64.52
+1.5VS on TOP (solid shape): 49,12.46 49,10.41 48.9,10.31 48.55,10.31 48.43,10.42 48.43,10.93 47.77,11.59 47.77,12.02 48.44,12.7 48.76,12.7
+1.05VS on TOP (solid shape): 180.99,65.41 180.99,64.82 181.08,64.73 182.05,64.73 182.12,64.65 182.12,63.48 182.07,63.43 181.11,63.43 180.88,63.2 180.88,62.26 180.73,62.11 180.47,62.11 180.22,62.37 180.22,65.13 180.22,65.14 180.22,65.35 180.38,65.51 180.89,65.51
+1.05VS on TOP (solid shape): 162.49,67.29 162.49,63.23 157.66,58.4 156.9,58.4 156.77,58.28 156.77,57.13 156.65,57.01 154.87,57.01 154.74,57.13 154.74,58.4 155.96,59.62 156.7,59.62 161.43,64.36 161.43,66.08 161.39,66.12 161,66.12 160.46,66.66 160.46,67.42 160.58,67.55 162.24,67.55
+1.05VS on TOP (solid shape): 154.12,55.53 154.12,53.44 153.79,53.11 151.72,53.11 151.24,53.59 151.24,54.77 151.75,54.77 151.75,54.05 152.51,54.05 152.51,54.77 152.46,54.77 152.46,55.03 152.46,55.05 152.45,55.1 152.44,55.15 152.41,55.2 152.38,55.24 152.35,55.28 152.3,55.31 152.26,55.33 152.21,55.35 152.16,55.36 152.1,55.36 152.05,55.35 152,55.33 151.96,55.31 151.92,55.28 151.88,55.24 151.85,55.2 151.82,55.15 151.81,55.1 151.8,55.05 151.8,55.03 151.8,54.77 151.24,54.77 151.24,55.13 151.55,55.43 153.24,55.43 153.57,55.76 153.9,55.76
+1.5VS on BOTTOM (solid shape): 72.59,15.98 72.59,15.48 72.46,15.35 71.19,15.35 71.06,15.48 71.06,16.11 71.19,16.24 72.33,16.24
+1.5VS on BOTTOM (solid shape): 89.6,57.44 89.6,55.53 89.48,55.41 88.28,55.41 88.08,55.61 88.08,57.49 88.18,57.59 89.45,57.59
+1.5VS on BOTTOM (solid shape): 49.47,12.3 49.47,11.98 48.51,11.02 47.92,11.02 47.52,11.42 47.52,11.92 47.61,12.01 48.22,12.01 48.76,12.56 49.22,12.56
+1.05VS on BOTTOM (solid shape): 184.14,65.94 184.14,64.47 183.41,63.74 183.41,62.8 182.98,62.37 180.62,62.37 180.5,62.39 180.38,62.37 180.36,62.37 180.23,62.49 180.23,65.36 180.33,65.46 182.42,65.46 182.94,65.99 184.09,65.99
+1.5VS on IN3 (solid shape): 72.71,15.86 72.71,15.48 72.59,15.35 71.19,15.35 71.06,15.48 71.06,16.11 71.19,16.24 72.33,16.24
+1.5VS on IN3 (solid shape): 48.58,11.67 48.58,11.31 48.36,11.09 48.05,11.09 47.01,12.14 47.01,12.38 47.32,12.69 47.56,12.69
+1.5VS on IN3 (solid shape): 89.22,57.01 89.22,55.35 89.1,55.23 88.46,55.23 88.33,55.35 88.33,57.01 88.46,57.13 89.1,57.13
+1.5VS on IN4 (solid shape): 89.23,56.59 89.23,55.81 88.14,54.72 87.79,54.72 87.25,55.26 87.25,55.83 88.24,56.82 89,56.82
+1.5VS on IN4 (solid shape): 72.62,15.78 73.11,15.78 73.63,15.26 73.63,14.77 73.37,14.51 72.28,14.51 71.14,15.65 71.14,15.98 71.61,16.44 71.96,16.44
+1.05VS on IN4 (solid shape): 153.98,54.78 153.98,53.29 153.87,53.18 151.68,53.18 151.61,53.25 151.61,53.76 151.81,53.76 151.81,53.7 151.82,53.65 151.83,53.6 151.86,53.55 151.89,53.51 151.92,53.47 151.96,53.44 152.01,53.41 152.06,53.39 152.11,53.38 152.16,53.37 152.22,53.38 152.27,53.39 152.32,53.41 152.37,53.44 152.41,53.47 152.44,53.51 152.47,53.55 152.5,53.6 152.51,53.65 152.52,53.7 152.52,53.76 152.51,53.81 152.5,53.86 152.47,53.91 152.44,53.95 152.41,53.99 152.37,54.02 152.32,54.05 152.27,54.07 152.22,54.08 152.16,54.09 152.11,54.08 152.06,54.07 152.01,54.05 151.96,54.02 151.92,53.99 151.89,53.95 151.86,53.91 151.83,53.86 151.82,53.81 151.81,53.76 151.61,53.76 151.61,54.76 151.69,54.84 153.91,54.84
+1.5VS on BOTTOM: 26.23,33.89 26.87,33.89 26.99,33.76 26.99,32.62 25.63,31.26 24.92,31.26 24.83,31.34 24.83,32.28 25.8,33.24 25.8,33.46
+1.5VS on IN1: 25.22,40.5 30.55,40.5 31.18,39.86 31.18,38.84 30.8,38.46 30.8,31.63 30.6,31.43 30.17,31.43 29.61,31.99 25.09,31.99 24.96,32.11 24.96,32.75 26.36,34.15 26.36,37.83 27.12,38.59 27.12,39.1 26.74,39.48 25.34,39.48 25.09,39.73 25.09,40.37
+1.05VS on VCC: outline of 119 points within 150.04,41.13 188.14,65.64 ; 1 cut-out
+1.05VS_B+ on TOP (solid shape): 195.71,59.85 195.71,57.72 195.38,57.39 193.07,57.39 192.83,57.63 192.83,58.67 193.29,59.13 193.7,59.13 194.49,59.93 195.64,59.93
+1.05VS_B+ on BOTTOM (solid shape): 196.94,57.83 196.94,56.73 196.84,56.62 193.49,56.62 193.24,56.37 192.09,56.37 191.97,56.5 191.97,58.28 192.34,58.64 196.13,58.64
+1.05VS_VCCST on TOP (solid shape): 153.09,50.27 153.09,48.88 152.96,48.75 150.3,48.75 150.04,48.5 149.28,48.5 149.03,48.75 149.03,49.64 149.28,49.89 151.69,49.89 152.2,50.4 152.96,50.4
+1.05VS_VCCST on BOTTOM (solid shape): 151.14,50.23 151.14,49.22 150.5,48.58 149.74,48.58 149.49,48.83 149.49,49.72 150.05,49.72 150.05,49.67 150.06,49.63 150.08,49.58 150.1,49.54 150.13,49.5 150.17,49.47 150.21,49.44 150.25,49.42 150.3,49.41 150.35,49.41 150.39,49.41 150.44,49.42 150.48,49.44 150.53,49.47 150.56,49.5 150.59,49.54 150.61,49.58 150.63,49.63 150.64,49.67 150.64,49.72 150.63,49.77 150.61,49.82 150.59,49.86 150.56,49.9 150.53,49.93 150.48,49.96 150.44,49.98 150.39,49.99 150.35,49.99 150.3,49.99 150.25,49.98 150.21,49.96 150.17,49.93 150.13,49.9 150.1,49.86 150.08,49.82 150.06,49.77 150.05,49.72 149.49,49.72 149.49,50.02 149.69,50.22 150.62,50.22 150.76,50.36 151.01,50.36
+1.05VS_VCCST on IN3: 149.42,49.89 149.55,50.02 151.07,50.02 151.2,49.89 151.2,49 150.95,48.75 149.55,48.75 149.42,48.88 149.04,48.88 148.91,49 128.34,49 126.94,50.4 123.89,50.4 119.7,54.59 118.56,54.59 118.43,54.72 118.43,55.23 118.56,55.35 118.69,55.35 119.32,55.99 123.77,55.99 129.61,50.15 149.17,50.15
+1.5VSP on BOTTOM (solid shape): 87.85,58.21 87.85,56.8 87.83,56.78 87.27,56.78 87.27,56.29 87.32,56.24 87.88,56.24 87.88,55.66 87.62,55.41 87.24,55.41 86.43,54.59 86.43,51.32 85.36,50.25 84.14,50.25 84.04,50.15 84.04,49.69 83.91,49.56 83.56,49.56 83.43,49.69 83.43,50.57 84.13,50.88 83.43,51.2 83.43,51.61 84.14,51.8 83.43,51.99 83.43,54.69 83.71,54.97 84.8,54.97 85.03,55.2 85.03,58.4 85.16,58.53 87.53,58.53
+1.05VSP on BOTTOM: 188.11,56.68 187.9,56.88 187.9,57.64 187.65,57.89 187.62,57.9 187.43,57.96 187.23,57.89 186.89,57.89 186.78,58 186.78,60.92 187.56,61.7 187.56,65.55 187.66,65.64 191.2,65.64 191.71,65.13 191.71,56.9 191.48,56.68
+1.5VSP_LX on TOP (solid shape): 90.06,54.93 90.06,51.81 89.25,51 88.03,51 87.95,51.08 87.95,54.89 88.16,55.09 89.9,55.09
+1.5VSP_LX on BOTTOM (solid shape): 90.62,54.97 90.62,52.69 90.37,52.43 88.84,52.43 88.72,52.31 88.72,51.16 88.59,51.04 87.26,51.04 87.13,51.16 87.13,54.85 87.38,55.1 90.49,55.1
+1.5VSP_VIN on TOP (solid shape): 89.34,48.88 89.34,46.72 89.21,46.59 86.92,46.59 86.8,46.72 86.8,47.61 86.99,47.8 87.72,47.8 87.95,48.03 87.95,48.92 88.08,49.04 89.17,49.04
+1.5VSP_VIN on BOTTOM (solid shape): 87.32,50.15 87.32,49.2 87.51,49 89.03,49 89.41,48.62 89.41,46.46 89.16,46.21 88.08,46.21 87.7,45.83 85.29,45.83 85.29,46.27 85.48,46.46 85.48,50.02 85.86,50.4 87.06,50.4
+1.8VP on BOTTOM: 212.16,37.96 212.16,38.46 212.41,38.72 214.06,38.72 214.57,39.23 218.89,39.23 219.14,38.97 219.14,35.92 218.76,35.54 217.49,35.54 217.49,36.13 216.43,37.19 213.43,37.19 213.3,37.07 212.29,37.07 212.29,37.32 212.79,37.32 212.79,37.96
+1.8VS on BOTTOM (solid shape): 212.03,38.18 212.03,36.81 211.78,36.56 210.48,36.56 210.31,36.74 210.31,37.02 210.84,37.55 211.32,37.55 211.45,37.68 211.45,38.26 211.58,38.39 211.83,38.39
+1.8VS on TOP: 216.97,61.45 217.35,61.45 217.48,61.32 217.48,54.34 217.35,54.21 216.97,54.21 216.85,54.34 216.85,61.32
+1.8VSP_LX on BOTTOM (solid shape): 222.14,39.71 223.16,39.71 223.45,39.42 223.45,38.1 223.41,38.06 221.89,38.06 221.63,37.8 221.63,35.64 221.48,35.49 219.83,35.49 219.6,35.72 219.6,39.96 219.86,40.22 221.63,40.22
+1.8VSP_LX on TOP: 223.12,40.19 223.12,39.05 223.04,38.97 220.71,38.97 220.43,39.25 220.43,40.37 220.68,40.62 222.69,40.62
+1.35V_DDR on TOP (solid shape): outline of 429 points within 124.83,19.47 132.07,23.15
+1.35V_DDR on TOP (solid shape): outline of 605 points within 147.44,16.8 158.12,24.68
+1.35V_DDR on TOP (solid shape): outline of 799 points within 135.37,17.57 143.5,27.85
+1.35V_DDR on TOP (solid shape): outline of 5089 points within 132.01,32.27 148.77,48.94
+1.35V_DDR on BOTTOM (solid shape): 149.42,23.94 149.46,23.95 149.5,23.95 149.62,23.83 149.62,23.82 149.74,23.67 149.92,23.62 149.95,23.61 149.97,23.57 149.97,23.51 149.88,23.42 149.87,23.42 149.61,23.08 149.95,22.83 150.04,22.8 150.07,22.72 150.1,22.55 150.21,22.41 150.21,22.13 150.01,21.93 149.91,21.91 149.84,21.98 149.72,22.19 149.5,22.27 149.43,22.3 149.4,22.36 149.31,22.54 149.13,22.62 149.1,22.64 149.09,22.67 149.09,22.76 149.16,22.83 149.17,22.83 149.4,23.12 149.17,23.41 149.1,23.48 149.12,23.58 149.17,23.63 149.18,23.63 149.33,23.73 149.4,23.9
+1.35V_DDR on BOTTOM (solid shape): 160.22,20.76 160.33,20.73 160.36,20.7 160.36,20.68 160.46,20.49 160.66,20.42 160.73,20.39 160.76,20.32 160.83,20.14 161,20.05 161.01,20.04 161.16,19.89 161.16,19.88 161.21,19.75 161.32,19.66 161.37,19.58 161.34,19.5 161.29,19.45 161.29,19.37 161.18,19.22 161.17,19.03 161.11,19.03 160.97,18.9 160.86,18.9 160.78,19.39 160.36,19.12 160.36,19.1 160.33,19.07 160.22,19.05 160.16,19.14 159.94,19.41 159.62,19.3 159.13,19.3 158.49,19.94 158.49,20.05 158.55,20.14 158.66,20.13 158.75,20.09 158.85,20.08 158.87,20.08 159.22,19.73 159.63,19.73 160.13,19.8 159.85,20.22 159.78,20.25 159.75,20.32 159.75,20.36 159.81,20.43 159.84,20.42 160.04,20.49 160.15,20.67
+1.35V_DDR on BOTTOM (solid shape): 161.17,23.85 161.17,23.84 161.27,23.69 161.43,23.62 161.5,23.59 161.53,23.5 161.45,23.42 161.43,23.42 161.16,23.07 161.53,22.83 161.63,22.81 161.66,22.71 161.66,22.53 161.75,22.37 161.78,22.3 161.76,22.22 161.68,22.1 161.65,21.95 161.66,21.93 161.54,21.81 161.51,21.82 161.26,21.75 161.16,21.51 161.13,21.43 161.06,21.4 161.04,21.4 160.99,21.41 160.95,21.45 160.88,21.72 160.61,21.82 160.59,21.85 160.59,21.91 160.59,21.94 160.6,21.99 160.63,22.02 160.96,22.31 160.66,22.62 160.59,22.69 160.59,22.73 160.62,22.79 160.68,22.82 160.96,23.12 160.69,23.42 160.67,23.42 160.62,23.47 160.63,23.52 160.65,23.59 160.71,23.63 160.85,23.69 160.94,23.82 160.94,23.83 161.07,23.95
+1.35V_DDR on TOP: 159.63,19.72 159.38,19.98 159.38,20.58 159.39,20.62 159.69,20.75 159.79,21.01 159.79,21.03 159.74,21.22 159.61,21.36 159.38,21.59 159.38,21.63 158.99,22.01 158.36,22.01 158.11,22.26 158.11,22.81 158.18,22.88 158.66,22.88 158.79,23.01 158.79,23.87 158.73,23.93 157.97,23.93 157.85,24.05 157.85,25.59 158,25.74 159.16,25.74 159.59,25.68 159.76,26.08 159.78,26.16 159.86,26.2 160.65,26.2 161.15,25.69 161.15,24.77 161.12,24.7 161.06,24.67 160.71,24.31 161.06,23.96 161.12,23.93 161.15,23.85 161.15,20.23 160.65,19.72
+1.35V_DDR on TOP: 113.32,15.28 112.51,15.28 112.51,15.53 112.13,15.92 111.75,15.53 111.75,15.28 109.59,15.28 109.08,15.79 109.03,15.79 109.03,15.81 108.27,15.81 108.27,15.79 108.19,15.79 108.13,15.85 108.09,15.81 107.36,15.81 107.36,15.79 101.21,15.79 100.83,16.17 100.83,16.82 100.9,16.88 100.95,16.96 101.57,17.59 101.82,17.9 101.62,18.24 101.57,18.33 101.62,18.42 101.78,18.6 101.79,18.83 100.55,20.07 98.84,20.07 96.37,22.54 96.37,25.89 96.77,26.29 100.64,26.29 100.92,26.57 100.92,28 101.09,28.18 101.83,28.18 102.14,27.87 119.67,27.87 120.55,26.98 120.55,26.17 119.84,25.46 119.84,20.23 118.94,19.32 118.94,19.27 118.95,19.21 119.46,18.7 119.46,17.81 119.79,17.48 119.79,16.98 119.61,16.8 119.21,16.8 118.07,17.94 118.07,18.55 118.03,18.58 116.62,18.58
+1.35V_DDR on BOTTOM: outline of 3380 points within 95.12,12.72 192.41,40.9
+1.35VP on BOTTOM (solid shape): 92.53,28.05 94.18,28.05 94.3,27.92 94.3,27.67 94.94,27.03 94.94,23.1 94.81,22.97 90.49,22.97 89.6,22.08 85.49,22.08 84.65,22.92 84.65,28.3 92.27,28.3
+1.35VP on BOTTOM (solid shape): 93.36,36.05 93.36,35.8 93.34,35.77 92.83,35.77 92.8,35.75 92.8,35.31 92.83,35.29 93.36,35.29 93.39,35.26 93.39,34.88 93.16,34.65 92.02,34.65 91.76,34.91 91.76,35.8 92.04,36.08 93.34,36.08
+3.3V_M on TOP (solid shape): 196.4,55.1 196.4,53.58 196.27,53.45 195.26,53.45 195.13,53.58 195.13,53.83 194.62,54.34 194.62,55.1 194.75,55.23 196.27,55.23
+3.3VDX_SSD on TOP (solid shape): 206.33,6.61 207.56,6.61 207.62,6.55 207.62,5.92 207.55,5.85 205.64,5.85 205.43,6.07 203.33,6.07 203.17,6.23 203.17,6.88 203.85,7.56 205.38,7.56
+3.3VDX_SSD on TOP (solid shape): 205.42,11.22 205.42,9.89 205.21,9.68 203.49,9.68 203.23,9.42 202.88,9.42 202.75,9.55 202.75,10.45 202.88,10.57 203.36,10.57 203.71,10.93 203.71,11.34 203.79,11.41 205.23,11.41
+3.3VDX_SSD on BOTTOM: 202.86,28.2 202.86,25.6 203.09,25.37 206.03,25.37 206.19,25.21 206.19,24.24 205.97,24.02 203.21,24.02 202.86,23.68 202.86,13.53 202.42,13.09 202.42,10.99 202.76,10.65 203.4,10.65 203.52,10.52 203.52,9.76 203.14,9.38 202.76,9.38 202.25,9.89 200.98,9.89 200.37,10.5 200.37,15.62 201.62,16.87 201.62,31.22 201.87,31.48 207.17,31.48 207.6,31.05 207.6,29.23 207.48,29.12 206.47,29.12 206.19,29.4 204.06,29.4
+3.3VDX_SSD on IN3: 201.49,9.67 201.51,9.78 202.51,10.78 202.68,10.78 202.76,10.72 202.85,10.68 205.61,13.44 205.61,29.27 206.11,29.77 207.38,29.77 207.62,29.53 207.62,5.88 207.06,5.32 201.49,5.32 201.24,5.57 201.24,8.92 201.27,8.93 201.31,8.96 201.36,9 201.6,8.9 201.88,9 201.91,8.99 202.51,9.25 201.91,9.52 201.88,9.5 201.84,9.52 201.73,9.59 201.59,9.61
+3V_NFC on BOTTOM (solid shape): 186.11,9.98 186.11,8.32 185.99,8.19 185.4,8.19 185.3,8.29 185.3,10.01 185.37,10.08 186.02,10.08
+3V_NFC on BOTTOM (solid shape): 192.21,10.22 192.21,8.99 192.02,8.81 191.89,8.81 191.8,8.9 191.8,10.02 191.59,10.23 191.31,10.23 191.23,10.31 191.23,10.64 191.32,10.73 191.7,10.73
+3V_PCH on TOP (solid shape): 168.43,66.3 168.43,64.83 168.23,64.63 167.7,64.63 167.6,64.73 167.6,65.34 167.37,65.57 167.37,66.61 167.6,66.84 167.9,66.84
+3V_PCH on TOP (solid shape): 169.61,51.9 169.61,51.89 169.6,51.47 170.01,51.5 170.05,51.46 170.95,51.46 170.98,51.43 170.98,50.67 171.38,50.27 171.38,49.39 171.25,49.26 169.6,49.26 169.47,49.39 169.47,50.72 169.12,51.07 169.12,51.37 168.74,51.75 168.74,52.28 168.8,52.34 169.18,52.34
+3V_PCH on IN2 (solid shape): 175.9,44.49 175.9,43.74 175.84,43.67 175.33,43.67 175.05,43.95 174.29,43.95 174.15,44.09 174.15,44.72 174.18,44.75 175.65,44.75
+3V_PCH on BOTTOM: 171.44,49.01 171.25,48.82 168.2,48.82 167.97,49.04 167.97,49.91 168.21,50.15 169.58,50.15 170.34,50.91 171.15,50.91 171.44,50.61
+3V_PCH on IN2: 158.18,43.42 158.57,43.42 159.07,42.91 159.07,41.89 160.09,40.88 167.07,40.88 167.58,41.38 167.58,42.02 167.46,42.15 166.57,42.15 166.19,41.77 161.49,41.77 159.84,43.42 159.58,43.42 158.82,44.18 158.18,44.18 158.06,44.05 158.06,43.54
+3V_PCH on IN4: 171.17,49.42 171.17,49.04 170.99,48.86 170.87,48.86 170.12,48.12 169.74,48.12 169.61,48.24 169.61,48.88 170.25,49.51 171.09,49.51
+3V_PCH on IN4: 175.2,44.69 175.71,44.69 175.96,44.43 175.96,41.51 176.47,41 176.98,41 178.5,39.48 178.5,39.23 181.3,36.43 185.62,36.43 186.38,35.67 186.38,33 186,32.62 185.24,32.62 185.11,32.75 185.11,33.51 185.49,33.89 185.49,35.16 185.11,35.54 180.92,35.54 177.36,39.1 176.47,39.1 175.08,40.5 175.08,44.56
+3V_PCH_DSW on TOP: 170.36,48.29 170.36,48.88 170.49,49 172.6,49 173,48.6 173,47 172.97,46.96 171.69,46.96
+3VALW on TOP (solid shape): 235.26,50.66 235.26,48.75 235.13,48.62 234.12,48.62 233.86,48.88 233.86,50.27 234.37,50.78 235.13,50.78
+3VALW on TOP (solid shape): 190.61,51.93 190.61,50.84 190.54,50.77 189.86,50.77 189.79,50.83 189.79,51.95 189.9,52.05 190.48,52.05
+3VALW on TOP (solid shape): 266.63,8.62 266.63,7.6 266.38,7.35 264.6,7.35 264.34,7.6 264.34,8.49 264.6,8.75 266.5,8.75
+3VALW on TOP (solid shape): 203.56,11.72 203.56,11.01 203.33,10.78 202.85,10.78 202.62,10.55 202.62,10.09 202.49,9.97 201.81,9.97 201.73,10.04 201.73,11.67 202.01,11.95 203.33,11.95
+3VALW on TOP (solid shape): 172.55,67.26 172.55,66.56 172.4,66.4 171.13,66.4 171,66.53 171,66.91 171.13,67.04 171.79,67.04 171.93,67.17 171.93,67.35 172.1,67.53 172.29,67.53
+3VALW on TOP (solid shape): 240.96,51.16 241.74,51.16 241.85,51.05 241.85,50.33 241.7,50.17 240.52,50.17 240.4,50.29 240.4,51.08 240.54,51.21 240.91,51.21
+3VALW on TOP (solid shape): 173.3,69.34 173.3,68.86 173.72,68.44 173.72,67.94 173.6,67.82 173.26,67.82 173.16,67.92 173.16,68.18 173.16,68.23 173.16,68.28 172.98,68.66 172.58,68.56 171.89,68.56 171.76,68.44 171,68.44 171,69.07 171.51,69.58 173.06,69.58
+3VALW on BOTTOM (solid shape): 267.22,22.42 267.54,22.42 267.56,22.4 267.56,21.91 267.55,21.9 267,21.9 266.92,21.83 265.75,21.83 265.63,21.95 265.63,22.59 265.75,22.72 266.92,22.72
+3VALW on BOTTOM (solid shape): 190.82,51.98 190.82,51.21 190.8,51.08 190.82,50.94 190.82,50.74 190.76,50.68 189.91,50.68 189.55,51.04 189.55,51.93 189.71,52.08 190.72,52.08
+3VALW on BOTTOM (solid shape): 198.57,36.94 200.48,36.94 200.48,36.43 202.51,36.43 202.51,36.94 203.27,36.94 203.52,36.69 203.52,35.16 203.27,34.91 196.28,34.91 195.52,35.67 195.52,37.07 196.28,37.83 197.68,37.83
+3VALW on BOTTOM (solid shape): 265.4,14.05 265.4,13.44 265.45,13.39 265.93,13.39 265.96,13.37 265.96,12.96 265.93,12.94 265.42,12.94 265.4,12.91 265.4,12.23 265.42,12.2 265.93,12.2 265.96,12.17 265.96,11.74 265.93,11.72 265.42,11.72 265.4,11.69 265.4,11.06 265.37,11.03 265.37,10.78 265.75,10.4 265.75,7.73 265.12,7.09 264.23,7.09 263.98,7.35 263.98,9.94 264.48,9.94 264.48,9.89 264.49,9.84 264.51,9.78 264.53,9.74 264.56,9.69 264.6,9.65 264.64,9.62 264.68,9.59 264.73,9.57 264.79,9.56 264.84,9.56 264.89,9.56 264.94,9.57 264.99,9.59 265.04,9.62 265.08,9.65 265.12,9.69 265.15,9.74 265.17,9.78 265.19,9.84 265.19,9.89 265.19,9.94 265.19,9.99 265.17,10.04 265.15,10.09 265.12,10.14 265.08,10.18 265.04,10.21 264.99,10.24 264.94,10.25 264.89,10.27 264.84,10.27 264.79,10.27 264.73,10.25 264.68,10.24 264.64,10.21 264.6,10.18 264.56,10.14 264.53,10.09 264.51,10.04 264.49,9.99 264.48,9.94 263.98,9.94 263.98,13.93 264.13,14.08 265.37,14.08
+3VALW on IN2 (solid shape): 235.53,49.51 235.53,46.21 235.02,45.7 233.75,45.7 233.5,45.96 233.5,46.72 233.75,46.97 234.13,46.97 234.26,47.1 234.26,48.75 233.88,49.13 233.88,49.64 234.38,50.15 234.89,50.15
+3VALW on IN4 (solid shape): 267.91,23.35 267.91,22.33 267.53,21.95 267.15,21.95 267.15,21.96 266.68,21.96 266.61,22.03 266.61,22.54 266.75,22.68 266.9,22.68 267.15,22.93 267.15,23.22 267.4,23.48 267.79,23.48
+3VALW on TOP: 242.93,54.26 242.93,55.39 242.84,55.49 241.78,55.49 241.35,55.05 241.35,54.23 241.04,53.92 241.04,52.61 241.12,52.54 241.74,52.54 241.84,52.64 241.84,53.17
+3VALW on TOP: 144.2,6.46 146.13,6.46 146.21,6.54 147.61,6.54 147.68,6.46 148.65,6.46 153.04,2.07 177.02,2.07 179.13,4.17 180.52,4.17 180.9,3.79 180.9,2.47 181.1,2.28 184.22,2.28 184.33,2.4 184.33,4.68 183.83,5.19 183.06,5.19 182.56,4.68 181.67,4.68 181.41,4.94 181.41,5.57 181.16,5.82 175.19,5.82 173.54,4.17 153.85,4.17 150.42,7.6 143.69,7.6 139.69,3.6 139.69,1.54 139.86,1.36 141.04,1.36 141.14,1.46 141.14,3.4
+3VALW on VCC: outline of 128 points within 171.55,1 271.29,70.48 ; 7 cut-outs
+3VALW on IN2: 243.27,55.86 242.51,55.86 241.37,54.72 241.37,52.94 240.39,51.96 240.39,51.02 240.67,50.74 242.39,50.74 243.4,51.76 243.4,55.74
+3VALW on IN4: 46.68,1.25 46.42,1.51 46.42,3.16 46.68,3.41 48.34,3.41 48.76,3.83 49.96,3.83 50.96,4.83 71.19,4.83 72.19,3.83 73.12,2.9 73.54,2.48 74.28,2.48 74.36,2.4 105.48,2.4 105.96,2.88 105.99,2.88 106.19,2.94 106.29,3.12 106.3,3.16 128.37,3.16 128.67,2.85 140.54,2.85 141.02,2.37 141.02,1.5 140.85,1.33 139.8,1.33 139.05,2.08 108.2,2.08 107.37,1.25
+3VALW_EC on BOTTOM (solid shape): 215.58,58.28 215.58,57.82 215.46,57.7 214.41,57.7 214.36,57.76 214.36,58.38 214.51,58.53 215.32,58.53
+3VALW_EC on BOTTOM (solid shape): 204.16,50.78 204.16,49.39 203.3,48.52 200.88,48.52 200.73,48.37 200.73,47.23 200.98,46.97 201.75,46.97 201.87,46.85 201.87,45.83 201.75,45.7 200.86,45.7 199.84,46.72 199.84,48.52 200.27,48.95 201.51,48.95 201.67,49.11 202.1,49.11 203.9,50.91 204.03,50.91
+3VALW_EC on TOP: 202.75,48.67 202.75,50.27 203.52,51.05 203.51,51.06 203.51,54.72 204.02,55.23 204.53,55.23 204.91,55.61 207.96,55.61 208.21,55.35 210.88,55.35 211,55.23 211,54.72 212.27,53.45 212.27,52.81 212.53,52.56 213.42,52.56 213.67,52.31 213.67,51.19 214.28,50.58 214.28,50.07 214.1,49.89 211.51,49.89 211.26,50.15 211.26,52.05 211.13,52.18 210.38,52.18 210.28,52.27 210.28,53.24 210.5,53.45 210.5,53.83 209.86,54.47 209.48,54.47 209.23,54.21 208.06,54.21 207.68,54.59 206.18,54.59 205.82,54.59 205.44,54.21 204.53,54.21 204.35,54.03 204.35,53.17 204.4,53.12 204.4,51.54 204.65,51.29 204.65,50.02 204.53,49.89 203.76,49.89 203.64,49.77 203.64,48.75 203.51,48.62 202.8,48.62
+3VALWP on BOTTOM (solid shape): 199.59,42.78 199.59,42.02 199.97,41.64 202.89,41.64 203.14,41.38 203.14,37.32 203.02,37.19 198.7,37.19 197.05,38.84 197.05,43.04 199.33,43.04
+3VNS_PWR on TOP: 241.23,59.93 242.5,59.93 242.63,59.8 242.63,59.34 242.15,58.87 242.15,56.77 241.99,56.61 241.39,56.61 241.34,56.66 241.34,57.63 241.18,57.79 240.42,57.79 240.33,57.88 240.33,58.23 240.15,58.4 237.93,58.4 237.42,58.91 237.42,61.58 238.18,62.34 239.32,62.34 239.45,62.21 239.45,59.16 239.71,58.91 240.59,58.91 240.85,59.16 240.85,59.55
+3VNS_PWR on IN2: 224.5,64.92 221.3,64.92 220.47,64.09 220.47,63.17 221.14,62.49 222.65,62.49 224.79,64.63
+3VNS_PWR on IN3: 166.57,68.94 174.57,68.94 175.29,68.22 175.29,67.71 174.11,66.53 167.84,66.53 166.95,67.42 165.93,67.42 165.68,67.67 165.68,68.05
+3VNS_PWR on IN4: 239.72,58.02 239.08,58.02 238.07,59.04 238.07,60.05 237.43,60.69 237.43,60.94 237.56,61.07 238.7,61.07 241.75,58.02 248.86,58.02 249.24,57.64 249.24,57.13 246.96,54.85 246.96,52.56 247.21,52.31 247.21,52.28 247.49,52 247.49,50.52 247.27,50.31 246.81,50.31 246.43,50.68 246.43,51.31
+3VNS_PWR on IN4: 244.93,66.28 251.91,66.28 252.16,66.02 252.16,62.47 254.96,59.67 254.96,58.66 254.58,58.28 253.82,58.28 253.56,58.53 251.78,58.53 251.28,59.04 241.88,59.04 241.37,59.55 241.37,59.8 241.5,59.93 244.29,59.93 244.54,60.18 244.54,65.9
+3VS on TOP: 245.17,54.7 245.17,55.27 245.09,55.35 244.85,55.35 244.4,55.79 243.26,55.79 243.21,55.74 243.21,55.1 243.26,55.05 244.06,55.05 244.27,54.83 244.27,53.9 244.52,53.65 245.08,53.65 245.35,53.92 245.35,54.52
+3VS on TOP: 100.73,61.4 100.73,60.55 100.79,60.49 101.29,60.49 101.34,60.54 101.34,62.1 101.22,62.22 100.26,62.22 100.12,62.08 100.12,61.71 100.3,61.53 100.6,61.53
+3VS on TOP: 206.69,39.86 211.51,39.86 211.64,39.99 211.64,40.75 208.08,44.31 208.08,46.08 208.34,46.34 209.86,46.34 210.09,46.11 210.09,44.56 209.84,44.31 209.84,43.57 209.96,43.44 210.55,43.44 210.62,43.51 210.62,45.65 211,46.02 211,47.23 210.04,48.19 207.61,48.19 206.94,47.52 206.94,43.8 207.83,42.91 207.83,41.89 206.43,40.5 206.43,40.11
+3VS on TOP: 26.6,31.1 29.01,31.1 29.27,30.84 29.27,30.34 29.14,30.21 27.62,30.21 27.49,30.08 27.49,29.57 27.23,29.32 26.97,29.32 26,30.29 25.71,30.29 25.13,30.87 25.13,31.68 25.46,32 25.46,33.26 25.84,33.64 25.84,34.4 25.96,34.53 26.73,34.53 26.98,34.27 26.98,34.02 27.39,33.61 27.83,33.61 28.3,33.13 29.27,33.13 29.39,33.26 29.39,33.76 29.52,33.89 30.16,33.89 30.41,34.15 31.55,34.15 31.81,34.4 31.81,40.24 31.55,40.5 29.14,40.5 28.89,40.75 28.89,41.64 29.27,42.02 33.33,42.02 33.58,41.77 33.58,32.62 33.33,32.37 26.6,32.37 26.35,32.11 26.35,31.35
+3VS on BOTTOM: 201.11,49.69 200.96,49.54 200.37,49.54 200.22,49.69 199.63,49.69 199.47,49.85 199.47,50.5 200.14,51.16 200.14,52.19 200.39,52.44 200.93,52.44 201.11,52.26 201.11,52 201.11,52
+3VS on VCC: 98.61,46.08 98.61,63.63 99.86,64.88 101.64,64.88 102.8,66.04 102.8,70.7 103.61,71.43 103.92,72.48 123.01,72.48 123.01,69.85 123.47,69.39 124.95,69.39 126.29,70.72 139.14,70.72 139.78,70.09 144.03,70.09 145.43,68.69 168.47,68.69 168.86,69.07 182.35,69.07 183.75,67.67 186.35,67.67 186.56,67.47 186.56,66.05 186.9,65.7 188.6,65.7 188.97,66.07 188.97,67.18 189.02,67.23 192.86,67.23 193.75,66.34 207.28,66.34 210.18,63.44 210.18,56.65 213.38,53.45 227.55,53.45 228.31,52.69 242.24,52.69 243.06,53.53 243.77,54.23 243.77,55.12 244.26,55.61 245.44,55.61 246.56,54.49 246.56,49.62 245.19,48.24 237.15,48.24 236.78,48.62 229.45,48.62 227.8,46.97 201.22,46.97 199.84,48.35 199.84,61.81 196.82,64.83 188.23,64.82 188.17,64.75 185.25,64.75 183.85,66.16 182.45,67.55 175.59,67.55 174.76,68.38 172.32,68.38 171.11,67.17 142.53,67.17 141.51,68.18 126.95,68.18 126.57,67.8 122.84,67.8 122.48,68.16 122.48,68.54 121.96,69.07 118.32,69.07 118.06,68.82 109.93,68.82 101.91,60.79 101.91,46.08 ; 2 cut-outs
+3VS on IN3: 157.45,57.51 157.55,57.51 157.93,57.89 162.25,57.89 163.65,56.5 166.69,56.5 167.33,57.13 168.09,57.13 168.6,56.62 168.6,55.35 168.47,55.23 166.57,55.23 166.31,55.48 165.04,55.48 164.79,55.23 161.8,55.23 161.33,54.75 159.87,54.75 159.07,53.96 155.77,53.96 153.61,56.12 153.61,56.52 153.76,56.68 155.77,56.68 156.28,57.18 157.12,57.18
+3VS_CAM on BOTTOM (solid shape): 194.25,51.72 194.25,48.8 194,48.55 193.49,48.55 193.41,48.62 193.41,49.06 193.39,49.08 193.39,50.55 193.11,50.83 193.11,51.72 193.24,51.85 194.13,51.85
+3VS_CAM on BOTTOM (solid shape): 213.49,62.39 213.49,60.75 212.96,60.22 211.32,60.22 211.27,60.27 211.27,61.45 211.4,61.58 212.53,61.58 212.64,61.69 212.64,62.33 212.78,62.47 213.41,62.47
+3VS_CR on TOP (solid shape): 266.91,18.47 266.91,16.65 266.88,16.62 266.88,15.73 266.76,15.6 265.87,15.6 265.64,15.83 265.64,16.24 265.74,16.35 266,16.35 266.42,16.77 266.43,16.77 266.68,17.03 266.68,18.45 266.76,18.52 266.86,18.52
+3VS_CR on BOTTOM (solid shape): 266.13,16.12 266.13,15.57 266.39,15.31 266.39,11.11 266.34,11.06 265.58,11.06 265.55,11.08 265.55,11.57 265.58,11.59 266.08,11.59 266.11,11.62 266.11,12.3 266.08,12.33 265.58,12.33 265.55,12.35 265.55,12.76 265.58,12.78 266.08,12.78 266.11,12.81 266.11,13.5 266.08,13.52 265.58,13.52 265.55,13.55 265.55,14.16 265.47,14.23 265.17,14.23 264.99,14.41 264.99,16.1 265.22,16.32 265.92,16.32
+3VS_CR on TOP: 265.74,14.97 265.99,14.97 266.08,14.88 266.08,14.55 266.17,14.46 266.93,14.46 266.93,13.83 266.54,13.83 265.27,12.56 264.34,12.56 264.34,13.19 264.47,13.32 264.85,13.32 264.98,13.44 264.98,14.59 265.11,14.71 265.49,14.71
+3VS_NGFF on TOP (solid shape): 224.47,62.17 224.47,60.56 224.42,60.51 223.2,60.51 222.56,61.15 222.56,61.75 223.3,62.49 224.15,62.49
+3VS_NGFF on BOTTOM (solid shape): 232.06,42.99 232.06,40.96 231.87,40.77 231.25,40.77 231.17,40.86 231.17,43 231.28,43.12 231.94,43.12
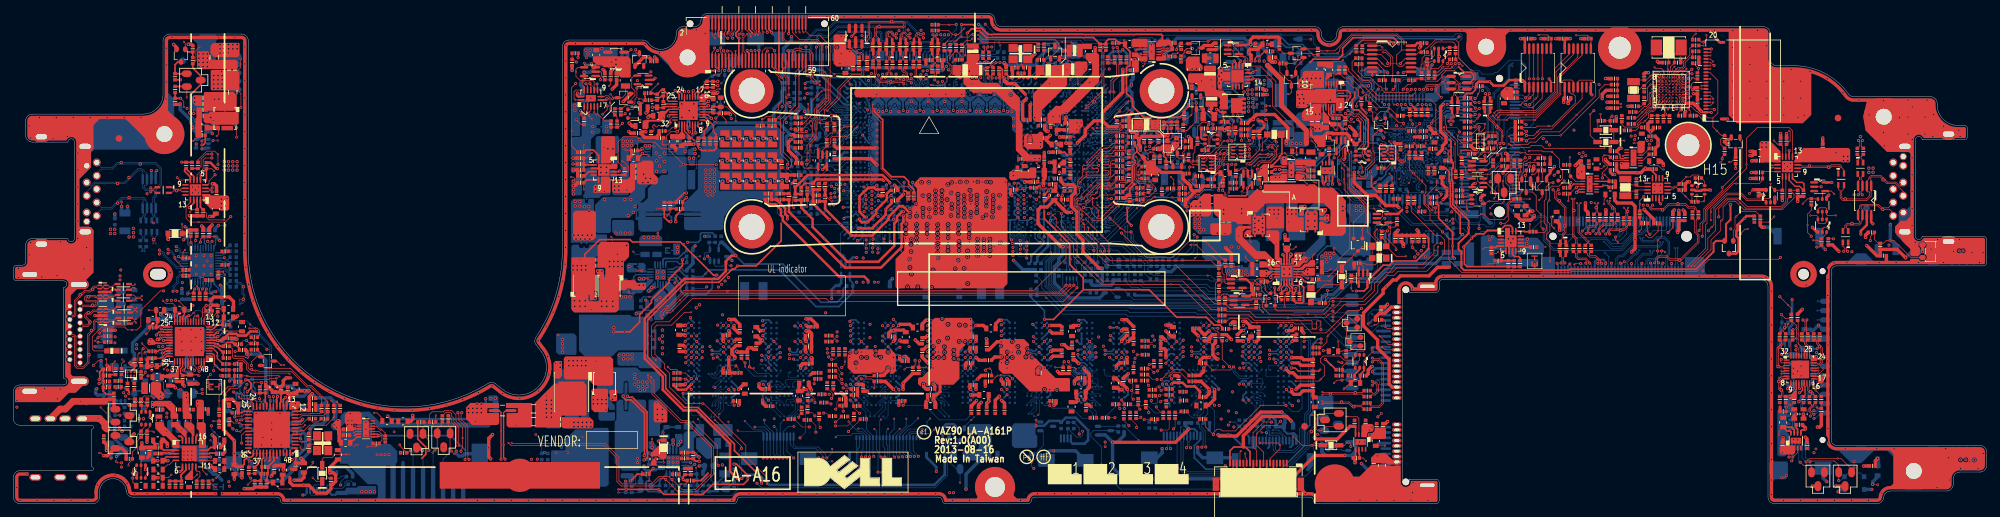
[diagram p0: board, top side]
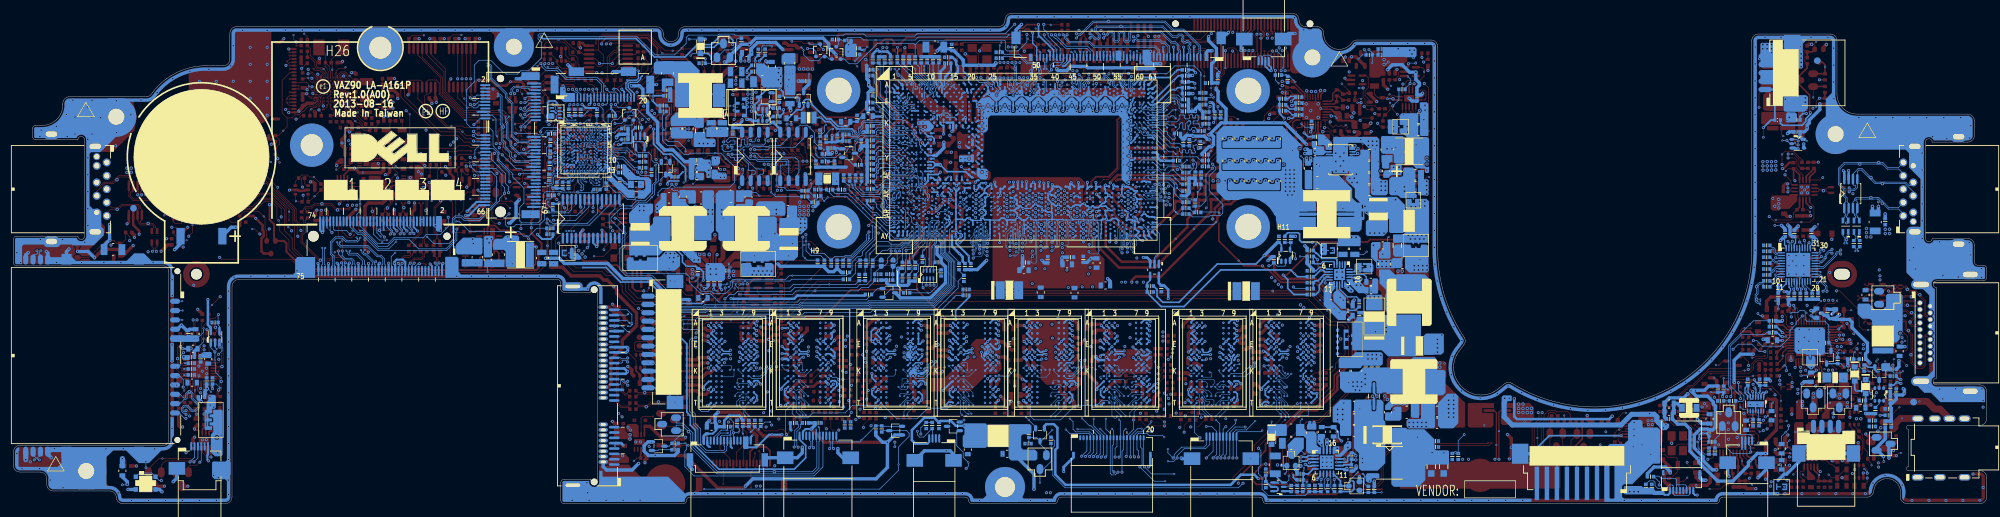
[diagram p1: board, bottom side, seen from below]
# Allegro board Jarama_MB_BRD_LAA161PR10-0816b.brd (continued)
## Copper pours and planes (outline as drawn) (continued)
+3VS_NGFF on TOP: 237.61,51.31 237.61,52.75 237.55,52.81 234.12,52.81 233.99,52.69 233.99,52.05 234.24,51.8 235.01,51.8 235.26,51.54 235.26,51.21 235.36,51.11 236.32,51.11 236.44,51.23 237.52,51.23
+3VS_NGFF on BOTTOM: 223.73,62.9 225.36,62.9 225.46,62.8 225.46,62.15 225.4,62.08 223.89,62.08 223.68,61.87 223.4,61.87 223.26,62.01 223.26,62.43
+3VS_NGFF on IN2: 223.78,62.72 224.99,62.72 231.46,56.24 231.46,53.96 231.08,53.58 228.92,53.58 222.62,59.88 222.62,61.56
+3VS_NGFF on IN3: 232.23,39.86 249.24,39.86 250.13,40.75 250.13,42.4 249.75,42.78 237.56,42.78 236.16,44.18 227.29,44.18 227.02,43.91 227.02,42.4 228.8,40.62 231.46,40.62
+3VS_NGFF on IN4: 227.53,42.78 227.65,42.78 228.29,43.42 235.4,43.42 236.04,44.05 236.04,45.45 234.77,46.72 234.77,49.77 235.91,50.91 235.91,52.05 232.73,55.23 226.38,55.23 225.88,54.72 225.88,52.94 227.15,51.67 227.15,50.27 228.16,49.26 230.45,49.26 231.59,48.12 231.59,46.97 231.08,46.46 229.56,46.46 228.8,47.23 228.16,47.23 224.99,50.4 223.21,50.4 222.67,49.86 222.67,49.29 223.59,48.37 223.59,47.48 225.24,45.83 225.24,44.81 227.27,42.78 227.4,42.78 227.53,42.91
+5V_USB_P0 on TOP: 24.19,46.34 26.14,46.34 26.22,46.26 26.22,45.19 20.76,39.73 17.2,39.73 17.07,39.86 17.07,50.91 17.46,51.29 21.65,51.29 21.77,51.16 21.77,49.13 21.65,49 19.61,49 18.98,48.37 18.98,46.34 19.36,45.96 23.81,45.96
+5V_USB_P0 on TOP, IN1, IN2, IN4: 10.47,42.02 10.47,44.56 10.85,44.94 15.04,44.94 15.68,44.31 15.68,39.99 15.42,39.73 13.77,39.73 11.74,41.77 10.72,41.77
+5V_USB_P0 on BOTTOM: 18.1,42.15 18.36,41.89 18.36,39.86 18.1,39.61 13.02,39.61 10.36,42.27 10.36,43.92 10.74,44.31 11.25,44.31 11.63,43.92 11.63,43.16 12.39,42.4 14.67,42.4 14.93,42.15
+5V_USB_P1 on TOP (solid shape): 274.88,53.07 274.88,51.29 274.76,51.16 273.62,51.16 273.55,51.24 271.87,51.24 271.78,51.15 266.56,51.15 266.5,51.21 266.5,51.42 266.63,51.54 266.63,52.05 267.9,53.32 274.63,53.32
+5V_USB_P1 on BOTTOM: 273.63,52.43 274.9,52.43 275.15,52.18 282.72,52.18 283.38,51.52 283.38,48.5 282.75,47.86 280.38,47.86 280.24,47.72 280.24,37.55 279.93,37.24 278.5,37.24 278.48,37.27 278.48,40.67 277.87,41.28 277.87,42.65 278.22,43 278.22,45.54 276.72,47.03 274.33,47.03 273.5,47.86 273.5,52.31
+5V_USB_P1 on IN2: 278.3,52.46 282.24,52.46 283.38,51.32 283.38,48.14 283.1,47.86 277.82,47.86 277.29,48.4 277.29,51.44
+5V_USB_P1 on IN3: 278.3,52.28 281.69,52.28 282.68,51.29 283.23,51.29 283.38,51.14 283.38,47.96 283.28,47.86 277.64,47.86 277.29,48.22 277.29,51.27
+5V_USB_P1 on IN4: 277.96,52.31 282.56,52.31 283.37,51.49 283.37,48.32 282.91,47.86 277.98,47.86 277.27,48.57 277.27,51.62
+5VALW on TOP (solid shape): 29.6,46.21 32.06,46.21 32.31,45.96 32.31,44.18 32.06,43.92 31.04,43.92 30.79,44.18 29.52,44.18 28.33,45.37 28.33,46.11 28.23,46.21 28.23,46.31 28.33,46.41 29.39,46.41
+5VALW on TOP (solid shape): 264.47,52.81 264.47,51.19 264.43,51.15 263.29,51.15 263.29,51.16 263.09,51.19 262.9,51.14 261.45,51.14 261.3,51.29 261.3,54.08 261.55,54.34 262.95,54.34
+5VALW on TOP (solid shape): 52.13,13.5 52.13,11.97 52.05,11.9 51.36,11.9 51.29,11.97 50.93,11.97 50.86,11.9 50.86,11.59 50.98,11.46 51.19,11.46 51.34,11.31 52.08,11.31 52.13,11.26 52.13,11.18 52.05,11.11 51.09,11.11 50.88,10.9 49.97,10.9 49.84,11.03 49.84,11.79 49.59,12.05 49.59,13.32 50.07,13.8 51.82,13.8
+5VALW on BOTTOM (solid shape): 97.33,33.27 97.33,32.01 97.75,31.6 97.75,30.41 96.56,29.21 95.96,29.21 95.88,29.3 95.88,30.89 97.13,32.14 97.13,33.24 97.21,33.33 97.28,33.33
+5VALW on BOTTOM (solid shape): 182.82,35.47 184.85,35.47 184.88,35.49 184.88,36.05 184.91,36.08 186.2,36.08 186.38,35.9 186.38,34.2 186.23,34.04 181.78,34.04 181.5,34.32 181.5,35.8 181.78,36.08 182.82,36.08
+5VALW on TOP: 267.47,8.7 267.37,8.59 267.37,7.91 268.12,7.16 269.87,7.16 270.06,7.35 270.06,8.53 269.89,8.7
+5VALW on BOTTOM: 35.25,17.25 35.5,17 35.5,16.75 35.63,16.62 36.39,16.62 36.52,16.75 36.52,18.02 36.39,18.14 34.87,18.14 34.49,17.76 34.49,17.38 34.61,17.25
+5VALW on BOTTOM: 269.63,7.41 269.73,7.52 269.73,9.15 269.62,9.26 268.6,9.26 268.52,9.18 268.52,7.57 268.68,7.41
+5VALW on BOTTOM: 188.54,49.89 189.55,49.89 189.68,50.02 189.68,50.53 189.3,50.91 188.28,50.91 187.65,50.27 187.65,48.5 188.28,47.86 195.78,47.86 196.03,48.12 196.79,48.12 197.3,47.61 197.55,47.61 197.81,47.86 197.81,48.37 197.68,48.5 194.51,48.5 194.38,48.37 188.54,48.37 188.28,48.62 188.28,49.64
+5VALW on VCC: 208.32,36.56 207.32,37.67 207.28,39.27 207.28,40.99 209.46,43.16 258.99,43.16 261.3,45.47 261.3,54.23 261.66,54.59 263.48,54.59 263.71,54.36 263.71,41.62 260.56,38.46 213.82,38.46 211.91,36.56
+5VALW on IN2: outline of 471 points within 24.58,2.55 213.74,45.96
+5VALW on IN3: 97.61,31.22 97.61,30.97 96.46,29.83 96.08,29.83 95.7,30.21 95.7,30.59 96.72,31.61 97.22,31.61
+5VALWP on BOTTOM (solid shape): 183.97,42.91 183.97,39.73 184.13,39.57 186.07,39.57 186.54,39.1 186.54,36.53 186.31,36.3 182.31,36.3 182.19,36.43 178.5,36.43 177.87,37.07 177.87,39.99 178,40.11 180.54,40.11 181.04,40.62 181.04,42.78 181.3,43.04 183.84,43.04
+5VS on BOTTOM (solid shape): 54.3,2.52 54.3,1.51 54.17,1.38 49.85,1.38 49.73,1.51 49.73,2.27 49.85,2.4 51.38,2.4 51.63,2.65 54.17,2.65
+5VS on BOTTOM (solid shape): 146.37,11.79 146.37,6.84 145.99,6.46 142.31,6.46 142.06,6.71 142.06,7.73 142.44,8.11 144.21,8.11 144.47,8.36 144.47,10.14 144.21,10.4 143.2,10.4 142.94,10.65 142.94,11.67 143.2,11.92 146.25,11.92
+5VS on BOTTOM (solid shape): 100.98,54.36 100.98,53.44 100.78,53.24 100.78,52.52 100.5,52.24 99.26,52.24 98.86,52.64 98.04,52.64 98,52.68 98,52.79 98.05,52.85 98.92,52.85 99.16,53.09 99.16,53.47 99.27,53.58 100.13,53.58 100.29,53.73 100.29,54.32 100.33,54.36 100.98,54.36
+5VS on TOP: 56.05,11.81 56.22,11.98 56.22,12.76 56.15,12.83 55.79,12.83 55.73,12.89 55.73,13.25 55.85,13.37 57.88,13.37 58.1,13.15 58.1,8.62 57.58,8.1 57.58,6.35 55.22,3.99 55.22,1.23 55.04,1.05 51.9,1.05 51.74,1.21 51.74,6.31 53.92,8.5 55.68,8.5 56.05,8.87
+5VS on BOTTOM: 18.39,34.3 18.39,32.72 18.87,32.24 18.87,31.55 18.7,31.38 16.81,31.38 16.52,31.1 15.74,31.1 15.3,31.54 15.3,34.24 15.59,34.53 18.16,34.53
+5VS on IN2: 41.09,1.02 39.98,2.14 35.76,2.14 32.45,5.44 32.45,9.25 30.3,11.41 30.3,22.21 26.99,25.51 26.99,29.32 26.1,30.21 16.44,30.21 15.63,31.02 15.63,34.36 15.78,34.52 16.57,34.52 22.17,40.11 23.31,40.11 23.44,39.99 23.44,38.84 22.93,38.34 22.93,37.57 20.14,34.78 20.14,33.89 20.9,33.13 27.63,33.13 29.66,31.1 29.66,26.91 30.8,25.76 31.44,24.62 33.09,21.19 33.34,20.68 33.34,16.11 37.03,12.43 37.03,8.36 40.96,4.43 49.73,4.43 51.25,2.9 55.57,2.9 55.82,2.65 55.82,1.63 55.21,1.02
+5VS_AUDIO on TOP: 21.14,18.43 20.6,18.43 20.16,17.99 20.16,16.45 20.09,16.38 19.06,16.38 18.95,16.49 18.95,18.45 20.4,19.9 20.4,20.04 20.6,20.25 20.78,20.25 21.22,19.81 21.22,18.5
+5VS_AUDIO on BOTTOM: 34.05,9.38 32.33,9.38 30.3,11.41 30.3,14.08 28.77,15.6 28.37,15.6 28.02,15.95 28.02,17.31 28.15,17.43 28.72,17.43 31.44,14.71 31.44,12.3 33.09,10.65 33.6,10.65 34.11,11.16 35.16,11.16 35.46,11.46 36.42,11.46 36.57,11.31 36.57,10.78 36.35,10.56 35.24,10.56
+5VS_AUDIO on IN4: 20.59,20.3 25.6,20.3 28.9,17 28.9,16.24 28.64,15.98 27.12,15.98 26.36,16.75 21.99,16.75 19.91,18.83 19.91,19.63
+5VS_KBL on BOTTOM (solid shape): 153.12,11.92 153.12,11.39 152.98,11.24 152.98,10.4 153.23,10.14 153.23,8.62 152.98,8.36 149.8,8.36 149.42,8.75 149.42,11.67 149.8,12.05 153,12.05
+5VS_LDO-IN on TOP (solid shape): 25.05,21.8 25.05,20.58 24.8,20.33 24.8,19.72 24.75,19.67 24.75,18.93 24.62,18.8 24.24,18.8 24.11,18.93 24.11,19.46 24.59,19.95 24.59,20.4 24.85,20.66 24.85,21.8 24.9,21.85 25,21.85
+V1.05A_AOSCSUS on IN3: 157.3,50.4 158.06,50.4 159.33,51.67 161.23,51.67 161.61,52.05 161.99,52.05 162.88,52.94 165.17,52.94 165.42,53.2 165.42,54.08 165.17,54.34 160.34,54.34 158.82,52.81 158.18,52.81 157.17,51.8 157.17,50.53
+V1.05S_APLLOPI on TOP (solid shape): outline of 216 points within 142.17,51.39 153.81,67.39
+V1.05S_APLLOPI on BOTTOM (solid shape): 152.05,52.19 153.67,52.19 153.79,52.06 153.79,51.3 153.67,51.18 153.11,51.18 153.09,51.19 153.05,51.23 153,51.25 152.95,51.27 152.89,51.27 152.84,51.27 152.78,51.26 152.73,51.25 152.68,51.22 152.65,51.2 152.61,51.2 152.6,51.21 151.91,51.21 151.83,51.12 151.7,51.12 151.56,51.26 151.56,51.76 151.99,51.76 151.99,51.71 152,51.66 152.01,51.61 152.04,51.57 152.06,51.53 152.1,51.5 152.14,51.47 152.19,51.45 152.23,51.44 152.28,51.44 152.33,51.44 152.38,51.45 152.42,51.47 152.46,51.5 152.5,51.53 152.53,51.57 152.55,51.61 152.56,51.66 152.57,51.71 152.57,51.76 152.56,51.8 152.55,51.85 152.53,51.89 152.5,51.93 152.46,51.96 152.42,51.99 152.38,52.01 152.33,52.02 152.28,52.02 152.23,52.02 152.19,52.01 152.14,51.99 152.1,51.96 152.06,51.93 152.04,51.89 152.01,51.85 152,51.8 151.99,51.76 151.56,51.76 151.56,52.25 151.65,52.34 151.9,52.34
+V1.05S_ASATA3PLL on BOTTOM (solid shape): 180.32,67.12 180.32,65.96 180.2,65.84 178.41,65.84 178.25,65.99 178.25,67.42 178.38,67.55 179.9,67.55
+V1.05S_ASATA3PLL on IN1 (solid shape): 180.32,65.63 180.32,65.34 179.98,65 178.83,65 178.78,65.05 178.78,65.71 178.85,65.77 180.18,65.77
+V1.05S_ASATA3PLL on IN4 (solid shape): 180.3,66.1 180.3,65.46 180.17,65.33 178.91,65.33 178.79,65.45 178.79,66.03 178.9,66.14 180.26,66.14
+V1.05S_ASATA3PLL on TOP: 178.2,64.81 179.99,64.81 180.05,64.87 180.05,65.66 180.42,66.03 180.42,67.45 180.36,67.51 179.63,67.51 179.52,67.4 179.52,66.41 179.03,65.92 178.31,65.92 178.14,65.75 178.14,64.88
+V1.05S_AXCK_DCB on TOP (solid shape): 158.3,65.83 158.3,64.46 157.67,63.83 157.67,62.73 154.23,59.29 154.23,59.29 153.93,58.98 153.93,57.41 153.75,57.23 152.99,57.23 152.58,57.64 152.58,57.69 152.57,57.7 152.57,58.04 152.58,58.05 152.58,61.45 155.25,64.12 155.25,65.64 155.38,65.77 156.9,65.77 157.16,66.02 158.11,66.02
+V1.05S_AXCK_DCB on VCC: 152.78,57.01 152.6,57.19 152.6,57.97 152.97,58.34 153.61,57.7 153.61,57.26 153.18,57.26 152.93,57.01
+V1.05S_AXCK_DCB_L on TOP (solid shape): 160.71,66.15 160.71,65.01 159.82,64.12 158.93,64.12 158.81,64.24 158.81,66.15 158.93,66.28 160.58,66.28
+V1.05S_AXCK_LCPLL_L on TOP (solid shape): 161.42,68.87 161.42,68.18 161.41,68.17 160.13,68.17 160,68.04 160,67.04 159.94,66.97 159.26,66.97 159.19,67.04 159.19,68.82 159.31,68.94 161.35,68.94
+V1.05VS_VCCHSIO on TOP (solid shape): 160.08,57.39 160.08,56.62 159.57,56.12 159.57,55.74 159.31,55.48 158.04,55.48 157.92,55.61 157.92,57.51 158.04,57.64 159.82,57.64
+V1.05VS_VCCHSIO on TOP (solid shape): 177.53,66.1 177.98,65.64 177.98,65.13 177.86,65.01 177.85,65.01 177.73,64.89 175.73,64.89 175.46,65.17 175.46,66.65 175.84,67.04 177.53,67.04
+V1.05VS_VCCHSIO on BOTTOM (solid shape): 158.75,57.45 158.95,57.34 159.16,57.45 159.32,57.45 159.33,57.44 159.48,57.44 159.61,57.31 159.96,57.31 160.06,57.21 160.06,56.85 159.99,56.78 158.69,56.78 158.56,56.65 158.56,56.37 158.57,56.37 158.74,56.19 158.97,56.19 159.1,56.32 159.28,56.32 159.43,56.17 159.43,55.91 159.28,55.76 159,55.76 158.95,55.81 158.51,55.81 158.51,55.81 158.09,55.81 157.55,56.35 157.55,56.69 158.31,57.45
+V1.05VS_VCCHSIO on VCC: 150.04,54.85 150.04,56.05 150.31,56.42 150.31,58 150.06,58.25 150.04,66.3 150.4,66.66 171.01,66.66 172.02,65.64 179.78,65.64 175.7,61.56 175.7,60.67 173.56,58.53 169.83,58.53 168.06,60.31 165.01,60.31 163.36,61.96 163.18,61.96 162.03,63.1 157.36,63.1 156.44,62.18 152.93,58.66 152.91,58.66 152.84,58.58 152.84,58.57 152.34,58.07 152.34,57.08 152.67,56.75 153.03,56.75 153.28,57.01 157.08,57.01 157.72,57.64 159.4,57.64 160.34,56.7 160.34,55.99 158.64,55.99 158.13,55.48 157.62,55.48 156.99,54.85 ; 3 cut-outs
+VCC_CORE on BOTTOM (solid shape): outline of 290 points within 100.37,41 115.26,56.62
+VCC_CORE on BOTTOM (solid shape): outline of 2062 points within 127.86,47.77 151.23,60.97
+VCC_CORE on VCC: 102.42,46.08 102.42,60.58 106.97,65.13 118.44,65.13 120.47,63.1 138.13,63.1 138.38,62.85 139.1,62.85 139.35,63.1 149.18,63.1 149.54,62.74 149.55,58.04 149.8,57.79 149.8,56.58 149.54,56.22 149.54,50.68 149.54,49 132.93,49 132.55,48.62 125.13,48.62 124.11,49.64 121.36,49.64 117.81,46.08
+VCC_CORE on IN2: 104.46,55.1 113.99,55.1 115.77,53.32 115.77,50.91 117.8,48.88 121.99,48.88 122.37,48.5 125.29,48.5 125.8,47.99 126.43,47.99 128.34,49.89 128.34,57.01 129.1,57.77 129.1,58.91 129.36,59.16 131.13,59.16 131.64,58.66 132.15,58.66 132.66,59.16 149.68,59.16 150.95,57.89 150.95,48.88 149.68,47.61 134.82,47.61 129.86,42.65 120.08,42.65 118.69,41.26 115.26,41.26 112.08,44.43 104.08,44.43 103.19,45.32 103.19,53.83
AGND on TOP (solid shape): 2.29,4.19 1,4.19 0.83,4.12 0.76,3.95 0.76,1 0.83,0.83 1,0.76 11.9,0.76 12.07,0.83 12.14,1 12.14,1.75 14.79,4.51 17.65,1.96 17.73,1.8 17.89,1.74 19.66,1.74 30.51,1.74 30.51,1.23 17.89,1.23 17.38,1.43 17.15,1.92 14.81,4 12.65,1.75 12.65,1 12.43,0.47 11.9,0.25 1,0.25 0.47,0.47 0.25,1 0.25,3.95 0.47,4.48 1,4.7 2.29,4.7
AGND on BOTTOM (solid shape): 26.18,22.13 26.18,21.62 26.21,21.6 26.61,21.6 26.64,21.62 26.64,22.13 26.66,22.16 26.92,22.16 27.02,22.06 27.02,20.73 26.43,20.15 26.1,20.15 25.6,20.66 25.6,21.9 25.85,22.16 26.16,22.16
AGND on IN1 (solid shape): 2.29,4.19 1,4.19 0.83,4.12 0.76,3.95 0.76,1 0.83,0.83 1,0.76 11.9,0.76 12.07,0.83 12.14,1 12.14,1.75 14.79,4.51 17.65,1.96 17.73,1.8 17.89,1.74 19.62,1.74 30.51,1.74 30.51,1.23 17.89,1.23 17.38,1.43 17.15,1.92 14.81,4 12.65,1.75 12.65,1 12.43,0.47 11.9,0.25 1,0.25 0.47,0.47 0.25,1 0.25,3.95 0.47,4.48 1,4.7 2.29,4.7
AGND on IN2 (solid shape): 2.29,4.19 1,4.19 0.83,4.12 0.76,3.95 0.76,1 0.83,0.83 1,0.76 11.9,0.76 12.07,0.83 12.14,1 12.14,1.75 14.79,4.51 17.65,1.96 17.73,1.8 17.89,1.74 19.36,1.74 30.51,1.74 30.51,1.23 17.89,1.23 17.38,1.43 17.15,1.92 14.81,4 12.65,1.75 12.65,1 12.43,0.47 11.9,0.25 1,0.25 0.47,0.47 0.25,1 0.25,3.95 0.47,4.48 1,4.7 2.29,4.7
AGND on IN3 (solid shape): 2.29,4.19 1,4.19 0.83,4.12 0.76,3.95 0.76,1 0.83,0.83 1,0.76 11.9,0.76 12.07,0.83 12.14,1 12.14,1.75 14.79,4.51 17.65,1.96 17.73,1.8 17.89,1.74 19.45,1.74 30.51,1.74 30.51,1.23 17.89,1.23 17.38,1.43 17.15,1.92 14.81,4 12.65,1.75 12.65,1 12.43,0.47 11.9,0.25 1,0.25 0.47,0.47 0.25,1 0.25,3.95 0.47,4.48 1,4.7 2.29,4.7
AGND on IN4 (solid shape): 2.29,4.19 1,4.19 0.83,4.12 0.76,3.95 0.76,1 0.83,0.83 1,0.76 11.9,0.76 12.07,0.83 12.14,1 12.14,1.75 14.79,4.51 17.65,1.96 17.73,1.8 17.89,1.74 19.37,1.74 30.51,1.74 30.51,1.23 17.89,1.23 17.38,1.43 17.15,1.92 14.81,4 12.65,1.75 12.65,1 12.43,0.47 11.9,0.25 1,0.25 0.47,0.47 0.25,1 0.25,3.95 0.47,4.48 1,4.7 2.29,4.7
AGND on TOP: 28.76,18.52 29.9,18.52 30.23,18.19 30.23,17.76 30.21,17.74 29.72,17.74 29.67,17.69 29.67,17.31 29.7,17.28 30.21,17.28 30.26,17.23 30.26,16.85 30.03,16.62 28.76,16.62 28.5,16.87 28.5,18.27
AGND on TOP: 18.14,24.11 18.85,24.11 18.98,23.99 18.98,22.75 18.47,22.24 18.47,21.37 18.41,21.32 17.81,21.32 17.75,21.38 17.75,23.72
AGND on BOTTOM: 30.93,2.83 30.85,2.75 30.37,2.75 30.32,2.7 30.32,2.32 30.35,2.29 30.88,2.29 30.91,2.27 30.91,2.04 30.88,2.01 29.03,2.01 28.77,2.27 28.77,3.79 29.28,4.3 30.42,4.3 30.93,3.79
AGND on BOTTOM: 1,0.25 0.47,0.47 0.25,1 0.25,3.95 0.47,4.48 1,4.7 2.29,4.7 2.29,4.19 1,4.19 0.83,4.12 0.76,3.95 0.76,1 0.83,0.83 1,0.76 11.9,0.76 12.07,0.83 12.14,1 12.14,1.75 14.79,4.51 17.65,1.96 17.73,1.8 17.89,1.74 19.43,1.74 30.51,1.74 30.51,1.23 17.89,1.23 17.38,1.43 17.15,1.92 14.81,4 12.65,1.75 12.65,1 12.43,0.47 11.9,0.25
AGND on GND1: 1,0.25 0.47,0.47 0.25,1 0.25,2.09 0.26,2.09 0.26,3.95 0.47,4.48 1,4.69 8.96,4.69 8.96,4.7 11.7,4.7 12,4.79 12.21,5.03 12.22,5.44 11.95,5.74 11.95,10.96 12.24,11.58 11.7,12 11.22,12 11.22,12.01 1,12.01 0.47,12.22 0.26,12.75 0.26,14.71 7.16,14.71 8.56,16.11 9.57,16.11 10.4,16.95 12.76,19.31 12.76,20.58 13.12,20.94 17.18,20.94 17.71,21.47 17.71,23.75 19.74,25.79 19.74,27.94 21.01,29.21 21.01,29.47 21.24,29.7 25.86,29.7 26.47,29.09 26.47,26.91 24.15,26.91 23.74,26.5 23.74,21.98 24.02,21.7 28.67,21.7 28.99,22.02 29.73,22.02 29.77,21.98 29.77,11.18 31.93,9.02 31.93,4.15 31.83,4.05 31.09,4.05 30.54,3.67 30.54,1.23 21.37,1.23 17.89,1.23 17.38,1.43 17.15,1.92 14.81,4 12.65,1.75 12.65,1 12.43,0.47 11.9,0.25
AGND on VCC: 1,0.25 0.47,0.47 0.25,1 0.25,3.95 0.47,4.48 1,4.7 11.7,4.7 12.03,4.81 12.23,5.1 12.21,5.47 11.95,5.74 11.95,10.96 12.24,11.58 11.7,12 11.18,12 11.18,12.01 1,12.01 0.47,12.22 0.26,12.75 0.26,14.71 7.16,14.71 8.56,16.11 9.57,16.11 10.4,16.95 12.76,19.31 12.76,20.58 13.12,20.94 17.18,20.94 17.71,21.47 17.71,23.75 19.74,25.79 19.74,27.94 21.01,29.21 21.01,29.47 21.24,29.7 25.86,29.7 26.47,29.09 26.47,26.91 24.15,26.91 23.74,26.5 23.74,21.98 24.02,21.7 28.67,21.7 28.99,22.02 29.73,22.02 29.77,21.98 29.77,11.18 31.93,9.02 31.93,4.15 31.83,4.05 31.09,4.05 30.54,3.67 30.54,3.05 30.54,3.05 30.54,1.23 17.89,1.23 17.38,1.43 17.15,1.92 14.81,4 12.65,1.75 12.65,1 12.43,0.47 11.9,0.25
AGND on GND2: 1,0.25 0.47,0.47 0.25,1 0.25,3.95 0.47,4.48 1,4.7 11.7,4.7 12.24,5.12 11.95,5.74 11.95,10.96 12.24,11.58 11.7,12 11.4,12 11.4,12.01 1,12.01 0.47,12.22 0.26,12.75 0.26,14.71 7.16,14.71 8.56,16.11 9.57,16.11 10.4,16.95 12.76,19.31 12.76,20.58 13.12,20.94 17.18,20.94 17.71,21.47 17.71,23.75 19.74,25.79 19.74,27.94 21.01,29.21 21.01,29.47 21.24,29.7 25.86,29.7 26.47,29.09 26.47,26.91 24.15,26.91 23.74,26.5 23.74,21.98 24.02,21.7 28.67,21.7 28.99,22.02 29.73,22.02 29.77,21.98 29.77,11.18 31.93,9.02 31.93,4.15 31.83,4.05 31.09,4.05 30.54,3.67 30.54,1.23 22.85,1.23 17.89,1.23 17.38,1.43 17.15,1.92 14.81,4 12.65,1.75 12.65,1 12.43,0.47 11.9,0.25
AGND on GND3: 1,0.25 0.47,0.47 0.25,1 0.25,3.95 0.47,4.48 1,4.7 11.7,4.7 12.24,5.12 11.95,5.74 11.95,10.96 12.24,11.58 11.7,12 11.18,12 11.18,12.01 1,12.01 0.47,12.22 0.26,12.75 0.26,14.71 7.16,14.71 8.56,16.11 9.57,16.11 10.4,16.95 12.76,19.31 12.76,20.58 13.12,20.94 17.18,20.94 17.71,21.47 17.71,23.75 19.74,25.79 19.74,27.94 21.01,29.21 21.01,29.47 21.24,29.7 25.86,29.7 26.47,29.09 26.47,26.91 24.15,26.91 23.74,26.5 23.74,21.98 24.02,21.7 28.67,21.7 28.99,22.02 29.73,22.02 29.77,21.98 29.77,11.18 31.93,9.02 31.93,4.15 31.83,4.05 31.09,4.05 30.54,3.67 30.54,1.23 22.22,1.23 17.89,1.23 17.38,1.43 17.15,1.92 14.81,4 12.65,1.75 12.65,1 12.43,0.47 11.9,0.25
DV12S on TOP: 266.95,14.71 266.95,15.65 268.03,16.73 268.03,17.26 268.04,17.27 268.21,17.27 268.23,17.25 268.23,15.65 268.13,15.55 267.51,15.55 267.49,15.54 267.49,14.88 267.49,14.88 267.49,14.75 267.55,14.69 268.32,14.69 268.45,14.57 268.45,13.87 268.37,13.79 267.37,13.79 267.23,13.93 267.23,14.43
DV33_18 on TOP (solid shape): 270.91,19.11 270.91,18.21 270.72,18.02 270.17,18.02 270.05,18.14 270.05,18.89 269.93,19.01 269.07,19.01 268.99,19.1 268.99,19.15 269.05,19.22 270.8,19.22
DVDD-12-SWR on TOP (solid shape): 42.96,15.15 42.96,14.59 42.47,14.11 41.56,14.11 41.48,14.03 41.36,14.03 41.31,14.08 41.31,15.1 41.56,15.35 42.75,15.35
DVDD-12-SWR on BOTTOM: 42.21,15.35 44.06,15.35 44.28,15.14 44.28,13.63 44.22,13.57 42.54,13.57 41.69,14.42 41.69,14.83
GND on TOP (solid shape): 28.2,61.07 28.2,59.65 28.17,59.62 27.31,59.62 26.85,60.08 26.85,61.02 27.03,61.2 28.07,61.2
GND on TOP (solid shape): 86.8,12.43 86.8,11.41 86.67,11.29 82.28,11.29 82.07,11.49 82.07,12.91 82.1,12.94 86.29,12.94
GND on TOP (solid shape): 88.98,17.08 88.98,13.9 88.8,13.72 86.92,13.72 86.49,14.16 86.49,17 86.75,17.25 88.8,17.25
GND on TOP (solid shape): 97.86,13.85 97.86,12.3 97.73,12.17 96.07,12.17 95.81,12.43 95.81,15.15 96.06,15.39 96.32,15.39
GND on TOP (solid shape): 142.49,62.22 142.49,61.09 142.3,60.9 126.24,60.9 125.86,61.27 125.86,61.88 126.29,62.31 142.4,62.31
GND on TOP (solid shape): 182.3,41.89 182.3,40.62 181.92,40.24 179.38,40.24 179.13,40.5 179.13,41.89 179.25,42.02 182.17,42.02
GND on TOP (solid shape): 197.61,51.29 197.61,49.64 197.35,49.39 195.83,49.39 195.7,49.51 195.7,50.27 195.83,50.4 197.1,50.4 197.22,50.53 197.22,51.29 197.35,51.42 197.48,51.42
GND on TOP (solid shape): 29.27,67.67 29.27,67.04 29.77,66.53 33.31,66.53 33.58,66.26 33.58,65.25 33.46,65.13 27.74,65.13 27.5,65.38 27.5,67.69 27.62,67.8 29.14,67.8
GND on TOP (solid shape): 93.02,50.91 93.02,47.1 92.51,46.59 89.85,46.59 89.59,46.85 89.59,48.5 89.72,48.62 91.88,48.62 92.26,49 92.26,50.91 92.39,51.04 92.89,51.04
GND on TOP (solid shape): 262.38,71.07 262.43,71.02 262.48,70.97 262.48,66.14 263.28,65.34 266.23,65.34 266.57,65 268.86,65 269.07,64.79 269.07,58.29 267.81,57.03 257.9,57.03 256.69,58.24 256.69,71.07
GND on TOP (solid shape): 195.89,56.75 196.78,56.75 196.91,56.62 196.91,56.12 196.78,55.99 196.02,55.99 195.76,55.74 194.7,55.74 194.6,55.83 194.6,56.47 194.49,56.57 194.07,56.57 194.02,56.63 194.02,57.06 194.09,57.13 195.51,57.13
GND on TOP (solid shape): 92.13,38.97 92.13,37.07 91.37,36.3 91.37,34.27 90.8,33.7 88.7,33.7 88.58,33.83 88.58,35.29 88.45,35.42 87.43,35.42 87.43,38.72 87.94,39.23 91.88,39.23
GND on TOP (solid shape): 223.96,41.31 223.96,40.29 224.06,40.19 224.92,40.19 224.95,40.17 224.95,38.54 224.92,38.51 224.06,38.51 223.96,38.41 223.96,37.47 223.88,37.4 223.81,37.4 223.73,37.47 223.73,38.34 223.55,38.51 223.25,38.51 223.25,40.22 223.22,40.24 223.22,41.28 223.3,41.36 223.91,41.36
GND on TOP (solid shape): 90.34,50.85 90.34,50.21 90.29,50.16 89.25,50.16 89.13,50.05 89.13,49.23 89.07,49.17 87.52,49.17 87.5,49.2 87.5,49.98 87.32,50.16 86.48,50.16 86.48,50.39 87.37,50.39 87.5,50.52 87.5,50.82 87.52,50.85 89.33,50.85 89.38,50.9 90.29,50.9
GND on TOP (solid shape): 197.92,61.96 197.92,60.94 198.05,60.82 199.07,60.82 199.19,60.69 199.19,59.16 198.94,58.91 198.05,58.91 197.92,59.04 197.92,60.05 197.87,60.1 194.29,60.1 193.48,59.29 192.11,59.29 191.95,59.44 191.95,61.83 192.14,62.02 194.79,62.02 194.85,62.09 197.8,62.09
GND on TOP (solid shape): 187.76,50.73 187.76,48.5 187.64,48.37 187.13,48.37 187.11,48.39 187.11,48.9 186.92,49.08 186.32,49.08 186.18,49.22 186.18,49.78 186.48,49.97 186.47,50.32 187.03,50.88 187.61,50.88
GND on TOP (solid shape): 174.43,53.58 172.9,52.05 172.65,52.05 172.52,52.18 172.52,52.56 172.48,52.6 172.24,52.98 171.82,52.81 171.25,52.81 171.13,52.94 171.13,53.45 171.25,53.58 171.63,53.58 171.89,53.83 173.16,53.83 173.54,54.21 174.43,54.21
GND on TOP (solid shape): outline of 174 points within 265.9,32.4 269.9,36.4
GND on TOP (solid shape): outline of 183 points within 19.4,32.4 23.9,36.4
GND on TOP (solid shape): outline of 114 points within 31.04,0.25 213.13,5.86
GND on TOP (solid shape): outline of 218 points within 0.25,15.22 104.2,73.24
GND on TOP (solid shape): outline of 1338 points within 118.92,0.25 295.05,73.24
GND on BOTTOM (solid shape): 271.79,21.23 271.29,21.23 271.29,24.07 271.79,24.07
GND on BOTTOM (solid shape): 92.83,31.15 92.83,29.12 92.8,29.09 90.47,29.09 90.47,31.17 90.62,31.33 92.65,31.33
GND on BOTTOM (solid shape): 30.17,61.07 30.17,58.91 30.04,58.78 27.25,58.78 26.74,59.29 26.74,60.94 26.99,61.2 30.04,61.2
GND on BOTTOM (solid shape): 84.27,25.13 84.27,22.46 84.14,22.33 81.6,22.33 81.22,22.72 81.22,25.38 81.35,25.51 83.89,25.51
GND on BOTTOM (solid shape): 97.1,39.86 97.1,38.72 96.97,38.59 93.8,38.59 93.67,38.72 93.67,39.86 94.05,40.24 96.72,40.24
GND on BOTTOM (solid shape): 228.22,36.55 228.22,35.63 228.14,35.54 225.19,35.54 225.06,35.67 225.06,36.58 225.14,36.66 228.11,36.66
GND on BOTTOM (solid shape): 30.36,61.01 30.36,58.87 30.27,58.78 27.25,58.78 26.74,59.29 26.74,60.94 26.99,61.2 30.17,61.2
GND on BOTTOM (solid shape): 92.91,42.27 92.91,40.37 92.65,40.11 90.24,40.11 89.6,40.75 89.6,42.4 89.73,42.53 92.65,42.53
GND on BOTTOM (solid shape): 170.88,68.69 170.88,67.24 170.6,66.96 169.19,66.96 169.11,67.04 169.11,68.82 169.24,68.95 170.16,68.95 170.24,69.03 170.55,69.03
GND on BOTTOM (solid shape): 191.71,35.91 191.71,33.64 191.46,33.38 189.05,33.38 188.79,33.64 188.79,35.54 189.31,36.06 191.56,36.06
GND on BOTTOM (solid shape): 197.32,62.36 197.32,60.22 197.28,60.18 196.76,60.18 196.69,60.25 196.69,62.35 196.76,62.42 197.26,62.42
GND on BOTTOM (solid shape): 224.88,39.91 224.88,37.07 224.76,36.94 223.82,36.94 223.67,37.09 223.67,39.48 223.46,39.68 223.46,39.99 223.61,40.14 224.66,40.14
GND on BOTTOM (solid shape): 203.17,43.54 203.17,42.1 203.07,41.99 200.37,41.99 200.12,42.25 200.12,43.14 199.56,43.7 199.56,44.86 199.69,44.99 201.72,44.99
GND on BOTTOM (solid shape): 89.22,50.66 89.22,50.15 89.35,50.02 89.99,50.02 90.24,49.77 90.24,48.88 89.48,48.88 89.1,49.26 87.7,49.26 87.57,49.39 87.57,50.78 89.1,50.78
GND on BOTTOM (solid shape): 85.08,49.97 85.08,46.34 84.96,46.21 83.64,46.21 83.51,46.34 83.51,48.5 83.64,48.62 84.14,48.62 84.24,48.72 84.24,49.98 84.26,50 85.06,50
GND on BOTTOM (solid shape): 89.28,15.87 89.28,15.47 89.99,14.77 89.99,14.11 89.33,14.11 88.66,14.77 86.71,14.77 86.53,14.94 86.53,16.14 86.73,16.34 88.82,16.34
GND on BOTTOM (solid shape): 191.57,56.24 191.57,54.99 191.56,54.97 188.41,54.97 188.28,55.1 188.28,56.24 188.54,56.5 191.32,56.5
GND on BOTTOM (solid shape): 84.65,15.1 84.65,12.81 84.78,12.68 86.56,12.68 86.81,12.43 86.81,11.67 86.43,11.29 82.75,11.29 82.56,11.48 82.56,15.03 82.87,15.35 84.4,15.35
GND on BOTTOM (solid shape): 97.86,14.46 97.86,12.3 97.73,12.17 97.1,12.17 96.77,11.84 96.77,10.27 96.64,10.14 95.19,10.14 95.07,10.27 95.07,15.48 95.19,15.6 96.72,15.6
GND on BOTTOM (solid shape): 196.94,56.17 196.94,54.97 196.69,54.72 193.74,54.72 193.62,54.85 193.62,55.74 193.69,55.81 194.47,55.81 194.57,55.91 194.57,56.31 194.7,56.44 196.67,56.44
GND on BOTTOM (solid shape): 95.19,21.95 96.72,21.95 96.97,21.7 96.97,20.43 96.84,20.3 93.8,20.3 93.41,20.68 90.62,20.68 90.37,20.94 90.37,22.46 90.62,22.72 94.43,22.72
GND on BOTTOM (solid shape): 179.52,44.43 179.52,43.04 179.77,42.78 180.54,42.78 180.66,42.65 180.66,40.62 180.41,40.37 177.39,40.37 176.47,41.28 176.47,42.78 176.6,42.91 177.87,42.91 178,43.04 178,44.56 178.12,44.69 179.27,44.69
GND on BOTTOM (solid shape): 179.93,65.55 179.93,62.16 179.85,62.07 179.85,61.32 179.75,61.23 178.4,61.23 178.25,61.38 178.25,65.53 178.42,65.7 179.79,65.7
GND on BOTTOM (solid shape): 185.74,45.56 185.74,45.07 185.87,44.94 187.01,44.94 187.27,44.69 187.27,40.62 187.14,40.5 185.49,40.5 184.98,41 184.98,44.43 184.6,44.81 184.6,45.45 184.73,45.58 185.72,45.58
GND on BOTTOM (solid shape): 192.98,51.72 192.98,50.58 193.24,50.33 193.24,49.94 193.11,49.82 191.84,49.82 191.59,49.56 191.59,48.93 191.46,48.8 191.08,48.8 190.95,48.93 190.95,51.47 191.08,51.6 191.97,51.6 192.22,51.85 192.86,51.85
GND on BOTTOM (solid shape): 196.77,46.62 196.77,44.69 196.61,44.53 195.42,44.53 195.09,44.2 195.09,41.36 194.99,41.26 193.64,41.26 193.49,41.41 193.49,43.98 194.68,45.17 194.68,45.65 194.71,45.68 195.57,45.68 195.9,46.01 195.9,46.59 195.98,46.67 196.72,46.67
GND on BOTTOM (solid shape): 92.14,38.97 92.14,36.94 91.38,36.18 91.38,35.42 91.26,35.29 87.7,35.29 87.45,35.54 87.45,36.69 87.57,36.81 88.84,36.81 89.1,36.56 91,36.56 91.13,36.69 91.13,37.96 90.75,38.34 90.75,39.1 90.87,39.23 91.89,39.23
GND on BOTTOM (solid shape): 28.77,26.14 28.77,22.84 28.39,22.46 27.12,22.46 26.97,22.31 26.54,22.31 26.51,22.28 26.51,21.78 26.49,21.75 26.33,21.75 26.31,21.78 26.31,22.28 26.28,22.31 24.48,22.31 24.2,22.59 24.2,26.09 24.51,26.4 28.52,26.4
GND on BOTTOM (solid shape): 84.83,60.05 84.83,59.26 84.54,58.91 84.83,58.56 84.83,55.25 84.68,55.1 83.66,55.1 83.53,55.23 83.53,59.93 83.79,60.18 84.7,60.18
GND on BOTTOM (solid shape): 96.13,36.28 96.13,35.36 96.35,35.14 96.67,35.14 96.72,35.19 96.72,36.25 96.79,36.33 96.87,36.33 96.93,36.27 96.93,35.24 97.04,35.14 97.63,35.14 97.63,35.13 97.63,33.54 97.63,33.53 96.66,33.53 96.53,33.41 96.53,32.39 96.48,32.34 96.39,32.34 96.33,32.4 96.33,33.43 96.22,33.53 96.03,33.53 96.03,33.54 96.03,35.24 95.93,35.34 95.93,36.28 95.98,36.33 96.08,36.33
GND on BOTTOM (solid shape): 108.27,48.37 108.27,48.18 108.53,47.93 108.85,47.93 109.54,48.62 109.8,48.62 110.05,48.37 110.05,48.12 110.24,47.93 110.75,47.93 111.45,48.62 111.58,48.62 111.7,48.5 111.7,48.24 112.02,47.93 112.45,47.93 113.15,48.62 113.4,48.62 113.53,48.5 113.53,47.13 113.38,46.97 105.86,46.97 105.73,47.1 105.73,48.37 105.92,48.56 106.37,48.56 106.5,48.43 106.5,48.05 106.62,47.93 107.19,47.93 107.89,48.62 108.02,48.62
GND on BOTTOM (solid shape): 108.15,54.85 108.15,54.53 108.4,54.28 108.85,54.28 109.54,54.97 109.8,54.97 109.99,54.78 109.99,54.53 110.24,54.28 110.62,54.28 111.32,54.97 111.64,54.97 111.77,54.85 111.77,54.4 111.89,54.28 112.4,54.28 113.1,54.97 113.48,54.97 113.61,54.85 113.61,54.47 113.8,54.28 114.31,54.28 114.37,54.21 114.37,53.39 114.31,53.32 105.73,53.32 105.61,53.45 105.61,54.72 105.8,54.91 106.24,54.91 106.37,54.78 106.37,54.4 106.5,54.28 107.07,54.28 107.77,54.97 108.02,54.97
GND on BOTTOM (solid shape): 108.15,51.54 108.15,51.23 108.4,50.97 108.85,50.97 109.54,51.67 109.8,51.67 109.99,51.48 109.99,51.23 110.24,50.97 110.62,50.97 111.32,51.67 111.64,51.67 111.77,51.54 111.77,51.1 111.89,50.97 112.4,50.97 113.1,51.67 113.48,51.67 113.61,51.54 113.61,51.16 113.8,50.97 114.31,50.97 114.37,50.91 114.37,50.08 114.31,50.02 105.73,50.02 105.61,50.15 105.61,51.42 105.8,51.61 106.24,51.61 106.37,51.48 106.37,51.1 106.5,50.97 107.07,50.97 107.77,51.67 108.02,51.67
GND on BOTTOM (solid shape): 97.79,54.88 97.79,52.51 97.84,52.46 98.82,52.46 98.88,52.41 98.88,52.28 98.82,52.23 97.88,52.23 97.8,52.15 97.8,49.58 97.73,49.51 95.64,49.51 95.59,49.56 95.59,53.45 95.62,53.47 95.62,53.92 95.45,54.08 93.29,54.08 92.14,52.94 92.14,46.46 91.89,46.21 89.86,46.21 89.6,46.46 89.6,48.37 89.73,48.5 90.49,48.5 90.87,48.88 90.87,49.57 91.04,49.87 90.87,50.17 90.87,54.59 91.26,54.97 97.7,54.97
GND on BOTTOM (solid shape): 278.34,36.41 285.95,36.41 286.73,37.19 287.85,37.19 288.09,36.96 290.54,36.96 290.54,35.9 272.85,35.9 272.1,35.59 271.79,34.84 271.79,30.96 271.29,30.96 271.29,34.22 271.57,34.78 271.38,35.38 271.95,36.12 272.85,36.41 274.63,36.41 275.76,37.53 277.22,37.53
GND on BOTTOM (solid shape): outline of 82 points within 31.04,0.25 57.45,12.56
GND on BOTTOM (solid shape): 230.65,36.97 230.65,33.91 230.59,33.84 217.53,33.84 217.53,33.84 213.88,33.84 213.35,33.62 213.13,33.09 213.13,32.17 213.05,31.99 212.88,31.92 209.13,31.92 209.13,32.06 208.38,32.82 207.63,32.06 207.63,30 207.59,29.92 207.52,29.9 207.5,29.9 207.12,29.9 207.12,32.06 208.2,33.31 209.59,32.43 210.2,32.43 210.64,32.87 212.62,32.87 212.62,33.09 212.99,33.98 213.88,34.35 215.43,34.35 228.29,34.35 228.67,34.73 228.67,36.76 228.92,37 230.61,37
GND on BOTTOM (solid shape): outline of 86 points within 68.12,0.25 213.13,4.93
GND on BOTTOM (solid shape): outline of 99 points within 250.14,0.25 295.04,36.98
GND on BOTTOM (solid shape): outline of 416 points within 128.42,60.26 149.67,62.17
GND on BOTTOM (solid shape): outline of 336 points within 0.25,15.22 295.05,73.24
GND on IN1 (solid shape): 242.26,49 242.26,45.83 242.13,45.7 240.48,45.7 240.23,45.96 240.23,49 240.35,49.13 242.13,49.13
GND on IN1 (solid shape): 11.44,18.79 11.44,18.63 9.46,16.65 8.35,16.65 6.93,15.22 0.26,15.22 0.26,16.02 0.25,16.02 0.25,16.8 0.47,17.33 1,17.55 7.5,17.55 8.24,18.17 7.75,19.01 7.75,19.23 7.77,19.25 10.98,19.25
GND on IN1 (solid shape): outline of 113 points within 31.04,0.25 213.13,5.72
GND on IN1 (solid shape): outline of 415 points within 0.25,0.25 295.05,73.24
GND on IN2 (solid shape): 242.26,49.13 242.26,45.7 242.13,45.58 240.35,45.58 240.23,45.7 240.23,49.13 240.35,49.26 242.13,49.26
GND on IN2 (solid shape): outline of 111 points within 31.04,0.25 213.13,5.72
GND on IN2 (solid shape): outline of 2422 points within 0.25,0.25 295.05,73.24
GND on IN3 (solid shape): 242.26,49.13 242.26,45.7 242.13,45.58 240.35,45.58 240.23,45.7 240.23,49.13 240.35,49.26 242.13,49.26
GND on IN3 (solid shape): outline of 113 points within 31.04,0.25 213.13,5.72
GND on IN3 (solid shape): outline of 2545 points within 0.25,0.25 295.05,73.24
GND on IN4 (solid shape): 242.26,49.13 242.26,45.7 242.13,45.58 240.35,45.58 240.23,45.7 240.23,49.13 240.35,49.26 242.13,49.26
GND on IN4 (solid shape): outline of 115 points within 31.04,0.25 213.13,5.72
GND on IN4 (solid shape): outline of 2486 points within 0.25,0.25 295.05,73.24
GND on TOP: 17.2,22.72 16.68,22.2 15.01,22.2 14.91,22.3 14.91,23.18 14.15,23.94 14.15,25.13 14.41,25.38 16.95,25.38 17.2,25.13
GND on TOP: 27.23,38.08 27.87,38.72 31.17,38.72 31.55,38.34 31.55,35.54 31.3,35.29 30.41,35.29 30.16,35.03 30.16,34.53 29.77,34.15 27.36,34.15 26.73,34.78 26.6,34.78 26.47,34.65 25.96,34.65 25.84,34.78 25.84,37.7 26.22,38.08
GND on TOP: 94.04,66.16 94.7,66.16 95.83,65.03 95.83,64.16 95.61,63.94 94.58,63.94 94.34,64.18 94.34,64.84 93.91,65.27 93.91,66.04
GND on TOP: 30.41,17 30.41,17.33 30.33,17.41 29.83,17.41 29.8,17.43 29.8,17.59 29.83,17.61 30.33,17.61 30.36,17.64 30.36,18.09 30.41,18.14 30.41,19.16 30.79,19.54 31.55,19.54 31.81,19.29 31.81,17.76 30.92,16.87 30.54,16.87
GND on TOP: 99.27,4.94 101.66,4.94 101.78,5.06 101.78,5.44 101.53,5.7 101.02,5.7 100.39,6.33 100.39,7.86 100.13,8.11 98.18,8.11 97.87,7.81 97.87,6.71 97.82,6.66 97.82,4.71 98.41,4.12 98.99,4.12 99.09,4.22 99.09,4.76
GND on BOTTOM: 267.53,21.57 267.79,21.32 267.79,18.94 268.17,18.56 268.17,17.76 268.04,17.64 267.28,17.64 267.02,17.89 267.02,18.27 266.77,18.52 265.25,18.52 265.18,18.59 265.18,19.15 265.63,19.59 265.63,21.41 265.79,21.57
GND on BOTTOM: 204.86,12.68 205.94,12.68 206.18,12.44 206.18,11.36 206.04,11.22 204.69,11.22 204.46,11.45 204.46,12.29
GND on BOTTOM: 213.3,38.97 211.02,38.97 210.89,39.1 210.89,41 211.02,41.13 213.3,41.13 213.43,41 213.43,39.1
GND on BOTTOM: 31.18,3.79 32.45,3.79 32.71,3.54 32.71,2.15 32.7,2.15 32.53,1.98 31.09,1.98 31.03,2.04 31.03,2.4 31.01,2.42 30.5,2.42 30.45,2.47 30.45,2.6 30.47,2.62 30.98,2.62 31.03,2.68 31.03,3.64
GND on BOTTOM: 187.23,65.56 187.41,65.38 187.41,62.6 187.09,62.28 185.98,62.28 185.87,62.39 185.87,65.43 186,65.56
GND on BOTTOM: 106.57,34.27 110.05,34.27 110.31,34.02 110.31,30.72 110.05,30.46 105.71,30.46 105.16,31.01 105.16,32.87
GND on BOTTOM: 99.64,57.01 102.05,57.01 102.56,57.51 102.56,61.32 102.43,61.45 101.54,61.45 101.42,61.32 99.89,61.32 99.26,60.69 99.26,57.39
GND on BOTTOM: 26.36,31.1 29.91,31.1 30.04,30.97 30.04,29.7 29.79,29.45 27.76,29.45 26.99,30.21 22.93,30.21 22.8,30.34 22.8,30.84 22.93,30.97 26.23,30.97
GND on GND1: outline of 277 points within 0.25,0.25 295.05,73.24 ; 2 cut-outs
GND on VCC: outline of 124 points within 0.25,0.25 80.96,70.14
GND on VCC: 90.46,46.08 87.31,49.24 87.31,64.9 89.97,67.57 89.97,69.25 94.2,69.25 94.55,69.16 94.81,68.93 94.86,68.87 94.9,68.81 97.69,67.97 99.45,70.29 99.45,70.4 99.45,70.5 99.67,71.03 100.2,71.24 100.92,71.24 101.28,70.7 101.9,70.48 102.1,70.49 102.29,70.52 102.29,66.26 101.42,65.39 99.65,65.39 98.1,63.84 98.1,46.08
GND on VCC: 203.09,0.25 201.99,1.36 201.99,4.2 205.9,8.11 207.63,8.11 207.63,3.27 208.38,2.51 209.13,3.27 209.13,3.41 210.49,3.41 210.49,3.41 212.38,3.41 212.91,3.19 213.13,2.66 213.13,0.5 213.05,0.33 212.88,0.25
GND on VCC: 272.74,35.89 272.62,35.87 272.49,35.84 272.47,35.86 271.92,35.86 270.2,37.57 261.66,37.57 261.3,37.93 261.3,38.49 264.22,41.41 264.22,54.57 263.69,55.1 261.15,55.1 260.13,56.12 254.42,56.12 248.85,61.68 248.85,63.59 248.07,64.37 241.14,64.37 240.61,63.84 240.61,57.37 240.38,57.13 219.62,57.13 217.35,59.4 217.35,70.83 217.61,71.08 217.61,71.24 255.23,71.24 255.23,71.25 261.9,71.25 262.43,71.03 262.65,70.5 262.65,66.65 263.01,65.76 263.9,65.4 266.45,65.4 270.93,64.3 274.41,61.28 274.86,60.89 275.43,60.75 286.9,60.75 287.43,60.53 287.65,60 287.65,59.8 288.63,57.43 291,56.45 291.95,56.45 292.12,56.37 292.2,56.2 292.2,55.05 292.12,54.88 291.95,54.8 285.86,54.8 285.02,55.29 284.4,54.55 284.4,40.1 285.02,39.36 285.86,39.85 294.8,39.85 294.97,39.77 295.05,39.6 295.05,36.14 294.97,35.97 294.8,35.89 279.2,35.89 279.2,35.9 272.85,35.9 272.74,35.9
GND on VCC: 263.58,0.25 263.05,0.47 262.83,1 262.83,1.6 262.83,5.35 263.97,6.49 269.35,6.49 271.36,8.49 272.61,8.49 272.64,8.5 272.68,8.5 272.76,8.49 272.85,8.49 294.3,8.49 294.83,8.27 295.05,7.74 295.05,5.74 294.83,5.21 294.3,4.99 291.3,4.99 290.41,4.63 290.05,3.74 290.05,2.9 289.83,2.37 289.3,2.15 280.9,2.15 280.31,2.01 279.86,1.6 279.71,1.3 279.65,0.96 279.42,0.46 278.9,0.25
GND on VCC: 149.54,66.3 149.54,63.61 139.14,63.61 138.89,63.36 138.59,63.36 138.34,63.61 138.24,63.61 137.87,63.91 137.51,63.61 120.69,63.61 118.65,65.64 108.11,65.64 107.88,65.87 107.88,66.04 110.14,68.31 118.27,68.31 118.53,68.56 121.74,68.56 121.98,68.33 121.98,67.95 122.63,67.29 126.78,67.29 127.16,67.67 141.3,67.67 142.32,66.66 149.18,66.66
GND on VCC: 165.77,7.98 165.54,8.22 165.54,10.12 165.01,10.65 159.8,10.65 159.55,10.9 154.98,10.9 153.2,12.68 142.7,12.68 141.68,11.67 137.87,11.67 136.6,10.4 125.55,10.4 125.17,10.02 124.5,10.02 124.24,10.27 116.54,10.27 115.9,9.63 114.72,9.63 113.45,10.9 104.68,10.9 100.01,15.58 100.01,27.56 104.18,31.73 104.57,31.73 106.55,33.71 107.11,34.28 107.11,34.49 107.12,45.58 118.02,45.58 121.57,49.13 123.9,49.13 124.92,48.12 132.76,48.12 133.14,48.5 149.55,48.5 149.56,48.38 150.84,47.1 151.35,47.1 152.24,46.21 152.61,46.21 153.24,45.58 156.16,45.58 161.12,40.62 164.63,40.62 169.45,45.45 174.7,45.45 175.06,45.09 175.06,40.52 176.86,38.72 177.98,38.72 181.06,35.64 181.06,34.52 183.97,31.61 187.66,31.61 192.46,26.8 192.46,15.33 187.02,9.89 176.48,9.89 174.58,7.98
GND on GND2: outline of 285 points within 0.25,0.25 295.05,73.24
GND on GND3: outline of 287 points within 0.25,0.25 295.05,73.24
VCC on BOTTOM (solid shape): 103.37,11.84 103.37,10.19 103.32,10.14 102.23,10.14 101.85,9.76 101.85,7.93 101.42,7.5 99.89,7.5 99.79,7.4 99.71,7.4 99.61,7.5 99.61,8.36 99.69,8.44 99.89,8.44 100.27,8.82 100.27,10.5 100.63,10.85 101.72,10.85 102.1,11.24 102.1,11.87 102.18,11.95 103.27,11.95
VDD_+1.2V on BOTTOM (solid shape): 97.8,33.26 98.25,33.26 99.21,32.3 99.21,29.71 97.03,27.52 95.99,27.52 95.87,27.65 95.87,28.88 95.96,28.97 96.58,28.97 98.07,30.45 98.07,31.66 97.53,32.2 97.53,33.3 97.59,33.36 97.71,33.36
VIN on TOP (solid shape): 33.44,61.25 33.44,59.11 33.24,58.91 29.14,58.91 29.01,58.78 28.61,58.78 28.5,58.89 28.5,61.58 28.63,61.7 32.99,61.7
VIN on BOTTOM: 104.87,9.89 108.4,9.89 108.53,9.76 108.53,5.16 108.11,4.75 107.58,4.75 107.46,4.86 107.46,5.3 107.45,5.32 106.11,5.32 104.84,6.59 104.84,9.86
3&5V_B+ on TOP (solid shape): 191.5,37.45 191.5,37.17 191.06,36.73 191.06,35.82 191,35.76 190.91,35.76 190.86,35.82 190.86,37.44 191.04,37.63 191.32,37.63
3&5V_B+ on TOP (solid shape): 193.31,47.85 193.58,47.66 193.85,47.85 193.86,47.89 194.75,47.89 195.26,47.38 197.47,47.38 199.42,45.42 199.42,44.44 199.36,44.23 199.42,44.02 199.42,40.65 198.91,40.14 195.66,40.14 195.38,40.42 195.38,42.07 195.64,42.32 195.99,42.32 196.32,41.99 196.96,41.99 197.11,42.15 197.11,44 196.07,45.04 187.48,45.04 186.11,43.67 185.48,43.67 185.22,43.42 185.22,42.02 185.1,41.89 183.19,41.89 182.81,42.27 180.9,42.27 179.61,43.57 179.61,46.41 180.97,46.41 181.04,46.39 181.07,46.32 181.2,46.09 181.46,46.07 181.49,46.08 181.74,45.83 184.71,45.83 186.09,47.2 186.24,47.2 186.49,46.96 186.85,46.96 187.11,47.21 187.11,47.76 187.18,47.84 187.18,47.84 187.23,47.89 193.3,47.89
3&5V_B+ on BOTTOM (solid shape): 184.14,44.94 184.14,43.44 183.89,43.19 179.88,43.19 179.77,43.29 179.77,44.94 180.16,45.32 183.76,45.32
3&5V_B+ on BOTTOM (solid shape): 198.38,46.46 198.38,45.64 199.21,44.81 199.21,43.67 199.08,43.54 198.57,43.54 197.55,44.56 197.55,46.51 197.6,46.55 198.29,46.55
+5PVDD on TOP (solid shape): 22.13,17.97 22.13,17.31 22.13,17.31 22.13,16.96 22.62,16.47 22.62,15.86 22.33,15.58 21.7,15.58 20.93,16.35 20.68,16.35 20.54,16.48 20.54,18.04 20.7,18.19 21.91,18.19
+5PVDD on IN3: 29.66,11.16 31.92,8.9 31.92,4.15 31.82,4.05 30.8,4.05 30.42,3.67 30.42,2.01 30.3,1.89 21.53,1.89 21.41,2.01 21.41,12.17 20.77,12.81 20.77,15.98 22.04,17.25 23.56,17.25 23.95,16.87 29.41,16.87 29.66,16.62
+EC_VCCA on BOTTOM (solid shape): 206.52,49.08 206.52,48.65 206.32,48.45 206.19,48.45 204.74,47 204.54,47 203.35,45.8 202.43,45.8 202.33,45.91 202.33,47.02 202.38,47.07 203.24,47.07 204.31,48.14 204.74,48.14 205.78,49.18 206.42,49.18
+EC_VCCA on IN4 (solid shape): 208.07,50.91 208.07,50 207.61,49.54 207.61,49.34 206.6,48.32 206.22,48.32 206.11,48.42 206.11,48.93 206.32,49.13 206.47,49.13 206.72,49.39 206.72,49.61 206.87,49.76 207,49.85 207.08,49.97 207.13,50.02 207.13,50.45 207.66,50.99 207.99,50.99
+HDMI_5V on BOTTOM (solid shape): outline of 84 points within 12.57,24.19 19.32,31.48
+HDMI_5V_OUT on BOTTOM: 17.04,26.4 17.34,26.69 17.34,27.16 17.47,27.29 19.16,27.29 19.22,27.23 19.22,25.95 17.21,23.95 17.21,21.7 16.96,21.45 12.9,21.45 12.26,20.81 12.26,19.67 12.03,19.44 8.82,19.44 8.17,20.08 8.17,21.67 8.53,22.03 9.42,22.03 9.59,21.85 9.59,20.81 9.92,20.48 10.53,20.48 10.86,20.81 10.86,22.72 11.12,22.97 13.53,22.97 14.17,23.6 15.25,23.6 15.63,23.98 15.63,26.14 15.89,26.4
+INV_PWR_SRC on TOP (solid shape): 92.39,66.67 92.39,65.39 92.38,65.39 92.38,63.95 92.33,63.89 90.87,63.89 90.59,64.18 90.01,64.18 89.97,64.23 89.97,64.79 90.08,64.9 90.08,65.25 90.08,65.25 90.08,65.33 89.91,65.49 89.59,65.49 89.53,65.43 88.39,65.43 88.03,65.79 87.27,65.79 86.71,66.35 86.71,66.97 86.81,67.07 91.99,67.07
+INV_PWR_SRC on BOTTOM (solid shape): 130.37,67.85 130.37,66.53 130.24,66.4 129.61,66.4 129.48,66.53 129.48,67.83 129.58,67.93 130.3,67.93
+INV_PWR_SRC on IN4: 130.63,66.66 130.5,66.53 129.61,66.53 129.23,66.91 126.31,66.91 124.78,65.39 105.99,65.39 103.07,62.47 92.02,62.47 89.91,64.58 89.91,66.72 90.04,66.86 94.65,66.86 94.73,66.78 97.73,66.78 100.02,64.5 101.67,64.5 104.84,67.67 121.99,67.67 124.66,70.34 130.24,70.34 130.63,69.96
+LCDVDD on TOP (solid shape): 124.71,70.21 124.71,69.52 124.64,69.45 124.64,68.15 124.75,68.04 125.23,68.04 126.04,67.23 126.04,65.77 125.79,65.51 123.18,65.51 122.74,65.96 122.74,68.46 122.88,68.46 122.88,68.41 122.89,68.36 122.9,68.31 122.93,68.26 122.96,68.21 122.99,68.17 123.03,68.14 123.08,68.12 123.13,68.1 123.18,68.08 123.23,68.08 123.29,68.08 123.34,68.1 123.39,68.12 123.43,68.14 123.48,68.17 123.51,68.21 123.54,68.26 123.57,68.31 123.58,68.36 123.59,68.41 123.59,68.46 123.58,68.52 123.57,68.57 123.54,68.61 123.51,68.66 123.48,68.7 123.43,68.73 123.39,68.76 123.34,68.78 123.29,68.79 123.23,68.79 123.18,68.79 123.13,68.78 123.08,68.76 123.03,68.73 122.99,68.7 122.96,68.66 122.93,68.61 122.9,68.57 122.89,68.52 122.88,68.46 122.74,68.46 122.74,70.16 122.99,70.34 124.58,70.34
+LCDVDD on BOTTOM (solid shape): 126.31,68 126.31,66 125.98,65.67 123.45,65.67 123.35,65.77 123.35,66.05 123.51,66.21 124.85,66.21 125.04,66.4 125.04,67.55 124.91,67.67 124.91,67.92 125.05,68.05 126.26,68.05
+LCDVDD on IN3 (solid shape): 126.05,67.55 126.05,66.53 125.67,66.15 124.28,66.15 123.77,66.66 123.77,67.04 124.53,67.8 125.8,67.8
+LCDVDD on TOP: 93.05,63.67 94.05,63.67 94.16,63.56 94.16,62.8 94.05,62.68 92.89,62.68 92.79,62.78 92.79,63.42
+LCDVDD on TOP: 192.59,52.18 194.75,52.18 194.87,52.31 194.87,53.23 194.57,53.53 194.57,53.79 194.15,54.21 193.48,54.21 192.72,53.45 192.52,53.45 192.47,53.4 192.47,52.3
+LCDVDD on TOP: 187.07,66.61 187.31,66.61 188.24,65.69 188.24,65.41 187.99,65.16 187.65,65.16 186.9,65.91 186.9,66.45
+LCDVDD on VCC: 186.51,68.05 183.9,68.05 182.51,69.45 168.69,69.45 168.44,69.2 145.64,69.2 144.24,70.59 139.99,70.59 139.35,71.23 126.08,71.23 124.74,69.9 123.68,69.9 123.51,70.07 123.51,72.48 145.88,72.48 146.32,71.25 147.42,70.54 147.48,70.48 188.58,70.48 188.59,70.47 188.59,66.23 188.45,66.09 187.08,66.09 186.94,66.23 186.94,67.63
+ODR_PWR on BOTTOM (solid shape): 268.84,25.26 268.98,25.22 269.12,25.2 269.68,25.2 269.73,25.26 271.62,25.26 271.79,25.08 271.79,24.44 271.59,24.24 267.71,24.24 267.53,24.42 267.53,25.12 267.67,25.26
+ODR_PWR on IN2: 269.18,17 266.77,17 266.64,17.13 266.64,24.34 267.1,24.8 269.54,24.8 269.82,24.52 269.82,17.64
+ODR_PWR on IN4: 267.68,24.98 268.29,24.98 268.52,24.75 268.52,24.24 268.34,24.06 267.56,24.06 267.4,24.21 267.4,24.7
+SD_VDD2 on IN3: 268.04,17.64 268.29,17.38 268.29,12.89 268.58,12.61 268.58,12.04 268.39,11.84 267.02,11.84 266.09,12.77 266.09,15.97 266.77,16.65 266.77,17.38 267.02,17.64
+VCHGR on BOTTOM (solid shape): 91.3,15.58 91.3,14.07 91.55,13.83 91.89,13.83 92.07,14.01 92.07,15.58 92.1,15.6 94.43,15.6 94.68,15.35 94.68,8.29 93.95,7.55 93.95,5.32 93.57,4.94 91.13,4.94 89.99,6.08 89.99,12.3 90.24,12.56 90.24,15.22 90.62,15.6 91.28,15.6
+VREFCA on IN2: 101.29,18.14 112.21,18.14 113.2,19.13 113.56,19.13 113.56,18.63 113.48,18.63 113.3,18.45 113.3,18.19 113.48,18.02 113.48,15.35 112.85,14.71 109.54,14.71 108.15,16.11 102.94,16.11 101.54,17.51 101.42,17.51 101.16,17.76 101.16,18.02
+VREFDQ_B on IN3: 179.65,22.84 184.73,22.84 186.89,20.68 186.89,19.41 186.38,18.91 182.31,18.91 181.55,19.67 180.16,19.67 179.39,20.43 179.39,22.59
ADPIN on TOP (solid shape): 33.84,64.63 33.84,62.09 33.71,61.96 29.65,61.96 29.52,62.09 29.52,64.88 29.65,65.01 33.46,65.01
ADPIN on BOTTOM (solid shape): 33.85,64.75 33.85,63.1 33.6,62.85 31.69,62.85 31.57,62.72 31.57,62.21 31.36,62 29.87,62 29.53,62.34 29.53,64.63 29.91,65.01 33.6,65.01
AMP_SPK_L on TOP: 19.38,3.23 21.22,3.23 21.37,3.07 21.37,2.23 21.24,2.09 19.36,2.09 19.3,2.16 19.3,3.15
B+ on TOP (solid shape): 87.18,43.67 87.18,39.94 86.72,39.48 83.88,39.48 83.75,39.61 83.75,43.54 84.13,43.92 86.92,43.92
B+ on TOP (solid shape): 179.26,46.32 179.26,43.42 178.87,43.04 176.6,43.04 176.59,43.04 176.14,43.04 176.06,43.13 176.06,44.98 176.6,45.52 177.18,45.52 178.13,46.47 179.11,46.47
B+ on BOTTOM (solid shape): 90.42,68.43 90.42,67 90.38,66.97 86.96,66.97 86.89,66.9 85.51,66.9 85.3,67.11 85.3,68.17 85.58,68.45 90.4,68.45
B+ on BOTTOM (solid shape): 193.49,55.48 193.49,53.58 193.36,53.45 190.35,53.45 190.22,53.59 190.22,54.5 190.44,54.72 191.59,54.72 191.71,54.85 191.71,55.61 191.84,55.74 193.24,55.74
B+ on BOTTOM (solid shape): 85.54,45.07 86.05,45.07 86.05,45.7 86.75,45.7 86.89,45.56 86.89,41.89 86.89,40.8 87.32,40.37 88.75,40.37 88.84,40.27 88.84,39.23 88.71,39.1 83.51,39.1 83.45,39.16 83.45,45.32 83.83,45.7 85.54,45.7
B+ on BOTTOM (solid shape): 93.92,19.79 96.78,19.79 96.78,17.32 96.08,16.62 92.08,16.62 92.07,16.63 92.07,18.15 91.83,18.4 91.54,18.4 91.31,18.16 91.31,16.61 91.19,16.49 90.49,16.49 90.29,16.7 89.86,16.7 89.66,16.49 87.45,16.49 87.32,16.62 87.32,20.3 87.45,20.43 93.29,20.43
B+ on TOP: 89.54,68.46 89.71,68.29 89.71,67.49 89.61,67.4 86.87,67.4 85.99,66.52 85.31,66.52 85.16,66.67 85.16,68.21 85.42,68.46
B+ on VCC: outline of 89 points within 78.16,1 199.45,68.54
BATDRV on BOTTOM (solid shape): 96.08,5.34 96.56,5.34 96.59,5.32 97.45,5.32 97.53,5.24 97.53,5.16 97.43,5.06 96.41,5.06 96.18,4.83 95.55,4.83 95.5,4.89 95.5,5.37 95.68,5.55 95.88,5.55
BATT+ on BOTTOM (solid shape): 89.1,11.16 89.1,2.9 88.72,2.52 85.01,2.52 84.01,3.52 84.01,5.58 83.74,5.85 82.57,5.85 82.56,5.85 80.54,5.85 80.46,5.93 80.46,7.84 80.63,8.01 82.43,8.01 82.62,8.19 82.62,9.63 84.14,11.16 86.75,11.16 86.95,11.36 88.89,11.36
BATT++ on TOP: 77.4,8.39 83.43,8.39 83.69,8.14 83.69,6.69 83.42,6.42 77.44,6.42 77.27,6.59 77.27,8.26
BATT++ on BOTTOM: 65.86,1.38 65.47,1.76 65.47,5.57 65.86,5.95 67.63,5.95 67.76,5.82 71.32,5.82 72.45,6.95 80.21,6.95 80.26,6.9 80.26,5.5 80.47,5.3 83.4,5.3 83.63,5.07 83.63,2.05 82.96,1.38
BST_3V on TOP (solid shape): 194.75,36.48 194.75,35.6 194.68,35.53 193.49,35.53 193.04,35.08 191.59,35.08 191.54,35.12 191.54,35.24 191.59,35.29 192.54,35.29 193.25,36 193.61,36 194.13,36.51 194.72,36.51
BST_5V on TOP (solid shape): 188.5,35.29 189.51,35.29 189.58,35.22 189.58,35.14 189.53,35.09 187.99,35.09 187.68,35.4 186.5,35.4 186.49,35.41 186.49,36.29 186.51,36.31 187.48,36.31
BYPASS on TOP (solid shape): 26.93,5.98 26.93,5.74 26.92,5.73 26.89,5.63 26.87,5.53 26.87,3.63 26.8,3.56 25.79,3.56 25.66,3.69 25.66,4.04 26.32,4.7 26.32,4.73 26.68,5.09 26.68,5.98 26.75,6.05 26.85,6.05
CHG_LGATE on TOP (solid shape): 90.35,16.92 90.35,15.48 90.23,15.35 89.49,15.35 89.24,15.6 89.24,16.98 89.34,17.08 90.2,17.08
CHG_LGATE on BOTTOM (solid shape): 96.22,8.73 96.22,8.12 97,7.35 97.43,7.35 97.53,7.25 97.53,7.15 97.45,7.07 96.49,7.07 95.42,8.14 95.27,8.14 95.07,8.34 95.07,9.25 95.19,9.38 95.57,9.38
CHG_LGATE on IN2 (solid shape): 90.62,16.62 90.62,14.84 90.37,14.59 89.73,14.59 89.48,14.84 89.48,16.62 89.73,16.87 90.37,16.87
CHG_LGATE on IN2 (solid shape): 95.7,9.81 95.7,8.24 95.57,8.11 94.99,8.11 93.87,9.23 93.87,10.02 94.02,10.17 95.34,10.17
CHG_LX on TOP (solid shape): 89.77,21.64 89.77,17.86 89.64,17.74 86.9,17.74 86.04,18.6 82.63,18.6 82.38,18.86 82.38,21.83 82.63,22.08 89.33,22.08
CHG_LX on BOTTOM (solid shape): 86.18,21.57 86.18,13.06 86.05,12.94 85.03,12.94 84.91,13.06 84.91,15.98 84.65,16.24 81.35,16.24 80.97,16.62 80.97,19.79 81.22,20.05 82.11,20.05 82.37,20.3 82.37,21.7 82.62,21.95 85.79,21.95
CHG_LX on BOTTOM (solid shape): 100.15,10.32 100.15,9.1 99.61,8.57 99.46,8.57 99.36,8.47 99.36,7.48 99.28,7.4 99.18,7.4 99.1,7.48 99.1,8.67 99.18,8.75 99.18,9.69 99.03,9.84 99.03,10.42 99.05,10.45 100.02,10.45
CHG_LX on IN2 (solid shape): 100.55,9.15 99.87,8.47 99.38,8.47 99.23,8.62 99.23,8.92 99.54,9.23 99.54,11.39 100.55,11.39
CHG_LX on IN2 (solid shape): 86.94,21.7 86.94,20.43 86.81,20.3 83,20.3 82.75,20.56 82.75,21.7 82.87,21.83 86.81,21.83
CHG_UGATE on TOP (solid shape): 82.11,21.29 82.11,19.14 81.72,18.75 81.08,18.75 80.83,19.01 80.83,21.09 81.13,21.4 82.01,21.4
CHG_UGATE on BOTTOM (solid shape): 99,9.61 99,8.8 98.88,8.67 98.88,7.48 98.8,7.4 98.67,7.4 98.6,7.48 98.6,8.67 98.44,8.82 98.44,9.66 98.57,9.79 98.82,9.79
CHG_UGATE on IN2 (solid shape): 82.11,21.45 82.11,19.79 81.86,19.54 81.1,19.54 80.97,19.67 80.97,21.45 81.22,21.7 81.86,21.7
CHG_UGATE on IN2 (solid shape): 99.08,10.8 99.08,8.87 98.85,8.64 98.42,8.64 98.09,8.97 98.09,10.09 97.43,10.75 97.43,11.36 97.63,11.57 98.32,11.57
CPU_B+ on TOP (solid shape): 95.81,51.16 95.81,49.51 96.45,48.88 96.45,48.12 96.2,47.86 93.59,47.86 93.34,48.12 93.34,50.91 93.59,51.16 93.91,51.16 94.16,51.42 95.56,51.42
CPU_B+ on BOTTOM (solid shape): 93.73,52.96 93.73,52.3 93.95,52.08 95.37,52.08 95.39,52.06 95.39,49.44 95.86,48.97 95.86,48.53 94.56,47.23 94.56,45.93 93.29,44.66 93.29,43.92 92.21,42.85 89.67,42.85 89.43,42.6 89.43,40.75 89.25,40.57 87.34,40.57 87.04,40.88 87.04,44.79 88.26,46.01 91.97,46.01 92.32,46.36 92.32,52.81 92.58,53.07 93.62,53.07
CPU_B+ on IN4 (solid shape): 95.68,51.14 95.68,48.34 94.56,47.23 94.56,45.93 93.29,44.66 93.29,43.92 92.21,42.85 89.49,42.85 89.03,43.31 89.03,44.65 88.2,45.48 88.2,45.79 88.42,46.01 91.97,46.01 92.32,46.36 92.32,51.21 92.63,51.52 95.29,51.52
